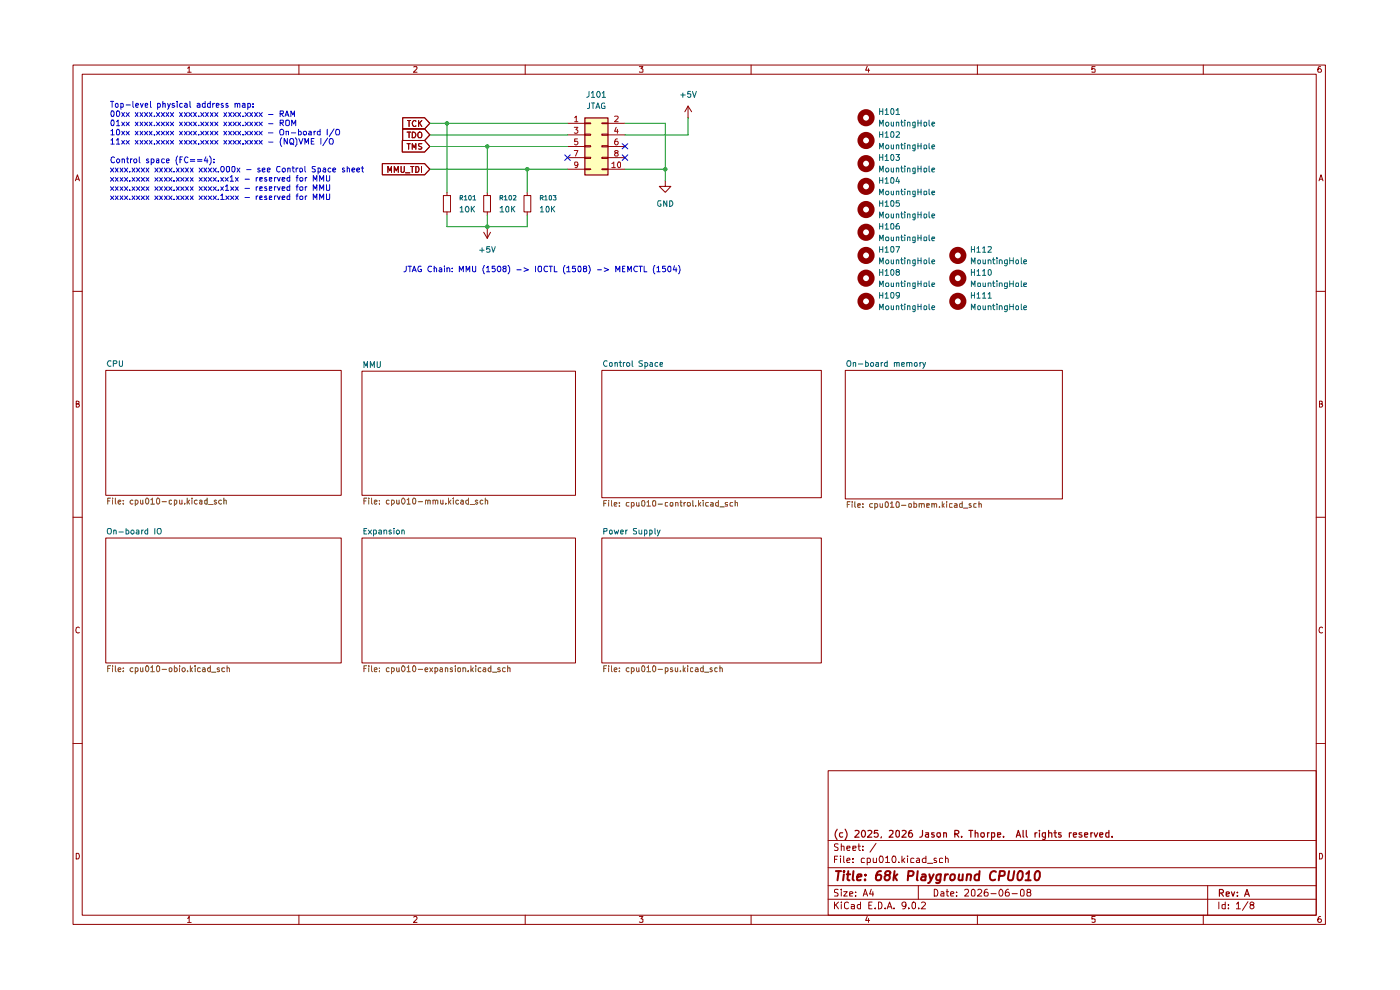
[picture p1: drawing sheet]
<svg xmlns="http://www.w3.org/2000/svg" width="297mm" height="210mm" viewBox="0 0 297 210" stroke-linecap="round" stroke-linejoin="round" font-family="sans-serif">
<g fill="none" stroke="#910000" stroke-width=".21">
<path d="M15.5 13.8h265.7v182.3h-265.7zM17.4 15.7h261.8v178.4h-261.8zM39.8 14.5l.3-.4v1.2M39.8 15.3h.8M63.4 13.8v1.9M87.8 14.2l.6-.1 .1 .4-.8 .8h.8M111.4 13.8v1.9M135.6 14.1h.8l-.4 .5 .4 .1v.5h-.8M159.3 13.8v1.9M184 14.1l-.4 .8h.9M184.2 14.6v.7M207.3 13.8v1.9"/>
<path d="M232.3 14.1h-.7v.6l.2-.1 .5 .1-.1 .6-.6-.1M255.3 13.8v1.9M280.2 14.1l-.5 .1a.94 .94 0 0 0 0 1.1h.5l.1-.1v-.4l-.2-.2h-.3l-.2 .2M16 38.4l.4-1.3 .4 1.3M16.2 38h.6M279.8 38.4l.4-1.3 .5 1.3M279.9 38h.6M15.5 61.8h1.9M279.2 61.8h2M16.2 85.7l.6-.1v-.4l-.6-.1v1.3h.4l.2-.5-.3-.2M279.9 85.7l.6-.1v-.4l-.6-.1v1.3l.6-.1 .1-.4-.3-.2M15.5 109.7h1.9"/>
<path d="M279.2 109.7h2M16.8 133.2l-.2-.2a.65 .65 0 0 0-.5 .6 .65 .65 0 0 0 .5 .7l.2-.1M280.6 133.2l-.3-.2a.65 .65 0 0 0-.5 .6 .65 .65 0 0 0 .5 .7l.3-.1M15.5 157.7h1.9M279.2 157.7h2M175.7 163.5h103.5v30.6h-103.5zM175.7 178.3h103.5M177.8 179.1l-.5-.1-.3 .2v.3l.8 .5-.3 .4-.5-.1M178.5 179.6l.5-.1 .1 .9M178.5 179v1.4M179.7 179.9l.6-.1v-.3h-.6v.2v.6h.6M180.9 179.9l.7-.1-.1-.3h-.6v.8h.6"/>
<path d="M182 179.5h.5M182.2 179v1.2l.3 .2M183 179.5v.2M185.8 178.9l-1.2 1.9M16.2 181a.66 .66 0 0 1 .6 .4 .66 .66 0 0 1-.2 .8h-.4zM39.8 194.8l.3-.4v1.3M39.8 195.7h.8M63.4 194.1v2M87.8 194.6l.4-.2 .3 .4-.8 .9h.8M111.4 194.1v2M135.6 194.4h.8l-.4 .5 .4 .1v.6h-.8M159.3 194.1v2"/>
<path d="M175.7 190.8h103.5M175.7 187.9h103.5M175.7 184.1h103.5M177 191.3v1.5M177 182.3h.5M177.3 191.9l.6 .9M177.7 181.6h-.7v1.4M177.8 188.7h-.7v.6a.53 .53 0 0 1 .6 .2 .53 .53 0 0 1 0 .6h-.7M177.9 191.3l-.9 .9M178.3 181.6v.1M178.3 182v1M178.5 191.3v.2"/>
<path d="M178.5 188.6v.2M178.5 189.1v1M178.5 191.9v.9M179 189.1h.7l-.7 1h.7M179 181.6v1.2l.2 .2M179.7 182.5l.6-.1-.1-.4-.5 .1v.7v.2h.6M180 191.5l-.4-.2-.4 .4v.9l.4 .2 .4-.2M180.3 189.7l.6-.2-.1-.3h-.5v.9h.5M180.6 191.9h.4l.3 .1v.8M180.9 182.9v.1M180.9 182.1v.2M181.3 192.2l-.7 .1v.4h.7"/>
<path d="M181.5 190v.1M181.5 189.2v.1M182.5 191.9h-.4l-.2 .2v.4l.2 .3 .4-.1M182.5 191.3v1.5M183 180.3v.1M183.1 190.1l.5-1.5 .5 1.5M183.2 189.7h.7M183.4 182.1l-.4-.1-.3 .3 .1 .7h.6M184 194.4l-.4 .8h.9M184 182.1l.4-.1 .3 .3-.1 .7h-.6M184 182v1.5M184.2 194.8v.9"/>
<path d="M184.3 192h.5M184.8 188.6l-.3 1.1h.8M185 191.3h-.7v1.5h.7M185.2 189.1v1M185.2 182l.1 1 .6-.1M185.7 192.6v.2M185.9 182v1M186.3 191.3l.7 .2v1.1l-.3 .2h-.4zM186.7 181.6a.73 .73 0 0 1 .7 .5 .73 .73 0 0 1-.3 .9h-.4l-.2-.5zM187.8 192.6v.2M187.9 181.9l.4-.3v1.4M187.9 183h.8"/>
<path d="M188.2 192.8l.5-1.5 .5 1.5M188.4 192.4h.7M189.4 181.7l.5-.1 .2 .5-.2 .9h-.4l-.2-.3-.1-.6zM189.7 192.6v.2M190.7 182.9v.1M191.3 181.6v1.4M191.5 182.5l.4 .5M191.9 182l-.6 .6M192.2 191.9l-.1 .3-.4 .1-.4-.4v-.3a.46 .46 0 0 1 .5-.3 .46 .46 0 0 1 .4 .3l-.2 1-.5 .2M192.5 181.6v.1M192.5 182v1M192.8 192.6v.2"/>
<path d="M193.5 191.5l.4-.2 .3 .3v.9l-.3 .3a.82 .82 0 0 1-.4-1.3zM193.9 182.1l-.4-.1-.3 .2v.7l.7 .1M194.5 182.1l.4-.1 .2 .3v.7h-.6l-.1-.4 .7-.2M194.8 187.9v2.9M194.9 192.6v.2M195.5 191.5l.2-.2h.3l.3 .5-.9 1h.9M196.4 181.6v1.4h-.6l-.1-.7a.52 .52 0 0 1 .7-.2M196.8 183.1h1.1M198.2 188.6a.8 .8 0 0 1 .8 .6 .8 .8 0 0 1-.3 .9h-.5zM198.6 182.1l-.3-.1-.2 .3 .2 .2 .4 .2-.1 .3h-.5M199.6 189.2l.4-.1 .2 .2v.8h-.6v-.4l.6-.2M200 182.1l-.4-.1-.3 .2v.7l.7 .1"/>
<path d="M200.6 182.2l.1-.2 .4 .1 .1 .9M200.6 181.6v1.4M200.7 189.1h.5M200.9 188.6v1.3l.1 .2h.2M201.7 189.7l.7-.2-.2-.4h-.4l-.1 .2v.6l.1 .2h.5M202.9 190v.1M202.9 189.2v.1M204.6 188.8l.6-.2 .3 .4-.1 .3-.8 .8h.9M206.2 188.8l.3-.2 .3 .4v.8l-.1 .3h-.5l-.1-.3zM207.3 194.1v2M207.4 188.8l.2-.2h.3l.4 .5-.1 .2-.9 .8h1M209.5 188.6l-.5 .2-.2 1 .2 .3 .5-.1v-.7l-.5-.1-.2 .3"/>
<path d="M210.2 189.6h1.1M212.3 188.6a.87 .87 0 0 1 .2 1.5h-.3l-.3-.5 .1-.6zM213.9 188.6h-.2a1.04 1.04 0 0 0-.3 1.5h.5l.2-.6-.2-.3-.5 .1-.1 .2M214.7 189.6h1.1M216.6 188.8l.3-.2 .4 .4v.8l-.2 .3h-.4l-.2-.3zM218.1 189.3l-.3-.3 .1-.3h.6l.2 .3-.1 .1-.7 .2-.1 .3 .1 .5h.6l.2-.5-.3-.3M232.3 194.4h-.7v.6h.7v.6h-.7M255.3 194.1v2M256.2 187.9v6.2M258.6 191.3v1.5M259.9 191.9h-.7v.7l.3 .2 .4-.1M259.9 191.3v1.5"/>
<path d="M260.6 192.6v.2M260.6 191.9v.1M262.3 191.8l.4-.5v1.5M262.3 192.8h.8M264.7 191.3l-1.1 1.8M265.4 191.9l-.2-.2 .2-.4 .6 .3-.1 .3h-.5l-.1 .2-.1 .4 .2 .3a.45 .45 0 0 0 .5-.2 .45 .45 0 0 0 0-.5l-.2-.2M279.9 181a.66 .66 0 0 1 .7 .4 .66 .66 0 0 1-.3 .8h-.4zM280.2 194.4a.72 .72 0 0 0-.6 .5 .72 .72 0 0 0 .2 .8l.4-.1a.42 .42 0 0 0 0-.6 .42 .42 0 0 0-.5 0l-.1 .2"/>
</g>
<g fill="none" stroke="#910000" stroke-width=".25">
<path d="M177.6 175.9a1.75 1.75 0 0 0 0 2.2M178.8 176.7h-.5l-.2 .2v.4l.2 .3 .5-.1M179.3 175.9a1.64 1.64 0 0 1 0 2.2M181.4 176.2h.8v.4l-.9 1h.9M182.9 176.2l.2-.1a.73 .73 0 0 1 .6 .8 .73 .73 0 0 1-.6 .7l-.4-.6zM184.1 176.2l.6-.1 .3 .5-1 1h1M186.2 176.1h-.7v.7l.6-.1 .2 .3v.3l-.2 .3-.6-.2M187 177.5l-.1 .3M188.7 176.2h.7v.5l-.8 .9h.8M190.1 176.2l.4-.1 .3 .3v.9l-.3 .3a.87 .87 0 0 1-.4-1.4zM191.4 176.2h.7l.1 .4-.9 1h.9M193.4 176.1a.57 .57 0 0 0-.7 .6v.6l.3 .3h.3l.3-.3v-.3l-.3-.3h-.3l-.3 .3"/>
<path d="M195.7 176.1v1.1l-.2 .3-.4 .1M196.4 176.7h.6v.9M197 177h-.4l-.3 .2 .3 .4 .4-.1M198.2 176.7h-.5v.3l.5 .3-.2 .3-.3-.1M198.8 176.7h.6v.8a.45 .45 0 0 1-.6-.2zM200.2 176.7h.5l.1 .9M200.2 176.7v.9M202.6 176.9l.6-.1 .2-.1-.1-.5-.7-.1v1.5M202.9 176.9l.5 .7M204 177.4v.2M205.5 176.1h.9M205.9 176.1v1.5"/>
<path d="M206.9 176.7h.5l.1 .9M206.9 176.1v1.5M208.1 176.7h.6v.8a.45 .45 0 0 1-.6-.2zM209.5 176.7v.9M209.8 176.7h-.2l-.1 .2M210.4 177.5h.5v-.8h-.5v1.4M211.6 177.1l.7-.1-.1-.3h-.6v.8h.6M212.9 177.4v.2M215.6 177.6l.4-1.5 .5 1.5M215.7 177.2h.7M217 176.1v1.4l.2 .1M217.7 176.1v1.2l.3 .3"/>
<path d="M219.6 176.7v.9M220 176.7h-.3l-.1 .2M220.5 176.1v.1M220.5 176.7v.9M221.8 177.5l-.4 .1-.3-.3 .2-.6h.5v1.1l-.3 .3-.3-.1M222.5 176.7h.6v.9M222.5 176.1v1.5M223.6 176.7h.6M223.8 176.1v1.2l.4 .3M225.1 176.7h-.5v.3l.6 .3-.3 .3-.3-.1M226.9 176.7v.9M227.3 176.7h-.3l-.1 .2"/>
<path d="M227.7 177.1l.7-.1-.1-.3h-.5l-.1 .1 .1 .7h.5M229.5 176.7h-.5l-.1 .1 .6 .4v.3h-.6M230.1 177.1l.7-.1-.1-.3h-.5l-.1 .1 .1 .7h.5M231.4 176.7v.9M231.8 176.7h-.3l-.1 .2M232.1 176.7l.3 .9 .5-.9M233.3 177.1l.7-.1-.1-.3h-.5l-.1 .1 .1 .7h.5M235.2 176.7h-.5l-.1 .2 .1 .6h.5M235.2 176.1v1.5M235.9 177.4v.2M258.7 189.4h.8v-.5l-.2-.2h-.6v1.4M259 189.4l.5 .7"/>
<path d="M260.1 189.7l.7-.2-.1-.2h-.6v.7h.6M261.2 189.2l.4 .9 .3-.9M262.5 190v.1M262.5 189.3v.1M264 190.1l.5-1.4 .5 1.4M264.2 189.7h.7"/>
</g>
<g fill="none" stroke="#910000" stroke-width=".42">
<path d="M177.3 184.8h1.1M177.9 184.8l-.2 1.9M179 185.5l-.1 1.2M179.1 184.8l-.2 .1 .1 .1 .1-.2-.1 .2M179.6 185.5h.8M180 184.8l-.2 1.7 .4 .2M181.1 184.8l-.2 1.7 .2 .2M181.8 186.1l.9-.2v-.4h-.5l-.3 .2-.1 .9h.8M183.5 186.6v.1M183.6 185.5v.2M186.9 184.8a1.2 1.2 0 0 0-.9 1.8l.5 .1 .3-.1 .1-.9a.63 .63 0 0 0-1 .2M188.1 185.6l-.4-.4 .3-.3 .6-.1 .2 .2 .1 .1-.2 .4-.8 .2a.61 .61 0 0 0-.1 .9 .61 .61 0 0 0 .9-.1 .61 .61 0 0 0-.2-.9"/>
<path d="M189.8 184.8l-.3 1.9M189.8 186l.5 .7M190.4 185.5l-.8 .6M192.7 185.8l.9-.1 .2-.6v-.1l-.3-.2h-.8l-.1 1.9M194.7 184.8l-.2 1.7 .2 .2M195.6 185.5h.7v1.2M196.4 185.9l-.9 .2-.1 .4 .2 .2 .7-.1M197.1 185.5l.4 1.2M198.1 185.5l-.9 1.7-.3 .1M199.6 185.5l-.2 1.5a.53 .53 0 0 1-.8 .2M199.6 185.5a.65 .65 0 0 0-.9 .3v.8a.64 .64 0 0 0 .8 0M200.5 185.5l-.1 1.2"/>
<path d="M201.1 185.5h-.4l-.2 .3M201.7 185.6l.3-.1 .6 .1v.7l-.5 .4a.46 .46 0 0 1-.6-.4zM203.5 185.5l-.2 1a.49 .49 0 0 0 .9 .1M204.3 185.5l-.1 1.2M205.2 185.6l.2-.1h.5v1.2M205.2 185.5l-.2 1.2M207.7 185.5a.65 .65 0 0 0-.9 .3v.8a.64 .64 0 0 0 .8 0M207.8 184.8l-.2 1.9M211.3 185l-.1-.1a.85 .85 0 0 0-1.2 .7v.6a.66 .66 0 0 0 1.1 .4M212 185.8l1-.1 .1-.2v-.5l-.2-.2h-.8l-.2 1.9M214.1 184.8l-.3 1.5 .4 .4 .6-.1 .4-1.8M216.1 185l.3-.2 .5 .2a1.72 1.72 0 0 1-.2 1.6l-.3 .1-.4-.1a1.4 1.4 0 0 1 .1-1.6z"/>
<path d="M217.5 186.7h1.1M217.7 185.4l.6-.6-.2 1.9M219.7 185l.4-.2 .4 .2a1.65 1.65 0 0 1-.2 1.6h-.6a1.4 1.4 0 0 1 0-1.6z"/>
</g>
<g fill="#fff">
<path d="M22.4 114.1h50v26.5h-50z"/>
<path d="M22.4 78.6h50v26.5h-50z"/>
<path d="M76.8 114.1h45.3v26.5h-45.3z"/>
<path d="M76.8 78.7h45.3v26.4h-45.3z"/>
<path d="M127.7 78.6h46.5v27h-46.5z"/>
<path d="M127.7 114.1h46.5v26.5h-46.5z"/>
<path d="M179.3 78.6h46.1v27.2h-46.1z"/>
</g>
<path d="M124 25h4.9v12.1h-4.9z" fill="#ffb"/>
<g fill="none" stroke="#910000" stroke-width=".21">
<path d="M81.1 34.7h9l1.1 1.2-1.1 1.2h-9zM82.3 36.6v-1.3l.4 .9 .4-.9v1.3M83.6 36.6v-1.3l.5 .9 .4-.9v1.3M85.1 35.3v1.1l.2 .2 .4-.1 .1-.2v-1M85.3 29.8h4.8l1.1 1.3-1.1 1.2h-4.8zM85.4 25h4.7l1.1 1.2-1.1 1.1h-4.7zM85.4 27.3h4.7l1.1 1.3-1.1 1.2h-4.7zM86 36.7h.9M86.4 30.5h.6M86.4 28h.7M86.4 25.6h.7M86.7 30.5v1.2"/>
<path d="M86.8 25.6v1.2M86.8 28v1.2M87.1 35.3h.7M87.5 31.7v-1.2l.4 .8 .3-.8v1.2M87.5 28a.66 .66 0 0 1 .7 .4 .66 .66 0 0 1-.2 .8h-.5zM87.5 35.3v1.3M88.2 35.3a.64 .64 0 0 1 .7 .6 .64 .64 0 0 1-.7 .7zM88.2 25.7l-.1-.1a.64 .64 0 0 0-.6 .6 .64 .64 0 0 0 .6 .6l.1-.1M88.7 28.2l.3-.2 .3 .1a.87 .87 0 0 1 0 1.1h-.5l-.2-.3zM88.8 25.6v1.2M89 26.1l.5 .7M89.4 35.3v1.3"/>
<path d="M89.5 30.5l-.7 .1v.3l.7 .4-.3 .4-.4-.1M89.5 25.6l-.7 .6M120.4 26.2h3.6M120.4 28.6h3.6M120.4 31.1h3.6M120.4 33.4h3.6M120.4 35.9h3.6M124 26.1h1.3v.1h-1.3zM124 28.4h1.3v.3h-1.3zM124 30.9h1.3v.3h-1.3zM124 33.4h1.3v.2h-1.3zM124 35.8h1.3v.2h-1.3z"/>
<path d="M127.7 26.1h1.2v.1h-1.2zM127.7 28.4h1.2v.3h-1.2zM127.7 30.9h1.2v.3h-1.2zM127.7 33.4h1.2v.2h-1.2zM127.7 35.8h1.2v.2h-1.2zM128.9 26.2h3.7M128.9 28.6h3.7M128.9 31.1h3.7M128.9 33.4h3.7M128.9 35.9h3.7M141.1 38.4v1.1h1.2l-1.2 1.3-1.2-1.3h1.2M141.1 38.4h.1"/>
<path d="M146 25h.1M146 22.5l-.7 1.2M146 22.5l.7 1.2M146 22.5v2.5M94.1 41.5h1.5v3.5h-1.5zM94.8 40.8v.7M94.8 45v.6M102.6 41.5h1.5v3.5h-1.5zM102.6 49.3l.8 1.2M103.4 48.1h.1M103.4 40.8v.7M103.4 45v.6"/>
<path d="M103.4 48.1v2.4M104.1 49.3l-.7 1.2M111.2 41.5h1.4v3.5h-1.4zM111.8 40.8v.7M111.8 45v.6M22.4 78.6h50v26.5h-50zM76.8 78.7h45.3v26.4h-45.3zM127.7 78.6h46.5v27h-46.5zM179.3 78.6h46.1v27.2h-46.1zM22.4 114.1h50v26.5h-50zM76.8 114.1h45.3v26.5h-45.3zM127.7 114.1h46.5v26.5h-46.5z"/>
</g>
<path d="M124.1 25h4.9v12.1h-4.9z" fill="none" stroke="#910000" stroke-width=".25"/>
<g fill="none" stroke="#b90000" stroke-width=".21">
<path d="M121.8 27h.8l-.4 .5 .3 .1v.6h-.7M121.8 31.9h.8l-.5 1.2M121.9 25l.4-.4v1.2M121.9 25.8h.7M122.5 29.5h-.6v.6l.5-.1 .2 .1v.4l-.3 .2-.4-.1M122.6 34.9l-.3 .2h-.2l-.2-.1v-.5l.5-.1 .2 .2-.2 .9-.4 .1M129.8 34.7l.4-.3v1.2M129.8 35.6h.8M130.4 24.7l.6-.1 .1 .2v.3l-.7 .7h.7M130.6 32.4l-.2-.2 .1-.2h.6v.2l-.1 .2h-.4l-.2 .3 .2 .4h.4l.1-.2v-.2l-.2-.3M130.7 27l-.3 .9h.7M131 29.5l-.4 .1-.2 .9 .2 .2h.3l.2-.2v-.4l-.1-.1h-.4l-.2 .1"/>
<path d="M131 27.4v.9M131.1 34.4h.4l.2 .2-.1 .9-.5 .1a1.05 1.05 0 0 1 0-1.2z"/>
</g>
<g fill="none" stroke="#910000" stroke-width="1.2">
<circle cx="183.7" cy="34.7" r="1.23"/>
<circle cx="183.7" cy="39.5" r="1.23"/>
<circle cx="183.7" cy="29.8" r="1.23"/>
<circle cx="183.7" cy="25" r="1.23"/>
<circle cx="183.7" cy="59" r="1.23"/>
<circle cx="183.7" cy="44.4" r="1.23"/>
<circle cx="183.7" cy="54.2" r="1.23"/>
<circle cx="183.7" cy="49.3" r="1.23"/>
<circle cx="203.2" cy="59" r="1.23"/>
<circle cx="203.2" cy="54.2" r="1.23"/>
<circle cx="183.7" cy="63.9" r="1.23"/>
<circle cx="203.2" cy="63.9" r="1.23"/>
</g>
<path d="M91.2 31.1h29.2M91.2 26.2h29.2M91.2 28.6h29.2M91.2 35.9h29.2M94.8 26.2v14.6M103.4 31.1v9.7M111.8 35.9v4.9M132.6 26.2h8.5v12.2M132.6 35.9h8.5M146 25v3.6h-13.4M94.8 45.6v2.5h17v-2.5M103.4 45.6v2.5" fill="none" stroke="#090" stroke-width=".21"/>
<g fill="none" stroke="#0000ca" stroke-width=".21">
<path d="M23.4 21.5h.7M23.4 35.6l.7 .9M23.4 37.7l.7 .7M23.4 39.6l.7 .8M23.5 27.8l.4-.4v1.2M23.5 29.7l.4-.3v1.2M23.5 28.6h.7M23.5 30.6h.7M23.6 23.6l.4-.1a.86 .86 0 0 1 0 1.2l-.4-.1zM23.6 25.6l.4-.1a.86 .86 0 0 1 0 1.2l-.4-.1zM23.8 21.5v1.3M24.1 35.6l-.7 .9"/>
<path d="M24.1 37.7l-.7 .7M24.1 39.6l-.7 .8M24.3 33.4l-.3-.1a.65 .65 0 0 0-.5 .6 .65 .65 0 0 0 .5 .6l.3-.1M24.5 35.6l.6 .9M24.5 37.7l.6 .7M24.5 39.6l.6 .8M24.6 22l.3-.1 .2 .2v.5l-.2 .2-.4-.3zM24.7 23.7l.2-.2 .3 .1a.66 .66 0 0 1-.2 1.1l-.3-.2zM24.7 25.8l.4-.3v1.2M24.7 29.7l.4-.3v1.2M24.7 33.9l.4-.2 .3 .2v.4l-.4 .2-.3-.2zM24.7 26.7h.7"/>
<path d="M24.7 30.6h.7M24.8 27.5l.3-.1a.84 .84 0 0 1 .1 1.2h-.3l-.2-.2zM25.1 35.6l-.6 .9M25.1 37.7l-.6 .7M25.1 39.6l-.6 .8M25.5 35.6l.6 .9M25.5 37.7l.6 .7M25.5 39.6l.6 .8M25.7 22l.3-.1 .2 .2v.5l-.2 .2-.3-.1M25.7 21.9v1.3M25.8 23.9l.6 .8M25.8 25.9l.6 .8"/>
<path d="M25.8 27.9l.6 .7M25.8 29.8l.6 .8M25.9 33.9l.2-.2 .3 .2v.6M25.9 33.7v.8M26.1 35.6l-.6 .9M26.1 37.7l-.6 .7M26.1 39.6l-.6 .8M26.4 23.9l-.6 .8M26.4 25.9l-.6 .8M26.4 27.9l-.6 .7M26.4 29.8l-.6 .8M26.4 35.6l.7 .9"/>
<path d="M26.4 37.7l.7 .7M26.4 39.6l.7 .8M26.8 22.3h.9M26.8 23.9l.6 .8M26.8 25.9l.6 .8M26.8 27.9l.6 .7M26.8 29.8l.6 .8M26.8 33.7h.5M27 33.3v1.1l.3 .1M27.1 35.6l-.7 .9M27.1 37.7l-.7 .7M27.1 39.6l-.7 .8"/>
<path d="M27.4 23.9l-.6 .8M27.4 25.9l-.6 .8M27.4 27.9l-.6 .7M27.4 29.8l-.6 .8M27.5 36.4v.1M27.5 38.4h.1M27.7 33.7v.8M28 33.7l-.3 .2M28 35.6l.6 .9M28 37.7l.6 .7M28 39.6l.6 .8M28.2 21.5v1.1l.2 .2"/>
<path d="M28.4 33.9l.2-.2 .4 .1v.7h-.4l-.2-.2zM28.6 35.6l-.6 .9M28.6 37.7l-.6 .7M28.6 39.6l-.6 .8M28.7 23.9l.6 .8M28.7 25.9l.6 .8M28.7 27.9l.6 .7M28.7 29.8l.6 .8M28.8 22.3h.6l-.2-.4-.4 .2v.5l.2 .2 .3-.1M29 35.6l.6 .9M29 37.7l.6 .7M29 39.6l.6 .8"/>
<path d="M29.3 23.9l-.6 .8M29.3 25.9l-.6 .8M29.3 27.9l-.6 .7M29.3 29.8l-.6 .8M29.5 33.3v1.1l.2 .1M29.6 35.6l-.6 .9M29.6 37.7l-.6 .7M29.6 39.6l-.6 .8M29.7 23.9l.6 .8M29.7 25.9l.6 .8M29.7 27.9l.6 .7M29.7 29.8l.6 .8"/>
<path d="M29.8 21.9l.3 .9 .3-.9M30 35.6l.6 .9M30 37.7l.6 .7M30 39.6l.6 .8M30.3 23.9l-.6 .8M30.3 25.9l-.6 .8M30.3 27.9l-.6 .7M30.3 29.8l-.6 .8M30.6 23.9l.7 .8M30.6 25.9l.7 .8M30.6 27.9l.7 .7M30.6 29.8l.7 .8"/>
<path d="M30.6 35.6l-.6 .9M30.6 37.7l-.6 .7M30.6 39.6l-.6 .8M30.8 22.3h.5v-.3h-.5v.7h.5M31 35.6l.6 .9M31 37.7l.6 .7M31 39.6l.6 .8M31.3 23.9l-.7 .8M31.3 25.9l-.7 .8M31.3 27.9l-.7 .7M31.3 29.8l-.7 .8M31.5 33.8l-.3-.1-.1 .2 .5 .5-.2 .1h-.3"/>
<path d="M31.6 35.6l-.6 .9M31.6 37.7l-.6 .7M31.6 39.6l-.6 .8M31.7 23.9l.6 .8M31.7 25.9l.6 .8M31.7 27.9l.6 .7M31.7 29.8l.6 .8M31.9 21.5v1.2l.2 .1M32.1 33.8l.3-.1 .3 .2-.1 .6h-.5M32.1 33.7v1.3M32.3 23.9l-.6 .8M32.3 25.9l-.6 .8"/>
<path d="M32.3 27.9l-.6 .7M32.3 29.8l-.6 .8M32.8 24.6v.1M32.8 26.6v.1M32.8 28.5v.1M32.8 30.5v.1M32.8 35.6l.7 .9M32.8 37.7l.7 .7M32.8 39.6l.7 .8M33.2 33.8h.5v.7M33.2 23.9l.7 .8M33.2 25.9l.7 .8"/>
<path d="M33.2 27.9l.7 .7M33.2 29.8l.7 .8M33.4 22l.4-.1 .2 .3-.1 .5h-.5M33.4 21.9v1.3M33.5 35.6l-.7 .9M33.5 37.7l-.7 .7M33.5 39.6l-.7 .8M33.7 34l-.5 .1v.4h.5M33.9 23.9l-.7 .8M33.9 25.9l-.7 .8M33.9 27.9l-.7 .7M33.9 29.8l-.7 .8"/>
<path d="M33.9 35.6l.6 .9M33.9 37.7l.6 .7M33.9 39.6l.6 .8M34.2 23.9l.7 .8M34.2 25.9l.7 .8M34.2 27.9l.7 .7M34.2 29.8l.7 .8M34.5 35.6l-.6 .9M34.5 37.7l-.6 .7M34.5 39.6l-.6 .8M34.5 22.1l.2-.2 .3 .1v.8M34.5 21.5v1.3"/>
<path d="M34.9 33.8l-.4-.1-.2 .2v.5l.2 .1h.4M34.9 23.9l-.7 .8M34.9 25.9l-.7 .8M34.9 27.9l-.7 .7M34.9 37.7l.6 .7M34.9 29.8l-.7 .8M34.9 35.6l.6 .9M34.9 39.6l.6 .8M35.2 23.9l.6 .8M35.2 25.9l.6 .8M35.2 27.9l.6 .7M35.2 29.8l.6 .8"/>
<path d="M35.3 34.1l.6-.1-.2-.3-.4 .2v.5l.2 .1h.3M35.5 35.6l-.6 .9M35.5 37.7l-.6 .7M35.5 39.6l-.6 .8M35.6 21.9l.2 .9M35.8 23.9l-.6 .8M35.8 25.9l-.6 .8M35.8 27.9l-.6 .7M35.8 29.8l-.6 .8M35.8 35.6l.7 .9M35.8 37.7l.7 .7M35.8 39.6l.7 .8"/>
<path d="M36.1 21.9l-.5 1.3M36.1 23.9l.7 .8M36.1 25.9l.7 .8M36.1 27.9l.7 .7M36.1 29.8l.7 .8M36.5 35.6l-.7 .9M36.5 37.7l-.7 .7M36.5 39.6l-.7 .8M36.8 23.9l-.7 .8M36.8 25.9l-.7 .8M36.8 27.9l-.7 .7M36.8 29.8l-.7 .8"/>
<path d="M36.9 36.4v.1M36.9 38.4h.1M37 22l-.3-.1-.2 .3 .6 .4-.3 .2-.3-.1M37.4 39.6l.6 .8M37.4 35.6l.6 .9M37.4 37.7l.6 .7M37.6 21.5v.2M37.6 21.9v.9M37.7 33.1l-.1 .1a1.48 1.48 0 0 0 .1 1.8M38 35.6l-.6 .9M38 37.7l-.6 .7M38 39.6l-.6 .8"/>
<path d="M38.1 23.9l.6 .8M38.1 25.9l.6 .8M38.1 27.9l.6 .7M38.1 29.8l.6 .8M38.2 33.9h.3M38.4 35.6l.6 .9M38.4 37.7l.6 .7M38.4 39.6l.6 .8M38.7 22l-.3-.1-.3 .3 .1 .5h.5M38.7 33.3h-.5v1.2M38.7 23.9l-.6 .8M38.7 25.9l-.6 .8"/>
<path d="M38.7 27.9l-.6 .7M38.7 29.8l-.6 .8M39 35.6l-.6 .9M39 37.7l-.6 .7M39 39.6l-.6 .8M39.1 23.9l.6 .8M39.1 25.9l.6 .8M39.1 27.9l.6 .7M39.1 29.8l.6 .8M39.2 22l.3-.1 .2 .2v.7M39.4 39.6l.6 .8M39.4 35.6l.6 .9"/>
<path d="M39.4 37.7l.6 .7M39.7 22.3h-.4l-.2 .1 .2 .4 .4-.1M39.7 23.9l-.6 .8M39.7 25.9l-.6 .8M39.7 27.9l-.6 .7M39.7 29.8l-.6 .8M39.9 33.4l-.3-.1a.6 .6 0 0 0-.5 .6 .6 .6 0 0 0 .7 .6l.1-.1M40 37.7l-.6 .7M40 39.6l-.6 .8M40 35.6l-.6 .9M40 23.9l.7 .8M40 25.9l.7 .8"/>
<path d="M40 27.9l.7 .7M40 29.8l.7 .8M40.3 21.5v1.1l.2 .2M40.4 39.6l.6 .8M40.4 33.9h.9M40.4 34.2h.9M40.4 35.6l.6 .9M40.4 37.7l.6 .7M40.7 23.9l-.7 .8M40.7 25.9l-.7 .8M40.7 27.9l-.7 .7M40.7 29.8l-.7 .8"/>
<path d="M41 35.6l-.6 .9M41 37.7l-.6 .7M41 39.6l-.6 .8M41.1 23.9l.6 .8M41.1 25.9l.6 .8M41.1 27.9l.6 .7M41.1 29.8l.6 .8M41.7 23.9l-.6 .8M41.7 25.9l-.6 .8M41.7 27.9l-.6 .7M41.7 29.8l-.6 .8M41.8 22l.4-.1 .2 .2v.7"/>
<path d="M41.9 33.9h.9M41.9 34.2h.9M42.2 24.6v.1M42.2 26.6v.1M42.2 28.5v.1M42.2 30.5v.1M42.2 35.6l.7 .9M42.2 37.7l.7 .7M42.2 39.6l.7 .8M42.4 22.3h-.6v.4h.6M42.6 23.9l.7 .8M42.6 25.9l.7 .8"/>
<path d="M42.6 27.9l.7 .7M42.6 29.8l.7 .8M42.9 35.6l-.7 .9M42.9 37.7l-.7 .7M42.9 39.6l-.7 .8M43.3 23.9l-.7 .8M43.3 25.9l-.7 .8M43.3 27.9l-.7 .7M43.3 29.8l-.7 .8M43.3 35.6l.6 .9M43.3 37.7l.6 .7M43.3 39.6l.6 .8"/>
<path d="M43.5 22l-.4-.1-.2 .2v.5l.2 .2 .4-.1M43.5 21.5v1.3M43.6 23.9l.6 .8M43.6 25.9l.6 .8M43.6 27.9l.6 .7M43.6 29.8l.6 .8M43.7 33.3l-.4 .8h.8M43.9 35.6l-.6 .9M43.9 37.7l-.6 .7M43.9 39.6l-.6 .8M43.9 33.7v.8M44.2 23.9l-.6 .8"/>
<path d="M44.2 25.9l-.6 .8M44.2 27.9l-.6 .7M44.2 29.8l-.6 .8M44.2 35.6l.7 .9M44.2 37.7l.7 .7M44.2 39.6l.7 .8M44.4 33.1l.1 .1a1.34 1.34 0 0 1-.1 1.8M44.6 22l-.4-.1-.2 .2v.5l.2 .2 .4-.1M44.6 21.5v1.3M44.6 23.9l.6 .8M44.6 25.9l.6 .8M44.6 27.9l.6 .7"/>
<path d="M44.6 29.8l.6 .8M44.9 35.6l-.7 .9M44.9 37.7l-.7 .7M44.9 39.6l-.7 .8M45.1 21.9v.9M45.2 23.9l-.6 .8M45.2 25.9l-.6 .8M45.2 27.9l-.6 .7M45.2 29.8l-.6 .8M45.2 35.6l.7 .9M45.2 37.7l.7 .7M45.2 39.6l.7 .8"/>
<path d="M45.4 34.4v.1M45.4 33.8v.1M45.5 21.9l-.4 .3M45.5 23.9l.7 .8M45.5 25.9l.7 .8M45.5 27.9l.7 .7M45.5 29.8l.7 .8M45.9 22.3h.6l-.1-.3h-.5v.7h.5M45.9 35.6l-.7 .9M45.9 37.7l-.7 .7M45.9 39.6l-.7 .8M46.2 23.9l-.7 .8"/>
<path d="M46.2 25.9l-.7 .8M46.2 27.9l-.7 .7M46.2 29.8l-.7 .8M46.3 36.4v.1M46.3 38.4h.1M46.8 39.6l.6 .8M46.8 37.7l.6 .7M47 35.3a.61 .61 0 0 1 .6 .5 .61 .61 0 0 1-.4 .7l-.4-.5zM47.3 22l-.2-.1-.2 .3 .5 .4-.2 .2-.3-.1M47.4 37.7l-.6 .7M47.4 39.6l-.6 .8M47.5 23.9l.6 .8"/>
<path d="M47.5 25.9l.6 .8M47.5 27.9l.6 .7M47.5 29.8l.6 .8M47.7 37.7l.7 .7M47.8 39.5l.4-.3v1.2M48.1 35.4l.4-.1 .2 .2v.7l-.3 .3-.3-.1zM48.1 23.9l-.6 .8M48.1 25.9l-.6 .8M48.1 27.9l-.6 .7M48.1 29.8l-.6 .8M48.3 22h-.4v.3h.4l.1 .3-.1 .2-.4-.1M48.4 37.7l-.7 .7"/>
<path d="M48.5 23.9l.6 .8M48.5 25.9l.6 .8M48.5 27.9l.6 .7M48.5 29.8l.6 .8M48.8 37.6l.4-.3v1.1M48.8 38.4h.7M48.9 39.6l.7 .8M49.1 23.9l-.6 .8M49.1 25.9l-.6 .8M49.1 27.9l-.6 .7M49.1 29.8l-.6 .8M49.4 35.3h.3a.91 .91 0 0 1-.1 1.2l-.4-.3v-.7z"/>
<path d="M49.4 23.9l.7 .8M49.4 25.9l.7 .8M49.4 27.9l.7 .7M49.4 29.8l.7 .8M49.6 39.6l-.7 .8M49.9 22.1l.1-.2 .4 .2v.7M49.9 21.9v.9M50 37.7l.5 .7M50 39.6l.5 .8M50.1 23.9l-.7 .8M50.1 25.9l-.7 .8M50.1 27.9l-.7 .7"/>
<path d="M50.1 29.8l-.7 .8M50.3 35.6l.6 .9M50.4 22.1l.1-.2 .4 .1v.8M50.5 23.9l.6 .8M50.5 25.9l.6 .8M50.5 27.9l.6 .7M50.5 29.8l.6 .8M50.5 37.7l-.5 .7M50.5 39.6l-.5 .8M50.9 35.6l-.6 .9M51.1 23.9l-.6 .8M51.1 25.9l-.6 .8"/>
<path d="M51.1 27.9l-.6 .7M51.1 29.8l-.6 .8M51.5 22h.5v.8M51.6 24.6v.1M51.6 26.6v.1M51.6 28.5v.1M51.6 30.5v.1M52 22.3h-.4l-.2 .1 .2 .4 .4-.1M52 23.9l.7 .8M52 25.9l.7 .8M52 27.9l.7 .7M52 29.8l.7 .8"/>
<path d="M52 38h.9M52 40h.9M52.3 36h1M52.6 22l.3-.1 .3 .3-.1 .5h-.5M52.6 21.9v1.3M52.7 23.9l-.7 .8M52.7 25.9l-.7 .8M52.7 27.9l-.7 .7M52.7 29.8l-.7 .8M53 23.9l.6 .8M53 25.9l.6 .8M53 27.9l.6 .7"/>
<path d="M53 29.8l.6 .8M53.6 23.9l-.6 .8M53.6 25.9l-.6 .8M53.6 27.9l-.6 .7M53.6 29.8l-.6 .8M53.7 22.6v.2M53.7 22v.1M54 23.9l.6 .8M54 25.9l.6 .8M54 27.9l.6 .7M54 29.8l.6 .8M54.4 37.7v.7"/>
<path d="M54.4 39.6v.8M54.6 23.9l-.6 .8M54.6 25.9l-.6 .8M54.6 27.9l-.6 .7M54.6 29.8l-.6 .8M54.7 37.7l-.3 .1M54.7 39.6l-.3 .2M54.9 23.9l.7 .8M54.9 25.9l.7 .8M54.9 27.9l.7 .7M54.9 29.8l.7 .8M55.1 35.7h-.4v.3l.3 .1 .2 .2-.2 .2-.3-.1"/>
<path d="M55.1 38l.5-.1v-.2h-.5v.7h.5M55.1 40l.5-.1v-.3h-.5v.8h.5M55.6 36.1l.6-.1v-.3l-.3-.1-.3 .2 .1 .6h.5M55.6 23.9l-.7 .8M55.6 25.9l-.7 .8M55.6 27.9l-.7 .7M55.6 29.8l-.7 .8M56.6 37.7h-.4l-.1 .1 .5 .5-.1 .1h-.4M56.6 39.6h-.4l-.1 .2 .5 .2v.4h-.5M56.7 36.1l.6-.1-.2-.4-.4 .1v.7h.5M57 24.3h.9M57 26.2h.9"/>
<path d="M57 28.2h.9M57 30.1h.9M57.1 38l.6-.1v-.2h-.6v.7h.6M57.1 40l.6-.1v-.3h-.6v.8h.6M58.2 37.7v.7M58.2 39.6v.8M58.6 37.7h-.3l-.1 .1M58.6 39.6h-.3l-.1 .2M58.8 37.7l.4 .7 .2-.7M58.8 39.6l.4 .8 .2-.8M59.4 24.1l.7-.1v-.4l-.7-.1v1.2M59.4 26.1h.6l.1-.5-.7-.1v1.2"/>
<path d="M59.4 27.6l.3-.2 .3 .1a.87 .87 0 0 1 0 1.1h-.5l-.2-.3zM59.4 35.4l-.5-.1a.61 .61 0 0 0-.2 .8 .61 .61 0 0 0 .7 .3M59.7 24.1l.4 .6M59.7 26.1l.4 .6M59.8 29.2a1.44 1.44 0 0 0 0 1.9M59.9 35.9l.2-.3 .3 .1v.7h-.5zM59.9 38l.5-.1v-.2h-.5v.7h.5M59.9 40l.5-.1v-.3h-.5v.8h.5M60.4 24.7l.5-1.2 .4 1.2M60.6 25.7l.2-.2h.4l.2 .2v.8l-.3 .2-.5-.2zM60.6 24.4h.6M60.7 27.9h.5v.7"/>
<path d="M60.7 27.9v.7M61 29.4v1.2l-.7-1.2v1.2M61 35.8l.2-.2 .3 .1v.8M61 35.6v.9M61.5 37.7h-.5l-.1 .1 .1 .6h.5M61.5 39.2v1.2h-.5v-.8h.5M61.5 37.3v1.1M61.7 24.7v-1.2l.4 .9 .4-.9v1.2M61.7 30.3l.6 .4M61.8 28.2h.9M61.9 26.7v-1.2l.4 .8 .4-.8v1.2M62 35.6h.5"/>
<path d="M62.1 35.3v1l.4 .2M62.7 29.2l.3 .5v.9l-.3 .5M62.8 35.6v.9M62.8 37.7h.4M62.8 39.6h.4M63.2 35.6l-.4 .3M63.2 37.3h-.2v1.1M63.2 39.2l-.2 .1v1.1M63.3 27.4v1.2h.5l.1-.2v-.4l-.1-.1h-.5M63.4 29.4l.4 1.2 .5-1.2M63.6 35.8l.2-.2 .3 .1v.7h-.5zM63.6 37.8l.2-.1h.3l.2 .1-.1 .6h-.5z"/>
<path d="M63.6 39.8l.2-.2h.3l.2 .2v.4l-.2 .2h-.3l-.2-.2zM64.3 28l.2-.1h.4l.1 .1v.4l-.1 .2h-.4l-.2-.2zM64.7 30.6v-1.2l.3 .8 .4-.8v1.2M64.7 35.3v1l.2 .2M64.8 37.7v.7M64.8 39.6v.8M65.1 37.7h-.2l-.1 .1M65.1 39.6h-.2l-.1 .2M65.5 27.9h.5v.1v.6h-.5l-.1-.2 .2-.2 .4-.1M66 30h.5M66.5 38.4v-1.1l.4 .8 .3-.8v1.1M66.6 29.4h-.6v1.2h.6"/>
<path d="M66.6 27.9v.7M66.9 35.3h-.5l-.2 .2 .2 .3 .5 .2v.4h-.7M67 27.9h-.3l-.1 .1M67.5 35.7l.3-.1 .2 .2v.6h-.5M67.5 35.6v1.3M67.8 38.4v-1.1l.4 .8 .5-.8v1.1M67.9 27.4v1.2h-.4l-.2-.2v-.4l.2-.1h.4M68.1 29.4v1.2M68.6 35.7l.3-.1 .2 .2v.7M69.1 36h-.4l-.2 .2 .2 .3 .4-.1M69.3 37.3v1.1a.36 .36 0 0 0 .6-.2v-.9M69.3 39.2v1.2h.5l.1-.2v-1"/>
<path d="M69.4 27.4v1.2M69.5 29.3l-1 1.6M69.9 29.5l.3-.1 .3 .1a.87 .87 0 0 1 0 1.1h-.5l-.2-.4zM70.2 35.7h-.5l-.1 .5a.36 .36 0 0 0 .6 .2M70.6 36.1l.6-.1-.2-.4-.4 .2v.5l.2 .2 .3-.1M70.9 27.3l-1.1 1.7M71.5 27.4a.46 .46 0 0 1 .5 .5l-.1 .7h-.5a.86 .86 0 0 1 .1-1.2zM73.1 35.7h-.5v.3l.4 .1 .1 .2-.1 .2-.4-.1M73.7 35.8l.1-.2 .4 .2v.7M73.7 35.3v1.2M74.7 36.1l.6-.1-.2-.4-.4 .2v.5l.1 .2 .4-.1M75.7 36.1l.6-.1v-.3l-.4-.1-.2 .2 .1 .6h.5"/>
<path d="M76.6 35.6h.5M76.9 35.3v1.1l.2 .1M23.4 41.6l.7 .7M24.1 41.6l-.7 .7M24.5 41.6l.6 .7M25.1 41.6l-.6 .7M25.5 41.6l.6 .7M26.1 41.6l-.6 .7M26.4 41.6l.7 .7M27.1 41.6l-.7 .7M27.5 40.3v.1M27.5 42.2v.1"/>
<path d="M28 41.6l.6 .7M28.6 41.6l-.6 .7M29 41.6l.6 .7M29.6 41.6l-.6 .7M30 41.6l.6 .7M30.6 41.6l-.6 .7M31 41.6l.6 .7M31.6 41.6l-.6 .7M32.8 41.6l.7 .7M33.5 41.6l-.7 .7M33.9 41.6l.6 .7M34.5 41.6l-.6 .7"/>
<path d="M34.9 41.6l.6 .7M35.5 41.6l-.6 .7M35.8 41.6l.7 .7M36.5 41.6l-.7 .7M36.9 40.3v.1M36.9 42.2v.1M37.4 41.6l.6 .7M38 41.6l-.6 .7M38.4 41.6l.6 .7M39 41.6l-.6 .7M39.4 41.6l.6 .7M40 41.6l-.6 .7"/>
<path d="M40.4 41.6l.6 .7M41 41.6l-.6 .7M42.2 41.6l.7 .7M42.9 41.6l-.7 .7M43.3 41.6l.6 .7M43.9 41.6l-.6 .7M44.2 41.6l.7 .7M44.9 41.6l-.7 .7M45.2 41.6l.7 .7M45.9 41.6l-.7 .7M46.3 40.3v.1M46.3 42.2v.1"/>
<path d="M46.8 41.5l.4-.4v1.2M46.8 42.3h.8M47.8 40.4h.7M47.9 41.6l.7 .7M48.6 41.6l-.7 .7M48.9 41.6l.7 .7M49.6 41.6l-.7 .7M50 41.6l.5 .7M50.5 41.6l-.5 .7M52 41.9h.9M54.4 41.6v.7M54.7 41.6l-.3 .2"/>
<path d="M55.1 42l.5-.2v-.1h-.5v.6h.5M56.6 41.7l-.3-.1-.2 .1 .2 .3h.3v.3h-.5M57.1 42l.6-.2v-.1h-.6v.6h.6M58.2 41.6v.7M58.6 41.6l-.4 .1v.1M58.8 41.6l.4 .7 .2-.7M59.9 42l.5-.2-.1-.2-.4 .1v.6h.5M61.5 41.1v1.2h-.5v-.6h.5M62.8 41.6h.4M63.2 41.1l-.2 .1v1.1M63.7 41.7h.5l.1 .5-.2 .1h-.3l-.2-.1zM64.8 41.6v.7"/>
<path d="M65.1 41.6l-.3 .2M66.5 40.4v-1.2l.4 .8 .3-.8v1.2M66.5 42.3v-1.2l.4 .9 .3-.9v1.2M67.8 40.4v-1.2l.4 .8 .5-.8v1.2M67.8 42.3v-1.2l.4 .9 .5-.9v1.2M69.3 41.1v1.2h.5l.1-.1v-1.1M86.2 56.5v.8l-.2 .3-.3 .1M86.5 56.5h.8M86.9 56.5v1.2M87.5 57.7l.4-1.2 .4 1.2M87.6 57.3h.6M89.3 56.5h-.4a.61 .61 0 0 0-.3 .8 .61 .61 0 0 0 .8 .3v-.5h-.2"/>
<path d="M91.5 56.6l-.5-.1a.61 .61 0 0 0-.2 .7 .61 .61 0 0 0 .7 .4M92.1 57l.2-.2 .3 .2v.7M92.1 56.5v1.2M93.2 56.9l.4-.1 .1 .2v.7M93.7 57.1l-.5 .1-.1 .2 .2 .3 .4-.1M94.3 56.5v.1M94.3 56.8v.9M94.8 57l.2-.2 .4 .2v.7M94.8 56.8v.9M95.9 57.6v.1M95.9 56.9v.1M97.4 57.7v-1.2l.5 .8 .4-.8v1.2"/>
<path d="M98.9 57.7v-1.2l.3 .8 .4-.8v1.2M100.2 56.5v.9l.3 .3 .4-.1v-1.1M102.8 56.3a1.32 1.32 0 0 0 0 1.8M103.2 56.8l.3-.3v1.2M103.2 57.7h.7M105 56.5h-.6v.5l.4-.1 .3 .2-.1 .5h-.6M105.6 56.6l.1-.1 .4 .1a.66 .66 0 0 1-.3 1.1l-.1-.1a.67 .67 0 0 1-.1-1zM106.9 57l-.2-.4 .1-.1h.5l.1 .3-.2 .2h-.4l-.1 .2 .2 .5 .5-.1v-.5l-.2-.1M107.8 56.3l.3 .5v.8l-.3 .5M109.6 57.2h1M111.2 56.8l.9 .4-.9 .4M113.6 56.5v1.2"/>
<path d="M114.3 56.5h.4l.2 .1v.9l-.5 .2a.86 .86 0 0 1-.1-1.2zM116.2 56.6l-.5-.1a.61 .61 0 0 0-.3 .8 .61 .61 0 0 0 .8 .3M116.5 56.5h.7M116.8 56.5v1.2M117.6 56.5v1.2h.6M119.9 56.3l-.4 .5v.8l.4 .5M120.2 56.8l.4-.3v1.2M120.2 57.7h.8M122.1 56.5h-.6l-.1 .5h.7v.6h-.7M122.7 56.6l.4-.1a.86 .86 0 0 1-.1 1.2l-.3-.1zM123.9 57l-.1-.4 .5-.1 .2 .2-.3 .3-.4 .1v.5l.1 .1 .5-.1 .1-.2-.3-.4M124.9 56.3a1.32 1.32 0 0 1 0 1.8"/>
<path d="M126.7 57.2h.9M128.2 56.8l.9 .4-.9 .4M130.6 57.7v-1.2l.5 .8 .4-.8v1.2M132.1 57h.3M132.6 56.5h-.5v1.2h.5M133.2 57.7v-1.2l.3 .8 .4-.8v1.2M135.2 56.6l-.5-.1a.61 .61 0 0 0-.2 .7 .61 .61 0 0 0 .7 .4M135.5 56.5h.8M135.9 56.5v1.2M136.6 56.5v1.2h.6M138.9 56.3a1.32 1.32 0 0 0 0 1.8M139.4 56.8l.3-.3v1.2"/>
<path d="M139.4 57.7h.6M141.1 56.5h-.6v.5l.5-.1 .2 .2-.1 .5h-.6M141.8 56.5h.4l.1 .1v.8l-.3 .3a.84 .84 0 0 1-.2-1.2zM143.1 56.4l-.3 .8h.8M143.4 56.8v.9M143.9 56.3a1.32 1.32 0 0 1 0 1.8"/>
<circle cx="61.9" cy="30" r=".58"/>
</g>
<g fill="none" stroke="#006665" stroke-width=".21">
<path d="M23.5 76.6l-.5-.1a.66 .66 0 0 0-.2 .7 .66 .66 0 0 0 .6 .5l.1-.1M24 77.1l.7-.1 .1-.3-.2-.2h-.6v1.2M25.3 76.5v1a.35 .35 0 0 0 .4 .2 .35 .35 0 0 0 .3-.2v-1M77.2 78v-1.3l.4 .9 .4-.9v1.3M78.6 78v-1.3l.4 .9 .4-.9v1.3M80 76.7v1.1l.2 .2h.2l.3-.3v-1M128.8 76.6l-.5-.1a.66 .66 0 0 0-.3 .7 .66 .66 0 0 0 .6 .5l.2-.1M129.4 77l.3-.1 .2 .1v.6h-.5zM130.5 77l.1-.1 .4 .1v.7M130.5 76.9v.8M131.3 76.9h.5M131.6 76.5v1.1l.2 .1"/>
<path d="M132.2 76.9v.8M132.6 76.9l-.4 .2M133 77l.3-.1 .3 .2-.1 .5h-.5zM134.1 76.5v1.1l.2 .1M136.3 76.5h-.6l-.2 .2 .2 .3 .5 .2v.4h-.7M136.8 77l.4-.1 .2 .2-.1 .5h-.5M136.8 76.9v1.2M137.9 77l.4-.1 .1 .1v.7M138.4 77.2h-.4l-.2 .2 .2 .3 .4-.1M139.5 77l-.3-.1-.3 .2 .1 .5h.5M140 77.3l.5-.1v-.2h-.5v.6h.5M181 77l.2-.1 .3 .1v.7"/>
<path d="M181 76.9v.8M182.1 77.2h.9M183.6 77l.4-.1 .2 .2-.1 .5h-.5M183.6 76.5v1.2M184.7 77.1l.2-.2 .3 .1v.6h-.5zM185.8 77h.5v.7M186.3 77.2h-.4l-.1 .2 .1 .3 .4-.1M186.9 76.9v.8M187.3 76.9l-.4 .2M188.2 77l-.3-.1-.3 .2 .1 .5h.5M188.2 76.5v1.2M189.7 77l.2-.1 .3 .1v.7"/>
<path d="M189.7 76.9v.8M190.2 77l.2-.1 .4 .1v.7M191.3 77.3l.6-.1v-.2l-.4-.1-.2 .1v.6h.6M192.4 77l.2-.1 .4 .1v.7M192.4 76.9v.8M193 77l.1-.1 .4 .1v.7M194.1 77l.3-.1 .2 .1v.6h-.5zM195.2 76.9v.8M195.5 76.9l-.3 .2M195.7 76.9l.4 .8M196.3 76.9l-.2 .8-.4 .4M24.1 112.6l.2-.2 .3 .1v.8"/>
<path d="M24.1 112.4v.9M25.2 112.9h1M26.8 112.5l.3-.1 .2 .3v.5h-.5M26.8 112.1v1.2M27.8 112.7l.4-.3 .2 .3v.5h-.5zM29 112.5h.5v.8M29.5 112.8l-.5 .1-.1 .1 .1 .3 .5-.1M30.1 112.4v.9M30.4 112.4l-.3 .3M31.3 112.5l-.3-.1-.3 .3 .1 .5h.5M31.3 112.1v1.2M32.8 112.1v1.2"/>
<path d="M33.5 112.1h.5a.77 .77 0 0 1-.1 1.2l-.4-.1a.87 .87 0 0 1 0-1.1zM77.2 112.6h.4M77.8 112.1h-.6v1.2h.6M78.1 112.4l.7 .9M78.8 112.4l-.7 .9M79.2 112.5l.5-.1 .1 .2v.6h-.6M79.2 112.4v1.3M80.3 112.5l.5-.1 .1 .2v.7M80.9 112.8l-.6 .1v.3h.6M81.4 112.6l.2-.2 .4 .2v.7M81.4 112.4v.9M83 112.5h-.5v.4h.4l.2 .2-.2 .2-.4-.1"/>
<path d="M83.6 112.1v.1M83.6 112.4v.9M84.1 112.7l.4-.3 .2 .3v.5h-.5zM85.3 112.6l.1-.2 .4 .2v.7M85.3 112.4v.9M128.1 112.7l.7-.1v-.4l-.7-.1v1.2M129.4 112.5l.3-.1 .2 .2v.6h-.5zM130.3 112.4l.3 .9 .2-.6 .2 .6 .2-.9M131.7 112.9l.5-.1-.1-.4-.4 .2v.5l.1 .2 .4-.1M132.8 112.4v.9M133.1 112.4l-.3 .3M135 112.1h-.6v.2v.3l.6 .3v.3h-.6"/>
<path d="M135.5 112.4v.7l.3 .2 .3-.1M136.1 112.4v.9M136.7 112.5l.4-.1 .1 .2v.6h-.5M136.7 112.4v1.3M137.8 112.5l.4-.1 .1 .2v.6h-.5M137.8 112.4v1.3M138.9 112.1v1.1l.2 .1M139.4 112.4l.3 .9M140 112.4l-.6 1.3"/>
<circle cx="180.1" cy="77.1" r=".57"/>
<circle cx="23.2" cy="112.7" r=".57"/>
</g>
<g fill="none" stroke="#765500" stroke-width=".21">
<path d="M22.9 106.3h.4M23.4 105.7h-.5v1.2M23.9 105.7v.1M23.9 106.1v.8M24.5 105.7v1.1l.1 .1M25.1 106.5l.6-.2-.2-.2-.4 .2v.5l.1 .1 .4-.1M26.2 106.8v.1M26.2 106.2v.1M28.2 106.2l-.3-.1-.3 .2v.4l.3 .2 .3-.1M28.7 106.2a.36 .36 0 0 1 .6 .1l-.1 .5h-.5M28.7 106.1v1.2M29.8 106.1v.7l.2 .1 .3-.1"/>
<path d="M30.3 106.1v.8M31.2 105.7a.68 .68 0 0 1 .4 .6 .68 .68 0 0 1-.4 .6l-.3-.2v-.8zM32 106h.2l.1-.3v1.2M32 106.9h.8M33.4 105.7l.5 .2v.8l-.3 .2a.75 .75 0 0 1-.2-1.2zM34.4 106.4h.9M36.4 106.2h-.5v.6l.2 .1 .3-.1M37 106.2h.5v.6l-.2 .1-.3-.1M37 106.1v1.2M38.1 106.1v.7l.3 .1 .2-.1M38.6 106.1v.8M39.2 106.8v.1"/>
<path d="M39.7 105.7v1.2M39.9 106.4l.3 .5M40.2 106.1l-.5 .5M40.7 105.7v.1M40.7 106.1v.8M41.8 106.2l-.3-.1-.3 .2v.4l.3 .2 .3-.1M42.3 106.2h.5v.7M42.8 106.3l-.5 .2v.3h.5M43.9 106.2h-.5v.6l.2 .1 .3-.1M43.9 105.7v1.2M44.3 107h.9M45.9 106.2h-.4v.2l.3 .1 .2 .3-.2 .1-.3-.1"/>
<path d="M47 106.2l-.4-.1-.2 .2v.4l.2 .2 .4-.1M47.5 106.2h.5v.7M47.5 105.7v1.2M77.2 106.3h.4M77.8 105.7h-.6v1.2M78.2 105.7v.1M78.2 106.1v.8M78.8 105.7v1.1l.2 .1M79.4 106.5l.6-.2-.2-.2-.4 .1v.6h.5M80.5 106.8v.1M80.5 106.2v.1M82.5 106.2a.36 .36 0 0 0-.5 .1v.5h.5"/>
<path d="M83.1 106.2l.3-.1 .2 .2v.4l-.2 .2-.3-.1M83.1 106.1v1.2M84.2 106.1v.7l.1 .1 .4-.1M84.7 106.1v.8M85.3 105.7h.2a.68 .68 0 0 1 .4 .6 .68 .68 0 0 1-.4 .6 .81 .81 0 0 1-.2-1.2zM86.4 106l.3-.3v1.2M86.4 106.9h.6M87.5 105.9l.3-.2a.68 .68 0 0 1 .4 .6 .68 .68 0 0 1-.4 .6l-.3-.2zM88.7 106.4h1M90.3 106.2l.3-.1 .2 .2v.6M90.3 106.1v.8M90.8 106.3l.1-.2 .4 .1v.7"/>
<path d="M91.9 106.2h.5v.7M91.9 106.1v.8M92.4 106.3l.1-.2 .4 .1v.7M93.5 106.1v.7l.1 .1 .4-.1M94 106.1v.8M94.6 106.8v.1M95.2 105.7v1.2M95.2 106.4l.5 .5M95.7 106.1l-.5 .5M96.2 105.7v.1M96.2 106.1v.8M97.3 106.2a.36 .36 0 0 0-.6 .1l.1 .5h.5"/>
<path d="M97.8 106.2l.3-.1 .2 .2v.6M98.3 106.3l-.6 .3 .2 .3 .4-.1M99.4 106.2l-.3-.1-.3 .2v.4l.3 .2 .3-.1M99.4 105.7v1.2M99.7 107h1M101.3 106.2l-.3-.1-.2 .2 .2 .2 .3 .1v.2h-.5M102.4 106.2a.36 .36 0 0 0-.5 .1v.5h.5M103 106.2l.3-.1 .2 .2v.6M103 105.7v1.2M128.1 106.8h.4M128.7 106.2h-.6v1.2M129.1 106.2v.1"/>
<path d="M129.1 106.6v.8M129.7 106.2v1l.2 .2M130.3 107l.6-.2-.1-.2h-.4l-.1 .2 .1 .6h.4M131.4 107.3v.1M131.4 106.6v.2M133.4 106.6h-.4l-.2 .2v.4l.2 .2h.4M133.9 107.4h.5v-.8h-.5v1.2M135 106.6l.1 .8 .4-.1M135.5 106.6v.8M136.2 106.3l.3-.1a.77 .77 0 0 1 .1 1.2h-.3l-.2-.2zM137.2 106.5l.4-.3v1.2M137.2 107.4h.8"/>
<path d="M138.5 106.3l.4-.1 .2 .2v.8l-.2 .2-.4-.1zM139.6 106.9h.9M141.6 106.6l-.5 .1v.6l.5 .1M142.2 106.6l.5 .1v.7h-.5zM143.3 106.7l.5-.1v.8M143.3 106.6v.8M144.3 106.6h.4M144.4 106.2v1.2h.3M145.1 106.6v.8M145.5 106.6h-.3l-.1 .2M145.9 106.6l.5 .1 .1 .5-.2 .2h-.4zM147 106.2v1.2h.1"/>
<path d="M147.6 107.3v.1M148.2 106.2v1.2M148.3 106.9l.4 .5M148.7 106.6l-.5 .4M149.2 106.2v.1M149.2 106.6v.8M150.3 106.6h-.5l-.1 .2 .1 .6h.5M150.8 106.6h.4l.1 .2v.6h-.5l-.1-.3 .6-.3M152.4 106.2v1.2h-.4l-.2-.2 .1-.5 .5-.1M152.7 107.5h1M154.3 106.6h-.4l-.1 .2 .2 .2h.3v.4h-.5M155.4 106.6h-.5v.2v.6h.5"/>
<path d="M156 106.7l.4-.1 .1 .8M156 106.2v1.2M179.7 107h.5M180.3 106.4h-.6v1.2M180.8 106.4v.1M180.8 106.8v.8M181.4 106.4v1l.1 .2M181.9 107.2l.6-.1v-.3h-.5l-.1 .2 .1 .6h.5M183 107.5v.1M183 106.8v.2M185.1 106.8h-.4l-.2 .2v.4l.2 .2h.4M185.6 107.6h.5v-.8h-.5v1.2"/>
<path d="M186.7 106.8l.1 .8 .4-.1M187.2 106.8v.8M187.9 106.5l.2-.1a.77 .77 0 0 1 .2 1.2h-.3l-.2-.2zM188.9 106.8l.3-.4v1.2M188.9 107.6h.8M190.2 106.5l.3-.1 .3 .3v.7l-.2 .2-.4-.1zM191.3 107.2h.9M192.8 106.9l.5-.1v.8l-.5-.1zM193.9 106.4v1.2h.5v-.8h-.5M195 106.9l.5-.1v.8M195 106.8v.8M195.5 107l.1-.2h.4l.1 .8"/>
<path d="M196.6 107.2l.6-.1-.1-.3h-.5v.8h.5M197.7 106.9l.4-.1 .1 .8M197.7 106.8v.8M198.2 107l.1-.2h.3l.1 .8M199.3 107.5v.1M199.9 106.4v1.2M200 107.2l.3 .4M200.3 106.8l-.4 .5M200.8 106.4v.1M200.8 106.8v.8M202 106.8l-.6 .1v.6l.6 .1M202.5 106.8h.4l.1 .2v.6h-.5v-.4l.5-.1"/>
<path d="M204.1 106.4v1.2h-.5v-.8h.5M204.4 107.8h.9M206 106.8h-.3l-.1 .2 .4 .3v.3h-.4M207.1 106.8l-.5 .1v.6l.5 .1M207.7 106.9l.4-.1 .1 .8M207.7 106.4v1.2M22.9 141.8h.4M23.4 141.2h-.5v1.3M23.9 141.2v.2M23.9 141.6v.9M24.5 141.2v1.1l.1 .2M25.1 142.1l.6-.1-.2-.4-.4 .2v.5l.1 .2 .4-.1"/>
<path d="M26.2 142.3v.2M26.2 141.7v.1M28.2 141.7l-.3-.1-.3 .3v.3l.3 .3 .3-.1M28.7 141.7a.36 .36 0 0 1 .6 .2l-.1 .5h-.5M28.7 141.6v1.3M29.8 141.6v.7l.2 .2 .3-.2M30.3 141.6v.9M31.2 141.2a.68 .68 0 0 1 .4 .7 .68 .68 0 0 1-.4 .6l-.3-.3v-.7zM32 141.6h.2l.1-.4v1.3M32 142.5h.8M33.4 141.2l.5 .3v.7l-.3 .3a.75 .75 0 0 1-.2-1.3zM34.4 142h.9"/>
<path d="M35.9 141.7h.5v.7l-.3 .1-.2-.2zM37 141.7a.36 .36 0 0 1 .6 .2l-.1 .5h-.5M37 141.2v1.3M38.1 141.2v.2M38.1 141.6v.9M38.7 141.7h.5v.7l-.3 .1-.3-.3zM39.8 142.3v.2M40.4 141.2v1.3M40.5 142l.3 .5M40.8 141.6l-.4 .6M41.4 141.2v.2M41.4 141.6v.9"/>
<path d="M42.5 141.7h-.6v.6l.3 .2 .3-.1M43 141.7l.3-.1 .2 .2v.7M43.5 142h-.4l-.2 .2 .2 .3 .4-.1M44.6 141.7l-.3-.1-.3 .3v.3l.3 .3 .3-.1M44.6 141.2v1.3M44.9 142.6h.9M46.6 141.7l-.4-.1-.1 .2 .1 .3 .4 .1v.2h-.5M47.7 141.7h-.6v.6l.2 .2 .4-.1M48.2 141.7l.3-.1 .2 .2v.7M48.2 141.2v1.3M77.2 141.8h.4M77.8 141.2h-.6v1.3"/>
<path d="M78.2 141.2v.2M78.2 141.6v.9M78.8 141.2v1.1l.2 .2M79.4 142.1l.6-.1-.2-.4-.4 .1v.7h.5M80.5 142.3v.2M80.5 141.7v.1M82.5 141.7a.36 .36 0 0 0-.5 .2v.5h.5M83.1 141.7l.3-.1 .2 .3v.3l-.2 .3-.3-.1M83.1 141.6v1.3M84.2 141.6v.7l.1 .2 .4-.2M84.7 141.6v.9M85.3 141.3l.2-.1a.68 .68 0 0 1 .4 .7 .68 .68 0 0 1-.4 .6 .81 .81 0 0 1-.2-1.2z"/>
<path d="M86.4 141.6l.3-.4v1.3M86.4 142.5h.6M87.5 141.5l.3-.3a.68 .68 0 0 1 .4 .7 .68 .68 0 0 1-.4 .6l-.3-.3zM88.7 142h1M90.2 142.1l.6-.1-.2-.4-.4 .2v.5l.1 .2 .4-.1M91.2 141.6l.6 .9M91.8 141.6l-.6 .9M92.3 141.7l.3-.1 .3 .3v.3l-.3 .3-.3-.1M92.3 141.6v1.3M93.4 141.7l.3-.1 .2 .2v.7M93.9 142h-.4l-.2 .2 .2 .3 .4-.1M94.5 141.7l.3-.1 .2 .2v.7"/>
<path d="M94.5 141.6v.9M96 141.7l-.3-.1-.2 .2 .2 .3 .3 .1v.2h-.5M96.6 141.2v.2M96.6 141.6v.9M97.1 141.7h.6v.6l-.2 .2-.4-.2zM98.2 141.7l.4-.1 .2 .2v.7M98.2 141.6v.9M99.3 142.3v.2M99.9 141.2v1.3M100.1 142l.3 .5M100.4 141.6l-.5 .6M100.9 141.2v.2"/>
<path d="M100.9 141.6v.9M102 141.7l-.3-.1-.3 .3 .1 .5h.5M102.5 141.7h.5v.8M103 142l-.6 .2 .3 .3 .3-.1M104.1 141.7l-.3-.1-.3 .3v.3l.3 .3 .3-.1M104.1 141.2v1.3M104.5 142.6h.9M106.1 141.7l-.4-.1-.1 .3 .4 .2 .2 .2-.2 .2-.4-.1M107.2 141.7l-.4-.1-.2 .3 .1 .5h.5M107.7 141.7h.5v.8M107.7 141.2v1.3M128.1 141.8h.4"/>
<path d="M128.7 141.2h-.6v1.3M129.1 141.2v.2M129.1 141.6v.9M129.7 141.2v1.1l.2 .2M130.3 142.1l.6-.1-.2-.4-.4 .2v.5l.2 .2 .3-.1M131.4 142.3v.2M131.4 141.7v.1M133.4 141.7l-.3-.1-.3 .3v.3l.3 .3 .3-.1M133.9 141.7a.36 .36 0 0 1 .6 .2l-.1 .5h-.5M133.9 141.6v1.3M135 141.6v.7l.2 .2 .3-.2M135.5 141.6v.9"/>
<path d="M136.4 141.2a.68 .68 0 0 1 .4 .7 .68 .68 0 0 1-.4 .6l-.3-.3v-.7zM137.2 141.6h.2l.2-.4v1.3M137.2 142.5h.8M138.7 141.2l.4 .3v.7l-.2 .3a.75 .75 0 0 1-.2-1.3zM139.6 142h.9M141.1 141.7a.36 .36 0 0 1 .6 .2l-.1 .5h-.5M141.1 141.6v1.3M142.7 141.7h-.5v.3l.4 .1 .1 .2-.1 .2-.4-.1M143.3 141.6v.7l.1 .2 .4-.2M143.8 141.6v.9M144.4 142.3v.2M144.9 141.2v1.3"/>
<path d="M145 142l.4 .5M145.4 141.6l-.5 .6M145.9 141.2v.2M145.9 141.6v.9M147 141.7h-.5v.6l.1 .2 .4-.1M147.6 141.7l.3-.1 .2 .2v.7M148.1 142h-.4l-.2 .2 .2 .3 .4-.1M149.2 141.7a.36 .36 0 0 0-.6 .2l.1 .5h.5M149.2 141.2v1.3M149.4 142.6h1M151 141.7l-.2-.1-.2 .3 .5 .4-.1 .2-.4-.1M152.1 141.7h-.5v.6l.2 .2 .3-.1"/>
<path d="M152.7 141.7l.4-.1 .1 .2v.7M152.7 141.2v1.3"/>
</g>
<path d="M119.8 32.8l1.2 1.2M121 32.8l-1.2 1.2M132 30.5l1.2 1.1M132 32.8l1.2 1.2M133.2 30.5l-1.2 1.1M133.2 32.8l-1.2 1.2" fill="none" stroke="#00008a" stroke-width=".21"/>
<g fill="#090">
<circle cx="111.8" cy="35.9" r=".47"/>
<circle cx="94.8" cy="26.2" r=".47"/>
<circle cx="103.4" cy="31.1" r=".47"/>
<circle cx="103.4" cy="48.1" r=".47"/>
<circle cx="141.1" cy="35.9" r=".47"/>
</g>
<g fill="none" stroke="#006665" stroke-width=".21">
<path d="M125 19.4l-.1 1.1-.4 .2M125.5 19.7l.3-.3v1.3M126.7 19.5a.61 .61 0 0 1 .7 .4 .61 .61 0 0 1-.4 .8 .71 .71 0 0 1-.3-1.2zM127.8 19.7l.3-.3v1.3M144.9 19.7v1M146.5 19.4h-.5l-.1 .6 .6-.1v.7l-.5 .1-.1-.2M146.9 19.4l.4 1.3 .4-1.3M125 21.8v1.1l-.4 .1M125.5 21.8h.7M125.5 20.7h.7M125.8 21.8v1.2M126.4 23l.4-1.2 .5 1.2"/>
<path d="M126.5 22.7h.6M127.8 20.7h.6M128.3 21.9a.46 .46 0 0 0-.7 .2v.7l.2 .2 .6-.1v-.4h-.3M144.4 20.1h1M186.6 31.6v-1.2l.3 .8 .5-.8v1.2M186.6 36.5v-1.3l.3 .9 .5-.9v1.3M186.6 26.8v-1.3l.3 .8 .5-.8v1.3M186.6 23v1.3M186.6 27.9v1.2M186.6 32.8v1.2M186.6 37.7v1.2M186.6 28.5h.7"/>
<path d="M186.6 33.4h.7M186.6 38.3h.7M186.6 23.6h.7M187.3 23v1.3M187.3 27.9v1.2M187.3 32.8v1.2M187.3 37.7v1.2M187.8 28.3l.3-.4v1.2M187.8 33.2l.3-.4v1.2M187.8 38l.3-.3v1.2M187.8 23.4l.3-.4v1.3M187.8 29.1h.7"/>
<path d="M187.8 34h.7M187.8 38.9h.7M187.8 24.3h.7M188 35.7h.5v.7l-.4 .1-.2-.3zM188 26h.5v.7l-.4 .1-.2-.3zM188.1 30.7l.4 .3v.3l-.2 .3-.4-.3v-.3zM189 33l.2-.2a.68 .68 0 0 1 .5 .6 .68 .68 0 0 1-.5 .6l-.2-.2zM189.1 30.7v.7l.1 .2 .4-.1M189.1 35.6v.7l.1 .2 .4-.2M189.1 25.9v.8l.3 .1 .2-.2M189.1 28l.3-.1a.86 .86 0 0 1 .1 1.2h-.4l-.1-.1zM189.1 37.8l.3-.1a.86 .86 0 0 1 .1 1.2h-.4l-.1-.2z"/>
<path d="M189.2 23a.68 .68 0 0 1 .5 .7 .68 .68 0 0 1-.5 .6l-.2-.3v-.7zM189.6 25.9v.9M189.6 30.7v.9M189.6 35.6v.9M190.1 28l.5-.1 .2 .3-.7 .9h.7M190.1 32.8h.7l-.4 .5 .4 .1v.4l-.2 .2h-.4l-.1-.1M190.1 23.4l.4-.4v1.3M190.1 24.3h.7M190.2 30.9l.1-.2 .4 .1v.8M190.2 35.7h.5v.8M190.2 26h.5v.8M190.2 25.9v.9"/>
<path d="M190.2 30.7v.9M190.2 35.6v.9M190.4 37.6l-.3 .9h.7M190.7 38.1v.8M191.1 30.7h.5M191.1 35.6h.5M191.1 25.9h.5M191.3 30.4v1l.3 .2M191.3 35.2v1.1l.3 .2M191.3 25.5v1l.3 .3M191.9 30.4v.1M191.9 35.2v.2"/>
<path d="M191.9 25.5v.2M191.9 25.9v.9M191.9 30.7v.9M191.9 35.6v.9M192.5 30.9l.2-.2 .3 .1v.8M192.5 35.7h.5v.8M192.5 26h.5v.8M192.5 25.9v.9M192.5 30.7v.9M192.5 35.6v.9M194.1 30.7v1.1l-.1 .2-.4-.1M194.1 30.8l-.3-.1-.2 .2v.6h.5"/>
<path d="M194.1 35.6v1.1l-.5 .1M194.1 35.7h-.5v.6l.2 .2 .3-.1M194.1 25.9v1.1l-.5 .1M194.1 26h-.5v.6l.2 .2 .3-.1M194.7 25.5v1.3M194.7 30.4v1.2M194.7 35.2v1.3M194.7 31h.7M194.7 35.8h.7M194.7 26.1h.7M195.4 25.5v1.3M195.4 30.4v1.2"/>
<path d="M195.4 35.2v1.3M196 30.9l.2-.2 .3 .1 .1 .7h-.6zM196 35.7h.6l-.1 .7-.3 .1-.2-.2zM196 26h.6l-.1 .7-.3 .1-.2-.2zM197.1 30.4v1l.2 .2M197.1 35.2v1.1l.2 .2M197.1 25.5v1l.2 .3M197.7 31.2l.6-.1-.2-.4-.3 .1-.1 .6 .2 .2 .3-.1M197.7 36.1l.6-.2-.2-.3-.4 .2v.5l.2 .2 .3-.1M197.7 26.3l.6-.1-.2-.3-.4 .2v.4l.2 .3 .3-.1M97.6 44.1l.4-.3v1.2M97.6 42l.5-.1-.1-.4h-.4v.9"/>
<path d="M97.6 45h.7M97.8 42l.3 .4M98.5 41.7l.3-.2v.9M98.5 42.4h.6M98.9 43.9l.2-.1a.84 .84 0 0 1 .2 1.2h-.3a.78 .78 0 0 1-.1-1.1zM99.6 41.5a.47 .47 0 0 1 .4 .4 .47 .47 0 0 1-.4 .5l-.2-.3zM100 43.8v1.2M100.2 44.3l.5 .7M100.3 41.7l.4-.2v.9M100.3 42.4h.6M100.7 43.8l-.7 .6M101.8 53.1h.9"/>
<path d="M102.3 52.6v.9M103.9 52.3h-.6l-.1 .6 .2-.2h.3l.3 .3-.1 .4h-.7M104.3 52.3l.3 1.2 .5-1.2M106.1 44.1l.4-.3v1.2M106.1 42h.4l.2-.2-.1-.3h-.5v.9M106.1 45h.7M106.3 42l.4 .4M107 41.7l.3-.2v.9M107 42.4h.6M107.4 43.9l.3-.1 .2 .2v.8l-.1 .2-.4-.1a.78 .78 0 0 1 0-1zM108 41.6l.1-.1a.47 .47 0 0 1 .5 .4 .47 .47 0 0 1-.5 .5l-.2-.3zM108.5 43.8v1.2"/>
<path d="M108.7 44.3l.5 .7M108.9 41.6l.5-.1 .1 .2-.6 .7h.6M109.2 43.8l-.7 .6M114.6 44.1l.4-.3v1.2M114.6 42l.5-.1 .1-.2-.1-.2h-.5v.9M114.6 45h.7M114.9 42l.3 .4M115.6 41.7l.2-.2v.9M115.6 42.4h.5M115.9 43.9l.3-.1a.86 .86 0 0 1 .1 1.2l-.4-.1zM116.6 41.5h.3l.1 .2-.1 .7h-.3l-.1-.2zM117 43.8v1.2"/>
<path d="M117.2 44.3l.5 .7M117.3 41.5h.6l-.2 .3 .2 .1v.4h-.6M117.7 43.8l-.7 .6M140.2 42.6h-.5l-.2 .2v.7a.45 .45 0 0 0 .7 .2v-.4h-.2M141.5 42.6v1.2l-.7-1.2v1.2M142.1 42.6h.4a.66 .66 0 0 1 .2 .7 .66 .66 0 0 1-.6 .5zM186.6 51.1v-1.2l.3 .8 .5-.8v1.2M186.6 46.2v-1.2l.3 .9 .5-.9v1.2M186.6 41.3v-1.2l.3 .9 .5-.9v1.2M186.6 56v-1.3l.3 .9 .5-.9v1.3M186.6 42.6v1.2M186.6 47.4v1.2"/>
<path d="M186.6 52.3v1.2M186.6 57.1v1.3M186.6 48h.7M186.6 43.1h.7M186.6 52.9h.7M186.6 57.7h.7M187.3 42.6v1.2M187.3 47.4v1.2M187.3 52.3v1.2M187.3 57.1v1.3M187.8 47.7l.3-.3v1.2M187.8 42.9l.3-.3v1.2"/>
<path d="M187.8 52.7l.3-.4v1.2M187.8 57.5l.3-.4v1.3M187.8 48.6h.7M187.8 43.8h.7M187.8 53.5h.7M187.8 58.4h.7M187.9 50.5l.1-.2h.5v.8h-.5l-.1-.2zM187.9 40.7l.1-.1h.5v.6h-.5zM188 45.5h.5v.6l-.4 .1-.2-.2zM188.1 55.1l.4 .3v.3l-.2 .3-.4-.3v-.3zM189 42.8l.1-.2h.4a.91 .91 0 0 1-.1 1.2l-.4-.3zM189 52.5l.1-.2h.4a.86 .86 0 0 1-.1 1.2l-.4-.2z"/>
<path d="M189.1 50.3v.8l.5-.1M189.1 45.4v.7l.1 .1 .4-.1M189.1 40.6v.5l.1 .2 .4-.1M189.1 55.1v.7l.1 .2 .4-.2M189.1 47.5l.3-.1a.91 .91 0 0 1 .1 1.2h-.4l-.1-.2zM189.2 57.1a.68 .68 0 0 1 .5 .7 .68 .68 0 0 1-.5 .6l-.2-.2v-.8zM189.6 40.6v.7M189.6 45.4v.8M189.6 50.3v.8M189.6 55.1v.9M190.1 52.3h.7l-.5 1.2M190.2 50.4l.5-.1v.8"/>
<path d="M190.2 45.5h.5v.7M190.2 40.6h.5v.7M190.2 55.3l.1-.2 .4 .1v.8M190.2 40.6v.7M190.2 45.4v.8M190.2 50.3v.8M190.2 55.1v.9M190.3 57.7l-.2-.3 .2-.3h.3l.2 .4-.7 .4v.3l.2 .2h.3l.2-.2v-.3l-.2-.2M190.7 47.4a.55 .55 0 0 0-.6 .5v.5l.1 .2h.5l.1-.2v-.3l-.1-.2h-.5l-.1 .2M190.8 42.6h-.6l-.1 .5a.45 .45 0 0 1 .6 0 .45 .45 0 0 1 .1 .6h-.7M191.1 50.3h.5M191.1 45.4h.5"/>
<path d="M191.1 40.6h.5M191.1 55.1h.5M191.3 49.9v1v.2h.3M191.3 45v1.1l.3 .1M191.3 40.1v1l.3 .2M191.3 54.7v1.1l.3 .2M191.3 59.6v1v.2h.3M191.9 49.9v.1M191.9 45v.1M191.9 40.1v.1M191.9 54.7v.2M191.9 59.6v.1"/>
<path d="M191.9 40.6v.7M191.9 45.4v.8M191.9 50.3v.8M191.9 55.1v.9M192.5 50.4l.5-.1v.8M192.5 45.5h.5v.7M192.5 40.6h.5v.7M192.5 55.3l.2-.2 .3 .1v.8M192.5 40.6v.7M192.5 45.4v.8M192.5 50.3v.8M192.5 55.1v.9"/>
<path d="M194.1 51.1l-.5-.1 .1-.7h.4v1.1h-.5M194.1 45.4v1.1l-.1 .1h-.4M194.1 45.5h-.5v.6l.2 .1 .3-.1M194.1 41.2h-.5l.1-.6h.4v1.1h-.5M194.1 55.1v1.1l-.1 .2-.4-.1M194.1 55.2l-.3-.1-.2 .2v.5l.2 .2 .3-.1M194.7 40.1v1.2M194.7 45v1.2M194.7 49.9v1.2M194.7 54.7v1.3M194.7 59.6v1.2M194.7 50.5h.7"/>
<path d="M194.7 45.5h.7M194.7 40.7h.7M194.7 55.3h.7M195.4 40.1v1.2M195.4 45v1.2M195.4 49.9v1.2M195.4 54.7v1.3M195.4 59.6v1.2M196 50.4h.6l-.1 .7-.5-.1zM196 45.5h.6l-.1 .6-.3 .1-.2-.1zM196 40.6h.5l.1 .6h-.6zM196 55.3l.2-.2 .4 .2-.1 .6-.3 .1-.2-.2z"/>
<path d="M197.1 49.9v1l.2 .2M197.1 45v1.1l.2 .1M197.1 40.1v1l.2 .2M197.1 54.7v1.1l.2 .2M197.1 59.6v1l.2 .2M197.7 50.6l.6-.1-.1-.2h-.4l-.1 .2 .1 .6h.4M197.7 45.8l.6-.1-.2-.3-.4 .1v.6l.2 .1 .3-.1M197.7 40.9l.6-.1-.1-.2h-.4l-.1 .1v.4l.2 .2 .3-.1M197.7 55.5h.6l-.2-.4-.4 .2v.5l.2 .2 .3-.1M206.1 56v-1.3l.4 .9 .3-.9v1.3M206.1 52.9h.7M206.1 52.3v1.2"/>
<path d="M206.1 57.1v1.3M206.1 57.7h.7M206.8 52.3v1.2M206.8 57.1v1.3M207.3 52.7l.3-.4v1.2M207.3 57.5h.1l.2-.4v1.3M207.3 53.5h.6M207.3 58.4h.6M207.4 55.3l.2-.2 .3 .1v.7l-.3 .1-.2-.2zM208.4 52.7l.4-.4v1.2M208.4 57.5l.4-.4v1.3M208.4 53.5h.7"/>
<path d="M208.4 58.4h.7M208.5 55.1v.7l.2 .2 .3-.2M209 55.1v.9M209.6 55.3l.2-.2 .4 .2v.7M209.6 52.4l.6-.1 .1 .4-.8 .8h.8M209.6 55.1v.9M209.9 57.1a.68 .68 0 0 1 .4 .7 .68 .68 0 0 1-.4 .6l-.3-.2v-.8zM210.6 55.1h.5M210.7 54.7v1.1l.4 .2M210.7 59.6v1l.1 .2h.3M211.5 54.7v.2M211.5 59.6v.1"/>
<path d="M211.5 55.1v.9M212 55.3l.2-.2 .4 .2v.7M212 55.1v.9M213.7 55.1v1l-.3 .3-.3-.1M213.7 55.2l-.3-.1-.3 .2v.5l.3 .2 .3-.1M214.2 55.3h.8M214.2 54.7v1.3M214.2 59.6v1.2M215 54.7v1.3M215 59.6v1.2M215.6 55.2l.3-.1 .2 .2v.5l-.2 .2-.4-.3zM216.7 54.7v1.2l.1 .1"/>
<path d="M216.7 59.6v1.2h.1M217.2 55.5h.6v-.3l-.5-.1-.1 .2v.5l.1 .2 .5-.1M186.6 65.7v-1.2l.3 .9 .5-.9v1.2M186.6 60.8v-1.2l.3 .8 .5-.8v1.2M186.6 62.1v1.1M186.6 62.7h.7M187.3 62.1v1.1M187.8 62.4l.3-.3v1.1M187.8 63.2h.7M187.9 65.1l.2-.2h.4v.7h-.5zM188 60.1l.5-.1v.8h-.5l-.1-.2zM189 62.2l.1-.1h.4a.86 .86 0 0 1-.1 1.1l-.4-.2z"/>
<path d="M189.1 64.9v.6l.1 .2 .4-.1M189.1 60v.8l.5-.1M189.6 60v.8M189.6 64.9v.8M190.2 65l.1-.1h.4v.8M190.2 60.1l.5-.1v.8M190.2 60v.8M190.2 64.9v.8M190.8 62.6l-.2 .2h-.3l-.2-.2v-.4l.1-.1h.5a.94 .94 0 0 1 0 1.1h-.5M191.1 60h.5M191.1 64.9h.5M191.3 64.5v1l.3 .2"/>
<path d="M191.9 64.5v.1M191.9 60v.8M191.9 64.9v.8M192.5 65l.2-.1h.3v.8M192.5 60.1l.5-.1v.8M192.5 60v.8M192.5 64.9v.8M194.1 64.9v1.1l-.1 .1-.4-.1M194.1 64.9h-.3l-.2 .1v.6h.5M194.1 60.8l-.5-.1 .1-.7h.4v1.1h-.5M194.7 64.5v1.2M194.7 60.2h.7"/>
<path d="M194.7 65h.7M195.4 64.5v1.2M196 65l.2-.1h.3l.1 .7h-.6zM196 60.1h.6l-.1 .7-.5-.1zM197.1 64.5v1l.2 .2M197.7 65.3l.6-.1-.2-.3-.4 .1v.5l.2 .2 .3-.1M197.7 60.4l.6-.1-.1-.3h-.4l-.1 .2 .1 .6h.4M206.1 60.8v-1.2l.4 .8 .3-.8v1.2M206.1 65.7v-1.2l.4 .9 .3-.9v1.2M206.1 62.1v1.1M206.1 62.7h.7M206.8 62.1v1.1"/>
<path d="M207.3 62.4l.3-.3v1.1M207.3 63.2h.6M207.4 60.1l.5-.1v.8l-.5-.1zM207.4 65l.2-.1h.3v.7h-.5zM208.4 62.4l.4-.3v1.1M208.4 63.2h.7M208.5 60l.1 .8 .4-.1M208.5 64.9v.6l.2 .2 .3-.1M209 60v.8M209 64.9v.8M209.6 60.1l.5-.1 .1 .8M209.6 65l.2-.1 .4 .1v.7"/>
<path d="M209.6 62.4l.4-.3v1.1M209.6 60v.8M209.6 64.9v.8M209.6 63.2h.7M210.6 60h.5M210.6 64.9h.5M210.7 64.5v1l.4 .2M211.5 64.5v.1M211.5 60v.8M211.5 64.9v.8M212 60.1l.5-.1 .1 .8M212 65l.2-.1 .4 .1v.7"/>
<path d="M212 60v.8M212 64.9v.8M213.7 60.8l-.6-.1 .1-.7h.5v1l-.3 .2-.3-.1M213.7 64.9v1l-.3 .2-.3-.1M213.7 64.9h-.3l-.3 .1v.6h.6M214.2 64.5v1.2M214.2 60.2h.8M214.2 65h.8M215 64.5v1.2M215.6 60l.5 .1-.1 .7h-.4zM215.6 64.9h.3l.2 .1v.6h-.5zM216.7 64.5v1.1l.1 .1"/>
<path d="M217.2 60.4l.6-.1v-.3h-.5l-.1 .2 .1 .6h.5M217.2 65.3l.6-.1v-.3h-.5l-.1 .1v.5l.1 .2 .5-.1"/>
</g>
</svg>
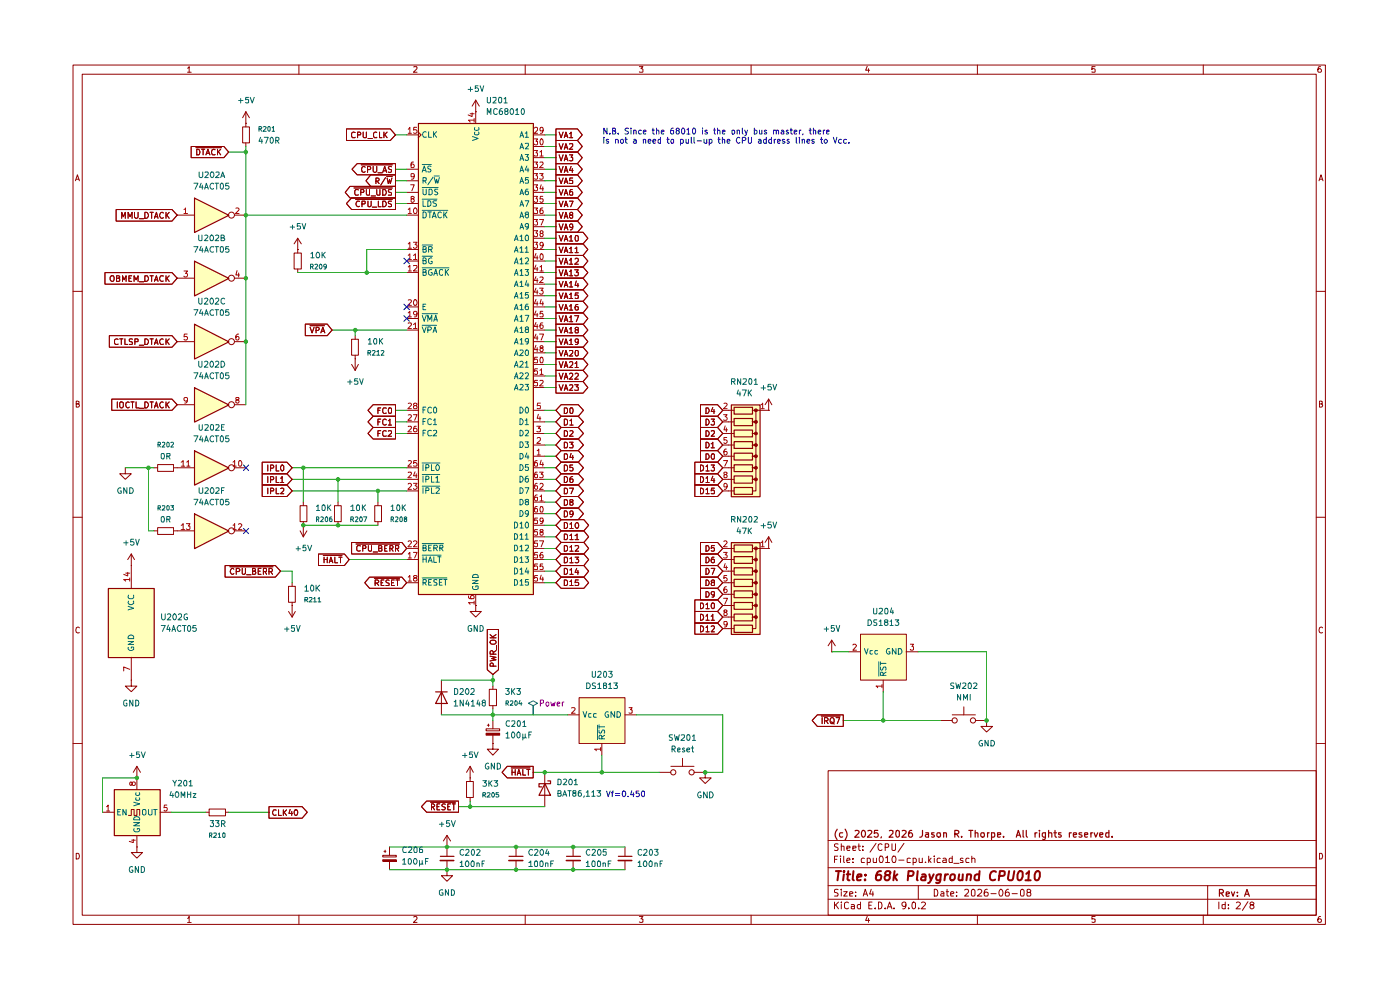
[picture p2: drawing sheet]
<svg xmlns="http://www.w3.org/2000/svg" width="297mm" height="210mm" viewBox="0 0 297 210" stroke-linecap="round" stroke-linejoin="round" font-family="sans-serif">
<g fill="none" stroke="#910000" stroke-width=".21">
<path d="M15.5 13.8h265.7v182.3h-265.7zM17.4 15.7h261.8v178.4h-261.8zM39.8 14.5l.3-.4v1.2M39.8 15.3h.8M63.4 13.8v1.9M87.8 14.2l.6-.1 .1 .4-.8 .8h.8M111.4 13.8v1.9M135.6 14.1h.8l-.4 .5 .4 .1v.5h-.8M159.3 13.8v1.9M184 14.1l-.4 .8h.9M184.2 14.6v.7M207.3 13.8v1.9"/>
<path d="M232.3 14.1h-.7v.6l.2-.1 .5 .1-.1 .6-.6-.1M255.3 13.8v1.9M280.2 14.1l-.5 .1a.94 .94 0 0 0 0 1.1h.5l.1-.1v-.4l-.2-.2h-.3l-.2 .2M16 38.4l.4-1.3 .4 1.3M16.2 38h.6M279.8 38.4l.4-1.3 .5 1.3M279.9 38h.6M15.5 61.8h1.9M279.2 61.8h2M16.2 85.7l.6-.1v-.4l-.6-.1v1.3h.4l.2-.5-.3-.2M279.9 85.7l.6-.1v-.4l-.6-.1v1.3l.6-.1 .1-.4-.3-.2M15.5 109.7h1.9"/>
<path d="M279.2 109.7h2M16.8 133.2l-.2-.2a.65 .65 0 0 0-.5 .6 .65 .65 0 0 0 .5 .7l.2-.1M280.6 133.2l-.3-.2a.65 .65 0 0 0-.5 .6 .65 .65 0 0 0 .5 .7l.3-.1M15.5 157.7h1.9M279.2 157.7h2M175.7 163.5h103.5v30.6h-103.5zM175.7 178.3h103.5M177.8 179.1l-.5-.1-.3 .2v.3l.8 .5-.3 .4-.5-.1M178.5 179.6l.5-.1 .1 .9M178.5 179v1.4M179.7 179.9l.6-.1v-.3h-.6v.2v.6h.6M180.9 179.9l.7-.1-.1-.3h-.6v.8h.6"/>
<path d="M182 179.5h.5M182.2 179v1.2l.3 .2M183 179.5v.2M185.8 178.9l-1.2 1.9M187.1 179.2l-.4-.2a.7 .7 0 0 0-.5 .8 .7 .7 0 0 0 .8 .5h.1M187.8 179.7h.7v-.6l-.7-.1v1.4M189.2 179v1.3l.3 .1h.2l.3-.2v-1.2M191.8 178.9l-1.3 1.9M16.2 181a.66 .66 0 0 1 .6 .4 .66 .66 0 0 1-.2 .8h-.4zM39.8 194.8l.3-.4v1.3M39.8 195.7h.8M63.4 194.1v2"/>
<path d="M87.8 194.6l.4-.2 .3 .4-.8 .9h.8M111.4 194.1v2M135.6 194.4h.8l-.4 .5 .4 .1v.6h-.8M159.3 194.1v2M175.7 190.8h103.5M175.7 187.9h103.5M175.7 184.1h103.5M177 191.3v1.5M177 182.3h.5M177.3 191.9l.6 .9M177.7 181.6h-.7v1.4M177.8 188.7h-.7v.6a.53 .53 0 0 1 .6 .2 .53 .53 0 0 1 0 .6h-.7"/>
<path d="M177.9 191.3l-.9 .9M178.3 181.6v.1M178.3 182v1M178.5 191.3v.2M178.5 188.6v.2M178.5 189.1v1M178.5 191.9v.9M179 189.1h.7l-.7 1h.7M179 181.6v1.2l.2 .2M179.7 182.5l.6-.1-.1-.4-.5 .1v.7v.2h.6M180 191.5l-.4-.2-.4 .4v.9l.4 .2 .4-.2M180.3 189.7l.6-.2-.1-.3h-.5v.9h.5"/>
<path d="M180.6 191.9h.4l.3 .1v.8M180.9 182.9v.1M180.9 182.1v.2M181.3 192.2l-.7 .1v.4h.7M181.5 190v.1M181.5 189.2v.1M182.5 191.9h-.4l-.2 .2v.4l.2 .3 .4-.1M182.5 191.3v1.5M183 180.3v.1M183.1 190.1l.5-1.5 .5 1.5M183.2 189.7h.7M183.4 182.1l-.4-.1-.3 .3 .1 .7h.6"/>
<path d="M184 194.4l-.4 .8h.9M184 182.1l.4-.1 .3 .3-.1 .7h-.6M184 182v1.5M184.2 194.8v.9M184.3 192h.5M184.8 188.6l-.3 1.1h.8M185 191.3h-.7v1.5h.7M185.2 189.1v1M185.2 182l.1 1 .6-.1M185.7 192.6v.2M185.9 182v1M186.3 191.3l.7 .2v1.1l-.3 .2h-.4z"/>
<path d="M186.7 181.6a.73 .73 0 0 1 .7 .5 .73 .73 0 0 1-.3 .9h-.4l-.2-.5zM187.8 192.6v.2M187.9 181.9l.4-.3v1.4M187.9 183h.8M188.2 192.8l.5-1.5 .5 1.5M188.4 192.4h.7M189.4 181.7l.5-.1 .2 .5-.2 .9h-.4l-.2-.3-.1-.6zM189.7 192.6v.2M190.7 182.5h1.1M192.2 191.9l-.1 .3-.4 .1-.4-.4v-.3a.46 .46 0 0 1 .5-.3 .46 .46 0 0 1 .4 .3l-.2 1-.5 .2M192.8 192.6v.2M193.1 182.1l-.4-.1-.3 .2v.7l.7 .1"/>
<path d="M193.5 191.5l.4-.2 .3 .3v.9l-.3 .3a.82 .82 0 0 1-.4-1.3zM193.7 182.1l.4-.1 .3 .3-.2 .7h-.5M193.7 182v1.5M194.8 187.9v2.9M194.9 192.6v.2M195 182l.1 1 .6-.1M195.5 191.5l.2-.2h.3l.3 .5-.9 1h.9M195.7 182v1M196.3 182.9v.1M197 181.6v1.4M197.1 182.5l.4 .5M197.5 182l-.5 .6"/>
<path d="M198.2 188.6a.8 .8 0 0 1 .8 .6 .8 .8 0 0 1-.3 .9h-.5zM198.2 181.6v.1M198.2 182v1M199.5 182.1l-.5-.1-.2 .3 .1 .7h.6M199.6 189.2l.4-.1 .2 .2v.8h-.6v-.4l.6-.2M200.1 182.1l.4-.1 .2 .3v.7h-.6v-.5l.6-.1M200.7 189.1h.5M200.9 188.6v1.3l.1 .2h.2M201.7 189.7l.7-.2-.2-.4h-.4l-.1 .2v.6l.1 .2h.5M202 181.6v1.4h-.6v-.9h.6M202.4 183.1h1.1M202.9 190v.1"/>
<path d="M202.9 189.2v.1M204.3 182.1a.36 .36 0 0 0-.6 .2l.6 .3v.4h-.6M204.6 188.8l.6-.2 .3 .4-.1 .3-.8 .8h.9M205.6 182.1l-.5-.1-.2 .3 .1 .7h.6M206.2 188.8l.3-.2 .3 .4v.8l-.1 .3h-.5l-.1-.3zM206.2 182.2v-.1a.36 .36 0 0 1 .6 .2v.7M206.2 181.6v1.4M207.3 194.1v2M207.4 188.8l.2-.2h.3l.4 .5-.1 .2-.9 .8h1M209.5 188.6l-.5 .2-.2 1 .2 .3 .5-.1v-.7l-.5-.1-.2 .3M210.2 189.6h1.1M212.3 188.6a.87 .87 0 0 1 .2 1.5h-.3l-.3-.5 .1-.6z"/>
<path d="M213.9 188.6h-.2a1.04 1.04 0 0 0-.3 1.5h.5l.2-.6-.2-.3-.5 .1-.1 .2M214.7 189.6h1.1M216.6 188.8l.3-.2 .4 .4v.8l-.2 .3h-.4l-.2-.3zM218.1 189.3l-.3-.3 .1-.3h.6l.2 .3-.1 .1-.7 .2-.1 .3 .1 .5h.6l.2-.5-.3-.3M232.3 194.4h-.7v.6h.7v.6h-.7M255.3 194.1v2M256.2 187.9v6.2M258.6 191.3v1.5M259.9 191.9h-.7v.7l.3 .2 .4-.1M259.9 191.3v1.5M260.6 192.6v.2M260.6 191.9v.1"/>
<path d="M262.3 191.5l.2-.2h.3l.3 .5-.9 1h.9M264.7 191.3l-1.1 1.8M265.4 191.9l-.2-.2 .2-.4 .6 .3-.1 .3h-.5l-.1 .2-.1 .4 .2 .3a.45 .45 0 0 0 .5-.2 .45 .45 0 0 0 0-.5l-.2-.2M279.9 181a.66 .66 0 0 1 .7 .4 .66 .66 0 0 1-.3 .8h-.4zM280.2 194.4a.72 .72 0 0 0-.6 .5 .72 .72 0 0 0 .2 .8l.4-.1a.42 .42 0 0 0 0-.6 .42 .42 0 0 0-.5 0l-.1 .2"/>
</g>
<g fill="none" stroke="#910000" stroke-width=".25">
<path d="M177.6 175.9a1.75 1.75 0 0 0 0 2.2M178.8 176.7h-.5l-.2 .2v.4l.2 .3 .5-.1M179.3 175.9a1.64 1.64 0 0 1 0 2.2M181.4 176.2h.8v.4l-.9 1h.9M182.9 176.2l.2-.1a.73 .73 0 0 1 .6 .8 .73 .73 0 0 1-.6 .7l-.4-.6zM184.1 176.2l.6-.1 .3 .5-1 1h1M186.2 176.1h-.7v.7l.6-.1 .2 .3v.3l-.2 .3-.6-.2M187 177.5l-.1 .3M188.7 176.2h.7v.5l-.8 .9h.8M190.1 176.2l.4-.1 .3 .3v.9l-.3 .3a.87 .87 0 0 1-.4-1.4zM191.4 176.2h.7l.1 .4-.9 1h.9M193.4 176.1a.57 .57 0 0 0-.7 .6v.6l.3 .3h.3l.3-.3v-.3l-.3-.3h-.3l-.3 .3"/>
<path d="M195.7 176.1v1.1l-.2 .3-.4 .1M196.4 176.7h.6v.9M197 177h-.4l-.3 .2 .3 .4 .4-.1M198.2 176.7h-.5v.3l.5 .3-.2 .3-.3-.1M198.8 176.7h.6v.8a.45 .45 0 0 1-.6-.2zM200.2 176.7h.5l.1 .9M200.2 176.7v.9M202.6 176.9l.6-.1 .2-.1-.1-.5-.7-.1v1.5M202.9 176.9l.5 .7M204 177.4v.2M205.5 176.1h.9M205.9 176.1v1.5"/>
<path d="M206.9 176.7h.5l.1 .9M206.9 176.1v1.5M208.1 176.7h.6v.8a.45 .45 0 0 1-.6-.2zM209.5 176.7v.9M209.8 176.7h-.2l-.1 .2M210.4 177.5h.5v-.8h-.5v1.4M211.6 177.1l.7-.1-.1-.3h-.6v.8h.6M212.9 177.4v.2M215.6 177.6l.4-1.5 .5 1.5M215.7 177.2h.7M217 176.1v1.4l.2 .1M217.7 176.1v1.2l.3 .3"/>
<path d="M219.6 176.7v.9M220 176.7h-.3l-.1 .2M220.5 176.1v.1M220.5 176.7v.9M221.8 177.5l-.4 .1-.3-.3 .2-.6h.5v1.1l-.3 .3-.3-.1M222.5 176.7h.6v.9M222.5 176.1v1.5M223.6 176.7h.6M223.8 176.1v1.2l.4 .3M225.1 176.7h-.5v.3l.6 .3-.3 .3-.3-.1M226.9 176.7v.9M227.3 176.7h-.3l-.1 .2"/>
<path d="M227.7 177.1l.7-.1-.1-.3h-.5l-.1 .1 .1 .7h.5M229.5 176.7h-.5l-.1 .1 .6 .4v.3h-.6M230.1 177.1l.7-.1-.1-.3h-.5l-.1 .1 .1 .7h.5M231.4 176.7v.9M231.8 176.7h-.3l-.1 .2M232.1 176.7l.3 .9 .5-.9M233.3 177.1l.7-.1-.1-.3h-.5l-.1 .1 .1 .7h.5M235.2 176.7h-.5l-.1 .2 .1 .6h.5M235.2 176.1v1.5M235.9 177.4v.2M258.7 189.4h.8v-.5l-.2-.2h-.6v1.4M259 189.4l.5 .7"/>
<path d="M260.1 189.7l.7-.2-.1-.2h-.6v.7h.6M261.2 189.2l.4 .9 .3-.9M262.5 190v.1M262.5 189.3v.1M264 190.1l.5-1.4 .5 1.4M264.2 189.7h.7"/>
</g>
<g fill="none" stroke="#910000" stroke-width=".42">
<path d="M177.3 184.8h1.1M177.9 184.8l-.2 1.9M179 185.5l-.1 1.2M179.1 184.8l-.2 .1 .1 .1 .1-.2-.1 .2M179.6 185.5h.8M180 184.8l-.2 1.7 .4 .2M181.1 184.8l-.2 1.7 .2 .2M181.8 186.1l.9-.2v-.4h-.5l-.3 .2-.1 .9h.8M183.5 186.6v.1M183.6 185.5v.2M186.9 184.8a1.2 1.2 0 0 0-.9 1.8l.5 .1 .3-.1 .1-.9a.63 .63 0 0 0-1 .2M188.1 185.6l-.4-.4 .3-.3 .6-.1 .2 .2 .1 .1-.2 .4-.8 .2a.61 .61 0 0 0-.1 .9 .61 .61 0 0 0 .9-.1 .61 .61 0 0 0-.2-.9"/>
<path d="M189.8 184.8l-.3 1.9M189.8 186l.5 .7M190.4 185.5l-.8 .6M192.7 185.8l.9-.1 .2-.6v-.1l-.3-.2h-.8l-.1 1.9M194.7 184.8l-.2 1.7 .2 .2M195.6 185.5h.7v1.2M196.4 185.9l-.9 .2-.1 .4 .2 .2 .7-.1M197.1 185.5l.4 1.2M198.1 185.5l-.9 1.7-.3 .1M199.6 185.5l-.2 1.5a.53 .53 0 0 1-.8 .2M199.6 185.5a.65 .65 0 0 0-.9 .3v.8a.64 .64 0 0 0 .8 0M200.5 185.5l-.1 1.2"/>
<path d="M201.1 185.5h-.4l-.2 .3M201.7 185.6l.3-.1 .6 .1v.7l-.5 .4a.46 .46 0 0 1-.6-.4zM203.5 185.5l-.2 1a.49 .49 0 0 0 .9 .1M204.3 185.5l-.1 1.2M205.2 185.6l.2-.1h.5v1.2M205.2 185.5l-.2 1.2M207.7 185.5a.65 .65 0 0 0-.9 .3v.8a.64 .64 0 0 0 .8 0M207.8 184.8l-.2 1.9M211.3 185l-.1-.1a.85 .85 0 0 0-1.2 .7v.6a.66 .66 0 0 0 1.1 .4M212 185.8l1-.1 .1-.2v-.5l-.2-.2h-.8l-.2 1.9M214.1 184.8l-.3 1.5 .4 .4 .6-.1 .4-1.8M216.1 185l.3-.2 .5 .2a1.72 1.72 0 0 1-.2 1.6l-.3 .1-.4-.1a1.4 1.4 0 0 1 .1-1.6z"/>
<path d="M217.5 186.7h1.1M217.7 185.4l.6-.6-.2 1.9M219.7 185l.4-.2 .4 .2a1.65 1.65 0 0 1-.2 1.6h-.6a1.4 1.4 0 0 1 0-1.6z"/>
</g>
<g fill="#ffb">
<path d="M41.2 95.6l7.3 3.6-7.3 3.7z"/>
<path d="M41.2 109l7.3 3.6-7.3 3.7z"/>
<path d="M22.9 124.8h9.8v14.6h-9.8z"/>
<path d="M24.2 167.5h9.7v9.7h-9.7z"/>
<path d="M122.8 148h9.8v9.7h-9.8z"/>
<path d="M182.5 134.5h9.8v9.8h-9.8z"/>
<path d="M88.7 26.2h24.4v99.9h-24.4z"/>
<path d="M41.2 55.4l7.3 3.6-7.3 3.7z"/>
<path d="M41.2 42l7.3 3.6-7.3 3.7z"/>
<path d="M41.2 68.7l7.3 3.8-7.3 3.6z"/>
<path d="M41.2 82.2l7.3 3.6-7.3 3.7z"/>
<path d="M155.1 85.8h6.1v19.5h-6.1z"/>
<path d="M155.1 115.1h6.1v19.4h-6.1z"/>
</g>
<g fill="none" stroke="#910000" stroke-width=".21">
<path d="M40.6 31.1h6.9l1 1.2-1 1.1h-6.9zM41.6 31.3h5.4M41.7 31.7a.66 .66 0 0 1 .7 .4 .66 .66 0 0 1-.2 .7h-.5zM42.8 31.7h.6M43.1 31.7v1.1M43.7 32.8l.4-1.1 .4 1.1M43.9 32.5h.5M45.6 31.7h-.2a.67 .67 0 0 0-.5 .5 .67 .67 0 0 0 .2 .6h.5M46.1 31.7v1.1M46.3 32.2l.5 .6M46.8 31.7l-.7 .6M51.5 26.9h1.4v3.4h-1.4z"/>
<path d="M52.2 26.2h.1M52.2 23.7l-.7 1.3M52.2 23.7l.7 1.3M52.2 23.7v3.2M52.2 30.3v.8M73.5 27.3h9.3l1.1 1.3-1.1 1.2h-9.3zM74.2 39.5h9.7v2.5h-9.7l-1-1.2zM75.1 39.9h8.1M75.4 28.1h-.1a.45 .45 0 0 0-.7 .2v.7l.2 .2 .6-.1M75.8 34.7h8.1v2.4h-8.1l-1.1-1.2zM75.9 28.6h.6v-.5l-.6-.1v1.2M76.6 35h6.6"/>
<path d="M77 28v1l.2 .2 .5-.1v-1.1M77.5 35.5l-.3-.2a.65 .65 0 0 0-.5 .6 .65 .65 0 0 0 .5 .7l.3-.2M78 36l.6-.1v-.5l-.6-.1v1.3M78.1 29.4h.9M78.7 37.1h5.2v2.4h-5.2l-1.1-1.1zM79.2 35.3v1l.2 .3h.3l.2-.3v-1M79.8 38.4h.4l.2-.2-.1-.4h-.5v1.1M79.9 28.1a.45 .45 0 0 0-.7 .2v.7l.2 .2 .5-.1M80 38.4l.4 .5M80.2 36.7h.9M80.5 28v1.2h.5M81.2 36.6l.4-1.3 .4 1.3"/>
<path d="M81.4 36.2h.6M81.4 28v1.2M81.6 28.5l.5 .7M81.8 37.7l-1 1.6M82 37.4h1.2M82.1 37.8l.3 1.1 .2-.8 .2 .8 .3-1.1M82.1 28l-.7 .7M83.1 35.4l-.5-.1-.2 .3 .1 .2 .6 .3v.3l-.3 .2-.4-.1M86.3 28.6h2.4M86.3 35.9h2.4M86.3 38.4h2.4M88.7 28l.6 .6-.6 .6"/>
<path d="M100.9 23.7h.1M100.9 21.2v5M100.9 21.2l-.7 1.3M100.9 21.2l.8 1.3M113.1 28.6h2.5M113.1 35.9h2.5M113.1 38.4h2.5M113.1 31.1h2.5M113.1 33.4h2.5M117.9 37.1h4.6l1 1.3-1 1.1h-4.6zM117.9 39.5h4.6l1 1.3-1 1.2h-4.6zM117.9 34.7h4.6l1 1.2-1 1.2h-4.6z"/>
<path d="M117.9 27.3h4.6l1 1.3-1 1.2h-4.6zM117.9 29.8h4.6l1 1.3-1 1.2h-4.6zM117.9 32.3h4.6l1 1.1-1 1.3h-4.6zM118.6 37.8l.4 1.1 .5-1.1M118.6 35.3l.4 1.3 .5-1.3M118.6 28l.4 1.2 .5-1.2M118.6 30.5l.4 1.2 .5-1.2M118.6 32.8l.4 1.3 .5-1.3M119.7 38.9l.4-1.1 .4 1.1M119.7 36.6l.4-1.3 .4 1.3M119.7 29.2l.4-1.2 .4 1.2M119.7 31.7l.4-1.2 .4 1.2"/>
<path d="M119.7 34.1l.4-1.3 .4 1.3M119.8 31.3h.6M119.8 36.2h.6M119.8 38.6h.6M119.8 28.9h.6M119.8 33.8h.6M120.8 28.4l.4-.4v1.2M120.8 30.6h.7v.4l-.7 .7h.7M120.8 32.8h.7l-.3 .6h.3v.6h-.7M120.8 29.2h.7M121.2 35.3l-.4 .8h.8M121.4 35.7v.9"/>
<path d="M121.5 37.8h-.6l-.1 .6 .6-.1 .1 .6h-.7M22.3 57.8h14.2l1.1 1.2-1.1 1.3h-14.2zM24.6 44.4h11.9l1.1 1.2-1.1 1.3h-11.9zM24.7 59h.5l.2-.3-.2-.2h-.5v1.2h.5l.2-.1v-.4l-.3-.2M25.8 46.3v-1.3l.4 1 .4-1v1.3M26 59.7v-1.2l.3 .8 .5-.8v1.2M27.2 46.3v-1.3l.4 1 .4-1v1.3M27.3 59h.5M27.9 58.5h-.6v1.2h.6M28.4 59.7v-1.2l.5 .8 .4-.8v1.2M28.5 45v1.1l.3 .2h.2l.3-.2v-1.1M29.5 46.4h1"/>
<path d="M29.5 59.8h1M30.7 45a.65 .65 0 0 1 .8 .7 .65 .65 0 0 1-.8 .6zM30.7 58.5h.5a.66 .66 0 0 1 .3 .8 .66 .66 0 0 1-.8 .4zM31.8 45h.7M31.8 58.5h.7M32.2 45v1.3M32.2 58.5v1.2M32.8 46.3l.4-1.3 .3 1.3M32.8 59.7l.4-1.2 .3 1.2M32.8 46h.6M32.8 59.3h.6M34.6 45.2l-.1-.2a.6 .6 0 0 0-.6 .7 .6 .6 0 0 0 .7 .5v-.1"/>
<path d="M34.6 58.6l-.5-.1a.61 .61 0 0 0-.2 .8 .61 .61 0 0 0 .7 .3M35.2 45v1.3M35.2 58.5v1.2M35.4 45.6l.5 .7M35.4 59l.5 .7M35.9 45l-.7 .8M35.9 58.5l-.7 .7M37.6 45.6h3.6M37.6 59h3.6M49.8 45.6h2.4M49.8 59h2.4M62.4 53.7h1.5v3.4h-1.5z"/>
<path d="M63.2 52.9h.1M63.2 50.5l-.8 1.2M63.2 50.5l.7 1.2M63.2 50.5v3.2M63.2 57.1v.7M74.6 42h9.3v2.4h-9.3l-1.1-1.2zM75.4 42.3h7.8M76 40.3l-.6-.1-.1 .3v.6l.1 .3 .6-.1M76.3 42.8l-.5-.1a.61 .61 0 0 0-.3 .8 .61 .61 0 0 0 .8 .3M76.5 40.8h.6v-.6h-.6v1.2M76.8 43.3l.7-.1v-.4l-.7-.1v1.2M77.7 40.2v.9l.2 .3 .5-.1v-1.1"/>
<path d="M78.1 42.7v1.1l.1 .1h.3l.2-.3v-.9M78.7 41.6h1M79 43.9h.9M79.9 40.2v.9l.2 .3 .5-.1v-1.1M80.3 42.7v1.2h.6M81.2 42.7h.5a.66 .66 0 0 1 .2 .8 .66 .66 0 0 1-.7 .4zM81.2 40.2h.5l.2 .3 .1 .4-.3 .5h-.5zM83.1 42.7h-.6l-.1 .1 .1 .4 .6 .1v.5h-.7M83.1 40.2h-.6a.47 .47 0 0 0 0 .5 .47 .47 0 0 0 .5 .2v.5h-.6M86.3 40.8h2.4M86.3 43.2h2.4M86.3 45.6h2.4"/>
<path d="M86.3 52.9h2.4M86.3 55.4h2.4M86.3 57.8h2.4M113.1 40.8h2.5M113.1 43.2h2.5M113.1 45.6h2.5M113.1 52.9h2.5M113.1 55.4h2.5M113.1 57.8h2.5M113.1 48.1h2.5M113.1 50.5h2.5M117.9 42h4.6l1 1.2-1 1.2h-4.6z"/>
<path d="M117.9 59h5.8l1 1.3-1 1.2h-5.8zM117.9 56.6h5.8l1 1.2-1 1.2h-5.8zM117.9 54.2h5.8l1 1.2-1 1.2h-5.8zM117.9 46.9h4.6l1 1.2-1 1.2h-4.6zM117.9 49.3h5.8l1 1.2-1 1.2h-5.8zM117.9 44.4h4.6l1 1.2-1 1.3h-4.6zM117.9 51.7h5.8l1 1.2-1 1.3h-5.8zM118.6 40.2l.4 1.2 .5-1.2M118.6 42.7l.4 1.2 .5-1.2M118.6 59.7l.4 1.2 .5-1.2M118.6 57.2l.4 1.3 .5-1.3M118.6 54.8l.4 1.2 .5-1.2"/>
<path d="M118.6 47.5l.4 1.3 .5-1.3M118.6 50l.4 1.1 .5-1.1M118.6 45l.4 1.3 .5-1.3M118.6 52.4l.4 1.2 .5-1.2M119.7 41.4l.4-1.2 .4 1.2M119.7 43.9l.4-1.2 .4 1.2M119.7 58.5l.4-1.3 .4 1.3M119.7 56l.4-1.2 .4 1.2M119.7 48.8l.4-1.3 .4 1.3M119.7 51.1l.4-1.1 .4 1.1M119.7 46.3l.4-1.3 .4 1.3M119.7 53.6l.4-1.2 .4 1.2"/>
<path d="M119.8 46h.6M119.8 41.1h.6M119.8 43.5h.6M119.8 58.2h.6M119.8 55.7h.6M119.8 48.3h.6M119.8 50.8h.6M119.8 53.3h.6M120.8 42.7h.8l-.5 1.2M120.8 57.6h.2l.2-.4v1.3M120.8 55.2l.4-.4v1.2M120.8 50.3l.4-.3v1.1"/>
<path d="M120.8 52.7l.4-.3v1.2M120.8 58.5h.7M120.8 56h.7M120.8 51.1h.7M120.8 53.6h.7M121.1 45.6l-.3-.3 .3-.3h.2l.2 .5-.7 .3v.3l.3 .2 .4-.2v-.4l-.2-.1M121.4 40.2l-.4 .1-.2 .8 .2 .3 .5-.1v-.5l-.2-.2h-.2l-.3 .3M121.5 48v.2l-.4 .1-.3-.3v-.3l.3-.2 .4 .2v.7l-.2 .3-.3 .1M121.9 57.2h.8l-.4 .5 .4 .1v.5l-.3 .2h-.3l-.2-.2M122 54.9l.2-.1 .4 .1 .1 .5-.8 .6h.8M122 52.7l.3-.3v1.2M122 53.6h.7"/>
<path d="M122.1 50h.3l.3 .2v.8l-.2 .1h-.4zM122.3 59.6l-.3 .9h.8M23.2 71.2h13.3l1.1 1.3-1.1 1.2h-13.3zM25.1 72h-.1a.46 .46 0 0 0-.7 .1v.7l.2 .3 .6-.1M25.4 71.9h.7M25.7 71.9v1.2M26.5 71.9v1.2h.6M28.1 72h-.7v.3l.7 .4-.1 .4h-.6M28.6 72.5h.6l.1-.5-.7-.1v1.2M29.5 73.2h1M30.7 71.9a.66 .66 0 0 1 .8 .4 .66 .66 0 0 1-.3 .8h-.5zM31.8 71.9h.7"/>
<path d="M32.2 71.9v1.2M32.8 73.1l.4-1.2 .3 1.2M32.8 72.7h.6M34.6 72a.61 .61 0 0 0-.7 .3 .61 .61 0 0 0 .2 .8l.5-.1M35.2 71.9v1.2M35.4 72.4l.5 .7M35.9 71.9l-.7 .7M37.6 72.5h3.6M49.8 72.5h2.4M64.8 68.7h4.6l1 1.3-1 1.2h-4.6zM65.8 69.4l.4 1.2 .4-1.2M65.8 69.1h3"/>
<path d="M67.1 70.1h.4l.2-.3-.1-.3-.5-.1v1.2M68.1 70.6l.4-1.2 .4 1.2M68.2 70.3h.5M74.6 72h1.4v3.4h-1.4zM74.6 77.3l.8 1.3M75.4 76.1h.1M75.4 71.2v.8M75.4 75.4v3.2M76 77.3l-.6 1.3M86.3 65.1h2.4M86.3 67.6h2.4M86.3 70h2.4"/>
<path d="M113.1 65.1h2.5M113.1 67.6h2.5M113.1 70h2.5M113.1 60.3h2.5M113.1 62.7h2.5M113.1 72.5h2.5M113.1 74.8h2.5M113.1 77.3h2.5M113.1 79.8h2.5M117.9 73.7h5.8l1 1.1-1 1.3h-5.8zM117.9 66.4h5.8l1 1.2-1 1.2h-5.8zM117.9 68.7h5.8l1 1.3-1 1.2h-5.8z"/>
<path d="M117.9 71.2h5.8l1 1.3-1 1.2h-5.8zM117.9 63.9h5.8l1 1.2-1 1.3h-5.8zM117.9 61.5h5.8l1 1.2-1 1.2h-5.8zM117.9 76.1h5.8l1 1.2-1 1.3h-5.8zM117.9 78.6h5.8l1 1.2-1 1.1h-5.8zM118.6 74.3l.4 1.2 .5-1.2M118.6 67l.4 1.2 .5-1.2M118.6 69.4l.4 1.2 .5-1.2M118.6 71.9l.4 1.2 .5-1.2M118.6 64.6l.4 1.2 .5-1.2M118.6 62.1l.4 1.2 .5-1.2M118.6 76.7l.4 1.3 .5-1.3"/>
<path d="M118.6 79.2l.4 1.2 .5-1.2M119.7 75.5l.4-1.2 .4 1.2M119.7 68.2l.4-1.2 .4 1.2M119.7 70.6l.4-1.2 .4 1.2M119.7 73.1l.4-1.2 .4 1.2M119.7 65.8l.4-1.2 .4 1.2M119.7 60.9l.4-1.2 .4 1.2M119.7 63.3l.4-1.2 .4 1.2M119.7 78l.4-1.3 .4 1.3M119.8 72.7h.6M119.8 70.3h.6M119.8 75.2h.6"/>
<path d="M119.8 67.9h.6M119.8 65.4h.6M119.8 60.5h.6M119.8 63h.6M119.8 77.6h.6M120.8 74.4h.7v.4l-.7 .7h.7M120.8 67.3h.2l.2-.3v1.2M120.8 69.8h.2l.2-.4v1.2M120.8 72.2l.4-.3v1.2M120.8 64.9l.4-.3v1.2M120.8 60l.4-.3v1.2M120.8 62.5l.4-.4v1.2"/>
<path d="M120.8 76.9l.2-.2h.3l.2 .2v.4l-.7 .7h.7M120.8 79.3l.2-.1h.3l.2 .1v.4l-.7 .7h.7M120.8 68.2h.7M120.8 70.6h.7M120.8 73.1h.7M120.8 65.8h.7M120.8 60.9h.7M120.8 63.3h.7M121.9 67h.9l-.5 1.2M122 77.1l.3-.4v1.3M122 79.3l.4-.1 .3 .1v.4l-.8 .7h.8M122 78h.7"/>
<path d="M122.1 74.4l.4-.1 .2 .2v.8a.35 .35 0 0 1-.4 .2 .35 .35 0 0 1-.3-.4zM122.3 69.9h-.2l-.1-.2a.42 .42 0 0 1 .7-.2l-.1 .4-.5 .1v.6l.6-.1v-.4l-.3-.2M122.6 64.6l-.4 .1-.2 .8a.42 .42 0 0 0 .7 .2l-.1-.6a.36 .36 0 0 0-.6 .2M122.6 60.1v.8M122.7 72.4l-.4 .2h-.2l-.1-.5a.42 .42 0 0 1 .7-.1v.8l-.3 .3h-.3M122.7 62.1h-.6l-.1 .6 .2-.1 .4 .1 .1 .5h-.7M23.7 84.7h12.8l1.1 1.1-1.1 1.2h-12.8zM24.9 85.3v1.2M25.4 85.4l.3-.1 .5 .1v.9l-.3 .2h-.2l-.3-.2zM26.6 99.2v1.3h1.3l-1.3 1.2-1.2-1.2h1.2M26.6 99.2h.1M27.4 85.3h-.2a.6 .6 0 0 0-.5 .6 .6 .6 0 0 0 .6 .5h.1"/>
<path d="M27.8 85.3h.6M28.1 85.3v1.2M28.9 85.3v1.2h.6M29.5 86.6h1M30.7 85.3a.65 .65 0 0 1 .8 .6 .65 .65 0 0 1-.8 .6zM31.8 85.3h.7M32.2 85.3v1.2M32.7 99.2h.7M32.8 86.5l.4-1.2 .3 1.2M32.8 86.1h.6M33.4 98.5h3.4v1.5h-3.4zM34.6 85.3h-.1a.64 .64 0 0 0-.6 .6 .64 .64 0 0 0 .6 .6l.1-.1"/>
<path d="M35.2 85.3v1.2M35.4 85.8l.5 .7M35.9 85.3l-.7 .6M36.8 99.2h4.4M37.6 85.8h3.6M49.8 99.2h2.4M49.8 85.8h2.4M55.6 98h5.3l1.1 1.2-1.1 1.3h-5.3zM56.8 98.6v1.3M57.4 99.3l.6-.1v-.5l-.6-.1v1.3M58.6 98.6v1.3h.6M59.7 98.7l.2-.1 .3 .3v.7l-.3 .3a.71 .71 0 0 1-.2-1.2z"/>
<path d="M79.2 88.3h4.7v2.4h-4.7l-1.1-1.2zM79.2 90.7h4.7v2.4h-4.7l-1.1-1.2zM79.2 85.8h4.7v2.5h-4.7l-1.1-1.3zM80.2 89.5h.4M80.2 91.9h.4M80.2 87h.4M80.8 88.9h-.6v1.3M80.8 91.4h-.6v1.1M80.8 86.5h-.6v1.2M82 89.1l-.5-.2-.3 .3v.6l.2 .3 .3 .1 .3-.2M82 91.4h-.1a.45 .45 0 0 0-.7 .2v.7l.2 .2h.6M82 86.6l-.6-.1-.2 .3 .1 .7 .2 .2 .5-.1"/>
<path d="M82.4 89.2l.3-.3v1.3M82.4 91.4h.7v.5l-.8 .6h.8M82.4 90.2h.7M82.5 86.6l.4-.1 .2 .2v.8l-.3 .2-.3-.1zM86.3 99.2h2.4M86.3 89.5h2.4M86.3 91.9h2.4M86.3 87h2.4M113.1 99.2h2.5M113.1 89.5h2.5M113.1 91.9h2.5M113.1 87h2.5"/>
<path d="M113.1 82.2h2.5M113.1 94.4h2.5M113.1 96.8h2.5M117.9 80.9h5.8l1 1.3-1 1.2h-5.8zM118.6 81.6l.4 1.2 .5-1.2M119 98h3.7l1.1 1.2-1.1 1.3h-3.7l-1.1-1.3zM119 95.6h3.7l1.1 1.2-1.1 1.2h-3.7l-1.1-1.2zM119 93.1h3.7l1.1 1.3-1.1 1.2h-3.7l-1.1-1.2zM119 90.7h3.7l1.1 1.2-1.1 1.2h-3.7l-1.1-1.2zM119 88.3h3.7l1.1 1.2-1.1 1.2h-3.7l-1.1-1.2zM119 85.8h3.7l1.1 1.2-1.1 1.3h-3.7l-1.1-1.3zM119.7 98.6h.4l.3 .4v.6l-.3 .3h-.4z"/>
<path d="M119.7 96.3h.5l.2 .2v.7l-.3 .2h-.4zM119.7 93.8h.4l.3 .3v.6l-.2 .3h-.5zM119.7 91.4h.4l.3 .2v.7l-.2 .2h-.5zM119.7 88.9l.5 .1 .2 .2v.6l-.3 .4h-.4zM119.7 86.5h.5l.2 .3v.6l-.3 .3h-.4zM119.7 82.8l.4-1.2 .4 1.2M119.7 80.4l.4-1.2 .4 1.2M119.8 82.5h.6M119.8 80h.6M120.8 93.8h.8l-.4 .4 .4 .3-.1 .5-.7-.1M120.8 81.7h.7v.4l-.7 .7h.7M120.9 91.4h.4l.3 .3-.8 .8h.8"/>
<path d="M120.9 89.2l.3-.3v1.3M120.9 86.7l.2-.2h.3a.91 .91 0 0 1-.1 1.2l-.4-.2zM120.9 90.2h.7M121.2 96.2l-.3 .8h.8M121.5 98.6h-.6v.6h.6v.6l-.4 .1-.2-.2M121.5 96.6v.8M121.9 81.6h.8l-.4 .4 .4 .2v.5h-.8M147.4 98h4.8l1.1 1.2-1.1 1.3h-4.8zM148.6 98.6a.64 .64 0 0 1 .7 .7 .64 .64 0 0 1-.7 .6zM148.6 95.6h3.6l1.1 1.2-1.1 1.2h-3.6zM148.6 93.1h3.6l1.1 1.3-1.1 1.2h-3.6zM148.6 90.7h3.6l1.1 1.2-1.1 1.2h-3.6z"/>
<path d="M148.6 85.8h3.6l1.1 1.2-1.1 1.3h-3.6zM148.6 88.3h3.6l1.1 1.2-1.1 1.2h-3.6zM149.8 99l.3-.4v1.3M149.8 96.3h.4a.66 .66 0 0 1 .2 .7 .66 .66 0 0 1-.6 .4zM149.8 93.8a.66 .66 0 0 1 .6 .4 .66 .66 0 0 1-.2 .8h-.4zM149.8 91.4a.66 .66 0 0 1 .6 .4 .66 .66 0 0 1-.2 .7h-.4zM149.8 86.5h.4a.66 .66 0 0 1 .2 .8 .66 .66 0 0 1-.6 .4zM149.8 88.9a.64 .64 0 0 1 .7 .6 .64 .64 0 0 1-.7 .7zM149.8 99.9h.6M150.9 98.6h.7l-.4 .5 .4 .1v.5l-.2 .2h-.4l-.1-.2M150.9 94.1l.3-.3v1.2M150.9 91.4h.7v.5l-.7 .6h.7"/>
<path d="M150.9 88.9h.7l-.4 .5 .4 .1v.5l-.2 .2h-.4l-.1-.2M150.9 95h.7M151 96.3h.4l.2 .1v.8l-.4 .2a.84 .84 0 0 1-.2-1.1zM151.2 86.4l-.3 .9h.7M151.5 86.9v.8M163.1 87h.1M163.1 84.7l-.8 1.1M163.1 84.7l.6 1.1M163.1 84.7v2.3M27.9 120h.1M27.9 117.5l-.8 1.2M27.9 117.5l.6 1.2"/>
<path d="M27.9 117.5v7.3M32.7 112.6h.7M33.4 111.9h3.4v1.5h-3.4zM36.8 112.6h4.4M47.7 120h10.7l1.1 1.2-1.1 1.2h-10.7zM49.8 112.6h2.4M55.6 100.5h5.3l1.1 1.2-1.1 1.2h-5.3zM55.6 102.9h5.3l1.1 1.2-1.1 1.2h-5.3zM56.8 101.1v1.3M56.8 103.5v1.2M57.4 101.8l.6-.1v-.5l-.6-.1v1.3M57.4 104.1h.6v-.5l-.6-.1v1.2"/>
<path d="M58.6 101.1v1.3h.6M58.6 103.5v1.2h.6M59.5 101.4h.2l.2-.3v1.3M59.5 103.6h.7v.5l-.7 .6h.7M59.5 102.4h.7M63.7 107.3h1.4v3.4h-1.4zM63.7 112.6l.6 1.3M64.3 111.4h.1M64.3 106.5v.8M64.3 110.7v3.2M65.1 112.6l-.8 1.3M67.6 117.5h5.5l1 1.2-1 1.3h-5.5z"/>
<path d="M68.6 117.9h4M68.7 118.2v1.2M68.7 118.7h.7M69.4 118.2v1.2M69.8 119.4l.4-1.2 .4 1.2M69.9 119h.6M70.9 107.3h1.5v3.4h-1.5zM71 118.2v1.2h.6M71.7 106.5v.8M71.7 110.7v.7M71.9 118.2h.7M72.2 118.2v1.2"/>
<path d="M74.6 115.1h10.7l1 1.2-1 1.2h-10.7zM75.5 115.4h9.2M76.5 115.8l-.6-.1-.2 .3v.7a.55 .55 0 0 0 .8 .1M77 116.3h.6v-.6h-.6v1.2M78.1 115.7v1l.3 .2 .4-.1v-1.1M79.2 117.1h.9M79.5 107.3h1.4v3.4h-1.4zM80.2 106.5v.8M80.2 110.7v.7M80.3 116.3h.5l.2-.2-.1-.4h-.6v1.2l.7-.1v-.4l-.2-.1M81.6 116.3h.4M82.1 115.7h-.5v1.2h.5"/>
<path d="M82.7 116.3h.5l.2-.1-.2-.5h-.5v1.2M83 116.3l.4 .6M83.9 116.3h.6l.1-.5-.7-.1v1.2M84.2 116.3l.4 .6M86.3 118.7h2.4M86.3 101.7h2.4M86.3 104.1h2.4M86.3 116.3h2.4M113.1 118.7h2.5M113.1 101.7h2.5M113.1 104.1h2.5M113.1 116.3h2.5"/>
<path d="M113.1 106.5h2.5M113.1 109h2.5M113.1 111.4h2.5M113.1 113.9h2.5M119 100.5h3.7l1.1 1.2-1.1 1.2h-3.7l-1.1-1.2zM119 102.9h3.7l1.1 1.2-1.1 1.2h-3.7l-1.1-1.2zM119 105.3h3.7l1.1 1.2-1.1 1.3h-3.7l-1.1-1.3zM119 107.8h3.7l1.1 1.2-1.1 1.2h-3.7l-1.1-1.2zM119 110.2h4.9l1 1.2-1 1.2h-4.9l-1.1-1.2zM119 115.1h4.9l1 1.2-1 1.2h-4.9l-1.1-1.2zM119 112.6h4.9l1 1.3-1 1.2h-4.9l-1.1-1.2zM119 120h4.9l1 1.2-1 1.2h-4.9l-1.1-1.2z"/>
<path d="M119 117.5h4.9l1 1.2-1 1.3h-4.9l-1.1-1.3zM119.7 101.1h.4l.3 .3v.6l-.3 .4h-.4zM119.7 103.5h.4l.3 .3v.7l-.2 .2h-.5zM119.7 106h.5l.2 .3v.6l-.3 .3h-.4zM119.7 108.4h.4l.3 .3v.6l-.3 .3h-.4zM119.7 110.8h.4l.3 .4v.6l-.3 .3h-.4zM119.7 115.7h.5l.2 .3v.7l-.3 .2h-.4zM119.7 113.3h.4l.3 .2v.7l-.2 .3h-.5zM119.7 118.2h.5l.2 .2v.7l-.3 .3h-.4zM120.8 103.5h.9l-.5 1.2M120.9 111.2l.3-.4v1.3M120.9 116.1l.3-.4v1.2"/>
<path d="M120.9 113.6l.3-.3v1.2M120.9 118.5l.3-.3v1.2M120.9 112.1h.7M120.9 116.9h.7M120.9 114.5h.7M120.9 119.4h.7M121.2 106.5l-.3-.2v-.2l.6-.1a.44 .44 0 0 1-.1 .5 .44 .44 0 0 1-.4 .1v.5a.35 .35 0 0 0 .5-.1 .35 .35 0 0 0-.2-.5M121.5 101.1h-.3l-.3 .3v.8l.3 .2 .3-.1v-.7h-.5l-.1 .2M121.6 109l-.1 .1-.6-.1 .1-.5 .3-.1 .2 .1a.85 .85 0 0 1-.3 1.1h-.2M122 115.8l.6-.1 .2 .3-.8 .9h.8M122 113.6l.4-.3v1.2M122 118.2h.8l-.5 .4 .4 .1v.6h-.7"/>
<path d="M122 114.5h.8M122.1 111.1l.2-.3a.68 .68 0 0 1 .5 .7 .68 .68 0 0 1-.5 .6 .77 .77 0 0 1-.2-1zM147.4 100.5h4.8l1.1 1.2-1.1 1.2h-4.8zM147.4 102.9h4.8l1.1 1.2-1.1 1.2h-4.8zM148.6 120h3.6l1.1 1.2-1.1 1.2h-3.6zM148.6 101.1a.64 .64 0 0 1 .7 .6 .64 .64 0 0 1-.7 .7zM148.6 103.5a.66 .66 0 0 1 .6 .5 .66 .66 0 0 1-.2 .7h-.4zM149.8 101.4l.3-.3v1.3M149.8 103.9l.3-.4v1.2M149.8 102.4h.6M149.8 104.7h.6M151.2 101l-.3 .9h.7"/>
<path d="M151.5 101.5v.9M151.6 103.5h-.6l-.1 .6 .1-.1h.4l.2 .1v.5h-.7M27.9 139.4v4.9M48.8 120.2h9.1M49.6 120.7l-.2-.1a.6 .6 0 0 0-.5 .6 .6 .6 0 0 0 .6 .5h.1M50.1 121.2h.7l.1-.4-.3-.2h-.5v1.2M51.4 120.6v1.1l.2 .1h.2l.3-.2v-1M52.3 121.9h1M53.6 121.2h.5l.1-.5-.6-.1v1.2h.4l.3-.4-.4-.2M54.8 121.2h.4M55.4 120.6h-.6v1.2h.6M55.9 121.2h.7v-.5l-.2-.1h-.5v1.2"/>
<path d="M56.2 121.2l.4 .6M57.1 121.2h.6l.1-.4-.2-.2h-.5v1.2M57.4 121.2l.4 .6M61.2 124.4h1.5v3.4h-1.5zM61.2 129.7l.8 1.2M62 128.4h.1M62 123.6v.8M62 127.8v3.1M62.7 129.7l-.7 1.2M78.4 122.4h6.9l1 1.2-1 1.2h-6.9l-1-1.2zM79.4 122.7h5.3M79.6 123.7h.5l.2-.3v-.3l-.7-.1v1.2"/>
<path d="M79.9 123.7l.4 .5M80.9 123.6h.3M81.4 123h-.5v1.2h.5M82.5 123.1l-.4-.1-.2 .3 .1 .2 .5 .3v.3l-.6 .1M83.1 123.6h.4M83.6 123h-.5v1.2h.5M84 123h.7M84.3 123v1.2M86.3 123.6h2.4M100.9 128.4v1.3h1.2l-1.2 1.2-1.2-1.2h1.2M100.9 128.4h.1M100.9 126.1v2.3"/>
<path d="M103.4 133.5h2.3v8.6l-1.1 1-1.2-1zM104 139.2l1.2 .2-.9 .3 .9 .3-1.2 .2M104 135.3h1.2M104 134.6l.7 .7M104.1 136l.7-.2 .4 .2v.3l-.1 .3h-.7l-.3-.1zM104.6 138.8v-.5l-.4-.3-.2 .3v.5h1.2M105.2 138l-.6 .4M105.2 134.6l-.7 .5M105.3 136.9v.9M113.1 121.2h2.5M113.1 123.6h2.5M119 122.4h4.9l1 1.2-1 1.2h-4.9l-1.1-1.2z"/>
<path d="M119.7 120.6h.5l.2 .3v.6l-.3 .3h-.4zM119.7 123h.4l.3 .4v.5l-.2 .3h-.5zM120.9 120.9l.3-.3v1.2M120.9 123.4l.3-.4v1.2M120.9 121.8h.7M120.9 124.2h.7M122.3 120.6l-.3 .8h.8M122.6 121v.8M122.7 123h-.6l-.1 .6 .6-.1 .2 .2v.3l-.2 .2-.6-.1M147.4 132.2h4.8l1.1 1.1-1.1 1.2h-4.8zM147.4 127.3h4.8l1.1 1.1-1.1 1.3h-4.8zM147.4 129.7h4.8l1.1 1.2-1.1 1.3h-4.8z"/>
<path d="M148.6 132.8a.64 .64 0 0 1 .7 .6 .64 .64 0 0 1-.7 .6zM148.6 124.8h3.6l1.1 1.3-1.1 1.2h-3.6zM148.6 122.4h3.6l1.1 1.2-1.1 1.2h-3.6zM148.6 127.9h.4a.66 .66 0 0 1 .2 .8 .66 .66 0 0 1-.6 .4zM148.6 130.3a.64 .64 0 0 1 .7 .6 .64 .64 0 0 1-.7 .7zM149.8 133.1l.3-.3v1.2M149.8 120.6a.64 .64 0 0 1 .7 .6 .64 .64 0 0 1-.7 .6zM149.8 125.5a.66 .66 0 0 1 .6 .4 .66 .66 0 0 1-.2 .8h-.4zM149.8 123a.66 .66 0 0 1 .6 .5 .66 .66 0 0 1-.2 .7h-.4zM149.8 128.3l.3-.4v1.2M149.8 130.7l.3-.4v1.3M149.8 134h.6"/>
<path d="M149.8 129.1h.6M149.8 131.6h.6M150.9 132.9l.1-.1h.4l.2 .1v.4l-.7 .7h.7M150.9 120.6h.7l-.5 1.2M150.9 130.7l.3-.4v1.3M150.9 131.6h.7M151 127.9h.4l.2 .2v.8l-.4 .2a.84 .84 0 0 1-.2-1.2zM151.1 123.5l-.2-.1 .1-.3h.6v.3l-.5 .1-.2 .3 .1 .4 .6-.1v-.4l-.2-.2M151.6 126l-.2 .2h-.3l-.2-.2 .1-.4h.6v.8l-.2 .3h-.4M176.4 138.3h.1M176.4 135.8l-.7 1.2M176.4 135.8l.8 1.2"/>
<path d="M176.4 135.8v2.5M180.1 138.3h2.4M182.5 134.5h9.8v9.8h-9.8zM192.3 138.3h2.4M27.9 144.3v1.2h1.1l-1.1 1.2-1.3-1.2h1.3M27.9 144.3h.1M93.6 144.3v7.3M103.1 154.6h2.9v.4h-2.9zM103.1 155.5h2.9v.5h-2.9zM103.4 153.8h.4M103.6 153.6v.5M103.8 146.2h1.5v3.5h-1.5z"/>
<path d="M104.6 157.7v1.2h1.1l-1.1 1.3-1.2-1.3h1.2M104.6 157.7h.1M104.6 145.5v.7M104.6 149.7v.7M104.6 152.8v1.8M104.6 156v1.7M104.6 141.3v-.6h-.5l-.1 .6h1.2M120.4 151.6h2.4M122.8 148h9.8v9.7h-9.8zM127.7 157.7v2.5M132.6 151.6h2.4M173.4 151.6h5.5v2.5h-5.5l-1.1-1.3z"/>
<path d="M174.2 151.9h4M174.4 152.2v1.3M174.9 152.9l.7-.1 .1-.3-.3-.3h-.5v1.3M175.3 152.9l.4 .6M176.2 152.4l.2-.2 .5 .2 .1 .7-.4 .4-.4-.2zM176.4 153.2l.6 .4M177.4 152.2h.7l-.5 1.3M187.4 144.3v2.4M199.6 152.8h2.4M202 151.6h4.9M204.5 149.9v1.7M206.9 152.8h2.4"/>
<path d="M209.3 152.8v1.3h1.3l-1.3 1.2-1.2-1.2h1.2M209.3 152.8h.1M21.8 172.3h2.4M27.3 173h.6v-1.3h.5v1.3h.6v-1.3h.6v1.3M29 165h.1M29 179.7v1.1h1.2l-1.2 1.2-1.1-1.2h1.1M29 179.7h.1M29 162.6l-.7 1.2M29 162.6l.8 1.2M29 162.6v4.9M29 177.2v2.5M33.9 172.3h2.4"/>
<path d="M43.7 172.3h.7M44.4 171.6h3.4v1.5h-3.4zM47.8 172.3h.7M57.1 171.1h7l1.1 1.2-1.1 1.3h-7zM58.6 171.9l-.5-.1a.61 .61 0 0 0-.3 .8 .61 .61 0 0 0 .8 .3M59.1 171.8v1.2h.6M60.1 171.8v1.2M60.3 172.3l.5 .7M60.8 171.8l-.7 .7M61.5 171.7l-.2 .8h.8M61.9 172.1v.9M62.6 171.8a.61 .61 0 0 1 .6 .5 .61 .61 0 0 1-.4 .7 .75 .75 0 0 1-.2-1.2z"/>
<path d="M82.6 179.7v1.7M90.5 169.9h6.8v2.4h-6.8l-1.1-1.2zM91.4 170.2h5.2M91.5 171.2h.4l.3-.3-.3-.4h-.4v1.3M91.8 171.2l.4 .6M92.7 171.1h.4M93.3 170.5h-.6v1.3h.6M94.5 170.6l-.5-.1-.3 .3 .1 .2 .7 .4-.3 .4-.5-.1M94.8 179.7h.1M94.8 177.2v4.4M94.8 177.2l-.7 1.2M94.8 177.2l.8 1.2"/>
<path d="M95 171.1h.3M95.6 170.5h-.6v1.3h.6M95.9 170.5h.7M96.3 170.5v1.3M99 165.8h1.4v3.4h-1.4zM99.7 165h.1M99.7 162.6l-.7 1.2M99.7 162.6l.7 1.2M99.7 162.6v3.2M99.7 169.2v.7M107.6 162.6h5.5v2.4h-5.5l-1.1-1.2zM108.5 162.9h3.9"/>
<path d="M108.6 163.2v1.2M108.6 163.8h.7M109.3 163.2v1.2M109.5 179.7v1.9M109.7 164.4l.4-1.2 .4 1.2M109.8 164.1h.6M110.9 163.2v1.2h.6M111.8 163.2h.6M112.1 163.2v1.2M115.6 163.8v7.3M121.6 179.7v1.9M132.6 179.7v1.9"/>
<path d="M139.9 163.8h2.4M142.3 162.6h4.9M144.8 160.9v1.7M147.2 163.8h2.4M149.6 163.8v1.2h1.3l-1.3 1.2-1.2-1.2h1.2M149.6 163.8h.1M81.2 181.4h2.9v.4h-2.9zM81.2 182.4h2.9v.3h-2.9zM81.4 180.6h.5M81.7 180.3v.5M82.6 182.7v1.8M94.8 184.5v1.3h1.2l-1.2 1.1-1.2-1.1h1.2"/>
<path d="M94.8 184.5h.1M94.8 182.5v2M109.5 182.5v2M121.6 182.5v2M132.6 182.5v2"/>
<circle cx="23.8" cy="59.1" r=".57"/>
<circle cx="49.1" cy="59" r=".64"/>
<circle cx="49.1" cy="45.6" r=".64"/>
<circle cx="49.1" cy="72.5" r=".64"/>
<circle cx="49.1" cy="99.2" r=".64"/>
<circle cx="49.1" cy="85.8" r=".64"/>
<circle cx="49.1" cy="112.6" r=".64"/>
<circle cx="202.5" cy="152.8" r=".55"/>
<circle cx="206.4" cy="152.8" r=".55"/>
<circle cx="142.8" cy="163.8" r=".55"/>
<circle cx="146.7" cy="163.8" r=".55"/>
</g>
<g fill="none" stroke="#910000" stroke-width=".25">
<path d="M88.8 26.2h24.4v99.9h-24.4zM41.3 55.4l7.3 3.7-7.3 3.7zM41.3 42l7.3 3.7-7.3 3.6zM41.3 68.8l7.3 3.7-7.3 3.7zM41.3 95.6l7.3 3.7-7.3 3.6zM41.3 82.3l7.3 3.6-7.3 3.6zM155.1 85.9h6.1v19.5h-6.1zM155.7 86.4h3.9v1.4h-3.9zM41.3 109l7.3 3.6-7.3 3.8zM23 124.8h9.7v14.7h-9.7zM92.4 146.8h2.5M93.7 146.8l1.2 2.4h-2.5z"/>
<path d="M24.3 167.5h9.7v9.7h-9.7zM115.6 166.2l1.2 2.5h-2.5zM116.2 165.6h.6v.6h-2.5v.7h.6M93.4 181.6h2.9M108 181.6h3M120.2 181.6h2.9M131.2 181.6h2.9"/>
</g>
<g fill="none" stroke="#b90000" stroke-width=".21">
<path d="M86.6 27.4l.3-.4v1.3M86.6 28.3h.7M87.1 39.2h.8l-.5 1.3M87.7 34.4h-.3l-.2 .2v.9h.6l.1-.5-.3-.2h-.2l-.2 .2M87.9 37.3l-.2 .2-.5-.1v-.5l.5-.1a.94 .94 0 0 1 0 1.1l-.4 .1M88.4 27h-.6l-.1 .6h.7v.6h-.7M99.7 24.1h.9M100.2 24v.7l-.9-.3M100.6 25.5h-1.2l.3 .4M100.6 25.1v.8M113.4 27.2l.1-.2h.4l.1 .2v.4l-.6 .7h.6M113.4 29.5h.6l-.3 .5 .3 .1v.5l-.1 .1h-.4l-.1-.1"/>
<path d="M113.4 31.9h.6l-.3 .5 .3 .1v.5h-.6M113.4 34.4h.6l-.3 .4 .3 .2v.5h-.6M113.4 36.8h.6l-.3 .5h.3v.6h-.6M113.4 39.2h.6l-.3 .5 .3 .1v.5l-.1 .2h-.4l-.1-.2M114.5 36.8h.7l-.4 .5 .4 .2-.1 .4h-.6M114.6 32.3l.3-.4v1.2M114.6 34.5l.5-.1 .1 .3-.7 .9h.7M114.6 33.1h.6M114.8 29.5a.68 .68 0 0 1 .4 .6 .68 .68 0 0 1-.4 .6l-.2-.5v-.6zM114.8 39.2l-.2 .8h.7M115.1 39.6v.9M115.2 27.6l-.1 .2h-.5v-.7l.4-.1 .2 .3-.1 .9-.5 .1"/>
<path d="M39 57.5h.8l-.4 .5 .4 .2v.3l-.3 .3h-.3l-.2-.2M39 44.4l.4-.3v1.2M39 45.3h.8M50 44.2l.5-.1 .2 .3-.7 .9h.7M50.3 57.4l-.3 .9h.8M50.6 57.9v.9M86.6 44.4l.3-.3v1.2M86.6 51.7l.3-.3v1.3M86.6 54.2l.3-.4v1.2M86.6 56.6l.3-.3v1.2M86.6 45.3h.7M86.6 52.7h.7"/>
<path d="M86.6 55h.7M86.6 57.5h.7M87.4 42.2l-.2-.1v-.4h.6l.1 .3-.7 .3v.5l.2 .1h.2l.3-.2v-.3l-.3-.2M87.7 51.4h.8l-.4 .5 .4 .2v.3l-.3 .3h-.3l-.2-.2M87.7 54.2l.4-.4v1.2M87.7 56.4l.6-.1 .2 .3-.8 .9h.8M87.7 55h.8M87.9 44.2l.2-.1a.84 .84 0 0 1 .2 1.2l-.4-.1a.78 .78 0 0 1 0-1zM113.4 41.7h.6l-.3 .5h.3v.6l-.1 .1h-.4l-.1-.1M113.4 44.1h.6l-.3 .4 .3 .2v.5h-.6M113.4 46.6h.6l-.3 .4 .3 .2v.5h-.6M113.4 48.9h.6l-.3 .5 .3 .1v.5l-.1 .2h-.4l-.1-.2"/>
<path d="M113.4 51.4h.6l-.3 .5 .3 .1v.5l-.1 .2h-.4l-.1-.2M113.7 53.8l-.3 .9h.7M113.7 56.2l-.3 .9h.7M113.7 58.7l-.3 .8h.7M114 54.3v.7M114 56.7v.8M114 59.1v.8M114.5 46.6h.8l-.5 1.1M114.6 56.6l.3-.3v1.2M114.6 58.8h.5l.1 .3-.7 .8h.7M114.6 57.5h.6M114.6 53.9l.4-.1a.86 .86 0 0 1 .1 1.2l-.5-.1z"/>
<path d="M114.8 49.5l-.2-.1a.31 .31 0 0 1 .1-.4 .31 .31 0 0 1 .4 .1v.3l-.5 .1v.2v.3l.2 .2 .4-.2-.1-.5h-.1M115.1 41.7h-.5v.5h.5v.6l-.4 .1-.1-.1M115.1 44.1l-.4 .1-.1 .4v.7h.5v-.7l-.3-.1-.2 .3M115.2 51.9a.35 .35 0 0 1-.3 .3 .35 .35 0 0 1-.3-.3v-.4l.4-.1a.72 .72 0 0 1 .2 .7 .72 .72 0 0 1-.6 .6M39.7 70.9h-.6l-.1 .6h.7l.1 .4-.3 .2h-.3l-.2-.1M50.6 70.9h-.2l-.4 .3v.8l.5 .1 .2-.2v-.3a.35 .35 0 0 0-.3-.2 .35 .35 0 0 0-.4 .2M86.6 63.7l.4-.1 .3 .3-.8 .9h.8M86.6 66.4l.3-.4v1.2M86.6 68.6l.6-.1 .1 .3-.8 .9h.8M86.6 67.2h.7M87.7 68.8l.4-.3v1.2M87.7 69.7h.8"/>
<path d="M87.9 63.7a.61 .61 0 0 1 .6 .3 .61 .61 0 0 1-.2 .8h-.4l-.1-.2-.1-.5zM88.5 66.5l-.3 .3h-.2l-.3-.3 .1-.4 .4-.1 .3 .3-.2 .8-.4 .1M113.7 61.1l-.3 .9h.7M113.7 63.5l-.3 .9h.7M113.7 66l-.3 .8h.7M113.7 68.4l-.3 .9h.7M113.7 70.9l-.3 .8h.7M113.7 73.2l-.3 1h.7M114 61.5v.9M114 64v.8M114 66.5v.7M114 68.8v.9"/>
<path d="M114 71.3v.8M114 73.7v.9M114 75.8h-.5l-.1 .6 .1-.2h.4l.1 .2v.5h-.6M114 78.2h-.5l-.1 .6 .1-.1h.4l.1 .1v.5h-.6M114.5 61.1h.7l-.4 .5h.3v.7l-.5 .1-.1-.2M114.5 70.9h.8l-.5 1.2M114.6 78.6l.3-.4v1.2M114.6 79.4h.6M114.6 75.9l.4-.1a.86 .86 0 0 1 .1 1.2l-.5-.1zM114.8 63.5l-.2 .9h.7M114.8 73.8h-.2a.31 .31 0 0 1 .1-.4 .31 .31 0 0 1 .4 .1v.3h-.3l-.2 .3v.2l.2 .3 .4-.3v-.2l-.2-.3M115.1 66h-.5v.6l.1-.1h.4v.7l-.5-.1"/>
<path d="M115.1 68.5l-.4 .1-.1 .8a.35 .35 0 0 0 .3 .3 .35 .35 0 0 0 .3-.3v-.2a.35 .35 0 0 0-.3-.3 .35 .35 0 0 0-.3 .3M115.1 64v.8M38.4 98l.5-.3v1.2M38.4 98.9h.8M39.6 98l.4-.3v1.2M39.6 98.9h.7M39.8 84.8l-.3 .3h-.2l-.3-.3v-.3l.2-.2h.4l.2 .2v.5a.55 .55 0 0 1-.6 .5M49.4 98l.4-.3v1.2M49.4 98.9h.7M50.3 84.8l-.3-.1v-.3l.6-.1a.44 .44 0 0 1 0 .5 .44 .44 0 0 1-.5 .1v.5a.35 .35 0 0 0 .6 0 .35 .35 0 0 0-.2-.6M50.7 97.8l.3-.1a.84 .84 0 0 1 .1 1.2h-.3l-.2-.2zM86.6 85.6l.4-.1 .3 .3-.8 .9h.8"/>
<path d="M86.6 88.1l.4-.1 .3 .3-.8 .9h.8M86.6 90.5l.6-.1 .1 .4-.8 .8h.8M86.6 97.8l.4-.1 .3 .3-.8 .9h.8M87.7 88h.8l-.5 1.2M88 86l-.3-.2 .1-.2h.6l.1 .2-.2 .2h-.3l-.3 .3 .2 .4h.4l.2-.2v-.2l-.3-.3M88.3 90.4h-.3l-.2 .3v.8a.42 .42 0 0 0 .5 0 .42 .42 0 0 0 .1-.6l-.4-.1-.3 .3M88.4 97.7h-.6l-.1 .6 .2-.2h.3l.3 .3v.3l-.2 .2-.6-.1M113.9 90.4h.7l-.4 .4 .4 .1v.6h-.7M114 93l.1-.2h.4l.1 .2v.4l-.7 .7h.7M114 95.6l.3-.4v1.3M114 97.7l-.5 .1a.94 .94 0 0 0 0 1.1l.5-.1v-.5l-.4-.2-.2 .3M114 96.5h.6"/>
<path d="M114 80.7h-.5l-.1 .5h.6v.6h-.6M114.2 87.9l-.2 .8h.7M114.6 80.8l.5-.1 .1 .3-.7 .9h.7M114.6 88.4v.8M114.6 85.5h-.6v.6l.6-.1v.6h-.6M114.8 97.6l-.2 .9h.7M115.1 98.1v.8M38.4 111.4l.5-.3v1.2M38.4 112.3h.8M39.5 111.1h.8l-.3 .5 .3 .1v.5l-.2 .1h-.4l-.2-.1M49.4 111.4l.4-.3v1.2M49.4 112.3h.7"/>
<path d="M50.6 111.2l.5-.1 .2 .3-.8 .9h.8M86.6 100.2h.6l.1 .3-.8 .8h.8M86.6 102.7l.4-.2 .3 .5-.8 .8h.8M86.6 114.9l.4-.2 .3 .4-.8 .9h.8M86.6 117.5l.3-.3v1.2M86.6 118.4h.7M87.7 102.5h.8l-.4 .5 .3 .1 .1 .4-.3 .3h-.3l-.2-.2M87.7 114.9l.2-.2h.3l.3 .3-.8 1h.8M87.7 117.2h.8l-.5 1.2M88.1 100.1l-.4 .8h.8M88.3 100.5v.8M114 100.2h-.5l-.1 .9 .2 .2h.4v-.5l-.1-.2h-.3l-.2 .2"/>
<path d="M114 102.5a.72 .72 0 0 0-.6 .6 .72 .72 0 0 0 .2 .7l.4-.2v-.5l-.4-.1-.2 .3M114 105l-.5 .2-.1 .8 .2 .3 .4-.2v-.6h-.5l-.1 .2M114 107.4l-.5 .1a.94 .94 0 0 0 0 1.1l.5-.1v-.5l-.4-.1-.2 .2M114 109.9h-.5l-.1 .6 .1-.2h.4l.1 .2v.5h-.6M114 112.3h-.5l-.1 .6h.6v.6h-.6M114 114.7h-.5l-.1 .6 .6-.1v.6l-.1 .2h-.4l-.1-.2M114 117.2h-.5l-.1 .6 .6-.1v.6h-.6M114 119.6h-.5l-.1 .6 .1-.1h.4l.1 .1v.5h-.6M114.5 100.2h.7l-.4 .4 .3 .1v.6h-.6M114.5 114.7h.8l-.5 1.3M114.6 102.7l.4-.2 .2 .5-.7 .8h.7M114.6 105.3l.3-.3v1.3"/>
<path d="M114.6 106.3h.6M114.6 107.5l.4-.1a.86 .86 0 0 1 .1 1.2l-.5-.1zM114.8 112.9l-.2-.3v-.3h.5v.5l-.5 .1v.4a.35 .35 0 0 0 .3 .2 .35 .35 0 0 0 .3-.2l-.1-.4h-.1M115.1 117.2l-.4 .1-.1 .4v.7h.5v-.7h-.5v.2M115.1 119.6h-.5v.6l.1-.1h.4v.7l-.5-.1M115.2 110.4l-.1 .2a.43 .43 0 0 1-.5-.2 .43 .43 0 0 1 0-.5h.5l.1 .2-.1 .9-.5 .1M26.7 121.6h.8M27.1 121.4v.8l-.9-.4M27.5 122.9h-1.3l.5 .4M27.5 122.6v.7M86.6 122.4l.3-.3v1.2M86.6 123.3h.7"/>
<path d="M88 122.6l-.3-.3 .2-.2h.4l.2 .2-.8 .5 .3 .5h.2l.3-.3-.3-.4M99.4 126.4v.4l.2 .2h.9v-.6h-.6l-.1 .4 .3 .2M100.6 127.8h-1.2l.3 .4M100.6 127.5v.7M114 122.1h-.5l-.1 .6 .1-.2h.4l.1 .2v.5h-.6M114.8 122l-.2 .8h.7M115.1 122.4v.9M180.9 136.8l.2-.2h.3l.3 .3-.8 1h.8M193.1 136.6h.7l-.3 .6h.3v.5l-.2 .2h-.3l-.2-.2M27.5 142l-1.3-.5v.8M121.2 150.2l.6-.1 .2 .2-.1 .3-.7 .7h.8M127.4 158.9h-1.2l.3 .4"/>
<path d="M127.4 158.6v.7M133.4 150.1h.7l-.3 .4 .3 .1v.6h-.7M187.1 145.5h-1.3l.4 .4M187.1 145.2v.7M22.6 171.1l.3-.3v1.2M22.6 172h.7M27.9 178.2h.8M28 166.1l.3-.2h.3v.6a.51 .51 0 0 1-.7-.6h-.3l-.1 .5 .3 .2 .2-.2M28.3 178.1v.6l-.9-.2M35.4 170.8h-.5l-.1 .6 .6-.1v.7h-.4l-.2-.1"/>
</g>
<g fill="none" stroke="#006665" stroke-width=".21">
<path d="M89.6 36.5l.4-1.3 .4 1.3M89.6 34.9h1.9M89.6 39.8h3.4M89.7 36.1h.6M89.7 38.4h.6l.1-.2v-.4l-.7-.1v1.2M90.1 38.4l.3 .5M90.4 28a.61 .61 0 0 0-.7 .3 .61 .61 0 0 0 .2 .8l.5-.1M90.9 27.9v1.2h.6M91.4 35.3l-.5-.1-.1 .2v.3l.6 .2v.2l-.2 .4-.4-.1M91.9 37.6l-1.1 1.6M91.9 27.9v1.2M92.1 37.7l.4 1.2 .1-.9 .3 .9 .3-1.2"/>
<path d="M92.1 28.4l.5 .7M92.1 37.3h1.1M92.6 27.9l-.7 .7M100.2 29l1.2 .4-1.2 .4M100.8 28l-.1 .4 .1 .2h.5l.3-.2-.1-.4M100.8 27.1l-.1 .4 .4 .2 .5-.2-.1-.4M110.3 29.1l.4-1.2 .4 1.2M110.3 31.6l.4-1.2 .4 1.2M110.3 34l.4-1.2 .4 1.2M110.3 36.5l.4-1.3 .4 1.3M110.3 38.9l.4-1.2 .4 1.2M110.4 36.1h.6"/>
<path d="M110.4 28.8h.6M110.4 31.2h.6M110.4 33.7h.6M110.4 38.5h.6M111.4 28.3l.4-.4v1.2M111.4 30.5h.7v.4l-.7 .7h.7M111.4 32.8h.7l-.3 .5 .3 .1v.5l-.2 .1h-.3l-.2-.1M111.4 29.1h.7M111.8 35.2l-.4 .9h.8M112 35.6v.9M112.1 37.7h-.6l-.1 .6 .2-.2h.3l.2 .2v.5h-.7M89.6 42.2h3.1"/>
<path d="M89.6 44.6h5.4M89.6 52h2.2M89.6 54.4h2.2M89.6 56.8h5.6M89.7 40.1v1l.3 .2 .4-.1v-1.1M89.7 42.6v1.2h.6M89.7 45h.4l.3 .3v.6l-.3 .3h-.4zM89.7 52.9h.5l.2-.2-.1-.4h-.6v1.2l.7-.1v-.4l-.2-.1M89.7 55.3h.6l.1-.4-.2-.2h-.5v1.3h.6l.1-.2v-.3l-.2-.2M89.7 57.7h.6l.1-.3-.2-.3h-.5v1.3h.6l.1-.2v-.4l-.2-.1M90.8 42.6h.4a.66 .66 0 0 1 .2 .7 .66 .66 0 0 1-.6 .5zM90.8 45h.7"/>
<path d="M90.9 52.9h.6l.2-.4-.2-.2h-.6v1.2M91 40.1h.5l.2 .3v.7l-.3 .2h-.4zM91.2 45v1.2M91.3 52.9l.4 .6M91.6 54.8l-.2-.1-.5 .3 .1 .8 .4 .2 .2-.1 .1-.4h-.3M91.6 57.2l-.2-.1-.5 .4v.6l.5 .3 .3-.2v-.4h-.3M91.7 46.2l.4-1.2 .4 1.2M91.9 45.9h.6M92 58.4l.5-1.3 .3 1.3M92.1 58h.6M92.6 42.6h-.6l-.1 .2 .1 .3 .5 .2v.4h-.6M92.9 40.1h-.6a.47 .47 0 0 0 0 .5 .47 .47 0 0 0 .5 .2v.4h-.6"/>
<path d="M93.6 45.1l-.2-.1a.65 .65 0 0 0-.5 .6 .65 .65 0 0 0 .5 .6l.2-.1M93.9 57.3l-.3-.2-.4 .4 .1 .7 .3 .2 .3-.2M94.1 45v1.2M94.3 45.5l.5 .7M94.5 57.1v1.3M94.7 57.7l.5 .7M94.8 45l-.7 .7M95.2 57.1l-.7 .7M109.1 51.1l.5-1.2 .3 1.2M109.1 53.5l.5-1.2 .3 1.2M109.1 56l.5-1.3 .3 1.3M109.1 58.4l.5-1.3 .3 1.3"/>
<path d="M109.2 58h.6M109.2 50.7h.6M109.2 53.2h.6M109.2 55.6h.6M110.3 41.3l.4-1.2 .4 1.2M110.3 43.8l.4-1.2 .4 1.2M110.3 46.2l.4-1.2 .4 1.2M110.3 48.6l.4-1.2 .4 1.2M110.3 50.2l.4-.3v1.2M110.3 52.7l.4-.4v1.2M110.3 55.1l.4-.4v1.3M110.3 57.5l.4-.4v1.3"/>
<path d="M110.3 59.9l.4-.3v1.2M110.3 51.1h.7M110.3 53.5h.7M110.3 56h.7M110.3 58.4h.7M110.4 45.9h.6M110.4 41h.6M110.4 43.4h.6M110.4 48.3h.6M111.4 42.6h.8l-.5 1.2M111.4 52.7l.4-.4v1.2M111.4 54.9l.2-.2h.3l.2 .2v.4l-.7 .7h.7"/>
<path d="M111.4 57.1h.7l-.3 .6h.3v.5l-.2 .2h-.3l-.2-.2M111.4 53.5h.7M111.6 50l.2-.1 .3 .2v.8l-.2 .2-.3-.1a.78 .78 0 0 1 0-1zM111.7 45.5l-.3-.3 .3-.2h.2l.2 .4-.4 .1-.3 .2v.3l.3 .2 .4-.1v-.5l-.2-.1M111.8 59.5l-.4 .9h.8M112 40.1l-.4 .1-.2 .9 .3 .2 .4-.1v-.5l-.2-.1h-.2l-.3 .2M112.1 47.9v.2a.42 .42 0 0 1-.6-.1 .42 .42 0 0 1 0-.5h.6v.8l-.2 .3h-.3M89.6 66.9l.4 1.3 .4-1.3M89.6 69.3l.4 1.2 .4-1.2M89.6 66.5h3.2M89.6 69h3M89.7 65h.5"/>
<path d="M90.3 64.5h-.6v1.2h.6M90.8 68.2v-1.3l.4 .9 .4-.9v1.3M90.8 70h.5l.2-.2-.1-.4-.6-.1v1.2M91.9 70.5l.4-1.2 .3 1.2M91.9 70.2h.6M92 68.2l.5-1.3 .3 1.3M92.1 67.8h.6M109.1 60.8l.5-1.2 .3 1.2M109.1 63.2l.5-1.1 .3 1.1M109.1 65.7l.5-1.2 .3 1.2M109.1 68.2l.5-1.3 .3 1.3M109.1 70.5l.5-1.2 .3 1.2"/>
<path d="M109.1 73l.5-1.2 .3 1.2M109.1 75.4l.5-1.2 .3 1.2M109.1 77.9l.5-1.3 .3 1.3M109.2 67.8h.6M109.2 70.2h.6M109.2 60.4h.6M109.2 62.9h.6M109.2 65.4h.6M109.2 72.6h.6M109.2 75.1h.6M109.2 77.6h.6M109.2 79.9h.6"/>
<path d="M110.3 62.4l.4-.3v1.1M110.3 64.9l.4-.4v1.2M110.3 67.2l.4-.3v1.3M110.3 69.7l.4-.4v1.2M110.3 72.1l.4-.3v1.2M110.3 74.3l.5-.1 .2 .4-.8 .8h.8M110.3 76.8l.4-.2 .3 .4-.8 .9h.8M110.3 79.2l.4-.1 .3 .3-.8 .9h.8M110.3 60.8h.7M110.3 63.2h.7M110.3 65.7h.7M110.3 68.2h.7"/>
<path d="M110.3 70.5h.7M110.3 73h.7M111.4 66.9h.8l-.5 1.3M111.4 77h.2l.2-.4v1.3M111.4 79.2l.2-.1h.3l.2 .1v.4l-.7 .7h.7M111.4 77.9h.7M111.6 74.2h.3l.2 .2v.8l-.3 .2a.84 .84 0 0 1-.2-1.2zM111.7 69.8l-.3-.2 .1-.2h.6v.4h-.4l-.3 .3 .2 .4h.4l.1-.5-.2-.2M112 64.5l-.4 .1-.2 .8 .3 .3 .4-.1v-.6l-.4-.1-.3 .3M112 60v.8M112.1 62.1h-.6l-.1 .6 .2-.2h.3l.2 .2v.5h-.7M112.1 72.3l-.2 .3h-.2l-.3-.3 .1-.4h.6v.8l-.2 .3h-.3"/>
<path d="M89.6 98.2h3.7M89.7 86.9h.5M89.7 89.4h.5M89.7 91.9h.5M89.7 98.5v1.3M90.3 86.4h-.6v1.2M90.3 88.8h-.6v1.3M90.3 91.3h-.6v1.2M90.3 99.2l.6-.1v-.5l-.6-.1v1.3M91.5 86.5l-.3-.1-.4 .3v.8l.4 .1 .3-.1M91.5 89l-.3-.2-.4 .4v.7l.4 .2 .3-.2M91.5 91.4h-.1a.46 .46 0 0 0-.6 .1v.7l.1 .3 .6-.1"/>
<path d="M91.5 98.5v1.3h.6M91.9 89.2l.4-.4v1.3M91.9 91.4h.7v.4l-.7 .7h.7M91.9 90.1h.7M92.1 86.4h.3l.2 .2v.8l-.2 .2a.71 .71 0 0 1-.3-1.2zM92.6 98.6l.2-.1a.68 .68 0 0 1 .4 .7 .68 .68 0 0 1-.4 .6 .81 .81 0 0 1-.2-1.2zM109.1 80.3l.5-1.2 .3 1.2M109.1 82.7l.5-1.2 .3 1.2M109.2 82.4h.6M110.3 81.6l.4-.1 .3 .4-.8 .8h.8M110.3 86.4a.64 .64 0 0 1 .7 .6 .64 .64 0 0 1-.7 .6zM110.3 88.8a.64 .64 0 0 1 .7 .6 .64 .64 0 0 1-.7 .7z"/>
<path d="M110.3 91.3a.66 .66 0 0 1 .7 .4 .66 .66 0 0 1-.3 .8h-.4zM110.3 93.7a.66 .66 0 0 1 .7 .5 .66 .66 0 0 1-.3 .7h-.4zM110.3 96.2h.4a.66 .66 0 0 1 .3 .7 .66 .66 0 0 1-.7 .5zM110.3 98.5a.64 .64 0 0 1 .7 .7 .64 .64 0 0 1-.7 .6zM111.4 81.5h.7l-.3 .5 .3 .1v.5h-.7M111.4 89.2h.2l.2-.4v1.3M111.4 91.4h.7v.4l-.7 .7h.7M111.4 93.7h.7l-.3 .4 .3 .2v.5h-.7M111.4 90.1h.7M111.6 86.4h.2l.3 .2v.8l-.3 .2a.71 .71 0 0 1-.2-1.2zM111.8 96.1l-.4 .8h.8M112 96.5v.9"/>
<path d="M112.1 98.5h-.6l-.1 .6h.7v.5l-.2 .2h-.3l-.2-.2M89.6 100.7h3.7M89.6 103.1h3.7M89.6 115.3h4.5M89.6 117.8h4M89.7 116.2h.5l.2-.2-.1-.3h-.6v1.1h.7v-.5l-.2-.1M89.7 101v1.3M89.7 103.5v1.1M89.7 118.1v1.2M89.7 118.6h.7M90.3 101.7l.6-.1v-.5l-.6-.1v1.3M90.3 104.1h.6v-.6h-.6v1.1"/>
<path d="M90.4 118.1v1.2M90.8 119.3l.5-1.2 .4 1.2M90.9 116.2h.5M90.9 119h.6M91.5 101v1.3h.6M91.5 103.5v1.1h.6M91.5 115.7h-.6v1.1h.6M92 116.2h.6l.2-.1-.1-.4h-.7v1.1M92 118.1v1.2h.6M92.4 116.2l.4 .6M92.5 101.3h.1l.2-.3v1.3M92.5 103.5h.5l.2 .2-.7 .9h.7"/>
<path d="M92.5 102.3h.7M92.9 118.1h.7M93.2 118.1v1.2M93.3 116.2h.6v-.5h-.6v1.1M93.6 116.2l.4 .6M109.1 110.7a.64 .64 0 0 1 .7 .7 .64 .64 0 0 1-.7 .6zM109.1 113.2a.66 .66 0 0 1 .7 .4 .66 .66 0 0 1-.2 .8h-.5zM109.1 115.7h.5a.66 .66 0 0 1 .2 .7 .66 .66 0 0 1-.7 .4zM109.1 118.1h.5a.66 .66 0 0 1 .2 .8 .66 .66 0 0 1-.7 .4zM110.3 101a.64 .64 0 0 1 .7 .6 .64 .64 0 0 1-.7 .7zM110.3 103.5a.66 .66 0 0 1 .7 .4 .66 .66 0 0 1-.3 .7h-.4zM110.3 105.9h.4a.66 .66 0 0 1 .3 .8 .66 .66 0 0 1-.7 .4z"/>
<path d="M110.3 108.3a.64 .64 0 0 1 .7 .6 .64 .64 0 0 1-.7 .7zM110.3 111.1l.4-.4v1.3M110.3 113.5l.4-.3v1.2M110.3 116l.4-.3v1.1M110.3 118.4l.4-.3v1.2M110.3 112h.7M110.3 114.4h.7M110.3 116.8h.7M110.3 119.3h.7M111.4 103.5h.8l-.5 1.1M111.4 113.5l.4-.3v1.2M111.4 115.7h.7v.5l-.7 .6h.7"/>
<path d="M111.4 118.1h.7l-.3 .4 .3 .1v.6h-.7M111.4 114.4h.7M111.6 110.8l.2-.1 .3 .3v.8l-.3 .2a.71 .71 0 0 1-.2-1.2zM111.7 106.4l-.3-.3 .2-.2h.4l.1 .4-.7 .4 .3 .4 .4-.1v-.5l-.2-.1M112 101l-.4 .1a.92 .92 0 0 0 .1 1.2l.4-.2v-.5l-.5-.1-.2 .2M112.1 108.9l-.1 .1h-.4l-.2-.1v-.4l.3-.2 .4 .2v.7l-.2 .3-.3 .1M27.2 128.6l1.2 .4-1.2 .4M27.2 136.1h1.2l-1.2 .6h1.2M27.3 127.5a.61 .61 0 0 0 .3 .8 .61 .61 0 0 0 .8-.3l-.1-.5M27.3 126.2v.1a.45 .45 0 0 0 .1 .7h.7l.3-.2-.1-.6M27.3 137.3a.59 .59 0 0 0 .3 .7 .59 .59 0 0 0 .8-.3l-.1-.5h-.4v.3M27.3 135a.72 .72 0 0 1 1.1 0v.5h-1.2z"/>
<path d="M89.6 122.6h5.2M89.7 123.6h.6l.1-.2v-.4l-.7-.1v1.2M90.1 123.6l.3 .5M90.9 123.5h.5M91.5 122.9h-.6v1.2h.6M92.7 123h-.7v.4l.6 .2 .1 .2-.1 .3h-.6M93.2 123.5h.4M93.8 122.9h-.6v1.2h.6M94.1 122.9h.7M94.5 122.9v1.2M100.2 123.1h1.2l-1.2 .7h1.2M100.3 124.4l-.1 .3 .4 .3h.6l.2-.1-.1-.6h-.4v.2"/>
<path d="M100.4 121.9h.9l.1 .2v.4h-1.2zM109.1 120.5a.64 .64 0 0 1 .7 .6 .64 .64 0 0 1-.7 .6zM109.1 122.9a.66 .66 0 0 1 .7 .5 .66 .66 0 0 1-.2 .7h-.5zM110.3 120.8l.4-.3v1.2M110.3 123.3l.4-.4v1.2M110.3 121.7h.7M110.3 124.1h.7M111.8 120.5l-.4 .8h.8M112 120.9v.8M112.1 122.9h-.6l-.1 .6 .6-.1 .1 .6h-.7M183.4 137.6l.4 1.2 .3-1.2M185.1 138l-.5 .1v.6h.5"/>
<path d="M186.2 138h-.5l-.1 .5a.36 .36 0 0 0 .6 .2M188.7 137.6h-.4a.61 .61 0 0 0-.3 .8 .61 .61 0 0 0 .8 .3v-.4h-.3M190.1 137.6v1.2l-.8-1.2v1.2M190.6 137.6h.5a.66 .66 0 0 1 .2 .8 .66 .66 0 0 1-.7 .4zM123.7 151l.4 1.1 .4-1.1M125.4 151.4l-.5 .1v.6h.5M126.5 151.4h-.5l-.1 .2 .1 .5h.5M126.7 153.8v3.1M127.1 154.9v.5l.2 .1 .3-.1 .2-.5h.4v.6M127.1 153.8v.7M127.1 154.2h1.2M127.7 156.7l-.1-.7h-.3l-.2 .1v.6h1.2"/>
<path d="M128.3 156l-.6 .4M129 151a.59 .59 0 0 0-.7 .4 .59 .59 0 0 0 .3 .7h.5v-.5h-.2M130.4 151v1.1l-.8-1.1v1.1M130.9 151a.66 .66 0 0 1 .7 .3 .66 .66 0 0 1-.2 .8h-.5zM186.4 140.4v3M186.8 141.5v.5l.1 .2 .4-.2 .1-.5h.5v.7M186.8 140.4v.7M186.8 140.7h1.2M187.4 143.3l-.1-.6-.4-.1-.1 .1v.6h1.2M188 142.6l-.6 .4M25 172.2h.4M25.6 171.7h-.6v1.2h.6"/>
<path d="M26.8 171.7v1.2l-.7-1.2v1.2M28.4 170.2l1.2 .3-1.2 .4M28.4 174.5h1.2l-1.2 .7h1.2M28.4 175.8v.3l.3 .3h.6l.2-.1v-.5h-.4v.1M28.5 173.3h1l.1 .6h-1.2zM28.9 169.2v.6h.6l.1-.2-.1-.4M28.9 168.1a.36 .36 0 0 0 .1 .6h.5v-.6M30.2 171.9l.2-.2h.4a.86 .86 0 0 1-.1 1.2l-.5-.2zM31.5 171.7v.9l.2 .3 .5-.1 .1-.2v-.9M32.6 171.7h.8M32.9 171.7v1.2"/>
</g>
<path d="M81.2 182.5h2.9M93.4 182.5h2.9M107.9 182.5h3M120.1 182.5h3M131.1 182.5h2.9" fill="none" stroke="#910000" stroke-width=".34"/>
<path d="M103.1 155.7h2.9" fill="none" stroke="#910000" stroke-width=".42"/>
<path d="M112.1 149.2l1-.5 .9 .5-.9 .5v1.9v-1.9z" fill="none" stroke="#474747" stroke-width=".21"/>
<path d="M160.2 86.9h.4v.4h-.4z" fill="#910000"/>
<path d="M154.5 87h1.2M159.6 87h.8v2.5h-.8M160.2 86.8h.4v.5h-.4z" fill="none" stroke="#910000" stroke-width=".21"/>
<path d="M155.7 88.8h3.9v1.5h-3.9z" fill="none" stroke="#910000" stroke-width=".25"/>
<path d="M160.2 89.3h.4v.5h-.4z" fill="#910000"/>
<path d="M154.5 89.5h1.2M159.6 89.5h.8v2.4h-.8M160.2 89.3h.4v.4h-.4z" fill="none" stroke="#910000" stroke-width=".21"/>
<path d="M155.7 91.2h3.9v1.5h-3.9z" fill="none" stroke="#910000" stroke-width=".25"/>
<path d="M160.2 91.8h.4v.4h-.4z" fill="#910000"/>
<path d="M154.5 91.9h1.2M159.6 91.9h.8v2.5h-.8M160.2 91.7h.4v.5h-.4z" fill="none" stroke="#910000" stroke-width=".21"/>
<path d="M155.7 93.7h3.9v1.4h-3.9z" fill="none" stroke="#910000" stroke-width=".25"/>
<path d="M160.2 94.2h.4v.5h-.4z" fill="#910000"/>
<path d="M154.5 94.4h1.2M159.6 94.4h.8v2.4h-.8M160.2 94.2h.4v.4h-.4z" fill="none" stroke="#910000" stroke-width=".21"/>
<path d="M155.7 96.1h3.9v1.5h-3.9z" fill="none" stroke="#910000" stroke-width=".25"/>
<path d="M160.2 96.6h.4v.4h-.4z" fill="#910000"/>
<path d="M154.5 96.8h1.2M159.6 96.8h.8v2.4h-.8M160.2 96.5h.4v.5h-.4z" fill="none" stroke="#910000" stroke-width=".21"/>
<path d="M155.7 98.6h3.9v1.4h-3.9z" fill="none" stroke="#910000" stroke-width=".25"/>
<path d="M160.2 99h.4v.5h-.4z" fill="#910000"/>
<path d="M154.5 99.2h1.2M159.6 99.2h.8v2.5h-.8M160.2 99h.4v.4h-.4z" fill="none" stroke="#910000" stroke-width=".21"/>
<path d="M155.7 101h3.9v1.5h-3.9z" fill="none" stroke="#910000" stroke-width=".25"/>
<path d="M160.2 101.5h.4v.4h-.4z" fill="#910000"/>
<g fill="none" stroke="#910000" stroke-width=".21">
<path d="M153.3 87h1.2M153.3 89.5h1.2M153.3 91.9h1.2M153.3 94.4h1.2M153.3 96.8h1.2M153.3 99.2h1.2M160.6 87h2.5M148.6 115.1h3.6l1.1 1.2-1.1 1.2h-3.6zM148.6 117.5h3.6l1.1 1.2-1.1 1.3h-3.6zM149.8 115.7h.4a.66 .66 0 0 1 .2 .8 .66 .66 0 0 1-.6 .4zM149.8 118.2h.4a.66 .66 0 0 1 .2 .7 .66 .66 0 0 1-.6 .5zM151.5 118.2l-.5 .1-.1 .8 .2 .3 .5-.1v-.6l-.5-.1-.2 .3"/>
<path d="M151.6 115.7h-.6l-.1 .6 .1-.1h.4l.2 .1v.5h-.7M153.3 101.7h2.4M153.3 104.1h2.4M159.6 101.7h.8v2.4h-.8M160.2 101.5h.4v.4h-.4z"/>
</g>
<path d="M155.1 115.1h6.1v19.5h-6.1zM155.7 103.4h3.9v1.5h-3.9zM155.7 115.6h3.9v1.4h-3.9z" fill="none" stroke="#910000" stroke-width=".25"/>
<path d="M153.5 88h.8l-.5 .4 .5 .2-.1 .5h-.7M153.5 97.7h.8l-.5 1.2M153.6 85.6l.4-.1 .3 .3-.8 .9h.8M153.8 90.3l-.2 .9h.7M154.1 95.2l-.3 .1-.2 .3v.7l.4 .2 .3-.2v-.4l-.2-.1h-.4l-.1 .1M154.1 90.8v.8M154.2 92.8h-.6v.6h.6l.1 .4-.3 .3-.4-.2M161.5 85.8l.3-.3v1.2M161.5 86.7h.6M153.8 100.7l-.2-.5h.5l.2 .2-.3 .3-.4 .1v.5h.2h.4l.1-.2-.3-.4M154.3 103.1l-.2 .2h-.4l-.1-.6 .4-.2 .3 .3-.2 .8-.4 .2" fill="none" stroke="#b90000" stroke-width=".21"/>
<path d="M160.2 116.1h.4v.5h-.4z" fill="#910000"/>
<path d="M154.5 116.3h1.2M159.6 116.3h.8v2.4h-.8M160.2 116.1h.4v.5h-.4z" fill="none" stroke="#910000" stroke-width=".21"/>
<path d="M155.7 118.1h3.9v1.4h-3.9z" fill="none" stroke="#910000" stroke-width=".25"/>
<path d="M160.2 118.5h.4v.5h-.4z" fill="#910000"/>
<path d="M154.5 118.7h1.2M159.6 118.7h.8v2.5h-.8M160.2 118.5h.4v.4h-.4z" fill="none" stroke="#910000" stroke-width=".21"/>
<path d="M155.7 120.4h3.9v1.6h-3.9z" fill="none" stroke="#910000" stroke-width=".25"/>
<path d="M160.2 121h.4v.4h-.4z" fill="#910000"/>
<path d="M154.5 121.2h1.2M159.6 121.2h.8v2.4h-.8M160.2 120.9h.4v.5h-.4z" fill="none" stroke="#910000" stroke-width=".21"/>
<path d="M155.7 122.9h3.9v1.5h-3.9z" fill="none" stroke="#910000" stroke-width=".25"/>
<path d="M160.2 123.4h.4v.5h-.4z" fill="#910000"/>
<path d="M154.5 123.6h1.2M159.6 123.6h.8v2.5h-.8M160.2 123.4h.4v.4h-.4z" fill="none" stroke="#910000" stroke-width=".21"/>
<path d="M155.7 125.3h3.9v1.5h-3.9z" fill="none" stroke="#910000" stroke-width=".25"/>
<path d="M160.2 125.9h.4v.4h-.4z" fill="#910000"/>
<path d="M154.5 126.1h1.2M159.6 126.1h.8v2.3h-.8M160.2 125.8h.4v.5h-.4z" fill="none" stroke="#910000" stroke-width=".21"/>
<path d="M155.7 127.8h3.9v1.4h-3.9z" fill="none" stroke="#910000" stroke-width=".25"/>
<path d="M160.2 128.3h.4v.4h-.4z" fill="#910000"/>
<path d="M154.5 128.4h1.2M159.6 128.4h.8v2.5h-.8M160.2 128.2h.4v.5h-.4z" fill="none" stroke="#910000" stroke-width=".21"/>
<path d="M155.7 130.3h3.9v1.4h-3.9z" fill="none" stroke="#910000" stroke-width=".25"/>
<path d="M160.2 130.7h.4v.5h-.4z" fill="#910000"/>
<g fill="none" stroke="#910000" stroke-width=".21">
<path d="M40.6 31.1h6.9l1 1.2-1 1.1h-6.9zM41.6 31.3h5.4M41.7 31.7a.66 .66 0 0 1 .7 .4 .66 .66 0 0 1-.2 .7h-.5zM42.8 31.7h.6M43.1 31.7v1.1M43.7 32.8l.4-1.1 .4 1.1M43.9 32.5h.5M45.6 31.7h-.2a.67 .67 0 0 0-.5 .5 .67 .67 0 0 0 .2 .6h.5M46.1 31.7v1.1M46.3 32.2l.5 .6M46.8 31.7l-.7 .6M73.5 27.3h9.3l1.1 1.3-1.1 1.2h-9.3z"/>
<path d="M74.2 39.5h9.7v2.5h-9.7l-1-1.2zM75.1 39.9h8.1M75.4 28.1h-.1a.45 .45 0 0 0-.7 .2v.7l.2 .2 .6-.1M75.8 34.7h8.1v2.4h-8.1l-1.1-1.2zM75.9 28.6h.6v-.5l-.6-.1v1.2M76.6 35h6.6M77 28v1l.2 .2 .5-.1v-1.1M77.5 35.5l-.3-.2a.65 .65 0 0 0-.5 .6 .65 .65 0 0 0 .5 .7l.3-.2M78 36l.6-.1v-.5l-.6-.1v1.3M78.1 29.4h.9M78.7 37.1h5.2v2.4h-5.2l-1.1-1.1zM79.2 35.3v1l.2 .3h.3l.2-.3v-1"/>
<path d="M79.8 38.4h.4l.2-.2-.1-.4h-.5v1.1M79.9 28.1a.45 .45 0 0 0-.7 .2v.7l.2 .2 .5-.1M80 38.4l.4 .5M80.2 36.7h.9M80.5 28v1.2h.5M81.2 36.6l.4-1.3 .4 1.3M81.4 36.2h.6M81.4 28v1.2M81.6 28.5l.5 .7M81.8 37.7l-1 1.6M82 37.4h1.2M82.1 37.8l.3 1.1 .2-.8 .2 .8 .3-1.1"/>
<path d="M82.1 28l-.7 .7M83.1 35.4l-.5-.1-.2 .3 .1 .2 .6 .3v.3l-.3 .2-.4-.1M117.9 37.1h4.6l1 1.3-1 1.1h-4.6zM117.9 39.5h4.6l1 1.3-1 1.2h-4.6zM117.9 34.7h4.6l1 1.2-1 1.2h-4.6zM117.9 27.3h4.6l1 1.3-1 1.2h-4.6zM117.9 29.8h4.6l1 1.3-1 1.2h-4.6zM117.9 32.3h4.6l1 1.1-1 1.3h-4.6zM118.6 37.8l.4 1.1 .5-1.1M118.6 35.3l.4 1.3 .5-1.3M118.6 28l.4 1.2 .5-1.2M118.6 30.5l.4 1.2 .5-1.2"/>
<path d="M118.6 32.8l.4 1.3 .5-1.3M119.7 38.9l.4-1.1 .4 1.1M119.7 36.6l.4-1.3 .4 1.3M119.7 29.2l.4-1.2 .4 1.2M119.7 31.7l.4-1.2 .4 1.2M119.7 34.1l.4-1.3 .4 1.3M119.8 31.3h.6M119.8 36.2h.6M119.8 38.6h.6M119.8 28.9h.6M119.8 33.8h.6M120.8 28.4l.4-.4v1.2"/>
<path d="M120.8 30.6h.7v.4l-.7 .7h.7M120.8 32.8h.7l-.3 .6h.3v.6h-.7M120.8 29.2h.7M121.2 35.3l-.4 .8h.8M121.4 35.7v.9M121.5 37.8h-.6l-.1 .6 .6-.1 .1 .6h-.7M22.3 57.8h14.2l1.1 1.2-1.1 1.3h-14.2zM24.6 44.4h11.9l1.1 1.2-1.1 1.3h-11.9zM24.7 59h.5l.2-.3-.2-.2h-.5v1.2h.5l.2-.1v-.4l-.3-.2M25.8 46.3v-1.3l.4 1 .4-1v1.3M26 59.7v-1.2l.3 .8 .5-.8v1.2M27.2 46.3v-1.3l.4 1 .4-1v1.3"/>
<path d="M27.3 59h.5M27.9 58.5h-.6v1.2h.6M28.4 59.7v-1.2l.5 .8 .4-.8v1.2M28.5 45v1.1l.3 .2h.2l.3-.2v-1.1M29.5 46.4h1M29.5 59.8h1M30.7 45a.65 .65 0 0 1 .8 .7 .65 .65 0 0 1-.8 .6zM30.7 58.5h.5a.66 .66 0 0 1 .3 .8 .66 .66 0 0 1-.8 .4zM31.8 45h.7M31.8 58.5h.7M32.2 45v1.3M32.2 58.5v1.2"/>
<path d="M32.8 46.3l.4-1.3 .3 1.3M32.8 59.7l.4-1.2 .3 1.2M32.8 46h.6M32.8 59.3h.6M34.6 45.2l-.1-.2a.6 .6 0 0 0-.6 .7 .6 .6 0 0 0 .7 .5v-.1M34.6 58.6l-.5-.1a.61 .61 0 0 0-.2 .8 .61 .61 0 0 0 .7 .3M35.2 45v1.3M35.2 58.5v1.2M35.4 45.6l.5 .7M35.4 59l.5 .7M35.9 45l-.7 .8M35.9 58.5l-.7 .7"/>
<path d="M74.6 42h9.3v2.4h-9.3l-1.1-1.2zM75.4 42.3h7.8M76 40.3l-.6-.1-.1 .3v.6l.1 .3 .6-.1M76.3 42.8l-.5-.1a.61 .61 0 0 0-.3 .8 .61 .61 0 0 0 .8 .3M76.5 40.8h.6v-.6h-.6v1.2M76.8 43.3l.7-.1v-.4l-.7-.1v1.2M77.7 40.2v.9l.2 .3 .5-.1v-1.1M78.1 42.7v1.1l.1 .1h.3l.2-.3v-.9M78.7 41.6h1M79 43.9h.9M79.9 40.2v.9l.2 .3 .5-.1v-1.1M80.3 42.7v1.2h.6"/>
<path d="M81.2 42.7h.5a.66 .66 0 0 1 .2 .8 .66 .66 0 0 1-.7 .4zM81.2 40.2h.5l.2 .3 .1 .4-.3 .5h-.5zM83.1 42.7h-.6l-.1 .1 .1 .4 .6 .1v.5h-.7M83.1 40.2h-.6a.47 .47 0 0 0 0 .5 .47 .47 0 0 0 .5 .2v.5h-.6M117.9 42h4.6l1 1.2-1 1.2h-4.6zM117.9 59h5.8l1 1.3-1 1.2h-5.8zM117.9 56.6h5.8l1 1.2-1 1.2h-5.8zM117.9 54.2h5.8l1 1.2-1 1.2h-5.8zM117.9 46.9h4.6l1 1.2-1 1.2h-4.6zM117.9 49.3h5.8l1 1.2-1 1.2h-5.8zM117.9 44.4h4.6l1 1.2-1 1.3h-4.6zM117.9 51.7h5.8l1 1.2-1 1.3h-5.8z"/>
<path d="M118.6 40.2l.4 1.2 .5-1.2M118.6 42.7l.4 1.2 .5-1.2M118.6 59.7l.4 1.2 .5-1.2M118.6 57.2l.4 1.3 .5-1.3M118.6 54.8l.4 1.2 .5-1.2M118.6 47.5l.4 1.3 .5-1.3M118.6 50l.4 1.1 .5-1.1M118.6 45l.4 1.3 .5-1.3M118.6 52.4l.4 1.2 .5-1.2M119.7 41.4l.4-1.2 .4 1.2M119.7 43.9l.4-1.2 .4 1.2M119.7 58.5l.4-1.3 .4 1.3"/>
<path d="M119.7 56l.4-1.2 .4 1.2M119.7 48.8l.4-1.3 .4 1.3M119.7 51.1l.4-1.1 .4 1.1M119.7 46.3l.4-1.3 .4 1.3M119.7 53.6l.4-1.2 .4 1.2M119.8 46h.6M119.8 41.1h.6M119.8 43.5h.6M119.8 58.2h.6M119.8 55.7h.6M119.8 48.3h.6M119.8 50.8h.6"/>
<path d="M119.8 53.3h.6M120.8 42.7h.8l-.5 1.2M120.8 57.6h.2l.2-.4v1.3M120.8 55.2l.4-.4v1.2M120.8 50.3l.4-.3v1.1M120.8 52.7l.4-.3v1.2M120.8 58.5h.7M120.8 56h.7M120.8 51.1h.7M120.8 53.6h.7M121.1 45.6l-.3-.3 .3-.3h.2l.2 .5-.7 .3v.3l.3 .2 .4-.2v-.4l-.2-.1M121.4 40.2l-.4 .1-.2 .8 .2 .3 .5-.1v-.5l-.2-.2h-.2l-.3 .3"/>
<path d="M121.5 48v.2l-.4 .1-.3-.3v-.3l.3-.2 .4 .2v.7l-.2 .3-.3 .1M121.9 57.2h.8l-.4 .5 .4 .1v.5l-.3 .2h-.3l-.2-.2M122 54.9l.2-.1 .4 .1 .1 .5-.8 .6h.8M122 52.7l.3-.3v1.2M122 53.6h.7M122.1 50h.3l.3 .2v.8l-.2 .1h-.4zM122.3 59.6l-.3 .9h.8M23.2 71.2h13.3l1.1 1.3-1.1 1.2h-13.3zM25.1 72h-.1a.46 .46 0 0 0-.7 .1v.7l.2 .3 .6-.1M25.4 71.9h.7M25.7 71.9v1.2M26.5 71.9v1.2h.6"/>
<path d="M28.1 72h-.7v.3l.7 .4-.1 .4h-.6M28.6 72.5h.6l.1-.5-.7-.1v1.2M29.5 73.2h1M30.7 71.9a.66 .66 0 0 1 .8 .4 .66 .66 0 0 1-.3 .8h-.5zM31.8 71.9h.7M32.2 71.9v1.2M32.8 73.1l.4-1.2 .3 1.2M32.8 72.7h.6M34.6 72a.61 .61 0 0 0-.7 .3 .61 .61 0 0 0 .2 .8l.5-.1M35.2 71.9v1.2M35.4 72.4l.5 .7M35.9 71.9l-.7 .7"/>
<path d="M64.8 68.7h4.6l1 1.3-1 1.2h-4.6zM65.8 69.4l.4 1.2 .4-1.2M65.8 69.1h3M67.1 70.1h.4l.2-.3-.1-.3-.5-.1v1.2M68.1 70.6l.4-1.2 .4 1.2M68.2 70.3h.5M117.9 73.7h5.8l1 1.1-1 1.3h-5.8zM117.9 66.4h5.8l1 1.2-1 1.2h-5.8zM117.9 68.7h5.8l1 1.3-1 1.2h-5.8zM117.9 71.2h5.8l1 1.3-1 1.2h-5.8zM117.9 63.9h5.8l1 1.2-1 1.3h-5.8zM117.9 61.5h5.8l1 1.2-1 1.2h-5.8z"/>
<path d="M117.9 76.1h5.8l1 1.2-1 1.3h-5.8zM117.9 78.6h5.8l1 1.2-1 1.1h-5.8zM118.6 74.3l.4 1.2 .5-1.2M118.6 67l.4 1.2 .5-1.2M118.6 69.4l.4 1.2 .5-1.2M118.6 71.9l.4 1.2 .5-1.2M118.6 64.6l.4 1.2 .5-1.2M118.6 62.1l.4 1.2 .5-1.2M118.6 76.7l.4 1.3 .5-1.3M118.6 79.2l.4 1.2 .5-1.2M119.7 75.5l.4-1.2 .4 1.2M119.7 68.2l.4-1.2 .4 1.2"/>
<path d="M119.7 70.6l.4-1.2 .4 1.2M119.7 73.1l.4-1.2 .4 1.2M119.7 65.8l.4-1.2 .4 1.2M119.7 60.9l.4-1.2 .4 1.2M119.7 63.3l.4-1.2 .4 1.2M119.7 78l.4-1.3 .4 1.3M119.8 72.7h.6M119.8 70.3h.6M119.8 75.2h.6M119.8 67.9h.6M119.8 65.4h.6M119.8 60.5h.6"/>
<path d="M119.8 63h.6M119.8 77.6h.6M120.8 74.4h.7v.4l-.7 .7h.7M120.8 67.3h.2l.2-.3v1.2M120.8 69.8h.2l.2-.4v1.2M120.8 72.2l.4-.3v1.2M120.8 64.9l.4-.3v1.2M120.8 60l.4-.3v1.2M120.8 62.5l.4-.4v1.2M120.8 76.9l.2-.2h.3l.2 .2v.4l-.7 .7h.7M120.8 79.3l.2-.1h.3l.2 .1v.4l-.7 .7h.7M120.8 68.2h.7"/>
<path d="M120.8 70.6h.7M120.8 73.1h.7M120.8 65.8h.7M120.8 60.9h.7M120.8 63.3h.7M121.9 67h.9l-.5 1.2M122 77.1l.3-.4v1.3M122 79.3l.4-.1 .3 .1v.4l-.8 .7h.8M122 78h.7M122.1 74.4l.4-.1 .2 .2v.8a.35 .35 0 0 1-.4 .2 .35 .35 0 0 1-.3-.4zM122.3 69.9h-.2l-.1-.2a.42 .42 0 0 1 .7-.2l-.1 .4-.5 .1v.6l.6-.1v-.4l-.3-.2M122.6 64.6l-.4 .1-.2 .8a.42 .42 0 0 0 .7 .2l-.1-.6a.36 .36 0 0 0-.6 .2"/>
<path d="M122.6 60.1v.8M122.7 72.4l-.4 .2h-.2l-.1-.5a.42 .42 0 0 1 .7-.1v.8l-.3 .3h-.3M122.7 62.1h-.6l-.1 .6 .2-.1 .4 .1 .1 .5h-.7M23.7 84.7h12.8l1.1 1.1-1.1 1.2h-12.8zM24.9 85.3v1.2M25.4 85.4l.3-.1 .5 .1v.9l-.3 .2h-.2l-.3-.2zM27.4 85.3h-.2a.6 .6 0 0 0-.5 .6 .6 .6 0 0 0 .6 .5h.1M27.8 85.3h.6M28.1 85.3v1.2M28.9 85.3v1.2h.6M29.5 86.6h1M30.7 85.3a.65 .65 0 0 1 .8 .6 .65 .65 0 0 1-.8 .6z"/>
<path d="M31.8 85.3h.7M32.2 85.3v1.2M32.8 86.5l.4-1.2 .3 1.2M32.8 86.1h.6M34.6 85.3h-.1a.64 .64 0 0 0-.6 .6 .64 .64 0 0 0 .6 .6l.1-.1M35.2 85.3v1.2M35.4 85.8l.5 .7M35.9 85.3l-.7 .6M55.6 98h5.3l1.1 1.2-1.1 1.3h-5.3zM56.8 98.6v1.3M57.4 99.3l.6-.1v-.5l-.6-.1v1.3M58.6 98.6v1.3h.6"/>
<path d="M59.7 98.7l.2-.1 .3 .3v.7l-.3 .3a.71 .71 0 0 1-.2-1.2zM79.2 88.3h4.7v2.4h-4.7l-1.1-1.2zM79.2 90.7h4.7v2.4h-4.7l-1.1-1.2zM79.2 85.8h4.7v2.5h-4.7l-1.1-1.3zM80.2 89.5h.4M80.2 91.9h.4M80.2 87h.4M80.8 88.9h-.6v1.3M80.8 91.4h-.6v1.1M80.8 86.5h-.6v1.2M82 89.1l-.5-.2-.3 .3v.6l.2 .3 .3 .1 .3-.2M82 91.4h-.1a.45 .45 0 0 0-.7 .2v.7l.2 .2h.6"/>
<path d="M82 86.6l-.6-.1-.2 .3 .1 .7 .2 .2 .5-.1M82.4 89.2l.3-.3v1.3M82.4 91.4h.7v.5l-.8 .6h.8M82.4 90.2h.7M82.5 86.6l.4-.1 .2 .2v.8l-.3 .2-.3-.1zM117.9 80.9h5.8l1 1.3-1 1.2h-5.8zM118.6 81.6l.4 1.2 .5-1.2M119 98h3.7l1.1 1.2-1.1 1.3h-3.7l-1.1-1.3zM119 95.6h3.7l1.1 1.2-1.1 1.2h-3.7l-1.1-1.2zM119 93.1h3.7l1.1 1.3-1.1 1.2h-3.7l-1.1-1.2zM119 90.7h3.7l1.1 1.2-1.1 1.2h-3.7l-1.1-1.2zM119 88.3h3.7l1.1 1.2-1.1 1.2h-3.7l-1.1-1.2z"/>
<path d="M119 85.8h3.7l1.1 1.2-1.1 1.3h-3.7l-1.1-1.3zM119.7 98.6h.4l.3 .4v.6l-.3 .3h-.4zM119.7 96.3h.5l.2 .2v.7l-.3 .2h-.4zM119.7 93.8h.4l.3 .3v.6l-.2 .3h-.5zM119.7 91.4h.4l.3 .2v.7l-.2 .2h-.5zM119.7 88.9l.5 .1 .2 .2v.6l-.3 .4h-.4zM119.7 86.5h.5l.2 .3v.6l-.3 .3h-.4zM119.7 82.8l.4-1.2 .4 1.2M119.7 80.4l.4-1.2 .4 1.2M119.8 82.5h.6M119.8 80h.6M120.8 93.8h.8l-.4 .4 .4 .3-.1 .5-.7-.1"/>
<path d="M120.8 81.7h.7v.4l-.7 .7h.7M120.9 91.4h.4l.3 .3-.8 .8h.8M120.9 89.2l.3-.3v1.3M120.9 86.7l.2-.2h.3a.91 .91 0 0 1-.1 1.2l-.4-.2zM120.9 90.2h.7M121.2 96.2l-.3 .8h.8M121.5 98.6h-.6v.6h.6v.6l-.4 .1-.2-.2M121.5 96.6v.8M121.9 81.6h.8l-.4 .4 .4 .2v.5h-.8M147.4 98h4.8l1.1 1.2-1.1 1.3h-4.8zM148.6 98.6a.64 .64 0 0 1 .7 .7 .64 .64 0 0 1-.7 .6zM148.6 95.6h3.6l1.1 1.2-1.1 1.2h-3.6z"/>
<path d="M148.6 93.1h3.6l1.1 1.3-1.1 1.2h-3.6zM148.6 90.7h3.6l1.1 1.2-1.1 1.2h-3.6zM148.6 85.8h3.6l1.1 1.2-1.1 1.3h-3.6zM148.6 88.3h3.6l1.1 1.2-1.1 1.2h-3.6zM149.8 99l.3-.4v1.3M149.8 96.3h.4a.66 .66 0 0 1 .2 .7 .66 .66 0 0 1-.6 .4zM149.8 93.8a.66 .66 0 0 1 .6 .4 .66 .66 0 0 1-.2 .8h-.4zM149.8 91.4a.66 .66 0 0 1 .6 .4 .66 .66 0 0 1-.2 .7h-.4zM149.8 86.5h.4a.66 .66 0 0 1 .2 .8 .66 .66 0 0 1-.6 .4zM149.8 88.9a.64 .64 0 0 1 .7 .6 .64 .64 0 0 1-.7 .7zM149.8 99.9h.6M150.9 98.6h.7l-.4 .5 .4 .1v.5l-.2 .2h-.4l-.1-.2"/>
<path d="M150.9 94.1l.3-.3v1.2M150.9 91.4h.7v.5l-.7 .6h.7M150.9 88.9h.7l-.4 .5 .4 .1v.5l-.2 .2h-.4l-.1-.2M150.9 95h.7M151 96.3h.4l.2 .1v.8l-.4 .2a.84 .84 0 0 1-.2-1.1zM151.2 86.4l-.3 .9h.7M151.5 86.9v.8M47.7 120h10.7l1.1 1.2-1.1 1.2h-10.7zM55.6 100.5h5.3l1.1 1.2-1.1 1.2h-5.3zM55.6 102.9h5.3l1.1 1.2-1.1 1.2h-5.3zM56.8 101.1v1.3M56.8 103.5v1.2"/>
<path d="M57.4 101.8l.6-.1v-.5l-.6-.1v1.3M57.4 104.1h.6v-.5l-.6-.1v1.2M58.6 101.1v1.3h.6M58.6 103.5v1.2h.6M59.5 101.4h.2l.2-.3v1.3M59.5 103.6h.7v.5l-.7 .6h.7M59.5 102.4h.7M67.6 117.5h5.5l1 1.2-1 1.3h-5.5zM68.6 117.9h4M68.7 118.7h.7M68.7 118.2v1.2M69.4 118.2v1.2"/>
<path d="M69.8 119.4l.4-1.2 .4 1.2M69.9 119h.6M71 118.2v1.2h.6M71.9 118.2h.7M72.2 118.2v1.2M74.6 115.1h10.7l1 1.2-1 1.2h-10.7zM75.5 115.4h9.2M76.5 115.8l-.6-.1-.2 .3v.7a.55 .55 0 0 0 .8 .1M77 116.3h.6v-.6h-.6v1.2M78.1 115.7v1l.3 .2 .4-.1v-1.1M79.2 117.1h.9M80.3 116.3h.5l.2-.2-.1-.4h-.6v1.2l.7-.1v-.4l-.2-.1"/>
<path d="M81.6 116.3h.4M82.1 115.7h-.5v1.2h.5M82.7 116.3h.5l.2-.1-.2-.5h-.5v1.2M83 116.3l.4 .6M83.9 116.3h.6l.1-.5-.7-.1v1.2M84.2 116.3l.4 .6M119 100.5h3.7l1.1 1.2-1.1 1.2h-3.7l-1.1-1.2zM119 102.9h3.7l1.1 1.2-1.1 1.2h-3.7l-1.1-1.2zM119 105.3h3.7l1.1 1.2-1.1 1.3h-3.7l-1.1-1.3zM119 107.8h3.7l1.1 1.2-1.1 1.2h-3.7l-1.1-1.2zM119 110.2h4.9l1 1.2-1 1.2h-4.9l-1.1-1.2zM119 115.1h4.9l1 1.2-1 1.2h-4.9l-1.1-1.2z"/>
<path d="M119 112.6h4.9l1 1.3-1 1.2h-4.9l-1.1-1.2zM119 120h4.9l1 1.2-1 1.2h-4.9l-1.1-1.2zM119 117.5h4.9l1 1.2-1 1.3h-4.9l-1.1-1.3zM119.7 101.1h.4l.3 .3v.6l-.3 .4h-.4zM119.7 103.5h.4l.3 .3v.7l-.2 .2h-.5zM119.7 106h.5l.2 .3v.6l-.3 .3h-.4zM119.7 108.4h.4l.3 .3v.6l-.3 .3h-.4zM119.7 110.8h.4l.3 .4v.6l-.3 .3h-.4zM119.7 115.7h.5l.2 .3v.7l-.3 .2h-.4zM119.7 113.3h.4l.3 .2v.7l-.2 .3h-.5zM119.7 118.2h.5l.2 .2v.7l-.3 .3h-.4zM120.8 103.5h.9l-.5 1.2"/>
<path d="M120.9 111.2l.3-.4v1.3M120.9 116.1l.3-.4v1.2M120.9 113.6l.3-.3v1.2M120.9 118.5l.3-.3v1.2M120.9 112.1h.7M120.9 116.9h.7M120.9 114.5h.7M120.9 119.4h.7M121.2 106.5l-.3-.2v-.2l.6-.1a.44 .44 0 0 1-.1 .5 .44 .44 0 0 1-.4 .1v.5a.35 .35 0 0 0 .5-.1 .35 .35 0 0 0-.2-.5M121.5 101.1h-.3l-.3 .3v.8l.3 .2 .3-.1v-.7h-.5l-.1 .2M121.6 109l-.1 .1-.6-.1 .1-.5 .3-.1 .2 .1a.85 .85 0 0 1-.3 1.1h-.2M122 115.8l.6-.1 .2 .3-.8 .9h.8"/>
<path d="M122 113.6l.4-.3v1.2M122 118.2h.8l-.5 .4 .4 .1v.6h-.7M122 114.5h.8M122.1 111.1l.2-.3a.68 .68 0 0 1 .5 .7 .68 .68 0 0 1-.5 .6 .77 .77 0 0 1-.2-1zM147.4 100.5h4.8l1.1 1.2-1.1 1.2h-4.8zM147.4 102.9h4.8l1.1 1.2-1.1 1.2h-4.8zM148.6 120h3.6l1.1 1.2-1.1 1.2h-3.6zM148.6 101.1a.64 .64 0 0 1 .7 .6 .64 .64 0 0 1-.7 .7zM148.6 103.5a.66 .66 0 0 1 .6 .5 .66 .66 0 0 1-.2 .7h-.4zM148.6 115.1h3.6l1.1 1.2-1.1 1.2h-3.6zM148.6 117.5h3.6l1.1 1.2-1.1 1.3h-3.6zM149.8 101.4l.3-.3v1.3"/>
<path d="M149.8 103.9l.3-.4v1.2M149.8 115.7h.4a.66 .66 0 0 1 .2 .8 .66 .66 0 0 1-.6 .4zM149.8 118.2h.4a.66 .66 0 0 1 .2 .7 .66 .66 0 0 1-.6 .5zM149.8 102.4h.6M149.8 104.7h.6M151.2 101l-.3 .9h.7M151.5 118.2l-.5 .1-.1 .8 .2 .3 .5-.1v-.6l-.5-.1-.2 .3M151.5 101.5v.9M151.6 103.5h-.6l-.1 .6 .1-.1h.4l.2 .1v.5h-.7M151.6 115.7h-.6l-.1 .6 .1-.1h.4l.2 .1v.5h-.7M153.3 116.3h1.2M153.3 118.7h1.2"/>
<path d="M160.6 116.3h2.5M163.1 116.3h.1M163.1 113.9l-.8 1.2M163.1 113.9l.6 1.2M163.1 113.9v2.4M48.8 120.2h9.1M49.6 120.7l-.2-.1a.6 .6 0 0 0-.5 .6 .6 .6 0 0 0 .6 .5h.1M50.1 121.2h.7l.1-.4-.3-.2h-.5v1.2M51.4 120.6v1.1l.2 .1h.2l.3-.2v-1M52.3 121.9h1M53.6 121.2h.5l.1-.5-.6-.1v1.2h.4l.3-.4-.4-.2M54.8 121.2h.4"/>
<path d="M55.4 120.6h-.6v1.2h.6M55.9 121.2h.7v-.5l-.2-.1h-.5v1.2M56.2 121.2l.4 .6M57.1 121.2h.6l.1-.4-.2-.2h-.5v1.2M57.4 121.2l.4 .6M78.4 122.4h6.9l1 1.2-1 1.2h-6.9l-1-1.2zM79.4 122.7h5.3M79.6 123.7h.5l.2-.3v-.3l-.7-.1v1.2M79.9 123.7l.4 .5M80.9 123.6h.3M81.4 123h-.5v1.2h.5M82.5 123.1l-.4-.1-.2 .3 .1 .2 .5 .3v.3l-.6 .1"/>
<path d="M83.1 123.6h.4M83.6 123h-.5v1.2h.5M84 123h.7M84.3 123v1.2M103.4 133.5h2.3v8.6l-1.1 1-1.2-1zM104 139.2l1.2 .2-.9 .3 .9 .3-1.2 .2M104 135.3h1.2M104 134.6l.7 .7M104.1 136l.7-.2 .4 .2v.3l-.1 .3h-.7l-.3-.1zM104.6 138.8v-.5l-.4-.3-.2 .3v.5h1.2M105.2 138l-.6 .4M105.2 134.6l-.7 .5"/>
<path d="M105.3 136.9v.9M119 122.4h4.9l1 1.2-1 1.2h-4.9l-1.1-1.2zM119.7 120.6h.5l.2 .3v.6l-.3 .3h-.4zM119.7 123h.4l.3 .4v.5l-.2 .3h-.5zM120.9 120.9l.3-.3v1.2M120.9 123.4l.3-.4v1.2M120.9 121.8h.7M120.9 124.2h.7M122.3 120.6l-.3 .8h.8M122.6 121v.8M122.7 123h-.6l-.1 .6 .6-.1 .2 .2v.3l-.2 .2-.6-.1M147.4 132.2h4.8l1.1 1.1-1.1 1.2h-4.8z"/>
<path d="M147.4 127.3h4.8l1.1 1.1-1.1 1.3h-4.8zM147.4 129.7h4.8l1.1 1.2-1.1 1.3h-4.8zM148.6 132.8a.64 .64 0 0 1 .7 .6 .64 .64 0 0 1-.7 .6zM148.6 124.8h3.6l1.1 1.3-1.1 1.2h-3.6zM148.6 122.4h3.6l1.1 1.2-1.1 1.2h-3.6zM148.6 127.9h.4a.66 .66 0 0 1 .2 .8 .66 .66 0 0 1-.6 .4zM148.6 130.3a.64 .64 0 0 1 .7 .6 .64 .64 0 0 1-.7 .7zM149.8 133.1l.3-.3v1.2M149.8 120.6a.64 .64 0 0 1 .7 .6 .64 .64 0 0 1-.7 .6zM149.8 125.5a.66 .66 0 0 1 .6 .4 .66 .66 0 0 1-.2 .8h-.4zM149.8 123a.66 .66 0 0 1 .6 .5 .66 .66 0 0 1-.2 .7h-.4zM149.8 128.3l.3-.4v1.2"/>
<path d="M149.8 130.7l.3-.4v1.3M149.8 134h.6M149.8 129.1h.6M149.8 131.6h.6M150.9 132.9l.1-.1h.4l.2 .1v.4l-.7 .7h.7M150.9 120.6h.7l-.5 1.2M150.9 130.7l.3-.4v1.3M150.9 131.6h.7M151 127.9h.4l.2 .2v.8l-.4 .2a.84 .84 0 0 1-.2-1.2zM151.1 123.5l-.2-.1 .1-.3h.6v.3l-.5 .1-.2 .3 .1 .4 .6-.1v-.4l-.2-.2M151.6 126l-.2 .2h-.3l-.2-.2 .1-.4h.6v.8l-.2 .3h-.4M153.3 130.9h2.4"/>
<path d="M153.3 133.3h2.4M153.3 121.2h1.2M153.3 123.6h1.2M153.3 126.1h1.2M153.3 128.4h1.2M159.6 130.9h.8v2.4h-.8M160.2 130.7h.4v.4h-.4zM104.6 141.3v-.6h-.5l-.1 .6h1.2M173.4 151.6h5.5v2.5h-5.5l-1.1-1.3zM174.2 151.9h4M174.4 152.2v1.3M174.9 152.9l.7-.1 .1-.3-.3-.3h-.5v1.3"/>
<path d="M175.3 152.9l.4 .6M176.2 152.4l.2-.2 .5 .2 .1 .7-.4 .4-.4-.2zM176.4 153.2l.6 .4M177.4 152.2h.7l-.5 1.3M57.1 171.1h7l1.1 1.2-1.1 1.3h-7zM58.6 171.9l-.5-.1a.61 .61 0 0 0-.3 .8 .61 .61 0 0 0 .8 .3M59.1 171.8v1.2h.6M60.1 171.8v1.2M60.3 172.3l.5 .7M60.8 171.8l-.7 .7M61.5 171.7l-.2 .8h.8M61.9 172.1v.9"/>
<path d="M62.6 171.8a.61 .61 0 0 1 .6 .5 .61 .61 0 0 1-.4 .7 .75 .75 0 0 1-.2-1.2zM90.5 169.9h6.8v2.4h-6.8l-1.1-1.2zM91.4 170.2h5.2M91.5 171.2h.4l.3-.3-.3-.4h-.4v1.3M91.8 171.2l.4 .6M92.7 171.1h.4M93.3 170.5h-.6v1.3h.6M94.5 170.6l-.5-.1-.3 .3 .1 .2 .7 .4-.3 .4-.5-.1M95 171.1h.3M95.6 170.5h-.6v1.3h.6M95.9 170.5h.7M96.3 170.5v1.3"/>
<path d="M107.6 162.6h5.5v2.4h-5.5l-1.1-1.2zM108.5 162.9h3.9M108.6 163.2v1.2M108.6 163.8h.7M109.3 163.2v1.2M109.7 164.4l.4-1.2 .4 1.2M109.8 164.1h.6M110.9 163.2v1.2h.6M111.8 163.2h.6M112.1 163.2v1.2"/>
<circle cx="23.8" cy="59.1" r=".57"/>
</g>
<path d="M155.7 132.6h3.9v1.6h-3.9z" fill="none" stroke="#910000" stroke-width=".25"/>
<path d="M153.5 117.2h.8l-.5 .5 .5 .2v.3l-.2 .2-.6-.1M153.6 114.9l.4-.2 .3 .4-.8 .9h.8M153.8 119.5l-.2 .9h.7M161.5 115.1h.1l.2-.4v1.3M161.5 116h.6M153.5 126.9h.8l-.5 1.3M153.8 129.9l-.2-.1v-.3h.6v.3l-.6 .2 .1 .6h.4l.2-.2v-.3l-.3-.2M154.1 124.5h-.3l-.2 .3v.8l.4 .1 .3-.2v-.3l-.3-.2h-.4v.2M154.1 120.1v.7M154.2 122.1h-.6v.6l.4-.2 .3 .3-.1 .4h-.6M154.3 132.3l-.3 .3-.4-.2v-.5l.5-.1a.94 .94 0 0 1 0 1.1l-.4 .1" fill="none" stroke="#b90000" stroke-width=".21"/>
<g fill="none" stroke="#090" stroke-width=".21">
<path d="M48.5 32.3h3.7M52.2 31.1v54.7M83.9 38.4h2.4M83.9 35.9h2.4M83.9 28.6h2.4M115.6 38.4h2.3M115.6 35.9h2.3M115.6 28.6h2.3M115.6 33.4h2.3M115.6 31.1h2.3M52.2 45.6h34.1M63.2 57.8h23.1"/>
<path d="M83.9 43.2h2.4M83.9 40.8h2.4M86.3 52.9h-8.5v4.9M115.6 45.6h2.3M115.6 57.8h2.3M115.6 43.2h2.3M115.6 40.8h2.3M115.6 52.9h2.3M115.6 48.1h2.3M115.6 50.5h2.3M115.6 55.4h2.3M70.4 70h15.9"/>
<path d="M75.4 70v1.2M115.6 74.8h2.3M115.6 77.3h2.3M115.6 72.5h2.3M115.6 70h2.3M115.6 79.8h2.3M115.6 65.1h2.3M115.6 67.6h2.3M115.6 60.3h2.3M115.6 62.7h2.3M26.6 99.2h6.1M31.5 99.2v13.4h1.2"/>
<path d="M62 99.2h24.3M64.3 99.2v7.3M83.9 89.5h2.4M83.9 91.9h2.4M83.9 87h2.4M115.6 99.2h2.3M115.6 96.8h2.3M115.6 89.5h2.3M115.6 94.4h2.3M115.6 91.9h2.3M115.6 87h2.3M115.6 82.2h2.3"/>
<path d="M62 104.1h24.3M62 101.7h24.3M64.3 111.4h15.9M71.7 101.7v4.8M74.1 118.7h12.2M80.2 104.1v2.4M115.6 104.1h2.3M115.6 101.7h2.3M115.6 109h2.3M115.6 106.5h2.3M115.6 111.4h2.3M115.6 113.9h2.3"/>
<path d="M115.6 116.3h2.3M115.6 118.7h2.3M59.5 121.2h2.5v2.4M115.6 121.2h2.3M115.6 123.6h2.3M176.4 138.3h3.7M194.7 138.3h14.6v14.5M93.6 151.6h26.8M93.6 144.3h11M104.6 143.1v2.4M104.6 150.4v2.4M135 151.6h18.3v12.2h-3.7"/>
<path d="M178.9 152.8h20.7M187.4 146.7v6.1M29 165h-7.2v7.3M36.3 172.3h7.4M48.5 172.3h8.6M82.6 179.7h50M97.3 171.1h18.3M99.7 169.9v1.2M113.1 163.8h26.8M127.7 160.2v3.6M82.6 184.5h50"/>
</g>
<g fill="none" stroke="#0000ca" stroke-width=".21">
<path d="M128.1 29.1v.2M128.1 29.5v.9M128.8 27.2v1.2l-.7-1.2v1.2M129.1 29.6l-.3-.1-.2 .2 .2 .3 .3 .1v.2h-.5M129.4 28.3v.1M130 27.8l.6-.1v-.4l-.2-.1h-.4v1.2h.6v-.4l-.2-.2M130.6 29.7l.2-.2 .3 .2v.7M130.6 29.5v.9M131.1 28.3v.1M131.7 29.7l.2-.2 .3 .2v.5l-.1 .2-.4-.2zM132.6 29.5h.5M132.8 29.1v1.1l.3 .2"/>
<path d="M133.3 27.3l-.5-.1-.2 .2 .1 .3 .5 .2 .1 .2-.2 .3h-.5M133.9 27.2v.1M133.9 27.6v.8M134.4 27.7l.4-.1 .2 .2v.6M134.4 29.6l.4-.1 .2 .2v.7M134.4 27.6v.8M135 29.9h-.5l-.1 .2 .1 .3 .5-.1M136.1 27.7a.36 .36 0 0 0-.6 .2v.5h.6M136.5 28l.6-.1-.2-.3-.4 .2v.5l.1 .1h.4M136.5 29.7l.1-.2 .4 .2v.7M136.5 29.5v.9M137.5 30l.6-.1-.2-.4-.4 .2v.5l.2 .2 .3-.1"/>
<path d="M138.3 27.6h.6M138.5 27.2v1.1l.4 .1M138.5 30l.6-.1-.2-.4-.4 .2v.5l.2 .2 .3-.1M139.3 27.7l.3-.1 .2 .2v.6M139.3 27.2v1.2M140.1 29.6l-.3-.1-.2 .2v.5l.2 .2 .3-.1M140.1 29.1v1.3M140.3 28l.6-.1-.2-.3-.4 .2v.5l.2 .1h.3M141.5 29.5h.5M141.6 29.1v1.1l.4 .2M142.4 29.6l.3-.1 .2 .2v.5l-.2 .2-.4-.3zM142.8 27.2l-.4 .1-.2 .9 .3 .2 .4-.1-.1-.6h-.4l-.2 .2"/>
<path d="M143.7 27.7h-.2a.31 .31 0 0 1 .1-.4 .31 .31 0 0 1 .4 0v.4h-.3l-.3 .2 .1 .5h.2l.4-.2v-.3l-.3-.2M144.4 29.6l.4-.1 .1 .2v.5l-.1 .2-.4-.1M144.4 29.5v1.3M144.9 27.2a.68 .68 0 0 1 .4 .6 .68 .68 0 0 1-.4 .6l-.3-.2v-.8zM145.5 29.5v.8l.4 .1 .1-.2M145.7 27.5h.2l.1-.3v1.2M145.7 28.4h.7M146 29.5v.9M146.6 29.1v1.2l.2 .1M147.1 27.2a.68 .68 0 0 1 .5 .6 .68 .68 0 0 1-.5 .6l-.2-.5 .1-.6zM147.2 29.1v1.1l.2 .2M147.9 29.9h.9"/>
<path d="M149 27.2v.1M149 27.6v.8M149.3 29.5v.7l.2 .2 .4-.2M149.9 29.5v.9M150 27.7l-.2-.1-.3 .3 .4 .1 .2 .3-.2 .1h-.4M150.4 29.6l.5-.1 .1 .2v.5l-.1 .2-.5-.1M150.4 29.5v1.3M151.4 27.6h.4M151.6 27.2v1.2h.2M152.2 27.7l.4-.1 .1 .2v.6M152.2 27.2v1.2M152.3 29.5h.5"/>
<path d="M152.5 29.1v1.1l.3 .2M153.2 28l.6-.1-.1-.3-.5 .2v.5l.2 .1h.4M153.2 29.7l.2-.2 .4 .2v.7M153.2 29.1v1.3M154.3 30l.6-.1-.2-.4-.4 .2v.5l.1 .2 .4-.1M155.3 27.7h.5v.7h-.4l-.1-.1zM156.4 27.7h.5v.7M156.4 27.6v.8M157 29.3l-.3-.2a.6 .6 0 0 0-.5 .7 .6 .6 0 0 0 .7 .5l.1-.1M157.5 27.2v1.1l.1 .1M157.5 29.8l.7-.1v-.3l-.2-.3h-.5v1.3M158 27.6l.3 .8"/>
<path d="M158.6 27.6l-.4 1.1-.2 .1M158.7 29.1v1.1l.2 .2 .4-.1 .1-.2v-1M160 27.7l.4-.1 .2 .3v.3l-.2 .2h-.4M160 27.2v1.2M160.9 29.6l.4-.1 .2 .2v.7M161.1 27.6v.8h.4l.1-.1M161.5 29.9h-.5l-.1 .2 .1 .3 .5-.1M161.6 27.6v.8M162.6 29.6l-.4-.1-.2 .3v.5h.6M162.6 29.1v1.3M162.6 27.7l-.3-.1-.2 .2 .2 .2 .3 .1v.3h-.5M163.7 29.6l-.4-.1-.2 .3v.5h.6"/>
<path d="M163.7 29.1v1.3M164.1 27.7l.4-.1 .2 .2v.6M164.1 27.6v.8M164.3 29.5v.9M164.6 29.5l-.3 .3M164.7 27.8l.1-.2 .4 .2v.6M164.9 30l.6-.1-.1-.4-.5 .2v.5l.2 .2 .3-.1M165.8 27.7l.3-.1 .2 .2v.6M166.3 27.9a.46 .46 0 0 0-.6 .4l.2 .1h.4M166.5 29.6l-.4-.1-.2 .3 .6 .4-.2 .2-.4-.1M167.2 27.7l-.2-.1-.2 .3 .5 .4-.2 .1h-.3M167.4 29.6l-.3-.1-.1 .3 .5 .4-.2 .2-.3-.1"/>
<path d="M167.6 27.6h.5M167.8 27.2v1.1l.3 .1M168.5 28l.6-.1-.2-.3-.4 .1v.7h.5M168.9 29.1v1.1l.2 .2M169.6 29.1v.2M169.6 27.6v.8M169.6 29.5v.9M169.9 27.6l-.3 .3M170.2 29.7l.1-.2 .4 .2v.7M170.2 29.5v.9M170.3 28.4v.2M171.2 30l.6-.1-.2-.4-.4 .2v.5l.2 .2 .3-.1"/>
<path d="M171.6 27.6h.5M171.9 27.2v1.2h.2M172.5 27.7l.4-.1 .2 .2v.6M172.5 27.2v1.2M172.7 29.6l-.3-.1-.2 .2 .2 .3 .3 .1v.2h-.5M173.6 28l.6-.1-.2-.3-.4 .2v.5l.1 .1h.4M174.1 29.5h.4M174.2 29.1v1.2l.3 .1M174.7 27.6v.8M174.8 29.8l.5-.3 .2 .3v.3l-.4 .3-.3-.3zM175 27.6l-.3 .3M175.3 28l.6-.1-.1-.3-.5 .2v.5l.2 .1h.3"/>
<path d="M176.8 29.1l.4 1.3 .3-1.3M178.5 29.6l-.4-.1-.2 .3v.3l.2 .3 .4-.1M179.6 29.6l-.4-.1-.2 .2 .1 .6h.5M180.1 30.2v.2M128.7 167.8l.3 1.2 .5-1.2M129.7 168.1h.4M130.1 167.8l-.2 .2v1M130.6 168.3h.9M130.6 168.7h.9M132.2 167.8a.61 .61 0 0 1 .6 .5 .61 .61 0 0 1-.5 .7l-.3-.5zM133.3 168.9v.1M134 167.7l-.2 .9h.7"/>
<path d="M134.4 168.1v.9M135.5 167.8h-.5v.5l.4-.1 .2 .3-.1 .4h-.5M136.2 167.8h.4l.1 .2v.7l-.1 .2a.6 .6 0 0 1-.6-.4 .6 .6 0 0 1 .2-.7z"/>
</g>
<path d="M85.7 54.8l1.2 1.2M86.9 54.8l-1.2 1.2M85.7 67l1.2 1.2M85.7 64.5l1.2 1.2M86.9 67l-1.2 1.2M86.9 64.5l-1.2 1.2M51.6 98.6l1.1 1.2M52.7 98.6l-1.1 1.2M51.6 112.1l1.1 1.1M52.7 112.1l-1.1 1.1" fill="none" stroke="#00008a" stroke-width=".21"/>
<g fill="#090">
<circle cx="64.3" cy="99.2" r=".47"/>
<circle cx="31.5" cy="99.2" r=".47"/>
<circle cx="29" cy="165" r=".47"/>
<circle cx="94.8" cy="184.5" r=".47"/>
<circle cx="94.8" cy="179.7" r=".47"/>
<circle cx="121.6" cy="184.5" r=".47"/>
<circle cx="109.5" cy="184.5" r=".47"/>
<circle cx="121.6" cy="179.7" r=".47"/>
<circle cx="104.6" cy="144.3" r=".47"/>
<circle cx="99.7" cy="171.1" r=".47"/>
<circle cx="109.5" cy="179.7" r=".47"/>
<circle cx="115.6" cy="163.8" r=".47"/>
<circle cx="104.6" cy="151.6" r=".47"/>
<circle cx="149.6" cy="163.8" r=".47"/>
<circle cx="127.7" cy="163.8" r=".47"/>
<circle cx="209.3" cy="152.8" r=".47"/>
<circle cx="187.4" cy="152.8" r=".47"/>
<circle cx="80.2" cy="104.1" r=".47"/>
<circle cx="71.7" cy="101.7" r=".47"/>
<circle cx="64.3" cy="111.4" r=".47"/>
<circle cx="71.7" cy="111.4" r=".47"/>
<circle cx="52.2" cy="45.6" r=".47"/>
<circle cx="52.2" cy="59" r=".47"/>
<circle cx="52.2" cy="32.3" r=".47"/>
<circle cx="52.2" cy="72.5" r=".47"/>
<circle cx="77.8" cy="57.8" r=".47"/>
<circle cx="75.3" cy="70" r=".47"/>
</g>
<path d="M114.6 149.2h.5l.2-.2v-.3l-.2-.2h-.5v1.3M115.9 149h.5v.6l-.2 .2-.4-.3zM116.8 148.9l.3 .9 .2-.6 .2 .6 .3-.9M118.2 149.3l.6-.1-.2-.3-.4 .2v.5l.2 .2 .3-.1M119.3 148.9v.9M119.6 148.9l-.3 .3" fill="none" stroke="#910089" stroke-width=".21"/>
<g fill="none" stroke="#006665" stroke-width=".21">
<path d="M99.3 19h.9M99.8 18.5v.9M101.4 18.2h-.6v.6l.5-.2 .2 .3-.2 .5-.5-.1M101.9 18.2l.4 1.2 .3-1.2M41.1 38.9h.9l-.6 1.2M42.2 36.5v.9l.3 .3 .4-.1 .1-.2v-.9M42.7 38.9l-.4 .8h.8M42.9 39.3v.8M43.5 36.6l.6-.1 .1 .3-.8 .9h.8M43.5 39.8h.6M44.8 36.5l.4 .1a.66 .66 0 0 1-.2 1.1 .84 .84 0 0 1-.2-1.2zM45.3 39l-.2-.1a.6 .6 0 0 0-.6 .6 .6 .6 0 0 0 .8 .5"/>
<path d="M45.6 38.9h.8M45.8 36.6l.6-.1 .1 .5-.8 .7h.8M46 38.9v1.2M46.8 37.7l.4-1.2 .5 1.2M47 38.9a.68 .68 0 0 1 .4 .6 .68 .68 0 0 1-.4 .6l-.3-.2v-.8zM47 37.3h.6M48.5 38.9h-.6l-.1 .6h.7l.1 .4-.3 .2h-.3l-.2-.1M50.6 21.3h1M51.1 20.9v.9M52.7 20.7h-.5l-.1 .5h.6v.6h-.6M53.1 20.7l.4 1.1 .4-1.1M54.9 27.3h.5l.1-.3-.6-.2v1.1"/>
<path d="M55.2 27.3l.3 .6M55.3 29.1l-.4 .9h.8M55.5 29.5v.9M55.9 26.9l.3-.1 .3 .3-.7 .8h.7M56 29.1h.9l-.5 1.3M56.8 27l.3-.2 .2 .2v.6l-.2 .3-.3-.3zM57.6 29.1a.68 .68 0 0 1 .4 .7 .68 .68 0 0 1-.4 .6l-.3-.3v-.7zM57.7 27.1l.3-.3v1.1M57.7 27.9h.5M58.5 29.8l.6-.1 .1-.4-.7-.2v1.3M58.8 29.8l.4 .6M103.4 24.3v-1.3l.4 1 .3-1v1.3"/>
<path d="M103.4 20.7v.9a.35 .35 0 0 0 .3 .3 .35 .35 0 0 0 .4-.3v-.9M104.6 20.7h.6v.5l-.6 .6h.6M105.5 23.2l-.4-.2-.4 .4v.6l.2 .2 .3 .1 .3-.2M105.8 20.7h.5l.1 .1v.8l-.2 .2h-.4zM106.5 23a.72 .72 0 0 0-.6 .6 .72 .72 0 0 0 .3 .7l.4-.2v-.5l-.4-.1-.3 .3M106.9 21l.4-.3v1.1M106.9 21.8h.7M107.3 23.6l-.2-.4 .2-.2 .4 .1v.4l-.6 .2v.4l.2 .2 .4-.1 .1-.2-.1-.4h-.2M108.4 23.1a.61 .61 0 0 1 .6 .5 .61 .61 0 0 1-.4 .7 .71 .71 0 0 1-.2-1.2zM109.4 23.4h.2l.1-.4v1.3M109.4 24.3h.7M110.8 23a.68 .68 0 0 1 .5 .7 .68 .68 0 0 1-.5 .6l-.2-.5 .1-.6z"/>
<path d="M41.1 52.3h.9l-.6 1.2M42.2 49.9v1l.1 .2 .5-.1v-1.1M42.7 52.2l-.4 .9h.8M42.9 52.7v.8M43.4 53.5l.4-1.2 .4 1.2M43.4 40.1l.4-1.2 .4 1.2M43.4 50l.5-.1 .2 .3-.8 .9h.8M43.5 53.2h.6M44.7 50l.3-.1a.84 .84 0 0 1 .1 1.2l-.4-.1a.78 .78 0 0 1 0-1zM45.3 52.4l-.5-.1a.61 .61 0 0 0-.2 .8 .61 .61 0 0 0 .7 .3M45.6 52.3h.8M45.7 50h.7v.4l-.8 .7h.8"/>
<path d="M46 52.3v1.2M46.7 52.5l.2-.2h.3a.86 .86 0 0 1 0 1.2l-.5-.2zM46.9 50.5l.6-.1v-.4l-.6-.1v1.2h.6l.2-.5-.4-.1M48.5 52.3h-.6l-.1 .6 .2-.2h.3l.3 .3-.1 .4h-.7M61.5 48.2h1M62.1 47.7v.9M63.7 47.4h-.6v.6l.5-.1 .2 .2v.3l-.2 .2-.5-.1M64.1 47.4l.4 1.2 .4-1.2M65.9 56.6h.5l.1-.3-.2-.3h-.4v1.1M66 53.8l.3-.3v1.2M66 54.7h.6M66.1 56.6l.4 .5"/>
<path d="M66.8 56.1l.4-.1 .2 .3-.6 .8h.6M67.2 53.6a.61 .61 0 0 1 .7 .4 .61 .61 0 0 1-.3 .7h-.4l-.1-.2v-.5zM67.8 56.1a.38 .38 0 0 1 .5 .1 .38 .38 0 0 1 0 .4l-.2 .5a.58 .58 0 0 1-.3-1zM68.3 53.5v1.2M68.5 54l.5 .7M69 53.5l-.7 .7M69.3 56.5l-.1 .1h-.5v-.1a.34 .34 0 0 1 .4-.5l.1 .1a.73 .73 0 0 1-.2 1h-.3M41.1 65.7h.9l-.6 1.2M41.1 79.1h.9l-.6 1.2M42.2 63.2v1.1l.2 .2 .4-.2v-1.1M42.2 76.6v1l.2 .3 .4-.2v-1.1M42.7 65.6l-.4 .9h.8"/>
<path d="M42.7 79l-.4 .9h.8M42.9 66.1v.8M42.9 79.5v.8M43.4 66.9l.4-1.2 .4 1.2M43.4 63.4l.5-.2 .2 .4-.8 .9h.8M43.4 76.8l.5-.2 .2 .4-.8 .9h.8M43.5 66.5h.6M43.5 79.9h.6M44.7 63.3a.61 .61 0 0 1 .7 .5 .61 .61 0 0 1-.4 .7 .71 .71 0 0 1-.3-1.2zM44.7 76.7a.61 .61 0 0 1 .7 .5 .61 .61 0 0 1-.4 .7 .71 .71 0 0 1-.3-1.2zM45.3 65.8a.61 .61 0 0 0-.8 .3 .61 .61 0 0 0 .3 .8l.5-.1M45.3 79.2l-.2-.1a.64 .64 0 0 0-.6 .6 .64 .64 0 0 0 .6 .6l.2-.1"/>
<path d="M45.6 65.7h.8M45.6 79.1h.8M45.7 63.4l.2-.2h.3l.2 .2v.4l-.8 .7h.8M45.7 76.8l.2-.2h.3l.2 .2v.4l-.8 .7h.8M46 65.7v1.2M46 79.1v1.2M46.8 65.8l.4-.1a.86 .86 0 0 1 0 1.2h-.3l-.2-.2zM46.9 76.6a.65 .65 0 0 1 .8 .7 .65 .65 0 0 1-.8 .6zM47 79.1a.68 .68 0 0 1 .4 .6 .68 .68 0 0 1-.4 .6l-.3-.2v-.8zM47.7 63.4l-.4-.2-.4 .4v.6l.4 .3 .4-.2M48.5 65.7h-.6l-.1 .6 .2-.2h.3l.3 .3v.3l-.2 .2-.6-.1M48.5 79.1h-.6l-.1 .6 .6-.1 .2 .2v.3l-.3 .2h-.3l-.2-.1"/>
<path d="M78.1 74.8h.5l.1-.3-.2-.2h-.4v1.1M78.1 72.1l.4-.3v1.2M78.1 73h.7M78.3 74.8l.4 .6M79 74.4l.4-.1 .2 .2-.6 .9h.6M79.4 71.9l.3-.1 .2 .2-.1 .9-.4 .1a.94 .94 0 0 1 0-1.1zM79.9 74.6l.4-.3v1.1M79.9 75.4h.6M80.5 71.8v1.2M80.7 72.3l.5 .7M80.9 74.4l.4-.1 .1 .2-.5 .9h.5M81.2 71.8l-.7 .7"/>
<path d="M33.5 94.3h.4l.1-.4-.5-.1v1M33.7 94.3l.3 .5M34.2 96.3l.2-.1h.3a.91 .91 0 0 1-.1 1.2l-.4-.3zM34.5 93.9h.5v.3l-.6 .6h.6M35.4 96.8l.7-.1v-.4l-.7-.1v1.2M35.6 93.8l.3 .3v.6l-.3 .1-.2-.1v-.6zM35.7 96.8l.4 .6M36.2 93.9l.5-.1 .1 .3-.6 .7h.6M41.1 92.5h.9l-.6 1.2M42.2 90.1v.9a.35 .35 0 0 0 .4 .3 .35 .35 0 0 0 .3-.3v-.9M42.7 92.5l-.4 .8h.8M42.9 92.9v.8"/>
<path d="M43.4 93.7l.4-1.2 .4 1.2M43.4 80.3l.4-1.2 .4 1.2M43.4 90.2l.6-.1 .2 .2-.1 .3-.7 .7h.8M43.5 93.4h.6M44.7 90.2l.4-.1 .2 .2v.7a.35 .35 0 0 1-.4 .3 .35 .35 0 0 1-.3-.5zM45.3 92.6l-.2-.1a.6 .6 0 0 0-.6 .6 .6 .6 0 0 0 .8 .5M45.6 92.5h.8M45.8 90.2l.6-.1 .1 .3-.8 .9h.8M46 92.5v1.2M47 92.5a.68 .68 0 0 1 .4 .6 .68 .68 0 0 1-.4 .6l-.3-.2v-.8zM47 90.6h.4M47.6 90.1h-.6v1.2h.6"/>
<path d="M48.5 92.5h-.6l-.1 .5h.7l.1 .5-.3 .2h-.3l-.2-.1M73.7 81h1M74.2 80.6v.9M75.9 80.3h-.6l-.1 .6h.7v.5h-.7M76.3 80.3l.4 1.2 .3-1.2M155.2 80.9h.7l.1-.4-.2-.2h-.6v1.2M155.5 80.9l.5 .6M156.6 82.7l-.2 .9h.7M157 83.1v.9M157.1 80.3v1.2l-.6-1.2v1.2M157.5 82.7h.8l-.5 1.3M157.6 80.4l.6-.1 .1 .6-.7 .6h.7"/>
<path d="M158.7 82.7v1.3M158.9 80.4l.4-.1a.91 .91 0 0 1 0 1.2l-.4-.1zM158.9 83.2l.5 .8M159.4 82.7l-.7 .8M160 80.7l.4-.4v1.2M160 81.5h.7M161.5 82.3h.9M162 81.8v.9M163.6 81.5h-.6l-.1 .6 .2-.1h.3l.3 .2v.3l-.2 .2-.6-.1M164 81.5l.3 1.2 .5-1.2M25.7 103.5a.59 .59 0 0 0-.8 .4 .59 .59 0 0 0 .3 .7h.5v-.5h-.2M26.2 115.1h1"/>
<path d="M26.8 114.7v1M26.9 103.5v1.1l-.7-1.1v1.1M27.5 103.5a.66 .66 0 0 1 .7 .4 .66 .66 0 0 1-.2 .7h-.5zM28.4 114.4h-.6l-.1 .6h.7v.4l-.2 .3h-.3l-.2-.2M28.8 114.4l.3 1.3 .4-1.3M33.5 107.8l.5-.1v-.3l-.5-.1v.9M33.7 107.8l.3 .4M34.3 109.6h.3a.86 .86 0 0 1 .1 1.1h-.3l-.2-.2zM34.5 107.4l.4-.1 .1 .4-.6 .5h.6M35.4 110.1h.6l.1-.5h-.7v1.1M35.5 107.3l.4 .1v.6l-.2 .2h-.2l-.1-.2zM35.7 110.1l.4 .6"/>
<path d="M36.2 107.3h.6l-.3 .3 .3 .2-.1 .4-.5-.1M41.1 105.9h.9l-.6 1.2M42.2 103.5v1l.2 .1h.4l.2-.1v-1M42.7 105.8l-.4 .9h.8M42.9 106.3v.8M43.4 107.1l.4-1.2 .4 1.2M43.5 103.5h.4l.3 .3-.8 .8h.8M43.5 106.8h.6M44.8 103.5h.2a.84 .84 0 0 1 .2 1.1h-.4a.78 .78 0 0 1 0-1.1zM45.3 106l-.5-.1a.61 .61 0 0 0-.2 .8 .61 .61 0 0 0 .7 .3M45.6 105.9h.8M45.8 103.5h.7v.5l-.8 .6h.8"/>
<path d="M46 105.9v1.2M46.7 106.1l.2-.2h.3a.86 .86 0 0 1 0 1.2l-.5-.3zM47 104.1h.4M47.6 103.5h-.6v1.1M48.5 105.9h-.6l-.1 .6 .2-.2h.3l.3 .3-.1 .4h-.7M62.8 116.4h1M63.2 115.9v.9M64.9 115.7h-.6v.5l.1-.1 .5 .1v.6h-.6M65.3 115.7l.4 1.1 .4-1.1M67.1 107.4l.4-.3v1.2M67.1 110.1h.5v-.4l-.5-.1v1.1M67.1 108.3h.7"/>
<path d="M67.4 110.1l.2 .6M68.1 109.7h.5v.4l-.6 .6h.6M68.4 107.2l.3-.1a.91 .91 0 0 1 .1 1.2h-.3l-.2-.2zM69.1 109.7l.2-.1 .2 .3v.6l-.2 .2-.3-.2zM69.5 107.1v1.2M69.7 107.6l.5 .7M70.2 107.1l-.7 .7M70.4 109.6l-.5 .3v.7h.5v-.5h-.4l-.1 .1M74.4 107.4l.4-.3v1.2M74.4 110.1h.5v-.4l-.5-.1v1.1M74.4 108.3h.8M74.7 110.1l.3 .6"/>
<path d="M75.4 109.7l.4-.1 .1 .3-.5 .8h.5M75.7 107.2l.3-.1 .3 .3v.7l-.2 .2-.4-.1zM76.4 109.7l.1-.1a.55 .55 0 0 1 .4 .5 .55 .55 0 0 1-.4 .6l-.2-.4zM76.9 107.1v1.2M77 107.6l.6 .7M77.1 109.6h.7l-.4 1.1M77.6 107.1l-.7 .7M83 107.4l.3-.3v1.2M83 110.1h.4l.1-.4-.5-.1v1.1M83 108.3h.6M83.2 110.1l.3 .6M83.9 109.7h.5v.4l-.6 .6h.6"/>
<path d="M84.2 107.2l.4-.1a.91 .91 0 0 1 .1 1.2l-.5-.1zM84.9 109.7l.3-.1 .1 .3v.6l-.1 .2-.4-.2zM85.3 107.1v1.2M85.5 107.6l.5 .7M85.9 110.1l-.1-.1v-.3h.5l-.1 .4h-.4v.5l.1 .1 .4-.1v-.5h-.2M86 107.1l-.7 .7M155.2 110.1h.6l.2-.1-.1-.4h-.7v1.1M155.5 110.1l.5 .6M156.6 111.9l-.2 .9h.7M157 112.3v.9M157.1 109.6v1.1l-.6-1.1v1.1M157.5 112h.8l-.5 1.2"/>
<path d="M157.6 109.6h.7v.5l-.7 .6h.7M158.7 112v1.2M158.9 109.6h.4a.86 .86 0 0 1 0 1.1h-.4zM158.9 112.5l.5 .7M159.4 112l-.7 .7M160 109.6h.4l.3 .3-.8 .8h.8M161.5 111.5h.9M162 111.1v.9M163.6 110.7h-.6l-.1 .6 .6-.1 .2 .2v.4l-.3 .2h-.3l-.2-.2M164 110.7l.3 1.3 .5-1.3M34.2 132.7h.8l-.5 1.2M34.3 130.2v1l.2 .3h.3l.2-.3v-1"/>
<path d="M35.6 130.4l.4-.2 .2 .4-.7 .9h.7M35.7 132.6l-.3 .9h.7M36 133.1v.8M36.5 133.9l.3-1.2 .5 1.2M36.6 133.5h.6M36.8 130.3a.61 .61 0 0 1 .7 .5 .61 .61 0 0 1-.4 .7 .71 .71 0 0 1-.3-1.2zM37.8 130.4l.2-.2h.4l.1 .2v.4l-.7 .7h.7M38.4 132.8l-.2-.1a.64 .64 0 0 0-.6 .6 .64 .64 0 0 0 .6 .6l.2-.1M38.7 132.7h.8M39.1 132.7v1.2M39.7 130.3l-.1-.1a.64 .64 0 0 0-.6 .6 .64 .64 0 0 0 .5 .7l.3-.2v-.3h-.3M40 132.7a.68 .68 0 0 1 .5 .6 .68 .68 0 0 1-.5 .6l-.2-.2v-.8z"/>
<path d="M41.6 132.7h-.6l-.1 .6 .6-.1 .2 .1v.4l-.3 .2h-.3l-.2-.1M60.4 133.4h.9M60.9 133v.9M62.5 132.7h-.6l-.1 .6 .6-.1 .1 .6-.2 .1h-.3l-.2-.1M62.9 132.7l.3 1.2 .5-1.2M64.7 124.5l.3-.4v1.3M64.7 127.3l.5-.1v-.5h-.5v1M64.7 125.4h.7M64.9 127.3l.4 .4M65.6 126.8l.5-.1 .1 .3-.7 .7h.7M66.1 124.1l.4 .3v.7l-.2 .3a.75 .75 0 0 1-.2-1.3zM66.5 127l.3-.3v1"/>
<path d="M66.5 127.7h.6M67.1 124.1v1.3M67.2 124.7l.6 .7M67.5 127l.2-.3v1M67.5 127.7h.6M67.8 124.1l-.7 .8M100 132.8h-.5l-.2 .2v.6l.2 .3h.3l.3-.1v-.5h-.3M101.3 132.7v1.2l-.7-1.2v1.2M101.9 132.7a.64 .64 0 0 1 .6 .6 .64 .64 0 0 1-.6 .6zM174.8 133.4h1M175.3 133v.9M177 132.7h-.6v.6l.5-.1 .1 .1v.4l-.2 .2-.4-.1"/>
<path d="M177.4 132.7l.4 1.2 .3-1.2M184.1 131.5h.6a.66 .66 0 0 1 .2 .8 .66 .66 0 0 1-.8 .4zM185.3 129l.1 1.2h.5l.1-1.2M186 131.5h-.6l-.1 .2 .1 .3 .6 .2v.4h-.7M186.5 131.8l.4-.3v1.2M186.5 129.1h.7v.4l-.8 .7h.8M186.5 132.7h.7M187.8 129.1l.3-.1a.86 .86 0 0 1 .1 1.2h-.3l-.2-.2zM187.9 132l-.3-.3 .2-.2h.4l.2 .2-.1 .2a.51 .51 0 0 0-.6 .7h.6l.1-.4-.3-.2M188.8 131.8l.3-.3v1.2M188.8 132.7h.7M189.1 128.9l-.2 1h.7"/>
<path d="M189.4 129.5v.7M189.9 131.5h.8l-.5 .4 .4 .1v.6h-.7M26.9 148.6l-.3-.1-.4 .3v.6l.4 .4 .3-.1v-.5h-.1M27.9 159.8v.9M28.2 148.5v1.3l-.7-1.3v1.3M28.8 148.5a.64 .64 0 0 1 .7 .6 .64 .64 0 0 1-.7 .7zM29.5 159.5h-.5v.6l.4-.2 .2 .3-.1 .4h-.5M30 159.5l.4 1.2 .4-1.2M96.3 148.8h.2l.2-.3v1.3M96.3 149.8h.8M96.4 146a.52 .52 0 0 1 .7 .4v.6a.52 .52 0 0 1-.7 .3zM97.6 146.2l.4-.2 .3 .5-.8 .8h.8"/>
<path d="M98.3 148.5v1.3l-.7-1.3v1.3M98.6 159.8v.9M99.1 146a.68 .68 0 0 1 .4 .7 .68 .68 0 0 1-.4 .6 .75 .75 0 0 1 0-1.3zM99.1 148.5l-.3 .8h.8M99.4 148.9v.9M99.9 146.2l.2-.2h.3l.2 .2v.4l-.8 .7h.8M100 148.8l.3-.3v1.3M100 149.8h.7M100.2 159.5h-.6v.6l.1-.2h.4l.1 .2v.5h-.6M100.6 159.5l.4 1.2 .4-1.2M101.4 148.5l-.2 .8h.7M101.7 148.9v.9"/>
<path d="M102.5 149l-.2-.2 .2-.3h.3l.2 .4-.5 .1-.2 .3v.2l.2 .3 .5-.2v-.4l-.2-.2M107.3 146h.7l-.4 .6 .4 .2-.1 .4-.5 .1-.1-.2M107.4 155.6l.3-.3v1.2M107.4 149.2l.5-.1v-.3l-.5-.1v.9M107.4 156.5h.6M107.5 149.2l.4 .4M108.1 153l-.5-.1a.61 .61 0 0 0-.3 .8 .61 .61 0 0 0 .8 .3M108.3 148.8l.4-.1 .1 .4-.6 .5h.6M108.5 153h.7v.4l-.7 .7h.7M108.5 146v1.3M108.7 146.6l.5 .7M108.8 155.3a.68 .68 0 0 1 .4 .6 .68 .68 0 0 1-.4 .6l-.3-.2v-.8z"/>
<path d="M109.2 146l-.7 .8M109.3 148.7l.4 .1v.6l-.1 .2h-.3l-.1-.2zM109.6 146h.8l-.4 .6 .4 .2-.1 .4-.5 .1-.2-.2M109.8 155.4l.3-.1 .2 .2v.8l-.2 .2a.71 .71 0 0 1-.3-1.1zM109.8 153l.4-.1a.91 .91 0 0 1-.1 1.2l-.3-.1zM110.3 148.6l-.2 .7h.6M110.6 149v.6M110.9 153.2l.3-.3v1.2M110.9 155.7v1.3M110.9 154.1h.7M111.4 156.4l.3 .1M111.4 155.7v.8h-.3l-.2-.1"/>
<path d="M112.2 155.9h.4M112.8 155.3h-.6v1.2M124.5 144.9a.66 .66 0 0 1 .7 .4 .66 .66 0 0 1-.2 .7h-.5zM125.6 142.4v1.1l.3 .2 .4-.3v-1M126.3 144.9h-.4l-.3 .2 .1 .3 .6 .2v.4h-.7M126.8 145.2l.4-.3v1.1M126.8 142.6l.2-.2h.3l.2 .2v.3l-.8 .8h.8M126.8 146h.7M128.2 145.4l-.2-.1v-.4h.6v.4l-.6 .2 .1 .5h.4l.2-.1v-.3l-.3-.2M128.3 142.4a.68 .68 0 0 1 .4 .6 .68 .68 0 0 1-.4 .7l-.3-.5 .1-.6zM129.1 145.2l.4-.3v1.1M129.1 142.4h.8l-.4 .5 .4 .2v.3l-.3 .3h-.3l-.2-.2"/>
<path d="M129.1 146h.7M130.2 144.9h.8l-.4 .5h.3l.1 .1-.1 .5h-.7M142.6 158.9l.6-.1v-.5l-.6-.1v1.3M142.7 155.9h-.6v.5l.5 .1 .1 .3-.3 .3-.4-.1M142.8 158.9l.5 .6M143.1 155.9l.2 1.2 .3-.9 .2 .9 .3-1.2M143.8 159.1l.5-.1v-.3h-.5v.7h.5M144.5 156l.6-.1 .1 .5-.8 .7h.8M145.2 158.7h-.3l-.1 .2 .5 .4-.2 .2-.3-.1M145.7 159.1l.6-.1v-.3h-.3l-.3 .1v.5l.3 .2 .3-.1M145.7 156l.2-.1h.3a.91 .91 0 0 1-.1 1.2l-.4-.3zM146.6 158.7h.5"/>
<path d="M146.9 158.2v1.2l.2 .1M146.9 156.2l.3-.3v1.2M146.9 157.1h.7M202.4 144.9h-.6v.5l.5 .1 .1 .4-.1 .1h-.6M202.8 144.9l.2 1.1 .3-.8 .2 .8 .3-1.1M203.8 147.3v1.2l-.7-1.2v1.2M204.2 144.9h.7v.5l-.8 .6h.8M204.4 148.5v-1.2l.4 .9 .4-.9v1.2M205.5 144.9h.3a.91 .91 0 0 1 .1 1.1h-.3l-.2-.1zM205.8 147.3v1.2M206.5 144.9h.5l.3 .2-.8 .9h.8M208.4 157.1a.59 .59 0 0 0-.7 .4 .59 .59 0 0 0 .2 .7h.5v-.5h-.2"/>
<path d="M209.6 157.1v1.1l-.6-1.1v1.1M210.2 157.1a.66 .66 0 0 1 .7 .3 .66 .66 0 0 1-.2 .8h-.5zM27.5 160.3h.9M36.3 167.9l-.2 .8h.7M36.7 165.5l.4 .6 .3-.6M36.7 168.3v.9M37.1 166.1v.6M37.3 168l.5 .1a.66 .66 0 0 1-.3 1.1 .84 .84 0 0 1-.2-1.2zM37.8 165.6l.5-.1 .2 .4-.7 .8h.7M38.4 169.2v-1.2l.5 .8 .3-.8v1.2M39.1 165.6l.3-.1 .2 .3-.1 .8-.4 .1a.94 .94 0 0 1 0-1.1zM39.8 168v1.2"/>
<path d="M39.8 168.5h.7M40.1 165.9l.4-.4v1.2M40.1 166.7h.7M40.5 168v1.2M41 168.3h.6l-.6 .9h.6M44.4 177.2l.6-.1-.1-.4h-.5v.9M44.6 174.1h.7l-.3 .5 .3 .1v.5l-.2 .1h-.3l-.2-.1M44.7 177.2l.3 .4M45.4 176.8l.4-.1 .1 .4-.6 .5h.6M45.7 174.1h.8l-.4 .5h.3v.7h-.5l-.2-.1M46.3 177l.3-.3v.9M46.3 177.6h.5"/>
<path d="M47 174.7h.5l.2-.4-.2-.2h-.5v1.2M47.3 176.7h.4v.2v.7h-.4l-.1-.1zM47.3 174.7l.4 .6M86.2 179.7h-.3a.67 .67 0 0 0-.5 .5 .67 .67 0 0 0 .3 .6h.5M86.6 179.7h.5l.3 .2-.8 .9h.8M87.9 179.7h.3l.3 .2v.8l-.2 .1h-.4zM89.6 179.7h-.4l-.2 .3v.8h.6v-.6h-.5l-.1 .1M93.2 174.8h.9M93.7 174.4v.9M95.3 174.1h-.6v.6l.5-.1 .2 .5-.2 .2-.5-.1M95.8 174.1l.4 1.2 .4-1.2M98.1 160.3h1"/>
<path d="M102.4 165.6h.8l-.4 .4 .3 .1v.6h-.7M102.4 168.7l.6-.1v-.5h-.6v1M102.7 168.7l.3 .4M103.4 168.2l.4-.1 .2 .3-.7 .7h.7M103.6 162a.61 .61 0 0 0-.7 .2 .61 .61 0 0 0 .1 .8l.4 .1h.2l.1-.5h-.2M103.7 165.6v1.2M103.9 166.1l.5 .7M104.4 165.6l-.7 .7M104.5 168.1a.47 .47 0 0 1 .4 .5 .47 .47 0 0 1-.4 .5l-.2-.4zM104.8 165.6h.8l-.4 .4 .3 .1v.6h-.7M104.9 161.9v1.2l-.7-1.2v1.2M105.5 161.9a.52 .52 0 0 1 .7 .3v.6a.52 .52 0 0 1-.7 .3z"/>
<path d="M105.7 168.1h-.5v.5h.5l.1 .3-.1 .2-.5-.1M118.4 168.3h.4l.2-.2v-.3l-.6-.1v1.2h.5l.1-.1v-.4l-.2-.1M118.4 165.3l.6 .2v.7l-.1 .3h-.5zM119.4 168.9l.4-1.2 .4 1.2M119.5 165.4l.5-.1 .2 .3-.7 .9h.7M119.5 168.6h.6M120.5 167.7h.7M120.8 165.4a.61 .61 0 0 1 .7 .3 .61 .61 0 0 1-.3 .8h-.4l-.1-.2-.1-.5zM120.8 167.7v1.2M121.7 168.2l-.2-.2 .1-.3 .6 .1v.3l-.3 .1a.35 .35 0 0 0-.4 .5 .35 .35 0 0 0 .6 .1l.1-.5-.3-.1M121.8 165.6l.4-.3v1.2M121.8 166.5h.7"/>
<path d="M123.3 167.7h-.5l-.1 .3v.8h.6v-.6l-.5-.1-.1 .3M123.9 168.8l-.1 .3M124.4 168.1l.3-.4v1.2M124.4 168.9h.6M125.6 168.1l.3-.4v1.2M125.6 168.9h.6M126.7 167.7h.7l-.4 .4 .3 .1v.6h-.6M148.7 168.1l-.1-.1a.6 .6 0 0 0-.6 .6 .6 .6 0 0 0 .7 .6l.1-.5h-.3M150 168v1.2l-.7-1.2v1.2M150.5 168a.65 .65 0 0 1 .8 .6 .65 .65 0 0 1-.8 .6zM28.1 183.9l-.1-.1a.64 .64 0 0 0-.6 .6 .64 .64 0 0 0 .5 .7l.3-.2v-.3h-.3M29.4 183.8v1.3l-.7-1.3v1.3"/>
<path d="M30 183.8a.52 .52 0 0 1 .6 .3v.6a.52 .52 0 0 1-.6 .4zM85.4 182.5l.4-.4v1.2M85.4 183.3h.7M86.7 182.2l.2-.1a.77 .77 0 0 1 .2 1.2h-.3l-.2-.3zM87.9 182.2h.3a.67 .67 0 0 1 0 1.1h-.3a.94 .94 0 0 1 0-1.1zM89 182.5v1.2M89.6 183.1v.2h.1M89.6 182.5l-.1 .8h-.5v-.2M90.3 182.7h.4M90.8 182.1h-.5v1.2M93.9 188.8l-.3-.1-.4 .3v.7l.3 .2 .5-.1v-.4h-.3M95.2 188.7v1.2l-.7-1.2v1.2"/>
<path d="M95.8 188.7a.66 .66 0 0 1 .6 .5 .66 .66 0 0 1-.2 .7h-.4zM97.6 183l.4-.4v1.2M97.6 183.8h.7M98.4 180.3l-.4-.1-.4 .3 .1 .8 .3 .1 .4-.1M98.8 180.3l.2-.1h.3l.2 .1v.4l-.8 .7h.8M98.9 182.7h.1a.6 .6 0 0 1 .6 .4 .6 .6 0 0 1-.3 .7h-.3a.78 .78 0 0 1-.1-1.1zM100.1 182.7l.2-.1 .3 .3v.7l-.2 .2h-.3l-.2-.4zM100.2 180.2a.68 .68 0 0 1 .5 .6 .68 .68 0 0 1-.5 .6l-.2-.5 .1-.6zM101.2 183.1l.3-.1 .2 .2v.6M101.2 180.3l.4-.1 .3 .3-.8 .9h.8M101.2 183v.8M102.3 183.2h.3"/>
<path d="M102.8 182.6h-.5v1.2M112.2 183l.4-.4v1.2M112.2 183.8h.7M112.9 180.3l-.1-.1a.64 .64 0 0 0-.6 .6 .64 .64 0 0 0 .6 .6l.1-.1M113.5 182.7l.3-.1 .2 .3v.7l-.1 .2-.4-.1zM113.5 180.3l.4-.1 .2 .3-.7 .9h.7M114.6 182.7l.4-.1a.91 .91 0 0 1 .1 1.2h-.4l-.1-.2zM114.9 180.2a.68 .68 0 0 1 .4 .6 .68 .68 0 0 1-.4 .6 .75 .75 0 0 1 0-1.2zM115.7 183.1h.5v.7M115.7 183v.8M116.1 180.2l-.4 .8h.8M116.3 180.6v.8"/>
<path d="M116.8 183.2h.5M117.4 182.6h-.6v1.2M124.4 183h.1l.2-.4v1.2M124.4 183.8h.6M125.1 180.3l-.2-.1a.65 .65 0 0 0-.5 .6 .65 .65 0 0 0 .5 .6l.2-.1M125.6 182.7l.4-.1 .2 .3v.7l-.1 .2-.5-.1zM125.6 180.3l.5-.1 .2 .3-.7 .9h.7M126.8 182.7h.5l.1 .7-.1 .4h-.4l-.2-.2zM126.9 180.3a.61 .61 0 0 1 .7 .4 .61 .61 0 0 1-.4 .7 .71 .71 0 0 1-.3-1.1zM127.9 183.1h.5v.7M127.9 183v.8M128.6 180.2h-.6l-.1 .6 .6-.1 .1 .6-.2 .1h-.3l-.2-.1"/>
<path d="M129 183.2h.5M129.6 182.6h-.6v1.2M135.4 183l.3-.4v1.2M135.4 183.8h.7M136.1 180.3l-.3-.1-.4 .3 .1 .8 .3 .1 .3-.1M136.6 180.3l.1-.1h.4l.1 .1v.4l-.7 .7h.7M136.6 182.7h.1a.6 .6 0 0 1 .6 .4 .6 .6 0 0 1-.2 .7h-.4a.78 .78 0 0 1-.1-1.1zM137.8 182.7l.3-.1 .2 .3v.7l-.1 .2h-.4l-.1-.4zM138 180.2a.68 .68 0 0 1 .4 .6 .68 .68 0 0 1-.4 .6l-.3-.5 .1-.6zM138.9 180.2h.7l-.4 .5 .3 .1 .1 .4-.2 .2h-.4l-.1-.1M138.9 183.1l.4-.1 .1 .2v.6M138.9 183v.8"/>
<path d="M140 183.2h.4M140.5 182.6h-.5v1.2"/>
</g>
</svg>
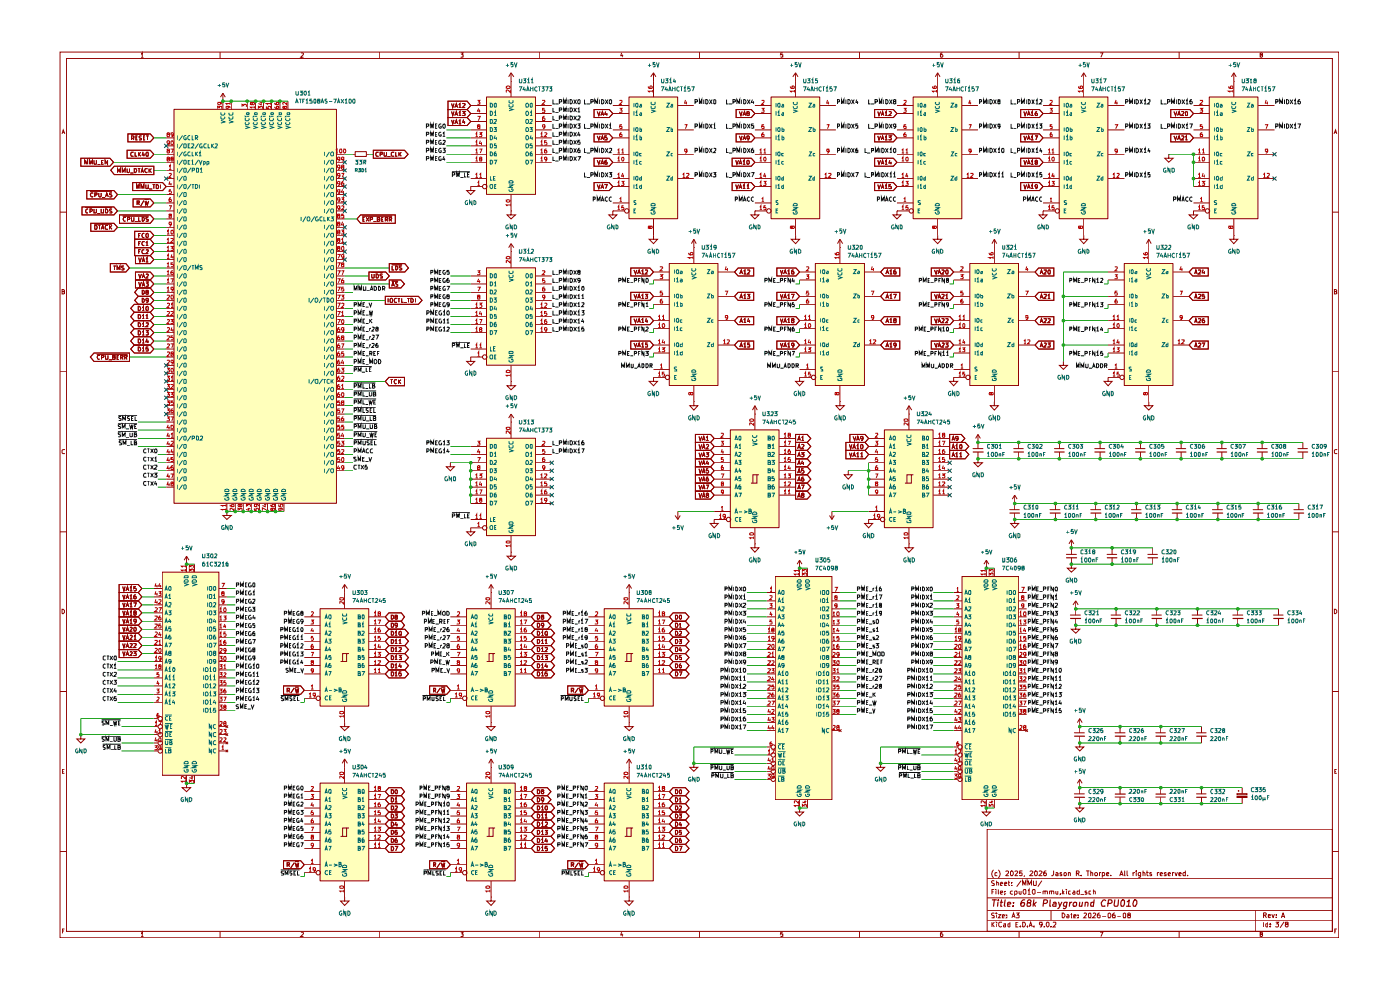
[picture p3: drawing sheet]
<svg xmlns="http://www.w3.org/2000/svg" width="297mm" height="210mm" viewBox="0 0 297 210" stroke-linecap="round" stroke-linejoin="round" font-family="sans-serif">
<g fill="none" stroke="#910000" stroke-width=".21">
<path d="M12.7 11h271.3v187.9h-271.3zM14.1 12.4h268.6v185.2h-268.6zM29.9 11.5l.3-.3v.9M29.9 12.1h.5M46.7 11v1.4M63.9 11.3l.3-.1 .2 .3-.6 .6h.6M80.6 11v1.4M97.7 11.2h.6l-.3 .4h.3v.5h-.6M114.5 11v1.4M131.9 11.2l-.2 .6h.5M132.1 11.6v.5M148.4 11v1.4"/>
<path d="M166.1 11.2h-.5v.4h.5v.5h-.5M182.3 11v1.4M199.9 11.2l-.3 .1-.1 .8h.4l.1-.1-.1-.4-.4 .1M216.2 11v1.4M233.4 11.2h.6l-.5 .9M250.1 11v1.4M267.5 11.6h-.2v-.3l.4-.1 .1 .3-.5 .2v.4h.2l.3-.1-.1-.4M13.2 28.4l.2-.8 .4 .8M13.2 28.1h.5M283 28.4l.3-.8 .3 .8M283.1 28.1h.4M12.7 45h1.4"/>
<path d="M282.7 45h1.3M12.7 78.9h1.4M13.2 61.8h.4l.1-.2-.2-.2h-.3v1l.5-.1v-.4l-.2-.1M282.7 78.9h1.3M283.1 61.8h.4l.1-.2-.2-.2h-.3v1l.5-.1v-.4l-.2-.1M13.7 95.5l-.4-.1-.1 .1v.6l.1 .1 .4-.1M283.6 95.5l-.4-.1-.1 .1v.6l.1 .1 .4-.1M12.7 112.8h1.4M282.7 112.8h1.3M13.2 129.2h.2l.3 .3v.4l-.3 .3h-.2zM283.1 129.2h.2l.3 .3v.4l-.3 .3h-.2zM12.7 146.7h1.4"/>
<path d="M282.7 146.7h1.3M13.2 163.6h.3M13.7 163.2h-.5v.8h.5M209.4 175.9h73.3v21.7h-73.3zM283.2 163.6h.2M283.6 163.2h-.4v.8h.4M12.7 180.6h1.4M13.2 197.5h.4M13.7 197.1h-.5v.9M29.9 198l.3-.3v1M29.9 198.7h.5M46.7 197.6v1.3"/>
<path d="M63.9 197.8l.3-.1 .2 .3-.6 .7h.6M80.6 197.6v1.3M97.7 197.7h.6l-.3 .4 .3 .1v.4h-.6M114.5 197.6v1.3M131.9 197.7l-.2 .6h.5M132.1 198.1v.6M148.4 197.6v1.3M166.1 197.7h-.5v.5h.5v.4h-.5M182.3 197.6v1.3M199.9 197.7l-.3 .1-.1 .8 .4 .1 .1-.2-.1-.4-.4 .1M209.4 195.2h73.3M209.4 193.2h73.3"/>
<path d="M209.4 190.5h73.3M209.4 186.4h73.3M210.4 195.6v1M210.4 189.2h.4M210.5 196l.4 .6M210.7 184.6l-.1 .1a1.11 1.11 0 0 0 .1 1.5M210.9 188.7h-.5v1M210.9 193.8l-.4-.1-.1 .1v.2l.4 .2 .1 .2v.3h-.5M210.9 186.9l-.4-.1-.1 .2v.2l.5 .4v.2h-.5M210.9 195.6l-.5 .5M211.3 188.7v.1M211.3 189v.7"/>
<path d="M211.4 193.7v.1M211.4 187.2h.4v.6M211.4 186.8v1M211.4 194v.7M211.5 195.6v.1M211.5 196v.6M211.5 185.2h-.4v.5l.4 .1M211.8 194h.5l-.5 .7h.5M211.8 188.7l.1 1M211.8 184.6l.1 .1a1.11 1.11 0 0 1-.1 1.5M212.2 189.4l.5-.1-.1-.3h-.3l-.1 .2v.3l.2 .2 .2-.1M212.2 187.5l.5-.1-.1-.2-.4 .1v.4l.4 .1"/>
<path d="M212.5 195.7l-.5-.1-.1 .2v.6l.3 .2 .3-.1M212.6 194.3h.5l-.1-.3-.4 .1v.6h.5M212.9 196h.4v.6M213.1 189.6v.1M213.1 189v.2M213.1 187.5l.5-.1-.1-.2h-.4v.6h.5M213.3 196.1l-.4 .2 .1 .3h.3M213.4 184.8h.5v.4l-.5 .6h.5M213.6 194.6v.1M213.6 194.1v.1M213.9 187.2h.3M214 186.8v.9l.2 .1"/>
<path d="M214.2 196h-.4v.5l.2 .1h.2M214.2 195.6v1M214.4 184.9l.2-.2a.52 .52 0 0 1 .4 .6 .52 .52 0 0 1-.5 .5zM214.6 187.7v.1M214.6 187.2v.1M214.7 194.7l.3-1 .3 1M214.8 194.4h.5M214.8 189h-.3l-.2 .2 .1 .4h.4M215.3 189.6l.3 .1 .2-.2-.1-.5h-.4v1M215.3 184.8l.4-.1 .2 .2-.6 .9h.6M215.5 196h.4M215.6 193.7h.6l-.3 .4 .3 .1v.4h-.6"/>
<path d="M216 195.6h-.5v1h.5M216.2 189v.5l.2 .2 .2-.1M216.2 197.6v1.3M216.4 196.5v.1M216.6 189v.7M216.6 186.8l-.9 1.3M216.8 184.7h-.5v.5h.5l-.1 .6-.4-.1M217 195.6h.3a.55 .55 0 0 1 .2 .8l-.3 .2h-.2zM217 187.8v-1l.3 .8 .3-.8v1M217.2 188.7h.3l.1 .1v.7l-.2 .2a.63 .63 0 0 1-.2-1zM217.3 185.8v.1M218 196.5v.1"/>
<path d="M218.1 188.9l.2-.2v1M218.1 187.8v-1l.3 .8 .4-.8v1M218.1 189.7h.5M218.3 196.6l.3-1 .4 1M218.4 196.3h.5M218.5 184.8l.4-.1 .2 .4-.7 .7h.7M219.2 188.7h.3l.1 .1v.7l-.3 .2a.63 .63 0 0 1-.1-1zM219.2 186.8l.1 1 .5-.1v-.9M219.3 196.5v.1M219.5 184.8l.3-.1 .2 .2v.7l-.1 .2-.4-.1zM220 189.3h.8M220.5 184.8l.3-.1 .3 .4-.7 .7h.7"/>
<path d="M221 186.8l-.8 1.3M221.1 196l-.2 .2-.4-.2 .1-.4h.4a.64 .64 0 0 1-.4 1M221.3 189.1l.4-.1v.7M221.3 189v.7M221.5 196.5v.1M221.7 189.2l.1-.2h.3l.1 .7M221.9 184.7l-.3 .1a.74 .74 0 0 0-.1 1h.4l.1-.5-.1-.1h-.4l-.1 .1M222 195.7l.4-.1 .1 .2v.6l-.2 .2-.3-.4zM222.6 189.1l.5-.1v.7M222.6 189v.7M223 196.5v.1M223 193.2v2"/>
<path d="M223.1 189.2v-.2h.4l.1 .7M223.4 195.7h.6v.3l-.6 .6h.6M223.5 184.7v.8l-.2 .3h-.2M224 189v.5l.2 .2 .2-.1M224 185.2l.3-.1 .1 .1v.6h-.4v-.4l.4-.1M224.4 189v.7M224.9 189.6v.1M225.2 185.2h-.3v.2l.4 .2-.1 .2h-.3M225.3 193.7h.3l.3 .4-.2 .6h-.4zM225.4 188.7v1M225.5 189.3l.3 .4M225.7 185.2l.4-.1 .1 .1-.1 .6-.4-.1z"/>
<path d="M225.8 189l-.4 .4M226.3 188.7v.1M226.3 189v.7M226.4 194.1l.2-.1 .2 .2v.5h-.4v-.4h.4M226.6 185.2h.5v.6M226.6 185.1v.7M227.1 189l-.4 .1v.5h.4M227.1 194h.4M227.3 193.7v1h.2M227.6 189h.4v.7M227.8 194.3h.5l-.2-.3-.3 .1v.6h.4M228 189.3h-.3l-.2 .1 .2 .3 .3-.1"/>
<path d="M228.3 185.2h.6v-.3l-.1-.2h-.5v1.1M228.6 185.2l.3 .6M228.7 194.6v.1M228.7 194.1v.1M229 189h-.4l-.1 .2v.3l.1 .2 .4-.1M229 188.7v1M229.2 189.8h.8M229.4 185.7v.1M229.9 193.8l.4-.1 .2 .1-.6 .9h.6M230.5 184.7h.6M230.6 189h-.4v.2l.4 .2v.2h-.4M230.8 184.7v1.1"/>
<path d="M231.1 193.7l.3 .1-.1 .9h-.3l-.1-.2v-.7zM231.4 185.2h.4v.6M231.4 184.7v1.1M231.4 189l-.4 .1v.5h.4M231.9 193.8l.4-.1 .1 .3-.6 .7h.6M231.9 189.1l.4-.1 .1 .7M231.9 188.7v1M232.3 185.2l.3-.1 .2 .1-.1 .6h-.4zM233.3 185.1v.7M233.3 193.7l-.3 .1-.2 .7 .2 .2 .4-.1-.1-.5h-.3l-.2 .2M233.4 197.7h.6l-.5 1M233.5 185.1l-.2 .1"/>
<path d="M233.8 194.3h.9M233.8 185.2l.4-.1 .2 .1-.1 .6h-.5M233.8 185.1v1M234.8 185.4l.4-.1-.1-.2-.3 .1v.6h.4M235.1 193.8l.2-.1a.52 .52 0 0 1 .4 .6 .52 .52 0 0 1-.5 .4zM235.6 185.7v.1M236.5 193.7l-.3 .1a.74 .74 0 0 0-.1 .9h.4l.1-.4-.1-.2h-.4l-.1 .2M237 194.3h.8M237.6 185.8l.3-1.1 .3 1.1M237.7 185.5h.5M238.5 193.7l.3 .1-.1 .9h-.3l-.1-.2v-.7zM238.6 184.7l.1 1.1"/>
<path d="M239.1 184.7v.9l.2 .2M239.4 194.1l-.2-.3 .4-.1 .2 .2-.1 .2-.4 .1v.5h.4l.1-.4-.2-.2M240.4 185.1v.7M240.7 185.1l-.3 .1M241 184.7v.1M241 185.1v.7M242 185.1v.8l-.1 .2h-.3M242 185.2l-.4-.1-.1 .1 .1 .6h.4M242.5 185.2l.2-.1 .2 .1v.6M242.5 184.7v1.1M243.2 185.1h.4M243.3 184.7v.9l.3 .2"/>
<path d="M244.3 185.2h-.4v.2l.4 .2v.2h-.4M245.5 185.1v.7M245.9 185.1l-.4 .1M246.1 185.4l.5-.1-.1-.2-.4 .1v.4l.1 .2h.3M247.4 185.2l-.3-.1-.1 .1 .4 .3v.3h-.4M247.8 185.4l.5-.1-.1-.2-.4 .1v.4l.1 .2h.3M248.7 185.1v.7M249 185.1l-.3 .1M249.3 185.1l.2 .7 .3-.7M250.1 185.4l.5-.1-.2-.2-.3 .1v.6h.4M250.1 197.6v1.3M251.5 184.7v1.1h-.5l-.1-.6 .2-.1 .4 .1"/>
<path d="M252 185.7v.1M266.4 193.2v4.4M267.5 198.2l-.2-.1v-.3l.4-.1 .1 .3-.5 .2v.4l.2 .1 .3-.2-.1-.3M268 195.6v1M268.1 194.1h.5v-.3l-.1-.2h-.4v1M268.3 194.1l.3 .5M268.9 196h-.4v.5l.2 .1h.2M268.9 195.6v1M269.1 194.3l.4-.1-.1-.2-.3 .1v.5h.4M269.4 196.5v.1M269.4 196h.1M269.8 194l.3 .6 .2-.6"/>
<path d="M270.6 195.6h.6l-.3 .4h.3v.5l-.1 .1h-.4l-.1-.1M270.8 194.6h.1M270.8 194.1h.1M271.9 194.6l.3-1 .3 1M271.9 194.4h.6M272.4 195.5l-.8 1.3M272.9 196l-.2-.2 .1-.2h.4l.1 .4h-.5l-.1 .2 .2 .4 .4-.1v-.4l-.2-.1M282.7 180.6h1.3M283.2 197.5h.2M283.6 197.1h-.4v.9"/>
</g>
<g fill="none" stroke="#910000" stroke-width=".25">
<path d="M210.5 190.9h.9M210.9 190.9l-.1 1.3M211.7 191.4l-.1 .8M211.8 190.9v.1M212.2 191.4h.5M212.5 190.9l-.2 1.3h.3M213.2 190.9l-.1 1.2 .1 .1M213.7 191.8l.7-.1-.2-.3-.5 .2v.6h.5M214.9 192.1v.1M215 191.5v.1M217.4 190.9a.89 .89 0 0 0-.7 1.3h.5l.2-.5-.1-.2h-.5l-.2 .2M218.1 191.5l-.1-.1v-.3l.2-.2 .4 .1v.4l-.5 .1-.2 .2 .1 .5 .6-.1v-.4l-.2-.2"/>
<path d="M219.3 190.9l-.1 1.3M219.3 191.7l.4 .5M219.8 191.4l-.6 .5M221.4 191.6h.6l.2-.2v-.4l-.2-.1h-.6l-.1 1.3M222.8 190.9l-.1 1.3h.2M223.5 191.5l.4-.1 .2 .2-.1 .6h-.6v-.4l.6-.1M224.6 191.4l.2 .8M225.3 191.4l-.6 1.2-.3 .1M226.4 191.4l-.2 1.1-.3 .2h-.3M226.4 191.5h-.6l-.2 .5 .1 .2h.5M226.9 191.4v.8M227.4 191.4l-.5 .2"/>
<path d="M227.8 191.5h.6v.5l-.2 .2-.5-.1zM229.1 191.4l-.1 .8 .5-.1M229.7 191.4l-.2 .8M230.2 191.5l.5-.1 .1 .2v.6M230.2 191.4v.8M232.1 190.9l-.2 1.3h-.5v-.7h.6M234.6 191a.6 .6 0 0 0-.8 0 .6 .6 0 0 0-.2 .7l.2 .5 .6-.1M235.1 191.6h.7l.1-.2-.1-.4-.6-.1-.2 1.3M236.5 190.9l-.2 1.1 .2 .2 .6-.1 .2-1.2M237.9 191.1l.3-.2 .3 .1v.7l-.2 .5h-.4zM239 192.2h.8M239.1 191.3l.5-.4-.2 1.3"/>
<path d="M240.7 190.9l.5 .2v.6l-.3 .5h-.4l-.2-.5 .2-.6z"/>
</g>
<g fill="#ffb">
<path d="M103.2 93h10.5v20.7h-10.5z"/>
<path d="M99 129.2h10.3v20.6h-10.3z"/>
<path d="M128.2 129.2h10.4v20.6h-10.4z"/>
<path d="M155 91.2h10.3v20.8h-10.3z"/>
<path d="M99 166.2h10.3v20.7h-10.3z"/>
<path d="M128.2 166.2h10.4v20.7h-10.4z"/>
<path d="M256.6 20.6h10.3v25.8h-10.3z"/>
<path d="M238.5 55.9h10.4v25.9h-10.4z"/>
<path d="M205.8 55.9h10.3v25.9h-10.3z"/>
<path d="M193.8 20.6h10.3v25.8h-10.3z"/>
<path d="M224.7 20.6h10.4v25.8h-10.4z"/>
<path d="M37 23.2h34.4v83.6h-34.4z"/>
<path d="M34.4 121.4h12v43.1h-12z"/>
<path d="M67.9 166.2h10.4v20.7h-10.4z"/>
<path d="M67.9 129.2h10.4v20.6h-10.4z"/>
<path d="M142 55.9h10.4v25.9h-10.4z"/>
<path d="M173 55.9h10.4v25.9h-10.4z"/>
<path d="M103.2 20.6h10.5v20.7h-10.5z"/>
<path d="M133.5 20.6h10.3v25.8h-10.3z"/>
<path d="M103.2 56.9h10.5v20.6h-10.5z"/>
<path d="M163.6 20.6h10.3v25.8h-10.3z"/>
<path d="M187.7 91.2h10.3v20.8h-10.3z"/>
<path d="M204.1 122.3h12v47.3h-12z"/>
<path d="M164.5 122.3h12v47.3h-12z"/>
</g>
<g fill="none" stroke="#910000" stroke-width=".21">
<path d="M47.3 19.8l-.5 .8M47.3 19.8l.5 .8M47.3 19.8v3.4M108.4 17.2h.1M108.4 15.4v5.2M108.4 15.4l-.5 .9M108.4 15.4l.6 .9M138.6 17.2h.1M138.6 15.4v5.2M138.6 15.4l-.6 .9M138.6 15.4l.5 .9M168.8 17.2h.1"/>
<path d="M168.8 15.4l-.6 .9M168.8 15.4l.5 .9M168.8 15.4v5.2M198.9 17.2h.1M198.9 15.4l-.5 .9M198.9 15.4l.5 .9M198.9 15.4v5.2M229.9 17.2h.1M229.9 15.4l-.5 .9M229.9 15.4l.5 .9M229.9 15.4v5.2M261.7 17.2h.1"/>
<path d="M261.7 15.4l-.5 .9M261.7 15.4l.6 .9M261.7 15.4v5.2M17.1 33.6h6.2l.8 .8-.8 .9h-6.2zM18 34.8v-.8l.3 .7 .3-.7v.8M19 34.8v-.8l.3 .7 .3-.7v.8M19.9 34l.1 .8h.4v-.8M20.7 34.9h.6M21.5 34.4h.3M22 34h-.5v.8h.5M22.8 34v.8l-.5-.8v.8M24.3 35.3h8.3v1.7h-8.3l-.8-.9z"/>
<path d="M24.9 36.6v-.8l.4 .6 .2-.6v.8M25.9 36.6v-.8l.3 .6 .3-.6v.8M27 31.9h4.9l.7 .8-.7 .9h-4.9zM27 35.8v.7l.1 .1 .4-.2v-.6M27.1 28.4h4.8l.7 .8-.7 .9h-4.8zM27.6 36.7h.7M27.8 28.6h3.7M27.9 29.3l.5-.1v-.3l-.5-.1v.9M28.1 38.7h6.4l.8 .9-.8 .8h-6.4zM28.1 29.3l.3 .4M28.2 32.4l-.3-.1-.2 .3 .2 .5h.3M28.5 35.8h.3a.48 .48 0 0 1 .2 .5 .48 .48 0 0 1-.5 .3z"/>
<path d="M28.7 32.3v.8h.4M28.8 29.2h.3M29.2 28.8h-.4v.9h.4M29.2 35.8h.6M29.3 32.3v.8M29.4 32.6l.4 .5M29.5 35.8v.8M29.8 32.3l-.5 .5M29.9 36.6l.3-.8 .2 .8M30 28.9l-.3-.1-.2 .2 .1 .2 .4 .2v.2l-.5 .1M30 36.4h.3M30.3 32.2l-.1 .7h.5"/>
<path d="M30.4 29.2h.3M30.5 32.6v.5M30.8 28.8h-.4v.9h.4M30.9 39.2l.1 .8 .5-.1v-.7M31 32.4l.4-.1v.8a.39 .39 0 0 1-.5-.2 .39 .39 0 0 1 .1-.5zM31 28.8h.5M31.3 35.9l-.4-.1a.44 .44 0 0 0-.1 .5 .44 .44 0 0 0 .5 .2M31.3 28.8v.9M31.6 35.8v.8M31.7 36.1l.4 .5M32.1 35.8l-.5 .4M32.4 39.2h.5"/>
<path d="M32.6 39.2v.8M33.1 39.2a.49 .49 0 0 1 .5 .3 .49 .49 0 0 1-.1 .5h-.4zM34 39.2v.8M35.3 29.2h1.7M35.3 32.7h1.7M35.3 34.4h1.7M35.3 37.9h1.7M35.3 39.6h1.7M35.3 30.9h1.7M35.3 36.1h1.7M36.9 23.2h34.5v83.6h-34.5zM47.3 21.5h.1"/>
<path d="M49.1 21.5v1.7M52.4 21.5v1.7M54.2 21.5v1.7M55.9 21.5v1.7M57.6 21.5v1.7M59.4 21.5v1.7M61.1 21.5v1.7M71.4 32.7h1.7M71.4 34.4h1.7M71.4 37.9h1.7M71.4 39.6h1.7M71.4 36.1h1.7"/>
<path d="M74.9 32.7h.5M75.4 32.2h2.3v1h-2.3zM77.8 32.7h.5M79.2 31.9h6.6l.8 .8-.8 .9h-6.6zM80.2 32.4l-.3-.1-.2 .3 .2 .5h.3M80.6 32.7h.5v-.4h-.5v.8M81.5 32.3l.1 .8h.3l.1-.1v-.7M82.2 33.2h.6M83.5 32.4l-.3-.1-.2 .2v.5l.2 .1h.3M83.9 32.3v.8h.4M84.6 32.3v.8M84.7 32.6l.4 .5"/>
<path d="M85.1 32.3l-.5 .5M95 23.2h4.1l.8 .9-.8 .8h-4.1zM95 21.5h4.1l.8 .9-.8 .8h-4.1zM95 24.9h4.1l.8 .9-.8 .8h-4.1zM95.8 23.7l.3 .8 .2-.8M95.8 22l.3 .8 .2-.8M95.8 25.4l.3 .9 .2-.9M96.5 24.5l.3-.8 .3 .8M96.5 22.8l.3-.8 .3 .8M96.5 26.3l.3-.9 .3 .9M96.6 24.3h.4M96.6 22.6h.4"/>
<path d="M96.6 26h.4M97.3 23.9l.3-.2v.8M97.3 22.2l.3-.2v.8M97.3 25.6l.3-.2v.9M97.3 24.5h.5M97.3 22.8h.5M97.3 26.3h.5M98.1 23.7h.6l-.4 .3 .4 .2-.1 .3-.5-.1M98.2 22.1l.4-.1 .1 .2-.6 .6h.6M98.3 25.4l-.1 .5h.5M98.6 25.7v.6M99.9 39.6v.8h.8l-.8 .9-.9-.9h.9"/>
<path d="M99.9 39.6h.1M99.9 22.4h3.3M99.9 24.1h3.3M99.9 27.6h3.3M99.9 29.2h3.3M99.9 32.7h3.3M99.9 34.4h3.3M99.9 37.9h3.3M99.9 39.6h2.5M99.9 30.9h3.3M99.9 25.8h3.3M103.2 20.6h10.4v20.6h-10.4z"/>
<path d="M113.7 22.4h3.3M113.7 24.1h3.3M113.7 27.6h3.3M113.7 29.2h3.3M113.7 32.7h3.3M113.7 34.4h3.3M113.7 30.9h3.3M113.7 25.8h3.3M126 33.6h3.2l.8 .8-.8 .9h-3.2zM126 38.7h3.2l.8 .9-.8 .8h-3.2zM126 28.4h3.2l.8 .8-.8 .9h-3.2zM126 23.2h3.2l.8 .9-.8 .8h-3.2z"/>
<path d="M126.7 34l.3 .8 .3-.8M126.7 39.2l.3 .8 .3-.8M126.7 28.8l.3 .9 .3-.9M126.7 23.7l.3 .8 .3-.8M127.5 34.8l.3-.8 .3 .8M127.5 29.7l.3-.9 .3 .9M127.5 24.5l.3-.8 .3 .8M127.5 29.4h.5M127.5 24.3h.5M127.5 34.7h.5M127.5 39.8h.5M128.2 39.2h.6l-.3 .8"/>
<path d="M128.5 23.7l-.2 .6h.5M128.7 34l-.4 .2v.6h.4l.1-.3-.2-.2-.3 .2M128.7 28.8h-.4v.4h.3l.2 .1-.1 .4-.4-.1M128.7 24v.5M130 22.4h3.5M130 24.1h3.5M130 27.6h3.5M130 29.2h3.5M130 32.7h3.5M130 34.4h3.5M130 37.9h3.5M130 39.6h3.5"/>
<path d="M133.4 20.6h10.4v25.8h-10.4zM143.8 22.4h3.4M143.8 27.6h3.4M143.8 32.7h3.4M143.8 37.9h3.4M155.3 33.6h4.1l.7 .8-.7 .9h-4.1zM155.3 38.7h4.1l.7 .9-.7 .8h-4.1zM156.1 34l.2 .8 .4-.8M156.1 39.2l.2 .8 .4-.8M156.2 28.4h3.2l.7 .8-.7 .9h-3.2zM156.2 23.2h3.2l.7 .9-.7 .8h-3.2zM156.8 34.8l.3-.8 .2 .8"/>
<path d="M156.8 28.8l.4 .9 .2-.9M156.8 23.7l.4 .8 .2-.8M156.8 34.7h.5M156.8 39.8h.5M157.6 34.2l.3-.2v.8M157.6 39.4l.3-.2v.8M157.6 29.7l.3-.9 .3 .9M157.6 24.5l.3-.8 .3 .8M157.6 34.8h.5M157.7 29.4h.4M157.7 24.3h.4M158.5 39.4l.2-.2v.8"/>
<path d="M158.6 34a.43 .43 0 0 1 .4 .5 .43 .43 0 0 1-.5 .3v-.6zM158.6 24.1l-.1-.1v-.3h.3l.2 .2-.2 .2h-.3v.3l.4 .1 .1-.3-.2-.1M159 29.2l-.2 .2-.3-.1v-.4l.3-.1 .2 .2-.2 .7h-.3M160.1 22.4h3.5M160.1 24.1h3.5M160.1 27.6h3.5M160.1 29.2h3.5M160.1 32.7h3.5M160.1 34.4h3.5M160.1 37.9h3.5M160.1 39.6h3.5M163.6 20.6h10.3v25.8h-10.3z"/>
<path d="M173.9 22.4h3.4M173.9 27.6h3.4M173.9 32.7h3.4M173.9 37.9h3.4M185.5 23.2h4l.8 .9-.8 .8h-4zM185.5 33.6h4l.8 .8-.8 .9h-4zM185.5 28.4h4l.8 .8-.8 .9h-4zM185.5 38.7h4l.8 .9-.8 .8h-4zM186.2 23.7l.3 .8 .3-.8M186.2 34l.3 .8 .3-.8M186.2 28.8l.3 .9 .3-.9M186.2 39.2l.3 .8 .3-.8"/>
<path d="M187 24.5l.2-.8 .3 .8M187 34.8l.2-.8 .3 .8M187 29.7l.2-.9 .3 .9M187 29.4h.4M187 24.3h.4M187 34.7h.4M187 39.8h.4M187.7 23.9l.3-.2v.8M187.7 34.2l.3-.2v.8M187.7 29.1l.3-.3v.9M187.7 39.4l.3-.2v.8M187.7 29.7h.6"/>
<path d="M187.7 24.5h.6M187.7 34.8h.6M188.5 28.8h.6l-.3 .4 .3 .1-.1 .4-.5-.1M188.6 23.7h.3l.2 .2-.6 .6h.6M188.8 34l-.2 .6h.5M189 39.2h-.4v.4l.3-.1 .2 .4h-.5M189 34.3v.5M190.3 22.4h3.5M190.3 24.1h3.5M190.3 27.6h3.5M190.3 29.2h3.5M190.3 32.7h3.5"/>
<path d="M190.3 34.4h3.5M190.3 37.9h3.5M190.3 39.6h3.5M193.7 20.6h10.3v25.8h-10.3zM204.1 22.4h3.4M204.1 27.6h3.4M204.1 32.7h3.4M204.1 37.9h3.4M216.5 33.6h4l.8 .8-.8 .9h-4zM216.5 38.7h4l.8 .9-.8 .8h-4zM216.5 23.2h4l.8 .9-.8 .8h-4zM216.5 28.4h4l.8 .8-.8 .9h-4z"/>
<path d="M217.2 34l.3 .8 .3-.8M217.2 39.2l.3 .8 .3-.8M217.2 23.7l.3 .8 .3-.8M217.2 28.8l.3 .9 .3-.9M218 34.8l.2-.8 .4 .8M218 24.5l.2-.8 .4 .8M218 29.7l.2-.9 .4 .9M218.1 29.4h.4M218.1 24.3h.4M218.1 34.7h.4M218.1 39.8h.4M218.7 34.2l.3-.2v.8"/>
<path d="M218.7 39.4l.3-.2v.8M218.7 23.9l.3-.2v.8M218.7 29.1l.3-.3v.9M218.7 29.7h.5M218.7 24.5h.5M218.7 34.8h.5M219.6 28.8h.5l-.4 .9M219.7 34.4l-.1-.2 .3-.2 .2 .2-.4 .2-.1 .3 .1 .1h.3l.1-.2-.2-.2M220 23.7h-.3l-.1 .4 .1 .4h.3l.1-.3-.2-.2-.3 .2M220.1 39.6l-.2 .1-.3-.1 .1-.4 .4 .1v.4l-.2 .3h-.2M221.3 22.4h3.4M221.3 24.1h3.4"/>
<path d="M221.3 27.6h3.4M221.3 29.2h3.4M221.3 32.7h3.4M221.3 34.4h3.4M221.3 37.9h3.4M221.3 39.6h3.4M224.7 20.6h10.3v25.8h-10.3zM235.1 22.4h3.4M235.1 27.6h3.4M235.1 32.7h3.4M235.1 37.9h3.4M247.9 32.7v.9h1l-1 .8-.8-.8h.8"/>
<path d="M247.9 32.7h.1M248.4 28.4h4l.8 .8-.8 .9h-4zM248.4 23.2h4l.8 .9-.8 .8h-4zM249 28.8l.4 .9 .2-.9M249 23.7l.4 .8 .2-.8M249.8 29.7l.3-.9 .3 .9M249.8 24.5l.3-.8 .3 .8M249.9 29.4h.4M249.9 24.3h.4M250.7 28.9l.3-.1 .2 .3-.6 .6h.6M250.7 23.7h.3l.2 .2-.6 .6h.6M251.5 29.1l.2-.3v.9"/>
<path d="M251.5 23.7h.3l.1 .1-.1 .7-.3-.1zM251.5 29.7h.4M253.2 22.4h3.4M253.2 24.1h3.4M253.2 27.6h3.4M253.2 29.2h3.4M253.2 32.7h3.4M253.2 34.4h3.4M253.2 37.9h3.4M253.2 39.6h3.4M256.5 20.6h10.4v25.8h-10.4zM266.9 22.4h3.5"/>
<path d="M266.9 27.6h3.5M266.9 32.7h3.5M266.9 37.9h3.5M17.4 43.9h6.8l.7 .8-.7 .9h-6.8zM18.1 44.1h5.6M18.4 40.4h5.8l.7 .9-.7 .9h-5.8zM18.7 44.4a.43 .43 0 0 0-.5 .3 .43 .43 0 0 0 .1 .5h.4M19.1 44.8h.3l.2-.1-.2-.4h-.3v.9M19.1 40.7h4.6M19.3 47.4h4.9l.7 .8-.7 .9h-4.9zM19.8 41l-.5-.1a.44 .44 0 0 0-.1 .6 .44 .44 0 0 0 .6 .2M19.9 44.3v.9l.5-.1v-.8"/>
<path d="M20 47.5h3.7M20.1 47.8l.4 .1 .1 .4-.2 .3h-.3zM20.1 41.4h.3l.2-.2-.1-.3h-.4v.9M20.6 45.3h.7M20.9 47.8h.4M21 40.9v.7l.1 .2 .4-.2v-.7M21.1 47.8v.8M21.5 44.3v.9h.5v-.9M21.5 48.6l.3-.8 .3 .8M21.5 48.4h.5M21.6 41.9h.7M22.4 44.3a.49 .49 0 0 1 .4 .3 .49 .49 0 0 1-.1 .6h-.3z"/>
<path d="M22.4 41.8l.2-.9 .4 .9M22.5 41.5h.4M22.8 47.9l-.3-.1-.2 .3 .2 .5h.3M23.2 47.8v.8M23.3 48.1l.4 .5M23.4 55.9h3.3l.8 1-.8 .8h-3.3zM23.7 44.4h-.5v.3l.5 .3v.2h-.5M23.7 40.9l-.5 .1v.3l.5 .1v.1l-.1 .3-.4-.1M23.7 47.8l-.5 .5M24.1 56.4h.5M24.3 56.4v.9M24.8 57.3v-.9l.4 .6 .2-.6v.9"/>
<path d="M25.4 45.6h6.5l.7 .8-.7 1h-6.5zM26 45.8h5.5M26.3 56.4h-.4l-.1 .2 .1 .3h.4v.3h-.5M26.6 46.2l-.3-.1a.43 .43 0 0 0-.2 .5 .43 .43 0 0 0 .5 .3M27 46.5h.5v-.4h-.5v.8M27.9 46.1v.8h.2l.3-.1v-.7M28.2 42.2h3.7l.7 .8-.7 .9h-3.7zM28.6 49.1h3.3l.7 .8-.7 .9h-3.3zM28.6 50.8h3.3l.7 .9-.7 .8h-3.3zM28.6 52.5h3.3l.7 .9-.7 .8h-3.3zM28.6 47h.6M28.7 54.2h3.2l.7 .9-.7 .8h-3.2z"/>
<path d="M28.7 57.7h3.2l.7 .8-.7 .9h-3.2zM28.7 59.4h3.2l.7 .8-.7 .9h-3.2zM29 40v-.8l.2 .6 .3-.6v.8M29.1 43h.4v-.4h-.4v.9M29.2 43l.4 .5M29.4 46.1v.8h.4M29.4 54.6l.3 1 .3-1M29.4 58.1l.3 .9 .3-.9M29.4 59.8l.3 .9 .3-.9M29.4 49.9h.3M29.4 51.7h.3M29.4 53.4h.3"/>
<path d="M29.8 49.5h-.4v.9M29.8 51.3h-.4v.8M29.8 53h-.4v.8M29.9 40v-.8l.4 .6 .2-.6v.8M30.2 46.1l.4 .2v.4l-.3 .2h-.1zM30.2 55.6l.2-1 .3 1M30.2 59l.2-.9 .3 .9M30.3 55.3h.3M30.3 58.7h.3M30.5 42.5l-.7 1.2M30.6 49.6a.4 .4 0 0 0-.5 .4 .4 .4 0 0 0 .5 .3M30.6 51.3h-.3a.42 .42 0 0 0-.2 .5 .42 .42 0 0 0 .5 .2"/>
<path d="M30.6 53a.42 .42 0 0 0-.5 .3 .42 .42 0 0 0 .2 .5l.3-.1M30.7 42.4h.8M30.8 42.6l.1 .9 .2-.6 .2 .6 .2-.9M30.9 51.5l.3-.2v.8M30.9 54.9l.3-.3v1M30.9 58.2h.6v.3l-.6 .5h.6M30.9 53h.6v.3l-.6 .5h.6M30.9 59.8h.6l-.3 .4h.3v.5h-.6M30.9 52.1h.6M30.9 55.6h.6M31 49.6l.3-.1 .2 .2v.5l-.2 .2a.53 .53 0 0 1-.3-.8zM31.5 46.1h-.5l-.1 .2 .2 .2 .4 .1v.3h-.6"/>
<path d="M31.6 40.1h.7M35.3 43h1.7M35.3 44.7h1.7M35.3 49.9h1.7M35.3 51.7h1.7M35.3 41.3h1.7M35.3 46.4h1.7M35.3 48.2h1.7M35.3 53.4h1.7M35.3 55.1h1.7M35.3 56.9h1.7M35.3 58.5h1.7"/>
<path d="M71.4 43h1.7M71.4 44.7h1.7M71.4 49.9h1.7M71.4 51.7h1.7M71.4 41.3h1.7M71.4 46.4h1.7M71.4 48.2h1.7M71.4 53.4h1.7M71.4 55.1h1.7M71.4 56.9h1.7M71.4 58.5h1.7M76.5 45.6h7.4v1.8h-7.4l-.8-1z"/>
<path d="M76.8 45.8h6.4M77 46.5h.3M77.3 46.1h-.3v.8h.3M77.7 46.1l.6 .8M78.3 57.7h3.5l.8 .8-.8 .9h-3.5zM78.3 46.1l-.6 .8M78.5 46.5h.4l.1-.3-.5-.1v.8M78.8 57.9h2.4M78.9 58.1v.9l.5-.1v-.8M79.2 47h.7M79.8 58.1a.47 .47 0 0 1 .5 .3 .47 .47 0 0 1-.2 .6h-.3zM80 46.5h.4l.2-.1-.1-.3h-.5v.8h.6v-.4h-.2"/>
<path d="M81 46.5h.2M81.1 58.2h-.5v.3l.5 .2v.3h-.5M81.3 46.1h-.3v.8h.3M81.7 46.5h.5v-.4h-.5v.8M81.9 46.5l.4 .4M82.6 46.5h.4v-.4h-.4v.8M82.6 59.4h2.4l.8 .8-.8 .9h-2.4zM82.6 55.9h3.3l.8 1-.8 .8h-3.3zM82.8 46.5l.3 .4M83.1 59.6h1.4M83.1 56.2h2.2M83.2 56.4v.9h.4"/>
<path d="M83.9 56.4l.5 .2v.4l-.3 .3h-.2zM84.4 59.9h-.5v.3l.5 .2v.3h-.5M85.2 56.4h-.4l-.1 .2 .2 .3h.3v.3h-.5M99.9 58.5h3.3M103.2 56.8h10.4v20.7h-10.4zM108.4 53.4h.1M108.4 44.7v.9h.9l-.9 .8-.8-.8h.8M108.4 44.7h.1M108.4 41.3v3.4M108.4 51.7v5.2M108.4 51.7l-.5 .8M108.4 51.7l.6 .8"/>
<path d="M113.7 58.5h3.3M127.5 40l.3-.8 .3 .8M130 44.7v.9h.8l-.8 .8-.8-.8h.8M130 44.7h.1M130 43h3.5M130 44.7h2.5M133.8 56.9h4.1l.7 .8-.7 .8h-4.1zM134.5 57.3l.3 .8 .3-.8M135.3 58.1l.3-.8 .2 .8M135.3 57.9h.5M136.1 57.5l.3-.2v.8M136.1 58.1h.5"/>
<path d="M136.9 57.4l.4-.1 .1 .3-.5 .5h.5M138.6 49.9v.9h.9l-.9 .9-.9-.9h.9M138.6 49.9h.1M138.6 57.7h3.4M138.6 59.4h3.4M138.6 46.4v3.5M142 55.9h10.3v25.9h-10.3zM147.2 52.5h.1M147.2 50.8v5.1M147.2 50.8l-.5 .9M147.2 50.8l.5 .9M152.4 57.7h3.4"/>
<path d="M156.6 56.9h3.3v1.6h-3.3l-.8-.8zM156.8 40l.3-.8 .2 .8M156.9 58.1l.4-.8 .2 .8M157 57.9h.4M157.6 40h.5M157.8 57.5l.2-.2v.8M157.8 58.1h.5M158.5 40h.5M158.6 57.4l.4-.1v.3l-.5 .5h.5M160.1 44.7v.9h.9l-.9 .8-.8-.8h.8M160.1 44.7h.1M160.1 43h3.5"/>
<path d="M160.1 44.7h2.6M164.8 56.9h4.1l.7 .8-.7 .8h-4.1zM165.6 57.3l.2 .8 .3-.8M166.2 58.1l.4-.8 .2 .8M166.3 57.9h.4M167.1 57.5l.2-.2v.8M167.1 58.1h.5M168.4 57.3l-.5 .1v.6l.5 .1v-.5h-.4l-.1 .2M168.8 49.9v.9h.8l-.8 .9-1-.9h1M168.8 49.9h.1M168.8 46.4v3.5M169.6 57.7h3.4"/>
<path d="M169.6 59.4h3.4M173 55.9h10.4v25.9h-10.4zM178.2 52.5h.1M178.2 50.8l-.5 .9M178.2 50.8l.6 .9M178.2 50.8v5.1M183.4 57.7h3.4M187 40l.2-.8 .3 .8M187.6 56.9h3.3v1.6h-3.3l-.8-.8zM187.7 40h.6M187.9 58.1l.4-.8 .2 .8M188 57.9h.4"/>
<path d="M188.8 57.5l.2-.2v.8M188.8 58.1h.5M190 57.3l-.4 .1v.6l.4 .1v-.5h-.3l-.1 .2M190.3 44.7v.9h.8l-.8 .8-.9-.8h.9M190.3 44.7h.1M190.3 43h3.5M190.3 44.7h2.5M197.6 56.9h3.9l.8 .8-.8 .8h-3.9zM198.2 57.3l.4 .8 .2-.8M198.9 49.9v.9h.9l-.9 .9-.9-.9h.9M198.9 49.9h.1M198.9 46.4v3.5"/>
<path d="M199 58.1l.3-.8 .3 .8M199.1 57.9h.4M199.9 57.4l.3-.1 .1 .3-.5 .5h.5M200.7 57.4l.3-.1 .1 .1-.1 .6a.39 .39 0 0 1-.4-.2 .39 .39 0 0 1 .1-.4zM202.3 57.7h3.5M202.3 59.4h3.5M205.7 55.9h10.4v25.9h-10.4zM210.9 52.5h.1M210.9 50.8v5.1M210.9 50.8l-.5 .9M210.9 50.8l.6 .9M216.1 57.7h3.5"/>
<path d="M218 40l.2-.8 .4 .8M218.7 40h.5M220.3 56.9h3.3v1.6h-3.3l-.7-.8zM220.7 58.1l.2-.8 .4 .8M220.8 57.9h.4M221.3 44.7v.9h.8l-.8 .8-.9-.8h.9M221.3 44.7h.1M221.3 43h3.4M221.3 44.7h2.6M221.5 57.4l.5-.1v.3l-.6 .5h.6M222.4 57.4l.3-.1v.7a.39 .39 0 0 1-.4-.2 .39 .39 0 0 1 .1-.4zM229.9 49.9v.9h.9l-.9 .9-.8-.9h.8"/>
<path d="M229.9 49.9h.1M229.9 46.4v3.5M235.1 57.7h3.4M235.1 59.4h3.4M238.5 55.9h10.3v25.9h-10.3zM243.7 52.5h.1M243.7 50.8l-.5 .9M243.7 50.8l.5 .9M243.7 50.8v5.1M248.9 57.7h3.4M253 56.9h3.3v1.6h-3.3l-.7-.8zM253.2 44.7v.9h.8l-.8 .8-.9-.8h.9"/>
<path d="M253.2 44.7h.1M253.2 43h3.4M253.2 44.7h2.5M253.4 58.1l.3-.8 .3 .8M253.5 57.9h.4M254.2 57.4h.5v.2l-.5 .5h.5M255.2 57.2l-.1 .7h.5M255.5 57.5v.6M261.7 49.9v.9h.9l-.9 .9-.8-.9h.8M261.7 49.9h.1M261.7 46.4v3.5M19.9 74.9h7.6v1.8h-7.6l-.7-1z"/>
<path d="M20.5 75.1h6.5M21.1 75.5l-.3-.1a.43 .43 0 0 0-.2 .5 .43 .43 0 0 0 .5 .3M21.5 75.8h.4l.2-.3-.6-.1v.8M22.4 75.4v.8h.2l.3-.1v-.7M23.1 76.3h.6M23.9 75.7h.4l.1-.2-.5-.1v.8h.5v-.4l-.1-.1M24.8 75.7h.3M25.2 75.4h-.4v.8h.4M25.6 75.8h.3l.2-.3-.5-.1v.8M25.8 75.8l.3 .4M26.5 75.8h.3l.2-.3-.5-.1v.8M26.6 75.8l.4 .4"/>
<path d="M28.5 64.6h3.4l.7 .8-.7 .8h-3.4l-.8-.8zM28.5 68h3.4l.7 .9-.7 .8h-3.4l-.8-.8zM28.5 66.2h3.4l.7 1-.7 .8h-3.4l-.8-.8zM28.5 69.7h3.4l.7 .9-.7 .8h-3.4l-.8-.8zM28.5 71.4h3.4l.7 .9-.7 .9h-3.4l-.8-.9zM28.5 73.2h3.4l.7 .8-.7 .9h-3.4l-.8-.9zM29.3 61.1h2.6l.7 .9-.7 .9h-2.6l-.7-.9zM29.3 62.9h2.6l.7 .8-.7 .9h-2.6l-.7-.9zM29.3 65a.47 .47 0 0 1 .5 .4 .47 .47 0 0 1-.5 .5zM29.3 68.4a.49 .49 0 0 1 .5 .4 .49 .49 0 0 1-.1 .5h-.4zM29.3 66.8h.4a.47 .47 0 0 1 .1 .5 .47 .47 0 0 1-.5 .3zM29.3 70.1a.47 .47 0 0 1 .5 .5 .47 .47 0 0 1-.5 .5z"/>
<path d="M29.3 71.9l.5 .1v.4l-.1 .4h-.4zM29.3 73.6a.49 .49 0 0 1 .5 .3 .49 .49 0 0 1-.1 .6h-.4zM30.2 60.7l.2-.9 .3 .9M30.2 61.6l.4 .2v.5l-.3 .1h-.1zM30.2 63.3l.4 .2v.5l-.2 .1h-.2zM30.2 65.2l.2-.2v.9M30.2 68.7l.2-.3v.9M30.2 67l.2-.2v.8M30.2 70.4l.2-.3v1M30.2 72.2l.2-.3v.9M30.2 73.9l.2-.3v.9M30.2 65.9h.4"/>
<path d="M30.2 69.3h.4M30.2 67.6h.4M30.2 71.1h.4M30.2 72.8h.4M30.2 74.5h.4M30.3 60.5h.3M30.9 68.5h.6v.4l-.6 .4h.6M30.9 67l.3-.2v.8M30.9 70.1h.6l-.3 .4 .3 .1v.4h-.6M30.9 67.6h.6M31 65.1l.3-.1 .2 .1v.6l-.2 .2a.53 .53 0 0 1-.3-.8zM31.1 61.9l-.2-.1 .1-.2h.4l.1 .2-.6 .3 .2 .3h.4v-.4l-.2-.1"/>
<path d="M31.2 71.8l-.3 .7h.6M31.4 72.2v.6M31.5 63.6l-.1 .2h-.4l-.1-.3 .2-.2 .4 .1v.6l-.5 .1M31.5 73.6h-.5l-.1 .4h.6v.4h-.6M35.3 60.2h1.7M35.3 62h1.7M35.3 63.7h1.7M35.3 65.4h1.7M35.3 67.2h1.7M35.3 68.9h1.7M35.3 70.6h1.7M35.3 72.3h1.7"/>
<path d="M35.3 74h1.7M35.3 75.7h1.7M35.3 77.5h1.7M35.3 79.2h1.7M71.4 60.2h1.7M71.4 62h1.7M71.4 63.7h1.7M71.4 65.4h1.7M71.4 67.2h1.7M71.4 68.9h1.7M71.4 70.6h1.7M71.4 72.3h1.7"/>
<path d="M71.4 74h1.7M71.4 75.7h1.7M71.4 77.5h1.7M71.4 79.2h1.7M81.7 62.9h7.1l.7 .8-.7 .9h-7.1zM82.3 63.3v.8M82.9 63.3l.4 .2-.1 .6-.4-.1v-.5zM83.1 60.7l.3-.9 .3 .9M83.2 60.5h.4M84.1 63.4a.43 .43 0 0 0-.5 .2 .43 .43 0 0 0 .2 .5l.3-.1M84.4 63.3h.5M84.6 63.3v.8"/>
<path d="M85.2 63.3v.8h.4M85.6 64.2h.7M86.4 63.3h.5M86.7 63.3v.8M87.2 63.3h.2l.3 .2v.5l-.2 .1h-.3zM88.1 63.3v.8M99.9 75.7v1h.8l-.8 .8-.9-.8h.9M99.9 75.7h.1M99.9 60.2h3.3M99.9 62h3.3M99.9 63.7h3.3M99.9 65.4h3.3"/>
<path d="M99.9 67.2h3.3M99.9 68.9h3.3M99.9 70.6h3.3M99.9 74h3.3M99.9 75.7h2.5M108.4 77.5v3.4M113.7 60.2h3.3M113.7 62h3.3M113.7 63.7h3.3M113.7 65.4h3.3M113.7 67.2h3.3M113.7 68.9h3.3"/>
<path d="M113.7 70.6h3.3M133.8 62h4.1l.7 .9-.7 .8h-4.1zM133.8 72.3h4.1l.7 .9-.7 .8h-4.1zM133.8 67.2h4.1l.7 .8-.7 .9h-4.1zM134.5 62.4l.3 .9 .3-.9M134.5 72.8l.3 .8 .3-.8M134.5 67.6l.3 .8 .3-.8M135.3 63.3l.3-.9 .2 .9M135.3 73.6l.3-.8 .2 .8M135.3 68.4l.3-.8 .2 .8M135.3 68.2h.5M135.3 63h.5"/>
<path d="M135.3 73.4h.5M136.1 62.7l.3-.3v.9M136.1 73l.3-.2v.8M136.1 67.9l.3-.3v.8M136.1 73.6h.5M136.1 68.4h.5M136.1 63.3h.5M136.9 62.4h.5l-.3 .4 .3 .1v.3h-.5M137.1 67.5l-.2 .7h.6M137.3 67.9v.5M137.4 72.8h-.5v.4h.5l-.1 .4-.4-.1M138.6 62.9h3.4"/>
<path d="M138.6 64.6h3.4M138.6 68h3.4M138.6 69.7h3.4M138.6 73.2h3.4M138.6 74.9h3.4M138.6 78.4h3.4M152.4 62.9h3.4M152.4 68h3.4M152.4 73.2h3.4M156.6 72.3h3.3v1.7h-3.3l-.8-.8zM156.6 67.2h3.3v1.7h-3.3l-.8-.9zM156.6 62h3.3v1.7h-3.3l-.8-.8z"/>
<path d="M156.9 73.6l.4-.8 .2 .8M156.9 68.4l.4-.8 .2 .8M156.9 63.3l.4-.9 .2 .9M157 68.2h.4M157 63h.4M157 73.4h.4M157.8 73l.2-.2v.8M157.8 67.9l.2-.3v.8M157.8 62.7l.2-.3v.9M157.8 73.6h.5M157.8 68.4h.5M157.8 63.3h.5"/>
<path d="M158.5 62.4h.5l-.2 .4 .2 .1v.3h-.5M158.8 67.5l-.2 .7h.5M159 67.9v.5M159 72.8h-.4v.4h.4v.4l-.4-.1M164.8 67.2h4.1l.7 .8-.7 .9h-4.1zM164.8 62h4.1l.7 .9-.7 .8h-4.1zM164.8 72.3h4.1l.7 .9-.7 .8h-4.1zM165.6 67.6l.2 .8 .3-.8M165.6 62.4l.2 .9 .3-.9M165.6 72.8l.2 .8 .3-.8M166.2 68.4l.4-.8 .2 .8M166.2 63.3l.4-.9 .2 .9"/>
<path d="M166.2 73.6l.4-.8 .2 .8M166.3 68.2h.4M166.3 63h.4M166.3 73.4h.4M167.1 67.9l.2-.3v.8M167.1 62.7l.2-.3v.9M167.1 73l.2-.2v.8M167.1 73.6h.5M167.1 68.4h.5M167.1 63.3h.5M167.8 62.4h.6l-.3 .9M168.1 67.9l-.2-.2 .5-.1v.3l-.5 .1 .1 .4h.4v-.3l-.1-.2"/>
<path d="M168.4 73.1v.2h-.4l-.1-.4 .4-.1 .1 .1-.1 .7h-.3M169.6 62.9h3.4M169.6 64.6h3.4M169.6 68h3.4M169.6 69.7h3.4M169.6 73.2h3.4M169.6 74.9h3.4M169.6 78.4h3.4M183.4 62.9h3.4M183.4 68h3.4M183.4 73.2h3.4M187.6 72.3h3.3v1.7h-3.3l-.8-.8z"/>
<path d="M187.6 67.2h3.3v1.7h-3.3l-.8-.9zM187.6 62h3.3v1.7h-3.3l-.8-.8zM187.9 73.6l.4-.8 .2 .8M187.9 68.4l.4-.8 .2 .8M187.9 63.3l.4-.9 .2 .9M188 68.2h.4M188 63h.4M188 73.4h.4M188.8 73l.2-.2v.8M188.8 67.9l.2-.3v.8M188.8 62.7l.2-.3v.9M188.8 73.6h.5"/>
<path d="M188.8 68.4h.5M188.8 63.3h.5M189.5 62.4h.6l-.3 .9M189.8 67.9l-.2-.2 .4-.1v.3l-.4 .1 .1 .4h.3l.1-.1-.2-.4M190.1 73.1l-.1 .2h-.3l-.1-.4 .3-.1 .2 .1-.2 .7h-.2M197.6 67.2h3.9l.8 .8-.8 .9h-3.9zM197.6 72.3h3.9l.8 .9-.8 .8h-3.9zM197.6 62h3.9l.8 .9-.8 .8h-3.9zM198.2 67.6l.4 .8 .2-.8M198.2 72.8l.4 .8 .2-.8M198.2 62.4l.4 .9 .2-.9M199 68.4l.3-.8 .3 .8"/>
<path d="M199 73.6l.3-.8 .3 .8M199 63.3l.3-.9 .3 .9M199.1 68.2h.4M199.1 63h.4M199.1 73.4h.4M199.9 67.7l.3-.1 .1 .3-.5 .5h.5M199.9 72.9l.3-.1 .1 .3-.5 .5h.5M199.9 62.5l.3-.1 .1 .4-.5 .5h.5M200.6 67.7h.5v.2l-.5 .5h.5M200.6 72.8h.5l-.2 .3 .2 .1v.3h-.5M200.6 62.7l.3-.3v.9M200.6 63.3h.5"/>
<path d="M202.3 62.9h3.5M202.3 64.6h3.5M202.3 68h3.5M202.3 69.7h3.5M202.3 73.2h3.5M202.3 74.9h3.5M202.3 78.4h3.5M216.1 62.9h3.5M216.1 68h3.5M216.1 73.2h3.5M220.3 72.3h3.3v1.7h-3.3l-.7-.8zM220.3 67.2h3.3v1.7h-3.3l-.7-.9z"/>
<path d="M220.3 62h3.3v1.7h-3.3l-.7-.8zM220.7 73.6l.2-.8 .4 .8M220.7 68.4l.2-.8 .4 .8M220.7 63.3l.2-.9 .4 .9M220.8 68.2h.4M220.8 63h.4M220.8 73.4h.4M221.5 72.9l.4-.1 .1 .3-.6 .5h.6M221.5 67.7l.5-.1v.3l-.6 .5h.6M221.5 62.5l.5-.1v.4l-.6 .5h.6M222.3 72.8h.5l-.3 .3 .3 .1v.3h-.5M222.3 67.7h.5v.2l-.5 .5h.5"/>
<path d="M222.3 62.7l.2-.3v.9M222.3 63.3h.5M225.6 76.7v.8h.8l-.8 .9-.9-.9h.9M225.6 76.7h.1M235.1 62.9h3.4M235.1 64.6h3.4M235.1 68h3.4M235.1 69.7h3.4M235.1 73.2h3.4M235.1 74.9h3.4M235.1 78.4h3.4M248.9 62.9h3.4"/>
<path d="M248.9 68h3.4M248.9 73.2h3.4M253 67.2h3.3v1.7h-3.3l-.7-.9zM253 62h3.3v1.7h-3.3l-.7-.8zM253 72.3h3.3v1.7h-3.3l-.7-.8zM253.4 68.4l.3-.8 .3 .8M253.4 63.3l.3-.9 .3 .9M253.4 73.6l.3-.8 .3 .8M253.5 68.2h.4M253.5 63h.4M253.5 73.4h.4M254.2 67.7h.5v.2l-.5 .5h.5"/>
<path d="M254.2 62.5h.5v.3l-.5 .5h.5M254.2 72.9h.5v.2l-.5 .5h.5M255 72.8h.6l-.4 .8M255.5 67.6l-.4 .2v.6h.4v-.5h-.4v.2M255.5 62.4h-.4v.5l.4-.1 .1 .1-.1 .4-.4-.1M35.3 94.7h1.7M35.3 96.4h1.7M35.3 98.2h1.7M35.3 99.9h1.7M35.3 93h1.7M35.3 80.9h1.7M35.3 82.7h1.7"/>
<path d="M35.3 84.4h1.7M35.3 86.1h1.7M35.3 87.8h1.7M35.3 89.5h1.7M35.3 91.2h1.7M71.4 94.7h1.7M71.4 96.4h1.7M71.4 98.2h1.7M71.4 99.9h1.7M71.4 93h1.7M71.4 80.9h1.7M71.4 82.7h1.7"/>
<path d="M71.4 84.4h1.7M71.4 86.1h1.7M71.4 87.8h1.7M71.4 89.5h1.7M71.4 91.2h1.7M82.5 80h3.3v1.8h-3.3l-.8-.9zM82.8 80.6h.6M83.1 80.6v.8M84.1 80.6h-.3a.43 .43 0 0 0-.2 .5 .43 .43 0 0 0 .5 .2M84.5 80.6v.8M84.6 80.9l.4 .5M85 80.6l-.5 .4"/>
<path d="M95.5 98.2v.8h.9l-.9 .9-.8-.9h.8M95.5 98.2h.1M99.9 94.7h3.3M99.9 96.4h3.3M99.9 98.2h3.3M99.9 99.9h3.3M103.2 93h10.4v20.6h-10.4zM108.4 80.9v.9h.9l-.9 .9-.8-.9h.8M108.4 80.9h.1M108.4 89.5h.1M108.4 87.8v5.2M108.4 87.8l-.5 .9"/>
<path d="M108.4 87.8l.6 .9M113.7 94.7h3.3M113.7 96.4h3.3M113.7 98.2h3.3M113.7 99.9h3.3M138.6 80v.9h.9l-.9 .9-.9-.9h.9M138.6 80h.1M138.6 80h2.6M147.2 85.2v.9h.8l-.8 .9-.9-.9h.9M147.2 85.2h.1M147.2 81.8v3.4M147.5 99h3.2l.8 .9-.8 .8h-3.2z"/>
<path d="M147.5 97.3h3.2l.8 .9-.8 .8h-3.2zM147.5 92.2h3.2l.8 .8-.8 .8h-3.2zM147.5 95.5h3.2l.8 .9-.8 .9h-3.2zM147.5 93.8h3.2l.8 .9-.8 .8h-3.2zM148.3 99.4l.2 1 .4-1M148.3 97.7l.2 .9 .4-.9M148.3 92.6l.2 .8 .4-.8M148.3 96.1l.2 .8 .4-.8M148.3 94.3l.2 .9 .4-.9M149 98.6l.3-.9 .3 .9M149 93.4l.3-.8 .3 .8M149 96.9l.3-.8 .3 .8"/>
<path d="M149 95.2l.3-.9 .3 .9M149.1 98.3h.4M149.1 93.2h.4M149.1 96.6h.4M149.1 95h.4M149.8 92.8l.3-.2v.8M149.8 96.1h.5l-.2 .3 .2 .1v.2l-.1 .2-.4-.1M149.8 94.4l.4-.1 .1 .1-.5 .8h.5M149.8 93.4h.5M150.1 97.7l-.3 .6h.5M150.2 99.4h-.3l-.1 .5 .4-.1 .1 .4-.1 .2-.4-.1M150.2 98v.6"/>
<path d="M151.5 94.7h3.5M151.5 96.4h3.5M151.5 98.2h3.5M151.5 99.9h3.5M151.5 93h3.5M154.9 91.2h10.4v20.7h-10.4zM160.1 87.8h.1M160.1 86.1v5.1M160.1 86.1l-.5 .9M160.1 86.1l.6 .9M165.3 94.7h3.5M165.3 96.4h3.5"/>
<path d="M165.3 98.2h3.5M165.3 99.9h3.5M165.3 93h3.5M168.8 97.3h2.4l.8 .9-.8 .8h-2.4zM168.8 99h2.4l.8 .9-.8 .8h-2.4zM168.8 93.8h2.4l.8 .9-.8 .8h-2.4zM168.8 92.2h2.4l.8 .8-.8 .8h-2.4zM168.8 95.5h2.4l.8 .9-.8 .9h-2.4zM169.2 98.6l.3-.9 .3 .9M169.2 95.2l.3-.9 .3 .9M169.2 93.4l.3-.8 .3 .8M169.2 96.9l.3-.8 .3 .8"/>
<path d="M169.3 98.3h.4M169.3 93.2h.4M169.3 96.6h.4M169.3 95h.4M169.6 80v.9h.9l-.9 .9-.8-.9h.8M169.6 80h.1M169.6 80h2.6M170 96.1h.6l-.4 .3h.3l.1 .3-.2 .2-.4-.1M170 94.4l.4-.1 .2 .2-.6 .7h.6M170 92.8l.3-.2v.8M170 93.4h.6M170.2 97.7l-.2 .6h.6"/>
<path d="M170.5 99.4h-.5v.5l.4-.1 .2 .4-.2 .2-.4-.1M170.5 98v.6M178.2 85.2v.9h.9l-.9 .9-.9-.9h.9M178.2 85.2h.1M178.2 81.8v3.4M179.4 95.5h4.1l.8 .9-.8 .9h-4.1zM179.4 93.8h4.1l.8 .9-.8 .8h-4.1zM180 99.9v.8h.8l-.8 .9-.9-.9h.9M180 99.9h.1M180.2 96.1l.3 .8 .2-.8M180.2 94.3l.3 .9 .2-.9M180.3 92.2h3.2l.8 .8-.8 .8h-3.2z"/>
<path d="M180.9 96.9l.3-.8 .3 .8M180.9 95.2l.3-.9 .3 .9M181 92.6l.3 .8 .3-.8M181 96.6h.4M181 95h.4M181.7 96.3l.3-.2v.8M181.7 93.4l.3-.8 .3 .8M181.7 94.5l.3-.2v.9M181.7 95.2h.5M181.7 96.9h.5M181.8 93.2h.4M182.6 96.3l.2-.2v.8"/>
<path d="M182.6 96.9h.5M182.7 94.3a.48 .48 0 0 1 .4 .4 .48 .48 0 0 1-.4 .5l-.1-.2v-.6zM183.1 92.9l-.1 .2h-.3l-.1-.4 .4-.1 .1 .1-.2 .7h-.2M184.3 94.7h3.4M184.3 96.4h3.4M184.3 98.2h3.4M184.3 99.9h3.4M184.3 93h3.4M187.6 91.2h10.3v20.7h-10.3zM192.8 87.8h.1M192.8 86.1l-.5 .9M192.8 86.1l.6 .9"/>
<path d="M192.8 86.1v5.1M198 94.7h3.5M198 96.4h3.5M198 98.2h3.5M198 99.9h3.5M198 93h3.5M201.5 93.8h3.3l.7 .9-.7 .8h-3.3zM201.5 92.2h2.4l.8 .8-.8 .8h-2.4zM201.5 95.5h3.3l.7 .9-.7 .9h-3.3zM202 95.2l.2-.9 .4 .9M202 93.4l.2-.8 .4 .8M202 96.9l.2-.8 .4 .8"/>
<path d="M202.1 93.2h.4M202.1 96.6h.4M202.1 95h.4M202.3 80v.9h.9l-.9 .9-.8-.9h.8M202.3 80h.1M202.3 80h2.6M202.7 94.5l.3-.2v.9M202.7 96.3l.3-.2v.8M202.7 95.2h.5M202.7 96.9h.5M203.2 92.9v.2h-.4v-.5l.4 .1v.6l-.4 .1M203.6 96.3l.2-.2v.8"/>
<path d="M203.6 96.9h.5M203.7 94.4l.1-.1a.59 .59 0 0 1 .1 .9 .53 .53 0 0 1-.2-.8zM206.4 95.2h2.1M207.5 93.8h.1M207.5 97.3v.9h.9l-.9 .8-.9-.8h.9M207.5 97.3h.1M207.5 92.2l-.5 .8M207.5 92.2l.5 .8M207.5 92.2v3M207.5 95.9v1.4M210.9 85.2v.9h.9l-.9 .9-.8-.9h.8M210.9 85.2h.1"/>
<path d="M210.9 81.8v3.4M215.1 95.2h2M216.1 93.8v1.4M216.1 95.9v1.4M223.7 95.2h2M224.7 93.8v1.4M224.7 95.9v1.4M232.2 95.2h2.2M233.4 93.8v1.4M233.4 95.9v1.4M235.1 80v.9h.8l-.8 .9-.9-.9h.9M235.1 80h.1"/>
<path d="M235.1 80h2.5M240.9 95.2h2M241.9 93.8v1.4M241.9 95.9v1.4M243.7 85.2v.9h.9l-.9 .9-.9-.9h.9M243.7 85.2h.1M243.7 81.8v3.4M249.5 95.2h2M250.6 93.8v1.4M250.6 95.9v1.4M258.1 95.2h2.1M259.2 93.8v1.4"/>
<path d="M259.2 95.9v1.4M266.7 95.2h2.1M267.8 93.8v1.4M267.8 95.9v1.4M275.3 95.2h2.1M276.4 93.8v1.4M276.4 95.9v1.4M35.3 101.6h1.7M35.3 103.3h1.7M39.6 119.7h.1M39.6 118l-.5 .8M39.6 118l.5 .8"/>
<path d="M39.6 118v3.4M41.3 119.7v1.7M48.1 108.5v.8h1l-1 .9-.8-.9h.8M48.1 108.5h.1M48.1 106.8v1.7M49.9 106.8v1.7M51.6 106.8v1.7M53.3 106.8v1.7M55.1 106.8v1.7M56.8 106.8v1.7M58.5 106.8v1.7M60.2 106.8v1.7"/>
<path d="M99.9 112v.8h.8l-.8 .9-.9-.9h.9M99.9 112h.1M99.9 101.6h3.3M99.9 103.3h3.3M99.9 105h3.3M99.9 106.8h3.3M99.9 110.2h3.3M99.9 112h2.5M108.4 117.1v.9h.9l-.9 .8-.8-.8h.8M108.4 117.1h.1M108.4 113.7v3.4M113.7 101.6h3.3"/>
<path d="M113.7 103.3h3.3M113.7 105h3.3M113.7 106.8h3.3M143.2 109.3l.6 .9M143.8 108.5h.1M143.8 108.5v1.7M144.3 109.3l-.5 .9M147.5 100.7h3.2l.8 .9-.8 .9h-3.2zM147.5 102.5h3.2l.8 .8-.8 .9h-3.2zM147.5 104.2h3.2l.8 .8-.8 .9h-3.2zM148.3 101.2l.2 .9 .4-.9M148.3 102.9l.2 .9 .4-.9"/>
<path d="M148.3 104.6l.2 .9 .4-.9M149 102.1l.3-.9 .3 .9M149 103.8l.3-.9 .3 .9M149 105.5l.3-.9 .3 .9M149 100.4l.3-1 .3 1M149.1 101.8h.4M149.1 103.5h.4M149.1 105.3h.4M149.1 100.1h.4M149.8 102.9h.5l-.3 .9M150 105l-.2-.2 .4-.2 .1 .3-.5 .3 .2 .3 .3-.1-.1-.4M150.2 101.2h-.2l-.2 .7 .2 .2 .3-.2-.1-.3h-.3l-.1 .1"/>
<path d="M151.5 110.2v.8h.9l-.9 1-.8-1h.8M151.5 110.2h.1M151.5 101.6h3.5M151.5 103.3h3.5M151.5 105h3.5M151.5 110.2h2.6M151.5 108.5h3.5M160.1 115.4v.8h.9l-.9 .9-.8-.9h.8M160.1 115.4h.1M160.1 112v3.4M160.6 100.7h-.9v1.8M161 100.7h-.4v1.8h-1.3"/>
<path d="M165.3 101.6h3.5M165.3 103.3h3.5M165.3 105h3.5M168.8 100.7h2.4l.8 .9-.8 .9h-2.4zM168.8 104.2h2.4l.8 .8-.8 .9h-2.4zM168.8 102.5h2.4l.8 .8-.8 .9h-2.4zM169.2 100.4l.3-1 .3 1M169.2 102.1l.3-.9 .3 .9M169.2 105.5l.3-.9 .3 .9M169.2 103.8l.3-.9 .3 .9M169.3 101.8h.4M169.3 103.5h.4"/>
<path d="M169.3 105.3h.4M169.3 100.1h.4M169.6 118.8v3.5M169.6 118.8l-.5 .9M169.6 118.8l.5 .9M170 102.9h.6l-.4 .9M170.2 105l-.2-.1v-.2l.4-.1 .2 .3-.6 .2v.3l.2 .1 .4-.1-.2-.4M170.5 101.2l-.5 .2v.6l.4 .1 .2-.2-.1-.3h-.4l-.1 .1M176 109.3l.5 .9M176.5 108.5h.1M176.5 108.5v1.7M177 109.3l-.5 .9"/>
<path d="M184.3 110.2v.8h.8l-.8 1-.9-1h.9M184.3 110.2h.1M184.3 101.6h3.4M184.3 103.3h3.4M184.3 105h3.4M184.3 110.2h2.5M184.3 108.5h3.4M192.8 115.4v.8h1l-1 .9-.8-.9h.8M192.8 115.4h.1M192.8 112v3.4M193.3 100.7h-.9v1.8M193.8 100.7h-.5v1.8h-1.3"/>
<path d="M198 101.6h3.5M198 103.3h3.5M198 105h3.5M209.3 118.8l-.6 .9M209.3 118.8l.5 .9M209.3 118.8v3.5M214.2 108.1h2M215.3 110.2v.8h.8l-.8 1-.9-1h.9M215.3 110.2h.1M215.3 106.8h.1M215.3 105v3.2M215.3 108.8v1.4"/>
<path d="M215.3 105l-.5 .9M215.3 105l.5 .9M222.8 108.1h2.1M223.9 106.8v1.4M223.9 108.8v1.4M226.2 117.6h2.1M227.3 116.2h.1M227.3 119.7v.8h.9l-.9 .9-.9-.9h.9M227.3 119.7h.1M227.3 114.5l-.5 .9M227.3 114.5l.5 .9M227.3 114.5v3.1"/>
<path d="M227.3 118.3v1.4M231.4 108.1h2.1M232.4 106.8v1.4M232.4 108.8v1.4M234.9 117.6h2M235.9 116.2v1.4M235.9 118.3v1.4M240 108.1h2.1M241.1 106.8v1.4M241.1 108.8v1.4M243.5 117.6h2M244.6 116.2v1.4"/>
<path d="M244.6 118.3v1.4M248.7 108.1h2M249.7 106.8v1.4M249.7 108.8v1.4M257.2 108.1h2.1M258.4 106.8v1.4M258.4 108.8v1.4M265.9 108.1h2M266.9 106.8v1.4M266.9 108.8v1.4M274.5 108.1h2M275.5 106.8v1.4"/>
<path d="M275.5 108.8v1.4M25.3 137.8h4l.8 .8-.8 .9h-4zM25.3 136h4l.8 .9-.8 .9h-4zM25.3 130.8h4l.8 1-.8 .8h-4zM25.3 124h4l.8 .8-.8 .9h-4zM25.3 132.6h4l.8 .9-.8 .8h-4zM25.3 125.7h4l.8 .9-.8 .9h-4zM25.3 134.3h4l.8 .9-.8 .8h-4zM25.3 127.5h4l.8 .8-.8 .9h-4zM25.3 129.2h4l.8 .8-.8 .8h-4zM26 138.2l.3 .9 .2-.9M26 136.5l.3 .9 .2-.9"/>
<path d="M26 131.4l.3 .8 .2-.8M26 124.4l.3 .9 .2-.9M26 133.1l.3 .8 .2-.8M26 126.2l.3 .8 .2-.8M26 134.7l.3 1 .2-1M26 127.9l.3 .8 .2-.8M26 129.6l.3 .9 .2-.9M26.7 139.1l.3-.9 .3 .9M26.7 137.4l.3-.9 .3 .9M26.7 132.2l.3-.8 .3 .8M26.7 125.3l.3-.9 .3 .9M26.7 133.9l.3-.8 .3 .8"/>
<path d="M26.7 127l.3-.8 .3 .8M26.7 135.7l.3-1 .3 1M26.7 128.7l.3-.8 .3 .8M26.7 130.5l.3-.9 .3 .9M26.8 138.8h.4M26.8 137.1h.4M26.8 131.9h.4M26.8 125.1h.4M26.8 133.6h.4M26.8 126.8h.4M26.8 135.4h.4M26.8 128.5h.4"/>
<path d="M26.8 130.3h.4M27.6 138.3l.3-.1 .2 .2-.5 .7h.5M27.6 136.6l.4-.1 .1 .2-.5 .7h.5M27.6 131.6l.2-.2v.8M27.6 124.7l.2-.3v.9M27.6 133.1h.3l.2 .1-.5 .7h.5M27.6 126.4l.2-.2v.8M27.6 134.8l.3-.1 .2 .2-.5 .8h.5M27.6 128.1l.2-.2v.8M27.6 129.8l.2-.2v.9M27.6 132.2h.5M27.6 125.3h.5"/>
<path d="M27.6 127h.5M27.6 128.7h.5M27.6 130.5h.5M28.3 138.2h.6l-.3 .4 .3 .1-.1 .4-.5-.1M28.3 127.9h.6l-.3 .8M28.4 136.6l.4-.1 .1 .3-.6 .6h.6M28.4 135l.3-.3v1M28.4 135.7h.5M28.6 133.1a.43 .43 0 0 1 .3 .4 .43 .43 0 0 1-.4 .4l-.1-.7zM28.6 130l-.2-.1v-.2l.3-.1 .2 .2-.5 .3v.3l.2 .1 .3-.2-.2-.3M28.8 124.4h-.4v.4h.3l.2 .4-.2 .1h-.3M28.8 126.2l-.4 .2v.6h.3l.2-.1-.1-.4h-.3l-.1 .2"/>
<path d="M28.9 131.7l-.1 .2h-.3l-.1-.5h.4l.1 .1-.1 .5-.3 .2M32.6 124.8h1.8M32.6 126.6h1.8M32.6 128.3h1.8M32.6 130h1.8M32.6 131.8h1.8M32.6 133.5h1.8M32.6 135.2h1.8M32.6 136.9h1.8M32.6 138.6h1.8M34.4 121.4h12v43.1h-12zM46.4 124.8h1.7"/>
<path d="M46.4 126.6h1.7M46.4 128.3h1.7M46.4 130h1.7M46.4 131.8h1.7M46.4 133.5h1.7M46.4 135.2h1.7M46.4 136.9h1.7M46.4 138.6h1.7M64.6 130.8h3.3M64.6 132.6h3.3M64.6 134.3h3.3M64.6 136h3.3"/>
<path d="M64.6 137.8h3.3M64.6 139.5h3.3M67.9 129.1h10.3v20.7h-10.3zM73.1 125.7h.1M73.1 124v5.2M73.1 124l-.5 .8M73.1 124l.6 .8M73.5 138.6h-.8v1.7M74 138.6h-.5v1.7h-1.2M78.3 130.8h3.4M78.3 132.6h3.4M78.3 134.3h3.4"/>
<path d="M78.3 136h3.4M78.3 137.8h3.4M78.3 139.5h3.4M82.5 138.6h3.4l.8 .9-.8 .8h-3.4l-.8-.8zM82.5 131.8h2.6l.7 .8-.7 .9h-2.6l-.8-.9zM82.5 135.2h3.4l.8 .8-.8 .9h-3.4l-.8-.9zM82.5 133.5h3.4l.8 .8-.8 .9h-3.4l-.8-.9zM82.5 136.9h3.4l.8 .9-.8 .8h-3.4l-.8-.8zM82.5 130h2.6l.7 .8-.7 1h-2.6l-.8-1zM83 139.1a.49 .49 0 0 1 .5 .3 .49 .49 0 0 1-.1 .5h-.4zM83 132.2l.4 .1 .1 .4-.1 .4h-.4zM83 135.7h.4a.48 .48 0 0 1 .1 .5 .48 .48 0 0 1-.5 .3z"/>
<path d="M83 133.9a.49 .49 0 0 1 .5 .3 .49 .49 0 0 1-.1 .5h-.4zM83 137.4l.4 .1 .1 .4-.1 .3h-.4zM83 130.5h.4a.48 .48 0 0 1 .1 .6 .48 .48 0 0 1-.5 .3zM83.8 139.3l.2-.2v.8M83.8 135.9l.2-.2v.8M83.8 134.2l.2-.3v.8M83.8 137.6l.2-.2v.8M83.8 139.9h.5M83.8 136.5h.5M83.8 134.7h.5M83.8 138.2h.5M83.9 130.8l-.1-.1 .1-.2 .4 .1v.2h-.4l-.1 .2 .1 .4 .4-.1v-.4l-.2-.1"/>
<path d="M84.3 132.5l-.1 .2h-.3v-.5l.4 .1v.6l-.4 .2M84.6 139.1h.5l-.2 .3 .2 .1v.4h-.5M84.6 135.9l.3-.2v.8M84.6 137.5h.5v.2l-.5 .5h.5M84.6 136.5h.5M84.7 134l.3-.1 .1 .2-.1 .6h-.2l-.2-.2zM95.5 130.8h3.5M95.5 132.6h3.5M95.5 134.3h3.5M95.5 136h3.5M95.5 137.8h3.5M95.5 139.5h3.5"/>
<path d="M99 129.1h10.3v20.7h-10.3zM104.2 125.7h.1M104.2 124l-.5 .8M104.2 124l.5 .8M104.2 124v5.2M104.6 138.6h-.8v1.7M105 138.6h-.4v1.7h-1.4M109.3 130.8h3.4M109.3 132.6h3.4M109.3 134.3h3.4M109.3 136h3.4M109.3 137.8h3.4"/>
<path d="M109.3 139.5h3.4M113.5 131.8h2.6l.8 .8-.8 .9h-2.6l-.8-.9zM113.5 136.9h3.4l.7 .9-.7 .8h-3.4l-.8-.8zM113.5 135.2h3.4l.7 .8-.7 .9h-3.4l-.8-.9zM113.5 133.5h3.4l.7 .8-.7 .9h-3.4l-.8-.9zM113.5 130h2.6l.8 .8-.8 1h-2.6l-.8-1zM113.5 138.6h3.4l.7 .9-.7 .8h-3.4l-.8-.8zM114 132.2l.4 .1 .1 .4-.2 .4h-.3zM114 137.4l.4 .1 .1 .4-.2 .3h-.3zM114 135.7h.3a.48 .48 0 0 1 .2 .5 .48 .48 0 0 1-.5 .3zM114 133.9a.49 .49 0 0 1 .5 .3 .49 .49 0 0 1-.2 .5h-.3zM114 130.5h.3a.48 .48 0 0 1 .2 .6 .48 .48 0 0 1-.5 .3z"/>
<path d="M114 139.1a.49 .49 0 0 1 .5 .3 .49 .49 0 0 1-.2 .5h-.3zM114.8 137.6l.3-.2v.8M114.8 135.9l.3-.2v.8M114.8 134.2l.3-.3v.8M114.8 139.3l.3-.2v.8M114.8 139.9h.6M114.8 136.5h.6M114.8 134.7h.6M114.8 138.2h.6M115 130.8l-.2-.2 .5-.1 .1 .2-.2 .1-.4 .1v.4l.2 .1 .4-.2-.2-.4M115.4 132.5l-.1 .2h-.4l-.1-.4 .5-.1 .1 .2-.2 .7h-.3M115.6 137.5h.5v.2l-.5 .5h.5"/>
<path d="M115.6 135.9l.3-.2v.8M115.6 139.1h.5l-.2 .3 .2 .1v.4h-.5M115.6 136.5h.5M115.7 134l.2-.1 .2 .2-.1 .6h-.2l-.2-.2zM124.8 130.8h3.4M124.8 132.6h3.4M124.8 134.3h3.4M124.8 136h3.4M124.8 137.8h3.4M124.8 139.5h3.4M128.2 129.1h10.4v20.7h-10.4zM133.5 125.7h.1"/>
<path d="M133.5 124l-.6 .8M133.5 124l.5 .8M133.5 124v5.2M133.9 138.6h-.9v1.7M134.3 138.6h-.4v1.7h-1.4M138.6 130.8h3.4M138.6 132.6h3.4M138.6 134.3h3.4M138.6 136h3.4M138.6 137.8h3.4M138.6 139.5h3.4M142.8 133.5h2.6l.8 .8-.8 .9h-2.6l-.8-.9z"/>
<path d="M142.8 135.2h2.6l.8 .8-.8 .9h-2.6l-.8-.9zM142.8 138.6h2.6l.8 .9-.8 .8h-2.6l-.8-.8zM142.8 130h2.6l.8 .8-.8 1h-2.6l-.8-1zM142.8 131.8h2.6l.8 .8-.8 .9h-2.6l-.8-.9zM142.8 136.9h2.6l.8 .9-.8 .8h-2.6l-.8-.8zM143.3 133.9a.49 .49 0 0 1 .4 .3 .49 .49 0 0 1-.1 .5h-.3zM143.3 135.7h.3a.48 .48 0 0 1 .2 .5 .48 .48 0 0 1-.5 .3zM143.3 139.1a.49 .49 0 0 1 .4 .3 .49 .49 0 0 1-.1 .5h-.3zM143.3 130.5h.3a.48 .48 0 0 1 .2 .6 .48 .48 0 0 1-.5 .3zM143.3 132.2l.4 .1 .1 .4-.2 .4h-.3zM143.3 137.4l.4 .1 .1 .4-.2 .3h-.3zM144.1 135.7h.5l-.3 .3h.3v.4h-.5"/>
<path d="M144.1 134h.5v.3l-.5 .4h.5M144.1 132.5l.2-.3v.9M144.1 133.1h.5M144.2 130.5h.3l.1 .2v.5l-.2 .2-.3-.2zM144.3 137.3l-.2 .7h.5M144.5 137.6v.6M144.6 139.1h-.5v.4h.5v.4h-.5M162.7 130.8h1.8M162.7 132.6h1.8M162.7 134.3h1.8M162.7 136h1.8M162.7 137.8h1.8"/>
<path d="M162.7 139.5h1.8M162.7 125.7h1.8M162.7 127.5h1.8M162.7 129.2h1.8M164.5 122.3h12v47.3h-12zM169.6 120.5h.1M171.3 120.5v1.8M176.5 130.8h1.7M176.5 132.6h1.7M176.5 134.3h1.7M176.5 136h1.7M176.5 137.8h1.7"/>
<path d="M176.5 139.5h1.7M176.5 125.7h1.7M176.5 127.5h1.7M176.5 129.2h1.7M202.3 130.8h1.8M202.3 132.6h1.8M202.3 134.3h1.8M202.3 136h1.8M202.3 137.8h1.8M202.3 139.5h1.8M202.3 125.7h1.8M202.3 127.5h1.8"/>
<path d="M202.3 129.2h1.8M204.1 122.3h12v47.3h-12zM209.3 120.5h.1M210.9 120.5v1.8M216.1 130.8h1.7M216.1 132.6h1.7M216.1 134.3h1.7M216.1 136h1.7M216.1 137.8h1.7M216.1 139.5h1.7M216.1 125.7h1.7M216.1 127.5h1.7"/>
<path d="M216.1 129.2h1.7M227.1 130.5h2.1M228.2 129.2h.1M228.2 132.6v.9h.9l-.9 .8-.9-.8h.9M228.2 132.6h.1M228.2 127.5l-.6 .8M228.2 127.5l.5 .8M228.2 127.5v3M228.2 131.2v1.4M235.7 130.5h2M236.8 129.2v1.3M236.8 131.2v1.4"/>
<path d="M244.3 130.5h2.1M245.4 129.2v1.3M245.4 131.2v1.4M252.9 130.5h2.1M254 129.2v1.3M254 131.2v1.4M261.5 130.5h2.1M262.6 129.2v1.3M262.6 131.2v1.4M270.2 130.5h2M271.2 129.2v1.3M271.2 131.2v1.4"/>
<path d="M17.1 155.8v1h.9l-.9 .8-.8-.8h.8M17.1 155.8h.1M32.6 140.3h1.8M32.6 142.1h1.8M32.6 143.8h1.8M32.6 145.5h1.8M32.6 147.3h1.8M32.6 149h1.8M32.6 152.4h.9M32.6 154.1h.9M32.6 155.8h.9M32.6 157.6h.9"/>
<path d="M32.6 159.3h.9M46.4 140.3h1.7M46.4 142.1h1.7M46.4 143.8h1.7M46.4 145.5h1.7M46.4 147.3h1.7M46.4 149h1.7M46.4 154.1h1.7M46.4 155.8h1.7M46.4 157.6h1.7M46.4 159.3h1.7M46.4 150.7h1.7"/>
<path d="M47.9 153.9l.5 .5M47.9 155.6l.5 .5M47.9 157.3l.5 .6M47.9 159l.5 .6M48.4 153.9l-.5 .5M48.4 155.6l-.5 .5M48.4 157.3l-.5 .6M48.4 159l-.5 .6M60.2 145.5h3.6l.8 .9-.8 .9h-3.6zM60.9 146.4h.4l.1-.3-.5-.1v.9M61.2 146.4l.2 .5M62.4 145.9l-.7 1.1"/>
<path d="M62.6 146l.3 .9 .1-.6 .2 .6 .2-.9M62.6 145.8h.8M64.6 141.2h3.3M64.6 143h3.3M64.6 146.4h3.3M64.6 148.1h2.5M73.1 153.3v.8h.9l-.9 .9-.8-.9h.8M73.1 153.3h.1M73.1 149.8v3.5M78.3 141.2h3.4M78.3 143h3.4M82.5 140.3h3.4l.8 .9-.8 .9h-3.4l-.8-.9z"/>
<path d="M82.5 142.1h3.4l.8 .9-.8 .8h-3.4l-.8-.8zM83 140.8h.4a.48 .48 0 0 1 .1 .6 .48 .48 0 0 1-.5 .3zM83 142.5l.4 .1 .1 .4-.1 .4h-.4zM83.8 141.1l.2-.3v.9M83.8 142.8l.2-.3v.9M83.8 141.7h.5M83.8 143.4h.5M84.9 140.8l-.3 .5h.5M85 141.1v.6M85.1 142.5h-.4l-.1 .5 .4-.1 .1 .4h-.5M91.1 145.5h3.7l.7 .9-.7 .9h-3.7zM92 146.4h.3l.1-.3-.4-.1v.9"/>
<path d="M92.2 146.4l.2 .5M93.4 145.9l-.7 1.1M93.6 146l.2 .9 .2-.6 .2 .6 .2-.9M93.6 145.8h.8M95.5 141.2h3.5M95.5 143h3.5M95.5 146.4h3.5M95.5 148.1h2.6M104.2 153.3v.8h.8l-.8 .9-1-.9h1M104.2 153.3h.1M104.2 149.8v3.5M109.3 141.2h3.4"/>
<path d="M109.3 143h3.4M113.5 140.3h3.4l.7 .9-.7 .9h-3.4l-.8-.9zM113.5 142.1h3.4l.7 .9-.7 .8h-3.4l-.8-.8zM114 140.8h.3a.48 .48 0 0 1 .2 .6 .48 .48 0 0 1-.5 .3zM114 142.5l.4 .1 .1 .4-.2 .4h-.3zM114.8 141.1l.3-.3v.9M114.8 142.8l.3-.3v.9M114.8 141.7h.6M114.8 143.4h.6M115.9 140.8l-.3 .5h.6M116 141.1v.6M116.1 142.5h-.4l-.1 .5 .4-.1 .1 .4h-.5"/>
<path d="M120.4 145.5h3.7l.7 .9-.7 .9h-3.7zM121.2 146.4h.4l.1-.3-.5-.1v.9M121.5 146.4l.2 .5M122.7 145.9l-.7 1.1M122.9 146l.2 .9 .2-.6 .2 .6 .2-.9M122.9 145.8h.8M124.8 141.2h3.4M124.8 143h3.4M124.8 146.4h3.4M124.8 148.1h2.6M133.5 153.3v.8h.8l-.8 .9-1-.9h1M133.5 153.3h.1"/>
<path d="M133.5 149.8v3.5M138.6 141.2h3.4M138.6 143h3.4M142.8 140.3h2.6l.8 .9-.8 .9h-2.6l-.8-.9zM142.8 142.1h2.6l.8 .9-.8 .8h-2.6l-.8-.8zM143.3 140.8h.3a.48 .48 0 0 1 .2 .6 .48 .48 0 0 1-.5 .3zM143.3 142.5l.4 .1 .1 .4-.2 .4h-.3zM144.1 142.5h.5l-.3 .9M144.5 140.8l-.4 .2v.6h.5l-.1-.4-.4 .1M162.7 141.2h1.8M162.7 143h1.8M162.7 146.4h1.8"/>
<path d="M162.7 148.1h1.8M162.7 144.6h1.8M162.7 149.8h1.8M162.7 151.6h1.8M162.7 153.3h1.8M162.7 155h1.8M162.7 158.5h.9M176.5 141.2h1.7M176.5 143h1.7M176.5 146.4h1.7M176.5 148.1h1.7M176.5 144.6h1.7"/>
<path d="M176.5 149.8h1.7M176.5 151.6h1.7M176.5 155h1.7M177.9 154.7l.6 .5M178.5 154.7l-.6 .5M202.3 141.2h1.8M202.3 143h1.8M202.3 146.4h1.8M202.3 148.1h1.8M202.3 144.6h1.8M202.3 149.8h1.8M202.3 151.6h1.8"/>
<path d="M202.3 153.3h1.8M202.3 155h1.8M202.3 158.5h.9M216.1 141.2h1.7M216.1 143h1.7M216.1 146.4h1.7M216.1 148.1h1.7M216.1 144.6h1.7M216.1 149.8h1.7M216.1 151.6h1.7M216.1 155h1.7M217.5 154.7l.6 .5"/>
<path d="M218.1 154.7l-.6 .5M227.9 155.4h2.1M229.1 157.6v.9h.8l-.8 .8-.9-.8h.9M229.1 157.6h.1M229.1 154.1h.1M229.1 152.4v3.1M229.1 156.2v1.4M229.1 152.4l-.5 .9M229.1 152.4l.5 .9M236.6 155.4h2.1M237.6 154.1v1.4M237.6 156.2v1.4"/>
<path d="M245.2 155.4h2M246.2 154.1v1.4M246.2 156.2v1.4M253.8 155.4h2.1M254.9 154.1v1.4M254.9 156.2v1.4M39.6 166.2v.9h.8l-.8 .8-1-.8h1M39.6 166.2h.1M39.6 164.5v1.7M41.3 164.5v1.7M64.6 167.9h3.3M64.6 169.6h3.3"/>
<path d="M64.6 171.4h3.3M64.6 173.1h3.3M64.6 174.8h3.3M64.6 176.6h3.3M64.6 178.3h3.3M64.6 180h3.3M67.9 166.1h10.3v20.8h-10.3zM73.1 162.8h.1M73.1 161l-.5 .9M73.1 161l.6 .9M73.1 161v5.2M73.5 175.6h-.8v1.8"/>
<path d="M74 175.6h-.5v1.8h-1.2M78.3 167.9h3.4M78.3 169.6h3.4M78.3 171.4h3.4M78.3 173.1h3.4M78.3 174.8h3.4M78.3 176.6h3.4M78.3 178.3h3.4M78.3 180h3.4M82.5 179.1h2.6l.7 .9-.7 .8h-2.6l-.8-.8zM82.5 177.4h2.6l.7 .9-.7 .8h-2.6l-.8-.8zM82.5 172.3h2.6l.7 .8-.7 .8h-2.6l-.8-.8z"/>
<path d="M82.5 173.9h2.6l.7 .9-.7 .8h-2.6l-.8-.8zM82.5 170.5h2.6l.7 .9-.7 .9h-2.6l-.8-.9zM82.5 168.8h2.6l.7 .8-.7 .9h-2.6l-.8-.9zM82.5 175.6h2.6l.7 1-.7 .8h-2.6l-.8-.8zM82.5 167.1h2.6l.7 .8-.7 .9h-2.6l-.8-.9zM83 179.5a.47 .47 0 0 1 .5 .5 .47 .47 0 0 1-.5 .5zM83 177.8a.49 .49 0 0 1 .5 .3 .49 .49 0 0 1-.1 .6h-.4zM83 172.7a.47 .47 0 0 1 .5 .3 .47 .47 0 0 1-.1 .5h-.4zM83 174.4a.47 .47 0 0 1 .5 .4 .47 .47 0 0 1-.5 .5zM83 171h.4a.47 .47 0 0 1 .1 .5 .47 .47 0 0 1-.5 .3zM83 169.2a.47 .47 0 0 1 .5 .5 .47 .47 0 0 1-.5 .4zM83 176.1h.4a.47 .47 0 0 1 .1 .6 .47 .47 0 0 1-.5 .3z"/>
<path d="M83 167.5a.47 .47 0 0 1 .5 .3 .47 .47 0 0 1-.1 .6h-.4zM83.8 179.5h.6l-.5 1M83.8 172.7h.5l-.3 .3 .3 .1v.3h-.5M83.8 171.1h.5v.2l-.5 .5h.5M83.8 169.5l.2-.3v.9M83.8 170.1h.5M83.9 167.6l.2-.1 .2 .2-.1 .6a.39 .39 0 0 1-.4-.2 .39 .39 0 0 1 .1-.5zM84 174.4l-.2 .6h.6M84.2 177.8l-.4 .4v.3l.1 .2 .4-.1-.1-.4h-.3l-.1 .1M84.2 174.7v.6M84.3 176.1h-.4l-.1 .5 .4-.1 .1 .4h-.5M95.5 167.9h3.5"/>
<path d="M95.5 169.6h3.5M95.5 171.4h3.5M95.5 173.1h3.5M95.5 174.8h3.5M95.5 176.6h3.5M95.5 178.3h3.5M95.5 180h3.5M99 166.1h10.3v20.8h-10.3zM104.2 162.8h.1M104.2 161v5.2M104.2 161l-.5 .9M104.2 161l.5 .9"/>
<path d="M104.6 175.6h-.8v1.8M105 175.6h-.4v1.8h-1.4M109.3 167.9h3.4M109.3 169.6h3.4M109.3 171.4h3.4M109.3 173.1h3.4M109.3 174.8h3.4M109.3 176.6h3.4M109.3 178.3h3.4M109.3 180h3.4M113.5 179.1h3.4l.7 .9-.7 .8h-3.4l-.8-.8zM113.5 168.8h2.6l.8 .8-.8 .9h-2.6l-.8-.9z"/>
<path d="M113.5 167.1h2.6l.8 .8-.8 .9h-2.6l-.8-.9zM113.5 172.3h3.4l.7 .8-.7 .8h-3.4l-.8-.8zM113.5 173.9h3.4l.7 .9-.7 .8h-3.4l-.8-.8zM113.5 175.6h3.4l.7 1-.7 .8h-3.4l-.8-.8zM113.5 177.4h3.4l.7 .9-.7 .8h-3.4l-.8-.8zM113.5 170.5h3.4l.7 .9-.7 .9h-3.4l-.8-.9zM114 179.5a.47 .47 0 0 1 .5 .5 .47 .47 0 0 1-.5 .5zM114 169.2a.47 .47 0 0 1 .5 .5 .47 .47 0 0 1-.5 .4zM114 167.5a.47 .47 0 0 1 .5 .3 .47 .47 0 0 1-.2 .6h-.3zM114 172.7a.47 .47 0 0 1 .5 .3 .47 .47 0 0 1-.2 .5h-.3zM114 174.4a.47 .47 0 0 1 .5 .4 .47 .47 0 0 1-.5 .5zM114 176.1h.3a.47 .47 0 0 1 .2 .6 .47 .47 0 0 1-.5 .3z"/>
<path d="M114 177.8a.49 .49 0 0 1 .5 .3 .49 .49 0 0 1-.2 .6h-.3zM114 171h.3a.47 .47 0 0 1 .2 .5 .47 .47 0 0 1-.5 .3zM114.8 179.8l.3-.3v1M114.8 172.9l.3-.2v.8M114.8 174.6l.3-.2v.9M114.8 176.4l.3-.3v.9M114.8 178.1l.3-.3v.9M114.8 171.2l.3-.2v.8M114.8 173.5h.6M114.8 175.3h.6M114.8 177h.6M114.8 178.7h.6"/>
<path d="M114.8 171.8h.6M115 167.8l-.2-.2 .4-.1 .2 .2-.1 .1-.5 .1 .1 .5h.4l.1-.4-.2-.2M115.4 169.6l-.2 .2-.4-.1v-.4l.4-.1 .2 .2-.2 .6-.3 .1M115.6 172.9l.3-.2v.8M115.6 174.5h.5v.3l-.5 .5h.5M115.6 176.1h.5l-.2 .4 .2 .1v.3h-.5M115.6 173.5h.5M115.7 171.1l.3-.1 .1 .2v.5l-.2 .1a.48 .48 0 0 1-.2-.7zM115.9 177.8l-.3 .6h.6M116 178.1v.6M116.1 179.5h-.4l-.1 .5h.5v.4h-.5M124.8 167.9h3.4"/>
<path d="M124.8 169.6h3.4M124.8 171.4h3.4M124.8 173.1h3.4M124.8 174.8h3.4M124.8 176.6h3.4M124.8 178.3h3.4M124.8 180h3.4M128.2 166.1h10.4v20.8h-10.4zM133.5 162.8h.1M133.5 161v5.2M133.5 161l-.6 .9M133.5 161l.5 .9"/>
<path d="M133.9 175.6h-.9v1.8M134.3 175.6h-.4v1.8h-1.4M138.6 167.9h3.4M138.6 169.6h3.4M138.6 171.4h3.4M138.6 173.1h3.4M138.6 174.8h3.4M138.6 176.6h3.4M138.6 178.3h3.4M138.6 180h3.4M142.8 167.1h2.6l.8 .8-.8 .9h-2.6l-.8-.9zM142.8 170.5h2.6l.8 .9-.8 .9h-2.6l-.8-.9z"/>
<path d="M142.8 175.6h2.6l.8 1-.8 .8h-2.6l-.8-.8zM142.8 173.9h2.6l.8 .9-.8 .8h-2.6l-.8-.8zM142.8 179.1h2.6l.8 .9-.8 .8h-2.6l-.8-.8zM142.8 177.4h2.6l.8 .9-.8 .8h-2.6l-.8-.8zM142.8 168.8h2.6l.8 .8-.8 .9h-2.6l-.8-.9zM142.8 172.3h2.6l.8 .8-.8 .8h-2.6l-.8-.8zM143.3 167.5a.47 .47 0 0 1 .5 .3 .47 .47 0 0 1-.2 .6h-.3zM143.3 171h.3a.47 .47 0 0 1 .2 .5 .47 .47 0 0 1-.5 .3zM143.3 176.1h.3a.47 .47 0 0 1 .2 .6 .47 .47 0 0 1-.5 .3zM143.3 174.4a.47 .47 0 0 1 .5 .4 .47 .47 0 0 1-.5 .5zM143.3 179.5a.47 .47 0 0 1 .5 .5 .47 .47 0 0 1-.5 .5zM143.3 177.8a.49 .49 0 0 1 .4 .3 .49 .49 0 0 1-.1 .6h-.3z"/>
<path d="M143.3 169.2a.47 .47 0 0 1 .5 .5 .47 .47 0 0 1-.5 .4zM143.3 172.7a.47 .47 0 0 1 .5 .3 .47 .47 0 0 1-.2 .5h-.3zM144.1 179.5h.5l-.3 1M144.1 172.7h.5l-.3 .3 .3 .1v.3h-.5M144.1 171.1l.4-.1 .1 .3-.5 .5h.5M144.1 169.5l.2-.3v.9M144.1 170.1h.5M144.3 167.5l.3 .2-.1 .7h-.3l-.1-.2v-.5zM144.3 174.4l-.2 .6h.5M144.5 177.8l-.4 .3v.5h.5l-.1-.4h-.3l-.1 .1M144.5 174.7v.6M144.6 176.1h-.5v.5h.5v.3h-.5"/>
<path d="M147.2 161.9v.9h.8l-.8 .8-.9-.8h.9M147.2 161.9h.1M162.7 160.1h.9M162.7 161.9h.9M162.7 163.6h.9M162.7 165.3h.9M169.6 171.4v.9h.9l-.9 .8-.8-.8h.8M169.6 171.4h.1M169.6 169.6v1.8M171.3 169.6v1.8M186.8 161.9v.9h.9l-.9 .8-.8-.8h.8M186.8 161.9h.1"/>
<path d="M202.3 160.1h.9M202.3 161.9h.9M202.3 163.6h.9M202.3 165.3h.9M209.3 171.4v.9h.8l-.8 .8-.9-.8h.9M209.3 171.4h.1M209.3 169.6v1.8M210.9 169.6v1.8M227.9 168.4h2.1M229.1 170.5v.9h.8l-.8 .9-.9-.9h.9M229.1 170.5h.1M229.1 167.1h.1"/>
<path d="M229.1 165.3v3.1M229.1 169.1v1.4M229.1 165.3l-.5 .9M229.1 165.3l.5 .9M236.6 169.1h2.1M237.6 167.1v1.3M237.6 169.1v1.4M245.2 169.1h2M246.2 167.1v1.3M246.2 169.1v1.4M253.8 168.4h2.1M254.9 167.1v1.3"/>
<path d="M254.9 169.1v1.4M262.4 168.4h2.1v.2h-2.1zM262.4 168.9h2.1v.3h-2.1zM262.6 167.8h.3M262.8 167.6v.3M263.5 167.1v1.3M263.5 169.2v1.3M60.2 182.6h3.6l.8 .8-.8 .9h-3.6zM60.9 183.4h.4l.1-.3-.5-.1v.9M61.2 183.4l.2 .5M62.4 183l-.7 1.1M62.6 183l.3 .9 .1-.6 .2 .6 .2-.9"/>
<path d="M62.6 182.7h.8M64.6 183.4h3.3M64.6 185.1h2.5M73.1 190.3v.8h.9l-.9 1-.8-1h.8M73.1 190.3h.1M73.1 186.9v3.4M91.1 182.6h3.7l.7 .8-.7 .9h-3.7zM92 183.4h.3l.1-.3-.4-.1v.9M92.2 183.4l.2 .5M93.4 183l-.7 1.1M93.6 183l.2 .9 .2-.6 .2 .6 .2-.9M93.6 182.7h.8"/>
<path d="M95.5 183.4h3.5M95.5 185.1h2.6M104.2 190.3v.8h.8l-.8 1-1-1h1M104.2 190.3h.1M104.2 186.9v3.4M114.8 180.5h.6M120.4 182.6h3.7l.7 .8-.7 .9h-3.7zM121.2 183.4h.4l.1-.3-.5-.1v.9M121.5 183.4l.2 .5M122.7 183l-.7 1.1M122.9 183l.2 .9 .2-.6 .2 .6 .2-.9M122.9 182.7h.8"/>
<path d="M124.8 183.4h3.4M124.8 185.1h2.6M133.5 190.3v.8h.8l-.8 1-1-1h1M133.5 190.3h.1M133.5 186.9v3.4"/>
<circle cx="102.8" cy="39.6" r=".47"/>
<circle cx="133" cy="44.7" r=".47"/>
<circle cx="163.1" cy="44.7" r=".47"/>
<circle cx="193.3" cy="44.7" r=".47"/>
<circle cx="224.3" cy="44.7" r=".47"/>
<circle cx="256.2" cy="44.7" r=".47"/>
<circle cx="102.8" cy="75.7" r=".47"/>
<circle cx="141.6" cy="80" r=".47"/>
<circle cx="172.6" cy="80" r=".47"/>
<circle cx="205.4" cy="80" r=".47"/>
<circle cx="238" cy="80" r=".47"/>
<circle cx="102.8" cy="112" r=".47"/>
<circle cx="154.6" cy="110.2" r=".47"/>
<circle cx="187.2" cy="110.2" r=".47"/>
<circle cx="34" cy="154.1" r=".47"/>
<circle cx="34" cy="155.8" r=".47"/>
<circle cx="34" cy="152.4" r=".47"/>
<circle cx="34" cy="157.6" r=".47"/>
<circle cx="34" cy="159.3" r=".47"/>
<circle cx="67.5" cy="148.1" r=".47"/>
<circle cx="98.6" cy="148.1" r=".47"/>
<circle cx="127.8" cy="148.1" r=".47"/>
<circle cx="164" cy="158.5" r=".47"/>
<circle cx="203.7" cy="158.5" r=".47"/>
<circle cx="164" cy="163.6" r=".47"/>
<circle cx="164" cy="161.9" r=".47"/>
<circle cx="164" cy="165.3" r=".47"/>
<circle cx="164" cy="160.1" r=".47"/>
<circle cx="203.7" cy="161.9" r=".47"/>
<circle cx="203.7" cy="163.6" r=".47"/>
<circle cx="203.7" cy="165.3" r=".47"/>
<circle cx="203.7" cy="160.1" r=".47"/>
<circle cx="67.5" cy="185.1" r=".47"/>
<circle cx="98.6" cy="185.1" r=".47"/>
<circle cx="127.8" cy="185.1" r=".47"/>
</g>
<g fill="none" stroke="#910000" stroke-width=".25">
<path d="M206.5 95.9h2.1M215.1 95.9h2M223.7 95.9h2.1M232.3 95.9h2.1M240.9 95.9h2M249.6 95.9h2M258.2 95.9h2M266.7 95.9h2.2M275.4 95.9h2M214.2 108.8h2.1M222.8 108.8h2.1M226.3 118.3h2.1"/>
<path d="M231.4 108.8h2.1M234.9 118.3h2M240.1 108.8h2M243.5 118.3h2.1M248.7 108.8h2M257.3 108.8h2.1M265.9 108.8h2M274.5 108.8h2.1M227.1 131.2h2.1M235.8 131.2h2M244.4 131.2h2M252.9 131.2h2.2"/>
<path d="M261.6 131.2h2.1M270.2 131.2h2M228 156.2h2.1M236.6 156.2h2.1M245.2 156.2h2.1M253.9 156.2h2M228 169.1h2.1M236.6 168.4h2.1M245.2 168.4h2.1M253.9 169.1h2M262.4 169.1h2.1"/>
</g>
<g fill="none" stroke="#0f0f0f" stroke-width=".21">
<path d="M90.5 33.7h.4l.1-.4-.5-.1v.9M90.5 30.2h.4l.1-.4h-.5v.8M90.5 32l.5-.1v-.4h-.5v.9M90.5 26.8l.5-.1v-.3l-.5-.1v.9M90.5 28.5h.4l.1-.4h-.5v.8M91.4 34.1v-.9l.2 .6 .3-.6v.9M91.4 30.6v-.8l.2 .5 .3-.5v.8M91.4 32.4v-.9l.2 .6 .3-.6v.9M91.4 27.2v-.9l.2 .7 .3-.7v.9M91.4 28.9v-.8l.2 .6 .3-.6v.8M92.3 33.7h.4M92.3 30.2h.4"/>
<path d="M92.3 31.9h.4M92.3 26.7h.4M92.3 28.5h.4M92.7 33.2h-.4v.9h.4M92.7 29.8h-.4v.8h.4M92.7 31.5h-.4v.9h.4M92.7 26.3h-.4v.9h.4M92.7 28.1h-.4v.8h.4M93.6 33.2h-.3l-.2 .2v.5l.2 .2 .3-.1v-.3h-.2M93.6 29.8h-.3l-.2 .1v.5l.2 .2h.3v-.3h-.2M93.6 31.5h-.3l-.2 .2v.4l.2 .3 .3-.1v-.3h-.2M93.6 26.4l-.3-.1-.2 .2v.5l.2 .2 .3-.1v-.3h-.2"/>
<path d="M93.6 28.1h-.3l-.2 .1v.5l.2 .2 .3-.1v-.2h-.2M93.9 29.8h.5v.3l-.5 .5h.5M93.9 31.5h.5l-.2 .3 .2 .1v.4h-.5M93.9 28.3l.3-.2v.8M93.9 28.9h.5M94 26.4l.3-.1 .1 .2v.5l-.1 .2a.53 .53 0 0 1-.3-.8zM94.2 33.1l-.3 .7h.5M94.4 33.5v.6M95.9 36.4h3.8M96 37.1l.5-.1v-.3l-.5-.1v.9M96.9 37.5v-.9l.3 .7 .2-.7v.9M97.7 37.6h.6"/>
<path d="M98.5 36.6v.9h.4M99.2 37h.3M99.6 36.6h-.4v.9h.4M117.3 33.2v.9h.4M117.3 31.5v.9h.4M117.3 29.8v.8h.4M117.3 21.1v1h.4M117.3 24.6v.8h.4M117.3 28.1v.8h.4M117.3 26.3v.9h.4M117.3 22.9v.8h.4M117.8 22.1h.7"/>
<path d="M117.8 27.3h.7M117.8 32.5h.7M117.8 34.2h.7M117.8 30.7h.7M117.8 25.5h.7M117.8 29h.7M117.8 23.8h.7M118.7 33.7h.4l.1-.4-.5-.1v.9M118.7 32l.5-.1v-.4h-.5v.9M118.7 30.2h.4l.1-.4h-.5v.8M118.7 21.6l.5-.1v-.3l-.5-.1v1M118.7 25h.4l.1-.3-.5-.1v.8"/>
<path d="M118.7 28.5h.4l.1-.4h-.5v.8M118.7 26.8l.5-.1v-.3l-.5-.1v.9M118.7 23.3h.4l.1-.3-.5-.1v.8M119.6 34.1v-.9l.2 .6 .3-.6v.9M119.6 32.4v-.9l.2 .6 .3-.6v.9M119.6 30.6v-.8l.2 .5 .3-.5v.8M119.6 22.1v-1l.2 .7 .3-.7v1M119.6 25.4v-.8l.2 .6 .3-.6v.8M119.6 28.9v-.8l.2 .6 .3-.6v.8M119.6 27.2v-.9l.2 .7 .3-.7v.9M119.6 23.7v-.8l.2 .6 .3-.6v.8M120.5 21.1v1"/>
<path d="M120.5 22.9v.8M120.5 24.6v.8M120.5 26.3v.9M120.5 28.1v.8M120.5 29.8v.8M120.5 31.5v.9M120.5 33.2v.9M120.9 33.2h.4a.47 .47 0 0 1 .1 .6 .47 .47 0 0 1-.5 .3zM120.9 31.5a.47 .47 0 0 1 .6 .4 .47 .47 0 0 1-.6 .5zM120.9 29.8a.47 .47 0 0 1 .5 .3 .47 .47 0 0 1-.1 .5h-.4zM120.9 21.1a.47 .47 0 0 1 .6 .5 .47 .47 0 0 1-.6 .5zM120.9 24.6a.47 .47 0 0 1 .5 .3 .47 .47 0 0 1-.1 .5h-.4z"/>
<path d="M120.9 28.1h.4a.47 .47 0 0 1 .1 .5 .47 .47 0 0 1-.5 .3zM120.9 26.3a.47 .47 0 0 1 .6 .5 .47 .47 0 0 1-.6 .4zM120.9 22.9h.4a.47 .47 0 0 1 .1 .6 .47 .47 0 0 1-.5 .2zM121.7 33.2l.6 .9M121.7 31.5l.6 .9M121.7 29.8l.6 .8M121.7 21.1l.6 1M121.7 24.6l.6 .8M121.7 28.1l.6 .8M121.7 26.3l.6 .9M121.7 22.9l.6 .8M122.3 33.2l-.6 .9"/>
<path d="M122.3 31.5l-.6 .9M122.3 29.8l-.6 .8M122.3 21.1l-.6 1M122.3 24.6l-.6 .8M122.3 28.1l-.6 .8M122.3 26.3l-.6 .9M122.3 22.9l-.6 .8M122.6 33.2h.5l-.4 .9M122.6 24.7h.5v.2l-.5 .5h.5M122.6 26.3h.5l-.3 .3 .3 .1v.4h-.5M122.6 23.2l.2-.3v.8M122.6 23.7h.5"/>
<path d="M122.6 21.2l.3-.1 .2 .2v.6l-.2 .2a.53 .53 0 0 1-.3-.9zM122.8 28l-.2 .7h.5M123 31.5h-.3l-.1 .7 .1 .2 .4-.1v-.4l-.4-.1-.1 .2M123 28.3v.6M123.1 29.8h-.5v.4l.4-.1 .1 .4h-.5M124 36.6v.9h.4M124 31.5v.9h.4M124 21.1v1h.4M124 26.3v.9h.4M124.5 22.1h.7M124.5 27.3h.7M124.5 32.5h.7"/>
<path d="M124.5 37.6h.7M125.3 37.1l.6-.1v-.3l-.6-.1v.9M125.3 32l.6-.1v-.4h-.6v.9M125.3 21.6l.6-.1v-.3l-.6-.1v1M125.3 26.8l.6-.1v-.3l-.6-.1v.9M126.2 37.5v-.9l.3 .7 .3-.7v.9M126.2 32.4v-.9l.3 .6 .3-.6v.9M126.2 22.1v-1l.3 .7 .3-.7v1M126.2 27.2v-.9l.3 .7 .3-.7v.9M127.2 21.1v1M127.2 26.3v.9M127.2 31.5v.9"/>
<path d="M127.2 36.6v.9M127.6 36.6a.47 .47 0 0 1 .5 .5 .47 .47 0 0 1-.5 .4zM127.6 31.5a.47 .47 0 0 1 .5 .4 .47 .47 0 0 1-.5 .5zM127.6 21.1a.47 .47 0 0 1 .5 .5 .47 .47 0 0 1-.5 .5zM127.6 26.3a.47 .47 0 0 1 .5 .5 .47 .47 0 0 1-.5 .4zM128.4 36.6l.6 .9M128.4 31.5l.6 .9M128.4 21.1l.6 1M128.4 26.3l.6 .9M129 36.6l-.6 .9M129 31.5l-.6 .9M129 21.1l-.6 1"/>
<path d="M129 26.3l-.6 .9M129.2 36.6h.5l-.2 .4h.2v.5h-.5M129.2 31.5h.5v.4l-.5 .5h.5M129.2 26.5l.3-.2v.9M129.2 27.2h.5M129.3 21.2l.3-.1 .1 .2v.6l-.1 .2a.53 .53 0 0 1-.3-.9zM147.4 32l.6-.1v-.4h-.6v.9M147.4 37.1l.6-.1v-.3l-.6-.1v.9M147.4 26.8l.6-.1v-.3l-.6-.1v.9M147.4 21.6l.6-.1v-.3l-.6-.1v1M148.4 32.4v-.9l.2 .6 .3-.6v.9M148.4 37.5v-.9l.2 .7 .3-.7v.9"/>
<path d="M148.4 27.2v-.9l.2 .7 .3-.7v.9M148.4 22.1v-1l.2 .7 .3-.7v1M149.3 21.1v1M149.3 26.3v.9M149.3 31.5v.9M149.3 36.6v.9M149.7 31.5a.47 .47 0 0 1 .5 .4 .47 .47 0 0 1-.5 .5zM149.7 36.6a.47 .47 0 0 1 .5 .5 .47 .47 0 0 1-.5 .4zM149.7 26.3a.47 .47 0 0 1 .5 .5 .47 .47 0 0 1-.5 .4zM149.7 21.1a.47 .47 0 0 1 .5 .5 .47 .47 0 0 1-.5 .5zM150.5 31.5l.6 .9M150.5 36.6l.6 .9"/>
<path d="M150.5 26.3l.6 .9M150.5 21.1l.6 1M151.1 31.5l-.6 .9M151.1 36.6l-.6 .9M151.1 26.3l-.6 .9M151.1 21.1l-.6 1M151.3 36.6h.5l-.2 .4h.2v.5h-.5M151.4 31.5h.4v.4l-.5 .5h.5M151.4 26.5l.2-.2v.9M151.4 21.2l.3-.1 .1 .2v.6l-.1 .2-.3-.1zM151.4 27.2h.4M154.1 31.5v.9h.5"/>
<path d="M154.1 36.6v.9h.5M154.1 21.1v1h.5M154.1 26.3v.9h.5M154.6 22.1h.7M154.6 27.3h.7M154.6 32.5h.7M154.6 37.6h.7M155.5 32l.5-.1v-.4h-.5v.9M155.5 37.1l.5-.1v-.3l-.5-.1v.9M155.5 21.6l.5-.1v-.3l-.5-.1v1M155.5 26.8l.5-.1v-.3l-.5-.1v.9M156.3 32.4v-.9l.4 .6 .2-.6v.9"/>
<path d="M156.3 37.5v-.9l.4 .7 .2-.7v.9M156.3 22.1v-1l.4 .7 .2-.7v1M156.3 27.2v-.9l.4 .7 .2-.7v.9M157.3 21.1v1M157.3 26.3v.9M157.3 31.5v.9M157.3 36.6v.9M157.8 31.5a.47 .47 0 0 1 .5 .4 .47 .47 0 0 1-.5 .5zM157.8 36.6a.47 .47 0 0 1 .5 .5 .47 .47 0 0 1-.5 .4zM157.8 21.1a.47 .47 0 0 1 .5 .5 .47 .47 0 0 1-.5 .5zM157.8 26.3a.47 .47 0 0 1 .5 .5 .47 .47 0 0 1-.5 .4zM158.5 31.5l.6 .9"/>
<path d="M158.5 36.6l.6 .9M158.5 21.1l.6 1M158.5 26.3l.6 .9M159.1 31.5l-.6 .9M159.1 36.6l-.6 .9M159.1 21.1l-.6 1M159.1 26.3l-.6 .9M159.4 36.6h.6l-.4 .9M159.6 21.1l-.2 .6h.6M159.8 31.5h-.2l-.2 .7 .2 .2 .3-.1v-.4l-.3-.1-.2 .2M159.8 21.5v.6M159.9 26.3h-.4l-.1 .4h.5v.4h-.5"/>
<path d="M177.7 32l.4-.1v-.4h-.4v.9M177.7 26.8l.4-.1v-.3l-.4-.1v.9M177.7 37.1l.4-.1v-.3l-.4-.1v.9M177.7 21.6l.4-.1v-.3l-.4-.1v1M178.5 32.4v-.9l.3 .6 .2-.6v.9M178.5 27.2v-.9l.3 .7 .2-.7v.9M178.5 37.5v-.9l.3 .7 .2-.7v.9M178.5 22.1v-1l.3 .7 .2-.7v1M179.4 21.1v1M179.4 26.3v.9M179.4 31.5v.9M179.4 36.6v.9"/>
<path d="M179.9 31.5h.2l.3 .2v.4l-.3 .3h-.2zM179.9 26.3h.2l.3 .2v.5l-.3 .2h-.2zM179.9 36.6h.2l.3 .3v.4l-.3 .2h-.2zM179.9 21.1h.2l.3 .3v.4l-.3 .3h-.2zM180.6 31.5l.6 .9M180.6 26.3l.6 .9M180.6 36.6l.6 .9M180.6 21.1l.6 1M181.2 31.5l-.6 .9M181.2 26.3l-.6 .9M181.2 36.6l-.6 .9M181.2 21.1l-.6 1"/>
<path d="M181.5 36.6h.6l-.5 .9M181.7 21.1l-.1 .6h.5M181.9 31.5l-.3 .2v.6h.4v-.4l-.4-.1v.2M181.9 21.5v.6M182 26.3h-.4v.4h.4v.4h-.4M183.5 36.6v.9h.4M183.5 31.5v.9h.4M183.9 32.5h.7M183.9 37.6h.7M184.3 21.1v1h.4M184.3 26.3v.9h.4M184.8 22.1h.7"/>
<path d="M184.8 27.3h.7M184.9 37.1l.4-.1-.1-.4h-.3v.9M184.9 32l.4-.1-.1-.4h-.3v.9M185.6 21.6l.5-.1v-.3l-.5-.1v1M185.6 26.8l.5-.1v-.3l-.5-.1v.9M185.7 37.5v-.9l.3 .7 .3-.7v.9M185.7 32.4v-.9l.3 .6 .3-.6v.9M186.6 22.1v-1l.2 .7 .3-.7v1M186.6 27.2v-.9l.2 .7 .3-.7v.9M186.6 31.5v.9M186.6 36.6v.9M187.1 36.6h.2l.3 .3v.4l-.3 .2h-.2z"/>
<path d="M187.1 31.5h.2l.3 .2v.4l-.3 .3h-.2zM187.5 21.1v1M187.5 26.3v.9M187.8 36.6l.6 .9M187.8 31.5l.6 .9M187.9 21.1a.47 .47 0 0 1 .5 .5 .47 .47 0 0 1-.5 .5zM187.9 26.3a.47 .47 0 0 1 .5 .5 .47 .47 0 0 1-.5 .4zM188.4 36.6l-.6 .9M188.4 31.5l-.6 .9M188.7 21.1l.6 1M188.7 26.3l.6 .9M188.8 36.9l.2-.3v.9"/>
<path d="M188.8 31.7l.2-.2v.9M188.8 37.5h.4M188.8 32.4h.4M189.3 21.1l-.6 1M189.3 26.3l-.6 .9M189.5 36.9l.3-.3v.9M189.5 37.5h.5M189.6 31.5h.3l.1 .1v.6l-.1 .2a.53 .53 0 0 1-.3-.9zM189.7 21.5l-.2-.1 .2-.3 .3 .1v.3h-.4l-.1 .2 .2 .4 .3-.1v-.4l-.1-.1M190 26.7l-.3 .2-.2-.4 .2-.2 .3 .1-.1 .7-.3 .1M207.8 37.1l.4-.1v-.3l-.4-.1v.9M207.8 26.8l.4-.1v-.3l-.4-.1v.9"/>
<path d="M207.8 21.6l.4-.1v-.3l-.4-.1v1M207.8 32l.4-.1v-.4h-.4v.9M208.7 37.5v-.9l.2 .7 .4-.7v.9M208.7 27.2v-.9l.2 .7 .4-.7v.9M208.7 22.1v-1l.2 .7 .4-.7v1M208.7 32.4v-.9l.2 .6 .4-.6v.9M209.6 21.1v1M209.6 26.3v.9M209.6 31.5v.9M209.6 36.6v.9M210 36.6h.3l.2 .3v.4l-.2 .2h-.3zM210 26.3h.3l.2 .2v.5l-.2 .2h-.3z"/>
<path d="M210 21.1h.3l.2 .3v.4l-.2 .3h-.3zM210 31.5h.3l.2 .2v.4l-.2 .3h-.3zM210.8 36.6l.6 .9M210.8 26.3l.6 .9M210.8 21.1l.6 1M210.8 31.5l.6 .9M211.4 36.6l-.6 .9M211.4 26.3l-.6 .9M211.4 21.1l-.6 1M211.4 31.5l-.6 .9M211.7 36.9l.3-.3v.9M211.7 31.7l.3-.2v.9"/>
<path d="M211.7 37.5h.4M211.7 32.4h.4M211.9 21.5h-.2v-.3l.3-.1 .1 .1v.3l-.4 .1v.4l.2 .1 .2-.1v-.4l-.1-.1M212.1 26.7l-.1 .2-.3-.1v-.4h.4v.6l-.3 .2M212.5 36.9l.2-.3v.9M212.5 37.5h.5M212.6 31.5h.2l.2 .1v.6l-.2 .2a.53 .53 0 0 1-.2-.9zM214.5 31.5v.9h.4M214.5 36.6v.9h.4M214.5 26.3v.9h.4M214.5 21.1v1h.4M215 22.1h.6"/>
<path d="M215 27.3h.6M215 32.5h.6M215 37.6h.6M215.9 32h.3l.2-.2-.2-.3h-.3v.9M215.9 37.1h.3l.2-.1-.2-.4h-.3v.9M215.9 26.8h.3l.2-.2-.2-.3h-.3v.9M215.9 21.6h.3l.2-.1-.2-.4h-.3v1M216.7 32.4v-.9l.3 .6 .3-.6v.9M216.7 37.5v-.9l.3 .7 .3-.7v.9M216.7 27.2v-.9l.3 .7 .3-.7v.9M216.7 22.1v-1l.3 .7 .3-.7v1M217.7 21.1v1"/>
<path d="M217.7 26.3v.9M217.7 31.5v.9M217.7 36.6v.9M218.1 31.5l.5 .2v.4l-.3 .3h-.2zM218.1 36.6l.5 .3v.4l-.3 .2h-.2zM218.1 26.3l.5 .2v.5l-.3 .2h-.2zM218.1 21.1l.5 .3v.4l-.3 .3h-.2zM218.9 31.5l.5 .9M218.9 36.6l.5 .9M218.9 26.3l.5 .9M218.9 21.1l.5 1M219.4 31.5l-.5 .9"/>
<path d="M219.4 36.6l-.5 .9M219.4 26.3l-.5 .9M219.4 21.1l-.5 1M219.7 31.7l.3-.2v.9M219.7 36.9l.3-.3v.9M219.7 26.5l.3-.2v.9M219.7 21.4l.3-.3v1M219.7 27.2h.6M219.7 22.1h.6M219.7 37.5h.6M219.7 32.4h.6M220.5 26.3h.5l-.2 .3 .2 .1v.4h-.5"/>
<path d="M220.6 21.2h.4v.3l-.5 .6h.5M220.8 31.5l-.2 .5h.5M220.9 31.8v.6M221 36.6h-.4v.4h.4v.5h-.4M238.8 37.1h.3l.2-.1-.2-.4h-.3v.9M238.8 26.8h.3l.2-.2-.2-.3h-.3v.9M238.8 21.6h.3l.2-.1-.2-.4h-.3v1M238.8 32h.3l.2-.2-.2-.3h-.3v.9M239.6 37.5v-.9l.3 .7 .3-.7v.9M239.6 27.2v-.9l.3 .7 .3-.7v.9M239.6 22.1v-1l.3 .7 .3-.7v1M239.6 32.4v-.9l.3 .6 .3-.6v.9"/>
<path d="M240.7 21.1v1M240.7 26.3v.9M240.7 31.5v.9M240.7 36.6v.9M241 36.6h.3l.2 .3v.4l-.2 .2h-.3zM241 26.3h.3l.2 .2v.5l-.2 .2h-.3zM241 21.1h.3l.2 .3v.4l-.2 .3h-.3zM241 31.5h.3l.2 .2v.4l-.2 .3h-.3zM241.8 36.6l.6 .9M241.8 26.3l.6 .9M241.8 21.1l.6 1M241.8 31.5l.6 .9"/>
<path d="M242.4 36.6l-.6 .9M242.4 26.3l-.6 .9M242.4 21.1l-.6 1M242.4 31.5l-.6 .9M242.7 36.9l.2-.3v.9M242.7 26.5l.2-.2v.9M242.7 21.4l.2-.3v1M242.7 31.7l.2-.2v.9M242.7 27.2h.5M242.7 22.1h.5M242.7 37.5h.5M242.7 32.4h.5"/>
<path d="M243.5 26.3h.5l-.3 .3 .3 .1v.4h-.5M243.5 21.2h.5v.3l-.5 .6h.5M243.7 31.5l-.2 .5h.5M243.9 31.8v.6M244 36.6h-.5v.4h.5v.5h-.5M246.3 26.3v.9h.5M246.3 21.1v1h.5M246.8 22.1h.7M246.8 27.3h.7M247.7 26.8l.5-.1v-.3l-.5-.1v.9M247.7 21.6l.5-.1v-.3l-.5-.1v1M248.5 27.2v-.9l.4 .7 .2-.7v.9"/>
<path d="M248.5 22.1v-1l.4 .7 .2-.7v1M249.6 21.1v1M249.6 26.3v.9M250 26.3a.47 .47 0 0 1 .5 .5 .47 .47 0 0 1-.5 .4zM250 21.1a.47 .47 0 0 1 .5 .5 .47 .47 0 0 1-.5 .5zM250.7 26.3l.6 .9M250.7 21.1l.6 1M251.3 26.3l-.6 .9M251.3 21.1l-.6 1M251.6 26.5l.2-.2v.9M251.6 21.4l.2-.3v1M251.6 27.2h.5"/>
<path d="M251.6 22.1h.5M252.3 26.3h.6l-.3 .9M252.9 21.1l-.5 .3v.6l.4 .1 .1-.2-.1-.4-.4 .1M270.6 26.8l.5-.1v-.3l-.5-.1v.9M270.6 21.6l.5-.1v-.3l-.5-.1v1M271.5 27.2v-.9l.3 .7 .3-.7v.9M271.5 22.1v-1l.3 .7 .3-.7v1M272.5 21.1v1M272.5 26.3v.9M272.9 26.3a.47 .47 0 0 1 .5 .5 .47 .47 0 0 1-.5 .4zM272.9 21.1a.47 .47 0 0 1 .5 .5 .47 .47 0 0 1-.5 .5zM273.7 26.3l.6 .9"/>
<path d="M273.7 21.1l.6 1M274.3 26.3l-.6 .9M274.3 21.1l-.6 1M274.5 26.5l.3-.2v.9M274.5 21.4l.3-.3v1M274.5 27.2h.5M274.5 22.1h.5M275.3 26.3h.6l-.4 .9M275.8 21.1l-.3 .1-.1 .8 .3 .1 .2-.2-.2-.4-.3 .1M91.4 57.8l.4-.1v-.3h-.4v.8M91.4 59.5h.4v-.4h-.4v.8M92.2 58.2v-.8l.3 .6 .3-.6v.8"/>
<path d="M92.2 59.9v-.8l.3 .5 .3-.5v.8M93.2 59.5h.3M93.2 57.7h.3M93.6 57.4h-.4v.8h.4M93.6 59.1h-.4v.8h.4M94.4 57.4h-.3a.43 .43 0 0 0-.1 .5 .43 .43 0 0 0 .4 .2v-.3M94.4 59.1h-.3l-.2 .3 .2 .5h.3v-.3M95.2 59.1h-.2l-.2 .6 .1 .2 .4-.1-.1-.4h-.3l-.1 .2M95.3 57.4h-.4l-.1 .3h.5v.4h-.5M117.3 59.1v.8h.4M117.3 57.4v.8h.4M117.8 60h.7"/>
<path d="M117.8 58.3h.7M118.7 59.5h.4l.1-.4h-.5v.8M118.7 57.8l.5-.1v-.3h-.5v.8M119.6 59.9v-.8l.2 .5 .3-.5v.8M119.6 58.2v-.8l.2 .6 .3-.6v.8M120.5 57.4v.8M120.5 59.1v.8M120.9 59.1h.5l.1 .5-.2 .3h-.4zM120.9 57.4h.4a.48 .48 0 0 1 .1 .5 .48 .48 0 0 1-.5 .3zM121.7 59.1l.6 .8M121.7 57.4l.6 .8M122.3 59.1l-.6 .8"/>
<path d="M122.3 57.4l-.6 .8M122.7 57.7l-.1-.2v-.1h.5v.2l-.5 .1v.2l.1 .3 .4-.1v-.3l-.2-.1M123.1 59.4l-.1 .2h-.4v-.5h.5v.6l-.5 .2M125.9 42.3l.4-.1v-.3l-.4-.1v.9M126.7 42.7v-.9l.3 .7 .3-.7v.9M127.5 42.7l.3-.9 .3 .9M127.6 42.5h.5M128.9 41.9l-.3-.1-.2 .2v.5l.2 .2 .3-.1M129.7 41.9l-.2-.1-.3 .2v.5l.3 .2 .2-.1M131.3 59.5h.4v-.4h-.4v.8M132.1 59.9v-.8l.4 .5 .2-.5v.8M133.1 59.5h.3"/>
<path d="M133.6 59.1h-.5v.8h.5M133.7 60h.6M134.6 59.5h.4v-.4h-.4v.8M135.4 59.5h.3M135.8 59.1h-.4v.8M136.6 59.1v.8l-.4-.8v.8M137.1 59.1a.42 .42 0 0 1 .4 .4 .42 .42 0 0 1-.4 .4zM156 42.3l.4-.1v-.3l-.4-.1v.9M156.8 42.7v-.9l.3 .7 .3-.7v.9M157.7 42.7l.2-.9 .4 .9M157.8 42.5h.4M159 41.9l-.2-.1-.3 .2v.5l.3 .2 .2-.1"/>
<path d="M159.9 41.9l-.3-.1-.2 .2v.5l.2 .2 .3-.1M162.3 59.5h.4l.1-.4h-.5v.8M163.1 59.9v-.8l.3 .5 .3-.5v.8M164.1 59.5h.3M164.5 59.1h-.4v.8h.4M164.7 60h.7M165.6 59.5h.4v-.4h-.4v.8M166.4 59.5h.3M166.8 59.1h-.4v.8M167.7 59.1v.8l-.5-.8v.8M168.2 59l-.2 .6h.5M168.4 59.3v.6"/>
<path d="M186.1 42.3l.5-.1-.1-.4h-.4v.9M187 42.7v-.9l.2 .7 .4-.7v.9M187.8 42.7l.3-.9 .3 .9M187.9 42.5h.4M189.2 41.9l-.3-.1-.2 .2v.5l.2 .2 .3-.1M190 41.9l-.2-.1-.3 .2v.5l.3 .2 .2-.1M195 59.5h.4v-.4h-.4v.8M195.9 59.9v-.8l.2 .5 .4-.5v.8M196.9 59.5h.2M197.2 59.1h-.3v.8h.3M197.4 60h.7M198.3 59.5l.5-.1-.1-.3h-.4v.8"/>
<path d="M199.2 59.5h.2M199.6 59.1h-.4v.8M200.4 59.1v.8l-.5-.8v.8M201 59.4l-.2-.3h.3l.1 .2-.4 .2 .1 .4 .3-.1v-.3l-.2-.1M217.1 42.3h.4l.1-.2-.1-.3h-.4v.9M218 42.7v-.9l.2 .7 .4-.7v.9M218.8 42.7l.4-.9 .2 .9M218.9 42.5h.4M220.2 41.9l-.3-.1-.2 .2v.5l.2 .2 .3-.1M221 41.9l-.2-.1a.43 .43 0 0 0-.3 .5 .43 .43 0 0 0 .5 .3M226.9 59.5l.5-.1-.1-.3h-.4v.8M227.8 59.9v-.8l.2 .5 .4-.5v.8"/>
<path d="M228.7 59.5h.4M229.1 59.1h-.4v.8h.4M229.3 60h.7M230.2 59.5h.4l.1-.4h-.5v.8M231.1 59.5h.2M231.4 59.1h-.3v.8M232.3 59.1v.8l-.5-.8v.8M232.6 59.3l.3-.2v.8M232.6 59.9h.5M233.5 59.1h.4l.1 .1-.5 .7h.5M249 42.3l.5-.1v-.3l-.5-.1v.9M249.8 42.7v-.9l.3 .7 .3-.7v.9"/>
<path d="M250.7 42.7l.3-.9 .2 .9M250.8 42.5h.4M252.1 41.9a.42 .42 0 0 0-.6 .3 .42 .42 0 0 0 .6 .4M252.9 41.9a.42 .42 0 0 0-.6 .3 .42 .42 0 0 0 .6 .4M75.1 77.8h3.8M75.1 64.6h.5v-.4h-.5v.9M75.1 69.8h.5v-.2l-.1-.2h-.4v.8M75.1 61.6v-.9l.3 .7 .3-.7v.9M75.1 73.3h.5v-.4h-.5v.8M75.1 76.7h.4l.1-.3-.1-.2h-.4v1M75.1 75h.5v-.3l-.1-.2h-.4v.9M75.1 68.1h.5v-.4h-.5v.8"/>
<path d="M75.1 66.4h.4l.1-.3-.1-.2h-.4v.9M75.1 71.6h.4l.1-.4-.1-.1h-.4v.9M75.1 78.4h.5v-.4h-.5v.9M76 65.1v-.9l.3 .6 .3-.6v.9M76 70.2v-.8l.3 .6 .3-.6v.8M76 73.7v-.8l.3 .5 .3-.5v.8M76 77.2v-1l.3 .7 .3-.7v1M76 75.4v-.9l.3 .6 .3-.6v.9M76 68.5v-.8l.3 .6 .3-.6v.8M76 66.8v-.9l.3 .7 .3-.7v.9M76 72v-.9l.3 .7 .3-.7v.9M76 78.9v-.9l.3 .6 .3-.6v.9"/>
<path d="M76.2 61.6v-.9l.2 .7 .3-.7v.9M76.7 78.9h.7M77 69.8h.3M77 75h.3M77 64.6h.3M77 66.3h.3M77 68.1h.3M77 73.3h.3M77 76.7h.3M77 71.5h.3M77.1 60.7l.1 .9 .4-.1v-.8M77.4 64.2h-.4v.9h.4"/>
<path d="M77.4 69.4h-.4v.8h.4M77.4 72.9h-.4v.8h.4M77.4 76.2h-.4v1h.4M77.4 74.5h-.4v.9h.4M77.4 67.7h-.4v.8h.4M77.4 65.9h-.4v.9h.4M77.4 71.1h-.4v.9h.4M77.6 70.3h.6M77.6 75.5h.6M77.6 65.1h.6M77.6 66.8h.6M77.6 73.8h.6"/>
<path d="M77.6 77.3h.6M77.6 68.6h.6M77.6 72.1h.6M77.7 78v.9h.3M77.8 61.7h.6M78.3 64.2l.3 .9 .3-.9M78.4 65.9l.1 .9 .2-.6 .2 .6 .1-.9M78.4 78.4h.2M78.4 77.2v-1l.3 .7 .3-.7v1M78.4 75h.5v-.3l-.1-.2h-.4v.9M78.4 67.7v.8M78.4 69.6v.6"/>
<path d="M78.4 71.4v.6M78.4 73.1v.6M78.5 61.6l.4-.9 .2 .9M78.5 68l.4 .5M78.6 61.4h.4M78.6 75l.3 .4M78.7 69.6l-.3 .2M78.7 73.1l-.3 .2M78.7 71.4l-.3 .2M78.8 78h-.4v.9h.4M78.9 69.5h.5v.2l-.5 .5h.5M78.9 72.9h.4l.1 .3-.5 .5h.5"/>
<path d="M78.9 71.2h.5v.3l-.5 .5h.5M78.9 67.7l-.5 .4M79.3 75h.2M79.4 60.7h.2l.3 .3v.4l-.2 .2h-.3zM79.4 76.4l.1-.2a.47 .47 0 0 1 .5 .5 .47 .47 0 0 1-.5 .5l-.1-.2zM79.7 74.5h-.4v.9h.4M79.7 71.1h.6l-.4 .9M79.9 69.7l-.2-.1 .2-.2 .3 .1-.1 .2-.4 .2 .1 .3 .4-.1v-.3l-.2-.1M80 75h.4M80.1 72.9h-.2l-.2 .6 .2 .2 .3-.1-.1-.4h-.3l-.1 .2M80.3 60.7l.4 .3v.4l-.1 .2h-.3zM80.3 76.2a.47 .47 0 0 1 .5 .5 .47 .47 0 0 1-.5 .5z"/>
<path d="M80.5 74.5h-.5v.9M81.1 61.3h.4l.2-.4-.2-.2h-.4v.9M81.3 61.3l.4 .3M90.5 66.4h.4l.2-.3-.2-.2h-.4v.9M90.5 68.1h.5v-.4h-.5v.8M90.5 69.8h.5l.1-.2-.2-.2h-.4v.8M91.4 66.8v-.9l.3 .7 .3-.7v.9M91.4 68.5v-.8l.3 .6 .3-.6v.8M91.4 70.2v-.8l.3 .6 .3-.6v.8M91.4 61.3l.4-.1-.1-.5h-.3v.9M91.4 62.9h.4v-.4h-.4v.9M91.4 64.6h.4v-.4h-.4v.9"/>
<path d="M92.2 61.6v-.9l.3 .7 .3-.7v.9M92.2 63.4v-.9l.3 .6 .3-.6v.9M92.2 65.1v-.9l.3 .6 .3-.6v.9M92.4 69.8h.3M92.4 66.3h.3M92.4 68.1h.3M92.8 65.9h-.4v.9h.4M92.8 67.7h-.4v.8h.4M92.8 69.4h-.4v.8h.4M93.2 64.6h.3M93.2 61.2h.3M93.2 62.9h.3"/>
<path d="M93.6 66a.41 .41 0 0 0-.5 .4 .41 .41 0 0 0 .6 .4v-.4h-.2M93.6 67.7h-.3a.44 .44 0 0 0-.1 .5 .44 .44 0 0 0 .5 .2v-.3h-.2M93.6 69.5l-.1-.1a.47 .47 0 0 0-.4 .3 .47 .47 0 0 0 .2 .5l.4-.1v-.2h-.2M93.6 60.7h-.4v.9h.4M93.6 62.5h-.4v.9h.4M93.6 64.2h-.4v.9h.4M94 66.2l.3-.3v.9M94 67.9l.3-.2v.8M94 69.6l.3-.2v.8M94 70.2h.4M94 66.8h.4M94 68.5h.4"/>
<path d="M94.4 60.8a.43 .43 0 0 0-.4 .3 .43 .43 0 0 0 .1 .5h.3v-.3M94.4 62.5h-.3a.43 .43 0 0 0-.1 .5 .43 .43 0 0 0 .4 .3v-.4M94.4 64.2h-.3l-.2 .4 .2 .5h.3v-.4M94.8 67.9l.2-.2v.8M94.8 69.5h.5v.2l-.5 .5h.5M94.8 60.7h.6l-.4 .9M94.8 68.5h.5M94.9 66l.2-.1 .2 .2v.6l-.2 .1a.53 .53 0 0 1-.2-.8zM95 62.9l-.2-.2 .1-.2h.3l.1 .3-.4 .1-.1 .1 .2 .4 .3-.1v-.4h-.2M95.3 64.6l-.1 .1h-.3v-.5l.4 .1v.6l-.4 .2M95.9 72.6h3.8M96 73.3h.4l.1-.4h-.5v.8"/>
<path d="M96.9 73.7v-.8l.3 .5 .2-.5v.8M97.7 73.8h.6M98.5 72.9v.8h.4M99.2 73.3h.3M99.6 72.9h-.4v.8h.4M117.3 60.7v.9h.4M117.3 64.2v.9h.4M117.3 67.7v.8h.4M117.3 69.4v.8h.4M117.3 65.9v.9h.4M117.3 62.5v.9h.4M117.8 70.3h.7"/>
<path d="M117.8 65.1h.7M117.8 66.8h.7M117.8 61.7h.7M117.8 68.6h.7M117.8 63.5h.7M118.7 61.3l.5-.1v-.4l-.5-.1v.9M118.7 64.6h.4l.1-.3-.5-.1v.9M118.7 68.1h.4l.1-.3-.5-.1v.8M118.7 69.8h.4l.1-.3-.5-.1v.8M118.7 66.4l.5-.1v-.3l-.5-.1v.9M118.7 62.9h.5v-.3l-.5-.1v.9M119.6 61.6v-.9l.2 .7 .3-.7v.9"/>
<path d="M119.6 65.1v-.9l.2 .6 .3-.6v.9M119.6 68.5v-.8l.2 .6 .3-.6v.8M119.6 70.2v-.8l.2 .6 .3-.6v.8M119.6 66.8v-.9l.2 .7 .3-.7v.9M119.6 63.4v-.9l.2 .6 .3-.6v.9M120.5 60.7v.9M120.5 62.5v.9M120.5 64.2v.9M120.5 65.9v.9M120.5 67.7v.8M120.5 69.4v.8M120.9 60.7a.49 .49 0 0 1 .5 .4 .49 .49 0 0 1-.1 .5h-.4z"/>
<path d="M120.9 64.2l.5 .1 .1 .4-.2 .4h-.4zM120.9 67.7h.4a.48 .48 0 0 1 .1 .5 .48 .48 0 0 1-.5 .3zM120.9 69.4a.47 .47 0 0 1 .5 .3 .47 .47 0 0 1-.1 .5h-.4zM120.9 65.9a.47 .47 0 0 1 .6 .5 .47 .47 0 0 1-.6 .4zM120.9 62.5h.4a.48 .48 0 0 1 .1 .6 .48 .48 0 0 1-.5 .3zM121.7 60.7l.6 .9M121.7 64.2l.6 .9M121.7 67.7l.6 .8M121.7 69.4l.6 .8M121.7 65.9l.6 .9M121.7 62.5l.6 .9M122.3 60.7l-.6 .9"/>
<path d="M122.3 64.2l-.6 .9M122.3 67.7l-.6 .8M122.3 69.4l-.6 .8M122.3 65.9l-.6 .9M122.3 62.5l-.6 .9M122.6 61l.2-.3v.9M122.6 64.5l.2-.3v.9M122.6 67.9l.2-.2v.8M122.6 69.6l.2-.2v.8M122.6 66.2l.2-.3v.9M122.6 62.8l.2-.3v.9M122.6 70.2h.5"/>
<path d="M122.6 65.1h.5M122.6 66.8h.5M122.6 68.5h.5M122.6 61.6h.5M122.6 63.4h.5M123.4 64.3l.4-.1 .1 .2-.5 .7h.5M123.4 65.9h.5l-.2 .3 .2 .2v.3l-.2 .1h-.3M123.4 62.8l.3-.3v.9M123.4 63.4h.5M123.5 60.8l.2-.1a.47 .47 0 0 1 .2 .5 .47 .47 0 0 1-.3 .4l-.2-.3zM123.7 67.6l-.3 .6h.5M123.8 69.4h-.3l-.1 .4 .4-.1v.5l-.4-.1"/>
<path d="M123.8 67.9v.6M131.3 75h.4l.1-.3-.2-.2h-.3v.9M131.3 69.8h.4l.1-.2-.2-.2h-.3v.8M131.3 64.6h.4v-.4h-.4v.9M131.9 78v-.8l.3 .6 .3-.6v.8M132.1 75.4v-.9l.4 .6 .2-.6v.9M132.1 70.2v-.8l.4 .6 .2-.6v.8M132.1 65.1v-.9l.4 .6 .2-.6v.9M132.9 78v-.8l.2 .6 .4-.6v.8M133.1 69.8h.3M133.1 75h.3M133.1 64.6h.3"/>
<path d="M133.6 74.5h-.5v.9h.5M133.6 69.4h-.5v.8h.5M133.6 64.2h-.5v.9h.5M133.7 70.3h.6M133.7 75.5h.6M133.7 65.1h.6M133.9 77.2l.1 .8 .3-.1v-.7M134.6 75h.4l.1-.3-.2-.2h-.3v.9M134.6 69.8h.4l.1-.2-.2-.2h-.3v.8M134.6 64.6h.4v-.4h-.4v.9M134.6 78.1h.6M135.3 78l.3-.8 .2 .8"/>
<path d="M135.3 77.8h.5M135.4 69.8h.3M135.4 75h.3M135.4 64.6h.3M135.8 74.5h-.4v.9M135.8 69.4h-.4v.8M135.8 64.2h-.4v.9M136.2 77.2h.3l.1 .1v.5l-.2 .2h-.2zM136.6 74.5v.9l-.4-.9v.9M136.6 69.4v.8l-.4-.8v.8M136.6 64.2v.9l-.4-.9v.9M136.9 74.5h.6l-.3 .4h.3v.2v.3l-.6-.1"/>
<path d="M137 77.2h.4a.48 .48 0 0 1 .1 .5 .48 .48 0 0 1-.5 .3zM137 69.5l.4-.1 .1 .2-.6 .6h.6M137 64.5l.3-.3v.9M137 65.1h.5M137.9 77.6h.3l.2-.2-.1-.2h-.4v.8M138 77.6l.4 .4M162.3 75h.4l.1-.4-.5-.1v.9M162.3 64.6h.4l.1-.3-.5-.1v.9M162.3 69.8h.4l.1-.3-.5-.1v.8M162.9 78v-.8l.3 .6 .2-.6v.8M163.1 75.4v-.9l.3 .6 .3-.6v.9M163.1 65.1v-.9l.3 .6 .3-.6v.9"/>
<path d="M163.1 70.2v-.8l.3 .6 .3-.6v.8M163.9 78v-.8l.2 .6 .4-.6v.8M164.1 69.8h.3M164.1 75h.3M164.1 64.6h.3M164.5 74.5h-.4v.9h.4M164.5 64.2h-.4v.9h.4M164.5 69.4h-.4v.8h.4M164.7 70.3h.7M164.7 75.5h.7M164.7 65.1h.7M164.9 77.2v.7l.2 .1 .3-.2v-.6"/>
<path d="M165.6 75h.4l.1-.3-.2-.2h-.3v.9M165.6 64.6h.4v-.4h-.4v.9M165.6 69.8h.4l.1-.2-.2-.2h-.3v.8M165.6 78.1h.6M166.3 78l.3-.8 .2 .8M166.4 77.8h.3M166.4 69.8h.3M166.4 75h.3M166.4 64.6h.3M166.8 74.5h-.4v.9M166.8 64.2h-.4v.9M166.8 69.4h-.4v.8"/>
<path d="M167.2 77.2h.3a.48 .48 0 0 1 .1 .5 .48 .48 0 0 1-.4 .3zM167.7 74.5v.9l-.5-.9v.9M167.7 64.2v.9l-.5-.9v.9M167.7 69.4v.8l-.5-.8v.8M168 74.5h.5l-.3 .9M168 77.2h.4a.48 .48 0 0 1 .1 .5 .48 .48 0 0 1-.5 .3zM168.4 64.2h-.3l-.1 .4h.4v.5l-.4-.1M168.4 69.4l-.3 .1-.1 .2 .1 .5h.3v-.5h-.3l-.1 .2M168.9 77.6l.5-.1v-.2l-.5-.1v.8M169.1 77.6l.3 .4M194.2 69.8h.4l.1-.2-.2-.2h-.3v.8M194.2 75h.4l.1-.3-.2-.2h-.3v.9"/>
<path d="M195 64.6h.4v-.4h-.4v.9M195 70.2v-.8l.4 .6 .2-.6v.8M195 75.4v-.9l.4 .6 .2-.6v.9M195.6 78v-.8l.3 .6 .3-.6v.8M195.9 65.1v-.9l.2 .6 .4-.6v.9M196 69.8h.3M196 75h.3M196.5 69.4h-.5v.8h.5M196.5 74.5h-.5v.9h.5M196.6 78v-.8l.3 .6 .2-.6v.8M196.6 70.3h.6M196.6 75.5h.6"/>
<path d="M196.9 64.6h.2M197.2 64.2h-.3v.9h.3M197.4 65.1h.7M197.5 69.8h.4l.1-.2-.2-.2h-.3v.8M197.5 75h.4l.1-.3-.2-.2h-.3v.9M197.6 77.2v.6l.1 .2 .4-.1v-.7M198.3 64.6h.4l.1-.3-.5-.1v.9M198.3 78.1h.6M198.3 69.8h.3M198.3 75h.3M198.8 69.4h-.5v.8M198.8 74.5h-.5v.9"/>
<path d="M199 78l.3-.8 .3 .8M199.1 77.8h.4M199.2 64.6h.2M199.6 64.2h-.4v.9M199.6 69.4v.8l-.5-.8v.8M199.6 74.5v.9l-.5-.9v.9M199.9 77.2h.3l.2 .1v.5l-.3 .2h-.2zM199.9 69.6l.3-.2v.8M199.9 74.8l.3-.3v.9M199.9 70.2h.5M199.9 75.4h.5M200.4 64.2v.9l-.5-.9v.9"/>
<path d="M200.8 77.2l.4 .1v.5l-.2 .2h-.2zM200.8 74.8l.2-.3v.9M200.8 75.4h.4M201 69.4l.2 .2-.1 .6h-.2l-.1-.1v-.5zM201.2 64.6l-.1 .1h-.2l-.1-.4h.4v.6l-.3 .2M201.6 77.6h.4l.1-.2v-.2h-.5v.8M201.8 77.6l.3 .4M226.9 69.8l.5-.1-.1-.3h-.4v.8M226.9 75l.5-.1-.1-.4h-.4v.9M226.9 64.6h.5l-.1-.4h-.4v.9M227.8 70.2v-.8l.2 .6 .4-.6v.8M227.8 75.4v-.9l.2 .6 .4-.6v.9"/>
<path d="M227.8 65.1v-.9l.2 .6 .4-.6v.9M228.4 78v-.8l.2 .6 .3-.6v.8M228.7 69.8h.4M228.7 75h.4M228.7 64.6h.4M229.1 69.4h-.4v.8h.4M229.1 74.5h-.4v.9h.4M229.1 64.2h-.4v.9h.4M229.3 78v-.8l.4 .6 .2-.6v.8M229.3 70.3h.7M229.3 75.5h.7M229.3 65.1h.7"/>
<path d="M230.2 69.8h.4l.1-.3-.5-.1v.8M230.2 75h.4l.1-.4-.5-.1v.9M230.2 64.6h.4l.1-.3-.5-.1v.9M230.3 77.2v.7l.2 .1 .3-.2v-.6M231 78.1h.7M231.1 69.8h.2M231.1 75h.2M231.1 64.6h.2M231.4 69.4h-.3v.8M231.4 74.5h-.3v.9M231.4 64.2h-.3v.9M231.8 78l.2-.8 .4 .8"/>
<path d="M231.9 77.8h.4M232.3 69.4v.8l-.5-.8v.8M232.3 74.5v.9l-.5-.9v.9M232.3 64.2v.9l-.5-.9v.9M232.6 77.2h.4a.48 .48 0 0 1 .1 .5 .48 .48 0 0 1-.5 .3zM232.6 69.6l.3-.2v.8M232.6 74.8l.3-.3v.9M232.6 64.5l.3-.3v.9M232.6 70.2h.5M232.6 75.4h.5M232.6 65.1h.5M233.5 77.2h.3a.48 .48 0 0 1 .1 .5 .48 .48 0 0 1-.4 .3z"/>
<path d="M233.5 64.2h.5l-.3 .4 .3 .1-.1 .4-.4-.1M233.7 69.4l-.2 .6h.5M233.9 74.5h-.4v.5l.4-.1v.5l-.4-.1M233.9 69.6v.6M234.3 77.6l.5-.1v-.2l-.5-.1v.8M234.6 77.6l.2 .4M25 91.6h4.1M25 89.8h4.1M25.1 88.1h4M25.2 93.3h3.9M25.6 90.1h-.5v.3l.5 .2-.1 .3h-.4M25.6 91.8h-.5v.3l.5 .3-.2 .3-.3-.1"/>
<path d="M25.7 88.3h-.4l-.1 .2 .2 .3 .3 .1v.2l-.5 .1M25.8 93.5h-.4l-.1 .2 .1 .2 .4 .1v.3l-.5 .1M25.9 90.9v-.9l.3 .6 .3-.6v.9M25.9 92.7v-.9l.3 .6 .3-.6v.9M26 89.2v-.9l.4 .6 .2-.6v.9M26.1 94.4v-.9l.4 .6 .2-.6v.9M26.7 92.7h.7M26.7 91h.7M27 94.4h.6M27.5 90l.2 .9 .2-.6 .2 .6 .1-.9M27.5 88.3l-.5 .1v.3l.5 .2v.2l-.5 .1M27.6 91.8v.7l.1 .2 .4-.1v-.8"/>
<path d="M27.8 93.5v.9h.4M27.9 88.8h.2M28.3 88.3h-.4v.9h.4M28.5 92.2h.3l.1-.4h-.4v.9h.3l.2-.4-.3-.1M28.5 93.9l.4-.1-.1-.3h-.3v.9h.4l.1-.3-.3-.2M28.6 90.5h.2M28.7 88.3v.9h.4M29 90h-.4v.9h.4M31 95.3a.44 .44 0 0 0-.6 .2 .44 .44 0 0 0 .2 .6l.4-.1M31 97.1l-.4-.1a.44 .44 0 0 0-.1 .5 .44 .44 0 0 0 .5 .2M31 98.8l-.4-.1-.2 .3 .2 .5 .4-.1M31.3 95.2h.4"/>
<path d="M31.3 98.7h.4M31.3 97h.4M31.5 95.2v.9M31.5 97v.8M31.5 98.7v.8M32 95.2l.6 .9M32 97l.6 .8M32 98.7l.6 .8M32.6 95.2l-.6 .9M32.6 97l-.6 .8M32.6 98.7l-.6 .8M32.8 97.2l.3-.2v.8"/>
<path d="M32.8 98.8l.4-.1 .1 .2-.6 .6h.6M32.8 97.8h.5M33 95.2a.43 .43 0 0 1 .3 .5 .43 .43 0 0 1-.4 .4l-.1-.7zM75.1 88.1h4.7M75.1 93.3h4.8M75.1 82.9h4.7M75.1 91.6h4.9M75.1 81.2h4.5M75.1 89.8h4.9M75.1 84.6h4.7M75.1 86.4h4.6M75.1 88.8h.5v-.5h-.5v.9"/>
<path d="M75.1 95.7h.4l.1-.3-.1-.2h-.4v.9M75.1 93.9h.5v-.4h-.5v.9M75.1 83.6h.5v-.4h-.5v.8M75.1 92.2h.4l.1-.3-.5-.1v.9M75.1 81.9h.4l.1-.3-.1-.2h-.4v.9M75.1 90.5h.5v-.3l-.1-.2h-.4v.9M75.1 85.3h.5v-.3l-.1-.1h-.4v.8M75.1 87.1h.4l.1-.4-.1-.1h-.4v.9M75.6 97l-.5 .1v.2l.5 .2v.2h-.5M75.6 98.8l-.4-.1-.1 .3 .1 .5 .4-.1M75.9 98.7h.5M76 89.2v-.9l.3 .6 .3-.6v.9"/>
<path d="M76 96.1v-.9l.3 .6 .3-.6v.9M76 94.4v-.9l.3 .6 .3-.6v.9M76 84v-.8l.3 .6 .3-.6v.8M76 92.7v-.9l.3 .6 .3-.6v.9M76 82.3v-.9l.3 .7 .3-.7v.9M76 90.9v-.9l.3 .6 .3-.6v.9M76 97.8v-.8l.2 .6 .3-.6v.8M76 85.7v-.8l.3 .6 .3-.6v.8M76 87.5v-.9l.3 .6 .3-.6v.9M76.2 98.7v.8M76.6 98.7l.6 .8M76.8 96.1l.4-.9 .2 .9"/>
<path d="M76.9 95.8h.4M76.9 97.3h.4M77 88.3l.1 .9h.3l.1-.2v-.7M77 93.5l.1 .9h.3l.1-.9M77 83.2v.8h.4M77 91.8v.8l.2 .1 .3-.2v-.7M77 81.4v.9h.4M77 90l.1 .9h.3l.1-.9M77 84.9v.8h.4M77 86.6v.9h.4M77.2 98.7l-.6 .8M77.3 97h-.4v.8h.4"/>
<path d="M77.5 84.1h.6M77.5 82.4h.6M77.5 97.9h.7M77.5 85.8h.6M77.7 89.3h.7M77.7 92.7h.7M77.7 91h.7M77.8 98.7h-.3l-.1 .4 .4-.1v.5l-.4-.1M78.1 86.7h-.4v.3l.4 .2v.2h-.4M78.2 95.3l-.3-.1-.2 .3v.4l.1 .2 .4-.1M78.3 97l.2 .8 .4-.8M78.3 84.9l.1 .8 .2-.6 .2 .6 .2-.8"/>
<path d="M78.4 93.5l-.6 .1v.2l.6 .3-.1 .3h-.5M78.4 83.2v.7l.1 .1 .4-.1v-.7M78.4 81.4v.9h.4M78.4 91.8l.3 .9 .2-.7 .1 .7 .2-.9M78.5 88.3v.9h.4M78.5 90l.1 .9 .4-.1v-.8M78.5 87h.3M78.7 93.9h.3M78.9 86.6h-.4v.9h.4M79 95.3a.43 .43 0 0 0-.4 .2 .43 .43 0 0 0 .1 .6l.3-.1M79 81.8h.4l.1-.3-.5-.1v.9h.4l.1-.3-.2-.2M79.1 93.5h-.4v.9h.4"/>
<path d="M79.2 88.8h.3l.2-.2-.1-.3h-.4v.9l.5-.1v-.2l-.2-.1M79.2 83.6h.3l.2-.2-.1-.2h-.4v.8l.5-.1v-.2l-.2-.1M79.3 86.6v.9h.4M79.3 85.3h.3M79.5 93.5v.9h.4M79.5 90.5h.3l.1-.4-.4-.1v.9h.4l.1-.3-.3-.1M79.5 92.2h.3M79.7 84.9h-.4v.8h.4M80 91.8h-.5v.9h.5M90.5 95.7h.4l.2-.3-.2-.2h-.4v.9M90.5 93.9h.5v-.4h-.5v.9M91.4 96.1v-.9l.3 .6 .3-.6v.9"/>
<path d="M91.4 94.4v-.9l.3 .6 .3-.6v.9M92.4 95.6h.3M92.4 93.9h.3M92.8 95.2h-.4v.9h.4M92.8 93.5h-.4v.9h.4M93.6 95.3a.43 .43 0 0 0-.5 .2 .43 .43 0 0 0 .2 .6l.4-.1v-.3h-.2M93.6 93.5h-.3l-.2 .3 .2 .6 .4-.1v-.3h-.2M94 95.5l.3-.3v.9M94 93.8l.3-.3v.9M94 96.1h.4M94 94.4h.4M94.8 93.5h.5l-.3 .3 .3 .1v.4h-.5"/>
<path d="M95 95.2l-.2 .6h.6M95.2 95.5v.6M117.3 95.2v.9h.4M117.3 93.5v.9h.4M117.8 94.4h.7M117.8 96.1h.7M118.7 95.7l.5-.1v-.3l-.5-.1v.9M118.7 93.9h.4l.1-.3-.5-.1v.9M119.6 96.1v-.9l.2 .6 .3-.6v.9M119.6 94.4v-.9l.2 .6 .3-.6v.9M120.5 93.5v.9M120.5 95.2v.9"/>
<path d="M120.9 95.2a.49 .49 0 0 1 .5 .3 .49 .49 0 0 1-.1 .6h-.4zM120.9 93.5l.5 .1 .1 .4-.2 .4h-.4zM121.7 95.2l.6 .9M121.7 93.5l.6 .9M122.3 95.2l-.6 .9M122.3 93.5l-.6 .9M122.6 95.5l.2-.3v.9M122.6 93.8l.2-.3v.9M122.6 96.1h.5M122.6 94.4h.5M123.4 95.2h.5l-.3 .9M123.8 93.5h-.2l-.2 .3 .1 .6h.3v-.6h-.3l-.1 .2"/>
<path d="M31 102.2l-.4-.1a.44 .44 0 0 0-.1 .6 .44 .44 0 0 0 .5 .2M31 100.5a.44 .44 0 0 0-.6 .1 .44 .44 0 0 0 .2 .6l.4-.1M31.3 102.1h.4M31.3 100.4h.4M31.5 100.4v.8M31.5 102.1v.9M32 102.1l.6 .9M32 100.4l.6 .8M32.6 102.1l-.6 .9M32.6 100.4l-.6 .8M32.7 100.4h.6l-.3 .3 .3 .2-.1 .3-.5-.1M33 102.1l-.2 .6h.5"/>
<path d="M33.2 102.4v.6M95.9 108.8h3.8M96 109.4h.4l.1-.3-.5-.1v.9M96.9 109.9v-.9l.3 .6 .2-.6v.9M97.7 109.9h.6M98.5 109v.9h.4M99.2 109.4h.3M99.6 109h-.4v.9h.4M22.4 139.2l-.3-.1-.2 .2v.5l.2 .2 .3-.1M22.6 139.1h.6M22.9 139.1v.9M23.3 139.1l.6 .9"/>
<path d="M23.9 139.1l-.6 .9M24.3 139.2l.3-.1v.8a.39 .39 0 0 1-.4-.2 .39 .39 0 0 1 .1-.5zM50.2 124.1h.4v-.4h-.4v.8M50.2 125.9h.3l.2-.2-.2-.4h-.3v.9M50.2 131h.3l.2-.3-.2-.2h-.3v.9M50.2 134.4h.4v-.4h-.4v.8M50.2 132.7h.3l.2-.2-.1-.2h-.4v.8M50.2 137.9h.4v-.4h-.4v.8M50.2 127.5h.3l.2-.1-.1-.3h-.4v.9M50.2 129.2h.4v-.4h-.4v.9M50.2 136.2h.3l.2-.4-.2-.1h-.3v.8M50.2 139.6h.4v-.5h-.4v.9"/>
<path d="M51 124.5v-.8l.3 .5 .3-.5v.8M51 126.2v-.9l.3 .7 .3-.7v.9M51 131.4v-.9l.3 .7 .3-.7v.9M51 134.8v-.8l.3 .6 .3-.6v.8M51 133.1v-.8l.3 .6 .3-.6v.8M51 138.3v-.8l.3 .5 .3-.5v.8M51 128v-.9l.3 .6 .3-.6v.9M51 129.7v-.9l.3 .6 .3-.6v.9M51 136.5v-.8l.3 .7 .3-.7v.8M51 140v-.9l.3 .6 .3-.6v.9M52 124.1h.3M52 125.8h.3"/>
<path d="M52 130.9h.3M52 134.4h.3M52 132.6h.3M52 137.9h.3M52 127.5h.3M52 129.2h.3M52 136.1h.3M52 139.6h.3M52.4 123.7h-.4v.8h.4M52.4 125.3h-.4v.9h.4M52.4 130.5h-.4v.9h.4M52.4 134h-.4v.8h.4"/>
<path d="M52.4 132.3h-.4v.8h.4M52.4 137.5h-.4v.8h.4M52.4 127.1h-.4v.9h.4M52.4 128.8h-.4v.9h.4M52.4 135.7h-.4v.8h.4M52.4 139.1h-.4v.9h.4M53.2 123.7h-.3l-.2 .3 .2 .5 .4-.1v-.2h-.2M53.2 125.4a.43 .43 0 0 0-.5 .3 .43 .43 0 0 0 .2 .5l.4-.1v-.2h-.2M53.2 130.6a.43 .43 0 0 0-.5 .2 .43 .43 0 0 0 .2 .6l.4-.1v-.3h-.2M53.2 134h-.3l-.2 .3 .2 .5 .4-.1v-.2h-.2M53.2 132.3h-.3a.44 .44 0 0 0-.1 .5 .44 .44 0 0 0 .5 .3v-.4h-.2M53.2 137.5h-.3a.44 .44 0 0 0-.1 .5 .44 .44 0 0 0 .5 .2v-.3h-.2"/>
<path d="M53.2 127.1h-.3a.44 .44 0 0 0-.1 .6 .44 .44 0 0 0 .5 .2v-.4h-.2M53.2 128.8h-.3l-.2 .4 .2 .5 .4-.1v-.3h-.2M53.2 135.8a.43 .43 0 0 0-.5 .2 .43 .43 0 0 0 .2 .5h.4v-.3h-.2M53.2 139.1h-.3l-.2 .4 .2 .5 .4-.1v-.2h-.2M53.5 128.8h.6l-.3 .4h.3v.5l-.6-.1M53.5 135.7h.6l-.3 .8M53.6 125.6l.3-.3v.9M53.6 127.2l.5-.1v.4l-.6 .5h.6M53.6 126.2h.5M53.7 123.7h.4l-.1 .8h-.3l-.1-.2zM53.8 130.5l-.2 .6h.5M53.8 137.8l-.2-.3h.5v.3l-.5 .1v.3l.2 .1 .3-.1-.1-.4"/>
<path d="M54.1 134l-.5 .2v.5l.5 .1v-.5h-.4l-.1 .2M54.1 132.3h-.5v.3h.5l-.1 .5h-.4M54.1 139.5v.2h-.4l-.1-.5 .5-.1v.7l-.1 .2h-.3M54.1 130.8v.6M59.6 137h.3l.2-.3-.2-.2h-.3v1M59.6 135.3h.4l.1-.3-.2-.2h-.3v.9M59.6 133.6h.4v-.5h-.4v.9M59.6 138.7h.4v-.4h-.4v.8M60.3 131.9l.5-.1v-.4h-.5v.9M60.3 130.1h.4l.1-.4h-.5v.8M60.4 137.5v-1l.3 .7 .3-.7v1M60.4 135.7v-.9l.3 .6 .3-.6v.9"/>
<path d="M60.4 134v-.9l.3 .6 .3-.6v.9M60.4 139.1v-.8l.3 .6 .3-.6v.8M61.3 132.3v-.9l.2 .6 .3-.6v.9M61.3 130.5v-.8l.2 .6 .3-.6v.8M61.4 138.7h.3M61.4 136.9h.3M61.4 135.3h.3M61.4 133.6h.3M61.8 136.5h-.4v1h.4M61.8 134.8h-.4v.9h.4M61.8 133.1h-.4v.9h.4M61.8 140h-.4v.8h.4"/>
<path d="M61.8 138.3h-.4v.8h.4M62.2 131.8h.3M62.2 130.1h.3M62.6 136.6a.41 .41 0 0 0-.5 .4 .41 .41 0 0 0 .6 .4v-.4h-.2M62.6 134.9a.43 .43 0 0 0-.5 .3 .43 .43 0 0 0 .2 .5l.4-.1v-.3h-.2M62.6 131.4h-.4v.9h.4M62.6 133.1h-.3a.44 .44 0 0 0-.2 .6 .44 .44 0 0 0 .6 .2v-.3h-.2M62.6 129.7h-.4v.8h.4M62.6 138.3h-.3l-.2 .3 .2 .5h.4v-.3h-.2M62.9 136.8l.3-.3v1M62.9 135.1l.3-.3v.9M62.9 133.4l.3-.3v.9"/>
<path d="M62.9 138.6l.3-.3v.8M62.9 134h.6M62.9 135.7h.6M62.9 139.1h.6M62.9 137.5h.6M63.5 131.4h-.3l-.3 .2v.4l.3 .3 .3-.1v-.3h-.2M63.5 129.7h-.3l-.3 .2v.4l.2 .2h.4v-.3h-.2M63.8 136.6l.3-.1 .2 .2-.5 .8h.5M63.8 135.1l.2-.3v.9M63.8 138.3h.5l-.3 .3 .3 .2-.1 .3h-.4M63.8 135.7h.5M63.9 133.2l.1-.1a.45 .45 0 0 1 .3 .4 .45 .45 0 0 1-.3 .5l-.2-.4z"/>
<path d="M64 130l-.2-.1 .2-.2 .3 .1-.5 .4 .1 .3h.3l.1-.3-.2-.2M64 140l-.2 .6h.5M64.3 131.8l-.3 .1-.2-.4 .2-.1 .3 .1-.2 .7-.2 .1M89.6 130.1h.4l.1-.4h-.5v.8M90 131.9l.5-.1-.1-.4h-.4v.9M90.2 135.3h.4l.1-.3-.2-.2h-.3v.9M90.2 137h.3l.2-.3-.2-.2h-.3v1M90.2 133.6h.4v-.5h-.4v.9M90.5 130.5v-.8l.3 .6 .3-.6v.8M90.9 132.3v-.9l.2 .6 .4-.6v.9M91.1 135.7v-.9l.3 .6 .2-.6v.9M91.1 137.5v-1l.3 .7 .2-.7v1"/>
<path d="M91.1 134v-.9l.3 .6 .2-.6v.9M91.5 130.1h.3M91.6 138.7l.4-.1-.1-.3h-.3v.8M91.8 131.8h.4M91.9 129.7h-.4v.8h.4M92.1 136.9h.2M92.1 135.3h.2M92.1 133.6h.2M92.1 130.6h.6M92.2 131.4h-.4v.9h.4M92.4 139.1v-.8l.3 .6 .3-.6v.8M92.4 132.4h.7"/>
<path d="M92.5 134.8h-.4v.9h.4M92.5 136.5h-.4v1h.4M92.5 133.1h-.4v.9h.4M92.7 137.5h.6M92.7 135.8h.6M92.7 134.1h.6M92.9 130.5v-.8l.3 .6 .3-.6v.8M93.3 131.9l.5-.1v-.4h-.5v.9M93.3 138.7h.4M93.5 133.4v.6M93.5 135.2v.5M93.5 136.9v.6"/>
<path d="M93.5 131.9l.3 .4M93.7 140h-.4v.8h.4M93.8 135.2l-.3 .1M93.8 138.3h-.5v.8h.5M93.8 136.9l-.3 .1M93.8 133.4l-.3 .2M93.9 139.2h.7M94 134.9l.4-.1v.5l-.5 .4h.5M94 136.6l.4-.1v.4l-.5 .6h.5M94 133.2l.4-.1v.4l-.5 .5h.5M94.1 129.7l.3 .1v.6h-.5a.52 .52 0 0 1 .2-.7zM94.2 131.8h.2"/>
<path d="M94.5 131.4h-.3v.9h.3M94.6 140l.2 .8 .2-.6 .1 .6 .3-.8M94.8 134.8h.6l-.4 .9M94.8 129.7h.2l.3 .2v.4l-.2 .2h-.3zM94.8 138.3v.8M95 136.9l-.2-.2 .2-.2 .3 .1v.3h-.4l-.1 .2 .2 .4 .3-.1v-.4l-.2-.1M95 131.8h.2M95 138.6l.3 .5M95.2 133.1h-.2l-.2 .7 .2 .2 .3-.1-.1-.4h-.3l-.1 .1M95.3 138.3l-.5 .5M95.4 131.4h-.4v.9M119.5 131.9h.3l.2-.2-.2-.3h-.3v.9"/>
<path d="M119.5 133.6h.4v-.5h-.4v.9M119.5 130.1h.4l.1-.3-.2-.1h-.3v.8M119.5 135.3h.4l.1-.3-.2-.2h-.3v.9M120.2 137h.3l.2-.3-.2-.2h-.3v1M120.2 138.7h.4v-.4h-.4v.8M120.4 132.3v-.9l.3 .6 .2-.6v.9M120.4 134v-.9l.3 .6 .2-.6v.9M120.4 130.5v-.8l.3 .6 .2-.6v.8M120.4 135.7v-.9l.3 .6 .2-.6v.9M121 137.5v-1l.3 .7 .3-.7v1M121 139.1v-.8l.3 .6 .3-.6v.8M121.4 135.3h.2"/>
<path d="M121.4 131.8h.2M121.4 133.6h.2M121.4 130.1h.2M121.8 131.4h-.4v.9h.4M121.8 133.1h-.4v.9h.4M121.8 129.7h-.4v.8h.4M121.8 134.8h-.4v.9h.4M122 135.8h.6M122 132.4h.6M122 134.1h.6M122 130.6h.6M122 138.7h.3"/>
<path d="M122 136.9h.3M122.4 136.5h-.4v1h.4M122.4 138.3h-.4v.8h.4M122.4 140h-.4v.8h.4M122.6 139.2h.6M122.6 137.5h.6M122.8 130v.5M122.8 131.7v.6M122.8 133.4v.6M122.8 135.2v.5M123.1 131.7l-.3 .2M123.1 133.4l-.3 .2"/>
<path d="M123.1 130l-.3 .1M123.1 135.2l-.3 .1M123.3 131.6l.2-.2v.9M123.3 133.4l.2-.3v.9M123.3 129.9l.2-.2v.8M123.3 135.1l.2-.3v.9M123.3 132.3h.4M123.3 134h.4M123.3 130.5h.4M123.3 135.7h.4M123.7 136.9h-.3v.2l.3 .1v.3l-.3-.1M123.7 138.6h-.3l.1 .3h.2v.2h-.3"/>
<path d="M124.1 131.4h.6l-.5 .9M124.1 138.6l.2-.3v.8M124.1 139.1h.5M124.2 136.6l.2-.1 .2 .2v.6l-.2 .2a.53 .53 0 0 1-.2-.9zM124.2 133.5l-.1-.2 .1-.2 .4 .1-.1 .3-.4 .1 .1 .4 .4-.1v-.3l-.2-.1M124.5 129.7l-.4 .3v.3l.1 .2 .4-.1-.1-.4h-.3l-.1 .2M124.6 135.3h-.5l.1-.5 .4 .1v.6l-.4 .2M153.8 137h.3l.2-.3-.2-.2h-.3v1M153.8 135.3h.4l.1-.3-.2-.2h-.3v.9M153.8 138.7h.4v-.4h-.4v.8M153.8 130.1h.4l.1-.3-.2-.1h-.3v.8M153.8 131.9h.3l.2-.2-.2-.3h-.3v.9"/>
<path d="M153.8 128.4h.4v-.4h-.4v.8M153.8 133.6h.4v-.5h-.4v.9M153.8 126.7h.3l.2-.2-.2-.3h-.3v.9M153.8 124.9h.4l.1-.2-.2-.2h-.3v.8M154.6 137.5v-1l.4 .7 .2-.7v1M154.6 135.7v-.9l.4 .6 .2-.6v.9M154.6 139.1v-.8l.4 .6 .2-.6v.8M154.6 130.5v-.8l.4 .6 .2-.6v.8M154.6 132.3v-.9l.4 .6 .2-.6v.9M154.6 128.8v-.8l.4 .6 .2-.6v.8M154.6 134v-.9l.4 .6 .2-.6v.9M154.6 127.1v-.9l.4 .7 .2-.7v.9"/>
<path d="M154.6 125.3v-.8l.4 .6 .2-.6v.8M155.7 124.5v.8M155.7 126.2v.9M155.7 128v.8M155.7 129.7v.8M155.7 131.4v.9M155.7 133.1v.9M155.7 134.8v.9M155.7 136.5v1M155.7 138.3v.8M155.7 140v.8M156.1 140l.4 .2v.5l-.2 .1h-.2z"/>
<path d="M156.1 136.5l.4 .3v.4l-.3 .3h-.1zM156.1 134.8l.4 .3v.4l-.2 .2h-.2zM156.1 138.3l.4 .2v.5l-.2 .1h-.2zM156.1 129.7l.4 .2v.4l-.2 .2h-.2zM156.1 131.4l.4 .2v.4l-.3 .3h-.1zM156.1 128l.4 .1v.5l-.3 .2h-.1zM156.1 133.1l.4 .2v.5l-.3 .2h-.1zM156.1 126.2l.4 .2v.5l-.3 .2h-.1zM156.1 124.5l.4 .3v.4l-.2 .1h-.2zM156.8 140l.6 .8M156.8 136.5l.6 1M156.8 134.8l.6 .9"/>
<path d="M156.8 138.3l.6 .8M156.8 129.7l.6 .8M156.8 131.4l.6 .9M156.8 128l.6 .8M156.8 133.1l.6 .9M156.8 126.2l.6 .9M156.8 124.5l.6 .8M157.4 140l-.6 .8M157.4 136.5l-.6 1M157.4 134.8l-.6 .9M157.4 138.3l-.6 .8M157.4 129.7l-.6 .8"/>
<path d="M157.4 131.4l-.6 .9M157.4 128l-.6 .8M157.4 133.1l-.6 .9M157.4 126.2l-.6 .9M157.4 124.5l-.6 .8M157.6 136.5h.6l-.3 1M157.6 129.7h.6l-.3 .3h.2l.1 .2-.1 .3-.5-.1M157.7 128.1l.4-.1 .1 .2-.6 .6h.6M157.7 126.4l.2-.2v.9M157.7 127.1h.5M157.9 138.6l-.2-.2 .4-.1v.3l-.4 .1 .1 .4h.3l.1-.1-.2-.4M157.9 131.4l-.2 .5h.5"/>
<path d="M157.9 124.5a.43 .43 0 0 1 .3 .5 .43 .43 0 0 1-.4 .3l-.1-.6zM158.1 134.8l-.4 .3v.5l.4 .1 .1-.4-.2-.1-.3 .1M158.1 133.1h-.4v.5l.4-.1 .1 .3-.2 .2-.3-.1M158.1 131.7v.6M181.9 137l.5-.1v-.3l-.5-.1v1M181.9 138.7h.4l.1-.3-.5-.1v.8M181.9 135.3h.5v-.4l-.5-.1v.9M181.9 128.4h.4l.1-.3-.5-.1v.8M181.9 130.1h.4l.1-.4h-.5v.8M181.9 126.7l.5-.1v-.3l-.5-.1v.9M181.9 133.6h.4l.1-.4-.5-.1v.9M181.9 131.9l.5-.1v-.4h-.5v.9"/>
<path d="M181.9 124.9h.4l.1-.3-.5-.1v.8M182.8 137.5v-1l.3 .7 .2-.7v1M182.8 139.1v-.8l.3 .6 .2-.6v.8M182.8 135.7v-.9l.3 .6 .2-.6v.9M182.8 128.8v-.8l.3 .6 .2-.6v.8M182.8 130.5v-.8l.3 .6 .2-.6v.8M182.8 127.1v-.9l.3 .7 .2-.7v.9M182.8 134v-.9l.3 .6 .2-.6v.9M182.8 132.3v-.9l.3 .6 .2-.6v.9M182.8 125.3v-.8l.3 .6 .2-.6v.8M183.8 138.7h.3M183.8 136.9h.3"/>
<path d="M183.8 135.3h.3M183.8 131.8h.3M183.8 133.6h.3M183.8 130.1h.3M183.8 124.9h.3M183.8 128.4h.3M183.8 126.6h.3M184.2 136.5h-.4v1h.4M184.2 138.3h-.4v.8h.4M184.2 140h-.4v.8h.4M184.2 134.8h-.4v.9h.4M184.2 128h-.4v.8h.4"/>
<path d="M184.2 129.7h-.4v.8h.4M184.2 126.2h-.4v.9h.4M184.2 133.1h-.4v.9h.4M184.2 131.4h-.4v.9h.4M184.2 124.5h-.4v.8h.4M184.4 139.2h.6M184.4 137.5h.6M184.4 135.8h.6M184.4 132.4h.6M184.4 134.1h.6M184.4 130.6h.6M184.4 125.4h.6"/>
<path d="M184.4 128.9h.6M184.4 127.2h.6M185.2 139.1v-.8l.3 .6 .3-.6v.8M185.2 124.8v.5M185.2 126.5v.6M185.2 128.2v.6M185.2 130v.5M185.5 128.2l-.3 .2M185.5 130l-.3 .1M185.5 126.5l-.3 .2M185.5 124.8l-.3 .1M185.5 136.9h-.3v.2l.3 .1v.3l-.3-.1"/>
<path d="M185.5 135.2h-.3l.1 .2h.2v.3h-.3M185.5 133.5h-.3l.1 .2h.2v.3l-.3-.1M185.5 131.7h-.3v.2h.3v.3h-.3M185.7 128.2l.3-.2v.8M185.7 129.9l.3-.2v.8M185.7 126.4l.3-.2v.9M185.7 124.8l.3-.3v.8M185.7 130.5h.5M185.7 127.1h.5M185.7 128.8h.5M185.7 125.3h.5M185.8 136.5h.6l-.3 .4 .3 .1v.3l-.2 .2-.4-.1"/>
<path d="M185.9 134.9l.3-.1 .2 .3-.6 .6h.6M185.9 133.4l.2-.3v.9M185.9 134h.5M186.1 131.4a.48 .48 0 0 1 .3 .4 .48 .48 0 0 1-.3 .5l-.2-.2v-.6zM186.2 138.4h.5l-.1 .7h-.4zM186.5 140h-.4v.8h.4M186.5 126.2h.6l-.4 .9M186.7 128.3l-.1-.2 .3-.1 .1 .2-.4 .2v.3l.1 .1 .3-.1-.1-.4M186.9 124.5l-.3 .3v.5h.4l-.1-.5h-.3v.2M187 130l-.1 .2h-.3v-.5h.4v.6l-.1 .2h-.3M187.1 138.3h.3l.2 .2v.5l-.2 .1h-.3zM187.2 140h-.3v.8"/>
<path d="M193.4 131.9h.4l.1-.2-.1-.3h-.4v.9M193.4 128.4h.4v-.4h-.4v.8M193.4 135.3h.4l.1-.3-.1-.2h-.4v.9M193.4 137h.4l.1-.3-.1-.2h-.4v1M193.4 124.9h.4l.1-.2-.1-.2h-.4v.8M193.4 130.1h.4l.1-.3-.1-.1h-.4v.8M193.4 126.7h.4l.1-.3-.1-.2h-.4v.9M193.4 133.6h.4v-.5h-.4v.9M193.4 138.7h.4v-.4h-.4v.8M194.3 132.3v-.9l.2 .6 .4-.6v.9M194.3 128.8v-.8l.2 .6 .4-.6v.8M194.3 135.7v-.9l.2 .6 .4-.6v.9"/>
<path d="M194.3 137.5v-1l.2 .7 .4-.7v1M194.3 125.3v-.8l.2 .6 .4-.6v.8M194.3 130.5v-.8l.2 .6 .4-.6v.8M194.3 127.1v-.9l.2 .7 .4-.7v.9M194.3 134v-.9l.2 .6 .4-.6v.9M194.3 139.1v-.8l.2 .6 .4-.6v.8M195.3 124.5v.8M195.3 126.2v.9M195.3 128v.8M195.3 129.7v.8M195.3 131.4v.9M195.3 133.1v.9"/>
<path d="M195.3 134.8v.9M195.3 136.5v1M195.3 138.3v.8M195.3 140v.8M195.7 131.4l.4 .2v.4l-.2 .3h-.2zM195.7 128l.4 .1v.5l-.2 .2h-.2zM195.7 134.8l.4 .3v.4l-.1 .2h-.3zM195.7 136.5l.4 .3v.4l-.2 .3h-.2zM195.7 124.5l.4 .3v.4l-.1 .1h-.3zM195.7 129.7l.4 .2v.4l-.1 .2h-.3zM195.7 126.2l.4 .2v.5l-.2 .2h-.2zM195.7 133.1l.4 .2v.5l-.2 .2h-.2z"/>
<path d="M195.7 140l.4 .2v.5l-.1 .1h-.3zM195.7 138.3l.4 .2v.5l-.1 .1h-.3zM196.5 140l.6 .8M196.5 129.7l.6 .8M196.5 131.4l.6 .9M196.5 128l.6 .8M196.5 134.8l.6 .9M196.5 136.5l.6 1M196.5 124.5l.6 .8M196.5 126.2l.6 .9M196.5 133.1l.6 .9M196.5 138.3l.6 .8"/>
<path d="M197.1 131.4l-.6 .9M197.1 128l-.6 .8M197.1 134.8l-.6 .9M197.1 136.5l-.6 1M197.1 124.5l-.6 .8M197.1 129.7l-.6 .8M197.1 126.2l-.6 .9M197.1 133.1l-.6 .9M197.1 140l-.6 .8M197.1 138.3l-.6 .8M197.2 136.5h.6l-.3 1M197.2 129.7h.6l-.3 .3h.2v.5l-.5-.1"/>
<path d="M197.3 128.1l.4-.1 .1 .2-.6 .6h.6M197.3 126.4l.3-.2v.9M197.3 127.1h.5M197.5 131.4l-.2 .5h.5M197.5 124.5a.43 .43 0 0 1 .3 .5 .43 .43 0 0 1-.4 .3l-.1-.6zM197.5 138.6l-.2-.2 .4-.1v.3l-.4 .1v.4h.4l.1-.3-.1-.2M197.7 134.8l-.4 .3v.5l.4 .1 .1-.4-.1-.1-.4 .1M197.7 133.1h-.4v.5l.4-.1 .1 .3-.1 .2-.4-.1M197.7 131.7v.6M218.1 138.7h.5v-.4h-.5v.8M218.1 137l.5-.1-.1-.4h-.4v1M218.1 135.3h.5v-.4l-.5-.1v.9"/>
<path d="M218.1 124.9h.5v-.3l-.5-.1v.8M218.1 130.1h.5v-.4h-.5v.8M218.1 128.4h.5v-.4h-.5v.8M218.1 133.6h.5v-.5h-.5v.9M218.1 126.7l.5-.1-.1-.4h-.4v.9M218.1 131.9l.5-.1-.1-.4h-.4v.9M219 139.1v-.8l.2 .6 .4-.6v.8M219 137.5v-1l.2 .7 .4-.7v1M219 135.7v-.9l.2 .6 .4-.6v.9M219 125.3v-.8l.2 .6 .4-.6v.8M219 130.5v-.8l.2 .6 .4-.6v.8M219 128.8v-.8l.2 .6 .4-.6v.8"/>
<path d="M219 134v-.9l.2 .6 .4-.6v.9M219 127.1v-.9l.2 .7 .4-.7v.9M219 132.3v-.9l.2 .6 .4-.6v.9M219.9 138.7h.4M219.9 136.9h.4M219.9 135.3h.4M219.9 131.8h.4M219.9 133.6h.4M219.9 130.1h.4M219.9 124.9h.4M219.9 128.4h.4M219.9 126.6h.4"/>
<path d="M220.3 138.3h-.4v.8h.4M220.3 140h-.4v.8h.4M220.3 136.5h-.4v1h.4M220.3 134.8h-.4v.9h.4M220.3 124.5h-.4v.8h.4M220.3 129.7h-.4v.8h.4M220.3 128h-.4v.8h.4M220.3 133.1h-.4v.9h.4M220.3 126.2h-.4v.9h.4M220.3 131.4h-.4v.9h.4M220.5 139.2h.7M220.5 137.5h.7"/>
<path d="M220.5 135.8h.7M220.5 132.4h.7M220.5 134.1h.7M220.5 130.6h.7M220.5 125.4h.7M220.5 128.9h.7M220.5 127.2h.7M221.4 138.7h.4l.1-.3-.5-.1v.8M221.4 137l.5-.1v-.3l-.5-.1v1M221.4 135.3h.5v-.4l-.5-.1v.9M221.4 124.9h.4l.1-.3-.5-.1v.8M221.4 130.1h.4l.1-.4h-.5v.8"/>
<path d="M221.4 128.4h.4l.1-.3-.5-.1v.8M221.4 133.6h.4l.1-.4-.5-.1v.9M221.4 126.7l.5-.1v-.3l-.5-.1v.9M221.4 131.9l.5-.1v-.4h-.5v.9M222.3 138.7h.2M222.3 136.9h.2M222.3 135.3h.2M222.3 131.8h.2M222.3 133.6h.2M222.3 130.1h.2M222.3 124.9h.2M222.3 128.4h.2"/>
<path d="M222.3 126.6h.2M222.6 138.3h-.3v.8M222.6 140h-.3v.8M222.6 136.5h-.3v1M222.6 134.8h-.3v.9M222.6 124.5h-.3v.8M222.6 129.7h-.3v.8M222.6 128h-.3v.8M222.6 133.1h-.3v.9M222.6 126.2h-.3v.9M222.6 131.4h-.3v.9M223.5 138.3v.8l-.5-.8v.8"/>
<path d="M223.5 140v.8l-.5-.8v.8M223.5 136.5v1l-.5-1v1M223.5 134.8v.9l-.5-.9v.9M223.5 124.5v.8l-.5-.8v.8M223.5 129.7v.8l-.5-.8v.8M223.5 128v.8l-.5-.8v.8M223.5 133.1v.9l-.5-.9v.9M223.5 126.2v.9l-.5-.9v.9M223.5 131.4v.9l-.5-.9v.9M223.8 136.5h.6l-.4 1M223.8 129.7h.5l-.2 .3 .2 .1v.3h-.5M223.8 128.1h.5v.2l-.5 .5h.5"/>
<path d="M223.8 126.4l.3-.2v.9M223.8 127.1h.5M223.9 124.6l.3-.1 .1 .2-.1 .6a.39 .39 0 0 1-.4-.2 .39 .39 0 0 1 .1-.5zM224 138.6l-.2-.1 .1-.2h.3l.1 .3-.5 .2 .1 .3h.4v-.4l-.1-.1M224.1 131.4l-.3 .5h.6M224.2 134.8l-.2 .1-.2 .6 .1 .2 .4-.1v-.3l-.3-.1-.2 .1M224.2 131.7v.6M224.3 133.1h-.4l-.1 .5 .4-.1 .1 .4h-.5M21.5 156.2h4.1M21.5 152.7h4.1M21.8 157.9h3.8M22.1 156.4l-.3-.1-.2 .2 .5 .6-.1 .2-.4-.1"/>
<path d="M22.1 152.9h-.4l-.1 .2 .5 .5-.1 .2-.4-.1M22.3 158.1l-.4 .1v.3l.4 .1v.3l-.4 .1M22.4 146.1l-.3-.1-.2 .3v.4l.2 .2h.3M22.4 147.9l-.3-.1-.2 .2v.4l.2 .2 .3-.1M22.4 142.7l-.3-.1-.2 .2v.4l.2 .3 .3-.1M22.4 140.9l-.3-.1-.2 .3v.4l.2 .3 .3-.1M22.4 144.4l-.3-.1-.2 .2v.5l.2 .2 .3-.1M22.5 157.3v-1l.3 .7 .3-.7v1M22.5 153.8v-.9l.3 .6 .3-.6v.9M22.6 142.6h.6M22.6 144.3h.6M22.6 146h.6"/>
<path d="M22.6 147.8h.6M22.6 140.8h.6M22.7 159v-.9l.3 .6 .3-.6v.9M22.9 140.8v1M22.9 142.6v.9M22.9 144.3v.9M22.9 146v.9M22.9 147.8v.8M23.3 157.3h.6M23.3 153.9h.6M23.3 146l.6 .9M23.3 147.8l.6 .8"/>
<path d="M23.3 142.6l.6 .9M23.3 140.8l.6 1M23.3 144.3l.6 .9M23.5 159h.7M23.9 146l-.6 .9M23.9 147.8l-.6 .8M23.9 142.6l-.6 .9M23.9 140.8l-.6 1M23.9 144.3l-.6 .9M24.1 152.9l.2 .9 .1-.6 .2 .6 .2-.9M24.2 156.3v.9l.1 .1 .4-.2v-.8M24.2 142.7h.5v.3l-.5 .5h.5"/>
<path d="M24.2 141.1l.2-.3v1M24.2 144.3h.5l-.3 .3 .3 .1v.4h-.5M24.2 141.8h.5M24.3 158.1v.9h.5M24.4 146l-.2 .6h.5M24.6 146.3v.6M24.7 147.8h-.4l-.1 .4 .4-.1 .1 .4h-.5M25 156.8h.4l.1-.3-.1-.2h-.4v1l.5-.1v-.4h-.1M25 158.5h.4l.1-.1-.1-.3h-.4v.9l.5-.1v-.3l-.1-.1M25.1 153.4h.3M25.5 152.9h-.4v.9h.4M50.2 148.2h.4v-.4h-.4v.8"/>
<path d="M50.2 146.5h.3l.2-.3-.2-.2h-.3v.9M50.2 144.7h.4l.1-.2-.2-.2h-.3v.9M50.2 141.3h.3l.2-.1-.2-.4h-.3v1M50.2 143h.4v-.4h-.4v.9M50.6 149.6l-.4-.1-.1 .1 .1 .3 .4 .1v.2l-.5 .1M51 148.6v-.8l.3 .6 .3-.6v.8M51 150.3v-.8l.3 .6 .2-.6v.8M51 146.9v-.9l.3 .7 .3-.7v.9M51 145.2v-.9l.3 .6 .3-.6v.9M51 141.8v-1l.3 .7 .3-.7v1M51 143.5v-.9l.3 .6 .3-.6v.9M51.9 149.9h.4"/>
<path d="M52 148.2h.3M52 146.4h.3M52 144.7h.3M52 141.3h.3M52 143h.3M52.4 149.5h-.5v.8h.5M52.4 147.8h-.4v.8h.4M52.4 146h-.4v.9h.4M52.4 144.3h-.4v.9h.4M52.4 140.8h-.4v1h.4M52.4 142.6h-.4v.9h.4M52.5 150.4h.7"/>
<path d="M53.2 147.8h-.3a.44 .44 0 0 0-.1 .5 .44 .44 0 0 0 .5 .2v-.2h-.2M53.2 146.1a.41 .41 0 0 0-.5 .4 .41 .41 0 0 0 .6 .4v-.4h-.2M53.2 144.4a.42 .42 0 0 0-.5 .2 .42 .42 0 0 0 .2 .6l.4-.1v-.3h-.2M53.2 140.9a.41 .41 0 0 0-.5 .5 .41 .41 0 0 0 .6 .3v-.4h-.2M53.2 142.6h-.3a.44 .44 0 0 0-.1 .6 .44 .44 0 0 0 .5 .2v-.3h-.2M53.3 149.5l.2 .8 .4-.8M53.6 148l.3-.2v.8M53.6 146.3l.3-.3v.9M53.6 144.6l.3-.3v.9M53.6 141.1l.3-.3v1M53.6 142.9l.3-.3v.9M53.6 141.8h.5"/>
<path d="M53.6 148.6h.5M53.6 146.9h.5M53.6 145.2h.5M53.6 143.5h.5M54.4 146h.5l-.3 .3 .3 .1v.5h-.5M54.4 144.4h.5v.2l-.5 .6h.5M54.4 142.9l.2-.3v.9M54.4 143.5h.5M54.5 140.9l.2-.1 .2 .2v.6l-.2 .2a.53 .53 0 0 1-.2-.9zM54.6 147.7l-.2 .7h.6M54.8 148v.6M59.6 140.5h.3l.2-.3-.2-.2h-.3v.8"/>
<path d="M59.6 147.5h3.9M60.2 147.8h-.5l-.1 .2 .2 .2 .4 .1v.2h-.6M60.4 140.8v-.8l.3 .6 .3-.6v.8M60.5 148.6v-.8l.3 .6 .3-.6v.8M61.2 141.8l-.5 .1v.1l.5 .4-.2 .2-.3-.1M61.4 140.4h.3M61.5 142.6v-.8l.3 .6 .3-.6v.8M61.9 147.8h-.4v.3l.4 .2v.2h-.4M62.4 148.2h.2M62.5 142.1h.3M62.6 140.1a.43 .43 0 0 0-.5 .2 .43 .43 0 0 0 .2 .5h.4v-.3h-.2M62.8 147.8h-.4v.8h.4"/>
<path d="M62.9 141.8h-.4v.8h.4M62.9 140.2l.3-.2v.8M62.9 140.8h.6M63 142.7h.7M63.1 147.8v.8h.4M63.8 141.8l.3 .8 .3-.8M64.2 140.3v.5M89.6 147.5h4.9M89.8 148.2h.4v-.4h-.4v.8M90.6 148.6v-.8l.3 .6 .3-.6v.8M91.4 140.5h.3l.2-.3-.2-.2h-.3v.8M91.6 147.8v.7l.2 .1 .3-.1v-.7"/>
<path d="M91.6 142.2h.4l.2-.3-.6-.1v.8M92.2 140.8v-.8l.4 .6 .2-.6v.8M92.5 142.6v-.8l.3 .6 .3-.6v.8M93 147.8l-.5 .1v.2l.5 .3-.2 .2-.3-.1M93.3 140.4h.2M93.3 148.2h.3M93.5 142.1h.3M93.8 147.8h-.5v.8h.5M93.8 140.9h.6M93.9 141.8h-.4v.8h.4M94.1 147.8v.8h.4M94.1 142.7h.6"/>
<path d="M94.8 141.8l.3 .8 .3-.8M118.9 147.5h4.9M119.1 148.2l.4-.1-.1-.3h-.3v.8M119.9 148.6v-.8l.3 .6 .3-.6v.8M120.2 140.5h.3l.2-.3-.2-.2h-.3v.8M120.2 142.2h.3l.2-.3-.5-.1v.8M120.9 147.8v.7l.1 .1 .4-.1v-.7M121 140.8v-.8l.3 .6 .3-.6v.8M121 142.6v-.8l.3 .6 .3-.6v.8M122 142.1h.3M122 140.4h.3M122.2 147.8l-.4 .1v.2l.4 .2v.2h-.4"/>
<path d="M122.4 141.8h-.4v.8h.4M122.6 142.7h.6M122.6 140.9h.6M122.6 148.2h.3M123.1 147.8h-.5v.8h.5M123.4 147.8v.8h.4M123.7 140.3h-.3l.1 .3h.2v.2h-.3M123.7 142h-.3v.3l.3 .1v.2l-.3-.1M124.1 140.1h.5v.3l-.5 .4h.5M124.1 141.8h.5l-.3 .2 .3 .1v.4h-.5M150.7 158.7h5M150.8 159.4h.4l.1-.4h-.5v.8"/>
<path d="M151.7 159.8v-.8l.2 .6 .4-.6v.8M152.6 159l.1 .8 .4-.1v-.7M152.9 150.8l.6-.1v-.3l-.6-.1v.9M152.9 147.4l.6-.1v-.3l-.6-.1v.9M152.9 152.5l.6-.1v-.2l-.6-.1v.8M152.9 154.2h.5l.1-.3-.6-.1v.8M152.9 149.1h.5l.1-.4-.6-.1v.9M152.9 142.2l.6-.1v-.2l-.6-.1v.8M152.9 143.9h.5l.1-.4h-.6v.8M152.9 145.7l.6-.1v-.4h-.6v.8M153.4 159.9h.6M153.8 151.2v-.9l.3 .7 .3-.7v.9"/>
<path d="M153.8 147.8v-.9l.3 .6 .3-.6v.9M153.8 152.9v-.8l.3 .6 .3-.6v.8M153.8 154.6v-.8l.3 .6 .3-.6v.8M153.8 149.5v-.9l.3 .6 .3-.6v.9M153.8 140.5h.3l.2-.3-.2-.2h-.3v.8M153.8 142.6v-.8l.3 .6 .3-.6v.8M153.8 144.3v-.8l.3 .6 .3-.6v.8M153.8 146v-.8l.3 .6 .3-.6v.8M154.1 159l.2 .8 .2-.6 .1 .6 .3-.8M154.6 140.8v-.8l.4 .6 .2-.6v.8M154.8 141.8v.8M154.8 143.5v.8"/>
<path d="M154.8 145.2v.8M154.8 146.9v.9M154.8 148.6v.9M154.8 150.3v.9M154.8 152.1v.8M154.8 153.8v.8M155.1 159.4h.4M155.2 150.3a.49 .49 0 0 1 .5 .3 .49 .49 0 0 1-.1 .6h-.4zM155.2 146.9h.4a.48 .48 0 0 1 .1 .6 .48 .48 0 0 1-.5 .3zM155.2 152.1h.4a.48 .48 0 0 1 .1 .5 .48 .48 0 0 1-.5 .3zM155.2 153.8l.5 .1v.4l-.1 .3h-.4zM155.2 148.6l.5 .1v.4l-.1 .4h-.4z"/>
<path d="M155.2 141.8h.4a.48 .48 0 0 1 .1 .5 .48 .48 0 0 1-.5 .3zM155.2 143.5h.5v.5l-.1 .3h-.4zM155.2 145.2a.49 .49 0 0 1 .5 .3 .49 .49 0 0 1-.1 .5h-.4zM155.6 159h-.5v.8h.5M156 150.3l.6 .9M156 146.9l.6 .9M156 152.1l.6 .8M156 153.8l.6 .8M156 148.6l.6 .9M156 141.8l.6 .8M156 143.5l.6 .8M156 145.2l.6 .8"/>
<path d="M156.6 150.3l-.6 .9M156.6 146.9l-.6 .9M156.6 152.1l-.6 .8M156.6 153.8l-.6 .8M156.6 148.6l-.6 .9M156.6 141.8l-.6 .8M156.6 143.5l-.6 .8M156.6 145.2l-.6 .8M156.8 150.6l.3-.3v.9M156.8 147.1l.3-.2v.9M156.8 152.4l.3-.3v.8M156.8 154l.3-.2v.8"/>
<path d="M156.8 148.9l.3-.3v.9M156.8 141.9l.3-.1v.8M156.8 143.7l.3-.2v.8M156.8 145.4l.3-.2v.8M156.8 142.6h.5M156.8 144.3h.5M156.8 146h.5M156.8 151.2h.5M156.8 147.8h.5M156.8 149.5h.5M156.8 152.9h.5M156.8 154.6h.5"/>
<path d="M157.6 146.9h.6l-.3 .3 .3 .2v.2l-.2 .2-.4-.1M157.6 153.8h.6l-.3 .8M157.7 141.9l.2-.1a.43 .43 0 0 1 .3 .4 .43 .43 0 0 1-.3 .4l-.2-.2zM157.7 143.7l.2-.2v.8M157.7 145.2h.3l.2 .2-.6 .6h.6M157.7 144.3h.5M157.9 148.5l-.2 .7h.5M158.1 150.3h-.4v.4h.3l.2 .1-.1 .4-.4-.1M158.1 152.1l-.4 .2v.6h.3l.2-.4-.2-.1-.3 .1M158.1 148.9v.6M158.2 140.4l-.5 .1v-.4l.3-.1 .2 .2-.2 .6h-.2M181.9 150.8l.5-.1v-.3l-.5-.1v.9"/>
<path d="M181.9 143.9h.4l.1-.4h-.5v.8M181.9 145.7l.5-.1v-.4h-.5v.8M181.9 149.1h.4l.1-.4-.5-.1v.9M181.9 142.2l.5-.1v-.2l-.5-.1v.8M181.9 140.5l.5-.1v-.3l-.5-.1v.8M181.9 147.4l.5-.1v-.3l-.5-.1v.9M182.8 151.2v-.9l.3 .7 .2-.7v.9M182.8 144.3v-.8l.3 .6 .2-.6v.8M182.8 146v-.8l.3 .6 .2-.6v.8M182.8 149.5v-.9l.3 .6 .2-.6v.9M182.8 142.6v-.8l.3 .6 .2-.6v.8M182.8 140.8v-.8l.3 .6 .2-.6v.8"/>
<path d="M182.8 147.8v-.9l.3 .6 .2-.6v.9M183.8 142.1h.3M183.8 143.9h.3M183.8 140.4h.3M183.8 145.6h.3M183.8 150.7h.3M183.8 147.3h.3M183.8 149.1h.3M184.2 150.3h-.4v.9h.4M184.2 143.5h-.4v.8h.4M184.2 145.2h-.4v.8h.4M184.2 148.6h-.4v.9h.4"/>
<path d="M184.2 141.8h-.4v.8h.4M184.2 146.9h-.4v.9h.4M184.4 142.7h.6M184.4 144.4h.6M184.4 140.9h.6M184.4 146.1h.6M184.4 151.3h.6M184.4 147.9h.6M184.4 149.6h.6M185.1 150.3l.3 .9 .2-.9M185.1 148.6l.3 .9 .1-.6 .1 .6 .3-.9M185.2 140.5h.3l.2-.3-.2-.2h-.3v.8"/>
<path d="M185.2 142v.6M185.2 143.7v.6M185.2 145.5v.5M185.2 146.9v.9M185.4 147.3l.3 .5M185.5 143.7l-.3 .2M185.5 145.5l-.3 .2M185.5 142l-.3 .2M185.5 140.5l.2 .3M185.7 143.5h.4l.1 .2-.6 .6h.6M185.7 145.2h.4l.1 .2-.6 .6h.6M185.7 141.9l.4-.1 .1 .1-.6 .7h.6"/>
<path d="M185.7 146.9l-.5 .5M186.1 140.4h.3M186.5 143.5h.6l-.4 .8M186.7 145.6l-.1-.1v-.3h.3l.1 .3-.4 .2v.3l.4-.1-.1-.3M186.9 141.8l-.3 .1v.6l.3 .1 .1-.5-.3-.1-.1 .2M186.9 140.4h.3M190.5 158.7h4.8M190.6 159.4h.4v-.4h-.4v.8M191.5 159.8v-.8l.3 .6 .3-.6v.8M192.5 159v.8h.4M192.6 142.2l.5-.1v-.2l-.5-.1v.8M192.6 143.9h.4l.1-.4h-.5v.8"/>
<path d="M192.6 150.8l.5-.1v-.3l-.5-.1v.9M192.6 152.5l.5-.1v-.2l-.5-.1v.8M192.6 145.7l.5-.1v-.4h-.5v.8M192.6 147.4l.5-.1v-.3l-.5-.1v.9M192.6 149.1h.4l.1-.4-.5-.1v.9M192.6 154.2h.4l.1-.3-.5-.1v.8M193 159.9h.6M193.4 142.6v-.8l.4 .6 .2-.6v.8M193.4 144.3v-.8l.4 .6 .2-.6v.8M193.4 151.2v-.9l.4 .7 .2-.7v.9M193.4 152.9v-.8l.4 .6 .2-.6v.8M193.4 146v-.8l.4 .6 .2-.6v.8"/>
<path d="M193.4 147.8v-.9l.4 .6 .2-.6v.9M193.4 149.5v-.9l.4 .6 .2-.6v.9M193.4 140.5h.4l.1-.3-.1-.2h-.4v.8M193.4 154.6v-.8l.4 .6 .2-.6v.8M193.8 159l.1 .8 .2-.6 .2 .6 .1-.8M194.3 140.8v-.8l.2 .6 .4-.6v.8M194.4 141.8v.8M194.4 143.5v.8M194.4 145.2v.8M194.4 146.9v.9M194.4 148.6v.9M194.4 150.3v.9"/>
<path d="M194.4 152.1v.8M194.4 153.8v.8M194.8 159.4h.3M194.9 141.8h.3a.48 .48 0 0 1 .1 .5 .48 .48 0 0 1-.4 .3zM194.9 143.5h.4l.1 .5-.2 .3h-.3zM194.9 150.3a.49 .49 0 0 1 .4 .3 .49 .49 0 0 1-.1 .6h-.3zM194.9 152.1h.3a.48 .48 0 0 1 .1 .5 .48 .48 0 0 1-.4 .3zM194.9 145.2a.49 .49 0 0 1 .4 .3 .49 .49 0 0 1-.1 .5h-.3zM194.9 146.9h.3a.48 .48 0 0 1 .1 .6 .48 .48 0 0 1-.4 .3zM194.9 148.6l.4 .1 .1 .4-.2 .4h-.3zM194.9 153.8l.4 .1 .1 .4-.2 .3h-.3zM195.2 159h-.4v.8h.4"/>
<path d="M195.6 141.8l.6 .8M195.6 143.5l.6 .8M195.6 150.3l.6 .9M195.6 152.1l.6 .8M195.6 145.2l.6 .8M195.6 146.9l.6 .9M195.6 148.6l.6 .9M195.6 153.8l.6 .8M196.2 141.8l-.6 .8M196.2 143.5l-.6 .8M196.2 150.3l-.6 .9M196.2 152.1l-.6 .8"/>
<path d="M196.2 145.2l-.6 .8M196.2 146.9l-.6 .9M196.2 148.6l-.6 .9M196.2 153.8l-.6 .8M196.5 141.9l.2-.1v.8M196.5 143.7l.2-.2v.8M196.5 150.6l.2-.3v.9M196.5 152.4l.2-.3v.8M196.5 145.4l.2-.2v.8M196.5 147.1l.2-.2v.9M196.5 148.9l.2-.3v.9M196.5 154l.2-.2v.8"/>
<path d="M196.5 142.6h.5M196.5 144.3h.5M196.5 146h.5M196.5 151.2h.5M196.5 147.8h.5M196.5 149.5h.5M196.5 152.9h.5M196.5 154.6h.5M197.2 146.9h.6l-.3 .3 .3 .2v.2l-.1 .2-.5-.1M197.2 153.8h.6l-.3 .8M197.3 141.9l.2-.1a.43 .43 0 0 1 .3 .4 .43 .43 0 0 1-.3 .4l-.2-.2zM197.3 143.7l.3-.2v.8"/>
<path d="M197.3 145.2h.4l.1 .2-.6 .6h.6M197.3 144.3h.5M197.5 148.5l-.2 .7h.5M197.7 150.3h-.4v.4h.4l.1 .1-.1 .4-.4-.1M197.7 152.1l-.4 .2v.6h.4l.1-.4-.1-.1-.4 .1M197.7 148.9v.6M197.8 140.4l-.5 .1v-.4l.4-.1 .1 .2-.1 .6h-.3M218.1 142.2h.4l.1-.4h-.5v.8M218.1 143.9h.5v-.4h-.5v.8M218.1 140.5l.5-.1-.1-.4h-.4v.8M218.1 145.7l.5-.1-.1-.4h-.4v.8M218.1 150.8l.5-.1-.1-.4h-.4v.9"/>
<path d="M218.1 147.4l.5-.1v-.4h-.5v.9M218.1 149.1h.5v-.5h-.5v.9M219 142.6v-.8l.2 .6 .4-.6v.8M219 144.3v-.8l.2 .6 .4-.6v.8M219 140.8v-.8l.2 .6 .4-.6v.8M219 146v-.8l.2 .6 .4-.6v.8M219 151.2v-.9l.2 .7 .4-.7v.9M219 147.8v-.9l.2 .6 .4-.6v.9M219 149.5v-.9l.2 .6 .4-.6v.9M219.9 142.1h.4M219.9 143.9h.4M219.9 140.4h.4"/>
<path d="M219.9 145.6h.4M219.9 150.7h.4M219.9 147.3h.4M219.9 149.1h.4M220.3 141.8h-.4v.8h.4M220.3 143.5h-.4v.8h.4M220.3 145.2h-.4v.8h.4M220.3 150.3h-.4v.9h.4M220.3 146.9h-.4v.9h.4M220.3 148.6h-.4v.9h.4M220.5 142.7h.7M220.5 144.4h.7"/>
<path d="M220.5 140.9h.7M220.5 146.1h.7M220.5 151.3h.7M220.5 147.9h.7M220.5 149.6h.7M221.4 142.2l.5-.1v-.2l-.5-.1v.8M221.4 143.9h.4l.1-.4h-.5v.8M221.4 140.5l.5-.1v-.3l-.5-.1v.8M221.4 145.7l.5-.1v-.4h-.5v.8M221.4 150.8l.5-.1v-.3l-.5-.1v.9M221.4 147.4l.5-.1v-.3l-.5-.1v.9M221.4 149.1h.4l.1-.4-.5-.1v.9"/>
<path d="M222.3 142.1h.2M222.3 143.9h.2M222.3 140.4h.2M222.3 145.6h.2M222.3 150.7h.2M222.3 147.3h.2M222.3 149.1h.2M222.6 141.8h-.3v.8M222.6 143.5h-.3v.8M222.6 145.2h-.3v.8M222.6 150.3h-.3v.9M222.6 146.9h-.3v.9"/>
<path d="M222.6 148.6h-.3v.9M223.5 141.8v.8l-.5-.8v.8M223.5 143.5v.8l-.5-.8v.8M223.5 145.2v.8l-.5-.8v.8M223.5 150.3v.9l-.5-.9v.9M223.5 146.9v.9l-.5-.9v.9M223.5 148.6v.9l-.5-.9v.9M223.8 141.9l.3-.1v.8M223.8 143.7l.3-.2v.8M223.8 145.4l.3-.2v.8M223.8 150.6l.3-.3v.9M223.8 147.1l.3-.2v.9"/>
<path d="M223.8 148.9l.3-.3v.9M223.8 142.6h.5M223.8 144.3h.5M223.8 146h.5M223.8 151.2h.5M223.8 147.8h.5M223.8 149.5h.5M224.3 140.4h-.5l.2-.4 .3 .1v.6l-.4 .1M224.7 143.7l.2-.2v.8M224.7 145.2h.3l.2 .1-.5 .7h.5M224.7 146.9h.5l-.3 .3 .3 .2v.2l-.2 .2-.3-.1M224.7 144.3h.5"/>
<path d="M224.8 141.8a.46 .46 0 0 1 .4 .3 .46 .46 0 0 1-.2 .5 .48 .48 0 0 1-.3-.4 .48 .48 0 0 1 .1-.4zM224.9 148.5l-.2 .7h.5M225.1 150.3h-.4v.4h.3l.2 .1-.1 .4-.4-.1M225.1 148.9v.6M60.3 174h.4l.1-.3-.5-.1v.9M60.3 177.5l.5-.1v-.2l-.5-.1v.8M60.3 175.8l.5-.1v-.3l-.5-.1v.8M60.3 170.6h.5v-.4l-.5-.1v.9M60.3 172.3h.5v-.3l-.5-.1v.9M60.3 167.2l.5-.1v-.3l-.5-.1v.9M60.3 168.9h.4l.1-.4-.5-.1v.9M60.3 179.2h.4l.1-.3-.5-.1v.8"/>
<path d="M61.3 174.5v-.9l.2 .6 .3-.6v.9M61.3 177.9v-.8l.2 .6 .3-.6v.8M61.3 176.1v-.8l.2 .7 .3-.7v.8M61.3 171v-.9l.2 .7 .3-.7v.9M61.3 172.8v-.9l.2 .6 .3-.6v.9M61.3 167.6v-.9l.2 .6 .3-.6v.9M61.3 169.3v-.9l.2 .6 .3-.6v.9M61.3 179.6v-.8l.2 .6 .3-.6v.8M62.2 179.2h.3M62.2 174h.3M62.2 172.3h.3M62.2 170.6h.3"/>
<path d="M62.2 177.4h.3M62.2 175.7h.3M62.2 167.1h.3M62.2 168.9h.3M62.6 173.6h-.4v.9h.4M62.6 177.1h-.4v.8h.4M62.6 175.3h-.4v.8h.4M62.6 170.1h-.4v.9h.4M62.6 171.9h-.4v.9h.4M62.6 166.7h-.4v.9h.4M62.6 168.4h-.4v.9h.4M62.6 178.8h-.4v.8h.4"/>
<path d="M63.5 173.6h-.4l-.2 .2v.5l.2 .2h.4v-.4h-.2M63.5 177.1h-.4l-.2 .1v.5l.3 .2 .3-.1v-.3h-.2M63.5 175.4l-.3-.1-.3 .3v.4l.2 .1h.4v-.3h-.2M63.5 170.2l-.3-.1-.3 .3v.4l.2 .2h.4v-.4h-.2M63.5 171.9h-.4l-.2 .2v.4l.3 .3 .3-.1v-.4h-.2M63.5 166.7h-.4l-.2 .2v.4l.3 .3 .3-.1v-.3h-.2M63.5 168.4h-.4l-.2 .2v.5l.2 .2h.4v-.4h-.2M63.5 178.8h-.4l-.2 .1v.5l.2 .2h.4v-.3h-.2M63.8 170.2l.3-.1 .2 .2-.5 .7h.5M63.8 171.9h.5l-.3 .3 .3 .1v.3l-.2 .2-.3-.1M63.8 168.7l.2-.3v.9M63.8 178.8h.5l-.3 .8"/>
<path d="M63.8 169.3h.5M63.9 166.8l.1-.1a.47 .47 0 0 1 .3 .5 .47 .47 0 0 1-.3 .4l-.2-.3zM64 173.5l-.2 .7h.5M64.2 177.1h-.2l-.2 .3v.4l.3 .1 .2-.4-.2-.2-.3 .2M64.2 175.3h-.3l-.1 .4 .3-.1 .2 .5h-.5M64.2 173.9v.6M88.3 179.2h.4v-.4h-.4v.8M88.3 174h.4v-.4h-.4v.9M88.3 172.3h.3l.2-.1-.1-.3h-.4v.9M88.3 170.6h.3l.2-.3-.2-.2h-.3v.9M88.3 177.5h.3l.2-.2-.1-.2h-.4v.8M88.3 175.8h.3l.2-.2-.2-.3h-.3v.8"/>
<path d="M89.1 179.6v-.8l.3 .6 .3-.6v.8M89.1 174.5v-.9l.3 .6 .3-.6v.9M89.1 172.8v-.9l.3 .6 .3-.6v.9M89.1 171v-.9l.3 .7 .3-.7v.9M89.1 177.9v-.8l.3 .6 .3-.6v.8M89.1 176.1v-.8l.3 .7 .3-.7v.8M89.1 167.2l.4-.1-.1-.4h-.3v.9M89.1 168.9l.4-.1-.1-.4h-.3v.9M90 167.6v-.9l.2 .6 .3-.6v.9M90 169.3v-.9l.2 .6 .3-.6v.9M90.1 179.2h.3M90.1 174h.3"/>
<path d="M90.1 172.3h.3M90.1 170.6h.3M90.1 177.4h.3M90.1 175.7h.3M90.5 178.8h-.4v.8h.4M90.5 173.6h-.4v.9h.4M90.5 171.9h-.4v.9h.4M90.5 170.1h-.4v.9h.4M90.5 177.1h-.4v.8h.4M90.5 175.3h-.4v.8h.4M90.6 179.7h.7M90.6 174.5h.7"/>
<path d="M90.6 172.8h.7M90.6 171.1h.7M90.6 178h.7M90.6 176.2h.7M90.9 167.1h.3M90.9 168.9h.3M91.3 166.7h-.4v.9h.4M91.3 168.4h-.4v.9h.4M91.5 167.7h.7M91.5 169.4h.7M91.6 179.2l.4-.1-.1-.3h-.3v.8M91.6 174h.3l.1-.3-.4-.1v.9"/>
<path d="M91.6 172.3h.4l-.1-.4h-.3v.9M91.6 170.6h.4v-.4l-.4-.1v.9M91.6 177.5l.4-.1v-.2l-.4-.1v.8M91.6 175.8l.4-.1v-.3l-.4-.1v.8M92.3 167.2l.5-.1v-.3l-.5-.1v.9M92.3 168.9h.4l.1-.4-.5-.1v.9M92.4 179.2h.3M92.4 174h.3M92.4 172.3h.3M92.4 170.6h.3M92.4 177.4h.3M92.4 175.7h.3"/>
<path d="M92.8 178.8h-.4v.8M92.8 173.6h-.4v.9M92.8 171.9h-.4v.9M92.8 170.1h-.4v.9M92.8 177.1h-.4v.8M92.8 175.3h-.4v.8M93.2 167.1h.3M93.2 168.9h.3M93.6 178.8v.8l-.5-.8v.8M93.6 173.6v.9l-.5-.9v.9M93.6 171.9v.9l-.5-.9v.9M93.6 170.1v.9l-.5-.9v.9"/>
<path d="M93.6 177.1v.8l-.5-.8v.8M93.6 175.3v.8l-.5-.8v.8M93.6 166.7h-.4v.9M93.6 168.4h-.4v.9M94 179l.3-.2v.8M94 173.9l.3-.3v.9M94 172.1l.3-.2v.9M94 170.4l.3-.3v.9M94 177.3l.3-.2v.8M94 175.6l.3-.3v.8M94 179.6h.4M94 174.5h.4"/>
<path d="M94 172.8h.4M94 171h.4M94 177.9h.4M94 176.1h.4M94.4 166.7v.9l-.5-.9v.9M94.4 168.4v.9l-.5-.9v.9M94.8 173.7h.5v.2l-.5 .6h.5M94.8 172.1l.2-.2v.9M94.8 175.3h.5l-.3 .3 .3 .1v.4h-.5M94.8 172.8h.5M94.9 170.2l.2-.1 .2 .2-.1 .7h-.2l-.2-.3zM95 167.1l-.2-.3 .4-.1 .1 .3-.4 .1-.1 .2 .2 .3 .3-.1v-.3l-.2-.1"/>
<path d="M95 177l-.2 .6h.6M95.2 177.3v.6M95.3 178.8h-.4l-.1 .4 .4-.1 .1 .4h-.5M95.3 168.8l-.1 .1h-.3v-.5l.4 .1v.6l-.4 .2M118.3 177.5l.5-.1v-.2l-.5-.1v.8M118.3 179.2h.4l.1-.3-.5-.1v.8M118.3 174h.4l.1-.3-.5-.1v.9M118.3 172.3h.5v-.3l-.5-.1v.9M118.3 170.6h.5v-.4l-.5-.1v.9M118.3 175.8l.5-.1v-.3l-.5-.1v.8M118.3 168.9h.4l.1-.4-.5-.1v.9M118.3 167.2l.5-.1v-.3l-.5-.1v.9"/>
<path d="M119.2 177.9v-.8l.3 .6 .3-.6v.8M119.2 179.6v-.8l.3 .6 .3-.6v.8M119.2 174.5v-.9l.3 .6 .3-.6v.9M119.2 172.8v-.9l.3 .6 .3-.6v.9M119.2 171v-.9l.3 .7 .3-.7v.9M119.2 176.1v-.8l.3 .7 .3-.7v.8M119.2 169.3v-.9l.3 .6 .3-.6v.9M119.2 167.6v-.9l.3 .6 .3-.6v.9M120.2 179.2h.3M120.2 174h.3M120.2 172.3h.3M120.2 170.6h.3"/>
<path d="M120.2 177.4h.3M120.2 175.7h.3M120.2 167.1h.3M120.2 168.9h.3M120.6 177.1h-.4v.8h.4M120.6 178.8h-.4v.8h.4M120.6 173.6h-.4v.9h.4M120.6 171.9h-.4v.9h.4M120.6 170.1h-.4v.9h.4M120.6 175.3h-.4v.8h.4M120.6 168.4h-.4v.9h.4M120.6 166.7h-.4v.9h.4"/>
<path d="M120.8 179.7h.7M120.8 174.5h.7M120.8 172.8h.7M120.8 171.1h.7M120.8 178h.7M120.8 176.2h.7M120.8 167.7h.7M120.8 169.4h.7M121.6 177.5h.4l.1-.2-.1-.2h-.4v.8M121.6 179.2h.4v-.4h-.4v.8M121.6 174h.4v-.4h-.4v.9M121.6 172.3h.4l.1-.1-.1-.3h-.4v.9"/>
<path d="M121.6 170.6h.4l.1-.3-.1-.2h-.4v.9M121.6 175.8h.4l.1-.2-.1-.3h-.4v.8M121.6 168.9h.4v-.5h-.4v.9M121.6 167.2h.4l.1-.4-.5-.1v.9M122.5 179.2h.3M122.5 174h.3M122.5 172.3h.3M122.5 170.6h.3M122.5 177.4h.3M122.5 175.7h.3M122.5 167.1h.3M122.5 168.9h.3"/>
<path d="M122.9 177.1h-.4v.8M122.9 178.8h-.4v.8M122.9 173.6h-.4v.9M122.9 171.9h-.4v.9M122.9 170.1h-.4v.9M122.9 175.3h-.4v.8M122.9 168.4h-.4v.9M122.9 166.7h-.4v.9M123.7 177.1v.8l-.5-.8v.8M123.7 178.8v.8l-.5-.8v.8M123.7 173.6v.9l-.5-.9v.9M123.7 171.9v.9l-.5-.9v.9"/>
<path d="M123.7 170.1v.9l-.5-.9v.9M123.7 175.3v.8l-.5-.8v.8M123.7 168.4v.9l-.5-.9v.9M123.7 166.7v.9l-.5-.9v.9M124.1 178.8h.6l-.5 .8M124.1 171.9h.5l-.3 .3 .3 .1v.4h-.5M124.1 170.2h.5v.4l-.5 .4h.5M124.1 168.7l.2-.3v.9M124.1 169.3h.5M124.2 166.8h.4v.6l-.2 .2-.2-.1-.1-.2zM124.3 173.5l-.2 .7h.6M124.5 177.1h-.3l-.1 .7 .1 .1 .4-.1v-.4l-.4-.1-.1 .2"/>
<path d="M124.5 173.9v.6M124.6 175.3h-.4l-.1 .4h.5v.4h-.5M150.7 162.2h5M150.8 162.9h.4l.1-.4-.5-.1v.9M150.9 163.9h4.8M151 164.5h.4l.1-.2-.2-.2h-.3v.9M151.7 163.3v-.9l.2 .6 .4-.6v.9M151.8 165v-.9l.4 .6 .2-.6v.9M152.6 162.4v.7l.2 .2 .3-.1v-.8M152.9 164.1v.9h.4l.1-.9M153.4 163.4h.6M153.5 165.1h.7"/>
<path d="M154.2 162.4v.8l.2 .1 .3-.2v-.7M154.4 164.1v.9h.4M155.1 164.5h.3l.2-.1-.2-.3h-.3v.9h.4l.1-.4-.2-.1M155.1 162.9h.3l.2-.2-.1-.3h-.4v.9l.5-.1v-.3h-.2M190.5 162.2h4.8M190.6 162.9h.4v-.5h-.4v.9M190.7 163.9h4.6M190.8 164.5h.4l.1-.3-.5-.1v.9M191.5 163.3v-.9l.3 .6 .3-.6v.9M191.7 165v-.9l.3 .6 .2-.6v.9M192.5 162.4v.9h.4M192.7 164.1v.9h.4"/>
<path d="M193 163.4h.6M193.2 165.1h.6M193.8 162.4v.8l.2 .1 .3-.2v-.7M194 164.1v.9h.4M194.7 164.5h.3l.2-.1-.2-.3h-.3v.9h.4l.1-.4-.2-.1M194.7 162.9h.3l.2-.2-.1-.3h-.4v.9l.5-.1v-.3h-.2M59.6 184.5h3.9M60.2 184.9l-.4-.1-.2 .2 .1 .2 .5 .1v.2l-.6 .1M60.5 185.6v-.8l.3 .6 .3-.6v.8M61.9 184.9h-.4v.3l.4 .1-.1 .3h-.3M62.4 185.2h.2M62.8 184.8h-.4v.8h.4"/>
<path d="M63.1 184.8v.8h.4M89.9 184.5h4.6M90 185.2h.5v-.3l-.5-.1v.8M90.8 185.6v-.8l.3 .6 .3-.6v.8M91.8 184.8v.8h.4M93 184.9h-.5l.1 .3 .4 .2-.1 .2h-.4M93.3 185.2h.3M93.8 184.8h-.5v.8h.5M94.1 184.8v.8h.4M119.2 184.5h4.6M119.2 185.2h.5l.1-.2-.2-.2h-.4v.8M120.1 185.6v-.8l.3 .6 .3-.6v.8"/>
<path d="M121.1 184.8v.8h.4M122.2 184.9h-.4l.1 .3 .3 .1-.1 .3h-.3M122.6 185.2h.3M123.1 184.8h-.5v.8h.5M123.4 184.8v.8h.4"/>
</g>
<g fill="none" stroke="#b90000" stroke-width=".21">
<path d="M107.4 18.4a.48 .48 0 0 1 .5-.2 .48 .48 0 0 1 .3 .4l-.1 .2h-.5l-.2-.1zM108.2 19.1v.5l-.5-.5-.3 .1 .1 .4M137.5 18.3l.2 .5h.6l.1-.4-.4-.2v.6M138.4 19.3h-.9l.3 .3M138.4 19.1v.5M167.7 18.3l.1 .5h.6l.1-.4-.4-.2v.6M168.5 19.3h-.8l.2 .3M168.5 19.1v.5M197.8 18.3l.2 .5h.6l.1-.4-.2-.2-.3 .1v.4l.1 .1M198.7 19.3h-.9l.3 .3M198.7 19.1v.5M228.8 18.3l.2 .5h.6l.1-.5h-.6v.4l.2 .1"/>
<path d="M229.7 19.3h-.9l.3 .3M229.7 19.1v.5M260.6 18.3l.3 .5h.6l.1-.4-.2-.2-.4 .2 .2 .4M261.6 19.3h-1l.3 .3M261.6 19.1v.5M35.6 28.5l-.2-.1 .2-.3 .3 .1v.3l-.5 .2 .1 .3 .4-.1v-.3l-.1-.1M35.6 32l-.2-.2 .1-.2 .4 .1v.3l-.5 .1 .2 .4 .3-.1v-.4h-.1M35.6 33.7l-.2-.1 .2-.3 .3 .1v.3l-.5 .1 .1 .4 .4-.1v-.4h-.1M35.9 35.3l.2-.3v.9M35.9 36.9l.4-.1 .1 .2-.5 .6h.5M35.9 35.9h.5M35.9 30.3l-.3 .1-.2-.4 .2-.2 .3 .1v.8l-.4 .1"/>
<path d="M36 38.5l-.1 .6h.5M36.2 31.6h.6l-.4 .9M36.3 30l.1-.2a.48 .48 0 0 1 .4 .5 .48 .48 0 0 1-.4 .5l-.1-.2zM36.3 38.8v.5M36.4 33.7h-.1v-.3l.3-.1 .2 .3-.2 .1h-.3l.1 .5h.3l.1-.4-.2-.1M36.8 28.5l-.1 .2h-.3l-.1-.5 .3-.1 .2 .2-.2 .7h-.2M46.2 23.1v-.5l.3 .2 .1-.2h.4v.5M46.6 21.7l.2 .2-.2 .3-.4-.1 .1-.4h.6l.1 .1v.3M48.3 22.6l.2 .1-.1 .3h-.4v-.4h.6l.2 .3M48.8 22h-.8l.2 .2M48.8 21.7v.5M51.3 22.6v-.5l.4 .3 .1-.3h.4v.5"/>
<path d="M53.5 21.9v-.2h.4l.1 .2-.2 .3h-.2l-.1-.4-.3-.1-.1 .4 .2 .1 .2-.1M54 22.7h-.9l.3 .3M54 22.6v.4M54.8 23.1v-.5l.4 .2v-.2h.4v.5M55.1 21.8h.6M55.4 21.6v.6l-.6-.2M56.5 22.6v.4h.4v-.4h.5v.4M57.4 22h-.9l.3 .2M57.4 21.7v.5M58.3 22.6l.2 .4h.6v-.4h-.5v.3l.2 .1M58.3 21.8v.3l.7 .1 .1-.1v-.4l-.5 .1v.3l.2 .1M60.3 22.7l.1-.1h.3l.1 .3-.4 .1-.1-.4h-.2v.4l.2-.2"/>
<path d="M60.8 21.7v.5l-.5-.5h-.2l-.1 .2 .1 .3M71.2 31.9l.3-.3v.9M71.2 32.5h.5M72.1 31.7l.3-.1 .1 .2v.5l-.2 .2a.48 .48 0 0 1-.2-.8zM72.1 33.7h-.5l.2-.4 .3 .1v.6l-.4 .2M72.1 35.4l-.3 .2-.2-.4 .2-.2 .3 .1-.1 .8h-.3M72.1 37.1l-.1 .2h-.3v-.5l.4 .1v.6l-.4 .1M72.1 38.9h-.5l.2-.4 .3 .1v.6l-.4 .1M72.4 36.8h.5l-.3 .8M72.6 35.4l-.2-.2 .2-.2 .3 .1v.2l-.4 .1-.1 .2 .2 .3h.3v-.4l-.1-.1M72.9 38.5l-.3 .1-.2 .6 .1 .1 .4-.1v-.3l-.3-.1-.2 .2M72.9 31.6a.39 .39 0 0 1 .5 .4 .39 .39 0 0 1-.5 .4z"/>
<path d="M72.9 33.7h-.5l.2-.4 .3 .1v.6l-.4 .2M100.9 28.4l.2-.3v.9M100.9 30.1l.2-.3v1M100.9 31.9l.2-.3v.9M100.9 33.6l.2-.3v.9M100.9 37l.2-.2v.8M100.9 32.5h.5M100.9 34.2h.5M100.9 37.6h.5M100.9 29h.5M100.9 30.8h.5M101.3 21.3h.5l-.2 .3 .2 .1v.4h-.5"/>
<path d="M101.3 24.7h.6l-.4 .9M101.3 38.7l.3-.2v.8M101.3 39.3h.5M101.5 26.8l-.2-.2 .1-.1h.3l.1 .2-.5 .3 .2 .3 .3-.1v-.3l-.2-.1M101.6 23l-.3 .6h.6M101.7 28.1h.5l-.3 .4h.2v.5l-.4-.1M101.7 31.6h.5l-.3 .9M101.7 37l.3-.2v.8M101.7 23.2v.6M101.7 37.6h.5M101.9 29.8l-.2 .6h.5M101.9 33.7l-.2-.2 .4-.2 .1 .3-.5 .2 .1 .4h.3l.1-.4-.1-.1"/>
<path d="M102.1 30.2v.6M114.7 28.4l.2-.3v.9M114.7 30.1l.2-.3v1M114.7 31.9l.2-.3v.9M114.7 33.6l.2-.3v.9M114.7 32.5h.5M114.7 34.2h.5M114.7 29h.5M114.7 30.8h.5M115.1 21.4l.4-.1 .1 .2-.6 .6h.6M115.5 23h-.4v.4l.4-.1v.5l-.4-.1M115.5 24.7l-.4 .2v.6l.3 .1 .2-.2-.2-.4-.3 .2"/>
<path d="M115.5 28.2l.4-.1 .1 .3-.6 .6h.6M115.6 26.8l-.1 .2h-.3l-.1-.5h.4l.1 .1-.1 .5-.3 .2M115.9 29.8h-.4v.5l.4-.1 .1 .4-.1 .2-.4-.1M115.9 31.6l-.4 .2v.6l.4 .1 .1-.2-.1-.3h-.3l-.1 .1M116 33.7l-.4 .1-.1-.4 .4-.1 .1 .2-.1 .7h-.3M131 31.9l.3-.3v.9M131 33.6l.3-.3v.9M131 37l.3-.2v.8M131 38.7l.3-.2v.8M131 32.5h.5M131 34.2h.5M131 37.6h.5"/>
<path d="M131 39.3h.5M131.4 21.4h.5v.2l-.5 .5h.5M131.4 23h.5l-.2 .3 .2 .1v.3h-.5M131.9 28.1l-.5 .4v.3l.1 .2 .4-.1v-.4h-.4l-.1 .2M131.9 31.9l.2-.3v.9M131.9 38.5h.5l-.3 .3 .3 .2-.1 .3-.4-.1M131.9 32.5h.5M131.9 26.5h-.4l-.1 .4 .5-.1v.4h-.5M131.9 33.4h.1a.34 .34 0 0 1 .4 .4 .34 .34 0 0 1-.5 .3zM132.1 36.7l-.2 .7h.5M132.3 37v.6M144.8 37l.3-.2v.8"/>
<path d="M144.8 37.6h.5M145.2 26.5h.6l-.4 .8M145.4 21.2l-.2 .7h.6M145.7 36.9l.4-.1 .1 .2-.6 .6h.6M145.7 21.5v.6M145.8 32l-.1 .1h-.4l-.1-.4 .5-.1 .1 .2-.1 .5-.4 .2M161.2 31.9l.2-.3v.9M161.2 33.6l.2-.3v.9M161.2 37l.2-.2v.8M161.2 38.7l.2-.2v.8M161.2 32.5h.5M161.2 34.2h.5"/>
<path d="M161.2 37.6h.5M161.2 39.3h.5M161.6 21.4h.5v.2l-.5 .5h.5M161.6 23h.5l-.3 .3 .3 .1v.3h-.5M162 28.1l-.4 .4v.3l.1 .2 .4-.1-.1-.4h-.3l-.1 .2M162 31.9l.3-.3v.9M162 38.5h.5l-.2 .3 .2 .2-.1 .3-.4-.1M162 32.5h.5M162.1 26.5h-.4l-.1 .4 .4-.1 .1 .4h-.5M162.1 33.4h.3v.8l-.3-.1zM162.3 36.7l-.3 .7h.5M162.4 37v.6"/>
<path d="M175 37l.2-.2v.8M175 37.6h.5M175.4 26.5h.5l-.3 .8M175.6 21.2l-.2 .7h.5M175.8 36.9l.4-.1 .1 .2-.6 .6h.6M175.8 21.5v.6M175.9 32l-.1 .1h-.3v-.5h.3l.1 .2-.1 .5-.3 .2M191.3 31.9l.3-.3v.9M191.3 33.6l.3-.3v.9M191.3 37l.3-.2v.8M191.3 38.7l.3-.2v.8M191.3 32.5h.5"/>
<path d="M191.3 34.2h.5M191.3 37.6h.5M191.3 39.3h.5M191.7 21.4h.5v.2l-.5 .5h.5M191.7 23h.5l-.2 .3 .2 .1v.3h-.5M192.1 28.1l-.4 .4v.3l.1 .2 .4-.1-.1-.4h-.3l-.1 .2M192.1 31.9l.3-.3v.9M192.1 38.5h.6l-.3 .3 .3 .1v.3h-.6M192.1 32.5h.6M192.2 26.5h-.4l-.1 .4 .4-.1 .1 .4h-.5M192.2 33.4l.3-.1 .2 .2-.1 .6a.39 .39 0 0 1-.5-.2 .39 .39 0 0 1 .1-.5zM192.4 36.7l-.3 .7h.6"/>
<path d="M192.6 37v.6M205.1 37l.3-.2v.8M205.1 37.6h.5M205.5 26.5h.5l-.3 .8M205.8 21.2l-.3 .7h.5M205.9 36.9l.5-.1 .1 .2-.6 .6h.6M205.9 21.5v.6M206 32l-.1 .1h-.3v-.5h.3l.1 .2-.1 .5-.3 .2M222.4 31.9l.2-.3v.9M222.4 33.6l.2-.3v.9M222.4 37l.2-.2v.8M222.4 38.7l.2-.2v.8"/>
<path d="M222.4 32.5h.5M222.4 34.2h.5M222.4 37.6h.5M222.4 39.3h.5M222.7 23h.5l-.2 .3 .2 .1v.3h-.5M222.8 21.4l.3-.1 .1 .3-.5 .5h.5M223.1 28.1l-.3 .3v.5h.4l-.1-.4h-.2l-.1 .2M223.1 31.9l.3-.3v.9M223.1 38.5h.5l-.2 .3 .2 .1v.3h-.5M223.1 32.5h.5M223.2 26.5h-.4v.4l.3-.1 .1 .4h-.4M223.2 33.4l.3-.1 .1 .2v.6a.39 .39 0 0 1-.5-.2 .39 .39 0 0 1 .1-.5z"/>
<path d="M223.4 36.7l-.3 .7h.6M223.6 37v.6M236.1 37l.2-.2v.8M236.1 37.6h.5M236.5 26.5h.6l-.4 .8M236.8 21.2l-.3 .7h.6M236.9 36.9l.5-.1v.2l-.5 .6h.5M236.9 21.5v.6M237 32l-.1 .1h-.3v-.5l.4 .1v.6l-.4 .2M254.2 31.9l.3-.3v.9M254.2 33.6l.3-.3v.9M254.2 37l.3-.2v.8"/>
<path d="M254.2 38.7l.3-.2v.8M254.2 32.5h.5M254.2 34.2h.5M254.2 37.6h.5M254.2 39.3h.5M254.5 23h.6l-.3 .3h.3v.5l-.6-.1M254.6 21.4l.5-.1v.2l-.6 .6h.6M255 38.5h.6l-.4 .3 .4 .2-.1 .3-.5-.1M255.1 26.5h-.5v.4l.5-.1v.3l-.1 .2-.4-.1M255.1 28.1l-.5 .3v.5l.5 .1v-.5h-.4l-.1 .2M255.1 31.9l.2-.3v.9M255.1 32.5h.5"/>
<path d="M255.2 33.3a.43 .43 0 0 1 .4 .5 .43 .43 0 0 1-.5 .4v-.7zM255.2 36.7l-.1 .7h.5M255.5 37v.6M268 37l.3-.2v.8M268 37.6h.5M268.3 26.5h.6l-.3 .8M268.6 21.2l-.2 .7h.5M268.9 36.9l.3-.1 .1 .3-.5 .5h.5M268.9 21.5v.6M268.9 32v.1h-.4l-.1-.4 .5-.1v.2v.5l-.4 .2M35.4 49.1l.3-.3v.9M35.4 50.8l.3-.2v.8"/>
<path d="M35.4 52.5l.3-.2v.8M35.4 54.2l.3-.2v.8M35.4 56l.3-.3v.9M35.4 57.7l.3-.3v.9M35.4 59.4l.3-.3v.9M35.4 49.7h.5M35.4 51.4h.5M35.4 53.1h.5M35.4 54.8h.5M35.4 56.6h.5M35.4 58.3h.5M35.4 60h.5"/>
<path d="M35.9 43.6h.5l-.4 .9M36 45.8l-.1-.3 .4-.1 .1 .2-.5 .3 .1 .4 .4-.2-.2-.3M36.2 52.3h.6l-.4 .3h.3l.1 .2-.1 .3-.5-.1M36.2 59.1h.6l-.4 .9M36.3 40.3h-.4v.3l.3-.1 .2 .4-.2 .2-.3-.1M36.3 41.9h-.3l-.1 .4v.5h.4v-.5h-.4v.2M36.3 50.7l.4-.1 .1 .2-.6 .6h.6M36.4 47.5l-.1 .1h-.4v-.5h.4l.1 .2-.2 .7h-.3M36.4 48.8a.43 .43 0 0 1 .4 .5 .43 .43 0 0 1-.4 .4l-.1-.7zM36.4 54l-.1 .6h.5M36.7 55.7h-.4v.4h.4l.1 .3-.2 .2-.3-.1M36.7 57.4l-.4 .2v.6l.4 .1v-.5h-.3l-.1 .2"/>
<path d="M36.7 54.3v.5M71.6 54h.6l-.4 .8M71.6 55.7h.6l-.4 .9M71.6 57.4h.6l-.4 .9M71.6 59.1h.6l-.4 .9M71.8 45.8l-.2-.2 .1-.2 .4 .1v.2l-.4 .1-.1 .1 .2 .4 .3-.1v-.4h-.2M71.8 47.5l-.2-.2 .1-.2 .4 .1-.1 .3-.4 .1 .1 .4 .4-.1v-.4h-.2M71.8 49.2l-.2-.1 .2-.3 .3 .1v.2l-.4 .1v.5l.4-.1v-.3l-.2-.1M71.8 50.9l-.2-.1 .1-.2 .4 .1v.1l-.4 .1-.1 .2 .2 .3 .3-.1v-.3l-.2-.1M71.8 52.6l-.2-.2 .1-.1h.3l.1 .2-.5 .3 .1 .3 .4-.1v-.3l-.2-.1M72.1 40.6l-.3 .2-.2-.5h.5l-.1 .7-.3 .1M72.1 42.3l-.1 .2h-.3v-.6l.4 .1v.6l-.4 .2"/>
<path d="M72.1 44.1l-.2 .1-.3-.1 .2-.5 .3 .1v.6l-.4 .2M72.4 41.9h.5l-.2 .4 .2 .1v.3h-.5M72.4 43.7h.5v.4l-.5 .4h.5M72.4 48.8h.5l-.2 .3 .2 .1v.4h-.5M72.4 50.8l.3-.2v.8M72.4 57.4h.5l-.3 .9M72.4 51.4h.5M72.6 52.3h.3v.1v.6a.39 .39 0 0 1-.5-.2 .39 .39 0 0 1 .1-.4zM72.6 56.1l-.2-.2 .1-.2h.4v.3l-.4 .1-.1 .2 .2 .3 .3-.1v-.3l-.1-.1M72.7 40.2l-.3 .6h.5M72.7 47l-.3 .7h.5M72.9 59.1l-.3 .1-.2 .7 .5 .1v-.4l-.3-.1-.2 .1"/>
<path d="M72.9 40.5v.6M72.9 47.4v.6M72.9 45.4h-.4l-.1 .4h.5v.4h-.5M72.9 54.4l-.1 .2-.4-.2 .2-.4 .3 .1v.5l-.4 .2M101.3 57.4h.5l-.2 .4 .2 .1v.3h-.5M101.6 59.1l-.3 .6h.6M101.7 59.5v.5M107.4 42.5l.5-.1 .3 .1a.43 .43 0 0 1-.4 .4 .43 .43 0 0 1-.4-.4zM107.4 54.6a.48 .48 0 0 1 .5-.2 .48 .48 0 0 1 .3 .3l-.1 .2h-.5l-.2-.1zM108.2 43.5h-.8l.2 .2M108.2 55.2v.5l-.6-.5-.2 .1 .1 .4M108.2 43.2v.5"/>
<path d="M115.1 57.5l.4-.1 .1 .3-.6 .6h.6M115.5 59.1h-.4v.5l.3-.1 .2 .4-.5 .1M131 43.9l.3-.3v.9M131 44.5h.5M131.4 42.2l.3-.3v.9M131.4 42.8h.5M132.3 43.6h-.4v.5l.3-.1 .2 .2-.1 .3-.4-.1M137.9 48.1l.1-.1h.3l.1 .1v.2l-.4 .2-.1-.1v-.4h-.3l-.1 .4 .2 .1 .2-.2M140 58.3h.6l-.4 .3 .4 .2-.1 .3h-.5M140.1 56.7l.4-.1 .1 .3-.6 .5h.6M146.1 53.6l.2 .5h.6l.1-.4-.1-.2-.5 .2 .2 .4M147 54.6h-.9l.2 .3"/>
<path d="M147 54.4v.5M154 56.5l-.1 .7h.5M154.3 56.9v.5M161.2 43.9l.2-.3v.9M161.2 44.5h.5M161.6 42.2l.2-.3v.9M161.6 42.8h.5M162.4 43.6h-.3l-.1 .5 .3-.1 .2 .2-.1 .3-.4-.1M168 48.1l.1-.1h.3l.1 .1v.2l-.3 .2-.3-.5h-.2v.4l.1 .1 .2-.2M171.1 56.7h.5v.2l-.5 .5h.5M171.1 58.3h.5l-.3 .3 .3 .1v.4h-.5M177.2 53.6l.1 .5h.6l.1-.4-.4-.2-.2 .2 .2 .4"/>
<path d="M178 54.6h-.8l.1 .3M178 54.4v.5M185 56.5l-.1 .7h.5M185.3 56.9v.5M191.3 43.9l.3-.3v.9M191.3 44.5h.5M191.7 42.2l.3-.3v.9M191.7 42.8h.5M192.7 43.6h-.5l-.1 .5h.6v.3h-.6M198.2 48.1v-.1h.4l.1 .1v.2l-.4 .2-.2-.5h-.3v.4l.2 .1 .2-.2M203.7 58.3h.6l-.3 .3 .3 .2v.3h-.6M203.8 56.7l.5-.1v.3l-.6 .5h.6"/>
<path d="M209.8 53.6l.3 .5h.5l.1-.5-.3-.1-.2 .2 .2 .4M210.7 54.6h-.9l.3 .3M210.7 54.4v.5M217.8 56.5l-.2 .7h.5M218 56.9v.5M222.4 43.9l.2-.3v.9M222.4 44.5h.5M222.8 42.2l.2-.3v.9M222.8 42.8h.4M223.6 43.6h-.4l-.1 .5h.5v.3h-.5M229.1 48.1l.1-.1h.5v.4l-.2 .1-.4-.2v-.3h-.3v.4l.2 .1 .1-.2M236.5 56.7h.5v.2l-.5 .5h.5"/>
<path d="M236.5 58.3h.5l-.2 .3 .2 .1v.4h-.5M242.6 53.6l.2 .5h.6l.1-.4-.2-.2-.4 .1v.4l.2 .1M243.5 54.6h-.9l.3 .3M243.5 54.4v.5M250.6 56.5l-.3 .7h.5M250.7 56.9v.5M254.2 43.9l.3-.3v.9M254.2 44.5h.5M254.6 42.2l.3-.3v.9M254.6 42.8h.5M255.5 43.6h-.4v.5l.3-.1 .2 .2-.1 .3-.4-.1M261.1 48.1l.1-.1h.3l.1 .1-.2 .4h-.2l-.1-.1-.1-.4h-.3l-.1 .3 .2 .2 .3-.2"/>
<path d="M35.4 61.2l.3-.3v.9M35.4 62.7h.5v.2l-.5 .6h.5M35.4 64.4h.5v.3l-.5 .5h.5M35.4 66.2h.5v.2l-.5 .5h.5M35.4 67.9h.5v.2l-.5 .5h.5M35.4 69.6h.5v.3l-.5 .5h.5M35.4 71.3h.5v.3l-.5 .5h.5M35.4 73h.5v.3l-.5 .5h.5M35.4 74.7h.5v.4l-.5 .5h.5M35.4 76.5h.5v.2l-.5 .6h.5M35.4 78.1h.5l-.2 .3 .2 .1v.4h-.5M35.4 79.8h.5l-.2 .3 .2 .1v.4h-.5"/>
<path d="M35.4 61.8h.5M36.2 67.8h.6l-.4 .3h.3v.5l-.5-.1M36.2 72.9h.6l-.4 .9M36.3 64.6l.2-.3v.9M36.3 66.2l.4-.1 .1 .2-.6 .6h.6M36.3 65.2h.5M36.4 62.6a.42 .42 0 0 1 .4 .4 .42 .42 0 0 1-.4 .5zM36.4 69.5l-.1 .6h.5M36.4 75.1l-.1-.1v-.3l.3-.1 .2 .3-.5 .2v.4l.1 .1 .4-.2-.2-.3M36.4 78.1a.43 .43 0 0 1 .4 .5 .43 .43 0 0 1-.4 .3l-.1-.6zM36.7 71.2h-.4v.5l.4-.1 .1 .3-.2 .2-.3-.1M36.7 69.8v.6"/>
<path d="M36.8 61.3l-.2 .1-.3-.1v-.3l.4-.1 .1 .2-.2 .6-.2 .1M36.8 76.7l-.1 .2h-.3l-.1-.4 .4-.1 .1 .2-.1 .5-.3 .2M71.6 60.9h.6l-.4 .9M71.6 62.6h.6l-.4 .9M71.6 64.3h.6l-.4 .9M71.6 66.1h.6l-.4 .8M71.6 67.8h.6l-.4 .8M72 69.5l-.2 .1-.2 .6 .2 .2 .3-.1v-.4l-.3-.1-.2 .2M72 71.2h-.2l-.2 .7 .2 .2 .3-.1-.1-.4h-.3l-.1 .2M72 72.9l-.4 .4v.3l.1 .2 .4-.1-.1-.4h-.3l-.1 .1M72 74.6l-.2 .1-.2 .7 .2 .2 .3-.1v-.4l-.3-.1-.2 .1M72 76.4h-.2l-.2 .7 .2 .2 .3-.1-.1-.5h-.3l-.1 .2"/>
<path d="M72 78.1l-.4 .3v.4l.1 .1h.4l-.1-.5h-.3l-.1 .2M72 79.8l-.2 .1-.2 .7 .2 .1 .3-.1v-.4l-.3-.1-.2 .2M72.4 62.6h.5l-.2 .3 .2 .1v.4h-.5M72.4 64.4h.5v.3l-.5 .5h.5M72.4 66.3l.3-.2v.8M72.4 72.9h.5l-.3 .9M72.4 78.1h.5l-.2 .3 .2 .1v.4h-.5M72.4 79.9h.5v.3l-.5 .5h.5M72.4 66.9h.5M72.5 67.9l.3-.1 .1 .1v.6a.39 .39 0 0 1-.5-.2 .39 .39 0 0 1 .1-.4zM72.6 71.6l-.2-.2 .1-.2h.4v.3l-.5 .3 .2 .3 .3-.1v-.3l-.1-.1M72.7 76.3l-.3 .7h.5"/>
<path d="M72.9 76.7v.6M72.9 60.9h-.4l-.1 .4h.5v.4h-.5M72.9 69.9l-.3 .2-.2-.5 .2-.1 .3 .1v.5l-.4 .3M72.9 74.6h-.4l-.1 .5h.5v.4h-.5M100.9 64.6l.2-.3v.9M100.9 66.3l.2-.2v.8M100.9 68l.2-.2v.8M100.9 69.7l.2-.2v.9M100.9 73.2l.2-.3v.9M100.9 65.2h.5M100.9 66.9h.5M100.9 68.6h.5"/>
<path d="M100.9 70.4h.5M100.9 73.8h.5M101.3 60.9h.6l-.4 .9M101.3 74.9l.3-.3v1M101.3 75.6h.5M101.5 62.9l-.2-.1 .1-.2h.3l.1 .3-.5 .2 .1 .4 .4-.1v-.4l-.2-.1M101.7 64.3h.5l-.3 .3 .3 .2v.3l-.1 .1-.4-.1M101.7 67.8h.5l-.3 .8M101.7 73.2l.3-.3v.9M101.7 73.8h.5M101.9 66l-.2 .6h.5M101.9 69.9l-.2-.3 .4-.1 .1 .2-.5 .4 .2 .3 .3-.2-.1-.3"/>
<path d="M102.1 66.3v.6M107.4 78.7a.48 .48 0 0 1 .5-.2 .48 .48 0 0 1 .3 .4l-.1 .1h-.5l-.2-.1zM108.2 79.6h-.8l.2 .3M108.2 79.4v.5M114.7 64.6l.2-.3v.9M114.7 66.3l.2-.2v.8M114.7 68l.2-.2v.8M114.7 69.7l.2-.2v.9M114.7 65.2h.5M114.7 66.9h.5M114.7 68.6h.5M114.7 70.4h.5"/>
<path d="M115.5 60.9l-.4 .2v.6l.3 .1 .2-.5h-.5M115.5 64.4l.4-.1 .1 .3-.6 .6h.6M115.6 62.9l-.1 .2h-.3l-.1-.4 .4-.1 .1 .2-.2 .7h-.2M115.9 66.1h-.4v.4l.4-.1 .1 .4-.1 .1-.4-.1M115.9 67.8l-.4 .1v.6l.4 .1v-.5h-.3l-.1 .2M116 69.9l-.1 .2-.4-.1v-.4l.4-.1 .1 .1-.1 .7-.3 .1M139.7 67.2l.2-.3v.9M139.7 68.9l.2-.3v.9M139.7 72.3l.2-.2v.8M139.7 74l.2-.2v.8M139.7 79.2l.2-.3v.9M139.7 67.8h.5"/>
<path d="M139.7 69.5h.5M139.7 72.9h.5M139.7 74.6h.5M139.7 79.8h.5M140.1 77.5l.2-.2v.8M140.1 78.1h.5M140.4 73.8h.6l-.3 .3 .3 .2-.1 .3-.5-.1M140.5 61.8h-.4v.4l.4-.1 .1 .2-.1 .3-.4-.1M140.5 63.5l-.4 .2v.5l.4 .1 .1-.3-.2-.2-.3 .2M140.5 67.2l.3-.3v.9M140.5 67.8h.5M140.7 68.6a.43 .43 0 0 1 .3 .5 .43 .43 0 0 1-.4 .4l-.1-.7z"/>
<path d="M140.7 72l-.2 .7h.5M140.9 78.9h-.4v.5l.3-.1 .2 .4-.5 .1M140.9 72.3v.6M153.5 72.3l.2-.2v.8M153.5 72.9h.5M153.8 61.8h.6l-.4 .8M154.3 72.2l.3-.1 .1 .3-.5 .5h.5M154.4 67.3l-.1 .1h-.3l-.1-.4 .4-.1 .1 .2-.2 .7h-.2M170.6 67.2l.3-.3v.9M170.6 68.9l.3-.3v.9M170.6 72.3l.3-.2v.8M170.6 74l.3-.2v.8"/>
<path d="M170.6 79.2l.3-.3v.9M170.6 67.8h.6M170.6 69.5h.6M170.6 72.9h.6M170.6 74.6h.6M170.6 79.8h.6M171.1 77.5l.2-.2v.8M171.1 78.1h.5M171.5 63.5h-.3l-.1 .6 .1 .2 .4-.1v-.3l-.2-.1-.3 .2M171.5 67.2l.2-.3v.9M171.5 73.8h.5l-.3 .3 .3 .2-.1 .3-.4-.1M171.5 67.8h.5"/>
<path d="M171.6 61.8h-.4l-.1 .4 .4-.1 .1 .4h-.5M171.7 68.6a.43 .43 0 0 1 .3 .5 .43 .43 0 0 1-.4 .4l-.1-.5zM171.7 72l-.2 .7h.5M171.9 78.9h-.3l-.1 .5 .3-.1 .2 .4-.5 .1M171.9 72.3v.6M184.4 72.3l.3-.2v.8M184.4 72.9h.6M184.8 61.8h.6l-.4 .8M185.3 72.2l.4-.1 .1 .2-.6 .6h.6M185.4 67.3l-.1 .1h-.3l-.1-.4 .4-.1 .1 .2-.2 .7h-.2M203.4 67.2l.3-.3v.9M203.4 68.9l.3-.3v.9"/>
<path d="M203.4 72.3l.3-.2v.8M203.4 74l.3-.2v.8M203.4 79.2l.3-.3v.9M203.4 67.8h.5M203.4 69.5h.5M203.4 72.9h.5M203.4 74.6h.5M203.4 79.8h.5M203.8 77.5l.3-.2v.8M203.8 78.1h.5M204.2 73.8h.5l-.3 .3 .3 .1v.3h-.5M204.3 61.8h-.5v.4l.5-.1v.5l-.5-.1"/>
<path d="M204.3 63.5l-.5 .2v.5l.5 .1v-.3l-.1-.2-.4 .2M204.3 67.2l.2-.3v.9M204.3 67.8h.4M204.4 68.6l.3 .2-.1 .7h-.3v-.2v-.5zM204.4 72l-.1 .7h.5M204.6 72.3v.6M204.7 78.9h-.4v.5h.4v.4h-.4M217.2 72.3l.3-.2v.8M217.2 72.9h.4M217.5 61.8h.6l-.4 .8M218 72.2h.5v.2l-.5 .5h.5M218.1 67.3l-.1 .1h-.4v-.5l.5 .1v.6l-.5 .2"/>
<path d="M236.1 67.2l.2-.3v.9M236.1 68.9l.2-.3v.9M236.1 72.3l.2-.2v.8M236.1 74l.2-.2v.8M236.1 79.2l.2-.3v.9M236.1 67.8h.5M236.1 69.5h.5M236.1 72.9h.5M236.1 74.6h.5M236.1 79.8h.5M236.5 77.5l.3-.2v.8M236.5 78.1h.5"/>
<path d="M236.9 63.5h-.2l-.2 .6 .1 .2 .4-.1v-.3l-.1-.1-.4 .2M236.9 67.2l.3-.3v.9M236.9 73.8h.5l-.2 .3 .2 .2v.3l-.5-.1M236.9 67.8h.5M237 61.8h-.4l-.1 .4 .4-.1 .1 .4h-.5M237 68.7h.4v.8h-.3l-.2-.3zM237.2 72l-.3 .7h.5M237.4 78.9h-.4l-.1 .5 .4-.1 .1 .4-.5 .1M237.4 72.3v.6M249.9 72.3l.2-.2v.8M249.9 72.9h.5M250.3 61.8h.5l-.3 .8"/>
<path d="M250.7 72.2l.5-.1v.2l-.5 .6h.5M250.8 67.3l-.1 .1h-.3v-.5h.3l.1 .2-.1 .7h-.3M35.4 81.6h.5l-.2 .3 .2 .1v.3h-.5M35.4 83.3h.5l-.2 .3 .2 .1v.3h-.5M35.4 85h.5l-.2 .3 .2 .1v.4h-.5M35.4 86.7h.5l-.2 .4 .2 .1v.3h-.5M35.4 88.4h.5l-.2 .4 .2 .1v.3h-.5M35.7 90.1l-.3 .6h.6M35.7 91.8l-.3 .7h.6M35.7 93.6l-.3 .6h.6M35.7 95.3l-.3 .6h.6M35.7 97l-.3 .7h.6"/>
<path d="M35.7 98.8l-.3 .6h.6M35.9 90.5v.6M35.9 92.2v.5M35.9 93.9v.5M35.9 95.6v.6M35.9 97.3v.6M35.9 99.1v.5M36.2 83.3h.6l-.4 .3 .4 .2-.1 .3-.5-.1M36.2 88.4h.6l-.4 .9M36.3 80l.2-.2v.9M36.3 81.7l.4-.1 .1 .2-.6 .6h.6M36.3 90.3l.1-.1a.43 .43 0 0 1 .4 .4 .43 .43 0 0 1-.4 .5l-.1-.2z"/>
<path d="M36.3 92.2l.2-.3v.8M36.3 93.7l.3-.1 .2 .2-.6 .6h.6M36.3 92.7h.5M36.3 80.7h.5M36.4 95.3l-.1 .6h.5M36.7 85h-.4v.4l.3-.1 .2 .4-.2 .2-.3-.1M36.7 86.7l-.4 .2v.6l.4 .1v-.5h-.3l-.1 .1M36.7 97.1h-.4v.4l.4-.1 .1 .2-.1 .3-.4-.1M36.7 98.8h-.3l-.1 .7h.5l-.2-.4-.3 .2M36.7 95.6v.6M71.8 98.8l-.2 .6h.6M72 81.6h-.2l-.2 .7 .1 .1 .4-.1-.1-.4h-.3l-.1 .2"/>
<path d="M72 83.3l-.2 .1-.2 .5 .1 .2 .4-.1v-.3l-.2-.1-.3 .2M72 99.1v.5M72.1 85h-.4l-.1 .4h.5v.4h-.5M72.1 86.7h-.4l-.1 .5 .4-.1 .1 .4h-.5M72.1 88.4h-.4l-.1 .5h.5v.3h-.5M72.1 90.2h-.4l-.1 .3h.5v.5h-.5M72.1 91.9h-.4l-.1 .4 .4-.1 .1 .5h-.5M72.1 93.6h-.4l-.1 .4h.5v.4h-.5M72.1 95.4h-.4l-.1 .3h.5v.4h-.5M72.1 97.1h-.4l-.1 .4 .4-.1 .1 .4h-.5M72.4 81.8l.3-.2v.8M72.4 86.7h.5l-.3 .9"/>
<path d="M72.4 93.6h.5l-.2 .3 .2 .1v.4h-.5M72.4 95.5h.5v.2l-.5 .5h.5M72.4 82.4h.5M72.5 83.4l.3-.1 .1 .1v.6a.39 .39 0 0 1-.5-.2 .39 .39 0 0 1 .1-.4zM72.5 97.2l.4-.1v.1v.6a.39 .39 0 0 1-.5-.2 .39 .39 0 0 1 .1-.4zM72.6 85.4l-.2-.3 .5-.1v.3l-.4 .1-.1 .2 .2 .3 .3-.1v-.3l-.1-.1M72.7 91.8l-.3 .7h.5M72.9 88.4l-.3 .1-.2 .6 .1 .2 .4-.1v-.3l-.3-.1-.2 .1M72.9 92.2v.5M72.9 90.2h-.4l-.1 .3h.5v.5h-.5M72.9 99.2l-.1 .2-.4-.2 .2-.4h.3v.6l-.4 .2M101.3 93.6h.5l-.2 .3 .2 .1v.4h-.5"/>
<path d="M101.3 97.1h.6l-.4 .8M101.5 99.2l-.2-.3 .2-.1h.3v.3l-.4 .1v.4l.4-.1v-.2l-.2-.1M101.6 95.3l-.3 .6h.6M101.7 95.6v.6M107.4 90.7l.7-.1 .1 .2a.43 .43 0 0 1-.4 .3 .43 .43 0 0 1-.4-.4zM108.2 91.4v.6l-.6-.6-.2 .1 .1 .4M115.1 93.7l.3-.1 .2 .2-.6 .6h.6M115.5 95.4h-.4v.3l.3-.1 .2 .5-.2 .1-.3-.1M115.5 97.1l-.4 .1v.6l.4 .1v-.5h-.3l-.1 .2M115.6 99.2l-.2 .2-.3-.1v-.5h.3l.2 .1-.2 .7h-.2M146.5 83.4l.1-.1h.3l.1 .1v.2l-.3 .2-.2-.1-.1-.4h-.2l-.1 .3 .2 .2 .2-.2M152.9 93.6h.6l-.3 .3 .3 .1v.4h-.6"/>
<path d="M153 92l.4-.1 .1 .3-.6 .5h.6M153.2 95.3l-.2 .6h.5M153.4 98.8l-.4 .2v.5h.5v-.3l-.3-.1-.2 .2M153.4 95.6v.6M153.5 97.1h-.5v.4h.5l-.1 .4-.4-.1M159.1 88.9a.39 .39 0 0 1 .5-.1 .39 .39 0 0 1 .2 .5l-.6 .1-.2-.1zM159.9 89.7v.5l-.6-.5-.3 .1 .1 .4M166.3 92.2l.3-.3v.8M166.3 93.8l.3-.2v.8M166.3 95.5l.3-.1v.8M166.3 97.3l.3-.2v.8M166.3 99l.3-.2v.8"/>
<path d="M166.3 92.7h.5M166.3 94.4h.5M166.3 96.2h.5M166.3 97.9h.5M166.3 99.6h.5M167.2 93.6h.5l-.4 .8M167.3 92.2l-.1-.1 .1-.2h.3l.1 .3-.5 .2 .1 .3h.3l.1-.4-.2-.1M167.4 98.8l-.2 .6h.5M167.6 95.4h-.3l-.1 .7 .1 .1 .4-.1v-.4l-.4-.1-.1 .2M167.6 99.1v.5M167.7 97.1h-.4l-.1 .4 .4-.1 .1 .4h-.5M177.5 83.4l.1-.1h.3l.1 .1v.2l-.3 .2-.2-.1-.1-.4h-.2v.4l.1 .1 .2-.2"/>
<path d="M185.7 92l.4-.1 .1 .2-.5 .6h.5M185.7 93.6h.5l-.2 .3 .2 .2-.1 .3h-.4M186 95.3l-.3 .6h.5M186.1 97.1h-.3l-.1 .4 .4-.1v.5l-.4-.1M186.1 98.8h-.2l-.2 .7h.5l-.1-.4-.4 .2M186.1 95.6v.6M191.8 88.9a.53 .53 0 0 1 .9 .3l-.2 .2h-.6zM192.7 89.7v.5l-.7-.5-.2 .1v.4M199.1 92.2l.2-.3v.8M199.1 93.8l.2-.2v.8M199.1 95.5l.2-.1v.8M199.1 97.3l.2-.2v.8"/>
<path d="M199.1 99l.2-.2v.8M199.1 92.7h.5M199.1 94.4h.5M199.1 96.2h.5M199.1 97.9h.5M199.1 99.6h.5M199.9 93.6h.5l-.3 .8M200.1 92.2l-.2-.2 .5-.1v.3l-.5 .1 .1 .4h.4v-.1l-.1-.4M200.1 98.8l-.2 .6h.5M200.4 95.4l-.5 .1v.6l.4 .1 .1-.4-.1-.2-.4 .2M200.4 97.1h-.5v.4l.5-.1v.2v.3l-.5-.1M200.4 99.1v.5"/>
<path d="M210.3 83.4v-.1l.4 .1v.3l-.3 .1-.2-.5h-.3l-.1 .3 .2 .2 .3-.2M242.9 83.4l.1-.1h.4l.1 .1v.2l-.4 .2-.2-.4-.2-.1-.1 .4 .2 .1 .1-.2M35.7 100.5l-.3 .5h.6M35.7 102.1l-.3 .7h.6M35.9 100.8v.6M35.9 102.5v.6M36.2 100.5h.6l-.4 .9M36.4 102.6l-.1-.3 .4-.1v.4l-.4 .1 .1 .4h.3l.1-.4-.2-.1M39.3 119.9v.5M48 108.1h-1l.3 .1M48 107.2h-1l.3 .3M48 107v.5"/>
<path d="M48 107.8v.4M48.8 107.1v.2l.7 .2 .2-.1-.1-.4-.5 .1v.3l.2 .1M49.7 107.8v.5l-.6-.5-.3 .1 .1 .3M50.5 108.3v-.5l.3 .3 .1-.3h.4v.5M50.9 107.1l.1-.1 .3 .1v.3l-.3 .1-.2-.5h-.2l-.1 .3 .2 .2 .2-.2M52.3 107.5v-.5l.2 .2 .1-.2h.4v.5M52.5 107.9h.6M52.8 107.7v.5l-.6-.1M54 107.8v.4h.4v-.4l.4 .1-.1 .3M54.3 107l.2 .1v.3h-.5l.1-.4h.5l.2 .4M56 107.1h.5M56.3 106.9v.6l-.6-.3"/>
<path d="M56.5 108.2l-.8-.5v.6M57.4 107.1v.2l.7 .2 .2-.2-.1-.3h-.4l-.1 .3 .2 .2M57.8 108l.1-.2h.3l.1 .2-.1 .2h-.4l-.1-.4-.3 .1v.3h.4M59.1 107v.4l.5 .1-.1-.4 .4-.1v.5M59.5 107.8l.1 .1v.3h-.5l.1-.4h.6l.2 .4M100.9 100.8l.2-.3v.9M100.9 102.5l.2-.3v.9M100.9 104.2l.2-.3v.9M100.9 106l.2-.3v.8M100.9 109.3l.2-.2v.9M100.9 101.4h.5M100.9 103.1h.5"/>
<path d="M100.9 104.8h.5M100.9 106.5h.5M100.9 110h.5M101.3 111.1l.3-.2v.8M101.3 111.7h.5M101.7 100.5h.5l-.3 .3 .3 .2v.2l-.1 .2-.4-.1M101.7 103.9h.5l-.3 .9M101.7 109.3l.3-.2v.9M101.7 110h.5M101.9 102.1l-.2 .7h.5M101.9 106l-.2-.1 .1-.2h.3v.3h-.3l-.1 .2 .2 .3 .3-.1-.1-.4M102.1 102.5v.6"/>
<path d="M107.4 114.8h.7l.1 .2-.1 .2h-.5l-.2-.1zM108.2 115.8h-.8l.2 .2M108.2 115.5v.5M114.7 100.8l.2-.3v.9M114.7 102.5l.2-.3v.9M114.7 104.2l.2-.3v.9M114.7 106l.2-.3v.8M114.7 101.4h.5M114.7 103.1h.5M114.7 104.8h.5M114.7 106.5h.5M115.5 100.6l.4-.1 .1 .3-.6 .6h.6"/>
<path d="M115.9 102.2h-.4v.5l.4-.1 .1 .1-.1 .4-.4-.1M115.9 103.9l-.3 .1-.1 .8 .5-.1-.1-.4-.4 .1M116 106l-.1 .2-.4-.1v-.3l.4-.1 .1 .2-.1 .6h-.3M152.6 109.3l.3-.2v.9M152.6 110h.5M152.9 100.5h.6l-.3 .9M153 107.7l.2-.3v.8M153 108.2h.5M153.2 102.6l-.2-.3 .4-.1 .1 .3-.5 .2 .1 .4 .4-.1v-.3l-.2-.1M153.5 104.3l-.2 .2-.3-.1v-.4h.5v.6l-.1 .2h-.3M153.9 109.5l-.4 .2-.1-.4 .1-.2 .4 .1-.1 .7-.3 .1M159.1 113.1a.39 .39 0 0 1 .5-.1 .39 .39 0 0 1 .2 .4l-.6 .1-.2-.1z"/>
<path d="M159.9 114.1h-.9l.3 .2M159.9 113.8v.5M166.3 100.8l.3-.3v.9M166.3 102.5l.3-.3v.9M166.3 104.2l.3-.3v.9M166.3 101.4h.5M166.3 103.1h.5M166.3 104.8h.5M167.2 100.5h.5l-.3 .3 .3 .1v.4h-.5M167.2 102.3h.5v.3l-.5 .5h.5M167.2 104.2l.2-.3v.9M167.2 104.8h.5"/>
<path d="M185.3 109.3l.2-.2v.9M185.3 110h.5M185.7 100.5h.5l-.3 .9M185.7 107.7l.3-.3v.8M185.7 108.2h.5M185.9 102.6l-.2-.2 .1-.2h.3v.4l-.4 .1 .1 .4h.3l.1-.4-.1-.1M186.2 104.3l-.1 .2-.4-.2 .2-.4 .3 .2v.3l-.1 .4h-.3M186.6 109.5l-.1 .2-.4-.1v-.4l.4-.1 .1 .2-.1 .6-.3 .1M191.8 113.1a.53 .53 0 0 1 .9 .2l-.2 .2h-.6zM192.7 114.1h-.9l.2 .2M192.7 113.8v.5M199.1 100.8l.2-.3v.9"/>
<path d="M199.1 102.5l.2-.3v.9M199.1 104.2l.2-.3v.9M199.1 101.4h.5M199.1 103.1h.5M199.1 104.8h.5M199.9 100.5h.5l-.3 .3 .3 .2v.2l-.1 .2-.4-.1M199.9 102.3l.5-.1v.3l-.5 .6h.5M199.9 104.2l.3-.3v.9M199.9 104.8h.5M32.9 129l.3-.1 .2 .3-.6 .5h.6M32.9 130.8l.4-.1 .1 .2-.6 .6h.6M32.9 132.5l.4-.1 .1 .2-.6 .6h.6"/>
<path d="M32.9 134.2l.3-.1 .2 .2-.6 .7h.6M32.9 135.9l.4-.1 .1 .3-.6 .6h.6M32.9 137.6l.3-.1 .2 .3-.6 .6h.6M32.9 139.5l.2-.3v1M33.1 123.7l-.2 .6h.5M33.1 125.4l-.2 .6h.5M33.1 127.1l-.2 .7h.5M33.3 124.1v.5M33.3 125.8v.6M33.3 127.5v.6M33.7 125.5h.5l-.3 .4h.3v.4h-.5M33.7 127.3h.5v.2l-.5 .6h.5"/>
<path d="M33.7 128.9h.5l-.4 .8M33.7 136.1l.2-.3v.9M33.7 136.7h.5M33.7 137.6l.3-.1 .2 .2-.1 .6a.39 .39 0 0 1-.5-.2 .39 .39 0 0 1 .1-.5zM33.9 123.7l-.2 .6h.5M33.9 134.1l-.2 .6h.5M34.1 130.7h-.3l-.1 .7 .1 .1 .4-.1-.1-.4-.4 .1M34.1 124.1v.5M34.1 134.4v.6M34.2 132.4h-.5v.4l.4-.1 .1 .4h-.5M34.2 139.7l-.4 .1-.1-.4 .1-.2 .4 .1-.1 .8-.4 .1M39.3 120.9h-.8l.2 .3"/>
<path d="M39.3 120.1h-.8l.2 .3M39.3 120.7v.5M40.2 121.3v-.6l.3 .3v-.2l.2-.1 .3 .1-.1 .5M40.2 120.4v-.5l.3 .3 .1-.3h.3v.5M46.6 129.2l.3-.3v.8M46.6 130.9l.3-.2v.8M46.6 132.6l.3-.2v.8M46.6 134.3l.3-.2v.9M46.6 136.1l.3-.3v.9M46.6 137.6h.5v.3l-.5 .5h.5M46.6 139.2h.5l-.2 .4 .2 .1v.4h-.5M46.6 136.7h.5"/>
<path d="M46.6 129.7h.5M46.6 131.5h.5M46.6 133.2h.5M46.6 135h.5M47 123.7h.6l-.4 .9M47.2 125.9l-.2-.2 .1-.2 .4 .1v.3h-.4l-.1 .1 .2 .4 .3-.1v-.4h-.1M47.5 130.7h.5l-.3 .3 .3 .1v.3l-.2 .1-.3-.1M47.5 127.5v.2h-.4v-.5l.4 .1v.6l-.4 .2M47.5 129h.4v.7h-.4zM47.5 139.3l.2-.1a.54 .54 0 0 1 0 1l-.2-.4zM47.7 132.4l-.2 .6h.5M47.9 134.1h-.4v.4l.3-.1 .2 .4-.2 .2-.3-.1"/>
<path d="M47.9 135.8h-.3l-.1 .7 .1 .2 .4-.2-.1-.3h-.4v.2M47.9 132.6v.6M48 137.9l-.1 .1h-.4v-.3l.1-.2 .4 .2-.1 .6-.4 .1M66 129.8l.3-.1 .2 .2-.5 .8h.5M66 131.5h.5l-.3 .4 .3 .1-.1 .4-.4-.1M66 138.4h.5l-.3 .8M66.2 133.2l-.2 .6h.5M66.4 135h-.3l-.1 .3h.3l.2 .4-.2 .1h-.3M66.4 136.7h-.2l-.2 .3 .1 .5h.3v-.5h-.3l-.1 .2M66.4 133.6v.5M72.1 126.9l.7-.1 .1 .2a.45 .45 0 0 1-.4 .3 .45 .45 0 0 1-.4-.3zM72.9 127.6v.5l-.5-.5h-.3v.5"/>
<path d="M79.4 130l.2-.3v1M79.4 131.8l.2-.3v.9M79.4 133.5l.2-.3v.9M79.4 135.2l.2-.2v.8M79.4 136.9l.2-.2v.8M79.4 138.6l.2-.2v.8M79.4 130.7h.5M79.4 132.4h.5M79.4 134.1h.5M79.4 135.8h.5M79.4 137.5h.5M79.4 139.2h.5"/>
<path d="M80.1 131.5h.6l-.3 .9M80.1 138.4h.6l-.3 .3 .3 .2-.1 .3-.5-.1M80.4 130.2l-.2-.1v-.3l.4-.1 .1 .3-.5 .3v.3l.2 .1 .3-.2-.1-.3M80.4 136.6l-.2 .7h.5M80.6 133.2l-.4 .3v.5l.4 .1 .1-.4-.1-.1-.4 .1M80.6 135h-.4v.3h.4l.1 .4-.1 .1h-.4M80.6 136.9v.6M97 129.8h.5v.4l-.5 .5h.5M97 131.5h.5l-.3 .4h.3v.4h-.5M97 138.4h.6l-.4 .8M97.2 133.2l-.2 .6h.6M97.4 136.7h-.2l-.2 .7 .1 .1h.4l-.1-.5h-.3l-.1 .2"/>
<path d="M97.4 133.6v.5M97.5 135h-.4l-.1 .3h.5v.5h-.5M103.1 126.9l.7-.1 .1 .2a.43 .43 0 0 1-.4 .3 .43 .43 0 0 1-.4-.4zM103.9 127.6v.5l-.5-.5-.3 .1 .1 .4M110.4 130l.2-.3v1M110.4 131.8l.2-.3v.9M110.4 133.5l.2-.3v.9M110.4 135.2l.2-.2v.8M110.4 136.9l.2-.2v.8M110.4 138.6l.2-.2v.8M110.4 130.7h.5M110.4 132.4h.5"/>
<path d="M110.4 134.1h.5M110.4 135.8h.5M110.4 137.5h.5M110.4 139.2h.5M111.1 131.5h.6l-.3 .9M111.1 138.4h.6l-.3 .3 .3 .2-.1 .3-.5-.1M111.4 130.2l-.2-.1v-.3l.3-.1 .2 .3-.5 .3v.3l.2 .1 .3-.2-.2-.3M111.4 136.6l-.2 .7h.5M111.6 133.2l-.4 .3v.5l.4 .1 .1-.4-.2-.1-.3 .1M111.6 135h-.4v.3h.3l.2 .4-.2 .1h-.3M111.6 136.9v.6M126.3 129.8h.5v.4l-.5 .5h.5"/>
<path d="M126.3 131.5h.5l-.3 .4h.3v.4h-.5M126.3 138.4h.6l-.5 .8M126.5 133.2l-.2 .6h.6M126.7 136.7h-.3l-.1 .7 .1 .1h.4l-.1-.5h-.3l-.1 .2M126.7 133.6v.5M126.8 135h-.4l-.1 .3h.5v.5h-.5M132.4 126.9l.7-.1 .1 .2a.43 .43 0 0 1-.4 .3 .43 .43 0 0 1-.4-.4zM133.2 127.6v.5l-.5-.5-.3 .1 .1 .4M139.7 130l.2-.3v1M139.7 131.8l.2-.3v.9M139.7 133.5l.2-.3v.9M139.7 135.2l.2-.2v.8"/>
<path d="M139.7 136.9l.2-.2v.8M139.7 138.6l.2-.2v.8M139.7 130.7h.5M139.7 132.4h.5M139.7 134.1h.5M139.7 135.8h.5M139.7 137.5h.5M139.7 139.2h.5M140.4 131.5h.6l-.3 .9M140.4 138.4h.6l-.3 .3 .3 .2-.1 .3-.5-.1M140.7 130.2l-.2-.1v-.3l.3-.1 .2 .3-.5 .3v.3l.2 .1 .3-.2-.2-.3M140.7 136.6l-.2 .7h.5"/>
<path d="M140.9 133.2l-.4 .3v.5l.4 .1 .1-.4-.2-.1-.3 .1M140.9 135h-.4v.3h.3l.2 .4-.2 .1h-.3M140.9 136.9v.6M162.9 133.5l.3-.3v.9M162.9 135.2l.3-.2v.8M162.9 136.8l.5-.1v.2l-.5 .6h.5M162.9 138.5l.4-.1 .1 .2-.5 .6h.5M162.9 134.1h.5M162.9 135.8h.5M163.3 128.1h.5l-.3 .3 .3 .1v.3h-.5M163.4 124.8l.2-.2v.9M163.4 126.4h.3l.1 .3-.5 .5h.5"/>
<path d="M163.4 125.5h.4M163.5 129.7l-.1 .6h.5M163.7 138.6l.3-.2v.8M163.7 139.2h.5M163.7 130.1v.6M163.8 131.5h-.4v.4h.4l-.1 .5-.3-.1M163.9 133.6l-.2-.2 .2-.2 .3 .1v.3l-.5 .1 .1 .4h.3l.1-.4-.2-.1M163.9 136.7h.2l.1 .2-.1 .6a.39 .39 0 0 1-.4-.3 .39 .39 0 0 1 .1-.4zM164.2 135.3l-.3 .2-.2-.4 .5-.1-.1 .8h-.3M169.4 121.8h-.9l.3 .2M169.4 121h-.9l.3 .3M169.4 120.8v.5"/>
<path d="M169.4 121.5v.5M170.2 122.1v-.6l.4 .4 .1-.4 .4 .1-.1 .5M170.2 121.3v-.5l.4 .2v-.2h.4v.5M176.7 130l.2-.3v1M176.7 131.8l.2-.3v.9M176.7 133.5l.2-.3v.9M176.7 135.2l.2-.2v.8M176.7 136.9l.2-.2v.8M176.7 138.5h.5v.3l-.5 .4h.5M176.7 130.7h.5M176.7 132.4h.5M176.7 134.1h.5"/>
<path d="M176.7 135.8h.5M176.7 137.5h.5M177.1 124.6h.6l-.5 .9M177.2 126.7l-.1-.2 .1-.1h.4l-.1 .3-.4 .2 .1 .3 .4-.1v-.3l-.2-.1M177.5 131.5h.5l-.2 .4h.2v.4h-.5M177.6 128.5h-.5l.1-.4h.4v.6l-.4 .2M177.6 129.8l.2-.1 .2 .2v.6l-.2 .2a.53 .53 0 0 1-.2-.9zM177.8 133.2l-.3 .6h.6M177.9 136.7h-.2l-.2 .7 .1 .1h.4l-.1-.5h-.3l-.1 .2M177.9 133.6v.5M178 135h-.4l-.1 .3h.5v.5h-.5M178 138.8l-.2 .2-.3-.2 .2-.4 .3 .1v.6l-.4 .1"/>
<path d="M202.6 133.5l.2-.3v.9M202.6 135.2l.2-.2v.8M202.6 136.8l.4-.1 .1 .2-.6 .6h.6M202.6 138.5l.3-.1 .2 .2-.6 .6h.6M202.6 134.1h.5M202.6 135.8h.5M202.9 128.1h.5l-.2 .3 .2 .1v.3h-.5M203 124.8l.2-.2v.9M203 126.4h.3l.1 .3-.5 .5h.5M203 125.5h.4M203.2 129.7l-.2 .6h.5M203.3 138.6l.3-.2v.8"/>
<path d="M203.3 139.2h.5M203.3 130.1v.6M203.4 131.5h-.4v.4h.4l-.1 .5-.3-.1M203.4 136.8l.3-.1 .1 .2-.1 .6a.39 .39 0 0 1-.4-.3 .39 .39 0 0 1 .1-.4zM203.5 133.6l-.2-.2 .2-.2 .3 .1v.3l-.5 .1 .1 .4 .4-.1v-.3l-.1-.1M203.8 135.3l-.3 .2-.2-.4 .5-.1v.6l-.4 .2M209 121.8h-.9l.3 .2M209 121h-.9l.3 .3M209 120.8v.5M209 121.5v.5M209.8 122.1v-.6l.4 .4 .2-.4 .3 .1-.1 .5M209.8 121.3v-.5l.4 .2 .1-.2h.3v.5"/>
<path d="M216.4 130l.1-.3v1M216.4 131.8l.1-.3v.9M216.4 133.5l.1-.3v.9M216.4 135.2l.1-.2v.8M216.4 136.9l.1-.2v.8M216.4 138.5h.4v.3l-.5 .4h.5M216.4 130.7h.4M216.4 132.4h.4M216.4 134.1h.4M216.4 135.8h.4M216.4 137.5h.4M216.7 124.6h.6l-.4 .9"/>
<path d="M216.9 126.7l-.2-.2 .1-.1h.3l.1 .2-.5 .3 .2 .3 .3-.1v-.3l-.2-.1M217.1 131.5h.5l-.2 .4h.2v.4h-.5M217.2 128.5h-.5l.2-.4h.3v.6l-.4 .2M217.2 129.8l.3-.1 .1 .2v.6l-.1 .2a.53 .53 0 0 1-.3-.9zM217.4 133.2l-.3 .6h.5M217.5 136.7h-.2l-.2 .7 .1 .1h.4l-.1-.5h-.3l-.1 .2M217.5 133.6v.5M217.6 135h-.4l-.1 .3h.5v.5h-.5M217.6 138.8l-.1 .2-.4-.2 .2-.4 .3 .1v.6l-.4 .1M32.8 158.2h.6l-.3 .3 .3 .2-.1 .3h-.5M32.9 141.3l.2-.3v.9M32.9 153.3l.2-.3v.9"/>
<path d="M32.9 140.2h.5M32.9 141.9h.5M32.9 153.9h.5M33.1 154.7l-.2 .6h.5M33.1 156.4l-.2 .7h.5M33.2 146.2h.5l-.2 .3 .2 .1v.3h-.5M33.3 148h.4v.2l-.5 .5h.5M33.3 155.1v.6M33.3 156.8v.5M33.5 144.4l-.2 .6h.5M33.7 151.3h-.3l-.1 .2v.6h.4v-.4h-.3l-.1 .1M33.7 153h.5l-.4 .9"/>
<path d="M33.7 155l.2-.3v1M33.7 144.7v.6M33.7 155.7h.5M33.7 142.7h-.4v.4h.4v.4h-.4M33.7 156.6l.4-.1 .1 .2-.1 .6a.39 .39 0 0 1-.5-.2 .39 .39 0 0 1 .1-.5zM33.8 141.3l-.1-.1v-.2h.4l.1 .3-.5 .2 .1 .4 .4-.1v-.4l-.2-.1M34.2 158.6h-.5l.1-.4 .4 .1v.6l-.5 .1M46.6 141h.5l-.2 .3 .2 .1v.4h-.5M46.6 142.7h.5l-.2 .3 .2 .1v.4h-.5M46.6 144.4h.5l-.2 .3 .2 .1v.4h-.5M46.6 146.2h.5l-.2 .3 .2 .1v.3h-.5M46.6 147.9h.5l-.2 .3 .2 .1v.3h-.5"/>
<path d="M46.6 149.6h.5l-.2 .3 .2 .1v.4h-.5M46.6 153.1h.5v.4l-.5 .4h.5M46.6 154.8h.5v.3l-.5 .6h.5M46.6 156.6h.5v.2l-.5 .5h.5M47 158.5l.3-.3v.8M47 159h.5M47.5 141.3l.2-.3v.9M47.5 142.8l.3-.1 .2 .2-.5 .6h.5M47.5 147.9h.5l-.4 .8M47.5 154.7h.5l-.3 .4 .3 .1v.3l-.2 .2-.3-.1M47.5 156.6l.4-.1 .1 .2-.5 .6h.5M47.5 141.9h.5"/>
<path d="M47.6 150l-.1-.3 .3-.1 .2 .2-.5 .4 .1 .3 .4-.2-.2-.3M47.6 153.5l-.1-.3 .3-.2 .2 .3-.5 .2v.4h.4l.1-.4h-.2M47.9 144.4h-.4v.4l.3-.1 .2 .5-.2 .1-.3-.1M47.9 146.2h-.3l-.1 .7 .1 .1 .4-.1-.1-.4h-.4v.2M65.6 147.3l.2-.3v.9M65.6 147.9h.5M66 145.6l.2-.3v.9M66 146.2h.5M66.2 140.5l-.2-.3h.4l.1 .1-.5 .4 .2 .3 .3-.2-.2-.3M66.5 142.2l-.1 .2h-.3v-.5h.3l.1 .1-.2 .7h-.2M66.9 147.4l-.1 .1h-.3l-.1-.4 .4-.1 .1 .2-.1 .7h-.3M72.1 151l.7-.1 .1 .2a.45 .45 0 0 1-.4 .3 .45 .45 0 0 1-.4-.2z"/>
<path d="M72.9 151.9h-.8l.2 .3M72.9 151.7v.5M79.4 140.3l.2-.1v.8M79.4 142.1l.2-.2v.8M79.4 141h.5M79.4 142.7h.5M80.2 140.2h.4l.1 .1-.6 .7h.6M80.2 142.1l.3-.2v.8M80.2 142.7h.5M96.6 147.3l.2-.3v.9M96.6 147.9h.5M97 145.6l.2-.3v.9"/>
<path d="M97 146.2h.5M97.2 140.5l-.2-.3h.4l.1 .2-.4 .1-.1 .2 .2 .3 .3-.1v-.3l-.2-.1M97.5 142.2l-.1 .2h-.3v-.5h.4v.6l-.4 .2M97.9 147.4l-.1 .1h-.3v-.5l.4 .1v.6l-.4 .2M103.1 151l.7-.1 .1 .2a.43 .43 0 0 1-.4 .3 .43 .43 0 0 1-.4-.4zM103.9 151.9h-.8l.2 .3M103.9 151.7v.5M110.4 140.3l.2-.1v.8M110.4 142.1l.2-.2v.8M110.4 141h.5M110.4 142.7h.5M111.2 140.2h.4l.1 .1-.6 .7h.6"/>
<path d="M111.2 142.1l.3-.2v.8M111.2 142.7h.5M125.9 147.3l.2-.3v.9M125.9 147.9h.5M126.3 145.6l.2-.3v.9M126.3 146.2h.5M126.4 140.5l-.1-.3h.4l.1 .2-.4 .1-.1 .2 .1 .3 .4-.1v-.3l-.2-.1M126.8 142.2l-.1 .2h-.3v-.5h.4v.6l-.4 .2M127.2 147.4l-.1 .1h-.3v-.5h.3l.1 .2-.2 .7h-.2M132.4 151l.7-.1 .1 .2a.43 .43 0 0 1-.4 .3 .43 .43 0 0 1-.4-.4zM133.2 151.9h-.8l.2 .3M133.2 151.7v.5"/>
<path d="M139.7 140.3l.2-.1v.8M139.7 142.1l.2-.2v.8M139.7 141h.5M139.7 142.7h.5M140.5 140.2h.4l.1 .1-.6 .7h.6M140.5 142.1l.3-.2v.8M140.5 142.7h.5M162.9 140.2h.5v.1l-.5 .7h.5M162.9 141.9h.5v.2l-.5 .6h.5M162.9 143.6l.4-.1 .1 .3-.5 .6h.5M162.9 145.4l.5-.1v.3l-.5 .6h.5M162.9 147.1l.5-.1v.3l-.5 .6h.5"/>
<path d="M162.9 148.8l.4-.1 .1 .3-.5 .6h.5M162.9 159.3l.3-.3v1M162.9 160h.5M163.1 150.4l-.2 .6h.5M163.1 152.1l-.2 .7h.5M163.1 153.9l-.2 .6h.5M163.4 150.7v.6M163.4 152.4v.6M163.4 154.2v.5M163.7 140.2h.5v.3l-.5 .5h.5M163.7 141.9h.5l-.2 .3 .2 .1v.3h-.5M163.7 148.7h.6l-.4 .9"/>
<path d="M163.7 150.6h.5v.2l-.5 .5h.5M163.7 152.2h.5l-.2 .3 .2 .1v.3h-.5M163.7 157.3l-.3 .2v.6h.4l-.1-.4h-.3v.2M163.7 159h.6l-.4 1M164 143.5l-.3 .6h.6M164 153.9l-.3 .6h.6M164.1 147h-.2l-.2 .7 .1 .2 .4-.1-.1-.4h-.3l-.1 .1M164.1 143.9v.5M164.1 154.2v.5M164.2 145.3h-.4l-.1 .4h.5v.4h-.5M176.7 140.2h.5l-.3 .2 .3 .1v.4h-.5M176.7 141.9h.5l-.3 .3 .3 .1v.3h-.5"/>
<path d="M176.7 143.5h.5l-.3 .4 .3 .1v.3h-.5M176.7 145.3h.5l-.3 .3 .3 .1v.4h-.5M176.7 147h.5l-.3 .4h.3v.4h-.5M176.7 148.7h.5l-.3 .4h.3v.4h-.5M176.7 150.5h.5l-.3 .3h.3v.5h-.5M176.7 154h.5v.3l-.5 .4h.5M177.5 142.1l.3-.2v.8M177.5 143.6h.5v.4l-.5 .4h.5M177.5 148.7h.6l-.4 .9M177.5 142.7h.5M177.7 140.2h.3v.6l-.2 .2a.48 .48 0 0 1-.3-.4 .48 .48 0 0 1 .2-.4zM177.7 150.8l-.2-.1 .1-.2h.3l.1 .2-.4 .1-.1 .2 .2 .3h.3v-.4l-.2-.1"/>
<path d="M177.7 154.3l-.2-.2 .2-.2 .3 .1v.2l-.4 .1-.1 .2 .1 .2h.4v-.3l-.2-.1M177.9 147h-.2l-.2 .7 .1 .2 .4-.1-.1-.4h-.3l-.1 .1M178 145.3h-.4l-.1 .4h.5v.4h-.5M202.6 140.2h.4l.1 .1-.6 .7h.6M202.6 141.9h.4l.1 .2-.6 .6h.6M202.6 143.6l.3-.1 .2 .3-.6 .6h.6M202.6 145.4l.4-.1 .1 .3-.6 .6h.6M202.6 147.1l.4-.1 .1 .3-.6 .6h.6M202.6 148.8l.3-.1 .2 .3-.6 .6h.6M202.6 159.3l.2-.3v1M202.6 160h.5M202.7 150.4l-.1 .6h.5"/>
<path d="M202.7 152.1l-.1 .7h.5M202.7 153.9l-.1 .6h.5M203 150.7v.6M203 152.4v.6M203 154.2v.5M203.3 140.2h.5v.3l-.5 .5h.5M203.3 141.9h.5l-.2 .3 .2 .1v.3h-.5M203.3 148.7h.6l-.4 .9M203.3 150.6h.5v.2l-.5 .5h.5M203.3 152.2h.5l-.2 .3 .2 .1v.3h-.5M203.3 157.3l-.3 .2v.6h.4l-.1-.4h-.2l-.1 .2M203.3 159h.6l-.4 1"/>
<path d="M203.6 143.5l-.3 .6h.6M203.6 153.9l-.3 .6h.6M203.7 147h-.2l-.2 .7 .1 .2 .4-.1-.1-.4h-.3l-.1 .1M203.7 143.9v.5M203.7 154.2v.5M203.8 145.3h-.4l-.1 .4h.5v.4h-.5M216.3 140.2h.5l-.3 .2 .3 .1v.4h-.5M216.3 141.9h.5l-.3 .3 .3 .1v.3h-.5M216.3 143.5h.5l-.3 .4 .3 .1v.3h-.5M216.3 145.3h.5l-.3 .3 .3 .1v.4h-.5M216.3 147h.5l-.3 .4h.3v.4h-.5M216.3 148.7h.5l-.3 .4h.3v.4h-.5"/>
<path d="M216.3 150.5h.5l-.3 .3h.3v.5h-.5M216.4 154h.4v.3l-.5 .4h.5M217.1 142.1l.3-.2v.8M217.1 143.6h.5v.4l-.5 .4h.5M217.1 148.7h.5l-.3 .9M217.1 142.7h.5M217.2 140.2h.4v.6l-.1 .2-.3-.1zM217.3 150.8l-.2-.1 .1-.2h.3l.1 .2-.4 .1-.1 .2 .2 .3h.3v-.4l-.1-.1M217.3 154.3l-.2-.2 .2-.2 .3 .1v.2l-.4 .1-.1 .2 .1 .2h.4v-.3l-.1-.1M217.5 147h-.2l-.2 .7 .1 .2 .4-.1-.1-.4h-.3l-.1 .1M217.6 145.3h-.4l-.1 .4h.5v.4h-.5M39.3 165.7h-.8l.2 .3"/>
<path d="M39.3 164.7v.5l-.5-.5-.3 .1 .1 .3M39.3 165.5v.5M40.2 166.1v-.6l.3 .3v-.2l.2-.1 .3 .1-.1 .5M40.5 164.8h.5M40.8 164.6v.5l-.6-.1M66 166.9l.4-.1 .1 .2-.5 .7h.5M66 168.5h.5l-.3 .4 .3 .1-.1 .4-.4-.1M66 175.5h.5l-.3 .8M66.2 177.5l-.2-.2 .1-.1h.3v.3l-.4 .2 .1 .3h.3l.1-.3-.2-.2M66.2 170.2l-.2 .6h.5M66.4 172h-.3l-.1 .4 .4-.1v.5h-.4M66.4 173.7l-.2 .1-.2 .7h.5l-.2-.5-.3 .2"/>
<path d="M66.4 170.6v.6M66.5 179.3l-.3 .1-.2-.4 .2-.1 .3 .1-.2 .7-.2 .1M72.1 163.9a.53 .53 0 0 1 .8 .2l-.1 .2h-.6zM72.9 164.6v.5l-.6-.5-.2 .1v.4M79.4 167.1l.2-.3v.9M79.4 168.8l.2-.3v.9M79.4 170.6l.2-.3v.9M79.4 172.3l.2-.3v.8M79.4 173.9l.2-.2v.8M79.4 175.7l.2-.2v.8M79.4 177.4l.2-.2v.8M79.4 179.1l.2-.2v.9"/>
<path d="M79.4 167.7h.5M79.4 169.4h.5M79.4 171.2h.5M79.4 172.8h.5M79.4 174.5h.5M79.4 176.3h.5M79.4 178h.5M79.4 179.8h.5M80.1 168.5h.6l-.3 .9M80.1 175.5h.6l-.3 .3 .3 .1v.2l-.1 .2-.5-.1M80.2 177.2h.4l.1 .2-.6 .6h.6M80.2 179.1l.3-.2v.9"/>
<path d="M80.2 179.8h.5M80.4 167.2l-.2-.3 .4-.1v.4l-.4 .1 .1 .4h.3l.1-.4-.1-.1M80.4 173.7l-.2 .6h.5M80.6 170.3l-.4 .2v.6l.4 .1 .1-.5-.1-.1-.4 .1M80.6 172h-.4v.4l.4-.1v.5h-.4M80.6 174v.5M97 166.9h.5v.3l-.5 .5h.5M97 168.5h.5l-.3 .4h.3v.4h-.5M97 175.5h.6l-.4 .8M97.2 177.5l-.2-.2 .1-.1h.3l.1 .2-.5 .3 .1 .3 .4-.1v-.3l-.2-.1M97.2 170.2l-.2 .6h.6M97.4 173.7l-.2 .1-.2 .7h.5v-.4l-.3-.1-.2 .2"/>
<path d="M97.4 170.6v.6M97.5 172h-.4l-.1 .4 .4-.1 .1 .5h-.5M97.5 179.3l-.3 .1-.2-.4 .2-.1h.3v.6l-.4 .3M103.1 164a.48 .48 0 0 1 .5-.2 .48 .48 0 0 1 .3 .3l-.1 .2h-.6l-.1-.1zM103.9 164.6v.5l-.6-.5-.2 .1 .1 .4M110.4 167.1l.2-.3v.9M110.4 168.8l.2-.3v.9M110.4 170.6l.2-.3v.9M110.4 172.3l.2-.3v.8M110.4 173.9l.2-.2v.8M110.4 175.7l.2-.2v.8M110.4 177.4l.2-.2v.8"/>
<path d="M110.4 179.1l.2-.2v.9M110.4 167.7h.5M110.4 169.4h.5M110.4 171.2h.5M110.4 172.8h.5M110.4 174.5h.5M110.4 176.3h.5M110.4 178h.5M110.4 179.8h.5M111.1 168.5h.6l-.3 .9M111.1 175.5h.6l-.3 .3 .3 .1v.2l-.2 .2-.4-.1M111.2 177.2h.4l.1 .2-.6 .6h.6"/>
<path d="M111.2 179.1l.3-.2v.9M111.2 179.8h.5M111.4 167.2l-.2-.3 .4-.1v.4l-.4 .1 .1 .4h.3l.1-.4-.2-.1M111.4 173.7l-.2 .6h.5M111.6 170.3l-.4 .2v.6l.3 .1 .2-.5-.2-.1-.3 .1M111.6 172h-.4v.4l.4-.1v.5h-.4M111.6 174v.5M126.3 166.9h.5v.3l-.5 .5h.5M126.3 168.5h.5l-.3 .4h.3v.4h-.5M126.3 175.5h.6l-.5 .8M126.4 177.5l-.1-.2 .1-.1h.3l.1 .2-.5 .3 .1 .3h.3l.1-.4-.2-.1M126.5 170.2l-.2 .6h.6"/>
<path d="M126.7 173.7l-.3 .1-.1 .7h.5v-.4l-.4-.1-.1 .2M126.7 170.6v.6M126.8 172h-.4l-.1 .4 .4-.1 .1 .5h-.5M126.8 179.3l-.4 .1-.1-.4 .1-.1h.4v.6l-.4 .3M132.4 164a.48 .48 0 0 1 .4-.2 .48 .48 0 0 1 .4 .3l-.1 .2h-.6l-.1-.1zM133.2 164.6v.5l-.6-.5-.2 .1 .1 .4M139.7 167.1l.2-.3v.9M139.7 168.8l.2-.3v.9M139.7 170.6l.2-.3v.9M139.7 172.3l.2-.3v.8M139.7 173.9l.2-.2v.8M139.7 175.7l.2-.2v.8"/>
<path d="M139.7 177.4l.2-.2v.8M139.7 179.1l.2-.2v.9M139.7 167.7h.5M139.7 169.4h.5M139.7 171.2h.5M139.7 172.8h.5M139.7 174.5h.5M139.7 176.3h.5M139.7 178h.5M139.7 179.8h.5M140.4 168.5h.6l-.3 .9M140.4 175.5h.6l-.3 .3h.2l.1 .3-.2 .2-.4-.1"/>
<path d="M140.5 177.2h.4l.1 .2-.6 .6h.6M140.5 179.1l.3-.2v.9M140.5 179.8h.5M140.7 167.2l-.2-.3 .4-.1v.4l-.4 .1v.3l.4 .1 .1-.4-.2-.1M140.7 173.7l-.2 .6h.5M140.9 170.3l-.4 .2v.6l.3 .1 .2-.5-.2-.1-.3 .1M140.9 172h-.4v.4l.4-.1v.5h-.4M140.9 174v.5M162.9 164.2h.5l-.3 .3 .3 .2v.3l-.1 .1h-.4M163.1 160.7l-.2 .6h.5M163.1 162.5l-.2 .6h.5M163.4 161.1v.6"/>
<path d="M163.4 162.8v.6M163.7 161.1l.3-.3v.9M163.7 161.7h.5M163.8 162.6l.2-.1 .2 .2-.1 .6a.39 .39 0 0 1-.4-.2 .39 .39 0 0 1 .1-.5zM164.2 164.6l-.3 .2-.2-.4 .2-.2 .3 .1-.1 .8h-.3M169.4 170.9h-.9l.3 .3M169.4 169.9v.5l-.5-.5-.4 .1 .1 .3M169.4 170.6v.6M170.2 171.2v-.6l.4 .4 .1-.4 .4 .1-.1 .5M170.6 170h.5M170.8 169.8v.5l-.6-.2M202.5 164.2h.6l-.4 .3 .4 .2v.3l-.2 .1h-.4"/>
<path d="M202.7 160.7l-.1 .6h.5M202.7 162.5l-.1 .6h.5M203 161.1v.6M203 162.8v.6M203.3 161.1l.3-.3v.9M203.3 161.7h.5M203.4 162.6l.3-.1 .1 .2-.1 .6a.39 .39 0 0 1-.4-.2 .39 .39 0 0 1 .1-.5zM203.8 164.6l-.3 .2-.2-.4 .2-.2 .3 .1v.6l-.4 .2M209 170.9h-.9l.3 .3M209 169.9v.5l-.5-.5-.4 .1 .1 .3M209 170.6v.6M209.8 171.2v-.6l.4 .4 .2-.4 .3 .1-.1 .5"/>
<path d="M210.2 170h.5M210.4 169.8v.5l-.6-.2M65.6 184.3l.2-.3v1M65.6 185h.5M66 182.6l.2-.3v.9M66 183.2h.5M66.9 184.4l-.1 .2-.4-.1v-.4l.4-.1 .1 .2-.1 .7-.3 .1M72.1 188a.53 .53 0 0 1 .8 .3l-.1 .1h-.6zM72.9 189h-.8l.2 .3M72.9 188.8v.5M96.6 184.3l.2-.3v1M96.6 185h.5"/>
<path d="M97 182.6l.2-.3v.9M97 183.2h.5M97.9 184.4l-.3 .2-.2-.4 .2-.2 .3 .1-.1 .8-.3 .1M103.1 188.1a.48 .48 0 0 1 .5-.2 .48 .48 0 0 1 .3 .4l-.1 .1h-.6l-.1-.1zM103.9 189h-.8l.2 .3M103.9 188.8v.5M125.9 184.3l.2-.3v1M125.9 185h.5M126.3 182.6l.2-.3v.9M126.3 183.2h.5M127.2 184.4l-.3 .2-.2-.4 .2-.2 .3 .2-.2 .7-.2 .1M132.4 188.1a.48 .48 0 0 1 .4-.2 .48 .48 0 0 1 .4 .4l-.1 .1h-.6l-.1-.1z"/>
<path d="M133.2 189h-.8l.2 .3M133.2 188.8v.5"/>
</g>
<g fill="none" stroke="#006665" stroke-width=".21">
<path d="M37.7 28.7v1M37.7 30.5v.9M37.7 32.2v.9M37.7 34v.8M37.7 35.7v.8M37.7 37.4v.8M37.7 39.2v.8M38.7 28.7l-.7 1.1M38.7 30.4l-.7 1.1M38.7 32.2l-.7 1.1M38.7 33.9l-.7 1.1M38.7 35.6l-.7 1.1"/>
<path d="M38.7 37.4l-.7 1.1M38.7 39.1l-.7 1.1M39 30.6h.5l-.1 .8-.4-.1zM39 34.1h.5v.6l-.2 .1-.3-.1zM39 35.8h.5l-.1 .7-.4-.1zM39 39.2h.5v.6l-.2 .2-.3-.2zM39.2 37.4l.3 .1-.1 .7-.4-.1v-.6zM39.4 28.8l-.2-.1-.2 .3v.4l.2 .3 .3-.1v-.4h-.2M39.4 32.3l-.2-.1-.2 .3v.4l.2 .2 .3-.1v-.3h-.2M39.9 30.9h.3M39.9 34.3h.3M40.3 28.8l-.2-.1-.3 .3v.4l.3 .3 .2-.1"/>
<path d="M40.3 30.5h-.4v.9h.4M40.3 32.3l-.2-.1-.3 .3v.4l.2 .2 .3-.1M40.3 34h-.4v.8h.4M40.5 35.6l-.8 1.1M40.5 39.1l-.8 1.1M40.7 30.6l.3-.1 .1 .4-.5 .5h.5M40.7 34.2l.1-.2v.8M40.7 34.8h.4M40.7 39.2h.5M40.8 28.7v1h.3M40.8 32.2v.9h.3M40.8 36.1h.4l.1-.3-.5-.1v.8"/>
<path d="M40.9 39.2v.8M41.4 29.2h.4l.1-.3-.1-.2h-.4v1M41.4 39.2h.4l.1 .1v.4l-.2 .3h-.3zM41.4 32.2v.9M41.5 32.6l.4 .5M41.6 29.2l.3 .5M41.7 35.7l.4 .1-.1 .7h-.3zM41.9 32.2l-.5 .5M42.1 30.4l-.7 1.1M42.1 33.9l-.7 1.1M42.2 32.5l.3-.3v.9M42.2 33.1h.5"/>
<path d="M42.3 34l.2 .8 .4-.8M42.3 39.2v.8M42.5 35.9l.2-.2v.8M42.5 36.5h.5M42.9 30.5h-.4l-.1 .2v.5l.1 .2h.4v-.4h-.2M43.1 34.8h.3l.2-.1-.1-.5h-.4v.9M43.7 30.6l-.3-.1-.2 .4 .2 .5 .3-.1M43.9 34.8h.4l-.1-.6h-.3v.9M44.2 30.5v.9h.4M44.8 30.5v.9M44.9 30.9l.4 .5M45.3 30.5l-.5 .5"/>
<path d="M45.7 30.6l.3-.1 .1 .4-.5 .5h.5M46.9 25.5l.8 .4-.8 .2M46.9 24.8v.3l.1 .2h.5l.2-.3-.1-.2M46.9 23.9v.4l.1 .1h.5l.2-.2-.1-.3M48.6 25.5l.8 .4-.8 .2M48.6 24.8v.2l.1 .3h.5l.2-.2-.1-.3M48.6 23.9v.3l.1 .2h.5l.2-.1-.1-.4M52 26.7l.9 .3-.9 .3M52 24.8h.1M52.1 25.9l-.1 .4 .2 .2h.4l.3-.3-.1-.3M52.1 25.1l-.1 .3 .2 .2h.4l.3-.2-.1-.3M52.3 24.8h.6"/>
<path d="M52.4 23.9h.4v.4h-.4zM53.7 26.7l.9 .3-.9 .3M53.7 24.8h.1M53.8 25.9l-.1 .3 .3 .3h.4l.2-.2-.1-.4M53.8 25.1l-.1 .3 .3 .2h.4l.2-.2-.1-.3M54 24.8h.6M54.1 23.9h.4l.1 .4h-.5zM55.4 26.7l.9 .3-.9 .3M55.4 24.8h.1M55.5 25.9l-.1 .3 .3 .3h.4l.2-.3v-.3M55.5 25.1l-.1 .3 .3 .2h.4l.2-.2v-.3M55.7 24l.6-.1v.3v.1h-.5z"/>
<path d="M55.7 24.8h.6M57.2 26.7l.8 .3-.8 .3M57.2 24.8h.1M57.3 25.9l-.1 .4 .2 .2h.5l.1-.3v-.3M57.3 25.1l-.1 .3 .2 .2h.5l.1-.2v-.3M57.4 24.8h.6M57.5 23.9h.5v.4h-.5zM58.9 26.7l.8 .3-.8 .3M58.9 24.8h.1M59 25.9l-.1 .3 .2 .3h.5l.1-.2-.1-.4M59 25.1l-.1 .3 .2 .2h.5l.1-.2-.1-.3M59.2 23.9h.4l.1 .4h-.5z"/>
<path d="M59.2 24.8h.5M60.6 26.7l.9 .3-.9 .3M60.6 24.8h.1M60.7 25.9l-.1 .3 .2 .3h.5l.2-.3-.1-.3M60.7 25.1l-.1 .3 .2 .2h.5l.2-.2-.1-.3M60.9 24l.5-.1 .1 .3-.1 .1h-.4zM60.9 24.8h.6M68.9 32.2v.9M68.9 34v.8M68.9 35.7v.8M68.9 37.4v.8M68.9 39.2v.8"/>
<path d="M69.9 32.2l-.7 1.1M69.9 33.9l-.7 1.1M69.9 35.6l-.7 1.1M69.9 37.4l-.7 1.1M69.9 39.1l-.7 1.1M70.2 34.1h.5v.6l-.1 .1a.47 .47 0 0 1-.4-.2 .47 .47 0 0 1 0-.5zM70.2 35.8h.5v.7l-.5-.1zM70.2 39.2h.5v.6l-.1 .2a.47 .47 0 0 1-.4-.3 .47 .47 0 0 1 0-.5zM70.4 32.2l.3 .2v.6h-.5a.52 .52 0 0 1 .2-.8zM70.4 37.4l.3 .1v.6h-.5a.52 .52 0 0 1 .2-.7zM104 21.9a.49 .49 0 0 1 .5 .3 .49 .49 0 0 1-.2 .5h-.3zM104 23.6a.47 .47 0 0 1 .5 .4 .47 .47 0 0 1-.5 .5z"/>
<path d="M104 25.4h.3a.47 .47 0 0 1 .2 .5 .47 .47 0 0 1-.5 .3zM104 27a.49 .49 0 0 1 .5 .4 .49 .49 0 0 1-.2 .5h-.3zM104 28.7a.47 .47 0 0 1 .5 .5 .47 .47 0 0 1-.5 .5zM104 30.5l.4 .1 .1 .4-.2 .4h-.3zM104 32.2a.49 .49 0 0 1 .5 .3 .49 .49 0 0 1-.2 .6h-.3zM104 34h.3a.48 .48 0 0 1 .2 .5 .48 .48 0 0 1-.5 .3zM104 37.4v.8h.4M104 39.2h.5v.6l-.2 .2a.47 .47 0 0 1-.4-.3 .47 .47 0 0 1 .1-.5zM104.7 37.8h.3M104.8 27h.5l-.3 .4h.3v.5l-.5-.1M104.8 34h.6l-.4 .8M104.9 22.1l.1-.2 .3 .1-.1 .7h-.3z"/>
<path d="M104.9 23.8l.2-.2v.9M104.9 25.4h.4v.3l-.5 .5h.5M104.9 24.5h.4M104.9 39.5h.3M105 28.7l-.1 .6h.5M105.1 37.4h-.4v.8h.4M105.3 30.5h-.4v.4h.4v.5l-.4-.1M105.3 32.2l-.4 .3v.5l.4 .1-.1-.5-.3 .1M105.3 39.2h-.4v.8h.4M105.3 29.1v.6M108 23l.8 .2-.8 .3M108 39.2h.8l-.8 .5h.8"/>
<path d="M108 38.5l.3-.2 .5 .1v.4h-.8zM108.1 22.1l-.1 .5 .3 .1 .5-.1v-.5M108.1 21.3l-.1 .4 .3 .2 .5-.2v-.4M111.6 25.4h.4l.1 .2v.3l-.2 .3-.4-.3zM111.6 30.5h.4l.1 .3-.1 .6h-.4zM111.6 34l.5 .1a.47 .47 0 0 1-.4 .7l-.2-.3zM111.7 21.9l.4 .2-.1 .6h-.4l-.1-.2zM111.7 23.6a.47 .47 0 0 1 .5 .4 .47 .47 0 0 1-.5 .5l-.2-.3zM111.7 27a.47 .47 0 0 1 .4 .4 .47 .47 0 0 1-.1 .5h-.4l-.1-.3zM111.7 28.7a.47 .47 0 0 1 .5 .5 .47 .47 0 0 1-.5 .5l-.2-.4zM111.7 32.2a.47 .47 0 0 1 .4 .3 .47 .47 0 0 1-.1 .6h-.4l-.1-.3zM112.4 27h.5l-.3 .4h.3v.5l-.5-.1"/>
<path d="M112.4 34h.6l-.4 .8M112.5 22.1l.1-.2 .3 .1-.1 .7h-.2zM112.5 23.8l.2-.2v.9M112.5 25.4h.4v.3l-.5 .5h.5M112.5 24.5h.4M112.6 28.7l-.1 .6h.5M112.9 30.5h-.4v.4h.4v.5l-.4-.1M112.9 32.2l-.4 .3v.5l.4 .1-.1-.5-.3 .1M112.9 29.1v.6M134.5 21.9v.8M134.5 23.6v.9M134.5 27v.9"/>
<path d="M134.5 28.7v1M134.5 32.2v.9M134.5 34v.8M134.5 37.4v.8M134.5 39.2v.8M134.8 23.8l.3-.2v.9M134.8 29l.3-.3v1M134.8 34.2l.3-.2v.8M134.8 39.3l.3-.1v.8M134.8 24.5h.5M134.8 29.7h.5M134.8 34.8h.5"/>
<path d="M134.9 22l.3-.1 .1 .2v.5a.39 .39 0 0 1-.5-.2 .39 .39 0 0 1 .1-.4zM134.9 27.1l.3-.1 .1 .2v.6a.39 .39 0 0 1-.5-.2 .39 .39 0 0 1 .1-.5zM134.9 32.3l.3-.1 .1 .2v.6a.39 .39 0 0 1-.5-.2 .39 .39 0 0 1 .1-.5zM134.9 37.5l.3-.1 .1 .1v.7h-.3l-.2-.2zM135.8 22.2l.2-.1 .1 .2v.4h-.3l-.1-.1 .1-.2h.3M135.8 23.9l.3 .1v.5M135.8 27v.9h.2l.1-.5h-.3M135.8 29.1l.3 .1v.4h-.3M135.8 28.7v1M136.1 24.1l-.4 .2 .1 .2 .3-.1M136.1 32.6h-.4l.1 .5h.3M136.1 34.2h-.3l-.1 .2 .1 .4h.3"/>
<path d="M136.1 37.4v.8h-.3v-.5h.3M136.1 39.4h-.3l-.1 .2 .1 .4 .3-.1M136.1 39.2v.8M138.1 23.3l.9 .3-.9 .3M138.2 22.6l-.1 .3 .4 .2 .5-.2-.1-.3M138.2 21.6l-.1 .5 .4 .1 .5-.1-.1-.5M141.4 21.9h.6l-.6 .8h.6M141.4 27h.6l-.6 .9h.6M141.4 32.2h.6l-.6 .9h.6M141.4 37.4h.6l-.6 .8h.6M142.4 22.2h.3v.5h-.3l-.1-.1 .1-.2h.3M142.4 27v.9h.3v-.5h-.3"/>
<path d="M142.7 32.6h-.3v.4l.3 .1M142.7 37.4v.8h-.3v-.5h.3M164.6 21.9v.8M164.6 23.6v.9M164.6 27v.9M164.6 28.7v1M164.6 32.2v.9M164.6 34v.8M164.6 37.4v.8M164.6 39.2v.8M165 23.8l.2-.2v.9M165 29l.2-.3v1"/>
<path d="M165 34.2l.2-.2v.8M165 39.3l.2-.1v.8M165 24.5h.5M165 29.7h.5M165 34.8h.5M165.1 22l.2-.1 .2 .2-.1 .5a.39 .39 0 0 1-.4-.2 .39 .39 0 0 1 .1-.4zM165.1 27.1l.2-.1 .2 .2-.1 .6a.39 .39 0 0 1-.4-.2 .39 .39 0 0 1 .1-.5zM165.1 32.3l.2-.1 .2 .2-.1 .6a.39 .39 0 0 1-.4-.2 .39 .39 0 0 1 .1-.5zM165.1 37.5l.2-.1 .2 .1-.1 .7h-.3l-.1-.2zM165.9 22.2h.3v.5h-.3l-.1-.1 .2-.2h.2M165.9 23.9h.3v.6M165.9 27v.9h.3l.1-.4-.4-.1"/>
<path d="M165.9 29.1h.3l.1 .1-.1 .5-.3-.1M165.9 28.7v1M166.2 24.1l-.4 .2 .2 .2 .2-.1M166.2 32.6h-.4l.1 .5h.3M166.2 34.2h-.3l-.1 .2 .2 .4h.2M166.2 37.4v.8h-.3v-.5h.3M166.2 39.4h-.3l-.1 .2 .2 .4 .2-.1M166.2 39.2v.8M168.3 23.3l.8 .3-.8 .3M168.4 22.6a.42 .42 0 0 0 .2 .5 .42 .42 0 0 0 .5-.2l-.1-.3M168.4 21.6a.44 .44 0 0 0 .1 .6 .44 .44 0 0 0 .6-.1l-.1-.5M171.6 21.9h.6l-.6 .8h.6"/>
<path d="M171.6 27h.6l-.6 .9h.6M171.6 37.4h.6l-.6 .8h.6M171.7 32.2h.5l-.5 .9h.5M172.5 22.2h.3v.5h-.3l-.1-.1 .2-.2h.2M172.5 27v.9h.3l.1-.4-.4-.1M172.8 37.4v.8h-.3v-.5h.3M172.9 32.6h-.4l.1 .5h.3M194.8 21.9v.8M194.8 23.6v.9M194.8 27v.9M194.8 28.7v1M194.8 32.2v.9"/>
<path d="M194.8 34v.8M194.8 37.4v.8M194.8 39.2v.8M195.2 23.8l.2-.2v.9M195.2 29l.2-.3v1M195.2 34.2l.2-.2v.8M195.2 39.3l.2-.1v.8M195.2 24.5h.4M195.2 29.7h.4M195.2 34.8h.4M195.4 21.9l.2 .2-.1 .6h-.2l-.1-.1v-.5zM195.4 27l.2 .2-.1 .7h-.2l-.1-.2v-.5z"/>
<path d="M195.4 32.2l.2 .2-.1 .7h-.2l-.1-.2v-.5zM195.4 37.4l.2 .1-.1 .7h-.2l-.1-.1v-.6zM196 22.2h.4v.5h-.4v-.1l.4-.2M196 23.9h.4v.6M196 27v.9h.4l.1-.4-.5-.1M196 29.1h.4l.1 .1-.2 .5-.3-.1M196 28.7v1M196.4 24.1l-.4 .2 .1 .2 .3-.1M196.4 32.6h-.4v.5h.4M196.4 34.2h-.4v.2l.1 .4h.3M196.4 37.4v.8h-.4v-.5h.4M196.4 39.4h-.4v.2l.1 .4 .3-.1"/>
<path d="M196.4 39.2v.8M198.4 23.3l.9 .3-.9 .3M198.5 22.6a.43 .43 0 0 0 .2 .4 .43 .43 0 0 0 .6-.1l-.1-.3M198.5 21.6a.44 .44 0 0 0 .2 .6 .44 .44 0 0 0 .6-.1l-.1-.5M201.7 21.9h.6l-.6 .8h.6M201.7 27h.6l-.6 .9h.6M201.7 37.4h.6l-.6 .8h.6M201.8 32.2h.5l-.5 .9h.5M202.6 22.2h.4v.5h-.4v-.1l.1-.2h.3M202.6 27v.9h.4l.1-.4-.5-.1M203 37.4v.8h-.4v-.5h.4M203.1 32.6h-.5l.1 .5h.4"/>
<path d="M225.8 21.9v.8M225.8 23.6v.9M225.8 27v.9M225.8 28.7v1M225.8 32.2v.9M225.8 34v.8M225.8 37.4v.8M225.8 39.2v.8M226.2 23.8l.2-.2v.9M226.2 29l.2-.3v1M226.2 34.2l.2-.2v.8M226.2 39.3l.2-.1v.8"/>
<path d="M226.2 24.5h.5M226.2 29.7h.5M226.2 34.8h.5M226.4 21.9a.43 .43 0 0 1 .3 .4 .43 .43 0 0 1-.4 .4l-.1-.6zM226.4 27a.43 .43 0 0 1 .3 .5 .43 .43 0 0 1-.4 .4l-.1-.7zM226.4 32.2a.43 .43 0 0 1 .3 .5 .43 .43 0 0 1-.4 .4l-.1-.7zM226.4 37.4a.43 .43 0 0 1 .3 .4 .43 .43 0 0 1-.4 .4l-.1-.7zM227 22.2h.4v.5h-.4l-.1-.1 .2-.2h.3M227 23.9h.4v.6M227 27v.9h.4l.1-.4-.5-.1M227 29.1h.4l.1 .1-.2 .5-.3-.1M227 28.7v1"/>
<path d="M227.4 24.1l-.5 .2 .2 .2 .3-.1M227.4 32.6h-.5l.1 .5h.4M227.4 34.2h-.4l-.1 .2 .2 .4h.3M227.4 37.4v.8h-.4v-.5h.4M227.4 39.4h-.4l-.1 .2 .2 .4 .3-.1M227.4 39.2v.8M229.4 23.3l.8 .3-.8 .3M229.5 22.6a.43 .43 0 0 0 .2 .4 .43 .43 0 0 0 .5-.1v-.3M229.5 21.6a.44 .44 0 0 0 .2 .6 .44 .44 0 0 0 .5-.1v-.5M232.7 21.9h.6l-.6 .8h.6M232.7 27h.6l-.6 .9h.6M232.7 37.4h.6l-.6 .8h.6"/>
<path d="M232.8 32.2h.6l-.6 .9h.6M233.6 22.2h.4v.5h-.4l-.1-.1 .2-.2h.3M233.6 27v.9h.4l.1-.4-.5-.1M234 37.4v.8h-.4v-.5h.4M234.1 32.6h-.5l.1 .5h.4M257.7 21.9v.8M257.7 23.6v.9M257.7 27v.9M257.7 28.7v1M257.7 32.2v.9M257.7 34v.8M257.7 37.4v.8"/>
<path d="M257.7 39.2v.8M258 23.8l.3-.2v.9M258 29l.3-.3v1M258 34.2l.3-.2v.8M258 39.3l.3-.1v.8M258 24.5h.5M258 29.7h.5M258 34.8h.5M258.1 22h.3v.7l-.3-.1zM258.1 27.1h.3v.8l-.3-.1zM258.1 32.3h.3v.8l-.3-.1zM258.1 37.5h.3v.7h-.2l-.2-.2z"/>
<path d="M258.9 22.2l.2-.1 .2 .2v.4h-.4v-.3h.4M258.9 23.9l.4 .1v.5M258.9 27v.9h.3l.1-.5h-.4M258.9 29.1l.4 .1v.4h-.4M258.9 28.7v1M259.3 24.1l-.4 .1v.3l.4-.1M259.3 32.6h-.4v.5h.4M259.3 34.2l-.4 .1v.5h.4M259.3 37.4v.8h-.4v-.4l.4-.1M259.3 39.4l-.4 .1v.4h.4M259.3 39.2v.8M261.3 23.3l.9 .3-.9 .3"/>
<path d="M261.4 22.6l-.1 .3a.43 .43 0 0 0 .5 .1 .43 .43 0 0 0 .3-.4M261.4 21.6l-.1 .5a.44 .44 0 0 0 .6 .1 .44 .44 0 0 0 .2-.6M264.6 21.9h.5l-.5 .8h.5M264.6 27h.5l-.5 .9h.5M264.6 32.2h.6l-.6 .9h.6M264.6 37.4h.5l-.5 .8h.5M265.5 22.2l.2-.1 .2 .2v.4h-.4l.1-.3h.3M265.5 27v.9h.3l.1-.5h-.4M265.9 32.6h-.4l.1 .5h.3M265.9 37.4v.8h-.3l-.1-.4 .4-.1M37.7 40.8v.9M37.7 42.5v.9"/>
<path d="M37.7 44.3v.9M37.7 46v.9M37.7 47.7v.9M37.7 49.5v.8M37.7 51.2v.8M37.7 52.9v.8M37.7 54.6v.9M37.7 56.3v.9M37.7 58v1M37.7 59.8v.9M38.7 40.8l-.7 1.1M38.7 42.5l-.7 1.1"/>
<path d="M38.7 44.2l-.7 1.1M38.7 45.9l-.7 1.2M38.7 47.7l-.7 1.1M38.7 49.4l-.7 1.1M38.7 51.1l-.7 1.2M38.7 52.9l-.7 1.1M38.7 54.6l-.7 1.1M38.7 56.3l-.7 1.1M38.7 58l-.7 1.1M38.7 59.7l-.7 1.1M39 44.4h.5v.6l-.2 .2-.3-.2zM39 46.1h.5l-.1 .8-.4-.1z"/>
<path d="M39 49.6h.5v.6l-.2 .1-.3-.1zM39 51.3h.5l-.1 .7-.4-.1zM39 54.7h.5v.6l-.2 .2-.3-.2zM39 56.4h.5l-.1 .8-.4-.1zM39 59.9h.5v.6l-.2 .2-.3-.2zM39.1 40.8l.4 .1-.1 .8-.4-.1zM39.2 42.5l.3 .2-.1 .7-.4-.1v-.6zM39.2 47.7l.3 .2-.1 .7-.4-.1v-.6zM39.2 52.9l.3 .1-.1 .7-.4-.1v-.6zM39.2 58l.3 .2v.6l-.2 .2-.3-.2v-.6zM40.5 56.3l-.8 1.1M40.7 56.3h.5"/>
<path d="M40.9 56.3v.9M41.4 57.2v-.9l.4 .6 .2-.6v.9M42.9 56.3h-.4l-.1 .2 .1 .3 .4 .1v.2l-.5 .1M63.9 46v.9M64.9 45.9l-.7 1.2M65.2 46.1l.4-.1 .1 .3-.1 .6h-.3l-.2-.3zM66.8 45.9l-.8 1.2M67.4 46h-.3l-.2 .4 .2 .5 .4-.1v-.3h-.2M68.4 46.1l-.4-.1-.1 .2v.5l.1 .2 .4-.1M68.7 46v.9h.4M68.9 40.8v.9M68.9 42.5v.9"/>
<path d="M68.9 44.3v.9M68.9 47.7v.9M68.9 49.5v.8M68.9 51.2v.8M68.9 52.9v.8M68.9 54.6v.9M68.9 56.3v.9M68.9 58v1M68.9 59.8v.9M69.5 46v.9M69.6 46.4l.3 .5M69.9 40.8l-.7 1.1"/>
<path d="M69.9 42.5l-.7 1.1M69.9 44.2l-.7 1.1M69.9 46l-.4 .5M69.9 47.7l-.7 1.1M69.9 49.4l-.7 1.1M69.9 51.1l-.7 1.2M69.9 52.9l-.7 1.1M69.9 54.6l-.7 1.1M69.9 56.3l-.7 1.1M69.9 58l-.7 1.1M69.9 59.7l-.7 1.1M70.2 40.9h.5v.8l-.5-.1z"/>
<path d="M70.2 44.4h.5v.6l-.1 .2a.47 .47 0 0 1-.4-.3 .47 .47 0 0 1 0-.5zM70.2 46h.5l-.2 .4h.2v.4h-.5M70.2 49.6h.5v.6l-.1 .1a.47 .47 0 0 1-.4-.2 .47 .47 0 0 1 0-.5zM70.2 51.3h.5v.7l-.5-.1zM70.2 54.7h.5v.6l-.1 .2a.47 .47 0 0 1-.4-.3 .47 .47 0 0 1 0-.5zM70.2 56.4h.5v.8l-.5-.1zM70.2 59.9h.5v.6l-.1 .2a.47 .47 0 0 1-.4-.3 .47 .47 0 0 1 0-.5zM70.4 42.5l.3 .2v.6h-.5a.52 .52 0 0 1 .2-.8zM70.4 47.7l.3 .2v.6h-.5a.52 .52 0 0 1 .2-.8zM70.4 52.9l.3 .1v.6h-.5a.52 .52 0 0 1 .2-.7zM70.4 58l.3 .2v.6l-.1 .2a.49 .49 0 0 1-.5-.4 .49 .49 0 0 1 .3-.6zM104 58a.47 .47 0 0 1 .5 .5 .47 .47 0 0 1-.5 .5z"/>
<path d="M104 59.8h.3a.47 .47 0 0 1 .2 .6 .47 .47 0 0 1-.5 .3zM105 58l.3 .1v.8l-.2 .1-.2-.2v-.6zM108 40.2l.2 .4h.5l.1-.2v-.3h-.3v.2M108 59.1l.8 .3-.8 .3M108.1 58.4l-.1 .3 .2 .2h.5l.1-.2v-.3M108.1 57.5l-.1 .4 .3 .1 .5-.1v-.4M111.6 59.8l.5 .1a.47 .47 0 0 1-.4 .8l-.2-.4zM111.7 58a.47 .47 0 0 1 .5 .5 .47 .47 0 0 1-.5 .5l-.2-.4zM112.6 58l.3 .1v.8l-.2 .1-.2-.2v-.6zM134.5 44.7h.2M134.8 40h.5M134.9 42.6h-.4v.3l.4 .2-.1 .3h-.3"/>
<path d="M134.9 44.3h-.4v.9h.4M138.1 45l.2 .4h.5l.2-.1-.1-.4h-.3v.2M138.1 44.1h.9l-.9 .5h.9M138.1 43.3l.4-.2 .4 .1 .1 .4h-.9zM143.1 57.2v.8M143.1 59v.8M143.5 59.1l.2-.1v.8M143.5 59.8h.5M143.5 57.3l.3-.1 .2 .2-.1 .6a.39 .39 0 0 1-.4-.3 .39 .39 0 0 1 0-.4zM144.3 57.5l.4 .1v.4h-.4l.1-.3h.3M144.3 59.2l.4 .1v.5M144.7 59.4l-.4 .1 .1 .3 .3-.1"/>
<path d="M146.8 58.6l.8 .3-.8 .3M146.9 57.9l-.1 .3a.42 .42 0 0 0 .5 .2 .42 .42 0 0 0 .2-.5M146.9 56.9l-.1 .5a.44 .44 0 0 0 .5 .1 .44 .44 0 0 0 .2-.6M150.1 57.2h.5l-.5 .8h.5M150.9 57.5l.4 .1v.4h-.4l.1-.3h.3M164.6 44.7h.4M165 40h.5M165.1 42.6h-.5v.3l.5 .2-.1 .3h-.4M165.1 44.3h-.5v.9h.5M168.3 44.1h.8l-.8 .5h.8M168.4 45l-.1 .2 .1 .2h.5l.2-.1-.1-.4h-.2v.2M168.4 43.3l.2-.2 .4 .1 .1 .4h-.8z"/>
<path d="M174.1 57.2v.8M174.1 59v.8M174.5 59.1l.2-.1v.8M174.5 59.8h.5M174.5 57.3l.3-.1 .2 .2-.1 .6a.39 .39 0 0 1-.5-.3 .39 .39 0 0 1 .1-.4zM175.4 57.5l.3 .1v.4h-.3l-.1-.1 .4-.2M175.4 59.2l.3 .1v.5M175.7 59.4l-.4 .2 .2 .2 .2-.1M177.8 58.6l.8 .3-.8 .3M177.8 57.9v.3l.3 .2 .5-.2-.1-.3M177.8 56.9v.5l.3 .1 .5-.1-.1-.5M181.1 57.2h.5l-.5 .8h.5"/>
<path d="M182 57.5l.3 .1v.4h-.3l-.1-.1 .2-.2h.2M194.8 44.7h.3M195.2 44.3h-.4v.9h.4M195.2 40h.4M195.3 42.6h-.5v.3l.5 .3-.1 .2h-.4M198.4 44.1h.9l-.9 .5h.9M198.5 45l-.1 .2 .3 .2h.4l.2-.1-.1-.4h-.3v.2M198.5 43.3l.3-.2 .4 .1 .1 .4h-.9zM206.9 57.2v.8M206.9 59v.8M207.2 59.1l.3-.1v.8M207.2 59.8h.5"/>
<path d="M207.4 57.2a.43 .43 0 0 1 .3 .5 .43 .43 0 0 1-.4 .3l-.1-.6zM208.1 57.5h.3v.5h-.3v-.3h.3M208.1 59.2h.3v.6M208.4 59.4l-.3 .1v.3l.3-.1M210.5 58.6l.9 .3-.9 .3M210.5 57.9v.3a.43 .43 0 0 0 .5 .1 .43 .43 0 0 0 .3-.4M210.5 56.9v.5a.44 .44 0 0 0 .6 .1 .44 .44 0 0 0 .2-.6M213.7 57.2h.6l-.6 .8h.6M214.7 57.5l.4 .1v.4h-.4l.1-.3h.3M225.8 44.7h.3M226.2 44.3h-.4v.9h.4M226.2 40h.5"/>
<path d="M226.3 42.6h-.5v.3l.5 .3-.1 .2h-.4M229.4 44.1h.8l-.8 .5h.8M229.5 45l-.1 .2 .3 .2h.4l.1-.1v-.4h-.3v.2M229.6 43.2h.6v.4h-.8zM239.6 57.2v.8M239.6 59v.8M240 57.3l.2-.1 .2 .2-.1 .6h-.3zM240 59.1l.2-.1v.8M240 59.8h.4M240.8 57.5h.4v.5h-.4l-.1-.1 .5-.2M240.8 59.2h.4v.6M241.2 59.4l-.5 .2 .2 .2 .3-.1"/>
<path d="M243.2 58.6l.8 .3-.8 .3M243.3 57.9l-.1 .1a.48 .48 0 0 0 .4 .4 .48 .48 0 0 0 .4-.2v-.3M243.3 56.9a.44 .44 0 0 0 .2 .6 .44 .44 0 0 0 .5-.1v-.5M246.5 57.2h.6l-.6 .8h.6M247.4 57.5h.4v.5h-.4v-.1l.4-.2M257.7 44.7h.2M258 40h.5M258.1 42.6l-.3-.1-.2 .2 .1 .3 .4 .1v.2l-.5 .1M258.1 44.3h-.4v.9h.4M261.3 45l.2 .4h.4l.3-.2-.1-.3h-.3v.2M261.3 44.1h.9l-.9 .5h.9M261.3 43.3a.47 .47 0 0 1 .6-.2 .47 .47 0 0 1 .3 .5h-.9z"/>
<path d="M37.7 61.5v.9M37.7 63.2v.9M37.7 65v.8M37.7 66.7v.8M37.7 68.4v.9M37.7 70.1v.9M37.7 71.8v.9M37.7 73.5v1M37.7 75.3v.9M37.7 77v.8M37.7 78.7v.9M38.7 61.5l-.7 1.1"/>
<path d="M38.7 63.2l-.7 1.1M38.7 64.9l-.7 1.1M38.7 66.7l-.7 1.1M38.7 68.4l-.7 1.1M38.7 70.1l-.7 1.1M38.7 71.8l-.7 1.1M38.7 73.5l-.7 1.1M38.7 75.2l-.7 1.1M38.7 77l-.7 1.1M38.7 78.7l-.7 1.1M39 61.6h.5l-.1 .8-.4-.1zM39 65.1h.5v.6l-.2 .1-.3-.1z"/>
<path d="M39 70.2h.5v.6l-.2 .2-.3-.2zM39 75.4h.5v.7h-.5zM39.2 63.2l.3 .2v.6l-.2 .1-.3-.1v-.6zM39.2 66.7l.3 .1-.1 .7-.4-.1v-.6zM39.2 68.4l.3 .1v.6l-.2 .2-.3-.2v-.6zM39.2 71.8l.3 .2-.1 .7-.4-.1v-.6zM39.2 73.5l.3 .2v.6l-.2 .2-.3-.2v-.6zM39.2 77l.3 .2-.1 .6h-.4v-.6zM39.2 78.7l.3 .2v.6l-.2 .1-.3-.1v-.6zM65.6 63.2v.9M66.6 63.2l-.8 1.1M67 63.2a.47 .47 0 0 1 .5 .5 .47 .47 0 0 1-.5 .4l-.2-.1v-.6z"/>
<path d="M68.4 63.2l-.7 1.1M68.5 63.2h.5M68.8 63.2v.9M68.9 61.5v.9M68.9 65v.8M68.9 66.7v.8M68.9 68.4v.9M68.9 70.1v.9M68.9 71.8v.9M68.9 73.5v1M68.9 75.3v.9M68.9 77v.8"/>
<path d="M68.9 78.7v.9M69.4 63.2l.4 .3v.4l-.2 .2h-.2zM69.9 61.5l-.7 1.1M69.9 64.9l-.7 1.1M69.9 66.7l-.7 1.1M69.9 68.4l-.7 1.1M69.9 70.1l-.7 1.1M69.9 71.8l-.7 1.1M69.9 73.5l-.7 1.1M69.9 75.2l-.7 1.1M69.9 77l-.7 1.1M69.9 78.7l-.7 1.1"/>
<path d="M70.2 61.6h.5v.8l-.5-.1zM70.2 65.1h.5v.6l-.1 .1-.5-.2zM70.2 70.2h.5v.6l-.1 .2-.5-.3zM70.2 75.4h.5v.7h-.5zM70.4 63.2l.3 .2v.6l-.1 .1a.49 .49 0 0 1-.5-.4 .49 .49 0 0 1 .3-.5zM70.4 66.7l.3 .1v.7h-.4l-.2-.2v-.4zM70.4 68.4l.3 .1v.6l-.1 .2a.49 .49 0 0 1-.5-.4 .49 .49 0 0 1 .3-.5zM70.4 71.8l.3 .2v.6h-.5a.52 .52 0 0 1 .2-.8zM70.4 73.5l.3 .2v.6l-.1 .2a.49 .49 0 0 1-.5-.4 .49 .49 0 0 1 .3-.6zM70.4 77l.3 .2v.6h-.5a.52 .52 0 0 1 .2-.8zM70.4 78.7l.3 .2v.6l-.1 .1a.49 .49 0 0 1-.5-.4 .49 .49 0 0 1 .3-.5zM104 61.5a.47 .47 0 0 1 .5 .3 .47 .47 0 0 1-.2 .6h-.3z"/>
<path d="M104 63.2a.47 .47 0 0 1 .5 .5 .47 .47 0 0 1-.5 .4zM104 65h.3a.47 .47 0 0 1 .2 .5 .47 .47 0 0 1-.5 .3zM104 66.7a.49 .49 0 0 1 .5 .3 .49 .49 0 0 1-.2 .5h-.3zM104 68.4a.47 .47 0 0 1 .5 .4 .47 .47 0 0 1-.5 .5zM104 70.1h.3a.47 .47 0 0 1 .2 .6 .47 .47 0 0 1-.5 .3zM104 73.5v1h.4M104 75.4h.5v.7h-.5zM104.7 74h.3M104.8 63.2h.5l-.3 .3 .3 .1v.4h-.5M104.8 70.1h.6l-.4 .9M104.9 60.1l.2-.3v.9M104.9 61.6l.3-.1 .1 .3-.5 .6h.5"/>
<path d="M104.9 60.7h.4M104.9 75.7h.3M105 64.9l-.1 .7h.5M105.1 73.5h-.4v1h.4M105.3 66.7h-.4v.4l.4-.1v.5l-.4-.1M105.3 68.4l-.4 .2v.6l.3 .1 .1-.5-.3-.1-.1 .2M105.3 75.3h-.4v.9h.4M105.3 65.2v.6M108 76.3v.4l.3 .1 .5-.1v-.5h-.3v.2M108 75.4h.8l-.8 .5h.8M108 74.6l.8-.1v.5h-.8zM111.6 65h.4l.1 .2v.4l-.2 .2-.4-.2z"/>
<path d="M111.6 70.1h.4l.1 .3v.3l-.2 .3-.4-.3zM111.7 61.5l.4 .3-.1 .6h-.4l-.1-.3zM111.7 63.2a.47 .47 0 0 1 .5 .5 .47 .47 0 0 1-.5 .4l-.2-.3zM111.7 66.7l.4 .2-.1 .6h-.4l-.1-.2zM111.7 68.4a.47 .47 0 0 1 .5 .4 .47 .47 0 0 1-.5 .5l-.2-.3zM112.4 63.2h.5l-.3 .3 .3 .1v.4h-.5M112.4 70.1h.6l-.4 .9M112.5 60.1l.2-.3v.9M112.5 61.6l.3-.1 .1 .3-.5 .6h.5M112.5 60.7h.4M112.6 64.9l-.1 .7h.5M112.9 66.7h-.4v.4l.4-.1v.5l-.4-.1"/>
<path d="M112.9 68.4l-.4 .2v.6l.3 .1 .1-.5-.3-.1-.1 .2M112.9 65.2v.6M143.1 62.4v.8M143.1 64.1v.9M143.1 67.5v.9M143.1 69.3v.8M143.1 72.7v.8M143.1 74.5v.8M143.5 64.3l.2-.2v.9M143.5 69.6l.2-.3v.8M143.5 74.7l.2-.2v.8M143.5 65h.5"/>
<path d="M143.5 70.1h.5M143.5 75.3h.5M143.5 62.4h.3l.2 .1-.1 .7h-.3l-.1-.3zM143.5 67.6l.3-.1 .2 .2-.1 .7h-.3l-.1-.3zM143.5 72.8l.3-.1 .2 .2-.1 .6h-.3l-.1-.2zM143.5 77.9l-.3-.1-.2 .2 .1 .3 .4 .1v.3h-.5M143.5 79.6h-.4v.9h.4M144.3 62.4v.8h.3l.1-.4-.4-.1M144.3 64.4l.4 .1v.4h-.4M144.3 64.1v.9M144.7 67.9h-.4v.4l.4 .1M144.7 69.6h-.4v.5h.4"/>
<path d="M144.7 72.7v.8h-.3l-.1-.4 .4-.1M144.7 74.8h-.4v.4h.4M144.7 74.5v.8M146.8 79.4h.8l-.8 .5h.8M146.8 78.6a.47 .47 0 0 1 .5-.1 .47 .47 0 0 1 .3 .4h-.8zM150.1 62.4h.5l-.5 .8h.5M150.1 67.5h.6l-.6 .9h.6M150.1 72.7h.5l-.5 .8h.5M150.9 62.4v.8h.4v-.4l-.4-.1M151.3 67.9h-.3l-.1 .1 .1 .4h.3M151.3 72.7v.8h-.3l-.1-.4 .4-.1M174.1 62.4v.8"/>
<path d="M174.1 64.1v.9M174.1 67.5v.9M174.1 69.3v.8M174.1 72.7v.8M174.1 74.5v.8M174.5 64.3l.2-.2v.9M174.5 69.6l.2-.3v.8M174.5 74.7l.2-.2v.8M174.5 65h.5M174.5 70.1h.5M174.5 75.3h.5M174.5 62.4h.3l.2 .1-.1 .7h-.3l-.1-.3z"/>
<path d="M174.5 67.6l.3-.1 .2 .2-.1 .7h-.3l-.1-.3zM174.5 72.8l.3-.1 .2 .2-.1 .6h-.3l-.1-.2zM174.5 77.9h-.4v.3l.4 .2v.3h-.4M174.5 79.6h-.4v.9h.4M175.4 62.4v.8h.2l.1-.4-.3-.1M175.4 64.4l.3 .1v.4h-.3M175.4 64.1v.9M175.7 67.9h-.3l-.1 .1 .1 .4h.3M175.7 69.6h-.3l-.1 .1 .2 .4h.2M175.7 72.7v.8h-.3v-.5h.3M175.7 74.8l-.2-.1-.2 .2 .2 .4 .2-.1M175.7 74.5v.8"/>
<path d="M177.8 79.4h.8l-.8 .5h.8M177.8 78.6l.3-.2 .4 .1 .1 .4h-.8zM181.1 62.4h.5l-.5 .8h.5M181.1 67.5h.5l-.5 .9h.5M181.1 72.7h.5l-.5 .8h.5M182 62.4v.8h.2l.1-.4-.3-.1M182.3 67.9h-.3v.4l.3 .1M182.3 72.7v.8h-.3v-.5h.3M206.9 62.4v.8M206.9 64.1v.9M206.9 67.5v.9M206.9 69.3v.8"/>
<path d="M206.9 72.7v.8M206.9 74.5v.8M207.2 64.3l.3-.2v.9M207.2 69.6l.3-.3v.8M207.2 74.7l.3-.2v.8M207.2 79.6h-.3v.9h.3M207.2 65h.5M207.2 70.1h.5M207.2 75.3h.5M207.3 77.9l-.3-.1-.2 .2 .1 .3 .4 .2-.1 .2h-.4M207.4 62.4a.43 .43 0 0 1 .3 .4 .43 .43 0 0 1-.4 .4l-.1-.7zM207.4 67.5a.43 .43 0 0 1 .3 .5 .43 .43 0 0 1-.4 .4l-.1-.7z"/>
<path d="M207.4 72.7a.43 .43 0 0 1 .3 .4 .43 .43 0 0 1-.4 .4l-.1-.6zM208.1 62.4v.8h.3v-.5h-.3M208.1 64.4h.3l.1 .2-.2 .4-.2-.1M208.1 64.1v.9M208.4 67.9h-.3v.4l.3 .1M208.4 69.6h-.3v.5h.3M208.4 72.7v.8h-.3v-.4l.3-.1M208.4 74.8h-.3v.4h.3M208.4 74.5v.8M210.5 79.4h.9l-.9 .5h.9M210.5 78.6a.48 .48 0 0 1 .6-.1 .48 .48 0 0 1 .3 .4h-.9zM213.7 62.4h.6l-.6 .8h.6"/>
<path d="M213.7 72.7h.6l-.6 .8h.6M213.8 67.5h.6l-.6 .9h.6M214.7 62.4v.8h.3l.1-.4-.4-.1M215.1 67.9h-.3l-.1 .1 .1 .4h.3M215.1 72.7v.8h-.3l-.1-.4 .4-.1M239.6 62.4v.8M239.6 64.1v.9M239.6 67.5v.9M239.6 69.3v.8M239.6 72.7v.8M239.6 74.5v.8M240 62.4h.2l.2 .1-.1 .7-.3-.1z"/>
<path d="M240 64.3l.2-.2v.9M240 67.6l.2-.1 .2 .2-.1 .7-.3-.1zM240 69.6l.2-.3v.8M240 72.8l.2-.1 .2 .2-.1 .6-.3-.1zM240 74.7l.2-.2v.8M240 77.9h-.4v.3l.4 .2v.3h-.4M240 79.6h-.4v.9h.4M240 65h.4M240 70.1h.4M240 75.3h.4M240.8 62.4v.8h.4v-.5h-.4M240.8 64.4h.4l.1 .2-.2 .4-.3-.1"/>
<path d="M240.8 64.1v.9M241.2 67.9h-.4l-.1 .1 .1 .4h.4M241.2 69.6h-.4l-.1 .1 .2 .4h.3M241.2 72.7v.8h-.4v-.5h.4M241.2 74.8l-.3-.1-.2 .2 .2 .4 .3-.1M241.2 74.5v.8M243.2 79.4h.8l-.8 .5h.8M243.3 78.6l.2-.2 .5 .1v.4h-.8zM246.5 62.4h.6l-.6 .8h.6M246.5 72.7h.6l-.6 .8h.6M246.6 67.5h.5l-.5 .9h.5M247.4 62.4v.8h.4v-.5h-.4"/>
<path d="M247.8 72.7v.8h-.4v-.5h.4M247.9 67.9h-.5l.1 .5h.4M37.7 80.5v.8M37.7 82.2v.8M37.7 83.9v.9M37.7 85.6v.9M37.7 87.3v.9M37.7 89.1v.9M37.7 90.8v.8M37.7 92.5v.8M37.7 94.3v.8M37.7 96v.8"/>
<path d="M37.7 97.7v.8M37.7 99.4v.9M38.7 80.4l-.7 1.1M38.7 82.2l-.7 1.1M38.7 83.9l-.7 1.1M38.7 85.6l-.7 1.1M38.7 87.3l-.7 1.1M38.7 89l-.7 1.1M38.7 90.7l-.7 1.2M38.7 92.5l-.7 1.1M38.7 94.2l-.7 1.1M38.7 95.9l-.7 1.2"/>
<path d="M38.7 97.7l-.7 1.1M38.7 99.4l-.7 1.1M39 80.6h.5l-.1 .7-.4-.1zM39 84h.5v.6l-.2 .2-.3-.2zM39 85.7h.5l-.1 .8-.4-.1zM39 89.2h.5v.6l-.2 .2-.3-.2zM39 90.9h.5l-.1 .7h-.4zM39 94.4h.5v.6l-.2 .1-.3-.1zM39 99.5h.5v.6l-.2 .2-.3-.2zM39.1 96l.4 .1-.1 .7-.4-.1zM39.2 82.2l.3 .1-.1 .7-.4-.1v-.6zM39.2 87.3l.3 .2-.1 .7-.4-.1v-.6z"/>
<path d="M39.2 92.5l.3 .2-.1 .6h-.4v-.6zM39.2 97.7l.3 .1-.1 .7-.4-.1v-.6zM40.5 92.5l-.8 1.1M40.8 93l.5-.1v-.3l-.5-.1v.8M41.7 92.5l.4 .2-.1 .6h-.3zM42.5 92.6h.5v.3l-.5 .4h.5M65.6 80.5v.8M66.7 80.4l-.8 1.1M66.9 80.6h.5l-.1 .7-.4-.1zM68.4 80.4l-.7 1.1M68.6 80.5h.5M68.9 80.5v.8"/>
<path d="M68.9 82.2v.8M68.9 83.9v.9M68.9 85.6v.9M68.9 87.3v.9M68.9 89.1v.9M68.9 90.8v.8M68.9 92.5v.8M68.9 94.3v.8M68.9 96v.8M68.9 97.7v.8M68.9 99.4v.9M69.9 80.6l-.3-.1-.2 .1v.5l.2 .2 .3-.1"/>
<path d="M69.9 82.2l-.7 1.1M69.9 83.9l-.7 1.1M69.9 85.6l-.7 1.1M69.9 87.3l-.7 1.1M69.9 89l-.7 1.1M69.9 90.7l-.7 1.2M69.9 92.5l-.7 1.1M69.9 94.2l-.7 1.1M69.9 95.9l-.7 1.2M69.9 97.7l-.7 1.1M69.9 99.4l-.7 1.1M70.2 84h.5v.6l-.1 .2a.47 .47 0 0 1-.4-.3 .47 .47 0 0 1 0-.5z"/>
<path d="M70.2 85.7h.5v.8l-.5-.1zM70.2 89.2h.5v.6l-.1 .2a.47 .47 0 0 1-.4-.3 .47 .47 0 0 1 0-.5zM70.2 90.9h.5v.7h-.5zM70.2 94.4h.5v.6l-.1 .1a.47 .47 0 0 1-.4-.3 .47 .47 0 0 1 0-.4zM70.2 99.5h.5v.6l-.1 .2a.47 .47 0 0 1-.4-.3 .47 .47 0 0 1 0-.5zM70.2 80.5v.8M70.3 96l.4 .1v.7h-.4l-.2-.2zM70.4 82.2l.3 .1v.6h-.5a.52 .52 0 0 1 .2-.7zM70.4 87.3l.3 .2v.6h-.5a.52 .52 0 0 1 .2-.8zM70.4 92.5l.3 .2v.6h-.5a.52 .52 0 0 1 .2-.8zM70.4 97.7l.3 .1v.6h-.5a.52 .52 0 0 1 .2-.7zM70.4 80.8l.3 .5"/>
<path d="M70.7 80.5l-.5 .5M104 94.3h.3a.48 .48 0 0 1 .2 .5 .48 .48 0 0 1-.5 .3zM104 96l.4 .1 .1 .4-.2 .3h-.3zM104 97.7a.49 .49 0 0 1 .5 .3 .49 .49 0 0 1-.2 .5h-.3zM104 99.4h.3a.48 .48 0 0 1 .2 .6 .48 .48 0 0 1-.5 .3zM104.8 99.4h.5l-.3 .4h.3v.4h-.5M104.9 96.2l.2-.2v.8M104.9 97.7h.3l.1 .4-.5 .4h.5M104.9 96.8h.4M104.9 94.3l.4 .1v.6l-.2 .1-.2-.1zM108 95.3l.8 .3-.8 .3M108.1 94.5l-.1 .4 .2 .1h.5l.1-.1v-.4"/>
<path d="M108.1 93.7l-.1 .3 .2 .2h.5l.1-.2v-.3M111.6 94.3l.5 .1a.47 .47 0 0 1-.4 .7l-.2-.3zM111.6 96h.4l.1 .2-.1 .6h-.4zM111.6 99.4l.5 .1a.47 .47 0 0 1-.4 .8l-.2-.4zM111.7 97.7a.47 .47 0 0 1 .4 .3 .47 .47 0 0 1-.1 .5h-.4l-.1-.2zM112.4 99.4h.5l-.3 .4h.3v.4h-.5M112.5 96.2l.2-.2v.8M112.5 97.7h.3l.1 .4-.5 .4h.5M112.5 96.8h.4M112.6 94.3l.3 .1v.6l-.2 .1-.2-.1zM143.1 80h.3M146.8 80.3v.3l.1 .1 .6-.1v-.4h-.2v.2"/>
<path d="M155.9 93.3l.3-.8 .3 .8M155.9 95.1l.3-.8 .3 .8M155.9 96.8l.3-.8 .3 .8M155.9 98.5l.3-.8 .3 .8M156 93.2h.4M156 94.9h.4M156 96.6h.4M156 98.3h.4M156.7 97.7h.5l-.3 .3 .3 .1v.4h-.5M156.8 94.5l.2-.2v.8M156.8 96.1l.3-.1 .1 .3-.5 .5h.5M156.8 95.1h.4"/>
<path d="M156.9 92.5l.3 .2-.1 .6h-.3v-.1v-.5zM156.9 99.4l-.1 .5h.5M157.1 99.7v.6M159.6 93.9l1 .3-1 .3M159.7 93.2l-.1 .2 .3 .3h.4l.3-.3-.1-.2M159.7 92.3a.4 .4 0 0 0 .4 .5 .4 .4 0 0 0 .4-.5M162.9 92.9h.5v-.2l-.1-.2h-.4v.8h.5v-.3l-.1-.1M162.9 94.6h.5v-.3h-.5v.8l.5-.1v-.3l-.1-.1M162.9 96.4h.4l.1-.2v-.2h-.5v.8l.5-.1v-.2l-.1-.1M162.9 98.1h.5v-.3l-.1-.1h-.4v.8h.5v-.3l-.1-.1M162.9 99.8h.5v-.4h-.5v.9l.5-.1v-.3l-.1-.1M163.7 97.7h.6l-.3 .3 .3 .2v.2l-.6 .1"/>
<path d="M163.8 94.5l.2-.2v.8M163.8 96.1l.4-.1 .1 .2-.6 .6h.6M163.8 95.1h.5M164 92.5a.43 .43 0 0 1 .3 .5 .43 .43 0 0 1-.4 .3l-.1-.6zM164 99.4l-.2 .5h.5M164.2 99.7v.6M174.1 80h.3M177.8 80.3v.3l.1 .1 .7-.1-.1-.4h-.2v.2M188.7 93.3l.2-.8 .3 .8M188.7 95.1l.2-.8 .3 .8M188.7 96.8l.2-.8 .3 .8M188.7 98.5l.2-.8 .3 .8"/>
<path d="M188.7 93.2h.4M188.7 94.9h.4M188.7 96.6h.4M188.7 98.3h.4M189.4 94.5l.3-.2v.8M189.4 96.1h.5v.2l-.5 .5h.5M189.4 97.7h.5l-.2 .3 .2 .1v.4h-.5M189.4 95.1h.5M189.5 92.6l.3-.1 .1 .2v.6h-.3l-.2-.2zM189.7 99.4l-.3 .5h.6M189.9 99.7v.6M192.4 93.9l.8 .3-.8 .3"/>
<path d="M192.5 93.2l-.1 .3 .2 .2h.5l.1-.2v-.3M192.5 92.3l-.1 .4 .3 .1 .5-.1v-.4M195.7 92.9h.3l.1-.3-.4-.1v.8h.4l.1-.2-.2-.2M195.7 94.6h.3l.1-.2-.4-.1v.8h.3l.2-.3-.2-.2M195.7 96.4l.4-.1-.1-.3h-.3v.8h.4l.1-.2-.2-.2M195.7 98.1h.3l.1-.4h-.4v.8h.4l.1-.2-.2-.2M195.7 99.8h.4v-.3l-.4-.1v.9h.3l.2-.4-.2-.1M196.5 97.7h.5l-.3 .3 .3 .1v.4h-.5M196.6 94.5l.1-.2v.8M196.6 96.1l.3-.1 .1 .3-.5 .5h.5M196.6 95.1h.4M196.7 92.5l.3 .2-.1 .6h-.3v-.1v-.5z"/>
<path d="M196.7 99.4l-.1 .5h.5M196.9 99.7v.6M206.9 80h.2M210.5 80.3v.3l.2 .1h.4l.3-.2-.1-.3h-.4v.2M239.6 80h.3M243.3 80.3l-.1 .2 .3 .2 .5-.1v-.4h-.3v.2M37.7 101.1v.9M37.7 102.8v1M38.7 101.1l-.7 1.1M38.7 102.8l-.7 1.1M39 101.2h.5l-.1 .8-.4-.1zM39.2 102.8l.3 .2v.6l-.2 .2-.3-.2v-.6z"/>
<path d="M47.7 105.6v.4l.3 .1 .6-.1-.1-.5h-.3v.2M47.7 104.7h.9l-.9 .5h.9M47.7 103.9l.3-.1h.5l.1 .5h-.9zM49.4 104.7h.8l-.8 .5h.8M49.5 105.6a.43 .43 0 0 0 .2 .5 .43 .43 0 0 0 .5-.1v-.5h-.3v.2M49.5 103.9l.3-.1h.4v.5h-.8zM51.2 105.6v.4a.44 .44 0 0 0 .5 .1 .44 .44 0 0 0 .2-.6h-.3v.2M51.2 104.7h.8l-.8 .5h.8M51.2 103.9a.48 .48 0 0 1 .5-.1 .48 .48 0 0 1 .3 .5h-.8zM52.9 105.6v.4l.3 .1 .5-.1-.1-.5h-.2v.2M52.9 104.7h.8l-.8 .5h.8M52.9 103.9l.3-.1h.4l.1 .5h-.8z"/>
<path d="M54.6 104.7h.8l-.8 .5h.8M54.6 105.6a.43 .43 0 0 0 .3 .5 .43 .43 0 0 0 .5-.1l-.1-.5h-.2v.2M54.6 103.9l.4-.1h.3l.1 .5h-.8zM56.3 105.6v.4a.44 .44 0 0 0 .6 .1 .44 .44 0 0 0 .2-.6h-.3v.2M56.3 104.7h.9l-.9 .5h.9M56.3 103.9a.48 .48 0 0 1 .6-.1 .48 .48 0 0 1 .3 .5h-.9zM58 105.6v.4l.4 .1 .5-.1-.1-.5h-.3v.2M58 104.7h.9l-.9 .5h.9M58 103.9l.4-.1h.4l.1 .5h-.9zM59.7 104.7h.9l-.9 .5h.9M59.8 105.6a.43 .43 0 0 0 .3 .5 .43 .43 0 0 0 .5-.1l-.1-.5h-.3v.2M59.8 103.9l.4-.1h.3l.1 .5h-.9z"/>
<path d="M104 101.1l.4 .1 .1 .4-.2 .4h-.3zM104 102.8a.47 .47 0 0 1 .5 .5 .47 .47 0 0 1-.5 .5zM104 104.6h.3a.48 .48 0 0 1 .2 .5 .48 .48 0 0 1-.5 .3zM104 106.3a.47 .47 0 0 1 .5 .3 .47 .47 0 0 1-.2 .5h-.3zM104 109.8v.8h.4M104.2 111.5l.3 .1-.1 .7h-.3l-.2-.2v-.4zM104.7 110.2h.3M104.8 106.3h.6l-.4 .8M104.9 111.9h.3M105 101.1l-.1 .6h.5M105.1 109.8h-.4v.8h.4M105.3 102.8h-.4v.4h.4l-.1 .6-.3-.1"/>
<path d="M105.3 104.6l-.4 .2v.6h.3l.1-.5-.4 .1M105.3 111.5h-.4v.8h.4M105.3 101.4v.6M108 112.5v.3l.3 .2 .5-.2v-.3h-.3v.1M108 111.5h.8l-.8 .6h.8M108 110.9l.2-.2h.5l.1 .2v.3h-.8zM111.6 101.1h.4l.1 .3-.1 .6h-.4zM111.6 104.6l.5 .1a.47 .47 0 0 1-.4 .7l-.2-.3zM111.7 102.8a.47 .47 0 0 1 .5 .5 .47 .47 0 0 1-.5 .5l-.2-.4zM111.7 106.3l.4 .2-.1 .6h-.4l-.1-.2zM112.4 106.3h.6l-.4 .8M112.6 101.1l-.1 .6h.5"/>
<path d="M112.9 102.8h-.4v.4h.4l-.1 .6-.3-.1M112.9 104.6l-.4 .2v.6h.3l.1-.5-.4 .1M112.9 101.4v.6M155.9 100.3l.3-.9 .3 .9M155.9 102l.3-.9 .3 .9M155.9 103.8l.3-1 .3 1M155.9 105.4l.3-.8 .3 .8M155.9 108.9l.3-.9 .3 .9M156 100h.4M156 101.7h.4M156 103.5h.4M156 105.2h.4"/>
<path d="M156 108.7h.4M156.5 109.9l-.3-.1-.2 .1v.5l.2 .2 .3-.1M156.7 104.6h.6l-.4 .8M156.8 108.6h.6M156.9 110.2h.3M157.1 102.8l-.3 .3v.6l.3 .1 .1-.6h-.3l-.1 .1M157.2 101.1h-.4v.5h.4l-.1 .4-.3-.1M157.3 109.8h-.4v.8h.4M157.9 108.3l.6 .3-.6 .2M158.9 108.4h.4l.1-.2-.2-.2h-.3v.9l.5-.1v-.3l-.2-.1M159.6 109.5h1l-1 .5h1M159.7 110.4l-.1 .2 .2 .3h.6l.2-.3-.1-.2h-.4v.1"/>
<path d="M159.7 108.8a.48 .48 0 0 1 .6-.2 .48 .48 0 0 1 .3 .5h-1zM162.9 101.6h.4l.1-.2v-.3h-.5v.9l.5-.1v-.3h-.1M162.9 103.2h.5v-.2l-.1-.2h-.4v1l.5-.1v-.4l-.1-.1M162.9 105h.4l.1-.1v-.3h-.5v.8h.5v-.4h-.1M163.7 104.6h.6l-.3 .8M164.2 101.1h-.4v.5l.4-.1 .1 .1-.1 .4-.4-.1M164.2 102.8l-.3 .1-.1 .8 .3 .1 .2-.2-.2-.4-.3 .1M188.7 100.3l.2-.9 .3 .9M188.7 102l.2-.9 .3 .9M188.7 103.8l.2-1 .3 1M188.7 105.4l.2-.8 .3 .8M188.7 108.9l.2-.9 .3 .9"/>
<path d="M188.7 100h.4M188.7 101.7h.4M188.7 103.5h.4M188.7 105.2h.4M188.7 108.7h.4M189.3 109.9l-.5-.1a.44 .44 0 0 0-.1 .5 .44 .44 0 0 0 .6 .2M189.4 104.6h.6l-.4 .8M189.5 108.6h.6M189.6 110.2h.3M189.9 102.8l-.3 .1-.2 .7 .2 .2 .3-.1v-.5h-.3l-.2 .1M189.9 101.1h-.4l-.1 .5 .5-.1v.4h-.5M190 109.8h-.4v.8h.4"/>
<path d="M190.5 108.3l.7 .3-.7 .2M191.6 108.4h.4l.1-.3-.5-.1v.9h.4l.1-.3-.2-.2M192.4 110.4l.1 .5h.7v-.5h-.3v.1M192.4 109.5h.8l-.8 .5h.8M192.4 108.8l.3-.2 .5 .1v.4h-.8zM195.7 101.6l.4-.1-.1-.4h-.3v.9h.4l.1-.3-.2-.1M195.7 103.2h.3l.1-.3-.4-.1v1h.3l.2-.4-.2-.2M195.7 105l.4-.1-.1-.3h-.3v.8h.3l.2-.1-.1-.3h-.1M196.5 104.6h.6l-.5 .8M196.9 102.8l-.3 .3v.6h.4v-.5h-.4v.1M197 101.1h-.4v.5l.3-.1 .1 .4h-.4M35 125.3l.3-.9 .2 .9"/>
<path d="M35 127l.3-.9 .2 .9M35 128.7l.3-.9 .2 .9M35 130.4l.3-.8 .2 .8M35 132.1l.3-.8 .2 .8M35 133.9l.3-.9 .2 .9M35 135.6l.3-.9 .2 .9M35 137.3l.3-.9 .2 .9M35 139.1l.3-1 .2 1M35.1 125h.4M35.1 126.7h.4M35.1 128.5h.4M35.1 130.2h.4"/>
<path d="M35.1 131.9h.4M35.1 133.6h.4M35.1 135.3h.4M35.1 137h.4M35.1 138.8h.4M35.8 126.4l.2-.3v.9M35.8 127.9h.5v.3l-.5 .5h.5M35.8 129.6h.5l-.3 .3 .3 .1v.3h-.5M35.8 136.4h.6l-.5 .9M35.8 127h.5M35.9 124.5l.3-.1 .1 .2v.5l-.2 .2a.48 .48 0 0 1-.2-.8zM35.9 138.6l-.1-.3 .1-.2 .4 .1v.3l-.4 .1-.1 .1 .1 .4 .4-.1v-.4h-.2"/>
<path d="M36 131.3l-.2 .6h.6M36.2 134.7h-.3l-.1 .7 .1 .2 .4-.1-.1-.4h-.3l-.1 .2M36.2 131.5v.6M36.3 133h-.4l-.1 .4h.5v.4h-.5M39.1 123.7l.8 .3-.8 .3M39.1 123.2l.2-.2h.4l.2 .1v.4h-.8zM39.2 122.2l.6-.1 .1 .5h-.8zM40.8 123.7l.9 .3-.9 .3M40.8 123.2l.2-.2h.4l.3 .2v.3h-.9zM40.8 122.2l.7-.1 .2 .5h-.9zM44 124.4v.9M44 126.1v.9"/>
<path d="M44 127.8v.9M44 129.6v.8M44 131.3v.8M44 133v.9M44 134.7v.9M44 136.4v.9M44 138.1v1M44 139.9v.9M44.4 124.5h.5v.6l-.2 .2-.3-.2zM44.4 126.2h.5l-.1 .8-.4-.1zM44.4 129.7h.5v.6l-.2 .1-.3-.1zM44.4 131.4h.5l-.1 .7-.4-.1z"/>
<path d="M44.4 134.8h.5v.6l-.2 .2-.3-.2zM44.5 139.9l.4 .1v.6l-.2 .2-.3-.2zM44.6 127.8l.3 .2v.6l-.2 .1-.3-.1v-.6zM44.6 133l.3 .1v.6l-.2 .2-.3-.2v-.6zM44.6 136.4l.3 .2-.1 .7-.4-.1v-.6zM44.6 138.1l.3 .2v.6l-.2 .2-.3-.2v-.6zM45.3 126.4l.2-.3v.9M45.3 127.9h.5v.3l-.5 .5h.5M45.3 129.6h.5l-.3 .3 .3 .1v.3h-.5M45.3 136.4h.5l-.4 .9M45.3 127h.5M45.3 124.5l.4-.1 .1 .2v.5l-.2 .2a.48 .48 0 0 1-.3-.8z"/>
<path d="M45.4 138.6l-.1-.3 .1-.2 .4 .1v.3l-.5 .1v.1l.1 .4 .4-.1v-.4h-.2M45.5 131.3l-.2 .6h.5M45.7 134.7h-.3l-.1 .7 .1 .2 .4-.1-.1-.4h-.4v.2M45.7 131.5v.6M45.8 133h-.5v.4h.5v.4h-.5M69 131.3l.2-.9 .3 .9M69 133l.2-.9 .3 .9M69 134.7l.2-.8 .3 .8M69 136.4l.2-.8 .3 .8M69 138.1l.2-.8 .3 .8M69 139.9l.2-.8 .3 .8M69 131h.4"/>
<path d="M69 132.7h.4M69 134.5h.4M69 136.2h.4M69 138h.4M69 139.7h.4M69.7 132.4l.3-.3v.9M69.7 134h.5v.2l-.5 .5h.5M69.7 135.6h.5l-.2 .3 .2 .1v.4h-.5M69.7 133h.5M69.9 130.4h.2l.1 .2-.1 .6a.39 .39 0 0 1-.4-.2 .39 .39 0 0 1 .1-.5zM70 137.3l-.3 .6h.5M70.1 137.6v.5"/>
<path d="M70.2 139.1h-.4l-.1 .3h.5v.4h-.5M72.7 131.9l.8 .2-.8 .3M72.8 131l-.1 .4 .3 .2 .5-.2-.1-.4M72.8 130.2l-.1 .4 .2 .1 .6-.1-.1-.4M76 130.8h.4l-.1-.4h-.3v.9h.4l.1-.3-.3-.2M76 132.5h.3l.1-.3-.4-.1v.9h.4l.1-.3-.3-.2M76 134.2h.3l.1-.2-.4-.1v.8h.3l.2-.3-.3-.2M76 136l.4-.1-.1-.3h-.3v.8h.4l.1-.2-.3-.2M76 137.7h.3l.1-.3-.4-.1v.8h.4l.1-.2-.3-.2M76 139.4h.3l.1-.3h-.4v.8h.3l.2-.3-.3-.2M76.7 135.6h.6l-.3 .3 .3 .1v.4h-.6M76.8 132.4l.2-.3v.9"/>
<path d="M76.8 134l.4-.1 .1 .3-.6 .5h.6M76.8 133h.5M76.9 130.4h.3l.1 .2-.1 .7h-.3l-.1-.2zM77 137.3l-.2 .6h.5M77.2 137.6v.5M77.3 139.1h-.5v.3h.5v.4h-.5M99.9 131.3l.3-.9 .3 .9M99.9 133l.3-.9 .3 .9M99.9 134.7l.3-.8 .3 .8M99.9 136.4l.3-.8 .3 .8M99.9 138.1l.3-.8 .3 .8M99.9 139.9l.3-.8 .3 .8"/>
<path d="M100 131h.5M100 132.7h.5M100 134.5h.5M100 136.2h.5M100 138h.5M100 139.7h.5M100.7 132.4l.3-.3v.9M100.7 134h.5v.2l-.5 .5h.5M100.7 135.6h.5l-.2 .3 .2 .1v.4h-.5M100.7 133h.5M100.9 130.4h.2l.1 .2-.1 .6a.39 .39 0 0 1-.4-.2 .39 .39 0 0 1 .1-.5zM101 137.3l-.3 .6h.6"/>
<path d="M101.1 137.6v.5M101.2 139.1h-.4l-.1 .3h.5v.4h-.5M103.7 131.9l.8 .2-.8 .3M103.8 131a.44 .44 0 0 0 .1 .6 .44 .44 0 0 0 .6-.2l-.1-.4M103.8 130.2l-.1 .2 .2 .3 .6-.1-.1-.4M107 130.8h.4l-.1-.4h-.3v.9h.4l.1-.3-.3-.2M107 132.5h.3l.1-.3-.4-.1v.9h.4l.1-.3-.3-.2M107 134.2h.3l.1-.2-.4-.1v.8h.3l.2-.3-.3-.2M107 136l.4-.1-.1-.3h-.3v.8h.4l.1-.2-.3-.2M107 137.7h.3l.1-.3-.4-.1v.8h.4l.1-.2-.3-.2M107 139.4h.3l.1-.3h-.4v.8h.3l.2-.3-.3-.2M107.7 135.6h.6l-.3 .3h.2l.1 .2-.1 .3h-.5"/>
<path d="M107.8 132.4l.3-.3v.9M107.8 134l.4-.1 .1 .2-.6 .6h.6M107.8 133h.5M107.9 130.4a.42 .42 0 0 1 .4 .4 .42 .42 0 0 1-.4 .5zM108 137.3l-.2 .6h.5M108.2 139.1h-.4v.3l.4-.1 .1 .4-.1 .2-.4-.1M108.2 137.6v.5M129.2 131.3l.3-.9 .2 .9M129.2 133l.3-.9 .2 .9M129.2 134.7l.3-.8 .2 .8M129.2 136.4l.3-.8 .2 .8M129.2 138.1l.3-.8 .2 .8"/>
<path d="M129.2 139.9l.3-.8 .2 .8M129.3 131h.4M129.3 132.7h.4M129.3 134.5h.4M129.3 136.2h.4M129.3 138h.4M129.3 139.7h.4M130 132.4l.3-.3v.9M130 134h.5v.2l-.5 .5h.5M130 135.6h.5l-.2 .3 .2 .1v.4h-.5M130 133h.5M130.2 130.4h.2l.1 .2-.1 .6a.39 .39 0 0 1-.4-.2 .39 .39 0 0 1 .1-.5z"/>
<path d="M130.3 137.3l-.3 .6h.6M130.4 137.6v.5M130.5 139.1h-.4l-.1 .3h.5v.4h-.5M133 131.9l.8 .2-.8 .3M133.1 131l-.1 .4 .3 .2 .5-.2-.1-.4M133.1 130.2l-.1 .4 .1 .1 .7-.1-.1-.4M136.3 130.8h.4l-.1-.4h-.3v.9h.4l.1-.3-.3-.2M136.3 132.5h.3l.1-.3-.4-.1v.9h.4l.1-.3-.3-.2M136.3 134.2h.3l.1-.2-.4-.1v.8h.3l.2-.3-.3-.2M136.3 136l.4-.1-.1-.3h-.3v.8h.4l.1-.2-.3-.2M136.3 137.7h.3l.1-.3-.4-.1v.8h.4l.1-.2-.3-.2M136.3 139.4h.3l.1-.3h-.4v.8h.3l.2-.3-.3-.2"/>
<path d="M137 135.6h.5l-.2 .3 .2 .1v.4h-.5M137.1 132.4l.3-.3v.9M137.1 134l.4-.1v.3l-.5 .5h.5M137.1 133h.4M137.2 130.4h.3v.2v.7h-.3l-.1-.2zM137.3 137.3l-.2 .6h.5M137.5 137.6v.5M137.5 139.1h-.4v.3h.4v.4h-.4M165.1 126.1l.2-.8 .3 .8M165.1 127.8l.2-.8 .3 .8M165.1 129.6l.2-.9 .3 .9M165.1 131.3l.2-.9 .3 .9"/>
<path d="M165.1 133l.2-.9 .3 .9M165.1 134.7l.2-.8 .3 .8M165.1 136.4l.2-.8 .3 .8M165.1 138.1l.2-.8 .3 .8M165.1 139.9l.2-.8 .3 .8M165.1 131h.5M165.1 132.7h.5M165.1 134.5h.5M165.1 136.2h.5M165.1 138h.5M165.1 139.7h.5M165.1 125.9h.5"/>
<path d="M165.1 127.5h.5M165.1 129.3h.5M165.8 127.2l.3-.2v.8M165.8 128.7h.5v.4l-.5 .5h.5M165.8 130.4h.5l-.2 .4h.2v.4h-.5M165.8 137.3h.6l-.4 .8M165.8 127.8h.5M165.9 125.3h.3l.1 .1-.1 .6a.39 .39 0 0 1-.4-.2 .39 .39 0 0 1 .1-.5zM166 139.4l-.2-.2 .1-.1h.3l.1 .2-.4 .1-.1 .2 .2 .3 .3-.1v-.3l-.1-.1M166.1 132.1l-.3 .6h.6M166.2 135.6h-.2l-.2 .7 .1 .1h.4l-.1-.5h-.3l-.1 .2M166.2 132.5v.5"/>
<path d="M166.3 133.9h-.4l-.1 .3h.5v.5h-.5M169.1 124.6l.9 .2-.9 .4M169.1 124.1l.3-.3h.4l.2 .2v.3h-.9zM169.1 123.2l.3-.2h.4l.2 .1v.4h-.9zM170.9 124.6l.8 .2-.8 .4M170.9 124l.2-.2h.4l.2 .3v.2h-.8zM170.9 123.1l.2-.1h.4l.2 .2v.3h-.8zM174 125.3v.8M174 127v.8M174 128.7v.9M174 130.4v.9M174 132.1v.9"/>
<path d="M174 133.9v.8M174 135.6v.8M174 137.3v.8M174 139.1v.8M174.5 125.3h.5l-.1 .8-.4-.1zM174.5 128.8h.5v.6l-.2 .2-.3-.2zM174.5 134h.5v.6l-.2 .1-.3-.1zM174.5 135.7h.5l-.1 .7h-.4zM174.5 139.1h.5v.6l-.2 .2-.3-.2zM174.5 130.4l.5 .1-.1 .8-.4-.1zM174.6 127l.4 .1-.1 .7-.4-.1v-.6zM174.6 132.1l.4 .2-.1 .7-.4-.1v-.6z"/>
<path d="M174.6 137.3l.4 .2-.1 .6-.4-.1v-.5zM175.3 127.2l.3-.2v.8M175.3 128.7h.5v.4l-.5 .5h.5M175.3 130.4h.5l-.2 .4h.2v.4h-.5M175.3 137.3h.6l-.4 .8M175.3 127.8h.5M175.4 125.3h.3l.1 .1-.1 .6a.39 .39 0 0 1-.4-.2 .39 .39 0 0 1 .1-.5zM175.5 139.4l-.2-.2 .1-.1h.4v.2l-.4 .1-.1 .2 .2 .3 .3-.1v-.3l-.2-.1M175.6 132.1l-.3 .6h.6M175.7 135.6h-.2l-.2 .7 .1 .1h.4l-.1-.5h-.3l-.1 .2M175.7 132.5v.5M175.8 133.9h-.4l-.1 .3h.5v.5h-.5"/>
<path d="M204.7 126.1l.2-.8 .4 .8M204.7 127.8l.2-.8 .4 .8M204.7 129.6l.2-.9 .4 .9M204.7 131.3l.2-.9 .4 .9M204.7 133l.2-.9 .4 .9M204.7 134.7l.2-.8 .4 .8M204.7 136.4l.2-.8 .4 .8M204.7 138.1l.2-.8 .4 .8M204.7 139.9l.2-.8 .4 .8M204.8 131h.4M204.8 132.7h.4M204.8 134.5h.4"/>
<path d="M204.8 136.2h.4M204.8 138h.4M204.8 139.7h.4M204.8 125.9h.4M204.8 127.5h.4M204.8 129.3h.4M205.4 127.2l.3-.2v.8M205.4 128.7h.5v.4l-.5 .5h.5M205.4 130.4h.5l-.2 .4h.2v.4h-.5M205.4 137.3h.6l-.4 .8M205.4 127.8h.5M205.5 125.3h.4v.7a.39 .39 0 0 1-.5-.2 .39 .39 0 0 1 .1-.5z"/>
<path d="M205.6 139.4l-.2-.2 .1-.1h.4v.2l-.4 .1-.1 .2 .2 .3 .3-.1v-.3l-.1-.1M205.7 132.1l-.3 .6h.6M205.9 135.6h-.3l-.2 .7 .1 .1h.4v-.5h-.4l-.1 .2M205.9 132.5v.5M205.9 133.9h-.4l-.1 .3h.5v.5h-.5M208.7 124.6l.9 .2-.9 .4M208.7 124.1l.3-.3h.4l.2 .2v.3h-.9zM208.7 123.2l.3-.2h.4l.2 .1v.4h-.9zM210.5 124.6l.9 .2-.9 .4M210.5 124l.2-.2h.4l.3 .3v.2h-.9zM210.5 123.1l.2-.1h.4l.3 .2v.3h-.9zM213.7 125.3v.8"/>
<path d="M213.7 127v.8M213.7 128.7v.9M213.7 130.4v.9M213.7 132.1v.9M213.7 133.9v.8M213.7 135.6v.8M213.7 137.3v.8M213.7 139.1v.8M214.1 125.3h.5l-.1 .8-.4-.1zM214.1 128.8h.5v.6l-.2 .2-.3-.2zM214.1 132.3l.1-.2 .4 .2-.1 .7-.4-.1zM214.1 134h.5v.6l-.2 .1-.3-.1z"/>
<path d="M214.1 135.7h.5l-.1 .7h-.4zM214.2 130.4l.4 .1-.1 .8-.4-.1zM214.2 139.1h.4v.6l-.2 .2-.3-.2zM214.2 127l.4 .1-.1 .7-.4-.1v-.6zM214.2 137.3l.4 .2-.1 .6-.4-.1v-.5zM214.9 127.2l.3-.2v.8M214.9 128.7h.5v.4l-.5 .5h.5M214.9 130.4h.5l-.2 .4h.2v.4h-.5M214.9 137.3h.6l-.4 .8M214.9 127.8h.5M215 125.3h.3v.7a.39 .39 0 0 1-.4-.2 .39 .39 0 0 1 .1-.5zM215.1 139.4l-.2-.2 .1-.1h.3l.1 .2-.4 .1-.1 .2 .2 .3 .3-.1v-.3l-.1-.1"/>
<path d="M215.2 132.1l-.3 .6h.6M215.3 135.6h-.2l-.2 .7 .1 .1h.4l-.1-.5h-.3l-.1 .2M215.3 132.5v.5M215.4 133.9h-.4l-.1 .3h.5v.5h-.5M35 140.8l.3-.9 .2 .9M35 142.4l.3-.8 .2 .8M35 144.2l.3-.9 .2 .9M35 145.9l.3-.8 .2 .8M35 147.6l.3-.8 .2 .8M35 149.4l.3-.9 .2 .9M35 153.7l.3 .9 .1-.7 .1 .7 .3-.9M35 151.7h1.4"/>
<path d="M35 153.5h1.6M35 155.1h1.5M35 156.8h1.6M35 158.6h1.4M35.1 157.1l.1 .8h.3l.1-.8M35.1 158.9v.8h.4M35.1 140.5h.4M35.1 142.2h.4M35.1 144h.4M35.1 145.7h.4M35.1 147.4h.4M35.1 149.1h.4"/>
<path d="M35.2 155.4l.4 .1-.1 .7h-.4zM35.6 152l-.3-.1-.2 .3v.4l.2 .2 .3-.1M35.8 141.9l.2-.3v.8M35.8 143.5l.2-.2v.9M35.8 145.3l.2-.2v.8M35.8 147l.2-.2v.8M35.8 148.7l.2-.2v.9M35.8 159.2h.4v-.3h-.4v.8l.5-.1v-.3l-.2-.1M35.8 142.4h.5M35.8 144.2h.5M35.8 145.9h.5M35.8 147.6h.5"/>
<path d="M35.8 149.4h.5M35.9 152.4h.4M36 157.5h.4v-.3l-.4-.1v.8h.4l.1-.2-.2-.2M36 155.8h.3M36.1 154h.3M36.3 140.2l-.1 .2h-.3v-.5l.4 .1v.6l-.4 .2M36.4 151.9h-.5v.9h.5M36.4 155.4h-.4v.8h.4M36.5 153.7h-.4v.9h.4M36.6 143.5l.3-.2v.9M36.6 145.2l.4-.1 .1 .1-.5 .7h.5M36.6 146.8h.5l-.3 .3 .3 .2-.1 .3-.4-.1"/>
<path d="M36.6 144.2h.5M36.8 141.6a.43 .43 0 0 1 .3 .4 .43 .43 0 0 1-.3 .4 .6 .6 0 0 1 0-.8zM36.8 148.5l-.2 .6h.5M37 148.8v.6M43.2 141.6v.8M43.2 143.3v.9M43.2 145.1v.8M43.2 146.8v.8M43.2 148.5v.9M43.2 150.2v.9M43.6 145.2h.5v.6h-.5zM43.6 150.3h.5l.1 .5-.2 .3-.4-.1z"/>
<path d="M43.7 141.6a.47 .47 0 0 1 .4 .3 .47 .47 0 0 1-.1 .5h-.4v-.6zM43.7 143.3a.47 .47 0 0 1 .5 .5 .47 .47 0 0 1-.5 .4l-.1-.1v-.6zM43.7 146.8a.47 .47 0 0 1 .4 .3 .47 .47 0 0 1-.1 .5l-.4-.1v-.6zM43.7 148.5a.47 .47 0 0 1 .5 .4 .47 .47 0 0 1-.5 .5l-.1-.2v-.6zM44.5 141.9l.2-.3v.8M44.5 143.5l.2-.2v.9M44.5 145.3l.2-.2v.8M44.5 147l.2-.2v.8M44.5 148.7l.2-.2v.9M44.5 150.5l.2-.3v.9M44.5 142.4h.4M44.5 144.2h.4"/>
<path d="M44.5 145.9h.4M44.5 147.6h.4M44.5 149.4h.4M44.5 151.1h.4M44.8 153.7v.9l-.4-.9v.9M44.8 155.4v.8l-.4-.8v.8M44.8 157.1v.8l-.4-.8v.8M44.8 158.9v.8l-.4-.8v.8M45.3 143.5l.2-.2v.9M45.3 145.2h.5v.2l-.5 .5h.5M45.3 146.8h.5l-.3 .3 .3 .1v.3h-.5M45.3 144.2h.5"/>
<path d="M45.3 141.7l.3-.1 .2 .2-.1 .6a.39 .39 0 0 1-.5-.2 .39 .39 0 0 1 .1-.5zM45.5 148.5l-.2 .6h.5M45.7 148.8v.6M45.8 140.2l-.1 .2h-.4v-.5l.5 .1v.6l-.5 .2M45.8 150.2h-.5v.5l.4-.1 .1 .4h-.5M45.8 153.7h-.4l-.1 .2v.4l.2 .3 .3-.1M45.8 155.5l-.4-.1-.1 .2v.5l.1 .1h.4M45.8 157.2l-.3-.1-.2 .2v.5l.1 .1h.4M45.8 159l-.4-.1-.1 .1v.5l.2 .2 .3-.1M69 141.6l.2-.8 .3 .8M69 143.3l.2-.9 .3 .9M69 146.8l.2-.9 .3 .9"/>
<path d="M69 141.3h.4M69 143.1h.4M69 146.5h.4M69.6 147.7a.44 .44 0 0 0-.6 .2 .44 .44 0 0 0 .1 .6h.5M69.7 142.4h.5l-.3 .9M69.8 146.4h.6M69.9 148h.3M70.1 140.8h-.2l-.2 .6 .1 .2 .4-.1-.1-.4h-.3l-.1 .2M70.3 147.6h-.4v.9h.4M70.8 146.2l.7 .2-.7 .3M71.9 146.3h.4v-.4h-.4v.9h.4l.1-.3-.2-.2M72.7 148.3v.3l.2 .2h.5l.1-.2v-.3h-.3v.2"/>
<path d="M72.7 147.4h.8l-.8 .5h.8M72.7 146.7l.2-.2h.5l.1 .2v.3h-.8zM76 141.2l.4-.1-.1-.3h-.3v.8h.4l.1-.3-.3-.1M76 142.9h.3l.1-.4-.4-.1v.9h.4l.1-.3-.3-.1M76.7 142.4h.6l-.4 .9M77.2 140.8h-.3l-.1 .1v.6h.5l-.1-.4h-.3l-.1 .2M99.9 141.6l.3-.8 .3 .8M99.9 143.3l.3-.9 .3 .9M99.9 146.8l.3-.9 .3 .9M100 141.3h.5M100 143.1h.5M100 146.5h.5"/>
<path d="M100.5 147.7l-.2-.1-.3 .3v.4l.2 .2h.3M100.7 142.4h.6l-.4 .9M100.8 146.4h.7M100.9 148h.3M101.1 140.8h-.2l-.2 .6 .1 .2 .4-.1-.1-.4h-.3l-.1 .2M101.3 147.6h-.4v.9h.4M101.8 146.2l.7 .2-.7 .3M102.9 146.3h.4l-.1-.4h-.3v.9h.4l.1-.3-.2-.2M103.7 147.4h.8l-.8 .5h.8M103.7 146.8l.2-.3h.4l.2 .2v.3h-.8zM103.8 148.3l-.1 .2 .2 .3h.4l.2-.2v-.3h-.3v.2M107 141.2l.4-.1-.1-.3h-.3v.8h.4l.1-.3-.3-.1"/>
<path d="M107 142.9h.3l.1-.4-.4-.1v.9h.4l.1-.3-.3-.1M107.7 142.4h.6l-.3 .9M108.2 140.8l-.4 .1v.6l.4 .1v-.5h-.3l-.1 .2M129.2 141.6l.3-.8 .2 .8M129.2 143.3l.3-.9 .2 .9M129.2 146.8l.3-.9 .2 .9M129.3 141.3h.4M129.3 143.1h.4M129.3 146.5h.4M129.8 147.7l-.2-.1-.3 .3v.4l.2 .2h.3M130 142.4h.6l-.4 .9M130.1 146.4h.7"/>
<path d="M130.2 148h.3M130.4 140.8h-.2l-.2 .6 .1 .2 .4-.1-.1-.4h-.3l-.1 .2M130.6 147.6h-.4v.9h.4M131.1 146.2l.7 .2-.7 .3M132.2 146.3h.4l-.1-.4h-.3v.9h.4l.1-.3-.2-.2M133 148.3v.3l.1 .2h.5l.2-.2v-.3h-.3v.2M133 147.4h.8l-.8 .5h.8M133 146.7l.1-.2h.5l.2 .2v.3h-.8zM136.3 141.2l.4-.1-.1-.3h-.3v.8h.4l.1-.3-.3-.1M136.3 142.9h.3l.1-.4-.4-.1v.9h.4l.1-.3-.3-.1M137 142.4h.6l-.3 .9M137.5 140.8l-.4 .1v.6h.4v-.4h-.3l-.1 .2"/>
<path d="M165.1 141.6l.2-.8 .3 .8M165.1 143.3l.2-.9 .3 .9M165.1 145.1l.2-.9 .3 .9M165.1 146.8l.2-.9 .3 .9M165.1 148.5l.2-.9 .3 .9M165.1 150.2l.2-.8 .3 .8M165.1 151.9l.2-.8 .3 .8M165.1 153.7l.2-.9 .3 .9M165.1 155.4l.2-.8 .3 .8M165.1 159.7l.2 .9 .2-.6 .1 .6 .2-.9M165.1 157.8h1.4M165.1 159.5h1.6"/>
<path d="M165.1 141.3h.5M165.1 143.1h.5M165.1 146.5h.5M165.1 151.7h.5M165.1 153.5h.5M165.1 155.1h.5M165.1 144.8h.5M165.1 148.3h.5M165.1 150h.5M165.6 158l-.2-.1-.3 .3v.4l.3 .3 .2-.1M165.8 142.7l.3-.3v.9M165.8 144.5l.3-.3v.9"/>
<path d="M165.8 146.2l.3-.3v.9M165.8 147.9l.3-.3v.9M165.8 149.6l.3-.2v.8M165.8 151.3l.3-.2v.8M165.8 153l.3-.2v.9M165.8 154.8l.3-.2v.8M165.8 143.3h.5M165.8 145.1h.5M165.8 146.8h.5M165.8 148.5h.5M165.8 150.2h.5M165.8 151.9h.5"/>
<path d="M165.8 153.7h.5M165.8 155.4h.5M166 158.4h.3M166.3 141.1l-.1 .2h-.3v-.5h.4v.6l-.4 .2M166.4 157.9h-.4v1h.4M166.6 159.7h-.4v.9h.4M166.7 144.5l.2-.3v.9M166.7 146l.4-.1 .1 .2-.5 .7h.5M166.7 147.6h.5l-.3 .4 .3 .1v.3l-.5 .1M166.7 154.6h.5l-.4 .8M166.7 145.1h.5M166.7 142.5h.4v.8h-.3l-.1-.3z"/>
<path d="M166.9 149.3l-.2 .6h.5M167.1 151.1h-.4v.4l.4-.1v.5l-.4-.1M167.1 152.8l-.3 .1-.1 .6 .1 .2 .4-.2-.2-.4-.3 .2M167.1 149.6v.6M173.3 142.4v.9M173.3 144.2v.9M173.3 145.9v.9M173.3 147.6v.9M173.3 149.4v.8M173.3 151.1v.8M173.6 144.3h.5a.47 .47 0 0 1-.3 .8l-.2-.2zM173.6 149.5h.5a.47 .47 0 0 1-.3 .7l-.2-.1z"/>
<path d="M173.6 151.2h.5l.1 .5-.2 .2-.4-.1zM173.7 145.9h.3l.2 .3-.2 .6-.4-.1zM173.8 142.4a.47 .47 0 0 1 .4 .4 .47 .47 0 0 1-.2 .5l-.4-.1v-.6zM173.8 147.6a.47 .47 0 0 1 .4 .3 .47 .47 0 0 1-.2 .6l-.4-.1v-.6zM174 140.8v.8M174.5 140.8h.5l-.1 .8-.4-.1zM174.5 142.7l.3-.3v.9M174.5 144.5l.3-.3v.9M174.5 146.2l.3-.3v.9M174.5 147.9l.3-.3v.9M174.5 149.6l.3-.2v.8M174.5 151.3l.3-.2v.8"/>
<path d="M174.5 143.3h.5M174.5 145.1h.5M174.5 146.8h.5M174.5 148.5h.5M174.5 150.2h.5M174.5 151.9h.5M174.9 154.6v.8l-.4-.8v.8M175.3 144.5l.3-.3v.9M175.3 146h.5v.3l-.5 .5h.5M175.3 147.6h.5l-.2 .4h.2v.5h-.5M175.3 145.1h.5M175.4 142.5l.2-.1 .2 .2-.1 .7h-.2l-.2-.3z"/>
<path d="M175.6 149.3l-.3 .6h.6M175.7 149.6v.6M175.8 141.1l-.1 .2h-.3v-.5h.4v.6l-.4 .2M175.8 151.1h-.4l-.1 .4 .4-.1 .1 .4h-.5M175.8 154.6h-.3l-.2 .1v.4l.3 .3 .2-.1M204.7 141.6l.2-.8 .4 .8M204.7 143.3l.2-.9 .4 .9M204.7 145.1l.2-.9 .4 .9M204.7 146.8l.2-.9 .4 .9M204.7 148.5l.2-.9 .4 .9M204.7 150.2l.2-.8 .4 .8M204.7 151.9l.2-.8 .4 .8"/>
<path d="M204.7 153.7l.2-.9 .4 .9M204.7 155.4l.2-.8 .4 .8M204.7 159.7l.2 .9 .2-.6 .2 .6 .1-.9M204.7 157.8h1.4M204.7 159.5h1.6M204.8 141.3h.4M204.8 143.1h.4M204.8 146.5h.4M204.8 151.7h.4M204.8 153.5h.4M204.8 155.1h.4M204.8 144.8h.4"/>
<path d="M204.8 148.3h.4M204.8 150h.4M205.3 158l-.3-.1-.2 .3v.4l.2 .3 .3-.1M205.4 142.7l.3-.3v.9M205.4 144.5l.3-.3v.9M205.4 146.2l.3-.3v.9M205.4 147.9l.3-.3v.9M205.4 149.6l.3-.2v.8M205.4 151.3l.3-.2v.8M205.4 153l.3-.2v.9M205.4 154.8l.3-.2v.8M205.4 143.3h.5"/>
<path d="M205.4 145.1h.5M205.4 146.8h.5M205.4 148.5h.5M205.4 150.2h.5M205.4 151.9h.5M205.4 153.7h.5M205.4 155.4h.5M205.6 158.4h.3M205.9 141.1v.2h-.4v-.5h.4v.6l-.4 .2M206 157.9h-.4v1h.4M206.2 159.7h-.4v.9h.4M206.3 144.5l.2-.3v.9"/>
<path d="M206.3 146l.4-.1 .1 .2-.5 .7h.5M206.3 147.6h.5l-.3 .4 .3 .1v.3l-.5 .1M206.3 154.6h.5l-.3 .8M206.3 145.1h.5M206.4 142.5l.1-.1a.45 .45 0 0 1 .3 .5 .45 .45 0 0 1-.3 .4l-.2-.3zM206.5 149.3l-.2 .6h.5M206.7 151.1h-.3l-.1 .4 .4-.1v.5l-.4-.1M206.7 152.8l-.2 .1-.2 .6 .2 .2 .3-.2-.2-.4-.3 .2M206.7 149.6v.6M212.9 142.4v.9M212.9 144.2v.9M212.9 145.9v.9"/>
<path d="M212.9 147.6v.9M212.9 149.4v.8M212.9 151.1v.8M213.2 144.3h.5a.47 .47 0 0 1-.3 .8l-.2-.2zM213.2 146h.5l.1 .5-.1 .3-.5-.1zM213.2 149.5h.5a.47 .47 0 0 1-.3 .7l-.2-.1zM213.2 151.2h.5l.1 .5-.1 .2-.5-.1zM213.4 142.4a.47 .47 0 0 1 .4 .4 .47 .47 0 0 1-.1 .5l-.5-.1v-.6zM213.4 147.6a.47 .47 0 0 1 .4 .3 .47 .47 0 0 1-.1 .6l-.5-.1v-.6zM213.7 140.8v.8M214.1 140.8h.5l-.1 .8-.4-.1zM214.2 142.7l.1-.3v.9"/>
<path d="M214.2 144.5l.1-.3v.9M214.2 146.2l.1-.3v.9M214.2 147.9l.1-.3v.9M214.2 149.6l.1-.2v.8M214.2 151.3l.1-.2v.8M214.2 143.3h.4M214.2 145.1h.4M214.2 146.8h.4M214.2 148.5h.4M214.2 150.2h.4M214.2 151.9h.4M214.5 154.6v.8l-.4-.8v.8"/>
<path d="M214.9 144.5l.3-.3v.9M214.9 146h.5v.3l-.5 .5h.5M214.9 147.6h.5l-.2 .4h.2v.5h-.5M214.9 145.1h.5M215 142.5l.3-.1 .1 .2-.1 .7h-.2l-.2-.3zM215.2 149.3l-.3 .6h.6M215.3 149.6v.6M215.4 141.1l-.1 .2h-.3v-.5h.4v.6l-.4 .2M215.4 151.1h-.4l-.1 .4 .4-.1 .1 .4h-.5M215.4 154.6h-.3l-.2 .1v.4l.3 .3 .2-.1M39.1 162.4h.8l-.8 .5h.8M39.2 163.3l-.1 .2 .2 .3h.4l.2-.2v-.3h-.3v.1"/>
<path d="M39.3 161.5h.4l.2 .2v.3h-.8v-.2zM40.8 162.4h.9l-.9 .5h.9M40.8 163.3v.2l.2 .3h.4l.3-.3-.1-.2h-.3v.1M41 161.5h.4l.3 .3v.2h-.9v-.2zM69 168.3l.2-.9 .3 .9M69 170l.2-.8 .3 .8M69 171.7l.2-.8 .3 .8M69 173.5l.2-.9 .3 .9M69 175.2l.2-.8 .3 .8M69 176.9l.2-.8 .3 .8M69 178.7l.2-.9 .3 .9M69 168.1h.4"/>
<path d="M69 169.8h.4M69 171.5h.4M69 173.3h.4M69 175h.4M69 176.7h.4M69 178.4h.4M69.7 169.5l.3-.3v.8M69.7 171h.5v.2l-.5 .5h.5M69.7 172.6h.5l-.2 .3 .2 .1v.4h-.5M69.7 179.5h.5l-.3 .9M69.7 170h.5M69.8 167.5l.3-.1 .1 .2-.1 .7h-.2l-.2-.3z"/>
<path d="M70 174.3l-.3 .6h.5M70.1 177.8h-.2l-.2 .7 .2 .2 .3-.1v-.4l-.3-.1-.2 .2M70.1 174.6v.6M70.2 176.1h-.4l-.1 .4 .4-.1 .1 .4h-.5M72.7 168.9l.8 .2-.8 .4M72.8 168.1l-.1 .3 .2 .2h.5l.1-.2-.1-.3M72.8 167.3l-.1 .3 .3 .2 .5-.2-.1-.3M76 167.8h.3l.1-.3-.4-.1v.9h.4l.1-.3-.3-.2M76 169.5h.4v-.2l-.4-.1v.8h.3l.2-.3-.3-.2M76 171.3l.4-.1-.1-.3h-.3v.8h.4l.1-.2-.3-.2M76 173h.3l.1-.3-.4-.1v.9h.3l.2-.3-.3-.2M76 174.8l.4-.1-.1-.3h-.3v.8h.3l.2-.2-.1-.2h-.2"/>
<path d="M76 176.5l.4-.1v-.3h-.4v.8h.4l.1-.2-.3-.2M76 178.2h.3l.1-.4h-.4v.9h.3l.2-.4-.3-.1M76 180l.4-.1-.1-.4h-.3v.9h.3l.2-.2v-.2h-.3M76.7 172.6h.6l-.3 .3 .3 .1v.4h-.6M76.7 179.5h.6l-.4 .9M76.8 169.5l.2-.3v.8M76.8 171l.4-.1 .1 .3-.6 .5h.6M76.8 170h.5M77 167.4l.3 .2-.1 .7-.4-.1v-.6zM77 174.3l-.2 .6h.5M77.2 177.8l-.4 .2v.6h.5v-.4l-.4-.1-.1 .2M77.2 174.6v.6"/>
<path d="M77.3 176.1h-.5v.4h.5l-.1 .4-.4-.1M99.9 168.3l.3-.9 .3 .9M99.9 170l.3-.8 .3 .8M99.9 171.7l.3-.8 .3 .8M99.9 173.5l.3-.9 .3 .9M99.9 175.2l.3-.8 .3 .8M99.9 176.9l.3-.8 .3 .8M99.9 178.7l.3-.9 .3 .9M100 168.1h.5M100 169.8h.5M100 171.5h.5M100 173.3h.5"/>
<path d="M100 175h.5M100 176.7h.5M100 178.4h.5M100.7 169.5l.3-.3v.8M100.7 171h.5v.2l-.5 .5h.5M100.7 172.6h.5l-.2 .3 .2 .1v.4h-.5M100.7 179.5h.6l-.4 .9M100.7 170h.5M100.8 167.5l.2-.1 .2 .2-.1 .7h-.2l-.2-.3zM101 174.3l-.3 .6h.6M101.1 177.8h-.2l-.2 .7 .2 .2 .3-.1v-.4l-.3-.1-.2 .2M101.1 174.6v.6"/>
<path d="M101.2 176.1h-.4l-.1 .4 .4-.1 .1 .4h-.5M103.7 168.9l.8 .2-.8 .4M103.8 168.1l-.1 .3 .2 .2h.4l.2-.2-.1-.3M103.8 167.3a.43 .43 0 0 0 .2 .4 .43 .43 0 0 0 .5-.1l-.1-.3M107 167.8h.3l.1-.3-.4-.1v.9h.4l.1-.3-.3-.2M107 169.5h.4v-.2l-.4-.1v.8h.3l.2-.3-.3-.2M107 171.3l.4-.1-.1-.3h-.3v.8h.4l.1-.2-.3-.2M107 173h.3l.1-.3-.4-.1v.9h.3l.2-.3-.3-.2M107 174.8l.4-.1-.1-.3h-.3v.8h.3l.2-.2-.1-.2h-.2M107 176.5l.4-.1v-.3h-.4v.8h.4l.1-.2-.3-.2M107 178.2h.3l.1-.4h-.4v.9h.3l.2-.4-.3-.1M107 180l.4-.1-.1-.4h-.3v.9h.3l.2-.2v-.2h-.3"/>
<path d="M107.7 172.6h.6l-.3 .3 .3 .2v.3l-.1 .1-.5-.1M107.7 179.5h.6l-.3 .9M107.8 169.5l.3-.3v.8M107.8 171l.4-.1 .1 .3-.6 .5h.6M107.8 170h.5M108 167.4a.43 .43 0 0 1 .3 .5 .43 .43 0 0 1-.4 .4l-.1-.7zM108 174.3l-.2 .6h.5M108.2 176.1h-.4v.4l.4-.1v.5l-.4-.1M108.2 177.8h-.3l-.1 .8 .4 .1 .1-.2-.1-.4-.4 .2M108.2 174.6v.6M129.2 168.3l.3-.9 .2 .9M129.2 170l.3-.8 .2 .8"/>
<path d="M129.2 171.7l.3-.8 .2 .8M129.2 173.5l.3-.9 .2 .9M129.2 175.2l.3-.8 .2 .8M129.2 176.9l.3-.8 .2 .8M129.2 178.7l.3-.9 .2 .9M129.3 168.1h.4M129.3 169.8h.4M129.3 171.5h.4M129.3 173.3h.4M129.3 175h.4M129.3 176.7h.4M129.3 178.4h.4"/>
<path d="M130 169.5l.3-.3v.8M130 171h.5v.2l-.5 .5h.5M130 172.6h.5l-.2 .3 .2 .1v.4h-.5M130 179.5h.6l-.4 .9M130 170h.5M130.1 167.5l.2-.1 .2 .2-.1 .7h-.2l-.2-.3zM130.3 174.3l-.3 .6h.6M130.4 177.8h-.2l-.2 .7 .2 .2 .3-.1v-.4l-.3-.1-.2 .2M130.4 174.6v.6M130.5 176.1h-.4l-.1 .4 .4-.1 .1 .4h-.5M133 168.9l.8 .2-.8 .4M133.1 168.1l-.1 .3 .1 .2h.5l.2-.2-.1-.3"/>
<path d="M133.1 167.3l-.1 .3 .3 .2 .5-.2-.1-.3M136.3 167.8h.3l.1-.3-.4-.1v.9h.4l.1-.3-.3-.2M136.3 169.5h.4v-.2l-.4-.1v.8h.3l.2-.3-.3-.2M136.3 171.3l.4-.1-.1-.3h-.3v.8h.4l.1-.2-.3-.2M136.3 173h.3l.1-.3-.4-.1v.9h.3l.2-.3-.3-.2M136.3 174.8l.4-.1-.1-.3h-.3v.8h.3l.2-.2v-.1l-.3-.1M136.3 176.5l.4-.1v-.3h-.4v.8h.4l.1-.2-.3-.2M136.3 178.2h.3l.1-.4h-.4v.9h.3l.2-.4-.3-.1M136.3 180l.4-.1-.1-.4h-.3v.9h.3l.2-.2v-.2h-.3M137 172.6h.5l-.2 .3 .2 .1v.4h-.5M137 179.5h.6l-.3 .9M137.1 169.5l.3-.3v.8"/>
<path d="M137.1 171l.4-.1v.3l-.5 .5h.5M137.1 170h.4M137.3 167.4l.2 .2v.7l-.4-.1v-.6zM137.3 174.3l-.2 .6h.5M137.5 177.8l-.4 .2v.6l.4 .1v-.5l-.2-.1-.2 .2M137.5 174.6v.6M137.5 176.1h-.4v.4h.4v.4l-.4-.1M165.1 161.2h1.5M165.1 162.9h1.6M165.1 164.6h1.3M165.1 163.1v.8l.2 .1h.3v-.9M165.1 164.9v.8h.5"/>
<path d="M165.3 161.4l.4 .3-.1 .6-.5-.1v-.6zM165.8 165.3h.4l.1-.2-.1-.2h-.4v.8l.5-.1v-.2l-.1-.1M166.1 163.5h.3l.1-.3-.4-.1v.9h.3l.2-.3-.3-.2M166.1 161.8h.2M166.2 160.1h.2M166.5 161.4h-.4v.9h.4M169.1 167.6h.9l-.9 .4h.9M169.1 166.9l.3-.2h.4l.2 .1v.4h-.9zM169.2 168.4l-.1 .3 .3 .2h.4l.2-.1v-.4h-.4v.2M170.9 168.4v.4l.2 .1h.4l.2-.2v-.3h-.4v.2M170.9 167.6h.8l-.8 .4h.8M170.9 166.8l.2-.1h.4l.2 .2v.3h-.8z"/>
<path d="M204.7 161.2h1.5M204.7 162.9h1.6M204.7 164.6h1.3M204.8 163.1v.8l.1 .1h.4v-.9M204.8 164.9v.8h.4M204.9 161.4l.4 .2-.1 .7-.4-.1v-.6zM205.4 165.3h.4l.1-.2v-.2h-.5v.8l.5-.1v-.2l-.1-.1M205.7 163.5h.3l.1-.3-.4-.1v.9h.3l.2-.3-.3-.2M205.7 161.8h.2M205.8 160.1h.2M206.1 161.4h-.4v.9h.4M208.7 167.6h.9l-.9 .4h.9"/>
<path d="M208.7 166.9l.3-.2h.4l.2 .1v.4h-.9zM208.8 168.4l-.1 .3 .3 .2h.4l.2-.1v-.4h-.3v.2M210.5 168.4v.4l.2 .1h.4l.3-.2-.1-.3h-.4v.2M210.5 167.6h.9l-.9 .4h.9M210.5 166.8l.2-.1h.4l.3 .2v.3h-.9zM69 180.4l.2-.9 .3 .9M69 183.9l.2-1 .3 1M69 180.1h.4M69 183.6h.4M69.6 184.8l-.5-.1a.44 .44 0 0 0-.1 .6 .44 .44 0 0 0 .6 .2M69.8 183.5h.6M69.9 185.1h.3"/>
<path d="M70.3 184.7h-.4v.8h.4M70.8 183.3l.7 .2-.7 .3M71.9 183.3h.4v-.3l-.4-.1v1h.4l.1-.4-.2-.2M72.7 185.4v.3l.3 .2 .5-.2-.1-.4h-.2v.2M72.7 184.4h.8l-.8 .6h.8M72.7 183.7l.3-.2 .4 .1 .1 .4h-.8zM99.9 180.4l.3-.9 .3 .9M99.9 183.9l.3-1 .3 1M100 180.1h.5M100 183.6h.5M100.5 184.8l-.3-.1-.2 .2v.4l.3 .2h.2M100.8 183.5h.7"/>
<path d="M100.9 185.1h.3M101.3 184.7h-.4v.8h.4M101.8 183.3l.7 .2-.7 .3M102.9 183.3h.3l.1-.3-.4-.1v1h.3l.2-.4-.2-.2M103.7 184.4h.8l-.8 .6h.8M103.8 185.4a.43 .43 0 0 0 .2 .4 .43 .43 0 0 0 .5-.1l-.1-.4h-.2v.2M103.8 183.7l.2-.2 .4 .1 .1 .4h-.8zM129.2 180.4l.3-.9 .2 .9M129.2 183.9l.3-1 .2 1M129.3 180.1h.4M129.3 183.6h.4M129.8 184.8l-.3-.1-.2 .2v.4l.3 .2h.2"/>
<path d="M130.1 183.5h.7M130.2 185.1h.3M130.6 184.7h-.4v.8h.4M131.1 183.3l.7 .2-.7 .3M132.2 183.3h.3l.1-.3-.4-.1v1h.3l.2-.4-.2-.2M133 185.4v.3l.3 .2 .5-.2-.1-.4h-.2v.2M133 184.4h.8l-.8 .6h.8M133 183.7l.3-.2 .4 .1 .1 .4h-.8z"/>
</g>
<g fill="none" stroke="#090" stroke-width=".21">
<path d="M24.1 34.4h11.2M32.6 32.7h2.7M32.6 29.2h2.7M32.6 36.1h2.7M47.3 21.5h13.8M73.1 32.7h1.8M78.3 32.7h.9M94.7 32.7h5.2M94.7 29.2h5.2M94.7 34.4h5.2M94.7 27.6h5.2M94.7 30.9h5.2"/>
<path d="M247.9 32.7h5.3v6.9M24.9 44.7h10.4M24.9 41.3h10.4M24.9 48.2h10.4M27.5 56.9h7.8M32.6 46.4h2.7M32.6 43h2.7M32.6 49.9h2.7M32.6 51.7h2.7M32.6 58.5h2.7M32.6 55.1h2.7M32.6 53.4h2.7"/>
<path d="M73.1 46.4h2.6M73.1 58.5h5.2M73.1 56.9h9.5M95.5 58.5h4.4M138.6 59.4v.8h-.9M169.6 59.4v.8h-.8M202.3 59.4v.8h-.8M235.1 57.7h-9.5v19M235.1 59.4v.8h-.9M27.5 75.7h7.8M32.6 65.4h2.7M32.6 70.6h2.7"/>
<path d="M32.6 60.2h2.7M32.6 63.7h2.7M32.6 62h2.7M32.6 67.2h2.7M32.6 68.9h2.7M32.6 74h2.7M32.6 72.3h2.7M73.1 65.4h1.8M73.1 70.6h1.8M73.1 75.7h1.8M73.1 60.2h9.5M73.1 63.7h8.6"/>
<path d="M73.1 62h1.8M73.1 67.2h1.8M73.1 68.9h1.8M73.1 74h1.8M73.1 72.3h1.8M73.1 79.2h1.8M73.1 77.5h1.8M95.5 65.4h4.4M95.5 70.6h4.4M95.5 60.2h4.4M95.5 63.7h4.4M95.5 62h4.4"/>
<path d="M95.5 67.2h4.4M95.5 68.9h4.4M138.6 64.6v.8h-.9M138.6 69.7v.9h-.9M138.6 74.9v.8h-.9M169.6 64.6v.8h-.8M169.6 69.7v.9h-.8M169.6 74.9v.8h-.8M202.3 64.6v.8h-.8M202.3 69.7v.9h-.8M202.3 74.9v.8h-.8M225.6 68h9.5"/>
<path d="M225.6 73.2h9.5M225.6 62.9h9.5M235.1 64.6v.8h-.9M235.1 69.7v.9h-.9M235.1 74.9v.8h-.9M29.2 93h6.1M29.2 94.7h6.1M29.2 91.2h6.1M29.2 89.5h6.1M33.5 99.9h1.8M33.5 96.4h1.8M33.5 98.2h1.8"/>
<path d="M73.1 80.9h8.6M73.1 99.9h1.8M73.1 93h1.8M73.1 94.7h1.8M73.1 96.4h1.8M73.1 91.2h1.8M73.1 98.2h1.8M73.1 89.5h1.8M73.1 86.1h1.8M73.1 87.8h1.8M73.1 82.7h1.8M73.1 84.4h1.8"/>
<path d="M95.5 98.2h4.4v8.6M95.5 94.7h4.4M95.5 96.4h4.4M180 99.9h4.3M184.3 98.2v6.8M207.5 97.3h68.9M207.5 93.8h68.9M33.5 101.6h1.8M33.5 103.3h1.8M39.6 119.7h1.7M48.1 108.5h12.1M143.8 108.5h7.7"/>
<path d="M176.5 108.5h7.8M215.3 106.8h60.2M215.3 110.2h60.2M227.3 116.2h17.3M227.3 119.7h17.3M30.1 138.6h2.5M30.1 135.2h2.5M30.1 130h2.5M30.1 128.3h2.5M30.1 133.5h2.5M30.1 126.6h2.5M30.1 124.8h2.5"/>
<path d="M30.1 136.9h2.5M30.1 131.8h2.5M48.1 138.6h1.8M48.1 135.2h1.8M48.1 130h1.8M48.1 128.3h1.8M48.1 133.5h1.8M48.1 126.6h1.8M48.1 124.8h1.8M48.1 136.9h1.8M48.1 131.8h1.8M158.5 132.6h4.2"/>
<path d="M158.5 129.2h4.2M158.5 134.3h4.2M158.5 136h4.2M158.5 130.8h4.2M158.5 125.7h4.2M158.5 127.5h4.2M158.5 137.8h4.2M158.5 139.5h4.2M169.6 120.5h1.7M178.2 132.6h3.4M178.2 129.2h3.4M178.2 134.3h3.4"/>
<path d="M178.2 136h3.4M178.2 130.8h3.4M178.2 125.7h3.4M178.2 127.5h3.4M178.2 137.8h3.4M178.2 139.5h3.4M198 132.6h4.3M198 129.2h4.3M198 134.3h4.3M198 136h4.3M198 130.8h4.3M198 125.7h4.3"/>
<path d="M198 127.5h4.3M198 137.8h4.3M198 139.5h4.3M209.3 120.5h1.6M228.2 132.6h43M228.2 129.2h43M24.9 149h7.7M24.9 147.3h7.7M24.9 145.5h7.7M24.9 143.8h7.7M24.9 140.3h7.7M24.9 142.1h7.7"/>
<path d="M25.8 154.1h6.8M25.8 157.6h6.8M25.8 159.3h6.8M32.6 152.4h-15.5v3.4h15.5M48.1 149h1.8M48.1 147.3h1.8M48.1 145.5h1.8M48.1 143.8h1.8M48.1 140.3h1.8M48.1 142.1h1.8M48.1 150.7h1.8M64.6 148.1v.9h-.9"/>
<path d="M95.5 148.1v.9h-.8M124.8 148.1v.9h-.8M158.5 151.6h4.2M158.5 148.1h4.2M158.5 146.4h4.2M158.5 143h4.2M158.5 149.8h4.2M158.5 144.6h4.2M158.5 155h4.2M158.5 153.3h4.2M158.5 141.2h4.2M162.7 158.5h-15.5v3.4h15.5"/>
<path d="M178.2 151.6h3.4M178.2 148.1h3.4M178.2 146.4h3.4M178.2 143h3.4M178.2 149.8h3.4M178.2 144.6h3.4M178.2 141.2h3.4M198 151.6h4.3M198 148.1h4.3M198 146.4h4.3M198 143h4.3M198 149.8h4.3"/>
<path d="M198 144.6h4.3M198 155h4.3M198 153.3h4.3M198 141.2h4.3M202.3 158.5h-15.5v3.4h15.5M229.1 154.1h25.8M229.1 157.6h25.8M39.6 166.2h1.7M155.8 160.1h6.9M155.8 165.3h6.9M155.8 163.6h6.9M169.6 171.4h1.7"/>
<path d="M195.4 160.1h6.9M195.4 165.3h6.9M195.4 163.6h6.9M209.3 171.4h1.6M229.1 170.5h34.4M229.1 167.1h34.4M64.6 185.1v.9h-.9M95.5 185.1v.9h-.8M124.8 185.1v.9h-.8"/>
</g>
<g fill="none" stroke="#00008a" stroke-width=".21">
<path d="M34.8 30.5l.9 .9M34.8 37.5l.9 .8M35.7 30.5l-.9 .9M35.7 37.5l-.9 .8M72.8 35.8l.7 .7M72.8 34l.7 .8M72.8 39.2l.7 .8M72.8 37.5l.7 .8M73.5 35.8l-.7 .7M73.5 34l-.7 .8M73.5 39.2l-.7 .8M73.5 37.5l-.7 .8"/>
<path d="M270 32.3l.8 .8M270 37.5l.8 .8M270.8 32.3l-.8 .8M270.8 37.5l-.8 .8M72.8 42.6l.7 .9M72.8 49.5l.7 .8M72.8 51.3l.7 .7M72.8 47.8l.7 .8M72.8 44.3l.7 .9M72.8 40.9l.7 .8M72.8 54.6l.7 .9M72.8 53l.7 .8"/>
<path d="M73.5 42.6l-.7 .9M73.5 49.5l-.7 .8M73.5 51.3l-.7 .7M73.5 47.8l-.7 .8M73.5 44.3l-.7 .9M73.5 40.9l-.7 .8M73.5 54.6l-.7 .9M73.5 53l-.7 .8M34.8 78.8l.9 .8M34.8 77.1l.9 .8M35.7 78.8l-.9 .8M35.7 77.1l-.9 .8"/>
<path d="M34.8 80.5l.9 .8M34.8 83.9l.9 .9M34.8 82.3l.9 .8M34.8 87.4l.9 .9M34.8 85.7l.9 .8M35.7 80.5l-.9 .8M35.7 83.9l-.9 .9M35.7 82.3l-.9 .8M35.7 87.4l-.9 .9M35.7 85.7l-.9 .8M116.6 99.4l.9 .9M116.6 97.7l.9 .9"/>
<path d="M117.5 99.4l-.9 .9M117.5 97.7l-.9 .9M201 97.7l.9 .9M201 99.4l.9 .9M201.9 97.7l-.9 .9M201.9 99.4l-.9 .9M116.6 104.6l.9 .8M116.6 101.2l.9 .8M116.6 106.4l.9 .7M116.6 102.9l.9 .9M117.5 104.6l-.9 .8M117.5 101.2l-.9 .8"/>
<path d="M117.5 106.4l-.9 .7M117.5 102.9l-.9 .9M201 102.9l.9 .9M201 104.6l.9 .8M201 101.2l.9 .8M201.9 102.9l-.9 .9M201.9 104.6l-.9 .8M201.9 101.2l-.9 .8"/>
</g>
<g fill="#090">
<circle cx="250.6" cy="97.3" r=".38"/>
<circle cx="249.7" cy="110.2" r=".38"/>
<circle cx="241.9" cy="97.3" r=".38"/>
<circle cx="232.4" cy="106.8" r=".38"/>
<circle cx="233.4" cy="97.3" r=".38"/>
<circle cx="249.7" cy="106.8" r=".38"/>
<circle cx="259.2" cy="97.3" r=".38"/>
<circle cx="229.1" cy="167.1" r=".38"/>
<circle cx="229.1" cy="170.5" r=".38"/>
<circle cx="229.1" cy="157.6" r=".38"/>
<circle cx="229.1" cy="154.1" r=".38"/>
<circle cx="227.3" cy="116.2" r=".38"/>
<circle cx="227.3" cy="119.7" r=".38"/>
<circle cx="235.9" cy="116.2" r=".38"/>
<circle cx="235.9" cy="119.7" r=".38"/>
<circle cx="232.4" cy="110.2" r=".38"/>
<circle cx="224.7" cy="97.3" r=".38"/>
<circle cx="223.9" cy="110.2" r=".38"/>
<circle cx="223.9" cy="106.8" r=".38"/>
<circle cx="236.8" cy="129.2" r=".38"/>
<circle cx="236.8" cy="132.6" r=".38"/>
<circle cx="245.4" cy="129.2" r=".38"/>
<circle cx="245.4" cy="132.6" r=".38"/>
<circle cx="228.2" cy="132.6" r=".38"/>
<circle cx="228.2" cy="129.2" r=".38"/>
<circle cx="262.6" cy="129.2" r=".38"/>
<circle cx="262.6" cy="132.6" r=".38"/>
<circle cx="254" cy="129.2" r=".38"/>
<circle cx="254" cy="132.6" r=".38"/>
<circle cx="246.2" cy="170.5" r=".38"/>
<circle cx="246.2" cy="167.1" r=".38"/>
<circle cx="237.6" cy="170.5" r=".38"/>
<circle cx="237.6" cy="167.1" r=".38"/>
<circle cx="246.2" cy="154.1" r=".38"/>
<circle cx="246.2" cy="157.6" r=".38"/>
<circle cx="237.6" cy="157.6" r=".38"/>
<circle cx="237.6" cy="154.1" r=".38"/>
<circle cx="254.9" cy="167.1" r=".38"/>
<circle cx="254.9" cy="170.5" r=".38"/>
<circle cx="169.6" cy="171.4" r=".38"/>
<circle cx="147.2" cy="161.9" r=".38"/>
<circle cx="99.9" cy="103.3" r=".38"/>
<circle cx="99.9" cy="105" r=".38"/>
<circle cx="253.2" cy="37.9" r=".38"/>
<circle cx="253.2" cy="34.4" r=".38"/>
<circle cx="253.2" cy="32.7" r=".38"/>
<circle cx="225.6" cy="73.2" r=".38"/>
<circle cx="216.1" cy="93.8" r=".38"/>
<circle cx="224.7" cy="93.8" r=".38"/>
<circle cx="225.6" cy="68" r=".38"/>
<circle cx="233.4" cy="93.8" r=".38"/>
<circle cx="207.5" cy="93.8" r=".38"/>
<circle cx="225.6" cy="62.9" r=".38"/>
<circle cx="258.4" cy="106.8" r=".38"/>
<circle cx="241.1" cy="106.8" r=".38"/>
<circle cx="241.1" cy="110.2" r=".38"/>
<circle cx="258.4" cy="110.2" r=".38"/>
<circle cx="241.9" cy="93.8" r=".38"/>
<circle cx="250.6" cy="93.8" r=".38"/>
<circle cx="259.2" cy="93.8" r=".38"/>
<circle cx="266.9" cy="106.8" r=".38"/>
<circle cx="266.9" cy="110.2" r=".38"/>
<circle cx="267.8" cy="93.8" r=".38"/>
<circle cx="267.8" cy="97.3" r=".38"/>
<circle cx="52.4" cy="21.5" r=".38"/>
<circle cx="55.9" cy="21.5" r=".38"/>
<circle cx="54.2" cy="21.5" r=".38"/>
<circle cx="47.3" cy="21.5" r=".38"/>
<circle cx="49.1" cy="21.5" r=".38"/>
<circle cx="57.6" cy="21.5" r=".38"/>
<circle cx="59.4" cy="21.5" r=".38"/>
<circle cx="17.1" cy="155.8" r=".38"/>
<circle cx="39.6" cy="119.7" r=".38"/>
<circle cx="49.9" cy="108.5" r=".38"/>
<circle cx="56.8" cy="108.5" r=".38"/>
<circle cx="51.6" cy="108.5" r=".38"/>
<circle cx="55.1" cy="108.5" r=".38"/>
<circle cx="53.3" cy="108.5" r=".38"/>
<circle cx="48.1" cy="108.5" r=".38"/>
<circle cx="58.5" cy="108.5" r=".38"/>
<circle cx="39.6" cy="166.2" r=".38"/>
<circle cx="99.9" cy="98.2" r=".38"/>
<circle cx="99.9" cy="99.9" r=".38"/>
<circle cx="99.9" cy="101.6" r=".38"/>
<circle cx="184.3" cy="101.6" r=".38"/>
<circle cx="184.3" cy="99.9" r=".38"/>
<circle cx="209.2" cy="120.5" r=".38"/>
<circle cx="215.3" cy="110.2" r=".38"/>
<circle cx="215.3" cy="106.8" r=".38"/>
<circle cx="207.5" cy="97.3" r=".38"/>
<circle cx="216.1" cy="97.3" r=".38"/>
<circle cx="186.8" cy="161.9" r=".38"/>
<circle cx="209.2" cy="171.4" r=".38"/>
<circle cx="169.6" cy="120.5" r=".38"/>
<circle cx="184.3" cy="103.3" r=".38"/>
</g>
<g fill="none" stroke="#006665" stroke-width=".21">
<path d="M46.2 18.2h.7M46.5 17.8v.6M47.7 17.6h-.4l-.1 .4h.5v.3h-.5M48 17.6l.2 .8 .4-.8M62.8 19.3v.7l.1 .2 .4-.1v-.8M63.6 19.3h.5l-.2 .3 .2 .1v.4h-.5M64.6 19.4l.3-.1 .1 .2v.5l-.2 .2a.48 .48 0 0 1-.2-.8zM65.3 19.5l.3-.2v.9M107.3 13.8h.7M107.7 13.5v.7M108.8 13.2h-.4v.5h.4v.4h-.4M109.1 13.2l.3 1 .3-1"/>
<path d="M110.1 18.4h.6l-.4 .9M110.2 16.7l.1 .9h.3l.1-.2v-.7M111 16.7h.5l-.2 .4 .2 .1v.4l-.5-.1M111.2 18.4l-.2 .6h.5M111.4 18.8v.5M111.7 19.3l.3-.9 .3 .9M111.8 19.1h.4M111.9 17l.2-.3v.9M111.9 17.6h.5M112.6 18.4v.9M112.6 18.8h.5M112.7 17l.2-.3v.9"/>
<path d="M112.7 17.6h.5M113.1 18.4v.9M114 18.5a.42 .42 0 0 0-.6 .4 .42 .42 0 0 0 .6 .4M114.2 18.4h.5M114.4 18.4v.9M114.9 18.4h.5l-.2 .4 .2 .1v.3l-.1 .1h-.4M115.7 18.4h.6l-.4 .9M116.5 18.4h.5l-.2 .4h.2v.5h-.5M137.5 13.8h.6M137.8 13.5v.7M139 13.2h-.4v.5h.4v.4h-.4M139.2 13.2l.4 1 .2-1"/>
<path d="M140.2 18.4h.6l-.4 .9M140.3 16.7l.1 .9h.4v-.9M141.2 16.7h.5l-.3 .4h.3v.4h-.5M141.3 18.4l-.2 .6h.6M141.5 18.8v.5M141.9 19.3l.2-.9 .3 .9M141.9 19.1h.5M142 17l.3-.3v.9M142 17.6h.5M142.7 18.8h.5M142.7 18.4v.9M143 16.7l-.1 .6h.5"/>
<path d="M143.2 17v.6M143.2 18.4v.9M144.1 18.5a.42 .42 0 0 0-.6 .4 .42 .42 0 0 0 .6 .4M144.3 18.4h.5M144.6 18.4v.9M145.1 18.7l.2-.3v.9M145.1 19.3h.5M146.3 18.4h-.4v.4h.4l.1 .4-.1 .1h-.4M146.7 18.4h.6l-.4 .9M167.7 13.8h.6M167.9 13.5v.7M169.1 13.2h-.4v.5h.4v.4h-.4"/>
<path d="M169.4 13.2l.3 1 .3-1M170.4 18.4h.6l-.4 .9M170.5 16.7l.1 .9h.3l.1-.9M171.3 16.7h.5l-.2 .4h.2v.4h-.5M171.5 18.4l-.3 .6h.6M171.7 18.8v.5M172 19.3l.3-.9 .3 .9M172.1 19.1h.4M172.2 17l.2-.3v.9M172.2 17.6h.5M172.8 18.8h.6M172.8 18.4v.9"/>
<path d="M173.4 18.4v.9M173.4 16.7h-.4v.4h.4v.5l-.4-.1M174.3 18.5a.42 .42 0 0 0-.6 .4 .42 .42 0 0 0 .6 .4M174.5 18.4h.5M174.7 18.4v.9M175.2 18.7l.3-.3v.9M175.2 19.3h.5M176.5 18.4h-.4v.4h.3l.2 .4-.2 .1h-.3M176.8 18.4h.6l-.3 .9M197.8 13.8h.6M198.1 13.5v.7M199.3 13.2h-.5v.5h.5l-.1 .5-.4-.1"/>
<path d="M199.5 13.2l.4 1 .2-1M200.5 18.4h.6l-.3 .9M200.6 16.7l.1 .9h.3l.1-.2v-.7M201.5 16.7h.5l-.3 .4h.3v.4h-.5M201.6 18.4l-.2 .6h.6M201.8 18.8v.5M202.1 19.3l.3-.9 .3 .9M202.2 19.1h.4M202.3 17l.3-.3v.9M202.3 17.6h.5M203 18.8h.5M203 18.4v.9"/>
<path d="M203.5 18.4v.9M203.6 16.7l-.4 .2v.6l.4 .1v-.5h-.4v.1M204.4 18.5a.42 .42 0 0 0-.6 .4 .42 .42 0 0 0 .6 .4M204.7 18.4h.4M204.8 18.4v.9M205.4 18.7l.2-.3v.9M205.4 19.3h.5M206.6 18.4h-.4v.4h.3l.2 .4-.2 .1h-.3M207 18.4h.6l-.4 .9M228.8 13.8h.7M229.1 13.5v.7M230.2 13.2h-.4v.5l.4-.1 .1 .4-.1 .2-.4-.1"/>
<path d="M230.6 13.2l.2 1 .3-1M231.5 18.4h.6l-.3 .9M231.6 16.7l.1 .9 .4-.1v-.8M232.4 16.7h.6l-.3 .4h.3v.4h-.6M232.6 18.4l-.2 .6h.6M232.8 18.8v.5M233.1 19.3l.4-.9 .2 .9M233.2 19.1h.4M233.3 17l.2-.3v.9M233.3 17.6h.5M234 18.8h.5M234 18.4v.9"/>
<path d="M234.1 16.7h.6l-.4 .9M234.5 18.4v.9M235.4 18.5l-.2-.1-.3 .3v.4l.3 .2h.2M235.7 18.4h.5M235.9 18.4v.9M236.4 18.7l.2-.3v.9M236.4 19.3h.5M237.7 18.4h-.4l-.1 .4h.5v.5h-.5M238 18.4h.5l-.3 .9M260.6 13.8h.7M261 13.5v.7M262.2 13.2h-.5v.5h.5v.4h-.5"/>
<path d="M262.4 13.2l.3 1 .3-1M263.4 18.4h.6l-.4 .9M263.5 16.7l.1 .9h.3l.1-.9M264.3 16.7h.6l-.4 .4h.3l.1 .1-.1 .4-.5-.1M264.5 18.4l-.2 .6h.5M264.7 18.8v.5M265 19.3l.3-.9 .3 .9M265.1 19.1h.4M265.2 17l.2-.3v.9M265.2 17.6h.4M265.9 18.4v.9M265.9 18.8h.5"/>
<path d="M266.1 17.1l-.1-.2 .1-.2 .4 .1-.1 .3-.4 .1 .1 .4 .4-.1v-.4h-.2M266.4 18.4v.9M267.2 18.5l-.2-.1-.3 .3v.4l.3 .2h.2M267.5 18.4h.5M267.8 18.4v.9M268.3 18.7l.2-.3v.9M268.3 19.3h.5M269.5 18.4h-.4v.4h.4v.5h-.4M269.9 18.4h.6l-.5 .9M62.7 21.9l.2-.9 .4 .9M62.8 21.6h.4M63.5 21h.5"/>
<path d="M63.7 21v.9M64.2 21.5h.3M64.6 21h-.4v.9M64.9 21.3l.2-.3v.9M64.9 21.9h.5M65.3 20.2h.5M66.2 21h-.5v.5l.5-.1v.1v.4l-.5-.1M66.7 21h.2l.1 .2-.1 .7h-.2l-.1-.2zM67.5 21.4l-.2-.2 .1-.2 .5 .1-.1 .3-.5 .1 .1 .4 .5-.1v-.3l-.2-.1M68.1 21.9l.3-.9 .3 .9M68.2 21.6h.4M69.4 21l-.4 .1v.3l.4 .1-.1 .4h-.3"/>
<path d="M69.8 21.5h.7M70.7 21h.6l-.3 .9M71.6 21.9l.2-.9 .3 .9M71.7 21.6h.3M72.3 21l.6 .9M72.9 21l-.6 .9M73.2 21.3l.2-.3v.9M73.2 21.9h.5M74.1 21a.42 .42 0 0 1 .5 .5 .42 .42 0 0 1-.5 .4zM74.9 21.1l.3-.1 .1 .2-.1 .6a.39 .39 0 0 1-.4-.2 .39 .39 0 0 1 .1-.5zM75.4 34h.5l-.3 .2 .3 .1v.5h-.5M75.4 36.1h.3l.1-.2-.4-.1v.6"/>
<path d="M75.6 36.1l.2 .3M76.1 35.8h.4l-.3 .2h.2l.1 .4h-.4M76.2 34h.5l-.2 .2 .2 .1v.5h-.5M76.8 35.8a.31 .31 0 0 1 .4 .3 .31 .31 0 0 1-.5 .3zM77.2 34.4l.4-.1v-.3h-.4v.8M77.3 34.4l.3 .4M77.4 35.9l.2-.1v.6M77.4 36.4h.4M247.4 35.7h-.4l-.2 .2v.5l.2 .1h.4v-.3h-.2M248.2 35.7v.8l-.4-.8v.8M248.6 35.7h.4l.1 .2v.5l-.1 .1h-.4zM99.2 42.6a.43 .43 0 0 0-.5 .3 .43 .43 0 0 0 .1 .5h.4l-.1-.4"/>
<path d="M100.1 42.5v.9l-.5-.9v.9M100.5 42.5l.5 .3v.4l-.2 .2h-.3zM107.3 50h.7M107.7 49.7v.6M107.8 47.8l-.2-.1-.3 .3v.4l.2 .2h.3v-.4h-.1M108.7 47.7v.9l-.5-.9v.9M108.8 49.5h-.4v.3h.4v.4h-.4M109.1 49.5l.3 .8 .3-.8M109.1 47.7h.2l.3 .3v.4l-.2 .2h-.3zM110.1 54.6h.6l-.4 .9M110.2 52.9v.8l.5-.1v-.7M111 52.9h.5l-.2 .3 .2 .2v.2l-.5 .1"/>
<path d="M111.2 54.6l-.2 .6h.5M111.4 54.9v.6M111.7 55.5l.3-.9 .3 .9M111.8 55.2h.4M111.9 53.1l.2-.2v.8M111.9 53.7h.5M112.6 54.6v.9M112.6 55.1h.5M112.7 53h.5v.3l-.6 .4h.6M113.1 54.6v.9M114 54.7l-.4-.1a.44 .44 0 0 0-.1 .6 .44 .44 0 0 0 .5 .2M114.2 54.6h.5"/>
<path d="M114.4 54.6v.9M114.9 54.6h.5l-.2 .4 .2 .1v.2l-.1 .2-.4-.1M115.7 54.6h.6l-.4 .9M116.5 54.6h.5l-.2 .4 .2 .1v.3h-.5M129.3 47.8a.43 .43 0 0 0-.4 .2 .43 .43 0 0 0 .1 .6l.4-.1v-.3h-.2M130.3 47.7v.9l-.6-.9v.9M130.7 47.7l.4 .3v.4l-.2 .2h-.2zM138 53l-.3-.1-.2 .2v.4l.1 .2h.4v-.3h-.2M138.8 52.9v.8l-.4-.8v.8M139.2 52.9h.3l.2 .2v.4l-.1 .2h-.4zM146.1 49.1h.7M146.4 48.8v.7"/>
<path d="M147.6 48.6h-.4l-.1 .4h.5v.4h-.5M147.9 48.6l.2 .9 .4-.9M148.9 53.7h.6l-.4 .9M149 52l.1 .9h.3l.1-.2v-.7M149.7 52h.6l-.3 .4 .3 .1-.1 .4-.5-.1M149.9 53.7l-.2 .6h.5M150.2 54.1v.5M150.5 54.6l.2-.9 .3 .9M150.6 54.4h.3M150.7 52.3l.2-.3v.9M150.7 52.9h.4M151.3 54.1h.5"/>
<path d="M151.3 53.7v.9M151.8 53.7v.9M151.9 52.4h-.5l.2-.4 .3 .1v.6l-.4 .2M152.7 53.8l-.2-.1a.43 .43 0 0 0-.3 .5 .43 .43 0 0 0 .5 .4M152.9 53.7h.6M153.2 53.7v.9M153.7 54l.3-.3v.9M153.7 54.6h.5M155 53.7h-.4v.4h.4l-.1 .5h-.3M155.3 53.7h.6l-.4 .9M159.5 47.8a.43 .43 0 0 0-.5 .2 .43 .43 0 0 0 .1 .6l.5-.1v-.3h-.2M160.4 47.7v.9l-.5-.9v.9"/>
<path d="M160.8 47.7l.4 .3v.4l-.1 .2h-.3zM168.1 53l-.1-.1a.48 .48 0 0 0-.4 .3 .48 .48 0 0 0 .2 .5h.3v-.3h-.2M168.9 52.9v.8l-.4-.8v.8M169.4 52.9h.2l.3 .2v.4l-.2 .2h-.3zM177.1 49.1h.7M177.4 48.8v.7M178.6 48.6h-.4v.4h.4v.4h-.4M178.9 48.6l.3 .9 .2-.9M179.9 53.7h.6l-.5 .9M180 52v.9h.4l.1-.2v-.7M180.8 52h.5l-.2 .4 .2 .1-.1 .4-.4-.1M181 53.7l-.3 .6h.5"/>
<path d="M181.1 54.1v.5M181.5 54.6l.2-.9 .4 .9M181.6 54.4h.4M181.6 52.1l.4-.1 .2 .3-.6 .6h.6M182.3 54.1h.5M182.3 53.7v.9M182.5 52.1l.2-.1 .2 .2-.1 .7-.3-.1zM182.8 53.7v.9M183.8 53.8a.42 .42 0 0 0-.6 .4 .42 .42 0 0 0 .6 .4M183.9 53.7h.5M184.2 53.7v.9M184.7 54l.3-.3v.9"/>
<path d="M184.7 54.6h.5M186 53.7h-.5v.4h.4l.2 .4-.2 .1h-.4M186.3 53.7h.6l-.4 .9M189.6 47.8a.43 .43 0 0 0-.5 .2 .43 .43 0 0 0 .2 .6l.4-.1v-.3h-.2M190.5 47.7v.9l-.5-.9v.9M191 47.7l.4 .3-.1 .6h-.3zM198.2 53v-.1a.48 .48 0 0 0-.4 .3 .48 .48 0 0 0 .1 .5h.3v-.3h-.1M199.2 52.9v.8l-.5-.8v.8M199.5 52.9h.3l.2 .2v.4l-.1 .2h-.4zM209.8 49.1h.7M210.2 48.8v.7M211.3 48.6h-.4v.4l.3-.1 .2 .4-.2 .2-.3-.1"/>
<path d="M211.6 48.6l.3 .9 .3-.9M212.6 53.7h.5l-.3 .9M212.7 52l.1 .9 .3-.1v-.8M213.5 52h.6l-.4 .4 .4 .1-.1 .4-.5-.1M213.7 53.7l-.2 .6h.5M213.9 54.1v.5M214.2 54.6l.3-.9 .3 .9M214.2 54.4h.5M214.3 52.1h.5v.3l-.5 .5h.5M215.1 54.1h.4M215.1 53.7v.9M215.2 52.3l.2-.3v.9"/>
<path d="M215.2 52.9h.5M215.5 53.7v.9M216.4 53.8l-.2-.1-.3 .3v.4l.3 .2h.2M216.7 53.7h.5M217 53.7v.9M217.5 54l.2-.3v.9M217.5 54.6h.5M218.7 53.7h-.4l-.1 .4h.5v.5h-.5M219.1 53.7h.5l-.4 .9M220.6 47.8l-.2-.1-.2 .3 .1 .6 .4-.1v-.3h-.2M221.5 47.7v.9l-.5-.9v.9M222 47.7a.49 .49 0 0 1 .4 .3 .49 .49 0 0 1-.1 .6h-.3z"/>
<path d="M229.2 53a.43 .43 0 0 0-.4 .2 .43 .43 0 0 0 .1 .5h.4v-.3h-.2M230.2 52.9v.8l-.5-.8v.8M230.6 52.9l.4 .2v.4l-.2 .2h-.2zM242.6 49.1h.6M242.9 48.8v.7M244 48.6h-.4v.4h.4v.5l-.4-.1M244.3 48.6l.3 .9 .3-.9M245.3 53.7h.6l-.3 .9M245.4 52l.1 .9h.3l.1-.2v-.7M246.2 52h.6l-.3 .4h.3v.4h-.6M246.4 53.7l-.2 .6h.6M246.6 54.1v.5"/>
<path d="M246.9 54.6l.3-.9 .3 .9M247 54.4h.4M247.1 52.1l.3-.1 .2 .3-.6 .6h.6M247.8 53.7v.9M247.8 54.1h.5M247.9 52.1l.4-.1 .1 .4-.5 .5h.5M248.3 53.7v.9M249.2 53.8a.42 .42 0 0 0-.6 .4 .42 .42 0 0 0 .6 .4M249.5 53.7h.4M249.6 53.7v.9M250.1 54l.3-.3v.9M250.1 54.6h.6"/>
<path d="M251.4 53.7h-.4v.4h.3l.2 .4-.2 .1h-.3M251.8 53.7h.5l-.3 .9M252.5 47.8l-.2-.1-.3 .3v.4l.2 .2h.3v-.4h-.2M253.4 47.7v.9l-.5-.9v.9M253.8 47.7h.2l.3 .3v.4l-.2 .2h-.3zM261.1 53l-.2-.1-.3 .2v.4l.2 .2h.4v-.3h-.2M262 52.9v.8l-.5-.8v.8M262.4 52.9a.49 .49 0 0 1 .5 .3 .49 .49 0 0 1-.1 .5h-.4zM99.2 78.8a.4 .4 0 0 0-.5 .4 .4 .4 0 0 0 .5 .3l-.1-.3M100.1 78.7v.9l-.5-.9v.9M100.5 78.7l.5 .2v.5l-.3 .2h-.2zM224.9 79.6h-.3a.44 .44 0 0 0-.1 .6 .44 .44 0 0 0 .5 .2v-.4h-.2"/>
<path d="M225.8 79.6v.9l-.5-.9v.9M226.3 79.6h.3a.48 .48 0 0 1 .1 .6 .48 .48 0 0 1-.4 .3zM107.3 86.1h.7M107.7 85.8v.7M107.8 83.9h-.3l-.2 .2v.4l.3 .3 .2-.1v-.3h-.1M108.7 83.9v.9l-.5-.9v.9M108.8 85.6h-.4v.5h.4v.4l-.4-.1M109.1 83.9h.3l.2 .2v.4l-.3 .3h-.2zM109.1 85.6l.3 .9 .3-.9M110.1 90.8h.6l-.4 .8M110.2 89.1v.8l.2 .1 .3-.2v-.7M111 89.1h.5l-.2 .3 .2 .1v.3l-.1 .2-.4-.1"/>
<path d="M111.2 90.7l-.2 .7h.5M111.4 91.1v.5M111.7 91.6l.3-.8 .3 .8M111.8 91.4h.4M111.9 89.3l.2-.2v.9M111.9 90h.5M112.6 90.8v.8M112.6 91.2h.5M112.6 89.1h.6l-.3 .3h.3v.5h-.6M113.1 90.8v.8M114 90.9l-.4-.1-.2 .3 .2 .5h.4M114.2 90.8h.5"/>
<path d="M114.4 90.8v.8M114.9 90.8h.5l-.2 .3 .2 .2v.3h-.5M115.7 90.8h.6l-.4 .8M116.5 90.8h.5l-.2 .3 .2 .1v.4h-.5M138 83.1l-.3-.1-.2 .3v.4l.2 .2h.3v-.4h-.2M138.8 83v.9l-.4-.9v.9M139.2 83h.3l.2 .3v.4l-.2 .2h-.3zM146.6 88.3l-.3-.1-.2 .2v.5l.2 .2 .3-.1v-.3h-.2M147.4 88.2v.9l-.5-.9v.9M147.9 88.2a.47 .47 0 0 1 .5 .4 .47 .47 0 0 1-.5 .5zM159 84.5h.7M159.4 84.1v.7"/>
<path d="M160.5 83.9h-.4v.4l.3-.1 .2 .4-.2 .2-.3-.1M160.8 83.9l.3 .9 .2-.9M161.8 89.1h.5l-.3 .9M161.8 87.3l.1 .9 .4-.1v-.8M162.7 87.3h.5l-.3 .4 .3 .1v.3h-.5M162.9 89l-.2 .6h.5M163 89.4v.6M163.4 90l.3-.9 .3 .9M163.4 89.7h.5M163.5 87.4h.5v.4l-.5 .4h.5M164.2 89.1v.9M164.2 89.4h.5"/>
<path d="M164.3 87.3h.6l-.4 .4 .4 .1-.1 .4-.5-.1M164.7 89.1v.9M165.6 89.2l-.3-.1-.2 .2v.4l.3 .3 .2-.1M165.9 89.1h.5M166.2 89.1v.9M166.7 89.2l.3-.1 .1 .3-.5 .6h.5M167.7 89l-.3 .6h.6M167.8 89.4v.6M168.7 89.1h-.4v.3h.3l.2 .4-.2 .2-.3-.1M168.9 83.1a.4 .4 0 0 0-.5 .4 .4 .4 0 0 0 .5 .4v-.4M169.9 83v.9l-.5-.9v.9M170.3 83l.4 .3v.4l-.2 .2h-.2z"/>
<path d="M177.6 88.3l-.3-.1-.2 .2v.5l.2 .2 .3-.1v-.3h-.2M178.4 88.2v.9l-.4-.9v.9M178.9 88.2h.2l.3 .2v.5l-.3 .2h-.2zM191.7 84.5h.7M192.1 84.1v.7M193.2 83.9h-.4l-.1 .4h.5v.4h-.5M193.5 83.9l.3 .9 .3-.9M194.5 89.1h.6l-.4 .9M194.6 87.3l.1 .9h.3l.1-.9M195.4 87.3h.6l-.4 .4 .4 .1-.1 .4-.5-.1M195.6 89l-.2 .6h.5M195.8 89.4v.6"/>
<path d="M196.1 90l.3-.9 .3 .9M196.2 89.7h.4M196.3 87.4l.3-.1 .2 .3-.6 .6h.6M197 89.4h.5M197 89.1v.9M197.3 87.3l-.2 .6h.6M197.5 87.7v.5M197.5 89.1v.9M198.3 89.2l-.3-.1a.43 .43 0 0 0-.1 .5 .43 .43 0 0 0 .4 .3M198.6 89.1h.5M198.8 89.1v.9M199.3 89.2l.5-.1 .1 .2-.6 .7h.6"/>
<path d="M200.4 89l-.2 .6h.5M200.6 89.4v.6M201.5 89.1h-.5v.3h.5v.5h-.5M201.7 83.1l-.2-.1-.3 .3v.4l.3 .2h.2v-.4h-.2M202.6 83v.9l-.5-.9v.9M203 83a.47 .47 0 0 1 .5 .5 .47 .47 0 0 1-.5 .4zM206.4 90.5h.6M206.7 90.1v.7M207.9 90h-.4l-.1 .4 .4-.1 .1 .4h-.5M208.1 90l.4 .8 .2-.8M209.5 96.2l.2-.2v.8M209.5 96.8h.4"/>
<path d="M210 94.4l-.4-.1-.1 .1 .1 .6h.4M210.3 88.3a.41 .41 0 0 0-.5 .4 .41 .41 0 0 0 .6 .3v-.3h-.2M210.3 94.3h.6l-.4 .3h.3l.1 .4-.2 .1-.4-.1M210.4 96.1l.3-.1 .1 .1-.1 .6a.39 .39 0 0 1-.4-.2 .39 .39 0 0 1 .1-.4zM211.2 88.2v.9l-.5-.9v.9M211.2 96a.42 .42 0 0 1 .4 .4 .42 .42 0 0 1-.4 .4zM211.2 94.4l.3-.1 .1 .1v.6l-.1 .1a.48 .48 0 0 1-.3-.7zM211.6 88.2a.47 .47 0 0 1 .5 .4 .47 .47 0 0 1-.5 .5zM212 96.3h.3v.5M212 94.5l.2-.2v.8M212 96.2v.6M212 95.1h.5"/>
<path d="M212.7 96.4h.4M213.1 96h-.4v.8M218.1 96.2l.2-.2v.8M218.1 96.8h.5M218.6 94.4l-.4-.1a.44 .44 0 0 0-.1 .5 .44 .44 0 0 0 .5 .2M218.9 94.3h.5l-.2 .3 .2 .1v.3h-.5M219 96a.42 .42 0 0 1 .4 .4 .42 .42 0 0 1-.4 .4zM219.8 96h.3l.1 .1-.1 .7h-.3l-.1-.2zM219.8 94.4l.1-.1a.45 .45 0 0 1 .4 .4 .45 .45 0 0 1-.3 .4l-.3-.3zM220.6 96.3h.3v.5M220.6 94.4l.4-.1 .1 .2-.6 .6h.6M220.6 96.2v.6"/>
<path d="M221.4 96.4h.2M221.8 96h-.4v.8M226.7 96.2l.2-.2v.8M226.7 96.8h.5M227.2 94.4l-.3-.1-.2 .1v.5l.2 .2 .3-.1M227.5 94.3h.5l-.2 .3 .2 .1v.3l-.1 .1-.4-.1M227.6 96l.4 .1-.1 .7h-.3l-.1-.2zM228.4 96.1l.3-.1v.7a.39 .39 0 0 1-.4-.2 .39 .39 0 0 1 .1-.4zM228.5 94.3a.43 .43 0 0 1 .4 .4 .43 .43 0 0 1-.3 .4l-.2-.1zM229.1 94.3h.6l-.3 .3 .3 .1v.3h-.6M229.2 96.3l.2-.1 .2 .2v.4M229.2 96.2v.6"/>
<path d="M230 96.4h.2M230.4 96h-.4v.8M234.4 83.1a.41 .41 0 0 0-.5 .4 .41 .41 0 0 0 .6 .4v-.4h-.2M235.3 83v.9l-.5-.9v.9M235.3 96.2l.3-.2v.8M235.3 96.8h.5M235.8 83l.4 .3v.4l-.3 .2h-.1zM235.8 94.4l-.3-.1-.2 .1v.5l.3 .2 .2-.1M236.1 94.3h.6l-.4 .3 .4 .1v.3l-.2 .1-.4-.1M236.3 96h.2l.1 .1-.1 .6a.39 .39 0 0 1-.4-.2 .39 .39 0 0 1 .1-.4zM237 96.1l.1-.1a.43 .43 0 0 1 .4 .4 .43 .43 0 0 1-.4 .4l-.2-.3zM237.1 94.3h.3v.1v.6l-.1 .1-.3-.1z"/>
<path d="M237.8 96.3l.2-.1 .2 .2v.4M237.8 96.2v.6M238 94.2l-.2 .6h.6M238.2 94.5v.6M238.5 96.4h.4M239 96h-.5v.8M243 88.3l-.1-.1a.43 .43 0 0 0-.4 .4 .43 .43 0 0 0 .5 .4v-.3h-.1M243.9 96.2l.2-.2v.8M243.9 96.8h.5M244 88.2v.9l-.5-.9v.9M244.3 88.2h.3l.2 .2v.5l-.2 .2h-.3zM244.5 94.4l-.5-.1a.44 .44 0 0 0-.1 .5 .44 .44 0 0 0 .6 .2"/>
<path d="M244.7 94.3h.5l-.2 .3 .2 .1v.3h-.5M244.8 96.1l.1-.1a.43 .43 0 0 1 .3 .4 .43 .43 0 0 1-.3 .4l-.2-.3zM245.7 96a.42 .42 0 0 1 .4 .4 .42 .42 0 0 1-.4 .4zM245.7 94.4l.3-.1 .1 .1v.6l-.2 .1a.48 .48 0 0 1-.2-.7zM246.4 96.3h.4v.5M246.4 96.2v.6M246.8 94.3h-.4v.4l.4-.1 .1 .4-.1 .1-.4-.1M247.2 96.4h.3M247.6 96h-.4v.8M252.5 96.2l.3-.2v.8M252.5 96.8h.5M253 94.4l-.3-.1a.43 .43 0 0 0-.1 .5 .43 .43 0 0 0 .4 .2"/>
<path d="M253.4 94.3h.5l-.3 .3 .3 .1v.3h-.5M253.4 96a.42 .42 0 0 1 .5 .4 .42 .42 0 0 1-.5 .4zM254.3 96h.2l.1 .1-.1 .7h-.2l-.1-.2zM254.3 94.3a.39 .39 0 0 1 .4 .4 .39 .39 0 0 1-.4 .3zM255.1 96.3h.3v.5M255.1 96.2v.6M255.5 94.3l-.4 .1v.6l.3 .1 .2-.4h-.5M255.8 96.4h.3M256.2 96h-.4v.8M261.2 96.2l.2-.2v.8M261.2 96.8h.5M261.7 94.4l-.4-.1-.1 .1v.5l.2 .2 .3-.1"/>
<path d="M262 94.3h.5l-.3 .3h.2l.1 .4-.2 .1-.3-.1M262.1 96h.2l.1 .1-.1 .7h-.2l-.1-.2zM262.8 96.1l.4-.1 .1 .1-.1 .6a.39 .39 0 0 1-.5-.2 .39 .39 0 0 1 .1-.4zM262.9 94.3a.43 .43 0 0 1 .5 .4 .43 .43 0 0 1-.4 .4l-.2-.1zM263.6 96.3l.3-.1 .1 .2v.4M263.6 94.3h.6l-.4 .8M263.6 96.2v.6M264.5 96.4h.2M264.8 96h-.3v.8M269.8 96.2l.2-.2v.8M269.8 96.8h.4M270.3 94.4l-.3-.1-.2 .1v.5l.2 .2 .3-.1"/>
<path d="M270.5 94.3h.6l-.3 .3h.3v.4l-.1 .1-.5-.1M270.6 96.1l.4-.1v.7a.39 .39 0 0 1-.5-.2 .39 .39 0 0 1 .1-.4zM271.5 96a.42 .42 0 0 1 .4 .4 .42 .42 0 0 1-.4 .4zM271.6 94.3h.2l.1 .1v.6l-.2 .1a.48 .48 0 0 1-.3-.4 .48 .48 0 0 1 .2-.4zM272.2 96.3l.3-.1 .2 .2v.4M272.2 96.2v.6M272.4 94.6l-.2-.2 .1-.1 .5 .1-.1 .2-.5 .2 .2 .3 .4-.1v-.3l-.2-.1M273 96.4h.3M273.4 96h-.4v.8M278.3 96.2l.3-.2v.8M278.3 96.8h.5M278.9 94.4l-.4-.1a.44 .44 0 0 0-.1 .5 .44 .44 0 0 0 .5 .2"/>
<path d="M279.2 94.3h.5l-.3 .3 .3 .1v.3h-.5M279.3 96a.42 .42 0 0 1 .4 .4 .42 .42 0 0 1-.4 .4zM280.1 96a.42 .42 0 0 1 .4 .4 .42 .42 0 0 1-.4 .4zM280.1 94.4l.4-.1v.1v.6l-.1 .1a.48 .48 0 0 1-.3-.7zM280.9 96.3h.3v.5M280.9 96.2v.6M281.4 94.6l-.4 .2-.1-.1v-.3l.4-.1 .1 .1-.2 .6-.2 .1M281.6 96.4h.3M282.1 96h-.5v.8M38.5 116.3h.6M38.7 115.9v.7M39.9 115.8h-.4v.4l.4-.1v.5l-.4-.1"/>
<path d="M40.2 115.8l.3 .8 .3-.8M43 117.5v.8l.5-.1v-.7M43.4 119.2l-.4 .2v.6l.3 .1 .2-.4-.2-.2-.3 .2M43.8 119.5l.3-.3v.9M43.8 117.5h.5l-.2 .3 .2 .1v.4l-.5-.1M44.7 117.6l.3-.1 .2 .1-.1 .7h-.3l-.1-.2zM45.2 119.3l-.5-.1a.44 .44 0 0 0-.1 .6 .44 .44 0 0 0 .6 .2M45.4 119.2h.5l-.2 .3 .2 .1v.4h-.5M45.5 117.6l.3-.1 .2 .1-.5 .7h.5M46.3 119.3h.5v.3l-.5 .5h.5M47.1 119.5l.3-.3v.9M47.5 111.5h-.2l-.3 .1v.5l.2 .2h.3v-.3h-.1"/>
<path d="M48.3 119.2l-.3 .2v.6l.3 .1 .1-.5-.3-.1-.1 .2M48.4 111.5v.8l-.5-.8v.8M48.8 111.5a.47 .47 0 0 1 .5 .3 .47 .47 0 0 1-.2 .5h-.3zM94.9 101.1h-.4l-.1 .4 .1 .5 .5-.1v-.3h-.2M95.8 101.1v.9l-.5-.9v.9M96.2 101.1h.4v.2v.7h-.4zM99.2 114.9h-.4a.42 .42 0 0 0-.1 .6 .42 .42 0 0 0 .5 .2l-.1-.3M100.1 114.9v.9l-.5-.9v.9M100.5 114.9l.5 .2v.5l-.3 .2h-.2zM142.6 112h.7M143 111.6v.7M144.1 111.5h-.4v.4l.4-.1v.4h-.4"/>
<path d="M144.4 111.5l.3 .8 .3-.8M150.8 113.2h-.1l-.3 .2v.4l.3 .3 .2-.1v-.3h-.2M151.8 113.2v.9l-.5-.9v.9M152.2 113.2a.47 .47 0 0 1 .5 .4 .47 .47 0 0 1-.5 .5zM159.5 118.4a.41 .41 0 0 0-.5 .4 .41 .41 0 0 0 .6 .4v-.4h-.2M160.4 118.3v.9l-.5-.9v.9M160.8 118.3l.4 .3v.4l-.2 .2h-.2zM168.5 117.1h.6M168.9 116.9v.6M170 116.6h-.5v.4h.5v.5l-.5-.1M170.3 116.6l.3 .9 .2-.9M173.1 118.3v.9h.2h.2v-.9"/>
<path d="M173.9 118.3h.6l-.4 .4 .4 .1v.3l-.2 .1h-.4M174.8 118.4l.2-.1 .2 .2v.6l-.2 .1a.53 .53 0 0 1-.2-.8zM175.4 112h.7M175.7 111.6v.7M176 118.3h-.4v.4h.3l.2 .4-.2 .1h-.3M176.8 111.5h-.3l-.1 .4 .4-.1v.5l-.4-.1M177.2 111.5l.2 .8 .4-.8M179.3 102.9a.41 .41 0 0 0-.5 .5 .41 .41 0 0 0 .6 .3v-.4h-.2M180.2 102.8v1l-.5-1v1M180.6 102.8l.5 .3v.4l-.3 .3h-.2zM183.6 113.2a.4 .4 0 0 0-.5 .4 .4 .4 0 0 0 .5 .4v-.3h-.2M184.5 113.2v.9l-.5-.9v.9"/>
<path d="M184.9 113.2h.2l.3 .2v.4l-.3 .3h-.2zM192.2 118.4l-.2-.1-.3 .3v.4l.3 .2h.2v-.4h-.1M193.1 118.3v.9l-.4-.9v.9M193.5 118.3h.3l.2 .3v.4l-.2 .2h-.3zM206.9 100.3h-.4l-.1 .2v.5l.1 .1h.4v-.3h-.2M207.7 100.3v.8l-.5-.8v.8M208.1 100.3l.5 .1 .1 .4-.2 .3h-.4zM208.1 117.1h.6M208.5 116.9v.6M209.6 116.6h-.4v.4h.4l.1 .1-.1 .4-.4-.1M209.8 116.6l.4 .9 .2-.9M212.7 118.3l.1 .9h.3v-.9"/>
<path d="M213.5 118.3h.6l-.4 .4 .4 .1v.3l-.2 .1h-.4M214.2 103.4h.6M214.4 118.4l.3-.1 .1 .2v.6l-.1 .1a.53 .53 0 0 1-.3-.8zM214.5 103.1v.7M214.6 113.2a.41 .41 0 0 0-.5 .5 .41 .41 0 0 0 .6 .3v-.3h-.2M215.5 113.2v.9l-.5-.9v.9M215.6 102.8h-.4v.4h.3l.2 .4-.2 .2-.3-.1M215.6 118.3l-.3 .1-.1 .7 .1 .1 .4-.1-.2-.4-.3 .1M215.9 113.2l.5 .1v.6l-.3 .2h-.2zM215.9 102.8l.3 1 .2-1M217.2 109.2l.3-.3v.9M217.2 109.8h.5"/>
<path d="M217.7 107.2l-.2-.1a.5 .5 0 0 0-.1 .9l.3-.1M218.1 107.1h.5l-.3 .4 .3 .1v.3h-.5M218.1 108.9a.42 .42 0 0 1 .4 .3 .42 .42 0 0 1-.1 .5l-.2 .1-.1-.2zM218.9 109l.3-.1 .1 .2v.5l-.1 .2a.48 .48 0 0 1-.3-.8zM218.9 107.4l.3-.3v.9M218.9 108h.5M219.7 109.3l.4-.1v.6M219.7 109.2v.6M219.9 107.1l.3 .2-.1 .7h-.3l-.1-.2v-.5zM220.5 109.3h.3M220.9 108.9h-.4v.9M225.8 109.2l.3-.3v.9"/>
<path d="M225.8 109.8h.6M226.2 112.9h.7M226.4 107.2l-.3-.1-.3 .3v.4l.2 .2 .4-.1M226.5 112.6v.6M226.7 109l.3-.1 .1 .2v.5l-.2 .2-.2-.1zM226.7 107.1h.5l-.3 .4 .3 .2-.1 .3-.4-.1M227.5 109l.4-.1 .1 .2v.5l-.2 .2a.48 .48 0 0 1-.3-.8zM227.5 107.4l.3-.3v.9M227.5 108h.5M227.7 112.3h-.4l-.1 .4h.5v.4h-.5M228 112.3l.2 .9 .4-.9M228.3 109.3h.4v.5"/>
<path d="M228.3 107.4l.3-.3v.9M228.3 109.2v.6M228.3 108h.5M229.1 109.3h.3M229.3 118.6l.2-.3v.9M229.3 119.2h.4M229.5 108.9h-.4v.9M229.8 116.7l-.2-.1-.3 .2v.6h.5M230.1 116.6h.5l-.3 .4h.3v.5l-.5-.1M230.2 118.4l.2-.1 .2 .2v.6l-.2 .1a.53 .53 0 0 1-.2-.8zM230.9 116.9l.3-.3v.9M230.9 117.5h.5"/>
<path d="M231.1 118.3a.48 .48 0 0 1 .4 .5 .48 .48 0 0 1-.4 .4l-.2-.1v-.6zM231.8 118.7h.3v.5M231.8 118.7v.5M231.9 117l-.1-.2 .3-.2 .2 .3-.4 .1-.1 .3 .1 .2h.3l.1-.4-.2-.1M232.5 118.7h.4M233 118.3h-.5v.9M234.5 109.2l.2-.3v.9M234.5 109.8h.4M235 107.2l-.3-.1-.2 .3 .1 .6 .4-.1M235.2 107.1h.6l-.3 .4 .3 .2v.3l-.6-.1M235.3 109l.4-.1 .1 .2v.5l-.2 .2a.48 .48 0 0 1-.3-.8zM236.1 107.4l.2-.3v.9"/>
<path d="M236.1 108h.5M236.2 108.9a.42 .42 0 0 1 .4 .3 .42 .42 0 0 1-.2 .5l-.1 .1-.2-.2zM236.9 109.3l.4-.1v.6M236.9 107.2l.4-.1 .1 .2-.5 .7h.5M236.9 109.2v.6M237.7 109.3h.3M237.9 118.6l.2-.3v.9M237.9 119.2h.5M238.1 108.9h-.4v.9M238.5 116.7a.44 .44 0 0 0-.6 .2 .44 .44 0 0 0 .1 .6l.5-.1M238.7 116.6h.5l-.2 .4h.2v.4h-.5M238.9 118.3a.48 .48 0 0 1 .3 .5 .48 .48 0 0 1-.3 .4l-.2-.1v-.6z"/>
<path d="M239.6 116.9l.2-.3v.9M239.6 117.5h.5M239.7 118.3l.3 .2v.6l-.2 .1-.2-.1v-.6zM240.4 118.7h.3v.5M240.4 118.7v.5M240.9 117l-.4 .1-.1-.4 .3-.1 .2 .2-.2 .7h-.2M241.2 118.7h.2M241.6 118.3h-.4v.9M243 109.2l.3-.3v.9M243 109.8h.5M243.6 107.2a.44 .44 0 0 0-.6 .2 .44 .44 0 0 0 .2 .6l.4-.1M243.9 107.1h.5l-.3 .4 .3 .1v.3h-.5"/>
<path d="M244 108.9a.42 .42 0 0 1 .4 .3 .42 .42 0 0 1-.2 .5l-.2 .1-.1-.2zM244.7 107.4l.3-.3v.9M244.7 108h.5M244.8 108.9h.3v.2v.5l-.1 .2-.3-.2zM245.5 107.1h.6l-.4 .4 .4 .2-.1 .3-.5-.1M245.6 109.3l.3-.1v.6M245.6 109.2v.6M246.3 109.3h.3M246.5 118.6l.3-.3v.9M246.5 119.2h.5M246.8 108.9h-.5v.9M247 116.7l-.2-.1-.3 .3v.4l.2 .2 .3-.1"/>
<path d="M247.4 116.6h.5l-.3 .4 .3 .1-.1 .4-.4-.1M247.5 118.3l.3 .2v.6l-.2 .1-.2-.1v-.6zM248.2 118.4l.3-.1 .1 .2v.6l-.1 .1a.53 .53 0 0 1-.3-.8zM248.2 116.7l.3-.1 .2 .3-.6 .6h.6M249 118.7h.4v.5M249 116.7l.3-.1 .2 .2-.1 .7-.4-.1zM249 118.7v.5M249.8 118.7h.3M250.2 118.3h-.4v.9M251.7 109.2l.2-.3v.9M251.7 109.8h.5M252.2 107.2l-.3-.1-.2 .3v.4l.1 .2 .4-.1"/>
<path d="M252.5 107.1h.5l-.2 .4 .2 .2-.1 .3-.4-.1M252.6 108.9l.3 .1v.7l-.1 .1-.3-.2zM253.4 107.4l.2-.3v.9M253.4 108h.5M253.4 108.9h.3l.1 .2v.5l-.2 .2a.48 .48 0 0 1-.3-.4 .48 .48 0 0 1 .1-.5zM254.2 109.3h.3v.5M254.2 109.2v.6M254.4 107.1l-.2 .6h.5M254.5 107.5v.5M255 109.3h.2M255.4 108.9h-.4v.9M260.3 109.2l.3-.3v.9"/>
<path d="M260.3 109.8h.5M260.8 107.2l-.2-.1-.3 .3v.4l.2 .2 .3-.1M261.1 107.1h.6l-.4 .4 .4 .2-.1 .3-.5-.1M261.2 109l.3-.1 .1 .2v.5l-.2 .2a.48 .48 0 0 1-.2-.8zM262 109l.1-.1a.43 .43 0 0 1 .3 .3 .43 .43 0 0 1-.1 .5h-.3zM262 107.4l.2-.3v.9M262 108h.4M262.8 109.3h.4v.5M262.8 109.2v.6M263.3 107.1h-.5v.5h.5v.3h-.5M263.5 109.3h.4M263.9 108.9h-.4v.9"/>
<path d="M268.9 109.2l.2-.3v.9M268.9 109.8h.5M269.4 107.2a.44 .44 0 0 0-.5 .2 .44 .44 0 0 0 .1 .6l.4-.1M269.7 107.1h.5l-.2 .4 .2 .1v.3h-.5M269.8 109l.1-.1a.46 .46 0 0 1 .3 .4 .46 .46 0 0 1-.2 .5 .48 .48 0 0 1-.2-.8zM270.5 107.4l.3-.3v.9M270.5 108h.6M270.6 108.9a.42 .42 0 0 1 .4 .3 .42 .42 0 0 1-.1 .5l-.2 .1-.2-.2zM271.4 109.3l.3-.1v.6M271.4 109.2v.6M271.8 107.1l-.4 .3v.5l.4 .1 .1-.3-.2-.2-.3 .2M272.2 109.3h.3"/>
<path d="M272.6 108.9h-.4v.9M277.5 109.2l.2-.3v.9M277.5 109.8h.5M278 107.2a.43 .43 0 0 0-.5 .3 .43 .43 0 0 0 .2 .5l.3-.1M278.3 107.1h.5l-.2 .4 .2 .1v.3h-.5M278.4 108.9a.42 .42 0 0 1 .4 .3 .42 .42 0 0 1-.1 .5l-.2 .1-.2-.2zM279.2 107.4l.2-.3v.9M279.2 108h.5M279.3 108.9h.2l.1 .2v.5l-.2 .2-.2-.2zM279.9 107.1h.6l-.3 .9M280 109.3l.4-.1v.6M280 109.2v.6"/>
<path d="M280.8 109.3h.2M281.2 108.9h-.4v.9M43.8 120.1h.5M47.1 120.1h.5M72 122.3h.7M72.3 122v.6M73.5 121.8h-.4l-.1 .4 .4-.1 .1 .5h-.5M73.8 121.8l.3 .8 .3-.8M74.8 127h.6l-.4 .8M74.9 125.3l.1 .8h.3l.1-.2v-.6M75.7 125.3h.5l-.3 .3h.3v.5l-.5-.1M75.9 127l-.3 .5h.6"/>
<path d="M76.1 127.3v.5M76.4 127.8l.3-.8 .3 .8M76.5 127.5h.4M76.7 125.3a.42 .42 0 0 1 .4 .4 .42 .42 0 0 1-.4 .4zM77.3 127.4h.5M77.3 127v.8M77.3 125.3h.5l-.2 .3 .2 .1v.3h-.5M77.8 127v.8M78.6 127a.43 .43 0 0 0-.5 .3 .43 .43 0 0 0 .2 .5l.3-.1M78.9 127h.5M79.1 127v.8M79.6 127h.4l.1 .1-.5 .7h.5"/>
<path d="M80.6 127l-.1 .5h.5M80.9 127.3v.5M81.7 127h-.4l-.1 .4h.5v.3h-.5M103.1 122.3h.6M103.3 122v.6M104.5 121.8h-.4v.4l.4-.1v.5h-.4M104.8 121.8l.3 .8 .3-.8M105.8 127h.6l-.4 .8M105.9 125.3l.1 .8h.3l.1-.8M106.7 125.3h.5l-.2 .3 .2 .1v.3h-.5M106.9 127l-.3 .5h.6M107.1 127.3v.5"/>
<path d="M107.4 127.8l.3-.8 .3 .8M107.5 127.5h.4M107.7 125.3a.42 .42 0 0 1 .4 .4 .42 .42 0 0 1-.4 .4zM107.8 120.1h-.3l-.2 .2 .1 .6h.4v-.3h-.1M108.2 127v.8M108.2 127.4h.6M108.3 125.3h.6l-.3 .8M108.7 120.1v.8l-.5-.8v.8M108.8 127v.8M109.1 120.1h.3l.2 .2v.5l-.3 .1h-.2zM109.7 127a.44 .44 0 0 0-.6 .2 .44 .44 0 0 0 .2 .6l.4-.1M109.9 127h.5"/>
<path d="M110.1 127v.8M110.6 127h.5v.4l-.5 .4h.5M111.6 127l-.1 .5h.5M111.9 127.3v.5M112.7 127h-.4v.4h.4v.4l-.4-.1M132.3 122.3h.7M132.6 122v.6M133.8 121.8h-.4v.4l.3-.1 .1 .5h-.4M134.1 121.8l.3 .8 .3-.8M135.1 127h.6l-.4 .8M135.2 125.3l.1 .8h.3l.1-.2v-.6M136 125.3h.5l-.2 .3 .2 .2-.1 .3-.4-.1"/>
<path d="M136.2 127l-.3 .5h.5M136.4 127.3v.5M136.7 127.8l.2-.8 .4 .8M136.8 127.5h.4M136.9 125.3a.42 .42 0 0 1 .5 .4 .42 .42 0 0 1-.5 .4zM137.5 127.4h.5M137.5 127v.8M137.8 125.6l-.1-.3h.3l.1 .2-.4 .2v.3l.3 .1 .1-.4-.1-.1M138 127v.8M139 127a.44 .44 0 0 0-.6 .2 .44 .44 0 0 0 .2 .6l.4-.1M139.1 127h.6M139.4 127v.8"/>
<path d="M139.9 127h.5v.4l-.5 .4h.5M140.9 127l-.1 .5h.5M141.2 127.3v.5M142 127h-.4v.4h.4v.3h-.4M173 120.1h.5l-.3 .8M174.4 120.2l-.4-.1-.1 .2v.5l.2 .1h.3M174.9 120l-.2 .7h.5M175.1 120.4v.5M175.6 120.1h.3l.1 .2v.5l-.2 .1-.2-.1zM176.8 120.4l-.1 .2h-.3v-.5l.4 .1v.6l-.4 .1M177.3 120.4l-.1-.1v-.2h.4v.3l-.4 .2 .1 .3 .4-.1-.2-.4M212.6 120.1h.5l-.3 .8"/>
<path d="M214 120.2l-.3-.1-.2 .2v.5l.2 .1h.3M214.5 120l-.2 .7h.5M214.8 120.4v.5M215.3 120.1h.2l.1 .2v.5l-.2 .1-.2-.1zM216.4 120.4v.2h-.4v-.5l.4 .1v.6l-.4 .1M217 120.4l-.2-.2 .4-.1v.3l-.4 .1v.4h.2l.3-.1-.2-.4M226.7 122.7l-.3-.1-.2 .3v.4l.2 .2h.3v-.4h-.2M227 125.8h.7M227.4 125.4v.7M227.5 122.6v.9l-.5-.9v.9M227.5 135.6h-.3l-.2 .2v.5l.2 .1h.3v-.3h-.1M228 122.6a.48 .48 0 0 1 .4 .3 .48 .48 0 0 1-.1 .6h-.3z"/>
<path d="M228.4 135.6v.8l-.4-.8v.8M228.6 125.3h-.5v.4h.5l-.1 .4-.4-.1M228.8 125.3l.3 .8 .3-.8M228.8 135.6h.3l.2 .2v.5l-.2 .1h-.3zM230.2 131.5l.2-.2v.8M230.2 132.1h.4M230.7 129.7l-.4-.1-.1 .1v.5l.2 .2 .3-.1M230.9 129.6h.6l-.3 .3h.2l.1 .4-.2 .1-.4-.1M231 131.4l.3-.1 .1 .1-.1 .6a.39 .39 0 0 1-.4-.2 .39 .39 0 0 1 .1-.4zM231.9 129.7l.3-.1 .1 .3-.5 .5h.5M231.9 131.3a.43 .43 0 0 1 .4 .4 .43 .43 0 0 1-.4 .4 .6 .6 0 0 1 0-.8zM232.6 131.6l.3-.1 .1 .2v.4"/>
<path d="M232.6 129.8l.3-.2v.8M232.6 131.5v.6M232.6 130.4h.5M233.4 131.7h.3M233.8 131.3h-.4v.8M238.7 131.5l.3-.2v.8M238.7 132.1h.5M239.3 129.7l-.4-.1a.44 .44 0 0 0-.1 .5 .44 .44 0 0 0 .5 .2M239.6 129.6h.5l-.3 .3 .3 .1v.3h-.5M239.6 131.4h.1a.34 .34 0 0 1 .4 .3 .34 .34 0 0 1-.5 .3zM240.4 129.7h.5v.2l-.5 .5h.5M240.6 131.3a.43 .43 0 0 1 .3 .4 .43 .43 0 0 1-.4 .4l-.1-.7z"/>
<path d="M241.3 131.6h.3v.5M241.3 129.7l.4-.1 .1 .2-.6 .6h.6M241.3 131.5v.6M242 131.7h.4M242.4 131.3h-.4v.8M247.4 131.5l.2-.2v.8M247.4 132.1h.5M247.9 129.7l-.4-.1a.42 .42 0 0 0-.1 .5 .42 .42 0 0 0 .5 .2M248.2 129.6h.5l-.2 .3 .2 .1v.3h-.5M248.4 131.3a.43 .43 0 0 1 .3 .4 .43 .43 0 0 1-.4 .4l-.1-.7zM249 131.4l.3-.1 .2 .1-.1 .7-.4-.1zM249 129.7l.5-.1 .1 .1-.6 .7h.6"/>
<path d="M249.8 129.6h.5l-.2 .3h.2v.4h-.5M249.9 131.6h.3v.5M249.9 131.5v.6M250.7 131.7h.2M251.1 131.3h-.4v.8M256 131.5l.2-.2v.8M256 132.1h.5M256.5 129.7l-.3-.1-.2 .1v.5l.2 .2 .3-.1M256.8 131.4l.2-.1 .3 .1-.1 .7h-.3zM256.8 129.6h.5l-.3 .3h.3v.4l-.1 .1-.4-.1M257.7 131.4l.2-.1 .2 .1-.1 .6a.39 .39 0 0 1-.4-.2 .39 .39 0 0 1 .1-.4zM257.7 129.7l.4-.1 .1 .2-.6 .6h.6"/>
<path d="M258.4 131.6l.3-.1 .2 .2v.4M258.4 131.5v.6M258.7 129.5l-.3 .7h.6M258.9 129.8v.6M259.3 131.7h.2M259.6 131.3h-.3v.8M264.6 131.5l.2-.2v.8M264.6 132.1h.4M265.1 129.7l-.3-.1-.2 .1v.5l.3 .2 .2-.1M265.4 129.6h.6l-.4 .3h.3l.1 .4-.2 .1-.4-.1M265.5 131.4l.2-.1 .2 .1-.1 .6a.39 .39 0 0 1-.4-.2 .39 .39 0 0 1 .1-.4zM266.2 131.4l.2-.1a.43 .43 0 0 1 .3 .4 .43 .43 0 0 1-.4 .4z"/>
<path d="M266.2 129.6h.5l-.2 .3 .2 .1v.3h-.5M267.1 131.6h.3v.5M267.1 129.6h.5l-.3 .3h.2l.1 .4-.2 .1-.3-.1M267.1 131.5v.6M267.8 131.7h.4M268.3 131.3h-.5v.8M273.2 131.5l.2-.2v.8M273.2 132.1h.5M273.8 129.7l-.5-.1a.44 .44 0 0 0-.1 .5 .44 .44 0 0 0 .6 .2M274 129.6h.5l-.2 .3 .2 .1v.3h-.5M274.2 131.3a.43 .43 0 0 1 .3 .4 .43 .43 0 0 1-.4 .4l-.1-.7zM274.9 129.6h.5l-.3 .3 .3 .1v.3h-.5"/>
<path d="M275 131.3a.43 .43 0 0 1 .4 .4 .43 .43 0 0 1-.4 .4l-.1-.7zM275.7 131.6h.4v.5M275.7 131.5v.6M275.9 129.5l-.2 .7h.5M276.1 129.8v.6M276.5 131.7h.2M276.9 131.3h-.4v.8M16.5 158.9l-.5 .1v.5l.3 .2 .2-.1v-.3h-.1M17.4 158.9v.8l-.5-.8v.8M17.8 158.9h.4a.48 .48 0 0 1 .1 .5 .48 .48 0 0 1-.5 .3zM72 159.4h.7M72.3 159v.7"/>
<path d="M72.5 156.3l-.2-.1-.3 .2v.5l.2 .2h.3v-.3h-.2M73.4 156.2v.9l-.5-.9v.9M73.5 158.9h-.4l-.1 .3h.5v.4h-.5M73.8 156.2a.47 .47 0 0 1 .5 .3 .47 .47 0 0 1-.2 .6h-.3zM73.8 158.9l.3 .8 .3-.8M103.1 159.4h.6M103.3 159v.7M103.5 156.3a.42 .42 0 0 0-.5 .3 .42 .42 0 0 0 .2 .5h.3v-.3h-.2M104.4 156.2v.9l-.5-.9v.9M104.5 158.9h-.4v.3h.4v.4h-.4M104.8 156.2l.5 .2v.5l-.2 .2h-.3zM104.8 158.9l.3 .8 .3-.8"/>
<path d="M132.3 159.4h.7M132.6 159v.7M132.8 156.3l-.3-.1-.2 .2v.5l.2 .2h.3v-.3h-.2M133.6 156.2v.9l-.4-.9v.9M133.8 158.9h-.4v.3h.4v.4h-.4M134.1 156.2l.5 .2v.5l-.2 .2h-.3zM134.1 158.9l.3 .8 .3-.8M228 150.7h.6M228.2 150.4v.7M229.4 150.2h-.4v.5l.4-.1 .1 .1-.1 .4-.4-.1M229.7 150.2l.3 .9 .2-.9M231 156.3l.3-.1 .2 .3-.6 .6h.6"/>
<path d="M231.5 154.6h-.3l-.2 .1v.5l.3 .2 .2-.1M231.9 156.3h.4v.3l-.5 .5h.5M231.9 154.6h.5l-.4 .3h.3l.1 .3-.2 .2-.3-.1M232.7 156.3l.3-.1 .1 .2-.1 .6a.39 .39 0 0 1-.4-.2 .39 .39 0 0 1 .1-.5zM232.7 154.6h.4l.1 .2-.6 .6h.6M233.5 156.6l.2-.1 .2 .2v.4M233.5 156.5v.6M234 154.6h-.5v.4l.4-.1 .1 .4h-.5M234.3 156.7h.3M234.7 156.2h-.4v.9M239.6 156.3h.5v.3l-.5 .5h.5M240.2 154.6h-.4l-.2 .1v.5l.3 .2 .3-.1"/>
<path d="M240.4 156.3h.5v.3l-.5 .5h.5M240.4 154.6h.6l-.3 .3h.2l.1 .3-.2 .2-.4-.1M241.3 154.6h.5v.3l-.5 .5h.5M241.4 156.2a.43 .43 0 0 1 .4 .5 .43 .43 0 0 1-.5 .4v-.7zM242.1 156.6h.3v.5M242.1 156.5v.6M242.5 154.6h-.2l-.2 .6 .2 .2 .3-.2-.1-.3h-.3l-.1 .2M242.9 156.7h.3M243.3 156.2h-.4v.9M248.2 156.3h.5v.3l-.5 .5h.5M248.8 154.6h-.4a.44 .44 0 0 0-.2 .5 .44 .44 0 0 0 .6 .2M249 156.3l.4-.1 .2 .2-.6 .7h.6"/>
<path d="M249 154.6h.6l-.3 .3 .3 .1v.3h-.6M249.9 154.6h.4l.1 .1-.5 .7h.5M250.1 156.2l.2 .1-.1 .8h-.2l-.1-.2v-.5zM250.7 154.6h.5l-.3 .8M250.7 156.6h.4v.5M250.7 156.5v.6M251.5 156.7h.3M251.9 156.2h-.4v.9M256.8 156.3l.4-.1 .1 .2-.5 .7h.5M257.3 154.6h-.3a.42 .42 0 0 0-.2 .5 .42 .42 0 0 0 .5 .2M257.7 156.3l.3-.1 .2 .3-.6 .6h.6M257.7 154.6h.5l-.3 .3 .3 .1v.3h-.5"/>
<path d="M258.5 156.3l.3-.1 .1 .2v.6a.39 .39 0 0 1-.5-.2 .39 .39 0 0 1 .1-.5zM258.5 154.6h.4l.1 .2-.6 .6h.6M259.4 156.6l.1-.1 .2 .2v.4M259.4 156.5v.6M259.5 154.9l-.1-.3h.3l.1 .2-.4 .2v.3l.1 .1 .3-.1v-.3l-.2-.1M260.1 156.7h.3M260.6 156.2h-.5v.9M38.9 169.2h-.3a.43 .43 0 0 0-.2 .5 .43 .43 0 0 0 .5 .3v-.4h-.2M39.8 169.2v.8l-.5-.8v.8M40.2 169.2h.3l.2 .2v.4l-.3 .2h-.2zM74.8 164h.6l-.4 .9M74.9 162.3l.1 .8h.3l.1-.8"/>
<path d="M75.7 162.3h.5l-.3 .3 .3 .2v.3l-.5-.1M75.9 164l-.3 .5h.6M76.1 164.3v.6M76.4 164.9l.3-.9 .3 .9M76.5 164.6h.4M76.7 162.3a.43 .43 0 0 1 .4 .4 .43 .43 0 0 1-.4 .4l-.1-.7zM77.3 164.4h.5M77.3 164v.9M77.6 162.3l-.3 .6h.6M77.8 162.6v.5M77.8 164v.9M78.6 164.1l-.3-.1a.43 .43 0 0 0-.2 .6 .43 .43 0 0 0 .5 .2"/>
<path d="M78.9 164h.5M79.1 164v.9M79.6 164.1l.4-.1 .1 .2-.5 .7h.5M80.6 164l-.1 .5h.5M80.9 164.3v.6M81.7 164h-.4l-.1 .4h.5v.4h-.5M105.8 164h.6l-.4 .9M105.9 162.3l.1 .8h.3l.1-.8M106.7 162.3h.5l-.2 .3 .2 .1v.3h-.5M106.9 164l-.3 .5h.6M107.1 164.3v.6M107.4 164.9l.3-.9 .3 .9"/>
<path d="M107.5 164.6h.4M107.7 162.3a.43 .43 0 0 1 .4 .4 .43 .43 0 0 1-.4 .4l-.1-.7zM108.2 164v.9M108.2 164.4h.6M108.8 164v.9M108.8 162.7v.2l-.4-.1v-.5h.4v.6v.2h-.3M109.7 164.1l-.4-.1a.44 .44 0 0 0-.1 .6 .44 .44 0 0 0 .5 .2M109.9 164h.5M110.1 164v.9M110.6 164.1h.5v.3l-.5 .5h.5M111.6 164l-.1 .5h.5M111.9 164.3v.6"/>
<path d="M112.7 164h-.4v.4h.4l-.1 .5-.3-.1M135.1 164h.6l-.4 .9M135.2 162.3l.1 .8h.3l.1-.8M136 162.3h.5l-.2 .3 .2 .2-.1 .3-.4-.1M136.2 164l-.3 .5h.5M136.4 164.3v.6M136.7 164.9l.2-.9 .4 .9M136.8 164.6h.4M136.9 162.5l.2-.2v.8M136.9 163.1h.5M137.5 164v.9M137.5 164.4h.5"/>
<path d="M137.9 162.3l.2 .1-.1 .7h-.2l-.1-.2v-.5zM138 164v.9M139 164.1l-.4-.1a.44 .44 0 0 0-.2 .6 .44 .44 0 0 0 .6 .2M139.1 164h.6M139.4 164v.9M139.9 164.1h.5v.3l-.5 .5h.5M140.9 164l-.1 .5h.5M141.2 164.3v.6M142 164h-.4v.4h.4v.4h-.4M146.6 164.9h-.3l-.2 .2v.5l.2 .1 .3-.1v-.2h-.2M147.4 164.9v.8l-.5-.8v.8M147.9 164.9h.3a.47 .47 0 0 1 .2 .5 .47 .47 0 0 1-.5 .3z"/>
<path d="M168.9 174.4h-.3a.43 .43 0 0 0-.1 .5 .43 .43 0 0 0 .4 .2v-.3M169.9 174.4v.8l-.5-.8v.8M170.3 174.4l.4 .1v.5l-.2 .2h-.2zM186.1 164.9l-.4 .2v.5l.3 .1 .2-.1v-.2h-.1M187.1 164.9v.8l-.5-.8v.8M187.5 164.9h.3a.47 .47 0 0 1 .2 .5 .47 .47 0 0 1-.5 .3zM208.6 174.4h-.4a.43 .43 0 0 0-.1 .5 .43 .43 0 0 0 .5 .2l-.1-.3M209.5 174.4v.8l-.5-.8v.8M209.8 174.4h.4l.2 .1v.5l-.3 .2h-.3zM228 163.7h.6M228.2 163.4v.6M228.4 173.5h-.4a.43 .43 0 0 0-.1 .5 .43 .43 0 0 0 .5 .3v-.4h-.2"/>
<path d="M228.4 160.6l-.4 .1-.1 .4 .1 .3h.4v-.3h-.2M229.3 173.5v.9l-.5-.9v.9M229.3 160.6v.8l-.5-.8v.8M229.4 163.1h-.4v.4l.3-.1 .2 .5-.2 .1h-.3M229.7 173.5h.3l.2 .2v.4l-.3 .3h-.2zM229.7 163.1l.3 .9 .2-.9M229.7 160.6h.3l.2 .1v.5l-.2 .2h-.3zM231 169.3l.4-.1 .1 .3-.6 .5h.6M231.5 167.5l-.2-.1-.3 .3v.4l.3 .3 .2-.1M231.9 169.3l.3-.1 .1 .3-.5 .5h.5M231.9 167.4h.5l-.4 .4 .4 .1v.3l-.2 .2-.3-.1M232.7 169.3l.3-.1 .1 .2v.5l-.1 .1a.48 .48 0 0 1-.3-.7z"/>
<path d="M232.7 167.5l.3-.1 .2 .3-.6 .7h.6M233.5 169.5h.2l.2 .1v.4M233.5 169.5v.5M234 167.8l-.4 .2-.1-.4 .1-.2 .4 .1v.6l-.5 .3M234.3 169.6h.3M234.7 169.2h-.4v.8M239.6 167.5h.5v.3l-.5 .5h.5M240.2 169.3l-.4-.1-.2 .2v.4l.3 .2h.3M240.4 167.5h.5v.3l-.5 .5h.5M240.4 169.2h.6l-.3 .3 .3 .1v.3l-.2 .1h-.4M241.3 169.2h.5l-.3 .3h.3v.5h-.5M241.4 167.4a.43 .43 0 0 1 .4 .5 .43 .43 0 0 1-.5 .4v-.7z"/>
<path d="M242.1 167.8h.3v.5M242.1 167.8v.5M242.2 169.3l.1-.1a.46 .46 0 0 1 .3 .4 .46 .46 0 0 1-.2 .4 .48 .48 0 0 1-.2-.7zM242.9 167.8h.3M243.3 167.4h-.4v.9M248.2 167.5h.5v.3l-.5 .5h.5M248.8 169.3l-.4-.1a.44 .44 0 0 0-.1 .6 .44 .44 0 0 0 .5 .2M249 167.5l.4-.1 .2 .2-.6 .7h.6M249 169.2h.6l-.3 .3h.3v.5h-.6M249.9 169.2h.5l-.3 .3 .3 .1v.3l-.2 .1h-.3M250.1 167.4l.2 .1-.1 .8h-.2l-.1-.2v-.5zM250.7 167.8h.4v.5"/>
<path d="M250.7 169.4l.3-.2v.8M250.7 167.8v.5M250.7 170h.5M251.5 167.8h.3M251.9 167.4h-.4v.9M256.8 169.3l.5-.1v.2l-.5 .6h.5M257.3 167.5l-.1-.1a.43 .43 0 0 0-.4 .5 .43 .43 0 0 0 .5 .4M257.7 169.3l.4-.1 .1 .3-.6 .5h.6M257.7 167.4h.5l-.3 .4h.3v.5h-.5M258.4 167.4h.6l-.3 .4 .3 .1v.3l-.1 .2-.5-.1M258.5 169.3l.4-.1v.2v.5l-.1 .1a.48 .48 0 0 1-.3-.7zM259.4 169.5h.1l.2 .1v.4"/>
<path d="M259.4 167.5h.4v.3l-.5 .6h.5M259.4 169.5v.5M260.1 169.6h.3M260.6 169.2h-.5v.8M265.5 169l.2-.2v.8M265.5 169.6h.5M266 167.2l-.4-.1-.1 .2v.5l.1 .1 .4-.1M266.2 167.1h.6l-.3 .3h.2v.5l-.5-.1M266.3 168.9l.3-.1 .1 .1v.7h-.3l-.2-.2zM267.1 167.1h.5l-.3 .3 .3 .1v.3h-.5M267.2 168.9l.1-.1a.45 .45 0 0 1 .3 .4 .45 .45 0 0 1-.4 .4l-.1-.2zM267.9 169.1v.9"/>
<path d="M268.3 169.5l.2 .1M268.3 169.1v.5l-.4-.1M268.4 167.1h-.4l-.1 .4 .4-.1 .1 .4h-.5M268.9 169.2h.2M269.3 168.8h-.4v.8M72.5 193.3l-.2-.1-.3 .3v.4l.3 .3 .2-.1v-.3h-.2M73.4 193.2v1l-.5-1v1M73.8 193.2a.47 .47 0 0 1 .5 .5 .47 .47 0 0 1-.5 .5zM103.5 193.3l-.1-.1a.43 .43 0 0 0-.4 .5 .43 .43 0 0 0 .5 .4v-.3h-.2M104.4 193.2v1l-.5-1v1M104.8 193.2h.2l.3 .3v.4l-.3 .3h-.2zM132.8 193.3l-.3-.1-.2 .3v.4l.2 .3 .3-.1v-.3h-.2"/>
<path d="M133.6 193.2v1l-.4-1v1M134.1 193.2h.2l.3 .3v.4l-.3 .3h-.2z"/>
</g>
</svg>
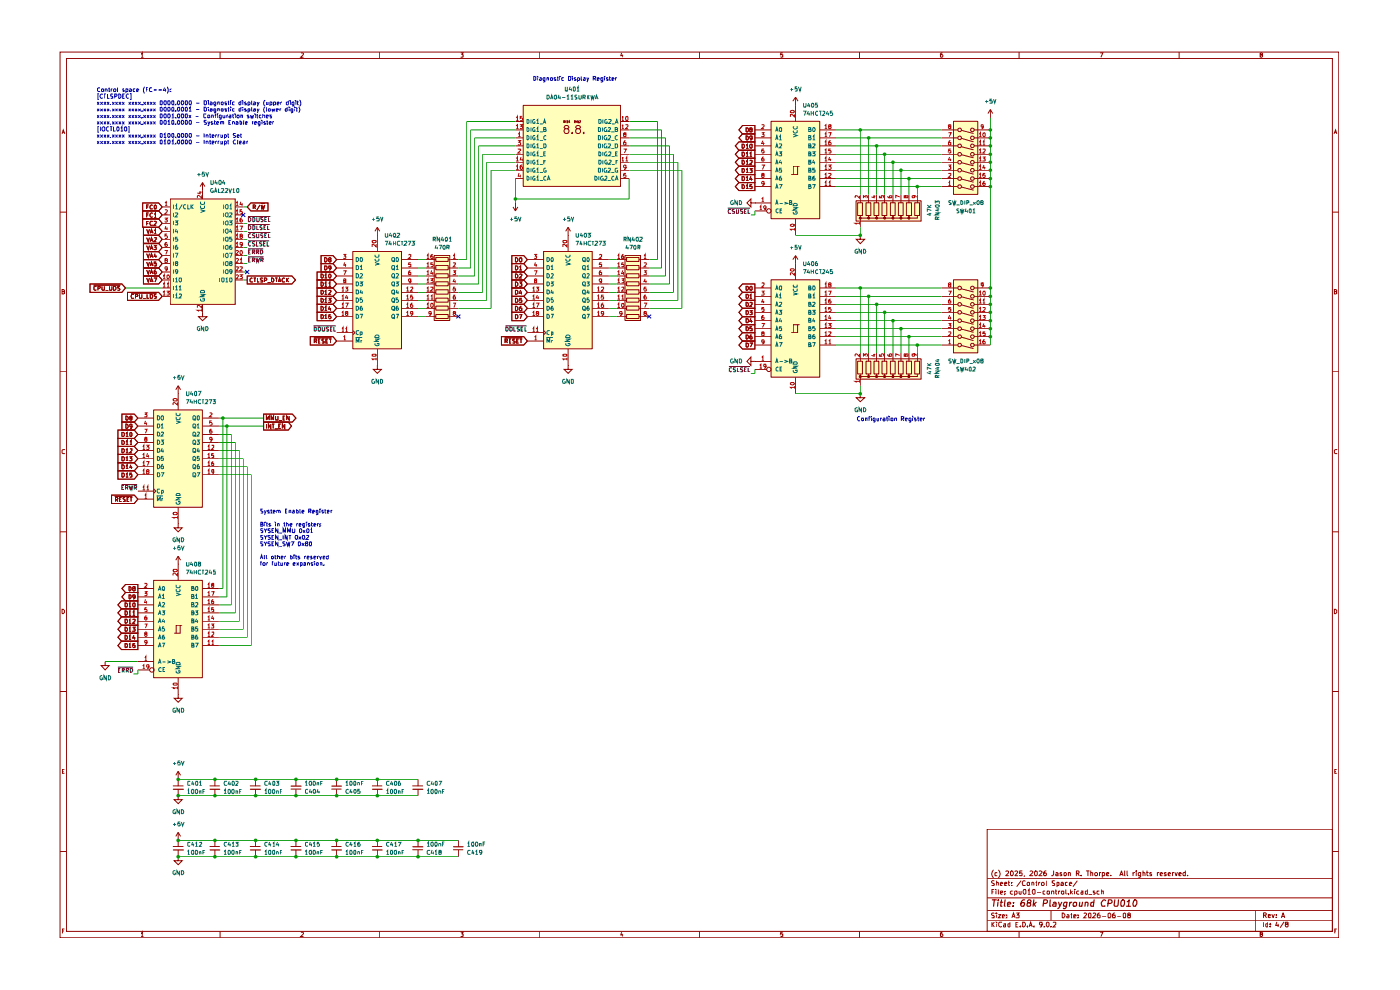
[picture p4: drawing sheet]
<svg xmlns="http://www.w3.org/2000/svg" width="297mm" height="210mm" viewBox="0 0 297 210" stroke-linecap="round" stroke-linejoin="round" font-family="sans-serif">
<g fill="none" stroke="#910000" stroke-width=".21">
<path d="M12.7 11h271.3v187.9h-271.3zM14.1 12.4h268.6v185.2h-268.6zM29.9 11.5l.3-.3v.9M29.9 12.1h.5M46.7 11v1.4M63.9 11.3l.3-.1 .2 .3-.6 .6h.6M80.6 11v1.4M97.7 11.2h.6l-.3 .4h.3v.5h-.6M114.5 11v1.4M131.9 11.2l-.2 .6h.5M132.1 11.6v.5M148.4 11v1.4"/>
<path d="M166.1 11.2h-.5v.4h.5v.5h-.5M182.3 11v1.4M199.9 11.2l-.3 .1-.1 .8h.4l.1-.1-.1-.4-.4 .1M216.2 11v1.4M233.4 11.2h.6l-.5 .9M250.1 11v1.4M267.5 11.6h-.2v-.3l.4-.1 .1 .3-.5 .2v.4h.2l.3-.1-.1-.4M13.2 28.4l.2-.8 .4 .8M13.2 28.1h.5M283 28.4l.3-.8 .3 .8M283.1 28.1h.4M12.7 45h1.4"/>
<path d="M282.7 45h1.3M12.7 78.9h1.4M13.2 61.8h.4l.1-.2-.2-.2h-.3v1l.5-.1v-.4l-.2-.1M282.7 78.9h1.3M283.1 61.8h.4l.1-.2-.2-.2h-.3v1l.5-.1v-.4l-.2-.1M13.7 95.5l-.4-.1-.1 .1v.6l.1 .1 .4-.1M283.6 95.5l-.4-.1-.1 .1v.6l.1 .1 .4-.1M12.7 112.8h1.4M282.7 112.8h1.3M13.2 129.2h.2l.3 .3v.4l-.3 .3h-.2zM283.1 129.2h.2l.3 .3v.4l-.3 .3h-.2zM12.7 146.7h1.4"/>
<path d="M282.7 146.7h1.3M13.2 163.6h.3M13.7 163.2h-.5v.8h.5M209.4 175.9h73.3v21.7h-73.3zM283.2 163.6h.2M283.6 163.2h-.4v.8h.4M12.7 180.6h1.4M13.2 197.5h.4M13.7 197.1h-.5v.9M29.9 198l.3-.3v1M29.9 198.7h.5M46.7 197.6v1.3"/>
<path d="M63.9 197.8l.3-.1 .2 .3-.6 .7h.6M80.6 197.6v1.3M97.7 197.7h.6l-.3 .4 .3 .1v.4h-.6M114.5 197.6v1.3M131.9 197.7l-.2 .6h.5M132.1 198.1v.6M148.4 197.6v1.3M166.1 197.7h-.5v.5h.5v.4h-.5M182.3 197.6v1.3M199.9 197.7l-.3 .1-.1 .8 .4 .1 .1-.2-.1-.4-.4 .1M209.4 195.2h73.3M209.4 193.2h73.3"/>
<path d="M209.4 190.5h73.3M209.4 186.4h73.3M210.4 195.6v1M210.4 189.2h.4M210.5 196l.4 .6M210.7 184.6l-.1 .1a1.11 1.11 0 0 0 .1 1.5M210.9 188.7h-.5v1M210.9 193.8l-.4-.1-.1 .1v.2l.4 .2 .1 .2v.3h-.5M210.9 186.9l-.4-.1-.1 .2v.2l.5 .4v.2h-.5M210.9 195.6l-.5 .5M211.3 188.7v.1M211.3 189v.7"/>
<path d="M211.4 193.7v.1M211.4 187.2h.4v.6M211.4 186.8v1M211.4 194v.7M211.5 195.6v.1M211.5 196v.6M211.5 185.2h-.4v.5l.4 .1M211.8 194h.5l-.5 .7h.5M211.8 188.7l.1 1M211.8 184.6l.1 .1a1.11 1.11 0 0 1-.1 1.5M212.2 189.4l.5-.1-.1-.3h-.3l-.1 .2v.3l.2 .2 .2-.1M212.2 187.5l.5-.1-.1-.2-.4 .1v.4l.4 .1"/>
<path d="M212.5 195.7l-.5-.1-.1 .2v.6l.3 .2 .3-.1M212.6 194.3h.5l-.1-.3-.4 .1v.6h.5M212.9 196h.4v.6M213.1 189.6v.1M213.1 189v.2M213.1 187.5l.5-.1-.1-.2h-.4v.6h.5M213.3 196.1l-.4 .2 .1 .3h.3M213.4 184.8h.5v.4l-.5 .6h.5M213.6 194.6v.1M213.6 194.1v.1M213.9 187.2h.3M214 186.8v.9l.2 .1"/>
<path d="M214.2 196h-.4v.5l.2 .1h.2M214.2 195.6v1M214.4 184.9l.2-.2a.52 .52 0 0 1 .4 .6 .52 .52 0 0 1-.5 .5zM214.6 187.7v.1M214.6 187.2v.1M214.7 194.7l.3-1 .3 1M214.8 194.4h.5M214.8 189h-.3l-.2 .2 .1 .4h.4M215.3 189.6l.3 .1 .2-.2-.1-.5h-.4v1M215.3 184.8l.4-.1 .2 .2-.6 .9h.6M215.5 196h.4M215.6 193.7h.6l-.3 .4 .3 .1v.4h-.6"/>
<path d="M216 195.6h-.5v1h.5M216.2 189v.5l.2 .2 .2-.1M216.2 197.6v1.3M216.4 196.5v.1M216.6 189v.7M216.6 186.8l-.9 1.3M216.8 184.7h-.5v.5h.5l-.1 .6-.4-.1M217 195.6h.3a.55 .55 0 0 1 .2 .8l-.3 .2h-.2zM217.2 188.7h.3l.1 .1v.7l-.2 .2a.63 .63 0 0 1-.2-1zM217.3 185.8v.1M217.5 186.9a.45 .45 0 0 0-.5 .1 .45 .45 0 0 0 0 .6v.2l.5-.1M218 196.5v.1"/>
<path d="M218 187.2h.4l-.1 .6h-.3zM218.1 188.9l.2-.2v1M218.1 189.7h.5M218.3 196.6l.3-1 .4 1M218.4 196.3h.5M218.5 184.8l.4-.1 .2 .4-.7 .7h.7M218.9 187.2h.3l.1 .1v.5M218.9 187.2v.6M219.2 188.7h.3l.1 .1v.7l-.3 .2a.63 .63 0 0 1-.1-1zM219.3 196.5v.1M219.5 184.8l.3-.1 .2 .2v.7l-.1 .2-.4-.1zM219.7 187.2h.3"/>
<path d="M219.8 186.8v1h.2M220 189.3h.8M220.3 187.2v.6M220.5 184.8l.3-.1 .3 .4-.7 .7h.7M220.7 187.2l-.4 .2M221 187.2h.4l.1 .5-.1 .1h-.4zM221.1 196l-.2 .2-.4-.2 .1-.4h.4a.64 .64 0 0 1-.4 1M221.5 196.5v.1M221.7 189l-.4 .1v.5h.4M221.9 184.7l-.3 .1a.74 .74 0 0 0-.1 1h.4l.1-.5-.1-.1h-.4l-.1 .1M222 186.8v1M222 195.7l.4-.1 .1 .2v.6l-.2 .2-.3-.4z"/>
<path d="M222.2 189l.4 .1v.5l-.3 .1-.2-.2zM223 196.5v.1M223 193.2v2M223.1 189.1l.4-.1 .1 .7M223.1 189v.7M223.4 195.7h.6v.3l-.6 .6h.6M223.5 184.7v.8l-.2 .3h-.2M223.7 186.9h-.5v.3l.5 .3-.1 .3h-.4M223.9 189h.3M224 188.7v.8l.2 .2M224 185.2l.3-.1 .1 .1v.6h-.4v-.4l.4-.1M224.2 187.2h.5v.5l-.5 .1"/>
<path d="M224.2 187.2v1M224.6 189v.7M224.9 189h-.2l-.1 .2M225.1 187.2h.3l.2 .1v.5h-.5v-.3l.5-.1M225.2 185.2h-.3v.2l.4 .2-.1 .2h-.3M225.3 189l.4 .1v.5l-.4 .1-.1-.2zM225.3 193.7h.3l.3 .4-.2 .6h-.4zM225.7 185.2l.4-.1 .1 .1-.1 .6-.4-.1zM226.1 188.7v.8l.2 .2M226.4 194.1l.2-.1 .2 .2v.5h-.4v-.4h.4M226.4 187.2h-.4v.5l.4 .1M226.6 185.2h.5v.6"/>
<path d="M226.6 185.1v.7M226.7 189.6v.1M226.9 187.5l.5-.1-.2-.2-.3 .1v.4l.4 .1M227.1 194h.4M227.1 188.7v1M227.3 193.7v1h.2M227.3 189.3l.2 .4M227.5 189l-.4 .4M227.8 194.3h.5l-.2-.3-.3 .1v.6h.4M228 188.7v.1M228 189v.7M228.3 185.2h.6v-.3l-.1-.2h-.5v1.1"/>
<path d="M228.6 186.8l-1 1.3M228.6 185.2l.3 .6M228.7 194.6v.1M228.7 194.1v.1M228.9 189h-.3l-.2 .2 .1 .4h.4M229.3 189h.4v.7M229.4 185.7v.1M229.7 189.3l-.4 .1 .1 .3 .3-.1M229.9 193.8l.4-.1 .2 .1-.6 .9h.6M230.5 184.7h.6M230.7 189l-.5 .1v.5h.5M230.7 188.7v1"/>
<path d="M230.8 184.7v1.1M230.9 189.8h.8M231.1 193.7l.3 .1-.1 .9h-.3l-.1-.2v-.7zM231.4 185.2h.4v.6M231.4 184.7v1.1M231.9 193.8l.4-.1 .1 .3-.6 .7h.6M232.3 189h-.4v.3l.5 .2-.2 .2-.3-.1M232.3 185.2l.3-.1 .2 .1-.1 .6h-.4zM233.2 189h-.4l-.1 .2 .1 .4h.4M233.3 185.1v.7M233.3 193.7l-.3 .1-.2 .7 .2 .2 .4-.1-.1-.5h-.3l-.2 .2M233.4 197.7h.6l-.5 1"/>
<path d="M233.5 185.1l-.2 .1M233.6 189.1l.5-.1v.7M233.6 188.7v1M233.8 194.3h.9M233.8 185.2l.4-.1 .2 .1-.1 .6h-.5M233.8 185.1v1M234.8 185.4l.4-.1-.1-.2-.3 .1v.6h.4M235.1 193.8l.2-.1a.52 .52 0 0 1 .4 .6 .52 .52 0 0 1-.5 .4zM235.6 185.7v.1M236.5 193.7l-.3 .1a.74 .74 0 0 0-.1 .9h.4l.1-.4-.1-.2h-.4l-.1 .2M237 194.3h.8M237.6 185.8l.3-1.1 .3 1.1"/>
<path d="M237.7 185.5h.5M238.5 193.7l.3 .1-.1 .9h-.3l-.1-.2v-.7zM238.6 184.7l.1 1.1M239.1 184.7v.9l.2 .2M239.4 194.1l-.2-.3 .4-.1 .2 .2-.1 .2-.4 .1v.5h.4l.1-.4-.2-.2M240.4 185.1v.7M240.7 185.1l-.3 .1M241 184.7v.1M241 185.1v.7M242 185.1v.8l-.1 .2h-.3M242 185.2l-.4-.1-.1 .1 .1 .6h.4M242.5 185.2l.2-.1 .2 .1v.6"/>
<path d="M242.5 184.7v1.1M243.2 185.1h.4M243.3 184.7v.9l.3 .2M244.3 185.2h-.4v.2l.4 .2v.2h-.4M245.5 185.1v.7M245.9 185.1l-.4 .1M246.1 185.4l.5-.1-.1-.2-.4 .1v.4l.1 .2h.3M247.4 185.2l-.3-.1-.1 .1 .4 .3v.3h-.4M247.8 185.4l.5-.1-.1-.2-.4 .1v.4l.1 .2h.3M248.7 185.1v.7M249 185.1l-.3 .1M249.3 185.1l.2 .7 .3-.7"/>
<path d="M250.1 185.4l.5-.1-.2-.2-.3 .1v.6h.4M250.1 197.6v1.3M251.5 184.7v1.1h-.5l-.1-.6 .2-.1 .4 .1M252 185.7v.1M266.4 193.2v4.4M267.5 198.2l-.2-.1v-.3l.4-.1 .1 .3-.5 .2v.4l.2 .1 .3-.2-.1-.3M268 195.6v1M268.1 194.1h.5v-.3l-.1-.2h-.4v1M268.3 194.1l.3 .5M268.9 196h-.4v.5l.2 .1h.2M268.9 195.6v1M269.1 194.3l.4-.1-.1-.2-.3 .1v.5h.4"/>
<path d="M269.4 196.5v.1M269.4 196h.1M269.8 194l.3 .6 .2-.6M270.8 194.6h.1M270.8 194.1h.1M270.9 195.5l-.3 .8h.7M271.1 196v.6M271.9 194.6l.3-1 .3 1M271.9 194.4h.6M272.4 195.5l-.8 1.3M272.9 196l-.2-.2 .1-.2h.4l.1 .4h-.5l-.1 .2 .2 .4 .4-.1v-.4l-.2-.1M282.7 180.6h1.3"/>
<path d="M283.2 197.5h.2M283.6 197.1h-.4v.9"/>
</g>
<g fill="none" stroke="#910000" stroke-width=".25">
<path d="M210.5 190.9h.9M210.9 190.9l-.1 1.3M211.7 191.4l-.1 .8M211.8 190.9v.1M212.2 191.4h.5M212.5 190.9l-.2 1.3h.3M213.2 190.9l-.1 1.2 .1 .1M213.7 191.8l.7-.1-.2-.3-.5 .2v.6h.5M214.9 192.1v.1M215 191.5v.1M217.4 190.9a.89 .89 0 0 0-.7 1.3h.5l.2-.5-.1-.2h-.5l-.2 .2M218.1 191.5l-.1-.1v-.3l.2-.2 .4 .1v.4l-.5 .1-.2 .2 .1 .5 .6-.1v-.4l-.2-.2"/>
<path d="M219.3 190.9l-.1 1.3M219.3 191.7l.4 .5M219.8 191.4l-.6 .5M221.4 191.6h.6l.2-.2v-.4l-.2-.1h-.6l-.1 1.3M222.8 190.9l-.1 1.3h.2M223.5 191.5l.4-.1 .2 .2-.1 .6h-.6v-.4l.6-.1M224.6 191.4l.2 .8M225.3 191.4l-.6 1.2-.3 .1M226.4 191.4l-.2 1.1-.3 .2h-.3M226.4 191.5h-.6l-.2 .5 .1 .2h.5M226.9 191.4v.8M227.4 191.4l-.5 .2"/>
<path d="M227.8 191.5h.6v.5l-.2 .2-.5-.1zM229.1 191.4l-.1 .8 .5-.1M229.7 191.4l-.2 .8M230.2 191.5l.5-.1 .1 .2v.6M230.2 191.4v.8M232.1 190.9l-.2 1.3h-.5v-.7h.6M234.6 191a.6 .6 0 0 0-.8 0 .6 .6 0 0 0-.2 .7l.2 .5 .6-.1M235.1 191.6h.7l.1-.2-.1-.4-.6-.1-.2 1.3M236.5 190.9l-.2 1.1 .2 .2 .6-.1 .2-1.2M237.9 191.1l.3-.2 .3 .1v.7l-.2 .5h-.4zM239 192.2h.8M239.1 191.3l.5-.4-.2 1.3"/>
<path d="M240.7 190.9l.5 .2v.6l-.3 .5h-.4l-.2-.5 .2-.6z"/>
</g>
<g fill="#ffb">
<path d="M32.6 87h10.4v20.7h-10.4z"/>
<path d="M92.2 54.2h3.3v13.8h-3.3z"/>
<path d="M74.9 53.4h10.3v20.6h-10.3z"/>
<path d="M36.1 42.2h13.8v22.4h-13.8z"/>
<path d="M32.6 123.1h10.4v20.7h-10.4z"/>
<path d="M181.6 76.2h13.8v4.3h-13.8z"/>
<path d="M202.3 59.4h5.2v15.5h-5.2z"/>
<path d="M163.6 25.8h10.3v20.6h-10.3z"/>
<path d="M111 22.4h20.7v17.2h-20.7z"/>
<path d="M132.6 54.2h3.3v13.8h-3.3z"/>
<path d="M115.4 53.4h10.3v20.6h-10.3z"/>
<path d="M163.6 59.4h10.3v20.6h-10.3z"/>
<path d="M202.3 25.8h5.2v15.5h-5.2z"/>
<path d="M181.6 42.6h13.8v4.3h-13.8z"/>
</g>
<g fill="none" stroke="#910000" stroke-width=".21">
<path d="M43 38.7l-.5 .9M43 38.7l.5 .9M43 38.7v3.5M30.3 43h3.4l.7 .9-.7 .8h-3.4zM30.3 44.7h3.4l.7 .9-.7 .8h-3.4zM30.3 46.4h3.4l.7 1-.7 .8h-3.4zM30.4 51.6h3.3l.7 .9-.7 .9h-3.3zM30.4 49.9h3.3l.7 .9-.7 .9h-3.3zM30.4 48.2h3.3l.7 .9-.7 .8h-3.3zM30.4 55.1h3.3l.7 .8-.7 1h-3.3zM30.4 53.4h3.3l.7 .8-.7 .9h-3.3zM30.4 58.5h3.3l.7 .9-.7 .8h-3.3z"/>
<path d="M30.4 56.9h3.3l.7 .8-.7 .8h-3.3zM31.1 52.1l.4 .9 .2-.9M31.1 50.4l.4 .9 .2-.9M31.1 48.6l.4 .9 .2-.9M31.1 55.6l.4 .8 .2-.8M31.1 53.8l.4 .8 .2-.8M31.1 59l.4 .8 .2-.8M31.1 57.3l.4 .8 .2-.8M31.1 43.9h.4M31.1 45.6h.4M31.1 47.4h.4M31.5 43.5h-.4v.8"/>
<path d="M31.5 45.2h-.4v.9M31.5 46.9h-.4v.9M31.9 53l.2-.9 .4 .9M31.9 51.3l.2-.9 .4 .9M31.9 49.5l.2-.9 .4 .9M31.9 56.4l.2-.8 .4 .8M31.9 54.6l.2-.8 .4 .8M31.9 59.8l.2-.8 .4 .8M31.9 58.1l.2-.8 .4 .8M32 59.6h.4M32 52.7h.4M32 51h.4"/>
<path d="M32 49.2h.4M32 56.2h.4M32 54.4h.4M32 57.9h.4M32.4 43.6a.44 .44 0 0 0-.6 .1 .44 .44 0 0 0 .2 .6l.4-.1M32.4 45.3a.42 .42 0 0 0-.6 .3 .42 .42 0 0 0 .6 .4M32.4 47l-.4-.1-.2 .4 .2 .5 .4-.1M32.6 52.1h.5l-.2 .3 .2 .1v.4h-.5M32.6 59h.6l-.3 .8M32.7 45.4l.3-.2v.9M32.7 47l.4-.1v.4l-.5 .5h.5M32.7 50.4h.4v.4l-.5 .5h.5"/>
<path d="M32.7 48.9l.3-.3v.9M32.7 46.1h.4M32.7 49.5h.4M32.9 43.5l.2 .1v.7h-.3l-.1-.1v-.6zM32.9 53.8l-.2 .6h.5M33.1 57.3l-.4 .1v.6h.4v-.4h-.3l-.1 .2M33.1 54.1v.5M33.1 55.6h-.4v.3h.4v.4h-.4M34.4 43.9h1.7M34.4 45.6h1.7M34.4 47.4h1.7M34.4 49.1h1.7"/>
<path d="M34.4 50.8h1.7M34.4 52.5h1.7M34.4 54.2h1.7M34.4 55.9h1.7M34.4 57.7h1.7M34.4 59.4h1.7M36.1 42.2h13.8v22.4h-13.8zM43 40.4h.1M49.9 43.9h1.7M49.9 45.6h1.7M49.9 47.4h1.7M49.9 49.1h1.7"/>
<path d="M49.9 50.8h1.7M49.9 52.5h1.7M49.9 54.2h1.7M49.9 55.9h1.7M49.9 57.7h1.7M49.9 59.4h1.7M52.4 58.5h9.5l.8 .9-.8 .8h-9.5zM53.2 43h3.7v1.7h-3.7l-.8-.8zM53.5 59.1l-.2-.1-.3 .2v.4l.2 .2 .3-.1M53.7 43.9h.4l.1-.3-.1-.1h-.4v.8M53.8 59h.5M53.9 43.9l.3 .4"/>
<path d="M54.1 59v.8M54.6 59v.8h.4M55.2 43.5l-.7 1.1M55.3 43.2h.9M55.4 43.5l.2 .8 .1-.6 .2 .6 .3-.8M55.7 59.1h-.5v.2l.5 .3v.2h-.5M56.1 59.5h.3l.2-.4-.2-.1h-.3v.8M56.8 59.9h.6M57.6 59a.49 .49 0 0 1 .5 .3 .49 .49 0 0 1-.1 .5h-.4zM58.4 59h.5M58.6 59v.8M59.1 59.8l.2-.8 .3 .8"/>
<path d="M59.1 59.6h.4M60.4 59.1a.44 .44 0 0 0-.6 .1 .44 .44 0 0 0 .2 .6l.4-.1M60.7 59v.8M60.8 59.4l.5 .4M61.3 59l-.6 .5M67.3 59.4h3.4l.7 .8-.7 .9h-3.4zM67.3 57.7h3.4l.7 .8-.7 .9h-3.4zM68.1 54.2h2.6l.7 .9-.7 .8h-2.6zM68.1 55.9h2.6l.7 1-.7 .8h-2.6zM68.1 59.8a.47 .47 0 0 1 .5 .5 .47 .47 0 0 1-.5 .4zM68.1 58.1a.49 .49 0 0 1 .5 .3 .49 .49 0 0 1-.2 .6h-.3zM68.9 54.6h.2l.3 .3v.4l-.3 .3h-.2z"/>
<path d="M68.9 56.4h.3l.2 .2v.4l-.3 .3h-.2zM68.9 58.4l.2-.3v.9M68.9 59h.5M69.9 55.1l-.2-.3 .4-.2 .1 .3-.5 .3 .2 .4 .3-.2-.1-.3M69.9 58.1a.43 .43 0 0 1 .3 .4 .43 .43 0 0 1-.3 .5 .6 .6 0 0 1 0-.9zM70.2 56.8l-.1 .1h-.3v-.5h.3l.1 .2v.3l-.4 .4M71.4 55.1h3.5M71.4 56.9h3.5M71.4 58.5h3.5M74.8 53.3h10.4v20.7h-10.4zM80 49.9h.1M80 48.2v5.2"/>
<path d="M80 48.2l-.5 .9M80 48.2l.6 .9M85.2 55.1h3.5M85.2 56.9h3.5M85.2 58.5h3.5M90.4 55.1h2.1M90.4 56.9h2.1M90.4 58.5h2.1M92.1 54.2h3.3v13.8h-3.3zM92.5 54.6h2.6v.9h-2.6zM92.5 56.3h2.6v.9h-2.6zM92.5 58.1h2.6v.8h-2.6z"/>
<path d="M92.5 59.8h2.6v.8h-2.6zM95.1 55.1h2.1M95.1 56.9h2.1M95.1 58.5h2.1M19.1 60.2h6.8l.7 .9-.7 .9h-6.8zM19.9 60.5h5.6M20.4 60.8h-.5v.6l.3 .2 .2-.1M20.8 61.2h.3l.2-.2-.1-.3h-.4v.9M21.6 60.7v.7l.2 .2 .3-.1v-.8M22.4 61.7h.6M23.2 60.7v.8l.2 .1 .3-.2v-.7M24.1 60.7h.3l.2 .2v.4l-.3 .3h-.2z"/>
<path d="M25.4 60.7h-.4l-.1 .2 .5 .3v.2l-.1 .2-.4-.1M27 62h6.7l.7 .9-.7 .8h-6.7zM27.8 62.2h5.4M28.4 62.5l-.4-.1-.2 .4 .2 .5 .4-.1M28.7 62.9h.5v-.5h-.5v.9M29.6 62.4l.1 .9 .4-.1v-.8M30.3 63.4h.6M31.2 62.4v.9h.4M31.9 62.4l.4 .1 .1 .4-.2 .4h-.3zM33.1 62.4l-.4 .1v.3l.4 .1v.4h-.4M34.4 61.1h1.7M34.4 62.9h1.7"/>
<path d="M43 66.2v1h.9l-.9 .8-.9-.8h.9M43 66.2h.1M43 64.6v1.6M65.8 71.4h4.9l.7 .9-.7 .9h-4.9zM66.6 71.7h3.7M66.7 72.3h.4l.1-.3-.5-.1v.9M66.9 72.3l.3 .5M67.3 62.9h3.4l.7 .8-.7 .9h-3.4zM67.3 66.2h3.4l.7 1-.7 .8h-3.4zM67.3 64.6h3.4l.7 .8-.7 .8h-3.4zM67.3 61.1h3.4l.7 .9-.7 .9h-3.4zM67.5 72.3h.4"/>
<path d="M67.9 71.9h-.4v.9h.4M68.1 63.3a.49 .49 0 0 1 .5 .3 .49 .49 0 0 1-.2 .5h-.3zM68.1 66.8h.3a.47 .47 0 0 1 .2 .5 .47 .47 0 0 1-.5 .3zM68.1 65a.47 .47 0 0 1 .5 .4 .47 .47 0 0 1-.5 .5zM68.1 61.6h.3a.47 .47 0 0 1 .2 .5 .47 .47 0 0 1-.5 .3zM68.8 71.9h-.4l-.1 .3 .5 .4-.1 .2h-.4M68.9 63.5l.2-.2v.8M68.9 67l.2-.2v.8M68.9 65.2l.2-.2v.9M68.9 61.8l.2-.2v.8M68.9 60.1l.2-.3v.9M68.9 64.1h.5"/>
<path d="M68.9 67.6h.5M68.9 65.9h.5M68.9 62.4h.5M68.9 60.7h.5M69.1 72.3h.4M69.6 71.9h-.5v.9h.5M69.7 63.3h.5l-.3 .3h.2v.5l-.4-.1M69.7 61.7l.4-.1 .1 .2-.5 .6h.5M69.7 60.1l.3-.3v.9M69.7 60.7h.5M69.8 71.9h.5M69.9 65l-.2 .6h.5"/>
<path d="M70.1 71.9v.9M70.1 66.8h-.3l-.1 .4 .4-.1 .1 .3-.1 .2-.4-.1M70.1 65.3v.6M71.4 60.2h3.5M71.4 62h3.5M71.4 63.7h3.5M71.4 65.4h3.5M71.4 67.2h3.5M71.4 70.6h3.5M71.4 72.3h3.5M74.9 70.1l.4 .5-.4 .4M80 77.5v.9h.9l-.9 .8-.8-.8h.8"/>
<path d="M80 77.5h.1M80 74v3.5M85.2 60.2h3.5M85.2 62h3.5M85.2 63.7h3.5M85.2 65.4h3.5M85.2 67.2h3.5M90.4 60.2h2.1M90.4 62h2.1M90.4 63.7h2.1M90.4 65.4h2.1M90.4 67.2h2.1"/>
<path d="M92.5 61.5h2.6v.9h-2.6zM92.5 63.2h2.6v.9h-2.6zM92.5 64.9h2.6v.9h-2.6zM92.5 66.7h2.6v.9h-2.6zM95.1 60.2h2.1M95.1 62h2.1M95.1 63.7h2.1M95.1 65.4h2.1M95.1 67.2h2.1M181.6 76.1h13.8v4.3h-13.8zM181.9 76.6h1.1v2.7h-1.1zM25 99.9h3.5l.7 .8-.7 .9h-3.5z"/>
<path d="M25 98.2h3.5l.7 .8-.7 .9h-3.5zM25 96.4h3.5l.7 .9-.7 .9h-3.5zM25 91.2h3.5l.7 1-.7 .8h-3.5zM25 93h3.5l.7 .8-.7 .9h-3.5zM25 94.7h3.5l.7 .8-.7 .9h-3.5zM25.9 98.6h.2l.3 .2v.5l-.2 .1h-.3zM25.9 96.9h.3l.2 .2v.5l-.2 .1h-.3zM25.9 91.7h.3l.2 .2v.5l-.2 .2h-.3zM25.9 93.4h.2l.3 .3v.4l-.2 .2h-.3zM25.9 95.2h.3l.2 .2v.4l-.3 .3h-.2zM25.9 89.5h2.6l.7 .9-.7 .8h-2.6zM25.9 87.8h2.6l.7 .9-.7 .8h-2.6z"/>
<path d="M26.7 98.8l.3-.2v.8M26.7 97.2l.3-.3v.8M26.7 92l.3-.3v.9M26.7 93.7l.3-.3v.9M26.7 95.4l.3-.2v.9M26.7 90a.47 .47 0 0 1 .5 .4 .47 .47 0 0 1-.5 .5zM26.7 88.3a.49 .49 0 0 1 .5 .3 .49 .49 0 0 1-.2 .5h-.3zM26.7 99.4h.5M26.7 97.7h.5M26.7 92.6h.5M26.7 94.3h.5M26.7 96.1h.5"/>
<path d="M27.5 96.9h.5l-.3 .3 .3 .1v.4h-.5M27.6 93.7l.2-.3v.9M27.6 95.2h.4v.3l-.5 .6h.5M27.6 94.3h.4M27.6 91.7h.3l.1 .2-.1 .7h-.3v-.2zM27.7 98.6l-.1 .6h.5M27.7 88.6h-.1v-.3h.4v.3l-.4 .1v.4l.4-.1v-.3l-.2-.1M27.9 98.9v.5M28 90.4l-.2 .1h-.2v-.5h.4v.6l-.4 .3M29.2 88.7h3.4M29.2 90.4h3.4M29.2 92.2h3.4"/>
<path d="M29.2 93.8h3.4M29.2 95.5h3.4M29.2 97.3h3.4M29.2 99h3.4M32.6 86.9h10.3v20.7h-10.3zM37.8 83.5h.1M37.8 81.8v5.2M37.8 81.8l-.5 .9M37.8 81.8l.5 .9M43 88.7h3.4M43 90.4h3.4M43 92.2h3.4"/>
<path d="M43 93.8h3.4M43 95.5h3.4M43 97.3h3.4M43 99h3.4M55.9 87.8h6.1l.8 .9-.8 .8h-6.1zM55.9 89.5h5.3l.6 .9-.6 .8h-5.3zM56.5 89.1v-.8l.3 .6 .3-.6v.8M56.5 90v.9M57.4 90v.9l-.5-.9v.9M57.5 89.1v-.8l.3 .6 .2-.6v.8M57.7 90h.5M58 90v.9"/>
<path d="M58.3 91h.7M58.5 88.3v.8l.5-.1v-.7M59.1 89.2h.7M59.1 90.4h.3M59.6 90h-.5v.9h.5M60.1 88.7h.2M60.4 88.3h-.3v.8h.3M60.4 90v.9l-.5-.9v.9M61.3 88.3v.8l-.5-.8v.8M182.5 83.5v.9h.9l-.9 .8-.9-.8h.9M182.5 83.5h.1M23.7 105h4.8l.7 .9-.7 .9h-4.8z"/>
<path d="M24.3 105.3h3.8M24.5 106h.3l.2-.2-.1-.3h-.4v.9M24.7 106l.3 .4M25.4 105.9h.2M25.8 105.5h-.4v.9h.4M25.9 100.4h.3l.2 .1v.5l-.3 .2h-.2zM26.5 105.5l-.4 .1 .1 .3 .3 .1v.3h-.4M26.7 100.5l.3-.1v.8M26.7 101.2h.5M27 105.9h.2M27.4 105.5h-.4v.9h.4M27.6 105.5h.5"/>
<path d="M27.8 105.5v.9M28 100.4h-.4v.3h.4v.4h-.4M29.2 105.9h3.4M29.2 100.7h3.4M29.2 104.2h3.4M32.6 103.8l.5 .4-.5 .4M37.8 119.7h.1M37.8 111v1h.8l-.8 .8-.8-.8h.8M37.8 111h.1M37.8 118l-.5 .8M37.8 118l.5 .8M37.8 107.7v3.3"/>
<path d="M37.8 118v5.1M43 100.7h3.4M25.8 134.3h3.4v1.7h-3.4l-.8-.8zM25.8 129.2h3.4v1.6h-3.4l-.8-.8zM25.8 127.5h3.4v1.7h-3.4l-.8-.9zM25.8 130.8h3.4v1.8h-3.4l-.8-.8zM25.8 132.6h3.4v1.7h-3.4l-.8-.8zM25.8 136h3.4v1.8h-3.4l-.8-.9zM26.5 134.7a.47 .47 0 0 1 .5 .5 .47 .47 0 0 1-.5 .5zM26.5 129.6a.47 .47 0 0 1 .5 .4 .47 .47 0 0 1-.5 .5zM26.5 127.9a.47 .47 0 0 1 .5 .3 .47 .47 0 0 1-.1 .5h-.4zM26.5 131.4h.4a.47 .47 0 0 1 .1 .5 .47 .47 0 0 1-.5 .3z"/>
<path d="M26.5 133.1a.49 .49 0 0 1 .5 .3 .49 .49 0 0 1-.1 .5h-.4zM26.5 136.5h.4a.47 .47 0 0 1 .1 .6 .47 .47 0 0 1-.5 .3zM26.6 125.7h2.6v1.8h-2.6l-.7-.9zM26.6 124h2.6v1.7h-2.6l-.7-.9zM27.4 135l.2-.3v1M27.4 129.8l.2-.2v.9M27.4 128.1l.2-.2v.8M27.4 126.2l.4 .2v.4l-.2 .2h-.2zM27.4 124.4l.4 .3v.4l-.2 .2h-.2zM27.4 131.6l.2-.2v.8M27.4 133.3l.2-.2v.8M27.4 136.8l.2-.3v.9"/>
<path d="M27.4 135.7h.4M27.4 130.5h.4M27.4 128.7h.4M27.4 132.2h.4M27.4 133.9h.4M27.4 137.4h.4M28.1 129.8l.3-.2v.9M28.1 131.4h.6v.3l-.6 .5h.6M28.1 133.1h.6l-.3 .3 .3 .1v.3h-.6M28.1 130.5h.6M28.2 128l.3-.1 .2 .2-.1 .5a.39 .39 0 0 1-.5-.2 .39 .39 0 0 1 .1-.4zM28.3 124.8l-.2-.2 .2-.2 .4 .1v.3h-.5l-.1 .2 .2 .3h.4v-.4l-.2-.1"/>
<path d="M28.4 134.7l-.3 .6h.6M28.6 135.1v.6M28.7 126.5l-.1 .2h-.4v-.5l.5 .1-.1 .7h-.4M28.7 136.5h-.5l-.1 .4h.5l.1 .4h-.6M29.2 124.8h3.4M29.2 126.6h3.4M29.2 128.3h3.4M29.2 130h3.4M29.2 131.8h3.4M29.2 133.5h3.4M29.2 135.2h3.4M29.2 136.9h3.4"/>
<path d="M32.6 123.1h10.3v20.7h-10.3zM38.2 132.6h-.8v1.7M38.6 132.6h-.4v1.7h-1.2M43 124.8h3.4M43 126.6h3.4M43 128.3h3.4M43 130h3.4M43 131.8h3.4M43 133.5h3.4M43 135.2h3.4M43 136.9h3.4M22.3 140.3v.9h.9l-.9 .9-.8-.9h.8"/>
<path d="M22.3 140.3h.1M29.2 140.3h3.4M29.2 142.1h2.6M37.8 147.3v.8h.8l-.8 .9-.8-.9h.8M37.8 147.3h.1M37.8 143.8v3.5M36.7 179.6h2.2M36.7 166.7h2.2M37.8 178.3h.1M37.8 168.8v.8h.8l-.8 .9-.8-.9h.8M37.8 168.8h.1M37.8 165.3h.1"/>
<path d="M37.8 163.6v3.1M37.8 167.4v1.4M37.8 176.6v3M37.8 176.6l-.5 .8M37.8 176.6l.5 .8M37.8 163.6l-.5 .9M37.8 163.6l.5 .9M44.5 179.6h2.1M44.5 166.7h2.1M45.6 165.3v1.4M45.6 167.4v1.4M45.6 178.3v1.3"/>
<path d="M53.1 179.6h2.1M53.1 166.7h2.1M54.2 165.3v1.4M54.2 167.4v1.4M54.2 178.3v1.3M61.7 179.6h2.1M61.7 167.4h2.1M62.8 165.3v1.4M62.8 167.4v1.4M62.8 178.3v1.3M70.4 179.6h2M70.4 167.4h2"/>
<path d="M71.4 165.3v1.4M71.4 167.4v1.4M71.4 178.3v1.3M79 179.6h2M79 166.7h2M80 165.3v1.4M80 167.4v1.4M80 178.3v1.3M87.5 166.7h2.2M88.7 165.3v1.4M88.7 167.4v1.4M88.7 178.3v1.3"/>
<path d="M97.2 178.3v1.3M37.8 181.7v.9h.8l-.8 .8-.8-.8h.8M37.8 181.7h.1M37.8 180.3v1.4M45.6 180.3v1.4M54.2 180.3v1.4M62.8 180.3v1.4M71.4 180.3v1.4M80 180.3v1.4M87.5 180.3h2.2M88.7 180.3v1.4M96.2 180.3h2"/>
<path d="M97.2 180.3v1.4"/>
<circle cx="32.2" cy="142.1" r=".47"/>
</g>
<g fill="none" stroke="#0f0f0f" stroke-width=".21">
<path d="M52.6 51.1h4.5M52.6 49.3h4.8M52.6 47.6h4.6M52.6 45.9h4.8M52.6 54.5h3.3M52.6 52.8h3.2M52.7 47.9h.3l.2 .1v.5l-.2 .2h-.3zM52.7 46.1h.3l.2 .3v.4l-.2 .2h-.3zM52.7 55.2h.3M52.7 53.5h.3M53.1 54.7h-.4v.9h.4M53.1 53h-.4v.9h.4"/>
<path d="M53.2 51.3h-.2l-.3 .2v.4l.3 .3 .2-.1M53.2 49.7l-.2-.1-.3 .1v.5l.2 .2 .3-.1M53.5 55.2h.5l.1-.3-.2-.2h-.4v.9M53.5 53.5h.5v-.5h-.5v.9M53.6 47.9l.5 .1v.6l-.3 .1h-.2zM53.6 46.1l.5 .2v.6l-.3 .1h-.2zM53.7 55.2l.4 .4M53.7 53.5l.4 .4M54.1 51.3h-.4l-.2 .1 .1 .3 .5 .2v.2h-.6M54.1 49.7l-.4-.1-.2 .1 .2 .3 .4 .1-.1 .3h-.5M54.3 54.7l.2 .9 .1-.6 .2 .6 .3-.9M54.4 51.3v.9h.4"/>
<path d="M54.4 49.6l.1 .8 .4-.1v-.7M54.4 53.5h.4v-.5h-.4v.9M54.5 47.9v.8h.4M54.5 46.1v.8l.1 .1 .4-.1v-.8M54.6 53.5l.3 .4M55.2 53h.4a.47 .47 0 0 1 .1 .6 .47 .47 0 0 1-.5 .3zM55.3 55.2h.4l.1-.4-.5-.1v.9M55.6 51.3h-.4l-.1 .1 .1 .3 .4 .2-.2 .3-.3-.1M55.6 47.9l-.4 .1v.2l.4 .2v.2h-.4M55.6 55.2l.2 .4M55.7 49.7h-.4v.2l.4 .2v.3h-.4M55.8 46.2h-.5v.2l.5 .4-.1 .2-.4-.1"/>
<path d="M55.9 51.7h.4M56 48.3h.3M56.2 50h.2M56.2 46.5h.3M56.3 51.3h-.4v.9h.4M56.4 47.9h-.4v.8h.4M56.6 49.6h-.4v.8h.4M56.6 46.1h-.4v.9h.4M56.7 51.3v.9h.4M56.8 47.9v.8h.4M56.9 49.6v.8h.5M56.9 46.1v.9h.5"/>
<path d="M66.5 69.1h4.7M66.7 69.4l.4 .2v.5l-.2 .1h-.2zM67.5 69.4a.47 .47 0 0 1 .5 .3 .47 .47 0 0 1-.1 .5h-.4zM68.4 69.4v.8h.4l.1-.8M69.7 69.5l-.3-.1-.2 .2 .5 .4-.1 .2h-.4M70.1 69.8h.3M70.5 69.4h-.4v.8h.4M70.8 69.4v.8h.4M25.8 102.7h3.3M25.9 103.4h.2M26.3 103h-.4v.8h.4M26.6 103.4h.4l.1-.3-.5-.1v.8"/>
<path d="M26.9 103.4l.2 .4M27.4 103l.2 .8 .2-.6 .2 .6 .1-.8M28.5 103.4h.4v-.4h-.4v.8M28.7 103.4l.3 .4M25 141.5h3.2M25.1 142.1h.3M25.5 141.8h-.4v.8h.4M25.9 142.2l.5-.1-.1-.3h-.4v.8M26.1 142.2l.3 .4M26.8 142.2h.3l.2-.3-.5-.1v.8M27 142.2l.3 .4M27.6 141.8h.4a.48 .48 0 0 1 .1 .5 .48 .48 0 0 1-.5 .3z"/>
</g>
<g fill="none" stroke="#b90000" stroke-width=".21">
<path d="M34.6 58.5l.2-.2v.8M34.6 59.1h.5M34.9 46.3h.6l-.3 .3h.2l.1 .3-.2 .2-.4-.1M34.9 53.1h.6l-.3 .9M35 43l.3-.2v.8M35 44.6l.3-.1 .2 .2-.6 .7h.6M35 43.6h.5M35.2 48l-.2 .6h.5M35.2 55.2h-.2v-.3l.3-.1 .2 .3-.5 .2v.4h.2l.3-.1-.2-.4M35.4 49.7h-.4v.4l.3-.1 .2 .4-.2 .2-.3-.1M35.4 51.4l-.4 .2v.6l.3 .1 .2-.2-.1-.3h-.3l-.1 .1M35.4 48.2v.6"/>
<path d="M35.5 56.9l-.1 .2h-.3l-.1-.4 .4-.1 .1 .2-.1 .5-.3 .1M35.6 58.3a.43 .43 0 0 1 .3 .5 .43 .43 0 0 1-.4 .3l-.1-.6zM42.2 40.8h.6M42.5 40.6v.5l-.6-.2M42.8 41.4v.6l-.7-.6-.2 .2v.3M50.1 43l.2-.2v.8M50.1 44.7l.2-.2v.9M50.1 46.5l.2-.2v.8M50.1 48.2l.2-.2v.8M50.1 49.9l.2-.2v.9M50.1 51.7l.2-.3v.9M50.1 53.2l.3-.1 .2 .2-.5 .7h.5"/>
<path d="M50.1 54.9l.3-.1 .2 .2-.5 .7h.5M50.1 56.7l.4-.1 .1 .2-.5 .6h.5M50.1 58.4l.3-.1 .2 .2-.5 .6h.5M50.1 43.6h.5M50.1 45.4h.5M50.1 47.1h.5M50.1 48.8h.5M50.1 50.6h.5M50.1 52.3h.5M50.8 48h.6l-.3 .8M50.8 58.3h.6l-.3 .3 .3 .2-.1 .3h-.5M50.9 53.3l.2-.2a.43 .43 0 0 1 .3 .5 .43 .43 0 0 1-.4 .4z"/>
<path d="M50.9 55.1l.3-.3v.9M50.9 56.7l.4-.1 .1 .3-.6 .5h.6M50.9 55.7h.5M51.1 42.8l-.2 .6h.5M51.1 50.1l-.2-.1v-.3h.4l.1 .2-.5 .3v.3l.2 .1 .3-.2-.1-.3M51.3 44.5h-.4v.4l.4-.1 .1 .5-.1 .1-.4-.1M51.3 46.3l-.4 .1v.6l.4 .1 .1-.2-.1-.3h-.3l-.1 .2M51.3 43v.6M51.4 51.8l-.1 .1h-.3l-.1-.4 .4-.1 .1 .2-.1 .5-.3 .2M72.9 54h.5l-.3 .3 .3 .1v.3h-.5M72.9 57.4h.5l-.4 .9M73 59.6v-.5l.4 .1v.3l-.5 .1v.4h.5v-.4h-.2"/>
<path d="M73.1 55.7l-.2 .6h.5M73.3 56v.6M78.9 51.1h.8a.39 .39 0 0 1-.2 .4 .39 .39 0 0 1-.5-.1zM79.8 51.8v.6l-.6-.6-.3 .1 .1 .4M86.7 54.1h.5v.3l-.5 .4h.5M87.1 57.4h-.3l-.1 .7v.2l.5-.1-.1-.4h-.4v.2M87.2 55.7h-.5v.4h.5v.4h-.5M87.2 59.6l-.2 .1-.3-.1 .1-.5 .4 .1v.6l-.1 .2h-.4M90.5 54.2l.3-.2v.8M90.5 56l.3-.3v.9M90.5 57.7l.3-.3v.9M90.5 59.4l.3-.3v.9"/>
<path d="M90.5 54.8h.6M90.5 56.6h.6M90.5 58.3h.6M90.5 60h.6M91.3 59.1h.6l-.3 .4 .3 .1v.3l-.6 .1M91.6 57.4l-.2 .6h.5M91.8 54l-.3 .1-.1 .6h.5l-.2-.4-.3 .2M91.8 55.7h-.4v.4h.4l.1 .3-.2 .2-.3-.1M91.8 57.7v.6M96.1 54.2l.3-.2v.8M96.1 55.8l.5-.1v.2l-.5 .7h.5M96.1 57.4h.5l-.2 .4 .2 .2v.3l-.5-.1"/>
<path d="M96.1 54.8h.5M96.4 59.1l-.3 .6h.5M96.6 59.5v.5M34.6 60.2l.2-.2v.9M34.6 62l.2-.2v.8M34.6 60.9h.5M34.6 62.6h.5M35.3 61.8h.6l-.3 .3h.3v.5l-.6-.1M35.4 60.2l.3-.2v.9M35.4 60.9h.5M42.8 65.8h-.9l.2 .3M42.8 64.8v.5l-.5-.5-.4 .1v.3"/>
<path d="M42.8 65.6v.5M72.5 61.2l.3-.3v.9M72.5 62.9l.3-.3v.9M72.5 64.6l.3-.3v.9M72.5 66.3l.3-.2v.8M72.5 69.7l.3-.2v.9M72.5 61.8h.4M72.5 63.5h.4M72.5 65.2h.4M72.5 66.9h.4M72.5 70.4h.4M72.9 71.5l.2-.3v.9"/>
<path d="M72.9 72.1h.5M73.3 60.9h.5l-.3 .4h.3v.4h-.5M73.3 64.3h.6l-.5 .9M73.3 69.7l.2-.2v.9M73.3 70.4h.5M73.4 66.4l-.1-.2 .1-.1h.3l.1 .2-.5 .3 .1 .3 .4-.1v-.3l-.2-.1M73.5 62.6l-.2 .6h.6M73.7 62.9v.6M78.9 75.2l.7-.1 .2 .1v.3l-.7 .1-.2-.1zM79.8 76.2h-.9l.3 .2M79.8 75.9v.5M86.2 61.2l.3-.3v.9"/>
<path d="M86.2 62.9l.3-.3v.9M86.2 64.6l.3-.3v.9M86.2 66.3l.3-.2v.8M86.2 61.8h.5M86.2 63.5h.5M86.2 65.2h.5M86.2 66.9h.5M87.1 61l.4-.1 .1 .2-.5 .7h.5M87.5 62.6h-.3l-.1 .4 .4-.1v.6l-.4-.1M87.5 64.3l-.3 .1-.1 .7 .1 .1 .4-.1-.2-.5-.3 .2M87.6 66.4l-.1 .2h-.3v-.5h.3l.1 .1v.4l-.4 .3M90.5 61.2l.3-.3v.9"/>
<path d="M90.5 62.9l.3-.3v.9M90.5 64.6l.3-.3v.9M90.5 61.8h.6M90.5 63.5h.6M90.5 65.2h.6M91.4 61l.4-.1 .1 .3-.6 .6h.6M91.4 62.9l.2-.3v.9M91.4 63.5h.5M91.5 66.4l-.1 .2h-.3v-.5h.3l.1 .1v.4l-.4 .3M91.6 64.3a.48 .48 0 0 1 .3 .5 .48 .48 0 0 1-.3 .4l-.2-.1v-.6zM96.1 64.3h.5l-.3 .9M96.3 66.4l-.2-.2 .1-.1h.4v.3l-.5 .2 .2 .3 .3-.1-.1-.4"/>
<path d="M96.6 60.9h-.4l-.1 .4h.5v.3l-.1 .2-.4-.1M96.6 62.6h-.3l-.2 .3 .1 .6h.4v-.6h-.4l-.1 .2M30.3 94.7l.2-.3v1M30.3 96.5l.2-.3v.9M30.3 98.2l.2-.3v.9M30.3 99.9l.2-.3v.9M30.3 95.4h.5M30.3 97.1h.5M30.3 98.8h.5M30.7 87.6h.5l-.3 .3h.2l.1 .2-.1 .3-.4-.1M30.7 91.1h.5l-.3 .8M30.9 89.3l-.2 .6h.5"/>
<path d="M30.9 93.1l-.2-.2 .2-.2 .3 .2-.5 .4 .1 .3h.3l.1-.3-.2-.2M31 94.4h.6l-.3 .4 .3 .2v.2l-.1 .2-.5-.1M31 97.9h.6l-.3 .9M31.1 89.6v.6M31.3 96.1l-.2 .7h.5M31.5 96.5v.6M36.8 84.6a.53 .53 0 0 1 .8 .3l-.1 .1h-.6l-.2-.1zM37.6 85.4v.5l-.6-.5-.3 .2 .1 .3M44.1 94.7l.2-.3v1M44.1 96.5l.2-.3v.9M44.1 98.2l.2-.3v.9M44.1 99.9l.2-.3v.9"/>
<path d="M44.1 95.4h.5M44.1 97.1h.5M44.1 98.8h.5M44.5 87.7l.3-.1 .2 .2-.6 .6h.6M44.9 89.3h-.4v.4l.3-.1 .2 .4-.2 .2-.3-.1M44.9 91.1l-.4 .1v.6l.3 .1 .2-.2-.1-.3h-.3l-.1 .2M44.9 94.5l.4-.1v.5l-.5 .5h.5M45 93.1l-.1 .2h-.3l-.1-.5 .3-.1 .2 .2-.2 .7h-.2M45.3 97.9l-.4 .3v.5h.4v-.4h-.3l-.1 .1M45.3 96.2h-.4v.4h.4v.5l-.4-.1M30.3 103.3l.2-.2v.8M30.3 100.5h.5"/>
<path d="M30.3 103.9h.5M30.7 105l.2-.2v.9M30.7 105.7h.5M31.1 103.3l.3-.2v.8M31.1 103.9h.5M31.3 100l-.2-.1v-.2l.4-.1 .1 .3-.5 .2v.4h.2l.3-.1-.1-.4M36.8 108.8a.53 .53 0 0 1 .8 .2l-.1 .2h-.6l-.2-.2zM37.6 109.8h-.9l.3 .2M37.6 109.5v.5M44.1 100.5h.5M45.3 100v.2l-.4-.1v-.4h.4v.6l-.3 .2M30.7 123.8l.3-.1 .2 .2-.5 .7h.5"/>
<path d="M30.7 125.5h.5l-.3 .4h.3v.3l-.2 .2-.3-.1M30.7 132.4h.5l-.3 .8M30.7 139.5l.2-.3v1M30.9 127.1l-.2 .7h.5M30.9 134.5l-.2-.3 .3-.1 .2 .2-.5 .4 .2 .3 .3-.2-.2-.3M31.1 128.9h-.3l-.1 .4 .3-.1 .2 .5h-.5M31.1 130.7h-.2l-.2 .3v.4l.3 .1 .2-.4h-.5M31.1 127.5v.6M31.2 136.2l-.1 .2h-.3v-.6h.3l.1 .2v.4l-.4 .3M36.7 120.9l.2-.1h.6l.1 .1a.48 .48 0 0 1-.4 .4 .48 .48 0 0 1-.5-.4zM37.6 121.5v.6l-.6-.6-.3 .2 .1 .3M44.1 124l.2-.3v.9"/>
<path d="M44.1 125.8l.2-.3v.9M44.1 127.5l.2-.3v.9M44.1 129.2l.2-.3v.8M44.1 130.9l.2-.2v.8M44.1 132.6l.2-.2v.8M44.1 134.3l.2-.2v.9M44.1 136.1l.2-.3v.9M44.1 124.6h.5M44.1 126.4h.5M44.1 128.1h.5M44.1 129.7h.5M44.1 131.5h.5"/>
<path d="M44.1 133.2h.5M44.1 135h.5M44.1 136.7h.5M44.8 125.5h.6l-.3 .9M44.8 132.4h.5l-.2 .3 .2 .1v.3h-.5M44.9 134.2l.4-.1v.4l-.5 .5h.5M44.9 136.1l.3-.3v.9M44.9 136.7h.4M45.1 124.2l-.2-.1v-.3l.4-.1v.4l-.4 .1 .1 .4 .3-.1v-.3M45.1 130.6l-.2 .6h.5M45.3 127.2l-.4 .2v.6h.4v-.5h-.3l-.1 .2M45.3 130.9v.6"/>
<path d="M45.3 128.9h-.4v.4h.4v.4h-.4M30.3 141.3l.2-.3v.9M30.3 141.9h.5M30.7 140.2h.5M31.6 141.3l-.1 .2h-.3l-.1-.4 .4-.1 .1 .2v.3l-.4 .4M36.7 145.1l.2-.2h.6l.1 .3-.1 .1h-.6zM37.6 145.9h-.9l.3 .3M37.6 145.7v.5"/>
</g>
<g fill="none" stroke="#006665" stroke-width=".21">
<path d="M36.8 43.4v.9M36.8 45.2v.8M36.8 46.9v.8M36.8 48.6v.9M36.8 50.3v.9M36.8 52v.9M36.8 53.7v.9M36.8 55.5v.8M36.8 57.2v.8M36.8 59v.8M37.1 46.9h.6l-.3 .3h.2l.1 .2-.1 .3-.5-.1M37.1 53.7h.6l-.3 .9"/>
<path d="M37.2 43.6l.3-.2v.9M37.2 45.3l.4-.1 .1 .2-.6 .6h.6M37.2 59.1l.3-.1v.8M37.2 44.3h.5M37.2 59.8h.5M37.4 48.6l-.2 .5h.5M37.4 55.8l-.2-.2 .4-.1v.3l-.4 .1 .1 .4h.3l.1-.1-.2-.4M37.6 50.3h-.4v.5l.4-.1 .1 .3-.2 .2-.3-.1M37.6 52l-.4 .3v.5l.4 .1 .1-.4-.2-.1-.3 .1M37.6 48.9v.6M37.7 57.6l-.5 .1v-.4l.3-.1 .2 .2-.2 .6h-.2M38.1 59l.4 .1v.5l-.2 .2a.53 .53 0 0 1-.2-.8z"/>
<path d="M38.6 43.4l-.6 1.1M39.4 43.5a.4 .4 0 0 0-.5 .4 .4 .4 0 0 0 .5 .3M39.8 43.4v.9h.5M40.5 43.4v.9M40.6 43.8l.4 .5M41 43.4l-.5 .5M42.5 44.5l.9 .2-.9 .4M42.6 43.7l-.1 .4 .2 .1h.5l.2-.1-.1-.4M42.6 42.9l-.1 .3 .4 .2 .5-.2-.1-.3M46.6 59v.8M47 59.1h.5v.5l-.1 .2-.4-.2zM47.5 43.4v.9"/>
<path d="M47.5 45.2v.8M47.5 46.9v.8M47.5 48.6v.9M47.5 50.3v.9M47.5 52v.9M47.5 53.7v.9M47.5 55.5v.8M47.5 57.2v.8M47.9 45.3h.5v.5l-.2 .2-.4-.2zM47.9 48.7l.1-.1 .4 .1v.6l-.2 .2a.47 .47 0 0 1-.4-.3 .47 .47 0 0 1 .1-.5zM47.9 50.4h.5v.7h-.5zM47.9 52.2l.1-.2 .4 .2-.1 .7-.4-.1z"/>
<path d="M47.9 55.6h.5l-.1 .7h-.4zM47.9 59.1l.2-.1v.8M47.9 59.8h.5M48 43.4l.4 .2v.6l-.2 .1a.49 .49 0 0 1-.4-.4 .49 .49 0 0 1 .2-.5zM48 46.9l.4 .1-.1 .7h-.3l-.2-.2v-.4zM48 53.7l.4 .2v.6l-.2 .1a.49 .49 0 0 1-.4-.4 .49 .49 0 0 1 .2-.5zM48 57.2l.4 .2v.6h-.5a.52 .52 0 0 1 .1-.8zM48.6 46.9h.6l-.3 .3h.2l.1 .2-.1 .3-.5-.1M48.6 53.7h.6l-.3 .9M48.7 43.6l.3-.2v.9M48.7 45.3l.4-.1 .1 .2-.6 .6h.6M48.7 59.1l.4-.1a.53 .53 0 0 1-.2 .8l-.2-.2z"/>
<path d="M48.7 44.3h.5M48.9 48.6l-.2 .5h.5M48.9 55.8l-.2-.2 .4-.1v.3l-.4 .1 .1 .4h.3l.1-.1-.1-.4M49.1 50.3h-.4v.5l.4-.1 .1 .3-.1 .2-.4-.1M49.1 52l-.4 .3v.5l.4 .1 .1-.4-.1-.1-.4 .1M49.1 48.9v.6M49.2 57.6l-.5 .1v-.4l.4-.1 .1 .2-.1 .6h-.3M75.6 54.6h.3l.2 .2v.4l-.3 .3h-.2zM75.6 56.3h.3l.2 .2v.5l-.2 .2h-.3zM75.6 58h.2l.3 .3v.4l-.3 .3h-.2zM75.6 59.8h.3l.2 .2v.4l-.3 .3h-.2zM76.3 59.8h.6l-.3 .4h.2l.1 .3-.2 .2-.4-.1"/>
<path d="M76.4 56.6l.3-.3v.9M76.4 58.1l.3-.1 .2 .3-.6 .7h.6M76.4 57.2h.5M76.5 54.6a.43 .43 0 0 1 .4 .4 .43 .43 0 0 1-.3 .5l-.2-.2zM79.5 55.7l.9 .3-.9 .3M79.6 54.9l-.1 .3 .3 .2h.4l.2-.2-.1-.3M79.6 54.1l-.1 .2 .3 .3h.4l.2-.2-.1-.3M83.2 54.7h.5v.6l-.2 .2a.47 .47 0 0 1-.4-.3 .47 .47 0 0 1 .1-.5zM83.2 56.4h.5l-.1 .8-.4-.1zM83.2 58.2l.2-.2 .3 .2v.6l-.2 .2a.47 .47 0 0 1-.4-.3 .47 .47 0 0 1 .1-.5zM83.2 59.9h.5v.6l-.2 .2a.47 .47 0 0 1-.4-.3 .47 .47 0 0 1 .1-.5zM83.3 55.2l.5 .4"/>
<path d="M83.3 57l.5 .3M83.3 58.7l.5 .3M84 56.6l.3-.3v.9M84 58.1l.4-.1 .1 .2-.5 .8h.5M84 59.8h.5l-.3 .4h.3v.3l-.1 .2-.4-.1M84 57.2h.5M84.1 54.6a.43 .43 0 0 1 .4 .4 .43 .43 0 0 1-.3 .5l-.2-.2zM36.8 60.7v.8M36.8 62.4v.8M37.2 60.9l.3-.2v.8M37.2 62.6l.3-.2v.8M37.2 61.5h.5"/>
<path d="M37.2 63.2h.5M38 60.9l.2-.2v.8M38 62.4h.5v.4l-.5 .4h.5M38 61.5h.5M42.5 63.4v.3l.2 .2h.5l.2-.2v-.3h-.4v.1M42.5 62.5h.9l-.9 .4h.9M42.5 61.8l.2-.2h.5l.2 .2v.3h-.9zM75.5 71.6h1.3M75.6 61.5l.5 .2v.5l-.2 .2h-.3zM75.6 63.2h.2l.3 .3v.4l-.3 .2h-.2zM75.6 65h.3l.2 .1v.5l-.3 .2h-.2zM75.6 66.7h.2l.3 .2v.4l-.2 .2h-.3z"/>
<path d="M75.6 72.7v-.9l.3 .6 .3-.6v.9M76.1 70.2l-.4-.1-.1 .2v.5l.2 .2 .3-.1M76.3 66.7h.6l-.3 .8M76.4 70.5h.4v.4h-.4M76.4 70.4v.8M76.6 61.5l-.2 .6h.5M76.6 72.2v.5M76.8 63.2h-.4v.4l.3-.1 .2 .5-.2 .1-.3-.1M76.8 65l-.4 .1v.6l.3 .1 .2-.1-.1-.4h-.3l-.1 .2M76.8 72.2l-.2 .1M76.8 61.8v.6M79.5 71.9h.9l-.9 .5h.9"/>
<path d="M79.5 71.3l.3-.2h.4l.2 .1v.4h-.9zM79.6 72.9h-.1a.48 .48 0 0 0 .4 .4 .48 .48 0 0 0 .5-.1v-.3h-.4v.1M83.1 66.9l.4-.2 .2 .1v.6l-.4 .1zM83.2 61.6h.5l-.1 .8-.4-.1zM83.2 63.4l.2-.2 .3 .2v.6l-.2 .1a.47 .47 0 0 1-.4-.2 .47 .47 0 0 1 .1-.5zM83.2 65.1h.5v.6l-.2 .1-.4-.2zM83.3 60.4l.5 .3M83.3 62.2l.5 .2M83.3 63.9l.5 .3M83.3 65.6l.5 .3M83.3 67.3l.5 .3M84 66.7h.5l-.3 .8"/>
<path d="M84.2 61.5l-.2 .6h.5M84.5 63.2h-.5v.4l.4-.1 .1 .5-.1 .1-.4-.1M84.5 65l-.5 .1v.6l.4 .1 .1-.1v-.4h-.4l-.1 .2M84.5 61.8v.6M33.4 88.2a.47 .47 0 0 1 .5 .4 .47 .47 0 0 1-.5 .5zM33.4 90h.3a.47 .47 0 0 1 .2 .5 .47 .47 0 0 1-.5 .3zM33.4 91.6a.49 .49 0 0 1 .4 .4 .49 .49 0 0 1-.1 .5h-.3zM33.4 93.3a.47 .47 0 0 1 .5 .5 .47 .47 0 0 1-.5 .5zM33.4 95.1h.3a.47 .47 0 0 1 .2 .6 .47 .47 0 0 1-.5 .3zM33.4 96.8a.49 .49 0 0 1 .4 .3 .49 .49 0 0 1-.1 .6h-.3zM33.4 98.5a.47 .47 0 0 1 .5 .5 .47 .47 0 0 1-.5 .4zM34.2 90.2l.2-.2v.8"/>
<path d="M34.2 91.7h.5v.3l-.5 .5h.5M34.2 93.3h.5l-.3 .4 .3 .1v.4h-.5M34.2 90.8h.5M34.2 88.3l.3-.1 .2 .1v.6l-.2 .2a.53 .53 0 0 1-.3-.8zM34.4 95l-.2 .7h.6M34.6 98.5l-.3 .1-.1 .7 .1 .1h.4v-.5l-.4-.1-.1 .2M34.6 95.4v.6M34.7 96.8h-.5v.4h.4l.1 .4h-.5M37.4 89.3l.8 .2-.8 .4M37.5 88.5l-.1 .4 .1 .1h.6l.1-.2-.1-.3M37.5 87.7l-.1 .3a.42 .42 0 0 0 .5 .2 .42 .42 0 0 0 .2-.5M40.9 88.3l.2-.1a.47 .47 0 0 1 .4 .4 .47 .47 0 0 1-.4 .5l-.2-.2z"/>
<path d="M40.9 90h.5l.1 .2v.3l-.2 .3-.4-.2zM40.9 91.8l.4-.2 .2 .3-.1 .6-.5-.1zM40.9 93.5l.2-.2a.47 .47 0 0 1 .4 .5 .47 .47 0 0 1-.4 .5l-.2-.2zM40.9 95.2h.5v.7h-.5zM40.9 97l.2-.2a.42 .42 0 0 1 .4 .4 .42 .42 0 0 1-.4 .5l-.2-.1zM41.1 88.9l.4 .3M41.1 90.5l.4 .4M41.1 92.3l.4 .3M41.1 94l.4 .4M41.1 95.8l.4 .3M41.1 97.5l.4 .2M41.1 99.2l.4 .3"/>
<path d="M41.1 98.5a.47 .47 0 0 1 .4 .5 .47 .47 0 0 1-.4 .4l-.2-.1v-.6zM41.8 93.3h.5l-.3 .4 .3 .1v.4h-.5M41.9 88.3l.2-.1 .2 .1v.6l-.2 .2-.2-.1zM41.9 90.2l.1-.2v.8M41.9 91.7h.4v.3l-.5 .5h.5M41.9 90.8h.4M42 95l-.1 .7h.5M42.2 98.5l-.3 .3v.6h.4v-.5l-.4-.1v.2M42.2 95.4v.6M42.3 96.8h-.4v.4h.4l-.1 .5-.3-.1M33.2 105.2h1.4M33.4 100.3l.4 .1 .1 .4-.2 .3h-.3z"/>
<path d="M33.4 106.3v-.9l.3 .6 .3-.6v.9M33.9 103.8h-.4a.44 .44 0 0 0-.1 .5 .44 .44 0 0 0 .5 .2M34.2 100.3h.6l-.5 .8M34.2 104.5l.3 .1 .2-.2-.1-.4h-.4v.9M34.3 105.7v.6M34.6 105.7l-.3 .2M37.4 106.5v.3a.44 .44 0 0 0 .6 .2 .44 .44 0 0 0 .1-.6h-.2v.1M37.4 105.5h.8l-.8 .5h.8M37.4 104.9l.1-.2h.6l.1 .4h-.8zM40.9 100.4h.5l.1 .5-.1 .2-.5-.1zM41.1 101l.4 .2M41.8 100.3h.6l-.5 .8"/>
<path d="M33.6 125.3l.3-.9 .3 .9M33.6 127l.3-.9 .3 .9M33.6 128.7l.3-.9 .3 .9M33.6 130.4l.3-.8 .3 .8M33.6 132.1l.3-.8 .3 .8M33.6 133.9l.3-.9 .3 .9M33.6 135.6l.3-.9 .3 .9M33.6 137.3l.3-.9 .3 .9M33.7 125h.4M33.7 126.7h.4M33.7 128.5h.4M33.7 130.2h.4"/>
<path d="M33.7 131.9h.4M33.7 133.6h.4M33.7 135.3h.4M33.7 137h.4M34.4 126.4l.3-.3v.9M34.4 127.9l.4-.1 .1 .2-.5 .7h.5M34.4 129.6h.5l-.2 .3h.1l.1 .4-.1 .1-.4-.1M34.4 136.4h.5l-.3 .9M34.4 127h.5M34.5 124.5l.1-.1a.45 .45 0 0 1 .3 .4 .45 .45 0 0 1-.2 .5l-.3-.4zM34.7 131.3l-.3 .6h.5M34.8 133h-.3l-.1 .4 .4-.1 .1 .4-.1 .2-.4-.1"/>
<path d="M34.8 134.7h-.2l-.2 .7 .2 .2 .3-.2-.1-.3h-.3l-.1 .2M34.8 131.5v.6M37.4 125.8l.8 .3-.8 .3M37.5 125l-.1 .3 .1 .2h.6l.1-.2-.1-.3M37.5 124.2l-.1 .3 .1 .2h.6l.1-.3-.1-.2M40.7 124.8h.4v-.3l-.4-.1v.9h.3l.2-.4-.3-.1M40.7 126.5l.4-.1-.1-.3h-.3v.9h.4l.1-.3-.3-.2M40.7 128.2h.3l.1-.3-.4-.1v.9h.3l.2-.3-.3-.2M40.7 130l.4-.1-.1-.3h-.3v.8h.3l.2-.1v-.2l-.3-.1M40.7 131.7l.4-.1v-.2l-.4-.1v.8h.4l.1-.2-.3-.2M40.7 133.4h.3l.1-.3-.4-.1v.9h.3l.2-.3-.3-.2M40.7 135.2l.4-.1-.1-.4h-.3v.9h.3l.2-.2-.1-.2h-.2"/>
<path d="M40.7 136.9l.4-.1v-.3l-.4-.1v.9h.4l.1-.3-.3-.1M41.4 126.4l.3-.3v.9M41.4 127.9h.5v.3l-.5 .5h.5M41.4 129.6h.5l-.2 .3 .2 .1v.3h-.5M41.4 136.4h.6l-.4 .9M41.4 127h.5M41.5 124.5l.4-.1v.2v.5l-.1 .2a.48 .48 0 0 1-.3-.8zM41.7 131.3l-.3 .6h.6M41.9 134.7h-.3l-.2 .7 .2 .2 .3-.1v-.4h-.4l-.1 .2M41.9 131.5v.6M41.9 133h-.4l-.1 .4h.5v.4h-.5M33.6 140.8l.3-.9 .3 .9"/>
<path d="M33.7 140.5h.4M34.2 141.7a.44 .44 0 0 0-.5 .2 .44 .44 0 0 0 .1 .5h.4M34.5 140.4h.6M34.6 142h.2M35 141.6h-.4v.8h.4M35.5 140.2l.7 .2-.7 .3M36.6 140.3l.4-.1v-.3h-.4v.9h.4l.1-.2-.1-.3h-.1M37.4 142.3v.3a.42 .42 0 0 0 .5 .2 .42 .42 0 0 0 .2-.5h-.2v.1M37.4 141.3h.8l-.8 .6h.8M37.4 140.7l.1-.2h.6l.1 .5h-.8z"/>
</g>
<g fill="none" stroke="#910000" stroke-width=".25">
<path d="M36.8 167.4h2.1M44.6 167.4h2M53.1 167.4h2.1M61.8 166.7h2.1M70.4 166.7h2M79 167.4h2.1M87.6 167.4h2.1M87.6 179.6h2.1M96.2 179.6h2.1M36.8 180.3h2.1M44.6 180.3h2M53.1 180.3h2.1"/>
<path d="M61.8 180.3h2.1M70.4 180.3h2M79 180.3h2.1"/>
</g>
<path d="M182.4 79.6l.3 .2-.1 .2-.4-.2z" fill="#910000"/>
<path d="M182.4 79.7l.3 .2-.1 .2-.3-.2zM182.5 79.4v.5h1.8v-.5M182.5 75.7v1M183.7 76.6h1v2.7h-1z" fill="none" stroke="#910000" stroke-width=".21"/>
<path d="M184.1 79.6l.3 .2-.1 .2-.3-.2z" fill="#910000"/>
<path d="M184.2 79.7l.3 .2-.1 .2-.3-.2zM184.3 79.4v.5h1.7v-.5M184.3 75.7v1M185.4 76.6h1v2.7h-1z" fill="none" stroke="#910000" stroke-width=".21"/>
<path d="M185.8 79.6l.3 .2-.1 .2-.3-.2z" fill="#910000"/>
<path d="M185.9 79.7l.3 .2-.1 .2-.3-.2zM186 79.4v.5h1.7v-.5M186 75.7v1M187.1 76.6h1v2.7h-1z" fill="none" stroke="#910000" stroke-width=".21"/>
<path d="M187.5 79.6l.3 .2-.1 .2-.3-.2z" fill="#910000"/>
<path d="M187.6 79.7l.3 .2-.1 .2-.4-.2zM187.7 79.4v.5h1.7v-.5M187.7 75.7v1M188.9 76.6h1v2.7h-1z" fill="none" stroke="#910000" stroke-width=".21"/>
<path d="M189.3 79.6l.3 .2-.1 .2-.3-.2z" fill="#910000"/>
<path d="M189.3 79.7l.4 .2-.2 .2-.3-.2zM189.4 79.4v.5h1.7v-.5M189.4 75.7v1M190.6 76.6h1v2.7h-1z" fill="none" stroke="#910000" stroke-width=".21"/>
<path d="M191 79.6l.3 .2-.1 .2-.3-.2z" fill="#910000"/>
<path d="M191 79.7l.3 .2-.1 .2-.3-.2zM191.1 79.4v.5h1.7v-.5M191.1 75.7v1M192.3 76.6h1.1v2.7h-1.1z" fill="none" stroke="#910000" stroke-width=".21"/>
<path d="M192.7 79.6l.3 .2-.1 .2-.3-.2z" fill="#910000"/>
<g fill="none" stroke="#910000" stroke-width=".21">
<path d="M109.3 27.6h1.7M109.3 29.2h1.7M109.3 30.9h1.7M109.3 32.7h1.7M109.3 34.4h1.7M109.3 36.1h1.7M109.3 37.9h1.7M109.3 25.8h1.7M111 22.3h20.7v17.2h-20.7zM119.6 25.6h.2v.4h-.2zM120 27.3l-.3-.3 .1-.3 .6-.1 .2 .2 .1 .2-.2 .2-.5 .1-.3 .3v.4l.3 .3h.4l.3-.3v-.4l-.3-.3M120 25.6v.4"/>
<path d="M120.5 25.6h-.2l.1 .4 .1-.1-.1-.1M120.7 25.7l.1-.1v.4M120.7 26h.2M121.4 28.1v.2M121.9 25.6l.2 .2-.1 .2zM122.3 25.6v.4M122.5 27.3l-.4-.3 .2-.3 .5-.1 .3 .2v.2l-.1 .2-.5 .1-.4 .3v.4l.4 .3h.3l.3-.3v-.4l-.3-.3M122.7 25.6l-.2 .1 .1 .3v-.2M122.9 25.6h.2l-.2 .4h.2M123.8 28.1v.2M131.7 27.6h1.8M131.7 29.2h1.8"/>
<path d="M131.7 30.9h1.8M131.7 32.7h1.8M131.7 34.4h1.8M131.7 36.1h1.8M131.7 37.9h1.8M131.7 25.8h1.8M156.8 33.6h3.3v1.7h-3.3l-.8-.9zM156.8 35.3h3.3v1.7h-3.3l-.8-.9zM156.8 31.9h3.3v1.7h-3.3l-.8-.9zM156.8 30.1h3.3v1.8h-3.3l-.8-1zM156.8 37h3.3v1.7h-3.3l-.8-.8zM156.8 38.7h3.3v1.7h-3.3l-.8-.8z"/>
<path d="M157.4 34a.48 .48 0 0 1 .5 .3 .48 .48 0 0 1-.1 .5h-.4zM157.4 35.8h.4a.48 .48 0 0 1 .1 .5 .48 .48 0 0 1-.5 .3zM157.4 32.3l.5 .1v.4l-.1 .3h-.4zM157.4 30.6h.4a.48 .48 0 0 1 .1 .6 .48 .48 0 0 1-.5 .3zM157.4 37.5h.5v.5l-.1 .3h-.4zM157.4 39.2a.48 .48 0 0 1 .5 .3 .48 .48 0 0 1-.1 .5h-.4zM157.5 28.4h2.6v1.7h-2.6l-.7-.9zM157.5 26.6h2.6v1.8h-2.6l-.7-.8zM158.3 34.2l.2-.2v.8M158.3 35.9l.2-.1v.8M158.3 28.8a.49 .49 0 0 1 .4 .3 .49 .49 0 0 1-.1 .6h-.3zM158.3 27.1l.4 .1 .1 .4-.2 .4h-.3z"/>
<path d="M158.3 32.6l.2-.3v.8M158.3 30.8l.2-.2v.9M158.3 37.7l.2-.2v.8M158.3 39.4l.2-.2v.8M158.3 34.8h.5M158.3 36.6h.5M158.3 33.1h.5M158.3 31.5h.5M158.3 38.3h.5M159 34.1h.6v.3l-.6 .4h.6M159 35.8h.6l-.3 .2 .3 .1v.4h-.6M159 32.6l.3-.3v.8"/>
<path d="M159 33.1h.6M159.1 30.7h.5v.6l-.2 .2-.3-.1zM159.2 27.5l-.2-.2 .1-.2h.4l.1 .3-.6 .2 .1 .4 .5-.1v-.3l-.2-.1M159.3 37.4l-.3 .7h.6M159.5 37.7v.6M159.6 29.2l-.2 .2-.4-.2 .2-.4 .4 .1v.6l-.5 .2M159.6 39.2h-.5l-.1 .4h.6v.3h-.6M160.1 27.6h3.5M160.1 29.2h3.5M160.1 30.9h3.5M160.1 32.7h3.5M160.1 34.4h3.5"/>
<path d="M160.1 36.1h3.5M160.1 37.9h3.5M160.1 39.6h3.5M163.6 25.7h10.3v20.7h-10.3zM168.8 22.4h.1M168.8 20.6v5.2M168.8 20.6l.5 .9M168.8 20.6l-.6 .9M169.2 35.3h-.9v1.7M169.6 35.3h-.4v1.7h-1.4M173.9 27.6h3.4M173.9 29.2h3.4"/>
<path d="M173.9 30.9h3.4M173.9 32.7h3.4M173.9 34.4h3.4M173.9 36.1h3.4M173.9 37.9h3.4M173.9 39.6h3.4M199.8 27.6h3.4M199.8 29.2h3.4M199.8 30.9h3.4M199.8 32.7h3.4M199.8 34.4h3.4M199.8 36.1h3.4"/>
<path d="M199.8 37.9h3.4M199.8 39.6h3.4M202.3 25.7h5.1v15.5h-5.1zM203.9 39.7l2.6 .6M203.9 38l2.6 .6M203.9 36.2l2.6 .8M203.9 34.5l2.6 .7M203.9 32.8l2.6 .7M203.9 31.1l2.6 .7M203.9 29.3l2.6 .8M203.9 27.6l2.6 .7M206.6 27.6h3.5"/>
<path d="M206.6 29.2h3.5M206.6 30.9h3.5M206.6 32.7h3.5M206.6 34.4h3.5M206.6 36.1h3.5M206.6 37.9h3.5M206.6 39.6h3.5M210.1 24.9h.1M210.1 23.2l-.5 .9M210.1 23.2l.5 .9M210.1 23.2v1.7M108.6 55.9h2.5l.8 1-.8 .8h-2.5z"/>
<path d="M108.6 54.2h2.5l.8 .9-.8 .8h-2.5zM108.6 57.7h2.5l.8 .8-.8 .9h-2.5zM108.6 59.4h2.5l.8 .8-.8 .9h-2.5zM108.8 43.9l.5 .8M109.3 43h.1M109.3 56.4h.4l.2 .2v.4l-.3 .3h-.3zM109.3 54.6h.3l.3 .3v.4l-.3 .3h-.3zM109.3 58.1h.3l.3 .3v.4l-.2 .2h-.4zM109.3 59.8h.3l.3 .3v.4l-.3 .2h-.3zM109.3 43v1.7M109.9 43.9l-.6 .8M110.2 56.7l.2-.3v.9"/>
<path d="M110.2 58.2h.5v.3l-.5 .5h.5M110.2 59.8h.5l-.3 .4h.3v.5h-.5M110.2 57.3h.5M110.3 54.7l.2-.1 .2 .2v.6l-.2 .2a.53 .53 0 0 1-.2-.9zM111.9 55.1h3.5M111.9 56.9h3.5M111.9 58.5h3.5M115.3 53.3h10.3v20.7h-10.3zM120.5 49.9h.1M120.5 48.2l.5 .9M120.5 48.2l-.5 .9M120.5 48.2v5.2"/>
<path d="M125.7 55.1h3.5M125.7 56.9h3.5M125.7 58.5h3.5M130.8 55.1h2.2M130.8 56.9h2.2M130.8 58.5h2.2M132.6 54.2h3.3v13.8h-3.3zM132.9 54.6h2.6v.9h-2.6zM132.9 56.3h2.6v.9h-2.6zM132.9 58.1h2.6v.8h-2.6zM132.9 59.8h2.6v.8h-2.6zM135.6 55.1h2.1"/>
<path d="M135.6 56.9h2.1M135.6 58.5h2.1M158.3 40h.5M159.3 43v-.8l-.8 .8 .8 .9v-.9h.8M160.1 43h.1M160.1 43h3.5M160.1 44.7h2.6M163.6 59.3h10.3v20.7h-10.3zM168.8 55.9h.1M168.8 46.4v3.5M168.8 54.2v5.2M168.8 54.2l.5 .9"/>
<path d="M168.8 54.2l-.6 .9M181.6 42.6h13.8v4.3h-13.8zM181.9 43h1.1v2.7h-1.1zM182.5 49.9v.9h.9l-.9 .9-.9-.9h.9M182.5 49.9h.1M202.3 59.3h5.1v15.5h-5.1zM106.4 71.4h4.7l.8 .9-.8 .9h-4.7zM107.1 71.7h3.7M107.1 72.3h.5l.1-.3-.6-.1v.9M107.4 72.3l.3 .5M108.1 72.3h.2M108.4 71.9h-.3v.9h.3"/>
<path d="M108.6 66.2h2.5l.8 1-.8 .8h-2.5zM108.6 62.9h2.5l.8 .8-.8 .9h-2.5zM108.6 64.6h2.5l.8 .8-.8 .8h-2.5zM108.6 61.1h2.5l.8 .9-.8 .9h-2.5zM109.3 71.9h-.5v.2l.1 .2 .4 .1v.3l-.5 .1M109.3 66.8h.4l.2 .1v.5l-.3 .2h-.3zM109.3 63.3h.3l.3 .2v.5l-.2 .1h-.4zM109.3 65h.3l.3 .2v.5l-.3 .2h-.3zM109.3 61.6h.4l.2 .2v.5l-.3 .1h-.3zM109.6 72.3h.3M110 71.9h-.4v.9h.4M110.2 66.8h.5l-.3 .8"/>
<path d="M110.3 71.9h.5M110.4 61.5l-.2 .7h.5M110.5 71.9v.9M110.6 65l-.2 .1-.2 .6 .2 .2 .3-.1v-.4l-.3-.1-.2 .2M110.6 61.8v.6M110.7 63.3h-.4l-.1 .4 .4-.1 .1 .4h-.5M111.9 60.2h3.5M111.9 62h3.5M111.9 63.7h3.5M111.9 65.4h3.5M111.9 67.2h3.5M111.9 72.3h3.5"/>
<path d="M111.9 70.6h3.5M115.4 70.1l.4 .5-.4 .4M120.5 77.5v.9h.9l-.9 .8-.8-.8h.8M120.5 77.5h.1M120.5 74v3.5M125.7 60.2h3.5M125.7 62h3.5M125.7 63.7h3.5M125.7 65.4h3.5M125.7 67.2h3.5M130.8 60.2h2.2M130.8 62h2.2"/>
<path d="M130.8 63.7h2.2M130.8 65.4h2.2M130.8 67.2h2.2M132.9 61.5h2.6v.9h-2.6zM132.9 63.2h2.6v.9h-2.6zM132.9 64.9h2.6v.9h-2.6zM132.9 66.7h2.6v.9h-2.6zM135.6 60.2h2.1M135.6 62h2.1M135.6 63.7h2.1M135.6 65.4h2.1M135.6 67.2h2.1"/>
<path d="M157.5 65.4h2.6v1.8h-2.6l-.7-1zM157.5 68.9h2.6v1.7h-2.6l-.7-.9zM157.5 67.2h2.6v1.7h-2.6l-.7-.9zM157.5 60.2h2.6v1.8h-2.6l-.7-.9zM157.5 63.7h2.6v1.7h-2.6l-.7-.8zM157.5 62h2.6v1.7h-2.6l-.7-.8zM157.5 72.3h2.6v1.7h-2.6l-.7-.8zM157.5 70.6h2.6v1.7h-2.6l-.7-.9zM158.3 65.9h.3a.48 .48 0 0 1 .2 .6 .48 .48 0 0 1-.5 .3zM158.3 69.3a.49 .49 0 0 1 .4 .3 .49 .49 0 0 1-.1 .5h-.3zM158.3 67.6l.4 .1 .1 .4-.2 .3h-.3zM158.3 60.7h.3a.48 .48 0 0 1 .2 .6 .48 .48 0 0 1-.5 .3z"/>
<path d="M158.3 64.1a.49 .49 0 0 1 .4 .3 .49 .49 0 0 1-.1 .6h-.3zM158.3 62.4l.4 .1 .1 .4-.2 .4h-.3zM158.3 72.8a.47 .47 0 0 1 .5 .3 .47 .47 0 0 1-.2 .5h-.3zM158.3 71.1h.3a.48 .48 0 0 1 .2 .5 .48 .48 0 0 1-.5 .3zM159 65.9h.6l-.3 .3h.3v.5h-.6M159 64.2h.6v.4l-.6 .4h.6M159 62.7l.3-.3v.9M159 72.8h.6l-.4 .8M159 63.3h.6M159.1 60.8l.4-.1 .1 .2v.5l-.2 .2a.48 .48 0 0 1-.3-.8zM159.3 67.5l-.3 .7h.6M159.3 76.7v-1l-.8 1 .8 .8v-.8h.8"/>
<path d="M159.5 71.1h-.3l-.2 .7 .2 .1 .4-.1-.1-.4-.5 .1M159.5 67.9v.5M159.6 69.3h-.5l-.1 .4h.6v.4h-.6M160.1 76.7h.1M160.1 73.2h3.5M160.1 71.4h3.5M160.1 69.7h3.5M160.1 68h3.5M160.1 66.2h3.5M160.1 64.6h3.5M160.1 62.9h3.5M160.1 61.1h3.5"/>
<path d="M160.1 76.7h3.5M160.1 78.4h2.6M169.2 68.9h-.9v1.7M169.6 68.9h-.4v1.7h-1.4M173.9 73.2h3.4M173.9 71.4h3.4M173.9 69.7h3.4M173.9 68h3.4M173.9 66.2h3.4M173.9 64.6h3.4M173.9 62.9h3.4M173.9 61.1h3.4"/>
<path d="M182.5 74.9v.8M184.3 74.9v.8M186 74.9v.8M187.7 74.9v.8M189.4 74.9v.8M191.1 74.9v.8M192.7 79.7l.3 .2-.1 .2-.3-.2zM192.8 79.4v.5h1.8v-.5M192.8 74.9v1.8M194.1 76.6h1v2.7h-1zM194.6 74.9v1.8M199.8 73.2h3.4"/>
<path d="M199.8 71.4h3.4M199.8 69.7h3.4M199.8 68h3.4M199.8 66.2h3.4M199.8 64.6h3.4M199.8 62.9h3.4M199.8 61.1h3.4M203.9 73.3l2.6 .7M203.9 71.5l2.6 .8M203.9 69.8l2.6 .7M203.9 68.1l2.6 .7M203.9 66.3l2.6 .8"/>
<path d="M203.9 64.6l2.6 .8M203.9 62.9l2.6 .7M203.9 61.3l2.6 .6M206.6 73.2h3.5M206.6 71.4h3.5M206.6 69.7h3.5M206.6 68h3.5M206.6 66.2h3.5M206.6 64.6h3.5M206.6 62.9h3.5M206.6 61.1h3.5M168.8 80v3.5"/>
<path d="M182.5 80v1.8"/>
<circle cx="203.6" cy="39.6" r=".38"/>
<circle cx="203.6" cy="30.9" r=".38"/>
<circle cx="203.6" cy="37.9" r=".38"/>
<circle cx="203.6" cy="32.7" r=".38"/>
<circle cx="203.6" cy="34.4" r=".38"/>
<circle cx="203.6" cy="29.2" r=".38"/>
<circle cx="203.6" cy="27.6" r=".38"/>
<circle cx="203.6" cy="36.1" r=".38"/>
<circle cx="206.3" cy="39.6" r=".38"/>
<circle cx="206.3" cy="30.9" r=".38"/>
<circle cx="206.3" cy="37.9" r=".38"/>
<circle cx="206.3" cy="34.4" r=".38"/>
<circle cx="206.3" cy="29.2" r=".38"/>
<circle cx="206.3" cy="27.6" r=".38"/>
<circle cx="206.3" cy="32.7" r=".38"/>
<circle cx="206.3" cy="36.1" r=".38"/>
<circle cx="163.1" cy="44.7" r=".47"/>
<circle cx="163.1" cy="78.4" r=".47"/>
<circle cx="203.6" cy="69.7" r=".38"/>
<circle cx="203.6" cy="64.6" r=".38"/>
<circle cx="203.6" cy="61.1" r=".38"/>
<circle cx="203.6" cy="66.2" r=".38"/>
<circle cx="203.6" cy="73.2" r=".38"/>
<circle cx="203.6" cy="71.4" r=".38"/>
<circle cx="203.6" cy="68" r=".38"/>
<circle cx="203.6" cy="62.9" r=".38"/>
<circle cx="206.3" cy="73.2" r=".38"/>
<circle cx="206.3" cy="66.2" r=".38"/>
<circle cx="206.3" cy="64.6" r=".38"/>
<circle cx="206.3" cy="62.9" r=".38"/>
<circle cx="206.3" cy="61.1" r=".38"/>
<circle cx="206.3" cy="71.4" r=".38"/>
<circle cx="206.3" cy="68" r=".38"/>
<circle cx="206.3" cy="69.7" r=".38"/>
</g>
<g fill="none" stroke="#b90000" stroke-width=".21">
<path d="M109.5 24.9l.3-.2v.9M109.5 26.7l.3-.2v.8M109.5 33.6l.3-.3v.9M109.5 35.3l.3-.3v.9M109.5 27.3h.5M109.5 34.2h.5M109.5 35.9h.5M109.5 25.6h.5M109.9 29.8h.5l-.3 .4 .3 .1v.3l-.1 .2-.4-.1M109.9 28.4l.3-.3v.9M109.9 31.7l.5-.1v.3l-.5 .6h.5M109.9 29h.5"/>
<path d="M110.1 36.7l-.2 .7h.5M110.3 26.5h.6l-.4 .3h.3l.1 .3-.2 .2-.4-.1M110.4 37v.6M110.5 33.3l-.1 .6h.5M110.8 24.7h-.4v.4l.3-.1 .2 .4-.2 .2-.3-.1M110.8 35l-.4 .1v.8h.3l.2-.1-.2-.5-.3 .2M110.8 33.7v.5M131.9 24.9l.2-.2v.9M131.9 26.7l.2-.2v.8M131.9 33.6l.2-.3v.9M131.9 27.3h.5M131.9 34.2h.5"/>
<path d="M131.9 25.6h.5M132.3 31.6h.6l-.4 .9M132.5 28.5l-.2-.1 .2-.3 .3 .1-.1 .3-.4 .2 .1 .3 .4-.1v-.3l-.2-.1M132.7 26.5h.5v.3l-.5 .5h.5M132.7 29.8l-.2 .1-.2 .7 .2 .2 .3-.1v-.4l-.3-.1-.2 .1M132.7 33.6l.3-.3v.9M132.7 34.2h.5M132.8 24.8l.3-.1 .1 .1v.6l-.1 .2a.53 .53 0 0 1-.3-.8zM132.8 35.4l-.3 .2-.2-.4 .2-.2 .3 .1v.6l-.4 .2M132.8 36.8h-.4l-.1 .4 .4-.1 .1 .4h-.5M161.6 26.5h.5v.3l-.5 .5h.5M161.6 28.1h.5l-.3 .4 .3 .1v.3h-.5"/>
<path d="M161.6 35h.6l-.4 .9M161.8 37.1l-.2-.1 .1-.2h.3l.1 .2-.5 .3 .1 .3 .4-.1v-.3l-.2-.1M161.8 29.8l-.2 .6h.6M162 33.3l-.2 .1-.2 .6 .1 .2 .4-.1v-.4h-.2l-.3 .1M162 30.2v.6M162.1 31.6h-.4l-.1 .4h.4l.1 .4h-.5M162.1 38.9h-.5l.2-.4 .3 .1v.6l-.4 .1M167.7 23.6a.48 .48 0 0 1 .5-.2 .48 .48 0 0 1 .3 .3l-.1 .2h-.6l-.1-.1zM168.5 24.3v.5l-.5-.5h-.2v.5M175 26.7l.2-.2v.8M175 28.4l.2-.3v.9M175 30.1l.2-.3v1"/>
<path d="M175 31.9l.2-.3v.9M175 33.6l.2-.3v.9M175 35.3l.2-.3v.9M175 37l.2-.2v.8M175 38.7l.2-.2v.8M175 27.3h.5M175 29h.5M175 30.8h.5M175 32.5h.5M175 34.2h.5M175 35.9h.5M175 37.6h.5"/>
<path d="M175 39.3h.5M175.7 28.1h.6l-.3 .9M175.7 35h.6l-.3 .3 .3 .2v.3l-.2 .1h-.4M175.8 36.9l.4-.1 .1 .2-.6 .6h.6M175.8 38.7l.3-.2v.8M175.8 39.3h.5M176 26.8l-.2-.3h.4v.3l-.4 .1v.3l.2 .1 .3-.2-.2-.3M176 33.3l-.2 .6h.5M176.2 29.8l-.3 .1-.1 .8 .3 .1 .2-.2-.2-.4-.3 .1M176.2 31.6h-.4v.4h.4l.1 .3-.2 .2-.3-.1M176.2 33.7v.5M201.2 38.7l.3-.2v.8"/>
<path d="M201.2 36.9h.5v.2l-.5 .5h.5M201.2 35h.5l-.2 .3 .2 .1v.5h-.5M201.2 28.1h.6l-.4 .9M201.2 39.3h.5M201.4 26.8l-.2-.2 .1-.1h.4l-.1 .3-.4 .2 .2 .3 .3-.1v-.3l-.2-.1M201.5 33.3l-.3 .6h.6M201.6 29.8l-.2 .1-.2 .7 .2 .2 .3-.1v-.4l-.3-.1-.2 .1M201.6 33.7v.5M201.7 31.6h-.4l-.1 .4h.4l.1 .4h-.5M207.7 38.7l.3-.2v.8M207.7 37l.3-.2v.8M207.7 35.3l.3-.3v.9"/>
<path d="M207.7 33.6l.3-.3v.9M207.7 31.9l.3-.3v.9M207.7 30.1l.3-.3v1M207.7 28.4l.3-.3v.9M207.7 29h.5M207.7 30.8h.5M207.7 32.5h.5M207.7 34.2h.5M207.7 35.9h.5M207.7 37.6h.5M207.7 39.3h.5M208.5 33.3h.5l-.3 .4h.3v.4h-.5"/>
<path d="M208.5 31.7h.5v.3l-.5 .5h.5M208.5 30.1l.2-.3v1M208.5 30.8h.5M208.6 28.2l.2-.1 .2 .2-.1 .6a.39 .39 0 0 1-.4-.2 .39 .39 0 0 1 .1-.5zM208.6 26.8l-.1 .2h-.3l-.1-.5h.5v.6l-.4 .2M208.7 35l-.2 .6h.6M208.9 38.5l-.2 .1-.2 .6 .1 .1 .4-.1v-.3l-.3-.1-.2 .2M208.9 35.3v.6M209 36.8h-.4l-.1 .4 .4-.1 .1 .4h-.5M113.3 54h.5l-.2 .3 .2 .1v.3h-.5M113.3 57.4h.6l-.3 .9M113.6 55.7l-.2 .6h.5"/>
<path d="M113.6 59.6l-.2-.1v-.3l.3-.1 .1 .1v.3l-.4 .1v.4h.4v-.4h-.1M113.7 56v.6M119.4 51.1h.8a.39 .39 0 0 1-.2 .4 .39 .39 0 0 1-.5-.1zM120.3 51.8v.6l-.6-.6-.3 .1 .1 .4M127.1 54.1h.5v.3l-.5 .4h.5M127.5 57.4h-.2l-.2 .7 .1 .2 .4-.1-.1-.4h-.3l-.1 .2M127.6 55.7h-.4l-.1 .4h.5v.4h-.5M127.6 59.6l-.1 .1-.4-.1 .2-.5 .3 .1v.6l-.1 .2h-.3M131 54.2l.3-.2v.8M131 56l.3-.3v.9M131 57.7l.3-.3v.9M131 59.4l.3-.3v.9"/>
<path d="M131 54.8h.5M131 56.6h.5M131 58.3h.5M131 60h.5M131.9 59.1h.5l-.3 .4 .3 .1v.3l-.5 .1M132.1 57.4l-.2 .6h.5M132.3 54l-.3 .1-.1 .6h.5l-.2-.4-.3 .2M132.3 55.7h-.4v.4h.4l.1 .3-.2 .2-.3-.1M132.3 57.7v.6M136.6 54.2l.3-.2v.8M136.6 55.8h.5v.3l-.5 .5h.5M136.6 57.4h.5l-.2 .4 .2 .1v.3h-.5"/>
<path d="M136.6 54.8h.5M136.9 59.1l-.3 .6h.6M137 59.5v.5M161.2 43.9l.2-.3v.9M161.2 44.5h.5M161.6 42.2l.2-.3v.9M161.6 42.8h.5M162.5 44.1l-.2 .1-.3-.1 .2-.5 .3 .2v.4l-.2 .3h-.2M167.7 47.7a.52 .52 0 0 1 .8 .1 .45 .45 0 0 1-.4 .3 .45 .45 0 0 1-.4-.4zM167.7 57.1l.7-.1 .1 .2a.43 .43 0 0 1-.4 .3 .43 .43 0 0 1-.4-.4zM168.5 48.6h-.8l.2 .3M168.5 57.9v.5l-.5-.5-.3 .1 .1 .3"/>
<path d="M168.5 48.4v.5M113 61.2l.2-.3v.9M113 62.9l.2-.3v.9M113 64.6l.2-.3v.9M113 66.3l.2-.2v.8M113 69.7l.2-.2v.9M113 61.8h.5M113 63.5h.5M113 65.2h.5M113 66.9h.5M113 70.4h.5M113.4 71.5l.3-.3v.9"/>
<path d="M113.4 72.1h.4M113.7 60.9h.6l-.3 .4h.3v.4h-.6M113.7 64.3h.6l-.4 .9M113.7 69.7l.3-.2v.9M113.7 70.4h.6M113.9 66.4l-.2-.2 .1-.1h.4l.1 .2-.6 .3 .2 .3 .4-.1v-.3l-.2-.1M114 62.6l-.3 .6h.6M114.2 62.9v.6M119.4 75.2l.7-.1 .2 .1v.3l-.7 .1-.2-.1zM120.3 76.2h-.9l.3 .2M120.3 75.9v.5M126.8 61.2l.2-.3v.9"/>
<path d="M126.8 62.9l.2-.3v.9M126.8 64.6l.2-.3v.9M126.8 66.3l.2-.2v.8M126.8 61.8h.4M126.8 63.5h.4M126.8 65.2h.4M126.8 66.9h.4M127.5 61h.6v.3l-.6 .5h.6M128 64.3l-.3 .1-.2 .7 .2 .1 .4-.1v-.4l-.4-.1-.2 .2M128.1 62.6h-.5l-.1 .4 .5-.1 .1 .5h-.6M128.1 66.4l-.1 .2h-.4v-.5l.5 .1-.1 .6-.4 .1M131 61.2l.3-.3v.9"/>
<path d="M131 62.9l.3-.3v.9M131 64.6l.3-.3v.9M131 61.8h.5M131 63.5h.5M131 65.2h.5M131.9 61l.4-.1 .1 .2-.5 .7h.5M131.9 62.9l.2-.3v.9M131.9 63.5h.5M131.9 64.4l.2-.1a.54 .54 0 0 1 0 .9l-.2-.3zM131.9 66.4v.2h-.4v-.5l.4 .1v.6l-.4 .1M136.6 64.3h.6l-.4 .9M136.8 66.4l-.2-.2 .1-.1 .4 .1-.1 .2-.4 .2 .2 .3 .3-.1v-.3l-.2-.1"/>
<path d="M137 62.6h-.2l-.2 .7 .1 .2 .4-.1-.1-.5h-.3l-.1 .2M137.1 60.9h-.4l-.1 .4h.4l.1 .4h-.5M161.2 77.5l.2-.2v.8M161.2 78.1h.5M161.6 60.1h.5v.3l-.5 .5h.5M161.6 61.8h.5l-.3 .3 .3 .1v.3h-.5M161.6 68.6h.6l-.4 .9M161.6 75.8l.2-.2v.8M161.6 76.4h.5M161.8 70.7l-.2-.1 .1-.2h.3l.1 .3h-.4l-.1 .2 .2 .3h.3v-.4l-.2-.1M161.8 63.5l-.2 .5h.6M162 66.9h-.2l-.2 .7 .1 .2 .4-.1-.1-.4h-.3l-.1 .1"/>
<path d="M162 63.8v.5M162.1 65.2h-.4l-.1 .4h.5v.4h-.5M162.1 72.4l-.1 .2h-.3v-.5l.4 .1v.6l-.4 .1M162.5 77.6l-.1 .2h-.3v-.5h.3l.1 .1-.1 .6-.3 .1M175 60.2l.2-.2v.9M175 62l.2-.2v.8M175 63.7l.2-.2v.8M175 65.4l.2-.2v.9M175 67.2l.2-.3v.9M175 68.9l.2-.3v.9M175 70.6l.2-.2v.8M175 72.3l.2-.2v.8"/>
<path d="M175 72.9h.5M175 71.2h.5M175 69.5h.5M175 67.8h.5M175 66.1h.5M175 64.3h.5M175 62.6h.5M175 60.9h.5M175.7 61.8h.6l-.3 .8M175.7 68.6h.6l-.3 .4 .3 .1-.1 .4-.5-.1M175.8 70.5l.4-.1 .1 .2-.6 .6h.6M175.8 72.3l.3-.2v.8"/>
<path d="M175.8 72.9h.5M176 60.4l-.2-.1v-.2l.3-.1 .2 .2-.5 .3v.3l.2 .1 .3-.2-.2-.3M176 66.8l-.2 .7h.5M176.2 63.5l-.4 .2v.5l.4 .1 .1-.3-.2-.2-.3 .2M176.2 65.2h-.4v.4l.3-.1 .2 .4-.2 .2-.3-.1M176.2 67.2v.6M182.3 75.1v.5l-.7-.5-.2 .1 .1 .4M183.2 75.6v-.5l.3 .3v-.3h.4l.1 .1-.1 .4M185.2 75.1h.5M185.5 75.1v.5l-.6-.2M186.6 75.1v.5h.4l-.1-.4 .4-.1 .2 .1-.1 .4M188.3 75.1l.2 .5h.6l.1-.5h-.5v.4l.1 .1"/>
<path d="M190.9 75.4l-.9-.3v.5M192.1 75.2l.2-.1 .4 .1-.1 .4h-.4l-.2-.5h-.2v.5h.3v-.2M193.8 75.1h.2v.4l-.4 .1-.1-.5h.2l.6 .1v.3M201.2 72.3l.3-.2v.8M201.2 70.5h.5v.2l-.5 .5h.5M201.2 68.6h.5l-.2 .4h.2v.4h-.5M201.2 61.8h.6l-.4 .8M201.2 72.9h.5M201.4 60.4l-.2-.2 .2-.2 .3 .1v.2l-.4 .1-.1 .2 .2 .3 .3-.1v-.3l-.2-.1M201.5 66.8l-.3 .7h.6M201.6 63.5h-.2l-.2 .6 .1 .2 .4-.1v-.3l-.2-.1-.3 .2M201.6 67.2v.6"/>
<path d="M201.7 65.2h-.4l-.1 .4h.5v.4h-.5M207.7 72.3l.3-.2v.8M207.7 70.6l.3-.2v.8M207.7 68.9l.3-.3v.9M207.7 67.2l.3-.3v.9M207.7 65.4l.3-.2v.9M207.7 63.7l.3-.2v.8M207.7 62l.3-.2v.8M207.7 72.9h.5M207.7 71.2h.5M207.7 69.5h.5M207.7 67.8h.5"/>
<path d="M207.7 66.1h.5M207.7 64.3h.5M207.7 62.6h.5M208.5 66.9h.5l-.3 .4h.3v.4h-.5M208.5 65.3h.5v.3l-.5 .5h.5M208.5 63.7l.2-.2v.8M208.5 64.3h.5M208.6 61.8h.3l.1 .1-.1 .6a.39 .39 0 0 1-.4-.2 .39 .39 0 0 1 .1-.5zM208.6 60.4l-.1 .2-.4-.1v-.4h.5v.6l-.4 .2M208.7 68.6l-.2 .6h.6M208.9 72.1h-.2l-.2 .7 .1 .1h.4l-.1-.5h-.3l-.1 .2M208.9 69v.5"/>
<path d="M209 70.4h-.4l-.1 .3h.5v.5h-.5M167.7 81.2l.7-.1 .1 .2a.43 .43 0 0 1-.4 .4 .43 .43 0 0 1-.4-.5zM168.5 82.2h-.8l.2 .2M168.5 81.9v.5M182.3 80.9h-.9l.2 .2M182.3 80.6v.5"/>
</g>
<g fill="none" stroke="#006665" stroke-width=".21">
<path d="M111.8 25.4l.4 .1v.5l-.2 .2h-.2zM111.8 27l.4 .3v.4l-.1 .2h-.3zM111.8 28.7l.4 .3v.4l-.2 .3h-.2zM111.8 30.5l.4 .2v.5l-.1 .2h-.3zM111.8 32.2l.4 .3v.4l-.1 .2h-.3zM111.8 34l.4 .2v.4l-.2 .2h-.2zM111.8 35.7l.4 .2v.5l-.1 .1h-.3zM111.8 37.4l.4 .2v.5l-.1 .1h-.3zM112.6 25.4v.8M112.6 27v.9M112.6 28.7v1M112.6 30.5v.9"/>
<path d="M112.6 32.2v.9M112.6 34v.8M112.6 35.7v.8M112.6 37.4v.8M113.5 25.4h-.3a.42 .42 0 0 0-.2 .5 .42 .42 0 0 0 .5 .2v-.2h-.2M113.5 27.1l-.1-.1a.47 .47 0 0 0-.4 .4 .47 .47 0 0 0 .2 .5h.3v-.3h-.2M113.5 28.8l-.1-.1a.43 .43 0 0 0-.4 .5 .43 .43 0 0 0 .5 .4v-.4h-.2M113.5 30.5l-.4 .1-.1 .4 .2 .4h.3v-.4h-.2M113.5 32.3l-.1-.1a.48 .48 0 0 0-.4 .4 .48 .48 0 0 0 .2 .5h.3v-.4h-.2M113.5 34h-.3a.43 .43 0 0 0-.2 .5 .43 .43 0 0 0 .5 .3v-.4h-.2M113.5 35.7l-.4 .1-.1 .4 .2 .3h.3v-.3h-.2M113.5 37.5l-.1-.1a.48 .48 0 0 0-.4 .3 .48 .48 0 0 0 .2 .5h.3v-.3h-.2"/>
<path d="M113.8 25.6l.3-.2v.8M113.8 27.3l.3-.3v.9M113.8 29l.3-.3v1M113.8 30.8l.3-.3v.9M113.8 32.5l.3-.3v.9M113.8 34.2l.3-.2v.8M113.8 35.9l.3-.2v.8M113.8 37.6l.3-.2v.8M113.8 29.7h.5M113.8 26.2h.5M113.8 27.9h.5M113.8 31.4h.5"/>
<path d="M113.8 33.1h.5M113.8 34.8h.5M113.8 36.5h.5M113.8 38.2h.5M114.5 26.3h.7M114.5 28h.7M114.5 29.8h.7M114.5 31.5h.7M114.5 33.1h.7M114.5 34.9h.7M114.5 36.6h.7M114.5 38.3h.7"/>
<path d="M115.3 26.2l.2-.8 .3 .8M115.4 27.5l.4-.1-.1-.4h-.3v.9h.4l.1-.3-.2-.1M115.4 30.5l.4 .1 .1 .4-.2 .4h-.3zM115.4 25.9h.4M115.4 32.6h.3M115.4 34.3h.3M115.8 32.2h-.4v.9h.4M115.8 34h-.4v.8M115.8 35.7l-.4 .2v.5l.1 .1 .4-.1v-.2h-.2M115.9 28.8l-.3-.1-.2 .3v.4l.2 .3 .3-.1M115.9 37.5l-.3-.1-.2 .2v.5l.1 .1 .4-.1M116.1 38.2l.3-.8 .3 .8"/>
<path d="M116.2 38h.4M126.2 37.4a.49 .49 0 0 1 .4 .3 .49 .49 0 0 1-.1 .5h-.3zM127 27l.4 .2-.1 .7h-.3zM127 28.7l.4 .2v.6l-.3 .2h-.1zM127 30.5l.4 .1-.1 .8h-.3zM127 35.7l.4 .1-.1 .7h-.3zM127 25.4h.4a.47 .47 0 0 1 .1 .5 .47 .47 0 0 1-.5 .3zM127 32.2l.5 .3-.1 .6h-.4zM127 34h.4a.48 .48 0 0 1 .1 .5 .48 .48 0 0 1-.5 .3zM127 37.4v.8M127.8 27v.9M127.8 28.7v1"/>
<path d="M127.8 30.5v.9M127.8 35.7v.8M127.9 37.5a.43 .43 0 0 0-.5 .2 .43 .43 0 0 0 .1 .5l.5-.1v-.2h-.2M127.9 25.4v.8M127.9 32.2v.9M127.9 34v.8M128.3 37.5l.3-.1 .1 .4-.5 .4h.5M128.6 27.1a.43 .43 0 0 0-.4 .3 .43 .43 0 0 0 .1 .5l.4-.1v-.2h-.1M128.6 28.8a.41 .41 0 0 0-.5 .5 .41 .41 0 0 0 .6 .3v-.4h-.1M128.6 30.5h-.3l-.2 .4 .2 .5 .4-.1v-.3h-.1M128.6 35.7h-.3l-.2 .3 .2 .5 .4-.1v-.2h-.1M128.7 25.4l-.4 .1v.5l.3 .2 .2-.1v-.2h-.2"/>
<path d="M128.7 32.3a.43 .43 0 0 0-.4 .2 .43 .43 0 0 0 .1 .6h.3l-.1-.4M128.7 34l-.4 .2v.4l.3 .2h.2v-.4h-.2M128.9 38.3h.7M129 27.1h.5v.3l-.5 .5h.5M129 28.8h.5v.4l-.5 .5h.5M129 30.6h.5v.3l-.5 .5h.5M129 35.8h.5v.2l-.5 .5h.5M129.1 32.3h.5v.3l-.5 .5h.5M129.2 25.4h.4l.1 .2-.6 .6h.6M129.2 34h.4l.1 .2-.6 .6h.6M129.7 28h.6M129.7 29.8h.6"/>
<path d="M129.7 31.5h.6M129.7 36.6h.6M129.7 33.1h.7M129.8 26.3h.6M129.8 34.9h.6M130.3 37.5a.43 .43 0 0 0-.5 .2 .43 .43 0 0 0 .1 .5l.4-.1M130.5 26.2l.3-.8 .3 .8M130.5 27.5h.3l.2-.2-.2-.3h-.3v.9h.4l.1-.3-.2-.1M130.5 30.5h.3l.2 .2v.5l-.2 .2h-.3zM130.5 38.2l.3-.8 .3 .8M130.6 38h.4M130.6 25.9h.4"/>
<path d="M130.6 32.6h.3M130.7 34.3h.2M131 28.8l-.2-.1-.3 .3v.4l.3 .3 .2-.1M131 32.2h-.4v.9h.4M131 35.7h-.3l-.2 .2v.5l.2 .1h.3v-.3h-.2M131.1 34h-.4v.8M164.5 27.9l.3-.9 .3 .9M164.5 29.7l.3-1 .3 1M164.5 31.4l.3-.9 .3 .9M164.5 33.1l.3-.9 .3 .9M164.5 34.8l.3-.8 .3 .8M164.5 36.5l.3-.8 .3 .8"/>
<path d="M164.5 38.2l.3-.8 .3 .8M164.6 27.6h.4M164.6 29.4h.4M164.6 31.1h.4M164.6 32.8h.4M164.6 34.6h.4M164.6 36.3h.4M164.6 38h.4M164.6 39.7h.4M165.3 29l.3-.3v1M165.3 30.6h.5v.3l-.5 .5h.5M165.3 32.2h.5l-.2 .4h.2v.4h-.5"/>
<path d="M165.3 39.2h.6l-.4 .8M165.3 29.7h.5M165.4 27.1l.2-.1 .2 .2-.1 .6a.39 .39 0 0 1-.4-.2 .39 .39 0 0 1 .1-.5zM165.6 33.9l-.3 .6h.6M165.7 37.4l-.2 .1-.2 .6 .1 .1 .4-.1v-.3l-.2-.1-.3 .2M165.7 34.2v.6M165.8 35.7h-.4l-.1 .4 .4-.1 .1 .4h-.5M168.3 28.5l.8 .2-.8 .4M168.4 27.7a.42 .42 0 0 0 .2 .5 .42 .42 0 0 0 .5-.1l-.1-.4M168.4 26.8a.44 .44 0 0 0 .1 .6 .44 .44 0 0 0 .6-.2l-.1-.4M171.6 27.5l.4-.1v-.3l-.4-.1v.9h.4l.1-.3-.3-.1M171.6 29.2h.3l.1-.4-.4-.1v1h.3l.2-.4-.3-.1"/>
<path d="M171.6 30.9h.4l-.1-.4h-.3v.9h.4l.1-.3-.3-.2M171.6 32.6h.3l.1-.3-.4-.1v.9h.4l.1-.3-.3-.2M171.6 34.3h.3l.1-.3h-.4v.8h.3l.2-.3-.3-.2M171.6 36.1l.4-.1-.1-.3h-.3v.8h.4l.1-.2-.3-.2M171.6 37.8h.3l.1-.3-.4-.1v.8h.4l.1-.2-.3-.2M171.6 39.5h.3l.1-.3h-.4v.8h.3l.2-.3-.3-.2M172.3 32.2h.6l-.3 .4 .3 .1-.1 .4-.5-.1M172.3 39.2h.6l-.3 .8M172.4 29l.3-.3v1M172.4 30.6l.4-.1 .1 .3-.6 .6h.6M172.4 29.7h.5M172.6 27a.43 .43 0 0 1 .3 .5 .43 .43 0 0 1-.4 .4l-.1-.7z"/>
<path d="M172.6 33.9l-.2 .6h.5M172.8 35.7h-.4v.4l.4-.1v.5l-.4-.1M172.8 37.4l-.4 .2v.5l.4 .1 .1-.3-.1-.2-.4 .2M172.8 34.2v.6M116 54.6h.4l.1 .2v.4l-.2 .3h-.3zM116 56.3h.4l.1 .2v.5l-.1 .2h-.4zM116 58h.3l.2 .3v.4l-.2 .3h-.3zM116 59.8h.4l.1 .2v.4l-.2 .3h-.3zM116.9 56.6l.2-.3v.9M116.9 58.1l.3-.1 .2 .2-.5 .8h.5M116.9 59.8h.5l-.4 .4h.3l.1 .3-.2 .2-.3-.1M116.9 57.2h.5"/>
<path d="M117 54.6a.39 .39 0 0 1 .4 .5 .39 .39 0 0 1-.4 .3l-.1-.4zM120 55.7l.9 .3-.9 .3M120.1 54.9l-.1 .3 .3 .2h.4l.2-.2v-.3M120.1 54.1l-.1 .2 .3 .3h.4l.2-.3v-.2M123.7 54.7h.5v.6l-.2 .2a.47 .47 0 0 1-.4-.3 .47 .47 0 0 1 .1-.5zM123.7 56.4h.5l-.1 .8-.4-.1zM123.7 59.9h.5v.6l-.2 .2a.47 .47 0 0 1-.4-.3 .47 .47 0 0 1 .1-.5zM123.7 55.2l.5 .4M123.7 57l.5 .3M123.7 58.7l.5 .3M123.8 58l.4 .2v.6l-.2 .2a.49 .49 0 0 1-.4-.4 .49 .49 0 0 1 .2-.6zM124.5 56.6l.3-.3v.9"/>
<path d="M124.5 58.1l.3-.1 .2 .2-.5 .8h.5M124.5 59.8h.5l-.2 .4h.1l.1 .3-.2 .2-.3-.1M124.5 57.2h.5M124.6 54.7l.1-.1a.38 .38 0 0 1 .3 .5 .38 .38 0 0 1-.4 .3zM164.5 40l.3-.8 .3 .8M164.5 43.4l.3-.9 .3 .9M164.6 43.2h.4M165.1 44.4l-.3-.1-.2 .2v.4l.3 .3 .2-.1M165.4 43.1h.7M165.5 44.7h.3M165.9 44.3h-.4v.9h.4M166.4 42.9l.7 .2-.7 .2"/>
<path d="M167.5 43h.3l.1-.4-.4-.1v.9h.4l.1-.3-.2-.1M168.3 44.1h.8l-.8 .5h.8M168.4 45l-.1 .2 .1 .2h.5l.2-.1-.1-.4h-.2v.2M168.4 43.3l.2-.2 .4 .1 .1 .4h-.8zM115.9 71.6h1.4M116 61.5l.5 .2v.5l-.1 .2h-.4zM116 63.2h.3l.2 .3v.4l-.2 .2h-.3zM116 65h.4l.1 .1v.5l-.2 .2h-.3zM116 66.7h.3l.2 .2v.4l-.1 .2h-.4zM116 72.7v-.9l.4 .6 .2-.6v.9M116.5 70.2l-.3-.1-.2 .2v.5l.3 .2 .2-.1M116.9 66.7h.5l-.4 .8"/>
<path d="M117 70.5h.3v.4h-.3M117 70.4v.8M117 61.5l-.1 .6h.5M117 72.2v.5M117.3 63.2h-.3l-.1 .4 .3-.1 .2 .5-.2 .1-.3-.1M117.3 65h-.3l-.1 .7 .1 .1 .4-.1-.1-.4h-.3l-.1 .2M117.3 72.2l-.3 .1M117.3 61.8v.6M120 71.9h.9l-.9 .5h.9M120 71.3l.3-.2h.4l.2 .2v.3h-.9zM120.1 72.9h-.1a.43 .43 0 0 0 .5 .5 .43 .43 0 0 0 .4-.5h-.4v.1M123.6 66.9l.4-.2 .2 .1v.6l-.5 .1z"/>
<path d="M123.7 61.6h.5l-.1 .8-.4-.1zM123.7 63.4l.1-.2 .4 .2v.6l-.2 .1a.47 .47 0 0 1-.4-.2 .47 .47 0 0 1 .1-.5zM123.7 65.1h.5v.6l-.2 .1-.4-.2zM123.7 60.4l.5 .3M123.7 62.2l.5 .2M123.7 63.9l.5 .3M123.7 65.6l.5 .3M123.7 67.3l.5 .3M124.5 66.7h.5l-.3 .8M124.8 61.5l-.3 .6h.5M124.9 63.2h-.3l-.1 .4 .3-.1 .2 .5-.2 .1-.3-.1M124.9 65h-.2l-.2 .7 .2 .1 .3-.1-.1-.4h-.3l-.1 .2"/>
<path d="M124.9 61.8v.6M164.5 61.5l.3-.8 .3 .8M164.5 63.2l.3-.8 .3 .8M164.5 65l.3-.9 .3 .9M164.5 66.7l.3-.9 .3 .9M164.5 68.4l.3-.9 .3 .9M164.5 70.1l.3-.8 .3 .8M164.5 71.8l.3-.8 .3 .8M164.5 73.5l.3-.8 .3 .8M164.5 77l.3-.8 .3 .8M164.6 71.6h.4M164.6 61.3h.4"/>
<path d="M164.6 62.9h.4M164.6 64.7h.4M164.6 66.4h.4M164.6 68.2h.4M164.6 69.9h.4M164.6 73.4h.4M164.6 76.7h.4M165.1 77.9l-.2-.1-.3 .3v.4l.2 .2h.3M165.3 62.6l.3-.2v.8M165.3 64.2h.5v.3l-.5 .5h.5M165.3 65.8h.5l-.2 .4h.2v.4h-.5M165.3 72.7h.6l-.4 .8"/>
<path d="M165.3 63.2h.5M165.4 76.7h.7M165.5 60.7h.2l.1 .1-.1 .6a.39 .39 0 0 1-.4-.2 .39 .39 0 0 1 .1-.5zM165.5 78.3h.3M165.6 67.5l-.3 .6h.6M165.7 71h-.2l-.2 .7 .1 .1h.4l-.1-.5h-.3l-.1 .2M165.7 67.9v.5M165.8 69.3h-.4l-.1 .3h.5v.5h-.5M165.9 77.8h-.4v.9h.4M166.4 76.4l.7 .3-.7 .2M167.5 76.6l.4-.1-.1-.3h-.3v.8h.4l.1-.3-.2-.1M168.3 62.1l.8 .3-.8 .2"/>
<path d="M168.3 77.7h.8l-.8 .4h.8M168.4 61.3a.44 .44 0 0 0 .1 .5 .44 .44 0 0 0 .6-.1l-.1-.4M168.4 60.4l-.1 .3 .1 .2 .7-.1-.1-.4M168.4 78.5l-.1 .3 .1 .2h.5l.2-.1v-.4h-.3v.2M168.4 76.7h.5l.2 .2v.4h-.8zM171.6 61.1l.4-.1-.1-.3h-.3v.8h.4l.1-.2-.3-.2M171.6 62.8h.3l.1-.4h-.4v.8h.4l.1-.3-.3-.1M171.6 64.5h.3l.1-.3-.4-.1v.9h.3l.2-.4-.3-.1M171.6 66.2h.4l-.1-.4h-.3v.9h.4l.1-.3-.3-.2M171.6 67.9h.3l.1-.3-.4-.1v.9h.4l.1-.3-.3-.2M171.6 69.6h.3l.1-.2-.4-.1v.8h.3l.2-.3-.3-.2M171.6 71.4l.4-.1-.1-.3h-.3v.8h.4l.1-.2-.3-.2"/>
<path d="M171.6 73.1h.3l.1-.3-.4-.1v.8h.4l.1-.2-.3-.2M172.3 65.8h.6l-.3 .4h.2v.5l-.5-.1M172.3 72.7h.6l-.3 .8M172.4 62.6l.3-.2v.8M172.4 64.2l.4-.1 .1 .2-.6 .7h.6M172.4 63.2h.5M172.5 60.7a.42 .42 0 0 1 .4 .4 .42 .42 0 0 1-.4 .4zM172.6 67.5l-.2 .6h.5M172.8 69.3h-.4v.3h.4l.1 .4-.1 .1h-.4M172.8 71l-.4 .2v.6h.4v-.5h-.3l-.1 .2M172.8 67.9v.5"/>
</g>
<g fill="none" stroke="#0f0f0f" stroke-width=".21">
<path d="M154.4 44.2h4.7M155 44.5l-.4-.1-.1 .3 .1 .6 .4-.1M155.8 44.4h-.4l-.1 .2 .2 .2 .3 .1v.3l-.5 .1M156.2 44.4v.9l.5-.1v-.8M157.6 44.4l-.5 .1v.2l.5 .3-.1 .3h-.4M157.9 44.8h.3M158.4 44.4h-.5v.9h.5M158.7 44.4v.9h.4M107.2 69.1h4.5M107.3 69.4a.47 .47 0 0 1 .5 .3 .47 .47 0 0 1-.1 .5h-.4zM108.2 69.4l.5 .2v.5l-.2 .1h-.3zM109 69.4v.8h.4"/>
<path d="M110.2 69.5l-.3-.1-.2 .2 .2 .2 .3 .1v.2l-.5 .1M110.5 69.8h.4M111 69.4h-.5v.8h.5M111.4 69.4v.8h.3M154.6 77.8h4.5M155.2 78.1l-.3-.1-.2 .2v.5l.3 .2 .2-.1M156.1 78l-.5 .1v.3l.5 .2-.2 .3-.3-.1M156.4 78v.9h.4M157.6 78l-.5 .1v.3l.5 .2-.2 .3-.3-.1M157.9 78.4h.3M158.4 78h-.5v.9h.5M158.7 78v.9h.4"/>
</g>
<path d="M182.4 46l.3 .2-.1 .2-.4-.2z" fill="#910000"/>
<path d="M182.4 46.1l.3 .2-.1 .2-.3-.2zM182.5 45.8v.5h1.8v-.5M182.5 42.2v.8M183.7 43h1v2.7h-1z" fill="none" stroke="#910000" stroke-width=".21"/>
<path d="M184.1 46l.3 .2-.1 .2-.3-.2z" fill="#910000"/>
<path d="M184.2 46.1l.3 .2-.1 .2-.3-.2zM184.3 45.8v.5h1.7v-.5M184.3 42.2v.8M185.4 43h1v2.7h-1z" fill="none" stroke="#910000" stroke-width=".21"/>
<path d="M185.8 46l.3 .2-.1 .2-.3-.2z" fill="#910000"/>
<path d="M185.9 46.1l.3 .2-.1 .2-.3-.2zM186 45.8v.5h1.7v-.5M186 42.2v.8M187.1 43h1v2.7h-1z" fill="none" stroke="#910000" stroke-width=".21"/>
<path d="M187.5 46l.3 .2-.1 .2-.3-.2z" fill="#910000"/>
<path d="M187.6 46.1l.3 .2-.1 .2-.4-.2zM187.7 45.8v.5h1.7v-.5M187.7 42.2v.8M188.9 43h1v2.7h-1z" fill="none" stroke="#910000" stroke-width=".21"/>
<path d="M189.3 46l.3 .2-.1 .2-.3-.2z" fill="#910000"/>
<path d="M189.3 46.1l.4 .2-.2 .2-.3-.2zM189.4 45.8v.5h1.7v-.5M189.4 42.2v.8M190.6 43h1v2.7h-1z" fill="none" stroke="#910000" stroke-width=".21"/>
<path d="M191 46l.3 .2-.1 .2-.3-.2z" fill="#910000"/>
<path d="M191 46.1l.3 .2-.1 .2-.3-.2zM191.1 45.8v.5h1.7v-.5M191.1 42.2v.8M192.3 43h1.1v2.7h-1.1z" fill="none" stroke="#910000" stroke-width=".21"/>
<path d="M192.7 46l.3 .2-.1 .2-.3-.2z" fill="#910000"/>
<g fill="none" stroke="#910000" stroke-width=".21">
<path d="M156.8 33.6h3.3v1.7h-3.3l-.8-.9zM156.8 35.3h3.3v1.7h-3.3l-.8-.9zM156.8 31.9h3.3v1.7h-3.3l-.8-.9zM156.8 30.1h3.3v1.8h-3.3l-.8-1zM156.8 37h3.3v1.7h-3.3l-.8-.8zM156.8 38.7h3.3v1.7h-3.3l-.8-.8zM157.4 34a.48 .48 0 0 1 .5 .3 .48 .48 0 0 1-.1 .5h-.4zM157.4 35.8h.4a.48 .48 0 0 1 .1 .5 .48 .48 0 0 1-.5 .3zM157.4 32.3l.5 .1v.4l-.1 .3h-.4zM157.4 30.6h.4a.48 .48 0 0 1 .1 .6 .48 .48 0 0 1-.5 .3zM157.4 37.5h.5v.5l-.1 .3h-.4zM157.4 39.2a.48 .48 0 0 1 .5 .3 .48 .48 0 0 1-.1 .5h-.4z"/>
<path d="M157.5 28.4h2.6v1.7h-2.6l-.7-.9zM157.5 26.6h2.6v1.8h-2.6l-.7-.8zM158.3 34.2l.2-.2v.8M158.3 35.9l.2-.1v.8M158.3 28.8a.49 .49 0 0 1 .4 .3 .49 .49 0 0 1-.1 .6h-.3zM158.3 27.1l.4 .1 .1 .4-.2 .4h-.3zM158.3 32.6l.2-.3v.8M158.3 30.8l.2-.2v.9M158.3 37.7l.2-.2v.8M158.3 39.4l.2-.2v.8M158.3 34.8h.5M158.3 36.6h.5"/>
<path d="M158.3 33.1h.5M158.3 31.5h.5M158.3 38.3h.5M159 34.1h.6v.3l-.6 .4h.6M159 35.8h.6l-.3 .2 .3 .1v.4h-.6M159 32.6l.3-.3v.8M159 33.1h.6M159.1 30.7h.5v.6l-.2 .2-.3-.1zM159.2 27.5l-.2-.2 .1-.2h.4l.1 .3-.6 .2 .1 .4 .5-.1v-.3l-.2-.1M159.3 37.4l-.3 .7h.6M159.5 37.7v.6M159.6 29.2l-.2 .2-.4-.2 .2-.4 .4 .1v.6l-.5 .2"/>
<path d="M159.6 39.2h-.5l-.1 .4h.6v.3h-.6M30.3 43h3.4l.7 .9-.7 .8h-3.4zM30.3 44.7h3.4l.7 .9-.7 .8h-3.4zM30.3 46.4h3.4l.7 1-.7 .8h-3.4zM30.4 51.6h3.3l.7 .9-.7 .9h-3.3zM30.4 49.9h3.3l.7 .9-.7 .9h-3.3zM30.4 48.2h3.3l.7 .9-.7 .8h-3.3zM30.4 55.1h3.3l.7 .8-.7 1h-3.3zM30.4 53.4h3.3l.7 .8-.7 .9h-3.3zM30.4 58.5h3.3l.7 .9-.7 .8h-3.3zM30.4 56.9h3.3l.7 .8-.7 .8h-3.3zM31.1 52.1l.4 .9 .2-.9"/>
<path d="M31.1 50.4l.4 .9 .2-.9M31.1 48.6l.4 .9 .2-.9M31.1 55.6l.4 .8 .2-.8M31.1 53.8l.4 .8 .2-.8M31.1 59l.4 .8 .2-.8M31.1 57.3l.4 .8 .2-.8M31.1 43.9h.4M31.1 45.6h.4M31.1 47.4h.4M31.5 43.5h-.4v.8M31.5 45.2h-.4v.9M31.5 46.9h-.4v.9"/>
<path d="M31.9 53l.2-.9 .4 .9M31.9 51.3l.2-.9 .4 .9M31.9 49.5l.2-.9 .4 .9M31.9 56.4l.2-.8 .4 .8M31.9 54.6l.2-.8 .4 .8M31.9 59.8l.2-.8 .4 .8M31.9 58.1l.2-.8 .4 .8M32 59.6h.4M32 52.7h.4M32 51h.4M32 49.2h.4M32 56.2h.4"/>
<path d="M32 54.4h.4M32 57.9h.4M32.4 43.6a.44 .44 0 0 0-.6 .1 .44 .44 0 0 0 .2 .6l.4-.1M32.4 45.3a.42 .42 0 0 0-.6 .3 .42 .42 0 0 0 .6 .4M32.4 47l-.4-.1-.2 .4 .2 .5 .4-.1M32.6 52.1h.5l-.2 .3 .2 .1v.4h-.5M32.6 59h.6l-.3 .8M32.7 45.4l.3-.2v.9M32.7 47l.4-.1v.4l-.5 .5h.5M32.7 50.4h.4v.4l-.5 .5h.5M32.7 48.9l.3-.3v.9M32.7 46.1h.4"/>
<path d="M32.7 49.5h.4M32.9 43.5l.2 .1v.7h-.3l-.1-.1v-.6zM32.9 53.8l-.2 .6h.5M33.1 57.3l-.4 .1v.6h.4v-.4h-.3l-.1 .2M33.1 54.1v.5M33.1 55.6h-.4v.3h.4v.4h-.4M52.4 58.5h9.5l.8 .9-.8 .8h-9.5zM53.2 43h3.7v1.7h-3.7l-.8-.8zM53.5 59.1l-.2-.1-.3 .2v.4l.2 .2 .3-.1M53.7 43.9h.4l.1-.3-.1-.1h-.4v.8M53.8 59h.5M53.9 43.9l.3 .4"/>
<path d="M54.1 59v.8M54.6 59v.8h.4M55.2 43.5l-.7 1.1M55.3 43.2h.9M55.4 43.5l.2 .8 .1-.6 .2 .6 .3-.8M55.7 59.1h-.5v.2l.5 .3v.2h-.5M56.1 59.5h.3l.2-.4-.2-.1h-.3v.8M56.8 59.9h.6M57.6 59a.49 .49 0 0 1 .5 .3 .49 .49 0 0 1-.1 .5h-.4zM58.4 59h.5M58.6 59v.8M59.1 59.8l.2-.8 .3 .8"/>
<path d="M59.1 59.6h.4M60.4 59.1a.44 .44 0 0 0-.6 .1 .44 .44 0 0 0 .2 .6l.4-.1M60.7 59v.8M60.8 59.4l.5 .4M61.3 59l-.6 .5M67.3 59.4h3.4l.7 .8-.7 .9h-3.4zM67.3 57.7h3.4l.7 .8-.7 .9h-3.4zM68.1 54.2h2.6l.7 .9-.7 .8h-2.6zM68.1 55.9h2.6l.7 1-.7 .8h-2.6zM68.1 59.8a.47 .47 0 0 1 .5 .5 .47 .47 0 0 1-.5 .4zM68.1 58.1a.49 .49 0 0 1 .5 .3 .49 .49 0 0 1-.2 .6h-.3zM68.9 54.6h.2l.3 .3v.4l-.3 .3h-.2z"/>
<path d="M68.9 56.4h.3l.2 .2v.4l-.3 .3h-.2zM68.9 58.4l.2-.3v.9M68.9 59h.5M69.9 55.1l-.2-.3 .4-.2 .1 .3-.5 .3 .2 .4 .3-.2-.1-.3M69.9 58.1a.43 .43 0 0 1 .3 .4 .43 .43 0 0 1-.3 .5 .6 .6 0 0 1 0-.9zM70.2 56.8l-.1 .1h-.3v-.5h.3l.1 .2v.3l-.4 .4M108.6 55.9h2.5l.8 1-.8 .8h-2.5zM108.6 54.2h2.5l.8 .9-.8 .8h-2.5zM108.6 57.7h2.5l.8 .8-.8 .9h-2.5zM108.6 59.4h2.5l.8 .8-.8 .9h-2.5zM109.3 56.4h.4l.2 .2v.4l-.3 .3h-.3zM109.3 54.6h.3l.3 .3v.4l-.3 .3h-.3z"/>
<path d="M109.3 58.1h.3l.3 .3v.4l-.2 .2h-.4zM109.3 59.8h.3l.3 .3v.4l-.3 .2h-.3zM110.2 56.7l.2-.3v.9M110.2 58.2h.5v.3l-.5 .5h.5M110.2 59.8h.5l-.3 .4h.3v.5h-.5M110.2 57.3h.5M110.3 54.7l.2-.1 .2 .2v.6l-.2 .2a.53 .53 0 0 1-.2-.9zM158.3 40h.5M182.5 41.3v.9M182.5 46.4v1.8M184.3 41.3v.9M186 41.3v.9"/>
<path d="M187.7 41.3v.9M189.4 41.3v.9M191.1 41.3v.9M192.7 46.1l.3 .2-.1 .2-.3-.2zM192.8 45.8v.5h1.8v-.5M192.8 41.3v1.7M194.1 43h1v2.7h-1zM194.6 41.3v1.7M19.1 60.2h6.8l.7 .9-.7 .9h-6.8zM19.9 60.5h5.6M20.4 60.8h-.5v.6l.3 .2 .2-.1M20.8 61.2h.3l.2-.2-.1-.3h-.4v.9"/>
<path d="M21.6 60.7v.7l.2 .2 .3-.1v-.8M22.4 61.7h.6M23.2 60.7v.8l.2 .1 .3-.2v-.7M24.1 60.7h.3l.2 .2v.4l-.3 .3h-.2zM25.4 60.7h-.4l-.1 .2 .5 .3v.2l-.1 .2-.4-.1M27 62h6.7l.7 .9-.7 .8h-6.7zM27.8 62.2h5.4M28.4 62.5l-.4-.1-.2 .4 .2 .5 .4-.1M28.7 62.9h.5v-.5h-.5v.9M29.6 62.4l.1 .9 .4-.1v-.8M30.3 63.4h.6M31.2 62.4v.9h.4"/>
<path d="M31.9 62.4l.4 .1 .1 .4-.2 .4h-.3zM33.1 62.4l-.4 .1v.3l.4 .1v.4h-.4M65.8 71.4h4.9l.7 .9-.7 .9h-4.9zM66.6 71.7h3.7M66.7 72.3h.4l.1-.3-.5-.1v.9M66.9 72.3l.3 .5M67.3 62.9h3.4l.7 .8-.7 .9h-3.4zM67.3 66.2h3.4l.7 1-.7 .8h-3.4zM67.3 64.6h3.4l.7 .8-.7 .8h-3.4zM67.3 61.1h3.4l.7 .9-.7 .9h-3.4zM67.5 72.3h.4M67.9 71.9h-.4v.9h.4"/>
<path d="M68.1 63.3a.49 .49 0 0 1 .5 .3 .49 .49 0 0 1-.2 .5h-.3zM68.1 66.8h.3a.47 .47 0 0 1 .2 .5 .47 .47 0 0 1-.5 .3zM68.1 65a.47 .47 0 0 1 .5 .4 .47 .47 0 0 1-.5 .5zM68.1 61.6h.3a.47 .47 0 0 1 .2 .5 .47 .47 0 0 1-.5 .3zM68.8 71.9h-.4l-.1 .3 .5 .4-.1 .2h-.4M68.9 63.5l.2-.2v.8M68.9 67l.2-.2v.8M68.9 65.2l.2-.2v.9M68.9 61.8l.2-.2v.8M68.9 60.1l.2-.3v.9M68.9 64.1h.5M68.9 67.6h.5"/>
<path d="M68.9 65.9h.5M68.9 62.4h.5M68.9 60.7h.5M69.1 72.3h.4M69.6 71.9h-.5v.9h.5M69.7 63.3h.5l-.3 .3h.2v.5l-.4-.1M69.7 61.7l.4-.1 .1 .2-.5 .6h.5M69.7 60.1l.3-.3v.9M69.7 60.7h.5M69.8 71.9h.5M69.9 65l-.2 .6h.5M70.1 71.9v.9"/>
<path d="M70.1 66.8h-.3l-.1 .4 .4-.1 .1 .3-.1 .2-.4-.1M70.1 65.3v.6M106.4 71.4h4.7l.8 .9-.8 .9h-4.7zM107.1 71.7h3.7M107.1 72.3h.5l.1-.3-.6-.1v.9M107.4 72.3l.3 .5M108.1 72.3h.2M108.4 71.9h-.3v.9h.3M108.6 66.2h2.5l.8 1-.8 .8h-2.5zM108.6 62.9h2.5l.8 .8-.8 .9h-2.5zM108.6 64.6h2.5l.8 .8-.8 .8h-2.5zM108.6 61.1h2.5l.8 .9-.8 .9h-2.5z"/>
<path d="M109.3 71.9h-.5v.2l.1 .2 .4 .1v.3l-.5 .1M109.3 66.8h.4l.2 .1v.5l-.3 .2h-.3zM109.3 63.3h.3l.3 .2v.5l-.2 .1h-.4zM109.3 65h.3l.3 .2v.5l-.3 .2h-.3zM109.3 61.6h.4l.2 .2v.5l-.3 .1h-.3zM109.6 72.3h.3M110 71.9h-.4v.9h.4M110.2 66.8h.5l-.3 .8M110.3 71.9h.5M110.4 61.5l-.2 .7h.5M110.5 71.9v.9M110.6 65l-.2 .1-.2 .6 .2 .2 .3-.1v-.4l-.3-.1-.2 .2"/>
<path d="M110.6 61.8v.6M110.7 63.3h-.4l-.1 .4 .4-.1 .1 .4h-.5M157.5 65.4h2.6v1.8h-2.6l-.7-1zM157.5 68.9h2.6v1.7h-2.6l-.7-.9zM157.5 67.2h2.6v1.7h-2.6l-.7-.9zM157.5 60.2h2.6v1.8h-2.6l-.7-.9zM157.5 63.7h2.6v1.7h-2.6l-.7-.8zM157.5 62h2.6v1.7h-2.6l-.7-.8zM157.5 72.3h2.6v1.7h-2.6l-.7-.8zM157.5 70.6h2.6v1.7h-2.6l-.7-.9zM158.3 65.9h.3a.48 .48 0 0 1 .2 .6 .48 .48 0 0 1-.5 .3zM158.3 69.3a.49 .49 0 0 1 .4 .3 .49 .49 0 0 1-.1 .5h-.3z"/>
<path d="M158.3 67.6l.4 .1 .1 .4-.2 .3h-.3zM158.3 60.7h.3a.48 .48 0 0 1 .2 .6 .48 .48 0 0 1-.5 .3zM158.3 64.1a.49 .49 0 0 1 .4 .3 .49 .49 0 0 1-.1 .6h-.3zM158.3 62.4l.4 .1 .1 .4-.2 .4h-.3zM158.3 72.8a.47 .47 0 0 1 .5 .3 .47 .47 0 0 1-.2 .5h-.3zM158.3 71.1h.3a.48 .48 0 0 1 .2 .5 .48 .48 0 0 1-.5 .3zM159 65.9h.6l-.3 .3h.3v.5h-.6M159 64.2h.6v.4l-.6 .4h.6M159 62.7l.3-.3v.9M159 72.8h.6l-.4 .8M159 63.3h.6M159.1 60.8l.4-.1 .1 .2v.5l-.2 .2a.48 .48 0 0 1-.3-.8z"/>
<path d="M159.3 67.5l-.3 .7h.6M159.5 71.1h-.3l-.2 .7 .2 .1 .4-.1-.1-.4-.5 .1M159.5 67.9v.5M159.6 69.3h-.5l-.1 .4h.6v.4h-.6M25 99.9h3.5l.7 .8-.7 .9h-3.5zM25 98.2h3.5l.7 .8-.7 .9h-3.5zM25 96.4h3.5l.7 .9-.7 .9h-3.5zM25 91.2h3.5l.7 1-.7 .8h-3.5zM25 93h3.5l.7 .8-.7 .9h-3.5zM25 94.7h3.5l.7 .8-.7 .9h-3.5zM25.9 98.6h.2l.3 .2v.5l-.2 .1h-.3zM25.9 96.9h.3l.2 .2v.5l-.2 .1h-.3z"/>
<path d="M25.9 91.7h.3l.2 .2v.5l-.2 .2h-.3zM25.9 93.4h.2l.3 .3v.4l-.2 .2h-.3zM25.9 95.2h.3l.2 .2v.4l-.3 .3h-.2zM25.9 89.5h2.6l.7 .9-.7 .8h-2.6zM25.9 87.8h2.6l.7 .9-.7 .8h-2.6zM26.7 98.8l.3-.2v.8M26.7 97.2l.3-.3v.8M26.7 92l.3-.3v.9M26.7 93.7l.3-.3v.9M26.7 95.4l.3-.2v.9M26.7 90a.47 .47 0 0 1 .5 .4 .47 .47 0 0 1-.5 .5zM26.7 88.3a.49 .49 0 0 1 .5 .3 .49 .49 0 0 1-.2 .5h-.3z"/>
<path d="M26.7 99.4h.5M26.7 97.7h.5M26.7 92.6h.5M26.7 94.3h.5M26.7 96.1h.5M27.5 96.9h.5l-.3 .3 .3 .1v.4h-.5M27.6 93.7l.2-.3v.9M27.6 95.2h.4v.3l-.5 .6h.5M27.6 94.3h.4M27.6 91.7h.3l.1 .2-.1 .7h-.3v-.2zM27.7 98.6l-.1 .6h.5M27.7 88.6h-.1v-.3h.4v.3l-.4 .1v.4l.4-.1v-.3l-.2-.1"/>
<path d="M27.9 98.9v.5M28 90.4l-.2 .1h-.2v-.5h.4v.6l-.4 .3M55.9 87.8h6.1l.8 .9-.8 .8h-6.1zM55.9 89.5h5.3l.6 .9-.6 .8h-5.3zM56.5 89.1v-.8l.3 .6 .3-.6v.8M56.5 90v.9M57.4 90v.9l-.5-.9v.9M57.5 89.1v-.8l.3 .6 .2-.6v.8M57.7 90h.5M58 90v.9M58.3 91h.7M58.5 88.3v.8l.5-.1v-.7"/>
<path d="M59.1 89.2h.7M59.1 90.4h.3M59.6 90h-.5v.9h.5M60.1 88.7h.2M60.4 88.3h-.3v.8h.3M60.4 90v.9l-.5-.9v.9M61.3 88.3v.8l-.5-.8v.8M23.7 105h4.8l.7 .9-.7 .9h-4.8zM24.3 105.3h3.8M24.5 106h.3l.2-.2-.1-.3h-.4v.9M24.7 106l.3 .4M25.4 105.9h.2"/>
<path d="M25.8 105.5h-.4v.9h.4M25.9 100.4h.3l.2 .1v.5l-.3 .2h-.2zM26.5 105.5l-.4 .1 .1 .3 .3 .1v.3h-.4M26.7 100.5l.3-.1v.8M26.7 101.2h.5M27 105.9h.2M27.4 105.5h-.4v.9h.4M27.6 105.5h.5M27.8 105.5v.9M28 100.4h-.4v.3h.4v.4h-.4M25.8 134.3h3.4v1.7h-3.4l-.8-.8zM25.8 129.2h3.4v1.6h-3.4l-.8-.8z"/>
<path d="M25.8 127.5h3.4v1.7h-3.4l-.8-.9zM25.8 130.8h3.4v1.8h-3.4l-.8-.8zM25.8 132.6h3.4v1.7h-3.4l-.8-.8zM25.8 136h3.4v1.8h-3.4l-.8-.9zM26.5 134.7a.47 .47 0 0 1 .5 .5 .47 .47 0 0 1-.5 .5zM26.5 129.6a.47 .47 0 0 1 .5 .4 .47 .47 0 0 1-.5 .5zM26.5 127.9a.47 .47 0 0 1 .5 .3 .47 .47 0 0 1-.1 .5h-.4zM26.5 131.4h.4a.47 .47 0 0 1 .1 .5 .47 .47 0 0 1-.5 .3zM26.5 133.1a.49 .49 0 0 1 .5 .3 .49 .49 0 0 1-.1 .5h-.4zM26.5 136.5h.4a.47 .47 0 0 1 .1 .6 .47 .47 0 0 1-.5 .3zM26.6 125.7h2.6v1.8h-2.6l-.7-.9zM26.6 124h2.6v1.7h-2.6l-.7-.9z"/>
<path d="M27.4 135l.2-.3v1M27.4 129.8l.2-.2v.9M27.4 128.1l.2-.2v.8M27.4 126.2l.4 .2v.4l-.2 .2h-.2zM27.4 124.4l.4 .3v.4l-.2 .2h-.2zM27.4 131.6l.2-.2v.8M27.4 133.3l.2-.2v.8M27.4 136.8l.2-.3v.9M27.4 135.7h.4M27.4 130.5h.4M27.4 128.7h.4M27.4 132.2h.4"/>
<path d="M27.4 133.9h.4M27.4 137.4h.4M28.1 129.8l.3-.2v.9M28.1 131.4h.6v.3l-.6 .5h.6M28.1 133.1h.6l-.3 .3 .3 .1v.3h-.6M28.1 130.5h.6M28.2 128l.3-.1 .2 .2-.1 .5a.39 .39 0 0 1-.5-.2 .39 .39 0 0 1 .1-.4zM28.3 124.8l-.2-.2 .2-.2 .4 .1v.3h-.5l-.1 .2 .2 .3h.4v-.4l-.2-.1M28.4 134.7l-.3 .6h.6M28.6 135.1v.6M28.7 126.5l-.1 .2h-.4v-.5l.5 .1-.1 .7h-.4M28.7 136.5h-.5l-.1 .4h.5l.1 .4h-.6"/>
</g>
<path d="M182.3 47.4h-.9l.2 .2M182.3 41.5v.5l-.5-.5h-.3v.4M182.3 47.1v.5M183.2 42v-.5l.3 .3 .1-.3h.3v.5M185.2 41.6h.5M185.5 41.4v.5l-.6-.1M186.6 41.5v.4h.4v-.4h.4v.4M188.3 41.6l.2 .3h.6v-.4l-.4 .1v.3h.1M190.9 41.8l-.9-.4v.6M192.1 41.7l.1-.2h.4l.1 .2-.1 .2h-.4l-.1-.4h-.3v.4h.3v-.1M193.8 41.5l.2 .1v.3h-.4v-.4h.6l.1 .4" fill="none" stroke="#b90000" stroke-width=".21"/>
<g fill="none" stroke="#090" stroke-width=".21">
<path d="M109.3 36.1h-5.1v29.3h-7M109.3 34.4h-6.1v29.3h-6M109.3 29.2h-8.6v29.3h-3.5M109.3 32.7h-6.9v29.3h-5.2M109.3 25.8h-10.3v29.3h-1.8M109.3 27.6h-9.4v29.3h-2.7M109.3 30.9h-7.7v29.3h-4.4M109.3 37.9v5.1M133.5 36.1h11.1v29.3h-6.9M133.5 34.4h10.3v29.3h-6.1M133.5 29.2h7.7v29.3h-3.5M133.5 25.8h6v29.3h-1.8"/>
<path d="M133.5 27.6h6.8v29.3h-2.6M133.5 30.9h8.5v29.3h-4.3M133.5 32.7h9.4v29.3h-5.2M133.5 37.9v4.3h-24.2M177.3 29.2h22.5M177.3 36.1h22.5M177.3 37.9h22.5M177.3 39.6h22.5M177.3 27.6h22.5M177.3 32.7h22.5M177.3 30.9h22.5M177.3 34.4h22.5"/>
<path d="M182.5 27.6v13.7M184.3 29.2v12.1M186 30.9v10.4M187.7 32.7v8.6M189.4 34.4v6.9M191.1 36.1v5.2M192.8 37.9v3.4M194.6 39.6v1.7M210.1 24.9v48.3M51.6 43.9h.8M51.6 52.5h.8M51.6 50.8h.8"/>
<path d="M51.6 49.1h.8M51.6 47.4h.8M51.6 54.2h.8M51.6 59.4h.8M51.6 57.7h.8M51.6 55.9h.8M88.7 58.5h1.7M88.7 55.1h1.7M88.7 56.9h1.7M129.2 58.5h1.6M129.2 55.1h1.6M129.2 56.9h1.6"/>
<path d="M160.1 44.7v.9h-.8M182.5 48.2v1.7h-13.7M26.6 61.1h7.8M88.7 67.2h1.7M88.7 65.4h1.7M88.7 63.7h1.7M88.7 60.2h1.7M88.7 62h1.7M129.2 67.2h1.6M129.2 65.4h1.6M129.2 63.7h1.6M129.2 60.2h1.6"/>
<path d="M129.2 62h1.6M160.1 78.4v.8h-.8M177.3 61.1h22.5M177.3 66.2h22.5M177.3 69.7h22.5M177.3 62.9h22.5M177.3 68h22.5M177.3 73.2h22.5M177.3 64.6h22.5M177.3 71.4h22.5M182.5 61.1v13.8M184.3 62.9v12"/>
<path d="M186 64.6v10.3M187.7 66.2v8.7M189.4 68v6.9M191.1 69.7v5.2M192.8 71.4v3.5M194.6 73.2v1.7M46.4 97.3h5.2v36.2h-5.2M46.4 95.5h4.4v36.3h-4.4M46.4 99h6v36.2h-6M46.4 93.8h3.5v36.2h-3.5M46.4 92.2h2.7v36.1h-2.7M46.4 90.4h9.5"/>
<path d="M46.4 88.7h9.5M47.3 88.7v36.1h-.9M48.1 90.4v36.2h-1.7M182.5 81.8v1.7h-13.7M46.4 100.7h6.9v36.2h-6.9M22.3 140.3h6.9M29.2 142.1v.9h-.9M37.8 178.3h59.4M37.8 168.8h50.9M37.8 165.3h50.9M37.8 181.7h59.4"/>
</g>
<g fill="none" stroke="#0000ca" stroke-width=".21">
<path d="M21 19.9h-.2v1.2h.2M21.2 18.7l-.2-.1-.3 .2v.5l.2 .1 .3-.1M21.5 18.9h.5l-.1 .5-.4-.1zM22.1 19.9h.4M22.2 19.9v1M22.3 18.9l.3-.1 .1 .2v.4M22.3 18.8v.6M22.8 19.9v1h.4M23 18.8h.3M23.2 18.6v.8h.1M23.6 18.8v.6M23.8 18.8l-.2 .2"/>
<path d="M24.1 19l.2-.2 .3 .2-.1 .4h-.3zM24.9 18.6l.1 .8M25.2 19.9a.47 .47 0 0 1 .5 .5 .47 .47 0 0 1-.5 .5zM26.3 18.9l-.2-.1-.1 .3 .4 .2-.4 .1M26.5 19.9h-.5v1h.5M26.7 18.9h.4v.4l-.4 .1M26.7 18.8v1M27.5 18.9l.2-.1 .2 .2v.4h-.4l.1-.3h.3M27.6 19.9h.2v1.2h-.2M28.7 18.9l-.3-.1-.2 .2 .1 .4h.4M29 19.2l.4-.1-.2-.3-.2 .1v.5h.3M30.7 18.5l-.3 .3v.6l.3 .4"/>
<path d="M31 19h.3M31.4 18.6h-.4v.8M32.2 18.7l-.2-.1-.3 .2v.5l.2 .1 .3-.1M32.6 19h.6M32.6 19.3h.6M33.7 19h.6M33.7 19.3h.6M34.9 18.6l-.2 .6h.6M35.1 18.8v.6M35.4 18.5l.3 .3v.6l-.3 .4M36.1 19.3v.1M36.1 18.9v.1"/>
<path d="M113.2 16.2l.5 .2v.5l-.2 .2h-.3zM114.1 16.2v.1M114.1 16.5v.6M114.5 16.5h.3v.6h-.3l-.1-.2 .2-.2h.2M115.6 16.5v.8h-.3M115.6 16.5h-.2l-.2 .1 .1 .5h.3M116 16.5h.4v.6M116 16.5v.6M116.8 16.5h.4l-.1 .6-.3-.1zM117.9 16.5h-.3v.3h.3v.3h-.3M118.1 16.5h.4M118.3 16.2v.9h.2"/>
<path d="M118.7 16.2v.1M118.7 16.5v.6M119.6 16.5h-.4v.5l.4 .1M120.6 16.2l.4 .1 .1 .4-.2 .4h-.3zM121.5 16.2v.1M121.5 16.5v.6M122.1 16.5h-.1l-.2 .1 .4 .4-.4 .1M122.6 16.5h.2l.2 .1-.1 .5h-.3M122.6 16.5v.9M123.3 16.2v.8l.2 .1M123.8 16.5h.3l.1 .1v.5h-.4l-.1-.2 .2-.2h.3M124.5 16.5l.2 .6"/>
<path d="M124.9 16.5l-.4 .9M125.9 16.6h.4l.1-.3-.5-.1v.9M126.1 16.6l.3 .5M126.7 16.8l.4-.1-.1-.2h-.3v.6h.3M127.9 16.5v.7l-.2 .2-.2-.1M127.9 16.5h-.4v.5l.4 .1M128.2 16.2v.1M128.2 16.5v.6M129 16.5h-.4l.1 .3h.3v.3h-.4M129.2 16.5h.4M129.3 16.2v.8l.3 .1M129.8 16.8l.5-.1-.2-.2h-.3v.6h.4"/>
<path d="M130.6 16.5v.6M130.8 16.5l-.2 .1M20.6 21.6l.4 .6M20.6 23.1l.4 .5M20.6 24.4l.4 .6M20.6 25.8l.4 .6M20.6 28.6l.4 .6M20.6 29.9l.4 .6M21 26.8h-.2v1.3h.2M21 21.6l-.4 .6M21 23.1l-.4 .5M21 24.4l-.4 .6"/>
<path d="M21 25.8l-.4 .6M21 28.6l-.4 .6M21 29.9l-.4 .6M21.3 21.6l.5 .6M21.3 23.1l.5 .5M21.3 24.4l.5 .6M21.3 25.8l.5 .6M21.3 26.9v.9M21.3 28.6l.5 .6M21.3 29.9l.5 .6M21.8 20a.42 .42 0 0 0-.6 .4 .42 .42 0 0 0 .6 .4M21.8 21.6l-.5 .6"/>
<path d="M21.8 23.1l-.5 .5M21.8 24.4l-.5 .6M21.8 25.8l-.5 .6M21.8 28.6l-.5 .6M21.8 29.9l-.5 .6M21.9 26.9l.3 .1v.6l-.1 .2a.49 .49 0 0 1-.5-.4 .49 .49 0 0 1 .3-.5zM22.1 21.6l.4 .6M22.1 23.1l.4 .5M22.1 24.4l.4 .6M22.1 25.8l.4 .6M22.1 28.6l.4 .6M22.1 29.9l.4 .6"/>
<path d="M22.5 21.6l-.4 .6M22.5 29.9l-.4 .6M22.5 23.1l-.4 .5M22.5 24.4l-.4 .6M22.5 25.8l-.4 .6M22.5 28.6l-.4 .6M22.7 21.6l.5 .6M22.7 23.1l.5 .5M22.7 24.4l.5 .6M22.7 25.8l.5 .6M22.7 28.6l.5 .6M22.7 29.9l.5 .6"/>
<path d="M23.1 27l-.3-.1-.2 .2v.5l.2 .2 .3-.1M23.2 21.6l-.5 .6M23.2 29.9l-.5 .6M23.2 23.1l-.5 .5M23.2 24.4l-.5 .6M23.2 25.8l-.5 .6M23.2 28.6l-.5 .6M23.3 26.9h.5M23.5 22.1v.1M23.5 23.5v.1M23.5 24.9v.1M23.5 26.3v.1"/>
<path d="M23.5 29.1v.1M23.5 30.4v.1M23.6 26.9v.9M23.8 21.6l.5 .6M23.8 23.1l.5 .5M23.8 24.4l.5 .6M23.8 25.8l.5 .6M23.8 28.6l.5 .6M23.8 29.9l.5 .6M23.9 20h-.4v.4l.4 .1v.3h-.4M24.1 26.9v.9h.4M24.3 21.6l-.5 .6"/>
<path d="M24.3 23.1l-.5 .5M24.3 24.4l-.5 .6M24.3 25.8l-.5 .6M24.3 28.6l-.5 .6M24.3 29.9l-.5 .6M24.3 20.4h.4l.1-.3-.1-.2h-.4v1M24.5 21.6l.4 .6M24.5 23.1l.4 .5M24.5 29.9l.4 .6M24.5 24.4l.4 .6M24.5 25.8l.4 .6M24.5 28.6l.4 .6"/>
<path d="M24.9 26.9a.48 .48 0 0 1 .4 .4 .48 .48 0 0 1-.4 .5l-.1-.3zM24.9 21.6l-.4 .6M24.9 23.1l-.4 .5M24.9 24.4l-.4 .6M24.9 25.8l-.4 .6M24.9 28.6l-.4 .6M24.9 29.9l-.4 .6M25.2 21.6l.5 .6M25.2 23.1l.5 .5M25.2 24.4l.5 .6M25.2 25.8l.5 .6M25.2 28.6l.5 .6"/>
<path d="M25.2 29.9l.5 .6M25.6 27.1l.3-.2v.9M25.6 27.8h.5M25.7 21.6l-.5 .6M25.7 23.1l-.5 .5M25.7 24.4l-.5 .6M25.7 25.8l-.5 .6M25.7 28.6l-.5 .6M25.7 29.9l-.5 .6M25.9 21.6l.5 .6M25.9 23.1l.5 .5M25.9 24.4l.5 .6"/>
<path d="M25.9 25.8l.5 .6M25.9 28.6l.5 .6M25.9 29.9l.5 .6M26 20.4h.3M26.4 21.6l-.5 .6M26.4 29.9l-.5 .6M26.4 23.1l-.5 .5M26.4 24.4l-.5 .6M26.4 25.8l-.5 .6M26.4 28.6l-.5 .6M26.5 27l.2-.1 .2 .1v.6l-.2 .2a.53 .53 0 0 1-.2-.8zM27.2 26.8h.2v1.3h-.2"/>
<path d="M27.3 20l-.3-.1-.2 .3v.4l.2 .3 .3-.1M27.3 21.6l.4 .6M27.3 23.1l.4 .5M27.3 24.4l.4 .6M27.3 25.8l.4 .6M27.3 28.6l.4 .6M27.3 29.9l.4 .6M27.7 21.6l-.4 .6M27.7 23.1l-.4 .5M27.7 24.4l-.4 .6M27.7 25.8l-.4 .6M27.7 28.6l-.4 .6"/>
<path d="M27.7 29.9l-.4 .6M28 29.9l.4 .6M28 21.6l.4 .6M28 23.1l.4 .5M28 24.4l.4 .6M28 28.6l.4 .6M28 25.8l.4 .6M28.4 21.6l-.4 .6M28.4 23.1l-.4 .5M28.4 24.4l-.4 .6M28.4 25.8l-.4 .6M28.4 28.6l-.4 .6"/>
<path d="M28.4 29.9l-.4 .6M28.7 29.9l.4 .6M28.7 21.6l.4 .6M28.7 23.1l.4 .5M28.7 24.4l.4 .6M28.7 25.8l.4 .6M28.7 28.6l.4 .6M29.1 21.6l-.4 .6M29.1 23.1l-.4 .5M29.1 24.4l-.4 .6M29.1 29.9l-.4 .6M29.1 25.8l-.4 .6"/>
<path d="M29.1 28.6l-.4 .6M29.3 21.6l.5 .6M29.3 23.1l.5 .5M29.3 24.4l.5 .6M29.3 25.8l.5 .6M29.3 28.6l.5 .6M29.3 29.9l.5 .6M29.8 21.6l-.5 .6M29.8 23.1l-.5 .5M29.8 24.4l-.5 .6M29.8 25.8l-.5 .6M29.8 28.6l-.5 .6"/>
<path d="M29.8 29.9l-.5 .6M30.1 22.1v.1M30.1 23.5v.1M30.1 24.9v.1M30.1 26.3v.1M30.1 29.1v.1M30.1 30.4v.1M30.4 21.6l.5 .6M30.4 23.1l.5 .5M30.4 24.4l.5 .6M30.4 25.8l.5 .6M30.4 28.6l.5 .6"/>
<path d="M30.4 29.9l.5 .6M30.9 21.6l-.5 .6M30.9 23.1l-.5 .5M30.9 24.4l-.5 .6M30.9 25.8l-.5 .6M30.9 28.6l-.5 .6M30.9 29.9l-.5 .6M31.2 21.6l.4 .6M31.2 23.1l.4 .5M31.2 29.9l.4 .6M31.2 24.4l.4 .6M31.2 25.8l.4 .6"/>
<path d="M31.2 28.6l.4 .6M31.6 21.6l-.4 .6M31.6 23.1l-.4 .5M31.6 24.4l-.4 .6M31.6 25.8l-.4 .6M31.6 28.6l-.4 .6M31.6 29.9l-.4 .6M31.9 29.9l.4 .6M31.9 21.6l.4 .6M31.9 23.1l.4 .5M31.9 24.4l.4 .6M31.9 25.8l.4 .6"/>
<path d="M31.9 28.6l.4 .6M32.3 21.6l-.4 .6M32.3 23.1l-.4 .5M32.3 24.4l-.4 .6M32.3 25.8l-.4 .6M32.3 28.6l-.4 .6M32.3 29.9l-.4 .6M32.6 21.6l.4 .6M32.6 23.1l.4 .5M32.6 29.9l.4 .6M32.6 24.4l.4 .6M32.6 25.8l.4 .6"/>
<path d="M32.6 28.6l.4 .6M33 21.6l-.4 .6M33 23.1l-.4 .5M33 24.4l-.4 .6M33 25.8l-.4 .6M33 28.6l-.4 .6M33 29.9l-.4 .6M34 21.5l.3-.1 .1 .1-.1 .7-.3-.1zM34 22.8l.2-.1 .2 .2-.1 .7-.3-.1zM34 24.3l.3-.1 .1 .1v.5l-.2 .2-.2-.1zM34 25.6l.3-.1 .1 .2-.1 .7-.3-.1zM34 28.4l.3-.1 .1 .2v.5l-.2 .2-.2-.1z"/>
<path d="M34 29.8l.2-.1 .2 .1-.1 .7-.3-.1zM34.8 28.6l.2-.3v.9M34.8 29.9l.2-.2v.8M34.8 29.2h.5M34.8 30.5h.5M34.8 21.5l.4-.1v.7a.39 .39 0 0 1-.5-.2 .39 .39 0 0 1 .1-.4zM34.8 22.8l.3-.1 .2 .2-.1 .6a.39 .39 0 0 1-.5-.2 .39 .39 0 0 1 .1-.5zM34.8 24.3l.4-.1 .1 .1v.5l-.2 .2a.48 .48 0 0 1-.3-.7zM34.8 25.6l.4-.1v.8a.39 .39 0 0 1-.5-.2 .39 .39 0 0 1 .1-.5zM35.6 22.9l.2-.2a.43 .43 0 0 1 .3 .5 .43 .43 0 0 1-.4 .4zM35.6 25.8l.3-.3v.9M35.6 29.8l.2-.1a.43 .43 0 0 1 .3 .4 .43 .43 0 0 1-.4 .4z"/>
<path d="M35.6 26.4h.5M35.7 21.4a.42 .42 0 0 1 .4 .4 .42 .42 0 0 1-.4 .4zM35.7 24.2a.42 .42 0 0 1 .4 .3 .42 .42 0 0 1-.2 .4l-.1 .1-.2-.2zM35.7 28.3a.43 .43 0 0 1 .4 .4 .43 .43 0 0 1-.3 .5l-.2-.2zM36.4 24.3l.3-.1v.8M36.4 29.9l.3-.2v.8M36.4 25h.5M36.4 30.5h.5M36.5 21.4h.3l.1 .1-.1 .7h-.3l-.1-.1zM36.5 25.5h.3l.1 .2-.1 .7h-.3l-.1-.2zM36.5 28.3h.3l.1 .2v.5l-.2 .2-.3-.2zM36.6 22.7l.3 .2-.1 .7h-.3l-.1-.2v-.5z"/>
<path d="M37.3 22.1v.1M37.3 23.5v.1M37.3 24.9v.1M37.3 26.3v.1M37.3 29.1v.1M37.3 30.4v.1M37.7 21.5l.1-.1a.43 .43 0 0 1 .3 .4 .43 .43 0 0 1-.3 .4l-.2-.3zM37.7 22.8l.2-.1a.45 .45 0 0 1 .2 .5 .45 .45 0 0 1-.3 .4l-.2-.4zM37.7 24.3l.1-.1a.46 .46 0 0 1 .4 .3 .46 .46 0 0 1-.2 .5 .48 .48 0 0 1-.3-.7zM37.7 25.6l.1-.1a.43 .43 0 0 1 .3 .4 .43 .43 0 0 1-.3 .5l-.2-.4zM37.7 28.4l.1-.1a.45 .45 0 0 1 .3 .4 .45 .45 0 0 1-.2 .5l-.3-.4zM37.7 29.8l.2-.1a.45 .45 0 0 1 .2 .4 .45 .45 0 0 1-.3 .4l-.2-.3z"/>
<path d="M38.6 21.4a.42 .42 0 0 1 .4 .4 .42 .42 0 0 1-.4 .4zM38.6 24.2a.42 .42 0 0 1 .4 .3 .42 .42 0 0 1-.2 .4l-.2 .1-.1-.2zM38.6 25.5a.42 .42 0 0 1 .4 .4 .42 .42 0 0 1-.4 .5zM38.6 28.3a.43 .43 0 0 1 .4 .4 .43 .43 0 0 1-.4 .5l-.1-.2zM38.6 22.7a.43 .43 0 0 1 .4 .5 .43 .43 0 0 1-.4 .4l-.1-.7zM38.6 29.7a.43 .43 0 0 1 .4 .4 .43 .43 0 0 1-.4 .4l-.1-.7zM39.3 21.5l.4-.1v.1v.7l-.4-.1zM39.3 22.8l.3-.1 .1 .2v.7l-.4-.1zM39.3 24.3l.4-.1v.1v.5l-.1 .2-.3-.1zM39.3 25.6l.4-.1v.2v.7l-.4-.1zM39.3 28.4l.4-.1v.2v.5l-.1 .2-.3-.1zM39.3 29.8l.3-.1 .1 .1v.7l-.4-.1z"/>
<path d="M40.1 23l.2-.3v.9M40.1 23.6h.5M40.1 24.4l.4 .6M40.2 21.5l.3-.1v.7a.39 .39 0 0 1-.4-.2 .39 .39 0 0 1 .1-.4zM40.2 25.6l.3-.1v.8a.39 .39 0 0 1-.4-.2 .39 .39 0 0 1 .1-.5zM40.2 28.4l.3-.1 .1 .2v.5l-.2 .2a.48 .48 0 0 1-.2-.8zM40.2 29.8l.2-.1 .2 .1-.1 .6a.39 .39 0 0 1-.4-.2 .39 .39 0 0 1 .1-.4zM40.5 24.4l-.4 .6M41.5 24.7h.6M41.6 21.9h.7M41.6 23.2h.7M41.6 26h.7"/>
<path d="M41.6 28.8h.7M41.6 30.2h.7M43.3 21.4h.3l.2 .1v.6l-.2 .1h-.3zM43.3 22.7h.3l.2 .3v.4l-.2 .2h-.3zM43.3 28.3v.9M43.3 29.7v.8M43.7 24.3h-.5v.5l.3 .2 .2-.1M43.7 28.7l.3-.1 .2 .1v.5M43.7 30l.3-.1 .2 .2v.4M43.7 28.6v.6M43.7 29.9v.6M43.8 25.5l-.5 .1v.3l.5 .2-.1 .3h-.4"/>
<path d="M44.1 24.5l.3-.1 .1 .5h-.4zM44.1 25.8l.2 .6M44.2 21.4v.1M44.2 22.7v.1M44.2 21.6v.6M44.2 23.1v.5M44.4 28.6h.3M44.4 29.9h.3M44.5 25.8l-.3 .8-.1 .1M44.6 21.7l.2-.1 .2 .2v.4h-.4l.1-.3h.3M44.6 23.1l.4 .1v.4h-.4l.1-.4h.3M44.6 28.3v.8l.1 .1"/>
<path d="M44.6 29.7v.8h.1M44.8 24.5h.5v.5M44.8 24.4v.6M45 28.8h.4l-.1-.2-.3 .1v.4h.3M45 30.3l.4-.1-.1-.3-.3 .1v.5h.3M45.1 25.9l-.2-.1-.2 .1 .5 .4-.5 .1M45.4 25.8h.4M45.5 25.5v.8l.3 .1M45.5 24.4h.3M45.8 21.6v.8l-.4 .1M45.8 21.7l-.3-.1-.2 .2 .1 .4h.4M45.8 23.6h-.4v-.5h.4v.7h-.4"/>
<path d="M45.8 28.6v.6M45.8 29.9v.6M45.8 24.2h-.1v.8M45.9 26.1l.5-.1-.1-.2-.4 .1v.4l.5 .1M46 28.6l-.2 .1M46 29.9l-.2 .2M46.1 24.2v.1M46.1 24.4v.6M46.2 21.7h.3v.5M46.2 23.2l.3-.1v.5M46.2 21.6v.6M46.2 23.1v.5"/>
<path d="M46.3 28.6v.6M46.3 29.9v.6M46.5 28.6l-.2 .1M46.5 29.9l-.2 .2M46.8 25.9h.3v.5M46.8 25.8v.6M46.9 28.6v.5h.3M46.9 29.9v.6l.3-.1M46.9 21.7l.3-.1 .2 .2-.1 .4-.4-.1zM46.9 23.2l.4-.1v.5l-.4-.1zM46.9 24.9h-.4l.1-.5h.3v.7v.2h-.4M47.1 25.9l.1-.1 .3 .1v.5"/>
<path d="M47.2 28.6v.6M47.2 29.9v.6M47.3 24.4v.4l.2 .2 .2-.1M47.6 28.7l.3-.1 .1 .1-.1 .5-.3-.1M47.6 30l.3-.1 .1 .2v.4h-.4M47.6 28.6v.8M47.6 29.9v1M47.7 24.4v.6M48 21.7h-.3l.1 .3h.2v.2h-.3M48 23.1h-.3l.1 .2h.2v.3h-.3M48.1 24.4v.6M48.3 21.6h.3"/>
<path d="M48.3 23.1h.3M48.3 28.6h.3M48.3 29.9h.3M48.4 24.4l-.3 .2M48.4 28.3v.7l.2 .2M48.4 29.7v.7l.2 .1M48.5 21.4v.8h.1M48.5 22.7v.9h.1M48.6 25.9h.2M48.6 24.4h.4v.6M48.9 21.4v.1M48.9 22.7v.1"/>
<path d="M48.9 21.6v.6M48.9 23.1v.5M49 24.6l-.4 .2 .1 .2 .3-.1M49 25.5h-.4v.9h.4M49.3 25.9l.3-.1 .1 .1v.5M49.3 24.4h.4M49.3 25.8v.6M49.4 24.2v.6l.3 .2M49.7 21.7h-.4v.4l.4 .1M49.7 23.1l-.4 .1 .1 .4h.3M49.9 24.2v.1M49.9 24.4v.6"/>
<path d="M50 28.3h-.4l-.1 .2 .5 .5-.2 .2-.3-.1M50 29.8a.43 .43 0 0 0-.5 .2 .43 .43 0 0 0 .2 .5l.3-.1M50.1 25.9l.2-.1 .2 .1v.5h-.4l.1-.4h.3M50.3 24.4h.4l.1 .2-.2 .4-.4-.2zM50.3 28.8h.5l-.2-.2-.3 .1v.4h.4M50.4 29.7l.1 .8M50.8 30.3l.4-.1-.1-.3-.3 .1v.5h.4M50.9 25.5v.9h.3l.1-.5h-.4M51 28.6h.3M51.1 21.4v.8h-.3l-.1-.4 .1-.2 .3 .1M51.1 22.7v.9h-.3v-.5h.3M51.1 24.5l.3-.1v.6"/>
<path d="M51.1 28.3v.8l.2 .1M51.1 24.4v.6M51.5 21.4v.1M51.5 22.7v.1M51.5 21.6v.6M51.5 23.1v.5M51.6 30h.3v.5h-.3l-.1-.2 .2-.1h.2M51.7 25.5l.1 .9M52.1 26.1l.3-.1v-.2l-.3 .1v.5h.3M52.2 21.7l-.2-.1-.1 .2 .4 .3-.4 .1M52.2 23.1h-.3v.1l.4 .3-.4 .1M52.4 29.9v.6"/>
<path d="M52.6 21.7l.3-.1 .1 .2v.4h-.4M52.6 23.6h.4v-.5h-.4v.8M52.6 29.9l-.2 .2M52.6 21.6v.9M52.8 24.4h-.3l-.1 .2 .5 .2-.2 .2-.3-.1M53.1 24.4l.2 .6 .2-.4 .1 .4 .2-.6M53.4 21.4v.7l.1 .1M53.4 22.7v.8l.1 .1M53.5 25.8v.6M53.7 25.8l-.2 .1M53.8 21.7l.3-.1 .1 .2v.4h-.4l.1-.3h.3M53.8 23.1l.4 .1v.4h-.4l.1-.4h.3"/>
<path d="M54 26.1l.4-.1-.1-.2-.3 .1v.4l.4 .1M54.1 24.2v.1M54.1 24.4v.6M54.4 24.4h.3M54.6 24.2v.7l.1 .1M54.6 21.6l.1 .6M54.6 23.1l.1 .5M55 21.6l-.4 .9M55 23.1l-.4 .8M55.2 25.8v.7l-.2 .2-.2-.1M55.2 25.9l-.3-.1-.2 .1 .1 .5h.4M55.4 24.4h-.3l-.1 .2 .2 .4 .2-.1"/>
<path d="M55.6 25.5v.1M55.6 25.8v.6M55.7 24.5h.5v.5M55.7 24.2v.8M56.2 21.2a1.02 1.02 0 0 0 0 1.4M56.2 22.6a.92 .92 0 0 0 0 1.3M56.3 25.9l-.2-.1-.2 .1 .4 .4-.4 .1M56.5 21.6v.6l.4-.1M56.5 22.7l.1 .9M56.5 24.7l.4-.1v-.2h-.4v.5h.4M56.5 25.8h.4M56.7 25.5v.9h.2"/>
<path d="M56.9 21.6v.6M56.9 23.2h.5l-.1 .4-.4-.1zM57.1 26.1l.4-.1-.1-.2-.3 .1v.4l.4 .1M57.3 21.7h.4v.4l-.4 .1M57.3 21.6v.9M57.6 24.4h-.3v.3h.2l.1 .2h-.3M57.7 23.1l.1 .5 .2-.4 .1 .4 .2-.5M57.9 25.8v.6M58 21.7h.5v.4l-.5 .1M58 21.6v.9M58.1 25.8l-.2 .1M58.6 23.3l.5-.1-.1-.1h-.4v.5h.4"/>
<path d="M58.8 22l.4-.1-.1-.3-.3 .2v.3l.3 .1M59.4 23.1v.5M59.6 21.6v.6M59.6 23.1l-.2 .1M59.8 21.6l-.2 .2M60.9 22.7v.9h-.3v-.5h.3M61.2 21.4v.8h-.4l-.1-.5h.5M61.3 22.7v.1M61.3 23.1v.5M61.6 21.4v.1M61.6 21.6v.6M62.1 23.6h-.3v-.5h.3v.7h-.3"/>
<path d="M62.4 21.6v.7l-.1 .2h-.4M62.4 21.7h-.5v.4l.5 .1M62.5 22.7v.1M62.5 23.1v.5M62.8 21.4v.1M62.8 21.6v.6M62.9 23.1h.2M62.9 22.7v.9h.2M63 21.6h.4M63.1 21.4v.7l.3 .1M63.4 22.6a.92 .92 0 0 1 0 1.3M63.5 21.2l.3 .4v.6l-.3 .4"/>
<path d="M182.4 88.4l-.2-.1-.3 .3v.4l.3 .3 .2-.1M182.8 88.7l.4 .1v.4l-.2 .1-.3-.2zM183.6 88.8l.3-.1v.6M183.6 88.7v.6M184.3 88.7h.2M184.5 88.3l-.1 .1v.9M184.9 88.3v.1M184.9 88.7v.6M185.6 89.2l-.2 .1-.2-.2 .1-.4h.3v.7l-.3 .1M186.1 88.7v.5h.3M186.4 88.7v.6M186.8 88.7v.6"/>
<path d="M187.1 88.7l-.3 .2M187.3 88.7l.4 .1v.5M187.7 88.9h-.4l.1 .4 .3-.1M188 88.7h.3M188.2 88.3v.9l.1 .1M188.6 88.3v.1M188.6 88.7v.6M189 88.8l.4-.1v.5h-.4zM189.8 88.8h.4v.5M189.8 88.7v.6M191.2 88.9l.5-.1v-.4l-.5-.1v1M191.5 88.9l.2 .4"/>
<path d="M192.1 88.9h.4l-.1-.2-.3 .1v.3l.1 .2 .2-.1M193.2 89.2h-.4l.1-.5h.3v.7v.1h-.4M193.6 88.3v.1M193.6 88.7v.6M194.3 88.7h-.3v.2l.3 .1v.3l-.3-.1M194.6 88.7h.3M194.8 88.3v.9l.1 .1M195.2 88.9h.4l-.1-.2h-.3v.5h.3M196 88.7v.6M196.2 88.7l-.2 .2M55.2 118.6l.3-.9 .2 .9M55.2 119.3h.3"/>
<path d="M55.3 111.2l.4-.1v-.2l-.4-.1v.8h.4l.1-.2-.2-.2M55.3 118.3h.4M55.5 119.1l-.2 .1v.7M55.7 108h-.4v.3l.4 .2v.3h-.4M55.7 112.2h-.4v.3l.4 .1v.4h-.4M55.7 113.6h-.4v.3l.4 .2v.2h-.4M55.7 114.9h-.4v.4l.4 .1v.4h-.4M55.7 119.5l.2-.2 .4 .2-.1 .4h-.4zM56 112.1l.3 .5 .3-.5M56 113.6l.3 .4 .3-.4M56 114.9l.3 .5 .3-.5M56.1 117.7l.1 .9"/>
<path d="M56.1 108.2l.2 .6M56.2 110.8v.1M56.2 111v.6M56.3 112.6v.4M56.3 114v.4M56.3 115.4v.4M56.5 108.2l-.4 1M56.5 117.7v.7l.2 .2M56.5 111h.3M56.6 110.8v.7l.2 .1M56.6 119.3v.6M56.9 119.3l-.3 .2"/>
<path d="M57.1 108.3h-.3l.1 .3h.2v.2h-.3M57.4 111.1l-.2-.1-.2 .2 .4 .3-.1 .1-.3-.1M57.4 112.2h-.5v.3l.5 .2-.1 .3h-.4M57.4 113.6h-.5v.2l.5 .4-.2 .2-.3-.1M57.4 114.9l-.5 .1v.3l.5 .2-.1 .3h-.4M57.4 108.2h.3M57.5 108v.8h.2M57.6 118.1l.3-.1 .1 .1-.1 .5-.3-.1zM57.7 112.6h.3M57.7 113.9h.3M57.7 115.4h.3M57.7 119.3h.3"/>
<path d="M58 108.6l.4-.1-.2-.3-.2 .1v.5h.3M58 119.1l-.2 .1v.7M58.1 112.1h-.4v.9h.4M58.1 113.6h-.4v.8h.4M58.1 114.9h-.4v.9h.4M58.3 119.3v.6l.3-.1M58.3 118h.3M58.4 117.7v.7l.2 .2M58.5 110.8v.1M58.5 111v.6M58.6 119.3v.6M58.7 108.3l.3-.1 .1 .2v.4"/>
<path d="M58.7 108.2v.6M58.9 111.1h.3v.5M58.9 118.1h.4v.5M58.9 111v.6M58.9 117.7v.9M59 112.1v.9l-.5-.9v.9M59 113.6v.8l-.5-.8v.8M59 114.9v.9l-.5-.9v.9M59 119.3h.3M59.1 119.1v.7l.2 .1M59.1 108.4l.1-.2 .3 .2v.4M59.2 113.1h.6"/>
<path d="M59.2 114.5h.6M59.2 115.9h.6M59.6 119.3v.6l.3-.1M59.6 118.2l.5-.1h-.5v.4h.4M59.9 119.3v.6M60.1 113v-.9l.2 .6 .3-.6v.9M60.1 113.6v.8M60.2 111h.3M60.3 110.8v.7l.2 .1M60.3 119.3v.6M60.4 118v.6M60.5 114.9h-.4l-.1 .2 .2 .3h.3v.3l-.5 .1"/>
<path d="M60.6 119.3l-.3 .2M60.6 108.4h.2M60.7 118l-.3 .1M60.7 111.1l.3-.1 .2 .2v.4M60.7 114.9l.3 .9 .2-.6 .1 .6 .2-.9M60.7 110.8v.8M60.8 119.7l.5-.1-.2-.3-.3 .1v.5h.4M60.9 108h-.3v.8h.3M60.9 113.6v.8l-.4-.8v.8M61 113v-.9l.3 .6 .3-.6v.9M61.3 113.6h.5M61.3 108.3h.4v.5"/>
<path d="M61.3 108.2v.6M61.5 111.4l.4-.1-.1-.3-.3 .2v.3l.2 .1 .2-.1M61.5 113.6v.8M61.6 118.1l.2-.1 .2 .1-.2 .5-.2-.1M61.6 117.7v.9M61.8 114.9h.6l-.5 .9M62 112.1l.1 .9h.3l.1-.2v-.7M62.1 108.3h.3v.5h-.3l-.1-.1 .4-.2M62.2 119.7l.4-.1-.1-.3-.3 .2v.3l.4 .1M62.4 117.7v.1M62.4 118v.6M62.7 113.6l.4 .1v.6l-.2 .1a.53 .53 0 0 1-.2-.8z"/>
<path d="M62.7 118h.3M62.8 117.7v.7l.2 .2M62.9 108v.8h.3l.1-.4-.2-.2-.2 .1M62.9 111v.6M62.9 119.3l.5 .6M63.2 111l-.3 .2M63.4 114.9a.42 .42 0 0 1 .4 .5 .42 .42 0 0 1-.4 .4zM63.4 113.8l.5 .6M63.4 119.3l-.5 .6M63.5 111.4l.4-.1-.2-.3-.2 .1v.4h.3M63.5 118.1l-.1-.1-.2 .1 .4 .3-.1 .2-.3-.1M63.6 108v.8h.2"/>
<path d="M63.7 112.1a.43 .43 0 0 1 .4 .5 .43 .43 0 0 1-.5 .4l-.1-.7zM63.7 119.4l.3-.1 .1 .2-.1 .4h-.3M63.7 119.3v1M63.9 113.8l-.5 .6M64 108.6l.5-.1-.1-.3-.4 .2v.4h.5M64 115.2l.6 .6M64.2 113.6a.46 .46 0 0 1 .5 .3 .46 .46 0 0 1-.2 .5 .53 .53 0 0 1-.3-.8zM64.3 112.5l.4 .5M64.5 119.4h.3v.5h-.3v-.2l.3-.1M64.6 111v.9h-.4M64.6 111.1h-.4v.4h.4M64.6 115.2l-.6 .6"/>
<path d="M64.6 118v.6M64.7 112.5l-.4 .5M64.9 118l-.3 .1M65 110.8v.1M65 113.6h.4l.1 .1-.6 .7h.6M65 115.3l-.2-.3 .4-.1v.4l-.4 .1 .1 .4h.3l.1-.4-.2-.1M65 111v.6M65.1 112.3l.1-.2a.43 .43 0 0 1 .4 .5 .43 .43 0 0 1-.5 .4zM65.1 118.2l.5-.1h-.5v.4h.4M65.2 119.4l.3-.1 .2 .2v.4M65.2 119.3v.6M65.5 108.4h.4v-.4h-.4v.8"/>
<path d="M65.7 111.1h-.3l.1 .3h.2v.2l-.3-.1M65.7 114.9h.3l.1 .2-.1 .7h-.3v-.2zM65.7 108.4l.3 .4M65.9 112.4l.2-.3v.9M65.9 113h.4M66 111h.3M66.1 110.8v.7l.2 .1M66.2 118.1l-.2-.1-.1 .2 .3 .2-.1 .2-.2-.1M66.3 108.6l.5-.1-.2-.3-.3 .1v.5h.4M66.3 119.4h-.3l.1 .3h.2v.2h-.3M66.6 111.4l.4-.1-.2-.3-.2 .1v.4h.3M66.6 118.2l.4-.1h-.4v.4h.3"/>
<path d="M66.8 119.1v.1M66.8 119.3v.6M67.1 119.5l.2-.2 .2 .1v.4l-.3 .1zM67.3 111v.6M67.3 118v.6M67.4 108.2v.9h-.3M67.4 108.3h-.3v.5h.3M67.6 111l-.3 .2M67.6 118l-.3 .1M67.8 118l.2 .6 .2-.6M67.9 108v.1M67.9 111.5v.1"/>
<path d="M67.9 111.1v.1M67.9 108.2v.6M67.9 119.4h.4v.5M67.9 119.3v.6M68.5 108.3l-.1-.1-.1 .3 .3 .3h-.3M68.5 118.2l.4-.1-.1-.1-.3 .1v.4h.4M68.7 119.8v.1M68.9 108.2h.3M69 108v.8h.2M69.5 108.6l.3-.1-.1-.3-.2 .1v.5h.3M69.6 118.1l-.2-.1-.2 .1 .2 .5 .2-.1M69.6 117.7v.9"/>
<path d="M70.2 108.2v.6M70.5 108.2l-.3 .2"/>
</g>
<path d="M51.2 45.2l.8 .8M52 45.2l-.8 .8M52 57.3l.9 .8M52.9 57.3l-.9 .8M96.8 66.8l.9 .7M97.7 66.8l-.9 .7M137.3 66.8l.8 .7M138.1 66.8l-.8 .7" fill="none" stroke="#00008a" stroke-width=".21"/>
<g fill="#090">
<circle cx="54.2" cy="168.8" r=".38"/>
<circle cx="45.6" cy="168.8" r=".38"/>
<circle cx="71.4" cy="181.7" r=".38"/>
<circle cx="71.4" cy="178.3" r=".38"/>
<circle cx="45.6" cy="165.3" r=".38"/>
<circle cx="54.2" cy="165.3" r=".38"/>
<circle cx="45.6" cy="178.3" r=".38"/>
<circle cx="37.8" cy="178.3" r=".38"/>
<circle cx="37.8" cy="181.7" r=".38"/>
<circle cx="62.8" cy="168.8" r=".38"/>
<circle cx="37.8" cy="168.8" r=".38"/>
<circle cx="37.8" cy="165.3" r=".38"/>
<circle cx="62.8" cy="181.7" r=".38"/>
<circle cx="62.8" cy="178.3" r=".38"/>
<circle cx="54.2" cy="178.3" r=".38"/>
<circle cx="54.2" cy="181.7" r=".38"/>
<circle cx="45.6" cy="181.7" r=".38"/>
<circle cx="80" cy="178.3" r=".38"/>
<circle cx="80" cy="181.7" r=".38"/>
<circle cx="71.4" cy="168.8" r=".38"/>
<circle cx="71.4" cy="165.3" r=".38"/>
<circle cx="62.8" cy="165.3" r=".38"/>
<circle cx="88.7" cy="178.3" r=".38"/>
<circle cx="88.7" cy="181.7" r=".38"/>
<circle cx="80" cy="165.3" r=".38"/>
<circle cx="80" cy="168.8" r=".38"/>
<circle cx="47.3" cy="88.7" r=".38"/>
<circle cx="48.1" cy="90.4" r=".38"/>
<circle cx="194.6" cy="73.2" r=".38"/>
<circle cx="182.5" cy="83.5" r=".38"/>
<circle cx="210.1" cy="68" r=".38"/>
<circle cx="210.1" cy="66.2" r=".38"/>
<circle cx="210.1" cy="64.6" r=".38"/>
<circle cx="210.1" cy="69.7" r=".38"/>
<circle cx="210.1" cy="71.4" r=".38"/>
<circle cx="192.8" cy="71.4" r=".38"/>
<circle cx="182.5" cy="61.1" r=".38"/>
<circle cx="189.4" cy="34.4" r=".38"/>
<circle cx="182.5" cy="49.9" r=".38"/>
<circle cx="187.7" cy="32.7" r=".38"/>
<circle cx="186" cy="30.9" r=".38"/>
<circle cx="184.3" cy="29.2" r=".38"/>
<circle cx="186" cy="64.6" r=".38"/>
<circle cx="191.1" cy="69.7" r=".38"/>
<circle cx="189.4" cy="68" r=".38"/>
<circle cx="184.3" cy="62.9" r=".38"/>
<circle cx="187.7" cy="66.2" r=".38"/>
<circle cx="182.5" cy="27.6" r=".38"/>
<circle cx="210.1" cy="30.9" r=".38"/>
<circle cx="210.1" cy="29.2" r=".38"/>
<circle cx="210.1" cy="27.6" r=".38"/>
<circle cx="210.1" cy="36.1" r=".38"/>
<circle cx="194.6" cy="39.6" r=".38"/>
<circle cx="210.1" cy="34.4" r=".38"/>
<circle cx="210.1" cy="32.7" r=".38"/>
<circle cx="191.1" cy="36.1" r=".38"/>
<circle cx="192.8" cy="37.9" r=".38"/>
<circle cx="109.3" cy="42.2" r=".38"/>
<circle cx="210.1" cy="37.9" r=".38"/>
<circle cx="210.1" cy="39.6" r=".38"/>
<circle cx="210.1" cy="61.1" r=".38"/>
<circle cx="210.1" cy="62.9" r=".38"/>
</g>
<g fill="none" stroke="#006665" stroke-width=".21">
<path d="M119.9 18.4v.9h.2h.3v-.9M120.9 18.4l-.1 .6h.5M121.2 18.8v.5M121.6 18.5l.3-.1 .1 .2v.6l-.1 .1h-.3zM122.4 18.7l.2-.3v.9M122.4 19.3h.5M167.7 19h.6M167.9 18.7v.6M169.1 18.4h-.4v.4h.4v.5h-.4M169.4 18.4l.3 .9 .3-.9M41.9 37h.6M42.2 36.7v.7"/>
<path d="M43.4 36.5h-.4l-.1 .5 .4-.1 .1 .4h-.5M43.6 36.5l.4 .9 .2-.9M44.7 38.2v.9l.2 .1 .4-.2v-.8M45.8 38.2l-.2 .6h.5M46 38.6v.6M46.6 38.2a.48 .48 0 0 1 .4 .5 .48 .48 0 0 1-.4 .5l-.2-.2v-.6zM47.5 38.2l-.3 .6h.6M47.6 38.6v.6M116 20.2h.4a.47 .47 0 0 1 .1 .5 .47 .47 0 0 1-.5 .3zM116.8 21l.2-.8 .3 .8M116.9 20.8h.3M117.6 20.3l.4-.1 .1 .2v.5l-.2 .1a.48 .48 0 0 1-.3-.7z"/>
<path d="M118.6 20.1l-.2 .7h.5M118.8 20.4v.6M119.2 20.7h.7M120.3 20.4l.2-.2v.8M120.3 21h.5M121.1 20.4l.3-.2v.8M121.1 21h.5M122.4 20.2l-.4 .1v.2l.4 .2v.3h-.4M122.8 20.2v.8h.2l.3-.1v-.7M123.7 20.6h.4l.1-.3-.5-.1v.8M123.9 20.6l.3 .4M124.6 20.2v.8"/>
<path d="M124.7 20.5l.3 .5M125 20.2l-.4 .5M125.3 20.2l.2 .8 .2-.6 .2 .6 .2-.8M126.3 21l.2-.8 .4 .8M126.4 20.8h.4M170.4 23.6h.6l-.4 .9M170.5 21.9l.1 .8h.3l.1-.8M171.5 23.6l-.3 .6h.6M171.6 21.9l-.3 .6h.6M171.7 23.9v.6M171.7 22.1v.6M172.1 23.6v.9"/>
<path d="M172.1 24h.5M172.3 21.9a.43 .43 0 0 1 .4 .4 .43 .43 0 0 1-.4 .4l-.1-.6zM172.6 23.6v.9M173.4 21.9h-.4v.4h.4v.4l-.4-.1M173.5 23.7l-.2-.1-.3 .2v.5l.3 .2 .2-.1M173.8 23.6h.5M174 23.6v.9M174.5 23.7h.5v.3l-.5 .5h.5M175.6 23.6l-.3 .6h.6M175.7 23.9v.6M176.6 23.6h-.5v.4l.4-.1 .2 .4-.2 .2-.4-.1M209 21.5h.7"/>
<path d="M209.3 21.2v.7M210.4 21h-.4v.5l.4-.1v.5l-.4-.1M210.8 21l.2 .9 .3-.9M45.2 40h-.4a.44 .44 0 0 0-.1 .6 .44 .44 0 0 0 .6 .2v-.3h-.2M45.5 40.8l.3-.8 .2 .8M45.6 40.6h.3M46.4 40v.8h.4M46.9 40.1h.6v.2l-.6 .5h.6M47.8 40.1h.5v.2l-.5 .5h.5M48.6 40l.2 .8 .3-.8M49.4 40.3l.2-.3v.8M49.4 40.8h.4"/>
<path d="M50.2 40.1l.4-.1 .1 .2v.5l-.2 .1a.48 .48 0 0 1-.3-.7zM78.9 46.5h.6M79.3 46.2v.7M80.4 46h-.4v.4h.4l.1 .1-.1 .4-.4-.1M80.7 46l.3 .9 .2-.9M81.7 51.2h.6l-.4 .8M81.7 49.5v.7l.2 .1 .4-.1v-.7M82.8 51.1l-.3 .7h.6M82.8 49.4l-.2 .6h.6M82.9 51.4v.6M83 49.7v.6M83.4 51.2v.8"/>
<path d="M83.4 51.6h.5M83.5 49.6l.1-.1a.45 .45 0 0 1 .4 .4 .45 .45 0 0 1-.3 .4l-.3-.3zM83.9 51.2v.8M84.3 49.6l.4-.1 .1 .2-.6 .6h.6M84.8 51.3l-.3-.1-.2 .1v.6l.2 .1 .3-.1M85 51.2h.6M85.3 51.2v.8M85.8 51.3l.4-.1 .1 .2-.6 .6h.6M86.6 51.2h.6l-.5 .8M87.4 51.2h.5l-.2 .3 .2 .2-.1 .3-.4-.1M91.9 50.8h.4v-.5h-.4v.9M92.1 50.8l.3 .4"/>
<path d="M92.5 52l-.2 .6h.5M92.7 52.4v.5M93.1 52h.6l-.4 .9M93.3 50.3v.9l-.6-.9v.9M93.8 50.2l-.2 .7h.6M94 52.1l.3-.1 .1 .2v.6a.39 .39 0 0 1-.5-.2 .39 .39 0 0 1 .1-.5zM94 50.6v.6M94.6 50.3a.39 .39 0 0 1 .4 .5 .39 .39 0 0 1-.5 .3l-.1-.4zM94.8 52.4h.5v-.3l-.5-.1v.9M95 52.4l.3 .5M95.3 50.6l.2-.3v.9M95.3 51.2h.5"/>
<path d="M108.2 46.5h.6M108.5 46.2v.7M109.7 46h-.4v.4h.4l.1 .1-.1 .4-.4-.1M109.9 46l.4 .9 .2-.9M119.4 46.5h.7M119.8 46.2v.7M120.9 46h-.5v.4h.5v.1v.4l-.5-.1M121.2 46l.3 .9 .2-.9M122.1 51.2h.6l-.3 .8M122.2 49.5v.7l.2 .1 .3-.1v-.7M123.2 51.1l-.1 .7h.5M123.3 49.4l-.2 .6h.6"/>
<path d="M123.4 51.4v.6M123.5 49.7v.6M123.9 51.6h.5M123.9 51.2v.8M124 49.6l.3-.1 .1 .2v.5l-.2 .1a.48 .48 0 0 1-.2-.7zM124.4 51.2v.8M124.7 49.5h.6l-.4 .3h.3l.1 .4-.2 .1-.4-.1M125.3 51.3l-.4-.1-.1 .1v.6l.1 .1 .4-.1M125.5 51.2h.5M125.8 51.2v.8M126.3 51.3l.4-.1 .1 .2-.6 .6h.6M127 51.2h.6l-.4 .8"/>
<path d="M127.9 51.2h.5l-.3 .3 .3 .1v.3h-.5M132.4 50.8h.4v-.5h-.4v.9M132.6 50.8l.3 .4M133 52l-.2 .6h.5M133.2 52.4v.5M133.6 52h.6l-.4 .9M133.7 50.3v.9l-.5-.9v.9M134.3 50.2l-.2 .7h.6M134.5 52.1l.2-.1 .2 .2-.1 .6a.39 .39 0 0 1-.4-.2 .39 .39 0 0 1 .1-.5zM134.5 50.6v.6M135.1 50.3h.2l.1 .2v.5l-.1 .2a.48 .48 0 0 1-.4-.4 .48 .48 0 0 1 .2-.5zM135.3 52.4h.5v-.3l-.5-.1v.9"/>
<path d="M135.5 52.4l.3 .5M135.8 50.4l.4-.1 .1 .3-.6 .6h.6M155.5 42.6a.43 .43 0 0 0-.5 .3 .43 .43 0 0 0 .1 .5l.5-.1v-.3h-.2M156.4 42.5v.9l-.5-.9v.9M156.8 42.5a.49 .49 0 0 1 .5 .4 .49 .49 0 0 1-.1 .5h-.4zM167.7 52.5h.6M167.9 52.3v.6M169.1 52h-.4v.4h.4v.4h-.4M169.4 52l.3 .9 .3-.9M170.4 57.2h.6l-.4 .8M170.5 55.5l.1 .8h.3l.1-.8M171.5 57.2l-.3 .6h.6"/>
<path d="M171.6 55.4l-.3 .7h.6M171.7 57.5v.5M171.7 55.7v.6M172.1 57.2v.8M172.1 57.6h.5M172.3 55.5a.42 .42 0 0 1 .4 .4 .42 .42 0 0 1-.4 .4zM172.6 57.2v.8M173.4 55.5l-.4 .2v.6h.4v-.5h-.3l-.1 .2M173.5 57.3l-.2-.1-.3 .2v.5l.2 .1h.3M173.8 57.2h.5M174 57.2v.8M174.5 57.3h.5v.3l-.5 .4h.5"/>
<path d="M175.6 57.2l-.3 .6h.6M175.7 57.5v.5M176.6 57.2h-.5v.4l.4-.1 .2 .2-.1 .3h-.5M181.9 53l-.3-.1-.2 .2v.4l.2 .2h.3v-.3h-.2M182.7 52.9v.8l-.5-.8v.8M183.2 52.9a.48 .48 0 0 1 .4 .3 .48 .48 0 0 1-.1 .5h-.3zM196.7 44h.9M196.7 43.5l.5 .5M197 45.3h.6M197.3 45.2v.5l-.7-.3M197.6 44.7l-.9-.4v.6M197.6 43.5l-.5 .4"/>
<path d="M198.4 45.2h.9l-.9 .4h.9M198.4 43.6l.2-.1 .6 .1a.36 .36 0 0 1-.2 .4 .36 .36 0 0 1-.5-.2zM198.4 43.1v-.5l.4 .3 .1-.3 .4 .1-.1 .4M198.7 44.3h.6M198.8 46.5v-.4l-.3-.1-.1 .5h.9M199 44.2v.5l-.6-.1M199.3 46l-.5 .3M201.8 42.6h-.5v.3l.5 .3-.1 .2h-.4M202.1 42.5l.2 .9 .2-.6 .1 .6 .2-.9M202.9 43.5h.7M203.4 44.3l-.4 .1 .1 .3 .3 .1v.3h-.4M203.7 44.3l.2 .9 .2-.7 .2 .7 .2-.9"/>
<path d="M203.8 42.5l.5 .3v.4l-.2 .2h-.3zM204.7 42.5v.9M204.9 44.2l-.1 .6h.5M205.1 43h.4v-.4l-.4-.1v.9M205.2 44.6v.6M205.7 44.3h.2l.1 .2v.5l-.1 .2-.3-.2zM205.7 43.5h.7M206.4 44.5l.2-.2v.9M206.4 45.2h.5M206.5 42.9l.5 .5M207 42.9l-.5 .5M207.3 42.6l.3-.1 .1 .2-.1 .7h-.2l-.2-.3z"/>
<path d="M208.2 43l-.1-.1v-.3l.3-.1 .2 .3-.5 .2v.4h.4l.1-.3-.2-.1M37 79.8v.7M38.2 79.6h-.4l-.1 .4h.4l.1 .4h-.5M38.5 79.6l.2 .9 .4-.9M42.4 69.3h-.4l-.1 .2v.4l.2 .2h.3v-.4h-.2M43.2 69.3v.8l-.5-.8v.8M43.6 69.3h.4a.48 .48 0 0 1 .1 .5 .48 .48 0 0 1-.5 .3zM155.5 76.2h-.4l-.1 .3 .1 .5 .5-.1v-.2h-.2M156.4 76.2v.8l-.5-.8v.8M156.8 76.2h.5v.5l-.1 .3h-.4zM196.7 77.6h.9M196.7 77.1l.5 .5"/>
<path d="M197 78.9h.6M197.3 78.7v.6l-.7-.3M197.6 78.3l-.9-.4v.5M197.6 77.1l-.5 .3M198.4 78.7h.9l-.9 .5h.9M198.5 77.1h.7l.1 .3-.7 .1-.2-.2zM198.7 77.9h.6M198.7 76.3h.6M199 77.8v.6l-.6-.2M199 76.2v.5l-.6-.2M199.3 79.6l-.5 .3M201.8 76.2h-.5v.3l.5 .2-.1 .3h-.4"/>
<path d="M202.1 76.2l.2 .8 .2-.6 .1 .6 .2-.8M202.9 77.1h.7M203.4 77.9h-.4v.3l.4 .2v.3h-.4M203.7 77.8l.2 .9 .2-.6 .2 .6 .2-.9M203.8 76.2l.5 .1v.5l-.2 .2h-.3zM204.7 76.2v.8M204.9 77.8l-.1 .6h.5M205.1 76.6h.3l.1-.4h-.4v.8M205.2 78.2v.5M205.7 77.1h.7M205.8 77.8l.2 .2-.1 .7-.3-.1v-.6zM206.4 77.9h.5v.4l-.5 .4h.5"/>
<path d="M206.5 76.4l.5 .6M207 76.4l-.5 .6M207.3 76.2h.3l.1 .1-.1 .6a.39 .39 0 0 1-.4-.2 .39 .39 0 0 1 .1-.5zM208.2 76.5l-.1-.3h.4v.3l-.4 .1v.4h.4l.1-.2-.2-.3M36.7 80.1h.7M39.5 84.8h.6l-.4 .8M39.6 83v.9h.1l.4-.1v-.8M40.5 84.7l-.2 .6h.5M40.6 83l-.2 .6h.5M40.8 85v.6M40.8 83.4v.5M41.2 84.8v.8"/>
<path d="M41.2 85.2h.5M41.4 83l.3 .1v.8h-.2l-.2-.1v-.6zM41.7 84.8v.8M42 83h.6l-.4 .9M42.6 84.9l-.4-.1a.44 .44 0 0 0-.1 .5 .44 .44 0 0 0 .5 .3M42.9 84.8h.4M43 84.8v.8M43.6 84.9h.5v.2l-.5 .5h.5M44.3 84.8h.6l-.3 .8M45.2 84.8h.5l-.3 .3h.3v.5h-.5M79.4 80.5h-.4l-.1 .3 .1 .5 .5-.1v-.2h-.2M80.3 80.5v.8l-.5-.8v.8"/>
<path d="M80.7 80.5l.4 .1v.5l-.1 .2h-.3zM119.8 80.5h-.3l-.2 .3 .2 .5 .4-.1v-.2h-.1M120.8 80.5v.8l-.5-.8v.8M121.2 80.5l.4 .1-.1 .7h-.3zM181.9 86.6l-.3-.1-.2 .2v.5l.2 .1h.3v-.3h-.2M182.7 86.5v.8l-.5-.8v.8M183.2 86.5a.47 .47 0 0 1 .5 .3 .47 .47 0 0 1-.2 .5h-.3zM198.8 80v-.3l-.3-.1-.1 .4h.9M36.7 116.3h.7M37 115.9v.7M37.2 114.1h-.3l-.2 .2v.4l.3 .2 .2-.1v-.3h-.2M38.1 114.1v.8l-.6-.8v.8"/>
<path d="M38.2 115.8h-.4l-.1 .4 .4-.1 .1 .4h-.5M38.5 115.8l.2 .8 .4-.8M38.5 114.1h.3a.48 .48 0 0 1 .2 .5 .48 .48 0 0 1-.5 .3zM39.6 119.2v.8l.1 .1 .4-.2v-.7M40.6 119.2l-.2 .6h.5M40.8 119.5v.6M41.4 119.2l.3 .1v.7l-.2 .1-.2-.2zM42.2 119.6l-.2-.2 .1-.2h.4v.3l-.4 .1-.1 .2 .2 .3 .3-.1v-.3l-.1-.1M39.5 120.9h.6l-.4 .9M40.5 120.9l-.2 .6h.5M40.8 121.2v.6M41.2 120.9v.9"/>
<path d="M41.2 121.4h.5M41.7 120.9v.9M42.6 121l-.4-.1-.2 .4 .2 .5 .4-.1M42.9 120.9h.4M43 120.9v.9M43.6 121h.5v.3l-.5 .5h.5M44.6 120.9l-.2 .6h.5M44.8 121.2v.6M45.7 120.9h-.4v.5l.4-.1v.5l-.4-.1M21.6 143.4l-.1-.1-.3 .2v.5l.3 .2 .2-.1v-.3h-.2M22.6 143.3v.9l-.5-.9v.9M23 143.3a.47 .47 0 0 1 .5 .5 .47 .47 0 0 1-.5 .4z"/>
<path d="M37.2 150.2h-.3l-.2 .2v.5l.2 .2h.3v-.4h-.2M38.1 150.2v.9l-.6-.9v.9M38.5 150.2l.4 .1 .1 .4-.2 .4h-.3zM36.7 174.9h.7M36.7 161.9h.7M37 161.7v.6M37 174.5v.7M37.2 171.8l-.2-.1-.3 .3v.4l.2 .2h.3v-.3h-.2M38.1 171.7v.9l-.6-.9v.9M38.2 174.4h-.4l-.1 .4 .4-.1 .1 .4h-.5M38.2 161.4h-.4l-.1 .4h.4l.1 .4h-.5M38.5 174.4l.2 .8 .4-.8"/>
<path d="M38.5 171.7a.48 .48 0 0 1 .5 .3 .48 .48 0 0 1-.2 .6h-.3zM38.5 161.4l.2 .9 .4-.9M39.8 167.7l.2-.3v1M39.8 168.4h.5M40.3 178.8h-.5v.6l.3 .1 .2-.1M40.3 165.8h-.5v.7h.5M40.7 167.5l.2-.1 .2 .2v.6l-.2 .2a.53 .53 0 0 1-.2-.9zM40.8 178.6l-.1 .6h.5M40.8 165.7l-.1 .6h.5M41.1 166v.6M41.1 178.9v.6M41.4 178.9l.3-.2v.8"/>
<path d="M41.4 179.5h.5M41.5 165.8l.4-.1v.8a.39 .39 0 0 1-.5-.2 .39 .39 0 0 1 .1-.5zM41.6 167.4a.48 .48 0 0 1 .4 .5 .48 .48 0 0 1-.4 .5l-.2-.2v-.6zM42.3 167.8h.3v.6M42.3 178.8l.4-.1 .1 .2-.5 .6h.5M42.3 166l.2-.3v.9M42.3 167.8v.6M42.3 166.6h.5M43 167.8h.4M43.5 167.4h-.5v1M47.5 167.7l.3-.3v1M47.5 168.4h.5"/>
<path d="M48 165.8l-.3-.1-.2 .4 .2 .5 .3-.1M48 178.8l-.3-.1a.43 .43 0 0 0-.1 .5 .43 .43 0 0 0 .4 .2M48.4 167.6l.2-.2a.48 .48 0 0 1 .3 .5 .48 .48 0 0 1-.3 .5l-.2-.2zM48.6 165.7l-.2 .6h.6M48.6 178.6l-.2 .6h.6M48.8 166v.6M48.8 178.9v.6M49.2 167.5l.3-.1 .2 .2v.6l-.2 .2a.53 .53 0 0 1-.3-.9zM49.2 178.9l.3-.2v.8M49.2 179.5h.5M49.3 165.7a.42 .42 0 0 1 .4 .5 .42 .42 0 0 1-.4 .4zM50 178.7h.5l-.3 .2 .3 .1v.4h-.5"/>
<path d="M50.1 167.8h.3v.6M50.1 165.8l.3-.1 .1 .4-.5 .5h.5M50.1 167.8v.6M50.8 167.8h.3M51.3 167.4h-.5v1M56.2 167.7l.2-.3v1M56.2 168.4h.5M56.7 165.8l-.4-.1-.1 .2v.5l.1 .2 .4-.1M56.7 178.8l-.4-.1-.1 .2v.4l.2 .2 .3-.1M57 167.5l.3-.1 .1 .2v.6l-.1 .2a.53 .53 0 0 1-.3-.9zM57.2 165.7l-.2 .6h.5M57.2 178.6l-.2 .6h.5"/>
<path d="M57.4 166v.6M57.4 178.9v.6M57.9 167.5l.1-.1a.54 .54 0 0 1 0 1l-.2-.4zM57.9 178.9l.2-.2v.8M57.9 179.5h.4M58 165.7h.2l.1 .2-.1 .7h-.2l-.1-.2zM58.6 167.8h.5v.6M58.6 165.7h.5l-.2 .4 .2 .1v.3h-.5M58.6 167.8v.6M58.9 178.6l-.3 .6h.6M59.1 178.9v.6M59.5 167.8h.2"/>
<path d="M59.8 167.4h-.3v1M64.8 166l.2-.3v.9M64.8 166.6h.4M65.3 178.8h-.5v.6l.3 .1 .2-.1M65.3 167.5l-.2-.1-.3 .2v.6h.5M65.7 165.8l.3-.1v.8a.39 .39 0 0 1-.4-.2 .39 .39 0 0 1 .1-.5zM65.8 178.6l-.1 .6h.5M65.8 167.4l-.1 .6h.5M66.1 167.8v.5M66.1 178.9v.6M66.4 178.9l.3-.2v.8M66.4 179.5h.5"/>
<path d="M66.5 165.7a.42 .42 0 0 1 .4 .5 .42 .42 0 0 1-.4 .4zM66.5 167.5l.3-.1 .1 .2-.1 .7h-.2l-.2-.3zM67.3 166.1h.3v.5M67.3 166v.6M67.4 167.4l-.1 .6h.5M67.7 178.7h-.4v.3l.3-.1 .2 .5-.2 .1-.3-.1M67.7 167.8v.5M68 166.2h.4M68.4 165.7h-.4v.9M73.4 166l.2-.3v.9M73.4 166.6h.5M74 167.5a.44 .44 0 0 0-.6 .2 .44 .44 0 0 0 .1 .6l.5-.1"/>
<path d="M74 178.8l-.5-.1a.44 .44 0 0 0-.1 .5 .44 .44 0 0 0 .6 .2M74.3 165.7a.42 .42 0 0 1 .4 .5 .42 .42 0 0 1-.4 .4zM74.5 167.4l-.3 .6h.6M74.5 178.6l-.3 .6h.6M74.6 167.8v.5M74.6 178.9v.6M75.1 178.9l.2-.2v.8M75.1 179.5h.5M75.1 165.7h.3l.1 .2-.1 .7h-.3v-.2zM75.1 167.5l.2-.1a.45 .45 0 0 1 .3 .5 .45 .45 0 0 1-.4 .4l-.1-.3zM75.9 166.1h.3v.5M75.9 166v.6"/>
<path d="M76.3 167.4h-.4v.4h.3l.2 .1-.1 .4-.4-.1M76.3 178.7l-.4 .2v.5l.3 .1 .2-.4-.2-.2-.3 .2M76.7 166.2h.2M77.1 165.7h-.4v.9M82 167.7l.3-.3v1M82 168.4h.5M82.5 178.8l-.3-.1-.2 .2v.4l.3 .2 .2-.1M82.5 165.8l-.3-.1-.2 .2v.5l.2 .2 .3-.1M83 167.4l.3 .2v.6l-.2 .2-.3-.2v-.6zM83.1 178.6l-.3 .6h.6M83.1 165.7l-.3 .6h.6M83.3 166v.6"/>
<path d="M83.3 178.9v.6M83.7 167.5l.2-.1 .2 .2v.6l-.2 .2a.53 .53 0 0 1-.2-.9zM83.7 178.9l.2-.2v.8M83.7 179.5h.5M83.8 165.7a.42 .42 0 0 1 .4 .5 .42 .42 0 0 1-.4 .4zM84.5 178.7h.5l-.4 .8M84.5 167.8h.4v.6M84.5 167.8v.6M84.9 165.7h-.3l-.1 .2v.7l.5-.1-.1-.4h-.4v.1M85.3 167.8h.3M85.7 167.4h-.4v1M90.6 178.9l.3-.3v.9"/>
<path d="M90.6 167.7l.3-.3v1M90.6 168.4h.5M90.6 179.5h.5M91.1 165.8l-.3-.1-.2 .2v.5l.2 .2 .3-.1M91.5 178.7l.2-.1 .2 .2v.6l-.2 .1a.53 .53 0 0 1-.2-.8zM91.5 167.5l.2-.1 .2 .2v.6l-.2 .2a.53 .53 0 0 1-.2-.9zM91.6 165.7l-.1 .6h.5M91.9 166v.6M92.4 178.6a.48 .48 0 0 1 .4 .5 .48 .48 0 0 1-.4 .4 .69 .69 0 0 1 0-.9zM92.4 167.4a.48 .48 0 0 1 .4 .5 .48 .48 0 0 1-.4 .5 .69 .69 0 0 1 0-1zM92.4 165.7h.3v.2v.7h-.3l-.1-.2zM93.1 179h.4v.5"/>
<path d="M93.1 167.8h.4v.6M93.1 165.7h.6l-.4 .9M93.1 167.8v.6M93.1 178.9v.6M93.8 167.8h.4M93.8 179h.4M94.3 178.6h-.5v.9M94.3 167.4h-.5v1M99.2 178.9l.2-.3v.9M99.2 179.5h.5M100.1 178.7l.2-.1a.59 .59 0 0 1 .1 .9 .53 .53 0 0 1-.3-.8zM101 178.6a.48 .48 0 0 1 .4 .5 .48 .48 0 0 1-.4 .4l-.1-.1v-.6z"/>
<path d="M101.7 179l.4-.1v.6M101.7 178.9v.6M102.5 179h.3M102.9 178.6h-.4v.9M37.2 184.7h-.3l-.2 .2v.4l.3 .2h.2v-.3h-.2M38.1 184.7v.8l-.6-.8v.8M38.5 184.7h.3a.47 .47 0 0 1 .2 .5 .47 .47 0 0 1-.5 .3zM39.8 180.6l.2-.2v.8M39.8 181.2h.5M40.8 180.4h.2l.1 .1-.1 .6a.39 .39 0 0 1-.4-.2 .39 .39 0 0 1 .1-.4zM41.5 180.4a.42 .42 0 0 1 .5 .4 .42 .42 0 0 1-.5 .4zM42.3 180.7h.3v.5"/>
<path d="M42.3 180.6v.6M43 180.8h.4M43.5 180.4h-.5v.8M47.5 180.6l.3-.2v.8M47.5 181.2h.5M48.5 180.4a.42 .42 0 0 1 .4 .4 .42 .42 0 0 1-.4 .4zM49.3 180.4h.3l.1 .1-.1 .6a.39 .39 0 0 1-.5-.2 .39 .39 0 0 1 .1-.4zM50.1 180.7l.2-.1 .1 .6M50.1 180.6v.6M50.8 180.8h.3M51.3 180.4h-.5v.8M56.2 180.6l.2-.2v.8"/>
<path d="M56.2 181.2h.5M57 180.5l.4-.1v.7a.39 .39 0 0 1-.5-.2 .39 .39 0 0 1 .1-.4zM57.9 180.5l.3-.1v.8l-.3-.1zM58.6 180.7l.3-.1 .2 .2v.4M58.6 180.6v.6M59.5 180.8h.2M59.8 180.4h-.3v.8M64.8 180.6l.2-.2v.8M64.8 181.2h.4M65.7 180.5l.3-.1v.7a.39 .39 0 0 1-.4-.2 .39 .39 0 0 1 .1-.4zM66.5 180.4a.42 .42 0 0 1 .4 .4 .42 .42 0 0 1-.4 .4zM67.3 180.7h.3v.5"/>
<path d="M67.3 180.6v.6M68 180.8h.4M68.4 180.4h-.4v.8M73.4 180.6l.2-.2v.8M73.4 181.2h.5M74.3 180.4a.42 .42 0 0 1 .4 .4 .42 .42 0 0 1-.4 .4zM75.1 180.4h.3l.1 .1-.1 .7h-.3v-.1zM75.9 180.7h.3v.5M75.9 180.6v.6M76.7 180.8h.2M77.1 180.4h-.4v.8M82 180.6l.3-.2v.8"/>
<path d="M82 181.2h.5M82.9 180.4h.3l.1 .1-.1 .7h-.3l-.1-.1zM83.7 180.5l.3-.1v.7a.39 .39 0 0 1-.4-.2 .39 .39 0 0 1 .1-.4zM84.5 180.7l.2-.1 .2 .2v.4M84.5 180.6v.6M85.3 180.8h.3M85.7 180.4h-.4v.8M91.1 180.5l-.3-.1-.2 .1v.6l.2 .1 .3-.1M91.6 180.3l-.1 .7h.5M91.9 180.6v.6M92.3 180.6l.2-.2v.8M92.3 181.2h.4"/>
<path d="M93.3 180.7l-.2-.2 .1-.1h.3l.1 .2-.5 .3 .1 .3h.3l.1-.4-.2-.1M99.8 180.5l-.4-.1-.2 .3 .2 .5 .4-.1M100.3 180.3l-.2 .7h.5M100.5 180.6v.6M100.9 180.6l.2-.2v.8M100.9 181.2h.5M102.2 180.7l-.1 .2h-.3l-.1-.4 .4-.1 .1 .1-.1 .7h-.3"/>
</g>
</svg>
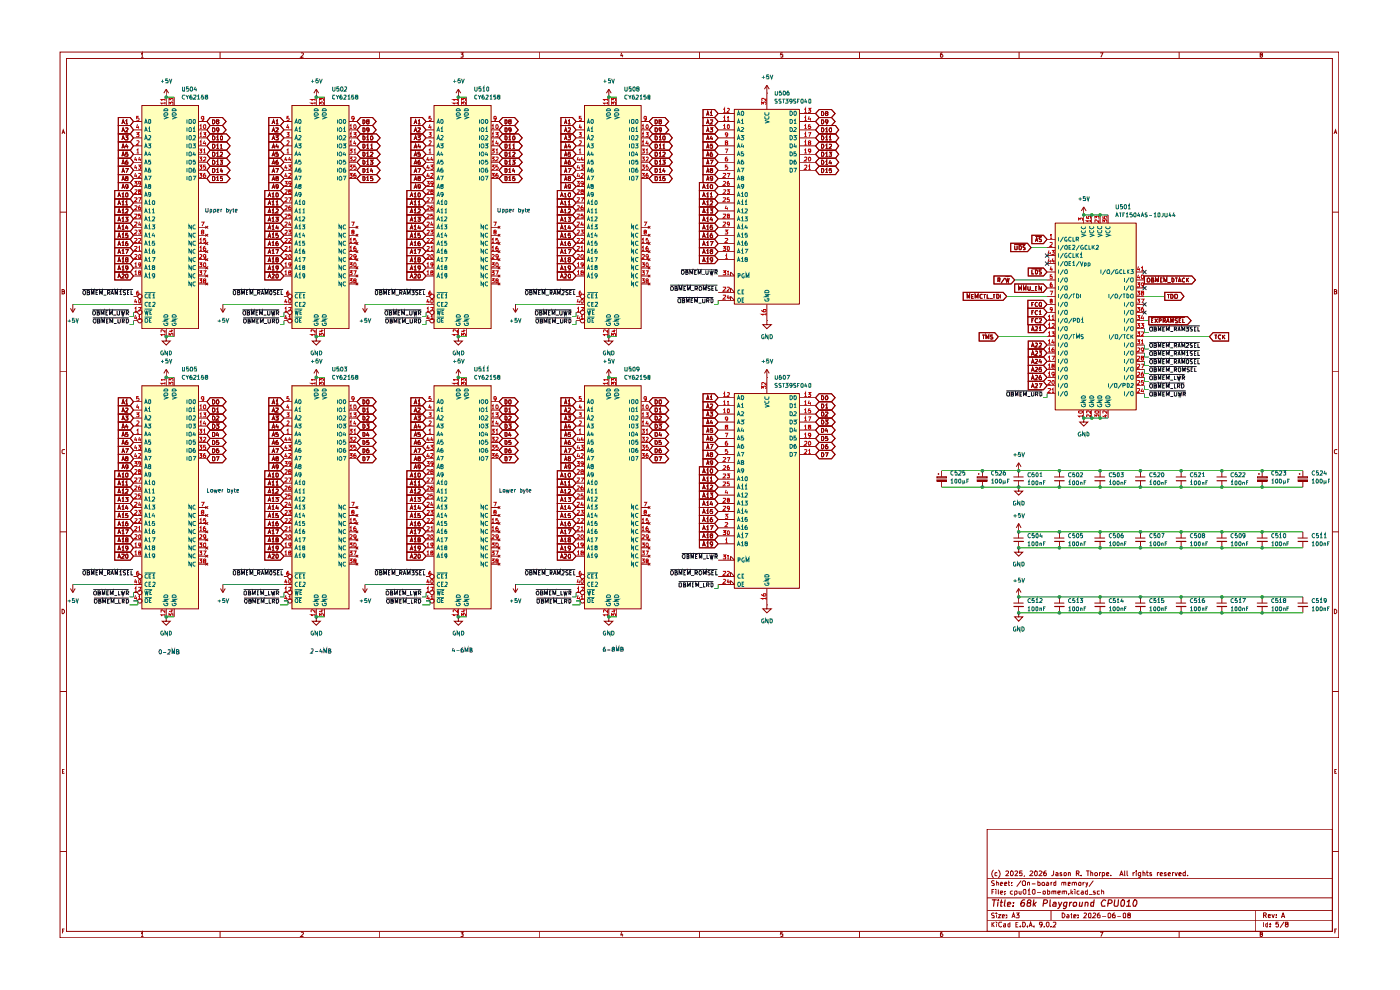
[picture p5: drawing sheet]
<svg xmlns="http://www.w3.org/2000/svg" width="297mm" height="210mm" viewBox="0 0 297 210" stroke-linecap="round" stroke-linejoin="round" font-family="sans-serif">
<g fill="none" stroke="#910000" stroke-width=".21">
<path d="M12.7 11h271.3v187.9h-271.3zM14.1 12.4h268.6v185.2h-268.6zM29.9 11.5l.3-.3v.9M29.9 12.1h.5M46.7 11v1.4M63.9 11.3l.3-.1 .2 .3-.6 .6h.6M80.6 11v1.4M97.7 11.2h.6l-.3 .4h.3v.5h-.6M114.5 11v1.4M131.9 11.2l-.2 .6h.5M132.1 11.6v.5M148.4 11v1.4"/>
<path d="M166.1 11.2h-.5v.4h.5v.5h-.5M182.3 11v1.4M199.9 11.2l-.3 .1-.1 .8h.4l.1-.1-.1-.4-.4 .1M216.2 11v1.4M233.4 11.2h.6l-.5 .9M250.1 11v1.4M267.5 11.6h-.2v-.3l.4-.1 .1 .3-.5 .2v.4h.2l.3-.1-.1-.4M13.2 28.4l.2-.8 .4 .8M13.2 28.1h.5M283 28.4l.3-.8 .3 .8M283.1 28.1h.4M12.7 45h1.4"/>
<path d="M282.7 45h1.3M12.7 78.9h1.4M13.2 61.8h.4l.1-.2-.2-.2h-.3v1l.5-.1v-.4l-.2-.1M282.7 78.9h1.3M283.1 61.8h.4l.1-.2-.2-.2h-.3v1l.5-.1v-.4l-.2-.1M13.7 95.5l-.4-.1-.1 .1v.6l.1 .1 .4-.1M283.6 95.5l-.4-.1-.1 .1v.6l.1 .1 .4-.1M12.7 112.8h1.4M282.7 112.8h1.3M13.2 129.2h.2l.3 .3v.4l-.3 .3h-.2zM283.1 129.2h.2l.3 .3v.4l-.3 .3h-.2zM12.7 146.7h1.4"/>
<path d="M282.7 146.7h1.3M13.2 163.6h.3M13.7 163.2h-.5v.8h.5M209.4 175.9h73.3v21.7h-73.3zM283.2 163.6h.2M283.6 163.2h-.4v.8h.4M12.7 180.6h1.4M13.2 197.5h.4M13.7 197.1h-.5v.9M29.9 198l.3-.3v1M29.9 198.7h.5M46.7 197.6v1.3"/>
<path d="M63.9 197.8l.3-.1 .2 .3-.6 .7h.6M80.6 197.6v1.3M97.7 197.7h.6l-.3 .4 .3 .1v.4h-.6M114.5 197.6v1.3M131.9 197.7l-.2 .6h.5M132.1 198.1v.6M148.4 197.6v1.3M166.1 197.7h-.5v.5h.5v.4h-.5M182.3 197.6v1.3M199.9 197.7l-.3 .1-.1 .8 .4 .1 .1-.2-.1-.4-.4 .1M209.4 195.2h73.3M209.4 193.2h73.3"/>
<path d="M209.4 190.5h73.3M209.4 186.4h73.3M210.4 195.6v1M210.4 189.2h.4M210.5 196l.4 .6M210.7 184.6l-.1 .1a1.11 1.11 0 0 0 .1 1.5M210.9 188.7h-.5v1M210.9 193.8l-.4-.1-.1 .1v.2l.4 .2 .1 .2v.3h-.5M210.9 186.9l-.4-.1-.1 .2v.2l.5 .4v.2h-.5M210.9 195.6l-.5 .5M211.3 188.7v.1M211.3 189v.7"/>
<path d="M211.4 193.7v.1M211.4 187.2h.4v.6M211.4 186.8v1M211.4 194v.7M211.5 195.6v.1M211.5 196v.6M211.5 185.2h-.4v.5l.4 .1M211.8 194h.5l-.5 .7h.5M211.8 188.7l.1 1M211.8 184.6l.1 .1a1.11 1.11 0 0 1-.1 1.5M212.2 189.4l.5-.1-.1-.3h-.3l-.1 .2v.3l.2 .2 .2-.1M212.2 187.5l.5-.1-.1-.2-.4 .1v.4l.4 .1"/>
<path d="M212.5 195.7l-.5-.1-.1 .2v.6l.3 .2 .3-.1M212.6 194.3h.5l-.1-.3-.4 .1v.6h.5M212.9 196h.4v.6M213.1 189.6v.1M213.1 189v.2M213.1 187.5l.5-.1-.1-.2h-.4v.6h.5M213.3 196.1l-.4 .2 .1 .3h.3M213.4 184.8h.5v.4l-.5 .6h.5M213.6 194.6v.1M213.6 194.1v.1M213.9 187.2h.3M214 186.8v.9l.2 .1"/>
<path d="M214.2 196h-.4v.5l.2 .1h.2M214.2 195.6v1M214.4 184.9l.2-.2a.52 .52 0 0 1 .4 .6 .52 .52 0 0 1-.5 .5zM214.6 187.7v.1M214.6 187.2v.1M214.7 194.7l.3-1 .3 1M214.8 194.4h.5M214.8 189h-.3l-.2 .2 .1 .4h.4M215.3 189.6l.3 .1 .2-.2-.1-.5h-.4v1M215.3 184.8l.4-.1 .2 .2-.6 .9h.6M215.5 196h.4M215.6 193.7h.6l-.3 .4 .3 .1v.4h-.6"/>
<path d="M216 195.6h-.5v1h.5M216.2 189v.5l.2 .2 .2-.1M216.2 197.6v1.3M216.4 196.5v.1M216.6 189v.7M216.6 186.8l-.9 1.3M216.8 184.7h-.5v.5h.5l-.1 .6-.4-.1M217 195.6h.3a.55 .55 0 0 1 .2 .8l-.3 .2h-.2zM217.1 186.8l.4 .2v.7h-.5a.67 .67 0 0 1 .1-.9zM217.2 188.7h.3l.1 .1v.7l-.2 .2a.63 .63 0 0 1-.2-1zM217.3 185.8v.1M218 196.5v.1"/>
<path d="M218 187.2h.4v.6M218 187.2v.6M218.1 188.9l.2-.2v1M218.1 189.7h.5M218.3 196.6l.3-1 .4 1M218.4 196.3h.5M218.5 184.8l.4-.1 .2 .4-.7 .7h.7M218.9 187.5h.8M219.2 188.7h.3l.1 .1v.7l-.3 .2a.63 .63 0 0 1-.1-1zM219.3 196.5v.1M219.5 184.8l.3-.1 .2 .2v.7l-.1 .2-.4-.1zM220 189.3h.8"/>
<path d="M220.2 186.8v1h.4v-.6h-.4M220.5 184.8l.3-.1 .3 .4-.7 .7h.7M221.1 196l-.2 .2-.4-.2 .1-.4h.4a.64 .64 0 0 1-.4 1M221.3 189.1l.4-.1 .1 .5-.2 .2-.3-.1zM221.5 196.5v.1M221.9 184.7l-.3 .1a.74 .74 0 0 0-.1 1h.4l.1-.5-.1-.1h-.4l-.1 .1M222 195.7l.4-.1 .1 .2v.6l-.2 .2-.3-.4zM222 187.2h.3l.2 .1v.5h-.5v-.3l.5-.1M222.2 189h.4l.1 .2v.3l-.2 .2-.3-.1M222.2 188.7v1M223 196.5v.1M223 187.2v.6"/>
<path d="M223 193.2v2M223.1 189.1l.5-.1v.7M223.1 189v.7M223.2 187.2h-.2v.2M223.4 195.7h.6v.3l-.6 .6h.6M223.5 184.7v.8l-.2 .3h-.2M223.6 189.2v-.2h.4v.7M224 186.8v1h-.4v-.6h.4M224 185.2l.3-.1 .1 .1v.6h-.4v-.4l.4-.1M224.4 189.4l.5-.1v-.3h-.4l-.1 .2v.3l.2 .2 .3-.1M225.2 185.2h-.3v.2l.4 .2-.1 .2h-.3M225.3 187.2h.4v.6"/>
<path d="M225.3 187.2v.6M225.3 193.7h.3l.3 .4-.2 .6h-.4zM225.3 189.1l.5-.1v.7M225.3 189v.7M225.7 187.3l.1-.1h.3v.6M225.7 185.2l.4-.1 .1 .1-.1 .6-.4-.1zM225.8 189.2v-.2h.4l.1 .7M226.4 194.1l.2-.1 .2 .2v.5h-.4v-.4h.4M226.6 187.5l.4-.1-.1-.2h-.3v.6h.4M226.6 185.2h.5v.6M226.6 185.1v.7M226.7 189.6v.1"/>
<path d="M227.1 194h.4M227.2 188.7v1M227.3 193.7v1h.2M227.3 189.3l.3 .4M227.5 187.2h.3l.2 .1v.5M227.5 187.2v.6M227.6 189l-.4 .4M227.8 194.3h.5l-.2-.3-.3 .1v.6h.4M228 187.3v-.1l.4 .1v.5M228 188.7v.1M228 189v.7M228.3 185.2h.6v-.3l-.1-.2h-.5v1.1"/>
<path d="M228.6 185.2l.3 .6M228.7 194.6v.1M228.7 194.1v.1M229 189h-.4l-.1 .2v.3l.1 .2 .4-.1M229 187.2h.3l-.1 .6h-.3l-.1-.1zM229.4 185.7v.1M229.4 189h.3l.1 .7M229.7 187.2v.6M229.8 189.3h-.3l-.2 .1 .2 .3 .3-.1M229.9 193.8l.4-.1 .2 .1-.6 .9h.6M230.1 187.2l-.4 .2M230.3 187.2l.3 .6"/>
<path d="M230.5 184.7h.6M230.8 189h-.5l-.1 .2v.3l.2 .2 .4-.1M230.8 187.2l-.5 1M230.8 188.7v1M230.8 184.7v1.1M231 189.8h.8M231.1 193.7l.3 .1-.1 .9h-.3l-.1-.2v-.7zM231.4 185.2h.4v.6M231.4 184.7v1.1M231.9 193.8l.4-.1 .1 .3-.6 .7h.6M231.9 186.8l-.9 1.3M232.3 185.2l.3-.1 .2 .1-.1 .6h-.4z"/>
<path d="M232.4 189h-.4l-.1 .2 .5 .2v.2h-.5M233.3 185.1v.7M233.3 193.7l-.3 .1-.2 .7 .2 .2 .4-.1-.1-.5h-.3l-.2 .2M233.3 189l-.5 .1v.5h.5M233.4 197.7h.6l-.5 1M233.5 185.1l-.2 .1M233.7 189.1l.4-.1v.7M233.7 188.7v1M233.8 194.3h.9M233.8 185.2l.4-.1 .2 .1-.1 .6h-.5M233.8 185.1v1M234.8 185.4l.4-.1-.1-.2-.3 .1v.6h.4"/>
<path d="M235.1 193.8l.2-.1a.52 .52 0 0 1 .4 .6 .52 .52 0 0 1-.5 .4zM235.6 185.7v.1M236.5 193.7l-.3 .1a.74 .74 0 0 0-.1 .9h.4l.1-.4-.1-.2h-.4l-.1 .2M237 194.3h.8M237.6 185.8l.3-1.1 .3 1.1M237.7 185.5h.5M238.5 193.7l.3 .1-.1 .9h-.3l-.1-.2v-.7zM238.6 184.7l.1 1.1M239.1 184.7v.9l.2 .2M239.4 194.1l-.2-.3 .4-.1 .2 .2-.1 .2-.4 .1v.5h.4l.1-.4-.2-.2M240.4 185.1v.7M240.7 185.1l-.3 .1"/>
<path d="M241 184.7v.1M241 185.1v.7M242 185.1v.8l-.1 .2h-.3M242 185.2l-.4-.1-.1 .1 .1 .6h.4M242.5 185.2l.2-.1 .2 .1v.6M242.5 184.7v1.1M243.2 185.1h.4M243.3 184.7v.9l.3 .2M244.3 185.2h-.4v.2l.4 .2v.2h-.4M245.5 185.1v.7M245.9 185.1l-.4 .1M246.1 185.4l.5-.1-.1-.2-.4 .1v.4l.1 .2h.3"/>
<path d="M247.4 185.2l-.3-.1-.1 .1 .4 .3v.3h-.4M247.8 185.4l.5-.1-.1-.2-.4 .1v.4l.1 .2h.3M248.7 185.1v.7M249 185.1l-.3 .1M249.3 185.1l.2 .7 .3-.7M250.1 185.4l.5-.1-.2-.2-.3 .1v.6h.4M250.1 197.6v1.3M251.5 184.7v1.1h-.5l-.1-.6 .2-.1 .4 .1M252 185.7v.1M266.4 193.2v4.4M267.5 198.2l-.2-.1v-.3l.4-.1 .1 .3-.5 .2v.4l.2 .1 .3-.2-.1-.3M268 195.6v1"/>
<path d="M268.1 194.1h.5v-.3l-.1-.2h-.4v1M268.3 194.1l.3 .5M268.9 196h-.4v.5l.2 .1h.2M268.9 195.6v1M269.1 194.3l.4-.1-.1-.2-.3 .1v.5h.4M269.4 196.5v.1M269.4 196h.1M269.8 194l.3 .6 .2-.6M270.8 194.6h.1M270.8 194.1h.1M271.2 195.6h-.5l-.1 .4h.6v.5l-.1 .1-.5-.1M271.9 194.6l.3-1 .3 1"/>
<path d="M271.9 194.4h.6M272.4 195.5l-.8 1.3M272.9 196l-.2-.2 .1-.2h.4l.1 .4h-.5l-.1 .2 .2 .4 .4-.1v-.4l-.2-.1M282.7 180.6h1.3M283.2 197.5h.2M283.6 197.1h-.4v.9"/>
<circle cx="221.3" cy="187.5" r=".34"/>
</g>
<g fill="none" stroke="#910000" stroke-width=".25">
<path d="M210.5 190.9h.9M210.9 190.9l-.1 1.3M211.7 191.4l-.1 .8M211.8 190.9v.1M212.2 191.4h.5M212.5 190.9l-.2 1.3h.3M213.2 190.9l-.1 1.2 .1 .1M213.7 191.8l.7-.1-.2-.3-.5 .2v.6h.5M214.9 192.1v.1M215 191.5v.1M217.4 190.9a.89 .89 0 0 0-.7 1.3h.5l.2-.5-.1-.2h-.5l-.2 .2M218.1 191.5l-.1-.1v-.3l.2-.2 .4 .1v.4l-.5 .1-.2 .2 .1 .5 .6-.1v-.4l-.2-.2"/>
<path d="M219.3 190.9l-.1 1.3M219.3 191.7l.4 .5M219.8 191.4l-.6 .5M221.4 191.6h.6l.2-.2v-.4l-.2-.1h-.6l-.1 1.3M222.8 190.9l-.1 1.3h.2M223.5 191.5l.4-.1 .2 .2-.1 .6h-.6v-.4l.6-.1M224.6 191.4l.2 .8M225.3 191.4l-.6 1.2-.3 .1M226.4 191.4l-.2 1.1-.3 .2h-.3M226.4 191.5h-.6l-.2 .5 .1 .2h.5M226.9 191.4v.8M227.4 191.4l-.5 .2"/>
<path d="M227.8 191.5h.6v.5l-.2 .2-.5-.1zM229.1 191.4l-.1 .8 .5-.1M229.7 191.4l-.2 .8M230.2 191.5l.5-.1 .1 .2v.6M230.2 191.4v.8M232.1 190.9l-.2 1.3h-.5v-.7h.6M234.6 191a.6 .6 0 0 0-.8 0 .6 .6 0 0 0-.2 .7l.2 .5 .6-.1M235.1 191.6h.7l.1-.2-.1-.4-.6-.1-.2 1.3M236.5 190.9l-.2 1.1 .2 .2 .6-.1 .2-1.2M237.9 191.1l.3-.2 .3 .1v.7l-.2 .5h-.4zM239 192.2h.8M239.1 191.3l.5-.4-.2 1.3"/>
<path d="M240.7 190.9l.5 .2v.6l-.3 .5h-.4l-.2-.5 .2-.6z"/>
</g>
<g fill="#ffb">
<path d="M223.9 47.4h17.2v39.6h-17.2z"/>
<path d="M92.1 81.8h12.1v47.4h-12.1z"/>
<path d="M155.8 23.2h13.8v41.4h-13.8z"/>
<path d="M124 22.4h12v47.3h-12z"/>
<path d="M92.1 22.4h12.1v47.3h-12.1z"/>
<path d="M155.8 83.5h13.8v41.3h-13.8z"/>
<path d="M124 81.8h12v47.4h-12z"/>
<path d="M30.1 81.8h12v47.4h-12z"/>
<path d="M61.9 81.8h12.1v47.4h-12.1z"/>
<path d="M61.9 22.4h12.1v47.3h-12.1z"/>
<path d="M30.1 22.4h12v47.3h-12z"/>
</g>
<g fill="none" stroke="#910000" stroke-width=".21">
<path d="M35.3 18.9v3.5M35.3 18.9l-.5 .9M35.3 18.9l.5 .9M67.1 18.9v3.5M67.1 18.9l-.5 .9M67.1 18.9l.5 .9M97.2 18.9v3.5M97.2 18.9l-.5 .9M97.2 18.9l.5 .9M129.2 18.9v3.5M129.2 18.9l-.6 .9M129.2 18.9l.5 .9"/>
<path d="M162.7 19.8h.1M162.7 18.1l-.5 .8M162.7 18.1l.5 .8M162.7 18.1v5.1M25.1 35.3h2.5l.7 .8-.7 .9h-2.5zM25.1 37h2.5l.7 .9-.7 .8h-2.5zM25.1 38.7h2.5l.7 .9-.7 .8h-2.5zM25.1 31.9h2.5l.7 .8-.7 .9h-2.5zM25.1 30.1h2.5l.7 .8-.7 1h-2.5zM25.1 33.6h2.5l.7 .8-.7 .9h-2.5zM25.1 24.9h2.5l.7 .9-.7 .8h-2.5zM25.1 26.6h2.5l.7 1-.7 .8h-2.5z"/>
<path d="M25.1 28.4h2.5l.7 .8-.7 .9h-2.5zM25.9 36.6l.2-.8 .4 .8M25.9 38.3l.2-.8 .4 .8M25.9 33.1l.2-.8 .4 .8M25.9 31.5l.2-.9 .4 .9M25.9 34.8l.2-.8 .4 .8M25.9 26.3l.2-.9 .4 .9M25.9 28l.2-.9 .4 .9M25.9 29.7l.2-.9 .4 .9M25.9 29.4h.5M25.9 27.7h.5M25.9 31.2h.5"/>
<path d="M25.9 32.9h.5M25.9 39.8h.5M25.9 34.7h.5M25.9 26h.5M25.9 38.1h.5M25.9 36.4h.5M26.6 35.8h.6l-.4 .8M26.6 25.6l.3-.2v.9M26.6 27.2h.5v.3l-.5 .5h.5M26.6 28.8h.5l-.2 .4h.2v.4h-.5M26.6 26.3h.5M26.8 37.8l-.2-.2 .1-.1h.3l.1 .2-.5 .3 .1 .3h.3l.1-.4-.1-.1"/>
<path d="M26.9 30.5l-.3 .6h.6M27 34l-.2 .1-.2 .6 .1 .1h.4v-.4l-.3-.1-.2 .2M27 30.9v.6M27.1 39.6l-.1 .1-.4-.1 .2-.4h.3v.6l-.4 .2M27.1 32.3h-.4l-.1 .4 .4-.1 .1 .5h-.5M28.3 25.8h1.8M28.3 27.6h1.8M28.3 29.2h1.8M28.3 30.9h1.8M28.3 32.7h1.8M28.3 34.4h1.8M28.3 36.1h1.8"/>
<path d="M28.3 37.9h1.8M28.3 39.6h1.8M30.1 22.4h12v47.3h-12zM35.3 20.6h.1M37 20.6v1.8M42.1 25.8h1.8M42.1 27.6h1.8M42.1 29.2h1.8M42.1 30.9h1.8M42.1 32.7h1.8M42.1 34.4h1.8M42.1 36.1h1.8"/>
<path d="M42.1 37.9h1.8M44.6 33.6h3.4l.8 .8-.8 .9h-3.4l-.7-.9zM44.6 37h3.4l.8 .9-.8 .8h-3.4l-.7-.8zM44.6 35.3h3.4l.8 .8-.8 .9h-3.4l-.7-.9zM44.6 24.9h2.6l.8 .9-.8 .8h-2.6l-.7-.8zM44.6 26.6h2.6l.8 1-.8 .8h-2.6l-.7-.8zM44.6 31.9h3.4l.8 .8-.8 .9h-3.4l-.7-.9zM44.6 28.4h3.4l.8 .8-.8 .9h-3.4l-.7-.9zM44.6 30.1h3.4l.8 .8-.8 1h-3.4l-.7-1zM45.1 34h.2l.3 .2v.5l-.2 .1h-.3zM45.1 37.5h.3l.2 .1v.5l-.2 .2h-.3zM45.1 35.8h.3l.2 .1v.5l-.3 .2h-.2z"/>
<path d="M45.1 25.4h.3l.2 .2v.4l-.3 .3h-.2zM45.1 27.1h.3l.2 .2v.5l-.2 .2h-.3zM45.1 32.3h.3l.2 .2v.5l-.2 .1h-.3zM45.1 28.8h.2l.3 .3v.4l-.2 .2h-.3zM45.1 30.6h.3l.2 .2v.4l-.3 .3h-.2zM45.9 34.2l.3-.2v.8M45.9 37.7l.3-.2v.8M45.9 35.9l.3-.1v.8M45.9 32.6l.3-.3v.8M45.9 29.1l.3-.3v.9M45.9 30.8l.3-.2v.9M45.9 29.7h.5"/>
<path d="M45.9 33.1h.5M45.9 38.3h.5M45.9 34.8h.5M45.9 36.6h.5M45.9 31.5h.5M46.1 25.8l-.2-.1v-.3h.5v.2l-.1 .2-.4 .1v.3l.2 .1 .3-.2-.1-.3M46.4 27.5v.1h-.4l-.1-.4 .5-.1v.2l-.1 .7h-.3M46.7 34h.5l-.3 .3 .3 .1v.4h-.5M46.8 32.4l.3-.1 .1 .3-.5 .5h.5M46.8 30.8l.1-.2v.9M46.8 31.5h.4M46.9 35.7l-.1 .6h.5"/>
<path d="M46.9 28.8l.3 .2-.1 .7h-.2l-.1-.2v-.5zM47.1 36v.6M47.2 37.5h-.4v.4h.4l-.1 .4-.3-.1M57 35.3h2.5l.7 .8-.7 .9h-2.5zM57 33.6h2.5l.7 .8-.7 .9h-2.5zM57 31.9h2.5l.7 .8-.7 .9h-2.5zM57 30.1h2.5l.7 .8-.7 1h-2.5zM57 37h2.5l.7 .9-.7 .8h-2.5zM57 38.7h2.5l.7 .9-.7 .8h-2.5zM57 24.9h2.5l.7 .9-.7 .8h-2.5zM57 26.6h2.5l.7 1-.7 .8h-2.5zM57 28.4h2.5l.7 .8-.7 .9h-2.5z"/>
<path d="M57.7 36.6l.3-.8 .3 .8M57.7 34.8l.3-.8 .3 .8M57.7 33.1l.3-.8 .3 .8M57.7 31.5l.3-.9 .3 .9M57.7 38.3l.3-.8 .3 .8M57.7 26.3l.3-.9 .3 .9M57.7 28l.3-.9 .3 .9M57.7 29.7l.3-.9 .3 .9M57.8 29.4h.4M57.8 27.7h.4M57.8 31.2h.4M57.8 32.9h.4"/>
<path d="M57.8 39.8h.4M57.8 34.7h.4M57.8 26h.4M57.8 38.1h.4M57.8 36.4h.4M58.5 35.8h.6l-.4 .8M58.5 28.8h.6l-.4 .4 .4 .1-.1 .4-.5-.1M58.5 25.6l.3-.2v.9M58.5 27.2l.5-.1 .1 .3-.6 .6h.6M58.5 26.3h.6M58.7 30.5l-.2 .6h.6M58.7 37.8l-.2-.3h.5v.3l-.5 .1 .1 .4h.4l.1-.3-.2-.2"/>
<path d="M59 34l-.5 .2v.6h.5l.1-.3-.2-.2-.4 .2M59 32.3h-.5v.4l.5-.1v.5h-.5M59 30.9v.6M59.1 39.6l-.2 .1h-.4v-.5h.4l.2 .1-.2 .7h-.3M60.2 25.8h1.7M60.2 27.6h1.7M60.2 29.2h1.7M60.2 30.9h1.7M60.2 32.7h1.7M60.2 34.4h1.7M60.2 36.1h1.7M60.2 37.9h1.7"/>
<path d="M60.2 39.6h1.7M61.9 22.4h12.1v47.3h-12.1zM67.1 20.6h.1M68.9 20.6v1.8M74 25.8h1.7M74 27.6h1.7M74 29.2h1.7M74 30.9h1.7M74 32.7h1.7M74 34.4h1.7M74 36.1h1.7M74 37.9h1.7"/>
<path d="M76.5 37h3.4l.7 .9-.7 .8h-3.4l-.8-.8zM76.5 33.6h3.4l.7 .8-.7 .9h-3.4l-.8-.9zM76.5 31.9h3.4l.7 .8-.7 .9h-3.4l-.8-.9zM76.5 30.1h3.4l.7 .8-.7 1h-3.4l-.8-1zM76.5 35.3h3.4l.7 .8-.7 .9h-3.4l-.8-.9zM76.5 26.6h2.5l.8 1-.8 .8h-2.5l-.8-.8zM76.5 28.4h3.4l.7 .8-.7 .9h-3.4l-.8-.9zM76.5 24.9h2.5l.8 .9-.8 .8h-2.5l-.8-.8zM77 37.5l.4 .1v.5l-.1 .2h-.3zM77 34l.4 .2v.5l-.1 .1h-.3zM77 32.3l.4 .2v.5l-.1 .1h-.3zM77 30.6l.4 .2v.4l-.2 .3h-.2z"/>
<path d="M77 35.8l.4 .1v.5l-.2 .2h-.2zM77 27.1l.4 .2v.5l-.1 .2h-.3zM77 28.8l.4 .3v.4l-.1 .2h-.3zM77 25.4l.4 .2v.4l-.2 .3h-.2zM77.8 37.7l.2-.2v.8M77.8 34.2l.2-.2v.8M77.8 32.6l.2-.3v.8M77.8 30.8l.2-.2v.9M77.8 35.9l.2-.1v.8M77.8 29.1l.2-.3v.9M77.8 29.7h.5M77.8 33.1h.5"/>
<path d="M77.8 38.3h.5M77.8 34.8h.5M77.8 36.6h.5M77.8 31.5h.5M77.9 25.8l-.1-.2v-.2h.5v.3l-.5 .1v.1l.1 .4 .4-.1v-.3l-.2-.1M78.3 27.5l-.1 .1h-.4v-.5l.5 .1v.6l-.5 .2M78.5 34h.6l-.3 .3 .3 .2-.1 .3h-.5M78.6 32.4l.4-.1 .1 .3-.6 .5h.6M78.6 30.8l.3-.2v.9M78.6 31.5h.5M78.8 35.7l-.2 .6h.5M78.8 28.8a.43 .43 0 0 1 .3 .5 .43 .43 0 0 1-.4 .4l-.1-.7z"/>
<path d="M79 37.5h-.4v.4l.4-.1 .1 .2-.1 .3-.4-.1M79 36v.6M87.2 24.9h2.4l.8 .9-.8 .8h-2.4zM87.2 28.4h2.4l.8 .8-.8 .9h-2.4zM87.2 26.6h2.4l.8 1-.8 .8h-2.4zM87.2 30.1h2.4l.8 .8-.8 1h-2.4zM87.2 37h2.4l.8 .9-.8 .8h-2.4zM87.2 33.6h2.4l.8 .8-.8 .9h-2.4zM87.2 38.7h2.4l.8 .9-.8 .8h-2.4zM87.2 35.3h2.4l.8 .8-.8 .9h-2.4zM87.2 31.9h2.4l.8 .8-.8 .9h-2.4zM87.8 26.3l.4-.9 .2 .9"/>
<path d="M87.8 29.7l.4-.9 .2 .9M87.8 28l.4-.9 .2 .9M87.8 31.5l.4-.9 .2 .9M87.8 38.3l.4-.8 .2 .8M87.8 34.8l.4-.8 .2 .8M87.8 36.6l.4-.8 .2 .8M87.8 33.1l.4-.8 .2 .8M87.9 29.4h.4M87.9 27.7h.4M87.9 31.2h.4M87.9 32.9h.4M87.9 39.8h.4"/>
<path d="M87.9 34.7h.4M87.9 26h.4M87.9 38.1h.4M87.9 36.4h.4M88.6 28.8h.6l-.3 .4 .3 .1-.1 .4-.5-.1M88.6 35.8h.6l-.3 .8M88.7 25.6l.2-.2v.9M88.7 27.2l.4-.1 .1 .3-.6 .6h.6M88.7 26.3h.5M88.9 30.5l-.2 .6h.5M88.9 37.8l-.2-.3h.4v.3l-.4 .1 .1 .4h.3l.1-.3-.2-.2M89.1 34l-.4 .2v.6h.4l.1-.3-.2-.2-.3 .2"/>
<path d="M89.1 32.3h-.4v.4l.4-.1 .1 .2-.1 .3h-.4M89.1 30.9v.6M89.2 39.6l-.2 .1h-.3v-.5h.3l.2 .1-.2 .7h-.2M90.4 25.8h1.7M90.4 27.6h1.7M90.4 29.2h1.7M90.4 30.9h1.7M90.4 32.7h1.7M90.4 34.4h1.7M90.4 36.1h1.7M90.4 37.9h1.7M90.4 39.6h1.7"/>
<path d="M92.1 22.4h12.1v47.3h-12.1zM97.2 20.6h.1M99 20.6v1.8M104.2 25.8h1.7M104.2 27.6h1.7M104.2 29.2h1.7M104.2 30.9h1.7M104.2 32.7h1.7M104.2 34.4h1.7M104.2 36.1h1.7M104.2 37.9h1.7M106.6 31.9h3.4l.8 .8-.8 .9h-3.4l-.7-.9z"/>
<path d="M106.6 26.6h2.6l.7 1-.7 .8h-2.6l-.7-.8zM106.6 30.1h3.4l.8 .8-.8 1h-3.4l-.7-1zM106.6 28.4h3.4l.8 .8-.8 .9h-3.4l-.7-.9zM106.6 24.9h2.6l.7 .9-.7 .8h-2.6l-.7-.8zM106.6 33.6h3.4l.8 .8-.8 .9h-3.4l-.7-.9zM106.6 35.3h3.4l.8 .8-.8 .9h-3.4l-.7-.9zM106.6 37h3.4l.8 .9-.8 .8h-3.4l-.7-.8zM107.1 32.3h.4l.1 .2-.1 .6h-.4zM107.1 27.1h.4l.1 .2-.1 .7h-.4zM107.1 30.6h.4l.1 .2v.4l-.3 .3h-.2zM107.1 28.8l.5 .3-.1 .6h-.4zM107.1 25.4h.4l.1 .2v.4l-.3 .3h-.2z"/>
<path d="M107.1 34l.5 .2-.1 .6h-.4zM107.1 35.8h.4l.1 .1v.5l-.3 .2h-.2zM107.1 37.5h.4l.1 .1-.1 .7h-.4zM107.9 32.6l.3-.3v.8M107.9 30.8l.3-.2v.9M107.9 29.1l.3-.3v.9M107.9 34.2l.3-.2v.8M107.9 35.9l.3-.1v.8M107.9 37.7l.3-.2v.8M107.9 29.7h.5M107.9 33.1h.5M107.9 38.3h.5"/>
<path d="M107.9 34.8h.5M107.9 36.6h.5M107.9 31.5h.5M108.1 25.8l-.2-.3 .5-.1v.3l-.4 .1-.1 .1 .2 .4 .3-.1v-.3l-.2-.1M108.4 27.5l-.1 .1h-.3v-.5l.4 .1v.6l-.4 .2M108.8 32.4l.4-.1 .1 .2-.5 .6h.5M108.8 30.8l.2-.2v.9M108.8 34h.5l-.4 .3 .4 .2-.1 .3h-.4M108.8 31.5h.5M108.9 28.8a.43 .43 0 0 1 .4 .5 .43 .43 0 0 1-.5 .4v-.5zM108.9 35.7l-.1 .6h.5M109.2 37.5h-.4v.4l.4-.1v.5l-.4-.1"/>
<path d="M109.2 36v.6M119 33.6h2.5l.7 .8-.7 .9h-2.5zM119 37h2.5l.7 .9-.7 .8h-2.5zM119 35.3h2.5l.7 .8-.7 .9h-2.5zM119 31.9h2.5l.7 .8-.7 .9h-2.5zM119 26.6h2.5l.7 1-.7 .8h-2.5zM119 30.1h2.5l.7 .8-.7 1h-2.5zM119 28.4h2.5l.7 .8-.7 .9h-2.5zM119 38.7h2.5l.7 .9-.7 .8h-2.5zM119 24.9h2.5l.7 .9-.7 .8h-2.5zM119.8 34.8l.2-.8 .3 .8M119.8 38.3l.2-.8 .3 .8"/>
<path d="M119.8 36.6l.2-.8 .3 .8M119.8 33.1l.2-.8 .3 .8M119.8 28l.2-.9 .3 .9M119.8 31.5l.2-.9 .3 .9M119.8 29.7l.2-.9 .3 .9M119.8 26.3l.2-.9 .3 .9M119.8 29.4h.4M119.8 27.7h.4M119.8 31.2h.4M119.8 32.9h.4M119.8 39.8h.4M119.8 34.7h.4"/>
<path d="M119.8 26h.4M119.8 38.1h.4M119.8 36.4h.4M120.5 35.8h.6l-.4 .8M120.5 27.2h.5v.3l-.5 .5h.5M120.5 28.8h.5l-.2 .4h.2v.4h-.5M120.5 25.6l.3-.2v.9M120.5 26.3h.5M120.7 37.8l-.2-.2 .1-.1h.3l.1 .2-.5 .3 .1 .3 .4-.1v-.3l-.1-.1M120.8 30.5l-.3 .6h.6M120.9 34l-.2 .1-.2 .6 .1 .1h.4v-.4l-.3-.1-.2 .2M120.9 30.9v.6"/>
<path d="M121 32.3h-.4l-.1 .4 .4-.1 .1 .5h-.5M121 39.6l-.1 .1-.4-.1 .2-.4h.3v.6l-.4 .2M122.2 25.8h1.8M122.2 27.6h1.8M122.2 29.2h1.8M122.2 30.9h1.8M122.2 32.7h1.8M122.2 34.4h1.8M122.2 36.1h1.8M122.2 37.9h1.8M122.2 39.6h1.8M124 22.4h12v47.3h-12z"/>
<path d="M129.2 20.6h.1M130.8 20.6v1.8M136 25.8h1.7M136 27.6h1.7M136 29.2h1.7M136 30.9h1.7M136 32.7h1.7M136 34.4h1.7M136 36.1h1.7M136 37.9h1.7M138.5 28.4h3.4l.7 .8-.7 .9h-3.4l-.8-.9zM138.5 31.9h3.4l.7 .8-.7 .9h-3.4l-.8-.9z"/>
<path d="M138.5 37h3.4l.7 .9-.7 .8h-3.4l-.8-.8zM138.5 33.6h3.4l.7 .8-.7 .9h-3.4l-.8-.9zM138.5 24.9h2.6l.8 .9-.8 .8h-2.6l-.8-.8zM138.5 35.3h3.4l.7 .8-.7 .9h-3.4l-.8-.9zM138.5 26.6h2.6l.8 1-.8 .8h-2.6l-.8-.8zM138.5 30.1h3.4l.7 .8-.7 1h-3.4l-.8-1zM139 28.8a.49 .49 0 0 1 .4 .3 .49 .49 0 0 1-.1 .6h-.3zM139 32.3l.4 .1 .1 .4-.2 .3h-.3zM139 37.5h.4l.1 .5-.2 .3h-.3zM139 34a.49 .49 0 0 1 .4 .3 .49 .49 0 0 1-.1 .5h-.3zM139 25.4h.3a.48 .48 0 0 1 .2 .6 .48 .48 0 0 1-.5 .3zM139 35.8h.3a.48 .48 0 0 1 .2 .5 .48 .48 0 0 1-.5 .3z"/>
<path d="M139 27.1l.4 .1 .1 .4-.2 .4h-.3zM139 30.6h.3a.48 .48 0 0 1 .2 .6 .48 .48 0 0 1-.5 .3zM139.8 29.1l.3-.3v.9M139.8 32.6l.3-.3v.8M139.8 37.7l.3-.2v.8M139.8 34.2l.3-.2v.8M139.8 35.9l.3-.1v.8M139.8 30.8l.3-.2v.9M139.8 29.7h.5M139.8 33.1h.5M139.8 38.3h.5M139.8 34.8h.5"/>
<path d="M139.8 36.6h.5M139.8 31.5h.5M140 25.8l-.2-.1v-.3h.4l.1 .2-.1 .2-.4 .1v.3l.2 .1 .3-.2-.1-.3M140.3 27.5l-.1 .1h-.3l-.1-.4 .4-.1 .1 .2-.1 .7h-.3M140.6 32.4h.5v.2l-.5 .5h.5M140.6 34h.5l-.3 .3 .3 .1v.4h-.5M140.6 30.8l.2-.2v.9M140.6 31.5h.5M140.7 28.9l.2-.1 .2 .2-.1 .7h-.2l-.2-.3zM140.8 35.7l-.2 .6h.6M141 36v.6M141.1 37.5h-.4l-.1 .4 .4-.1 .1 .4h-.5"/>
<path d="M148.4 38.7h3.2l.8 .9-.8 .8h-3.2zM149.1 28.4h2.5l.8 .8-.8 .9h-2.5zM149.1 26.6h2.5l.8 1-.8 .8h-2.5zM149.1 30.1h2.5l.8 .8-.8 1h-2.5zM149.1 31.9h2.5l.8 .8-.8 .9h-2.5zM149.1 33.6h2.5l.8 .8-.8 .9h-2.5zM149.1 24.9h2.5l.8 .9-.8 .8h-2.5zM149.1 23.2h2.5l.8 .9-.8 .8h-2.5zM149.1 37h2.5l.8 .9-.8 .8h-2.5zM149.1 35.3h2.5l.8 .8-.8 .9h-2.5zM149.1 39.8h.5M149.9 29.7l.3-.9 .2 .9"/>
<path d="M149.9 28l.3-.9 .2 .9M149.9 31.5l.3-.9 .2 .9M149.9 33.1l.3-.8 .2 .8M149.9 39.4l.3-.2v.8M149.9 34.8l.3-.8 .2 .8M149.9 26.3l.3-.9 .2 .9M149.9 24.5l.3-.8 .2 .8M149.9 38.3l.3-.8 .2 .8M149.9 36.6l.3-.8 .2 .8M150 29.4h.3M150 27.7h.3M150 31.2h.3"/>
<path d="M150 32.9h.3M150 34.7h.3M150 26h.3M150 24.3h.3M150 38.1h.3M150 36.4h.3M150.7 27.1h.5l-.3 .4 .3 .1v.3h-.5M150.7 34h.6l-.5 .8M150.7 25.4h.5v.4l-.5 .5h.5M150.7 23.9l.2-.2v.8M150.7 24.5h.5M150.7 39.2h.3l.2 .1-.1 .7h-.3l-.1-.3z"/>
<path d="M150.8 36.1l-.1-.2v-.1h.4l.1 .2-.5 .1v.2l.1 .3 .4-.1v-.3l-.2-.1M150.9 28.8l-.2 .6h.6M151.1 32.3h-.3l-.1 .7v.1h.5l-.1-.5h-.4v.2M151.1 29.2v.5M151.2 30.6h-.5v.3h.5v.5h-.5M151.2 37.8l-.1 .2h-.4v-.5h.5v.6l-.5 .2M152.4 24.1h3.4M152.4 25.8h3.4M152.4 27.6h3.4M152.4 29.2h3.4M152.4 30.9h3.4M152.4 32.7h3.4"/>
<path d="M152.4 34.4h3.4M152.4 36.1h3.4M152.4 37.9h3.4M152.4 39.6h3.4M155.8 23.2h13.8v41.3h-13.8zM169.6 24.1h3.4M169.6 25.8h3.4M169.6 27.6h3.4M169.6 29.2h3.4M169.6 30.9h3.4M169.6 32.7h3.4M169.6 34.4h3.4"/>
<path d="M169.6 36.1h3.4M173.8 31.9h3.4l.7 .8-.7 .9h-3.4l-.8-.9zM173.8 33.6h3.4l.7 .8-.7 .9h-3.4l-.8-.9zM173.8 28.4h3.4l.7 .8-.7 .9h-3.4l-.8-.9zM173.8 30.1h3.4l.7 .8-.7 1h-3.4l-.8-1zM173.8 35.3h3.4l.7 .8-.7 .9h-3.4l-.8-.9zM173.8 26.6h3.4l.7 1-.7 .8h-3.4l-.8-.8zM173.8 23.2h2.6l.8 .9-.8 .8h-2.6l-.8-.8zM173.8 24.9h2.6l.8 .9-.8 .8h-2.6l-.8-.8zM174.3 32.3l.4 .1 .1 .4-.2 .3h-.3zM174.3 34a.48 .48 0 0 1 .5 .3 .48 .48 0 0 1-.2 .5h-.3zM174.3 28.8a.48 .48 0 0 1 .5 .3 .48 .48 0 0 1-.2 .6h-.3z"/>
<path d="M174.3 30.6h.3a.48 .48 0 0 1 .2 .6 .48 .48 0 0 1-.5 .3zM174.3 35.8h.3a.48 .48 0 0 1 .2 .5 .48 .48 0 0 1-.5 .3zM174.3 27.1l.4 .1 .1 .4-.2 .4h-.3zM174.3 23.7a.48 .48 0 0 1 .5 .3 .48 .48 0 0 1-.2 .5h-.3zM174.3 25.4h.3a.48 .48 0 0 1 .2 .6 .48 .48 0 0 1-.5 .3zM175.1 32.6l.3-.3v.8M175.1 34.2l.3-.2v.8M175.1 29.1l.3-.3v.9M175.1 30.8l.3-.2v.9M175.1 35.9l.3-.1v.8M175.1 27.4l.3-.3v.9M175.1 29.7h.5"/>
<path d="M175.1 33.1h.5M175.1 34.8h.5M175.1 36.6h.5M175.1 31.5h.5M175.1 28h.5M175.3 24.1l-.2-.1v-.3h.4l.1 .2-.1 .2h-.4v.3l.5 .1v-.3l-.1-.1M175.6 25.8l-.1 .1h-.4v-.5l.5 .1-.1 .7-.3 .1M175.9 32.3h.5l-.3 .3 .3 .1v.4h-.5M175.9 29.1l.2-.3v.9M175.9 30.7h.5v.2l-.5 .6h.5M175.9 29.7h.5M176.1 27.1h.2l.1 .2-.1 .6a.39 .39 0 0 1-.4-.2 .39 .39 0 0 1 .1-.5z"/>
<path d="M176.1 34l-.2 .6h.6M176.3 34.3v.5M176.4 35.8h-.4l-.1 .3h.5v.4h-.5M24.3 55.9h3.3l.7 1-.7 .8h-3.3zM24.3 57.7h3.3l.7 .8-.7 .9h-3.3zM24.3 54.2h3.3l.7 .9-.7 .8h-3.3zM24.3 50.8h3.3l.7 .9-.7 .8h-3.3zM24.3 52.5h3.3l.7 .9-.7 .8h-3.3zM24.3 45.6h3.3l.7 .8-.7 1h-3.3zM24.3 43.9h3.3l.7 .8-.7 .9h-3.3zM24.3 47.4h3.3l.7 .8-.7 .9h-3.3zM24.3 49.1h3.3l.7 .8-.7 .9h-3.3z"/>
<path d="M24.3 40.4h3.3l.7 .9-.7 .9h-3.3zM24.3 42.2h3.3l.7 .8-.7 .9h-3.3zM25 57.3l.3-.9 .3 .9M25 59l.3-.9 .3 .9M25 55.6l.3-1 .3 1M25 52.1l.3-.8 .3 .8M25 53.8l.3-.8 .3 .8M25 46.9l.3-.8 .3 .8M25 45.2l.3-.9 .3 .9M25 48.6l.3-.8 .3 .8M25 50.4l.3-.9 .3 .9M25 41.8l.3-.9 .3 .9"/>
<path d="M25 43.5l.3-.9 .3 .9M25.1 58.7h.4M25.1 51.9h.4M25.1 50.2h.4M25.1 57h.4M25.1 48.4h.4M25.1 55.3h.4M25.1 53.5h.4M25.1 43.2h.4M25.1 46.7h.4M25.1 41.5h.4M25.1 45h.4"/>
<path d="M25.9 56.7l.2-.3v.9M25.9 58.2l.3-.1 .2 .3-.6 .6h.6M25.9 54.9l.2-.3v1M25.9 51.5l.2-.2v.8M25.9 53.2l.2-.2v.8M25.9 46.4l.2-.3v.8M25.9 44.6l.2-.3v.9M25.9 48l.2-.2v.8M25.9 49.7l.2-.2v.9M25.9 41.2l.2-.3v.9M25.9 42.9l.2-.3v.9M25.9 40l.2-.8 .4 .8"/>
<path d="M25.9 52.1h.5M25.9 48.6h.5M25.9 55.6h.5M25.9 50.4h.5M25.9 53.8h.5M25.9 43.5h.5M25.9 46.9h.5M25.9 41.8h.5M25.9 45.2h.5M25.9 57.3h.5M26.6 53h.6l-.4 .8M26.6 46.1h.5l-.2 .3 .2 .1v.4h-.5"/>
<path d="M26.6 44.4h.5v.3l-.5 .5h.5M26.6 42.9l.3-.3v.9M26.6 43.5h.5M26.7 58.2l.3-.1 .1 .2-.1 .6a.39 .39 0 0 1-.4-.2 .39 .39 0 0 1 .1-.5zM26.7 41l.3-.1 .1 .2v.5l-.1 .2a.48 .48 0 0 1-.3-.8zM26.8 55.1l-.2-.3 .2-.2 .3 .1v.3l-.4 .1-.1 .1 .2 .4 .3-.1v-.3l-.1-.1M26.9 47.8l-.3 .6h.6M27 51.3h-.2l-.2 .6 .2 .2 .3-.1-.1-.4h-.3l-.1 .2M27 48v.6M27.1 56.8l-.1 .1h-.3v-.5l.4 .1-.1 .7-.3 .1M27.1 49.5h-.4l-.1 .4h.5v.4h-.5M28.3 41.3h1.8"/>
<path d="M28.3 43h1.8M28.3 44.7h1.8M28.3 46.4h1.8M28.3 48.2h1.8M28.3 49.9h1.8M28.3 51.7h1.8M28.3 53.4h1.8M28.3 55.1h1.8M28.3 58.5h1.8M28.3 56.9h1.8M42.1 48.2h1.8M42.1 49.9h1.8"/>
<path d="M42.1 51.7h1.8M42.1 53.4h1.8M42.1 55.1h1.8M42.1 58.5h1.8M42.1 56.9h1.8M43.6 48l.6 .5M43.6 49.7l.6 .5M43.6 51.3l.6 .6M43.6 53.1l.6 .5M43.6 54.8l.6 .5M43.6 56.5l.6 .6M43.6 58.3l.6 .5"/>
<path d="M43.6 60l.6 .5M44.2 48l-.6 .5M44.2 49.7l-.6 .5M44.2 51.3l-.6 .6M44.2 53.1l-.6 .5M44.2 54.8l-.6 .5M44.2 56.5l-.6 .6M44.2 58.3l-.6 .5M44.2 60l-.6 .5M56.2 45.6h3.3l.7 .8-.7 1h-3.3zM56.2 47.4h3.3l.7 .8-.7 .9h-3.3zM56.2 52.5h3.3l.7 .9-.7 .8h-3.3z"/>
<path d="M56.2 49.1h3.3l.7 .8-.7 .9h-3.3zM56.2 50.8h3.3l.7 .9-.7 .8h-3.3zM56.2 43.9h3.3l.7 .8-.7 .9h-3.3zM56.2 55.9h3.3l.7 1-.7 .8h-3.3zM56.2 57.7h3.3l.7 .8-.7 .9h-3.3zM56.2 54.2h3.3l.7 .9-.7 .8h-3.3zM56.2 40.4h3.3l.7 .9-.7 .9h-3.3zM56.2 42.2h3.3l.7 .8-.7 .9h-3.3zM56.9 46.9l.3-.8 .2 .8M56.9 48.6l.3-.8 .2 .8M56.9 53.8l.3-.8 .2 .8M56.9 50.4l.3-.9 .2 .9"/>
<path d="M56.9 52.1l.3-.8 .2 .8M56.9 45.2l.3-.9 .2 .9M56.9 57.3l.3-.9 .2 .9M56.9 59l.3-.9 .2 .9M56.9 55.6l.3-1 .2 1M56.9 41.8l.3-.9 .2 .9M56.9 43.5l.3-.9 .2 .9M56.9 58.7h.5M56.9 51.9h.5M56.9 50.2h.5M56.9 57h.5M56.9 48.4h.5"/>
<path d="M56.9 55.3h.5M56.9 53.5h.5M56.9 43.2h.5M56.9 46.7h.5M56.9 41.5h.5M56.9 45h.5M57.7 46.4l.3-.3v.8M57.7 48l.3-.2v.8M57.7 53.2l.3-.2v.8M57.7 49.7l.3-.2v.9M57.7 51.5l.3-.2v.8M57.7 44.6l.3-.3v.9"/>
<path d="M57.7 56.7l.3-.3v.9M57.7 58.2l.3-.1 .2 .2-.5 .7h.5M57.7 54.9l.3-.3v1M57.7 40l.3-.8 .3 .8M57.7 41.2l.3-.3v.9M57.7 42.9l.3-.3v.9M57.7 52.1h.5M57.7 48.6h.5M57.7 55.6h.5M57.7 50.4h.5M57.7 53.8h.5M57.7 43.5h.5"/>
<path d="M57.7 46.9h.5M57.7 41.8h.5M57.7 45.2h.5M57.7 57.3h.5M58.5 46.1h.6l-.4 .3h.3l.1 .4-.2 .1h-.4M58.5 53h.6l-.4 .8M58.5 44.4l.4-.1 .2 .3-.6 .6h.6M58.5 42.9l.3-.3v.9M58.5 43.5h.6M58.6 40.9a.43 .43 0 0 1 .5 .4 .43 .43 0 0 1-.4 .5l-.2-.2zM58.7 47.8l-.2 .6h.6M58.7 58.1a.43 .43 0 0 1 .4 .5 .43 .43 0 0 1-.5 .4l-.1-.7z"/>
<path d="M58.7 55.1l-.2-.1v-.3l.4-.1 .2 .3-.6 .3v.3l.2 .1 .4-.2-.2-.3M59 49.5h-.5v.4l.4-.1 .2 .4-.2 .2-.4-.1M59 51.3l-.5 .1v.6l.4 .1 .2-.2-.1-.3h-.4l-.1 .2M59 48v.6M59.1 56.8l-.1 .1h-.4l-.1-.4 .5-.1 .1 .2v.3l-.5 .4M60.2 41.3h1.7M60.2 43h1.7M60.2 44.7h1.7M60.2 46.4h1.7M60.2 48.2h1.7M60.2 49.9h1.7M60.2 51.7h1.7"/>
<path d="M60.2 53.4h1.7M60.2 55.1h1.7M60.2 58.5h1.7M60.2 56.9h1.7M74 48.2h1.7M74 49.9h1.7M74 51.7h1.7M74 53.4h1.7M74 55.1h1.7M74 58.5h1.7M74 56.9h1.7M75.5 48l.5 .5"/>
<path d="M75.5 49.7l.5 .5M75.5 51.3l.5 .6M75.5 53.1l.5 .5M75.5 54.8l.5 .5M75.5 56.5l.5 .6M75.5 58.3l.5 .5M75.5 60l.5 .5M76 48l-.5 .5M76 49.7l-.5 .5M76 51.3l-.5 .6M76 53.1l-.5 .5M76 54.8l-.5 .5"/>
<path d="M76 56.5l-.5 .6M76 58.3l-.5 .5M76 60l-.5 .5M86.3 42.2h3.3l.8 .8-.8 .9h-3.3zM86.3 43.9h3.3l.8 .8-.8 .9h-3.3zM86.3 47.4h3.3l.8 .8-.8 .9h-3.3zM86.3 45.6h3.3l.8 .8-.8 1h-3.3zM86.3 40.4h3.3l.8 .9-.8 .9h-3.3zM86.3 49.1h3.3l.8 .8-.8 .9h-3.3zM86.3 50.8h3.3l.8 .9-.8 .8h-3.3zM86.3 52.5h3.3l.8 .9-.8 .8h-3.3zM86.3 54.2h3.3l.8 .9-.8 .8h-3.3z"/>
<path d="M86.3 55.9h3.3l.8 1-.8 .8h-3.3zM86.3 57.7h3.3l.8 .8-.8 .9h-3.3zM87 43.5l.3-.9 .3 .9M87 45.2l.3-.9 .3 .9M87 48.6l.3-.8 .3 .8M87 46.9l.3-.8 .3 .8M87 41.8l.3-.9 .3 .9M87 50.4l.3-.9 .3 .9M87 52.1l.3-.8 .3 .8M87 53.8l.3-.8 .3 .8M87 55.6l.3-1 .3 1M87 57.3l.3-.9 .3 .9"/>
<path d="M87 59l.3-.9 .3 .9M87.1 58.7h.4M87.1 51.9h.4M87.1 50.2h.4M87.1 57h.4M87.1 48.4h.4M87.1 55.3h.4M87.1 53.5h.4M87.1 43.2h.4M87.1 46.7h.4M87.1 41.5h.4M87.1 45h.4"/>
<path d="M87.8 42.9l.3-.3v.9M87.8 44.6l.3-.3v.9M87.8 48l.3-.2v.8M87.8 46.4l.3-.3v.8M87.8 41.2l.3-.3v.9M87.8 40l.4-.8 .2 .8M87.8 49.7l.3-.2v.9M87.8 51.5l.3-.2v.8M87.8 53.2l.3-.2v.8M87.8 54.9l.3-.3v1M87.8 56.7l.3-.3v.9M87.8 58.2h.5v.3l-.5 .5h.5"/>
<path d="M87.8 52.1h.5M87.8 48.6h.5M87.8 55.6h.5M87.8 50.4h.5M87.8 53.8h.5M87.8 43.5h.5M87.8 46.9h.5M87.8 41.8h.5M87.8 45.2h.5M87.8 57.3h.5M88.6 46.1h.6l-.3 .3 .3 .1v.3l-.2 .1h-.4M88.6 53h.6l-.3 .8"/>
<path d="M88.7 42.9l.2-.3v.9M88.7 44.4l.3-.1 .2 .3-.6 .6h.6M88.7 43.5h.5M88.8 40.9a.43 .43 0 0 1 .4 .4 .43 .43 0 0 1-.3 .5l-.2-.2zM88.9 47.8l-.2 .6h.5M88.9 55.1l-.2-.1v-.3l.3-.1 .2 .3-.5 .3v.3l.2 .1 .3-.2-.2-.3M88.9 58.1a.43 .43 0 0 1 .3 .5 .43 .43 0 0 1-.4 .4l-.1-.7zM89.1 49.5h-.4v.4l.3-.1 .2 .4-.2 .2-.3-.1M89.1 51.3l-.4 .1v.6l.3 .1 .2-.2-.1-.3h-.3l-.1 .2M89.1 48v.6M89.2 56.8l-.1 .1h-.3l-.1-.4 .4-.1 .1 .2v.3l-.4 .4M90.4 41.3h1.7"/>
<path d="M90.4 43h1.7M90.4 44.7h1.7M90.4 46.4h1.7M90.4 48.2h1.7M90.4 49.9h1.7M90.4 51.7h1.7M90.4 53.4h1.7M90.4 55.1h1.7M90.4 58.5h1.7M90.4 56.9h1.7M104.2 48.2h1.7M104.2 49.9h1.7"/>
<path d="M104.2 51.7h1.7M104.2 53.4h1.7M104.2 55.1h1.7M104.2 58.5h1.7M104.2 56.9h1.7M105.6 48l.5 .5M105.6 49.7l.5 .5M105.6 51.3l.5 .6M105.6 53.1l.5 .5M105.6 54.8l.5 .5M105.6 56.5l.5 .6M105.6 58.3l.5 .5"/>
<path d="M105.6 60l.5 .5M106.1 48l-.5 .5M106.1 49.7l-.5 .5M106.1 51.3l-.5 .6M106.1 53.1l-.5 .5M106.1 54.8l-.5 .5M106.1 56.5l-.5 .6M106.1 58.3l-.5 .5M106.1 60l-.5 .5M118.2 55.9h3.3l.7 1-.7 .8h-3.3zM118.2 57.7h3.3l.7 .8-.7 .9h-3.3zM118.2 40.4h3.3l.7 .9-.7 .9h-3.3z"/>
<path d="M118.2 42.2h3.3l.7 .8-.7 .9h-3.3zM118.2 49.1h3.3l.7 .8-.7 .9h-3.3zM118.2 47.4h3.3l.7 .8-.7 .9h-3.3zM118.2 45.6h3.3l.7 .8-.7 1h-3.3zM118.2 50.8h3.3l.7 .9-.7 .8h-3.3zM118.2 52.5h3.3l.7 .9-.7 .8h-3.3zM118.2 43.9h3.3l.7 .8-.7 .9h-3.3zM118.2 54.2h3.3l.7 .9-.7 .8h-3.3zM118.9 57.3l.3-.9 .3 .9M118.9 59l.3-.9 .3 .9M118.9 41.8l.3-.9 .3 .9M118.9 43.5l.3-.9 .3 .9"/>
<path d="M118.9 50.4l.3-.9 .3 .9M118.9 48.6l.3-.8 .3 .8M118.9 46.9l.3-.8 .3 .8M118.9 52.1l.3-.8 .3 .8M118.9 53.8l.3-.8 .3 .8M118.9 45.2l.3-.9 .3 .9M118.9 55.6l.3-1 .3 1M119 58.7h.4M119 51.9h.4M119 50.2h.4M119 57h.4M119 48.4h.4"/>
<path d="M119 55.3h.4M119 53.5h.4M119 43.2h.4M119 46.7h.4M119 41.5h.4M119 45h.4M119.8 56.7l.1-.3v.9M119.8 58.2h.4v.3l-.5 .5h.5M119.8 41.2l.1-.3v.9M119.8 42.9l.1-.3v.9M119.8 40l.2-.8 .3 .8M119.8 49.7l.1-.2v.9"/>
<path d="M119.8 48l.1-.2v.8M119.8 46.4l.1-.3v.8M119.8 51.5l.1-.2v.8M119.8 53.2l.1-.2v.8M119.8 44.6l.1-.3v.9M119.8 54.9l.1-.3v1M119.8 52.1h.4M119.8 48.6h.4M119.8 55.6h.4M119.8 50.4h.4M119.8 53.8h.4M119.8 43.5h.4"/>
<path d="M119.8 46.9h.4M119.8 41.8h.4M119.8 45.2h.4M119.8 57.3h.4M120.5 42.9l.3-.3v.9M120.5 46.1h.5l-.2 .3 .2 .1v.4h-.5M120.5 53h.6l-.4 .8M120.5 44.4h.5v.3l-.5 .5h.5M120.5 43.5h.5M120.6 58.2l.3-.1 .1 .2-.1 .6a.39 .39 0 0 1-.4-.2 .39 .39 0 0 1 .1-.5zM120.6 41l.3-.1 .1 .2v.5l-.1 .2a.48 .48 0 0 1-.3-.8zM120.7 55.1l-.2-.3 .2-.2 .3 .1v.3l-.4 .1-.1 .1 .2 .4 .3-.1v-.3l-.1-.1"/>
<path d="M120.8 47.8l-.3 .6h.6M120.9 51.3h-.2l-.2 .6 .2 .2 .3-.1-.1-.4h-.3l-.1 .2M120.9 48v.6M121 56.8l-.1 .1h-.3v-.5l.4 .1-.1 .7-.3 .1M121 49.5h-.4l-.1 .4h.5v.4h-.5M122.2 41.3h1.8M122.2 43h1.8M122.2 44.7h1.8M122.2 46.4h1.8M122.2 48.2h1.8M122.2 49.9h1.8M122.2 51.7h1.8"/>
<path d="M122.2 53.4h1.8M122.2 55.1h1.8M122.2 58.5h1.8M122.2 56.9h1.8M136 48.2h1.7M136 49.9h1.7M136 51.7h1.7M136 53.4h1.7M136 55.1h1.7M136 58.5h1.7M136 56.9h1.7M137.5 48l.5 .5"/>
<path d="M137.5 49.7l.5 .5M137.5 51.3l.5 .6M137.5 53.1l.5 .5M137.5 54.8l.5 .5M137.5 56.5l.5 .6M137.5 58.3l.5 .5M137.5 60l.5 .5M138 48l-.5 .5M138 49.7l-.5 .5M138 51.3l-.5 .6M138 53.1l-.5 .5M138 54.8l-.5 .5"/>
<path d="M138 56.5l-.5 .6M138 58.3l-.5 .5M138 60l-.5 .5M148.4 50.8h3.2l.8 .9-.8 .8h-3.2zM148.4 47.4h3.2l.8 .8-.8 .9h-3.2zM148.4 54.2h3.2l.8 .9-.8 .8h-3.2zM148.4 49.1h3.2l.8 .8-.8 .9h-3.2zM148.4 52.5h3.2l.8 .9-.8 .8h-3.2zM148.4 42.2h3.2l.8 .8-.8 .9h-3.2zM148.4 45.6h3.2l.8 .8-.8 1h-3.2zM148.4 40.4h3.2l.8 .9-.8 .9h-3.2zM148.4 43.9h3.2l.8 .8-.8 .9h-3.2z"/>
<path d="M149.1 52.1l.2-.8 .3 .8M149.1 48.6l.2-.8 .3 .8M149.1 55.6l.2-1 .3 1M149.1 50.4l.2-.9 .3 .9M149.1 53.8l.2-.8 .3 .8M149.1 43.5l.2-.9 .3 .9M149.1 46.9l.2-.8 .3 .8M149.1 41.8l.2-.9 .3 .9M149.1 40l.2-.8 .3 .8M149.1 45.2l.2-.9 .3 .9M149.1 51.9h.5M149.1 50.2h.5"/>
<path d="M149.1 48.4h.5M149.1 55.3h.5M149.1 53.5h.5M149.1 43.2h.5M149.1 46.7h.5M149.1 41.5h.5M149.1 45h.5M149.9 51.5l.3-.2v.8M149.9 48l.3-.2v.8M149.9 54.9l.3-.3v1M149.9 49.7l.3-.2v.9M149.9 53.2l.3-.2v.8"/>
<path d="M149.9 42.9l.3-.3v.9M149.9 46.4l.3-.3v.8M149.9 41.2l.3-.3v.9M149.9 44.6l.3-.3v.9M149.9 52.1h.4M149.9 48.6h.4M149.9 55.6h.4M149.9 50.4h.4M149.9 53.8h.4M149.9 43.5h.4M149.9 46.9h.4M149.9 41.8h.4"/>
<path d="M149.9 40h.4M149.9 45.2h.4M150.7 51.3h.6l-.5 .8M150.7 42.7h.5v.3l-.5 .5h.5M150.7 41.2l.2-.3v.9M150.7 44.3h.5l-.3 .4h.3v.5h-.5M150.7 41.8h.5M150.8 53.3l-.1-.2 .1-.1h.4l-.1 .3-.4 .2v.3h.4l.1-.4-.2-.1M150.9 46l-.2 .6h.6M151.1 49.5l-.3 .1-.1 .6 .1 .2 .4-.1v-.4l-.4-.1-.1 .2M151.1 46.4v.5M151.2 47.8h-.5v.4l.4-.1 .1 .5h-.5"/>
<path d="M151.2 55.1l-.4 .1-.1-.4 .1-.2 .4 .1-.1 .8-.4 .1M152.4 41.3h3.4M152.4 43h3.4M152.4 44.7h3.4M152.4 46.4h3.4M152.4 48.2h3.4M152.4 49.9h3.4M152.4 51.7h3.4M152.4 53.4h3.4M152.4 55.1h3.4M152.4 58.5h3.4l-.8-.8v.8M210.9 58.5h3.6l.8 .9-.8 .8h-3.6z"/>
<path d="M211.7 59.5l.4-.1-.1-.4h-.3v.8M211.9 59.5l.2 .3M213.1 59l-.7 1.1M213.3 59l.3 .8 .1-.6 .2 .6 .2-.8M213.3 58.7h.9M214.4 51.6h3.6l.7 .9-.7 .9h-3.6zM215.2 51.9h2.3M215.3 52.1v.9l.5-.1v-.8M216.2 52.1l.4 .1 .1 .4-.2 .4h-.3zM217.5 52.1l-.5 .1v.2l.5 .2-.1 .4h-.4M218.1 56.9h3.3l.7 .8-.7 .8h-3.3zM218.8 57h2.2"/>
<path d="M218.9 49.9h2.5l.7 .9-.7 .9h-2.5zM218.9 57.3v.8h.4M219.7 51.3l.2-.9 .3 .9M219.7 57.3l.4 .1v.6l-.2 .1h-.2zM219.7 50.2h1.3M219.7 51h.4M220.9 50.4l-.5 .1 .1 .3 .4 .1v.3h-.5M220.9 57.3h-.4l-.1 .1 .2 .3 .3 .1v.2l-.5 .1M222.1 50.8h1.8M222.1 52.5h1.8M222.1 54.2h1.8M222.1 55.9h1.8"/>
<path d="M222.1 57.7h1.8M222.1 59.4h1.8M223.9 47.3h17.1v39.6h-17.1zM229.9 45.6h.1M229.9 43.9l-.5 .8M229.9 43.9l.5 .8M229.9 43.9v3.5M231.6 45.6v1.8M233.4 45.6v1.8M235.1 45.6v1.8M241.1 57.7h1.7M241.1 59.4h1.7"/>
<path d="M242.8 58.5h10.1l.7 .9-.7 .8h-10.1zM243.5 59a.47 .47 0 0 1 .5 .3 .47 .47 0 0 1-.2 .5l-.4-.1v-.6zM244.3 59.4l.4-.1-.1-.3h-.3v.8h.4l.1-.2-.2-.2M245.1 59.8v-.8l.4 .6 .2-.6v.8M246.2 59.4h.2M246.6 59h-.4v.8h.4M246.9 59.8v-.8l.4 .6 .2-.6v.8M247.7 59.9h.7M248.6 59l.4 .2v.4l-.1 .2h-.3zM249.3 59h.5M249.6 59v.8M250 59.8l.2-.8 .4 .8"/>
<path d="M250.1 59.6h.4M251.3 59.1l-.2-.1-.3 .2v.4l.2 .2 .3-.1M251.7 59v.8M251.8 59.4l.4 .4M252.2 59l-.5 .5M14.9 65.4l.5 .8M15.4 64.6h.1M15.4 64.6v1.6M16 65.4l-.6 .8M28.3 62.9h.9M28.3 64.6h1.8M28.3 66.2h.9"/>
<path d="M28.3 68h.9M35.3 71.4v.9h.8l-.8 .9-.9-.9h.9M35.3 71.4h.1M35.3 78.4l-.5 .8M35.3 78.4l.5 .8M35.3 69.7v1.7M35.3 78.4v3.4M37 69.7v1.7M42.1 60.2h1.8M46.8 65.4l.5 .8M47.3 64.6h.1M47.3 64.6v1.6"/>
<path d="M47.8 65.4l-.5 .8M60.2 62.9h.9M60.2 64.6h1.7M60.2 66.2h.9M60.2 68h.9M67.1 71.4v.9h.8l-.8 .9-.9-.9h.9M67.1 71.4h.1M67.1 78.4l-.5 .8M67.1 78.4l.5 .8M67.1 69.7v1.7M67.1 78.4v3.4M68.9 69.7v1.7"/>
<path d="M74 60.2h1.7M76.9 65.4l.5 .8M77.4 64.6h.1M77.4 64.6v1.6M77.9 65.4l-.5 .8M90.4 62.9h.8M90.4 64.6h1.7M90.4 66.2h.8M90.4 68h.8M97.2 71.4v.9h.9l-.9 .9-.8-.9h.8M97.2 71.4h.1M97.2 69.7v1.7"/>
<path d="M97.2 78.4v3.4M97.2 78.4l-.5 .8M97.2 78.4l.5 .8M99 69.7v1.7M104.2 60.2h1.7M108.8 65.4l.5 .8M109.3 64.6h.1M109.3 64.6v1.6M109.9 65.4l-.6 .8M122.2 62.9h.9M122.2 64.6h1.8M122.2 66.2h.9"/>
<path d="M122.2 68h.9M129.2 71.4v.9h.8l-.8 .9-1-.9h1M129.2 71.4h.1M129.2 78.4l-.6 .8M129.2 78.4l.5 .8M129.2 69.7v1.7M129.2 78.4v3.4M130.8 69.7v1.7M136 60.2h1.7M152.4 62h3.4l-.8-.9v.9M152.4 63.7h3.4l-.8-.8v.8M162.7 68v.9h.9l-.9 .8-.9-.8h.9"/>
<path d="M162.7 68h.1M162.7 64.6v3.4M162.7 78.4v5.1M162.7 78.4l-.5 .8M162.7 78.4l.5 .8M204.3 62h8.5l.8 .9-.8 .8h-8.5zM205.2 63.3v-.9l.2 .6 .3-.6v.9M206.1 62.9h.4M206.5 62.4h-.4v.9h.4M206.9 63.3v-.9l.3 .6 .3-.6v.9M207.7 70.6h3.3l.8 .8-.8 .9h-3.3zM208.4 62.5l-.3-.1-.2 .2v.5l.2 .2 .3-.1"/>
<path d="M208.4 71.1h.5M208.7 62.4h.5M208.7 71.1v.8M208.9 62.4v.9M209.2 71.9v-.8l.2 .6 .4-.6v.8M209.4 62.4v.9h.4M209.9 63.4h.7M210.6 71.1h-.4l-.1 .1 .2 .3 .3 .1v.2h-.5M210.7 62.4h.4M210.9 62.4v.9M211.5 62.4l.4 .1 .1 .4-.2 .4h-.3zM212.3 62.4v.9"/>
<path d="M215.3 60.2h6.1l.7 .9-.7 .9h-6.1zM216.1 61.6v-.9l.3 .6 .3-.6v.9M217.1 61.6v-.9l.3 .6 .2-.6v.9M218.1 63.7h3.3l.7 .9-.7 .8h-3.3zM218.1 60.7v.7l.1 .2 .4-.1v-.8M218.1 65.4h3.3l.7 .8-.7 1h-3.3zM218.1 67.2h3.3l.7 .8-.7 .9h-3.3zM218.1 79.2h3.3l.7 .8-.7 .9h-3.3zM218.1 74h3.3l.7 .9-.7 .8h-3.3zM218.1 75.7h3.3l.7 1-.7 .8h-3.3zM218.1 77.5h3.3l.7 .9-.7 .8h-3.3zM218.1 68.9h3.3l.7 .8-.7 .9h-3.3z"/>
<path d="M218.1 72.3h3.3l.7 .9-.7 .8h-3.3zM218.7 61.7h.7M218.8 75.4l.3-.9 .3 .9M218.8 77.1l.3-.9 .3 .9M218.8 78.8l.3-.9 .3 .9M218.8 70.1l.3-.8 .3 .8M218.8 73.6l.3-.8 .3 .8M218.9 64.6h.3M218.9 66.2h.3M218.9 68h.3M218.9 75.1h.4M218.9 76.8h.4"/>
<path d="M218.9 78.5h.4M218.9 70h.4M218.9 73.4h.4M219.3 64.1h-.4v.9M219.3 65.9h-.4v.9M219.3 67.6h-.4v.8M219.7 79.7h.4v.3l-.5 .6h.5M219.7 74.5h.4v.4l-.5 .5h.5M219.7 76.3l.3-.1 .1 .4-.5 .5h.5M219.7 78h.4v.3l-.5 .5h.5M219.7 69.4h.4v.3l-.5 .4h.5M219.7 72.9h.4v.2l-.5 .5h.5"/>
<path d="M219.7 61.1h.2M220 60.7h-.3v.9h.3M220.1 64.2a.43 .43 0 0 0-.5 .3 .43 .43 0 0 0 .1 .5l.4-.1M220.1 66l-.4-.1a.43 .43 0 0 0-.1 .5 .43 .43 0 0 0 .5 .3M220.1 67.7l-.4-.1-.1 .3 .1 .5h.4M220.4 74.5h.5l-.2 .3 .2 .1v.4h-.5M220.4 69.6l.3-.3v.8M220.4 66.2l.3-.3v.9M220.4 72.9h.5v.2l-.5 .5h.5M220.4 67.7h.5v.2l-.5 .5h.5M220.4 70.1h.5M220.4 66.8h.5"/>
<path d="M220.5 64.2l.3-.1 .1 .2-.1 .7h-.2l-.2-.3zM220.7 76.2l-.3 .5h.6M220.8 79.6l-.2 .1-.2 .7 .2 .2 .3-.1v-.5h-.3l-.2 .1M220.8 76.5v.6M220.9 60.7v.9l-.5-.9v.9M220.9 77.9h-.4l-.1 .5 .4-.1 .1 .4h-.5M222.1 62.9h1.8M222.1 64.6h1.8M222.1 61.1h1.8M222.1 66.2h1.8M222.1 68h1.8M222.1 69.7h1.8"/>
<path d="M222.1 71.4h1.8M222.1 73.2h1.8M222.1 74.9h1.8M222.1 76.7h1.8M222.1 78.4h1.8M241.1 62.9h1.7M241.1 64.6h1.7M241.1 61.1h1.7M241.1 66.2h1.7M241.1 68h1.7M241.1 69.7h1.7M241.1 71.4h1.7"/>
<path d="M241.1 73.2h1.7M241.1 74.9h1.7M241.1 76.7h1.7M241.1 78.4h1.7M243.7 67.2h8.2l.8 .8-.8 .9h-8.2zM244.1 67.3h7.2M244.3 68h.3M244.6 67.6h-.3v.8h.3M245 67.6l.6 .8M245.6 67.6l-.6 .8M245.9 68h.3l.1-.3-.4-.1v.8M246.8 68h.4v-.4h-.4v.8"/>
<path d="M246.9 68l.4 .4M247.1 62h3.4l.7 .9-.7 .8h-3.4zM247.4 68.4l.4-.8 .2 .8M247.5 68.2h.4M247.6 62.4h.5M247.9 62.4v.9M248.4 68.4v-.8l.2 .6 .3-.6v.8M248.4 62.4l.4 .1 .1 .4-.2 .4h-.3zM249.2 62.5h.5l.1 .5-.2 .3-.4-.1zM249.8 67.6l-.5 .1v.2l.5 .3-.1 .2h-.4M250.1 68h.3M250.6 67.6h-.5v.8h.5"/>
<path d="M250.9 67.6v.8h.4M257.3 70.6h3.3v1.7h-3.3l-.7-.9zM257.7 71.1h.5M257.9 71.1v.8M258.9 71.2l-.3-.1a.43 .43 0 0 0-.1 .5 .43 .43 0 0 0 .4 .2M259.4 71.1v.8M259.5 71.4l.4 .5M259.9 71.1l-.5 .4M24.3 99.9h3.3l.7 .8-.7 .9h-3.3zM25.1 93h2.5l.7 .8-.7 .9h-2.5zM25.1 87.8h2.5l.7 .9-.7 .8h-2.5zM25.1 84.4h2.5l.7 .8-.7 .9h-2.5z"/>
<path d="M25.1 94.7h2.5l.7 .8-.7 .9h-2.5zM25.1 89.5h2.5l.7 .9-.7 .8h-2.5zM25.1 86.1h2.5l.7 .9-.7 .8h-2.5zM25.1 91.2h2.5l.7 1-.7 .8h-2.5zM25.1 98.2h2.5l.7 .8-.7 .9h-2.5zM25.1 96.4h2.5l.7 .9-.7 .9h-2.5zM25.9 94.3l.2-.9 .4 .9M25.9 89.1l.2-.8 .4 .8M25.9 85.7l.2-.9 .4 .9M25.9 96.1l.2-.9 .4 .9M25.9 90.9l.2-.9 .4 .9M25.9 87.4l.2-.8 .4 .8"/>
<path d="M25.9 92.6l.2-.9 .4 .9M25.9 99.4l.2-.8 .4 .8M25.9 97.7l.2-.8 .4 .8M25.9 99.2h.5M25.9 97.5h.5M25.9 95.8h.5M25.9 94h.5M25.9 88.9h.5M25.9 87.2h.5M25.9 90.6h.5M25.9 85.5h.5M25.9 92.3h.5"/>
<path d="M26.6 88.3h.5l-.2 .3 .2 .1v.3h-.5M26.6 85l.3-.2v.9M26.6 95.2h.6l-.4 .9M26.6 86.7h.5v.2l-.5 .5h.5M26.6 85.7h.5M26.8 97.2l-.2-.1 .1-.2 .4 .1-.1 .2-.4 .2 .1 .3h.3l.1-.4-.1-.1M26.9 90l-.3 .5h.6M27 93.4l-.2 .1-.2 .6 .1 .2 .4-.1v-.4h-.3l-.2 .1M27 90.3v.6M27.1 91.7h-.4l-.1 .5 .4-.1 .1 .4h-.5M27.1 99h-.5l.2-.4 .3 .1v.6l-.4 .1M28.3 85.2h1.8"/>
<path d="M28.3 87h1.8M28.3 88.7h1.8M28.3 90.4h1.8M28.3 92.2h1.8M28.3 93.8h1.8M28.3 95.5h1.8M28.3 97.3h1.8M28.3 99h1.8M30.1 81.8h12v47.4h-12zM35.3 80h.1M37 80v1.8M42.1 85.2h1.8"/>
<path d="M42.1 87h1.8M42.1 88.7h1.8M42.1 90.4h1.8M42.1 92.2h1.8M42.1 93.8h1.8M42.1 95.5h1.8M42.1 97.3h1.8M44.6 86.1h2.6l.8 .9-.8 .8h-2.6l-.7-.8zM44.6 87.8h2.6l.8 .9-.8 .8h-2.6l-.7-.8zM44.6 84.4h2.6l.8 .8-.8 .9h-2.6l-.7-.9zM44.6 89.5h2.6l.8 .9-.8 .8h-2.6l-.7-.8zM44.6 94.7h2.6l.8 .8-.8 .9h-2.6l-.7-.9z"/>
<path d="M44.6 96.4h2.6l.8 .9-.8 .9h-2.6l-.7-.9zM44.6 93h2.6l.8 .8-.8 .9h-2.6l-.7-.9zM44.6 91.2h2.6l.8 1-.8 .8h-2.6l-.7-.8zM45.1 86.6h.3l.2 .1v.5l-.3 .2h-.2zM45.1 88.3h.2l.3 .2v.4l-.2 .2h-.3zM45.1 84.8h.2l.3 .2v.5l-.3 .2h-.2zM45.1 90h.2l.3 .2v.4l-.3 .3h-.2zM45.1 95.2h.3l.2 .2v.4l-.3 .3h-.2zM45.1 96.9h.3l.2 .2v.5l-.2 .1h-.3zM45.1 93.4h.2l.3 .3v.4l-.2 .2h-.3zM45.1 91.7h.3l.2 .2v.5l-.2 .2h-.3zM45.8 90h.6l-.3 .3 .3 .2v.2l-.1 .2-.5-.1"/>
<path d="M45.8 96.9h.6l-.3 .8M45.9 86.8l.3-.2v.8M45.9 88.3h.4l.1 .2-.6 .6h.6M45.9 85l.2-.2a.48 .48 0 0 1 .4 .5 .48 .48 0 0 1-.4 .4l-.2-.1zM45.9 87.4h.5M46.1 91.6l-.2 .7h.5M46.4 95.2h-.4l-.1 .2v.6l.4 .1 .1-.5-.1-.1-.4 .1M46.4 93.4h-.5v.4h.4l.1 .1v.4l-.5-.1M46.4 92v.6M56.2 99.9h3.3l.7 .8-.7 .9h-3.3zM57 98.2h2.5l.7 .8-.7 .9h-2.5zM57 84.4h2.5l.7 .8-.7 .9h-2.5z"/>
<path d="M57 86.1h2.5l.7 .9-.7 .8h-2.5zM57 87.8h2.5l.7 .9-.7 .8h-2.5zM57 96.4h2.5l.7 .9-.7 .9h-2.5zM57 94.7h2.5l.7 .8-.7 .9h-2.5zM57 93h2.5l.7 .8-.7 .9h-2.5zM57 91.2h2.5l.7 1-.7 .8h-2.5zM57 89.5h2.5l.7 .9-.7 .8h-2.5zM57.7 99.4l.3-.8 .3 .8M57.7 85.7l.3-.9 .3 .9M57.7 87.4l.3-.8 .3 .8M57.7 89.1l.3-.8 .3 .8M57.7 97.7l.3-.8 .3 .8"/>
<path d="M57.7 96.1l.3-.9 .3 .9M57.7 94.3l.3-.9 .3 .9M57.7 92.6l.3-.9 .3 .9M57.7 90.9l.3-.9 .3 .9M57.8 99.2h.4M57.8 97.5h.4M57.8 95.8h.4M57.8 94h.4M57.8 88.9h.4M57.8 87.2h.4M57.8 90.6h.4M57.8 85.5h.4"/>
<path d="M57.8 92.3h.4M58.5 88.3h.6l-.4 .3h.3v.5l-.5-.1M58.5 95.2h.6l-.4 .9M58.5 85l.3-.2v.9M58.5 86.7l.5-.1 .1 .2-.6 .6h.6M58.5 85.7h.6M58.7 97.2l-.2-.2 .5-.1v.3l-.5 .1 .1 .4h.4l.1-.3-.2-.2M58.7 90l-.2 .5h.6M59 93.4l-.5 .3v.5l.5 .1 .1-.4-.2-.1-.4 .1M59 91.7h-.5v.5l.5-.1v.5l-.5-.1M59 90.3v.6M59.1 99l-.6 .1v-.4l.4-.1 .2 .2-.2 .6h-.3"/>
<path d="M60.2 85.2h1.7M60.2 87h1.7M60.2 88.7h1.7M60.2 90.4h1.7M60.2 92.2h1.7M60.2 93.8h1.7M60.2 95.5h1.7M60.2 97.3h1.7M60.2 99h1.7M61.9 81.8h12.1v47.4h-12.1zM67.1 80h.1M68.9 80v1.8"/>
<path d="M74 85.2h1.7M74 87h1.7M74 88.7h1.7M74 90.4h1.7M74 92.2h1.7M74 93.8h1.7M74 95.5h1.7M74 97.3h1.7M76.5 89.5h2.5l.8 .9-.8 .8h-2.5l-.8-.8zM76.5 86.1h2.5l.8 .9-.8 .8h-2.5l-.8-.8zM76.5 91.2h2.5l.8 1-.8 .8h-2.5l-.8-.8zM76.5 93h2.5l.8 .8-.8 .9h-2.5l-.8-.9z"/>
<path d="M76.5 84.4h2.5l.8 .8-.8 .9h-2.5l-.8-.9zM76.5 96.4h2.5l.8 .9-.8 .9h-2.5l-.8-.9zM76.5 94.7h2.5l.8 .8-.8 .9h-2.5l-.8-.9zM76.5 87.8h2.5l.8 .9-.8 .8h-2.5l-.8-.8zM77 90l.4 .2v.4l-.2 .3h-.2zM77 86.6l.4 .1v.5l-.2 .2h-.2zM77 91.7l.4 .2v.5l-.1 .2h-.3zM77 93.4l.4 .3v.4l-.1 .2h-.3zM77 84.8l.4 .2v.5l-.2 .2h-.2zM77 96.9l.4 .2v.5l-.1 .1h-.3zM77 95.2l.4 .2v.4l-.2 .3h-.2zM77 88.3l.4 .2v.4l-.1 .2h-.3z"/>
<path d="M77.8 90h.5l-.3 .3 .3 .1v.4h-.5M77.8 86.8l.2-.2v.8M77.8 96.9h.6l-.5 .8M77.8 88.3h.5v.3l-.5 .5h.5M77.8 87.4h.5M77.8 84.9l.3-.1 .2 .2v.6l-.2 .1a.53 .53 0 0 1-.3-.8zM78 91.6l-.2 .7h.6M78.2 95.2h-.3l-.1 .7 .1 .2 .4-.1v-.5h-.4l-.1 .1M78.2 92v.6M78.3 93.4h-.5v.4h.5v.4h-.5M86.3 99.9h3.3l.8 .8-.8 .9h-3.3zM87.2 98.2h2.4l.8 .8-.8 .9h-2.4z"/>
<path d="M87.2 93h2.4l.8 .8-.8 .9h-2.4zM87.2 89.5h2.4l.8 .9-.8 .8h-2.4zM87.2 96.4h2.4l.8 .9-.8 .9h-2.4zM87.2 86.1h2.4l.8 .9-.8 .8h-2.4zM87.2 94.7h2.4l.8 .8-.8 .9h-2.4zM87.2 84.4h2.4l.8 .8-.8 .9h-2.4zM87.2 87.8h2.4l.8 .9-.8 .8h-2.4zM87.2 91.2h2.4l.8 1-.8 .8h-2.4zM87.8 99.4l.4-.8 .2 .8M87.8 94.3l.4-.9 .2 .9M87.8 90.9l.4-.9 .2 .9M87.8 97.7l.4-.8 .2 .8"/>
<path d="M87.8 87.4l.4-.8 .2 .8M87.8 96.1l.4-.9 .2 .9M87.8 85.7l.4-.9 .2 .9M87.8 89.1l.4-.8 .2 .8M87.8 92.6l.4-.9 .2 .9M87.9 99.2h.4M87.9 97.5h.4M87.9 95.8h.4M87.9 94h.4M87.9 88.9h.4M87.9 87.2h.4M87.9 90.6h.4"/>
<path d="M87.9 85.5h.4M87.9 92.3h.4M88.6 95.2h.6l-.3 .9M88.6 88.3h.6l-.3 .3h.2v.5l-.5-.1M88.7 86.7l.4-.1 .1 .2-.6 .6h.6M88.7 85l.2-.2v.9M88.7 85.7h.5M88.9 90l-.2 .5h.5M88.9 97.2l-.2-.2 .4-.1v.3l-.4 .1 .1 .4h.3l.1-.1-.2-.4M89.1 93.4l-.4 .3v.5l.4 .1 .1-.4-.2-.1-.3 .1M89.1 91.7h-.4v.5l.4-.1v.5l-.4-.1M89.1 90.3v.6"/>
<path d="M89.2 99l-.5 .1v-.4l.3-.1 .2 .2-.2 .6h-.2M90.4 85.2h1.7M90.4 87h1.7M90.4 88.7h1.7M90.4 90.4h1.7M90.4 92.2h1.7M90.4 93.8h1.7M90.4 95.5h1.7M90.4 97.3h1.7M90.4 99h1.7M92.1 81.8h12.1v47.4h-12.1zM97.2 80h.1"/>
<path d="M99 80v1.8M104.2 85.2h1.7M104.2 87h1.7M104.2 88.7h1.7M104.2 90.4h1.7M104.2 92.2h1.7M104.2 93.8h1.7M104.2 95.5h1.7M104.2 97.3h1.7M106.6 96.4h2.6l.7 .9-.7 .9h-2.6l-.7-.9zM106.6 94.7h2.6l.7 .8-.7 .9h-2.6l-.7-.9zM106.6 93h2.6l.7 .8-.7 .9h-2.6l-.7-.9z"/>
<path d="M106.6 86.1h2.6l.7 .9-.7 .8h-2.6l-.7-.8zM106.6 91.2h2.6l.7 1-.7 .8h-2.6l-.7-.8zM106.6 84.4h2.6l.7 .8-.7 .9h-2.6l-.7-.9zM106.6 89.5h2.6l.7 .9-.7 .8h-2.6l-.7-.8zM106.6 87.8h2.6l.7 .9-.7 .8h-2.6l-.7-.8zM107.1 96.9h.4l.1 .2-.1 .6h-.4zM107.1 95.2h.4l.1 .2v.4l-.3 .3h-.2zM107.1 93.4l.5 .3-.1 .6h-.4zM107.1 86.6h.4l.1 .1v.5l-.3 .2h-.2zM107.1 91.7h.4l.1 .2-.1 .7h-.4zM107.1 84.8l.5 .2v.5l-.3 .2h-.2zM107.1 90l.5 .2v.4l-.3 .3h-.2z"/>
<path d="M107.1 88.3l.5 .2-.1 .6h-.4zM107.9 96.9h.6l-.4 .8M107.9 86.8l.3-.2v.8M107.9 90h.5l-.2 .3 .2 .1v.4h-.5M107.9 88.3h.5v.3l-.5 .5h.5M107.9 87.4h.5M108 84.9l.2-.1 .2 .2v.6l-.2 .1a.53 .53 0 0 1-.2-.8zM108.2 91.6l-.3 .7h.6M108.3 95.2h-.2l-.2 .7 .2 .2 .3-.1v-.5h-.3l-.2 .1M108.3 92v.6M108.4 93.4h-.4l-.1 .4h.5v.4h-.5M118.2 99.9h3.3l.7 .8-.7 .9h-3.3z"/>
<path d="M119 98.2h2.5l.7 .8-.7 .9h-2.5zM119 96.4h2.5l.7 .9-.7 .9h-2.5zM119 94.7h2.5l.7 .8-.7 .9h-2.5zM119 93h2.5l.7 .8-.7 .9h-2.5zM119 87.8h2.5l.7 .9-.7 .8h-2.5zM119 86.1h2.5l.7 .9-.7 .8h-2.5zM119 89.5h2.5l.7 .9-.7 .8h-2.5zM119 84.4h2.5l.7 .8-.7 .9h-2.5zM119 91.2h2.5l.7 1-.7 .8h-2.5zM119.8 99.4l.2-.8 .3 .8M119.8 97.7l.2-.8 .3 .8M119.8 96.1l.2-.9 .3 .9"/>
<path d="M119.8 94.3l.2-.9 .3 .9M119.8 89.1l.2-.8 .3 .8M119.8 87.4l.2-.8 .3 .8M119.8 90.9l.2-.9 .3 .9M119.8 85.7l.2-.9 .3 .9M119.8 92.6l.2-.9 .3 .9M119.8 99.2h.4M119.8 97.5h.4M119.8 95.8h.4M119.8 94h.4M119.8 88.9h.4M119.8 87.2h.4"/>
<path d="M119.8 90.6h.4M119.8 85.5h.4M119.8 92.3h.4M120.5 95.2h.6l-.4 .9M120.5 88.3h.5l-.2 .3 .2 .1v.3h-.5M120.5 86.7h.5v.2l-.5 .5h.5M120.5 85l.3-.2v.9M120.5 85.7h.5M120.7 97.2l-.2-.1 .1-.2h.3l.1 .3-.5 .2 .1 .3h.4v-.4l-.1-.1M120.8 90l-.3 .5h.6M120.9 93.4l-.2 .1-.2 .6 .1 .2 .4-.1v-.4h-.3l-.2 .1M120.9 90.3v.6"/>
<path d="M121 99h-.5l.2-.4 .3 .1v.6l-.4 .1M121 91.7h-.4l-.1 .5 .4-.1 .1 .4h-.5M122.2 85.2h1.8M122.2 87h1.8M122.2 88.7h1.8M122.2 90.4h1.8M122.2 92.2h1.8M122.2 93.8h1.8M122.2 95.5h1.8M122.2 97.3h1.8M122.2 99h1.8M124 81.8h12v47.4h-12z"/>
<path d="M129.2 80h.1M130.8 80v1.8M136 85.2h1.7M136 87h1.7M136 88.7h1.7M136 90.4h1.7M136 92.2h1.7M136 93.8h1.7M136 95.5h1.7M136 97.3h1.7M138.5 86.1h2.6l.8 .9-.8 .8h-2.6l-.8-.8zM138.5 84.4h2.6l.8 .8-.8 .9h-2.6l-.8-.9z"/>
<path d="M138.5 87.8h2.6l.8 .9-.8 .8h-2.6l-.8-.8zM138.5 91.2h2.6l.8 1-.8 .8h-2.6l-.8-.8zM138.5 89.5h2.6l.8 .9-.8 .8h-2.6l-.8-.8zM138.5 94.7h2.6l.8 .8-.8 .9h-2.6l-.8-.9zM138.5 93h2.6l.8 .8-.8 .9h-2.6l-.8-.9zM138.5 96.4h2.6l.8 .9-.8 .9h-2.6l-.8-.9zM139 86.6h.3a.47 .47 0 0 1 .2 .5 .47 .47 0 0 1-.5 .3zM139 84.8a.47 .47 0 0 1 .5 .5 .47 .47 0 0 1-.5 .4zM139 88.3a.49 .49 0 0 1 .4 .3 .49 .49 0 0 1-.1 .5h-.3zM139 91.7l.4 .1 .1 .4-.2 .4h-.3zM139 90a.47 .47 0 0 1 .5 .4 .47 .47 0 0 1-.5 .5zM139 95.2h.3a.48 .48 0 0 1 .2 .6 .48 .48 0 0 1-.5 .3z"/>
<path d="M139 93.4a.49 .49 0 0 1 .4 .3 .49 .49 0 0 1-.1 .6h-.3zM139 96.9l.4 .1 .1 .4-.2 .3h-.3zM139.7 90h.6l-.3 .3 .3 .2v.2l-.1 .2-.5-.1M139.7 96.9h.6l-.3 .8M139.8 86.8l.3-.2v.8M139.8 88.3h.4l.1 .2-.6 .6h.6M139.8 87.4h.5M140 84.8a.48 .48 0 0 1 .3 .5 .48 .48 0 0 1-.3 .4l-.2-.1v-.6zM140 91.6l-.2 .7h.5M140.2 95.2h-.3l-.1 .2v.6l.4 .1 .1-.5-.1-.1-.4 .1M140.2 93.4h-.4v.4h.4l.1 .1-.1 .4-.4-.1M140.2 92v.6"/>
<path d="M148.4 99h3.2l.8 .9-.8 .8h-3.2zM149.1 90.4h2.5l.8 .8-.8 1h-2.5zM149.1 88.7h2.5l.8 .8-.8 .9h-2.5zM149.1 92.2h2.5l.8 .8-.8 .8h-2.5zM149.1 95.5h2.5l.8 .9-.8 .9h-2.5zM149.1 97.3h2.5l.8 .9-.8 .8h-2.5zM149.1 93.8h2.5l.8 .9-.8 .8h-2.5zM149.1 85.2h2.5l.8 .9-.8 .9h-2.5zM149.1 87h2.5l.8 .8-.8 .9h-2.5zM149.1 83.5h2.5l.8 .9-.8 .8h-2.5zM149.9 91.7l.3-.8 .2 .8M149.9 90l.3-.9 .2 .9"/>
<path d="M149.9 93.4l.3-.8 .2 .8M149.9 96.9l.3-.8 .2 .8M149.9 98.6l.3-.9 .2 .9M149.9 95.2l.3-.9 .2 .9M149.9 99.7l.3-.3v1M149.9 86.6l.3-.9 .2 .9M149.9 88.3l.3-.9 .2 .9M149.9 84.8l.3-.9 .2 .9M150 91.5h.3M150 89.8h.3M150 93.2h.3M150 96.6h.3"/>
<path d="M150 98.3h.3M150 95h.3M150 86.3h.3M150 88h.3M150 84.6h.3M150.7 94.3h.6l-.5 .9M150.7 85.8h.5v.3l-.5 .5h.5M150.7 87.4h.5l-.3 .4h.3v.4h-.5M150.7 84.2l.2-.3v.9M150.7 84.8h.5M150.7 99.5l.3-.1 .2 .2v.6l-.2 .2a.53 .53 0 0 1-.3-.9zM150.8 96.4l-.1-.2v-.1h.4l.1 .2-.5 .3 .1 .3 .4-.1v-.3l-.2-.1"/>
<path d="M150.9 89.1l-.2 .6h.6M151.1 92.6h-.3l-.1 .7v.1l.5-.1-.1-.4h-.4v.2M151.1 89.4v.6M151.2 90.9h-.5v.3h.5v.4h-.5M151.2 98.1l-.1 .2h-.4v-.4l.1-.2 .4 .1v.6l-.5 .2M152.4 84.4h3.4M152.4 86.1h3.4M152.4 87.8h3.4M152.4 89.5h3.4M152.4 91.2h3.4M152.4 93h3.4M152.4 94.7h3.4"/>
<path d="M152.4 96.4h3.4M152.4 98.2h3.4M152.4 99.9h3.4M155.8 83.5h13.8v41.3h-13.8zM162.7 80h.1M169.6 84.4h3.4M169.6 86.1h3.4M169.6 87.8h3.4M169.6 89.5h3.4M169.6 91.2h3.4M169.6 93h3.4M169.6 94.7h3.4"/>
<path d="M169.6 96.4h3.4M173.8 93.8h2.6l.8 .9-.8 .8h-2.6l-.8-.8zM173.8 92.2h2.6l.8 .8-.8 .8h-2.6l-.8-.8zM173.8 88.7h2.6l.8 .8-.8 .9h-2.6l-.8-.9zM173.8 90.4h2.6l.8 .8-.8 1h-2.6l-.8-1zM173.8 95.5h2.6l.8 .9-.8 .9h-2.6l-.8-.9zM173.8 83.5h2.6l.8 .9-.8 .8h-2.6l-.8-.8zM173.8 87h2.6l.8 .8-.8 .9h-2.6l-.8-.9zM173.8 85.2h2.6l.8 .9-.8 .9h-2.6l-.8-.9zM174.3 94.3a.47 .47 0 0 1 .5 .4 .47 .47 0 0 1-.5 .5zM174.3 92.6l.4 .1 .1 .4-.2 .3h-.3zM174.3 89.1a.48 .48 0 0 1 .5 .3 .48 .48 0 0 1-.2 .6h-.3z"/>
<path d="M174.3 90.9h.3a.48 .48 0 0 1 .2 .5 .48 .48 0 0 1-.5 .3zM174.3 96.1h.3a.48 .48 0 0 1 .2 .5 .48 .48 0 0 1-.5 .3zM174.3 83.9a.48 .48 0 0 1 .5 .3 .48 .48 0 0 1-.2 .6h-.3zM174.3 87.4l.4 .1 .1 .4-.2 .4h-.3zM174.3 85.7h.3a.48 .48 0 0 1 .2 .6 .48 .48 0 0 1-.5 .3zM175 89.1h.6l-.3 .3 .3 .2v.3l-.6 .1M175 96.1h.6l-.3 .8M175.1 87.5l.5-.1v.3l-.6 .6h.6M175.1 86l.3-.3v.9M175.1 86.6h.5M175.3 90.8l-.2 .6h.5M175.3 83.9a.43 .43 0 0 1 .3 .5 .43 .43 0 0 1-.4 .4l-.1-.7z"/>
<path d="M175.6 94.3l-.5 .2v.6l.4 .1 .1-.2-.1-.4-.4 .2M175.6 92.6h-.5v.4l.5-.1v.5l-.5-.1M175.6 91.1v.6M199.8 99.9v1.2M208.4 99.9v1.2M216.1 99.9h.1M216.1 98.2l-.5 .8M216.1 98.2l.5 .8M216.1 98.2v3M218.1 80.9h3.3l.7 .9-.7 .9h-3.3zM218.8 80.6l.3-1 .3 1M218.8 82.3l.3-.9 .3 .9"/>
<path d="M218.9 80.3h.4M218.9 82h.4M219.7 81.5l.3-.1 .1 .3-.5 .6h.5M220.4 81.4h.6l-.4 .9M222.1 80h1.8M222.1 81.8h1.8M222.1 83.5h1.8M224.7 99.9v1.3M229.9 88.7v.8h.9l-.9 .9-.8-.9h.8M229.9 88.7h.1M229.9 87v1.7M231.6 87v1.7"/>
<path d="M233.4 87v1.7M233.4 99.9v1.3M235.1 87v1.7M241.1 80h1.7M241.1 81.8h1.7M241.1 83.5h1.7M241.9 99.9v1.3M250.6 99.9v1.3M259.2 99.9v1.3M267.8 99.9v1.2M276.4 99.9v1.2M24.3 115.4h3.3l.7 .8-.7 .9h-3.3z"/>
<path d="M24.3 112h3.3l.7 .8-.7 .9h-3.3zM24.3 117.1h3.3l.7 .9-.7 .8h-3.3zM24.3 113.7h3.3l.7 .8-.7 .9h-3.3zM24.3 106.8h3.3l.7 .9-.7 .8h-3.3zM24.3 108.5h3.3l.7 .8-.7 .9h-3.3zM24.3 110.2h3.3l.7 .8-.7 1h-3.3zM24.3 101.6h3.3l.7 .9-.7 .8h-3.3zM24.3 105h3.3l.7 .9-.7 .9h-3.3zM24.3 103.3h3.3l.7 .9-.7 .8h-3.3zM25 116.7l.3-.8 .3 .8M25 113.2l.3-.8 .3 .8M25 118.4l.3-.8 .3 .8"/>
<path d="M25 114.9l.3-.8 .3 .8M25 108.1l.3-.9 .3 .9M25 109.8l.3-.9 .3 .9M25 111.5l.3-.8 .3 .8M25 102.9l.3-.8 .3 .8M25 106.4l.3-.9 .3 .9M25 101.2l.3-.8 .3 .8M25 104.6l.3-.8 .3 .8M25.1 101h.4M25.1 102.7h.4M25.1 107.8h.4M25.1 106.1h.4"/>
<path d="M25.1 104.4h.4M25.1 113h.4M25.1 111.3h.4M25.1 116.5h.4M25.1 118.1h.4M25.1 114.8h.4M25.1 109.6h.4M25.9 116.1l.2-.2v.8M25.9 112.6l.2-.2v.8M25.9 117.6h.4l.1 .2-.6 .6h.6M25.9 114.3l.2-.2v.8M25.9 107.5l.2-.3v.9"/>
<path d="M25.9 109.2l.2-.3v.9M25.9 111l.2-.3v.8M25.9 102.3l.2-.2v.8M25.9 105.7l.2-.2v.9M25.9 100.5l.2-.1v.8M25.9 104l.2-.2v.8M25.9 101.2h.5M25.9 102.9h.5M25.9 108.1h.5M25.9 106.4h.5M25.9 104.6h.5M25.9 113.2h.5"/>
<path d="M25.9 111.5h.5M25.9 116.7h.5M25.9 114.9h.5M25.9 109.8h.5M26.6 112.4h.6l-.4 .8M26.6 102.3l.3-.2v.8M26.6 105.5h.5l-.2 .3 .2 .1v.4h-.5M26.6 103.8h.5v.4l-.5 .4h.5M26.6 102.9h.5M26.7 117.6h.3v.7a.39 .39 0 0 1-.4-.2 .39 .39 0 0 1 .1-.5zM26.7 100.5h.4v.5l-.1 .2-.3-.1-.1-.2zM26.8 114.5l-.2-.2 .2-.2 .3 .1v.2l-.4 .1-.1 .2 .1 .2h.4v-.3l-.1-.1"/>
<path d="M26.9 107.1l-.3 .7h.6M27 110.7h-.2l-.2 .7 .2 .1h.3v-.5h-.3l-.2 .1M27 107.5v.6M27.1 116.2l-.3 .2-.2-.2 .1-.3h.4l-.1 .7-.3 .1M27.1 108.9h-.4l-.1 .4h.5v.4h-.5M28.3 100.7h1.8M28.3 102.5h1.8M28.3 104.2h1.8M28.3 105.9h1.8M28.3 107.7h1.8M28.3 109.3h1.8M28.3 111h1.8"/>
<path d="M28.3 112.8h1.8M28.3 114.5h1.8M28.3 116.2h1.8M28.3 118h1.8M42.1 107.7h1.8M42.1 109.3h1.8M42.1 111h1.8M42.1 112.8h1.8M42.1 114.5h1.8M42.1 116.2h1.8M42.1 118h1.8M42.1 119.7h1.8"/>
<path d="M43.6 107.4l.6 .5M43.6 109.1l.6 .5M43.6 110.8l.6 .5M43.6 112.6l.6 .5M43.6 114.3l.6 .5M43.6 115.9l.6 .6M43.6 117.7l.6 .5M43.6 119.4l.6 .5M44.2 107.4l-.6 .5M44.2 109.1l-.6 .5M44.2 110.8l-.6 .5M44.2 112.6l-.6 .5"/>
<path d="M44.2 114.3l-.6 .5M44.2 115.9l-.6 .6M44.2 117.7l-.6 .5M44.2 119.4l-.6 .5M56.2 101.6h3.3l.7 .9-.7 .8h-3.3zM56.2 106.8h3.3l.7 .9-.7 .8h-3.3zM56.2 105h3.3l.7 .9-.7 .9h-3.3zM56.2 103.3h3.3l.7 .9-.7 .8h-3.3zM56.2 115.4h3.3l.7 .8-.7 .9h-3.3zM56.2 113.7h3.3l.7 .8-.7 .9h-3.3zM56.2 112h3.3l.7 .8-.7 .9h-3.3zM56.2 108.5h3.3l.7 .8-.7 .9h-3.3z"/>
<path d="M56.2 110.2h3.3l.7 .8-.7 1h-3.3zM56.2 117.1h3.3l.7 .9-.7 .8h-3.3zM56.9 101.2l.3-.8 .2 .8M56.9 102.9l.3-.8 .2 .8M56.9 108.1l.3-.9 .2 .9M56.9 106.4l.3-.9 .2 .9M56.9 104.6l.3-.8 .2 .8M56.9 116.7l.3-.8 .2 .8M56.9 114.9l.3-.8 .2 .8M56.9 113.2l.3-.8 .2 .8M56.9 109.8l.3-.9 .2 .9M56.9 111.5l.3-.8 .2 .8"/>
<path d="M56.9 118.4l.3-.8 .2 .8M56.9 101h.5M56.9 102.7h.5M56.9 107.8h.5M56.9 106.1h.5M56.9 104.4h.5M56.9 113h.5M56.9 111.3h.5M56.9 116.5h.5M56.9 118.1h.5M56.9 114.8h.5M56.9 109.6h.5"/>
<path d="M57.7 100.5l.3-.1v.8M57.7 102.3l.3-.2v.8M57.7 107.5l.3-.3v.9M57.7 105.7l.3-.2v.9M57.7 104l.3-.2v.8M57.7 116.1l.3-.2v.8M57.7 114.3l.3-.2v.8M57.7 112.6l.3-.2v.8M57.7 109.2l.3-.3v.9M57.7 111l.3-.3v.8M57.7 117.6h.4l.1 .1-.5 .7h.5M57.7 101.2h.5"/>
<path d="M57.7 102.9h.5M57.7 108.1h.5M57.7 106.4h.5M57.7 104.6h.5M57.7 113.2h.5M57.7 111.5h.5M57.7 116.7h.5M57.7 114.9h.5M57.7 109.8h.5M58.5 105.5h.6l-.4 .3 .4 .2v.2l-.2 .2-.4-.1M58.5 112.4h.6l-.4 .8M58.5 100.5l.2-.1a.43 .43 0 0 1 .4 .4 .43 .43 0 0 1-.4 .4l-.2-.2z"/>
<path d="M58.5 102.3l.3-.2v.8M58.5 103.8h.4l.2 .2-.6 .6h.6M58.5 102.9h.6M58.6 117.6a.42 .42 0 0 1 .5 .4 .42 .42 0 0 1-.5 .4zM58.7 107.1l-.2 .7h.6M58.7 114.5l-.2-.1v-.2l.4-.1 .2 .2-.6 .3v.3l.6-.1-.2-.3M59 108.9h-.5v.4h.4l.2 .4h-.6M59 110.7l-.5 .2v.6h.4l.2-.4-.2-.1-.4 .1M59 107.5v.6M59.1 116.2l-.4 .2-.2-.1v-.4h.5l.1 .1-.2 .6-.3 .1M60.2 100.7h1.7M60.2 102.5h1.7"/>
<path d="M60.2 104.2h1.7M60.2 105.9h1.7M60.2 107.7h1.7M60.2 109.3h1.7M60.2 111h1.7M60.2 112.8h1.7M60.2 114.5h1.7M60.2 116.2h1.7M60.2 118h1.7M74 107.7h1.7M74 109.3h1.7M74 111h1.7"/>
<path d="M74 112.8h1.7M74 114.5h1.7M74 116.2h1.7M74 118h1.7M74 119.7h1.7M75.5 107.4l.5 .5M75.5 109.1l.5 .5M75.5 110.8l.5 .5M75.5 112.6l.5 .5M75.5 114.3l.5 .5M75.5 115.9l.5 .6M75.5 117.7l.5 .5"/>
<path d="M75.5 119.4l.5 .5M76 107.4l-.5 .5M76 109.1l-.5 .5M76 110.8l-.5 .5M76 112.6l-.5 .5M76 114.3l-.5 .5M76 115.9l-.5 .6M76 117.7l-.5 .5M76 119.4l-.5 .5M86.3 112h3.3l.8 .8-.8 .9h-3.3zM86.3 113.7h3.3l.8 .8-.8 .9h-3.3zM86.3 115.4h3.3l.8 .8-.8 .9h-3.3z"/>
<path d="M86.3 117.1h3.3l.8 .9-.8 .8h-3.3zM86.3 110.2h3.3l.8 .8-.8 1h-3.3zM86.3 108.5h3.3l.8 .8-.8 .9h-3.3zM86.3 103.3h3.3l.8 .9-.8 .8h-3.3zM86.3 101.6h3.3l.8 .9-.8 .8h-3.3zM86.3 105h3.3l.8 .9-.8 .9h-3.3zM86.3 106.8h3.3l.8 .9-.8 .8h-3.3zM87 113.2l.3-.8 .3 .8M87 114.9l.3-.8 .3 .8M87 116.7l.3-.8 .3 .8M87 118.4l.3-.8 .3 .8M87 111.5l.3-.8 .3 .8"/>
<path d="M87 109.8l.3-.9 .3 .9M87 104.6l.3-.8 .3 .8M87 102.9l.3-.8 .3 .8M87 101.2l.3-.8 .3 .8M87 106.4l.3-.9 .3 .9M87 108.1l.3-.9 .3 .9M87.1 101h.4M87.1 102.7h.4M87.1 107.8h.4M87.1 106.1h.4M87.1 104.4h.4M87.1 113h.4"/>
<path d="M87.1 111.3h.4M87.1 116.5h.4M87.1 118.1h.4M87.1 114.8h.4M87.1 109.6h.4M87.8 112.6l.3-.2v.8M87.8 114.3l.3-.2v.8M87.8 116.1l.3-.2v.8M87.8 117.6h.5v.3l-.5 .5h.5M87.8 111l.3-.3v.8M87.8 109.2l.3-.3v.9M87.8 104l.3-.2v.8"/>
<path d="M87.8 102.3l.3-.2v.8M87.8 100.5l.3-.1v.8M87.8 105.7l.3-.2v.9M87.8 107.5l.3-.3v.9M87.8 101.2h.5M87.8 102.9h.5M87.8 108.1h.5M87.8 106.4h.5M87.8 104.6h.5M87.8 113.2h.5M87.8 111.5h.5M87.8 116.7h.5"/>
<path d="M87.8 114.9h.5M87.8 109.8h.5M88.6 112.4h.6l-.3 .8M88.6 105.5h.6l-.3 .3 .3 .2v.2l-.2 .2-.4-.1M88.7 103.8h.3l.2 .2-.6 .6h.6M88.7 102.3l.2-.2v.8M88.7 100.5l.2-.1a.43 .43 0 0 1 .3 .4 .43 .43 0 0 1-.3 .4l-.2-.2zM88.7 102.9h.5M88.8 117.6a.42 .42 0 0 1 .4 .4 .42 .42 0 0 1-.4 .4zM88.9 114.5l-.2-.1v-.2l.3-.1 .2 .2-.5 .3v.3l.5-.1-.2-.3M88.9 107.1l-.2 .7h.5M89.1 110.7l-.4 .2v.6h.3l.2-.4-.2-.1-.3 .1"/>
<path d="M89.1 108.9h-.4v.4h.3l.2 .4h-.5M89.1 107.5v.6M89.2 116.2l-.2 .2-.3-.1v-.4h.4l.1 .1-.2 .6-.2 .1M90.4 100.7h1.7M90.4 102.5h1.7M90.4 104.2h1.7M90.4 105.9h1.7M90.4 107.7h1.7M90.4 109.3h1.7M90.4 111h1.7M90.4 112.8h1.7M90.4 114.5h1.7"/>
<path d="M90.4 116.2h1.7M90.4 118h1.7M104.2 107.7h1.7M104.2 109.3h1.7M104.2 111h1.7M104.2 112.8h1.7M104.2 114.5h1.7M104.2 116.2h1.7M104.2 118h1.7M104.2 119.7h1.7M105.6 107.4l.5 .5M105.6 109.1l.5 .5"/>
<path d="M105.6 110.8l.5 .5M105.6 112.6l.5 .5M105.6 114.3l.5 .5M105.6 115.9l.5 .6M105.6 117.7l.5 .5M105.6 119.4l.5 .5M106.1 107.4l-.5 .5M106.1 109.1l-.5 .5M106.1 110.8l-.5 .5M106.1 112.6l-.5 .5M106.1 114.3l-.5 .5M106.1 115.9l-.5 .6"/>
<path d="M106.1 117.7l-.5 .5M106.1 119.4l-.5 .5M118.2 101.6h3.3l.7 .9-.7 .8h-3.3zM118.2 106.8h3.3l.7 .9-.7 .8h-3.3zM118.2 105h3.3l.7 .9-.7 .9h-3.3zM118.2 103.3h3.3l.7 .9-.7 .8h-3.3zM118.2 112h3.3l.7 .8-.7 .9h-3.3zM118.2 110.2h3.3l.7 .8-.7 1h-3.3zM118.2 115.4h3.3l.7 .8-.7 .9h-3.3zM118.2 117.1h3.3l.7 .9-.7 .8h-3.3zM118.2 113.7h3.3l.7 .8-.7 .9h-3.3zM118.2 108.5h3.3l.7 .8-.7 .9h-3.3z"/>
<path d="M118.9 101.2l.3-.8 .3 .8M118.9 102.9l.3-.8 .3 .8M118.9 108.1l.3-.9 .3 .9M118.9 106.4l.3-.9 .3 .9M118.9 104.6l.3-.8 .3 .8M118.9 113.2l.3-.8 .3 .8M118.9 111.5l.3-.8 .3 .8M118.9 116.7l.3-.8 .3 .8M118.9 118.4l.3-.8 .3 .8M118.9 114.9l.3-.8 .3 .8M118.9 109.8l.3-.9 .3 .9M119 101h.4"/>
<path d="M119 102.7h.4M119 107.8h.4M119 106.1h.4M119 104.4h.4M119 113h.4M119 111.3h.4M119 116.5h.4M119 118.1h.4M119 114.8h.4M119 109.6h.4M119.8 100.5l.1-.1v.8M119.8 102.3l.1-.2v.8"/>
<path d="M119.8 107.5l.1-.3v.9M119.8 105.7l.1-.2v.9M119.8 104l.1-.2v.8M119.8 112.6l.1-.2v.8M119.8 111l.1-.3v.8M119.8 116.1l.1-.2v.8M119.8 117.6h.3l.1 .3-.5 .5h.5M119.8 114.3l.1-.2v.8M119.8 109.2l.1-.3v.9M119.8 101.2h.4M119.8 102.9h.4M119.8 108.1h.4"/>
<path d="M119.8 106.4h.4M119.8 104.6h.4M119.8 113.2h.4M119.8 111.5h.4M119.8 116.7h.4M119.8 114.9h.4M119.8 109.8h.4M120.5 102.3l.3-.2v.8M120.5 105.5h.5l-.2 .3 .2 .1v.4h-.5M120.5 103.8h.5v.4l-.5 .4h.5M120.5 112.4h.6l-.4 .8M120.5 102.9h.5"/>
<path d="M120.6 100.5h.4v.5l-.1 .2-.3-.1zM120.6 117.6h.3v.7a.39 .39 0 0 1-.4-.2 .39 .39 0 0 1 .1-.5zM120.7 114.5l-.2-.2 .2-.2 .3 .1v.2l-.4 .1-.1 .2 .1 .2h.4v-.3l-.1-.1M120.8 107.1l-.3 .7h.6M120.9 110.7h-.2l-.2 .7 .2 .1h.3v-.5h-.3l-.2 .1M120.9 107.5v.6M121 116.2l-.3 .2-.2-.2 .1-.3h.4l-.1 .7-.3 .1M121 108.9h-.4l-.1 .4h.5v.4h-.5M122.2 100.7h1.8M122.2 102.5h1.8M122.2 104.2h1.8M122.2 105.9h1.8"/>
<path d="M122.2 107.7h1.8M122.2 109.3h1.8M122.2 111h1.8M122.2 112.8h1.8M122.2 114.5h1.8M122.2 116.2h1.8M122.2 118h1.8M136 107.7h1.7M136 109.3h1.7M136 111h1.7M136 112.8h1.7M136 114.5h1.7"/>
<path d="M136 116.2h1.7M136 118h1.7M136 119.7h1.7M137.5 107.4l.5 .5M137.5 109.1l.5 .5M137.5 110.8l.5 .5M137.5 112.6l.5 .5M137.5 114.3l.5 .5M137.5 115.9l.5 .6M137.5 117.7l.5 .5M137.5 119.4l.5 .5M138 107.4l-.5 .5"/>
<path d="M138 109.1l-.5 .5M138 110.8l-.5 .5M138 112.6l-.5 .5M138 114.3l-.5 .5M138 115.9l-.5 .6M138 117.7l-.5 .5M138 119.4l-.5 .5M148.4 114.5h3.2l.8 .9-.8 .8h-3.2zM148.4 109.3h3.2l.8 .9-.8 .8h-3.2zM148.4 111h3.2l.8 1-.8 .8h-3.2zM148.4 107.7h3.2l.8 .8-.8 .8h-3.2zM148.4 112.8h3.2l.8 .9-.8 .8h-3.2z"/>
<path d="M148.4 104.2h3.2l.8 .8-.8 .9h-3.2zM148.4 100.7h3.2l.8 .9-.8 .9h-3.2zM148.4 102.5h3.2l.8 .8-.8 .9h-3.2zM148.4 105.9h3.2l.8 .9-.8 .9h-3.2zM149.1 115.9l.2-1 .3 1M149.1 110.7l.2-.9 .3 .9M149.1 112.4l.2-.9 .3 .9M149.1 108.9l.2-.8 .3 .8M149.1 114.1l.2-.9 .3 .9M149.1 100.4l.2-1 .3 1M149.1 105.5l.2-.9 .3 .9M149.1 102.1l.2-.9 .3 .9"/>
<path d="M149.1 103.8l.2-.9 .3 .9M149.1 107.2l.2-.8 .3 .8M149.1 115.6h.5M149.1 110.4h.5M149.1 112.1h.5M149.1 108.7h.5M149.1 113.8h.5M149.1 100.1h.5M149.1 105.3h.5M149.1 101.8h.5M149.1 103.5h.5M149.1 107h.5"/>
<path d="M149.9 115.2l.3-.3v1M149.9 110l.3-.2v.9M149.9 111.8l.3-.3v.9M149.9 108.3l.3-.2v.8M149.9 113.5l.3-.3v.9M149.9 104.9l.3-.3v.9M149.9 101.5l.3-.3v.9M149.9 103.2l.3-.3v.9M149.9 106.6l.3-.2v.8M149.9 115.9h.4M149.9 110.7h.4M149.9 112.4h.4"/>
<path d="M149.9 108.9h.4M149.9 114.1h.4M149.9 100.4h.4M149.9 105.5h.4M149.9 102.1h.4M149.9 103.8h.4M149.9 107.2h.4M150.7 111.5h.6l-.5 .9M150.7 104.6h.5l-.3 .3 .3 .1v.4h-.5M150.7 101.5l.2-.3v.9M150.7 103h.5v.2l-.5 .6h.5M150.7 102.1h.5"/>
<path d="M150.8 113.6l-.1-.1 .1-.3 .4 .1v.3h-.4l-.1 .1v.4h.4l.1-.4-.2-.1M150.9 106.3l-.2 .7h.6M151.1 109.8l-.3 .1-.1 .6 .1 .2 .4-.1v-.4l-.4-.1-.1 .2M151.1 106.6v.6M151.2 115.4l-.4 .1-.1-.4 .1-.2 .4 .1-.1 .8-.4 .1M151.2 108.1h-.5v.4l.4-.1 .1 .4h-.5M152.4 118.8h3.4l-.8-.8v.8M152.4 101.6h3.4M152.4 103.3h3.4M152.4 105h3.4M152.4 106.8h3.4M152.4 108.5h3.4"/>
<path d="M152.4 110.2h3.4M152.4 112h3.4M152.4 113.7h3.4M152.4 115.4h3.4M198.8 101.1h2v.3h-2zM198.8 101.8h2v.3h-2zM198.9 100.5h.4M199.1 100.4v.3M199.8 102.1v1.2M207.3 101.1h2.1v.3h-2.1zM207.3 101.8h2.1v.3h-2.1zM207.5 100.5h.3"/>
<path d="M207.6 100.4v.3M208.4 102.1v1.2M215.1 114.1h2M215.1 101.2h2M216.1 103.3v.9h.9l-.9 .8-.8-.8h.8M216.1 103.3h.1M216.1 112.8h.1M216.1 116.2v.9h.9l-.9 .9-.8-.9h.8M216.1 116.2h.1M216.1 102v1.3M216.1 111v3.2M216.1 114.8v1.4"/>
<path d="M216.1 111l-.5 1M216.1 111l.5 1M223.7 114.1h2M223.7 101.2h2M224.7 102v1.3M224.7 112.8v1.4M224.7 114.8v1.4M232.2 114.1h2.2M232.2 101.2h2.2M233.4 102v1.3M233.4 112.8v1.4M233.4 114.8v1.4"/>
<path d="M240.9 114.1h2M240.9 101.2h2M241.9 102v1.3M241.9 112.8v1.4M241.9 114.8v1.4M249.5 114.1h2M249.5 101.2h2M250.6 102v1.3M250.6 112.8v1.4M250.6 114.8v1.4M258.1 114.1h2.1M258.1 101.2h2.1"/>
<path d="M259.2 102v1.3M259.2 112.8v1.4M259.2 114.8v1.4M266.7 114.1h2.1M266.7 101.1h2.2v.3h-2.2zM266.7 101.8h2.2v.3h-2.2zM266.9 100.5h.3M267.1 100.4v.3M267.8 102.1v1.2M267.8 112.8v1.4M267.8 114.8v1.4M275.3 114.1h2.1"/>
<path d="M275.4 101.1h2v.3h-2zM275.4 101.8h2v.3h-2zM275.5 100.5h.4M275.7 100.4v.3M276.4 102.1v1.2M276.4 112.8v1.4M276.4 114.8v1.4M14.9 124.8l.5 .9M15.4 124h.1M15.4 124v1.7M16 124.8l-.6 .9M28.3 122.3h.9"/>
<path d="M28.3 124h1.8M28.3 125.7h.9M28.3 127.5h.9M35.3 130.8v1h.8l-.8 .8-.9-.8h.9M35.3 130.8h.1M35.3 129.2v1.6M37 129.2v1.6M46.8 124.8l.5 .9M47.3 124h.1M47.3 124v1.7M47.8 124.8l-.5 .9M60.2 122.3h.9"/>
<path d="M60.2 124h1.7M60.2 125.7h.9M60.2 127.5h.9M67.1 130.8v1h.8l-.8 .8-.9-.8h.9M67.1 130.8h.1M67.1 129.2v1.6M68.9 129.2v1.6M76.9 124.8l.5 .9M77.4 124h.1M77.4 124v1.7M77.9 124.8l-.5 .9M90.4 122.3h.8"/>
<path d="M90.4 124h1.7M90.4 125.7h.8M90.4 127.5h.8M97.2 130.8v1h.9l-.9 .8-.8-.8h.8M97.2 130.8h.1M97.2 129.2v1.6M99 129.2v1.6M108.8 124.8l.5 .9M109.3 124h.1M109.3 124v1.7M109.9 124.8l-.6 .9M122.2 122.3h.9"/>
<path d="M122.2 124h1.8M122.2 125.7h.9M122.2 127.5h.9M129.2 130.8v1h.8l-.8 .8-1-.8h1M129.2 130.8h.1M129.2 129.2v1.6M130.8 129.2v1.6M152.4 122.3h3.4l-.8-.9v.9M152.4 124h3.4l-.8-.9v.9M162.7 128.3v.9h.9l-.9 .8-.9-.8h.9M162.7 128.3h.1M162.7 124.8v3.5"/>
<path d="M215.1 127.9h2M216.1 130v.8h.9l-.9 1-.8-1h.8M216.1 130h.1M216.1 126.6h.1M216.1 124.8v3.2M216.1 128.6v1.4M216.1 124.8l-.5 .9M216.1 124.8l.5 .9M223.7 127.9h2M224.7 126.6v1.4M224.7 128.6v1.4M232.2 127.9h2.2"/>
<path d="M233.4 126.6v1.4M233.4 128.6v1.4M240.9 127.9h2M241.9 126.6v1.4M241.9 128.6v1.4M249.5 127.9h2M250.6 126.6v1.4M250.6 128.6v1.4M258.1 127.9h2.1M259.2 126.6v1.4M259.2 128.6v1.4M266.7 127.9h2.1"/>
<path d="M267.8 126.6v1.4M267.8 128.6v1.4M275.3 127.9h2.1M276.4 126.6v1.4M276.4 128.6v1.4"/>
<circle cx="29.7" cy="68" r=".47"/>
<circle cx="29.7" cy="66.2" r=".47"/>
<circle cx="29.7" cy="62.9" r=".47"/>
<circle cx="61.5" cy="68" r=".47"/>
<circle cx="61.5" cy="62.9" r=".47"/>
<circle cx="61.5" cy="66.2" r=".47"/>
<circle cx="91.6" cy="62.9" r=".47"/>
<circle cx="91.6" cy="66.2" r=".47"/>
<circle cx="91.6" cy="68" r=".47"/>
<circle cx="123.6" cy="68" r=".47"/>
<circle cx="123.6" cy="66.2" r=".47"/>
<circle cx="123.6" cy="62.9" r=".47"/>
<circle cx="29.7" cy="125.7" r=".47"/>
<circle cx="29.7" cy="127.5" r=".47"/>
<circle cx="29.7" cy="122.3" r=".47"/>
<circle cx="61.5" cy="125.7" r=".47"/>
<circle cx="61.5" cy="127.5" r=".47"/>
<circle cx="61.5" cy="122.3" r=".47"/>
<circle cx="91.6" cy="125.7" r=".47"/>
<circle cx="91.6" cy="127.5" r=".47"/>
<circle cx="91.6" cy="122.3" r=".47"/>
<circle cx="123.6" cy="125.7" r=".47"/>
<circle cx="123.6" cy="122.3" r=".47"/>
<circle cx="123.6" cy="127.5" r=".47"/>
</g>
<g fill="none" stroke="#910000" stroke-width=".25">
<path d="M198.8 101.9h2M207.3 101.9h2.1M215.1 114.8h2M215.1 102h2M223.7 114.8h2.1M223.7 102h2.1M232.3 114.8h2.1M232.3 102h2.1M240.9 114.8h2M240.9 102h2M249.6 114.8h2M249.6 102h2"/>
<path d="M258.2 114.8h2M258.2 102h2M266.7 114.8h2.2M266.7 101.9h2.2M275.4 101.9h2M275.4 114.8h2M215.1 128.6h2M223.7 128.6h2.1M232.3 128.6h2.1M240.9 128.6h2M249.6 128.6h2M258.2 128.6h2"/>
<path d="M266.7 128.6h2.2M275.4 128.6h2"/>
</g>
<g fill="none" stroke="#b90000" stroke-width=".21">
<path d="M28.5 38.5h.6l-.4 .3 .4 .2-.1 .3-.5-.1M28.7 33.3l-.1 .6h.5M28.7 35l-.1 .6h.5M28.7 36.7l-.1 .7h.5M28.9 28.1h.6l-.3 .4h.2v.5l-.5-.1M29 29.9l.3-.1 .2 .3-.6 .7h.6M29 31.9l.2-.3v.9M29 32.5h.5M29 33.7v.5M29 35.3v.6M29 37v.6M29.2 26.4l-.2 .6h.5"/>
<path d="M29.3 35h.5l-.2 .3 .2 .1v.5h-.5M29.4 24.7h-.4v.4l.3-.1 .2 .4-.2 .2-.3-.1M29.4 36.9l.4-.1v.3l-.5 .5h.5M29.4 26.7v.6M29.6 33.3l-.2 .6h.5M29.8 33.7v.5M29.8 38.9l-.4 .1v-.4h.4v.6l-.3 .1M35 21.9h-.8l.2 .2M35 21.1h-.8l.2 .3M35 20.9v.5M35 21.6v.5M35.9 22.2v-.6l.3 .4 .2-.4 .3 .1-.1 .5"/>
<path d="M35.9 21.4v-.5l.3 .2 .1-.2h.3v.5M42.3 31.6h.5l-.3 .4h.3v.4h-.5M42.3 33.3h.5l-.3 .4h.3v.4h-.5M42.3 35h.5l-.3 .3 .3 .1v.5h-.5M42.3 36.8h.5l-.3 .3 .3 .1v.3h-.5M42.4 26.7l.2-.2v.8M42.4 28.4l.2-.3v.9M42.4 30.1l.2-.3v1M42.4 27.3h.4M42.4 29h.4M42.4 30.8h.4M43.1 28.1h.5l-.2 .4 .2 .1v.3h-.5"/>
<path d="M43.1 31.9l.3-.3v.9M43.1 33.4h.5v.3l-.5 .5h.5M43.1 32.5h.5M43.2 25.1l-.3 .2-.2-.5 .2-.1 .3 .1-.1 .7-.3 .1M43.2 26.5h.4v.1v.5l-.1 .2a.48 .48 0 0 1-.3-.8zM43.4 29.8l-.3 .6h.6M43.6 36.8h-.3l-.2 .7 .1 .1 .4-.1v-.4h-.4l-.1 .2M43.6 30.2v.6M43.6 35h-.4l-.1 .4h.5v.5h-.5M60.4 38.5h.5l-.2 .3 .2 .1v.3h-.5M60.7 33.3l-.3 .6h.6M60.7 35l-.3 .6h.6"/>
<path d="M60.7 36.7l-.3 .7h.6M60.8 28.1h.5l-.2 .4 .2 .2v.3l-.5-.1M60.8 29.9l.4-.1 .1 .2-.5 .8h.5M60.8 31.9l.3-.3v.9M60.8 32.5h.5M60.8 33.7v.5M60.8 35.3v.6M60.8 37v.6M61.1 26.4l-.3 .6h.5M61.2 35h.6l-.4 .3 .4 .2v.3l-.2 .1h-.4M61.3 24.7h-.4l-.1 .4 .4-.1 .1 .4-.1 .2-.4-.1M61.3 36.9l.4-.1 .1 .2-.6 .6h.6"/>
<path d="M61.3 26.7v.6M61.4 33.3l-.1 .6h.5M61.7 33.7v.5M61.8 38.9l-.5 .1v-.4l.3-.1 .2 .1-.2 .7h-.3M66.8 21.9h-.8l.2 .2M66.8 21.1h-.8l.2 .3M66.8 20.9v.5M66.8 21.6v.5M67.8 22.2v-.6l.3 .4v-.3l.3-.1 .2 .2-.1 .4M67.8 21.4v-.5l.3 .2v-.2h.4v.5M74.2 26.7l.3-.2v.8M74.2 28.4l.3-.3v.9"/>
<path d="M74.2 30.1l.3-.3v1M74.2 31.6h.5l-.3 .4h.2l.1 .3-.2 .2-.3-.1M74.2 33.3h.5l-.3 .4 .3 .1-.1 .4-.4-.1M74.2 35h.5l-.3 .3 .3 .2v.3l-.2 .1h-.3M74.2 36.8h.5l-.3 .3h.2v.5l-.4-.1M74.2 27.3h.5M74.2 29h.5M74.2 30.8h.5M75 28.1h.6l-.4 .4h.3v.5l-.5-.1M75.1 31.9l.2-.3v.9M75.1 33.4l.3-.1 .2 .3-.6 .6h.6M75.1 32.5h.5"/>
<path d="M75.1 25.1l-.1 .2-.4-.1v-.4l.4-.1 .1 .1-.1 .7-.3 .1M75.1 26.5a.43 .43 0 0 1 .5 .3 .43 .43 0 0 1-.4 .5l-.1-.2zM75.2 29.8l-.1 .6h.5M75.5 35h-.4v.4l.3-.1 .2 .5-.2 .1h-.3M75.5 36.8l-.4 .2v.5l.4 .1v-.5h-.4v.2M75.5 30.2v.6M90.5 38.5h.6l-.3 .3 .3 .1v.3h-.6M90.8 33.3l-.3 .6h.6M90.8 35l-.3 .6h.6M90.8 36.7l-.3 .7h.6M91 28.1h.5l-.3 .4 .3 .2-.1 .3-.4-.1M91 29.9l.3-.1 .2 .2-.5 .8h.5"/>
<path d="M91 31.9l.2-.3v.9M91 33.7v.5M91 35.3v.6M91 37v.6M91 32.5h.5M91.2 26.4l-.2 .6h.5M91.3 35h.6l-.3 .3 .3 .2v.3l-.2 .1h-.4M91.4 24.7h-.3l-.1 .4 .3-.1 .2 .4-.2 .2-.3-.1M91.4 36.9l.4-.1 .1 .2-.6 .6h.6M91.4 26.7v.6M91.6 33.3l-.2 .6h.5M91.8 33.7v.5"/>
<path d="M91.9 38.9l-.5 .1v-.4l.3-.1 .2 .1-.2 .7h-.2M97.1 21.9h-1l.3 .2M97.1 21.1h-1l.3 .3M97.1 20.9v.5M97.1 21.6v.5M97.9 22.2v-.6l.4 .4v-.4h.3l.2 .2-.1 .4M97.9 21.4v-.5l.4 .2v-.2h.4v.5M104.3 26.7l.3-.2v.8M104.3 28.4l.3-.3v.9M104.3 30.1l.3-.3v1M104.3 31.6h.6l-.4 .4h.3l.1 .3-.2 .2-.4-.1M104.3 33.3h.6l-.4 .4 .4 .1-.1 .4-.5-.1"/>
<path d="M104.3 35h.6l-.4 .3 .4 .2v.3l-.2 .1h-.4M104.3 36.8h.6l-.4 .3h.3v.5l-.5-.1M104.3 27.3h.6M104.3 29h.6M104.3 30.8h.6M105.1 28.1h.6l-.3 .4h.2v.5l-.5-.1M105.2 31.9l.2-.3v.9M105.2 33.4l.3-.1 .2 .3-.6 .6h.6M105.2 32.5h.5M105.3 25.1l-.2 .2-.3-.1v-.4l.3-.1 .2 .1-.2 .7-.2 .1M105.3 26.5a.43 .43 0 0 1 .4 .3 .43 .43 0 0 1-.3 .5l-.2-.2zM105.4 29.8l-.2 .6h.5"/>
<path d="M105.6 35h-.4v.4l.3-.1 .2 .5-.2 .1h-.3M105.6 36.8l-.4 .2v.5l.4 .1v-.5h-.3l-.1 .2M105.6 30.2v.6M122.4 38.5h.5l-.3 .3 .3 .1v.4l-.5-.1M122.6 33.3l-.1 .6h.5M122.6 35l-.1 .6h.5M122.6 36.7l-.1 .7h.5M122.8 28.1h.5l-.2 .4 .2 .1v.3h-.5M122.9 29.9h.4v.4l-.5 .5h.5M122.9 31.9l.2-.3v.9M122.9 32.5h.4M122.9 33.7v.5"/>
<path d="M122.9 35.3v.6M122.9 37v.6M123.1 26.4l-.2 .6h.5M123.2 35h.5l-.2 .3 .2 .1v.5h-.5M123.2 36.9h.5v.2l-.5 .5h.5M123.2 26.7v.6M123.3 24.7h-.4v.4h.4v.4h-.4M123.5 33.3l-.3 .6h.6M123.7 33.7v.5M123.7 38.9h-.5l.2-.4 .3 .1v.6l-.4 .1M128.9 21.9h-.8l.2 .2M128.9 21.1h-.8l.2 .3"/>
<path d="M128.9 20.9v.5M128.9 21.6v.5M129.7 22.2v-.6l.4 .4v-.3l.2-.1 .3 .1-.1 .5M129.7 21.4v-.5l.4 .2 .1-.2h.3v.5M136.2 26.7l.2-.2v.8M136.2 28.4l.2-.3v.9M136.2 30.1l.2-.3v1M136.2 31.6h.5l-.3 .4h.3v.4h-.5M136.2 33.3h.5l-.3 .4h.3v.4h-.5M136.2 35h.5l-.3 .3 .3 .1v.5h-.5M136.2 36.8h.5l-.3 .3 .3 .1v.3h-.5M136.2 27.3h.5"/>
<path d="M136.2 29h.5M136.2 30.8h.5M137 28.1h.5l-.2 .4 .2 .2v.3l-.5-.1M137 31.9l.3-.3v.9M137 33.4l.4-.1 .1 .2-.5 .7h.5M137 32.5h.5M137.1 25.1l-.3 .2-.2-.5 .2-.1 .3 .1v.6l-.4 .2M137.2 26.5a.45 .45 0 0 1 .3 .3 .45 .45 0 0 1-.2 .5 .52 .52 0 0 1-.1-.8zM137.3 29.8l-.3 .6h.5M137.5 35h-.4l-.1 .4 .4-.1 .1 .5-.1 .1h-.4M137.5 36.8h-.3l-.2 .3 .1 .5h.4v-.5h-.4l-.1 .2M137.5 30.2v.6"/>
<path d="M153.5 23.2l.2-.2v.8M153.5 24.9l.2-.2v.9M153.5 26.7l.2-.2v.8M153.5 36.9l.4-.1 .1 .2-.6 .6h.6M153.5 38.6l.3-.1 .2 .2-.6 .6h.6M153.5 23.8h.5M153.5 25.6h.5M153.5 27.3h.5M153.8 31.6h.6l-.4 .9M154 30.3l-.1-.1v-.3l.3-.1 .2 .3-.5 .2v.4l.1 .1 .4-.2-.2-.3M154.2 36.8h.6l-.3 .8M154.3 23.1h.4v.2l-.5 .5h.5"/>
<path d="M154.3 24.9l.2-.2v.9M154.3 33.3l-.4 .3v.5l.4 .1 .1-.4-.2-.1-.3 .1M154.3 35h-.4v.4l.3-.1 .2 .5-.2 .1h-.3M154.3 25.6h.4M154.4 26.5h.2l.1 .1v.5l-.1 .2-.3-.2zM154.4 28.5l-.1 .2h-.3l-.1-.5 .3-.1 .2 .2-.2 .7h-.2M154.6 38.5l-.3 .2v.5h.4v-.3l-.2-.1-.2 .2M161.6 22.2v-.6l.3 .4 .2-.4h.2l.2 .2-.1 .4M162.5 20.9v.5l-.5-.5h-.3v.5M170.6 23.2l.3-.2v.8M170.6 24.9l.3-.2v.9M170.6 26.7l.3-.2v.8"/>
<path d="M170.6 28.4l.3-.3v.9M170.6 30.1l.3-.3v1M170.6 31.9l.3-.3v.9M170.6 33.4h.6v.3l-.6 .5h.6M170.6 35.1h.6v.3l-.6 .5h.6M170.6 23.8h.6M170.6 25.6h.6M170.6 27.3h.6M170.6 29h.6M170.6 30.8h.6M170.6 32.5h.6M171.5 23h.5l-.3 .3h.2l.1 .2-.1 .3-.4-.1"/>
<path d="M171.5 28.1h.5l-.3 .9M171.5 35.3l.2-.3v.9M171.5 35.9h.5M171.7 24.7l-.2 .6h.5M171.7 30.3l-.2-.3 .3-.2 .2 .3-.5 .3 .2 .4 .3-.2-.2-.3M171.7 33.3a.43 .43 0 0 1 .3 .5 .43 .43 0 0 1-.4 .4l-.1-.5zM171.9 26.5h-.3l-.1 .4 .4-.1 .1 .3-.2 .2-.3-.1M171.9 25v.6M172 32l-.1 .1h-.3v-.5h.3l.1 .2-.1 .5-.3 .2M28.6 40.3h.4l.1 .1-.6 .7h.6M28.6 42l.4-.1 .1 .3-.6 .6h.6M28.6 43.7l.3-.1 .2 .3-.6 .6h.6"/>
<path d="M28.6 45.5l.4-.1 .1 .2-.6 .7h.6M28.6 47.2l.4-.1 .1 .3-.6 .6h.6M28.6 48.9l.3-.1 .2 .3-.6 .6h.6M28.6 50.7l.4-.1 .1 .2-.6 .6h.6M28.6 52.4l.4-.1 .1 .2-.6 .6h.6M28.6 54.1l.3-.1 .2 .2-.6 .6h.6M28.6 56l.2-.3v.9M28.6 57.7l.2-.3v.9M28.6 58.3h.5M28.6 56.6h.5M29.3 41.9h.6l-.4 .9M29.3 48.8h.5l-.2 .3 .2 .1v.4h-.5"/>
<path d="M29.4 50.7l.4-.1v.3l-.5 .5h.5M29.4 52.5l.2-.2v.8M29.4 53.1h.4M29.5 40.6l-.1-.3h.4v.2l-.4 .2 .1 .4 .3-.1v-.3l-.1-.1M29.5 57.8l-.1-.3 .4-.1v.3l-.4 .2v.3l.4 .1v-.4l-.1-.1M29.6 47l-.2 .7h.5M29.6 54l.2 .1v.7l-.4-.1v-.6zM29.8 43.6l-.4 .3v.5h.4v-.3l-.3-.1-.1 .2M29.8 47.4v.6M29.8 45.4h-.4v.4h.4v.4h-.4M29.8 56.1l-.3 .2-.1-.5h.4v.5l-.3 .3M42.3 55.7h.5l-.3 .4h.3v.4h-.5"/>
<path d="M42.3 57.4h.5l-.3 .4 .3 .1v.3h-.5M42.3 59.1h.5l-.3 .4 .3 .1v.4h-.5M42.4 50.8l.2-.2v.8M42.4 52.5l.2-.2v.8M42.4 54.1h.4v.3l-.5 .4h.5M42.4 53.1h.4M42.4 51.4h.4M42.7 47.1h.6l-.4 .9M42.9 49.2l-.2-.2 .2-.2 .3 .1v.2l-.4 .1v.5l.4-.1v-.3l-.2-.1M43.1 57.4h.6l-.4 .9M43.2 55.8l.4-.1v.2v.5l-.1 .2a.48 .48 0 0 1-.3-.8zM43.3 59.6l-.2-.3 .2-.2 .3 .1v.3l-.4 .1-.1 .1 .1 .3h.4v-.4h-.1"/>
<path d="M43.6 52.3h-.3l-.2 .7 .1 .1 .4-.1v-.4h-.4l-.1 .2M43.6 50.6h-.4l-.1 .3h.5v.4h-.5M43.6 54.4l-.1 .2-.4-.2 .2-.4 .3 .1v.5l-.4 .2M60.4 40.3h.5v.3l-.5 .5h.5M60.4 42h.5v.3l-.5 .5h.5M60.4 43.7h.5v.4l-.5 .4h.5M60.4 45.5h.5v.3l-.5 .5h.5M60.4 47.2h.5v.3l-.5 .5h.5M60.4 48.9h.5v.3l-.5 .5h.5M60.4 50.7h.5v.2l-.5 .5h.5M60.4 52.4h.5v.2l-.5 .5h.5M60.4 54.1h.5v.3l-.5 .4h.5"/>
<path d="M60.4 56l.3-.3v.9M60.4 57.7l.3-.3v.9M60.4 58.3h.5M60.4 56.6h.5M61.2 41.9h.6l-.4 .9M61.2 48.8h.6l-.4 .3 .4 .2-.1 .4-.5-.1M61.3 50.7l.4-.1 .1 .2-.6 .6h.6M61.3 52.5l.2-.2v.8M61.3 53.1h.5M61.4 40.6l-.1-.1v-.2h.4l.1 .1-.2 .2-.3 .1v.3l.1 .1 .4-.2-.2-.3M61.4 47l-.1 .7h.5M61.4 54a.43 .43 0 0 1 .4 .4 .43 .43 0 0 1-.5 .4v-.7z"/>
<path d="M61.4 57.8l-.1-.3 .4-.1v.4l-.4 .1v.4h.4l.1-.2-.2-.3M61.7 43.6l-.4 .3v.5l.4 .1 .1-.3-.2-.2-.3 .2M61.7 45.4h-.4v.4l.3-.1 .2 .4-.2 .2-.3-.1M61.7 47.4v.6M61.8 56.1l-.4 .2-.1-.1v-.4l.4-.1 .1 .2-.2 .6-.3 .1M74.2 50.8l.3-.2v.8M74.2 52.5l.3-.2v.8M74.2 54.1l.3-.1 .2 .1-.5 .7h.5M74.2 55.7h.5l-.3 .4 .3 .1v.2l-.2 .2-.3-.1M74.2 57.4h.5l-.3 .4h.2l.1 .2-.1 .3-.4-.1M74.2 59.1h.5l-.3 .4 .3 .1v.3l-.5 .1M74.2 53.1h.5"/>
<path d="M74.2 51.4h.5M74.5 47.1h.6l-.3 .9M74.8 49.2l-.2-.1v-.2l.4-.1 .1 .3-.5 .2 .1 .4h.4v-.3l-.1-.2M75 57.4h.6l-.4 .9M75.1 55.7a.43 .43 0 0 1 .5 .4 .43 .43 0 0 1-.4 .5l-.1-.2zM75.2 59.6l-.1-.1v-.3l.3-.1 .2 .3-.5 .2v.4l.5-.1-.2-.3M75.5 50.6h-.4v.3l.3-.1 .2 .5-.2 .1-.3-.1M75.5 52.3l-.4 .1v.6l.4 .1v-.5h-.4v.2M75.6 54.4l-.2 .2-.3-.1v-.4l.3-.1 .2 .1-.2 .7h-.3M90.5 40.3h.6v.3l-.6 .5h.6M90.5 42h.6v.3l-.6 .5h.6M90.5 43.7h.6v.4l-.6 .4h.6"/>
<path d="M90.5 45.5h.6v.3l-.6 .5h.6M90.5 47.2h.6v.3l-.6 .5h.6M90.5 48.9h.6v.3l-.6 .5h.6M90.5 50.7h.6v.2l-.6 .5h.6M90.5 52.4h.6v.2l-.6 .5h.6M90.5 54.1h.6v.3l-.6 .4h.6M90.5 56l.3-.3v.9M90.5 57.7l.3-.3v.9M90.5 58.3h.6M90.5 56.6h.6M91.3 41.9h.6l-.3 .9M91.3 48.8h.6l-.3 .3 .3 .2-.1 .4-.5-.1"/>
<path d="M91.4 50.7l.4-.1 .1 .2-.6 .6h.6M91.4 52.5l.2-.2v.8M91.4 53.1h.5M91.6 40.6l-.2-.1v-.2h.4l.1 .1-.5 .3v.3l.2 .1 .3-.2-.2-.3M91.6 47l-.2 .7h.5M91.6 54a.43 .43 0 0 1 .3 .4 .43 .43 0 0 1-.4 .4l-.1-.7zM91.6 57.8l-.2-.3 .4-.1v.4l-.4 .1 .1 .4h.3l.1-.2-.2-.3M91.8 43.6l-.4 .3v.5l.4 .1 .1-.3-.2-.2-.3 .2M91.8 45.4h-.4v.4l.3-.1 .2 .4-.2 .2-.3-.1M91.8 47.4v.6M91.9 56.1l-.3 .2-.2-.1v-.4l.4-.1 .1 .2-.2 .6-.2 .1M104.3 50.8l.3-.2v.8"/>
<path d="M104.3 52.5l.3-.2v.8M104.3 54.1l.4-.1 .2 .1-.6 .7h.6M104.3 55.7h.6l-.4 .4 .4 .1v.2l-.2 .2-.4-.1M104.3 57.4h.6l-.4 .4h.3l.1 .2-.1 .3-.5-.1M104.3 59.1h.6l-.4 .4 .4 .1v.3l-.6 .1M104.3 53.1h.6M104.3 51.4h.6M104.7 47.1h.6l-.4 .9M104.9 49.2l-.1-.1v-.2l.3-.1 .2 .3-.5 .2 .1 .4h.3l.1-.3-.2-.2M105.1 57.4h.6l-.3 .9M105.3 55.7a.43 .43 0 0 1 .4 .4 .43 .43 0 0 1-.3 .5l-.2-.2zM105.4 59.6l-.2-.1v-.3l.3-.1 .2 .3-.5 .2v.4l.5-.1-.2-.3"/>
<path d="M105.6 50.6h-.4v.3l.3-.1 .2 .5-.2 .1-.3-.1M105.6 52.3l-.4 .1v.6l.4 .1v-.5h-.3l-.1 .2M105.7 54.4l-.2 .2-.3-.1v-.4l.3-.1 .2 .1-.2 .7h-.2M122.5 40.3h.4v.3l-.5 .5h.5M122.5 42l.4-.1v.4l-.5 .5h.5M122.5 43.7l.3-.1 .1 .5-.5 .4h.5M122.5 45.5l.4-.1v.4l-.5 .5h.5M122.5 47.2l.4-.1v.4l-.5 .5h.5M122.5 48.9l.3-.1 .1 .4-.5 .5h.5M122.5 50.7l.4-.1v.3l-.5 .5h.5M122.5 52.4l.4-.1v.3l-.5 .5h.5M122.5 54.1l.3-.1 .1 .4-.5 .4h.5"/>
<path d="M122.5 56l.2-.3v.9M122.5 57.7l.2-.3v.9M122.5 58.3h.4M122.5 56.6h.4M123.2 41.9h.6l-.4 .9M123.2 48.8h.5l-.2 .3 .2 .1v.4h-.5M123.2 50.7h.5v.2l-.5 .5h.5M123.2 52.5l.3-.2v.8M123.2 53.1h.5M123.3 54.1l.3-.1 .1 .1v.7h-.3l-.2-.2zM123.4 40.6l-.2-.3h.5v.2l-.4 .1-.1 .2 .2 .3 .3-.1v-.3l-.1-.1M123.4 57.8l-.2-.2 .1-.2h.4v.3l-.5 .3 .1 .3 .4-.1v-.3l-.1-.1"/>
<path d="M123.5 47l-.3 .7h.6M123.7 43.6l-.3 .1-.2 .6 .1 .2 .4-.1v-.3l-.3-.1-.2 .2M123.7 47.4v.6M123.7 45.4h-.4l-.1 .4h.5v.4h-.5M123.7 56.1l-.3 .2-.2-.2 .1-.4 .4 .1v.7l-.4 .1M136.2 50.8l.2-.2v.8M136.2 52.5l.2-.2v.8M136.2 54.1h.5v.3l-.5 .4h.5M136.2 55.7h.5l-.3 .4h.3v.4h-.5M136.2 57.4h.5l-.3 .4 .3 .1v.3h-.5M136.2 59.1h.5l-.3 .4 .3 .1v.4h-.5M136.2 53.1h.5"/>
<path d="M136.2 51.4h.5M136.6 47.1h.6l-.4 .9M136.8 49.2l-.2-.2 .2-.2 .3 .1v.2l-.4 .1v.5l.4-.1v-.3l-.2-.1M137 57.4h.5l-.3 .9M137.1 55.8l.1-.1a.45 .45 0 0 1 .3 .4 .45 .45 0 0 1-.2 .5l-.3-.3zM137.2 59.6l-.2-.3 .4-.2 .1 .3-.4 .2-.1 .3 .5 .1v-.3l-.1-.1M137.5 50.6h-.4l-.1 .3 .4-.1 .1 .5-.1 .1-.4-.1M137.5 52.3h-.3l-.2 .3 .1 .5h.4v-.5h-.4l-.1 .2M137.5 54.4l-.1 .2-.4-.2 .2-.4 .3 .1v.4l-.1 .3h-.3M153.4 52.3h.6l-.4 .3h.3l.1 .2-.1 .3-.5-.1M153.4 57.4h.6l-.4 .4h.3l.1 .2-.1 .3-.5-.1M153.5 40.3h.4l.1 .1-.6 .7h.6"/>
<path d="M153.5 42l.4-.1 .1 .3-.6 .6h.6M153.5 45.5l.4-.1 .1 .2-.6 .7h.6M153.5 47.2l.4-.1 .1 .3-.6 .6h.6M153.8 48.8h.6l-.4 .3 .4 .2-.1 .4-.5-.1M153.9 50.7l.4-.1 .1 .2-.6 .6h.6M153.9 54.2l.2-.2v.8M153.9 54.8h.5M154 43.6l-.1 .6h.5M154.2 40.3h.5l-.2 .2 .2 .1v.4h-.5M154.3 57.7l.2-.3v.9M154.3 44v.5M154.3 58.3h.4"/>
<path d="M154.4 52.3h.2l.1 .1-.1 .7h-.2l-.1-.1zM154.5 45.8l-.2-.3 .3-.1 .1 .3-.4 .1v.4l.2 .1 .2-.1v-.4h-.1M154.7 41.9h-.4v.5l.3-.1 .1 .4h-.4M154.7 47.5l-.1 .1h-.2l-.1-.4h.4v.6l-.3 .2M222.5 53.1l-.1 .6h.5M222.5 54.8l-.1 .6h.5M222.8 49.9l.2-.2v.9M222.8 51.5l.3-.1 .1 .4-.5 .5h.5M222.8 50.6h.4M222.8 53.5v.5M222.8 55.2v.5M223 56.5l-.2 .7h.5"/>
<path d="M223.1 53.1h.5l-.2 .4h.2v.4h-.5M223.1 60l-.3 .2v.6h.4v-.4l-.2-.1-.2 .2M223.1 56.9v.5M223.2 58.3h-.4v.4h.4v.4h-.4M223.4 54.8l-.3 .6h.6M223.6 55.2v.5M228.8 46.8v-.5l.3 .2 .1-.2h.4v.5M230.5 45.8v.5l.4 .1v-.6h.4v.6M231.3 46.9h-.8l.3 .2M231.3 46.6v.5M232.3 46.4v-.6l.3 .3v-.3h.4v.6M233.1 46.6v.6l-.6-.6-.2 .1 .1 .4"/>
<path d="M234 47.2v-.6l.3 .3v-.2l.2-.1 .3 .1-.1 .5M234 45.8v.5l.4 .1-.1-.5 .4-.1v.6M241.3 60h.5l-.3 .3 .3 .1v.4h-.5M241.5 56.5l-.2 .7h.5M241.5 58.3l-.2 .6h.5M241.7 56.9v.5M241.7 58.6v.5M242.1 56.9l.3-.3v.8M242.1 57.4h.5M242.2 58.4l.2-.1 .2 .2-.1 .6a.39 .39 0 0 1-.4-.3 .39 .39 0 0 1 .1-.4zM28.6 65.4l.2-.2v.9M28.6 66.1h.5"/>
<path d="M28.7 63.5l-.1 .5h.5M28.7 66.8l-.1 .7h.5M29 63.8v.5M29 67.2v.6M29.3 65.2h.6l-.4 .9M29.4 61.8l-.4 .1v.6l.4 .1v-.5h-.3l-.1 .2M29.4 67.2l.2-.3v.9M29.4 67.8h.4M29.6 63.5l.2 .1v.7h-.3l-.1-.2v-.5zM35 71h-.8l.2 .2M35 70v.5l-.5-.5-.3 .1v.3M35 70.7v.5"/>
<path d="M35.9 71.3v-.6l.3 .4 .2-.4 .3 .1-.1 .5M36.2 70.1h.5M36.4 69.9v.5l-.5-.2M60.4 65.4l.3-.2v.9M60.4 66.1h.5M60.7 63.5l-.3 .5h.6M60.7 66.8l-.3 .7h.6M60.8 63.8v.5M60.8 67.2v.6M61.2 65.2h.6l-.4 .9M61.3 61.8h-.3l-.2 .3 .1 .5h.4v-.5h-.4l-.1 .2M61.3 63.6l.1-.1a.43 .43 0 0 1 .4 .4 .43 .43 0 0 1-.5 .4z"/>
<path d="M61.3 67.2l.2-.3v.9M61.3 67.8h.5M66.8 71h-.8l.2 .2M66.8 70v.5l-.4-.5-.4 .1 .1 .3M66.8 70.7v.5M67.8 71.3v-.6l.3 .4v-.3l.3-.1 .2 .2-.1 .4M68 70.1h.6M68.3 69.9v.5l-.6-.2M90.5 65.4l.3-.2v.9M90.5 66.1h.6M90.8 63.5l-.3 .5h.6M90.8 66.8l-.3 .7h.6"/>
<path d="M91 63.8v.5M91 67.2v.6M91.3 65.2h.6l-.3 .9M91.4 61.8h-.3l-.1 .3 .1 .5h.3v-.5h-.3l-.1 .2M91.4 67.2l.2-.3v.9M91.4 67.8h.5M91.6 63.5a.43 .43 0 0 1 .3 .4 .43 .43 0 0 1-.4 .4l-.1-.7zM97.1 71h-1l.3 .2M97.1 70v.5l-.5-.5-.5 .1 .1 .3M97.1 70.7v.5M97.9 71.3v-.6l.4 .4v-.4h.3l.2 .2-.1 .4M98.2 70.1h.6"/>
<path d="M98.4 69.9v.5l-.6-.2M122.5 65.4l.2-.2v.9M122.5 66.1h.4M122.6 63.5l-.1 .5h.5M122.6 66.8l-.1 .7h.5M122.9 63.8v.5M122.9 67.2v.6M123.2 61.8h-.2l-.1 .1v.7l.4-.1-.1-.4h-.3v.2M123.2 65.2h.6l-.4 .9M123.2 67.2l.3-.3v.9M123.2 67.8h.5M123.3 63.5h.3l.1 .1v.6a.39 .39 0 0 1-.5-.2 .39 .39 0 0 1 .1-.5z"/>
<path d="M128.9 71h-.8l.2 .2M128.9 70v.5l-.5-.5-.3 .1v.3M128.9 70.7v.5M129.7 71.3v-.6l.4 .4v-.3l.2-.1 .3 .1-.1 .5M130 70.1h.6M130.3 69.9v.5l-.6-.2M153.5 61l.4-.1 .1 .3-.6 .6h.6M153.5 62.7l.4-.1 .1 .3-.6 .6h.6M154.3 61l.3-.1 .1 .4-.5 .5h.5M154.5 62.6l-.2 .6h.5M154.6 62.9v.6M161.6 65.7l.1 .3 .6 .2 .2-.2-.1-.3h-.4l-.1 .3 .2 .2"/>
<path d="M162.5 66.7h-.9l.2 .2M162.5 66.4v.5M222.4 67.2l.2-.3v.9M222.4 68.9l.2-.3v.9M222.4 70.6l.2-.2v.8M222.4 72.3l.2-.2v.8M222.4 74l.2-.2v.8M222.4 75.8l.2-.2v.8M222.4 77.5l.2-.2v.8M222.4 79.2l.2-.3v.9M222.4 67.8h.5M222.4 69.5h.5"/>
<path d="M222.4 71.2h.5M222.4 72.9h.5M222.4 74.6h.5M222.4 76.4h.5M222.4 78.1h.5M222.4 79.8h.5M222.7 61.8h.6l-.3 .8M223 63.9l-.2-.1v-.3h.3h.1v.3l-.4 .2 .1 .3 .3-.1v-.2l-.1-.1M223.1 67.2l.3-.3v.9M223.1 68.7h.5v.3l-.5 .5h.5M223.1 70.4h.5l-.2 .3h.2v.5h-.5M223.1 75.6h.6l-.4 .8"/>
<path d="M223.1 67.8h.5M223.2 65.6l-.1 .1h-.3v-.4h.4v.5l-.3 .3M223.3 77.6l-.2-.2 .1-.1h.4v.3l-.5 .2 .1 .3 .4-.1v-.3l-.1-.1M223.4 72l-.3 .7h.6M223.6 73.8l-.3 .1-.2 .6 .1 .1 .4-.1v-.3l-.3-.1-.2 .2M223.6 72.3v.6M223.6 79.4l-.1 .1-.4-.1 .2-.5 .3 .1v.6v.2h-.4M241.3 61.8h.5l-.3 .3 .3 .1v.3h-.5M241.3 63.5h.5l-.3 .3 .3 .1v.3h-.5M241.3 65.2h.5l-.3 .3 .3 .1v.4h-.5M241.3 66.9h.5l-.3 .4h.3v.4h-.5M241.3 68.6h.5l-.3 .4h.3v.4h-.5"/>
<path d="M241.3 70.4h.5l-.3 .3h.3v.5h-.5M241.3 72.1h.5l-.3 .3 .3 .1v.4h-.5M241.3 73.9h.5v.3l-.5 .4h.5M241.3 75.6h.4l.1 .3-.5 .5h.5M241.3 77.3h.4l.1 .3-.5 .5h.5M241.3 79h.5v.4l-.5 .4h.5M242.1 63.5h.6l-.4 .8M242.1 68.6h.5l-.2 .4h.2v.4h-.5M242.1 70.5h.5v.2l-.5 .5h.5M242.1 72.3l.3-.2v.8M242.1 77.3h.6l-.4 .8M242.1 72.9h.5"/>
<path d="M242.3 62.1l-.2-.2 .1-.1h.3l.1 .2-.5 .3 .1 .3h.3l.1-.4-.2-.1M242.3 75.9l-.2-.2 .1-.1h.3l.1 .2-.4 .1-.1 .2 .2 .3 .3-.1v-.3l-.2-.1M242.4 66.8l-.3 .7h.6M242.5 65.2h-.2l-.2 .7 .2 .2 .3-.1v-.4l-.3-.1-.2 .2M242.5 78.9l-.2 .1-.2 .7 .5 .1v-.4l-.3-.1-.2 .2M242.5 67.2v.6M242.6 60.4l-.3 .2-.2-.4 .2-.2 .3 .1-.1 .7-.3 .1M242.6 74.2l-.2 .2-.3-.2 .2-.4 .3 .1v.6l-.4 .1M28.5 97.9h.6l-.4 .4h.3l.1 .1-.1 .4-.5-.1M28.6 99.7l.3-.1 .2 .3-.6 .6h.6M28.7 92.7l-.1 .6h.5M28.7 94.4l-.1 .6h.5"/>
<path d="M28.7 96.1l-.1 .7h.5M28.9 87.6h.6l-.3 .3h.2l.1 .2-.1 .3-.5-.1M29 89.4l.3-.1 .2 .2-.6 .7h.6M29 91.3l.2-.2v.8M29 91.9h.5M29 93v.6M29 94.8v.6M29 96.5v.6M29.2 85.8l-.2 .6h.5M29.3 94.4h.5l-.2 .4 .2 .1v.4h-.5M29.4 84.1h-.4v.4h.3l.2 .4-.2 .1h-.3M29.4 96.3l.4-.1v.4l-.5 .5h.5"/>
<path d="M29.4 86.1v.6M29.6 92.7l-.2 .6h.5M29.8 93v.6M29.8 98.3v.1h-.3l-.1-.4h.4v.6l-.3 .2M35 81.3h-.8l.2 .3M35 80.6h-.8l.2 .1M35 80.3v.4M35 81.1v.5M35.9 81.7v-.6l.3 .3 .2-.3h.3l-.1 .6M35.9 80.8v-.5l.3 .3 .1-.3h.3v.5M42.3 91.1h.5l-.3 .3 .3 .1v.3h-.5M42.3 92.7h.5l-.3 .4 .3 .1v.3h-.5"/>
<path d="M42.3 94.4h.5l-.3 .4 .3 .1v.4h-.5M42.3 96.2h.5l-.3 .4h.3v.4h-.5M42.4 86.1l.2-.2v.8M42.4 87.8l.2-.2v.8M42.4 89.5l.2-.2v.9M42.4 86.7h.4M42.4 88.4h.4M42.4 90.2h.4M43.1 87.6h.5l-.2 .3 .2 .1v.3h-.5M43.1 91.3l.3-.2v.8M43.1 92.8h.5v.3l-.5 .5h.5M43.1 91.9h.5"/>
<path d="M43.2 84.5l-.3 .2-.2-.4 .2-.2 .3 .1v.6l-.4 .2M43.2 86l.4-.1v.2v.5l-.1 .1a.48 .48 0 0 1-.3-.7zM43.4 89.3l-.3 .6h.6M43.6 96.2h-.3l-.2 .7 .2 .2 .3-.1v-.4h-.4l-.1 .1M43.6 89.6v.6M43.6 94.4h-.4l-.1 .5h.5v.4h-.5M60.4 97.9h.5l-.2 .4h.2v.4h-.5M60.4 99.7h.5v.3l-.5 .5h.5M60.7 92.7l-.3 .6h.6M60.7 94.4l-.3 .6h.6M60.7 96.1l-.3 .7h.6M60.8 87.6h.5l-.2 .3 .2 .2v.3l-.5-.1"/>
<path d="M60.8 89.4l.4-.1 .1 .1-.5 .8h.5M60.8 91.3l.3-.2v.8M60.8 91.9h.5M60.8 93v.6M60.8 94.8v.6M60.8 96.5v.6M61.1 85.8l-.3 .6h.5M61.2 94.4h.6l-.4 .4 .4 .2v.2l-.2 .2-.4-.1M61.3 84.1h-.4l-.1 .4h.4l.1 .4-.1 .1h-.4M61.3 96.3l.4-.1 .1 .3-.6 .6h.6M61.3 86.1v.6M61.4 92.7l-.1 .6h.5"/>
<path d="M61.7 93v.6M61.8 98.3l-.1 .1h-.4v-.4l.3-.1 .2 .2-.2 .7h-.3M66.8 81.3h-.8l.2 .3M66.8 80.6h-.8l.2 .1M66.8 80.3v.4M66.8 81.1v.5M67.8 81.7v-.6l.3 .3v-.3h.3l.2 .1-.1 .5M67.8 80.8v-.5l.3 .3v-.3h.4v.5M74.2 86.1l.3-.2v.8M74.2 87.8l.3-.2v.8M74.2 89.5l.3-.2v.9M74.2 91.1h.5l-.3 .3h.2l.1 .3-.2 .2-.3-.1"/>
<path d="M74.2 92.7h.5l-.3 .4h.2l.1 .2-.1 .3-.4-.1M74.2 94.4h.5l-.3 .4 .3 .2v.2l-.2 .2-.3-.1M74.2 96.2h.5l-.3 .4h.2l.1 .3-.2 .2-.3-.1M74.2 86.7h.5M74.2 88.4h.5M74.2 90.2h.5M75 87.6h.6l-.4 .3h.3l.1 .2-.1 .3-.5-.1M75.1 91.3l.2-.2v.8M75.1 92.8l.3-.1 .2 .3-.6 .6h.6M75.1 91.9h.5M75.1 84.5l-.1 .2-.4-.1v-.4l.4-.1 .1 .2-.1 .7h-.3M75.1 85.9a.43 .43 0 0 1 .5 .4 .43 .43 0 0 1-.4 .4l-.1-.1z"/>
<path d="M75.2 89.3l-.1 .6h.5M75.5 94.4h-.4v.5l.3-.1 .2 .4-.2 .2-.3-.1M75.5 96.2l-.4 .2v.6l.3 .1 .2-.2-.1-.3h-.4v.1M75.5 89.6v.6M90.5 97.9h.6l-.3 .4h.3v.4h-.6M90.5 99.7h.6v.3l-.6 .5h.6M90.8 92.7l-.3 .6h.6M90.8 94.4l-.3 .6h.6M90.8 96.1l-.3 .7h.6M91 87.6h.5l-.3 .3 .3 .2-.1 .3-.4-.1M91 89.4l.3-.1 .2 .1-.5 .8h.5M91 91.3l.2-.2v.8"/>
<path d="M91 91.9h.5M91 93v.6M91 94.8v.6M91 96.5v.6M91.2 85.8l-.2 .6h.5M91.3 94.4h.6l-.3 .4 .3 .2v.2l-.2 .2-.4-.1M91.4 84.1h-.3l-.1 .4h.3l.2 .4-.2 .1h-.3M91.4 96.3l.4-.1 .1 .3-.6 .6h.6M91.4 86.1v.6M91.6 92.7l-.2 .6h.5M91.8 93v.6M91.9 98.3l-.1 .1h-.3l-.1-.4 .3-.1 .2 .2-.2 .7h-.2"/>
<path d="M97.1 81.3h-1l.3 .3M97.1 80.6h-1l.3 .1M97.1 80.3v.4M97.1 81.1v.5M97.9 81.7v-.6l.4 .3v-.3h.3l.2 .1-.1 .5M97.9 80.8v-.5l.4 .3v-.3h.4v.5M104.3 86.1l.3-.2v.8M104.3 87.8l.3-.2v.8M104.3 89.5l.3-.2v.9M104.3 91.1h.6l-.4 .3h.3l.1 .3-.2 .2-.4-.1M104.3 92.7h.6l-.4 .4h.3l.1 .2-.1 .3-.5-.1M104.3 94.4h.6l-.4 .4 .4 .2v.2l-.2 .2-.4-.1"/>
<path d="M104.3 96.2h.6l-.4 .4h.3l.1 .3-.2 .2-.4-.1M104.3 86.7h.6M104.3 88.4h.6M104.3 90.2h.6M105.1 87.6h.6l-.3 .3h.2l.1 .2-.1 .3-.5-.1M105.2 91.3l.2-.2v.8M105.2 92.8l.3-.1 .2 .3-.6 .6h.6M105.2 91.9h.5M105.3 84.5l-.2 .2-.3-.1v-.4l.3-.1 .2 .2-.2 .7h-.2M105.3 85.9a.43 .43 0 0 1 .4 .4 .43 .43 0 0 1-.3 .4l-.2-.1zM105.4 89.3l-.2 .6h.5M105.6 94.4h-.4v.5l.3-.1 .2 .4-.2 .2-.3-.1"/>
<path d="M105.6 96.2l-.4 .2v.6l.3 .1 .2-.2-.1-.3h-.3l-.1 .1M105.6 89.6v.6M122.4 97.9h.5l-.3 .4h.3v.5l-.5-.1M122.5 99.7l.3-.1 .1 .4-.5 .5h.5M122.6 92.7l-.1 .6h.5M122.6 94.4l-.1 .6h.5M122.6 96.1l-.1 .7h.5M122.8 87.6h.5l-.2 .3 .2 .1v.3h-.5M122.9 89.4h.4v.3l-.5 .5h.5M122.9 91.3l.2-.2v.8M122.9 91.9h.4M122.9 93v.6"/>
<path d="M122.9 94.8v.6M122.9 96.5v.6M123.1 85.8l-.2 .6h.5M123.2 94.4h.5l-.2 .4 .2 .1v.4h-.5M123.2 96.3h.5v.3l-.5 .5h.5M123.2 86.1v.6M123.3 84.1h-.4v.4h.4v.5h-.4M123.5 92.7l-.3 .6h.6M123.7 93v.6M123.7 98.3v.1h-.4l-.1-.3 .2-.2 .3 .1v.6l-.4 .2M128.9 81.3h-.8l.2 .3M128.9 80.6h-.8l.2 .1"/>
<path d="M128.9 80.3v.4M128.9 81.1v.5M129.7 81.7v-.6l.4 .3v-.3h.2h.3l-.1 .6M129.7 80.8v-.5l.4 .3 .1-.3h.3v.5M136.2 86.1l.2-.2v.8M136.2 87.8l.2-.2v.8M136.2 89.5l.2-.2v.9M136.2 91.1h.5l-.3 .3 .3 .1v.3h-.5M136.2 92.7h.5l-.3 .4 .3 .1v.3h-.5M136.2 94.4h.5l-.3 .4 .3 .1v.4h-.5M136.2 96.2h.5l-.3 .4h.3v.4h-.5M136.2 86.7h.5"/>
<path d="M136.2 88.4h.5M136.2 90.2h.5M137 87.6h.5l-.2 .3 .2 .2v.3l-.5-.1M137 91.3l.3-.2v.8M137 92.8l.4-.1 .1 .2-.5 .7h.5M137 91.9h.5M137.1 84.5l-.3 .2-.2-.4 .2-.2 .3 .1v.6l-.4 .2M137.1 86l.1-.1a.45 .45 0 0 1 .3 .4 .45 .45 0 0 1-.2 .4l-.3-.3zM137.3 89.3l-.3 .6h.5M137.5 94.4h-.4l-.1 .5 .4-.1 .1 .4-.1 .2-.4-.1M137.5 96.2h-.3l-.2 .7 .2 .2 .3-.2v-.3h-.4l-.1 .1M137.5 89.6v.6"/>
<path d="M153.5 83.5l.2-.2v.8M153.5 85.2l.2-.2v.9M153.5 87l.2-.3v.9M153.5 97.2l.4-.1 .1 .2-.6 .6h.6M153.5 98.8h.3l.2 .2-.6 .6h.6M153.5 84.1h.5M153.5 85.9h.5M153.5 87.6h.5M153.8 91.9h.6l-.4 .8M154 90.5h-.1l.1-.3 .4 .1-.2 .2-.3 .1v.4l.1 .1 .4-.2-.2-.4M154.2 97.1h.6l-.3 .8M154.3 83.4h.4v.3l-.5 .4h.5"/>
<path d="M154.3 85.2l.2-.2v.9M154.3 93.6l-.4 .2v.6h.4l.1-.3-.2-.2-.3 .2M154.3 95.4h-.4v.3l.3-.1 .2 .5-.2 .1-.3-.1M154.3 85.9h.4M154.4 86.7h.2l.1 .2-.1 .7h-.2l-.1-.2zM154.4 88.9h-.5v-.4l.3-.1 .2 .2-.2 .7h-.2M154.6 98.8l-.3 .2v.5h.4v-.3l-.2-.1-.2 .2M161.6 82.5v-.6l.3 .4 .2-.4h.2l.2 .2-.1 .4M162.5 81.1v.6l-.5-.6h-.3v.6M170.6 83.5l.3-.2v.8M170.6 85.2l.3-.2v.9M170.6 87l.3-.3v.9"/>
<path d="M170.6 88.7l.3-.3v.9M170.6 90.4l.3-.2v.9M170.6 92.2l.3-.3v.8M170.6 93.7h.6v.3l-.6 .4h.6M170.6 95.5h.6v.2l-.6 .5h.6M170.6 84.1h.6M170.6 85.9h.6M170.6 87.6h.6M170.6 89.3h.6M170.6 91.1h.6M170.6 92.7h.6M171.5 83.3h.5l-.3 .3 .3 .2-.1 .3-.4-.1"/>
<path d="M171.5 88.4h.5l-.3 .9M171.5 95.5l.2-.1v.8M171.5 96.2h.5M171.7 85l-.2 .6h.5M171.7 90.5l-.2-.1 .1-.2 .4 .1-.5 .4 .2 .4 .3-.2-.2-.4M171.7 93.6a.43 .43 0 0 1 .3 .5 .43 .43 0 0 1-.4 .3l-.1-.5zM171.9 86.7h-.3l-.1 .5 .4-.1v.5l-.4-.1M171.9 85.3v.6M172 92.2l-.1 .2h-.3v-.5h.3l.1 .2-.2 .6h-.2M222.4 80.8l.4-.1 .1 .3-.6 .6h.6M222.4 82.5l.4-.1 .1 .3-.6 .6h.6M223.1 82.7l.3-.3v.9"/>
<path d="M223.1 83.3h.5M223.2 80.8l.4-.1v.2v.5l-.1 .2a.48 .48 0 0 1-.3-.8zM228.8 87.2h.8a.39 .39 0 0 1-.2 .5 .39 .39 0 0 1-.5-.1zM229.7 88.3h-.9l.3 .2M229.7 88v.5M231.3 88v.5l-.4-.5h-.3v.5M231.3 87.2v.5l-.4-.5h-.3v.5M232.3 88.5v-.5l.3 .3v-.3h.4v.5M232.3 87.2h.7l.1 .1a.43 .43 0 0 1-.4 .4 .43 .43 0 0 1-.4-.5zM234.2 88.1h.6M234.6 87.9v.6l-.7-.2M234.8 87.2v.5l-.5-.5h-.3l.1 .5"/>
<path d="M241.3 80.8l.4-.1 .1 .4-.5 .5h.5M241.3 82.5l.4-.1 .1 .4-.5 .5h.5M242.4 82.4l-.3 .6h.6M242.5 82.7v.6M242.6 80.7h-.4l-.1 .4h.5v.4h-.5M28.6 101.5l.4-.1 .1 .2-.6 .6h.6M28.6 103.2l.3-.1 .2 .2-.6 .6h.6M28.6 104.9l.3-.1 .2 .2-.6 .7h.6M28.6 106.6l.4-.1 .1 .3-.6 .6h.6M28.6 108.3l.3-.1 .2 .3-.6 .6h.6M28.6 110h.4l.1 .2-.6 .7h.6M28.6 111.8l.4-.1 .1 .3-.6 .6h.6"/>
<path d="M28.6 113.5l.3-.1 .2 .3-.6 .6h.6M28.6 115.4l.2-.2v.8M28.6 117.1l.2-.2v.8M28.6 116h.5M28.6 117.7h.5M29.3 101.4h.6l-.4 .8M29.3 108.2h.5l-.2 .4 .2 .1v.3h-.5M29.4 110h.4v.4l-.5 .5h.5M29.4 112l.2-.3v.9M29.4 112.6h.4M29.5 100l-.1-.3h.4v.2l-.4 .2 .1 .4h.3v-.4l-.1-.1M29.5 117.2v-.3l.3 .1v.2l-.4 .1v.3l.4 .1v-.4l-.1-.1"/>
<path d="M29.6 106.5l-.2 .6h.5M29.6 113.4l.2 .2v.7h-.3l-.1-.2v-.5zM29.8 103.1l-.4 .2v.5h.4v-.4h-.3l-.1 .2M29.8 106.8v.6M29.8 104.8h-.4v.4h.4v.4h-.4M29.8 115.5l-.3 .2-.1-.4h.4v.5l-.3 .2M42.3 115.2h.5l-.3 .2 .3 .1v.4h-.5M42.3 116.9h.5l-.3 .3 .3 .1v.3h-.5M42.3 118.6h.5l-.3 .3 .3 .1v.3h-.5M42.4 110.2l.2-.2v.9M42.4 112l.2-.3v.9M42.4 113.5h.4v.3l-.5 .5h.5"/>
<path d="M42.4 112.6h.4M42.4 110.9h.4M42.7 106.5h.6l-.4 .9M42.9 108.7l-.2-.3 .2-.2 .3 .1v.3l-.5 .2 .1 .3 .4-.1v-.3h-.2M43.1 116.9h.6l-.4 .8M43.2 115.3h.4v.6l-.1 .1-.3-.1zM43.3 119l-.2-.3 .2-.1 .3 .1v.2l-.4 .1v.4l.4-.1v-.2l-.1-.1M43.6 111.7h-.3l-.2 .7 .1 .2 .4-.1v-.4h-.4l-.1 .1M43.6 110h-.4l-.1 .4h.5v.4h-.5M43.6 113.8l-.1 .2-.4-.2 .2-.4 .3 .1v.6l-.4 .2M60.4 101.5h.5v.2l-.5 .5h.5M60.4 103.2h.5v.2l-.5 .5h.5"/>
<path d="M60.4 104.9h.5v.3l-.5 .5h.5M60.4 106.6h.5v.3l-.5 .5h.5M60.4 108.3h.5v.4l-.5 .4h.5M60.4 110h.5v.4l-.5 .5h.5M60.4 111.8h.5v.3l-.5 .5h.5M60.4 113.5h.5v.3l-.5 .5h.5M60.4 115.4l.3-.2v.8M60.4 117.1l.3-.2v.8M60.4 116h.5M60.4 117.7h.5M61.2 101.4h.6l-.4 .8M61.2 108.2h.6l-.4 .4 .4 .2-.1 .3-.5-.1"/>
<path d="M61.3 110h.4l.1 .2-.6 .7h.6M61.3 112l.2-.3v.9M61.3 112.6h.5M61.4 100l-.1-.1v-.2l.3-.1 .2 .3-.5 .2v.4h.1l.4-.1-.2-.4M61.4 106.5l-.1 .6h.5M61.4 113.4a.43 .43 0 0 1 .4 .5 .43 .43 0 0 1-.5 .4v-.7zM61.4 117.2l-.1-.2 .4-.1v.3l-.4 .1v.4h.4l.1-.3-.2-.2M61.7 103.1l-.4 .2v.5l.4 .1v-.5h-.4v.2M61.7 104.8h-.4v.4l.3-.1 .2 .4-.2 .2-.3-.1M61.7 106.8v.6M61.8 115.5l-.2 .2-.3-.1v-.3h.5l-.2 .6-.3 .1M74.2 110.2l.3-.2v.9"/>
<path d="M74.2 112l.3-.3v.9M74.2 113.5l.3-.1 .2 .2-.5 .7h.5M74.2 115.2h.5l-.3 .2 .3 .2v.3l-.2 .1-.3-.1M74.2 116.9h.5l-.3 .3h.2l.1 .2-.1 .3-.4-.1M74.2 118.6h.5l-.3 .3 .3 .2-.1 .3-.4-.1M74.2 112.6h.5M74.2 110.9h.5M74.5 106.5h.6l-.3 .9M74.8 108.7l-.2-.1v-.3l.4-.1 .1 .3-.1 .2h-.4l.1 .4h.4v-.3l-.1-.1M75 116.9h.6l-.4 .8M75.1 115.3l.1-.1a.43 .43 0 0 1 .4 .4 .43 .43 0 0 1-.4 .4l-.1-.1zM75.2 119l-.1-.1v-.2l.3-.1 .2 .2-.5 .3v.3h.4l.1-.2-.2-.2"/>
<path d="M75.5 110h-.4v.4l.3-.1 .2 .4-.2 .2-.3-.1M75.5 111.7l-.4 .2v.6l.4 .1v-.5h-.4v.1M75.6 113.8l-.2 .2-.3-.1v-.4l.3-.1 .2 .2-.2 .7h-.3M90.5 101.5h.6v.2l-.6 .5h.6M90.5 103.2h.6v.2l-.6 .5h.6M90.5 104.9h.6v.3l-.6 .5h.6M90.5 106.6h.6v.3l-.6 .5h.6M90.5 108.3h.6v.4l-.6 .4h.6M90.5 110h.6v.4l-.6 .5h.6M90.5 111.8h.6v.3l-.6 .5h.6M90.5 113.5h.6v.3l-.6 .5h.6M90.5 115.4l.3-.2v.8"/>
<path d="M90.5 117.1l.3-.2v.8M90.5 116h.6M90.5 117.7h.6M91.3 101.4h.6l-.3 .8M91.3 108.2h.6l-.3 .4 .3 .2-.1 .3-.5-.1M91.4 110h.4l.1 .2-.6 .7h.6M91.4 112l.2-.3v.9M91.4 112.6h.5M91.6 100l-.2-.1v-.2l.3-.1 .2 .3-.5 .2v.4h.2l.3-.1-.2-.4M91.6 106.5l-.2 .6h.5M91.6 113.4a.43 .43 0 0 1 .3 .5 .43 .43 0 0 1-.4 .4l-.1-.7zM91.6 117.2l-.2-.2 .4-.1v.3l-.4 .1 .1 .4h.3l.1-.3-.2-.2"/>
<path d="M91.8 103.1l-.4 .2v.5l.4 .1v-.5h-.3l-.1 .2M91.8 104.8h-.4v.4l.3-.1 .2 .4-.2 .2-.3-.1M91.8 106.8v.6M91.9 115.5l-.2 .2-.3-.1v-.3h.5l-.2 .6-.2 .1M104.3 110.2l.3-.2v.9M104.3 112l.3-.3v.9M104.3 113.5l.4-.1 .2 .2-.6 .7h.6M104.3 115.2h.6l-.4 .2 .4 .2v.3l-.2 .1-.4-.1M104.3 116.9h.6l-.4 .3h.3l.1 .2-.1 .3-.5-.1M104.3 118.6h.6l-.4 .3 .4 .2-.1 .3-.5-.1M104.3 112.6h.6M104.3 110.9h.6"/>
<path d="M104.7 106.5h.6l-.4 .9M104.9 108.7l-.1-.1v-.3l.3-.1 .2 .3-.2 .2h-.3l.1 .4h.3l.1-.3-.2-.1M105.1 116.9h.6l-.3 .8M105.2 115.3l.2-.1a.43 .43 0 0 1 .3 .4 .43 .43 0 0 1-.3 .4l-.2-.1zM105.4 119l-.2-.1v-.2l.3-.1 .2 .2-.5 .3 .1 .3h.3l.1-.2-.2-.2M105.6 110h-.4v.4l.3-.1 .2 .4-.2 .2-.3-.1M105.6 111.7l-.4 .2v.6l.4 .1v-.5h-.3l-.1 .1M105.7 113.8l-.2 .2-.3-.1v-.4l.3-.1 .2 .2-.2 .7h-.2M122.5 101.5l.4-.1v.3l-.5 .5h.5M122.5 103.2l.3-.1 .1 .3-.5 .5h.5M122.5 104.9l.3-.1 .1 .4-.5 .5h.5M122.5 106.6l.4-.1v.4l-.5 .5h.5"/>
<path d="M122.5 108.3l.3-.1 .1 .5-.5 .4h.5M122.5 110h.4v.4l-.5 .5h.5M122.5 111.8l.4-.1v.4l-.5 .5h.5M122.5 113.5l.3-.1 .1 .4-.5 .5h.5M122.5 115.4l.2-.2v.8M122.5 117.1l.2-.2v.8M122.5 116h.4M122.5 117.7h.4M123.2 101.4h.6l-.4 .8M123.2 108.2h.5l-.2 .4 .2 .1v.3h-.5M123.2 110h.5v.4l-.5 .5h.5M123.2 112l.3-.3v.9"/>
<path d="M123.2 112.6h.5M123.3 113.5l.3-.1 .1 .2v.7h-.3l-.2-.3zM123.4 100l-.2-.2 .2-.2 .3 .1v.2l-.4 .1-.1 .2 .2 .3h.3v-.4l-.1-.1M123.4 117.2l-.2-.2 .1-.1h.4v.2l-.5 .3 .1 .3 .4-.1v-.3l-.1-.1M123.5 106.5l-.3 .6h.6M123.7 103.1l-.5 .3v.4l.1 .1 .4-.1v-.4h-.4l-.1 .2M123.7 106.8v.6M123.7 104.8h-.4l-.1 .4h.5v.4h-.5M123.7 115.5l-.3 .2-.2-.4h.5v.6l-.4 .1M136.2 110.2l.2-.2v.9M136.2 112l.2-.3v.9M136.2 113.5h.5v.3l-.5 .5h.5"/>
<path d="M136.2 115.2h.5l-.3 .2 .3 .1v.4h-.5M136.2 116.9h.5l-.3 .3 .3 .1v.3h-.5M136.2 118.6h.5l-.3 .3 .3 .1v.3h-.5M136.2 112.6h.5M136.2 110.9h.5M136.6 106.5h.6l-.4 .9M136.8 108.7l-.2-.3 .2-.2 .3 .1v.3l-.5 .2 .1 .3 .4-.1v-.3h-.2M137 116.9h.5l-.3 .8M137.1 115.3l.2-.1a.47 .47 0 0 1 .2 .4 .47 .47 0 0 1-.2 .4l-.3-.3zM137.2 119l-.2-.3 .4-.1 .1 .2-.4 .2-.1 .2 .1 .2h.4v-.2l-.1-.2M137.5 110h-.4l-.1 .4 .4-.1 .1 .4-.1 .2-.4-.1M137.5 111.7h-.3l-.2 .4 .1 .5h.4v-.5h-.4l-.1 .1"/>
<path d="M137.5 113.8l-.1 .2-.4-.2 .2-.4 .3 .2v.3l-.1 .4h-.3M153.4 112.6h.6l-.4 .3h.3l.1 .2-.1 .3-.5-.1M153.4 117.7h.6l-.4 .4h.3l.1 .1-.1 .4-.5-.1M153.5 100.6l.4-.1 .1 .3-.6 .6h.6M153.5 102.3l.4-.1 .1 .3-.6 .6h.6M153.5 105.8l.4-.1 .1 .3-.6 .5h.6M153.5 107.5l.4-.1 .1 .3-.6 .5h.6M153.8 109.1h.6l-.4 .3 .4 .2v.3l-.2 .1-.4-.1M153.9 111l.4-.1 .1 .2-.6 .6h.6M153.9 114.5l.2-.2v.9M153.9 115.2h.5M154 103.9l-.1 .6h.5"/>
<path d="M154.2 100.5h.5l-.2 .3 .2 .1v.4h-.5M154.3 118l.2-.3v.9M154.3 104.3v.5M154.3 118.6h.4M154.5 106l-.2-.2 .3-.1 .1 .3-.4 .1v.4h.2h.2v-.4l-.1-.1M154.5 112.6l.2 .1-.1 .7h-.2l-.1-.2v-.5zM154.7 102.2h-.4v.5h.4l-.1 .4-.3-.1M154.7 107.7l-.1 .2h-.2l-.1-.4h.4v.6l-.3 .1M28.6 124.8l.2-.2v.9M28.6 125.5h.5M28.7 122.9l-.1 .6h.5M28.7 126.3l-.1 .7h.5"/>
<path d="M29 123.1v.6M29 126.6v.6M29.3 124.6h.6l-.4 .9M29.4 121.2l-.4 .2v.6h.3l.2-.1-.1-.4h-.3l-.1 .2M29.4 126.6l.2-.2v.8M29.4 127.2h.4M29.6 122.9l.2 .2v.6h-.3l-.1-.1v-.5zM35 130.4h-.8l.2 .3M35 129.3v.6l-.6-.6-.2 .1v.4M35 130.2v.5M35.9 130.7v-.5l.3 .3 .2-.3 .3 .1-.1 .4M36.2 129.4h.5"/>
<path d="M36.4 129.3v.5l-.5-.1M60.4 124.8l.3-.2v.9M60.4 125.5h.5M60.7 122.9l-.3 .6h.6M60.7 126.3l-.3 .7h.6M60.8 123.1v.6M60.8 126.6v.6M61.2 124.6h.6l-.4 .9M61.3 121.2h-.3l-.2 .7 .2 .1 .3-.1v-.4h-.4l-.1 .2M61.3 126.6l.2-.2v.8M61.3 127.2h.5M61.4 122.9a.43 .43 0 0 1 .4 .5 .43 .43 0 0 1-.5 .3v-.6z"/>
<path d="M66.8 130.4h-.8l.2 .3M66.8 129.3v.6l-.6-.6-.2 .2 .1 .3M66.8 130.2v.5M67.8 130.7v-.5l.3 .3 .1-.3h.2l.2 .1-.1 .4M68 129.4h.6M68.3 129.3v.5l-.6-.1M90.5 124.8l.3-.2v.9M90.5 125.5h.6M90.8 122.9l-.3 .6h.6M90.8 126.3l-.3 .7h.6M91 123.1v.6M91 126.6v.6"/>
<path d="M91.3 124.6h.6l-.3 .9M91.4 121.2h-.3l-.1 .7 .1 .1 .4-.1-.1-.4h-.3l-.1 .2M91.4 126.6l.2-.2v.8M91.4 127.2h.5M91.6 122.9a.43 .43 0 0 1 .3 .5 .43 .43 0 0 1-.4 .3l-.1-.6zM97.1 130.4h-1l.3 .3M97.1 129.3v.6l-.7-.6-.3 .2 .1 .3M97.1 130.2v.5M97.9 130.7v-.5l.4 .3v-.3h.3l.2 .1-.1 .4M98.2 129.4h.6M98.4 129.3v.5l-.6-.1M122.5 124.8l.2-.2v.9"/>
<path d="M122.5 125.5h.4M122.6 122.9l-.1 .6h.5M122.6 126.3l-.1 .7h.5M122.9 123.1v.6M122.9 126.6v.6M123.2 121.2h-.2l-.1 .2v.6h.4l-.1-.5h-.3v.2M123.2 124.6h.6l-.4 .9M123.2 126.6l.3-.2v.8M123.2 127.2h.5M123.3 123l.3-.1 .1 .2v.6a.39 .39 0 0 1-.5-.3 .39 .39 0 0 1 .1-.4zM128.9 130.4h-.8l.2 .3M128.9 129.3v.6l-.6-.6-.2 .1v.4"/>
<path d="M128.9 130.2v.5M129.7 130.7v-.5l.4 .3v-.2l.2-.1 .3 .1-.1 .4M130 129.4h.6M130.3 129.3v.5l-.6-.1M153.5 121.3l.4-.1 .1 .3-.6 .5h.6M153.5 123l.3-.1 .2 .2-.6 .6h.6M154.3 121.3l.3-.1 .1 .3-.5 .5h.5M154.5 122.9l-.2 .6h.5M154.6 123.1v.6M161.6 126l.1 .3 .6 .1 .2-.1-.1-.4h-.4l-.1 .4 .2 .1M162.5 127h-.9l.2 .2M162.5 126.7v.5"/>
</g>
<g fill="none" stroke="#006665" stroke-width=".21">
<path d="M30.7 26.2l.2-.8 .4 .8M30.7 27.9l.2-.9 .4 .9M30.7 29.7l.2-1 .4 1M30.7 31.4l.2-.9 .4 .9M30.7 33.1l.2-.9 .4 .9M30.7 34.8l.2-.8 .4 .8M30.7 36.5l.2-.8 .4 .8M30.7 38.2l.2-.8 .4 .8M30.8 25.9h.4M30.8 27.6h.4M30.8 29.4h.4M30.8 31.1h.4"/>
<path d="M30.8 32.8h.4M30.8 34.6h.4M30.8 36.3h.4M30.8 38h.4M30.8 39.7h.4M31.5 30.5h.5l-.3 .4h.3v.4h-.5M31.5 37.4h.5l-.4 .8M31.5 25.4h.4l.1 .1v.5l-.2 .2-.3-.1zM31.5 27.3l.2-.3v.9M31.5 28.8h.5v.4l-.5 .5h.5M31.5 27.9h.5M31.6 39.5l-.1-.3h.5v.2l-.5 .1 .1 .5 .4-.1v-.3l-.2-.1"/>
<path d="M31.7 32.2l-.2 .6h.5M31.9 35.7h-.3l-.1 .2v.6l.5-.1-.1-.4h-.4v.2M31.9 32.6v.5M32 34h-.5v.3h.5v.5h-.5M34.8 24.7l.8 .2-.8 .4M34.8 24.2l.2-.3h.4l.2 .2v.3h-.8zM34.8 23.3l.2-.2h.4l.2 .4h-.8zM36.5 24.7l.9 .2-.9 .4M36.5 24.1l.2-.2h.4l.3 .3v.2h-.9zM36.7 23.1h.4l.3 .4h-.9zM39.7 25.4v.8M39.7 27v.9"/>
<path d="M39.7 28.7v1M39.7 30.5v.9M39.7 32.2v.9M39.7 34v.8M39.7 35.7v.8M39.7 37.4v.8M40.1 25.4h.5v.7h-.5zM40.1 28.9l.2-.2 .3 .2v.6l-.2 .2-.3-.2zM40.1 32.4l.2-.2 .3 .2-.1 .7-.4-.1zM40.1 34.1h.5v.6l-.2 .1-.3-.1zM40.1 35.8h.5l-.1 .7-.4-.1zM40.2 30.5l.4 .1-.1 .8-.4-.1z"/>
<path d="M40.3 27l.3 .2-.1 .7-.4-.1v-.6zM40.3 37.4l.3 .1-.1 .7-.4-.1v-.6zM40.9 27.3l.3-.3v.9M40.9 28.8h.5v.4l-.5 .5h.5M40.9 30.5h.5l-.2 .4h.2v.4h-.5M40.9 37.4h.6l-.4 .8M40.9 27.9h.5M41 25.4h.4v.1v.5l-.1 .2a.48 .48 0 0 1-.3-.8zM41.2 32.2l-.3 .6h.6M41.4 35.7h-.3l-.2 .7 .1 .1 .4-.1v-.4h-.4l-.1 .2M41.4 32.6v.5M41.4 34h-.4l-.1 .3h.5v.5h-.5"/>
<path d="M62.5 26.2l.4-.8 .2 .8M62.5 27.9l.4-.9 .2 .9M62.5 29.7l.4-1 .2 1M62.5 31.4l.4-.9 .2 .9M62.5 33.1l.4-.9 .2 .9M62.5 34.8l.4-.8 .2 .8M62.5 36.5l.4-.8 .2 .8M62.5 38.2l.4-.8 .2 .8M62.6 25.9h.4M62.6 27.6h.4M62.6 29.4h.4M62.6 31.1h.4"/>
<path d="M62.6 32.8h.4M62.6 34.6h.4M62.6 36.3h.4M62.6 38h.4M62.6 39.7h.4M63.3 30.5h.6l-.4 .4h.3l.1 .1-.1 .4-.5-.1M63.3 37.4h.6l-.4 .8M63.4 27.3l.2-.3v.9M63.4 28.8l.3-.1 .2 .3-.6 .7h.6M63.4 27.9h.5M63.5 25.4a.43 .43 0 0 1 .4 .3 .43 .43 0 0 1-.4 .5l-.1-.2zM63.5 32.2l-.1 .6h.5"/>
<path d="M63.5 39.5l-.1-.1 .1-.2h.4l-.2 .3-.3 .1v.3l.1 .1 .4-.2-.2-.3M63.8 34h-.4v.3l.3-.1 .2 .5-.2 .1h-.3M63.8 35.7l-.4 .2v.5l.4 .1v-.5h-.3l-.1 .2M63.8 32.6v.5M66.7 24.7l.8 .2-.8 .4M66.7 24.1l.1-.2h.5l.2 .3v.2h-.8zM66.8 23.1h.5l.2 .4h-.8zM68.4 24.7l.8 .2-.8 .4M68.4 24l.6-.1 .2 .2v.3h-.8zM68.4 23.2l.6-.1 .2 .4h-.8zM71.6 25.4v.8M71.6 27v.9"/>
<path d="M71.6 28.7v1M71.6 30.5v.9M71.6 32.2v.9M71.6 34v.8M71.6 35.7v.8M71.6 37.4v.8M72 25.4h.3l.2 .2v.3l-.2 .3-.4-.3zM72 30.6l.3-.1 .2 .3-.2 .6h-.2l-.2-.3zM72 34.1h.4a.48 .48 0 0 1-.2 .7 .52 .52 0 0 1-.2-.7zM72 35.8l.3-.1 .2 .2-.2 .6h-.2l-.2-.2zM72.2 27h.1a.52 .52 0 0 1 0 .9l-.3-.1a.52 .52 0 0 1 .2-.8zM72.2 28.7h.1a.5 .5 0 0 1 .2 .5 .5 .5 0 0 1-.3 .5 .54 .54 0 0 1 0-1z"/>
<path d="M72.2 32.2h.1a.52 .52 0 0 1 0 .9l-.3-.1a.52 .52 0 0 1 .2-.8zM72.2 37.4h.1a.52 .52 0 0 1 0 .8l-.3-.1a.52 .52 0 0 1 .2-.7zM72.8 30.5h.6l-.4 .4h.3v.5l-.5-.1M72.8 37.4h.6l-.4 .8M72.9 27.3l.2-.3v.9M72.9 28.8l.3-.1 .2 .3-.6 .7h.6M72.9 27.9h.5M72.9 25.4a.43 .43 0 0 1 .5 .3 .43 .43 0 0 1-.4 .5l-.1-.2zM73 32.2l-.1 .6h.5M73.3 34h-.4v.3l.3-.1 .2 .5-.2 .1h-.3M73.3 35.7l-.4 .2v.5l.4 .1v-.5h-.4v.2M73.3 32.6v.5"/>
<path d="M92.7 26.2l.3-.8 .3 .8M92.7 27.9l.3-.9 .3 .9M92.7 29.7l.3-1 .3 1M92.7 31.4l.3-.9 .3 .9M92.7 33.1l.3-.9 .3 .9M92.7 34.8l.3-.8 .3 .8M92.7 36.5l.3-.8 .3 .8M92.7 38.2l.3-.8 .3 .8M92.7 25.9h.5M92.7 27.6h.5M92.7 29.4h.5M92.7 31.1h.5"/>
<path d="M92.7 32.8h.5M92.7 34.6h.5M92.7 36.3h.5M92.7 38h.5M92.7 39.7h.5M93.4 30.5h.6l-.3 .4h.2l.1 .1-.1 .4-.5-.1M93.4 37.4h.6l-.3 .8M93.5 27.3l.3-.3v.9M93.5 28.8l.3-.1 .2 .3-.6 .7h.6M93.5 27.9h.5M93.6 25.4a.43 .43 0 0 1 .4 .3 .43 .43 0 0 1-.3 .5l-.2-.2zM93.7 32.2l-.2 .6h.5"/>
<path d="M93.7 39.5l-.2-.3h.4l.1 .1-.5 .3v.3l.2 .1 .3-.2-.2-.3M93.9 34h-.4v.3l.3-.1 .2 .5-.2 .1h-.3M93.9 35.7l-.4 .2v.5l.4 .1v-.5h-.3l-.1 .2M93.9 32.6v.5M96.8 24.7l.9 .2-.9 .4M96.8 24.1l.2-.2h.4l.3 .3v.2h-.9zM96.8 23.2l.2-.1h.4l.3 .4h-.9zM98.5 24.7l.9 .2-.9 .4M98.7 23.9h.5l.2 .2v.3h-.9zM98.7 23.1h.5l.2 .4h-.9zM101.7 25.4v.8M101.7 27v.9"/>
<path d="M101.7 28.7v1M101.7 30.5v.9M101.7 32.2v.9M101.7 34v.8M101.7 35.7v.8M101.7 37.4v.8M102.1 25.4h.4l.2 .2v.3l-.3 .3-.3-.3zM102.1 30.6l.4-.1 .2 .3-.2 .6h-.3l-.1-.3zM102.1 34.1h.5a.48 .48 0 0 1-.3 .7 .52 .52 0 0 1-.2-.7zM102.1 35.8l.4-.1 .2 .2-.2 .6h-.3l-.1-.2zM102.3 27h.1a.52 .52 0 0 1 .1 .9l-.4-.1a.52 .52 0 0 1 .2-.8zM102.3 28.7h.1a.5 .5 0 0 1 .3 .5 .5 .5 0 0 1-.4 .5 .54 .54 0 0 1 0-1z"/>
<path d="M102.3 32.2h.1a.52 .52 0 0 1 .1 .9l-.4-.1a.52 .52 0 0 1 .2-.8zM102.3 37.4h.1a.52 .52 0 0 1 .1 .8l-.4-.1a.52 .52 0 0 1 .2-.7zM102.9 30.5h.6l-.3 .4h.2l.1 .1-.1 .4-.5-.1M102.9 37.4h.6l-.3 .8M103 27.3l.2-.3v.9M103 28.8l.3-.1 .2 .3-.6 .7h.6M103 27.9h.5M103.1 25.4a.43 .43 0 0 1 .4 .3 .43 .43 0 0 1-.3 .5l-.2-.2zM103.2 32.2l-.2 .6h.5M103.4 34h-.4v.3l.3-.1 .2 .5-.2 .1h-.3M103.4 35.7l-.4 .2v.5l.4 .1v-.5h-.3l-.1 .2M103.4 32.6v.5"/>
<path d="M124.6 26.2l.2-.8 .3 .8M124.6 27.9l.2-.9 .3 .9M124.6 29.7l.2-1 .3 1M124.6 31.4l.2-.9 .3 .9M124.6 33.1l.2-.9 .3 .9M124.6 34.8l.2-.8 .3 .8M124.6 36.5l.2-.8 .3 .8M124.6 38.2l.2-.8 .3 .8M124.7 25.9h.3M124.7 27.6h.3M124.7 29.4h.3M124.7 31.1h.3"/>
<path d="M124.7 32.8h.3M124.7 34.6h.3M124.7 36.3h.3M124.7 38h.3M124.7 39.7h.3M125.3 27.3l.3-.3v.9M125.3 28.8h.6v.4l-.6 .5h.6M125.3 30.5h.6l-.3 .4h.3v.4h-.6M125.3 37.4h.6l-.4 .8M125.3 27.9h.6M125.5 25.4h.3l.1 .1v.5l-.2 .2a.48 .48 0 0 1-.4-.4 .48 .48 0 0 1 .2-.4zM125.5 39.5l-.2-.3h.5l.1 .2-.5 .1-.1 .2 .2 .3 .4-.1v-.3l-.2-.1"/>
<path d="M125.6 32.2l-.3 .6h.6M125.8 35.7h-.3l-.2 .7 .1 .1 .5-.1-.1-.4h-.4l-.1 .2M125.8 32.6v.5M125.9 34h-.5l-.1 .3h.6v.5h-.6M128.6 24.7l.9 .2-.9 .4M128.6 24.2l.3-.3h.4l.2 .2v.3h-.9zM128.6 23.3l.3-.2h.4l.2 .4h-.9zM130.3 24.7l1 .2-1 .4M130.3 24.2l.3-.3h.4l.3 .3v.2h-1zM130.3 23.3l.3-.2h.4l.3 .4h-1zM133.6 25.4v.8M133.6 27v.9"/>
<path d="M133.6 28.7v1M133.6 30.5v.9M133.6 32.2v.9M133.6 34v.8M133.6 35.7v.8M133.6 37.4v.8M134 25.4h.5v.7h-.5zM134 30.6h.5l-.1 .8-.4-.1zM134 34.1h.5v.6l-.2 .1-.3-.1zM134 35.8h.5l-.1 .7-.4-.1zM134.2 27l.3 .2-.1 .7-.4-.1v-.6zM134.2 28.7l.3 .2v.6l-.2 .2-.3-.2v-.6z"/>
<path d="M134.2 32.2l.3 .2-.1 .7-.4-.1v-.6zM134.2 37.4l.3 .1-.1 .7-.4-.1v-.6zM134.8 27.3l.3-.3v.9M134.8 28.8h.5v.4l-.5 .5h.5M134.8 30.5h.5l-.2 .4h.2v.4h-.5M134.8 37.4h.5l-.3 .8M134.8 27.9h.5M134.9 25.4h.4v.1v.5l-.1 .2a.48 .48 0 0 1-.3-.8zM135.1 32.2l-.3 .6h.5M135.3 35.7h-.3l-.2 .7 .1 .1 .4-.1v-.4h-.4l-.1 .2M135.3 32.6v.5M135.3 34h-.4l-.1 .3h.5v.5h-.5"/>
<path d="M156.4 24.5l.3-.9 .3 .9M156.4 26.2l.3-.8 .3 .8M156.4 27.9l.3-.9 .3 .9M156.4 29.7l.3-1 .3 1M156.4 31.4l.3-.9 .3 .9M156.4 33.1l.3-.9 .3 .9M156.4 34.8l.3-.8 .3 .8M156.4 36.5l.3-.8 .3 .8M156.4 38.2l.3-.8 .3 .8M156.5 24.3h.4M156.5 25.9h.4M156.5 27.6h.4"/>
<path d="M156.5 29.4h.4M156.5 31.1h.4M156.5 32.8h.4M156.5 34.6h.4M156.5 36.3h.4M156.5 38h.4M156.5 39.7h.4M157.2 28.7h.6l-.4 .4 .4 .1v.3l-.2 .2-.4-.1M157.2 35.7h.6l-.4 .8M157.3 25.6l.2-.2v.8M157.3 27.1l.3-.1 .2 .3-.6 .6h.6M157.3 26.2h.5"/>
<path d="M157.4 23.6a.48 .48 0 0 1 .4 .4 .48 .48 0 0 1-.4 .5l-.1-.2v-.6zM157.4 30.4l-.1 .7h.5M157.4 37.8l-.1-.1v-.2l.3-.1 .2 .2-.5 .3v.3h.4l.1-.2-.2-.2M157.7 32.2h-.4v.4h.3l.2 .1-.1 .4-.4-.1M157.7 34h-.4v.2v.6h.3l.2-.4-.2-.2-.3 .2M157.7 30.8v.6M157.8 39.5l-.4 .2-.1-.1v-.4h.5l-.2 .7-.3 .1M162.3 25.5l.8 .4-.8 .2M162.3 24.8v.3l.1 .2h.5l.2-.2-.1-.3M162.3 23.9v.4l.1 .1h.5l.2-.1-.1-.4M167.6 23.6h.2l.3 .2v.5l-.3 .2h-.2zM167.6 25.4h.3l.2 .1v.5l-.3 .2h-.2z"/>
<path d="M167.6 27h.2l.3 .3v.4l-.2 .2h-.3zM167.6 28.7h.2l.3 .3v.4l-.3 .3h-.2zM167.6 30.5h.3l.2 .2v.5l-.2 .2h-.3zM167.6 32.2h.2l.3 .3v.4l-.2 .2h-.3zM167.6 34h.3l.2 .2v.4l-.3 .2h-.2zM167.6 35.7h.3l.2 .2v.5l-.2 .1h-.3zM168.4 28.7h.5l-.3 .4 .3 .1v.3l-.1 .2-.4-.1M168.4 35.7h.5l-.3 .8M168.4 25.6l.3-.2v.8M168.4 27.1l.4-.1 .1 .3-.5 .6h.5M168.4 26.2h.5M168.6 23.6a.48 .48 0 0 1 .4 .4 .48 .48 0 0 1-.4 .5l-.2-.2v-.6z"/>
<path d="M168.6 30.4l-.2 .7h.5M168.9 32.2h-.5v.4h.4l.1 .1v.4l-.5-.1M168.9 34h-.4l-.1 .2v.6h.4l.1-.4-.1-.2-.4 .2M168.9 30.8v.6M30.7 40l.2-.8 .4 .8M30.7 41.7l.2-.9 .4 .9M30.7 43.4l.2-.9 .4 .9M30.7 45.2l.2-.9 .4 .9M30.7 46.9l.2-.9 .4 .9M30.7 48.6l.2-.9 .4 .9M30.7 50.3l.2-.8 .4 .8M30.7 52l.2-.8 .4 .8"/>
<path d="M30.7 53.7l.2-.8 .4 .8M30.7 55.5l.2-.9 .4 .9M30.7 57.2l.2-.9 .4 .9M30.7 59l.2-1 .4 1M30.8 41.4h.4M30.8 43.2h.4M30.8 44.9h.4M30.8 46.6h.4M30.8 48.4h.4M30.8 50.1h.4M30.8 51.8h.4M30.8 53.5h.4"/>
<path d="M30.8 55.2h.4M30.8 56.9h.4M30.8 58.7h.4M31.5 42.8l.2-.3v.9M31.5 44.5l.2-.2v.9M31.5 46.3l.2-.3v.9M31.5 48l.2-.3v.9M31.5 49.7l.2-.2v.8M31.5 51.4l.2-.2v.8M31.5 53.1l.2-.2v.8M31.5 54.9l.2-.3v.9M31.5 56.6l.2-.3v.9"/>
<path d="M31.5 58.3l.2-.3v1M31.5 43.4h.5M31.5 45.2h.5M31.5 46.9h.5M31.5 48.6h.5M31.5 50.3h.5M31.5 52h.5M31.5 53.7h.5M31.5 55.5h.5M31.5 57.2h.5M31.5 59h.5M32 41.2l-.1 .2h-.4v-.6l.5 .1v.6l-.5 .2"/>
<path d="M32.3 44.5l.3-.2v.9M32.3 46.1h.5v.3l-.5 .5h.5M32.3 47.7h.5l-.2 .3 .2 .1v.4h-.5M32.3 54.6h.6l-.4 .9M32.3 45.2h.5M32.4 42.6l.2-.1 .2 .2-.1 .7h-.2l-.2-.3zM32.5 56.7l-.2-.2 .1-.2h.3l.1 .3-.5 .3 .1 .3 .4-.1v-.3l-.2-.1M32.6 49.4l-.3 .6h.6M32.7 52.9l-.2 .1-.2 .6 .5 .1v-.4l-.3-.1-.2 .2M32.7 49.7v.6M32.8 51.2h-.4l-.1 .4 .4-.1 .1 .4h-.5M32.8 58.5l-.3 .1-.2-.4 .2-.2 .3 .1-.1 .8-.3 .1"/>
<path d="M40.6 47.7v.9l-.5-.9v.9M40.6 49.5v.8l-.5-.8v.8M40.6 51.2v.8l-.5-.8v.8M40.6 52.9v.8l-.5-.8v.8M40.6 54.6v.9l-.5-.9v.9M40.6 56.3v.9l-.5-.9v.9M40.6 58v1l-.5-1v1M40.6 59.8v.9l-.5-.9v.9M41.4 47.8l-.2-.1-.3 .3v.4l.2 .2 .3-.1M41.4 49.6l-.3-.1-.2 .2v.4l.3 .2 .2-.1M41.4 51.3l-.3-.1-.2 .1v.6l.2 .1 .3-.1M41.4 53l-.2-.1-.3 .2v.4l.2 .2h.3"/>
<path d="M41.4 54.7l-.3-.1-.2 .2v.4l.3 .3 .2-.1M41.4 56.4l-.3-.1-.2 .2v.5l.2 .2 .3-.1M41.4 58.1l-.2-.1-.3 .3v.4l.3 .3 .2-.1M41.4 59.9l-.3-.1-.2 .2v.4l.3 .3 .2-.1M62.5 40l.4-.8 .2 .8M62.5 41.7l.4-.9 .2 .9M62.5 43.4l.4-.9 .2 .9M62.5 45.2l.4-.9 .2 .9M62.5 46.9l.4-.9 .2 .9M62.5 48.6l.4-.9 .2 .9M62.5 50.3l.4-.8 .2 .8M62.5 52l.4-.8 .2 .8"/>
<path d="M62.5 53.7l.4-.8 .2 .8M62.5 55.5l.4-.9 .2 .9M62.5 57.2l.4-.9 .2 .9M62.5 59l.4-1 .2 1M62.6 41.4h.4M62.6 43.2h.4M62.6 44.9h.4M62.6 46.6h.4M62.6 48.4h.4M62.6 50.1h.4M62.6 51.8h.4M62.6 53.5h.4"/>
<path d="M62.6 55.2h.4M62.6 56.9h.4M62.6 58.7h.4M63.4 42.8l.2-.3v.9M63.4 44.5l.2-.2v.9M63.4 46.3l.2-.3v.9M63.4 48l.2-.3v.9M63.4 49.7l.2-.2v.8M63.4 51.4l.2-.2v.8M63.4 53.1l.2-.2v.8M63.4 54.9l.2-.3v.9M63.4 56.6l.2-.3v.9"/>
<path d="M63.4 58.3l.2-.3v1M63.4 43.4h.5M63.4 45.2h.5M63.4 46.9h.5M63.4 48.6h.5M63.4 50.3h.5M63.4 52h.5M63.4 53.7h.5M63.4 55.5h.5M63.4 57.2h.5M63.4 59h.5M63.9 41.2l-.1 .2h-.3l-.1-.5 .4-.1 .1 .2-.2 .7h-.2"/>
<path d="M64.1 47.7h.5l-.2 .3 .2 .1v.4h-.5M64.1 54.6h.6l-.3 .9M64.2 44.5l.3-.2v.9M64.2 46.1l.4-.1v.4l-.5 .5h.5M64.2 45.2h.4M64.4 42.5l.2 .2v.7h-.3l-.1-.2v-.5zM64.4 49.4l-.2 .6h.5M64.4 56.7l-.2-.3 .4-.1v.3l-.4 .2 .1 .4 .3-.1v-.3l-.1-.1M64.6 52.9l-.4 .2v.6h.4v-.4l-.2-.1-.2 .2M64.6 49.7v.6M64.6 51.2h-.4v.4h.4v.4l-.4-.1M64.6 58.5l-.1 .1-.3-.1v-.4h.4v.6l-.3 .3"/>
<path d="M72.4 47.7v.9l-.5-.9v.9M72.4 49.5v.8l-.5-.8v.8M72.4 51.2v.8l-.5-.8v.8M72.4 52.9v.8l-.5-.8v.8M72.4 54.6v.9l-.5-.9v.9M72.4 56.3v.9l-.5-.9v.9M72.4 58v1l-.5-1v1M72.4 59.8v.9l-.5-.9v.9M73.4 47.8a.44 .44 0 0 0-.6 .2 .44 .44 0 0 0 .1 .6l.5-.1M73.4 49.6l-.5-.1a.44 .44 0 0 0-.1 .5 .44 .44 0 0 0 .6 .2M73.4 51.3l-.5-.1-.1 .3 .1 .5 .5-.1M73.4 53a.44 .44 0 0 0-.6 .1 .44 .44 0 0 0 .1 .6h.5"/>
<path d="M73.4 54.7l-.5-.1a.44 .44 0 0 0-.1 .6 .44 .44 0 0 0 .6 .2M73.4 56.4l-.5-.1-.1 .4 .1 .5 .5-.1M73.4 58.1a.42 .42 0 0 0-.6 .4 .42 .42 0 0 0 .6 .4M73.4 59.9l-.5-.1a.44 .44 0 0 0-.1 .6 .44 .44 0 0 0 .6 .2M92.7 40l.3-.8 .3 .8M92.7 41.7l.3-.9 .3 .9M92.7 43.4l.3-.9 .3 .9M92.7 45.2l.3-.9 .3 .9M92.7 46.9l.3-.9 .3 .9M92.7 48.6l.3-.9 .3 .9M92.7 50.3l.3-.8 .3 .8M92.7 52l.3-.8 .3 .8"/>
<path d="M92.7 53.7l.3-.8 .3 .8M92.7 55.5l.3-.9 .3 .9M92.7 57.2l.3-.9 .3 .9M92.7 59l.3-1 .3 1M92.7 41.4h.5M92.7 43.2h.5M92.7 44.9h.5M92.7 46.6h.5M92.7 48.4h.5M92.7 50.1h.5M92.7 51.8h.5M92.7 53.5h.5"/>
<path d="M92.7 55.2h.5M92.7 56.9h.5M92.7 58.7h.5M93.5 42.8l.3-.3v.9M93.5 44.5l.3-.2v.9M93.5 46.3l.3-.3v.9M93.5 48l.3-.3v.9M93.5 49.7l.3-.2v.8M93.5 51.4l.3-.2v.8M93.5 53.1l.3-.2v.8M93.5 54.9l.3-.3v.9M93.5 56.6l.3-.3v.9"/>
<path d="M93.5 58.3l.3-.3v1M93.5 43.4h.5M93.5 45.2h.5M93.5 46.9h.5M93.5 48.6h.5M93.5 50.3h.5M93.5 52h.5M93.5 53.7h.5M93.5 55.5h.5M93.5 57.2h.5M93.5 59h.5M94 41.2l-.1 .2h-.3l-.1-.5 .4-.1 .1 .2-.2 .7h-.2"/>
<path d="M94.3 47.7h.5l-.3 .3 .3 .1v.4h-.5M94.3 54.6h.6l-.4 .9M94.4 44.5l.2-.2v.9M94.4 46.1l.3-.1 .1 .4-.5 .5h.5M94.4 45.2h.4M94.5 42.5l.3 .2-.1 .7h-.3v-.2v-.5zM94.5 49.4l-.1 .6h.5M94.5 56.7l-.1-.3 .3-.1 .1 .3-.4 .2v.4l.4-.1-.1-.4M94.7 52.9l-.3 .2v.6h.4l-.1-.5-.3 .2M94.7 49.7v.6M94.8 51.2h-.4v.4l.3-.1 .1 .4h-.4M94.8 58.5l-.1 .1-.3-.1v-.4h.4v.6l-.4 .3"/>
<path d="M102.6 47.7v.9l-.5-.9v.9M102.6 49.5v.8l-.5-.8v.8M102.6 51.2v.8l-.5-.8v.8M102.6 52.9v.8l-.5-.8v.8M102.6 54.6v.9l-.5-.9v.9M102.6 56.3v.9l-.5-.9v.9M102.6 58v1l-.5-1v1M102.6 59.8v.9l-.5-.9v.9M103.5 47.8a.44 .44 0 0 0-.6 .2 .44 .44 0 0 0 .2 .6l.4-.1M103.5 49.6l-.4-.1a.44 .44 0 0 0-.1 .5 .44 .44 0 0 0 .5 .2M103.5 51.3l-.4-.1-.2 .3 .2 .5 .4-.1M103.5 53a.44 .44 0 0 0-.6 .1 .44 .44 0 0 0 .2 .6h.4"/>
<path d="M103.5 54.7l-.4-.1a.44 .44 0 0 0-.1 .6 .44 .44 0 0 0 .5 .2M103.5 56.4l-.4-.1-.2 .4 .2 .5 .4-.1M103.5 58.1a.42 .42 0 0 0-.6 .4 .42 .42 0 0 0 .6 .4M103.5 59.9l-.4-.1a.44 .44 0 0 0-.1 .6 .44 .44 0 0 0 .5 .2M124.6 40l.2-.8 .3 .8M124.6 41.7l.2-.9 .3 .9M124.6 43.4l.2-.9 .3 .9M124.6 45.2l.2-.9 .3 .9M124.6 46.9l.2-.9 .3 .9M124.6 48.6l.2-.9 .3 .9M124.6 50.3l.2-.8 .3 .8M124.6 52l.2-.8 .3 .8"/>
<path d="M124.6 53.7l.2-.8 .3 .8M124.6 55.5l.2-.9 .3 .9M124.6 57.2l.2-.9 .3 .9M124.6 59l.2-1 .3 1M124.7 41.4h.3M124.7 43.2h.3M124.7 44.9h.3M124.7 46.6h.3M124.7 48.4h.3M124.7 50.1h.3M124.7 51.8h.3M124.7 53.5h.3"/>
<path d="M124.7 55.2h.3M124.7 56.9h.3M124.7 58.7h.3M125.3 42.8l.3-.3v.9M125.3 44.5l.3-.2v.9M125.3 46.3l.3-.3v.9M125.3 48l.3-.3v.9M125.3 49.7l.3-.2v.8M125.3 51.4l.3-.2v.8M125.3 53.1l.3-.2v.8M125.3 54.9l.3-.3v.9M125.3 56.6l.3-.3v.9"/>
<path d="M125.3 58.3l.3-.3v1M125.3 43.4h.6M125.3 45.2h.6M125.3 46.9h.6M125.3 48.6h.6M125.3 50.3h.6M125.3 52h.6M125.3 53.7h.6M125.3 55.5h.6M125.3 57.2h.6M125.3 59h.6M125.9 41.2l-.1 .2h-.4v-.6l.5 .1v.6l-.5 .2"/>
<path d="M126.2 44.5l.2-.2v.9M126.2 46.1l.4-.1 .1 .2-.5 .7h.5M126.2 47.7h.5l-.3 .3 .3 .2v.3h-.5M126.2 54.6h.5l-.3 .9M126.2 45.2h.5M126.4 42.5a.43 .43 0 0 1 .3 .5 .43 .43 0 0 1-.4 .4l-.1-.5zM126.4 49.4l-.2 .6h.5M126.4 56.7l-.2-.2 .1-.2h.3v.4l-.4 .2 .1 .3h.3l.1-.2-.2-.3M126.6 51.2h-.3l-.1 .4 .4-.1v.5l-.4-.1M126.6 52.9l-.3 .1-.1 .6h.5l-.2-.4-.3 .2M126.6 49.7v.6M126.7 58.5l-.3 .1-.2-.4 .2-.2 .3 .2-.2 .7-.2 .1"/>
<path d="M134.4 47.7v.9l-.4-.9v.9M134.4 49.5v.8l-.4-.8v.8M134.4 51.2v.8l-.4-.8v.8M134.4 52.9v.8l-.4-.8v.8M134.4 54.6v.9l-.4-.9v.9M134.4 56.3v.9l-.4-.9v.9M134.4 58v1l-.4-1v1M134.4 59.8v.9l-.4-.9v.9M135.3 47.8l-.2-.1-.3 .3v.4l.2 .2 .3-.1M135.3 49.6l-.3-.1-.2 .2v.4l.3 .2 .2-.1M135.3 51.3l-.3-.1-.2 .1v.6l.2 .1 .3-.1M135.3 53l-.2-.1-.3 .2v.4l.2 .2h.3"/>
<path d="M135.3 54.7l-.3-.1-.2 .2v.4l.3 .3 .2-.1M135.3 56.4l-.3-.1-.2 .2v.5l.2 .2 .3-.1M135.3 58.1l-.2-.1-.3 .3v.4l.3 .3 .2-.1M135.3 59.9l-.3-.1-.2 .2v.4l.3 .3 .2-.1M156.4 40l.3-.8 .3 .8M156.4 41.7l.3-.9 .3 .9M156.4 43.4l.3-.9 .3 .9M156.4 45.2l.3-.9 .3 .9M156.4 46.9l.3-.9 .3 .9M156.4 48.6l.3-.9 .3 .9M156.4 50.3l.3-.8 .3 .8M156.4 52l.3-.8 .3 .8"/>
<path d="M156.4 53.7l.3-.8 .3 .8M156.4 55.5l.3-.9 .3 .9M156.5 41.4h.4M156.5 43.2h.4M156.5 44.9h.4M156.5 46.6h.4M156.5 48.4h.4M156.5 50.1h.4M156.5 51.8h.4M156.5 53.5h.4M156.5 55.2h.4M156.6 58.5h.4v-.4l-.4-.1v1"/>
<path d="M157.3 41.1l.2-.3v.9M157.3 42.8l.2-.3v.9M157.3 44.5l.2-.2v.9M157.3 46.3l.2-.3v.9M157.3 48l.2-.3v.9M157.3 49.7l.2-.2v.8M157.3 51.4l.2-.2v.8M157.3 53.1l.2-.2v.8M157.3 54.9l.2-.3v.9M157.3 41.7h.5M157.3 43.4h.5M157.3 45.2h.5"/>
<path d="M157.3 46.9h.5M157.3 48.6h.5M157.3 50.3h.5M157.3 52h.5M157.3 53.7h.5M157.3 55.5h.5M157.9 58.1a.4 .4 0 0 0-.6 .4 .4 .4 0 0 0 .6 .4l-.1-.4M158 42.8l.3-.3v.9M158 44.4h.5v.3l-.5 .5h.5M158 46h.5l-.2 .4h.2v.4h-.5M158 52.9h.6l-.4 .8M158 43.4h.5"/>
<path d="M158.1 40.9l.4-.1v.2v.6a.39 .39 0 0 1-.5-.2 .39 .39 0 0 1 .1-.5zM158.2 55l-.2-.2 .1-.2 .4 .1v.3l-.5 .2 .2 .3 .3-.1v-.3l-.1-.1M158.3 47.7l-.3 .6h.6M158.3 59v-1l.2 .7 .4-.7v1M158.5 51.2h-.3l-.2 .7 .1 .1 .4-.1v-.4h-.4l-.1 .2M158.5 48v.6M158.5 49.5h-.4l-.1 .3h.5v.4h-.5M224.6 50.3v.9M224.6 52v.9M224.6 53.7v.9M224.6 55.5v.8M224.6 57.2v.8"/>
<path d="M224.6 59v.8M225.6 50.2l-.7 1.1M225.6 52l-.7 1.1M225.6 53.7l-.7 1.1M225.6 55.4l-.7 1.1M225.6 57.2l-.7 1.1M225.6 58.9l-.7 1.1M225.9 55.6l.5-.1v.8h-.5zM225.9 59.1l.1-.1a.46 .46 0 0 1 .5 .3 .46 .46 0 0 1-.2 .5 .47 .47 0 0 1-.4-.3 .47 .47 0 0 1 0-.4zM226.1 52l.3 .1v.5v.3l-.5-.1a.52 .52 0 0 1 .2-.8zM226.1 57.2l.3 .1v.5v.2h-.5a.52 .52 0 0 1 .2-.8zM226.4 50.3h-.4a.42 .42 0 0 0-.2 .6 .42 .42 0 0 0 .6 .2l-.1-.3"/>
<path d="M226.4 53.8a.4 .4 0 0 0-.6 .4 .4 .4 0 0 0 .6 .4l-.1-.4M226.8 52.4h.3M226.8 55.9h.3M227.2 52h-.4v.9h.4M227.2 55.5h-.4v.8h.4M227.3 50.4l-.4-.1a.44 .44 0 0 0-.2 .6 .44 .44 0 0 0 .6 .2M227.3 53.8a.42 .42 0 0 0-.6 .4 .42 .42 0 0 0 .6 .4M227.5 52.1l.4-.1 .1 .2-.5 .7h.5M227.5 55.7l.3-.2v.8M227.5 56.3h.5M227.6 50.3v.9h.4M227.6 53.7v.9h.4"/>
<path d="M228.3 50.8h.4l.1-.4-.5-.1v.9M228.3 53.7v.9M228.5 54.1l.3 .5M228.6 50.8l.2 .4M228.8 53.7l-.5 .5M229 52l-.7 1.1M229 55.4l-.7 1.1M229.1 54l.3-.3v.9M229.1 55.5l.4 .8 .2-.8M229.1 54.6h.6M229.4 49.7l.8 .2-.8 .3M229.5 48.9l-.1 .2 .3 .3h.4l.1-.2v-.3"/>
<path d="M229.5 48l-.1 .2a.5 .5 0 0 0 .8 .2v-.4M229.7 52.1a.43 .43 0 0 0-.4 .3 .43 .43 0 0 0 .1 .5l.4-.1v-.3h-.1M230.1 55.8h.3v.5h-.3M230.1 55.7v.9M230.7 52.1l-.3-.1-.2 .3v.6l.5-.1M230.8 55.8l.3-.1 .2 .2-.1 .4h-.4M230.8 55.7v.9M231 52v.9h.4M231.2 49.7l.8 .2-.8 .3M231.3 48.9l-.1 .3 .1 .2h.5l.2-.3-.1-.2M231.3 48l-.1 .4a.43 .43 0 0 0 .5 .1 .43 .43 0 0 0 .2-.5M231.7 52v.9"/>
<path d="M231.9 52.4l.3 .5M232.2 52l-.5 .5M232.5 52.1l.4-.1 .1 .2-.5 .7h.5M232.9 49.7l.8 .2-.8 .3M233 48.9l-.1 .3 .1 .2h.5l.2-.2-.1-.3M233 48l-.1 .4 .3 .2 .5-.2-.1-.4M233.5 57.2v.8M234.6 49.7l.9 .2-.9 .3M234.6 57.2l-.7 1.1M234.7 48.9l-.1 .2 .2 .3h.4l.3-.3-.1-.2M234.7 48l-.1 .2a.43 .43 0 0 0 .5 .4 .43 .43 0 0 0 .3-.6M235.1 57.2l.2 .1 .1 .5-.1 .2h-.4a.52 .52 0 0 1 .2-.8z"/>
<path d="M236.4 57.2l-.7 1.1M237.1 57.3l-.2-.1-.2 .2 .1 .6h.4v-.3h-.2M238 57.3l-.2-.1-.3 .2v.5l.2 .1h.3M238.4 57.2v.8h.4M238.5 59v.8M239.1 57.2v.8M239.2 57.6l.4 .4M239.6 57.2l-.5 .5M239.6 58.9l-.7 1.1M239.9 57.2h.5l-.2 .3 .2 .1v.4h-.5M239.9 59.1h.5v.5l-.2 .2a.47 .47 0 0 1-.4-.3 .47 .47 0 0 1 .1-.4zM30.7 65.8l.2 .9 .2-.6 .2 .6 .2-.9"/>
<path d="M30.7 62.1h2.3M30.7 65.6h1.6M30.7 67.3h1.5M30.9 67.5a.47 .47 0 0 1 .5 .4 .47 .47 0 0 1-.2 .5l-.4-.1v-.6zM31.3 62.4h-.3l-.2 .2v.4l.1 .2 .4-.1M31.3 64.2l-.4-.1-.1 .2v.4l.2 .3 .3-.1M31.6 62.8h.4M31.6 64.5h.4M31.7 67.9h.3M31.8 66.2h.2M32 62.4h-.4v.8h.4M32 64.1h-.4v.9h.4"/>
<path d="M32.1 67.5h-.4v.9h.4M32.2 65.8h-.4v.9h.4M32.4 62.6l.2-.2v.8M32.4 64.2h.5v.3l-.5 .5h.5M32.4 63.2h.5M34.8 67.7h.8l-.8 .4h.8M34.8 67l.2-.2h.4l.2 .1v.4h-.8zM34.8 68.5v.3l.2 .2h.4l.2-.1v-.4h-.3v.2M36.5 68.5v.4l.2 .1h.4l.3-.2-.1-.3h-.3v.2M36.5 67.7h.9l-.9 .4h.9M36.5 66.9l.2-.1h.4l.3 .2v.3h-.9zM62.5 62.1h2.3"/>
<path d="M62.5 65.6h1.6M62.5 67.3h1.5M62.6 65.8l.2 .9 .1-.6 .2 .6 .2-.9M62.9 67.5l.2 .1 .1 .5-.1 .3-.4-.1a.52 .52 0 0 1 .2-.8zM63.1 62.4a.43 .43 0 0 0-.5 .3 .43 .43 0 0 0 .2 .5l.3-.1M63.1 64.2l-.3-.1a.43 .43 0 0 0-.2 .5 .43 .43 0 0 0 .5 .3M63.5 62.8h.3M63.5 64.5h.3M63.5 67.9h.4M63.6 66.2h.4M64 62.4h-.5v.8h.5M64 64.1h-.5v.9h.5"/>
<path d="M64 67.5h-.5v.9h.5M64 65.8h-.4v.9h.4M64.3 62.6l.2-.2v.8M64.3 64.2l.3-.1 .1 .4-.5 .5h.5M64.3 63.2h.4M66.7 68.5v.4l.1 .1h.5l.2-.2-.1-.3h-.3v.2M66.7 67.7h.8l-.8 .4h.8M66.7 66.9l.1-.1h.5l.2 .2v.3h-.8zM68.4 67.7h.8l-.8 .4h.8M68.4 68.5v.3l.1 .2h.5l.2-.1v-.4h-.3v.2M68.4 66.8h.6l.2 .1v.4h-.8zM92.7 62.1h2.3"/>
<path d="M92.7 65.6h1.6M92.7 67.3h1.5M92.7 65.8l.2 .9 .2-.6 .2 .6 .1-.9M93 67.5l.3 .2v.6h-.5a.52 .52 0 0 1 .2-.8zM93.3 62.4a.44 .44 0 0 0-.5 .2 .44 .44 0 0 0 .1 .6l.4-.1M93.3 64.2l-.4-.1a.44 .44 0 0 0-.1 .6 .44 .44 0 0 0 .5 .2M93.7 62.8h.2M93.7 64.5h.2M93.7 67.9h.3M93.8 66.2h.3M94.1 62.4h-.4v.8h.4M94.1 64.1h-.4v.9h.4"/>
<path d="M94.1 67.5h-.4v.9h.4M94.2 65.8h-.4v.9h.4M94.4 62.6l.3-.2v.8M94.4 64.2l.4-.1 .1 .4-.5 .5h.5M94.4 63.2h.5M96.8 68.5v.4l.2 .1h.4l.3-.2-.1-.3h-.3v.2M96.8 67.7h.9l-.9 .4h.9M96.8 66.9l.2-.1h.4l.3 .2v.3h-.9zM98.5 67.7h.9l-.9 .4h.9M98.6 68.5l-.1 .3 .2 .2h.5l.2-.1v-.4h-.4v.2M98.7 66.8h.5l.2 .1v.4h-.9zM124.6 65.8l.2 .9 .2-.6 .1 .6 .2-.9"/>
<path d="M124.6 62.1h2.3M124.6 65.6h1.6M124.6 67.3h1.5M124.8 67.5l.4 .2-.1 .7-.4-.1v-.6zM125.2 62.4h-.3l-.2 .2v.4l.1 .2 .4-.1M125.2 64.2l-.4-.1-.1 .2v.4l.2 .3 .3-.1M125.5 62.8h.4M125.5 64.5h.4M125.6 67.9h.3M125.7 66.2h.2M125.9 62.4h-.4v.8h.4M125.9 64.1h-.4v.9h.4"/>
<path d="M126 67.5h-.4v.9h.4M126.1 65.8h-.4v.9h.4M126.3 62.6l.2-.2v.8M126.3 64.2l.4-.1 .1 .2-.5 .7h.5M126.3 63.2h.5M128.6 67.7h.9l-.9 .4h.9M128.6 67l.3-.2h.4l.2 .1v.4h-.9zM128.7 68.5l-.1 .3 .3 .2h.4l.2-.1v-.4h-.3v.2M130.3 67.7h1l-1 .4h1M130.3 67l.3-.2h.4l.3 .2v.3h-1zM130.4 68.5l-.1 .3 .3 .2h.4l.3-.2-.1-.3h-.4v.2M156.6 63.3l.1-.1a.47 .47 0 0 1 .4 .5 .47 .47 0 0 1-.4 .4l-.2-.3z"/>
<path d="M157 61.6l-.2-.1a.48 .48 0 0 0-.3 .4 .48 .48 0 0 0 .2 .5l.3-.1M157.4 61.9h.3M157.4 63.6h.4M157.9 61.5h-.5v.9h.5M157.9 63.2h-.5v.9h.5M162.3 63.4v.3l.1 .2h.5l.2-.2v-.3h-.3v.1M162.3 62.5h.8l-.8 .4h.8M162.3 61.8l.1-.2h.5l.2 .2v.3h-.8zM224.6 60.7v.8M224.6 62.4v.8M224.6 64.1v.9M224.6 65.8v.9"/>
<path d="M224.6 67.5v.9M224.6 69.3v.8M224.6 71v.8M224.6 72.7v.8M224.6 74.5v.8M224.6 76.2v.8M224.6 77.8v.9M224.6 79.6v.9M225.6 60.6l-.7 1.1M225.6 62.4l-.7 1.1M225.6 64l-.7 1.1M225.6 65.7l-.7 1.2"/>
<path d="M225.6 67.5l-.7 1.1M225.6 69.2l-.7 1.1M225.6 70.9l-.7 1.2M225.6 72.7l-.7 1.1M225.6 74.4l-.7 1.1M225.6 76.1l-.7 1.2M225.6 77.8l-.7 1.1M225.6 79.5l-.7 1.1M225.9 60.7h.5v.8l-.5-.1zM225.9 64.2l.1-.1a.46 .46 0 0 1 .5 .4 .46 .46 0 0 1-.2 .5 .47 .47 0 0 1-.4-.3 .47 .47 0 0 1 0-.5zM225.9 65.9l.5-.1v.9l-.5-.1zM225.9 69.4l.1-.1a.46 .46 0 0 1 .5 .3 .46 .46 0 0 1-.2 .5 .47 .47 0 0 1-.4-.2 .47 .47 0 0 1 0-.5z"/>
<path d="M225.9 71.1l.5-.1v.8h-.5zM225.9 74.5h.1a.46 .46 0 0 1 .5 .3 .46 .46 0 0 1-.2 .5 .47 .47 0 0 1-.4-.3 .47 .47 0 0 1 0-.5zM225.9 76.2h.5v.8l-.5-.1zM225.9 79.7l.1-.1a.46 .46 0 0 1 .5 .4 .46 .46 0 0 1-.2 .5 .47 .47 0 0 1-.4-.3 .47 .47 0 0 1 0-.5zM226.1 62.4h.3v.5v.3l-.5-.1a.52 .52 0 0 1 .2-.7zM226.1 67.5l.3 .1v.5v.3l-.5-.1a.52 .52 0 0 1 .2-.8zM226.1 72.7l.3 .1v.5v.2l-.5-.1a.52 .52 0 0 1 .2-.7zM226.1 77.8l.3 .1v.5v.3l-.5-.1a.52 .52 0 0 1 .2-.8zM227.5 62.4l-.8 1.1M227.5 67.5l-.8 1.1M227.5 70.9l-.8 1.2M227.6 62.4h.4"/>
<path d="M227.6 71h.4M227.7 68h.3l.2-.1-.2-.4h-.3v.9M227.8 62.4v.8M227.8 71v.8M228.4 62.4a.49 .49 0 0 1 .4 .3 .49 .49 0 0 1-.1 .5h-.3zM228.4 71.8v-.8l.2 .6 .4-.6v.8M228.6 67.5a.48 .48 0 0 1 .4 .3 .48 .48 0 0 1-.1 .6h-.3zM229.2 62.4v.8M229.4 67.8l.3-.3v.9M229.4 68.4h.5M229.8 71l-.5 .1v.2l.5 .3-.1 .2h-.4M235.2 62.4v.8"/>
<path d="M235.3 71v.8M236.3 62.4l-.8 1.1M236.3 70.9l-.7 1.2M236.6 71.1h.5l-.1 .7h-.4zM236.7 62.4a.47 .47 0 0 1 .4 .3 .47 .47 0 0 1-.2 .5h-.3l-.1-.3zM238 62.4l-.6 1.1M238.1 70.9l-.7 1.2M238.2 62.4h.5M238.3 71h.5M238.5 62.4v.8M238.5 60.7v.8M238.5 64.1v.9"/>
<path d="M238.5 65.8v.9M238.5 67.5v.9M238.5 69.3v.8M238.5 71v.8M238.5 72.7v.8M238.5 74.5v.8M238.5 76.2v.8M238.5 77.8v.9M238.5 79.6v.9M239.1 62.4l.4 .2v.4l-.2 .2h-.2zM239.6 71.1l-.4-.1-.1 .2v.5l.1 .1h.4M239.6 60.6l-.7 1.1"/>
<path d="M239.6 64l-.7 1.1M239.6 65.7l-.7 1.2M239.6 67.5l-.7 1.1M239.6 69.2l-.7 1.1M239.6 72.7l-.7 1.1M239.6 74.4l-.7 1.1M239.6 76.1l-.7 1.2M239.6 77.8l-.7 1.1M239.6 79.5l-.7 1.1M239.9 60.7h.5l-.1 .8-.4-.1zM239.9 64.2h.5v.6l-.2 .2a.47 .47 0 0 1-.4-.3 .47 .47 0 0 1 .1-.5zM239.9 65.9h.5l-.1 .8-.4-.1z"/>
<path d="M239.9 69.4h.5v.6l-.2 .1a.47 .47 0 0 1-.4-.2 .47 .47 0 0 1 .1-.5zM239.9 74.5h.5v.6l-.2 .2a.47 .47 0 0 1-.4-.3 .47 .47 0 0 1 .1-.5zM239.9 76.2h.5l-.1 .8-.4-.1zM239.9 79.7h.5v.6l-.2 .2a.47 .47 0 0 1-.4-.3 .47 .47 0 0 1 .1-.5zM239.9 71v.8M240.1 62.4l.3 .1v.6h-.5a.52 .52 0 0 1 .2-.7zM240.1 67.5l.3 .2v.6h-.5a.52 .52 0 0 1 .2-.8zM240.1 72.7l.3 .2v.5h-.5a.52 .52 0 0 1 .2-.7zM240.1 77.8l.3 .2v.6h-.5a.52 .52 0 0 1 .2-.8zM240.1 71.3l.3 .5M240.4 71l-.5 .5M30.7 85.6l.2-.8 .4 .8"/>
<path d="M30.7 87.3l.2-.8 .4 .8M30.7 89.1l.2-.9 .4 .9M30.7 90.8l.2-.8 .4 .8M30.7 92.5l.2-.9 .4 .9M30.7 94.3l.2-1 .4 1M30.7 96l.2-.9 .4 .9M30.7 97.7l.2-.9 .4 .9M30.7 99.4l.2-.9 .4 .9M30.8 85.4h.4M30.8 87.1h.4M30.8 88.9h.4M30.8 90.5h.4"/>
<path d="M30.8 92.2h.4M30.8 94h.4M30.8 95.7h.4M30.8 97.4h.4M30.8 99.2h.4M31.5 90h.5l-.3 .3 .3 .1v.3h-.5M31.5 96.8h.5l-.4 .9M31.5 84.9l.4-.1 .1 .2v.5l-.2 .1h-.3zM31.5 86.7l.2-.2v.8M31.5 88.3h.5v.3l-.5 .5h.5M31.5 87.3h.5M31.6 98.9v-.4l.4 .1v.2l-.5 .1 .1 .5h.4v-.4l-.2-.1"/>
<path d="M31.7 91.6l-.2 .6h.5M31.9 95.1h-.3l-.1 .2v.6h.5l-.1-.4h-.4v.1M31.9 91.9v.6M32 93.3h-.5v.5h.5v.4h-.5M34.8 84.1l.8 .3-.8 .3M34.8 83.6l.2-.2h.4l.2 .1v.4h-.8zM34.8 82.8l.2-.3h.4l.2 .4h-.8zM36.5 84.1l.9 .3-.9 .3M36.5 83.5l.2-.1h.4l.3 .2v.3h-.9zM36.5 82.7l.2-.2h.4l.3 .4h-.9zM39.7 84.8v.8M39.7 86.5v.8"/>
<path d="M39.7 88.2v.9M39.7 90v.8M39.7 91.6v.9M39.7 93.3v1M39.7 95.1v.9M39.7 96.8v.9M40.1 84.9h.5v.6l-.2 .1-.3-.1zM40.1 86.7l.2-.2 .3 .2-.1 .6-.4-.1zM40.1 90h.5v.6l-.2 .2-.3-.2zM40.1 95.2h.5v.7h-.5zM40.1 97l.2-.2 .3 .2-.1 .7-.4-.1zM40.3 88.2l.3 .1v.6l-.2 .2-.3-.2v-.6z"/>
<path d="M40.3 91.6l.3 .2-.1 .7-.4-.1v-.6zM40.3 93.3l.3 .2v.6l-.2 .2-.3-.2v-.6zM40.9 86.7l.3-.2v.8M40.9 88.3h.5v.3l-.5 .5h.5M40.9 90h.5l-.2 .3 .2 .1v.3h-.5M40.9 96.8h.6l-.4 .9M40.9 87.3h.5M41 84.9l.4-.1v.2v.5l-.1 .1a.48 .48 0 0 1-.3-.7zM41.2 91.6l-.3 .6h.6M41.4 95.1h-.3l-.2 .7 .2 .2 .3-.1v-.4h-.4l-.1 .1M41.4 91.9v.6M41.4 93.3h-.4l-.1 .5h.5v.4h-.5"/>
<path d="M62.5 85.6l.4-.8 .2 .8M62.5 87.3l.4-.8 .2 .8M62.5 89.1l.4-.9 .2 .9M62.5 90.8l.4-.8 .2 .8M62.5 92.5l.4-.9 .2 .9M62.5 94.3l.4-1 .2 1M62.5 96l.4-.9 .2 .9M62.5 97.7l.4-.9 .2 .9M62.5 99.4l.4-.9 .2 .9M62.6 85.4h.4M62.6 87.1h.4M62.6 88.9h.4"/>
<path d="M62.6 90.5h.4M62.6 92.2h.4M62.6 94h.4M62.6 95.7h.4M62.6 97.4h.4M62.6 99.2h.4M63.3 90h.6l-.4 .3h.3l.1 .3-.2 .2-.4-.1M63.3 96.8h.6l-.4 .9M63.4 86.7l.2-.2v.8M63.4 88.3l.3-.1 .2 .2-.6 .7h.6M63.4 87.3h.5M63.5 84.8a.43 .43 0 0 1 .4 .4 .43 .43 0 0 1-.4 .4l-.1-.1z"/>
<path d="M63.5 91.6l-.1 .6h.5M63.5 98.9l-.1-.1v-.2l.3-.1 .2 .3-.5 .2v.4h.1l.4-.1-.2-.4M63.8 93.3h-.4v.5l.3-.1 .2 .4-.2 .2-.3-.1M63.8 95.1l-.4 .2v.6l.3 .1 .2-.2-.1-.3h-.3l-.1 .1M63.8 91.9v.6M66.7 84.1l.8 .3-.8 .3M66.7 83.5l.1-.1h.5l.2 .2v.3h-.8zM66.7 82.7l.1-.2h.5l.2 .4h-.8zM68.4 84.1l.8 .3-.8 .3M68.4 83.4h.6l.2 .1v.4h-.8zM68.4 82.6l.6-.1 .2 .4h-.8zM71.6 84.8v.8"/>
<path d="M71.6 86.5v.8M71.6 88.2v.9M71.6 90v.8M71.6 91.6v.9M71.6 93.3v1M71.6 95.1v.9M71.6 96.8v.9M72 84.9h.4a.48 .48 0 0 1-.2 .7 .52 .52 0 0 1-.2-.7zM72 90h.3l.2 .2v.3l-.2 .3-.4-.3zM72 95.2l.3-.1 .2 .3v.3l-.2 .3-.4-.3zM72.2 86.5l.3 .2-.2 .6h-.2l-.2-.2v-.4zM72.2 88.2h.1a.5 .5 0 0 1 .2 .5 .5 .5 0 0 1-.3 .4 .54 .54 0 0 1 0-.9z"/>
<path d="M72.2 91.6l.3 .3-.2 .6h-.2l-.2-.3v-.3zM72.2 93.3h.1a.5 .5 0 0 1 .2 .5 .5 .5 0 0 1-.3 .5 .54 .54 0 0 1 0-1zM72.2 96.8h.1a.52 .52 0 0 1 0 .9l-.3-.1a.52 .52 0 0 1 .2-.8zM72.8 90h.6l-.4 .3h.3l.1 .3-.2 .2-.4-.1M72.8 96.8h.6l-.4 .9M72.9 86.7l.2-.2v.8M72.9 88.3l.3-.1 .2 .2-.6 .7h.6M72.9 87.3h.5M72.9 84.8a.43 .43 0 0 1 .5 .4 .43 .43 0 0 1-.4 .4l-.1-.1zM73 91.6l-.1 .6h.5M73.3 93.3h-.4v.5l.3-.1 .2 .4-.2 .2-.3-.1M73.3 95.1l-.4 .2v.6l.3 .1 .2-.2-.1-.3h-.4v.1"/>
<path d="M73.3 91.9v.6M92.7 85.6l.3-.8 .3 .8M92.7 87.3l.3-.8 .3 .8M92.7 89.1l.3-.9 .3 .9M92.7 90.8l.3-.8 .3 .8M92.7 92.5l.3-.9 .3 .9M92.7 94.3l.3-1 .3 1M92.7 96l.3-.9 .3 .9M92.7 97.7l.3-.9 .3 .9M92.7 99.4l.3-.9 .3 .9M92.7 85.4h.5M92.7 87.1h.5"/>
<path d="M92.7 88.9h.5M92.7 90.5h.5M92.7 92.2h.5M92.7 94h.5M92.7 95.7h.5M92.7 97.4h.5M92.7 99.2h.5M93.4 90h.6l-.3 .3h.2l.1 .3-.2 .2-.4-.1M93.4 96.8h.6l-.3 .9M93.5 86.7l.3-.2v.8M93.5 88.3l.3-.1 .2 .2-.6 .7h.6M93.5 87.3h.5"/>
<path d="M93.6 84.8a.43 .43 0 0 1 .4 .4 .43 .43 0 0 1-.3 .4l-.2-.1zM93.7 91.6l-.2 .6h.5M93.7 98.9l-.2-.1v-.2l.3-.1 .2 .3-.5 .2v.4h.2l.3-.1-.2-.4M93.9 93.3h-.4v.5l.3-.1 .2 .4-.2 .2-.3-.1M93.9 95.1l-.4 .2v.6l.3 .1 .2-.2-.1-.3h-.3l-.1 .1M93.9 91.9v.6M96.8 84.1l.9 .3-.9 .3M96.8 83.5l.2-.1h.4l.3 .2v.3h-.9zM96.8 82.7l.2-.2h.4l.3 .4h-.9zM98.5 84.1l.9 .3-.9 .3M98.7 83.4h.5l.2 .1v.4h-.9zM98.7 82.5h.5l.2 .4h-.9z"/>
<path d="M101.7 84.8v.8M101.7 86.5v.8M101.7 88.2v.9M101.7 90v.8M101.7 91.6v.9M101.7 93.3v1M101.7 95.1v.9M101.7 96.8v.9M102.1 84.9h.5a.48 .48 0 0 1-.3 .7 .52 .52 0 0 1-.2-.7zM102.1 90h.4l.2 .2v.3l-.3 .3-.3-.3zM102.1 95.2l.4-.1 .2 .3v.3l-.3 .3-.3-.3zM102.3 86.5l.4 .2-.2 .6h-.3l-.1-.2v-.4z"/>
<path d="M102.3 88.2h.1a.5 .5 0 0 1 .3 .5 .5 .5 0 0 1-.4 .4 .54 .54 0 0 1 0-.9zM102.3 91.6l.4 .3-.2 .6h-.3l-.1-.3v-.3zM102.3 93.3h.1a.5 .5 0 0 1 .3 .5 .5 .5 0 0 1-.4 .5 .54 .54 0 0 1 0-1zM102.3 96.8h.1a.52 .52 0 0 1 .1 .9l-.4-.1a.52 .52 0 0 1 .2-.8zM102.9 90h.6l-.3 .3h.2l.1 .3-.2 .2-.4-.1M102.9 96.8h.6l-.3 .9M103 86.7l.2-.2v.8M103 88.3l.3-.1 .2 .2-.6 .7h.6M103 87.3h.5M103.1 84.8a.43 .43 0 0 1 .4 .4 .43 .43 0 0 1-.3 .4l-.2-.1zM103.2 91.6l-.2 .6h.5M103.4 93.3h-.4v.5l.3-.1 .2 .4-.2 .2-.3-.1"/>
<path d="M103.4 95.1l-.4 .2v.6l.3 .1 .2-.2-.1-.3h-.3l-.1 .1M103.4 91.9v.6M124.6 85.6l.2-.8 .3 .8M124.6 87.3l.2-.8 .3 .8M124.6 89.1l.2-.9 .3 .9M124.6 90.8l.2-.8 .3 .8M124.6 92.5l.2-.9 .3 .9M124.6 94.3l.2-1 .3 1M124.6 96l.2-.9 .3 .9M124.6 97.7l.2-.9 .3 .9M124.6 99.4l.2-.9 .3 .9M124.7 85.4h.3"/>
<path d="M124.7 87.1h.3M124.7 88.9h.3M124.7 90.5h.3M124.7 92.2h.3M124.7 94h.3M124.7 95.7h.3M124.7 97.4h.3M124.7 99.2h.3M125.3 86.7l.3-.2v.8M125.3 88.3h.6v.3l-.6 .5h.6M125.3 90h.6l-.3 .3 .3 .1v.3h-.6M125.3 96.8h.6l-.4 .9"/>
<path d="M125.3 87.3h.6M125.4 84.9l.4-.1 .1 .2v.5l-.2 .1a.48 .48 0 0 1-.3-.7zM125.5 98.9l-.2-.2 .2-.2 .4 .1v.2l-.5 .1-.1 .2 .2 .3h.4v-.4l-.2-.1M125.6 91.6l-.3 .6h.6M125.8 95.1h-.3l-.2 .7 .2 .2 .4-.1-.1-.4h-.4l-.1 .1M125.8 91.9v.6M125.9 93.3h-.5l-.1 .5h.6v.4h-.6M128.6 84.1l.9 .3-.9 .3M128.6 83.6l.3-.2h.4l.2 .1v.4h-.9zM128.6 82.8l.3-.3h.4l.2 .4h-.9zM130.3 84.1l1 .3-1 .3M130.3 83.6l.3-.2h.4l.3 .2v.3h-1z"/>
<path d="M130.3 82.8l.3-.3h.4l.3 .4h-1zM133.6 84.8v.8M133.6 86.5v.8M133.6 88.2v.9M133.6 90v.8M133.6 91.6v.9M133.6 93.3v1M133.6 95.1v.9M133.6 96.8v.9M134 84.9h.5v.6l-.2 .1-.3-.1zM134 90h.5v.6l-.2 .2-.3-.2zM134 95.2h.5v.7h-.5z"/>
<path d="M134.2 86.5l.3 .2-.1 .6-.4-.1v-.5zM134.2 88.2l.3 .1v.6l-.2 .2-.3-.2v-.6zM134.2 91.6l.3 .2-.1 .7-.4-.1v-.6zM134.2 93.3l.3 .2v.6l-.2 .2-.3-.2v-.6zM134.2 96.8l.3 .2-.1 .7-.4-.1v-.6zM134.8 86.7l.3-.2v.8M134.8 88.3h.5v.3l-.5 .5h.5M134.8 90h.5l-.2 .3 .2 .1v.3h-.5M134.8 96.8h.5l-.3 .9M134.8 87.3h.5M134.9 84.9l.4-.1v.2v.5l-.1 .1a.48 .48 0 0 1-.3-.7zM135.1 91.6l-.3 .6h.5"/>
<path d="M135.3 95.1h-.3l-.2 .7 .2 .2 .3-.1v-.4h-.4l-.1 .1M135.3 91.9v.6M135.3 93.3h-.4l-.1 .5h.5v.4h-.5M156.4 84.8l.3-.9 .3 .9M156.4 86.5l.3-.9 .3 .9M156.4 88.2l.3-.9 .3 .9M156.4 90l.3-.9 .3 .9M156.4 91.6l.3-.8 .3 .8M156.4 93.3l.3-.8 .3 .8M156.4 95.1l.3-.8 .3 .8M156.4 96.8l.3-.8 .3 .8M156.4 98.5l.3-.8 .3 .8"/>
<path d="M156.5 84.5h.4M156.5 86.2h.4M156.5 87.9h.4M156.5 89.7h.4M156.5 91.4h.4M156.5 93.2h.4M156.5 94.9h.4M156.5 96.6h.4M156.5 98.3h.4M157.2 89.1h.6l-.4 .3 .4 .1v.3l-.2 .2-.4-.1M157.2 96h.6l-.4 .8M157.3 84l.1-.1a.43 .43 0 0 1 .4 .5 .43 .43 0 0 1-.4 .4l-.1-.2z"/>
<path d="M157.3 85.9l.2-.3v.9M157.3 87.4l.3-.1 .2 .3-.6 .6h.6M157.3 86.5h.5M157.4 90.7l-.1 .7h.5M157.4 98.1l-.1-.1v-.3h.3l.2 .2-.5 .3v.3l.5-.1-.2-.3M157.7 92.5h-.4v.4l.3-.1 .2 .2-.1 .3h-.4M157.7 94.3l-.4 .1v.6l.3 .1 .2-.4-.2-.2-.3 .2M157.7 91.1v.5M157.8 99.8l-.4 .1h-.1v-.4l.4-.1 .1 .2-.2 .6-.3 .1M162.3 85.8l.8 .3-.8 .3M162.3 85v.4l.1 .2h.5l.2-.2-.1-.4M162.3 84.2v.3l.1 .2h.5l.2-.2-.1-.3"/>
<path d="M167.6 83.9h.3l.2 .2v.4l-.3 .3h-.2zM167.6 85.6h.3l.2 .2v.5l-.2 .2h-.3zM167.6 87.3h.2l.3 .3v.4l-.2 .2h-.3zM167.6 89.1h.3l.2 .2v.4l-.3 .3h-.2zM167.6 90.8h.3l.2 .2v.5l-.2 .1h-.3zM167.6 92.5h.2l.3 .2v.5l-.2 .1h-.3zM167.6 94.3h.3l.2 .1v.5l-.3 .2h-.2zM167.6 96h.3l.2 .1v.5l-.2 .2h-.3zM168.4 89.1h.5l-.3 .3 .3 .1v.3l-.1 .2-.4-.1M168.4 96h.5l-.3 .8M168.4 84l.2-.1a.43 .43 0 0 1 .4 .5 .43 .43 0 0 1-.4 .4l-.2-.2zM168.4 85.9l.3-.3v.9"/>
<path d="M168.4 87.4l.4-.1 .1 .3-.5 .6h.5M168.4 86.5h.5M168.6 90.7l-.2 .7h.5M168.9 92.5h-.5v.4l.4-.1 .1 .2v.3h-.5M168.9 94.3l-.5 .1v.6l.4 .1 .1-.4-.1-.2-.4 .2M168.9 91.1v.5M224.6 81.3v.9M224.6 83v.9M225.6 81.3l-.7 1.1M225.6 83l-.7 1.1M225.9 81.4h.5v.8l-.5-.1zM226.1 83a.48 .48 0 0 1 .4 .5 .48 .48 0 0 1-.4 .4 .54 .54 0 0 1 0-.9z"/>
<path d="M229.4 84.9h.8l-.8 .5h.8M229.5 85.8a.43 .43 0 0 0 .2 .5 .43 .43 0 0 0 .5-.2v-.4h-.3v.2M229.5 84.1l.3-.2 .4 .1v.5h-.8zM231.2 85.8v.3a.44 .44 0 0 0 .5 .2 .44 .44 0 0 0 .2-.6h-.3v.2M231.2 84.9h.8l-.8 .5h.8M231.2 84.1a.48 .48 0 0 1 .5-.1 .48 .48 0 0 1 .3 .5h-.8zM232.9 85.8v.3l.3 .2 .5-.2-.1-.4h-.2v.2M232.9 84.9h.8l-.8 .5h.8M232.9 84.1l.3-.2 .4 .1 .1 .5h-.8zM234.6 84.9h.9l-.9 .5h.9M234.7 85.8a.41 .41 0 0 0 .4 .5 .41 .41 0 0 0 .3-.6h-.3v.2M234.7 84.1a.48 .48 0 0 1 .5-.1 .48 .48 0 0 1 .3 .5h-.9z"/>
<path d="M235.2 81.3v.9M236.2 81.3l-.8 1.1M236.4 81.4h.5v.8l-.5-.1zM238 81.3l-.8 1.1M238.2 81.7h.4l.1-.3-.5-.1v.9M238.5 83v.9M239.1 81.3l.5 .2v.5l-.2 .2h-.3zM239.6 83l-.7 1.1M239.9 81.4h.5v.3l-.5 .5h.5M240.1 83l.3 .2v.6l-.2 .1a.49 .49 0 0 1-.4-.4 .49 .49 0 0 1 .3-.5zM30.7 101.1l.2-.8 .4 .8M30.7 102.8l.2-.8 .4 .8"/>
<path d="M30.7 104.6l.2-.8 .4 .8M30.7 106.3l.2-.9 .4 .9M30.7 108l.2-.9 .4 .9M30.7 109.8l.2-.9 .4 .9M30.7 111.5l.2-.9 .4 .9M30.7 113.2l.2-.9 .4 .9M30.7 114.9l.2-.8 .4 .8M30.7 116.6l.2-.8 .4 .8M30.7 118.3l.2-.8 .4 .8M30.8 100.9h.4M30.8 102.6h.4M30.8 104.3h.4"/>
<path d="M30.8 106h.4M30.8 107.7h.4M30.8 109.5h.4M30.8 111.2h.4M30.8 113h.4M30.8 114.7h.4M30.8 116.4h.4M30.8 118.1h.4M31.5 102.2l.2-.2v.8M31.5 103.9l.2-.1v.8M31.5 105.7l.2-.3v.9M31.5 107.4l.2-.3v.9"/>
<path d="M31.5 109.1l.2-.2v.9M31.5 110.9l.2-.3v.9M31.5 112.6l.2-.3v.9M31.5 114.3l.2-.2v.8M31.5 116l.2-.2v.8M31.5 117.7l.2-.2v.8M31.5 102.8h.5M31.5 104.6h.5M31.5 106.3h.5M31.5 108h.5M31.5 109.8h.5M31.5 111.5h.5"/>
<path d="M31.5 113.2h.5M31.5 114.9h.5M31.5 116.6h.5M31.5 118.3h.5M32 100.6l-.1 .2h-.4v-.5l.5 .1v.6l-.5 .1M32.3 103.9l.3-.1v.8M32.3 105.5h.5v.3l-.5 .5h.5M32.3 107.1h.5l-.2 .4 .2 .1v.3h-.5M32.3 114.1h.6l-.4 .8M32.3 104.6h.5M32.4 102.1l.2-.1 .2 .1-.1 .6a.39 .39 0 0 1-.4-.2 .39 .39 0 0 1 .1-.4zM32.5 116.1l-.2-.2 .1-.1h.3l.1 .2-.5 .3 .1 .3 .4-.1v-.3l-.2-.1"/>
<path d="M32.6 108.8l-.3 .6h.6M32.7 112.3l-.2 .1-.2 .6 .1 .2 .4-.1v-.4l-.2-.1-.3 .2M32.7 109.2v.6M32.8 110.6h-.4l-.1 .4h.4l.1 .4h-.5M32.8 117.9l-.2 .2-.3-.2 .2-.4 .3 .1v.5l-.4 .2M40.6 107.1v.9l-.5-.9v.9M40.6 108.9v.9l-.5-.9v.9M40.6 110.6v.9l-.5-.9v.9M40.6 112.3v.9l-.5-.9v.9M40.6 114.1v.8l-.5-.8v.8M40.6 115.8v.8l-.5-.8v.8M40.6 117.5v.8l-.5-.8v.8"/>
<path d="M40.6 119.2v.9l-.5-.9v.9M41.4 107.2l-.2-.1-.3 .3v.4l.2 .2 .3-.1M41.4 109l-.3-.1-.2 .2v.4l.3 .3 .2-.1M41.4 110.7l-.3-.1-.2 .2v.5l.2 .2 .3-.1M41.4 112.4l-.2-.1-.3 .3v.4l.2 .2 .3-.1M41.4 114.2l-.3-.1-.2 .2v.4l.3 .2 .2-.1M41.4 115.9l-.3-.1-.2 .1v.6l.2 .1 .3-.1M41.4 117.6l-.2-.1-.3 .2v.4l.2 .2 .3-.1M41.4 119.3l-.3-.1-.2 .2v.4l.3 .3 .2-.1M62.5 101.1l.4-.8 .2 .8M62.5 102.8l.4-.8 .2 .8M62.5 104.6l.4-.8 .2 .8"/>
<path d="M62.5 106.3l.4-.9 .2 .9M62.5 108l.4-.9 .2 .9M62.5 109.8l.4-.9 .2 .9M62.5 111.5l.4-.9 .2 .9M62.5 113.2l.4-.9 .2 .9M62.5 114.9l.4-.8 .2 .8M62.5 116.6l.4-.8 .2 .8M62.5 118.3l.4-.8 .2 .8M62.6 100.9h.4M62.6 102.6h.4M62.6 104.3h.4M62.6 106h.4"/>
<path d="M62.6 107.7h.4M62.6 109.5h.4M62.6 111.2h.4M62.6 113h.4M62.6 114.7h.4M62.6 116.4h.4M62.6 118.1h.4M63.4 102.2l.2-.2v.8M63.4 103.9l.2-.1v.8M63.4 105.7l.2-.3v.9M63.4 107.4l.2-.3v.9M63.4 109.1l.2-.2v.9"/>
<path d="M63.4 110.9l.2-.3v.9M63.4 112.6l.2-.3v.9M63.4 114.3l.2-.2v.8M63.4 116l.2-.2v.8M63.4 117.7l.2-.2v.8M63.4 102.8h.5M63.4 104.6h.5M63.4 106.3h.5M63.4 108h.5M63.4 109.8h.5M63.4 111.5h.5M63.4 113.2h.5"/>
<path d="M63.4 114.9h.5M63.4 116.6h.5M63.4 118.3h.5M63.9 100.6l-.1 .2h-.3l-.1-.4 .4-.1 .1 .2-.2 .6h-.2M64.1 107.1h.5l-.2 .4 .2 .1v.3h-.5M64.1 114.1h.6l-.3 .8M64.2 103.9l.3-.1v.8M64.2 105.5l.4-.1v.4l-.5 .5h.5M64.2 104.6h.4M64.4 102l.2 .1v.7h-.3l-.1-.1v-.6zM64.4 108.8l-.2 .6h.5M64.4 116.1l-.2-.2 .4-.1v.2l-.4 .2 .1 .4 .3-.1v-.3l-.1-.1"/>
<path d="M64.6 112.3l-.4 .3v.5h.4v-.4l-.2-.1-.2 .2M64.6 109.2v.6M64.6 110.6h-.4v.4h.4v.5l-.4-.1M64.6 117.9l-.1 .2-.3-.1v-.4h.4v.5l-.3 .2M72.4 107.1v.9l-.5-.9v.9M72.4 108.9v.9l-.5-.9v.9M72.4 110.6v.9l-.5-.9v.9M72.4 112.3v.9l-.5-.9v.9M72.4 114.1v.8l-.5-.8v.8M72.4 115.8v.8l-.5-.8v.8M72.4 117.5v.8l-.5-.8v.8M72.4 119.2v.9l-.5-.9v.9"/>
<path d="M73.4 107.2a.44 .44 0 0 0-.6 .2 .44 .44 0 0 0 .1 .6l.5-.1M73.4 109l-.5-.1a.44 .44 0 0 0-.1 .6 .44 .44 0 0 0 .6 .2M73.4 110.7l-.5-.1-.1 .4 .1 .5 .5-.1M73.4 112.4a.44 .44 0 0 0-.6 .2 .44 .44 0 0 0 .1 .6l.5-.1M73.4 114.2l-.5-.1a.44 .44 0 0 0-.1 .5 .44 .44 0 0 0 .6 .2M73.4 115.9l-.5-.1-.1 .3 .1 .5 .5-.1M73.4 117.6a.44 .44 0 0 0-.6 .1 .44 .44 0 0 0 .1 .6l.5-.1M73.4 119.3l-.5-.1a.44 .44 0 0 0-.1 .6 .44 .44 0 0 0 .6 .2M92.7 101.1l.3-.8 .3 .8M92.7 102.8l.3-.8 .3 .8M92.7 104.6l.3-.8 .3 .8M92.7 106.3l.3-.9 .3 .9"/>
<path d="M92.7 108l.3-.9 .3 .9M92.7 109.8l.3-.9 .3 .9M92.7 111.5l.3-.9 .3 .9M92.7 113.2l.3-.9 .3 .9M92.7 114.9l.3-.8 .3 .8M92.7 116.6l.3-.8 .3 .8M92.7 118.3l.3-.8 .3 .8M92.7 100.9h.5M92.7 102.6h.5M92.7 104.3h.5M92.7 106h.5M92.7 107.7h.5"/>
<path d="M92.7 109.5h.5M92.7 111.2h.5M92.7 113h.5M92.7 114.7h.5M92.7 116.4h.5M92.7 118.1h.5M93.5 102.2l.3-.2v.8M93.5 103.9l.3-.1v.8M93.5 105.7l.3-.3v.9M93.5 107.4l.3-.3v.9M93.5 109.1l.3-.2v.9M93.5 110.9l.3-.3v.9"/>
<path d="M93.5 112.6l.3-.3v.9M93.5 114.3l.3-.2v.8M93.5 116l.3-.2v.8M93.5 117.7l.3-.2v.8M93.5 102.8h.5M93.5 104.6h.5M93.5 106.3h.5M93.5 108h.5M93.5 109.8h.5M93.5 111.5h.5M93.5 113.2h.5M93.5 114.9h.5"/>
<path d="M93.5 116.6h.5M93.5 118.3h.5M94 100.6l-.1 .2h-.3l-.1-.4 .4-.1 .1 .2-.2 .6h-.2M94.3 107.1h.5l-.3 .4 .3 .1v.3h-.5M94.3 114.1h.6l-.4 .8M94.4 103.9l.2-.1v.8M94.4 105.5l.3-.1 .1 .4-.5 .5h.5M94.4 104.6h.4M94.5 102l.3 .1-.1 .7h-.3v-.1v-.6zM94.5 108.8l-.1 .6h.5M94.5 116.1l-.1-.2 .3-.1 .1 .2-.4 .2v.4l.4-.1-.1-.4M94.7 112.3l-.3 .3v.5h.4l-.1-.5-.3 .2"/>
<path d="M94.7 109.2v.6M94.8 110.6h-.4v.4h.4l-.1 .5-.3-.1M94.8 117.9l-.1 .2-.3-.1v-.4h.4v.5l-.1 .2h-.3M102.6 107.1v.9l-.5-.9v.9M102.6 108.9v.9l-.5-.9v.9M102.6 110.6v.9l-.5-.9v.9M102.6 112.3v.9l-.5-.9v.9M102.6 114.1v.8l-.5-.8v.8M102.6 115.8v.8l-.5-.8v.8M102.6 117.5v.8l-.5-.8v.8M102.6 119.2v.9l-.5-.9v.9M103.5 107.2a.44 .44 0 0 0-.6 .2 .44 .44 0 0 0 .2 .6l.4-.1"/>
<path d="M103.5 109l-.4-.1a.44 .44 0 0 0-.1 .6 .44 .44 0 0 0 .5 .2M103.5 110.7l-.4-.1-.2 .4 .2 .5 .4-.1M103.5 112.4a.44 .44 0 0 0-.6 .2 .44 .44 0 0 0 .2 .6l.4-.1M103.5 114.2l-.4-.1a.44 .44 0 0 0-.1 .5 .44 .44 0 0 0 .5 .2M103.5 115.9l-.4-.1-.2 .3 .2 .5 .4-.1M103.5 117.6a.44 .44 0 0 0-.6 .1 .44 .44 0 0 0 .2 .6l.4-.1M103.5 119.3l-.4-.1a.44 .44 0 0 0-.1 .6 .44 .44 0 0 0 .5 .2M124.6 101.1l.2-.8 .3 .8M124.6 102.8l.2-.8 .3 .8M124.6 104.6l.2-.8 .3 .8M124.6 106.3l.2-.9 .3 .9M124.6 108l.2-.9 .3 .9"/>
<path d="M124.6 109.8l.2-.9 .3 .9M124.6 111.5l.2-.9 .3 .9M124.6 113.2l.2-.9 .3 .9M124.6 114.9l.2-.8 .3 .8M124.6 116.6l.2-.8 .3 .8M124.6 118.3l.2-.8 .3 .8M124.7 100.9h.3M124.7 102.6h.3M124.7 104.3h.3M124.7 106h.3M124.7 107.7h.3M124.7 109.5h.3"/>
<path d="M124.7 111.2h.3M124.7 113h.3M124.7 114.7h.3M124.7 116.4h.3M124.7 118.1h.3M125.3 102.2l.3-.2v.8M125.3 103.9l.3-.1v.8M125.3 105.7l.3-.3v.9M125.3 107.4l.3-.3v.9M125.3 109.1l.3-.2v.9M125.3 110.9l.3-.3v.9M125.3 112.6l.3-.3v.9"/>
<path d="M125.3 114.3l.3-.2v.8M125.3 116l.3-.2v.8M125.3 117.7l.3-.2v.8M125.3 102.8h.6M125.3 104.6h.6M125.3 106.3h.6M125.3 108h.6M125.3 109.8h.6M125.3 111.5h.6M125.3 113.2h.6M125.3 114.9h.6M125.3 116.6h.6"/>
<path d="M125.3 118.3h.6M125.9 100.6l-.1 .2h-.4v-.5l.5 .1v.6l-.5 .1M126.2 103.9l.2-.1v.8M126.2 105.5l.4-.1 .1 .2-.5 .7h.5M126.2 107.1h.5l-.3 .4 .3 .2-.1 .3-.4-.1M126.2 114.1h.5l-.3 .8M126.2 104.6h.5M126.4 102a.43 .43 0 0 1 .3 .4 .43 .43 0 0 1-.4 .4l-.1-.5zM126.4 108.8l-.2 .6h.5M126.4 116.1l-.2-.2 .1-.1h.3v.3l-.4 .2 .1 .3h.3l.1-.1-.2-.4M126.6 110.6h-.3l-.1 .4h.4v.5l-.4-.1M126.6 112.3a.57 .57 0 0 0-.3 .9h.3l.1-.4-.2-.2-.3 .2"/>
<path d="M126.6 109.2v.6M126.7 117.9l-.2 .2-.3-.2 .2-.4 .3 .1v.4l-.2 .3h-.2M134.4 107.1v.9l-.4-.9v.9M134.4 108.9v.9l-.4-.9v.9M134.4 110.6v.9l-.4-.9v.9M134.4 112.3v.9l-.4-.9v.9M134.4 114.1v.8l-.4-.8v.8M134.4 115.8v.8l-.4-.8v.8M134.4 117.5v.8l-.4-.8v.8M134.4 119.2v.9l-.4-.9v.9M135.3 107.2l-.2-.1-.3 .3v.4l.2 .2 .3-.1M135.3 109l-.3-.1-.2 .2v.4l.3 .3 .2-.1"/>
<path d="M135.3 110.7l-.3-.1-.2 .2v.5l.2 .2 .3-.1M135.3 112.4l-.2-.1-.3 .3v.4l.2 .2 .3-.1M135.3 114.2l-.3-.1-.2 .2v.4l.3 .2 .2-.1M135.3 115.9l-.3-.1-.2 .1v.6l.2 .1 .3-.1M135.3 117.6l-.2-.1-.3 .2v.4l.2 .2 .3-.1M135.3 119.3l-.3-.1-.2 .2v.4l.3 .3 .2-.1M156.4 100.3l.3-.9 .3 .9M156.4 102l.3-.9 .3 .9M156.4 103.8l.3-1 .3 1M156.4 105.4l.3-.8 .3 .8M156.4 107.1l.3-.8 .3 .8M156.4 108.9l.3-.9 .3 .9"/>
<path d="M156.4 110.6l.3-.8 .3 .8M156.4 112.3l.3-.8 .3 .8M156.4 114.1l.3-.9 .3 .9M156.4 115.8l.3-.9 .3 .9M156.5 100h.4M156.5 101.7h.4M156.5 103.5h.4M156.5 105.2h.4M156.5 106.9h.4M156.5 108.7h.4M156.5 110.4h.4M156.5 112.1h.4"/>
<path d="M156.5 113.8h.4M156.5 115.5h.4M156.6 118.8l.4-.1v-.3l-.4-.1v.9M157.3 101.4l.2-.3v.9M157.3 103.1l.2-.3v1M157.3 104.9l.2-.3v.8M157.3 106.5l.2-.2v.8M157.3 108.2l.2-.2v.9M157.3 110l.2-.2v.8M157.3 111.7l.2-.2v.8M157.3 113.4l.2-.2v.9M157.3 115.2l.2-.3v.9"/>
<path d="M157.3 102h.5M157.3 103.8h.5M157.3 105.4h.5M157.3 107.1h.5M157.3 108.9h.5M157.3 110.6h.5M157.3 112.3h.5M157.3 114.1h.5M157.3 115.8h.5M157.9 118.4a.4 .4 0 0 0-.6 .4 .4 .4 0 0 0 .6 .4l-.1-.4M158 103.1l.3-.3v1M158 104.7h.5v.2l-.5 .5h.5"/>
<path d="M158 106.3h.5l-.2 .3 .2 .1v.4h-.5M158 113.2h.6l-.4 .9M158 103.8h.5M158.1 101.2l.4-.1v.2v.6a.39 .39 0 0 1-.5-.2 .39 .39 0 0 1 .1-.5zM158.2 115.3l-.2-.2 .1-.2 .4 .1v.3l-.5 .1 .2 .4 .3-.1v-.3l-.1-.1M158.3 108l-.3 .6h.6M158.3 119.2v-.9l.2 .7 .4-.7v.9M158.5 111.5l-.4 .1-.1 .5 .1 .2 .4-.1v-.4h-.4l-.1 .2M158.5 108.3v.6M158.5 109.8h-.4l-.1 .4 .5-.1v.4h-.5M30.7 125.3l.2 .8 .2-.6 .2 .6 .2-.8M30.7 121.5h2.3"/>
<path d="M30.7 125h1.6M30.7 126.7h1.5M30.9 127a.47 .47 0 0 1 .5 .3 .47 .47 0 0 1-.2 .5l-.4-.1v-.6zM31.3 121.9l-.3-.1-.2 .2v.5l.1 .1h.4M31.3 123.6l-.3-.1-.2 .2v.5l.2 .2 .3-.1M31.6 122.2h.4M31.6 123.9h.4M31.7 127.4h.3M31.8 125.7h.2M32 121.8h-.4v.8h.4M32 123.5h-.4v.9h.4M32.1 127h-.4v.8h.4"/>
<path d="M32.2 125.3h-.4v.8h.4M32.4 122l.2-.2v.8M32.4 123.6h.5v.3l-.5 .5h.5M32.4 122.6h.5M34.8 127.1h.8l-.8 .4h.8M34.8 126.4l.2-.2h.4l.2 .2v.3h-.8zM34.8 128v.2l.2 .3h.4l.2-.2v-.3h-.3v.1M36.5 128v.3l.2 .2h.4l.3-.3-.1-.2h-.3v.1M36.5 127.1h.9l-.9 .4h.9M36.5 126.4l.2-.2h.4l.3 .2v.3h-.9zM62.5 121.5h2.3M62.5 125h1.6"/>
<path d="M62.5 126.7h1.5M62.6 125.3l.2 .8 .1-.6 .2 .6 .2-.8M62.9 127h.2l.1 .5-.1 .3-.4-.1a.52 .52 0 0 1 .2-.7zM63.1 121.9a.43 .43 0 0 0-.5 .2 .43 .43 0 0 0 .2 .5h.3M63.1 123.6a.4 .4 0 0 0-.5 .3 .4 .4 0 0 0 .5 .4M63.5 122.2h.3M63.5 123.9h.3M63.5 127.4h.4M63.6 125.7h.4M64 121.8h-.5v.8h.5M64 123.5h-.5v.9h.5M64 127h-.5v.8h.5"/>
<path d="M64 125.3h-.4v.8h.4M64.3 122l.2-.2v.8M64.3 123.6h.4v.3l-.5 .5h.5M64.3 122.6h.4M66.7 128v.3l.1 .2h.5l.2-.3-.1-.2h-.3v.1M66.7 127.1h.8l-.8 .4h.8M66.7 126.4l.1-.2h.5l.2 .2v.3h-.8zM68.4 127.1h.8l-.8 .4h.8M68.4 128v.2l.1 .3h.5l.2-.2v-.3h-.3v.1M68.4 126.3l.6-.1 .2 .2v.3h-.8zM92.7 121.5h2.3M92.7 125h1.6"/>
<path d="M92.7 126.7h1.5M92.7 125.3l.2 .8 .2-.6 .2 .6 .1-.8M93 127l.3 .1v.6h-.5a.52 .52 0 0 1 .2-.7zM93.3 121.9a.44 .44 0 0 0-.5 .2 .44 .44 0 0 0 .1 .5h.4M93.3 123.6a.42 .42 0 0 0-.6 .3 .42 .42 0 0 0 .6 .4M93.7 122.2h.2M93.7 123.9h.2M93.7 127.4h.3M93.8 125.7h.3M94.1 121.8h-.4v.8h.4M94.1 123.5h-.4v.9h.4M94.1 127h-.4v.8h.4"/>
<path d="M94.2 125.3h-.4v.8h.4M94.4 122l.3-.2v.8M94.4 123.6h.5v.3l-.5 .5h.5M94.4 122.6h.5M96.8 128v.3l.2 .2h.4l.3-.3-.1-.2h-.3v.1M96.8 127.1h.9l-.9 .4h.9M96.8 126.4l.2-.2h.4l.3 .2v.3h-.9zM98.5 127.1h.9l-.9 .4h.9M98.6 128l-.1 .2 .2 .3h.5l.2-.2v-.3h-.4v.1M98.7 126.2h.5l.2 .2v.3h-.9zM124.6 125.3l.2 .8 .2-.6 .1 .6 .2-.8M124.6 121.5h2.3"/>
<path d="M124.6 125h1.6M124.6 126.7h1.5M124.8 127l.4 .1-.1 .7-.4-.1v-.6zM125.2 121.9l-.3-.1-.2 .2v.5l.1 .1h.4M125.2 123.6l-.3-.1-.2 .2v.5l.2 .2 .3-.1M125.5 122.2h.4M125.5 123.9h.4M125.6 127.4h.3M125.7 125.7h.2M125.9 121.8h-.4v.8h.4M125.9 123.5h-.4v.9h.4M126 127h-.4v.8h.4"/>
<path d="M126.1 125.3h-.4v.8h.4M126.3 122l.2-.2v.8M126.3 123.6l.3-.1 .2 .2-.5 .7h.5M126.3 122.6h.5M128.6 127.1h.9l-.9 .4h.9M128.6 126.4l.3-.2h.4l.2 .2v.3h-.9zM128.7 128l-.1 .2 .3 .3h.4l.2-.2v-.3h-.3v.1M130.3 127.1h1l-1 .4h1M130.3 126.4l.3-.2h.4l.3 .2v.3h-1zM130.4 128l-.1 .2 .3 .3h.4l.3-.3-.1-.2h-.4v.1M156.7 123.5a.47 .47 0 0 1 .4 .4 .47 .47 0 0 1-.4 .5l-.2-.3zM157 121.9l-.2-.1a.48 .48 0 0 0-.3 .4 .48 .48 0 0 0 .2 .4h.3"/>
<path d="M157.4 122.2h.3M157.4 123.9h.4M157.9 121.8h-.5v.8h.5M157.9 123.5h-.5v.9h.5M162.3 123.7v.3l.1 .2h.5l.2-.2v-.3h-.3v.1M162.3 122.8h.8l-.8 .4h.8M162.3 122l.3-.1 .4 .1 .1 .4h-.8z"/>
</g>
<g fill="none" stroke="#0f0f0f" stroke-width=".21">
<path d="M144.5 57.1h7.7M144.6 57.4h.5a.47 .47 0 0 1-.4 .8l-.1-.2zM145.5 57.7h.3l.1-.3h-.4v.8h.3l.2-.3-.2-.2M146.3 58.2v-.8l.4 .6 .2-.6v.8M147.4 57.7h.2M147.8 57.4h-.4v.8h.4M148.1 58.2v-.8l.3 .6 .3-.6v.8M148.9 58.3h.7M149.7 57.4v.6l.2 .2 .3-.1v-.7M150.6 57.4l.2 .8 .2-.6 .1 .6 .2-.8M151.7 57.8h.3l.2-.2-.1-.2h-.4v.8M151.8 57.8l.4 .4"/>
<path d="M17.5 61.4h10.7M17.6 61.8l.2-.2a.48 .48 0 0 1 .4 .5 .48 .48 0 0 1-.4 .4 .52 .52 0 0 1-.2-.7zM18.5 62h.4l.1-.2-.2-.2h-.3v.9l.5-.1v-.3l-.2-.1M19.4 62.5v-.9l.3 .7 .2-.7v.9M19.6 65.7h7.7M19.7 67.4h7.6M19.9 67.8h.5v.6l-.2 .1a.47 .47 0 0 1-.4-.2 .47 .47 0 0 1 .1-.5zM19.9 65.9a.47 .47 0 0 1 .4 .5 .47 .47 0 0 1-.4 .4l-.2-.1v-.6zM20.4 62h.3M20.6 66.3h.4v-.3l-.4-.1v.9h.4l.1-.3-.2-.2M20.7 68.1h.3l.2-.2-.1-.2h-.4v.8l.5-.1v-.3h-.2M20.8 61.6h-.4v.9h.4"/>
<path d="M21.1 62.5v-.9l.4 .7 .2-.7v.9M21.5 66.8v-.9l.3 .7 .3-.7v.9M21.6 68.5v-.8l.3 .6 .2-.6v.8M22 62.6h.6M22.5 66.3h.2M22.6 68.1h.3M22.8 62.1h.4l.1-.3-.1-.2h-.4v.9M22.9 65.9h-.4v.9h.4M23 67.7h-.4v.8h.4M23 62.1l.3 .4M23.2 66.8v-.9l.3 .7 .3-.7v.9M23.3 68.5v-.8l.4 .6 .2-.6v.8"/>
<path d="M23.5 62.5l.3-.9 .3 .9M23.6 62.3h.4M24 66.8h.7M24.2 68.6h.6M24.4 62.5v-.9l.3 .7 .2-.7v.9M24.8 65.9v.8l.2 .1h.4v-.9M25 67.7v.7l.2 .1 .3-.1v-.7M25.4 61.8l.2-.2v.9M25.4 62.5h.5M25.7 65.9l.2 .9 .1-.6 .2 .6 .3-.9M25.9 68.1h.4l.1-.3-.5-.1v.8M26.1 68.1l.3 .4"/>
<path d="M26.6 61.7l-.3-.1-.2 .2 .1 .2 .4 .2v.2h-.5M26.8 67.7h.3a.48 .48 0 0 1 .2 .5 .48 .48 0 0 1-.5 .3zM26.8 66.4h.3l.2-.2-.2-.3h-.3v.9M27 66.4l.3 .4M27 62h.3M27.4 61.6h-.4v.9h.4M27.8 61.6v.9h.4M49.4 61.4h10.7M49.7 61.6l.3 .2v.6l-.2 .1-.3-.1v-.6zM50.4 62h.4v-.3l-.4-.1v.9h.4l.1-.3-.2-.2M51.3 62.5v-.9l.2 .7 .4-.7v.9M51.4 65.7h7.8"/>
<path d="M51.6 66.1l.2-.2 .3 .2v.6l-.2 .1a.47 .47 0 0 1-.4-.2 .47 .47 0 0 1 .1-.5zM51.6 67.4h7.6M51.7 67.8h.5a.47 .47 0 0 1-.3 .7l-.2-.1zM52.3 62h.2M52.4 66.3h.5l.1-.2-.2-.2h-.4v.9h.6v-.4l-.2-.1M52.6 68.1l.4-.1v-.2l-.4-.1v.8h.4l.1-.3-.2-.1M52.6 61.6h-.3v.9h.3M53 62.5v-.9l.3 .7 .3-.7v.9M53.4 66.8v-.9l.2 .7 .3-.7v.9M53.5 68.5v-.8l.2 .6 .4-.6v.8M53.8 62.6h.7M54.3 66.3h.3"/>
<path d="M54.5 68.1h.2M54.6 62.1h.4l.2-.3-.2-.2h-.4v.9M54.7 65.9h-.4v.9h.4M54.9 67.7h-.4v.8h.4M54.9 62.1l.3 .4M55.1 66.8v-.9l.3 .7 .3-.7v.9M55.2 68.5v-.8l.3 .6 .3-.6v.8M55.4 62.5l.3-.9 .3 .9M55.5 62.3h.4M55.9 66.8h.6M56 68.6h.7M56.3 62.5v-.9l.2 .7 .4-.7v.9"/>
<path d="M56.8 65.9v.9h.1l.4-.1v-.8M56.9 67.7v.7l.1 .1 .4-.1v-.7M57.3 61.7l.1-.1a.59 .59 0 0 1 .1 .9 .53 .53 0 0 1-.2-.8zM57.5 65.9l.3 .9 .2-.6 .1 .6 .2-.9M57.8 68.1h.4v-.4h-.4v.8M58 68.1l.3 .4M58.5 61.7h-.5v.2l.5 .4-.1 .2-.4-.1M58.6 66.4h.4l.1-.2-.1-.3h-.4v.9M58.6 67.7h.4a.48 .48 0 0 1 .1 .5 .48 .48 0 0 1-.5 .3zM58.9 62h.2M58.9 66.4l.2 .4M59.3 61.6h-.4v.9h.4"/>
<path d="M59.6 61.6v.9h.5M79.5 61.4h10.7M79.8 61.6l.3 .2v.6l-.1 .1-.4-.1v-.6zM80.6 62h.3l.1-.3-.4-.1v.9h.3l.2-.3-.3-.2M81.4 62.5v-.9l.3 .7 .3-.7v.9M81.6 65.7h7.8M81.7 67.4h7.7M81.8 67.8h.5a.47 .47 0 0 1-.3 .7l-.2-.1zM81.9 65.9l.4 .2v.6l-.2 .1a.49 .49 0 0 1-.5-.4 .49 .49 0 0 1 .3-.5zM82.4 62h.3M82.6 66.3h.4l.1-.2-.2-.2h-.3v.9h.5v-.4l-.2-.1M82.8 61.6h-.4v.9h.4"/>
<path d="M82.8 68.1l.4-.1v-.2l-.4-.1v.8h.3l.2-.3-.3-.1M83.2 62.5v-.9l.2 .7 .4-.7v.9M83.5 66.8v-.9l.3 .7 .2-.7v.9M83.6 68.5v-.8l.3 .6 .3-.6v.8M83.9 62.6h.7M84.5 66.3h.3M84.6 68.1h.3M84.8 62.1h.3l.2-.2-.2-.3h-.3v.9M84.9 65.9h-.4v.9h.4M85 67.7h-.4v.8h.4M85 62.1l.3 .4M85.2 66.8v-.9l.4 .7 .2-.7v.9"/>
<path d="M85.4 68.5v-.8l.2 .6 .4-.6v.8M85.6 62.5l.2-.9 .3 .9M85.6 62.3h.5M86.1 66.8h.6M86.1 68.6h.7M86.4 62.5v-.9l.3 .7 .3-.7v.9M86.9 65.9v.9h.2l.3-.1v-.8M87 67.7v.7l.2 .1 .3-.1v-.7M87.3 61.6h.5l-.2 .3 .2 .1v.4h-.5M87.8 65.9l.1 .9 .2-.6 .2 .6 .1-.9M87.9 68.1h.4v-.4h-.4v.8M88.1 68.1l.3 .4"/>
<path d="M88.7 61.7h-.5v.2l.5 .4-.2 .2-.3-.1M88.8 67.7h.3a.48 .48 0 0 1 .1 .5 .48 .48 0 0 1-.4 .3zM88.8 66.4h.3l.2-.2-.2-.3h-.3v.9M89 62h.3M89 66.4l.3 .4M89.4 61.6h-.4v.9h.4M89.8 61.6v.9h.4M111.4 61.4h10.6M111.6 61.6a.47 .47 0 0 1 .5 .5 .47 .47 0 0 1-.5 .4l-.1-.3zM112.4 62h.4v-.3l-.4-.1v.9h.3l.2-.1-.2-.4M113.2 62.5v-.9l.4 .7 .2-.7v.9M113.5 65.7h7.7"/>
<path d="M113.6 67.4h7.6M113.7 65.9a.47 .47 0 0 1 .5 .5 .47 .47 0 0 1-.5 .4l-.1-.1v-.6zM113.7 67.8l.1-.1a.46 .46 0 0 1 .5 .3 .46 .46 0 0 1-.2 .5 .47 .47 0 0 1-.4-.2 .47 .47 0 0 1 0-.5zM114.3 62h.2M114.5 66.3h.3l.1-.3-.4-.1v.9h.3l.2-.3-.2-.2M114.6 68.1h.3l.2-.2-.1-.2h-.4v.8l.5-.1v-.3h-.2M114.7 61.6h-.4v.9h.4M115 62.5v-.9l.4 .7 .2-.7v.9M115.4 66.8v-.9l.2 .7 .3-.7v.9M115.4 68.5v-.8l.4 .6 .2-.6v.8M115.8 62.6h.7M116.4 66.3h.2"/>
<path d="M116.5 68.1h.3M116.7 62.1l.4-.1v-.3l-.4-.1v.9M116.8 65.9h-.4v.9h.4M116.9 67.7h-.4v.8h.4M116.9 62.1l.2 .4M117.1 66.8v-.9l.3 .7 .3-.7v.9M117.2 68.5v-.8l.4 .6 .2-.6v.8M117.4 62.5l.3-.9 .3 .9M117.5 62.3h.4M117.9 66.8h.7M118.1 68.6h.6M118.2 62.5v-.9l.4 .7 .2-.7v.9"/>
<path d="M118.7 65.9v.8l.2 .1h.3v-.9M118.9 67.7v.7l.2 .1 .3-.1v-.7M119.2 61.7h.5v.3l-.5 .5h.5M119.6 65.9l.2 .9 .1-.6 .2 .6 .3-.9M119.8 68.1h.4l.1-.3-.5-.1v.8M120 68.1l.3 .4M120.5 61.7l-.3-.1-.2 .2 .1 .2 .4 .2v.2h-.5M120.7 66.4l.4-.1v-.3l-.4-.1v.9M120.7 67.7l.4 .2v.4l-.2 .2h-.2zM120.9 62h.3M120.9 66.4l.2 .4M121.3 61.6h-.4v.9h.4"/>
<path d="M121.7 61.6v.9h.3M142.2 60.5h10M142.4 60.7a.47 .47 0 0 1 .5 .4 .47 .47 0 0 1-.2 .5l-.4-.1v-.6zM143.2 61.2h.3l.1-.4-.4-.1v.9h.4l.1-.3-.2-.1M143.7 63.1h7.6M144 63.4l.4 .1-.1 .7h-.3l-.2-.2zM144.1 61.6v-.9l.3 .7 .2-.7v.9M144.7 63.8h.4l.1-.2v-.2h-.5v.8h.5v-.3l-.1-.1M145.1 61.2h.2M145.5 60.7h-.4v.9h.4M145.7 64.2v-.8l.2 .6 .3-.6v.8M145.8 61.6v-.9l.3 .7 .3-.7v.9"/>
<path d="M146.6 63.8h.3M146.6 61.7h.7M147 63.4h-.4v.8h.4M147.4 64.2v-.8l.3 .6 .3-.6v.8M147.4 61.3l.6-.1v-.4l-.6-.1v.9M147.7 61.3l.3 .3M148.2 64.3h.6M148.5 60.7a.47 .47 0 0 1 .4 .4 .47 .47 0 0 1-.2 .5h-.3l-.1-.3zM149.1 63.4v.8h.4l.1-.8M149.2 61.6v-.9l.4 .7 .2-.7v.9M149.9 63.8h.4l.1-.3-.5-.1v.8M150.2 63.8l.2 .4"/>
<path d="M150.7 60.8l-.4-.1-.1 .2v.3l.5 .1v.2l-.5 .1M150.8 63.4l.5 .1v.5l-.2 .2h-.3zM151 61.2h.3M151.4 60.7h-.4v.9h.4M151.8 60.7v.9h.5M243.8 77.8h10.1M243.8 72.6h10.7M243.8 74.3h10.7M243.8 76.1h10.7M243.8 79.5h7.5M243.8 69.1h10.7M244 78.1h.5v.6l-.2 .2-.4-.3z"/>
<path d="M244 72.9h.5v.6l-.2 .2a.47 .47 0 0 1-.4-.3 .47 .47 0 0 1 .1-.5zM244 69.5h.5l-.1 .7-.4-.1zM244.1 74.5l.4 .2-.1 .7h-.4l-.1-.3v-.3zM244.1 76.2l.4 .2v.6l-.2 .2a.49 .49 0 0 1-.4-.4 .49 .49 0 0 1 .2-.6zM244.1 79.7l.4 .2-.1 .7h-.4l-.1-.3v-.3zM244.8 78.4h.3l.2-.1-.1-.3h-.4v.9l.5-.1v-.3l-.2-.1M244.8 73.3h.3l.2-.2-.1-.2h-.4v.8l.5-.1v-.2l-.2-.1M244.8 75h.3l.2-.2-.2-.3h-.3v.9h.4l.1-.3-.2-.1M244.8 76.7h.4l.1-.3-.2-.2h-.3v1l.5-.1v-.4h-.2M244.8 69.8h.3l.2-.2-.2-.2h-.3v.8h.4l.1-.3-.2-.1M245.7 78.9v-.9l.3 .6 .2-.6v.9M245.7 73.7v-.8l.3 .5 .2-.5v.8"/>
<path d="M245.7 75.4v-.9l.3 .6 .2-.6v.9M245.7 77.2v-1l.3 .7 .2-.7v1M245.7 70.2v-.8l.3 .6 .2-.6v.8M246.7 78.4h.3M246.7 73.3h.3M246.7 75h.3M246.7 76.7h.3M246.7 69.8h.3M247.1 78h-.4v.9h.4M247.1 72.9h-.4v.8h.4M247.1 74.5h-.4v.9h.4M247.1 76.2h-.4v1h.4"/>
<path d="M247.1 79.7h-.4v.9h.4M247.1 69.4h-.4v.8h.4M247.4 78.9v-.9l.4 .6 .2-.6v.9M247.4 73.7v-.8l.4 .5 .2-.5v.8M247.4 75.4v-.9l.4 .6 .2-.6v.9M247.4 77.2v-1l.4 .7 .2-.7v1M247.4 70.2v-.8l.4 .6 .2-.6v.8M248.3 78.9h.6M248.3 73.8h.6M248.3 75.5h.6M248.3 77.3h.6M248.3 70.3h.6"/>
<path d="M249.1 78.4h.5v-.4h-.5v.9M249.1 73.3h.5v-.4h-.5v.8M249.1 75h.5v-.3l-.1-.2h-.4v.9M249.1 76.7h.4l.1-.3-.1-.2h-.4v1M249.1 79.7v.9h.5M249.1 69.8h.5v-.2l-.1-.2h-.4v.8M249.3 78.4l.3 .5M249.3 73.3l.3 .4M249.3 75l.3 .4M249.3 76.7l.3 .5M249.3 69.8l.3 .4M249.7 79.7l.3 .9 .1-.6 .1 .6 .3-.9"/>
<path d="M249.9 73.7l.2-.8 .3 .8M249.9 75.4l.2-.9 .3 .9M249.9 77.2l.2-1 .3 1M249.9 70.2l.2-.8 .3 .8M250 73.4h.3M250 75.1h.3M250 76.9h.3M250 70h.3M250.1 78l.4 .1v.6l-.2 .2-.3-.2zM250.7 73.7v-.8l.3 .5 .3-.5v.8M250.7 75.4v-.9l.3 .6 .3-.6v.9M250.7 77.2v-1l.3 .7 .3-.7v1"/>
<path d="M250.7 70.2v-.8l.3 .6 .3-.6v.8M250.9 78.9v-.9l.3 .6 .2-.6v.9M251.6 69.4h.6l-.4 .3h.3v.5l-.5-.1M251.7 72.9h.4l.1 .2-.6 .6h.6M251.7 74.8l.2-.3v.9M251.7 75.4h.5M251.8 76.2a.48 .48 0 0 1 .4 .5 .48 .48 0 0 1-.4 .5l-.1-.2v-.6zM252.3 78l-.5 .1v.3l.5 .2-.1 .3-.4-.1M252.7 78.4h.2M252.9 72.9h-.4v.3l.4 .2v.2h-.4M252.9 74.6h-.4v.3l.4 .2v.3h-.4M252.9 76.3h-.4v.3l.4 .2v.3h-.4"/>
<path d="M252.9 69.5h-.4v.2l.4 .2v.3h-.4M253.1 78h-.4v.9h.4M253.4 73.3h.2M253.4 75h.2M253.4 76.7h.2M253.4 69.8h.2M253.4 78v.9h.5M253.8 72.9h-.4v.8h.4M253.8 74.5h-.4v.9h.4M253.8 76.2h-.4v1h.4M253.8 69.4h-.4v.8h.4M254.1 72.9v.8h.4"/>
<path d="M254.1 74.5v.9h.4M254.1 76.2v1h.4M254.1 69.4v.8h.4M213.5 82.9h7.6M213.7 83.3h.5v.6h-.5zM214.5 83.6h.3l.2-.2-.1-.2h-.4v.8l.5-.1v-.2l-.2-.1M215.4 84v-.8l.3 .6 .2-.6v.8M216.4 83.6h.3M216.8 83.2h-.4v.8h.4M217.1 84v-.8l.4 .6 .2-.6v.8M218 84.1h.6M218.8 83.2v.7l.2 .1 .3-.1v-.7"/>
<path d="M219.7 83.6h.4l.1-.3-.5-.1v.8M219.9 83.6l.3 .4M220.6 83.2l.4 .2v.5l-.2 .1h-.2zM243.8 82.9h7.8M243.8 81.2h7.4M244 83.2l.5 .1v.6l-.2 .1-.4-.2zM244.1 81.4l.4 .2v.6l-.2 .1a.49 .49 0 0 1-.4-.4 .49 .49 0 0 1 .2-.5zM244.8 83.6h.3l.2-.2-.1-.2h-.4v.8l.5-.1v-.2l-.2-.1M244.8 81.8h.4l.1-.2-.2-.2h-.3v.9h.5v-.4l-.2-.1M244.8 80.1h.3l.2-.1-.2-.3h-.3v.9h.4l.1-.4-.2-.1M245.7 84v-.8l.3 .6 .2-.6v.8M245.7 82.3v-.9l.3 .7 .2-.7v.9"/>
<path d="M245.7 80.6v-.9l.3 .6 .2-.6v.9M246.7 83.6h.3M246.7 81.8h.3M246.7 80.1h.3M247.1 83.2h-.4v.8h.4M247.1 81.4h-.4v.9h.4M247.4 84v-.8l.4 .6 .2-.6v.8M247.4 82.3v-.9l.4 .7 .2-.7v.9M247.4 80.6v-.9l.4 .6 .2-.6v.9M248.3 84.1h.6M248.3 82.4h.6M248.3 80.6h.6"/>
<path d="M249.1 83.2v.7l.2 .1 .3-.1v-.7M249.1 81.4v.9h.5M249.8 81.9h.3l.2-.3-.2-.2h-.3v.9M250 83.2l.1 .8 .2-.6 .2 .6 .2-.8M250.1 81.9l.2 .4M250.7 81.4h.2l.3 .3v.4l-.3 .2h-.2zM250.8 80.1h.4l.1-.2-.1-.2h-.4v.9M251 83.6h.4v-.4h-.4v.8M251 80.1l.3 .5M251.2 83.6l.3 .4M144.6 117.4h7.6M144.8 117.7h.5v.6l-.1 .2a.47 .47 0 0 1-.4-.3 .47 .47 0 0 1 0-.5z"/>
<path d="M145.8 118.1l.4-.2-.1-.3h-.3v.9l.4-.1v-.3h-.2M146.6 118.5v-.9l.3 .6 .2-.6v.9M147.5 118.1h.4M148 117.6h-.5v.9h.5M148.4 118.5v-.9l.2 .6 .3-.6v.9M149.1 118.6h.6M150 117.6v.9h.4M150.6 117.6l.2 .9 .2-.6 .1 .6 .2-.9M151.7 118.1h.4v-.5h-.4v.9M151.8 118.1l.4 .4M17.5 120.9h10.7M17.6 121.2l.2-.2a.48 .48 0 0 1 .4 .5 .48 .48 0 0 1-.4 .5 .52 .52 0 0 1-.2-.8z"/>
<path d="M18.5 121.5h.4l.1-.3-.2-.2h-.3v1l.5-.1v-.4h-.2M19.4 122v-1l.3 .7 .2-.7v1M19.8 125.1h7.5M19.9 126.9h7.4M20 127.2h.5a.47 .47 0 0 1-.3 .8l-.2-.2zM20.1 125.3l.3 .2v.6h-.5a.52 .52 0 0 1 .2-.8zM20.4 121.5h.3M20.8 125.8h.4l.1-.3-.2-.2h-.3v.9h.4l.1-.3-.2-.1M20.8 121h-.4v1h.4M21 127.5h.3l.1-.3-.4-.1v.9h.3l.2-.4-.3-.1M21.1 122v-1l.4 .7 .2-.7v1M21.7 126.2v-.9l.3 .7 .2-.7v.9"/>
<path d="M21.8 128v-.9l.3 .6 .3-.6v.9M22 122h.6M22.6 125.8h.4M22.8 121.5h.4l.1-.1-.1-.4h-.4v1M22.8 127.5h.3M23 121.5l.3 .5M23.1 125.3h-.5v.9h.5M23.2 127.1h-.4v.9h.4M23.4 126.2v-.9l.3 .7 .3-.7v.9M23.5 122l.3-1 .3 1M23.6 128v-.9l.2 .6 .4-.6v.9M23.6 121.7h.4"/>
<path d="M24.3 126.3h.5M24.3 128.1h.7M24.4 122v-1l.3 .7 .2-.7v1M25.1 125.3v.9h.4M25.2 127.1v.9h.4M25.4 121.3l.2-.3v1M25.4 122h.5M25.7 125.3l.2 .9 .1-.6 .2 .6 .3-.9M25.9 127.5h.5v-.3l-.5-.1v.9M26.1 127.5l.3 .5M26.6 121.1l-.3-.1-.2 .2 .1 .3 .4 .1v.3h-.5M26.8 125.9h.3l.2-.2-.2-.4h-.3v.9"/>
<path d="M26.8 127.1h.3a.48 .48 0 0 1 .2 .6 .48 .48 0 0 1-.5 .3zM27 125.9l.3 .3M27 121.5h.3M27.4 121h-.4v1h.4M27.8 121v1h.4M49.4 120.9h10.7M49.7 121l.3 .2v.6l-.2 .2-.3-.2v-.6zM50.4 121.5h.4v-.4l-.4-.1v1h.4l.1-.4-.2-.1M51.3 122v-1l.2 .7 .4-.7v1M51.7 125.1h7.5M51.8 126.9h7.4M51.9 127.2l.1-.1a.46 .46 0 0 1 .5 .3 .46 .46 0 0 1-.2 .6 .47 .47 0 0 1-.4-.3 .47 .47 0 0 1 0-.5z"/>
<path d="M51.9 125.3l.4 .2-.1 .7-.4-.1v-.6zM52.3 121.5h.2M52.6 121h-.3v1h.3M52.7 125.8h.3l.1-.4-.4-.1v.9h.4l.1-.3-.2-.1M52.8 127.5h.4v-.4h-.4v.9l.5-.1v-.4h-.2M53 122v-1l.3 .7 .3-.7v1M53.5 126.2v-.9l.3 .7 .3-.7v.9M53.6 128v-.9l.4 .6 .2-.6v.9M53.8 122h.7M54.6 125.8h.2M54.6 121.5h.4l.2-.1-.2-.4h-.4v1M54.6 127.5h.3"/>
<path d="M54.9 125.3h-.3v.9h.3M54.9 121.5l.3 .5M55.1 127.1h-.5v.9h.5M55.3 126.2v-.9l.3 .7 .3-.7v.9M55.4 128v-.9l.3 .6 .3-.6v.9M55.4 122l.3-1 .3 1M55.5 121.7h.4M56.1 126.3h.7M56.3 122v-1l.2 .7 .4-.7v1M56.3 128.1h.6M56.9 125.3v.9h.5M57.1 127.1v.9h.4"/>
<path d="M57.3 121.1l.1-.1a.59 .59 0 0 1 .1 1 .53 .53 0 0 1-.2-.9zM57.5 125.3l.3 .9 .2-.6 .1 .6 .2-.9M57.8 127.5h.3l.2-.1-.1-.3h-.4v.9M58 127.5l.3 .5M58.5 121.1h-.5v.3l.5 .3-.1 .3-.4-.1M58.6 127.1h.4a.48 .48 0 0 1 .1 .6 .48 .48 0 0 1-.5 .3zM58.6 125.9h.4l.1-.2-.1-.4h-.4v.9M58.9 121.5h.2M58.9 125.9l.2 .3M59.3 121h-.4v1h.4M59.6 121v1h.5M79.5 120.9h10.7"/>
<path d="M79.8 121l.3 .2v.6l-.1 .2-.4-.2v-.6zM80.6 121.5h.3l.1-.4-.4-.1v1h.3l.2-.4-.3-.1M81.4 122v-1l.3 .7 .3-.7v1M81.8 125.1h7.6M81.9 126.9h7.5M82.1 127.2h.5v.6l-.2 .2a.47 .47 0 0 1-.4-.3 .47 .47 0 0 1 .1-.5zM82.1 125.3a.47 .47 0 0 1 .4 .4 .47 .47 0 0 1-.2 .5l-.4-.1v-.6zM82.4 121.5h.3M82.8 121h-.4v1h.4M82.8 125.8h.4l.1-.4-.5-.1v.9h.5l.1-.3-.3-.1M82.9 127.5h.5v-.4h-.5v.9l.5-.1v-.4h-.1M83.2 122v-1l.2 .7 .4-.7v1"/>
<path d="M83.7 126.2v-.9l.2 .7 .4-.7v.9M83.9 128v-.9l.2 .6 .3-.6v.9M83.9 122h.7M84.7 125.8h.3M84.8 121.5h.3l.2-.1-.2-.4h-.3v1M84.8 127.5h.3M85 121.5l.3 .5M85.1 125.3h-.4v.9h.4M85.2 127.1h-.4v.9h.4M85.5 126.2v-.9l.2 .7 .4-.7v.9M85.6 128v-.9l.3 .6 .2-.6v.9M85.6 122l.2-1 .3 1"/>
<path d="M85.6 121.7h.5M86.2 126.3h.7M86.4 122v-1l.3 .7 .3-.7v1M86.4 128.1h.6M87.1 125.3v.9h.4M87.2 127.1v.9h.5M87.3 121h.5l-.2 .4 .2 .1v.4h-.5M87.8 125.3l.1 .9 .2-.6 .2 .6 .1-.9M87.9 127.5h.4l.1-.1-.1-.3h-.4v.9M88.1 127.5l.3 .5M88.7 121.1h-.5v.3l.5 .3-.2 .3-.3-.1M88.8 127.1h.3a.48 .48 0 0 1 .1 .6 .48 .48 0 0 1-.4 .3z"/>
<path d="M88.8 125.9h.3l.2-.2-.2-.4h-.3v.9M89 121.5h.3M89 125.9l.3 .3M89.4 121h-.4v1h.4M89.8 121v1h.4M111.4 120.9h10.6M111.6 121a.47 .47 0 0 1 .5 .5 .47 .47 0 0 1-.5 .5l-.1-.4zM112.4 121.5h.4v-.4l-.4-.1v1h.3l.2-.2-.2-.3M113.2 122v-1l.4 .7 .2-.7v1M113.7 125.1h7.5M113.8 126.9h7.4M113.9 127.2h.5v.6l-.1 .2-.4-.2z"/>
<path d="M114 125.3a.43 .43 0 0 1 .3 .5 .43 .43 0 0 1-.4 .4l-.1-.1a.52 .52 0 0 1 .2-.8zM114.3 121.5h.2M114.7 125.8h.4l.1-.3-.2-.2h-.3v.9h.4l.1-.3-.2-.1M114.7 121h-.4v1h.4M114.8 127.5h.4l.1-.3-.5-.1v.9h.4l.2-.4-.3-.1M115 122v-1l.4 .7 .2-.7v1M115.5 126.2v-.9l.4 .7 .2-.7v.9M115.7 128v-.9l.2 .6 .4-.6v.9M115.8 122h.7M116.5 125.8h.3M116.7 121.5h.4v-.4l-.4-.1v1M116.7 127.5h.3"/>
<path d="M116.9 121.5l.2 .5M117 125.3h-.5v.9h.5M117 127.1h-.3v.9h.3M117.3 126.2v-.9l.3 .7 .3-.7v.9M117.4 122l.3-1 .3 1M117.5 128v-.9l.2 .6 .4-.6v.9M117.5 121.7h.4M118.1 126.3h.6M118.2 122v-1l.4 .7 .2-.7v1M118.2 128.1h.7M119 125.3v.9h.4M119.1 127.1v.9h.4"/>
<path d="M119.2 121.1h.5v.4l-.5 .5h.5M119.6 125.3l.2 .9 .1-.6 .2 .6 .3-.9M119.8 127.5h.5v-.3l-.5-.1v.9M120 127.5l.3 .5M120.5 121.1l-.3-.1-.2 .2 .1 .3 .4 .1v.3h-.5M120.7 127.1l.4 .2v.4l-.2 .3h-.2zM120.7 125.9l.4-.1v-.4l-.4-.1v.9M120.9 125.9l.2 .3M120.9 121.5h.3M121.3 121h-.4v1h.4M121.7 121v1h.3M142.2 120.9h10"/>
<path d="M142.4 121a.47 .47 0 0 1 .5 .5 .47 .47 0 0 1-.5 .5l-.1-.2v-.6zM143.2 121.5h.3l.1-.4-.4-.1v1h.3l.2-.4-.2-.1M144 123.4h7.3M144.1 123.7h.5l-.1 .8-.4-.1zM144.1 122v-1l.3 .7 .2-.7v1M145 124.1l.4-.1-.1-.3h-.3v.8h.4l.1-.3-.3-.1M145.1 121.5h.2M145.5 121h-.4v1h.4M145.8 124.5v-.8l.3 .5 .3-.5v.8M145.8 122v-1l.3 .7 .3-.7v1M146.6 122h.7M146.9 124.1h.2"/>
<path d="M147.2 123.7h-.3v.8h.3M147.4 121.5h.6v-.4l-.6-.1v1M147.6 124.5v-.8l.3 .5 .3-.5v.8M147.7 121.5l.3 .5M148.4 124.6h.7M148.5 121a.47 .47 0 0 1 .4 .5 .47 .47 0 0 1-.4 .5l-.2-.4zM149.2 123.7v.8h.4M149.2 122v-1l.4 .7 .2-.7v1M149.9 124.1h.4l.1-.4h-.5v.8M150.2 124.1l.2 .4M150.7 121.1l-.4-.1-.1 .2v.3l.5 .1v.3h-.5M150.8 123.7l.5 .1v.5l-.2 .2h-.3z"/>
<path d="M151 121.5h.3M151.4 121h-.4v1h.4M151.8 121v1h.5"/>
</g>
<g fill="none" stroke="#090" stroke-width=".21">
<path d="M35.3 20.6h1.7M67.1 20.6h1.8M97.2 20.6h1.8M129.2 20.6h1.6M215.3 59.4h6.8M218.7 52.5h3.4M229.9 45.6h5.2M15.4 64.6h12.9M28.3 68v.9h-.8M28.3 66.2v1h-.8M35.3 71.4h1.7M47.3 64.6h12.9"/>
<path d="M60.2 68v.9h-.8M60.2 66.2v1h-.8M67.1 71.4h1.8M77.4 64.6h13M90.4 66.2v1h-.9M90.4 68v.9h-.9M97.2 71.4h1.8M109.3 64.6h12.9M122.2 66.2v1h-.8M122.2 68v.9h-.8M129.2 71.4h1.6M152.4 63.7v.9h-.9"/>
<path d="M211.8 71.4h10.3M213.6 62.9h8.5M242.8 69.7v.9h.9M242.8 73.2v.8h.9M242.8 74.9v.8h.9M242.8 76.7v.8h.9M242.8 78.4v.8h.9M242.8 68h.9M242.8 62.9h4.3M242.8 71.4h13.8M35.3 80h1.7M67.1 80h1.8"/>
<path d="M97.2 80h1.8M129.2 80h1.6M199.8 99.9h76.6M222.1 83.5v.9h-.8M229.9 88.7h5.2M242.8 81.8v.9h.9M242.8 80v.9h.9M242.8 83.5v.9h.9M199.8 103.3h76.6M216.1 112.8h60.3M216.1 116.2h60.3M15.4 124h12.9"/>
<path d="M28.3 125.7v.9h-.8M28.3 127.5h.9v.8h-1.7M35.3 130.8h1.7M47.3 124h12.9M60.2 125.7v.9h-.8M60.2 127.5h.9v.8h-1.7M67.1 130.8h1.8M77.4 124h13M90.4 125.7v.9h-.9M90.4 127.5h.8v.8h-1.7M97.2 130.8h1.8M109.3 124h12.9"/>
<path d="M122.2 125.7v.9h-.8M122.2 127.5h.9v.8h-1.7M129.2 130.8h1.6M152.4 124v.8h-.9M216.1 126.6h60.3M216.1 130h60.3"/>
</g>
<g fill="none" stroke="#0000ca" stroke-width=".21">
<path d="M43.6 44.2v.7l.2 .1 .4-.2v-.6M44.6 44.9h.3l-.1-.5h-.2v.9M45.3 44.9l.3 .1 .2-.2-.1-.4h-.4v.9M46.1 44.7l.3-.1v-.2h-.3v.5h.3M46.9 44.4v.6M47.1 44.4l-.2 .2M48 44.4h.4l.1 .2-.2 .4-.3-.1M48 44.2v.8M48.7 44.4l.2 .6M49.1 44.4l-.4 .9M49.3 44.4h.4M49.5 44.2v.7l.2 .1"/>
<path d="M49.9 44.7l.4-.1-.1-.2-.3 .1 .1 .5 .2-.1M105.6 44.2v.6l.2 .2 .3-.1v-.7M106.5 44.9l.3 .1 .2-.2-.1-.4h-.4v.9M107.3 44.9h.4v-.5h-.4v.9M108.1 44.7l.4-.1-.1-.2h-.3v.5h.3M108.8 44.4v.6M109.1 44.4l-.3 .2M110 44.4l.4 .1v.4h-.4M110 44.2v.8M110.7 44.4l.3 .6M111.1 44.4l-.1 .6-.3 .3M111.4 44.4h.3"/>
<path d="M111.5 44.2v.6l.2 .2M111.9 44.7l.4-.1v-.2l-.4 .1v.3l.2 .2 .2-.1M44 103.6v.8h.4M44.7 103.8h.4l.1 .2-.2 .4-.3-.1zM45.4 103.8l.2 .6 .2-.4 .1 .4 .2-.6M46.4 104.1l.4-.1-.1-.2-.3 .1v.4l.1 .1 .2-.1M47.1 103.8v.6M47.4 103.8l-.3 .2M48.3 103.8l.4 .1v.4h-.4M48.3 103.6v.8M49.1 103.8l.1 .6M49.4 103.8l-.3 .9"/>
<path d="M49.7 103.8h.3M49.7 103.6v.7l.3 .1M50.2 104.1l.4-.1v-.2h-.4v.5h.4M106 103.6v.8h.5M106.7 103.9l.4-.1v.5h-.4zM107.4 103.8l.2 .6 .1-.4 .2 .4 .2-.6M108.4 104.1l.4-.1v-.2h-.4v.5h.4M109.2 103.8v.6M109.4 103.8l-.2 .2M110.4 103.8h.3l.1 .2-.2 .4-.2-.1M110.4 103.6v.8M111 103.8l.2 .6"/>
<path d="M111.5 103.8l-.5 .9M111.6 103.8h.4M111.8 103.6v.7l.2 .1M112.2 104.1l.4-.1v-.2l-.4 .1v.4l.2 .1 .2-.1M33.8 137.9l.3-.1 .1 .2v.6l-.1 .1a.53 .53 0 0 1-.3-.8zM34.6 138.4h.7M35.6 137.9h.5v.3l-.5 .5h.5M36.5 138.7v-.9l.3 .7 .2-.7v.9M37.5 138.2h.4l.1-.2-.2-.2h-.3v.9l.5-.1v-.3l-.2-.1M66 137.7l.3-.1 .1 .4-.5 .6h.5M66.8 138.2h.7M68 137.6l-.1 .6h.5"/>
<path d="M68.3 138v.6M68.7 138.6v-1l.3 .7 .3-.7v1M69.7 138h.4v-.3l-.4-.1v1h.4l.1-.4-.2-.2M96.1 137.5l-.1 .5h.5M96.4 137.8v.5M96.8 138h.7M98.3 137.5h-.4l-.1 .8 .5-.1-.1-.4-.4 .2M98.7 138.3v-.8l.3 .6 .3-.6v.8M99.7 137.9h.3l.1-.4h-.4v.8h.4l.1-.3-.3-.1M128.4 137.3l-.3 .1-.1 .6h.5l-.2-.4-.3 .2M128.8 137.9h.7M130 137.7l-.2-.2 .2-.2 .3 .1v.2l-.4 .1v.4l.4-.1v-.2l-.1-.1"/>
<path d="M130.8 138.1v-.8l.2 .7 .3-.7v.8M131.7 137.7h.4l.1-.2-.2-.2h-.3v.8h.4l.1-.3-.2-.1"/>
</g>
<path d="M221.7 55.5l.8 .8M221.7 53.8l.8 .8M222.5 55.5l-.8 .8M222.5 53.8l-.8 .8M242.4 57.3l.8 .8M243.2 57.3l-.8 .8M242.4 60.7l.8 .8M242.4 65.9l.8 .8M242.4 64.1l.8 .9M243.2 60.7l-.8 .8M243.2 65.9l-.8 .8M243.2 64.1l-.8 .9" fill="none" stroke="#00008a" stroke-width=".21"/>
<g fill="#090">
<circle cx="259.2" cy="112.8" r=".38"/>
<circle cx="259.2" cy="103.3" r=".38"/>
<circle cx="250.6" cy="130" r=".38"/>
<circle cx="259.2" cy="130" r=".38"/>
<circle cx="241.9" cy="130" r=".38"/>
<circle cx="250.6" cy="126.6" r=".38"/>
<circle cx="241.9" cy="126.6" r=".38"/>
<circle cx="259.2" cy="126.6" r=".38"/>
<circle cx="267.8" cy="130" r=".38"/>
<circle cx="267.8" cy="126.6" r=".38"/>
<circle cx="267.8" cy="112.8" r=".38"/>
<circle cx="267.8" cy="116.2" r=".38"/>
<circle cx="259.2" cy="116.2" r=".38"/>
<circle cx="259.2" cy="99.9" r=".38"/>
<circle cx="267.8" cy="99.9" r=".38"/>
<circle cx="267.8" cy="103.3" r=".38"/>
<circle cx="233.4" cy="88.7" r=".38"/>
<circle cx="233.4" cy="103.3" r=".38"/>
<circle cx="233.4" cy="99.9" r=".38"/>
<circle cx="233.4" cy="112.8" r=".38"/>
<circle cx="241.9" cy="103.3" r=".38"/>
<circle cx="241.9" cy="99.9" r=".38"/>
<circle cx="241.9" cy="112.8" r=".38"/>
<circle cx="229.9" cy="88.7" r=".38"/>
<circle cx="231.6" cy="88.7" r=".38"/>
<circle cx="224.7" cy="112.8" r=".38"/>
<circle cx="216.1" cy="112.8" r=".38"/>
<circle cx="216.1" cy="103.3" r=".38"/>
<circle cx="208.4" cy="103.3" r=".38"/>
<circle cx="208.4" cy="99.9" r=".38"/>
<circle cx="224.7" cy="126.6" r=".38"/>
<circle cx="216.1" cy="126.6" r=".38"/>
<circle cx="216.1" cy="130" r=".38"/>
<circle cx="233.4" cy="116.2" r=".38"/>
<circle cx="233.4" cy="126.6" r=".38"/>
<circle cx="224.7" cy="130" r=".38"/>
<circle cx="233.4" cy="130" r=".38"/>
<circle cx="224.7" cy="103.3" r=".38"/>
<circle cx="216.1" cy="99.9" r=".38"/>
<circle cx="224.7" cy="116.2" r=".38"/>
<circle cx="216.1" cy="116.2" r=".38"/>
<circle cx="233.4" cy="45.6" r=".38"/>
<circle cx="231.6" cy="45.6" r=".38"/>
<circle cx="229.9" cy="45.6" r=".38"/>
<circle cx="241.9" cy="116.2" r=".38"/>
<circle cx="250.6" cy="116.2" r=".38"/>
<circle cx="250.6" cy="112.8" r=".38"/>
<circle cx="224.7" cy="99.9" r=".38"/>
<circle cx="250.6" cy="99.9" r=".38"/>
<circle cx="250.6" cy="103.3" r=".38"/>
<circle cx="129.2" cy="80" r=".38"/>
<circle cx="129.2" cy="71.4" r=".38"/>
<circle cx="97.2" cy="71.4" r=".38"/>
<circle cx="129.2" cy="20.6" r=".38"/>
<circle cx="129.2" cy="130.8" r=".38"/>
<circle cx="67.1" cy="71.4" r=".38"/>
<circle cx="67.1" cy="80" r=".38"/>
<circle cx="35.3" cy="80" r=".38"/>
<circle cx="35.3" cy="71.4" r=".38"/>
<circle cx="97.2" cy="130.8" r=".38"/>
<circle cx="35.3" cy="130.8" r=".38"/>
<circle cx="67.1" cy="130.8" r=".38"/>
<circle cx="97.2" cy="20.6" r=".38"/>
<circle cx="67.1" cy="20.6" r=".38"/>
<circle cx="35.3" cy="20.6" r=".38"/>
<circle cx="97.2" cy="80" r=".38"/>
</g>
<g fill="none" stroke="#006665" stroke-width=".21">
<path d="M34.2 17.2h.6M34.5 16.9v.7M35.6 16.7h-.4v.4h.4l.1 .1-.1 .4-.4-.1M35.9 16.7l.3 .9 .2-.9M38.7 18.4v.9h.2h.3v-.9M40 18.4h-.4v.4h.3l.2 .4-.2 .1h-.3M40.4 18.5l.3-.1 .1 .2v.6l-.1 .1a.53 .53 0 0 1-.3-.8zM41.4 18.4l-.2 .6h.5M41.6 18.8v.5M66 17.2h.7M66.3 16.9v.7M67.5 16.7h-.4l-.1 .4h.4l.1 .4h-.5"/>
<path d="M67.8 16.7l.2 .9 .4-.9M70.6 18.4v.8l.1 .1 .4-.1v-.8M71.9 18.4h-.4l-.1 .4h.5v.5h-.5M72.4 18.4a.48 .48 0 0 1 .4 .5 .48 .48 0 0 1-.4 .4l-.1-.1v-.6zM73.1 18.5h.4v.3l-.5 .5h.5M96.1 17.2h.7M96.5 16.9v.7M97.7 16.7h-.5v.4h.4l.1 .4h-.5M97.9 16.7l.3 .9 .3-.9M100.7 18.4v.8l.2 .1 .3-.1v-.8M102.1 18.4h-.5v.4h.5v.5h-.5M102.4 18.7l.3-.3v.9"/>
<path d="M102.4 19.3h.5M103.4 18.4l.3 .2v.6l-.2 .1-.3-.1v-.6zM128.1 17.2h.5M128.3 16.9v.7M129.5 16.7h-.4v.4h.4v.5l-.4-.1M129.7 16.7l.4 .9 .2-.9M132.5 18.4v.8l.2 .1h.4v-.9M133.9 18.4h-.4v.4h.4v.5h-.4M134.3 18.5l.3-.1 .1 .2v.6l-.1 .1a.53 .53 0 0 1-.3-.8zM135.3 18.8h-.2v-.3l.3-.1 .2 .3-.5 .2v.4h.2l.3-.1-.2-.4M161.6 16.4h.7M161.9 16v.7"/>
<path d="M163.1 15.9h-.4l-.1 .4 .4-.1 .1 .4h-.5M163.4 15.9l.3 .8 .3-.8M164.5 19.3v.8l.1 .1 .4-.2v-.7M165.7 19.3h-.3l-.1 .4 .3-.1 .2 .4-.2 .2-.3-.1M166.2 19.3a.42 .42 0 0 1 .4 .3 .42 .42 0 0 1-.1 .5l-.2 .1-.1-.2zM167.3 19.3h-.2l-.2 .7 .2 .2 .3-.1v-.4l-.3-.1-.2 .2M39.2 20.3l-.4-.1a.42 .42 0 0 0-.1 .5 .42 .42 0 0 0 .5 .3M39.4 20.2l.3 .4 .3-.4M39.7 20.6v.4M40.7 20.2l-.4 .1v.6l.1 .1 .4-.1-.1-.4h-.4v.2M41.1 20.3l.4-.1 .1 .2-.6 .6h.6M41.9 20.4l.2-.2v.8"/>
<path d="M41.9 21h.5M43.1 20.2h-.3l-.1 .4 .4-.1 .1 .4-.2 .1h-.3M43.7 20.5l-.1-.2 .4-.1v.3l-.4 .1v.4h.1l.4-.1-.2-.4M71.1 20.3l-.4-.1-.1 .2v.5l.2 .1h.3M71.3 20.2l.3 .4 .3-.4M71.6 20.6v.4M72.5 20.2h-.2l-.2 .7 .2 .1h.3l-.1-.5h-.3l-.1 .2M72.9 20.3l.5-.1v.2l-.5 .6h.5M73.8 20.4l.2-.2v.8M73.8 21h.5M75.1 20.2h-.5l-.1 .4 .5-.1 .1 .5h-.6M75.6 20.5l-.2-.1 .1-.2 .4 .1-.1 .2-.4 .2 .2 .3h.3v-.4l-.2-.1"/>
<path d="M101.2 20.3l-.3-.1-.2 .2v.5l.3 .1h.2M101.5 20.2l.2 .4 .4-.4M101.7 20.6v.4M102.7 20.2h-.3l-.2 .7 .2 .1h.3v-.5h-.4l-.1 .2M103.1 20.3l.4-.1 .1 .2-.5 .6h.5M103.9 20.4l.3-.2v.8M103.9 21h.5M105.2 20.2h-.4v.4l.3-.1 .1 .5h-.4M105.7 20.5l-.2-.1 .1-.2h.4v.2l-.5 .3 .2 .3h.3v-.4l-.1-.1M133.1 20.3l-.4-.1-.2 .2v.5l.3 .1h.3M133.3 20.2l.3 .4 .3-.4M133.6 20.6v.4"/>
<path d="M134.6 20.2l-.4 .2v.6h.3l.2-.1-.1-.4h-.4v.2M135 20.3l.3-.1 .1 .3-.5 .5h.5M135.8 20.4l.2-.2v.8M135.8 21h.5M137 20.2h-.4v.4l.4-.1 .1 .4-.2 .1h-.3M137.6 20.5l-.1-.2 .3-.1 .1 .2-.4 .2v.4h.1h.3l-.1-.5M164.9 21h-.4l-.1 .2 .1 .3h.4v.3l-.5 .1M165.7 21h-.4l-.1 .3 .5 .4-.1 .2h-.4M166 21h.5M166.2 21v.9M166.7 21h.5l-.3 .4 .3 .1v.3h-.5M168 21.4l-.1 .1h-.3v-.5l.4 .1v.6l-.4 .2"/>
<path d="M168.9 21l-.5 .1v.3l.5 .2-.1 .3h-.4M169.2 21.5h.3M169.6 21h-.4v.9M170 21.1l.3-.1v.8a.39 .39 0 0 1-.4-.2 .39 .39 0 0 1 .1-.5zM170.9 21l-.2 .6h.5M171.2 21.3v.6M171.7 21l.3 .1-.1 .8h-.2l-.1-.2zM228.8 42.2h.7M229.1 41.9v.6M230.2 41.7h-.4v.4l.4-.1 .1 .2-.1 .3h-.4M230.6 41.7l.2 .8 .3-.8M236.7 46l.2-.8 .4 .8"/>
<path d="M236.8 43.4v.8l.1 .1 .4-.1v-.8M236.8 45.8h.4M237.4 45.2h.5M237.7 45.2v.8M238.1 43.4h-.4v.4h.4v.4h-.4M238.2 45.6h.3M238.5 43.5l.3-.1 .2 .2v.6l-.2 .1a.53 .53 0 0 1-.3-.8zM238.6 45.2h-.4v.8M238.9 45.4l.2-.2v.8M238.9 46h.5M239.3 43.6l.3-.2v.9M239.3 44.3h.5"/>
<path d="M240.2 45.2h-.5v.4l.5-.1v.3l-.1 .2-.4-.1M240.6 45.3l.3-.1 .1 .1v.5l-.2 .2a.48 .48 0 0 1-.2-.7zM241.6 45.1l-.3 .7h.5M241.8 45.4v.6M242.1 46l.3-.8 .3 .8M242.2 45.8h.4M243.4 45.2l-.5 .1v.2l.5 .2v.2h-.5M243.8 45.7h.6M244.8 45.4l.3-.2v.8M244.8 46h.5M245.7 45.3l.3-.1 .1 .1v.5l-.2 .2-.2-.1zM246.8 45.2v.6l-.4 .2"/>
<path d="M247.1 45.2v.6l.2 .2 .3-.1v-.7M248.2 45.1l-.2 .7h.5M248.4 45.4v.6M249 45.1l-.2 .7h.6M249.2 45.4v.6M14.3 68.1h.7M14.7 67.8v.6M15.8 67.5h-.4v.4h.3l.2 .1-.1 .4-.4-.1M16.1 67.5l.3 .9 .2-.9M34.2 76.7h.6M34.5 76.3v.7M34.6 74.5h-.4a.44 .44 0 0 0-.1 .5 .44 .44 0 0 0 .6 .2v-.3h-.2"/>
<path d="M35.5 74.5v.8l-.5-.8v.8M35.6 76.2h-.4v.4l.4-.1 .1 .2-.1 .3-.4-.1M35.9 76.2l.3 .8 .2-.8M35.9 74.5l.5 .1v.5l-.3 .2h-.2zM38.7 77.8v.9h.5v-.9M39.2 79.7l-.4-.1a.43 .43 0 0 0-.1 .5 .43 .43 0 0 0 .5 .3M39.4 79.6l.3 .4 .3-.4M40 77.8h-.4v.5l.3-.1 .2 .4-.5 .1M40.4 77.9l.3-.1 .1 .2v.7h-.4zM40.7 79.6h-.3l-.1 .4v.3l.3 .2 .2-.5h-.5M41.1 79.7l.4-.1 .1 .3-.6 .6h.6M41.7 77.8h-.4l-.1 .5h.5v.4h-.5"/>
<path d="M41.9 79.9l.2-.3v.9M43.1 79.6h-.3l-.1 .4h.4l.1 .3-.2 .2-.3-.1M43.7 80l-.1-.3 .4-.1v.4h-.4v.4l.1 .1 .4-.2-.2-.3M46.2 68.1h.7M46.5 67.8v.6M47.7 67.5h-.4l-.1 .4h.5v.4h-.5M48 67.5l.2 .9 .4-.9M66 76.7h.7M66.3 76.3v.7M66.4 74.5l-.4 .1v.5l.2 .2 .3-.1v-.3h-.2M67.3 74.5v.8l-.5-.8v.8M67.5 76.2h-.4l-.1 .4 .4-.1 .1 .4h-.5"/>
<path d="M67.8 74.5h.3a.48 .48 0 0 1 .1 .5 .48 .48 0 0 1-.4 .3zM67.8 76.2l.2 .8 .4-.8M70.6 77.8l.1 .9 .4-.1v-.8M71.1 79.7l-.4-.1-.1 .2 .1 .6h.4M71.3 79.6l.3 .4 .3-.4M71.9 77.8h-.4l-.1 .5h.5v.4h-.5M72.4 77.8a.53 .53 0 0 1 .3 .9l-.4-.1v-.6zM72.5 79.6h-.2l-.2 .7 .2 .2 .3-.1-.1-.4h-.4M72.9 79.7l.5-.1v.2l-.5 .7h.5M73 77.8h.5l-.2 .4 .2 .1v.4h-.5M73.8 79.9l.2-.3v.9M75.1 79.6h-.5l-.1 .4h.5l.1 .4h-.6"/>
<path d="M75.6 80l-.2-.2 .1-.2 .4 .1-.1 .3-.4 .1 .2 .4 .3-.1v-.4h-.2M76.3 68.1h.7M76.7 67.8v.6M77.8 67.5h-.4l-.1 .4h.5v.4h-.5M78.1 67.5l.3 .9 .3-.9M96.1 76.7h.7M96.5 76.3v.7M96.6 74.5l-.5 .1v.5l.3 .2 .2-.1v-.3h-.1M97.5 74.5v.8l-.5-.8v.8M97.7 76.2h-.5v.4l.4-.1 .1 .4h-.5M97.9 76.2l.3 .8 .3-.8M97.9 74.5h.4a.48 .48 0 0 1 .1 .5 .48 .48 0 0 1-.5 .3z"/>
<path d="M100.7 77.8l.1 .9 .4-.1v-.8M101.2 79.7l-.3-.1-.2 .2v.4l.3 .3 .2-.1M101.5 79.6l.2 .4 .4-.4M102.1 77.8h-.5v.5h.5v.4h-.5M102.4 78.1l.3-.3v.9M102.4 78.7h.5M102.7 79.6h-.3l-.2 .7 .2 .2 .3-.1v-.4h-.5M103.1 79.7l.4-.1 .1 .2-.5 .7h.5M103.2 78.1l.3-.3v.9M103.2 78.7h.5M103.9 79.9l.3-.3v.9M105.2 79.6h-.4v.4h.3l.1 .4h-.4"/>
<path d="M105.7 80l-.2-.2 .1-.2h.4v.3l-.5 .2 .2 .4 .3-.1v-.4h-.1M108.2 68.1h.6M108.5 67.8v.6M109.7 67.5h-.4v.4h.3l.2 .1-.1 .4-.4-.1M109.9 67.5l.4 .9 .2-.9M128.1 76.7h.5M128.3 76.3v.7M128.5 74.5h-.4a.43 .43 0 0 0-.1 .5 .43 .43 0 0 0 .5 .2v-.3h-.2M129.4 74.5v.8l-.5-.8v.8M129.5 76.2h-.4v.4l.4-.1v.5l-.4-.1M129.7 74.5h.4l.2 .1v.5l-.3 .2h-.3zM129.7 76.2l.4 .8 .2-.8"/>
<path d="M132.5 77.8l.1 .9h.5v-.9M133.1 79.7l-.4-.1-.2 .2v.4l.3 .3 .3-.1M133.3 79.6l.3 .4 .3-.4M133.9 77.8h-.4v.5h.4v.4h-.4M134.3 77.9l.3-.1 .1 .2v.7h-.4zM134.6 79.6l-.4 .2v.6l.3 .1 .2-.5h-.5M135 79.7l.3-.1 .1 .4-.5 .5h.5M135.6 78.3l-.2 .1h-.3v-.5l.3-.1 .2 .2-.2 .7h-.2M135.8 79.9l.2-.3v.9M137 79.6h-.4v.4h.4l.1 .3-.2 .2-.3-.1M137.6 80l-.1-.3 .3-.1 .1 .3-.4 .1v.4l.1 .1 .3-.1-.1-.4M161.6 76.7h.7"/>
<path d="M161.9 76.3v.7M162.1 71h-.3l-.2 .2v.5l.2 .1h.3v-.3h-.2M162.9 71v.8l-.5-.8v.8M163.1 76.2h-.4l-.1 .4 .4-.1 .1 .4h-.5M163.4 71l.4 .1 .1 .4-.2 .3h-.3zM163.4 76.2l.3 .8 .3-.8M164.5 79.6v.8l.1 .1 .4-.2v-.7M165.7 79.6h-.3l-.1 .4h.4l.1 .3-.2 .2-.3-.1M166.2 79.6a.43 .43 0 0 1 .5 .4 .43 .43 0 0 1-.4 .5l-.1-.2zM166.9 79.6h.6l-.4 .9M39.7 80v.5M41.9 80.5h.5"/>
<path d="M71.6 80v.5M73.8 80.5h.5M101.7 80v.5M103.9 80.5h.5M133.6 80v.5M135.8 80.5h.5M164.9 81.4l-.4-.1-.1 .2 .1 .2 .4 .1-.1 .4h-.4M165.7 81.4l-.3-.1-.2 .2 .5 .4-.1 .3h-.4M166 81.3h.5M166.2 81.3v.9M166.7 81.3h.5l-.3 .4h.3v.4h-.5M168 81.7l-.1 .1h-.3l-.1-.3 .2-.2 .3 .1v.6l-.4 .2"/>
<path d="M168.9 81.4h-.5v.3l.5 .2-.1 .3h-.4M169.2 81.7h.3M169.6 81.3h-.4v.9M170 81.4l.2-.1 .2 .2-.1 .6a.39 .39 0 0 1-.4-.2 .39 .39 0 0 1 .1-.5zM170.9 81.3l-.2 .6h.5M171.2 81.6v.6M171.7 81.3l.3 .1-.1 .8h-.2l-.1-.2v-.5zM202.2 99.9h-.2l-.3 .2v.4l.3 .3 .2-.1M203 99.9h-.4v.4l.3-.1 .2 .4-.2 .2-.3-.1M203.4 99.9h.3l.2 .2-.6 .7h.6M204.7 99.9h-.4v.4h.4v.4h-.4M210.9 99.9h-.3l-.2 .2v.4l.2 .3 .3-.1"/>
<path d="M211.6 99.9h-.4v.4l.3-.1 .2 .4-.2 .2-.3-.1M212 99.9h.5v.4l-.5 .5h.5M213.2 99.9h-.2l-.2 .7 .2 .2 .3-.1v-.4l-.3-.1-.2 .2M215 96.5h.7M215.3 96.1v.7M216.4 96h-.3l-.1 .4 .4-.1v.5l-.4-.1M216.8 96l.2 .8 .4-.8M229.2 91.7a.43 .43 0 0 0-.4 .3 .43 .43 0 0 0 .1 .5l.4-.1v-.2h-.2M230.2 91.6v.9l-.5-.9v.9M230.6 91.6l.4 .3v.4l-.2 .2h-.2zM270.3 99.9h-.3l-.2 .2v.4l.2 .3 .3-.1M271.1 99.9h-.5v.4l.4-.1 .1 .4-.1 .2-.4-.1"/>
<path d="M271.4 99.9h.5v.4l-.5 .5h.5M272.2 99.9h.6l-.3 .3 .3 .1v.4h-.6M278.9 99.9a.42 .42 0 0 0-.6 .4 .42 .42 0 0 0 .6 .4M279.7 99.9h-.4v.4h.4v.4h-.4M280 99.9h.5v.4l-.5 .5h.5M281 99.9l-.1 .6h.5M201.7 101.9l.3-.3v.9M201.7 102.5h.5M202.6 101.6l.4 .1v.7l-.2 .1-.2-.2zM203.4 101.7l.3-.1 .1 .2v.5l-.1 .2a.48 .48 0 0 1-.3-.8zM204.3 101.9v.8M204.6 102.4l.2 .1"/>
<path d="M204.6 101.9v.5h-.3M205.1 102.1h.3M205.5 101.6h-.4v.9M210.4 101.9l.2-.3v.9M210.4 102.5h.5M211.2 101.7l.3-.1 .1 .2v.5l-.1 .2a.48 .48 0 0 1-.3-.8zM212 101.7l.1-.1a.38 .38 0 0 1 .4 .5 .38 .38 0 0 1-.5 .3zM212.8 101.9v.8M213.2 102.4l.2 .1M213.2 101.9v.5h-.4M213.7 102.1h.3M214.2 101.6h-.5v.9"/>
<path d="M215 109.4h.7M215.3 109.1v.7M215.4 106.4h-.4v.7h.4l.1-.3h-.2M215.4 119.2l-.4 .1v.6l.3 .2 .2-.1v-.3h-.2M216.4 106.3v.8l-.5-.8v.8M216.4 119.2v.9l-.5-.9v.9M216.4 108.9h-.3l-.1 .4 .4-.1 .1 .4-.1 .2-.4-.1M216.8 106.3a.47 .47 0 0 1 .5 .3 .47 .47 0 0 1-.2 .5h-.3zM216.8 108.9l.2 .9 .4-.9M216.8 119.2h.3a.48 .48 0 0 1 .2 .6 .48 .48 0 0 1-.5 .3zM218.1 102.2l.2-.2v.8M218.1 115.2l.2-.3v.9"/>
<path d="M218.1 115.8h.5M218.1 102.8h.5M218.6 100.4l-.4-.1-.1 .3 .1 .5 .4-.1M218.6 113.2a.42 .42 0 0 0-.5 .4 .42 .42 0 0 0 .5 .4M219 114.9a.43 .43 0 0 1 .4 .4 .43 .43 0 0 1-.3 .5l-.2-.2zM219.1 102a.43 .43 0 0 1 .3 .4 .43 .43 0 0 1-.4 .4l-.1-.7zM219.4 100.3h-.4l-.1 .4 .4-.1 .1 .4h-.5M219.4 113.2h-.4l-.1 .4h.5v.4h-.5M219.8 114.9h.3l.1 .2v.5l-.2 .2-.3-.2zM219.8 113.2h.2a.59 .59 0 0 1 .1 .9 .53 .53 0 0 1-.3-.9zM219.9 102l.3 .1-.1 .7h-.3l-.1-.1v-.6zM219.9 100.3a.43 .43 0 0 1 .4 .4 .43 .43 0 0 1-.4 .4l-.2-.3z"/>
<path d="M220.6 102.4l.3-.1v.5M220.6 115.3h.3v.5M220.6 100.5l.2-.2v.8M220.6 102.3v.5M220.6 115.2v.6M220.6 101.1h.5M220.8 113.2l-.2 .5h.5M221 113.5v.6M221.4 115.4h.2M221.4 102.4h.2M221.8 102h-.4v.8M221.8 114.9h-.4v.9"/>
<path d="M226.7 115.2l.2-.3v.9M226.7 102.2l.2-.2v.8M226.7 115.8h.5M226.7 102.8h.5M227.2 113.2h-.3l-.2 .2v.4l.2 .3 .3-.1M227.2 100.4l-.3-.1-.2 .2v.5l.2 .1 .3-.1M227.6 114.9l.4 .1v.7l-.2 .1-.3-.2zM227.7 102l.3 .1-.1 .7h-.3l-.1-.1v-.6zM228 113.2h-.4l-.1 .4 .4-.1 .1 .4-.1 .2-.4-.1M228 100.3h-.4l-.1 .4 .5-.1v.5l-.5-.1M228.4 115l.3-.1 .1 .2v.5l-.2 .2a.48 .48 0 0 1-.2-.8zM228.4 102.1l.2-.1 .2 .1-.1 .7h-.2l-.2-.2z"/>
<path d="M228.5 100.3a.42 .42 0 0 1 .4 .4 .42 .42 0 0 1-.4 .4zM228.6 113.2a.48 .48 0 0 1 .3 .4 .48 .48 0 0 1-.3 .5l-.2-.2v-.6zM229.2 115.3l.2-.1 .2 .2v.4M229.2 102.4h.4v.4M229.2 100.4l.4-.1 .1 .3-.6 .5h.6M229.2 102.3v.5M229.2 115.2v.6M229.7 113.2h-.5v.4h.5v.4h-.5M230 115.4h.2M230 102.4h.2M230.4 114.9h-.4v.9M230.4 102h-.4v.8"/>
<path d="M235.3 115.2l.3-.3v.9M235.3 102.2l.3-.2v.8M235.3 115.8h.5M235.3 102.8h.5M235.8 113.2h-.2l-.3 .2v.4l.3 .3 .2-.1M235.8 100.4l-.3-.1-.2 .2v.5l.2 .1 .3-.1M236.2 115l.3-.1 .1 .2v.5l-.2 .2a.48 .48 0 0 1-.2-.8zM236.2 102.1l.2-.1 .2 .1-.1 .7h-.2l-.2-.2zM236.6 113.2h-.4v.4l.3-.1 .2 .4-.2 .2-.3-.1M236.6 100.3h-.4v.4l.4-.1 .1 .2-.1 .3-.4-.1M237 115l.1-.1a.38 .38 0 0 1 .4 .5 .38 .38 0 0 1-.5 .3zM237 102.1l.2-.1a.45 .45 0 0 1 .2 .4 .45 .45 0 0 1-.3 .4l-.2-.2z"/>
<path d="M237.1 100.3h.3v.2v.6h-.3l-.1-.1zM237.2 113.2l.2 .1v.6l-.1 .2-.3-.2v-.6zM237.8 115.3l.2-.1 .2 .2v.4M237.8 102.4h.4v.4M237.8 100.3h.5l-.3 .3 .3 .1v.3h-.5M237.8 102.3v.5M237.8 115.2v.6M238.2 113.2h-.2l-.2 .7 .2 .2 .3-.1v-.4l-.3-.1-.2 .2M238.5 115.4h.4M238.5 102.4h.4M239 114.9h-.5v.9M239 102h-.5v.8"/>
<path d="M243.9 115.2l.2-.3v.9M243.9 102.2l.2-.2v.8M243.9 115.8h.5M243.9 102.8h.5M244.5 113.2a.42 .42 0 0 0-.6 .4 .42 .42 0 0 0 .6 .4M244.5 100.4l-.5-.1-.1 .3 .1 .5 .5-.1M244.8 115l.1-.1a.45 .45 0 0 1 .3 .4 .45 .45 0 0 1-.2 .5l-.3-.4zM244.8 102.1l.2-.1a.45 .45 0 0 1 .2 .4 .45 .45 0 0 1-.3 .4l-.2-.2zM245.2 113.2h-.4v.4h.4v.4h-.4M245.2 100.3h-.4v.4l.3-.1 .1 .4h-.4M245.6 100.4h.5v.2l-.5 .5h.5M245.7 114.9a.43 .43 0 0 1 .4 .4 .43 .43 0 0 1-.4 .5l-.1-.2z"/>
<path d="M245.7 113.2h.2l.2 .1v.6l-.2 .2a.53 .53 0 0 1-.2-.9zM245.7 102a.43 .43 0 0 1 .4 .4 .43 .43 0 0 1-.4 .4l-.1-.7zM246.4 115.3h.4v.5M246.4 102.4l.4-.1v.5M246.4 113.2h.5l-.3 .9M246.4 102.3v.5M246.4 115.2v.6M246.5 100.3a.42 .42 0 0 1 .4 .4 .42 .42 0 0 1-.4 .4zM247.2 115.4h.3M247.2 102.4h.3M247.6 114.9h-.4v.9M247.6 102h-.4v.8"/>
<path d="M252.5 115.2l.3-.3v.9M252.5 102.2l.3-.2v.8M252.5 115.8h.5M252.5 102.8h.5M253 113.2a.4 .4 0 0 0-.5 .4 .4 .4 0 0 0 .5 .4M253 100.4l-.3-.1-.2 .3 .2 .5 .3-.1M253.4 114.9a.43 .43 0 0 1 .5 .4 .43 .43 0 0 1-.4 .5l-.1-.2zM253.5 102a.43 .43 0 0 1 .4 .4 .43 .43 0 0 1-.5 .4v-.7zM253.9 113.2h-.5v.4h.5v.4h-.5M253.9 100.3h-.5v.4l.4-.1 .1 .4h-.5M254.2 100.4l.4-.1 .1 .2-.5 .6h.5M254.3 114.9h.2l.1 .2v.5l-.1 .2-.3-.2z"/>
<path d="M254.4 102l.2 .1-.1 .7h-.2l-.1-.1v-.6zM254.4 113.2a.48 .48 0 0 1 .3 .4 .48 .48 0 0 1-.3 .5l-.2-.4zM255.1 115.3h.3v.5M255.1 102.4l.3-.1v.5M255.1 100.5l.2-.2v.8M255.1 102.3v.5M255.1 115.2v.6M255.1 101.1h.5M255.2 113.6l-.1-.1v-.3h.3l.2 .2-.5 .3v.3l.1 .1 .4-.2-.2-.3M255.8 115.4h.3M255.8 102.4h.3M256.2 114.9h-.4v.9"/>
<path d="M256.2 102h-.4v.8M261.2 115.2l.2-.3v.9M261.2 102.2l.2-.2v.8M261.2 115.8h.5M261.2 102.8h.5M261.7 113.2h-.3l-.2 .2v.4l.2 .3 .3-.1M261.7 100.4l-.4-.1-.1 .2v.5l.1 .1 .4-.1M262.1 114.9h.2l.1 .2v.5l-.1 .2-.3-.2zM262.2 102l.2 .1-.1 .7h-.2l-.1-.1v-.6zM262.4 113.2h-.3l-.1 .4 .3-.1 .2 .4-.2 .2-.3-.1M262.4 100.3h-.3l-.1 .4 .4-.1v.5l-.4-.1M262.8 115l.4-.1 .1 .2v.5l-.2 .2a.48 .48 0 0 1-.3-.8z"/>
<path d="M262.8 102.1l.3-.1 .2 .1-.1 .7h-.3l-.1-.2zM262.8 113.3l.2-.1a.48 .48 0 0 1 .4 .4 .48 .48 0 0 1-.4 .5l-.2-.2zM262.8 100.4l.5-.1 .1 .2-.6 .6h.6M263.6 115.3l.3-.1 .1 .2v.4M263.6 102.4l.3-.1 .1 .5M263.6 100.4h.5v.2l-.5 .5h.5M263.6 102.3v.5M263.6 115.2v.6M264.1 113.6l-.3 .1-.2-.4 .2-.1h.3l-.1 .8-.3 .1M264.5 115.4h.2M264.5 102.4h.2M264.8 114.9h-.3v.9"/>
<path d="M264.8 102h-.3v.8M269.8 115.2l.2-.3v.9M269.8 101.9l.2-.3v.9M269.8 115.8h.4M269.8 102.5h.4M270.3 113.2h-.3l-.2 .2v.4l.2 .3 .3-.1M270.6 101.7l.4-.1 .1 .2v.5l-.2 .2a.48 .48 0 0 1-.3-.8zM270.7 114.9h.3l.1 .2v.5l-.2 .2a.48 .48 0 0 1-.4-.4 .48 .48 0 0 1 .2-.5zM271.1 113.2h-.5v.4l.4-.1 .1 .4-.1 .2-.4-.1M271.4 113.4l.2-.2v.9M271.4 114.1h.5M271.5 114.9a.43 .43 0 0 1 .4 .4 .43 .43 0 0 1-.3 .5l-.2-.2z"/>
<path d="M271.5 101.6a.43 .43 0 0 1 .4 .4 .43 .43 0 0 1-.3 .5l-.2-.2zM272.2 115.3l.3-.1 .2 .2v.4M272.2 101.9v.8M272.2 115.2v.6M272.3 113.2h.3l.2 .1v.6l-.2 .2a.53 .53 0 0 1-.3-.9zM272.7 102.4l.1 .1M272.7 101.9v.5h-.5M273 115.4h.3M273.2 102.1h.2M273.4 114.9h-.4v.9M273.6 101.6h-.4v.9M278.3 115.2l.3-.3v.9"/>
<path d="M278.3 101.9l.3-.3v.9M278.3 115.8h.5M278.3 102.5h.5M278.9 113.2a.42 .42 0 0 0-.6 .4 .42 .42 0 0 0 .6 .4M279.3 114.9a.39 .39 0 0 1 .4 .4 .39 .39 0 0 1-.4 .4zM279.3 101.6a.39 .39 0 0 1 .4 .4 .39 .39 0 0 1-.4 .4zM279.7 113.2h-.4v.4h.4v.4h-.4M280 113.4l.3-.2v.9M280 114.1h.5M280.1 114.9a.43 .43 0 0 1 .4 .4 .43 .43 0 0 1-.3 .5l-.2-.2zM280.1 101.6a.43 .43 0 0 1 .4 .4 .43 .43 0 0 1-.3 .5l-.2-.2zM280.9 115.3h.3v.5"/>
<path d="M280.9 113.4l.2-.2v.9M280.9 101.9v.8M280.9 115.2v.6M280.9 114.1h.5M281.3 101.9v.5h-.4M281.3 102.4l.1 .1M281.3 100.2v.6M281.6 115.4h.3M281.8 102.1h.3M282.1 114.9h-.5v.9M282.1 101.6h-.3v.9M14.3 127.5h.7"/>
<path d="M14.7 127.2v.6M15.8 127h-.4v.4l.3-.1 .2 .2-.1 .3-.4-.1M16.1 127l.3 .8 .2-.8M34.6 133.9h-.4a.44 .44 0 0 0-.1 .6 .44 .44 0 0 0 .6 .2v-.4h-.2M35.5 133.9v.8l-.5-.8v.8M35.9 133.9l.5 .2v.4l-.3 .2h-.2zM46.2 127.5h.7M46.5 127.2v.6M47.7 127h-.4l-.1 .4h.5v.3h-.5M48 127l.2 .8 .4-.8M66.4 133.9l-.4 .2v.4l.2 .2h.3v-.4h-.2M67.3 133.9v.8l-.5-.8v.8"/>
<path d="M67.8 133.9h.3a.48 .48 0 0 1 .1 .5 .48 .48 0 0 1-.4 .3zM76.3 127.5h.7M76.7 127.2v.6M77.8 127h-.4l-.1 .4h.5v.3h-.5M78.1 127l.3 .8 .3-.8M96.6 133.9l-.5 .2v.4l.3 .2h.2v-.4h-.1M97.5 133.9v.8l-.5-.8v.8M97.9 133.9h.4a.48 .48 0 0 1 .1 .5 .48 .48 0 0 1-.5 .3zM108.2 127.5h.6M108.5 127.2v.6M109.7 127h-.4v.4l.3-.1 .2 .2-.1 .3-.4-.1M109.9 127l.4 .8 .2-.8"/>
<path d="M128.5 133.9h-.4a.43 .43 0 0 0-.1 .5 .43 .43 0 0 0 .5 .3v-.4h-.2M129.4 133.9v.8l-.5-.8v.8M129.7 133.9h.4l.2 .2v.4l-.3 .2h-.3zM162.1 131.4l-.3-.1-.2 .1v.5l.2 .2h.3v-.3h-.2M162.9 131.3v.8l-.5-.8v.8M163.4 131.3a.47 .47 0 0 1 .5 .3 .47 .47 0 0 1-.2 .5h-.3zM215 123.2h.7M215.3 122.9v.6M215.4 133.1l-.1-.1-.3 .1v.6l.3 .2 .2-.1v-.3h-.2M216.4 133v.9l-.5-.9v.9M216.4 122.6h-.3l-.1 .5 .4-.1 .1 .4-.5 .1M216.8 133a.47 .47 0 0 1 .5 .4 .47 .47 0 0 1-.5 .5z"/>
<path d="M216.8 122.6l.2 .9 .4-.9M218.1 128.9l.2-.2v.9M218.1 129.6h.5M218.6 127a.44 .44 0 0 0-.5 .2 .44 .44 0 0 0 .1 .6l.4-.1M219 128.7a.42 .42 0 0 1 .4 .3 .42 .42 0 0 1-.2 .5l-.1 .1-.2-.2zM219.4 127h-.4l-.1 .4h.5v.3h-.5M219.7 127.2l.3-.2v.8M219.7 127.8h.6M219.8 128.7h.3l.1 .2v.5l-.2 .2-.3-.2zM220.6 129.1l.3-.1v.6M220.6 127h.3l.2 .2-.6 .6h.6M220.6 129v.6"/>
<path d="M221.4 129.1h.2M221.8 128.7h-.4v.9M226.7 128.9l.2-.2v.9M226.7 129.6h.5M227.2 127h-.3l-.2 .2v.4l.2 .2 .3-.1M227.6 128.7l.4 .1v.7l-.2 .1-.3-.2zM228 127h-.4l-.1 .4 .4-.1 .1 .2v.3l-.5-.1M228.4 128.8l.3-.1 .1 .2v.5l-.2 .2a.48 .48 0 0 1-.2-.8zM228.4 127.2l.2-.2v.8M228.4 127.8h.5M229.1 127h.6l-.3 .3 .3 .1v.3h-.6M229.2 129.1h.4v.5"/>
<path d="M229.2 129v.6M230 129.1h.2M230.4 128.7h-.4v.9M235.3 128.9l.3-.2v.9M235.3 129.6h.5M235.8 127h-.2l-.3 .2v.4l.2 .2 .3-.1M236.2 128.8l.3-.1 .1 .2v.5l-.2 .2a.48 .48 0 0 1-.2-.8zM236.6 127h-.4v.4l.3-.1 .2 .2-.1 .3-.4-.1M237 128.8l.1-.1a.43 .43 0 0 1 .3 .4 .43 .43 0 0 1-.1 .4h-.3zM237 127.2l.2-.2v.8M237 127.8h.4M237.8 129.1h.4v.5"/>
<path d="M237.8 129v.6M238 127l-.2 .5h.6M238.2 127.3v.5M238.5 129.1h.4M239 128.7h-.5v.9M243.9 128.9l.2-.2v.9M243.9 129.6h.5M244.5 127a.44 .44 0 0 0-.6 .2 .44 .44 0 0 0 .1 .6l.5-.1M244.8 128.8l.1-.1a.46 .46 0 0 1 .4 .4 .46 .46 0 0 1-.2 .5 .48 .48 0 0 1-.3-.8zM245.2 127h-.4v.4h.4v.3h-.4M245.6 127.2l.2-.2v.8M245.6 127.8h.5"/>
<path d="M245.7 128.7a.42 .42 0 0 1 .4 .3 .42 .42 0 0 1-.2 .5l-.2 .1-.1-.2zM246.4 129.1l.4-.1v.6M246.4 129v.6M246.8 127h-.4v.4l.4-.1 .1 .2-.1 .3-.4-.1M247.2 129.1h.3M247.6 128.7h-.4v.9M252.5 128.9l.3-.2v.9M252.5 129.6h.5M253 127a.43 .43 0 0 0-.4 .3 .43 .43 0 0 0 .1 .5l.3-.1M253.4 128.7a.42 .42 0 0 1 .4 .3 .42 .42 0 0 1-.1 .5l-.2 .1-.1-.2zM253.9 127h-.5v.4h.5v.3h-.5M254.2 127.2l.3-.2v.8"/>
<path d="M254.2 127.8h.5M254.3 128.7h.2l.1 .2v.5l-.1 .2-.3-.2zM255.1 129.1l.3-.1v.6M255.1 129v.6M255.5 127l-.4 .2v.5l.4 .1 .1-.3-.2-.2-.3 .2M255.8 129.1h.3M256.2 128.7h-.4v.9M261.2 128.9l.2-.2v.9M261.2 129.6h.5M261.7 127h-.3l-.2 .2v.4l.1 .2 .4-.1M262.1 128.7h.2l.1 .2v.5l-.1 .2-.3-.2zM262.4 127h-.3l-.1 .4 .3-.1 .2 .2-.1 .3-.4-.1"/>
<path d="M262.8 128.8l.4-.1 .1 .2v.5l-.2 .2a.48 .48 0 0 1-.3-.8zM262.8 127.2l.3-.2v.8M262.8 127.8h.6M263.6 129.1h.4v.5M263.6 127h.6l-.4 .8M263.6 129v.6M264.5 129.1h.2M264.8 128.7h-.3v.9M269.8 128.9l.2-.2v.9M269.8 129.6h.4M270.3 127h-.3l-.2 .2v.4l.2 .2 .3-.1M270.6 128.8l.4-.1 .1 .2v.5l-.2 .2a.48 .48 0 0 1-.3-.8z"/>
<path d="M271.1 127h-.5v.4l.4-.1 .1 .2v.3l-.5-.1M271.4 127.2l.2-.2v.8M271.4 127.8h.5M271.5 128.7a.42 .42 0 0 1 .4 .3 .42 .42 0 0 1-.2 .5l-.1 .1-.2-.2zM272.2 129.1h.5v.5M272.2 129v.6M272.4 127.4l-.2-.2 .2-.2h.4v.3l-.5 .1v.4l.5-.1v-.2l-.2-.1M273 129.1h.3M273.4 128.7h-.4v.9M278.3 128.9l.3-.2v.9M278.3 129.6h.5M278.9 127a.44 .44 0 0 0-.5 .2 .44 .44 0 0 0 .1 .6l.4-.1"/>
<path d="M279.3 128.7a.42 .42 0 0 1 .4 .3 .42 .42 0 0 1-.2 .5h-.2zM279.7 127h-.4v.4h.4l-.1 .4-.3-.1M280 127.2l.3-.2v.8M280 127.8h.5M280.1 128.7a.42 .42 0 0 1 .4 .3 .42 .42 0 0 1-.1 .5l-.2 .1-.2-.2zM280.9 129.1l.3-.1v.6M280.9 129v.6M281.4 127.4l-.2 .1h-.3v-.5h.3l.2 .1-.2 .7h-.2M281.6 129.1h.3M282.1 128.7h-.5v.9"/>
</g>
</svg>
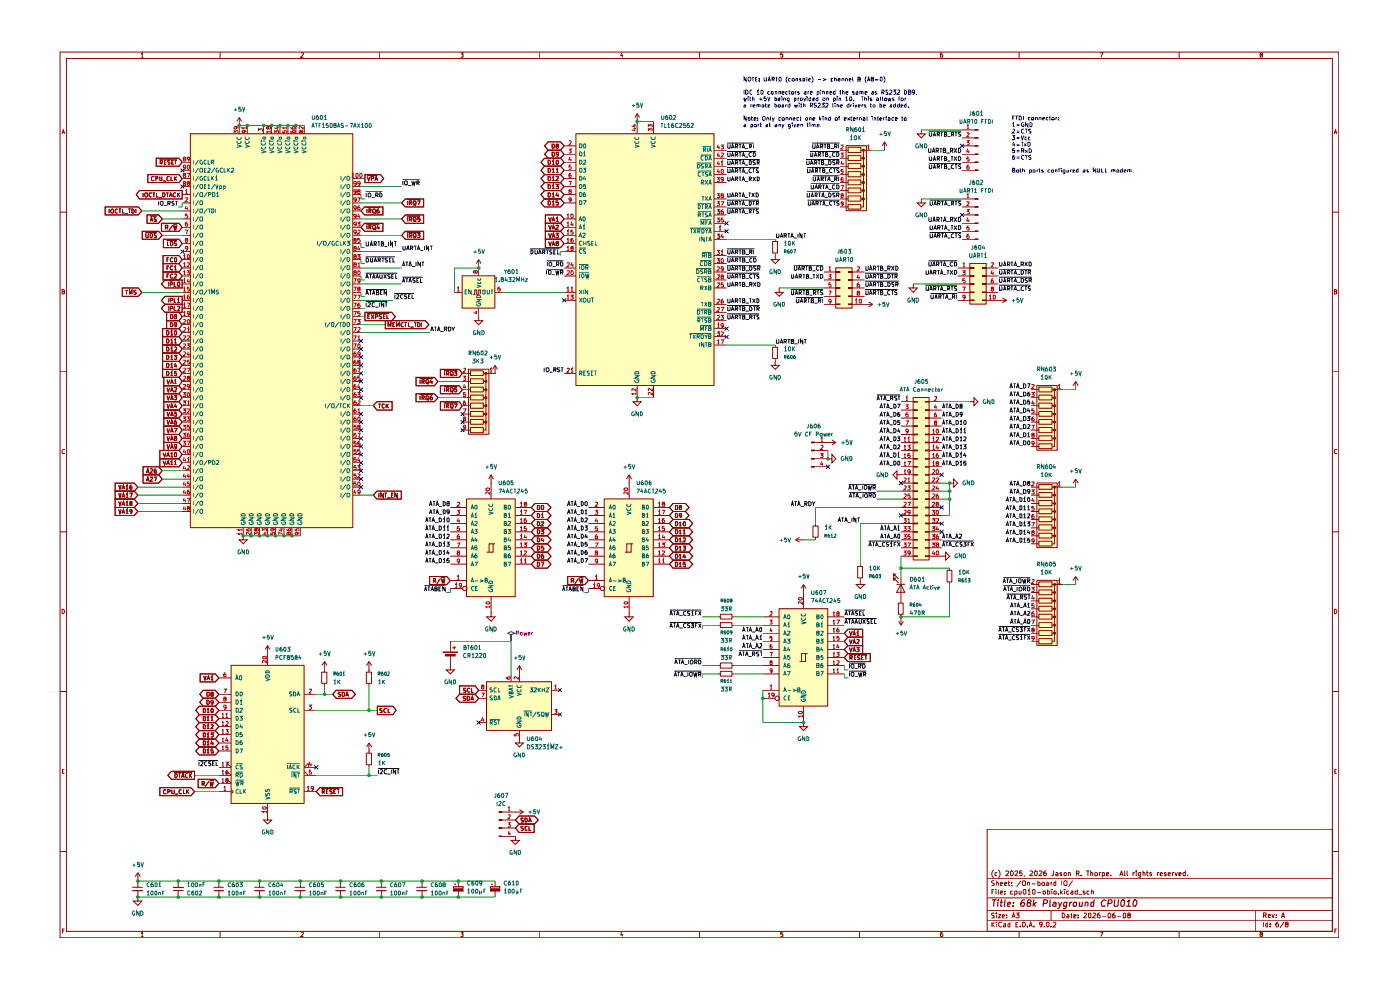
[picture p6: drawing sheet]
<svg xmlns="http://www.w3.org/2000/svg" width="297mm" height="210mm" viewBox="0 0 297 210" stroke-linecap="round" stroke-linejoin="round" font-family="sans-serif">
<g fill="none" stroke="#910000" stroke-width=".21">
<path d="M12.7 11h271.3v187.9h-271.3zM14.1 12.4h268.6v185.2h-268.6zM29.9 11.5l.3-.3v.9M29.9 12.1h.5M46.7 11v1.4M63.9 11.3l.3-.1 .2 .3-.6 .6h.6M80.6 11v1.4M97.7 11.2h.6l-.3 .4h.3v.5h-.6M114.5 11v1.4M131.9 11.2l-.2 .6h.5M132.1 11.6v.5M148.4 11v1.4"/>
<path d="M166.1 11.2h-.5v.4h.5v.5h-.5M182.3 11v1.4M199.9 11.2l-.3 .1-.1 .8h.4l.1-.1-.1-.4-.4 .1M216.2 11v1.4M233.4 11.2h.6l-.5 .9M250.1 11v1.4M267.5 11.6h-.2v-.3l.4-.1 .1 .3-.5 .2v.4h.2l.3-.1-.1-.4M13.2 28.4l.2-.8 .4 .8M13.2 28.1h.5M283 28.4l.3-.8 .3 .8M283.1 28.1h.4M12.7 45h1.4"/>
<path d="M282.7 45h1.3M12.7 78.9h1.4M13.2 61.8h.4l.1-.2-.2-.2h-.3v1l.5-.1v-.4l-.2-.1M282.7 78.9h1.3M283.1 61.8h.4l.1-.2-.2-.2h-.3v1l.5-.1v-.4l-.2-.1M13.7 95.5l-.4-.1-.1 .1v.6l.1 .1 .4-.1M283.6 95.5l-.4-.1-.1 .1v.6l.1 .1 .4-.1M12.7 112.8h1.4M282.7 112.8h1.3M13.2 129.2h.2l.3 .3v.4l-.3 .3h-.2zM283.1 129.2h.2l.3 .3v.4l-.3 .3h-.2zM12.7 146.7h1.4"/>
<path d="M282.7 146.7h1.3M13.2 163.6h.3M13.7 163.2h-.5v.8h.5M209.4 175.9h73.3v21.7h-73.3zM283.2 163.6h.2M283.6 163.2h-.4v.8h.4M12.7 180.6h1.4M13.2 197.5h.4M13.7 197.1h-.5v.9M29.9 198l.3-.3v1M29.9 198.7h.5M46.7 197.6v1.3"/>
<path d="M63.9 197.8l.3-.1 .2 .3-.6 .7h.6M80.6 197.6v1.3M97.7 197.7h.6l-.3 .4 .3 .1v.4h-.6M114.5 197.6v1.3M131.9 197.7l-.2 .6h.5M132.1 198.1v.6M148.4 197.6v1.3M166.1 197.7h-.5v.5h.5v.4h-.5M182.3 197.6v1.3M199.9 197.7l-.3 .1-.1 .8 .4 .1 .1-.2-.1-.4-.4 .1M209.4 195.2h73.3M209.4 193.2h73.3"/>
<path d="M209.4 190.5h73.3M209.4 186.4h73.3M210.4 195.6v1M210.4 189.2h.4M210.5 196l.4 .6M210.7 184.6l-.1 .1a1.11 1.11 0 0 0 .1 1.5M210.9 188.7h-.5v1M210.9 193.8l-.4-.1-.1 .1v.2l.4 .2 .1 .2v.3h-.5M210.9 186.9l-.4-.1-.1 .2v.2l.5 .4v.2h-.5M210.9 195.6l-.5 .5M211.3 188.7v.1M211.3 189v.7"/>
<path d="M211.4 193.7v.1M211.4 187.2h.4v.6M211.4 186.8v1M211.4 194v.7M211.5 195.6v.1M211.5 196v.6M211.5 185.2h-.4v.5l.4 .1M211.8 194h.5l-.5 .7h.5M211.8 188.7l.1 1M211.8 184.6l.1 .1a1.11 1.11 0 0 1-.1 1.5M212.2 189.4l.5-.1-.1-.3h-.3l-.1 .2v.3l.2 .2 .2-.1M212.2 187.5l.5-.1-.1-.2-.4 .1v.4l.4 .1"/>
<path d="M212.5 195.7l-.5-.1-.1 .2v.6l.3 .2 .3-.1M212.6 194.3h.5l-.1-.3-.4 .1v.6h.5M212.9 196h.4v.6M213.1 189.6v.1M213.1 189v.2M213.1 187.5l.5-.1-.1-.2h-.4v.6h.5M213.3 196.1l-.4 .2 .1 .3h.3M213.4 184.8h.5v.4l-.5 .6h.5M213.6 194.6v.1M213.6 194.1v.1M213.9 187.2h.3M214 186.8v.9l.2 .1"/>
<path d="M214.2 196h-.4v.5l.2 .1h.2M214.2 195.6v1M214.4 184.9l.2-.2a.52 .52 0 0 1 .4 .6 .52 .52 0 0 1-.5 .5zM214.6 187.7v.1M214.6 187.2v.1M214.7 194.7l.3-1 .3 1M214.8 194.4h.5M214.8 189h-.3l-.2 .2 .1 .4h.4M215.3 189.6l.3 .1 .2-.2-.1-.5h-.4v1M215.3 184.8l.4-.1 .2 .2-.6 .9h.6M215.5 196h.4M215.6 193.7h.6l-.3 .4 .3 .1v.4h-.6"/>
<path d="M216 195.6h-.5v1h.5M216.2 189v.5l.2 .2 .2-.1M216.2 197.6v1.3M216.4 196.5v.1M216.6 189v.7M216.6 186.8l-.9 1.3M216.8 184.7h-.5v.5h.5l-.1 .6-.4-.1M217 195.6h.3a.55 .55 0 0 1 .2 .8l-.3 .2h-.2zM217.1 186.8l.4 .2v.7h-.5a.67 .67 0 0 1 .1-.9zM217.2 188.7h.3l.1 .1v.7l-.2 .2a.63 .63 0 0 1-.2-1zM217.3 185.8v.1M218 196.5v.1"/>
<path d="M218 187.2h.4v.6M218 187.2v.6M218.1 188.9l.2-.2v1M218.1 189.7h.5M218.3 196.6l.3-1 .4 1M218.4 196.3h.5M218.5 184.8l.4-.1 .2 .4-.7 .7h.7M218.9 187.5h.8M219.2 188.7h.3l.1 .1v.7l-.3 .2a.63 .63 0 0 1-.1-1zM219.3 196.5v.1M219.5 184.8l.3-.1 .2 .2v.7l-.1 .2-.4-.1zM220 189.3h.8"/>
<path d="M220.2 186.8v1h.4v-.6h-.4M220.5 184.8l.3-.1 .3 .4-.7 .7h.7M221.1 196l-.2 .2-.4-.2 .1-.4h.4a.64 .64 0 0 1-.4 1M221.3 189.1l.4-.1 .1 .5-.2 .2-.3-.1zM221.5 196.5v.1M221.9 184.7l-.3 .1a.74 .74 0 0 0-.1 1h.4l.1-.5-.1-.1h-.4l-.1 .1M222 195.7l.4-.1 .1 .2v.6l-.2 .2-.3-.4zM222 187.2h.3l.2 .1v.5h-.5v-.3l.5-.1M222.2 189h.4l.1 .2v.3l-.2 .2-.3-.1M222.2 188.7v1M223 196.5v.1M223 187.2v.6"/>
<path d="M223 193.2v2M223.1 188.7v.1M223.1 189v.7M223.2 187.2h-.2v.2M223.4 195.7h.6v.3l-.6 .6h.6M223.5 184.7v.8l-.2 .3h-.2M223.6 189l.5 .1v.5l-.4 .1-.1-.2zM224 186.8v1h-.4v-.6h.4M224 185.2l.3-.1 .1 .1v.6h-.4v-.4l.4-.1M224.6 189.6v.1M225 188.7v1M225.1 189.3l.3 .4"/>
<path d="M225.2 185.2h-.3v.2l.4 .2-.1 .2h-.3M225.3 186.8v1M225.3 193.7h.3l.3 .4-.2 .6h-.4zM225.4 189l-.4 .4M225.7 185.2l.4-.1 .1 .1-.1 .6-.4-.1zM225.8 188.7v.1M225.8 189v.7M225.9 186.8l.5 .2v.7h-.6a.67 .67 0 0 1 .1-.9zM226.4 194.1l.2-.1 .2 .2v.5h-.4v-.4h.4M226.6 185.2h.5v.6M226.6 185.1v.7M226.8 189h-.4l-.1 .2v.3l.1 .2 .4-.1"/>
<path d="M227.1 194h.4M227.2 189h.4v.7M227.3 193.7v1h.2M227.5 186.8l-.8 1.3M227.6 189.3h-.3l-.2 .1 .2 .3 .3-.1M227.8 194.3h.5l-.2-.3-.3 .1v.6h.4M228.3 185.2h.6v-.3l-.1-.2h-.5v1.1M228.6 189h-.5l-.1 .2 .1 .4h.5M228.6 188.7v1M228.6 185.2l.3 .6M228.7 194.6v.1M228.7 194.1v.1"/>
<path d="M228.8 189.8h.8M229.4 185.7v.1M229.9 193.8l.4-.1 .2 .1-.6 .9h.6M230.2 189h-.4l-.1 .2 .5 .3-.1 .2-.4-.1M230.5 184.7h.6M230.8 184.7v1.1M231.1 193.7l.3 .1-.1 .9h-.3l-.1-.2v-.7zM231.1 189h-.4l-.1 .2v.3l.2 .2 .3-.1M231.4 185.2h.4v.6M231.4 184.7v1.1M231.5 189.1l.4-.1v.7M231.5 188.7v1"/>
<path d="M231.9 193.8l.4-.1 .1 .3-.6 .7h.6M232.3 185.2l.3-.1 .2 .1-.1 .6h-.4zM233.3 185.1v.7M233.3 193.7l-.3 .1-.2 .7 .2 .2 .4-.1-.1-.5h-.3l-.2 .2M233.4 197.7h.6l-.5 1M233.5 185.1l-.2 .1M233.8 194.3h.9M233.8 185.2l.4-.1 .2 .1-.1 .6h-.5M233.8 185.1v1M234.8 185.4l.4-.1-.1-.2-.3 .1v.6h.4M235.1 193.8l.2-.1a.52 .52 0 0 1 .4 .6 .52 .52 0 0 1-.5 .4zM235.6 185.7v.1"/>
<path d="M236.5 193.7l-.3 .1a.74 .74 0 0 0-.1 .9h.4l.1-.4-.1-.2h-.4l-.1 .2M237 194.3h.8M237.6 185.8l.3-1.1 .3 1.1M237.7 185.5h.5M238.5 193.7l.3 .1-.1 .9h-.3l-.1-.2v-.7zM238.6 184.7l.1 1.1M239.1 184.7v.9l.2 .2M239.4 194.1l-.2-.3 .4-.1 .2 .2-.1 .2-.4 .1v.5h.4l.1-.4-.2-.2M240.4 185.1v.7M240.7 185.1l-.3 .1M241 184.7v.1M241 185.1v.7"/>
<path d="M242 185.1v.8l-.1 .2h-.3M242 185.2l-.4-.1-.1 .1 .1 .6h.4M242.5 185.2l.2-.1 .2 .1v.6M242.5 184.7v1.1M243.2 185.1h.4M243.3 184.7v.9l.3 .2M244.3 185.2h-.4v.2l.4 .2v.2h-.4M245.5 185.1v.7M245.9 185.1l-.4 .1M246.1 185.4l.5-.1-.1-.2-.4 .1v.4l.1 .2h.3M247.4 185.2l-.3-.1-.1 .1 .4 .3v.3h-.4M247.8 185.4l.5-.1-.1-.2-.4 .1v.4l.1 .2h.3"/>
<path d="M248.7 185.1v.7M249 185.1l-.3 .1M249.3 185.1l.2 .7 .3-.7M250.1 185.4l.5-.1-.2-.2-.3 .1v.6h.4M250.1 197.6v1.3M251.5 184.7v1.1h-.5l-.1-.6 .2-.1 .4 .1M252 185.7v.1M266.4 193.2v4.4M267.5 198.2l-.2-.1v-.3l.4-.1 .1 .3-.5 .2v.4l.2 .1 .3-.2-.1-.3M268 195.6v1M268.1 194.1h.5v-.3l-.1-.2h-.4v1M268.3 194.1l.3 .5"/>
<path d="M268.9 196h-.4v.5l.2 .1h.2M268.9 195.6v1M269.1 194.3l.4-.1-.1-.2-.3 .1v.5h.4M269.4 196.5v.1M269.4 196h.1M269.8 194l.3 .6 .2-.6M270.8 194.6h.1M270.8 194.1h.1M271.1 195.6h-.2a.73 .73 0 0 0-.2 1h.4l.1-.1v-.5h-.3l-.3 .1M271.9 194.6l.3-1 .3 1M271.9 194.4h.6M272.4 195.5l-.8 1.3"/>
<path d="M272.9 196l-.2-.2 .1-.2h.4l.1 .4h-.5l-.1 .2 .2 .4 .4-.1v-.4l-.2-.1M282.7 180.6h1.3M283.2 197.5h.2M283.6 197.1h-.4v.9"/>
<circle cx="221.3" cy="187.5" r=".34"/>
</g>
<g fill="none" stroke="#910000" stroke-width=".25">
<path d="M210.5 190.9h.9M210.9 190.9l-.1 1.3M211.7 191.4l-.1 .8M211.8 190.9v.1M212.2 191.4h.5M212.5 190.9l-.2 1.3h.3M213.2 190.9l-.1 1.2 .1 .1M213.7 191.8l.7-.1-.2-.3-.5 .2v.6h.5M214.9 192.1v.1M215 191.5v.1M217.4 190.9a.89 .89 0 0 0-.7 1.3h.5l.2-.5-.1-.2h-.5l-.2 .2M218.1 191.5l-.1-.1v-.3l.2-.2 .4 .1v.4l-.5 .1-.2 .2 .1 .5 .6-.1v-.4l-.2-.2"/>
<path d="M219.3 190.9l-.1 1.3M219.3 191.7l.4 .5M219.8 191.4l-.6 .5M221.4 191.6h.6l.2-.2v-.4l-.2-.1h-.6l-.1 1.3M222.8 190.9l-.1 1.3h.2M223.5 191.5l.4-.1 .2 .2-.1 .6h-.6v-.4l.6-.1M224.6 191.4l.2 .8M225.3 191.4l-.6 1.2-.3 .1M226.4 191.4l-.2 1.1-.3 .2h-.3M226.4 191.5h-.6l-.2 .5 .1 .2h.5M226.9 191.4v.8M227.4 191.4l-.5 .2"/>
<path d="M227.8 191.5h.6v.5l-.2 .2-.5-.1zM229.1 191.4l-.1 .8 .5-.1M229.7 191.4l-.2 .8M230.2 191.5l.5-.1 .1 .2v.6M230.2 191.4v.8M232.1 190.9l-.2 1.3h-.5v-.7h.6M234.6 191a.6 .6 0 0 0-.8 0 .6 .6 0 0 0-.2 .7l.2 .5 .6-.1M235.1 191.6h.7l.1-.2-.1-.4-.6-.1-.2 1.3M236.5 190.9l-.2 1.1 .2 .2 .6-.1 .2-1.2M237.9 191.1l.3-.2 .3 .1v.7l-.2 .5h-.4zM239 192.2h.8M239.1 191.3l.5-.4-.2 1.3"/>
<path d="M240.7 190.9l.5 .2v.6l-.3 .5h-.4l-.2-.5 .2-.6z"/>
</g>
<g fill="#ffb">
<path d="M179.5 30.9h4.4v13.8h-4.4z"/>
<path d="M193.8 84.4h3.3v34.4h-3.3z"/>
<path d="M220 102.5h4.3v13.7h-4.3z"/>
<path d="M220 123.1h4.3v13.8h-4.3z"/>
<path d="M177.3 56.9h3.5v8.5h-3.5z"/>
<path d="M122.2 28.4h29.3v53.4h-29.3z"/>
<path d="M128.2 105.9h10.4v20.7h-10.4z"/>
<path d="M220 81.8h4.3v13.7h-4.3z"/>
<path d="M205.8 55.9h3.5v8.7h-3.5z"/>
<path d="M165.3 129.2h10.3v20.6h-10.3z"/>
<path d="M40.4 28.4h34.5v83.6h-34.5z"/>
<path d="M99.4 78.4h4.4v13.8h-4.4z"/>
<path d="M98.1 58.5h6.9v6.9h-6.9z"/>
<path d="M49.1 141.2h15.5v29.3h-15.5z"/>
<path d="M99 105.9h10.3v20.7h-10.3z"/>
<path d="M103.2 144.6h13.8v10.4h-13.8z"/>
</g>
<g fill="none" stroke="#0f0f0f" stroke-width=".21">
<path d="M171 33.8h7.1M171.2 34.1v.8h.4l.1-.8M171.2 35.5h6.9M171.3 35.8l.1 .8 .4-.1v-.7M171.8 32.1h6.3M171.9 34.9l.3-.8 .3 .8M172 32.4l.1 .8 .3-.1v-.7M172 34.7h.4M172 39h6.1M172.1 36.6l.3-.8 .3 .8M172.1 39.2l.1 .9h.3l.1-.9M172.2 36.4h.4"/>
<path d="M172.3 30.3h5.8M172.4 30.6l.1 .9h.3l.1-.9M172.4 37.3h5.7M172.5 37.5v.7l.2 .2 .3-.1v-.8M172.8 34.5h.4l.1-.3-.5-.1v.8M172.8 33.2l.2-.8 .4 .8M172.8 33h.5M172.9 39.8h.5M173 36.3l.4-.1v-.4h-.4v.8M173 34.5l.3 .4M173.2 31.5l.2-.9 .4 .9M173.2 36.3l.2 .3"/>
<path d="M173.3 31.3h.4M173.4 38.4l.2-.9 .3 .9M173.4 38.1h.4M173.5 34.1h.5M173.6 32.8h.3l.2-.2-.1-.2h-.4v.8M173.7 39.7h.4l.1-.4-.5-.1v.9M173.7 35.8h.5M173.8 34.1v.8M173.8 32.8l.3 .4M173.9 35.8v.8M173.9 39.7l.3 .4M174 31.1l.5-.1v-.3l-.5-.1v.9"/>
<path d="M174.2 38h.3l.2-.2-.1-.3h-.4v.9M174.3 34.5l.4-.1v-.3h-.4v.8h.4l.1-.2-.2-.2M174.3 31.1l.2 .4M174.4 38l.3 .4M174.4 32.4h.4M174.5 39.2h.5M174.5 36.2h.4l.1-.3-.2-.1h-.3v.8h.4l.1-.3-.2-.1M174.6 32.4v.8M174.7 39.2v.9M174.8 30.6h.5M174.9 37.5h.5M175 35h.6"/>
<path d="M175 30.6v.9M175.1 32.7h.4l.1-.2-.5-.1v.8h.4l.1-.3-.2-.2M175.1 36.7h.7M175.1 37.5v.9M175.2 39.8h.4M175.6 31h.4l-.1-.4h-.3v.9h.4l.1-.3-.2-.2M175.6 38.4l.3-.9 .2 .9M175.6 38.1h.5M175.8 34.1l.4 .1 .1 .4-.2 .3h-.3zM175.8 33.3h.6M176.2 31.5h.7M176.2 38.5h.7"/>
<path d="M176.5 35.9l-.3-.1-.2 .2v.4l.1 .2 .4-.1M176.7 35.8h.5M177 35.8v.8M177.1 31.1h.3l.2-.2-.2-.3h-.3v.9M177.1 38h.3l.2-.2-.1-.3h-.4v.9M177.2 34.1l-.5 .1v.2l.5 .3-.1 .2h-.4M177.2 39.3l-.5-.1-.1 .4 .1 .5 .5-.1M177.2 32.5l-.5-.1a.44 .44 0 0 0-.1 .5 .44 .44 0 0 0 .6 .2M177.3 31.1l.3 .4M177.3 38l.3 .4M177.5 34.5h.4v-.4h-.4v.8M177.5 39.2l.4 .1 .1 .4-.2 .4h-.3z"/>
<path d="M177.5 32.4h.3a.48 .48 0 0 1 .2 .5 .48 .48 0 0 1-.5 .3zM177.7 34.5l.3 .4M177.9 30.6v.9M177.9 37.5v.9M178 35.9h-.5v.2l.5 .3-.1 .2h-.4M197 31.5v.7l.1 .2 .4-.2v-.7M197.1 34.7h6.8M197.1 27.8h6.8M197.1 33.2v.7l.2 .2 .4-.1v-.8M197.1 34.9l.1 .9 .5-.1v-.8M197.1 28.1v.6l.2 .2 .4-.1v-.7M197.7 32.4l.4-.9 .2 .9"/>
<path d="M197.8 32.1h.4M198 34.1l.2-.9 .3 .9M198 35.8l.2-.9 .3 .9M198 28.9l.2-.8 .3 .8M198.1 33.8h.3M198.1 35.5h.3M198.1 28.7h.3M198.6 32l.5-.1v-.4h-.5v.9M198.8 33.7h.5v-.5h-.5v.9M198.8 35.3h.5v-.2l-.1-.2h-.4v.9M198.8 28.5h.5v-.4h-.5v.8M198.8 32l.3 .4"/>
<path d="M199 33.7l.3 .4M199 35.3l.3 .5M199 28.5l.3 .4M199.3 31.5h.6M199.6 33.2h.4M199.6 34.9h.4M199.6 31.5v.9M199.6 28.1h.4M199.8 28.1v.8M199.8 33.2v.9M199.8 34.9v.9M200.1 31.9h.4l.1-.3-.2-.1h-.3v.9l.5-.1v-.3l-.2-.1"/>
<path d="M200.4 33.7l.4-.1-.1-.4h-.3v.9h.3l.2-.2-.1-.2h-.2M200.4 35.3h.4v-.3l-.4-.1v.9h.4l.1-.3-.3-.2M200.4 28.5l.4-.1-.1-.3h-.3v.8h.3l.2-.2-.1-.2h-.2M200.8 32.5h.7M201 34.2h.6M201 35.9h.6M201 29h.6M201.6 32l.5-.1v-.4h-.5v.9M201.7 33.2h.5M201.9 28.5h.4v-.4h-.4v.8M201.9 32l.2 .4M202 33.2v.9"/>
<path d="M202.1 28.5l.2 .4M202.3 35a.43 .43 0 0 0-.5 .3 .43 .43 0 0 0 .2 .5l.3-.1M202.4 33.2l.6 .9M202.4 31.5l.6 .9M202.6 34.9h.5M202.6 28.1h.5M202.8 28.1v.8M202.8 34.9v.9M203 33.2l-.6 .9M203 31.5l-.6 .9M203.3 33.2h.4v.2a.42 .42 0 0 1 .1 .5 .42 .42 0 0 1-.5 .2zM203.3 31.5a.47 .47 0 0 1 .5 .4 .47 .47 0 0 1-.5 .5z"/>
<path d="M203.8 35l-.3-.1-.2 .2 .5 .4-.1 .3h-.4M203.8 28.1h-.4l-.1 .1 .5 .5-.1 .2-.4-.1M171.2 40.7h6.9M171.2 40.9l.1 .9h.4v-.9M171.3 42.5h6.8M171.5 42.7v.8l.2 .1 .3-.2v-.7M172.1 41.8l.2-.9 .3 .9M172.1 41.6h.4M172.3 43.6l.2-.9 .3 .9M172.3 43.3h.5M172.8 40.1l.4-.9 .2 .9M172.9 41.4h.5l-.1-.5h-.4v.9"/>
<path d="M173.1 43.1h.4v-.4h-.4v.9M173.1 41.4l.3 .4M173.4 43.1l.2 .5M173.6 40.9h.5M173.9 42.7h.5M173.9 40.9v.9M174.1 42.7v.9M174.3 41.8l.3-.9 .3 .9M174.4 41.6h.4M174.5 43.6l.3-.9 .2 .9M174.6 43.3h.4M175 41.9h.6"/>
<path d="M175.1 40.1l.3-.9 .3 .9M175.1 43.6h.7M175.8 40.9a.49 .49 0 0 1 .5 .3 .49 .49 0 0 1-.2 .6h-.3zM175.8 40.2h.6M176.5 42.8l-.4-.1-.1 .2v.4l.2 .3 .3-.1M176.7 42.7h.5M177 42.7v.9M177.2 41h-.5v.3l.5 .3-.1 .2h-.4M177.5 41.4h.3l.2-.3-.2-.2h-.3v.9M177.7 41.4l.3 .4M178 42.7l-.5 .1v.2l.4 .1 .1 .2-.2 .3-.3-.1M197.2 42.5h6.7"/>
<path d="M197.3 42.7v.8l.2 .1 .3-.2v-.7M198.1 43.6l.3-.9 .3 .9M198.2 43.3h.4M198.9 43.1h.4l.1-.3-.5-.1v.9M199.2 43.1l.2 .5M199.7 42.7h.5M199.9 42.7v.9M200.4 43.6l.2-.9 .4 .9M200.4 43.3h.5M201 43.6h.6M201.9 43.1h.4v-.4h-.4v.9M202.1 43.1l.2 .5"/>
<path d="M202.6 42.7h.5M202.8 42.7v.9M203.8 42.7h-.4l-.1 .2 .2 .2h.2l.1 .3-.1 .2-.4-.1"/>
</g>
<path d="M179.5 30.9h4.3v13.8h-4.3zM179.9 31.2h2.7v1.1h-2.7zM187.7 31.9h.1M187.7 30.1l-.5 .8M187.7 30.1l.5 .8M187.7 30.1v1.8M195.4 27.6v.8h.9l-.9 .8-.8-.8h.8M195.4 27.6h.1" fill="none" stroke="#910000" stroke-width=".21"/>
<path d="M183 31.6l.3 .2-.1 .2-.3-.2z" fill="#910000"/>
<path d="M179.1 31.9h.9M179.9 33h2.7v1h-2.7zM182.7 31.9h.5v1.7h-.5M183.1 31.7l.3 .2-.1 .2-.3-.2z" fill="none" stroke="#910000" stroke-width=".21"/>
<path d="M183 33.3l.3 .2-.1 .2-.3-.2z" fill="#910000"/>
<path d="M179.1 33.6h.9M179.9 34.7h2.7v1h-2.7zM182.7 33.6h.5v1.7h-.5M183.1 33.4l.3 .2-.1 .2-.3-.2z" fill="none" stroke="#910000" stroke-width=".21"/>
<path d="M183 35l.3 .2-.1 .2-.3-.2z" fill="#910000"/>
<path d="M179.1 35.3h.9M179.9 36.4h2.7v1.1h-2.7zM182.7 35.3h.5v1.7h-.5M183.1 35.1l.3 .2-.1 .1-.3-.1z" fill="none" stroke="#910000" stroke-width=".21"/>
<path d="M183 36.8l.3 .2-.1 .2-.3-.2z" fill="#910000"/>
<path d="M179.1 37h.9M179.9 38.2h2.7v1h-2.7zM182.7 37h.5v1.7h-.5M183.1 36.9l.3 .1-.1 .2-.3-.2z" fill="none" stroke="#910000" stroke-width=".21"/>
<path d="M183 38.5l.3 .2-.1 .2-.3-.2z" fill="#910000"/>
<path d="M179.1 38.7h.9M179.9 39.9h2.7v1h-2.7zM182.7 38.7h.5v1.7h-.5M183.1 38.5l.3 .2-.1 .2-.3-.2z" fill="none" stroke="#910000" stroke-width=".21"/>
<path d="M183 40.2l.3 .2-.1 .2-.3-.2z" fill="#910000"/>
<path d="M179.1 40.4h.9M179.9 41.6h2.7v1.1h-2.7zM182.7 40.4h.5v1.8h-.5M183.1 40.2l.3 .2-.1 .2-.3-.2z" fill="none" stroke="#910000" stroke-width=".21"/>
<path d="M183 42l.3 .2-.1 .1-.3-.1z" fill="#910000"/>
<g fill="none" stroke="#910000" stroke-width=".21">
<path d="M178.2 31.9h.9M178.2 33.6h.9M178.2 35.3h.9M178.2 37h.9M178.2 38.7h.9M183.4 31.9h1.7M178.2 42.2h1.8M178.2 43.9h1.8M178.2 40.4h.9M179.9 43.3h2.7v1.1h-2.7zM182.7 42.2h.5v1.7h-.5M183.1 42l.3 .2-.1 .2-.3-.2z"/>
<path d="M175.6 97.3h.9v-.9l.8 .9-.8 .9v-.9M175.6 97.3h.1"/>
</g>
<path d="M178.3 32.5h.6l-.3 .3h.3v.5l-.6-.1M178.3 39.3h.6l-.3 1M178.4 30.9l.5-.1v.3l-.6 .5h.6M178.6 34.2l-.2 .6h.5M178.9 35.9h-.5v.5l.5-.1v.4h-.5M178.9 37.6l-.5 .2v.6l.5 .1v-.5h-.4l-.1 .1M178.9 34.5v.5M184 31l.3-.2v.8M184 31.6h.5M178.6 41.4l-.2-.2 .5-.1v.3l-.5 .1v.4h.2h.3l-.1-.5M178.9 43.1v.2h-.4l-.1-.4h.5v.6l-.1 .1h-.3" fill="none" stroke="#b90000" stroke-width=".21"/>
<path d="M172.2 93.8h.6v.1h-.6z" fill="#910000"/>
<path d="M172.2 93.8h.6v.1h-.6z" fill="none" stroke="#910000" stroke-width=".21"/>
<path d="M172.2 95.5h.6v.1h-.6z" fill="#910000"/>
<path d="M172.2 95.5h.6v.1h-.6z" fill="none" stroke="#910000" stroke-width=".21"/>
<path d="M172.2 97.2h.6v.2h-.6z" fill="#910000"/>
<path d="M172.2 97.2h.6v.2h-.6z" fill="none" stroke="#910000" stroke-width=".21"/>
<path d="M172.2 98.9h.6v.2h-.6z" fill="#910000"/>
<g fill="none" stroke="#910000" stroke-width=".21">
<path d="M172.2 98.9h.6v.2h-.6zM172.8 93.8h4.5M172.8 95.5h2.8M172.8 97.3h2.8M172.8 99h2.8M175.6 93.8h.1M176.5 93.3l.8 .5M177.3 93.8l-.8 .6M191.1 93.8h2.7M191.1 95.5h2.7M191.1 97.3h2.7M191.1 99h2.7"/>
<path d="M191.1 85.2h2.7M191.1 87h2.7M191.1 88.7h2.7M191.1 90.4h2.7M191.1 92.2h2.7M193.7 84.3h3.4v34.5h-3.4zM193.8 85.1h.8v.2h-.8zM193.8 86.9h.8v.2h-.8zM193.8 88.6h.8v.2h-.8zM193.8 90.3h.8v.2h-.8zM193.8 92.1h.8v.1h-.8zM193.8 93.8h.8v.1h-.8z"/>
<path d="M193.8 95.5h.8v.1h-.8zM193.8 97.2h.8v.2h-.8zM193.8 98.9h.8v.2h-.8zM196.3 85.1h.8v.2h-.8zM196.3 86.9h.8v.2h-.8zM196.3 88.6h.8v.2h-.8zM196.3 90.3h.8v.2h-.8zM196.3 92.1h.8v.1h-.8zM196.3 93.8h.8v.1h-.8zM196.3 95.5h.8v.1h-.8zM196.3 97.2h.8v.2h-.8zM196.3 98.9h.8v.2h-.8z"/>
<path d="M197.1 93.8h2.7M197.1 95.5h2.7M197.1 97.3h2.7M197.1 99h2.7M197.1 85.2h2.7M197.1 87h2.7M197.1 88.7h2.7M197.1 90.4h2.7M197.1 92.2h2.7M172.5 111.6h1.1v2.4h-1.1zM173 111v.6M173 114v.5"/>
<path d="M190.3 100.7v-.8l-.9 .8 .9 .9v-.9h.8M191.1 100.7h.1M191.1 100.7h2.7M191.1 102.5h2.7M191.1 104.2h2.7M191.1 105.9h2.7M191.1 107.7h2.7M191.1 109.3h2.7M191.1 111h2.7M191.1 112.8h2.7M191.1 114.5h2.7M191.1 116.2h2.7"/>
<path d="M191.1 118h2.7M193.8 100.6h.8v.2h-.8zM193.8 102.4h.8v.2h-.8zM193.8 104.1h.8v.2h-.8zM193.8 105.8h.8v.2h-.8zM193.8 107.6h.8v.1h-.8zM193.8 109.3h.8v.1h-.8zM193.8 111h.8v.1h-.8zM193.8 112.7h.8v.2h-.8zM193.8 114.4h.8v.2h-.8zM193.8 116.1h.8v.2h-.8zM193.8 117.9h.8v.2h-.8z"/>
<path d="M196.3 100.6h.8v.2h-.8zM196.3 102.4h.8v.2h-.8zM196.3 104.1h.8v.2h-.8zM196.3 105.8h.8v.2h-.8zM196.3 107.6h.8v.1h-.8zM196.3 109.3h.8v.1h-.8zM196.3 111h.8v.1h-.8zM196.3 112.7h.8v.2h-.8zM196.3 114.4h.8v.2h-.8zM196.3 116.1h.8v.2h-.8zM196.3 117.9h.8v.2h-.8zM197.1 100.7h2.7"/>
<path d="M197.1 102.5h2.7M197.1 104.2h2.7M197.1 105.9h2.7M197.1 107.7h2.7M197.1 109.3h2.7M197.1 111h2.7M197.1 112.8h2.7M197.1 114.5h2.7M197.1 116.2h2.7M197.1 118h2.7M199.8 118h.8v-.9l.9 .9-.9 .8v-.8M199.8 118h.1"/>
<path d="M201.5 102.5h.8v-.9l.9 .9-.9 .8v-.8M201.5 102.5h.1M220 102.4h4.3v13.8h-4.3zM220.4 102.8h2.8v1h-2.8zM228.2 103.3h.1M228.2 101.6l-.6 .9M228.2 101.6l.5 .9M228.2 101.6v1.7M200.9 121h1v2.4h-1zM201.5 120.5v.5M201.5 123.5v.5"/>
</g>
<g fill="none" stroke="#b90000" stroke-width=".21">
<path d="M174 96.2h.6l-.3 .4h.2l.1 .3-.1 .2-.5-.1M174.1 93l.3-.3v.9M174.1 94.5l.4-.1 .1 .3-.6 .7h.6M174.1 93.6h.5M174.3 97.9l-.2 .6h.5M174.5 98.2v.6M191.8 93l.2-.3v.9M191.8 94.7l.2-.3v1M191.8 96.5l.2-.3v.9M191.8 98.2l.2-.3v.9M191.8 99.9l.2-.3v.9M191.8 93.6h.4"/>
<path d="M191.8 95.4h.4M191.8 97.1h.4M191.8 98.8h.4M192.1 84.4l.3-.3v.9M192.1 85.9h.6l-.3 .3 .3 .1v.4h-.6M192.1 89.3h.6l-.4 .9M192.1 85h.6M192.6 93l.2-.3v.9M192.6 94.4h.5l-.3 .4 .3 .1v.4h-.5M192.6 97.9h.6l-.5 .9M192.6 93.6h.5M192.7 87.6h-.5l-.1 .4 .5-.1 .1 .4h-.6"/>
<path d="M192.7 91.4l-.1 .2h-.4v-.5h.5l-.1 .7-.4 .1M193.1 96.2h-.4l-.1 .4h.4l.1 .4h-.5M197.8 91.3l.3-.2v.8M197.8 93l.3-.3v.9M197.8 94.7l.3-.3v1M197.8 96.5l.3-.3v.9M197.8 98.2l.3-.3v.9M197.8 99.7l.4-.1 .1 .3-.6 .6h.6M197.8 93.6h.5M197.8 95.4h.5M197.8 97.1h.5M197.8 98.8h.5"/>
<path d="M197.8 91.9h.5M198.2 84.2l.4-.1 .1 .4-.5 .5h.5M198.4 85.8l-.2 .6h.6M198.4 89.7l-.2-.1v-.2l.4-.1 .1 .3-.5 .2v.3l.2 .1 .3-.1-.1-.4M198.6 87.6l-.4 .2v.5h.5l-.1-.4h-.3l-.1 .2M198.6 92.8h.5v.3l-.5 .5h.5M198.6 86.1v.6M198.7 91.1h.3l.1 .1v.5l-.2 .2a.48 .48 0 0 1-.2-.8zM198.7 99.7l.2-.1 .2 .2v.6l-.2 .1a.53 .53 0 0 1-.2-.8zM198.8 98.3l-.2-.1 .2-.3 .3 .1-.1 .3-.4 .1 .1 .4h.3l.1-.5h-.2M198.8 94.4l-.2 .6h.6M199 96.2h-.2l-.2 .7 .2 .2 .3-.1-.1-.4h-.3l-.1 .1"/>
<path d="M199 94.8v.6M191.7 110h.5l-.2 .3 .2 .1v.4h-.5M191.7 111.7h.5l-.2 .4h.2v.4h-.5M191.7 113.4h.5l-.2 .3 .2 .1v.4h-.5M191.7 115.2h.5l-.2 .2 .2 .1v.4h-.5M191.7 116.9h.5l-.2 .3 .2 .1v.3h-.5M191.8 101.5l.3-.1 .1 .3-.5 .5h.5M191.8 103.2h.4v.2l-.5 .5h.5M191.8 104.9h.4v.3l-.5 .5h.5M191.8 106.6l.3-.1 .1 .4-.5 .5h.5M191.8 108.3h.4v.4l-.5 .4h.5M191.8 100.5h.4"/>
<path d="M192.6 101.6l.2-.2v.8M192.6 103.1h.5l-.3 .3 .3 .1v.3h-.5M192.6 106.5h.6l-.5 .9M192.6 110.2l.2-.2v.9M192.6 111.7h.5l-.3 .4h.3v.4h-.5M192.6 115.2h.6l-.5 .8M192.6 102.2h.5M192.6 110.9h.5M193.1 100l-.4 .2-.1-.4 .1-.2 .4 .1-.1 .8h-.3M193.1 104.8h-.4l-.1 .4h.5v.4h-.5M193.1 108.7h-.5l.1-.5 .4 .1v.6l-.4 .2M193.1 113.4h-.4l-.1 .4h.5v.4h-.5"/>
<path d="M193.1 117.2l-.1 .2h-.3v-.5l.4 .1v.6l-.4 .1M197.7 108.2h.6l-.3 .4 .3 .2-.1 .3-.5-.1M197.7 110h.6l-.3 .3 .3 .1v.3l-.1 .2-.5-.1M197.7 111.7h.6l-.3 .4h.2v.5l-.5-.1M197.7 113.4h.6l-.3 .3 .3 .2-.1 .4-.5-.1M197.7 115.2h.6l-.3 .2 .3 .2v.3l-.1 .1-.5-.1M197.8 101.5l.4-.1 .1 .2-.6 .6h.6M197.8 103.2l.4-.1 .1 .2-.6 .6h.6M197.8 104.9l.4-.1 .1 .2-.6 .7h.6M197.8 106.6l.4-.1 .1 .3-.6 .6h.6M198 116.8l-.2 .7h.5M198.2 117.1v.6"/>
<path d="M198.6 101.5h.5v.2l-.5 .5h.5M198.6 110h.5v.4l-.5 .5h.5M198.7 108.3l.2-.1 .2 .2-.1 .6a.39 .39 0 0 1-.4-.2 .39 .39 0 0 1 .1-.5zM198.7 117l.3-.1v.7a.39 .39 0 0 1-.4-.2 .39 .39 0 0 1 .1-.4zM198.8 106.9l-.2-.2 .1-.2h.3l.1 .3-.5 .3 .1 .3h.3l.1-.4-.2-.1M198.8 115.5l-.2-.2 .4-.1 .1 .2-.4 .1-.1 .2 .2 .3 .3-.1v-.3l-.2-.1M198.8 103.1l-.2 .6h.6M198.8 111.6l-.2 .7h.6M199 104.8l-.2 .1-.2 .6 .2 .2 .3-.1v-.4l-.3-.1-.2 .2M199 113.4l-.2 .1-.2 .6 .1 .2 .4-.1v-.4l-.3-.1-.2 .2M199 103.4v.5M199 112v.6"/>
</g>
<g fill="none" stroke="#0f0f0f" stroke-width=".21">
<path d="M186.6 90l.4-.8 .2 .8M186.6 93.5l.4-.8 .2 .8M186.6 98.7l.4-.9 .2 .9M186.6 91.8l.4-.9 .2 .9M186.6 97l.4-.9 .2 .9M186.7 89.8h.5M186.7 93.3h.5M186.7 98.4h.5M186.7 91.6h.5M186.7 96.7h.5M187.4 89.2h.5M187.4 92.7h.5"/>
<path d="M187.4 97.8h.5M187.4 90.9h.5M187.4 96.1h.5M187.7 89.2v.8M187.7 90.9v.9M187.7 92.7v.8M187.7 96.1v.9M187.7 97.8v.9M188.1 90l.2-.8 .4 .8M188.1 93.5l.2-.8 .4 .8M188.1 98.7l.2-.9 .4 .9M188.1 91.8l.2-.9 .4 .9"/>
<path d="M188.1 97l.2-.9 .4 .9M188.2 89.8h.4M188.2 93.3h.4M188.2 98.4h.4M188.2 91.6h.4M188.2 96.7h.4M188.8 90.1h.6M188.8 93.6h.6M188.8 98.8h.6M188.8 91.8h.6M188.8 97.1h.6M189.6 89.2l.4 .1 .1 .4-.2 .3h-.3z"/>
<path d="M189.6 92.7h.3a.48 .48 0 0 1 .2 .5 .48 .48 0 0 1-.5 .3zM189.6 97.8h.3a.47 .47 0 0 1 .2 .6 .47 .47 0 0 1-.5 .3zM189.6 90.9a.47 .47 0 0 1 .5 .5 .47 .47 0 0 1-.5 .4zM189.6 96.1a.47 .47 0 0 1 .5 .4 .47 .47 0 0 1-.5 .5zM190.4 92.7h.5l-.3 .3 .3 .1v.3h-.5M190.5 97.9l.3-.1 .1 .2v.5l-.2 .2-.2-.1zM190.5 96.3l.1-.2v.9M190.5 97h.4M190.6 90.9l-.1 .6h.5M190.8 91.2v.6M190.9 89.2h-.4v.4h.4l-.1 .4h-.3M199.9 98.7l.3-.9 .2 .9"/>
<path d="M200 98.4h.4M200.6 97.8h.5M200.9 97.8v.9M201.3 98.7l.2-.9 .4 .9M201.4 98.4h.4M202 98.8h.6M202.8 97.8h.4a.47 .47 0 0 1 .1 .6 .47 .47 0 0 1-.5 .3zM203.7 98.1l.2-.3v.9M203.7 98.7h.4M204.9 97.8h-.4l-.1 .5 .4-.1 .1 .4h-.5M167.8 107.3l.3-.9 .3 .9M167.9 107.1h.4"/>
<path d="M168.5 106.4h.5M168.8 106.4v.9M169.2 107.3l.3-.9 .3 .9M169.3 107.1h.4M169.9 107.4h.7M170.7 106.9h.4l.1-.4-.1-.1h-.4v.9M170.9 106.9l.3 .4M171.6 106.4h.2l.3 .2v.5l-.3 .2h-.2zM172.3 106.4l.3 .5 .3-.5M172.6 106.9v.4M177.8 110.7l.3-.8 .2 .8M177.8 110.4h.5"/>
<path d="M178.5 109.9h.5M178.8 109.9v.8M179.2 110.7l.2-.8 .4 .8M179.3 110.4h.4M179.9 110.8h.6M180 103.8l.3-.8 .3 .8M180 102.7h5.8M180.1 105.5l.4-.8 .2 .8M180.1 103.6h.4M180.1 104.4h5.7M180.2 105.3h.4M180.7 109.9v.8"/>
<path d="M180.8 103h.4M180.9 104.7h.5M181.1 103v.8M181.1 104.7v.8M181.4 103.8l.3-.8 .3 .8M181.5 103.6h.4M181.6 105.5l.2-.8 .4 .8M181.6 109.9v.8l-.5-.8v.8M181.6 105.3h.5M181.9 109.9h.5M182.1 103.9h.6M182.2 109.9v.8"/>
<path d="M182.2 105.6h.6M182.9 103v.8M183.1 104.7v.8M183.3 103.1l.5-.1 .1 .2v.4l-.2 .2-.4-.1zM183.7 104.7l.3 .2-.1 .6h-.3l-.2-.2v-.4zM184.2 103l.2 .8 .1-.6 .2 .6 .3-.8M184.4 105.1h.4l.1-.3-.5-.1v.8M184.6 105.1l.3 .4M185.2 103.4h.4l.1-.3-.5-.1v.8M185.2 104.7h.3l.2 .2v.5l-.2 .1h-.3zM185.5 103.4l.2 .4M186.8 112.5l.3-1 .3 1"/>
<path d="M186.9 112.2h.4M187.6 111.5h.4M187.8 111.5v1M188.2 112.5l.3-1 .3 1M188.3 112.2h.4M188.8 112.6h.7M189.6 112.5l.3-1 .3 1M189.7 112.2h.4M190.5 111.8l.1-.3v1M190.5 112.5h.4M199.9 115.9l.3-.9 .2 .9M199.9 114.2l.3-.9 .2 .9"/>
<path d="M199.9 114.8h6.6M200 115.6h.4M200 113.9h.4M200.6 115h.5M200.6 113.3h.5M200.9 113.3v.9M200.9 115v.9M201.3 115.9l.2-.9 .4 .9M201.3 114.2l.2-.9 .4 .9M201.4 115.6h.4M201.4 113.9h.4M202 115.9h.6"/>
<path d="M202 114.3h.6M202.7 114.2l.3-.9 .2 .9M202.7 113.9h.5M203.3 115.1a.44 .44 0 0 0-.6 .2 .44 .44 0 0 0 .2 .6l.4-.1M203.5 113.4h.5v.3l-.5 .5h.5M204.1 115.1h-.4v.3l.4 .1v.4h-.4M204.4 115h.5l-.2 .4h.2v.4h-.5M205.4 115.4h.2M205.7 115h-.3v.9M205.9 115l.6 .9M206.5 115l-.6 .9M213.4 111.5l.3-.8 .3 .8"/>
<path d="M213.4 109.9l.3-.9 .3 .9M213.4 113.3l.3-.8 .3 .8M213.4 115l.3-.8 .3 .8M213.5 114.8h.4M213.5 111.4h.4M213.5 109.6h.4M213.5 113.1h.4M214.2 112.5h.5M214.2 110.7h.5M214.2 109h.5M214.2 114.2h.5M214.4 109v.9"/>
<path d="M214.4 110.7v.8M214.4 112.5v.8M214.4 114.2v.8M214.8 111.5l.3-.8 .3 .8M214.8 109.9l.3-.9 .3 .9M214.8 113.3l.3-.8 .3 .8M214.8 115l.3-.8 .3 .8M214.9 114.8h.4M214.9 111.4h.4M214.9 109.6h.4M214.9 113.1h.4M215.5 111.6h.6"/>
<path d="M215.5 109.9h.6M215.5 113.4h.6M215.5 115.1h.6M216.4 110.7l.4 .2-.1 .6h-.3zM216.4 109l.4 .1-.1 .8h-.3zM216.4 112.5l.4 .1v.6l-.3 .1h-.1zM216.4 114.2l.4 .1-.1 .7h-.3zM217.1 111l.3-.3v.8M217.1 109.3l.3-.3v.9M217.1 112.7l.3-.2v.8M217.1 114.4l.3-.2v.8M217.1 111.5h.5"/>
<path d="M217.1 109.9h.5M217.1 115h.5M217.1 113.3h.5M218 110.7h.5l-.4 .3 .4 .2v.3h-.5M218 109.1l.4-.1 .1 .2-.5 .7h.5M218.1 112.4l-.1 .6h.5M218.4 114.2h-.3l-.1 .4 .4-.1v.5l-.4-.1M218.4 112.7v.6"/>
</g>
<path d="M223.6 103.1l.3 .2-.1 .2-.3-.2z" fill="#910000"/>
<path d="M219.6 103.3h.8M220.4 104.5h2.8v1h-2.8zM223.2 103.3h.5v1.7h-.5M223.6 103.1l.3 .2-.1 .2-.3-.2z" fill="none" stroke="#910000" stroke-width=".21"/>
<path d="M223.6 104.8l.3 .2-.1 .2-.3-.2z" fill="#910000"/>
<path d="M219.6 105h.8M220.4 106.2h2.8v1.1h-2.8zM223.2 105h.5v1.8h-.5M223.6 104.8l.3 .2-.1 .2-.3-.2z" fill="none" stroke="#910000" stroke-width=".21"/>
<path d="M223.6 106.6l.3 .2-.1 .1-.3-.1z" fill="#910000"/>
<path d="M219.6 106.8h.8M220.4 107.9h2.8v1.1h-2.8zM223.2 106.8h.5v1.7h-.5M223.6 106.6l.3 .2-.1 .2-.3-.2z" fill="none" stroke="#910000" stroke-width=".21"/>
<path d="M223.6 108.3l.3 .2-.1 .1-.3-.1z" fill="#910000"/>
<path d="M219.6 108.5h.8M220.4 109.6h2.8v1.1h-2.8zM223.2 108.5h.5v1.7h-.5M223.6 108.3l.3 .2-.1 .2-.3-.2z" fill="none" stroke="#910000" stroke-width=".21"/>
<path d="M223.6 110l.3 .1-.1 .2-.3-.2z" fill="#910000"/>
<path d="M219.6 110.2h.8M220.4 111.3h2.8v1.1h-2.8zM223.2 110.2h.5v1.8h-.5M223.6 110l.3 .2-.1 .2-.3-.2z" fill="none" stroke="#910000" stroke-width=".21"/>
<path d="M223.6 111.7l.3 .2-.1 .2-.3-.2z" fill="#910000"/>
<path d="M219.6 112h.8M220.4 113.1h2.8v1h-2.8zM223.2 112h.5v1.7h-.5M223.6 111.8l.3 .2-.1 .2-.3-.2z" fill="none" stroke="#910000" stroke-width=".21"/>
<path d="M223.6 113.4l.3 .2-.1 .2-.3-.2z" fill="#910000"/>
<g fill="none" stroke="#910000" stroke-width=".21">
<path d="M218.7 113.7h1.7M218.7 115.4h1.7M218.7 103.3h.9M218.7 105h.9M218.7 106.8h.9M218.7 108.5h.9M218.7 110.2h.9M218.7 112h.9M220.4 114.8h2.8v1h-2.8zM223.2 113.7h.5v1.7h-.5M223.6 113.5l.3 .2-.1 .1-.3-.1zM223.9 103.3h1.7"/>
<path d="M220 123.1h4.3v13.8h-4.3zM220.4 123.4h2.8v1.1h-2.8zM228.2 124h.1M228.2 122.3l-.6 .8M228.2 122.3l.5 .8M228.2 122.3v1.7"/>
</g>
<path d="M218.8 103.9h.6l-.3 .4 .3 .1v.3l-.6 .1M218.8 110.9h.6l-.3 .8M218.9 102.3l.4-.1 .1 .3-.6 .6h.6M219.1 105.6l-.2 .6h.5M219.1 112.9l-.2-.3h.3l.2 .1-.1 .2-.4 .1 .1 .4h.3l.1-.3-.2-.2M219.3 107.4h-.4v.4l.4-.1v.5h-.4M219.3 109.1l-.3 .1-.1 .7 .3 .1 .2-.1-.2-.5-.3 .2M219.3 106v.5M219.4 114.7l-.2 .1h-.3v-.5h.3l.2 .1-.2 .7-.2 .1M224.5 102.5l.2-.3v.9M224.5 103.1h.5" fill="none" stroke="#b90000" stroke-width=".21"/>
<g fill="none" stroke="#0f0f0f" stroke-width=".21">
<path d="M199.9 91.8l.3-.9 .2 .9M199.9 93.5l.3-.8 .2 .8M199.9 97l.3-.9 .2 .9M199.9 95.2l.3-.8 .2 .8M199.9 86.6l.3-.9 .2 .9M200 91.6h.4M200 93.3h.4M200 96.7h.4M200 95h.4M200 86.4h.4M200.6 90.9h.5M200.6 92.7h.5"/>
<path d="M200.6 96.1h.5M200.6 94.4h.5M200.6 85.7h.5M200.9 85.7v.9M200.9 90.9v.9M200.9 92.7v.8M200.9 94.4v.8M200.9 96.1v.9M201.3 91.8l.2-.9 .4 .9M201.3 93.5l.2-.8 .4 .8M201.3 97l.2-.9 .4 .9M201.3 95.2l.2-.8 .4 .8"/>
<path d="M201.3 86.6l.2-.9 .4 .9M201.4 91.6h.4M201.4 93.3h.4M201.4 96.7h.4M201.4 95h.4M201.4 86.4h.4M202 91.8h.6M202 93.6h.6M202 97.1h.6M202 95.3h.6M202 86.7h.6M202.8 90.9a.47 .47 0 0 1 .5 .5 .47 .47 0 0 1-.5 .4z"/>
<path d="M202.8 92.7h.4a.48 .48 0 0 1 .1 .5 .48 .48 0 0 1-.5 .3zM202.8 96.1a.47 .47 0 0 1 .5 .4 .47 .47 0 0 1-.5 .5zM202.8 94.4a.47 .47 0 0 1 .5 .3 .47 .47 0 0 1-.1 .5h-.4zM202.8 85.7a.49 .49 0 0 1 .5 .3 .49 .49 0 0 1-.1 .6h-.4zM203.7 91.1l.2-.2v.9M203.7 92.9l.2-.2v.8M203.7 96.3l.2-.2v.9M203.7 94.6l.2-.2v.8M203.7 91.8h.4M203.7 93.5h.4M203.7 97h.4M203.7 95.2h.4"/>
<path d="M203.8 86.1h-.1v-.3l.3-.1 .1 .4-.4 .1v.4h.4l-.1-.5M204.4 91.1l.3-.2v.9M204.4 92.7h.5v.3l-.5 .5h.5M204.4 94.4h.5l-.2 .3 .2 .1v.3h-.5M204.4 91.8h.5M204.7 96.1l-.3 .5h.6M204.8 96.4v.6M211.9 134l.2-.9 .4 .9M211.9 135.7l.2-.9 .4 .9M211.9 132.9h6.7M211.9 134.6h6.7M212 133.7h.4"/>
<path d="M212 135.4h.4M212.6 133.1h.5M212.6 134.8h.5M212.8 123.7l.3-.9 .2 .9M212.8 123.4h.4M212.8 122.6h5.8M212.9 125.3l.2-.8 .4 .8M212.9 133.1v.9M212.9 134.8v.9M212.9 124.2h5.7M213 125.1h.4M213.2 134l.4-.9 .2 .9"/>
<path d="M213.2 135.7l.4-.9 .2 .9M213.3 133.7h.4M213.3 135.4h.4M213.5 122.8h.5M213.6 127.1l.3-.9 .3 .9M213.6 126h5M213.7 124.5h.5M213.7 126.9h.4M213.7 122.8v.9M213.9 134.1h.7M213.9 135.8h.7M213.9 124.5v.8"/>
<path d="M214.2 123.7l.2-.9 .4 .9M214.2 125.3l.4-.8 .2 .8M214.2 123.4h.5M214.3 132.3l.4-.9 .2 .9M214.3 130.5l.4-.8 .2 .8M214.3 128.8l.4-.8 .2 .8M214.3 125.1h.5M214.3 126.2h.5M214.4 132h.4M214.4 130.3h.4M214.4 128.6h.4M214.6 126.2v.9"/>
<path d="M214.8 123.7h.7M214.9 125.4h.7M215 127.1l.3-.9 .2 .9M215.1 131.4h.5M215.1 129.7h.5M215.1 128h.5M215.1 126.9h.4M215.3 133.2l-.4-.1-.1 .2v.5l.2 .2 .3-.1M215.3 134.9l-.3-.1-.2 .3v.4l.1 .2 .4-.1M215.3 128v.8M215.3 129.7v.8M215.3 131.4v.9"/>
<path d="M215.6 127.2h.7M215.7 122.8v.9M215.8 132.3l.2-.9 .4 .9M215.8 130.5l.2-.8 .4 .8M215.8 128.8l.2-.8 .4 .8M215.8 124.5v.8M215.9 132h.4M215.9 130.3h.4M215.9 128.6h.4M216.1 133.1l-.5 .1v.3l.5 .2-.2 .3-.3-.1M216.1 134.9h-.5v.3l.5 .2-.1 .3h-.4M216.1 122.9h.5v.6l-.2 .2-.4-.3z"/>
<path d="M216.4 133.1h.5l-.3 .4 .3 .1v.3h-.5M216.4 124.5l.4 .3-.2 .5h-.4v-.6zM216.4 135.1l.3-.3v.9M216.4 132.4h.6M216.4 135.7h.5M216.4 130.6h.6M216.4 128.9h.6M216.5 126.7l.5-.1v-.3l-.5-.1v.9M216.7 126.7l.3 .4M216.9 122.8l.2 .9 .2-.6 .2 .6 .1-.9M217.1 132.3l.4-.9 .2 .9M217.1 130.5l.4-.8 .2 .8"/>
<path d="M217.1 128.8l.4-.8 .2 .8M217.1 124.9h.4l.1-.2-.1-.2h-.4v.8M217.2 132h.4M217.2 130.3h.4M217.2 128.6h.4M217.3 133.6h.2M217.3 135.3h.2M217.3 124.9l.3 .4M217.7 133.1h-.4v.9M217.7 134.8h-.4v.9M217.8 126.3l-.3-.1-.2 .2 .1 .2 .4 .2v.2h-.5M218 129.7h.3l.2 .1-.5 .7h.5"/>
<path d="M218 128.2l.2-.2v.8M218 124.5a.49 .49 0 0 1 .4 .3 .49 .49 0 0 1-.1 .5h-.3zM218 123.2h.4v-.4h-.4v.9M218 133.1l.5 .9M218 134.8l.5 .9M218 128.8h.5M218.1 126.2h.5M218.1 131.4a.48 .48 0 0 1 .4 .4 .48 .48 0 0 1-.4 .5 .69 .69 0 0 1 0-.9zM218.1 123.2l.4 .5M218.3 126.2v.9M218.5 133.1l-.5 .9M218.5 134.8l-.5 .9"/>
</g>
<path d="M223.6 123.8l.3 .1-.1 .2-.3-.2z" fill="#910000"/>
<path d="M219.6 124h.8M220.4 125.1h2.8v1.1h-2.8zM223.2 124h.5v1.7h-.5M223.6 123.8l.3 .2-.1 .2-.3-.2z" fill="none" stroke="#910000" stroke-width=".21"/>
<path d="M223.6 125.5l.3 .1-.1 .2-.3-.2z" fill="#910000"/>
<path d="M219.6 125.7h.8M220.4 126.9h2.8v1h-2.8zM223.2 125.7h.5v1.8h-.5M223.6 125.5l.3 .2-.1 .2-.3-.2z" fill="none" stroke="#910000" stroke-width=".21"/>
<path d="M223.6 127.2l.3 .2-.1 .2-.3-.2z" fill="#910000"/>
<path d="M219.6 127.5h.8M220.4 128.6h2.8v1h-2.8zM223.2 127.5h.5v1.7h-.5M223.6 127.3l.3 .2-.1 .2-.3-.2z" fill="none" stroke="#910000" stroke-width=".21"/>
<path d="M223.6 128.9l.3 .2-.1 .2-.3-.2z" fill="#910000"/>
<path d="M219.6 129.2h.8M220.4 130.3h2.8v1h-2.8zM223.2 129.2h.5v1.6h-.5M223.6 129l.3 .2-.1 .1-.3-.1z" fill="none" stroke="#910000" stroke-width=".21"/>
<path d="M223.6 130.6l.3 .2-.1 .2-.3-.2z" fill="#910000"/>
<path d="M219.6 130.8h.8M220.4 132.1h2.8v1h-2.8zM223.2 130.8h.5v1.8h-.5M223.6 130.7l.3 .1-.1 .2-.3-.2z" fill="none" stroke="#910000" stroke-width=".21"/>
<path d="M223.6 132.4l.3 .2-.1 .2-.3-.2z" fill="#910000"/>
<path d="M219.6 132.6h.8M220.4 133.8h2.8v1h-2.8zM223.2 132.6h.5v1.7h-.5M223.6 132.4l.3 .2-.1 .2-.3-.2z" fill="none" stroke="#910000" stroke-width=".21"/>
<path d="M223.6 134.1l.3 .2-.1 .2-.3-.2z" fill="#910000"/>
<g fill="none" stroke="#910000" stroke-width=".21">
<path d="M119.7 30.9h2.5M119.7 32.7h2.5M119.7 34.4h2.5M119.7 36.1h2.5M119.7 37.9h2.5M119.7 39.6h2.5M122.2 28.4h29.3v53.4h-29.3zM135.2 25.8h.1M135.2 24.1l-.5 .8M135.2 24.1l.5 .8M135.2 24.1v4.3M138.6 25.8v2.6"/>
<path d="M151.5 31.9h2.6M151.5 33.6h2.6M151.5 35.3h2.6M151.5 37h2.6M151.5 38.7h2.6M119.7 41.3h2.5M119.7 43h2.5M119.7 46.4h2.5M119.7 48.2h2.5M119.7 49.9h2.5M119.7 51.7h2.5M119.7 53.4h2.5"/>
<path d="M119.7 56.9h2.5M119.7 58.5h2.5M151.5 57.7h2.6M151.5 59.4h2.6M151.5 42.2h2.6M151.5 43.9h2.6M151.5 45.6h2.6M151.5 47.4h2.6M151.5 49.1h2.6M151.5 50.8h2.6M151.5 54.2h2.6M151.5 55.9h2.6"/>
<path d="M163.9 51.2h1v2.5h-1zM164.5 54.2v.9h.8l-.8 .8-.9-.8h.9M164.5 54.2h.1M164.5 50.8v.5M164.5 53.7v.5M174.8 57.7h2.5M174.8 59.4h2.5M177.3 56.8h3.5v8.6h-3.5zM177.3 57.6h.9v.2h-.9zM177.3 59.3h.9v.2h-.9zM180 57.6h.8v.2h-.8zM180 59.3h.8v.2h-.8z"/>
<path d="M180.8 57.7h2.6M180.8 59.4h2.6M119.7 62h2.5M119.7 63.7h2.5M119.7 79.2h2.5M151.5 61.1h2.6M151.5 64.6h2.6M151.5 66.2h2.6M151.5 68h2.6M151.5 69.7h2.6M151.5 71.4h2.6M151.5 73.2h2.6"/>
<path d="M163.9 73.7h1v2.3h-1zM164.5 76.7v.8h.8l-.8 .9-.9-.9h.9M164.5 76.7h.1M164.5 73.2v.5M164.5 76.1v.6M165.3 61.1v.9h.9l-.9 .9-.8-.9h.8M165.3 61.1h.1M174.8 61.1h2.5M174.8 62.9h2.5M174.8 64.6h2.5M177.3 61h.9v.2h-.9zM177.3 62.8h.9v.1h-.9z"/>
<path d="M177.3 64.5h.9v.1h-.9zM180 61h.8v.2h-.8zM180 62.8h.8v.1h-.8zM180 64.5h.8v.1h-.8zM180.8 61.1h2.6M180.8 62.9h2.6M180.8 64.6h4.3M183.4 64.6h.1M184.3 64l.8 .6M185.1 64.6l-.8 .5M135.2 84.4v.8h.8l-.8 .9-.9-.9h.9M135.2 84.4h.1"/>
<path d="M135.2 81.8v2.6M138.6 81.8v2.6M220 81.8h4.3v13.7h-4.3zM220.4 82.1h2.8v1h-2.8zM228.2 82.7h.1M228.2 80.9l-.6 .9M228.2 80.9l.5 .9M228.2 80.9v1.8M124.8 107.7h3.4M124.8 109.3h3.4M124.8 111h3.4M124.8 112.8h3.4"/>
<path d="M124.8 114.5h3.4M124.8 116.2h3.4M124.8 118h3.4M124.8 119.7h3.4M128.2 105.8h10.4v20.8h-10.4zM133.5 102.5h.1M133.5 100.7v5.2M133.5 100.7l-.6 .9M133.5 100.7l.5 .9M133.9 115.4h-.9v1.7M134.3 115.4h-.4v1.7h-1.4M138.6 107.7h3.4"/>
<path d="M138.6 109.3h3.4M138.6 111h3.4M138.6 112.8h3.4M138.6 114.5h3.4M138.6 116.2h3.4M138.6 118h3.4M138.6 119.7h3.4M142.8 110.2h3.4l.7 .8-.7 1h-3.4l-.8-1zM142.8 118.8h3.4l.7 .9-.7 .8h-3.4l-.8-.8zM142.8 106.8h2.6l.8 .9-.8 .8h-2.6l-.8-.8zM142.8 108.5h2.6l.8 .8-.8 .9h-2.6l-.8-.9zM142.8 117.1h3.4l.7 .9-.7 .8h-3.4l-.8-.8z"/>
<path d="M142.8 115.4h3.4l.7 .8-.7 .9h-3.4l-.8-.9zM142.8 112h3.4l.7 .8-.7 .9h-3.4l-.8-.9zM142.8 113.7h3.4l.7 .8-.7 .9h-3.4l-.8-.9zM143.3 110.7h.3a.48 .48 0 0 1 .2 .5 .48 .48 0 0 1-.5 .3zM143.3 119.2a.47 .47 0 0 1 .5 .5 .47 .47 0 0 1-.5 .5zM143.3 107.2l.4 .1 .1 .4-.2 .4h-.3zM143.3 108.9a.49 .49 0 0 1 .4 .3 .49 .49 0 0 1-.1 .6h-.3zM143.3 117.6h.4l.1 .5-.2 .3h-.3zM143.3 115.9h.3a.48 .48 0 0 1 .2 .5 .48 .48 0 0 1-.5 .3zM143.3 112.4l.4 .1 .1 .4-.2 .3h-.3zM143.3 114.1a.49 .49 0 0 1 .4 .3 .49 .49 0 0 1-.1 .5h-.3zM144.1 111l.2-.3v.8"/>
<path d="M144.1 119.5l.2-.3v1M144.1 117.8l.2-.2v.8M144.1 116.1l.2-.2v.8M144.1 112.6l.2-.2v.8M144.1 114.3l.2-.2v.8M144.1 111.5h.5M144.1 118.4h.5M144.1 116.7h.5M144.1 113.2h.5M144.1 114.9h.5M144.3 107.6l-.2-.3 .4-.1 .1 .3-.5 .2 .1 .4 .4-.1v-.3l-.2-.1M144.6 109.3l-.2 .2-.3-.1v-.4h.5v.6l-.4 .2"/>
<path d="M144.9 115.9h.5l-.2 .3h.2v.4h-.5M144.9 112.6l.3-.2v.8M144.9 114.2h.5v.3l-.5 .4h.5M144.9 113.2h.5M145 110.8l.3-.1 .1 .2v.5l-.2 .1a.48 .48 0 0 1-.2-.7zM145.2 117.6l-.3 .5h.6M145.3 117.8v.6M145.4 119.2h-.4l-.1 .5h.5v.4h-.5M120.4 122.3h3.7l.7 .8-.7 .9h-3.7zM121.2 123.1h.4l.1-.3-.5-.1v.9M121.5 123.1l.2 .5M122.7 122.7l-.7 1.1"/>
<path d="M122.9 122.7l.2 .9 .2-.6 .2 .6 .2-.9M122.9 122.5h.8M124.8 123.1h3.4M124.8 124.8h2.6M133.5 130v.8h.8l-.8 1-1-1h1M133.5 130h.1M133.5 126.6v3.4M144.1 120.2h.5M152.4 130.8h.5M152.4 132.6h.5M152.8 132.1h2.5v1h-2.5zM152.8 130.3h2.5v1h-2.5z"/>
<path d="M155.3 130.8h.5M155.3 132.6h.5M218.7 134.3h1.7M218.7 136h1.7M218.7 124h.9M218.7 125.7h.9M218.7 127.5h.9M218.7 129.2h.9M218.7 130.8h.9M218.7 132.6h.9M220.4 135.5h2.8v1.1h-2.8zM223.2 134.3h.5v1.7h-.5"/>
<path d="M223.6 134.1l.3 .2-.1 .2-.3-.2zM223.9 124h1.7M152.4 141.2h.5M152.4 143h.5M152.8 140.6h2.5v1.1h-2.5zM152.8 142.4h2.5v1h-2.5zM155.3 141.2h.5M155.3 143h.5"/>
<circle cx="127.8" cy="124.8" r=".47"/>
</g>
<g fill="none" stroke="#b90000" stroke-width=".21">
<path d="M120.7 29.9l.3-.1 .2 .2-.5 .8h.5M120.7 31.6h.5l-.3 .4h.2l.1 .3-.2 .2-.3-.1M120.7 38.5h.5l-.3 .8M120.9 33.3l-.2 .6h.5M121.1 35h-.3l-.1 .4 .3-.1 .2 .5-.2 .1h-.3M121.1 36.8h-.2l-.2 .3 .1 .5h.3v-.5h-.3l-.1 .2M121.1 33.7v.5M134.3 27.3h.6M134.3 26.5h.6M134.7 27.2v.5l-.7-.1M134.7 26.4v.6l-.7-.3M137.5 27.8v-.5l.4 .3v-.3h.4v.5"/>
<path d="M137.5 27v-.5l.4 .2v-.2h.4v.5M152.1 37.6h.5l-.2 .4 .2 .1v.3h-.5M152.4 30.7l-.2 .6h.5M152.4 32.4l-.2 .7h.5M152.4 34.2l-.2 .6h.5M152.4 35.9l-.2 .5h.5M152.5 31v.6M152.5 32.7v.6M152.5 34.5v.5M152.5 36.2v.6M152.9 30.8h.6l-.3 .2 .3 .1v.4h-.6M152.9 32.6h.6v.2l-.6 .5h.6"/>
<path d="M152.9 34.4l.3-.2v.8M152.9 35h.6M153 36l.4-.1 .1 .2v.5l-.2 .2a.48 .48 0 0 1-.3-.8zM153.5 38l-.1 .1h-.4v-.5l.5 .1v.6l-.5 .2M120.3 45.6l.2-.2v.9M120.3 47.4l.2-.3v.9M120.3 49.1l.2-.3v.9M120.3 50.8l.2-.2v.8M120.3 52.5l.2-.2v.8M120.3 55.8h.5v.3l-.5 .5h.5M120.3 57.5h.5v.3l-.5 .5h.5M120.3 46.3h.5"/>
<path d="M120.3 48h.5M120.3 49.7h.5M120.3 51.4h.5M120.3 53.1h.5M120.9 40.6l-.2-.3h.4l.1 .1-.5 .4 .2 .3 .3-.2-.2-.3M121.1 45.5l.2-.1a.43 .43 0 0 1 .3 .4 .43 .43 0 0 1-.3 .5l-.2-.2zM121.2 42.3l-.1 .2h-.3v-.6h.3l.1 .2-.2 .7h-.2M121.2 57.4a.42 .42 0 0 1 .4 .5 .42 .42 0 0 1-.4 .4zM121.3 47l-.2 .7h.5M121.3 52.6l-.2-.2 .4-.1v.3l-.4 .1 .1 .4h.3l.1-.3-.1-.2M121.3 55.7l-.2 .6h.5M121.5 48.8h-.4v.4l.4-.1 .1 .2-.1 .4-.4-.1"/>
<path d="M121.5 50.6l-.4 .2v.5l.4 .1 .1-.4-.1-.2-.4 .2M121.5 47.4v.6M121.5 56v.6M152.1 41.1h.5l-.2 .3 .2 .1v.4h-.5M152.1 42.8h.5l-.2 .3 .2 .1v.4h-.5M152.1 44.5h.5l-.2 .3 .2 .1v.4h-.5M152.1 46.3h.5l-.2 .3 .2 .1v.3h-.5M152.1 49.7h.5l-.2 .3 .2 .1v.4h-.5M152.1 53.1h.5l-.2 .4h.2v.4h-.5M152.1 54.8h.5l-.2 .4h.2v.5h-.5M152.2 56.7l.3-.1 .1 .3-.5 .5h.5M152.2 58.4l.3-.1 .1 .4-.5 .4h.5"/>
<path d="M152.5 48.2l.3-.2v.8M152.5 48.8h.5M152.9 42.8h.6l-.4 .8M152.9 53.4l.3-.3v.9M152.9 54h.6M153 54.9l.3-.1 .2 .2v.6l-.2 .1a.53 .53 0 0 1-.3-.8zM153.1 41.4l-.2-.1 .1-.2 .5 .1-.1 .2-.5 .2 .2 .3h.4v-.4l-.2-.1M153.1 58.7l-.2-.2 .2-.2 .4 .1v.2l-.6 .2 .1 .3h.5v-.4h-.2M153.2 49.7l-.3 .5h.6M153.4 44.5l-.3 .1-.2 .7 .2 .1 .4-.1v-.4l-.4-.1-.2 .2M153.4 50v.6M153.5 46.3h-.5l-.1 .4 .5-.1 .1 .4h-.6"/>
<path d="M153.5 56.9l-.1 .2h-.4v-.5l.5 .1v.6l-.5 .1M153.5 60h-.5l-.1 .4h.6v.4h-.6M175.8 56.9l.3-.3v.8M175.8 58.3h.5l-.2 .3 .2 .2-.1 .3h-.4M175.8 57.4h.5M176.2 60h-.3l-.1 .4 .3-.1 .2 .4-.2 .2-.3-.1M181.8 56.7h.5v.2l-.5 .5h.5M182.1 58.3l-.3 .6h.6M182.2 60l-.2 .1-.2 .6 .2 .2 .3-.1v-.4l-.3-.1-.2 .2M182.2 58.6v.5M120.3 61.2l.2-.3v.9M120.3 62.9l.2-.3v.9"/>
<path d="M120.3 78.2h.5v.2l-.5 .5h.5M120.3 61.8h.5M120.3 63.5h.5M121 62.6h.6l-.3 .3h.2v.6l-.5-.1M121.1 61.2l.3-.3v.9M121.1 78.4l.3-.3v.8M121.1 61.8h.5M121.1 78.9h.5M152.1 70.4h.5l-.2 .3h.2v.5h-.5M152.2 60.1l.3-.1 .1 .4-.5 .5h.5M152.2 63.5h.3l.1 .4-.5 .4h.5M152.2 65.3l.3-.1 .1 .4-.5 .5h.5"/>
<path d="M152.2 67l.3-.1 .1 .4-.5 .5h.5M152.2 68.9l.2-.3v.9M152.2 72.3l.2-.2v.8M152.2 69.5h.4M152.2 72.9h.4M152.9 65.2h.6l-.4 .9M152.9 66.9h.6l-.3 .4h.3v.4h-.6M152.9 70.5h.6v.2l-.6 .5h.6M152.9 72.1h.6l-.4 .8M153.4 63.5h-.3l-.2 .6 .1 .2 .5-.1v-.3l-.2-.1-.4 .2M153.5 69l-.2 .2-.4-.2 .2-.4 .4 .1v.6l-.5 .2M175.8 61.8h.5l-.3 .8"/>
<path d="M176.3 63.9h-.5l.2-.4 .3 .1v.4l-.2 .3h-.2M181.5 63.7l.1-.2v.8M181.5 64.3h.4M182 62.1l-.2-.2 .1-.1h.4l-.1 .3-.4 .2 .1 .3 .4-.1v-.3l-.1-.1M182.3 63.5h.3l.1 .1v.6a.39 .39 0 0 1-.5-.2 .39 .39 0 0 1 .1-.5zM134.9 83.5h-.8l.2 .3M134.9 82.4v.5l-.6-.5-.2 .1 .1 .4M134.9 83.3v.5M138.4 83.3v.5l-.5-.5-.4 .1 .1 .4M138.4 82.4v.5l-.6-.5-.3 .1 .1 .4M126.3 106.6h.5v.3l-.5 .5h.5M126.3 108.2h.5l-.3 .4 .3 .1v.3h-.5"/>
<path d="M126.3 115.2h.6l-.5 .8M126.4 117.2l-.1-.2 .1-.1 .4 .1-.1 .2-.4 .2 .1 .3h.3l.1-.4-.2-.1M126.5 109.9l-.2 .6h.6M126.7 113.4l-.3 .1-.1 .6 .1 .2 .4-.1v-.4l-.4-.1-.1 .2M126.7 110.3v.6M126.8 111.7h-.4l-.1 .4h.4l.1 .4h-.5M126.8 119l-.2 .2-.3-.2 .1-.4 .4 .1v.5l-.4 .2M132.4 103.7a.48 .48 0 0 1 .4-.2 .48 .48 0 0 1 .4 .3l-.1 .2h-.6l-.1-.1zM133.2 104.3v.6l-.5-.6-.3 .1 .1 .5M139.7 106.8l.2-.3v.9M139.7 108.5l.2-.3v.9M139.7 110.2l.2-.2v.9"/>
<path d="M139.7 112l.2-.3v.9M139.7 113.7l.2-.3v.9M139.7 115.4l.2-.2v.8M139.7 117.1l.2-.2v.8M139.7 118.8l.2-.2v.8M139.7 107.4h.5M139.7 109.1h.5M139.7 110.9h.5M139.7 112.6h.5M139.7 114.3h.5M139.7 116h.5M139.7 117.7h.5"/>
<path d="M139.7 119.4h.5M140.4 108.2h.6l-.3 .9M140.4 115.2h.6l-.3 .2 .3 .2v.3l-.2 .1-.4-.1M140.5 117l.4-.1 .1 .2-.6 .6h.6M140.5 118.8l.3-.2v.8M140.5 119.4h.5M140.7 106.9l-.2-.3 .4-.1v.4l-.4 .1v.3l.4 .1 .1-.3-.2-.2M140.7 113.4l-.2 .6h.5M140.9 110h-.3l-.1 .2v.6l.3 .1 .2-.5-.2-.1-.3 .1M140.9 111.7h-.4v.4h.4v.5l-.4-.1M140.9 113.7v.6M125.9 124l.2-.3v.9"/>
<path d="M125.9 124.6h.5M126.3 122.3l.2-.3v.9M126.3 122.9h.5M127.2 124.2l-.2 .1-.3-.1 .2-.5 .3 .2v.3l-.2 .4h-.2M132.4 127.8a.48 .48 0 0 1 .4-.2 .48 .48 0 0 1 .4 .4 .5 .5 0 0 1-.8-.2zM133.2 128.7h-.8l.2 .3M133.2 128.5v.5M218.8 124.6h.6l-.3 .3 .3 .2v.2l-.2 .2-.4-.1M218.8 131.5h.6l-.3 .9M218.9 123l.3-.1 .2 .2-.6 .6h.6M219.1 126.3l-.2 .7h.5M219.1 133.6h-.2v-.3l.3-.1 .2 .3-.5 .2 .1 .4h.3l.1-.4-.2-.1"/>
<path d="M219.3 128.1h-.4v.4l.3-.1 .2 .2-.1 .3-.4-.1M219.3 129.7l-.3 .1-.1 .8 .3 .1 .2-.2-.2-.4-.3 .2M219.3 126.6v.6M219.4 135.3l-.2 .2-.3-.1v-.4l.5 .1-.2 .7h-.2M224.5 123.1l.2-.2v.8M224.5 123.7h.5"/>
</g>
<g fill="none" stroke="#0f0f0f" stroke-width=".21">
<path d="M154.2 32.1h6.2M154.2 30.3h5.7M154.2 33.8h7M154.2 35.5h6.8M154.4 32.4v.7l.2 .1 .3-.1v-.7M154.4 30.6l.1 .9h.3l.1-.2v-.7M154.4 34.1l.1 .8h.3l.1-.1v-.7M154.4 37.5v.8l.2 .1 .3-.2v-.7M154.4 35.8l.1 .8 .4-.1v-.7M155.1 33.2l.3-.8 .3 .8M155.1 31.5l.3-.9 .3 .9M155.1 34.9l.3-.8 .3 .8"/>
<path d="M155.1 38.4l.3-.9 .3 .9M155.1 36.6l.3-.8 .3 .8M155.2 33h.5M155.2 31.3h.5M155.2 34.7h.5M155.2 38.1h.5M155.2 36.4h.5M156 32.8l.5-.1v-.2l-.5-.1v.8M156 31.1l.5-.1v-.3l-.5-.1v.9M156 34.5h.4l.1-.3-.5-.1v.8M156 38l.5-.1v-.3l-.5-.1v.9M156 36.3l.5-.1v-.3l-.5-.1v.8"/>
<path d="M156.2 32.8l.3 .4M156.2 31.1l.3 .4M156.2 34.5l.3 .4M156.2 38l.3 .4M156.2 36.3l.3 .3M156.8 32.4h.5M156.8 30.6h.5M156.8 34.1h.5M156.8 37.5h.5M156.8 35.8h.5M157 30.6v.9M157 32.4v.8"/>
<path d="M157 34.1v.8M157 35.8v.8M157 37.5v.9M157.4 33.2l.3-.8 .3 .8M157.4 31.5l.3-.9 .3 .9M157.4 34.9l.3-.8 .3 .8M157.4 38.4l.3-.9 .3 .9M157.4 36.6l.3-.8 .3 .8M157.5 33h.4M157.5 31.3h.4M157.5 34.7h.4M157.5 38.1h.4"/>
<path d="M157.5 36.4h.4M158 33.3h.7M158 31.5h.7M158 35h.7M158 38.5h.7M158 36.7h.7M159 31.1l.4-.1-.1-.4h-.3v.9M159 34.1h.3l.1 .1-.1 .7h-.3zM159 38l.4-.1-.1-.4h-.3v.9M159.1 31.1l.3 .4M159.1 38l.3 .4M159.4 32.5l-.4-.1a.43 .43 0 0 0-.1 .5 .43 .43 0 0 0 .5 .2"/>
<path d="M159.4 35.9a.43 .43 0 0 0-.5 .2 .43 .43 0 0 0 .1 .5l.4-.1M159.6 35.8h.5M159.7 37.5l.6 .9M159.8 32.4h.3a.48 .48 0 0 1 .2 .5 .48 .48 0 0 1-.5 .3zM159.8 30.6v.9M159.9 35.8v.8M160.2 34.1h-.4l-.1 .1 .2 .3 .3 .1v.2l-.5 .1M160.3 37.5l-.6 .9M160.7 34.5h.3l.1-.3-.4-.1v.8M160.7 37.5l.4 .2v.4l-.3 .3h-.1zM160.8 34.5l.3 .4M160.9 35.9l-.3-.1-.2 .1 .1 .3 .4 .2-.1 .2h-.4"/>
<path d="M154.2 54.5h6.3M154.2 58h6.9M154.2 56.3h7.1M154.2 52.8h5.9M154.2 42.5h6.8M154.2 44.2h6.8M154.4 54.7l.1 .9h.3l.1-.2v-.7M154.4 58.2v.8l.2 .1 .3-.2v-.7M154.4 56.4v.9l.2 .1 .3-.2v-.8M154.4 53v.8l.2 .1 .3-.2v-.7M154.4 59.9l.1 .8h.3l.1-.1v-.7M154.4 42.7v.8l.2 .1 .3-.2v-.7"/>
<path d="M154.4 40.9v.9l.5-.1v-.8M154.4 44.4l.1 .9h.3l.1-.2v-.7M155.1 55.6l.3-.9 .3 .9M155.1 59.1l.3-.9 .3 .9M155.1 57.4l.3-1 .3 1M155.1 53.9l.3-.9 .3 .9M155.1 43.6l.3-.9 .3 .9M155.1 41.8l.3-.9 .3 .9M155.1 45.3l.3-.9 .3 .9M155.2 55.3h.5M155.2 58.8h.5M155.2 57.1h.5"/>
<path d="M155.2 53.6h.5M155.2 43.3h.5M155.2 41.6h.5M155.2 45h.5M156 55.2h.4l.1-.4-.5-.1v.9M156 58.6h.4l.1-.3-.5-.1v.9M156 56.9h.5v-.4l-.5-.1v1M156 53.5h.4l.1-.4-.5-.1v.9M156 43.1h.4l.1-.3-.5-.1v.9M156 41.4h.5v-.4l-.5-.1v.9M156 44.8h.4l.1-.3-.5-.1v.9M156.2 55.2l.3 .4"/>
<path d="M156.2 58.6l.3 .5M156.2 56.9l.3 .5M156.2 53.5l.3 .4M156.2 43.1l.3 .5M156.2 41.4l.3 .4M156.2 44.8l.3 .5M156.8 54.7h.5M156.8 58.2h.5M156.8 56.4h.5M156.8 53h.5M156.8 59.9h.5M156.8 42.7h.5"/>
<path d="M156.8 40.9h.5M156.8 44.4h.5M157 40.9v.9M157 42.7v.9M157 44.4v.9M157 53v.9M157 54.7v.9M157 56.4v1M157 58.2v.9M157 59.9v.8M157.4 43.6l.3-.9 .3 .9M157.4 41.8l.3-.9 .3 .9"/>
<path d="M157.4 45.3l.3-.9 .3 .9M157.5 55.2h.4l.1-.2-.1-.3h-.4v.9h.4l.1-.4h-.1M157.5 58.6h.4l.1-.1-.1-.3h-.4v.9l.5-.1v-.3l-.1-.1M157.5 56.9h.4l.1-.3-.1-.2h-.4v1l.5-.1v-.4h-.1M157.5 53.5h.4l.1-.2-.1-.3h-.4v.9l.5-.1v-.3h-.1M157.5 43.3h.4M157.5 41.6h.4M157.5 45h.4M158 43.6h.7M158 41.9h.7M158 45.3h.7M158.2 55.7h.7"/>
<path d="M158.2 59.1h.7M158.2 57.4h.7M158.2 54h.7M158.8 40.9h.5M159 42.7h.3l.1 .2v.4l-.3 .3h-.1zM159 44.8l.4-.1-.1-.3h-.3v.9M159 56.4a.47 .47 0 0 1 .6 .5 .47 .47 0 0 1-.6 .5zM159 53.5h.5v-.5h-.5v.9M159 40.9v.9M159.1 44.8l.3 .5M159.3 53.5l.3 .4M159.5 40.9l.6 .9"/>
<path d="M159.6 54.8l-.3-.1-.3 .3v.4l.2 .2 .4-.1M159.6 58.3l-.4-.1-.2 .2v.5l.3 .2 .3-.1M159.6 42.7h.5M159.6 44.4h.5M159.8 58.2h.5M159.8 59.9l.6 .8M159.9 54.7h.2l.3 .3v.4l-.2 .2h-.3zM159.9 42.7v.9M159.9 44.4v.9M159.9 53v.9M160.1 58.2v.9M160.1 40.9l-.6 .9"/>
<path d="M160.4 56.5h-.5v.3l.5 .3-.2 .3-.3-.1M160.4 40.9a.48 .48 0 0 1 .5 .3 .48 .48 0 0 1-.2 .6h-.3zM160.4 59.9l-.6 .8M160.5 43.1h.3l.1-.3-.4-.1v.9M160.7 43.1l.2 .5M160.7 56.9h.4l.1-.1-.1-.4h-.4v1M160.7 59.9a.49 .49 0 0 1 .5 .3 .49 .49 0 0 1-.1 .5h-.4zM160.9 44.4h-.4l-.1 .2 .5 .4-.1 .3h-.4M160.9 56.9l.3 .5M161 58.2l-.4 .1 .1 .3 .3 .1v.3h-.4M164.7 49.6l.1 .8h.3l.1-.2v-.6M165.5 50.4l.3-.8 .3 .8"/>
<path d="M165.6 50.2h.4M166.3 50h.4l.1-.3-.5-.1v.8M166.6 50l.2 .4M167.1 49.6h.5M167.3 49.6v.8M167.8 50.4l.2-.8 .4 .8M167.8 50.2h.5M167.9 58.2v.8l.2 .1 .3-.1v-.8M168.4 56.3h6.2M168.4 50.5h.6M168.5 56.4v.9l.2 .1 .3-.2v-.8M168.7 59.1l.2-.9 .4 .9"/>
<path d="M168.8 58.8h.4M169.3 57.4l.2-1 .4 1M169.3 49.6v.8M169.4 57.1h.4M169.5 58.6h.5v-.4h-.5v.9M169.7 58.6l.3 .5M170.1 56.9h.5v-.4l-.5-.1v1M170.1 49.6v.8l-.4-.8v.8M170.3 58.2h.4M170.4 56.9l.2 .5M170.5 49.6h.5M170.6 58.2v.9"/>
<path d="M170.7 49.6v.8M170.9 56.4h.5M171.1 58.6l.4-.1-.1-.3h-.3v.9h.3l.2-.3-.3-.2M171.2 56.4v1M171.7 56.9h.4l-.1-.5h-.3v1h.3l.2-.2-.2-.3M171.7 59.1h.6M172.3 57.4h.7M172.4 58.2h.5M172.7 58.2v.9M173.2 58.2l.5 .9M173.7 56.5l-.3-.1-.2 .3v.4l.2 .3 .3-.1M173.7 58.2l-.5 .9"/>
<path d="M174 58.2h.4l.1 .2v.5l-.2 .2h-.3zM174 56.4h.3l.2 .3v.4l-.2 .3h-.3zM154.2 66.6h6.9M154.2 64.8h7M154.4 63.4l.1 .8h.3l.1-.2v-.6M154.4 66.8v.8l.2 .1 .3-.2v-.7M154.4 65.1l.1 .8h.3l.1-.2v-.6M155.1 64.2l.3-.8 .3 .8M155.1 60.7l.3-.8 .3 .8M155.1 67.7l.3-.9 .3 .9M155.1 65.9l.3-.8 .3 .8M155.2 64h.5"/>
<path d="M155.2 60.5h.5M155.2 67.4h.5M155.2 65.7h.5M156 63.8h.4l.1-.3-.5-.1v.8M156 60.3h.4l.1-.3-.5-.1v.8M156 67.3l.5-.1v-.4h-.5v.9M156 65.5h.5v-.4h-.5v.8M156.2 63.8l.3 .4M156.2 60.3l.3 .4M156.2 67.3l.3 .4M156.2 65.5l.3 .4M156.8 63.4h.5"/>
<path d="M156.8 66.8h.5M156.8 65.1h.5M157 63.4v.8M157 65.1v.8M157 66.8v.9M157.5 63.8h.4l.1-.2-.1-.2h-.4v.8h.4l.1-.3-.1-.1M157.5 60.3h.4l.1-.1-.1-.3h-.4v.8h.4l.1-.3-.1-.1M157.5 67.2h.4l.1-.3-.5-.1v.9l.5-.1v-.3l-.1-.1M157.5 65.5h.4l.1-.3-.1-.1h-.4v.8h.4l.1-.3-.1-.1M158.2 64.3h.7M158.2 60.8h.7M158.2 67.8h.7"/>
<path d="M158.2 66h.7M159 63.4h.4M159 60.3h.5l.1-.2-.2-.2h-.4v.8M159 67.3h.4l.2-.4-.6-.1v.9M159 65.1a.48 .48 0 0 1 .5 .3 .48 .48 0 0 1-.1 .5h-.4zM159.2 63.4v.8M159.3 60.3l.3 .4M159.3 67.3l.3 .4M159.6 63.4l.6 .8M159.8 66.8h.5M159.8 65.1h.5M160.1 65.1v.8"/>
<path d="M160.1 66.8v.9M160.2 63.4l-.6 .8M160.6 63.4l.4 .1v.5l-.2 .2h-.2zM160.6 65.5h.4l.1-.3-.2-.1h-.3v.8M160.7 65.5l.4 .4M161 66.8h-.4v.3l.4 .2v.3h-.4M164.7 72v.8l.2 .1 .3-.2v-.7M165.5 72.9l.3-.9 .3 .9M165.6 72.6h.4M166.3 72.4l.5-.1v-.2l-.5-.1v.9M166.6 72.4l.2 .5M167.1 72h.5"/>
<path d="M167.3 72v.9M167.8 61.4h6.8M167.8 72.3h.5l.1-.2-.6-.1v.9l.6-.1v-.4l-.2-.1M167.9 61.6v.8l.2 .1 .3-.1v-.8M168.5 72.9h.7M168.7 62.5l.2-.9 .4 .9M168.8 62.3h.4M168.9 63.1h5.7M168.9 63.4l.1 .8 .5-.1v-.7M169.4 72v.9M169.5 62.1h.4l.1-.2-.1-.3h-.4v.9M169.7 64.2l.3-.8 .3 .8"/>
<path d="M169.7 62.1l.3 .4M169.8 64h.4M170.3 72v.9l-.5-.9v.9M170.3 61.6h.4M170.6 61.6v.9M170.6 72h.5M170.6 63.8h.4l.1-.3-.5-.1v.8M170.8 63.8l.3 .4M170.8 72v.9M171.1 62h.3l.1-.3-.4-.1v.9h.3l.2-.3-.3-.2M171.3 63.4h.5M171.6 63.4v.8"/>
<path d="M171.7 62.6h.6M172.1 63.8h.3l.2-.2-.1-.2h-.4v.8h.4l.1-.3-.2-.1M172.6 62.1h.3l.2-.2-.2-.3h-.3v.9M172.8 64.3h.6M172.8 62.1l.3 .4M173.4 61.6h.4M173.5 61.6v.9M173.6 63.8h.4l.1-.3-.5-.1v.8M173.9 63.8l.2 .4M174.5 61.7l-.3-.1-.2 .2 .1 .2 .4 .2v.2h-.5M174.5 63.4v.8M183.5 61.4h6.9"/>
<path d="M183.7 61.6v.8l.2 .1 .3-.1v-.8M184.4 62.5l.3-.9 .3 .9M184.5 62.3h.5M185.3 62.1h.3l.2-.2-.2-.3h-.3v.9M185.5 62.1l.3 .4M186.1 61.6h.5M186.3 61.6v.9M186.8 62h.4v-.3l-.4-.1v.9h.4l.1-.3-.2-.2M187.5 62.6h.7M188.8 61.7a.42 .42 0 0 0-.5 .4 .42 .42 0 0 0 .5 .3M189.1 61.6h.5M189.4 61.6v.9"/>
<path d="M190.3 61.7l-.4-.1-.1 .2 .1 .2 .4 .2v.2h-.5M186.1 84.9l.2-.9 .3 .9M186.1 83.8h4.9M186.1 84.6h.5M186.6 95.2l.4-.8 .2 .8M186.6 86.6l.4-.9 .2 .9M186.6 88.3l.4-.8 .2 .8M186.7 95h.5M186.7 84h.5M186.7 86.4h.5M186.7 88.1h.5M187 84v.9"/>
<path d="M187.4 84.9l.3-.9 .3 .9M187.4 94.4h.5M187.4 85.7h.5M187.4 87.5h.5M187.5 84.6h.4M187.7 85.7v.9M187.7 87.5v.8M187.7 94.4v.8M188.1 95.2l.2-.8 .4 .8M188.1 86.6l.2-.9 .4 .9M188.1 88.3l.2-.8 .4 .8M188.1 85h.7"/>
<path d="M188.2 95h.4M188.2 86.4h.4M188.2 88.1h.4M188.8 95.3h.6M188.8 86.7h.6M188.8 88.4h.6M188.9 84.5h.5v-.5h-.5v.9M189.2 84.5l.2 .4M189.6 94.4a.47 .47 0 0 1 .5 .3 .47 .47 0 0 1-.2 .5h-.3zM189.6 85.7a.49 .49 0 0 1 .5 .3 .49 .49 0 0 1-.2 .6h-.3zM189.6 87.5h.3a.48 .48 0 0 1 .2 .5 .48 .48 0 0 1-.5 .3zM190.3 84l-.5 .1v.3l.5 .2-.1 .3h-.4"/>
<path d="M190.4 85.7h.6l-.5 .9M190.5 94.4h.4v.3l-.5 .5h.5M190.5 84h.5M190.7 84v.9M190.8 87.5h-.3v.2v.6h.4v-.5l-.4 .1M214.2 94.4l.3-.9 .3 .9M214.2 84l.3-.8 .3 .8M214.2 85.7l.3-.8 .3 .8M214.2 82.3l.3-.9 .3 .9M214.2 89.2l.3-.9 .3 .9M214.2 87.5l.3-.9 .3 .9M214.3 94.1h.5"/>
<path d="M214.3 83.8h.5M214.3 85.5h.5M214.3 82.1h.5M214.3 88.9h.5M214.3 87.2h.5M215 93.5h.5M215 83.2h.5M215 84.9h.5M215 81.4h.5M215 88.3h.5M215 86.6h.5M215.3 81.4v.9"/>
<path d="M215.3 83.2v.8M215.3 84.9v.8M215.3 86.6v.9M215.3 88.3v.9M215.3 93.5v.9M215.6 94.4l.3-.9 .3 .9M215.6 84l.3-.8 .3 .8M215.6 85.7l.3-.8 .3 .8M215.6 82.3l.3-.9 .3 .9M215.6 89.2l.3-.9 .3 .9M215.6 87.5l.3-.9 .3 .9M215.7 94.1h.4"/>
<path d="M215.7 83.8h.4M215.7 85.5h.4M215.7 82.1h.4M215.7 88.9h.4M215.7 87.2h.4M216.3 94.4h.7M216.3 84.1h.7M216.3 85.8h.7M216.3 82.4h.7M216.3 89.3h.7M216.3 87.6h.7M217.1 93.5h.4l.1 .2v.5l-.1 .2h-.4z"/>
<path d="M217.1 83.2h.4l.1 .2v.5l-.2 .1h-.3zM217.1 84.9h.3l.2 .2v.5l-.1 .1h-.4zM217.1 81.4h.3l.2 .3v.4l-.2 .2h-.3zM217.1 88.3h.4l.1 .2v.5l-.1 .2h-.4zM217.1 86.6h.3l.2 .2v.4l-.2 .3h-.3zM218 81.4h.5l-.4 .9M218 88.3h.5l-.4 .4h.3v.5l-.4-.1M218.1 93.5a.43 .43 0 0 1 .4 .4 .43 .43 0 0 1-.4 .5l-.1-.4zM218.1 86.6l-.1 .6h.5M218.4 83.2h-.3l-.1 .7 .1 .1 .4-.1-.1-.4h-.3l-.1 .2M218.4 84.9h-.3l-.1 .4 .4-.1v.5l-.4-.1M218.4 86.9v.6"/>
<path d="M120.4 117.6l.3-.8 .2 .8M120.4 115.9l.3-.9 .2 .9M120.4 119.3l.3-.8 .2 .8M120.4 114.2l.3-.9 .2 .9M120.4 110.7l.3-.8 .2 .8M120.4 109l.3-.8 .2 .8M120.4 112.5l.3-1 .2 1M120.4 107.3l.3-.9 .2 .9M120.4 117.4h.5M120.4 115.6h.5M120.4 119.1h.5M120.4 113.9h.5"/>
<path d="M120.4 110.4h.5M120.4 108.8h.5M120.4 112.2h.5M120.4 107.1h.5M121.1 108.2h.5M121.1 106.4h.5M121.1 116.8h.5M121.1 115h.5M121.1 118.5h.5M121.1 113.3h.5M121.1 109.9h.5M121.1 111.5h.5"/>
<path d="M121.4 106.4v.9M121.4 108.2v.8M121.4 109.9v.8M121.4 111.5v1M121.4 113.3v.9M121.4 115v.9M121.4 116.8v.8M121.4 118.5v.8M121.8 117.6l.2-.8 .3 .8M121.8 115.9l.2-.9 .3 .9M121.8 119.3l.2-.8 .3 .8M121.8 114.2l.2-.9 .3 .9"/>
<path d="M121.8 110.7l.2-.8 .3 .8M121.8 109l.2-.8 .3 .8M121.8 112.5l.2-1 .3 1M121.8 107.3l.2-.9 .3 .9M121.9 117.4h.3M121.9 115.6h.3M121.9 119.1h.3M121.9 113.9h.3M121.9 110.4h.3M121.9 108.8h.3M121.9 112.2h.3M121.9 107.1h.3"/>
<path d="M122.4 117.7h.7M122.4 115.9h.7M122.4 119.4h.7M122.4 114.3h.7M122.4 110.8h.7M122.4 109.1h.7M122.4 112.6h.7M122.4 107.4h.7M123.3 116.8l.4 .2v.4l-.2 .2h-.2zM123.3 115l.4 .3v.4l-.1 .2h-.3zM123.3 118.5l.4 .2v.5l-.1 .1h-.3zM123.3 113.3l.4 .2v.5l-.1 .2h-.3z"/>
<path d="M123.3 109.9l.4 .2v.4l-.1 .2h-.3zM123.3 108.2l.4 .1v.5l-.2 .2h-.2zM123.3 111.5l.4 .3v.4l-.2 .3h-.2zM123.3 106.4l.4 .2v.5l-.2 .2h-.2zM124.1 118.5h.6l-.5 .8M124.1 109.9h.5v.4l-.5 .4h.5M124.1 108.4l.2-.2v.8M124.1 111.5h.5l-.3 .4 .3 .1v.4h-.5M124.1 109h.5M124.2 106.5l.2-.1 .2 .1v.6l-.2 .2a.53 .53 0 0 1-.2-.8zM124.3 113.2l-.2 .7h.6M124.5 116.8h-.3l-.1 .7 .1 .1h.4v-.5l-.4-.1-.1 .2"/>
<path d="M124.5 113.6v.6M124.6 115h-.4l-.1 .4h.5v.4h-.5M213.4 108.2l.3-.9 .3 .9M213.4 106.4l.3-.9 .3 .9M213.5 107.9h.4M213.5 106.2h.4M214.2 107.3h.5M214.2 105.5h.5M214.2 104.7l.3-.9 .3 .9M214.2 103l.3-.9 .3 .9M214.3 104.4h.5M214.3 102.7h.5"/>
<path d="M214.4 105.5v.9M214.4 107.3v.9M214.8 108.2l.3-.9 .3 .9M214.8 106.4l.3-.9 .3 .9M214.9 107.9h.4M214.9 106.2h.4M215 103.8h.5M215 102.1h.5M215.3 102.1v.9M215.3 103.8v.9M215.5 108.2h.6M215.5 106.5h.6"/>
<path d="M215.6 104.7l.3-.9 .3 .9M215.6 103l.3-.9 .3 .9M215.7 104.4h.4M215.7 102.7h.4M216.3 104.8h.7M216.3 103.1h.7M216.4 107.3l.4 .1v.6l-.3 .2h-.1zM216.4 105.5l.4 .2-.1 .7h-.3zM217.1 107.6l.3-.3v.9M217.1 105.8l.3-.3v.9M217.1 103.8h.4l.1 .2v.5l-.1 .2h-.4zM217.1 102.1h.4l.1 .2v.4l-.2 .3h-.3z"/>
<path d="M217.1 108.2h.5M217.1 106.4h.5M218 107.6l.2-.3v.9M218 108.2h.5M218.1 105.5a.43 .43 0 0 1 .4 .5 .43 .43 0 0 1-.4 .4l-.1-.3zM218.1 102.5l-.1-.2 .1-.2h.3l.1 .2-.5 .4 .1 .3 .4-.2-.2-.3M218.5 104.2l-.1 .1h-.3v-.5h.3l.1 .2-.2 .7h-.2M119.3 125.3l.3-.8 .2 .8M119.3 124.2h4.5M119.4 125.1h.4M120 124.5h.5M120.3 124.5v.8"/>
<path d="M120.7 125.3l.2-.8 .4 .8M120.8 125.1h.4M121.5 124.9h.4l.1-.1-.1-.3h-.4v.8h.5v-.3l-.1-.1M122.4 124.9h.3M122.8 124.5h-.4v.8h.4M123.7 124.5v.8l-.5-.8v.8M142.1 133.1l.3-.8 .3 .8M142.1 130.5l.3-.8 .3 .8M142.1 132h6.7M142.1 129.4h6.7M142.2 132.9h.4M142.2 130.3h.4"/>
<path d="M142.9 132.3h.4M142.9 129.7h.4M143.1 139.7h5.7M143.1 129.7v.8M143.1 132.3v.8M143.5 133.1l.3-.8 .3 .8M143.5 130.5l.3-.8 .3 .8M143.5 132.9h.5M143.5 130.3h.5M143.9 140h.5M144.1 140v.8M144.1 133.2h.7"/>
<path d="M144.1 130.6h.7M145.5 132.4l-.3-.1-.2 .2v.4l.2 .2h.3M145.5 129.7h-.3l-.2 .2v.4l.2 .2 .3-.1M146 140v.8M146.3 132.3l-.5 .1v.2l.5 .1v.3l-.1 .1h-.4M146.3 129.7h-.5v.3l.5 .3v.2h-.5M146.6 140a.47 .47 0 0 1 .4 .3 .47 .47 0 0 1-.1 .5h-.5v-.6zM146.6 132.3h.5l-.2 .3h.2v.5h-.5M146.7 129.9l.2-.2v.8M146.7 130.5h.4M147.5 132.6h.3M147.5 130.1h.3"/>
<path d="M148 132.3h-.5v.8M148 129.7h-.5v.8M148.2 140a.49 .49 0 0 1 .5 .3 .49 .49 0 0 1-.2 .5h-.3zM148.2 132.3l.5 .8M148.2 129.7l.5 .8M148.7 132.3l-.5 .8M148.7 129.7l-.5 .8M156.8 139.1l.2-.8 .3 .8M156.8 138h4.9M156.8 138.9h.5M157.5 135.7l.3-.9 .3 .9M157.5 137.5l.3-1 .3 1"/>
<path d="M157.5 134l.3-.9 .3 .9M157.5 138.3h.4M157.6 135.4h.4M157.6 137.2h.4M157.6 133.7h.4M157.7 138.3v.8M158.1 139.1l.4-.8 .2 .8M158.2 138.9h.4M158.3 134.8h.5M158.3 136.5h.5M158.3 133.1h.5M158.5 133.1v.9"/>
<path d="M158.5 134.8v.9M158.5 136.5v1M158.8 139.2h.7M158.9 135.7l.3-.9 .3 .9M158.9 137.5l.3-1 .3 1M158.9 134l.3-.9 .3 .9M159 135.4h.4M159 137.2h.4M159 133.7h.4M159.6 135.8h.6M159.6 137.5h.6M159.6 134.1h.6"/>
<path d="M159.6 138.7h.5v-.3l-.5-.1v.8M159.9 138.7l.2 .4M160.3 135.7l.3-.9 .3 .9M160.3 137.5l.3-1 .3 1M160.3 134l.3-.9 .3 .9M160.4 135.4h.4M160.4 137.2h.4M160.4 133.7h.4M161 138.3l-.5 .1v.2l.5 .3-.1 .2h-.4M161.2 135.1l.2-.3v.9M161.2 136.6l.3-.1 .1 .4-.5 .6h.5M161.2 135.7h.4"/>
<path d="M161.2 133.1h.3l.1 .2v.5l-.2 .2-.2-.2zM161.2 138.3h.5M161.5 138.3v.8M143 143.5l.3-.9 .2 .9M143 142.4h5.8M143.1 140.8l.3-.8 .3 .8M143.1 143.2h.4M143.2 140.6h.4M143.7 142.6h.5M144 142.6v.9M144.4 143.5l.2-.9 .4 .9M144.5 140.8l.3-.8 .3 .8"/>
<path d="M144.5 143.2h.4M144.6 140.6h.4M145.1 143.5h.7M145.2 140.9h.6M145.9 142.6v.9M146.3 142.7h.6v.6l-.2 .2a.47 .47 0 0 1-.4-.3 .47 .47 0 0 1 0-.5zM147.1 142.6l.3 .9 .1-.6 .2 .6 .2-.9M147.4 140.5h.3l.2-.3-.2-.2h-.3v.8M147.5 140.5l.4 .3M148.2 143h.4v-.4h-.4v.9M148.4 143l.3 .5"/>
</g>
<g fill="none" stroke="#006665" stroke-width=".21">
<path d="M123 30.5l.4 .1 .1 .4-.2 .4h-.3zM123 32.2a.49 .49 0 0 1 .4 .3 .49 .49 0 0 1-.1 .6h-.3zM123 34h.3a.48 .48 0 0 1 .2 .5 .48 .48 0 0 1-.5 .3zM123 35.7l.4 .1 .1 .4-.2 .3h-.3zM123 37.4a.49 .49 0 0 1 .4 .3 .49 .49 0 0 1-.1 .5h-.3zM123 39.2h.3a.48 .48 0 0 1 .2 .5 .48 .48 0 0 1-.5 .3zM123.7 32.5l.3-.3v.9M123.7 34h.5v.3l-.5 .5h.5M123.7 35.7h.5l-.2 .3 .2 .1v.3h-.5M123.7 33.1h.5M123.9 30.5h.3v.2v.6a.39 .39 0 0 1-.5-.2 .39 .39 0 0 1 .1-.5zM124 37.4l-.3 .6h.6"/>
<path d="M124.2 37.7v.5M124.2 39.2h-.4l-.1 .3h.5v.4h-.5M134.7 30.7l.8 .3-.8 .3M134.7 29.9v.3l.2 .2h.4l.2-.1v-.4M134.7 29.1v.2l.2 .3h.4l.2-.2v-.3M138.1 30.7l.9 .3-.9 .3M138.2 29.9l-.1 .4 .2 .1h.5l.2-.1-.1-.4M138.2 29.1l-.1 .3 .2 .2h.5l.2-.2-.1-.3M147.8 34.6h3.1M148 34.8h.3a.47 .47 0 0 1 .1 .6 .47 .47 0 0 1-.4 .3zM148 36.3h2.9M148.6 36.6l-.2-.1-.3 .2v.5l.2 .2 .3-.1"/>
<path d="M148.6 32.9h2.3M148.8 38.7h.3l.2-.3-.2-.2h-.3v1M148.9 36.5h.5M149 38.7l.3 .5M149.1 31.1h1.8M149.1 36.5v.9M149.2 31.8h.4v-.4h-.4v.8M149.2 33.1h-.2l-.3 .2v.4l.3 .3 .2-.1M149.2 34.8h-.4l-.1 .2 .2 .3h.3v.3h-.5M149.4 31.8l.3 .4M149.6 38.2l.6 1M149.6 33.1l.5 .2v.4l-.3 .3h-.2z"/>
<path d="M149.6 35.3l.5-.1-.1-.4h-.4v.9M149.8 35.3l.3 .4M150.1 36.6h-.5v.3l.5 .1-.1 .4h-.4M150.1 31.4v.8M150.2 38.2l-.6 1M150.3 32.2l.4-.8 .2 .8M150.3 34l.4-.9 .2 .9M150.3 35.7l.4-.9 .2 .9M150.3 37.4l.4-.9 .2 .9M150.3 39.2l.4-1 .2 1M150.4 32h.4M150.4 33.7h.4"/>
<path d="M150.4 35.4h.4M150.4 37.1h.4M150.4 38.9h.4M122.8 46.9l.3-.9 .3 .9M122.8 48.6l.3-.9 .3 .9M122.8 50.3l.3-.8 .3 .8M122.8 52.6h1.5M122.8 56.1h2M122.8 57.9h2.1M122.9 46.6h.4M122.9 48.4h.4M122.9 50.1h.4"/>
<path d="M123 40.8l.4 .1 .1 .5-.2 .3h-.3zM123 42.5a.49 .49 0 0 1 .4 .4 .49 .49 0 0 1-.1 .5h-.3zM123 56.3v.9M123 58v1M123.4 56.4l.3-.1 .2 .3-.2 .6h-.2l-.2-.3zM123.5 51.3l-.4-.1-.2 .3 .2 .5 .4-.1M123.5 53a.44 .44 0 0 0-.6 .1 .44 .44 0 0 0 .2 .6h.4M123.6 58h.1a.5 .5 0 0 1 .2 .5 .5 .5 0 0 1-.3 .5 .54 .54 0 0 1 0-1zM123.7 48l.2-.3v.9M123.7 49.6l.4-.1 .1 .2-.5 .6h.5M123.7 48.6h.5M123.7 42.5h.6l-.4 .9"/>
<path d="M123.7 46a.42 .42 0 0 1 .5 .4 .42 .42 0 0 1-.5 .5zM123.8 51.2v.8M123.8 51.6h.5M124.2 40.8h-.3l-.2 .7 .1 .2 .4-.1v-.4h-.4l-.1 .2M124.2 58l.2 1 .2-.7 .2 .7 .1-1M124.2 53l-.3-.1-.2 .1 .1 .3 .4 .2v.2h-.5M124.2 56.8h.5l.1-.4-.6-.1v.9M124.3 51.2v.8M124.5 56.8l.3 .4M125.2 51.2h-.4l-.1 .2 .5 .5-.1 .1h-.4M125.5 51.6h.4M125.9 51.2h-.4v.8h.4"/>
<path d="M126.3 51.2v.8h.4M146.4 48.4h4.5M146.4 48.6h.5M146.7 48.6v.9M147.1 48.6l.6 .9M147.7 48.6l-.6 .9M147.7 56.9h3.2M147.8 57.2h.2l.3 .2v.5l-.2 .1h-.3zM147.9 58.7h3M148 43.2h2.9M148 49.1l.5-.1-.1-.4h-.4v.9M148 44.9h2.9"/>
<path d="M148.1 43.4l.4 .2v.5l-.2 .2h-.2zM148.1 45.6h.4v-.4h-.4v.8M148.2 49.1l.3 .4M148.4 45.6l.2 .4M148.5 59h-.4a.43 .43 0 0 0-.1 .5 .43 .43 0 0 0 .5 .2M148.5 50.3v.9M148.5 55.2h2.4M148.6 46.6h2.3M148.7 47.7v-.8l.4 .6 .2-.6v.8M148.7 59h.5M148.8 43.4h.5M148.9 48.6a.47 .47 0 0 1 .5 .4 .47 .47 0 0 1-.5 .5z"/>
<path d="M148.9 41.7h.5M148.9 45.2h.5M149 53.5h1.9M149 59v.8M149.1 54.2l.5-.1v-.3l-.5-.1v.9M149.1 43.4v.9M149.1 55.6l-.4-.1-.2 .3 .2 .5h.4M149.1 57.3h-.5v.2l.5 .3v.2h-.5M149.1 41.7v.8M149.1 45.2v.8M149.3 54.2l.3 .4M149.4 50.3v.9l-.5-.9v.9"/>
<path d="M149.5 55.5l.4 .1 .1 .4-.2 .3h-.3zM149.5 57.7h.3l.2-.2-.2-.3h-.3v.8M149.6 41.7l.6 .8M149.6 43.9l.5-.1v-.3l-.5-.1v.9M149.6 48.6l.3 .5 .3-.5M149.7 47.3h.3M149.7 50.3h.5M149.7 57.7l.3 .3M149.8 43.9l.3 .4M149.9 49.1v.4M149.9 50.3v.9M149.9 53.7v.9"/>
<path d="M150 59l-.5 .1 .5 .5-.2 .2-.3-.1M150.1 45.2l-.5 .1v.2l.5 .2v.2h-.5M150.2 46.9h-.5v.8M150.2 41.7l-.6 .8M150.3 42.5l.4-.8 .2 .8M150.3 44.3l.4-.9 .2 .9M150.3 46l.4-.8 .2 .8M150.3 47.7l.4-.8 .2 .8M150.3 49.5l.4-.9 .2 .9M150.3 51.2l.4-.9 .2 .9M150.3 54.1h.4l.1-.2-.1-.2h-.4v.9h.5v-.4l-.1-.1M150.3 55.9h.4l.1-.2-.1-.2h-.4v.8h.5v-.3l-.1-.1"/>
<path d="M150.3 57.6h.4l.1-.2-.1-.2h-.4v.8h.4l.1-.3-.1-.1M150.3 59.3h.4l.1-.2-.5-.1v.8l.5-.1v-.3l-.1-.1M150.4 42.3h.4M150.4 44.1h.4M150.4 45.8h.4M150.4 47.5h.4M150.4 49.2h.4M150.4 50.9h.4M122.9 61.5l.6 .9M122.9 63.2l.6 .9M123 79.2h.3l.2-.3-.2-.2h-.3v.9M123.1 79.2l.4 .4"/>
<path d="M123.5 61.5l-.6 .9M123.5 63.2l-.6 .9M123.7 61.5v.9M123.8 79.1h.3M123.9 63.2a.47 .47 0 0 1 .4 .5 .47 .47 0 0 1-.4 .4l-.2-.1v-.6zM124.2 78.7h-.4v.9h.4M124.7 61.5v.9l-.5-.9v.9M124.7 63.2v.8l.1 .1 .4-.1v-.8M125 78.8h-.4v.2l.4 .2-.1 .4-.3-.1M125.4 63.2h.5M125.4 79.1h.3M125.7 63.2v.9"/>
<path d="M125.9 78.7h-.5v.9h.5M126.1 78.7h.4M126.3 78.7v.9M134.7 79.7h.8l-.8 .5h.8M134.7 78.9l.4-.1 .3 .1 .1 .4h-.8zM138.1 79.7h.9l-.9 .5h.9M138.1 78.9l.4-.1 .4 .1 .1 .4h-.9zM146.3 71h.5M146.3 70.7h4.6M146.5 71v.8M147 71l.5 .8M147.5 71l-.5 .8"/>
<path d="M147.9 71.4h.4l.1-.3-.5-.1v.8M147.9 65.6h3M147.9 67.3h3M148 65.8h.3l.2 .2v.5l-.2 .2h-.3zM148 68l.5-.1-.1-.4h-.4v.9M148.1 71.4l.3 .4M148.2 68l.3 .4M148.4 72.7v.8M148.5 69h2.4M148.6 61.1h.5v-.4h-.5v.8M148.6 70.1v-.8l.3 .6 .3-.6v.8M148.7 71h.4l.1 .2v.5l-.1 .1h-.4z"/>
<path d="M148.7 64.1h.5M148.7 65.8h.5M148.7 67.5h.5M148.9 61.1l.2 .4M149 64.1v.9M149 65.8v.9M149 67.5v.9M149.3 72.7v.8l-.5-.8v.8M149.5 66.2h.4v-.4h-.4v.9M149.5 71l.3 .4 .3-.4M149.5 60.7l.5 .8M149.5 64.1l.5 .9"/>
<path d="M149.6 72.7h.5M149.6 69.6h.3M149.7 66.2l.3 .5M149.8 71.4v.4M149.8 72.7v.8M150 67.6l-.4-.1-.1 .2 .1 .2 .4 .3-.1 .2h-.4M150 69.3h-.4v.8M150 60.7l-.5 .8M150 64.1l-.5 .9M150.3 61.1h.4l.1-.2-.1-.2h-.4v.8h.4l.1-.3-.1-.1M150.3 64.5h.4v-.4h-.4v.9l.5-.1v-.3l-.1-.1M150.3 66.2h.4l.1-.1-.1-.3h-.4v.9l.5-.1v-.3l-.1-.1"/>
<path d="M150.3 67.9h.4l.1-.2-.1-.2h-.4v.9h.4l.1-.4-.1-.1M150.3 69.6h.4v-.3h-.4v.8h.5v-.4l-.1-.1M150.3 71.4h.4l.1-.2-.1-.2h-.4v.8h.4l.1-.3-.1-.1M150.3 73.1h.4l.1-.2-.1-.2h-.4v.8h.4l.1-.3-.1-.1M134.7 80.6a.43 .43 0 0 0 .3 .5 .43 .43 0 0 0 .5-.1v-.4h-.3v.1M138.1 80.6v.4l.4 .1 .5-.1-.1-.4h-.3v.1M129.2 108l.3-.9 .2 .9M129.2 109.8l.3-.9 .2 .9M129.2 111.5l.3-.9 .2 .9M129.2 113.2l.3-.9 .2 .9M129.2 114.9l.3-.8 .2 .8M129.2 116.6l.3-.8 .2 .8"/>
<path d="M129.2 118.3l.3-.8 .2 .8M129.3 107.7h.4M129.3 109.5h.4M129.3 111.2h.4M129.3 113h.4M129.3 114.7h.4M129.3 116.4h.4M129.3 118.1h.4M129.3 119.8h.4M130 109.1l.3-.2v.9M130 110.7h.5v.3l-.5 .5h.5M130 112.3h.5l-.2 .3 .2 .1v.4h-.5"/>
<path d="M130 119.2h.6l-.4 .9M130 109.8h.5M130.1 107.2l.2-.1 .2 .2-.1 .6a.39 .39 0 0 1-.4-.2 .39 .39 0 0 1 .1-.5zM130.3 114l-.3 .6h.6M130.4 117.5l-.2 .1-.2 .6h.5v-.3l-.3-.1-.2 .2M130.4 114.3v.6M130.5 115.8h-.4l-.1 .4 .4-.1 .1 .4h-.5M133 108.6l.8 .2-.8 .4M133.1 107.8l-.1 .4 .3 .1 .5-.1-.1-.4M133.1 106.9l-.1 .4 .3 .2 .5-.2-.1-.4M136.3 107.6h.3l.1-.4-.4-.1v.9h.4l.1-.3-.3-.1M136.3 109.3h.3l.1-.3-.4-.1v.9h.3l.2-.4-.3-.1"/>
<path d="M136.3 111h.4l-.1-.4h-.3v.9h.4l.1-.3-.3-.2M136.3 112.7h.3l.1-.3-.4-.1v.9h.4l.1-.3-.3-.2M136.3 114.4h.3l.1-.2-.4-.1v.8h.3l.2-.3-.3-.2M136.3 116.2l.4-.1-.1-.3h-.3v.8h.4l.1-.2-.3-.2M136.3 117.9h.3l.1-.3-.4-.1v.8h.4l.1-.2-.3-.2M136.3 119.6h.3l.1-.3-.4-.1v.9h.3l.2-.3-.3-.2M137 112.3h.5l-.2 .3 .2 .1v.4h-.5M137 119.2h.6l-.3 .9M137.1 109.1l.3-.2v.9M137.1 110.7l.4-.1v.4l-.5 .5h.5M137.1 109.8h.4M137.3 107.1l.2 .2v.7h-.3l-.1-.2v-.5z"/>
<path d="M137.3 114l-.2 .6h.5M137.5 117.5l-.4 .2v.5h.4v-.4l-.4 .2M137.5 114.3v.6M137.5 115.8h-.4v.4h.4v.4l-.4-.1M129.2 120.1l.3-.9 .2 .9M129.2 123.5l.3-.9 .2 .9M129.3 123.3h.4M129.8 124.5l-.3-.1-.2 .2v.4l.3 .3 .2-.1M130.1 123.2h.7M130.2 124.8h.3M130.6 124.4h-.4v.9h.4M131.1 123l.7 .2-.7 .3"/>
<path d="M132.2 123.1h.3l.1-.4-.4-.1v.9h.4l.1-.3-.2-.1M133 125.1l.1 .4h.5l.2-.2-.1-.3h-.2v.2M133 124.2h.8l-.8 .5h.8M133 123.4l.3-.2 .4 .1 .1 .4h-.8z"/>
</g>
<path d="M223.6 82.4l.3 .2-.1 .2-.3-.2z" fill="#910000"/>
<path d="M219.6 82.7h.8M220.4 83.8h2.8v1h-2.8zM223.2 82.7h.5v1.7h-.5M223.6 82.5l.3 .2-.1 .2-.3-.2z" fill="none" stroke="#910000" stroke-width=".21"/>
<path d="M223.6 84.1l.3 .2-.1 .2-.3-.2z" fill="#910000"/>
<path d="M219.6 84.4h.8M220.4 85.5h2.8v1.1h-2.8zM223.2 84.4h.5v1.7h-.5M223.6 84.2l.3 .2-.1 .2-.3-.2z" fill="none" stroke="#910000" stroke-width=".21"/>
<path d="M223.6 85.8l.3 .2-.1 .2-.3-.2z" fill="#910000"/>
<path d="M219.6 86.1h.8M220.4 87.3h2.8v1h-2.8zM223.2 86.1h.5v1.7h-.5M223.6 85.9l.3 .2-.1 .1-.3-.1z" fill="none" stroke="#910000" stroke-width=".21"/>
<path d="M223.6 87.6l.3 .2-.1 .2-.3-.2z" fill="#910000"/>
<path d="M219.6 87.8h.8M220.4 89h2.8v1h-2.8zM223.2 87.8h.5v1.7h-.5M223.6 87.7l.3 .1-.1 .2-.3-.2z" fill="none" stroke="#910000" stroke-width=".21"/>
<path d="M223.6 89.3l.3 .2-.1 .2-.3-.2z" fill="#910000"/>
<path d="M219.6 89.5h.8M220.4 90.7h2.8v1.1h-2.8zM223.2 89.5h.5v1.7h-.5M223.6 89.3l.3 .2-.1 .2-.3-.2z" fill="none" stroke="#910000" stroke-width=".21"/>
<path d="M223.6 91l.3 .2-.1 .2-.3-.2z" fill="#910000"/>
<path d="M219.6 91.2h.8M220.4 92.5h2.8v1h-2.8zM223.2 91.2h.5v1.8h-.5M223.6 91l.3 .2-.1 .2-.3-.2z" fill="none" stroke="#910000" stroke-width=".21"/>
<path d="M223.6 92.8l.3 .2-.1 .1-.3-.1z" fill="#910000"/>
<g fill="none" stroke="#910000" stroke-width=".21">
<path d="M195.4 42.2v.8h.9l-.9 .9-.8-.9h.8M195.4 42.2h.1M218.7 93h1.7M218.7 94.7h1.7M218.7 82.7h.9M218.7 84.4h.9M218.7 86.1h.9M218.7 87.8h.9M218.7 89.5h.9M218.7 91.2h.9M220.4 94.1h2.8v1.1h-2.8zM223.2 93h.5v1.7h-.5"/>
<path d="M223.6 92.8l.3 .2-.1 .2-.3-.2zM223.9 82.7h1.7"/>
</g>
<path d="M218.8 83.3h.6l-.3 .3 .3 .2-.1 .3-.5-.1M218.8 90.2h.6l-.3 .9M218.9 81.7l.4-.1 .1 .2-.6 .6h.6M219.1 85l-.2 .6h.5M219.1 92.2l-.2-.2 .4-.1v.3l-.4 .1 .1 .4h.3l.1-.3-.2-.2M219.3 86.7h-.4v.5l.4-.1v.5l-.4-.1M219.3 88.4l-.4 .3v.5l.4 .1 .1-.4-.2-.1-.3 .1M219.3 85.3v.6M219.4 94l-.2 .2-.3-.1v-.4l.3-.1 .2 .2-.2 .6h-.2M224.5 81.8l.2-.2v.8M224.5 82.4h.5" fill="none" stroke="#b90000" stroke-width=".21"/>
<g fill="none" stroke="#0f0f0f" stroke-width=".21">
<path d="M197.1 46.1v.8l.1 .1 .4-.1v-.8M197.2 49.3h6.7M197.3 49.6l.1 .8h.3l.1-.8M197.3 47.9v.7l.2 .1 .3-.1v-.7M197.9 47l.3-.9 .2 .9M198 46.8h.4M198.1 50.4l.3-.8 .3 .8M198.1 48.7l.3-.8 .3 .8M198.2 50.2h.4M198.2 48.5h.4M198.8 46.6h.3l.2-.3-.2-.2h-.3v.9M198.9 50h.4l.1-.3-.5-.1v.8"/>
<path d="M198.9 48.3h.4l.1-.3-.5-.1v.8M198.9 46.6l.4 .4M199.2 50l.2 .4M199.2 48.3l.2 .4M199.5 46.1h.4M199.7 49.6h.5M199.7 47.9h.5M199.7 46.1v.9M199.9 47.9v.8M199.9 49.6v.8M200.1 47l.3-.9 .3 .9M200.2 46.8h.4"/>
<path d="M200.4 50.4l.2-.8 .4 .8M200.4 48.7l.2-.8 .4 .8M200.4 50.2h.5M200.4 48.5h.5M200.8 47h.7M201 50.5h.6M201 48.8h.6M201.6 46.6l.5-.1v-.3l-.5-.1v.9M201.7 47.9h.5M201.9 46.6l.2 .4M202 47.9v.8M202.3 49.7a.42 .42 0 0 0-.5 .2 .42 .42 0 0 0 .2 .5l.3-.1"/>
<path d="M202.4 47.9l.6 .8M202.4 46.1l.6 .9M202.6 49.6h.5M202.8 49.6v.8M203 47.9l-.6 .8M203 46.1l-.6 .9M203.3 47.9h.4a.47 .47 0 0 1 .1 .5 .47 .47 0 0 1-.5 .3zM203.3 46.1a.47 .47 0 0 1 .5 .5 .47 .47 0 0 1-.5 .4zM203.8 49.7l-.3-.1-.2 .1 .5 .5-.1 .2h-.4"/>
</g>
<path d="M206.9 27.5h.6v.1h-.6z" fill="#910000"/>
<path d="M206.9 27.5h.6v.1h-.6z" fill="none" stroke="#910000" stroke-width=".21"/>
<path d="M206.9 29.2h.6v.1h-.6z" fill="#910000"/>
<path d="M206.9 29.2h.6v.1h-.6z" fill="none" stroke="#910000" stroke-width=".21"/>
<path d="M206.9 30.9h.6v.1h-.6z" fill="#910000"/>
<path d="M206.9 30.9h.6v.1h-.6z" fill="none" stroke="#910000" stroke-width=".21"/>
<path d="M206.9 32.6h.6v.2h-.6z" fill="#910000"/>
<path d="M206.9 32.6h.6v.2h-.6z" fill="none" stroke="#910000" stroke-width=".21"/>
<path d="M206.9 34.3h.6v.2h-.6z" fill="#910000"/>
<path d="M206.9 34.3h.6v.2h-.6z" fill="none" stroke="#910000" stroke-width=".21"/>
<path d="M206.9 36h.6v.2h-.6z" fill="#910000"/>
<path d="M204.1 27.6h2.8M204.1 29.2h2.8M204.1 30.9h2.8M204.1 32.7h2.8M204.1 34.4h2.8M204.1 36.1h2.8M206.9 36h.6v.2h-.6z" fill="none" stroke="#910000" stroke-width=".21"/>
<path d="M205.1 26.7l.3-.2v.8M205.1 28.2l.3-.1 .2 .2-.5 .7h.5M205.1 29.8h.5l-.3 .4 .3 .1v.3l-.2 .2-.3-.1M205.1 27.3h.5M205.3 31.5l-.2 .7h.5M205.5 33.3h-.3l-.1 .4h.3l.2 .1-.1 .4-.4-.1M205.5 35l-.3 .1-.1 .7 .2 .1 .3-.1-.2-.5-.3 .2M205.5 31.9v.6" fill="none" stroke="#b90000" stroke-width=".21"/>
<path d="M206.9 42.1h.6v.2h-.6z" fill="#910000"/>
<path d="M206.9 42.1h.6v.2h-.6z" fill="none" stroke="#910000" stroke-width=".21"/>
<path d="M206.9 43.8h.6v.2h-.6z" fill="#910000"/>
<path d="M206.9 43.8h.6v.2h-.6z" fill="none" stroke="#910000" stroke-width=".21"/>
<path d="M206.9 45.5h.6v.2h-.6z" fill="#910000"/>
<path d="M206.9 45.5h.6v.2h-.6z" fill="none" stroke="#910000" stroke-width=".21"/>
<path d="M206.9 47.3h.6v.2h-.6z" fill="#910000"/>
<path d="M206.9 47.3h.6v.2h-.6z" fill="none" stroke="#910000" stroke-width=".21"/>
<path d="M206.9 49h.6v.1h-.6z" fill="#910000"/>
<path d="M206.9 49h.6v.1h-.6z" fill="none" stroke="#910000" stroke-width=".21"/>
<path d="M206.9 50.7h.6v.1h-.6z" fill="#910000"/>
<g fill="none" stroke="#910000" stroke-width=".21">
<path d="M38.6 34.4h1.8M38.6 36.1h1.8M38.6 37.9h1.8M38.6 39.6h1.8M40.4 28.4h34.4v83.5h-34.4zM50.8 26.6v1.8M52.4 26.6v1.8M55.9 26.6v1.8M57.6 26.6v1.8M59.4 26.6v1.8M61.1 26.6v1.8M62.8 26.6v1.8"/>
<path d="M64.6 26.6v1.8M74.9 37.9h1.7M74.9 39.6h1.7M38.6 56.9h1.8M38.6 58.5h1.8M38.6 41.3h1.8M38.6 43h1.8M38.6 44.7h1.8M38.6 46.4h1.8M38.6 48.2h1.8M38.6 49.9h1.8M38.6 51.7h1.8"/>
<path d="M38.6 53.4h1.8M38.6 55.1h1.8M74.9 56.9h1.7M74.9 58.5h1.7M74.9 41.3h1.7M74.9 43h1.7M74.9 44.7h1.7M74.9 46.4h1.7M74.9 48.2h1.7M74.9 49.9h1.7M74.9 51.7h1.7M74.9 53.4h1.7"/>
<path d="M74.9 55.1h1.7M203.2 56.9h2.6M203.2 58.5h2.6M204.1 42.2h2.8M204.1 43.9h2.8M204.1 45.6h2.8M204.1 47.4h2.8M204.1 49.1h2.8M204.1 50.8h2.8M205.7 55.9h3.5v8.6h-3.5zM205.8 56.8h.8v.1h-.8zM205.8 58.5h.8v.1h-.8z"/>
<path d="M206.9 50.7h.6v.1h-.6zM208.4 56.8h.9v.1h-.9zM208.4 58.5h.9v.1h-.9zM209.3 56.9h2.5M209.3 58.5h2.5M38.6 60.2h1.8M38.6 62h1.8M38.6 63.7h1.8M38.6 65.4h1.8M38.6 67.2h1.8M38.6 68.9h1.8M38.6 70.6h1.8"/>
<path d="M38.6 72.3h1.8M38.6 74h1.8M38.6 75.7h1.8M38.6 77.5h1.8M38.6 79.2h1.8M74.9 60.2h1.7M74.9 62h1.7M74.9 63.7h1.7M74.9 65.4h1.7M74.9 67.2h1.7M74.9 68.9h1.7M74.9 70.6h1.7"/>
<path d="M74.9 72.3h1.7M74.9 74h1.7M74.9 75.7h1.7M74.9 77.5h1.7M74.9 79.2h1.7M93.4 78.4h4l.7 .8-.7 .8h-4zM94.2 78.5h2.8M94.3 78.8v.8M94.7 79.3h.3l.2-.4-.2-.1h-.3v.8M94.9 79.3l.3 .3M95.5 78.9l.2-.1a.42 .42 0 0 1 .4 .4 .42 .42 0 0 1-.4 .4l-.2-.1zM95.7 79.5l.4 .2"/>
<path d="M96.4 78.8h.5l-.3 .3 .3 .1v.3h-.5M99.4 78.3h4.3v13.8h-4.3zM99.8 78.7h2.7v1h-2.7zM193.8 60.2v.9h.8l-.8 .9-1-.9h1M193.8 60.2h.1M203.2 60.2h2.6M203.2 62h2.6M203.2 63.7h2.6M205.8 60.2h.8v.1h-.8zM205.8 61.9h.8v.2h-.8zM205.8 63.6h.8v.2h-.8zM208.4 60.2h.9v.1h-.9z"/>
<path d="M208.4 61.9h.9v.2h-.9zM208.4 63.6h.9v.2h-.9zM209.3 60.2h2.5M209.3 62h2.5M209.3 63.7h4.3M211.8 63.7h.1M212.6 63.2l1 .5M213.6 63.7l-1 .5M38.6 80.9h1.8M38.6 82.7h1.8M38.6 84.4h1.8M38.6 86.1h1.8"/>
<path d="M38.6 87.8h1.8M38.6 89.5h1.8M38.6 91.2h1.8M38.6 93h1.8M38.6 94.7h1.8M38.6 96.4h1.8M38.6 98.2h1.8M38.6 99.9h1.8M74.9 80.9h1.7M74.9 82.7h1.7M74.9 84.4h1.7M74.9 86.1h1.7"/>
<path d="M74.9 87.8h1.7M74.9 89.5h1.7M74.9 91.2h1.7M74.9 93h1.7M74.9 94.7h1.7M74.9 96.4h1.7M74.9 98.2h1.7M74.9 99.9h1.7M80 85.2h3.2v1.8h-3.2l-.8-.9zM80.3 85.7h.5M80.6 85.7v.9M81.6 85.8l-.5-.1v.2v.6h.5"/>
<path d="M81.9 85.7v.9M82.1 86.1l.3 .5M82.4 85.7l-.5 .4M93.4 81.8h4l.7 .9-.7 .8h-4zM94.2 82h2.8M94.3 82.3v.8M94.7 82.7h.4v-.4h-.4v.8M94.9 82.7l.3 .4M95.5 82.3h.6v.5l-.1 .3-.5-.1zM95.7 82.9l.4 .3M96.9 82.3h-.4l-.1 .4 .4-.1 .1 .4h-.5M205.8 85.2h.8v-.8l.9 .8-.9 .9v-.9"/>
<path d="M205.8 85.2h.1M38.6 101.6h1.8M38.6 103.3h1.8M38.6 105h1.8M38.6 106.8h1.8M38.6 108.5h1.8M51.6 112v1.7M53.3 112v1.7M55.1 112v1.7M56.8 112v1.7M58.5 112v1.7M60.2 112v1.7"/>
<path d="M61.9 112v1.7M63.7 112v1.7M74.9 101.6h1.7M74.9 103.3h1.7M74.9 105h1.7M168.8 114.5l.8 .5M168.8 114.5h1.7M169.6 114l-.8 .5M170.5 114.5h.1M182.5 119.7v.5M161.8 130.8h3.5M161.8 132.6h3.5"/>
<path d="M161.8 134.3h3.5M161.8 136h3.5M161.8 137.8h3.5M161.8 139.5h3.5M165.3 129.1h10.3v20.7h-10.3zM170.5 125.7h.1M170.5 124v5.2M170.5 124l-.5 .8M170.5 124l.5 .8M170.9 138.6h-.9v1.7M171.3 138.6h-.4v1.7h-1.3M175.6 130.8h3.5"/>
<path d="M175.6 132.6h3.5M175.6 134.3h3.5M175.6 136h3.5M175.6 137.8h3.5M175.6 139.5h3.5M179.9 133.5h3.1v1.7h-3.1l-.8-.9zM179.9 138.6h4.7v1.7h-4.7l-.8-.8zM179.9 135.2h3.1v1.7h-3.1l-.8-.9zM179.9 136.9h3.1v1.7h-3.1l-.8-.8zM180.2 133.9l.3 .8 .3-.8M180.2 135.7l.3 .8 .3-.8M180.2 137.4l.3 .8 .3-.8"/>
<path d="M180.2 138.8h3.7M180.3 139.6l.5-.1v-.4h-.5v.8M180.5 139.6l.3 .3M181 134.7l.2-.8 .3 .8M181 136.5l.2-.8 .3 .8M181 138.2l.2-.8 .3 .8M181.1 134.6h.3M181.1 136.3h.3M181.1 138h.3M181.2 139.5h.3M181.6 139.1h-.4v.8h.4M181.7 134.2l.3-.3v.8"/>
<path d="M181.7 135.8h.5v.2l-.5 .5h.5M181.7 137.4h.5l-.2 .3 .2 .1v.3h-.5M181.7 134.7h.5M181.9 120.1h1.1v2.5h-1.1zM182.4 139.1h-.3l-.2 .1 .1 .3 .4 .2v.2h-.5M182.5 123.1v.9h.9l-.9 .8-.9-.8h.9M182.5 123.1h.1M182.5 122.6v.5M182.7 139.5h.4M183.2 139.1h-.5v.8h.5M183.4 139.1h.5M183.7 139.1v.8"/>
<path d="M190.1 121.8h-.5v.5v-.5l1 1M190.1 122.6h-.5v.5v-.5l1 1.1M190.2 123.9h1.7M190.6 127.9h1v2.4h-1zM190.6 131.8l.5 .8M191.1 123.9l.8 1.7h-1.7zM191.1 130.8h.1M191.1 122.3v5.7M191.1 130.3v2.3M191.6 131.8l-.5 .8M161.8 141.2h3.5M161.8 143h3.5"/>
<path d="M161.8 146.4h3.5M161.8 148.1h2.7M170.5 153.3v.8h.8l-.8 .9-.9-.9h.9M170.5 153.3h.1M170.5 149.8v3.5M175.6 141.2h3.5M175.6 143h3.5"/>
<circle cx="164.9" cy="148.1" r=".47"/>
</g>
<g fill="none" stroke="#b90000" stroke-width=".21">
<path d="M39.1 33.7h-.2v-.3l.3-.1 .2 .3-.2 .1h-.3l.1 .5h.3l.1-.4-.2-.1M39.1 37.1l-.2-.2 .4-.1v.3l-.4 .1 .1 .4h.3l.1-.3-.2-.2M39.1 38.9l-.2-.1v-.2l.3-.1 .2 .2-.5 .3 .1 .3h.3l.1-.3-.2-.1M39.4 35.4l-.2 .2-.3-.1v-.4l.3-.1 .2 .2-.2 .7h-.2M39.7 36.8h.6l-.4 .8M39.9 35l.3 .2v.6l-.2 .1-.3-.1v-.6zM39.9 38.9l-.2-.1v-.2l.3-.1 .2 .1v.2l-.5 .2 .1 .3 .4-.1v-.2l-.2-.1M40.2 33.7l-.4 .1-.1-.4h.5v.6l-.4 .2M49.7 28.2v-.5l.3 .3 .1-.3h.3v.5M50 26.9l.2 .1v.3h-.5v-.4h.6l.2 .4M51.8 27.7l.1 .2v.2h-.5v-.4h.6l.3 .4M52.3 27.1h-1l.3 .3"/>
<path d="M52.3 26.9v.5M54.8 27.8v-.5l.4 .3v-.3h.4v.5M56.9 27l.1-.1h.4v.1l-.1 .4h-.2l-.2-.1v-.4h-.3l-.1 .3 .2 .2 .2-.2M57.4 28h-.9l.3 .1M57.4 27.7v.4M58.3 28.2v-.5l.3 .3 .1-.3h.4v.5M58.5 27h.6M58.9 26.8v.6l-.7-.3M60 27.7v.4h.4v-.4l.4 .1-.1 .3M60.8 27.1h-.8l.2 .3M60.8 26.9v.5M61.7 27.8l.2 .3h.6v-.4h-.4l-.1 .3 .2 .1"/>
<path d="M61.7 27l.1 .2 .6 .2 .2-.2-.1-.3h-.4l-.1 .3 .2 .2M63.8 27.9l.1-.2h.3l.1 .2-.1 .2h-.3l-.2-.4-.2 .1v.3l.3-.1M64.3 26.9v.5l-.5-.5-.3 .1v.4M74.6 37l.3-.2v.8M74.6 37.6h.5M75.6 36.8a.42 .42 0 0 1 .4 .4 .42 .42 0 0 1-.4 .4zM75.6 38.9h-.5l.1-.4 .4 .1v.6l-.5 .1M76.4 36.8a.42 .42 0 0 1 .4 .4 .42 .42 0 0 1-.4 .4zM76.4 38.9l-.5 .1v-.4l.3-.1 .2 .1-.2 .7h-.2M38.9 54.2l.3-.2v.8M38.9 56l.3-.3v.9M38.9 57.7l.3-.3v.9"/>
<path d="M38.9 59.4l.3-.3v.9M38.9 56.6h.5M38.9 54.8h.5M38.9 58.3h.5M38.9 60h.5M39.2 48.8h.6l-.3 .9M39.3 40.4l.3-.1v.8M39.3 42l.4-.1 .1 .3-.6 .6h.6M39.3 41.1h.5M39.5 43.6l-.2 .6h.5M39.5 50.9l-.2-.2 .4-.1 .1 .2-.1 .1-.4 .1v.3l.2 .1 .3-.1-.1-.4M39.7 57.4h.5l-.3 .4 .3 .1v.3h-.5"/>
<path d="M39.7 45.4h-.4v.4l.4-.1 .1 .4-.1 .2-.4-.1M39.7 47.1l-.4 .2v.6l.4 .1v-.5h-.3l-.1 .1M39.7 55.8l.4-.1 .1 .4-.5 .5h.5M39.7 44v.5M39.8 52.6l-.1 .2h-.3l-.1-.4 .4-.1 .1 .1-.1 .7h-.3M39.9 54l.3 .1-.1 .7-.4-.1v-.6zM39.9 59.1l-.2 .6h.6M40.1 59.5v.5M75.1 59.1h.5l-.4 .9M75.2 50.9l-.1-.1v-.2h.4l.1 .2-.5 .1v.2l.1 .3 .4-.1v-.3l-.2-.1M75.2 52.6l-.1-.2v-.1h.4l.1 .2-.5 .3v.3l.5-.1v-.3l-.2-.1M75.2 54.4l-.1-.3 .1-.1 .4 .1v.2l-.5 .1v.4l.5-.1v-.2l-.2-.1"/>
<path d="M75.2 56.1l-.1-.2v-.2h.4l.1 .3-.5 .1v.2l.1 .3 .4-.1v-.3l-.2-.1M75.2 57.8l-.1-.2v-.2h.4l.1 .3-.5 .3v.3l.5-.1v-.3l-.2-.1M75.6 40.6l-.4 .2-.1-.5h.5l-.1 .7-.4 .1M75.6 42.3l-.1 .2h-.4v-.6l.5 .1v.6l-.5 .2M75.6 44.1l-.2 .1-.3-.1 .1-.5 .4 .1v.6l-.5 .2M75.6 45.8l-.4 .1-.1-.4h.5l-.1 .7-.4 .1M75.6 47.5l-.1 .1h-.4v-.5l.5 .1v.6l-.5 .2M75.6 49.2l-.2 .2-.3-.2 .1-.4 .4 .1v.6l-.5 .2M75.8 41.9h.6l-.3 .9M75.8 47.1h.6l-.3 .4h.2l.1 .1-.1 .4-.5-.1M75.8 54h.6l-.3 .3 .3 .2v.2h-.6M75.9 48.9l.3-.1 .2 .3-.6 .6h.6"/>
<path d="M75.9 56l.3-.3v.9M75.9 56.6h.5M76 57.4a.42 .42 0 0 1 .4 .5 .42 .42 0 0 1-.4 .4zM76.1 40.6l-.2-.1v-.2h.4l.1 .1-.5 .3v.3l.2 .1 .3-.2-.2-.3M76.1 45.3l-.2 .6h.5M76.1 52.2l-.2 .7h.5M76.3 43.6l-.4 .3v.5l.4 .1 .1-.3-.2-.2-.3 .2M76.3 50.6h-.4v.3l.3-.1 .2 .5-.2 .1-.3-.1M76.3 45.7v.6M76.3 52.5v.6M76.4 59.6l-.2 .1-.3-.1v-.4l.3-.1 .2 .2-.2 .7h-.2M204.2 57.4h.6l-.4 .4h.3l.1 .2-.1 .3-.5-.1"/>
<path d="M204.3 56l.2-.3v.9M204.3 56.6h.5M204.7 59.1h-.4v.5l.3-.1 .2 .4-.5 .1M205.1 41.4l.3-.3v.8M205.1 42.9l.3-.1 .2 .2-.5 .6h.5M205.1 44.5h.5l-.3 .3 .3 .2v.3l-.2 .1-.3-.1M205.1 41.9h.5M205.3 46.2l-.2 .7h.5M205.5 48h-.3l-.1 .4 .4-.1v.5l-.4-.1M205.5 49.7h-.3l-.1 .7 .2 .2 .3-.2-.2-.4-.3 .2M205.5 46.5v.6M210.3 55.8l.4-.1 .1 .2-.5 .7h.5"/>
<path d="M210.4 57.4l-.1 .6h.5M210.7 59.1l-.3 .1-.1 .7h.5l-.2-.4-.3 .1M210.7 57.7v.6M38.9 61.2l.3-.3v.9M38.9 62.9l.3-.3v.9M38.9 64.6l.3-.3v.9M38.9 66.3l.3-.2v.8M38.9 67.9l.3-.1 .2 .2-.6 .6h.6M38.9 69.6l.3-.1 .2 .2-.6 .7h.6M38.9 71.3l.4-.1 .1 .3-.6 .6h.6M38.9 73l.3-.1 .2 .3-.6 .6h.6M38.9 74.7l.3-.1 .2 .3-.6 .7h.6"/>
<path d="M38.9 76.5l.4-.1 .1 .3-.6 .6h.6M38.9 78.2l.3-.1 .2 .3-.6 .5h.6M38.9 79.9l.3-.1 .2 .2-.6 .7h.6M38.9 63.5h.5M38.9 61.8h.5M38.9 65.2h.5M38.9 66.9h.5M39.7 64.3h.6l-.4 .9M39.7 72.9h.5l-.3 .4 .3 .1v.3h-.5M39.7 78.1h.6l-.4 .8M39.7 69.7l.3-.2v.9M39.7 71.3l.4-.1 .1 .4-.5 .5h.5"/>
<path d="M39.7 70.4h.5M39.9 67.8l.3 .1-.1 .7h-.3l-.1-.2v-.5zM39.9 74.6l-.2 .6h.6M40.1 62.6l-.4 .2v.6h.5l-.1-.5h-.3l-.1 .2M40.1 75v.6M40.2 60.9h-.5v.4h.5v.4h-.5M40.2 66.4l-.1 .2h-.3l-.1-.4h.5v.5l-.4 .2M40.2 76.4h-.5v.4h.5v.4h-.5M75.1 60.9h.5l-.4 .9M75.1 62.6h.5l-.4 .9M75.1 64.3h.5l-.4 .9M75.1 66.1h.5l-.4 .8"/>
<path d="M75.1 67.8h.5l-.4 .8M75.1 69.5h.5l-.4 .9M75.1 71.2h.5l-.4 .9M75.1 72.9h.5l-.4 .9M75.5 74.6l-.3 .1-.1 .7 .1 .2 .4-.1v-.4l-.4-.1-.1 .1M75.5 76.4h-.3l-.1 .7 .1 .2 .4-.1-.1-.5h-.4v.2M75.5 78.1l-.4 .3v.4v.1h.5l-.1-.5h-.4v.2M75.5 79.8l-.3 .1-.1 .7 .1 .1 .4-.1v-.4l-.4-.1-.1 .2M75.8 62.6h.6l-.3 .9M75.8 67.8h.6l-.3 .3h.2v.5l-.5-.1M75.8 78.1h.6l-.3 .8M75.9 69.6l.3-.1 .2 .2-.6 .7h.6"/>
<path d="M75.9 71.5l.3-.3v.9M75.9 72.1h.5M76.1 61.3l-.2-.3 .4-.1v.4h-.4v.4l.2 .1 .3-.2-.2-.3M76.1 72.9a.43 .43 0 0 1 .3 .5 .43 .43 0 0 1-.4 .4l-.1-.7zM76.1 76.7l-.2-.2 .4-.1v.3l-.4 .1v.4l.2 .1 .3-.2-.2-.4M76.3 64.3l-.4 .3v.5l.3 .1 .2-.1-.2-.5-.3 .2M76.3 66.1h-.4v.4l.4-.1 .1 .4-.2 .1-.3-.1M76.3 79.8h-.4v.4l.3-.1 .2 .5-.2 .1-.3-.1M76.4 75.1l-.2 .1-.3-.1v-.4l.3-.1 .2 .2-.2 .7-.2 .1M204.2 60.9h.6l-.4 .9M204.8 62.9l-.1 .2h-.4v-.4l.4-.1 .1 .2-.2 .7h-.3M209.8 62.9l.3-.3v.9"/>
<path d="M209.8 63.5h.6M210.4 61.3l-.1-.2 .1-.2h.3v.4l-.4 .1 .1 .4 .4-.2-.2-.3M210.8 62.6a.42 .42 0 0 1 .4 .4 .42 .42 0 0 1-.4 .5zM38.8 83.3h.6l-.3 .3 .3 .2-.1 .3-.5-.1M38.8 85h.6l-.3 .3 .3 .2v.2l-.2 .2-.4-.1M38.8 86.7h.6l-.3 .4h.2v.5l-.5-.1M38.8 88.4h.6l-.3 .4 .3 .1-.1 .4-.5-.1M38.8 90.2h.6l-.3 .3 .3 .1v.3l-.2 .2-.4-.1M38.8 91.9h.6l-.3 .3h.2v.5h-.5M38.8 93.6h.6l-.3 .3 .3 .2-.1 .3h-.5M38.9 81.7l.4-.1 .1 .2-.6 .6h.6M39.1 95.3l-.2 .6h.5"/>
<path d="M39.1 97l-.2 .7h.5M39.1 98.8l-.2 .6h.5M39.3 95.6v.6M39.3 97.3v.6M39.3 99.1v.5M39.7 88.4h.5l-.3 .4 .3 .1v.3h-.5M39.7 93.6h.6l-.4 .8M39.7 85.2l.3-.2v.9M39.7 86.8l.4-.1 .1 .4-.5 .5h.5M39.7 97.3l.3-.2v.8M39.7 98.8h.5v.4l-.5 .4h.5M39.7 85.9h.5"/>
<path d="M39.7 97.9h.5M39.8 95.4h.3l.1 .1v.6l-.2 .1-.3-.1zM39.9 80.2l-.2-.1v-.2l.3-.1 .2 .1v.2l-.5 .2v.3l.2 .1 .3-.1v-.3l-.2-.1M39.9 83.3l.3 .1-.1 .7h-.3l-.1-.2v-.5zM40.1 91.9l-.4 .2v.6h.5l-.1-.5h-.3l-.1 .2M40.2 81.9l-.1 .2h-.3l-.1-.4h.5v.6l-.4 .1M40.2 90.2h-.5v.3h.5v.5h-.5M75.5 81.6h-.3l-.1 .7v.1l.5-.1-.1-.4h-.4v.2M75.5 83.3l-.3 .1-.1 .5v.2l.5-.1v-.3l-.4-.1-.1 .2M75.5 85h-.3l-.1 .7 .1 .2 .4-.1v-.4l-.4-.1-.1 .2M75.5 86.7h-.3l-.1 .7v.2l.5-.1-.1-.4h-.4v.1M75.5 88.4l-.3 .1-.1 .6v.2l.5-.1v-.3l-.4-.1-.1 .1"/>
<path d="M75.6 90.2h-.5v.3h.5v.5h-.5M75.6 91.9h-.5v.4l.4-.1 .1 .5h-.5M75.6 93.6h-.5v.4h.5v.4h-.5M75.6 95.4h-.5v.3h.5v.4h-.5M75.6 97.1h-.5v.4l.4-.1 .1 .4h-.5M75.6 98.8h-.5v.4h.5v.3h-.5M75.8 83.3h.6l-.3 .3 .3 .2-.1 .3-.5-.1M75.8 91.9h.6l-.3 .8M75.8 98.8h.6l-.3 .3 .3 .2v.2h-.6M75.9 85h.4l.1 .2-.6 .7h.6M75.9 87l.3-.3v.9M75.9 87.6h.5"/>
<path d="M76.1 81.5l-.2 .7h.5M76.1 88.4a.43 .43 0 0 1 .3 .5 .43 .43 0 0 1-.4 .4l-.1-.7zM76.1 90.5l-.2-.2 .4-.1 .1 .2-.5 .2v.4l.2 .1 .3-.2-.2-.4M76.1 97l-.2 .7h.5M76.3 93.6l-.4 .2v.6h.4l.1-.3-.2-.2-.3 .2M76.3 95.4h-.4v.3l.3-.1 .2 .5-.2 .1-.3-.1M76.3 81.8v.6M76.3 97.3v.6M39.1 100.5l-.2 .5h.5M39.1 102.1l-.2 .7h.5M39.1 103.9l-.2 .6h.5M39.1 105.6l-.2 .6h.5"/>
<path d="M39.1 107.4l-.2 .6h.5M39.3 100.8v.6M39.3 102.5v.6M39.3 104.3v.5M39.3 106v.5M39.3 107.7v.5M39.7 105.7h.6l-.4 .8M39.9 100.5l-.2 .5h.6M39.9 107.7l-.2-.2 .4-.1 .1 .3-.5 .1 .1 .4h.4v-.4l-.2-.1M40.1 103.9l-.4 .3v.6h.5v-.5h-.3l-.2 .1M40.1 100.8v.6M40.2 102.2h-.5v.5h.5l-.1 .4-.4-.1"/>
<path d="M51.3 113.2h-.8l.3 .3M51.3 112.4h-.8l.3 .2M51.3 112.1v.5M51.3 113v.5M52.3 112.2v.3l.3 .1h.4l.1-.3-.4-.2-.2 .2 .2 .3M53.1 113v.5l-.5-.5h-.3v.5M54 113.5v-.5l.3 .2 .1-.2h.3v.5M54.3 112.3l.2-.2 .3 .1v.4h-.2l-.3-.1v-.3h-.3v.4h.1l.2-.1M55.7 112.6v-.5l.3 .3 .2-.3 .3 .1-.1 .4M56 113.1h.5M56.3 112.9v.6l-.6-.3M57.4 113v.4l.4 .1v-.5h.4v.5"/>
<path d="M57.8 112.1l.2 .2-.2 .3h-.4v-.4a.57 .57 0 0 1 .9 .4M59.4 112.2h.6M59.7 112.1v.5l-.6-.2M60 113.3l-.9-.4v.6M60.8 112.2v.2l.5 .2h.4v-.4l-.4-.1-.1 .2 .1 .3M61.3 113.2v-.2l.4 .1v.3l-.3 .1-.1-.1-.1-.4h-.3l-.1 .3 .2 .2 .3-.2M62.6 112.2v.4h.3v-.3l.4-.2 .2 .2-.1 .3M62.9 113l.2 .3-.2 .2-.3-.1 .1-.4 .7 .1 .1 .3M75.3 103.9l-.2 .6h.5M75.5 104.3v.5M75.6 100.5h-.5v.4h.5v.4h-.5M75.6 102.2h-.5v.5l.4-.1 .1 .4h-.5"/>
<path d="M75.9 100.6l.4-.1 .1 .3-.6 .6h.6M76 102.2a.42 .42 0 0 1 .4 .5 .42 .42 0 0 1-.4 .4zM76.4 104.3l-.2 .2-.3-.1v-.4l.3-.1 .2 .2-.2 .7h-.2M163.3 131.5h.5l-.3 .4h.3v.4h-.5M163.3 138.4h.6l-.4 .8M163.4 129.8l.3-.1 .1 .5-.5 .5h.5M163.5 133.2l-.1 .6h.5M163.7 136.7l-.3 .2v.6h.4l-.1-.5h-.3v.2M163.7 133.6v.5M163.8 135h-.4v.3h.4l-.1 .5h-.3M169.4 127l.1-.2 .6 .1a.36 .36 0 0 1-.2 .4 .36 .36 0 0 1-.4-.2zM170.2 127.6v.5l-.5-.5h-.2v.5"/>
<path d="M176.7 130l.2-.3v1M176.7 131.8l.2-.3v.9M176.7 133.5l.2-.3v.9M176.7 135.2l.2-.2v.8M176.7 136.9l.2-.2v.8M176.7 138.6l.2-.2v.8M176.7 130.7h.5M176.7 132.4h.5M176.7 134.1h.5M176.7 135.8h.5M176.7 137.5h.5M176.7 139.2h.5"/>
<path d="M177.5 131.5h.6l-.4 .9M177.5 138.4h.5l-.2 .3 .2 .1v.3h-.5M177.7 130.2l-.2-.2 .2-.3 .3 .1v.3l-.4 .1-.1 .1 .2 .4 .3-.1v-.3l-.2-.1M177.8 136.6l-.3 .7h.6M177.9 133.2l-.2 .1-.2 .6 .1 .2 .4-.1v-.4h-.2l-.3 .1M177.9 136.9v.6M178 135h-.4l-.1 .3h.5v.5h-.5M162.9 147.3l.3-.3v.9M162.9 147.9h.5M163.4 145.6l.2-.3v.9M163.4 146.2h.4M163.5 140.5l-.1-.3h.3l.1 .2-.4 .2v.3l.1 .1 .3-.1-.1-.4"/>
<path d="M163.8 142.2l-.1 .2h-.3v-.5h.4v.6l-.1 .2h-.3M164.2 147.4l-.1 .1h-.3v-.5l.4 .1v.6l-.4 .2M169.4 151.1l.1-.2 .6 .1a.36 .36 0 0 1-.2 .4 .36 .36 0 0 1-.4-.1zM170.2 151.9h-.8l.2 .3M170.2 151.7v.5M176.7 140.3l.2-.1v.8M176.7 142.1l.2-.2v.8M176.7 141h.5M176.7 142.7h.5M177.5 140.2h.5v.3l-.5 .5h.5M177.5 142.1l.3-.2v.8M177.5 142.7h.5"/>
</g>
<g fill="none" stroke="#0f0f0f" stroke-width=".21">
<path d="M85.4 38.1h3.6M85.5 38.4v.8M85.9 38.5h.5v.7h-.5zM86.6 39.3h.6M87.3 38.4l.3 .8 .2-.6 .1 .6 .2-.8M88.4 38.8h.5v-.4h-.5v.8M88.6 38.8l.3 .4M77.6 59.1l.2-.9 .4 .9M77.6 58h6.7M77.6 40.7h3.5M77.7 51.3v.7l.1 .2 .4-.1v-.8M77.7 58.8h.4"/>
<path d="M77.7 40.9v.9M78.3 40.9a.47 .47 0 0 1 .4 .4 .47 .47 0 0 1-.2 .5l-.4-.1v-.6zM78.4 58.2h.5M78.5 52.2l.3-.9 .2 .9M78.6 51.9h.4M78.6 58.2v.9M78.9 41.9h.6M79 59.1l.3-.9 .2 .9M79 58.8h.5M79.4 51.8h.3l.2-.4-.2-.1h-.3v.9M79.5 51.8l.4 .4M79.7 41.4h.3l.2-.3-.2-.2h-.3v.9"/>
<path d="M79.7 59.1l.3-.9 .3 .9M79.8 58.8h.4M79.9 41.4l.3 .4M80.1 51.3h.5M80.4 51.3v.9M80.6 40.9a.49 .49 0 0 1 .4 .3 .49 .49 0 0 1-.1 .6h-.3zM80.6 58.2v.7l.1 .2 .4-.1v-.8M80.9 51.7h.3l.1-.4h-.4v.9h.3l.2-.3-.3-.2M81.4 58.2l.6 .9M81.6 52.3h.6M82 58.2l-.6 .9M82.4 51.3v.9"/>
<path d="M82.8 58.2h-.5v.2l.1 .2 .4 .1v.3h-.5M83.1 58.6h.3M83.3 51.3v.9l-.5-.9v.9M83.5 58.2h-.4v.9h.4M83.6 51.3h.5M83.9 51.3v.9M83.9 58.2v.9h.4M85.4 59.9l.2-.8 .3 .8M85.4 58.8h4.2M85.5 59.6h.3M86.1 59.1h.5M86.3 59.1v.8"/>
<path d="M86.7 59.9l.3-.8 .3 .8M86.8 59.6h.4M88.1 59.1h-.5v.3l.5 .2-.1 .3h-.4M88.4 59.5h.3M88.9 59.1h-.5v.8h.5M89.2 59.1v.8h.4M183.5 58h7M183.5 59.6h7.1M183.7 59.9l.1 .8h.3l.1-.8M183.7 56.4v.9l.2 .1 .3-.2v-.8M183.7 58.2v.8l.2 .1 .3-.2v-.7M184.4 57.4l.3-1 .3 1"/>
<path d="M184.4 59.1l.3-.9 .3 .9M184.5 57.1h.5M184.5 58.8h.5M185.3 56.9h.3l.2-.1-.2-.4h-.3v1M185.3 58.6h.4v-.4h-.4v.9M185.5 56.9l.3 .5M185.5 58.6l.3 .5M186.1 59.9h.5M186.1 56.4h.5M186.1 58.2h.5M186.3 56.4v1M186.3 58.2v.9"/>
<path d="M186.3 59.9v.8M186.8 56.9h.4v-.4l-.4-.1v1h.4l.1-.4-.2-.1M186.8 58.6l.4-.1v-.2l-.4-.1v.9h.4l.1-.3-.2-.2M187.5 57.4h.7M187.5 59.1h.7M188.3 59.9a.49 .49 0 0 1 .5 .3 .49 .49 0 0 1-.1 .5h-.4zM188.3 56.9h.4l.1-.3-.1-.2h-.4v1M188.3 58.2h.4a.47 .47 0 0 1 .1 .6 .47 .47 0 0 1-.5 .3zM188.5 56.9l.3 .5M189.1 56.4l.6 1M189.1 58.2h.5M189.4 58.2v.9"/>
<path d="M189.6 60h-.4v.2l.4 .2v.3h-.4M189.7 56.4l-.6 1M189.9 58.6h.4v-.4h-.4v.9M190 56.4a.47 .47 0 0 1 .5 .5 .47 .47 0 0 1-.5 .5zM190 58.6l.4 .5M196.5 57.4v.7l.1 .1 .4-.2v-.6M197 55.3h6.1M197.1 55.6v.8h.4l.1-.1v-.7M197.2 58.2l.3-.8 .3 .8M197.3 58h.4M197.8 56.4l.4-.8 .2 .8M197.9 56.3h.4"/>
<path d="M198.1 57.8h.3l.2-.2-.1-.2h-.4v.8M198.3 57.8l.3 .4M198.7 56.1l.5-.1v-.3l-.5-.1v.8M198.8 57.4h.5M198.9 56.1l.3 .3M199.1 57.4v.8M199.4 55.6h.5M199.5 58.2l.3-.8 .2 .8M199.6 58h.3M199.7 55.6v.8M200.1 56.4l.3-.8 .3 .8M200.1 58.3h.7"/>
<path d="M200.2 56.3h.4M200.8 56.5h.6M200.9 57.4h.5M201.1 57.4v.8M201.5 57.4l.6 .8M202.1 55.7a.44 .44 0 0 0-.5 .1 .44 .44 0 0 0 .1 .6l.4-.1M202.1 57.4l-.6 .8M202.5 57.4h.3a.48 .48 0 0 1 .2 .5 .48 .48 0 0 1-.5 .3zM202.5 55.6a.49 .49 0 0 1 .4 .3 .49 .49 0 0 1-.1 .5h-.3zM212 57.1h6.7M212 58.8h6.9M212 59.1l.1 .8 .5-.1v-.7"/>
<path d="M212 55.6l.1 .8 .5-.1v-.7M212 57.4v.6l.2 .2 .4-.1v-.7M212.9 59.9l.2-.8 .3 .8M212.9 56.4l.2-.8 .3 .8M212.9 58.2l.2-.8 .3 .8M213 58h.3M213 59.6h.3M213 56.3h.3M213.7 59.5h.5v-.4h-.5v.8M213.7 56.1h.4l.1-.4-.1-.1h-.4v.8M213.7 57.8h.4l.1-.2v-.2h-.5v.8M213.9 59.5l.3 .4"/>
<path d="M213.9 56.1l.3 .3M213.9 57.8l.3 .4M214.5 57.4h.4M214.5 59.1h.4M214.5 55.6h.4M214.7 55.6v.8M214.7 57.4v.8M214.7 59.1v.8M215.1 59.9l.3-.8 .3 .8M215.1 56.4l.3-.8 .3 .8M215.1 58.2l.3-.8 .3 .8M215.2 58h.4"/>
<path d="M215.2 59.6h.4M215.2 56.3h.4M215.8 58.3h.6M215.8 60h.6M215.8 56.5h.6M216.6 59.1h.4l.1 .1v.5l-.1 .2h-.4zM216.6 56.1l.5-.1v-.3l-.5-.1v.8M216.6 57.4h.4l.1 .1v.5l-.2 .2h-.3zM216.9 56.1l.2 .3M217.4 57.4h.5M217.4 55.6l.6 .8M217.6 57.4v.8"/>
<path d="M218 59.1h-.5v.3l.5 .2-.1 .3h-.4M218 55.6l-.6 .8M218.1 57.8h.4l.1-.2v-.2h-.5v.8M218.3 59.5h.4v-.4h-.4v.8M218.3 55.6a.48 .48 0 0 1 .5 .3 .48 .48 0 0 1-.2 .5h-.3zM218.4 57.8l.2 .4M218.6 59.5l.2 .4M77.6 62.5l.2-.9 .4 .9M77.6 61.4h4.5M77.6 64h4.6M77.7 62.3h.4M77.7 64.2v.9"/>
<path d="M78.1 64.3l.4-.1 .1 .3-.6 .6h.6M78.4 61.6h.5M78.6 61.6v.9M79 62.5l.3-.9 .2 .9M79 62.3h.5M79.5 64.3l-.5-.1-.1 .2 .1 .7 .5-.1M79.6 65.1h.7M79.9 62h.3l.1-.3-.4-.1v.9h.3l.2-.3-.3-.2M80.5 64.2v.9M80.7 62h.3M81.1 61.6h-.4v.9h.4M81.4 64.2v.9l-.5-.9v.9"/>
<path d="M81.7 64.2h.5M81.9 64.2v.9M82 61.6v.9l-.5-.9v.9M83.6 62.3h4.2M83.8 62.5v.9M84.1 62.6l.4-.1 .1 .2-.5 .7h.5M85.5 62.6l-.4-.1-.1 .2v.4l.2 .3 .3-.1M86.3 62.5l-.5 .1v.3h.4l.1 .3-.2 .2-.3-.1M86.7 62.9h.2M87.1 62.5h-.4v.9h.4M87.4 62.5v.9h.4M184.4 60.7l.3-.8 .3 .8"/>
<path d="M184.5 60.5h.5M185.3 60.3h.4l.1-.2-.2-.2h-.3v.8M185.5 60.3l.3 .4M186.8 60.3l.4-.1v-.2l-.4-.1v.8h.4l.1-.2-.2-.2M187.5 60.8h.7M190 60.3h.5v-.2l-.1-.2h-.4v.8M190.2 60.3l.3 .4M196.3 60.5h6.8M196.5 60.7l.1 .9 .4-.1v-.8M197.2 61.6l.3-.9 .3 .9M197.3 61.4h.4M197.4 62.3h5.7"/>
<path d="M197.5 62.5v.7l.2 .2 .3-.1v-.8M198.1 61.3h.3l.2-.4-.2-.2h-.3v.9M198.3 63.4l.3-.9 .2 .9M198.3 61.3l.3 .3M198.4 63.1h.4M198.8 60.7h.5M199.1 60.7v.9M199.2 62.9h.3l.2-.1-.1-.3h-.4v.9M199.3 62.9l.4 .5M199.5 61.6l.3-.9 .2 .9M199.6 61.4h.3M199.9 62.5h.5"/>
<path d="M200.1 61.7h.7M200.1 62.5v.9M200.5 63.4l.4-.9 .2 .9M200.6 63.1h.4M201 61.3l.5-.1v-.4l-.5-.1v.9M201.2 61.3l.3 .3M201.2 63.5h.7M201.7 60.7h.5M202 60.7v.9M202.1 62.9h.3l.2-.1-.1-.3h-.4v.9M202.3 62.9l.3 .5M202.9 62.5v.9"/>
<path d="M203 60.8h-.5v.3l.5 .3-.1 .2h-.4M212 60.5h6.6M212 60.7l.1 .9 .5-.1v-.8M212.9 61.6l.2-.9 .3 .9M213 61.4h.3M213.7 61.3h.4l.1-.4-.1-.2h-.4v.9M213.9 61.3l.3 .3M214.5 60.7h.4M214.7 60.7v.9M215.1 61.6l.3-.9 .3 .9M215.2 61.4h.4M215.8 61.7h.6"/>
<path d="M217.1 60.8l-.2-.1-.3 .3v.4l.2 .2 .3-.1M217.4 60.7h.5M217.6 60.7v.9M218.6 60.8h-.5v.3l.5 .2v.3h-.5M199.9 90l.3-.8 .2 .8M199.9 88.3l.3-.8 .2 .8M200 89.8h.4M200 88.1h.4M200.6 89.2h.5M200.6 87.5h.5M200.9 87.5v.8M200.9 89.2v.8"/>
<path d="M201.3 90l.2-.8 .4 .8M201.3 88.3l.2-.8 .4 .8M201.4 89.8h.4M201.4 88.1h.4M202 90.1h.6M202 88.4h.6M202.8 89.2l.4 .1 .1 .4-.1 .3h-.4zM202.8 87.5h.4a.48 .48 0 0 1 .1 .5 .48 .48 0 0 1-.5 .3zM203.7 89.4l.2-.2v.8M203.7 90h.4M204.1 87.8l-.1 .2-.3-.1v-.3l.4-.1v.6l-.4 .2M204.5 89.3l.3-.1 .1 .2-.1 .6a.39 .39 0 0 1-.4-.3 .39 .39 0 0 1 .1-.4z"/>
<path d="M214.2 92.7l.3-.9 .3 .9M214.2 90.9l.3-.9 .3 .9M214.3 92.4h.5M214.3 90.6h.5M215 90h.5M215 91.8h.5M215.3 90v.9M215.3 91.8v.9M215.6 92.7l.3-.9 .3 .9M215.6 90.9l.3-.9 .3 .9M215.7 92.4h.4M215.7 90.6h.4"/>
<path d="M216.3 92.7h.7M216.3 91h.7M217.1 91.8h.4l.1 .2v.4l-.2 .3h-.3zM217.1 90h.3l.2 .3v.4l-.1 .2h-.4zM218 92l.2-.2v.9M218 90.1l.3-.1 .2 .2-.5 .7h.5M218 92.7h.5M184.3 115.9l.3-.9 .3 .9M184.3 114.8h6.7M184.4 115.6h.4M185 115h.5M185.3 115v.9"/>
<path d="M185.7 115.9l.3-.9 .3 .9M185.8 115.6h.4M186.4 115.9h.6M186.8 114.2l.3-.9 .3 .9M186.9 113.9h.4M187.6 113.3h.4M187.7 115.1a.44 .44 0 0 0-.5 .2 .44 .44 0 0 0 .1 .6l.4-.1M187.8 113.3v.9M188.2 114.2l.3-.9 .3 .9M188.3 113.9h.4M188.5 115.1l-.3-.1-.2 .2 .1 .2 .4 .1v.3l-.5 .1M188.8 115.3l.3-.3v.9"/>
<path d="M188.8 114.3h.7M188.8 115.9h.6M189.6 114.2l.3-.9 .3 .9M189.7 113.9h.4M189.7 115.4h.3M190.1 115h-.4v.9M190.4 115l.6 .9M190.5 113.4l.3-.1 .1 .2-.1 .7-.3-.1zM191 115l-.6 .9M179.2 132.3l.3-.9 .3 .9M179.2 130.5l.3-.8 .3 .8M179.2 131.2h6.8"/>
<path d="M179.2 129.4h4.3M179.3 132h.4M179.3 130.3h.4M180 131.4h.5M180 129.7h.5M180.2 129.7v.8M180.2 131.4v.9M180.6 132.3l.3-.9 .3 .9M180.6 130.5l.3-.8 .3 .8M180.7 132h.4M180.7 130.3h.4M181.4 132.3l.2-.9 .3 .9"/>
<path d="M181.5 132h.3M181.9 129.7h-.4v.3l.4 .2-.1 .3h-.3M182.2 131.4v.8l.2 .1 .3-.2v-.7M182.3 130.1h.3M182.7 129.7h-.4v.8h.4M183 131.4l.6 .9M183.1 129.7v.8h.4M183.6 131.4l-.6 .9M184.4 131.4h-.5v.3l.5 .2-.1 .4-.4-.1M184.8 131.8h.2M185.2 131.4h-.4v.9h.4M185.5 131.4v.9h.5"/>
<path d="M180.1 142.4h3.7M180.1 140.7h3.5M180.2 140.8v1M180.2 142.6v.9M180.6 142.7h.5v.6l-.1 .2a.47 .47 0 0 1-.4-.3 .47 .47 0 0 1 0-.5zM180.8 140.8l.3 .2v.6l-.1 .2a.49 .49 0 0 1-.5-.4 .49 .49 0 0 1 .3-.6zM181.3 143.5h.7M181.3 141.9h.7M182.1 142.6l.2 .9 .2-.6 .2 .6 .1-.9M182.2 141.3h.5v-.4l-.5-.1v1M182.4 141.3l.3 .5M183 140.8h.3l.2 .3v.4l-.2 .3h-.3z"/>
<path d="M183.2 143h.4v-.4h-.4v.9M183.3 143l.4 .5"/>
</g>
<g fill="none" stroke="#006665" stroke-width=".21">
<path d="M41.1 34v.8M41.1 35.7v.8M41.1 37.4v.8M41.1 39.2v.8M42.1 33.9l-.7 1.1M42.1 35.6l-.7 1.1M42.1 37.4l-.7 1.1M42.1 39.1l-.7 1.1M42.5 35.8h.5l-.1 .7-.4-.1zM42.5 39.2h.5v.6l-.2 .2a.47 .47 0 0 1-.4-.3 .47 .47 0 0 1 .1-.5zM42.9 34h-.4a.44 .44 0 0 0-.1 .5 .44 .44 0 0 0 .6 .3v-.4h-.2M42.9 37.5a.43 .43 0 0 0-.5 .2 .43 .43 0 0 0 .1 .5l.5-.1v-.2h-.2"/>
<path d="M43.4 36.1h.2M43.4 39.5h.2M43.7 35.7h-.3v.8h.3M43.7 39.2h-.3v.8h.3M43.8 34h-.4l-.1 .2 .1 .6h.4M43.8 37.5l-.2-.1-.3 .2 .1 .6 .4-.1M44.1 35.8h.5v.2l-.5 .5h.5M44.1 39.3l.2-.1v.8M44.2 34v.8h.4M44.2 37.4v.8h.4M44.8 34.4l.5-.1v-.3h-.5v.8M44.8 37.4v.8"/>
<path d="M45 37.8l.3 .4M45.1 34.4l.2 .4M45.3 37.4l-.5 .5M45.6 35.6l-.8 1.1M45.6 39.1l-.8 1.1M45.7 37.6l.2-.2v.8M45.7 38.2h.5M45.8 39.2l.2 .8 .3-.8M46.3 35.7l-.5 .2v.5l.2 .1 .4-.1v-.2h-.2M46.6 39.9l.3 .1 .1-.2-.1-.4h-.3v.9M47.2 35.8l-.3-.1-.2 .2v.5l.2 .1 .3-.1M47.4 39.9l.2 .1 .2-.2-.1-.4h-.3v.9"/>
<path d="M47.5 35.7v.8h.5M48.3 35.7v.8M48.4 36l.3 .5M48.7 35.7l-.4 .5M49.1 35.8h.5v.2l-.5 .5h.5M50.2 30.7l1 .3-1 .3M50.3 29.9l-.1 .3 .3 .2h.4l.3-.2-.1-.3M50.3 29.1l-.1 .2 .3 .3h.4l.3-.3-.1-.2M52 30.7l.9 .3-.9 .3M52.1 29.9l-.1 .4 .2 .1h.4l.3-.2-.1-.3M52.1 29.1l-.1 .3 .2 .2h.4l.3-.3-.1-.2M55.4 31.9l.9 .3-.9 .3"/>
<path d="M55.4 29.9h.1M55.5 31.1l-.1 .3 .3 .2h.4l.2-.2v-.3M55.5 30.3l-.1 .2 .3 .3h.4l.2-.3v-.2M55.7 29.2l.6-.1v.2v.2h-.5zM55.7 29.9h.6M57.2 31.9l.8 .3-.8 .3M57.2 29.9h.1M57.3 31.1l-.1 .4 .2 .1h.5l.1-.2v-.3M57.3 30.3l-.1 .3 .2 .2h.5l.1-.3v-.2M57.4 29.9h.6M57.5 29.1h.5v.4h-.5zM58.9 31.9l.8 .3-.8 .3"/>
<path d="M58.9 29.9h.1M59 31.1l-.1 .3 .2 .2h.5l.1-.1-.1-.4M59 30.3l-.1 .2 .2 .3h.5l.1-.2-.1-.3M59.2 29.1h.4l.1 .3-.5 .1zM59.2 29.9h.5M60.6 31.9l.9 .3-.9 .3M60.6 29.9h.1M60.7 31.1l-.1 .3 .2 .2h.5l.2-.2-.1-.3M60.7 30.3l-.1 .2 .2 .3h.5l.2-.3-.1-.2M60.9 29.2l.5-.1 .1 .2-.1 .2h-.4zM60.9 29.9h.6M62.4 31.9l.8 .3-.8 .3"/>
<path d="M62.4 29.9h.1M62.4 31.1v.4l.1 .1h.5l.2-.2-.1-.3M62.4 30.3v.3l.1 .2h.5l.2-.3-.1-.2M62.6 29.9h.6M62.7 29.1h.4v.4h-.4zM64 31.9l.9 .3-.9 .3M64 29.9h.1M64.1 31.1l-.1 .3 .3 .2h.4l.2-.1-.1-.4M64.1 30.3l-.1 .2 .3 .3h.4l.2-.2-.1-.3M64.4 29.2l.4-.1 .1 .3-.4 .1zM64.4 29.9h.5M72.3 37.4v.8"/>
<path d="M72.3 39.2v.8M73.4 37.4l-.8 1.1M73.4 39.1l-.8 1.1M73.6 39.2h.5a.47 .47 0 0 1-.3 .8l-.2-.2zM73.8 37.4a.47 .47 0 0 1 .4 .3 .47 .47 0 0 1-.2 .5l-.4-.1v-.6zM41.1 40.8v.9M41.1 42.5v.9M41.1 44.3v.9M41.1 46v.9M41.1 47.7v.9M41.1 49.5v.8M41.1 51.2v.8"/>
<path d="M41.1 52.9v.8M41.1 54.6v.9M41.1 56.3v.9M41.1 58v1M41.1 59.8v.9M42.1 40.8l-.7 1.1M42.1 42.5l-.7 1.1M42.1 44.2l-.7 1.1M42.1 45.9l-.7 1.2M42.1 47.7l-.7 1.1M42.1 49.4l-.7 1.1M42.1 51.1l-.7 1.2"/>
<path d="M42.1 52.9l-.7 1.1M42.1 54.6l-.7 1.1M42.1 56.3l-.7 1.1M42.1 58l-.7 1.1M42.1 59.7l-.7 1.1M42.5 44.4h.5v.6l-.2 .2a.47 .47 0 0 1-.4-.3 .47 .47 0 0 1 .1-.5zM42.5 46.1h.5l-.1 .8-.4-.1zM42.5 49.6h.5v.6l-.2 .1a.47 .47 0 0 1-.4-.2 .47 .47 0 0 1 .1-.5zM42.5 51.3h.5l-.1 .7-.4-.1zM42.5 54.7h.5v.6l-.2 .2a.47 .47 0 0 1-.4-.3 .47 .47 0 0 1 .1-.5zM42.5 56.4h.5l-.1 .8-.4-.1zM42.5 59.9h.5v.6l-.2 .2a.47 .47 0 0 1-.4-.3 .47 .47 0 0 1 .1-.5z"/>
<path d="M42.5 40.8l.5 .1-.1 .8h-.4l-.1-.3zM42.6 42.5l.4 .2v.6h-.5a.52 .52 0 0 1 .1-.8zM42.6 47.7l.4 .2v.6h-.5a.52 .52 0 0 1 .1-.8zM42.6 52.9l.4 .1v.6h-.5a.52 .52 0 0 1 .1-.7zM42.6 58l.4 .2v.6l-.2 .2a.49 .49 0 0 1-.4-.4 .49 .49 0 0 1 .2-.6zM44 40.8l-.8 1.1M44 44.2l-.8 1.1M44.1 40h.5M44.2 44.3h.5M44.2 41.3h.5v-.4l-.5-.1v.9M44.4 44.3v.9M44.9 44.3h.4a.48 .48 0 0 1 .1 .6 .48 .48 0 0 1-.5 .3z"/>
<path d="M45.1 40.8h.3l.2 .2v.5l-.2 .2h-.3zM45.8 44.3v.9M45.9 41.1l.3-.3v.9M45.9 41.7h.5M67.3 51.2v.8M68.4 51.1l-.8 1.2M68.6 51.3h.5l.1 .5-.2 .2-.4-.1zM70.1 51.1l-.6 1.2M70.9 51.2h-.3l-.2 .3 .2 .5h.3l-.1-.3M71.8 51.3l-.4-.1-.2 .3 .2 .5 .4-.1M72.2 51.2v.8h.4M72.3 40.8v.9"/>
<path d="M72.3 42.5v.9M72.3 44.3v.9M72.3 46v.9M72.3 47.7v.9M72.3 49.5v.8M72.3 52.9v.8M72.3 54.6v.9M72.3 56.3v.9M72.3 58v1M72.3 59.8v.9M72.9 51.2v.8M73 51.5l.4 .5"/>
<path d="M73.4 40.8l-.8 1.1M73.4 42.5l-.8 1.1M73.4 44.2l-.8 1.1M73.4 45.9l-.8 1.2M73.4 47.7l-.8 1.1M73.4 49.4l-.8 1.1M73.4 51.2l-.5 .5M73.4 52.9l-.8 1.1M73.4 54.6l-.8 1.1M73.4 56.3l-.8 1.1M73.4 58l-.8 1.1M73.4 59.7l-.8 1.1"/>
<path d="M73.6 44.4h.5a.47 .47 0 0 1-.3 .8l-.2-.2zM73.6 46.1h.5l.1 .5-.2 .3-.4-.1zM73.6 49.6h.5a.47 .47 0 0 1-.3 .7l-.2-.1zM73.6 51.2h.6l-.3 .3h.2l.1 .2-.1 .3-.5-.1M73.6 54.7h.5a.47 .47 0 0 1-.3 .8l-.2-.2zM73.6 56.4h.5l.1 .5-.2 .3-.4-.1zM73.6 59.9h.5a.47 .47 0 0 1-.3 .8l-.2-.2zM73.7 40.8h.3l.2 .3-.2 .6-.4-.1zM73.8 42.5a.47 .47 0 0 1 .4 .4 .47 .47 0 0 1-.2 .5l-.4-.1v-.6zM73.8 47.7a.47 .47 0 0 1 .4 .3 .47 .47 0 0 1-.2 .6l-.4-.1v-.6zM73.8 52.9a.47 .47 0 0 1 .4 .3 .47 .47 0 0 1-.2 .5l-.4-.1v-.6zM73.8 58a.47 .47 0 0 1 .4 .5 .47 .47 0 0 1-.4 .5l-.2-.2v-.6z"/>
<path d="M41.1 61.5v.9M41.1 63.2v.9M41.1 65v.8M41.1 66.7v.8M41.1 68.4v.9M41.1 70.1v.9M41.1 71.8v.9M41.1 73.5v1M41.1 75.3v.9M41.1 77v.8M41.1 78.7v.9M42.1 61.5l-.7 1.1"/>
<path d="M42.1 63.2l-.7 1.1M42.1 64.9l-.7 1.1M42.1 66.7l-.7 1.1M42.1 68.4l-.7 1.1M42.1 70.1l-.7 1.1M42.1 71.8l-.7 1.1M42.1 73.5l-.7 1.1M42.1 75.2l-.7 1.1M42.1 77l-.7 1.1M42.1 78.7l-.7 1.1M42.5 61.6h.5l-.1 .8-.4-.1zM42.5 65.1h.5v.6l-.2 .1-.4-.2z"/>
<path d="M42.5 70.2h.5v.6l-.2 .2-.4-.3zM42.5 75.4h.5v.7h-.5zM42.6 63.2l.4 .2v.6l-.2 .1a.49 .49 0 0 1-.4-.4 .49 .49 0 0 1 .2-.5zM42.6 66.7l.4 .1-.1 .7h-.4l-.1-.2v-.4zM42.6 68.4l.4 .1v.6l-.2 .2a.49 .49 0 0 1-.4-.4 .49 .49 0 0 1 .2-.5zM42.6 71.8l.4 .2v.6h-.5a.52 .52 0 0 1 .1-.8zM42.6 73.5l.4 .2v.6l-.2 .2a.49 .49 0 0 1-.4-.4 .49 .49 0 0 1 .2-.6zM42.6 77l.4 .2v.6h-.5a.52 .52 0 0 1 .1-.8zM42.6 78.7l.4 .2v.6l-.2 .1a.49 .49 0 0 1-.4-.4 .49 .49 0 0 1 .2-.5zM44 61.5l-.8 1.1M44.2 61.5h.5M44.4 61.5v.9"/>
<path d="M44.9 62.4v-.9l.3 .6 .3-.6v.9M46.4 61.6l-.4-.1-.2 .2 .6 .4-.1 .3h-.5M69 68.4v.9M70.1 68.4l-.8 1.1M70.5 68.4l.3 .1v.6l-.1 .2-.4-.2v-.6zM71.8 68.4l-.7 1.1M72 68.4h.5M72.3 68.4v.9M72.3 61.5v.9M72.3 63.2v.9M72.3 65v.8M72.3 66.7v.8"/>
<path d="M72.3 70.1v.9M72.3 71.8v.9M72.3 73.5v1M72.3 75.3v.9M72.3 77v.8M72.3 78.7v.9M72.8 68.4h.2l.3 .2v.4l-.3 .3h-.2zM73.4 61.5l-.8 1.1M73.4 63.2l-.8 1.1M73.4 64.9l-.8 1.1M73.4 66.7l-.8 1.1M73.4 70.1l-.8 1.1"/>
<path d="M73.4 71.8l-.8 1.1M73.4 73.5l-.8 1.1M73.4 75.2l-.8 1.1M73.4 77l-.8 1.1M73.4 78.7l-.8 1.1M73.6 61.6h.5l.1 .5-.2 .3-.4-.1zM73.6 65.1l.4-.1 .2 .2v.4l-.2 .2-.4-.1zM73.6 70.2l.4-.1 .2 .3v.3l-.2 .3-.4-.2zM73.6 75.4h.5v.7h-.5zM73.8 63.2a.47 .47 0 0 1 .4 .5 .47 .47 0 0 1-.4 .4l-.2-.1v-.6zM73.8 66.7l.4 .2-.2 .6-.4-.1v-.6zM73.8 68.4a.47 .47 0 0 1 .4 .4 .47 .47 0 0 1-.4 .5l-.2-.2v-.6z"/>
<path d="M73.8 71.8a.47 .47 0 0 1 .4 .4 .47 .47 0 0 1-.2 .5l-.4-.1v-.6zM73.8 73.5a.47 .47 0 0 1 .4 .5 .47 .47 0 0 1-.4 .5l-.2-.2v-.6zM73.8 77a.47 .47 0 0 1 .4 .3 .47 .47 0 0 1-.2 .5h-.4v-.6zM73.8 78.7a.47 .47 0 0 1 .4 .5 .47 .47 0 0 1-.4 .4l-.2-.1v-.6zM41.1 80.5v.8M41.1 82.2v.8M41.1 83.9v.9M41.1 85.6v.9M41.1 87.3v.9M41.1 89.1v.9M41.1 90.8v.8M41.1 92.5v.8"/>
<path d="M41.1 94.3v.8M41.1 96v.8M41.1 97.7v.8M41.1 99.4v.9M42.1 80.4l-.7 1.1M42.1 82.2l-.7 1.1M42.1 83.9l-.7 1.1M42.1 85.6l-.7 1.1M42.1 87.3l-.7 1.1M42.1 89l-.7 1.1M42.1 90.7l-.7 1.2M42.1 92.5l-.7 1.1"/>
<path d="M42.1 94.2l-.7 1.1M42.1 95.9l-.7 1.2M42.1 97.7l-.7 1.1M42.1 99.4l-.7 1.1M42.5 80.6h.5l-.1 .7-.4-.1zM42.5 84h.5v.6l-.2 .2a.47 .47 0 0 1-.4-.3 .47 .47 0 0 1 .1-.5zM42.5 85.7h.5l-.1 .8-.4-.1zM42.5 89.2h.5v.6l-.2 .2a.47 .47 0 0 1-.4-.3 .47 .47 0 0 1 .1-.5zM42.5 90.9h.5l-.1 .7h-.4zM42.5 94.4h.5v.6l-.2 .1a.47 .47 0 0 1-.4-.3 .47 .47 0 0 1 .1-.4zM42.5 99.5h.5v.6l-.2 .2a.47 .47 0 0 1-.4-.3 .47 .47 0 0 1 .1-.5zM42.5 96l.5 .1-.1 .7h-.4l-.1-.2z"/>
<path d="M42.6 82.2l.4 .1v.6h-.5a.52 .52 0 0 1 .1-.7zM42.6 87.3l.4 .2v.6h-.5a.52 .52 0 0 1 .1-.8zM42.6 92.5l.4 .2v.6h-.5a.52 .52 0 0 1 .1-.8zM42.6 97.7l.4 .1v.6h-.5a.52 .52 0 0 1 .1-.7zM44 97.7l-.8 1.1M44.2 98.2l.5-.1v-.4h-.5v.8M45.1 97.7h.2l.3 .2v.4l-.2 .2h-.3zM45.9 97.7h.4l.1 .1-.5 .7h.5M69 85.6v.9M70.1 85.6l-.7 1.1M70.4 85.7l.4-.1v.9l-.4-.1zM71.9 85.6l-.7 1.1"/>
<path d="M72.1 85.6h.4M72.3 85.6v.9M72.3 80.5v.8M72.3 82.2v.8M72.3 83.9v.9M72.3 87.3v.9M72.3 89.1v.9M72.3 90.8v.8M72.3 92.5v.8M72.3 94.3v.8M72.3 96v.8M72.3 97.7v.8"/>
<path d="M72.3 99.4v.9M73.4 85.7l-.5-.1-.1 .4 .1 .5 .5-.1M73.4 80.4l-.8 1.1M73.4 82.2l-.8 1.1M73.4 83.9l-.8 1.1M73.4 87.3l-.8 1.1M73.4 89l-.8 1.1M73.4 90.7l-.8 1.2M73.4 92.5l-.8 1.1M73.4 94.2l-.8 1.1M73.4 95.9l-.8 1.2M73.4 97.7l-.8 1.1"/>
<path d="M73.4 99.4l-.8 1.1M73.6 80.6h.5l.1 .5-.2 .2-.4-.1zM73.6 84h.5a.47 .47 0 0 1-.3 .8l-.2-.2zM73.6 89.2h.5a.47 .47 0 0 1-.3 .8l-.2-.2zM73.6 90.9h.5l.1 .5-.2 .2h-.4zM73.6 94.4h.5a.47 .47 0 0 1-.3 .7l-.2-.1zM73.6 99.5h.5a.47 .47 0 0 1-.3 .8l-.2-.2zM73.7 96h.3l.2 .2-.2 .6-.4-.1zM73.7 85.6v.9M73.8 82.2a.47 .47 0 0 1 .4 .3 .47 .47 0 0 1-.2 .5l-.4-.1v-.6zM73.8 87.3a.47 .47 0 0 1 .4 .4 .47 .47 0 0 1-.2 .5l-.4-.1v-.6zM73.8 92.5a.47 .47 0 0 1 .4 .3 .47 .47 0 0 1-.2 .5h-.4v-.6z"/>
<path d="M73.8 97.7a.47 .47 0 0 1 .4 .3 .47 .47 0 0 1-.2 .5l-.4-.1v-.6zM73.8 86l.4 .5M74.2 85.6l-.5 .5M41.1 101.1v.9M41.1 102.8v1M41.1 104.6v.8M41.1 106.3v.8M41.1 108v.9M42.1 101.1l-.7 1.1M42.1 102.8l-.7 1.1M42.1 104.5l-.7 1.1M42.1 106.3l-.7 1.1"/>
<path d="M42.1 108l-.7 1.1M42.5 101.2h.5l-.1 .8-.4-.1zM42.5 104.7h.5v.6l-.2 .1a.47 .47 0 0 1-.4-.2 .47 .47 0 0 1 .1-.5zM42.5 106.4h.5l-.1 .7h-.4zM42.6 102.8l.4 .2v.6l-.2 .2a.49 .49 0 0 1-.4-.4 .49 .49 0 0 1 .2-.6zM42.6 108l.4 .2v.6l-.2 .1a.49 .49 0 0 1-.4-.4 .49 .49 0 0 1 .2-.5zM51.2 110.8v.3a.44 .44 0 0 0 .5 .1 .44 .44 0 0 0 .2-.5h-.3v.2M51.2 109.9h.8l-.8 .5h.8M51.2 109.1a.48 .48 0 0 1 .5-.1 .48 .48 0 0 1 .3 .4h-.8zM52.9 110.8v.3l.3 .2 .5-.2-.1-.4h-.2v.2M52.9 109.9h.8l-.8 .5h.8M52.9 109.1l.3-.2 .4 .1 .1 .4h-.8z"/>
<path d="M54.6 109.9h.8l-.8 .5h.8M54.6 110.8a.43 .43 0 0 0 .3 .5 .43 .43 0 0 0 .5-.2l-.1-.4h-.2v.2M54.6 109.1l.4-.2 .3 .1 .1 .4h-.8zM56.3 110.8v.3a.44 .44 0 0 0 .6 .1 .44 .44 0 0 0 .2-.5h-.3v.2M56.3 109.9h.9l-.9 .5h.9M56.3 109.1a.48 .48 0 0 1 .6-.1 .48 .48 0 0 1 .3 .4h-.9zM58 110.8v.3l.4 .2 .5-.2-.1-.4h-.3v.2M58 109.9h.9l-.9 .5h.9M58 109.1l.4-.2 .4 .1 .1 .4h-.9zM59.7 109.9h.9l-.9 .5h.9M59.8 110.8a.43 .43 0 0 0 .3 .5 .43 .43 0 0 0 .5-.2l-.1-.4h-.3v.2M59.8 109.1l.4-.2 .3 .1 .1 .4h-.9z"/>
<path d="M61.5 110.8v.3a.44 .44 0 0 0 .6 .1 .44 .44 0 0 0 .2-.5h-.4v.2M61.5 109.9h.9l-.9 .5h.9M61.5 109.1a.48 .48 0 0 1 .6-.1 .48 .48 0 0 1 .3 .4h-.9zM63.2 110.8v.3l.3 .2 .5-.2v-.4h-.3v.2M63.2 109.9h.8l-.8 .5h.8M63.2 109.1l.3-.2 .5 .1v.4h-.8zM72.3 101.1v.9M72.3 102.8v1M72.3 104.6v.8M73.4 101.1l-.8 1.1M73.4 102.8l-.8 1.1M73.4 104.5l-.8 1.1"/>
<path d="M73.6 101.2h.5l.1 .5-.2 .3-.4-.1zM73.6 104.7h.5a.47 .47 0 0 1-.3 .7l-.2-.1zM73.8 102.8a.47 .47 0 0 1 .4 .5 .47 .47 0 0 1-.4 .5l-.2-.2v-.6zM166.2 131.3l.3-.9 .3 .9M166.2 133l.3-.9 .3 .9M166.2 134.7l.3-.8 .3 .8M166.2 136.4l.3-.8 .3 .8M166.2 138.1l.3-.8 .3 .8M166.2 139.9l.3-.8 .3 .8M166.3 131h.4M166.3 132.7h.4M166.3 134.5h.4"/>
<path d="M166.3 136.2h.4M166.3 138h.4M166.3 139.7h.4M167 135.6h.6l-.3 .3h.2l.1 .2-.1 .3h-.5M167.1 132.4l.2-.3v.9M167.1 134l.4-.1 .1 .2-.6 .6h.6M167.1 133h.5M167.2 130.4a.42 .42 0 0 1 .4 .4 .42 .42 0 0 1-.4 .5zM167.3 137.3l-.2 .6h.5M167.5 139.1h-.4v.3l.3-.1 .2 .4-.2 .2-.3-.1M167.5 137.6v.5M170 131.9l.9 .2-.9 .3"/>
<path d="M170 131a.42 .42 0 0 0 .4 .6 .42 .42 0 0 0 .4-.6M170 130.2v.2l.2 .3 .6-.1v-.4M173.3 130.8h.3l.2-.1-.1-.3h-.4v.9l.5-.1v-.3l-.2-.1M173.3 132.5h.4l.1-.2-.2-.2h-.3v.9h.4l.1-.4-.2-.1M173.3 134.2h.4l.1-.2-.5-.1v.8h.5v-.4l-.2-.1M173.3 136h.3l.2-.2-.1-.2h-.4v.8h.5v-.3l-.2-.1M173.3 137.7h.4l.1-.2-.2-.2h-.3v.8h.4l.1-.3-.2-.1M173.3 139.4h.4v-.3h-.4v.8l.5-.1v-.3l-.2-.1M174.1 132.4l.3-.3v.9M174.1 134h.5l-.5 .7h.5M174.1 135.6h.5l-.3 .3h.2v.5h-.4M174.1 133h.5"/>
<path d="M174.3 130.4a.43 .43 0 0 1 .3 .4 .43 .43 0 0 1-.3 .5l-.2-.4zM174.3 137.3l-.2 .6h.5M174.5 139.1h-.3l-.1 .3 .4-.1 .1 .4-.1 .2-.4-.1M174.5 137.6v.5M166.2 141.6l.3-.8 .3 .8M166.2 143.3l.3-.9 .3 .9M166.2 146.8l.3-.9 .3 .9M166.3 141.3h.4M166.3 143.1h.4M166.3 146.5h.4M166.8 147.7l-.2-.1-.3 .3v.4l.2 .2h.3M167 142.4h.6l-.3 .9"/>
<path d="M167.1 146.4h.7M167.3 148h.2M167.5 140.8l-.4 .1v.6l.4 .1v-.5h-.3l-.1 .2M167.6 147.6h-.3v.9h.3M168.2 146.2l.7 .2-.7 .3M169.2 146.3h.3l.2-.1-.1-.3h-.4v.9l.5-.1v-.3l-.2-.1M170 147.4h.9l-.9 .5h.9M170 146.8l.2-.3h.4l.3 .3v.2h-.9zM170 148.3v.2l.2 .3h.4l.3-.3-.1-.2h-.3v.2M173.3 141.2h.3l.2-.2-.1-.2h-.4v.8h.4l.1-.3-.2-.1M173.3 142.9h.4l.1-.3-.2-.2h-.3v.9h.4l.1-.3-.2-.1M174.1 142.4h.5l-.3 .9"/>
<path d="M174.5 140.8h-.2l-.2 .3 .1 .5h.3v-.5h-.3l-.1 .2"/>
</g>
<path d="M102.9 79l.3 .2-.1 .1-.3-.1z" fill="#910000"/>
<path d="M99 79.2h.9M102.6 79.2h.5v1.7h-.5M103 79l.3 .2-.1 .2-.3-.2zM99.8 80.3h2.7v1.1h-2.7z" fill="none" stroke="#910000" stroke-width=".21"/>
<path d="M102.9 80.7l.3 .2-.1 .1-.3-.1z" fill="#910000"/>
<path d="M99 80.9h.9M99.8 82.1h2.7v1h-2.7zM102.6 80.9h.5v1.8h-.5M103 80.7l.3 .2-.1 .2-.3-.2z" fill="none" stroke="#910000" stroke-width=".21"/>
<path d="M102.9 82.4l.3 .2-.1 .2-.3-.2z" fill="#910000"/>
<path d="M99 82.7h.9M99.8 83.8h2.7v1h-2.7zM102.6 82.7h.5v1.7h-.5M103 82.5l.3 .2-.1 .2-.3-.2z" fill="none" stroke="#910000" stroke-width=".21"/>
<path d="M102.9 84.1l.3 .2-.1 .2-.3-.2z" fill="#910000"/>
<path d="M99 84.4h.9M99.8 85.5h2.7v1.1h-2.7zM102.6 84.4h.5v1.7h-.5M103 84.2l.3 .2-.1 .2-.3-.2z" fill="none" stroke="#910000" stroke-width=".21"/>
<path d="M102.9 85.8l.3 .2-.1 .2-.3-.2z" fill="#910000"/>
<path d="M99 86.1h.9M99.8 87.3h2.7v1h-2.7zM102.6 86.1h.5v1.7h-.5M103 85.9l.3 .2-.1 .1-.3-.1z" fill="none" stroke="#910000" stroke-width=".21"/>
<path d="M102.9 87.6l.3 .2-.1 .2-.3-.2z" fill="#910000"/>
<path d="M99 87.8h.9M99.8 89h2.7v1h-2.7zM102.6 87.8h.5v1.7h-.5M103 87.7l.3 .1-.1 .2-.3-.2z" fill="none" stroke="#910000" stroke-width=".21"/>
<path d="M102.9 89.3l.3 .2-.1 .2-.3-.2z" fill="#910000"/>
<g fill="none" stroke="#910000" stroke-width=".21">
<path d="M31.4 37h6.6l.6 .9-.6 .8h-6.6zM32.6 37.5h-.3l-.2 .1v.5l.2 .2 .3-.1M33.1 37.9h.3l.1-.4h-.4v.8M33.1 33.6h4.9l.6 .8-.6 .9h-4.9zM33.8 33.7h3.7M33.9 37.5l.1 .8h.3v-.8M34 34.5l.4-.1-.1-.4h-.3v.8M34.2 34.5l.2 .3M34.6 38.4h.7M34.8 34.4h.3M35.3 34h-.5v.8h.5M35.9 37.5h-.3l-.2 .1v.5l.2 .2 .3-.1"/>
<path d="M36 34.1h-.4v.2l.4 .3-.1 .2h-.3M36.3 37.5v.8h.4M36.4 34.4h.3M36.9 34h-.5v.8h.5M37 34h.5M37 37.5v.8M37.1 37.8l.4 .5M37.3 34v.8M37.5 37.5l-.5 .5M50.8 26.6h.1M50.8 24.9l-.6 .9M50.8 24.9l.5 .9"/>
<path d="M50.8 24.9v1.7M77.4 37h3.3l.7 .9-.7 .8h-3.3zM77.9 37.5l.3 .8 .3-.8M77.9 37.2h2.1M78.8 37.9h.4v-.4h-.4v.8M79.5 38.3l.3-.8 .3 .8M79.6 38.1h.4M115.5 37h3.4l.8 .9-.8 .8h-3.4l-.7-.8zM115.5 35.3h3.4l.8 .8-.8 .9h-3.4l-.7-.9zM115.5 33.6h3.4l.8 .8-.8 .9h-3.4l-.7-.9zM115.5 38.7h3.4l.8 .9-.8 .8h-3.4l-.7-.8zM116.3 30.1h2.6l.8 .8-.8 1h-2.6l-.8-1z"/>
<path d="M116.3 37.5h.3l.2 .1v.5l-.2 .2h-.3zM116.3 31.9h2.6l.8 .8-.8 .9h-2.6l-.8-.9zM116.3 35.8h.3l.2 .1v.5l-.3 .2h-.2zM116.3 34h.2l.3 .2v.5l-.2 .1h-.3zM116.3 39.2h.2l.3 .2v.4l-.2 .2h-.3zM117.1 30.6h.4a.48 .48 0 0 1 .1 .6 .48 .48 0 0 1-.5 .3zM117.1 37.7l.3-.2v.8M117.1 32.3l.5 .1v.4l-.1 .3h-.4zM117.1 35.9l.3-.1v.8M117.1 34.2l.3-.2v.8M117.1 39.4l.3-.2v.8M117.1 38.3h.5"/>
<path d="M117.1 36.6h.5M117.1 34.8h.5M117.9 39.2h.6l-.4 .3 .4 .2v.2h-.6M118 37.5h.4l.1 .2-.6 .6h.6M118 35.9l.2-.1v.8M118 36.6h.5M118.1 30.9l-.1-.2 .4-.1 .1 .2-.2 .1-.3 .1v.4l.1 .1 .4-.2-.2-.4M118.1 34a.43 .43 0 0 1 .4 .5 .43 .43 0 0 1-.4 .3l-.1-.6zM118.5 32.6l-.1 .2h-.3l-.1-.4 .4-.1 .1 .2-.2 .6h-.2M22.3 43.9h7l.8 .8-.8 .9h-7zM23.2 44.3v.9M23.7 44.3h.1a.52 .52 0 0 1 .1 .9l-.3-.1a.52 .52 0 0 1 .1-.8z"/>
<path d="M24.9 44.4l-.2-.1-.3 .3v.4l.2 .2h.3M25.2 44.3h.5M25.4 44.3v.9M25.9 44.3v.9h.5M26.5 45.3h.6M27.2 44.3h.5M27.5 44.3v.9M28 44.3a.49 .49 0 0 1 .4 .3 .49 .49 0 0 1-.1 .6h-.3zM28.8 44.3v.9M29.6 40.4h9v1.8h-9l-.7-.9zM30.2 49.1h3.5l.7 .8-.7 .9h-3.5zM30.3 40.9v.9"/>
<path d="M30.8 41h.5v.6l-.2 .2a.47 .47 0 0 1-.4-.3 .47 .47 0 0 1 .1-.5zM30.9 49.3h2.3M30.9 49.5v.7l.2 .2 .4-.1v-.8M31.2 45.6h2.5l.7 .8-.7 1h-2.5zM31.9 46.9l.2-.8 .4 .8M31.9 49.5a.47 .47 0 0 1 .5 .5 .47 .47 0 0 1-.5 .4zM31.9 45.8h1.3M32 46.7h.4M32.1 41l-.3-.1-.2 .2v.4l.3 .3 .2-.1M32.4 40.9h.5M32.6 40.9v.9M33.1 46.1l-.4 .1v.2l.4 .2v.3h-.4"/>
<path d="M33.1 49.6h-.4v.2l.4 .3v.3l-.4-.1M33.1 40.9v.9h.5M33.7 41.9h.6M34.2 47.4h3.8l.6 .8-.6 .9h-3.8zM34.5 40.9h.3l.2 .2v.4l-.2 .3h-.3zM34.6 55.9h3.4l.6 1-.6 .8h-3.4zM34.6 57.7h3.4l.6 .8-.6 .9h-3.4zM34.6 54.2h3.4l.6 .9-.6 .8h-3.4zM34.7 50.8h3.3l.6 .9-.6 .8h-3.3zM35 59.4h3.6v1.7h-3.6l-.8-.9zM35.1 48.2h.4l.1-.3-.5-.1v.8M35.3 40.9h.5"/>
<path d="M35.3 48.2l.3 .4M35.3 51h2.2M35.4 56.9h.3M35.4 58.5h.3M35.4 55.1h.3M35.5 51.3v.8h.4M35.5 40.9v.9M35.7 59.8v.9M35.9 56.4h-.5v.9M35.9 58.1h-.5v.9M35.9 54.6h-.5v1M35.9 41.8l.3-.9 .3 .9"/>
<path d="M36 41.5h.4M36.2 51.3h.3a.47 .47 0 0 1 .2 .5 .47 .47 0 0 1-.5 .3zM36.6 47.8l-.7 1.1M36.7 56.5l-.4-.1a.44 .44 0 0 0-.1 .6 .44 .44 0 0 0 .5 .2M36.7 58.2a.44 .44 0 0 0-.6 .2 .44 .44 0 0 0 .2 .6l.4-.1M36.7 54.7a.42 .42 0 0 0-.6 .4 .42 .42 0 0 0 .6 .4M36.8 47.8l.2 .8 .1-.6 .2 .6 .2-.8M36.8 47.5h.7M37 59.8v.9h.4M37 56.7l.2-.3v.9M37 58.2h.5v.3l-.5 .5h.5M37 54.7l.3-.1 .2 .2v.6l-.2 .2-.3-.1z"/>
<path d="M37 57.3h.5M37.3 41l-.4-.1a.44 .44 0 0 0-.1 .6 .44 .44 0 0 0 .5 .2M37.5 51.3h-.5v.3l.5 .2v.2h-.5M37.6 40.9v.9M37.7 59.9l.2-.1a.59 .59 0 0 1 .1 .9 .53 .53 0 0 1-.3-.8zM37.8 41.3l.3 .5M38.1 40.9l-.5 .5M77.3 47.4h3.9v1.7h-3.9l-.7-.9zM77.3 43.9h3.9v1.7h-3.9l-.7-.9zM77.7 47.5h2.9M77.7 44.1h2.9M77.8 44.3v.9"/>
<path d="M77.8 47.8v.8M78.3 48.2l.4-.1-.1-.3h-.3v.8M78.3 44.8l.4-.1v-.3l-.4-.1v.9M78.4 48.2l.3 .4M78.4 44.8l.3 .4M79.1 47.9h.5l-.1 .7h-.4zM79.1 44.5l.2-.2 .3 .2-.1 .7-.4-.1zM79.2 48.5l.5 .2M79.2 45l.5 .3M80.1 47.8l-.1 .6h.5M80.4 44.3l-.4 .3v.6l.5-.1-.2-.4-.3 .1M80.4 48v.6"/>
<path d="M86 49.1h3.9v1.7h-3.9l-.8-.9zM86 45.6h3.9v1.8h-3.9l-.8-1zM86 42.2h3.9v1.7h-3.9l-.8-.9zM86.3 49.3h2.8M86.3 45.8h2.8M86.3 42.4h2.8M86.4 42.6v.9M86.4 46.1v.8M86.4 49.5v.9M86.8 50l.5-.1v-.3l-.5-.1v.9M86.8 46.5h.4l.1-.3-.5-.1v.8M86.8 43h.4l.1-.3-.5-.1v.9"/>
<path d="M87.1 50l.2 .4M87.1 46.5l.2 .4M87.1 43l.2 .5M87.8 49.6v-.1a.47 .47 0 0 1 .5 .5 .47 .47 0 0 1-.5 .4l-.1-.3zM87.8 46.1l.4 .1a.47 .47 0 0 1-.4 .7l-.1-.3zM87.8 42.6h.3l.2 .3-.2 .6h-.3zM87.8 50.2l.5 .2M87.8 46.7l.5 .3M87.8 43.3l.5 .3M88.5 49.5h.6l-.3 .3 .3 .2v.2l-.2 .2-.4-.1M88.5 42.6h.6l-.3 .9M89 46.1h-.4v.4l.4-.1 .1 .4-.2 .1h-.3"/>
<path d="M98 58.5h7v6.9h-7zM101.6 56.9h.1M101.6 55.1l-.6 .8M101.6 55.1l.5 .8M101.6 55.1v3.4M115.5 40.4h3.4l.8 .9-.8 .9h-3.4l-.7-.9zM115.5 42.2h3.4l.8 .8-.8 .9h-3.4l-.7-.9zM115.7 47.4h3.2l.8 .8-.8 .9h-3.2zM115.7 50.8h3.2l.8 .9-.8 .8h-3.2zM115.7 45.6h3.2l.8 .8-.8 1h-3.2zM115.7 49.1h3.2l.8 .8-.8 .9h-3.2zM116.3 40.9h.3l.2 .2v.4l-.3 .3h-.2z"/>
<path d="M116.3 42.6h.3l.2 .2v.5l-.2 .2h-.3zM116.4 47.8l.3 .8 .3-.8M116.4 51.3l.3 .8 .3-.8M116.4 46.1l.3 .8 .3-.8M116.4 49.5l.3 .9 .3-.9M117.1 41.2l.3-.3v.9M117.1 42.9l.3-.3v.9M117.1 48.6l.3-.8 .3 .8M117.1 52.1l.3-.8 .3 .8M117.1 46.9l.3-.8 .3 .8M117.1 50.4l.3-.9 .3 .9M117.1 40h.5"/>
<path d="M117.1 41.8h.5M117.1 43.5h.5M117.2 48.4h.4M117.2 51.9h.4M117.2 46.7h.4M117.2 50.2h.4M117.9 49.5h.6l-.4 .3 .4 .2v.2l-.2 .2-.4-.1M118 47.9l.4-.1 .1 .2-.6 .6h.6M118 46.4l.2-.3v.8M118 46.9h.5M118.1 40.8l-.1 .6h.5M118.1 51.6l-.1-.3h.4v.3l-.4 .1v.3l.1 .1 .4-.2-.2-.3"/>
<path d="M118.4 42.6h-.4v.4h.4l.1 .1-.1 .4-.4-.1M118.4 41.2v.6M25.9 61.1h3.4l.8 .9-.8 .9h-3.4zM26.6 61.6h.5M26.9 61.6v.8M27.5 62.4v-.8l.2 .6 .3-.6v.8M28.9 61.6l-.5 .1v.2l.5 .3-.2 .2h-.3M34.5 69.7h3.5l.6 .9-.6 .8h-3.5zM34.5 71.4h3.5l.6 .9-.6 .9h-3.5zM34.5 78.4h3.5l.6 .8-.6 .8h-3.5zM34.5 76.7h3.5l.6 .8-.6 .9h-3.5zM34.5 74.9h3.5l.6 .8-.6 1h-3.5z"/>
<path d="M34.5 73.2h3.5l.6 .8-.6 .9h-3.5zM35 62.9h3.6v1.7h-3.6l-.8-.9zM35 64.6h3.6v1.6h-3.6l-.8-.8zM35.3 66.2h2.7l.6 1-.6 .8h-2.7zM35.3 68h2.7l.6 .9-.6 .8h-2.7zM35.3 70.1a.47 .47 0 0 1 .6 .5 .47 .47 0 0 1-.6 .5zM35.3 71.9l.5 .1 .1 .4-.2 .4h-.4zM35.3 78.8a.48 .48 0 0 1 .5 .3 .48 .48 0 0 1-.1 .5h-.4zM35.3 77.1l.5 .1 .1 .4-.2 .3h-.4zM35.3 75.4h.4a.48 .48 0 0 1 .1 .5 .48 .48 0 0 1-.5 .3zM35.3 73.6a.48 .48 0 0 1 .5 .3 .48 .48 0 0 1-.1 .6h-.4zM35.7 63.3v.8"/>
<path d="M35.7 65v.9M36.1 60.3l.5-.1v-.3l-.5-.1v.9M36.1 63.7h.4l.1-.3-.5-.1v.8M36.1 65.5l.5-.1v-.3l-.5-.1v.9M36.2 66.8h.3a.47 .47 0 0 1 .2 .5 .47 .47 0 0 1-.5 .3zM36.2 68.4a.49 .49 0 0 1 .4 .4 .49 .49 0 0 1-.1 .5h-.3zM36.2 70.4l.2-.3v1M36.2 72.2l.2-.3v.9M36.2 79l.2-.2v.8M36.2 77.3l.2-.2v.8M36.2 75.6l.2-.2v.8M36.2 73.9l.2-.3v.9"/>
<path d="M36.2 71.1h.5M36.2 72.8h.5M36.2 79.6h.5M36.2 77.9h.5M36.2 76.2h.5M36.2 74.5h.5M37 63.3v.8h.4M37 65v.9h.4M37 75.4h.5l-.3 .2 .3 .1v.5h-.5M37 70.2l.3-.1 .2 .2v.6l-.2 .2-.3-.1zM37 72.2l.2-.3v.9M37 73.7h.5v.3l-.5 .5h.5"/>
<path d="M37 72.8h.5M37.1 67.1l-.1-.3h.5l-.1 .3-.4 .1 .1 .4 .4-.1v-.3l-.2-.1M37.2 77l-.2 .7h.5M37.4 77.3v.6M37.5 68.9l-.5 .1 .1-.6 .4 .1v.6l-.5 .2M37.5 78.8h-.5v.4h.5l-.1 .4-.4-.1M37.6 63.5l.3-.2v.8M37.6 65.1l.4-.1 .1 .1-.5 .8h.5M37.6 64.1h.5M77.4 66.2h5.7l.8 1-.8 .8h-5.7zM77.9 66.5h4.6M78 67.2h.4"/>
<path d="M78.4 66.8h-.4v.8h.4M78.8 66.8l.5 .8M79.3 66.8l-.5 .8M79.6 67.2h.4l.1-.4h-.5v.8M81 66.8h-.5v.3l.5 .2-.2 .3-.3-.1M81.3 67.2h.3M81.7 66.8h-.4v.8h.4M81.7 68h8.5l.8 .9-.8 .8h-8.5zM82.1 66.8v.8h.4M82.3 69.3v-.9l.4 .6 .2-.6v.9M83.4 68.9h.2M83.8 68.4h-.4v.9h.4"/>
<path d="M84.1 69.3v-.9l.3 .6 .3-.6v.9M85.6 68.5a.43 .43 0 0 0-.5 .3 .43 .43 0 0 0 .1 .5l.4-.1M85.8 68.4h.5M86.1 68.4v.9M86.7 68.4v.9h.3M87.1 69.4h.7M87.8 68.4h.5M88.1 68.4v.9M88.6 68.4h.3l.2 .3v.4l-.2 .2h-.3zM89.4 68.4v.9M96.4 62h1.7M98.1 79.2h.9"/>
<path d="M100.3 62.4h.4v-.9h.4v.9h.5v-.9h.4v.9M101.6 67.2v.8h.8l-.8 .9-.9-.9h.9M101.6 67.2h.1M101.6 65.4v1.8M103.2 79.2h1.8M105 79.2h.1M105 77.5l-.5 .9M105 77.5l.5 .9M105 77.5v1.7M105 62h1.7M30.3 99h3.4l.7 .9-.7 .8h-3.4zM31.9 99.5l.3-.1 .2 .3-.6 .7h.6"/>
<path d="M33.1 99.4l-.4 .3v.6h.4v-.5l-.4 .1M33.9 95.5h4.1l.6 .9-.6 .9h-4.1zM33.9 97.3h4.1l.6 .9-.6 .8h-4.1zM34.6 96.1l.3 .8 .3-.8M34.6 97.7l.3 .9 .3-.9M34.8 93.8h3.2l.6 .9-.6 .8h-3.2zM34.8 92.2h3.2l.6 .8-.6 .8h-3.2zM34.8 87h3.2l.6 .8-.6 .9h-3.2zM34.8 88.7h3.2l.6 .8-.6 .9h-3.2zM34.8 90.4h3.2l.6 .8-.6 1h-3.2zM34.8 80h3.2l.6 .9-.6 .9h-3.2zM34.8 85.2h3.2l.6 .9-.6 .9h-3.2z"/>
<path d="M34.8 83.5h3.2l.6 .9-.6 .8h-3.2zM34.8 81.8h3.2l.6 .9-.6 .8h-3.2zM35.3 96.9l.4-.8 .2 .8M35.3 98.6l.4-.9 .2 .9M35.4 94.3l.3 .9 .3-.9M35.4 92.6l.3 .8 .3-.8M35.4 87.4l.3 .9 .3-.9M35.4 89.1l.3 .9 .3-.9M35.4 90.9l.3 .8 .3-.8M35.4 80.6l.3 .8 .3-.8M35.4 85.7l.3 .9 .3-.9M35.4 83.9l.3 .9 .3-.9"/>
<path d="M35.4 82.3l.3 .8 .3-.8M35.4 96.6h.5M35.4 98.3h.5M36.2 96.3l.2-.2v.8M36.2 98l.2-.3v.9M36.2 95.2l.2-.9 .4 .9M36.2 93.4l.2-.8 .4 .8M36.2 88.3l.2-.9 .4 .9M36.2 90l.2-.9 .4 .9M36.2 91.7l.2-.8 .4 .8M36.2 81.4l.2-.8 .4 .8M36.2 86.6l.2-.9 .4 .9"/>
<path d="M36.2 84.8l.2-.9 .4 .9M36.2 83.1l.2-.8 .4 .8M36.2 96.9h.5M36.2 98.6h.5M36.3 95h.4M36.3 93.2h.4M36.3 88h.4M36.3 89.8h.4M36.3 91.5h.4M36.3 81.1h.4M36.3 86.3h.4M36.3 84.6h.4"/>
<path d="M36.3 82.8h.4M37 90.9h.5l-.4 .8M37 83.9h.5l-.3 .4 .3 .1v.3h-.5M37 96.1h.4l.1 .1v.5l-.2 .2-.3-.1zM37 98l.2-.3v.9M37 80.7l.2-.1v.8M37 82.3h.4l.1 .3-.5 .5h.5M37 98.6h.5M37 81.4h.5M37.1 92.9l-.1-.3h.4l.1 .2-.5 .2v.4l.5-.1v-.3l-.2-.1M37.2 85.6l-.2 .6h.5M37.4 89.1l-.4 .3v.6h.5v-.5l-.4-.1-.1 .2"/>
<path d="M37.4 86v.6M37.5 94.7l-.2 .2-.3-.1 .1-.5 .4 .1v.6l-.5 .2M37.5 87.4h-.5v.4h.5l-.1 .5-.4-.1M88.3 80h3.9l.7 .9-.7 .9h-3.9zM88.3 83.5h3.9l.7 .9-.7 .8h-3.9zM89 80.3h2.8M89 83.7h2.8M89.1 80.6v.8M89.1 83.9v.9M89.5 81h.4l.1-.2v-.2h-.5v.8M89.5 84.5h.4l.1-.4-.1-.2h-.4v.9M89.7 81l.3 .4"/>
<path d="M89.7 84.5l.3 .3M90.4 80.6h.5a.47 .47 0 0 1-.4 .8l-.1-.2zM90.4 84.1l.1-.2a.42 .42 0 0 1 .5 .5 .42 .42 0 0 1-.5 .4l-.1-.1zM90.5 81.1l.5 .4M90.5 84.6l.5 .3M91.5 80.5l-.3 .6h.6M91.6 83.9l-.2 .1-.2 .6 .1 .2 .4-.1v-.3l-.3-.1-.2 .2M91.6 80.8v.6M93.4 85.2h4l.7 .9-.7 .9h-4zM94.2 85.5h2.8M94.3 85.7v.9M94.7 86.1h.3l.2-.1-.1-.3h-.4v.9"/>
<path d="M94.9 86.1l.3 .5M95.5 85.8h.6a.47 .47 0 0 1-.4 .8l-.2-.2zM95.7 86.3l.4 .4M96.4 85.7h.6l-.4 .9M98.1 89.5h1.8M98.1 91.2h1.8M98.1 80.9h.9M98.1 82.7h.9M98.1 84.4h.9M98.1 86.1h.9M98.1 87.8h.9M99.8 90.7h2.7v1.1h-2.7z"/>
<path d="M102.6 89.5h.5v1.7h-.5M103 89.3l.3 .2-.1 .2-.3-.2zM24.4 102.5h4.1l.7 .8-.7 .9h-4.1zM24.4 105.9h4.1l.7 .9-.7 .9h-4.1zM24.4 104.2h4.1l.7 .8-.7 .9h-4.1zM24.4 107.7h4.1l.7 .8-.7 .8h-4.1zM25.2 102.9l.2 .9 .3-.9M25.2 106.4l.2 .8 .3-.8M25.2 104.6l.2 .9 .3-.9M25.2 108.1l.2 .8 .3-.8M25.9 103.8l.3-.9 .3 .9M25.9 107.2l.3-.8 .3 .8"/>
<path d="M25.9 105.5l.3-.9 .3 .9M25.9 108.9l.3-.8 .3 .8M25.9 103.5h.5M25.9 107h.5M25.9 105.3h.5M25.9 108.7h.5M26.7 103.2l.3-.3v.9M26.7 106.6l.3-.2v.8M26.7 104.9l.3-.3v.9M26.7 108.3l.3-.2v.8M26.7 103.8h.5M26.7 107.2h.5"/>
<path d="M26.7 105.5h.5M26.7 108.9h.5M27.5 104.6h.6l-.4 .9M27.7 106.7l-.1-.2 .3-.1 .1 .2-.4 .2v.3l.1 .1 .3-.1v-.3l-.2-.1M27.9 102.9l-.3 .2v.6h.4l-.1-.5h-.3v.2M28 108.4l-.1 .2h-.3v-.4h.4v.6l-.4 .1M30.3 100.7h3.4l.7 .9-.7 .9h-3.4zM31 100.4l.4-1 .2 1M31 102.1l.4-.9 .2 .9M31.1 100.1h.4M31.1 101.8h.4M31.9 101.3l.4-.1 .1 .3-.6 .6h.6"/>
<path d="M32.6 101.2h.6l-.3 .9M51.6 113.7v.8h.8l-.8 .9-.8-.9h.8M51.6 113.7h.1M80 104.2h5.1v1.7h-5.1l-.8-.9zM80.4 104.6v.9M81.3 104.6v.9l-.5-.9v.9M81.6 104.6h.5M81.8 104.6v.9M82.2 105.6h.6M83 105h.4M83.4 104.6h-.4v.9h.4M84.3 104.6v.9l-.5-.9v.9"/>
<path d="M95.5 107.7h3.5M95.5 109.3h3.5M95.5 111h3.5M95.5 112.8h3.5M95.5 114.5h3.5M95.5 116.2h3.5M95.5 118h3.5M95.5 119.7h3.5M99 105.8h10.3v20.8h-10.3zM104.2 102.5h.1M104.2 100.7l-.5 .9M104.2 100.7l.5 .9"/>
<path d="M104.2 100.7v5.2M104.6 115.4h-.8v1.7M105 115.4h-.4v1.7h-1.4M109.3 107.7h3.4M109.3 109.3h3.4M109.3 111h3.4M109.3 112.8h3.4M109.3 114.5h3.4M109.3 116.2h3.4M109.3 118h3.4M109.3 119.7h3.4M113.5 106.8h2.6l.8 .9-.8 .8h-2.6l-.8-.8z"/>
<path d="M113.5 112h2.6l.8 .8-.8 .9h-2.6l-.8-.9zM113.5 110.2h2.6l.8 .8-.8 1h-2.6l-.8-1zM113.5 108.5h2.6l.8 .8-.8 .9h-2.6l-.8-.9zM113.5 118.8h2.6l.8 .9-.8 .8h-2.6l-.8-.8zM113.5 113.7h2.6l.8 .8-.8 .9h-2.6l-.8-.9zM113.5 117.1h2.6l.8 .9-.8 .8h-2.6l-.8-.8zM113.5 115.4h2.6l.8 .8-.8 .9h-2.6l-.8-.9zM114 107.2l.4 .1 .1 .4-.2 .4h-.3zM114 112.4l.4 .1 .1 .4-.2 .3h-.3zM114 110.7h.3a.48 .48 0 0 1 .2 .5 .48 .48 0 0 1-.5 .3zM114 108.9a.49 .49 0 0 1 .5 .3 .49 .49 0 0 1-.2 .6h-.3zM114 119.2a.47 .47 0 0 1 .5 .5 .47 .47 0 0 1-.5 .5z"/>
<path d="M114 114.1a.49 .49 0 0 1 .5 .3 .49 .49 0 0 1-.2 .5h-.3zM114 117.6h.4l.1 .5-.2 .3h-.3zM114 115.9h.3a.48 .48 0 0 1 .2 .5 .48 .48 0 0 1-.5 .3zM114.8 112.4h.6l-.4 .3h.3v.5h-.5M114.8 119.2h.6l-.4 1M114.8 110.8l.5-.1 .1 .3-.6 .5h.6M114.8 109.2l.3-.3v.9M114.8 109.8h.6M114.9 107.2a.42 .42 0 0 1 .5 .5 .42 .42 0 0 1-.5 .4zM115 114.1l-.2 .6h.6M115.3 117.6l-.5 .1v.6l.5 .1v-.5h-.4l-.1 .2M115.3 115.9h-.5v.3h.5l.1 .3-.2 .2-.4-.1"/>
<path d="M115.3 114.4v.5M56.8 138.6h.1M56.8 136.9l-.5 .9M56.8 136.9l.5 .9M56.8 136.9v4.3M91.1 122.3h3.7l.7 .8-.7 .9h-3.7zM92 123.1h.3l.1-.3-.4-.1v.9M92.2 123.1l.2 .5M93.4 122.7l-.7 1.1M93.6 122.7l.2 .9 .2-.6 .2 .6 .2-.9M93.6 122.5h.8M95.5 123.1h3.5"/>
<path d="M95.5 124.8h2.6M104.2 130v.8h.8l-.8 1-1-1h1M104.2 130h.1M104.2 126.6v3.4M42.3 156.8h3.4l.7 .8-.7 .9h-3.4l-.8-.9zM42.3 155h3.4l.7 .8-.7 1h-3.4l-.8-1zM42.3 151.6h3.4l.7 .8-.7 .9h-3.4l-.8-.9zM42.3 153.3h3.4l.7 .8-.7 .9h-3.4l-.8-.9zM42.3 158.5h3.4l.7 .8-.7 .8h-3.4l-.8-.8zM42.3 149.8h3.4l.7 .9-.7 .9h-3.4l-.8-.9zM42.5 143h3.2l.7 .8-.7 .8h-3.2zM43.1 157.2l.5 .1-.1 .7h-.4z"/>
<path d="M43.1 155.5l.5 .1v.6l-.3 .1h-.2zM43.1 152l.5 .1-.1 .8h-.4zM43.1 153.7l.5 .2-.1 .7h-.4zM43.1 158.9l.5 .1-.1 .7h-.4zM43.1 150.3l.5 .1v.6l-.3 .2h-.2zM43.1 146.4h2.6l.7 .9-.7 .8h-2.6l-.7-.8zM43.1 148.1h2.6l.7 .9-.7 .8h-2.6l-.7-.8zM43.2 143.4l.3 .8 .2-.8M43.9 157.4l.3-.2v.8M43.9 155.7l.3-.2v.8M43.9 152.3l.3-.3v.9M43.9 154l.3-.3v.9"/>
<path d="M43.9 159.1l.3-.2v.8M43.9 150.5l.3-.2v.9M43.9 146.9h.3l.2 .1v.5l-.2 .2h-.3zM43.9 144.2l.3-.8 .3 .8M43.9 148.5h.3l.2 .3v.4l-.2 .2h-.3zM43.9 158h.5M43.9 156.3h.5M43.9 152.9h.5M43.9 154.6h.5M43.9 159.7h.5M43.9 151.2h.5M44 144h.4"/>
<path d="M44.7 155.5h.6l-.4 .2 .4 .2v.3l-.2 .1-.4-.1M44.7 152.3l.3-.3v.9M44.7 153.8l.4-.1 .2 .2-.6 .7h.6M44.7 143.6l.3-.2v.8M44.7 152.9h.6M44.7 144.2h.6M44.9 157.1l-.2 .7h.6M44.9 150.3h.2a.48 .48 0 0 1 .2 .5 .48 .48 0 0 1-.4 .4 .6 .6 0 0 1 0-.9zM44.9 147.2l-.2-.2 .1-.1h.4v.3l-.5 .2 .1 .3h.4l.1-.3-.2-.2M45.2 158.9h-.4l-.1 .4 .4-.1 .2 .4h-.6M45.2 157.4v.6M45.3 149l-.2 .1-.4-.1 .2-.5 .4 .2v.4l-.2 .3h-.3"/>
<path d="M46.4 143.8h2.7M46.4 147.3h2.7M46.4 149h2.7M46.4 150.7h2.7M46.4 152.4h2.7M46.4 154.1h2.7M46.4 155.8h2.7M46.4 157.6h2.7M46.4 159.3h2.7M49 141.1h15.5v29.3h-15.5zM64.6 147.3h2.5M64.6 150.7h2.5"/>
<path d="M68.2 142.6h1.1v2.3h-1.1zM68.9 142.1h.1M68.9 140.3l-.6 .9M68.9 140.3l.5 .9M68.9 140.3v2.3M68.9 145v.5M71.3 146.4h3.3l.8 .9-.8 .8h-3.3l-.7-.8zM72.3 146.9h-.5v.1l.5 .4-.1 .3h-.4M72.6 146.9h.3l.2 .1v.5l-.2 .2h-.3zM73.4 147.7l.2-.8 .4 .8M73.4 147.4h.5M77.7 142.6h1.1v2.3h-1.1z"/>
<path d="M77.7 159.8h1.1v2.4h-1.1zM78.3 142.1h.1M78.3 159.3h.1M78.3 140.3l-.5 .9M78.3 140.3l.6 .9M78.3 140.3v2.3M78.3 145v.5M78.3 157.6v2.2M78.3 157.6l-.5 .9M78.3 157.6l.6 .9M80 149.8h3.4l.6 .9-.6 .9h-3.4zM81.1 150.3h-.5v.2l.5 .3v.3h-.5"/>
<path d="M81.9 150.4l-.3-.1a.43 .43 0 0 0-.2 .5 .43 .43 0 0 0 .5 .3M82.3 150.3v.9h.5M101.6 146.4h1.6M101.6 148.1h1.6M101.6 153.3h1.6M103.2 144.6h13.8v10.3h-13.8zM108.4 143v1.6M110.2 156.8v.8h.8l-.8 .9-.9-.9h.9M110.2 156.8h.1M110.2 143v1.6M110.2 155v1.8M117 146.4h1.8"/>
<path d="M117 151.6h1.8M33.9 167.1h6.6l.8 .8-.8 .9h-6.6zM35.3 167.6a.44 .44 0 0 0-.7 .1 .44 .44 0 0 0 .2 .7l.5-.1M35.6 167.9h.4l.1-.2-.2-.2h-.3v.9M36.4 163.6h4.9v1.7h-4.9l-.8-.8zM36.4 167.5l.1 .9 .5-.1v-.8M37 163.9h3.8M37.1 164a.47 .47 0 0 1 .5 .5 .47 .47 0 0 1-.5 .5zM37.1 168.4h.7M37.9 164h.4M38.1 164v1M38.5 167.6a.42 .42 0 0 0-.5 .2 .42 .42 0 0 0 .1 .6l.4-.1"/>
<path d="M38.5 165l.3-1 .3 1M38.6 164.7h.4M38.9 167.5v.9h.4M39.6 167.5v.9M39.7 167.8l.4 .6M39.8 164.1l-.2-.1-.3 .3v.4l.3 .3 .2-.1M40.1 167.5l-.5 .5M40.3 164v1M40.3 164.5l.4 .5M40.7 164l-.4 .5M42 165.3h3.7l.7 .9-.7 .9h-3.7zM42.9 166.2h.4v-.4h-.4v.9"/>
<path d="M43 166.2l.4 .5M44.3 165.7l-.7 1.1M44.5 165.6h.8M44.6 165.8l.1 .9 .2-.6 .2 .6 .2-.9M46.4 162.8h2.7l-1-.9v.9M46.4 164.5h2.7l-1-.9v.9M46.4 166.2h2.7l-1-.9v.9M46.4 167.9h2.7M49.1 167.5l.4 .4-.4 .5M56.8 173.1v.8h.8l-.8 .9-.9-.9h.9M56.8 173.1h.1M56.8 170.5v2.6"/>
<path d="M64.6 164.5h2.5M64.6 167.9h2.5M64.6 163.6l.8 .9M65.4 162.8v-.9l-.8 .9h2.5M67.9 167.1h4.8v1.7h-4.8l-.8-.9zM68.2 167.3h3.7M68.4 167.9h.4l.1-.2-.2-.2h-.3v.9M68.5 167.9l.4 .5M69.2 167.9h.3M69.6 167.5h-.4v.9h.4M70.5 167.6h-.5v.2l.5 .3-.1 .3h-.4M70.8 167.9h.3"/>
<path d="M71.2 167.5h-.4v.9h.4M71.5 167.5h.4M71.8 167.5v.9M78.3 162.3v.5M109.3 177.4v.9h.9l-.9 .8-.9-.8h.9M109.3 177.4h.1M110.1 174.8h3.2v1.8h-3.2l-.8-1zM110.1 173.1h3.3l.8 .8-.8 .9h-3.3l-.8-.9zM111 175.3l-.5 .1v.2l.5 .1v.3l-.1 .1h-.4M111 173.6h-.5l.1 .3 .4 .2v.3h-.5M111.4 173.5a.49 .49 0 0 1 .4 .3 .49 .49 0 0 1-.1 .6h-.3zM111.9 175.4l-.4-.1-.1 .2 .1 .6h.4"/>
<path d="M112.1 174.4l.3-.9 .3 .9M112.2 175.3v.8h.4M112.2 174.1h.4M28.1 188.2h2.1M29.2 190.3v.8h.9l-.9 1-.9-1h.9M29.2 190.3h.1M29.2 186.9h.1M29.2 185.1v3.2M29.2 188.9v1.4M29.2 185.1l-.5 .9M29.2 185.1l.6 .9M36.7 188.9h2.2"/>
<path d="M37.8 186.9v1.4M37.8 188.9v1.4M45.4 188.2h2M46.4 186.9v1.4M46.4 188.9v1.4M54 188.2h2M55.1 186.9v1.4M55.1 188.9v1.4M62.6 188.2h2.1M63.7 186.9v1.4M63.7 188.9v1.4M71.2 188.2h2"/>
<path d="M72.3 186.9v1.4M72.3 188.9v1.4M79.8 188.2h2.1M80.9 186.9v1.4M80.9 188.9v1.4M88.4 188.2h2.1M89.5 186.9v1.4M89.5 188.9v1.4"/>
<circle cx="98.6" cy="124.8" r=".47"/>
</g>
<g fill="none" stroke="#b90000" stroke-width=".21">
<path d="M100.9 57.6l.1-.2 .3 .1v.4l-.3 .1-.1-.1-.1-.5h-.3v.4l.1 .2 .3-.2M97 61.2l.2-.3v.9M97 61.8h.5M98.3 79.8h.5l-.3 .3 .3 .1v.4h-.5M98.3 78.2h.5v.2l-.5 .5h.5M100.8 66.2h.5M101 66v.5l-.5-.2M103.9 78.4l.3-.3v.8M103.9 78.9h.5M106 60.9h-.3l-.1 .4h.4l.1 .3-.1 .2-.4-.1M98.3 86.7h.5l-.3 .9M98.5 81.5l-.2 .7h.5"/>
<path d="M98.5 88.9l-.2-.1v-.3l.3-.1 .2 .1v.3l-.5 .1 .1 .4 .4-.1v-.3h-.2M98.7 85h-.3l-.1 .2v.6h.5v-.4l-.3-.1-.2 .2M98.7 81.8v.6M98.8 83.3h-.5v.4h.5l-.1 .4-.4-.1M98.8 90.5l-.2 .2-.3-.1v-.3h.5v.5l-.4 .3M97 106.6h.5v.3l-.5 .5h.5M97 108.2h.5l-.3 .4 .3 .1v.3h-.5M97 115.2h.6l-.4 .8M97.2 117.2l-.2-.2 .1-.1 .4 .1-.1 .2-.4 .2 .1 .3 .4-.1v-.3l-.2-.1M97.2 109.9l-.2 .6h.6M97.4 113.4l-.2 .1-.2 .6 .1 .2 .4-.1v-.4l-.2-.1-.3 .2M97.4 110.3v.6"/>
<path d="M97.5 111.7h-.4l-.1 .4h.4l.1 .4h-.5M97.5 119l-.2 .2-.3-.2 .2-.4 .3 .1v.5l-.4 .2M103.1 103.7a.48 .48 0 0 1 .5-.2 .48 .48 0 0 1 .3 .3l-.1 .2h-.6l-.1-.1zM103.9 104.3v.6l-.5-.6-.3 .1 .1 .5M110.4 106.8l.2-.3v.9M110.4 108.5l.2-.3v.9M110.4 110.2l.2-.2v.9M110.4 112l.2-.3v.9M110.4 113.7l.2-.3v.9M110.4 115.4l.2-.2v.8M110.4 117.1l.2-.2v.8M110.4 118.8l.2-.2v.8"/>
<path d="M110.4 107.4h.5M110.4 109.1h.5M110.4 110.9h.5M110.4 112.6h.5M110.4 114.3h.5M110.4 116h.5M110.4 117.7h.5M110.4 119.4h.5M111.1 108.2h.6l-.3 .9M111.1 115.2h.6l-.3 .2 .3 .2v.3l-.2 .1-.4-.1M111.2 117l.4-.1 .1 .2-.6 .6h.6M111.2 118.8l.3-.2v.8"/>
<path d="M111.2 119.4h.5M111.4 106.9l-.2-.3 .4-.1v.4l-.4 .1 .1 .4h.3l.1-.3-.2-.2M111.4 113.4l-.2 .6h.5M111.6 110h-.3l-.1 .2v.6l.3 .1 .2-.5-.2-.1-.3 .1M111.6 111.7h-.4v.4h.4v.5l-.4-.1M111.6 113.7v.6M55.7 139.3l.6-.1 .2 .2v.3h-.7l-.1-.1zM96.6 124l.2-.3v.9M96.6 124.6h.5M97 122.3l.2-.3v.9M97 122.9h.5M97.9 124.2l-.2 .1-.3-.1 .2-.5 .3 .1v.6l-.4 .2"/>
<path d="M103.1 127.8a.4 .4 0 0 1 .4-.2 .4 .4 0 0 1 .3 .4 .42 .42 0 0 1-.4 .1 .42 .42 0 0 1-.3-.3zM103.9 128.7h-.8l.2 .3M103.9 128.5v.5M47.1 151.6l.2-.3v.9M47.1 153.3l.2-.3v.9M47.1 155l.2-.3v1M47.1 156.8l.2-.3v.8M47.1 158.5l.2-.3v.8M47.1 152.2h.4M47.1 153.9h.4M47.1 155.7h.4M47.1 157.3h.4"/>
<path d="M47.1 159h.4M47.5 146.2h.5l-.4 .8M47.6 148.2l-.1-.1 .1-.2 .4 .1v.2h-.4l-.1 .2v.3l.5-.1v-.3l-.2-.1M47.9 142.7l-.4 .3v.4v.1h.5l-.1-.5h-.4v.2M47.9 151.6l.2-.3v.9M47.9 153.1h.5v.4l-.5 .4h.5M47.9 154.7h.5l-.3 .4h.3v.5h-.5M47.9 152.2h.5M48 150l-.4 .2-.1-.5 .1-.1h.4v.6l-.5 .3M48.1 156.4l-.2 .7h.6M48.3 156.8v.5M48.4 158.2h-.4l-.1 .4h.5v.4h-.5"/>
<path d="M56.5 140.1v.5l-.6-.5-.2 .1v.4M65.6 146.3l.4-.1 .1 .1-.5 .7h.5M65.6 149.6h.5l-.4 .3 .4 .2v.2l-.2 .2-.3-.1M102.1 147h.6l-.4 .9M102.3 145.7l-.2-.2 .1-.2 .5 .1v.2l-.5 .1-.1 .1 .2 .4 .4-.1v-.3l-.2-.1M102.4 152.1l-.3 .7h.6M102.6 152.4v.6M107.4 143.6v.3l.3 .2h.4l.1-.4-.4-.2-.1 .2 .1 .4M109.1 155.7v.4h.4l-.1-.4 .2-.1 .3 .1v.4M109.9 143.5v.6l-.6-.6-.2 .1 .1 .5M117.6 145.6l.3-.3v.9M117.6 150.5h.5l-.2 .3h.2v.5h-.5"/>
<path d="M117.6 146.2h.5M47.1 161.9l.2-.2v.8M47.1 163.6l.2-.2v.8M47.1 165.3l.2-.2v.9M47.1 162.5h.4M47.1 164.2h.4M47.1 166h.4M47.5 167.1l.2-.3v.9M47.5 167.7h.5M47.9 161.7h.6l-.5 .8M48 165.5l-.1-.2 .1-.2h.3l.1 .3-.4 .1-.1 .1 .1 .4 .4-.1v-.3l-.2-.1M48.3 163.4h-.3l-.1 .6 .1 .2 .4-.1v-.3l-.2-.1-.3 .2"/>
<path d="M55.7 171.3l.1-.1h.5h.2v.3a.48 .48 0 0 1-.5 .2 .48 .48 0 0 1-.3-.4zM56.5 172.2h-.8l.2 .2M56.5 172v.4M65.1 167.1l.3-.3v.9M65.1 167.7h.6M65.7 161.6l-.1 .7h.5M66 163.4h-.3l-.1 .4 .3-.1 .2 .2-.1 .3-.4-.1M66 161.9v.6M66.5 167.2l-.1 .1h-.3l-.1-.4 .4-.1 .1 .2-.2 .7h-.2"/>
</g>
<g fill="none" stroke="#0f0f0f" stroke-width=".21">
<path d="M33.7 42.7v.9M34.1 42.8h.5v.6l-.2 .2a.47 .47 0 0 1-.4-.3 .47 .47 0 0 1 .1-.5zM34.8 43.6h.6M35.6 43.1h.4l.1-.3-.5-.1v.9M35.9 43.1l.2 .5M37 42.7h-.5l-.1 .2 .2 .2h.3l.1 .3-.2 .2-.4-.1M37.2 42.7h.5M37.5 42.7v.9M77.6 54.5h6.2M77.7 54.7h.2l.3 .3v.4l-.2 .2h-.3zM78.6 54.7l.1 .9h.3v-.9M79.4 55.6l.2-.9 .4 .9"/>
<path d="M79.5 55.3h.4M80.2 55.2h.4l.1-.3-.1-.2h-.4v.9M80.4 55.2l.3 .4M81 54.7h.5M81.2 54.7v.9M82.2 54.8l-.4-.1-.1 .2 .1 .3h.4l-.1 .4h-.4M82.6 55.2h.2M83 54.7h-.4v.9h.4M83.4 54.7v.9h.4M85.4 56.4l.2-.8 .3 .8M85.5 52.2v.7l.1 .1 .4-.1v-.7M85.5 56.3h.3"/>
<path d="M86.1 55.6h.5M86.2 53l.4-.8 .2 .8M86.3 52.8h.4M86.3 55.6v.8M86.7 56.4l.3-.8 .3 .8M86.8 56.3h.4M87.1 52.6l.5-.1v-.2l-.5-.1v.8M87.3 52.6l.3 .4M87.4 56.5h.7M87.8 52.2h.5M88.1 52.2v.8M88.3 55.6v.8"/>
<path d="M88.5 53l.3-.8 .3 .8M88.6 52.8h.4M89.2 55.6v.8l-.5-.8v.8M89.2 53.1h.6M89.4 55.6h.6M89.7 55.6v.8M90 52.2v.8M90.9 52.2v.8l-.4-.8v.8M91.2 52.2h.5M91.5 52.2v.8M112.5 52.8h6.2M112.6 53l.5 .2v.4l-.3 .3h-.2z"/>
<path d="M113.5 53v.8l.2 .1 .3-.2v-.7M114.3 53.9l.2-.9 .3 .9M114.3 53.6h.5M115.1 53.5h.4v-.5h-.4v.9M115.4 53.5l.2 .4M115.9 57.1h3.6M115.9 53h.5M115.9 57.4v.8M115.9 55.3h3.6M116.1 53v.9M116.1 55.6v.8M116.4 57.4h.5v.6l-.2 .2-.3-.2z"/>
<path d="M116.7 55.6h.1a.52 .52 0 0 1 .1 .8l-.4-.1a.52 .52 0 0 1 .2-.7zM117 53l-.4 .1v.3l.4 .1v.3h-.4M117 58.3h.7M117.2 56.5h.7M117.5 53.5h.2M117.9 57.4l.2 .8 .1-.6 .2 .6 .2-.8M117.9 53h-.4v.9h.4M118.1 56.1h.3l.2-.4-.2-.1h-.3v.8M118.2 53v.9h.5M118.2 56.1l.4 .3M118.9 57.8l.5-.1v-.3h-.5v.8M118.9 55.6h.3l.2 .2v.5l-.2 .1h-.3z"/>
<path d="M119.2 57.8l.2 .4M91.4 70.2l.2-.8 .4 .8M91.5 70h.4M92.2 69.4h.4M92.3 69.4v.8M92.7 70.2l.4-.8 .2 .8M92.8 70h.5M93.4 70.3h.7M94.3 69.8h.4l.1-.3-.5-.1v.8M94.5 69.8l.3 .4M95.1 69.4l.5 .2v.5l-.1 .1h-.4zM95.9 69.4l.2 .4 .4-.4"/>
<path d="M96.1 69.8v.4M115.4 78v.9M115.9 78.1l.4-.1 .2 .3v.3l-.3 .3-.3-.2zM116.6 78.9h.6M117.5 78.4h.4v-.4h-.4v.9M117.6 78.4l.4 .5M118.7 78h-.4l-.1 .2 .2 .2 .3 .1v.3h-.5M119 78h.5M119.2 78v.9M90.3 110.7l.2-.8 .3 .8M90.3 117.6l.2-.8 .3 .8M90.3 114.2l.2-.9 .3 .9"/>
<path d="M90.3 119.3l.2-.8 .3 .8M90.3 115.9l.2-.9 .3 .9M90.3 112.5l.2-1 .3 1M90.4 110.4h.3M90.4 117.4h.3M90.4 113.9h.3M90.4 119.1h.3M90.4 115.6h.3M90.4 112.2h.3M91 109.9h.5M91 116.8h.5M91 113.3h.5"/>
<path d="M91 118.5h.5M91 115h.5M91 111.5h.5M91.1 109l.3-.8 .2 .8M91.1 107.3l.3-.9 .2 .9M91.1 108.8h.5M91.1 107.1h.5M91.2 109.9v.8M91.2 111.5v1M91.2 113.3v.9M91.2 115v.9M91.2 116.8v.8"/>
<path d="M91.2 118.5v.8M91.6 110.7l.3-.8 .3 .8M91.6 117.6l.3-.8 .3 .8M91.6 114.2l.3-.9 .3 .9M91.6 119.3l.3-.8 .3 .8M91.6 115.9l.3-.9 .3 .9M91.6 112.5l.3-1 .3 1M91.7 110.4h.5M91.7 117.4h.5M91.7 113.9h.5M91.7 119.1h.5M91.7 115.6h.5"/>
<path d="M91.7 112.2h.5M91.8 108.2h.5M91.8 106.4h.5M92.1 106.4v.9M92.1 108.2v.8M92.3 110.8h.7M92.3 117.7h.7M92.3 114.3h.7M92.3 119.4h.7M92.3 115.9h.7M92.3 112.6h.7M92.5 109l.2-.8 .4 .8"/>
<path d="M92.5 107.3l.2-.9 .4 .9M92.6 108.8h.4M92.6 107.1h.4M93.1 109.1h.7M93.1 107.4h.7M93.2 109.9a.49 .49 0 0 1 .4 .3 .49 .49 0 0 1-.1 .5h-.3zM93.2 116.8h.3a.48 .48 0 0 1 .1 .5 .48 .48 0 0 1-.4 .3zM93.2 113.3l.4 .1 .1 .4-.2 .4h-.3zM93.2 118.5l.4 .1 .1 .4-.2 .3h-.3zM93.2 115a.49 .49 0 0 1 .4 .3 .49 .49 0 0 1-.1 .6h-.3zM93.2 111.5a.47 .47 0 0 1 .5 .5 .47 .47 0 0 1-.5 .5zM94 110.1l.3-.2v.8"/>
<path d="M94 108.2h.4v.7l-.4 .1zM94 106.4l.4 .1v.6l-.2 .2h-.2zM94 117l.3-.2v.8M94 113.6l.3-.3v.9M94 118.7l.3-.2v.8M94 115.3l.3-.3v.9M94 111.8l.3-.3v1M94 110.7h.4M94 117.6h.4M94 114.2h.4M94 119.3h.4M94 115.9h.4"/>
<path d="M94 112.5h.4M94.8 113.4h.5v.3l-.5 .5h.5M94.8 115h.5l-.3 .4h.3v.4h-.5M94.8 111.8l.2-.3v1M94.8 112.5h.5M94.9 109.9h.2l.2 .1-.1 .6a.39 .39 0 0 1-.4-.2 .39 .39 0 0 1 .1-.5zM95 106.8l-.2-.3 .2-.1 .3 .1v.2l-.4 .1-.1 .2 .2 .3 .3-.1v-.3l-.2-.1M95 116.7l-.2 .6h.6M95.2 117v.6M95.3 108.5l-.1 .2h-.3v-.5h.4v.6l-.4 .2M95.3 118.5h-.4l-.1 .4 .4-.1 .1 .4h-.5M90 125.3l.3-.8 .2 .8"/>
<path d="M90 124.2h4.5M90.1 125.1h.4M90.7 124.5h.5M91 124.5v.8M91.4 125.3l.3-.8 .3 .8M91.5 125.1h.4M92.2 124.9h.4l.1-.1-.1-.3h-.4v.8h.5v-.3l-.1-.1M93.1 124.9h.3M93.5 124.5h-.4v.8h.4M94.4 124.5v.8l-.5-.8v.8M42 161.3h4.3M42.2 161.6v.8"/>
<path d="M42.5 161.6h.5v.3l-.5 .5h.5M43.9 161.6h-.3l-.2 .2v.4l.2 .2 .3-.1M44.7 161.6l-.5 .1 .1 .2 .4 .3-.1 .2-.4-.1M45.1 161.9h.3M45.5 161.6h-.4v.8h.4M45.8 161.6v.8h.5M80.2 163h4.5M80.3 163.3v.8M80.6 163.4h.5v.2l-.5 .5h.5M82 163.4l-.3-.1-.2 .3 .2 .5 .3-.1M82.2 164.2h.6M83 163.3v.8"/>
<path d="M83.9 163.3v.8l-.5-.8v.8M84.3 163.3h.4M84.5 163.3v.8"/>
</g>
<g fill="none" stroke="#006665" stroke-width=".21">
<path d="M101.4 59.8l.1 .4h.4v-.4M101.4 59.1v.3l.2 .1 .4-.2-.1-.2M98.7 61.9h.2M99.1 61.5h-.4v.9h.4M99.9 61.5v.9l-.5-.9v.9M101.1 60.4l.9 .3-.9 .3M101.1 64.4v.3l.2 .2h.4l.3-.3-.1-.2h-.3v.2M101.1 63.5h.9l-.9 .5h.9M101.1 62.8a.48 .48 0 0 1 .6-.2 .48 .48 0 0 1 .3 .5h-.9zM102.4 61.6h.5l-.1 .8-.4-.1zM103.3 61.5l.1 .9h.4v-.9M104.1 61.5h.5"/>
<path d="M104.3 61.5v.9M99.9 108l.3-.9 .3 .9M99.9 109.8l.3-.9 .3 .9M99.9 111.5l.3-.9 .3 .9M99.9 113.2l.3-.9 .3 .9M99.9 114.9l.3-.8 .3 .8M99.9 116.6l.3-.8 .3 .8M99.9 118.3l.3-.8 .3 .8M100 107.7h.5M100 109.5h.5M100 111.2h.5M100 113h.5"/>
<path d="M100 114.7h.5M100 116.4h.5M100 118.1h.5M100 119.8h.5M100.7 109.1l.3-.2v.9M100.7 110.7h.5v.3l-.5 .5h.5M100.7 112.3h.5l-.2 .3 .2 .1v.4h-.5M100.7 119.2h.6l-.4 .9M100.7 109.8h.5M100.8 107.2l.2-.1 .2 .2-.1 .6a.39 .39 0 0 1-.4-.2 .39 .39 0 0 1 .1-.5zM101 114l-.3 .6h.6M101.1 117.5l-.2 .1-.2 .6h.5v-.3l-.3-.1-.2 .2"/>
<path d="M101.1 114.3v.6M101.2 115.8h-.4l-.1 .4 .4-.1 .1 .4h-.5M103.7 108.6l.8 .2-.8 .4M103.8 107.8l-.1 .2a.48 .48 0 0 0 .3 .3 .48 .48 0 0 0 .5-.1l-.1-.4M103.8 106.9a.44 .44 0 0 0 .1 .6 .44 .44 0 0 0 .6-.2l-.1-.4M107 107.6h.3l.1-.4-.4-.1v.9h.4l.1-.3-.3-.1M107 109.3h.3l.1-.3-.4-.1v.9h.3l.2-.4-.3-.1M107 111h.4l-.1-.4h-.3v.9h.4l.1-.3-.3-.2M107 112.7h.3l.1-.3-.4-.1v.9h.4l.1-.3-.3-.2M107 114.4h.3l.1-.2-.4-.1v.8h.3l.2-.3-.3-.2M107 116.2l.4-.1-.1-.3h-.3v.8h.4l.1-.2-.3-.2M107 117.9h.3l.1-.3-.4-.1v.8h.4l.1-.2-.3-.2"/>
<path d="M107 119.6h.3l.1-.3-.4-.1v.9h.3l.2-.3-.3-.2M107.7 112.3h.6l-.3 .3 .3 .2-.1 .4-.5-.1M107.7 119.2h.6l-.3 .9M107.8 109.1l.3-.2v.9M107.8 110.7l.4-.1 .1 .3-.6 .6h.6M107.8 109.8h.5M108 107.1a.43 .43 0 0 1 .3 .5 .43 .43 0 0 1-.4 .4l-.1-.7zM108 114l-.2 .6h.5M108.2 115.8h-.4v.4l.4-.1 .1 .2-.1 .3-.4-.1M108.2 117.5l-.3 .1-.1 .6h.5l-.1-.4-.4 .2M108.2 114.3v.6M99.9 120.1l.3-.9 .3 .9"/>
<path d="M99.9 123.5l.3-.9 .3 .9M100 123.3h.5M100.5 124.5l-.3-.1-.2 .2v.4l.3 .3 .2-.1M100.8 123.2h.7M100.9 124.8h.3M101.3 124.4h-.4v.9h.4M101.8 123l.7 .2-.7 .3M102.9 123.1h.3l.1-.4-.4-.1v.9h.4l.1-.3-.2-.1M103.7 124.2h.8l-.8 .5h.8M103.8 125.1l-.1 .2 .2 .2h.4l.2-.2-.1-.3h-.2v.2M103.8 123.4l.2-.2 .4 .1 .1 .4h-.8zM50 144.2l.2-.9 .3 .9"/>
<path d="M50.1 146.8a.48 .48 0 0 1 .5 .3 .48 .48 0 0 1-.2 .5h-.3zM50.1 148.5a.47 .47 0 0 1 .5 .4 .47 .47 0 0 1-.5 .5zM50.1 150.2l.4 .1 .1 .4-.2 .4h-.3zM50.1 151.9a.48 .48 0 0 1 .5 .3 .48 .48 0 0 1-.2 .6h-.3zM50.1 153.7h.3a.48 .48 0 0 1 .2 .6 .48 .48 0 0 1-.5 .3zM50.1 155.4l.4 .1 .1 .4-.2 .3h-.3zM50.1 157.1a.48 .48 0 0 1 .5 .3 .48 .48 0 0 1-.2 .5h-.3zM50.1 158.9h.3a.48 .48 0 0 1 .2 .5 .48 .48 0 0 1-.5 .3zM50.1 144h.4M50.8 143.4l.3-.1 .2 .2v.6l-.2 .1a.53 .53 0 0 1-.3-.8zM50.8 151.9h.6l-.3 .4 .3 .1-.1 .4-.5-.1M50.8 158.9h.6l-.3 .8"/>
<path d="M50.9 146.9l.2-.1a.43 .43 0 0 1 .3 .4 .43 .43 0 0 1-.4 .4zM50.9 148.7l.3-.2v.9M50.9 150.3l.4-.1 .1 .3-.6 .6h.6M50.9 149.4h.5M51.1 153.6l-.2 .6h.5M51.3 155.4h-.4v.4l.4-.1v.5h-.4M51.3 157.1l-.4 .2v.6h.4l.1-.3-.1-.2-.4 .2M51.3 154v.6M56.3 143.9l.9 .2-.9 .4M56.3 143.3l.2-.2h.4l.3 .3v.2h-.9zM56.3 142.4l.2-.1h.4l.3 .4h-.9zM61.9 146.9h-.5v.2l.5 .3-.1 .2h-.4"/>
<path d="M61.9 150.2h-.4l-.1 .2 .2 .3h.3v.3l-.5 .1M62.3 146.8a.49 .49 0 0 1 .4 .3 .49 .49 0 0 1-.1 .5h-.3zM62.8 150.3l-.4-.1-.1 .4 .1 .5 .4-.1M63 147.6l.3-.8 .3 .8M63.1 147.4h.4M63.2 150.2v.9h.4M103.9 152.6h2.1M104 153.3h.3l.2-.4-.2-.1h-.3v.9M104.2 153.3l.3 .4M104.4 145.9h-.4l-.1 .2 .2 .2 .3 .1v.3l-.5 .1M104.4 147.7l-.3-.1-.2 .2 .1 .2 .4 .2v.3h-.5M104.9 147.6l.4 .2-.1 .7h-.3z"/>
<path d="M105.3 146l-.4-.1-.1 .4 .1 .5 .4-.1M105.3 152.9h-.4v.2l.4 .2-.1 .4-.3-.1M105.5 148.5l.4-.9 .2 .9M105.5 152.8h.5M105.6 148.3h.4M105.7 145.9v.9h.4M105.8 152.8v.9M108 147.5l.8 .3-.8 .3M108 145.2v.6M108 145.5h.8M108.4 146.9l.1-.1 .3 .1v.3h-.8v-.3l.2-.1 .2 .4M108.6 146v.4"/>
<path d="M108.8 145.9l-.8 .3 .8 .3M109.7 147l.8 .3-.8 .2M109.7 152.9h.8l-.8 .6h.8M109.7 152.3l.5-.3 .3 .2v.3h-.8zM109.8 146.2a.44 .44 0 0 0 .1 .6 .44 .44 0 0 0 .6-.2v-.4M109.8 145.3l-.1 .3 .2 .2h.5l.1-.5M109.8 153.8l-.1 .2 .2 .3h.5l.1-.2v-.3h-.3v.2M111 150.8h1.8M111.2 151.1v.8M112.1 151.1v.8l-.5-.8v.8M112.4 151.1h.5M112.5 145.9h.5l-.3 .4 .3 .1-.1 .4-.4-.1"/>
<path d="M112.6 151.1v.8M113.3 146l.4-.1 .1 .3-.6 .6h.6M113.7 151.1l-.7 1.1M114.2 145.9v.9M114.3 146.3l.4 .5M114.5 151.1h-.4l-.1 .2 .5 .5-.1 .1h-.4M114.7 145.9l-.5 .5M114.8 151.2h.6v.5l-.1 .2-.5-.1zM115 151.8l.4 .2M115 145.9v.9M115 146.3h.5M115.5 145.9v.9"/>
<path d="M115.7 151.1l.2 .8 .1-.6 .2 .6 .3-.8M115.9 145.9h.6l-.6 .9h.6M50 165.7l.2 .9 .2-.6 .1 .6 .3-.9M50 162h1.5M50 163.8h1.5M50 165.5h1.7M50.1 164.5h.3l.2-.2-.1-.3h-.4v.9M50.3 164.5l.3 .4M50.6 162.3h-.3l-.2 .2v.4l.1 .2 .4-.1M50.6 167.5l-.3-.1-.2 .3v.4l.1 .2 .4-.1M50.9 164h.4l.1 .2v.4l-.2 .3h-.3zM50.9 167.4v.9h.4"/>
<path d="M51.1 166.2h.4v-.5h-.4v.9M51.3 166.2l.3 .4M51.4 162.3h-.5v.3l.5 .3-.1 .2h-.4M51.7 167.4v.9M51.8 167.8l.3 .5M52.1 167.4l-.4 .5M56.3 168.9l.9 .4-.9 .2M56.3 168.3v.4l.2 .1 .4-.5h.2v.5M56.3 167.4v.4l.2 .1 .3-.4 .2-.1 .2 .2-.1 .3M60.9 162h2.7M61 162.3v.8M61.3 163.1l.3-.8 .2 .8"/>
<path d="M61.3 162.9h.5M61.4 167.2h2.2M61.5 167.9l.5-.1v-.3l-.5-.1v.9M61.8 163.8h1.8M61.8 167.9l.2 .4M61.9 164v.9M62.6 162.3a.43 .43 0 0 0-.5 .3 .43 .43 0 0 0 .2 .5l.3-.1M62.8 164v.9l-.4-.9v.9M62.9 167.5l-.4-.1-.1 .2 .5 .6-.5 .1M63 162.3v.8M63.1 162.7l.4 .4M63.1 164h.5"/>
<path d="M63.1 167.4h.5M63.4 164v.9M63.4 167.4v.9M63.5 162.3l-.5 .5"/>
</g>
<path d="M28.1 188.9h2.2M36.8 188.3h2.1M45.4 188.9h2.1M54.1 188.9h2M62.6 188.9h2.1M71.2 188.9h2.1M79.9 188.9h2M88.4 188.9h2.1" fill="none" stroke="#910000" stroke-width=".25"/>
<path d="M105.9 172.2h.6v.1h-.6z" fill="#910000"/>
<path d="M105.9 172.2h.6v.1h-.6z" fill="none" stroke="#910000" stroke-width=".21"/>
<path d="M105.9 173.9h.6v.1h-.6z" fill="#910000"/>
<path d="M105.9 173.9h.6v.1h-.6z" fill="none" stroke="#910000" stroke-width=".21"/>
<path d="M105.9 175.6h.6v.1h-.6z" fill="#910000"/>
<path d="M105.9 175.6h.6v.1h-.6z" fill="none" stroke="#910000" stroke-width=".21"/>
<path d="M105.9 177.3h.6v.2h-.6z" fill="#910000"/>
<g fill="none" stroke="#910000" stroke-width=".21">
<path d="M31.4 37h6.6l.6 .9-.6 .8h-6.6zM32.6 37.5h-.3l-.2 .1v.5l.2 .2 .3-.1M33.1 37.9h.3l.1-.4h-.4v.8M33.1 33.6h4.9l.6 .8-.6 .9h-4.9zM33.8 33.7h3.7M33.9 37.5l.1 .8h.3v-.8M34 34.5l.4-.1-.1-.4h-.3v.8M34.2 34.5l.2 .3M34.6 38.4h.7M34.8 34.4h.3M35.3 34h-.5v.8h.5M35.9 37.5h-.3l-.2 .1v.5l.2 .2 .3-.1"/>
<path d="M36 34.1h-.4v.2l.4 .3-.1 .2h-.3M36.3 37.5v.8h.4M36.4 34.4h.3M36.9 34h-.5v.8h.5M37 34h.5M37 37.5v.8M37.1 37.8l.4 .5M37.3 34v.8M37.5 37.5l-.5 .5M77.4 37h3.3l.7 .9-.7 .8h-3.3zM77.9 37.5l.3 .8 .3-.8M77.9 37.2h2.1"/>
<path d="M78.8 37.9h.4v-.4h-.4v.8M79.5 38.3l.3-.8 .3 .8M79.6 38.1h.4M115.5 37h3.4l.8 .9-.8 .8h-3.4l-.7-.8zM115.5 35.3h3.4l.8 .8-.8 .9h-3.4l-.7-.9zM115.5 33.6h3.4l.8 .8-.8 .9h-3.4l-.7-.9zM115.5 38.7h3.4l.8 .9-.8 .8h-3.4l-.7-.8zM116.3 30.1h2.6l.8 .8-.8 1h-2.6l-.8-1zM116.3 37.5h.3l.2 .1v.5l-.2 .2h-.3zM116.3 31.9h2.6l.8 .8-.8 .9h-2.6l-.8-.9zM116.3 35.8h.3l.2 .1v.5l-.3 .2h-.2zM116.3 34h.2l.3 .2v.5l-.2 .1h-.3z"/>
<path d="M116.3 39.2h.2l.3 .2v.4l-.2 .2h-.3zM117.1 30.6h.4a.48 .48 0 0 1 .1 .6 .48 .48 0 0 1-.5 .3zM117.1 37.7l.3-.2v.8M117.1 32.3l.5 .1v.4l-.1 .3h-.4zM117.1 35.9l.3-.1v.8M117.1 34.2l.3-.2v.8M117.1 39.4l.3-.2v.8M117.1 38.3h.5M117.1 36.6h.5M117.1 34.8h.5M117.9 39.2h.6l-.4 .3 .4 .2v.2h-.6M118 37.5h.4l.1 .2-.6 .6h.6"/>
<path d="M118 35.9l.2-.1v.8M118 36.6h.5M118.1 30.9l-.1-.2 .4-.1 .1 .2-.2 .1-.3 .1v.4l.1 .1 .4-.2-.2-.4M118.1 34a.43 .43 0 0 1 .4 .5 .43 .43 0 0 1-.4 .3l-.1-.6zM118.5 32.6l-.1 .2h-.3l-.1-.4 .4-.1 .1 .2-.2 .6h-.2M22.3 43.9h7l.8 .8-.8 .9h-7zM23.2 44.3v.9M23.7 44.3h.1a.52 .52 0 0 1 .1 .9l-.3-.1a.52 .52 0 0 1 .1-.8zM24.9 44.4l-.2-.1-.3 .3v.4l.2 .2h.3M25.2 44.3h.5M25.4 44.3v.9M25.9 44.3v.9h.5"/>
<path d="M26.5 45.3h.6M27.2 44.3h.5M27.5 44.3v.9M28 44.3a.49 .49 0 0 1 .4 .3 .49 .49 0 0 1-.1 .6h-.3zM28.8 44.3v.9M29.6 40.4h9v1.8h-9l-.7-.9zM30.2 49.1h3.5l.7 .8-.7 .9h-3.5zM30.3 40.9v.9M30.8 41h.5v.6l-.2 .2a.47 .47 0 0 1-.4-.3 .47 .47 0 0 1 .1-.5zM30.9 49.3h2.3M30.9 49.5v.7l.2 .2 .4-.1v-.8M31.2 45.6h2.5l.7 .8-.7 1h-2.5z"/>
<path d="M31.9 46.9l.2-.8 .4 .8M31.9 49.5a.47 .47 0 0 1 .5 .5 .47 .47 0 0 1-.5 .4zM31.9 45.8h1.3M32 46.7h.4M32.1 41l-.3-.1-.2 .2v.4l.3 .3 .2-.1M32.4 40.9h.5M32.6 40.9v.9M33.1 46.1l-.4 .1v.2l.4 .2v.3h-.4M33.1 49.6h-.4v.2l.4 .3v.3l-.4-.1M33.1 40.9v.9h.5M33.7 41.9h.6M34.2 47.4h3.8l.6 .8-.6 .9h-3.8z"/>
<path d="M34.5 40.9h.3l.2 .2v.4l-.2 .3h-.3zM34.6 55.9h3.4l.6 1-.6 .8h-3.4zM34.6 57.7h3.4l.6 .8-.6 .9h-3.4zM34.6 54.2h3.4l.6 .9-.6 .8h-3.4zM34.7 50.8h3.3l.6 .9-.6 .8h-3.3zM35 59.4h3.6v1.7h-3.6l-.8-.9zM35.1 48.2h.4l.1-.3-.5-.1v.8M35.3 40.9h.5M35.3 48.2l.3 .4M35.3 51h2.2M35.4 56.9h.3M35.4 58.5h.3"/>
<path d="M35.4 55.1h.3M35.5 51.3v.8h.4M35.5 40.9v.9M35.7 59.8v.9M35.9 56.4h-.5v.9M35.9 58.1h-.5v.9M35.9 54.6h-.5v1M35.9 41.8l.3-.9 .3 .9M36 41.5h.4M36.2 51.3h.3a.47 .47 0 0 1 .2 .5 .47 .47 0 0 1-.5 .3zM36.6 47.8l-.7 1.1M36.7 56.5l-.4-.1a.44 .44 0 0 0-.1 .6 .44 .44 0 0 0 .5 .2"/>
<path d="M36.7 58.2a.44 .44 0 0 0-.6 .2 .44 .44 0 0 0 .2 .6l.4-.1M36.7 54.7a.42 .42 0 0 0-.6 .4 .42 .42 0 0 0 .6 .4M36.8 47.8l.2 .8 .1-.6 .2 .6 .2-.8M36.8 47.5h.7M37 59.8v.9h.4M37 56.7l.2-.3v.9M37 58.2h.5v.3l-.5 .5h.5M37 54.7l.3-.1 .2 .2v.6l-.2 .2-.3-.1zM37 57.3h.5M37.3 41l-.4-.1a.44 .44 0 0 0-.1 .6 .44 .44 0 0 0 .5 .2M37.5 51.3h-.5v.3l.5 .2v.2h-.5M37.6 40.9v.9"/>
<path d="M37.7 59.9l.2-.1a.59 .59 0 0 1 .1 .9 .53 .53 0 0 1-.3-.8zM37.8 41.3l.3 .5M38.1 40.9l-.5 .5M77.3 47.4h3.9v1.7h-3.9l-.7-.9zM77.3 43.9h3.9v1.7h-3.9l-.7-.9zM77.7 47.5h2.9M77.7 44.1h2.9M77.8 44.3v.9M77.8 47.8v.8M78.3 48.2l.4-.1-.1-.3h-.3v.8M78.3 44.8l.4-.1v-.3l-.4-.1v.9M78.4 48.2l.3 .4"/>
<path d="M78.4 44.8l.3 .4M79.1 47.9h.5l-.1 .7h-.4zM79.1 44.5l.2-.2 .3 .2-.1 .7-.4-.1zM79.2 48.5l.5 .2M79.2 45l.5 .3M80.1 47.8l-.1 .6h.5M80.4 44.3l-.4 .3v.6l.5-.1-.2-.4-.3 .1M80.4 48v.6M86 49.1h3.9v1.7h-3.9l-.8-.9zM86 45.6h3.9v1.8h-3.9l-.8-1zM86 42.2h3.9v1.7h-3.9l-.8-.9zM86.3 49.3h2.8"/>
<path d="M86.3 45.8h2.8M86.3 42.4h2.8M86.4 42.6v.9M86.4 46.1v.8M86.4 49.5v.9M86.8 50l.5-.1v-.3l-.5-.1v.9M86.8 46.5h.4l.1-.3-.5-.1v.8M86.8 43h.4l.1-.3-.5-.1v.9M87.1 50l.2 .4M87.1 46.5l.2 .4M87.1 43l.2 .5M87.8 49.6v-.1a.47 .47 0 0 1 .5 .5 .47 .47 0 0 1-.5 .4l-.1-.3z"/>
<path d="M87.8 46.1l.4 .1a.47 .47 0 0 1-.4 .7l-.1-.3zM87.8 42.6h.3l.2 .3-.2 .6h-.3zM87.8 50.2l.5 .2M87.8 46.7l.5 .3M87.8 43.3l.5 .3M88.5 49.5h.6l-.3 .3 .3 .2v.2l-.2 .2-.4-.1M88.5 42.6h.6l-.3 .9M89 46.1h-.4v.4l.4-.1 .1 .4-.2 .1h-.3M115.5 40.4h3.4l.8 .9-.8 .9h-3.4l-.7-.9zM115.5 42.2h3.4l.8 .8-.8 .9h-3.4l-.7-.9zM115.7 47.4h3.2l.8 .8-.8 .9h-3.2zM115.7 50.8h3.2l.8 .9-.8 .8h-3.2z"/>
<path d="M115.7 45.6h3.2l.8 .8-.8 1h-3.2zM115.7 49.1h3.2l.8 .8-.8 .9h-3.2zM116.3 40.9h.3l.2 .2v.4l-.3 .3h-.2zM116.3 42.6h.3l.2 .2v.5l-.2 .2h-.3zM116.4 47.8l.3 .8 .3-.8M116.4 51.3l.3 .8 .3-.8M116.4 46.1l.3 .8 .3-.8M116.4 49.5l.3 .9 .3-.9M117.1 41.2l.3-.3v.9M117.1 42.9l.3-.3v.9M117.1 48.6l.3-.8 .3 .8M117.1 52.1l.3-.8 .3 .8"/>
<path d="M117.1 46.9l.3-.8 .3 .8M117.1 50.4l.3-.9 .3 .9M117.1 40h.5M117.1 41.8h.5M117.1 43.5h.5M117.2 48.4h.4M117.2 51.9h.4M117.2 46.7h.4M117.2 50.2h.4M117.9 49.5h.6l-.4 .3 .4 .2v.2l-.2 .2-.4-.1M118 47.9l.4-.1 .1 .2-.6 .6h.6M118 46.4l.2-.3v.8"/>
<path d="M118 46.9h.5M118.1 40.8l-.1 .6h.5M118.1 51.6l-.1-.3h.4v.3l-.4 .1v.3l.1 .1 .4-.2-.2-.3M118.4 42.6h-.4v.4h.4l.1 .1-.1 .4-.4-.1M118.4 41.2v.6M25.9 61.1h3.4l.8 .9-.8 .9h-3.4zM26.6 61.6h.5M26.9 61.6v.8M27.5 62.4v-.8l.2 .6 .3-.6v.8M28.9 61.6l-.5 .1v.2l.5 .3-.2 .2h-.3M34.5 69.7h3.5l.6 .9-.6 .8h-3.5zM34.5 71.4h3.5l.6 .9-.6 .9h-3.5z"/>
<path d="M34.5 78.4h3.5l.6 .8-.6 .8h-3.5zM34.5 76.7h3.5l.6 .8-.6 .9h-3.5zM34.5 74.9h3.5l.6 .8-.6 1h-3.5zM34.5 73.2h3.5l.6 .8-.6 .9h-3.5zM35 62.9h3.6v1.7h-3.6l-.8-.9zM35 64.6h3.6v1.6h-3.6l-.8-.8zM35.3 66.2h2.7l.6 1-.6 .8h-2.7zM35.3 68h2.7l.6 .9-.6 .8h-2.7zM35.3 70.1a.47 .47 0 0 1 .6 .5 .47 .47 0 0 1-.6 .5zM35.3 71.9l.5 .1 .1 .4-.2 .4h-.4zM35.3 78.8a.48 .48 0 0 1 .5 .3 .48 .48 0 0 1-.1 .5h-.4zM35.3 77.1l.5 .1 .1 .4-.2 .3h-.4z"/>
<path d="M35.3 75.4h.4a.48 .48 0 0 1 .1 .5 .48 .48 0 0 1-.5 .3zM35.3 73.6a.48 .48 0 0 1 .5 .3 .48 .48 0 0 1-.1 .6h-.4zM35.7 63.3v.8M35.7 65v.9M36.1 60.3l.5-.1v-.3l-.5-.1v.9M36.1 63.7h.4l.1-.3-.5-.1v.8M36.1 65.5l.5-.1v-.3l-.5-.1v.9M36.2 66.8h.3a.47 .47 0 0 1 .2 .5 .47 .47 0 0 1-.5 .3zM36.2 68.4a.49 .49 0 0 1 .4 .4 .49 .49 0 0 1-.1 .5h-.3zM36.2 70.4l.2-.3v1M36.2 72.2l.2-.3v.9M36.2 79l.2-.2v.8"/>
<path d="M36.2 77.3l.2-.2v.8M36.2 75.6l.2-.2v.8M36.2 73.9l.2-.3v.9M36.2 71.1h.5M36.2 72.8h.5M36.2 79.6h.5M36.2 77.9h.5M36.2 76.2h.5M36.2 74.5h.5M37 63.3v.8h.4M37 65v.9h.4M37 75.4h.5l-.3 .2 .3 .1v.5h-.5"/>
<path d="M37 70.2l.3-.1 .2 .2v.6l-.2 .2-.3-.1zM37 72.2l.2-.3v.9M37 73.7h.5v.3l-.5 .5h.5M37 72.8h.5M37.1 67.1l-.1-.3h.5l-.1 .3-.4 .1 .1 .4 .4-.1v-.3l-.2-.1M37.2 77l-.2 .7h.5M37.4 77.3v.6M37.5 68.9l-.5 .1 .1-.6 .4 .1v.6l-.5 .2M37.5 78.8h-.5v.4h.5l-.1 .4-.4-.1M37.6 63.5l.3-.2v.8M37.6 65.1l.4-.1 .1 .1-.5 .8h.5M37.6 64.1h.5"/>
<path d="M77.4 66.2h5.7l.8 1-.8 .8h-5.7zM77.9 66.5h4.6M78 67.2h.4M78.4 66.8h-.4v.8h.4M78.8 66.8l.5 .8M79.3 66.8l-.5 .8M79.6 67.2h.4l.1-.4h-.5v.8M81 66.8h-.5v.3l.5 .2-.2 .3-.3-.1M81.3 67.2h.3M81.7 66.8h-.4v.8h.4M81.7 68h8.5l.8 .9-.8 .8h-8.5zM82.1 66.8v.8h.4"/>
<path d="M82.3 69.3v-.9l.4 .6 .2-.6v.9M83.4 68.9h.2M83.8 68.4h-.4v.9h.4M84.1 69.3v-.9l.3 .6 .3-.6v.9M85.6 68.5a.43 .43 0 0 0-.5 .3 .43 .43 0 0 0 .1 .5l.4-.1M85.8 68.4h.5M86.1 68.4v.9M86.7 68.4v.9h.3M87.1 69.4h.7M87.8 68.4h.5M88.1 68.4v.9M88.6 68.4h.3l.2 .3v.4l-.2 .2h-.3z"/>
<path d="M89.4 68.4v.9M93.4 78.4h4l.7 .8-.7 .8h-4zM94.2 78.5h2.8M94.3 78.8v.8M94.7 79.3h.3l.2-.4-.2-.1h-.3v.8M94.9 79.3l.3 .3M95.5 78.9l.2-.1a.42 .42 0 0 1 .4 .4 .42 .42 0 0 1-.4 .4l-.2-.1zM95.7 79.5l.4 .2M96.4 78.8h.5l-.3 .3 .3 .1v.3h-.5M30.3 99h3.4l.7 .9-.7 .8h-3.4zM31.9 99.5l.3-.1 .2 .3-.6 .7h.6M33.1 99.4l-.4 .3v.6h.4v-.5l-.4 .1"/>
<path d="M33.9 95.5h4.1l.6 .9-.6 .9h-4.1zM33.9 97.3h4.1l.6 .9-.6 .8h-4.1zM34.6 96.1l.3 .8 .3-.8M34.6 97.7l.3 .9 .3-.9M34.8 93.8h3.2l.6 .9-.6 .8h-3.2zM34.8 92.2h3.2l.6 .8-.6 .8h-3.2zM34.8 87h3.2l.6 .8-.6 .9h-3.2zM34.8 88.7h3.2l.6 .8-.6 .9h-3.2zM34.8 90.4h3.2l.6 .8-.6 1h-3.2zM34.8 80h3.2l.6 .9-.6 .9h-3.2zM34.8 85.2h3.2l.6 .9-.6 .9h-3.2zM34.8 83.5h3.2l.6 .9-.6 .8h-3.2z"/>
<path d="M34.8 81.8h3.2l.6 .9-.6 .8h-3.2zM35.3 96.9l.4-.8 .2 .8M35.3 98.6l.4-.9 .2 .9M35.4 94.3l.3 .9 .3-.9M35.4 92.6l.3 .8 .3-.8M35.4 87.4l.3 .9 .3-.9M35.4 89.1l.3 .9 .3-.9M35.4 90.9l.3 .8 .3-.8M35.4 80.6l.3 .8 .3-.8M35.4 85.7l.3 .9 .3-.9M35.4 83.9l.3 .9 .3-.9M35.4 82.3l.3 .8 .3-.8"/>
<path d="M35.4 96.6h.5M35.4 98.3h.5M36.2 96.3l.2-.2v.8M36.2 98l.2-.3v.9M36.2 95.2l.2-.9 .4 .9M36.2 93.4l.2-.8 .4 .8M36.2 88.3l.2-.9 .4 .9M36.2 90l.2-.9 .4 .9M36.2 91.7l.2-.8 .4 .8M36.2 81.4l.2-.8 .4 .8M36.2 86.6l.2-.9 .4 .9M36.2 84.8l.2-.9 .4 .9"/>
<path d="M36.2 83.1l.2-.8 .4 .8M36.2 96.9h.5M36.2 98.6h.5M36.3 95h.4M36.3 93.2h.4M36.3 88h.4M36.3 89.8h.4M36.3 91.5h.4M36.3 81.1h.4M36.3 86.3h.4M36.3 84.6h.4M36.3 82.8h.4"/>
<path d="M37 90.9h.5l-.4 .8M37 83.9h.5l-.3 .4 .3 .1v.3h-.5M37 96.1h.4l.1 .1v.5l-.2 .2-.3-.1zM37 98l.2-.3v.9M37 80.7l.2-.1v.8M37 82.3h.4l.1 .3-.5 .5h.5M37 98.6h.5M37 81.4h.5M37.1 92.9l-.1-.3h.4l.1 .2-.5 .2v.4l.5-.1v-.3l-.2-.1M37.2 85.6l-.2 .6h.5M37.4 89.1l-.4 .3v.6h.5v-.5l-.4-.1-.1 .2M37.4 86v.6"/>
<path d="M37.5 94.7l-.2 .2-.3-.1 .1-.5 .4 .1v.6l-.5 .2M37.5 87.4h-.5v.4h.5l-.1 .5-.4-.1M80 85.2h3.2v1.8h-3.2l-.8-.9zM80.3 85.7h.5M80.6 85.7v.9M81.6 85.8l-.5-.1v.2v.6h.5M81.9 85.7v.9M82.1 86.1l.3 .5M82.4 85.7l-.5 .4M88.3 80h3.9l.7 .9-.7 .9h-3.9zM88.3 83.5h3.9l.7 .9-.7 .8h-3.9zM89 80.3h2.8"/>
<path d="M89 83.7h2.8M89.1 80.6v.8M89.1 83.9v.9M89.5 81h.4l.1-.2v-.2h-.5v.8M89.5 84.5h.4l.1-.4-.1-.2h-.4v.9M89.7 81l.3 .4M89.7 84.5l.3 .3M90.4 80.6h.5a.47 .47 0 0 1-.4 .8l-.1-.2zM90.4 84.1l.1-.2a.42 .42 0 0 1 .5 .5 .42 .42 0 0 1-.5 .4l-.1-.1zM90.5 81.1l.5 .4M90.5 84.6l.5 .3M91.5 80.5l-.3 .6h.6"/>
<path d="M91.6 83.9l-.2 .1-.2 .6 .1 .2 .4-.1v-.3l-.3-.1-.2 .2M91.6 80.8v.6M93.4 81.8h4l.7 .9-.7 .8h-4zM93.4 85.2h4l.7 .9-.7 .9h-4zM94.2 82h2.8M94.2 85.5h2.8M94.3 82.3v.8M94.3 85.7v.9M94.7 82.7h.4v-.4h-.4v.8M94.7 86.1h.3l.2-.1-.1-.3h-.4v.9M94.9 82.7l.3 .4M94.9 86.1l.3 .5"/>
<path d="M95.5 82.3h.6v.5l-.1 .3-.5-.1zM95.5 85.8h.6a.47 .47 0 0 1-.4 .8l-.2-.2zM95.7 82.9l.4 .3M95.7 86.3l.4 .4M96.4 85.7h.6l-.4 .9M96.9 82.3h-.4l-.1 .4 .4-.1 .1 .4h-.5M24.4 102.5h4.1l.7 .8-.7 .9h-4.1zM24.4 105.9h4.1l.7 .9-.7 .9h-4.1zM24.4 104.2h4.1l.7 .8-.7 .9h-4.1zM24.4 107.7h4.1l.7 .8-.7 .8h-4.1zM25.2 102.9l.2 .9 .3-.9M25.2 106.4l.2 .8 .3-.8"/>
<path d="M25.2 104.6l.2 .9 .3-.9M25.2 108.1l.2 .8 .3-.8M25.9 103.8l.3-.9 .3 .9M25.9 107.2l.3-.8 .3 .8M25.9 105.5l.3-.9 .3 .9M25.9 108.9l.3-.8 .3 .8M25.9 103.5h.5M25.9 107h.5M25.9 105.3h.5M25.9 108.7h.5M26.7 103.2l.3-.3v.9M26.7 106.6l.3-.2v.8"/>
<path d="M26.7 104.9l.3-.3v.9M26.7 108.3l.3-.2v.8M26.7 103.8h.5M26.7 107.2h.5M26.7 105.5h.5M26.7 108.9h.5M27.5 104.6h.6l-.4 .9M27.7 106.7l-.1-.2 .3-.1 .1 .2-.4 .2v.3l.1 .1 .3-.1v-.3l-.2-.1M27.9 102.9l-.3 .2v.6h.4l-.1-.5h-.3v.2M28 108.4l-.1 .2h-.3v-.4h.4v.6l-.4 .1M30.3 100.7h3.4l.7 .9-.7 .9h-3.4zM31 100.4l.4-1 .2 1"/>
<path d="M31 102.1l.4-.9 .2 .9M31.1 100.1h.4M31.1 101.8h.4M31.9 101.3l.4-.1 .1 .3-.6 .6h.6M32.6 101.2h.6l-.3 .9M80 104.2h5.1v1.7h-5.1l-.8-.9zM80.4 104.6v.9M81.3 104.6v.9l-.5-.9v.9M81.6 104.6h.5M81.8 104.6v.9M82.2 105.6h.6M83 105h.4"/>
<path d="M83.4 104.6h-.4v.9h.4M84.3 104.6v.9l-.5-.9v.9M113.5 106.8h2.6l.8 .9-.8 .8h-2.6l-.8-.8zM113.5 112h2.6l.8 .8-.8 .9h-2.6l-.8-.9zM113.5 110.2h2.6l.8 .8-.8 1h-2.6l-.8-1zM113.5 108.5h2.6l.8 .8-.8 .9h-2.6l-.8-.9zM113.5 118.8h2.6l.8 .9-.8 .8h-2.6l-.8-.8zM113.5 113.7h2.6l.8 .8-.8 .9h-2.6l-.8-.9zM113.5 117.1h2.6l.8 .9-.8 .8h-2.6l-.8-.8zM113.5 115.4h2.6l.8 .8-.8 .9h-2.6l-.8-.9zM114 107.2l.4 .1 .1 .4-.2 .4h-.3zM114 112.4l.4 .1 .1 .4-.2 .3h-.3z"/>
<path d="M114 110.7h.3a.48 .48 0 0 1 .2 .5 .48 .48 0 0 1-.5 .3zM114 108.9a.49 .49 0 0 1 .5 .3 .49 .49 0 0 1-.2 .6h-.3zM114 119.2a.47 .47 0 0 1 .5 .5 .47 .47 0 0 1-.5 .5zM114 114.1a.49 .49 0 0 1 .5 .3 .49 .49 0 0 1-.2 .5h-.3zM114 117.6h.4l.1 .5-.2 .3h-.3zM114 115.9h.3a.48 .48 0 0 1 .2 .5 .48 .48 0 0 1-.5 .3zM114.8 112.4h.6l-.4 .3h.3v.5h-.5M114.8 119.2h.6l-.4 1M114.8 110.8l.5-.1 .1 .3-.6 .5h.6M114.8 109.2l.3-.3v.9M114.8 109.8h.6M114.9 107.2a.42 .42 0 0 1 .5 .5 .42 .42 0 0 1-.5 .4z"/>
<path d="M115 114.1l-.2 .6h.6M115.3 117.6l-.5 .1v.6l.5 .1v-.5h-.4l-.1 .2M115.3 115.9h-.5v.3h.5l.1 .3-.2 .2-.4-.1M115.3 114.4v.5M142.8 110.2h3.4l.7 .8-.7 1h-3.4l-.8-1zM142.8 118.8h3.4l.7 .9-.7 .8h-3.4l-.8-.8zM142.8 106.8h2.6l.8 .9-.8 .8h-2.6l-.8-.8zM142.8 108.5h2.6l.8 .8-.8 .9h-2.6l-.8-.9zM142.8 117.1h3.4l.7 .9-.7 .8h-3.4l-.8-.8zM142.8 115.4h3.4l.7 .8-.7 .9h-3.4l-.8-.9zM142.8 112h3.4l.7 .8-.7 .9h-3.4l-.8-.9zM142.8 113.7h3.4l.7 .8-.7 .9h-3.4l-.8-.9z"/>
<path d="M143.3 110.7h.3a.48 .48 0 0 1 .2 .5 .48 .48 0 0 1-.5 .3zM143.3 119.2a.47 .47 0 0 1 .5 .5 .47 .47 0 0 1-.5 .5zM143.3 107.2l.4 .1 .1 .4-.2 .4h-.3zM143.3 108.9a.49 .49 0 0 1 .4 .3 .49 .49 0 0 1-.1 .6h-.3zM143.3 117.6h.4l.1 .5-.2 .3h-.3zM143.3 115.9h.3a.48 .48 0 0 1 .2 .5 .48 .48 0 0 1-.5 .3zM143.3 112.4l.4 .1 .1 .4-.2 .3h-.3zM143.3 114.1a.49 .49 0 0 1 .4 .3 .49 .49 0 0 1-.1 .5h-.3zM144.1 111l.2-.3v.8M144.1 119.5l.2-.3v1M144.1 117.8l.2-.2v.8M144.1 116.1l.2-.2v.8"/>
<path d="M144.1 112.6l.2-.2v.8M144.1 114.3l.2-.2v.8M144.1 111.5h.5M144.1 118.4h.5M144.1 116.7h.5M144.1 113.2h.5M144.1 114.9h.5M144.3 107.6l-.2-.3 .4-.1 .1 .3-.5 .2 .1 .4 .4-.1v-.3l-.2-.1M144.6 109.3l-.2 .2-.3-.1v-.4h.5v.6l-.4 .2M144.9 115.9h.5l-.2 .3h.2v.4h-.5M144.9 112.6l.3-.2v.8M144.9 114.2h.5v.3l-.5 .4h.5"/>
<path d="M144.9 113.2h.5M145 110.8l.3-.1 .1 .2v.5l-.2 .1a.48 .48 0 0 1-.2-.7zM145.2 117.6l-.3 .5h.6M145.3 117.8v.6M145.4 119.2h-.4l-.1 .5h.5v.4h-.5M91.1 122.3h3.7l.7 .8-.7 .9h-3.7zM92 123.1h.3l.1-.3-.4-.1v.9M92.2 123.1l.2 .5M93.4 122.7l-.7 1.1M93.6 122.7l.2 .9 .2-.6 .2 .6 .2-.9M93.6 122.5h.8M94 138.4h3.1"/>
<path d="M94 138.3h3.1v.2h-3.1zM94.5 138.8h2.1v.3h-2.1zM95.5 136v2.3M95.5 139v2.2M96 137.4h.7M96.3 137.1v.6M120.4 122.3h3.7l.7 .8-.7 .9h-3.7zM121.2 123.1h.4l.1-.3-.5-.1v.9M121.5 123.1l.2 .5M122.7 122.7l-.7 1.1M122.9 122.7l.2 .9 .2-.6 .2 .6 .2-.9M122.9 122.5h.8"/>
<path d="M144.1 120.2h.5M179.9 133.5h3.1v1.7h-3.1l-.8-.9zM179.9 138.6h4.7v1.7h-4.7l-.8-.8zM179.9 135.2h3.1v1.7h-3.1l-.8-.9zM179.9 136.9h3.1v1.7h-3.1l-.8-.8zM180.2 133.9l.3 .8 .3-.8M180.2 135.7l.3 .8 .3-.8M180.2 137.4l.3 .8 .3-.8M180.2 138.8h3.7M180.3 139.6l.5-.1v-.4h-.5v.8M180.5 139.6l.3 .3M181 134.7l.2-.8 .3 .8"/>
<path d="M181 136.5l.2-.8 .3 .8M181 138.2l.2-.8 .3 .8M181.1 134.6h.3M181.1 136.3h.3M181.1 138h.3M181.2 139.5h.3M181.6 139.1h-.4v.8h.4M181.7 134.2l.3-.3v.8M181.7 135.8h.5v.2l-.5 .5h.5M181.7 137.4h.5l-.2 .3 .2 .1v.3h-.5M181.7 134.7h.5M182.4 139.1h-.3l-.2 .1 .1 .3 .4 .2v.2h-.5"/>
<path d="M182.7 139.5h.4M183.2 139.1h-.5v.8h.5M183.4 139.1h.5M183.7 139.1v.8M42.3 156.8h3.4l.7 .8-.7 .9h-3.4l-.8-.9zM42.3 155h3.4l.7 .8-.7 1h-3.4l-.8-1zM42.3 151.6h3.4l.7 .8-.7 .9h-3.4l-.8-.9zM42.3 153.3h3.4l.7 .8-.7 .9h-3.4l-.8-.9zM42.3 158.5h3.4l.7 .8-.7 .8h-3.4l-.8-.8zM42.3 149.8h3.4l.7 .9-.7 .9h-3.4l-.8-.9zM42.5 143h3.2l.7 .8-.7 .8h-3.2zM43.1 157.2l.5 .1-.1 .7h-.4z"/>
<path d="M43.1 155.5l.5 .1v.6l-.3 .1h-.2zM43.1 152l.5 .1-.1 .8h-.4zM43.1 153.7l.5 .2-.1 .7h-.4zM43.1 158.9l.5 .1-.1 .7h-.4zM43.1 150.3l.5 .1v.6l-.3 .2h-.2zM43.1 146.4h2.6l.7 .9-.7 .8h-2.6l-.7-.8zM43.1 148.1h2.6l.7 .9-.7 .8h-2.6l-.7-.8zM43.2 143.4l.3 .8 .2-.8M43.9 157.4l.3-.2v.8M43.9 155.7l.3-.2v.8M43.9 152.3l.3-.3v.9M43.9 154l.3-.3v.9"/>
<path d="M43.9 159.1l.3-.2v.8M43.9 150.5l.3-.2v.9M43.9 146.9h.3l.2 .1v.5l-.2 .2h-.3zM43.9 144.2l.3-.8 .3 .8M43.9 148.5h.3l.2 .3v.4l-.2 .2h-.3zM43.9 158h.5M43.9 156.3h.5M43.9 152.9h.5M43.9 154.6h.5M43.9 159.7h.5M43.9 151.2h.5M44 144h.4"/>
<path d="M44.7 155.5h.6l-.4 .2 .4 .2v.3l-.2 .1-.4-.1M44.7 152.3l.3-.3v.9M44.7 153.8l.4-.1 .2 .2-.6 .7h.6M44.7 143.6l.3-.2v.8M44.7 152.9h.6M44.7 144.2h.6M44.9 157.1l-.2 .7h.6M44.9 150.3h.2a.48 .48 0 0 1 .2 .5 .48 .48 0 0 1-.4 .4 .6 .6 0 0 1 0-.9zM44.9 147.2l-.2-.2 .1-.1h.4v.3l-.5 .2 .1 .3h.4l.1-.3-.2-.2M45.2 158.9h-.4l-.1 .4 .4-.1 .2 .4h-.6M45.2 157.4v.6M45.3 149l-.2 .1-.4-.1 .2-.5 .4 .2v.4l-.2 .3h-.3"/>
<path d="M71.3 146.4h3.3l.8 .9-.8 .8h-3.3l-.7-.8zM72.3 146.9h-.5v.1l.5 .4-.1 .3h-.4M72.6 146.9h.3l.2 .1v.5l-.2 .2h-.3zM73.4 147.7l.2-.8 .4 .8M73.4 147.4h.5M80 149.8h3.4l.6 .9-.6 .9h-3.4zM81.1 150.3h-.5v.2l.5 .3v.3h-.5M81.9 150.4l-.3-.1a.43 .43 0 0 0-.2 .5 .43 .43 0 0 0 .5 .3M82.3 150.3v.9h.5M95.5 141.2v.9h.9l-.9 .9-.8-.9h.8M95.5 141.2h.1M97.5 147.3h3.3l.8 .8-.8 .9h-3.3l-.8-.9z"/>
<path d="M97.5 145.5h3.3l.8 .9-.8 .9h-3.3zM98.8 147.8l-.4-.1-.1 .2 .1 .2 .4 .1-.1 .3h-.4M98.8 146l-.5 .1v.2l.5 .3-.1 .3-.4-.1M99.1 147.7l.5 .2v.5l-.2 .1h-.3zM99.7 146.1l-.4-.1a.44 .44 0 0 0-.1 .6 .44 .44 0 0 0 .5 .2M99.9 148.5l.3-.8 .3 .8M99.9 148.3h.5M100 146v.9h.5M110.2 143h.1M110.2 141.2l-.5 .9M110.2 141.2l.5 .9M110.2 141.2v1.8"/>
<path d="M33.9 167.1h6.6l.8 .8-.8 .9h-6.6zM35.3 167.6a.44 .44 0 0 0-.7 .1 .44 .44 0 0 0 .2 .7l.5-.1M35.6 167.9h.4l.1-.2-.2-.2h-.3v.9M36.4 163.6h4.9v1.7h-4.9l-.8-.8zM36.4 167.5l.1 .9 .5-.1v-.8M37 163.9h3.8M37.1 164a.47 .47 0 0 1 .5 .5 .47 .47 0 0 1-.5 .5zM37.1 168.4h.7M37.9 164h.4M38.1 164v1M38.5 167.6a.42 .42 0 0 0-.5 .2 .42 .42 0 0 0 .1 .6l.4-.1M38.5 165l.3-1 .3 1"/>
<path d="M38.6 164.7h.4M38.9 167.5v.9h.4M39.6 167.5v.9M39.7 167.8l.4 .6M39.8 164.1l-.2-.1-.3 .3v.4l.3 .3 .2-.1M40.1 167.5l-.5 .5M40.3 164v1M40.3 164.5l.4 .5M40.7 164l-.4 .5M42 165.3h3.7l.7 .9-.7 .9h-3.7zM42.9 166.2h.4v-.4h-.4v.9M43 166.2l.4 .5"/>
<path d="M44.3 165.7l-.7 1.1M44.5 165.6h.8M44.6 165.8l.1 .9 .2-.6 .2 .6 .2-.9M67.9 167.1h4.8v1.7h-4.8l-.8-.9zM68.2 167.3h3.7M68.4 167.9h.4l.1-.2-.2-.2h-.3v.9M68.5 167.9l.4 .5M69.2 167.9h.3M69.6 167.5h-.4v.9h.4M70.5 167.6h-.5v.2l.5 .3-.1 .3h-.4M70.8 167.9h.3M71.2 167.5h-.4v.9h.4"/>
<path d="M71.5 167.5h.4M71.8 167.5v.9M105.9 177.3h.6v.2h-.6zM106.5 172.3h4.5M106.5 173.9h2.8M106.5 175.6h2.8M106.5 177.4h2.8M109.3 172.3h.1M110.1 174.8h3.2v1.8h-3.2l-.8-1zM110.1 173.1h3.3l.8 .8-.8 .9h-3.3l-.8-.9zM110.2 171.7l.8 .6M111 175.3l-.5 .1v.2l.5 .1v.3l-.1 .1h-.4"/>
<path d="M111 173.6h-.5l.1 .3 .4 .2v.3h-.5M111 172.3l-.8 .5M111.4 173.5a.49 .49 0 0 1 .4 .3 .49 .49 0 0 1-.1 .6h-.3zM111.9 175.4l-.4-.1-.1 .2 .1 .6h.4M112.1 174.4l.3-.9 .3 .9M112.2 175.3v.8h.4M112.2 174.1h.4M96.2 188.1h2.1v.3h-2.1zM96.2 188.8h2.1v.2h-2.1zM96.4 187.6h.3M96.6 187.4v.3M97.2 186.9v1.2"/>
<path d="M97.2 189v1.3M104 188.1h2v.3h-2zM104 188.8h2v.2h-2zM104.2 187.6h.3M104.3 187.4v.3M105 186.9v1.2M105 189v1.3"/>
</g>
<path d="M107.7 174.5h.5l-.2 .4 .2 .1v.4h-.5M107.8 171.4l.2-.2v.8M107.8 172.9h.4v.3l-.5 .5h.5M107.8 172h.4M108 176.2l-.2 .7h.5M108.2 176.6v.6" fill="none" stroke="#b90000" stroke-width=".21"/>
<path d="M107.7 134.3l.7-.3 .8 .3-.8 .4v1.3v-1.3z" fill="none" stroke="#474747" stroke-width=".21"/>
<path d="M94.5 139h2.1" fill="none" stroke="#910000" stroke-width=".34"/>
<path d="M96.2 188.9h2.1M104 188.9h2" fill="none" stroke="#910000" stroke-width=".25"/>
<g fill="none" stroke="#090" stroke-width=".21">
<path d="M50.8 26.6h13.8M76.6 37.9h.8M76.6 39.6h8.6M135.2 25.8h3.4M185.1 31.9h2.6M195.4 27.6h8.7M30.1 44.7h8.5M34.4 49.9h4.2M34.4 46.4h4.2M38.6 43v.9h-.8M76.6 41.3v.9h.8M76.6 51.7v.8h.8"/>
<path d="M76.6 55.1v.8h.8M76.6 58.5v.9h.8M76.6 49.9h8.6M76.6 46.4h8.6M76.6 43h8.6M76.6 56.9h8.6M76.6 53.4h8.6M101.6 56.9h-5.2v5.1M119.7 53.4h-.9v.8M154.1 50.8h10.4M195.4 42.2h8.7M30.1 62h8.5"/>
<path d="M76.6 60.2h8.6M76.6 62v.9h.8M76.6 63.7h6.8M76.6 65.4h.8M76.6 68.9h5.1M76.6 67.2h.8M76.6 70.6h14.6M106.7 62h13M154.1 73.2h10.4M165.3 61.1h9.5M193.8 60.2h9.4M34.4 99.9h4.2"/>
<path d="M76.6 86.1h2.6M92.9 84.4h5.2M92.9 80.9h5.2M135.2 84.4h3.4M175.6 95.5v1.8M199.8 85.2h6M225.6 82.7h2.6M29.2 103.3h9.4M29.2 106.8h9.4M29.2 108.5h9.4M29.2 105h9.4M34.4 101.6h4.2"/>
<path d="M51.6 113.7h12.1M76.6 105h2.6M170.5 114.5h2.5M186 105.9h5.1M186 104.2h5.1M191.1 107.7h-18.1v3.3M191.1 111h-8.6v8.7M191.1 118v4.3M199.8 102.5h1.7v6.8h-1.7M199.8 105.9h1.7M199.8 104.2h1.7M225.6 103.3h2.6"/>
<path d="M95.5 124.8v.9h-.8M95.5 136h12.9v7M124.8 124.8v.9h-.8M149 130.8h3.4M152.4 132.6h-3.4v.9M155.8 132.6h6M155.8 130.8h6M191.1 120.5h10.4M201.5 124v6.8h-10.4M225.6 124h2.6M67.1 147.3h3.5M67.1 150.7h12.9"/>
<path d="M68.9 145.5v1.8M78.3 145.5v5.2M149 141.2h3.4M152.4 143h-3.4v.8M155.8 143h6M155.8 141.2h6M161.8 146.4v6.9h8.7M179.1 141.2v.9h.9M179.1 143v.8h.9M41.3 164.5h5.1M41.3 167.9h5.1M67.1 164.5h12.9"/>
<path d="M78.3 162.8v1.7M29.2 190.3h75.8M29.2 186.9h75.8"/>
</g>
<g fill="none" stroke="#0000ca" stroke-width=".21">
<path d="M157.9 19.1v.9M158.2 19.1h.3l.2 .2v.5l-.2 .2h-.3zM158.3 16.4v.8l-.4-.8v.8M158.7 16.5h.5a.47 .47 0 0 1-.3 .7l-.2-.1zM159.5 16.4h.5M159.6 19.2l-.2-.1a.43 .43 0 0 0-.4 .5 .43 .43 0 0 0 .6 .3M159.7 16.4v.8M160.3 16.8h.3M160.6 19.3l.2-.2v.9M160.7 16.4h-.4v.8h.4M161.1 17.1v.1M161.1 16.7v.1"/>
<path d="M161.6 19.1a.48 .48 0 0 1 .3 .5 .48 .48 0 0 1-.3 .4l-.2-.1v-.6zM162.1 16.4v.7l.2 .1 .3-.1v-.7M162.9 17.2l.3-.8 .2 .8M163 17h.4M163.3 19.4h-.4v.2l.1 .4 .3-.1M163.6 19.5l.4-.1v.5h-.4zM163.8 16.8h.4v-.4h-.4v.8M164 16.8l.3 .4M164.5 19.5h.3v.5M164.5 19.4v.6M164.5 16.4h.5M164.7 16.4v.8"/>
<path d="M165.2 19.5l.4-.1v.6M165.2 19.4v.6M165.3 16.5l.3-.1 .1 .1v.6l-.1 .1a.48 .48 0 0 1-.3-.7zM165.9 19.7l.4-.1v-.2l-.4 .1v.4l.2 .1 .2-.1M167 16.2a1.02 1.02 0 0 0 0 1.4M167.1 19.4h-.4v.2l.1 .4 .3-.1M167.3 19.4h.4M167.4 19.1v.8l.3 .1M167.7 16.7l-.3-.1-.1 .2 .1 .4 .3-.1M167.9 19.5h.5v.4h-.5zM168 16.8l.4-.2 .1 .5-.3 .1zM168.7 19.4v.6"/>
<path d="M168.9 16.7h.3v.5M168.9 16.6v.6M168.9 19.4l-.2 .2M169.5 19.4h-.2l-.1 .2 .4 .3-.1 .1-.3-.1M169.9 16.7l-.2-.1-.1 .3 .4 .2-.2 .1-.2-.1M170.3 16.7h.4v.4h-.4zM170.6 19.4h.4v.6M171 19.6l-.4 .2 .1 .2 .3-.1M171.2 16.4v.8M171.4 19.4v.6M171.5 16.9l.4-.1-.1-.2-.3 .2v.3l.2 .1 .2-.1M171.7 19.4l-.3 .2"/>
<path d="M171.9 19.7l.4-.1v-.2h-.4v.5h.4M172.3 16.2a1.02 1.02 0 0 1 0 1.4M173.4 19.9l.2 .1 .2-.1-.1-.5h-.3v.9M173.5 16.9h.7M174.1 19.1v.1M174.1 19.4v.6M174.5 19.5l.4-.1v.6M174.5 19.4v.6M174.6 16.6l.6 .3-.6 .2M175.3 19.5l.3-.1v.6M175.3 19.4v.6M176.1 19.7l.3-.1v-.2h-.3v.5h.3"/>
<path d="M176.7 16.7h-.4v.4h.4M177.1 16.7h.3v.5M177.1 16.4v.8M177.2 19.4h-.4l-.1 .2 .2 .4 .3-.1M177.2 19.1v.9M177.8 16.7h.4v.5M178.1 19.4h.3M178.2 16.8l-.4 .2 .1 .2 .3-.1M178.3 19.1v.8l.1 .1M178.6 16.7l.3-.1 .1 .2v.4M178.6 16.6v.6M178.8 19.5h.3v.5"/>
<path d="M178.8 19.1v.9M179.4 16.7l.2-.1 .2 .2v.4M179.4 16.6v.6M179.4 19.7l.5-.1v-.2l-.5 .1v.4l.2 .1 .3-.1M180.1 16.9l.4-.1-.1-.2-.3 .2v.3l.2 .1 .2-.1M180.9 16.4v.7l.2 .1M181.2 19.4h-.3v.3l.3 .1-.1 .2-.2-.1M181.6 19.4l.4 .1v.5M182 16.8h.3l.2-.2-.1-.2h-.4v.8l.5-.1v-.3h-.2M182 19.6l-.4 .2v.2l.4-.1M182.4 19.5l.3-.1v.6M182.4 19.4v.6"/>
<path d="M182.7 19.5l.4-.1v.6M183.5 19.7l.4-.1v-.2h-.4v.5h.4M183.8 16.2a1.02 1.02 0 0 0 0 1.4M184 17.2l.3-.8 .2 .8M184.1 17h.3M185 16.7l-.2-.2 .1-.1h.3l.1 .2-.5 .3 .2 .3 .3-.1v-.3l-.2-.1M185 19.4h.3v.6M185.3 19.6l-.4 .2 .1 .2 .3-.1M185.6 16.8h.7M185.6 17h.7M186 19.4h-.3l-.1 .2 .5 .3-.2 .1-.3-.1M186.8 16.4h.3l.1 .1v.6l-.2 .1-.3-.1z"/>
<path d="M187.1 19.6h.3l.2-.3-.2-.2h-.3v.9M187.2 19.6l.4 .4M187.5 16.2a1.02 1.02 0 0 1 0 1.4M188.3 19.2h-.4v.2l.4 .3v.3l-.4-.1M188.7 19.2h.5v.3l-.5 .5h.5M189.5 19.1h.5l-.3 .3 .3 .2v.3l-.1 .1-.4-.1M190.4 19.2l.3-.1 .2 .2-.6 .7h.6M191.9 19.1l.4 .2v.5l-.2 .2h-.2zM192.7 19.5h.4l.1-.3-.5-.1v.9h.4l.1-.3-.2-.2M194 19.5l-.3 .2-.2-.4 .2-.2 .3 .1-.1 .7-.3 .1M194.4 19.9l-.1 .2M157.8 20.8l.1 .6 .1-.4 .2 .4 .2-.6"/>
<path d="M157.9 22.2l.3 .1v.4h-.3l-.1-.1 .1-.2h.3M157.9 26.4l.3 .1v.4h-.3v-.3l.3-.1M158.3 24.7v.8l-.4-.8v.8M158.7 20.5v.1M158.7 25h.4l-.1 .5-.3-.1zM158.7 20.8v.6M159 20.8h.3M159.1 20.5v.8l.2 .1M159.3 26.9h.3v-.5h-.3v.8M159.3 22.2v.5M159.4 24.9h.3M159.5 22.2h-.2v.2"/>
<path d="M159.5 24.7v.7l.2 .1M159.6 20.9h.4v.5M159.6 20.5v.9M159.7 22.5l.4-.1v-.2l-.4 .1v.3l.4 .1M160 25.3l.4-.1-.2-.3-.2 .1v.5h.3M160.1 26.4h.3v.5l-.4-.1zM160.6 22.3h.3v.4M160.6 20h.5M160.6 22.2v.5M160.7 25.4v.1M160.7 25v.1M160.8 26.4v.5"/>
<path d="M160.9 22.3l.3-.1v.5M161.1 26.4l-.3 .1M161.1 21h.7M161.2 26.4h.4M161.3 26v.8l.3 .1M161.4 20.7v.7M161.7 22.3l.3-.1v.5l-.3-.1zM161.9 24.7h.3l.1 .2-.1 .6h-.3l-.1-.2zM162.3 22.2h.4M162.4 21.9v.7l.3 .1M162.5 20.5h-.4v.5l.4-.1 .1 .3-.2 .2-.3-.1M162.5 26.4h.4v.5h-.4l-.1-.2 .5-.2"/>
<path d="M162.7 25l.2-.1 .2 .2v.4M162.7 24.9v.6M162.9 20.5l.2 .9 .3-.9M162.9 22.5l.4-.1v-.2h-.4v.5h.4M163.2 26.4h.2M163.3 26v.9h.1M163.4 24.7v.7l.2 .1M163.9 24.9l.1 .6M164.3 24.9l-.4 .9M164.4 20.9h.3v.4h-.3M164.4 21.9v.8h.2l.1-.4-.3-.1M164.4 20.5v.9"/>
<path d="M164.5 26.4l.3 .1v.4h-.3v-.3l.3-.1M165.1 21.1l.4-.1-.1-.2-.3 .2v.3h.4M165.1 22.2h.4v.5h-.4zM165.2 26.5l.4-.1v.5M165.2 26.4v.5M165.6 25h-.4v.4l.4 .1M165.9 20.5v.1M165.9 22.2h.3v.5h-.3v-.2l.3-.1M165.9 25.1l.3-.2 .2 .2-.1 .4h-.3zM165.9 20.8v.6M165.9 26.4l.2 .5M166.2 20.9l.3-.1 .2 .2v.4"/>
<path d="M166.2 20.8v.6M166.3 26.4l-.4 .8M166.7 22.2v.5M166.7 25l.3-.1 .2 .2v.4M166.7 24.9v.6M166.9 22.2l-.2 .2M167.4 20.8v.7l-.1 .1h-.2M167.4 20.9l-.2-.1-.2 .2 .2 .4 .2-.1M167.5 25l.3-.1 .1 .2v.4M167.5 24.9v.6M167.6 21.9v.8h-.3l-.1-.4 .4-.1M167.7 26.9h-.4v-.5h.4v.6l-.2 .2-.2-.1"/>
<path d="M168.1 26v.1M168.1 26.4v.5M168.3 25.3l.4-.1-.2-.3-.2 .2v.3l.3 .1M168.4 26.4l.2 .5 .2-.5M168.5 20.9h.4v.4h-.4M168.5 22.2l.2 .5 .2-.3 .1 .3 .2-.5M168.5 20.8v.8M169.1 26.6l.4-.1v-.1h-.4v.5h.4M169.3 20.8v.6M169.5 25h-.5v.4l.5 .1M169.5 20.8l-.2 .2M169.5 21.9v.1"/>
<path d="M169.5 22.2v.5M169.7 24.9h.3M169.8 24.7v.8h.2M169.8 22.2h.3M169.9 20.8l.3 .2-.2 .4-.2-.1zM169.9 26.5l.3-.1v.5M169.9 26.4v.5M170 21.9v.8h.1M170.5 20.8l.2 .6 .2-.6M170.5 22.3l.3-.1v.5M170.5 21.9v.8M170.9 25.1l.2-.2 .2 .1-.1 .5h-.2z"/>
<path d="M171.2 26.4h.3M171.2 20.5v.1M171.2 20.8v.6M171.3 26v.9h.2M171.7 25h.4v.5M171.7 24.9v.6M171.8 26v.1M171.8 26.4v.5M171.9 22.4h.4l.1-.2-.1-.3h-.4v.8M172 20.9l-.3-.1-.1 .2 .1 .4 .3-.1M172 20.5v.9M172.1 22.4l.3 .3"/>
<path d="M172.3 26.5h.3v.4M172.3 26.4v.5M172.4 21.1l.4-.1-.1-.2-.3 .1v.4h.4M172.4 25.3l.4-.1v-.3l-.4 .2v.3l.4 .1M172.6 26.5l.3-.1v.5M173.2 22l-.4-.1-.1 .2 .1 .2 .4 .1v.2l-.5 .1M173.4 26.6l.4-.1-.1-.1h-.3v.5h.3M173.5 20.9l-.2-.1-.2 .2 .2 .4 .2-.1M173.5 22l.4-.1 .1 .2-.5 .6h.5M173.5 20.5v.9M173.9 24.7v.8M173.9 25.2l.3 .3"/>
<path d="M174.1 26.9h.1M174.2 24.9l-.3 .4M174.3 21.9h.6l-.4 .3 .4 .2-.1 .3-.5-.1M174.5 21l.4-.2 .1 .4-.3 .2zM174.6 24.7v.1M174.6 24.9v.6M175 25l.2-.1 .2 .2v.4M175 24.9v.6M175.1 22h.5v.3l-.5 .4h.5M175.4 20.9h.3v.5M175.4 20.8v.6M176.1 24.7v.8h-.3l-.1-.4 .2-.2 .2 .1"/>
<path d="M176.7 21.9v.7l.1 .1M176.8 20.9l.3-.1 .1 .2-.1 .4-.3-.1M176.8 20.8v.8M177.2 21.9v.1M177.2 25.1l.3-.2 .2 .2-.1 .4h-.4zM177.2 22.2v.5M177.6 20.5v.1M177.6 22.3h.3v.4M177.6 20.8v.6M177.6 22.2v.5M177.8 24.9h.4M178 20.9h.3v.5"/>
<path d="M178 20.8v.6M178.2 24.7h-.2v.8M178.3 22.5l.4-.1v-.2l-.4 .1v.3l.4 .1M179.1 25.3l.4-.1-.1-.3-.3 .1v.5h.3M179.4 20.8l.2-.3v.9M179.4 21.4h.5M179.8 24.9l.5 .6M180.1 21.9v.8h-.3l-.1-.4 .4-.1M180.3 24.9l-.5 .6M180.4 20.5a.39 .39 0 0 1 .4 .5 .39 .39 0 0 1-.5 .3l-.1-.4zM180.5 22.2v.5M180.5 24.9h.3"/>
<path d="M180.5 24.7v.7l.3 .1M180.7 22.2l-.2 .2M181.1 21.3v.1M181.1 21.9v.1M181.1 25.3l.4-.1-.2-.3-.2 .1v.5h.3M181.1 22.2v.5M181.4 22.2l.2 .5 .1-.5M181.8 24.9v.6M182.1 22.5l.4-.1-.1-.2h-.3v.5h.3M182.1 24.9l-.3 .2M182.3 25l.3-.1 .1 .2v.4M182.3 24.9v.6"/>
<path d="M182.7 20.5h.5M182.8 22.2v.5M182.9 20.5v.9M183.1 22.2l-.3 .2M183.1 25l.2-.1 .2 .2v.4h-.4l.1-.3h.3M183.4 20.9l.3-.1 .2 .2v.4M183.4 20.5v.9M183.7 22.2h-.4l.1 .3h.3v.2h-.4M183.9 24.7l.1 .8M184.3 20.5v.1M184.3 20.8v.6M184.6 22.2h.4"/>
<path d="M184.7 21.9v.7l.3 .1M185 20.9h-.4l.1 .2h.3l-.1 .3-.3-.1M185 24.7v.1M185 24.9v.6M185.3 22.2l.3 .1-.1 .4-.3-.1zM185.5 25l.1-.1 .2 .2v.4M185.5 24.9v.6M186 20.9l.2-.1 .2 .2v.4M186.1 24.9h.3M186.2 24.7v.8h.2M186.4 21l-.4 .1 .1 .3 .3-.1M186.6 21.9v.8h.4v-.5h-.4"/>
<path d="M186.6 25.3l.5-.1-.2-.3-.3 .2v.3l.4 .1M186.8 20.5l.1 .9M187.2 20.5l.1 .9M187.4 22.5l.4-.1-.1-.2h-.3v.5h.3M187.4 24.9v.6M187.7 20.9h.4v.4h-.4zM187.7 24.9l-.3 .2M187.8 24.9h.4M188.2 24.7h-.2v.8M188.3 20.8l.2 .6 .2-.4 .1 .4 .2-.6M188.4 25l.3-.1 .1 .2v.4h-.4l.1-.3h.3M188.8 22.2h.4v.5h-.4v-.1l.1-.2h.3"/>
<path d="M189.6 20.9l-.2-.1v.2l.3 .3h-.3M189.6 25l-.2-.1-.2 .2 .1 .4h.3M189.9 21.9v.8h-.3v-.5h.3M189.9 25.3l.5-.1-.2-.3-.3 .1v.5h.4M190.6 20.8h.3M190.8 21.9v.8h-.3l-.1-.4 .4-.1M190.9 20.5l-.2 .1v.8M191.1 21l.4-.2 .1 .4-.3 .2zM191.1 22.5l.5-.1-.1-.2h-.4v.5h.4M191.2 24.9h.4M191.4 24.7v.8h.2M191.8 25.1l.2-.2 .2 .1v.5h-.3z"/>
<path d="M192 20.8v.6M192.2 20.8l-.2 .2M192.2 21.9v.8h-.2l-.1-.4 .3-.1M192.7 22.6v.1M214.8 28.7h.5l-.3 .4 .3 .1v.4h-.5M214.8 26.3l.2-.3v.9M214.8 27.5h.5v.2l-.5 .5h.5M214.8 36.1h.4l.1-.3-.5-.1v.8h.5v-.2l-.2-.2M214.8 25h.3M214.8 26.9h.5M215 30.1l-.2 .7h.5M215.2 33h-.3l-.1 .1v.6h.5v-.4l-.4-.1-.1 .2"/>
<path d="M215.2 30.4v.6M215.3 24.6h-.5v.8M215.3 31.5h-.5v.5h.5v.3h-.5M215.4 24.6h.5M215.7 24.6v.8M215.7 26.5h.6M215.7 26.6h.6M215.7 27.8h.6M215.7 28.1h.6M215.7 29.2h.6M215.7 29.4h.6M215.7 30.6h.6"/>
<path d="M215.7 30.9h.6M215.7 32h.6M215.7 32.2h.6M215.7 33.3h.6M215.7 33.6h.6M215.8 36l.3 .1v.4h-.4zM216.2 24.6h.2l.3 .2v.5l-.2 .1h-.3zM216.4 36h.3M216.4 35.7v.7l.3 .1M216.6 28.7l.3 1 .3-1M216.6 30.2h.5M216.7 32h.5v-.4l-.5-.1v.9"/>
<path d="M216.9 30.2v.8M217 36.1l.3-.1 .1 .5M217 32l.2 .4M217 35.7v.8M217.1 24.6v.8M217.2 26h-.3l-.2 .2v.4l.3 .3 .2-.1v-.3h-.2M217.2 27.5l-.2-.1-.3 .2v.5l.2 .1 .3-.1M217.2 33.1l-.3-.1-.2 .1v.5l.3 .2 .2-.1M217.3 30.4l.4 .6M217.5 27.4h.5M217.5 31.9l.5 .5M217.5 33h.5"/>
<path d="M217.7 27.4v.8M217.7 33v.8M217.7 30.4l-.4 .6M217.8 29.1h-.3v.5h.3M218 31.9l-.5 .5M218.1 26v.9l-.6-.9v.9M218.1 30.2h.3l.2 .1v.6l-.3 .1h-.2zM218.3 31.5a.49 .49 0 0 1 .5 .3 .49 .49 0 0 1-.2 .6h-.3zM218.4 36.5h.4l-.1-.5h-.3v.9M218.5 26h.3a.48 .48 0 0 1 .2 .6 .48 .48 0 0 1-.5 .3zM218.6 24.9l-.5 .1v.4h.5M218.6 29.1h-.4l-.1 .1 .2 .5 .3-.1"/>
<path d="M218.7 27.5h-.5v.2l.5 .3-.1 .2h-.4M218.7 33l-.5 .1 .1 .2 .4 .3-.1 .2-.4-.1M218.9 24.9h.3v.5h-.4zM219.2 36l.4 .1v.4h-.4zM219.7 25l.3-.1 .1 .5M219.7 24.9v.5M220 36v.5M220.2 36l-.2 .2M220.3 36h.4M220.4 25l.4-.1v.5M220.4 24.9v.5M220.5 35.7v.8h.2"/>
<path d="M221.2 25.2l.4-.1-.1-.2-.3 .1v.4h.3M221.3 36h-.3l-.1 .2 .5 .2-.5 .1M222.4 24.9l-.4 .1v.4h.4M222.6 24.9h.3M222.7 24.6v.8h.2M222.7 36h-.3l-.1 .2 .1 .3h.3M223.1 36.1h.4v.4h-.4zM223.2 24.9h.4v.5h-.5zM223.9 36.1h.3v.4M223.9 36v.5M224 24.9v.5M224.2 24.9l-.2 .2"/>
<path d="M224.5 25.4h.1M224.5 24.9v.1M224.5 36h.3M224.8 35.7l-.1 .1v.7M225.2 35.7v.1M225.2 36v.5M225.9 36.5h-.4l.1-.5h.3v.7l-.1 .2-.3-.1M226.4 36v.5h.3v-.5M227.1 36v.5M227.4 36l-.3 .2M227.6 36.3l.4-.1v-.2h-.4v.5h.4M228.7 35.7v.8h-.3v-.5h.3"/>
<path d="M229.8 36h.4v.5h-.4l-.1-.1 .5-.2M230.8 36h-.2v.3l.3 .1-.3 .1M232.4 35.7v.8l-.5-.8v.8M232.9 35.7v.8h.4v-.8M233.7 35.7v.8h.4M234.5 35.7v.8h.3M235.8 36.1h.4v.4M235.8 36v.5M236.2 36.1l.3-.1v.5M236.9 36.1l.4-.1v.5h-.4zM238.1 35.7v.8h-.4v-.4l.4-.1M238.5 36.3l.4-.1-.1-.2-.3 .1v.3l.3 .1"/>
<path d="M239.2 36.1h.4v.4M239.2 36v.5M239.6 36.1h.4v.4M240.4 36.5h.1"/>
</g>
<g fill="none" stroke="#00008a" stroke-width=".21">
<path d="M38.3 35.8l.8 .7M38.3 39.2l.8 .8M39.1 35.8l-.8 .7M39.1 39.2l-.8 .8M203.7 30.5l.8 .9M204.5 30.5l-.8 .9M38.3 53l.8 .8M39.1 53l-.8 .8M153.7 48.6l.9 .9M153.7 46.9l.9 .9M154.6 48.6l-.9 .9M154.6 46.9l-.9 .9"/>
<path d="M203.7 45.2l.8 .8M204.5 45.2l-.8 .8M76.2 71.9l.8 .9M76.2 73.6l.8 .9M76.2 75.3l.8 .9M76.2 77.1l.8 .8M76.2 78.8l.8 .8M77 71.9l-.8 .9M77 73.6l-.8 .9M77 75.3l-.8 .9M77 77.1l-.8 .8M77 78.8l-.8 .8"/>
<path d="M119.2 63.3l.9 .8M120.1 63.3l-.9 .8M153.7 71.1l.9 .7M153.7 69.3l.9 .8M154.6 71.1l-.9 .7M154.6 69.3l-.9 .8M76.2 94.3l.8 .8M76.2 90.9l.8 .7M76.2 92.6l.8 .8M76.2 89.1l.8 .9M76.2 83.9l.8 .9M76.2 87.4l.8 .9"/>
<path d="M76.2 80.5l.8 .8M76.2 82.3l.8 .8M76.2 96.1l.8 .7M76.2 97.7l.8 .9M76.2 99.4l.8 .9M77 94.3l-.8 .8M77 90.9l-.8 .7M77 92.6l-.8 .8M77 89.1l-.8 .9M77 83.9l-.8 .9M77 87.4l-.8 .9M77 80.5l-.8 .8"/>
<path d="M77 82.3l-.8 .8M77 96.1l-.8 .7M77 97.7l-.8 .9M77 99.4l-.8 .9M97.7 87.4l.8 .9M97.7 89.1l.8 .9M97.7 90.9l.8 .7M98.5 87.4l-.8 .9M98.5 89.1l-.8 .9M98.5 90.9l-.8 .7M175.2 98.6l.9 .8M176.1 98.6l-.9 .8"/>
<path d="M76.2 102.9l.8 .9M76.2 101.2l.8 .8M77 102.9l-.8 .9M77 101.2l-.8 .8M190.7 102.1l.9 .8M190.7 108.9l.9 .9M191.6 108.9l-.9 .9M191.6 102.1l-.9 .8M199.3 112.4l.9 .8M199.3 110.7l.9 .8M199.3 107.2l.9 .9M199.3 100.3l.9 .8"/>
<path d="M200.2 112.4l-.9 .8M200.2 110.7l-.9 .8M200.2 107.2l-.9 .9M200.2 100.3l-.9 .8M101.1 152.9l.9 .8M102 152.9l-.9 .8M118.4 146l.8 .8M118.4 151.2l.8 .7M119.2 146l-.8 .8M119.2 151.2l-.8 .7M66.7 162.3l.8 .9M67.5 162.3l-.8 .9"/>
</g>
<g fill="#090">
<circle cx="175.6" cy="97.3" r=".38"/>
<circle cx="201.5" cy="105.9" r=".38"/>
<circle cx="201.5" cy="104.2" r=".38"/>
<circle cx="201.5" cy="102.5" r=".38"/>
<circle cx="135.2" cy="25.8" r=".38"/>
<circle cx="135.2" cy="84.4" r=".38"/>
<circle cx="191.1" cy="120.5" r=".38"/>
<circle cx="161.8" cy="148.1" r=".38"/>
<circle cx="170.5" cy="153.3" r=".38"/>
<circle cx="191.1" cy="130.8" r=".38"/>
<circle cx="62.8" cy="26.6" r=".38"/>
<circle cx="57.6" cy="26.6" r=".38"/>
<circle cx="59.4" cy="26.6" r=".38"/>
<circle cx="61.1" cy="26.6" r=".38"/>
<circle cx="55.9" cy="26.6" r=".38"/>
<circle cx="52.4" cy="26.6" r=".38"/>
<circle cx="101.6" cy="56.8" r=".38"/>
<circle cx="50.8" cy="26.6" r=".38"/>
<circle cx="53.3" cy="113.7" r=".38"/>
<circle cx="55.1" cy="190.3" r=".38"/>
<circle cx="55.1" cy="186.9" r=".38"/>
<circle cx="46.4" cy="190.3" r=".38"/>
<circle cx="63.7" cy="186.9" r=".38"/>
<circle cx="37.8" cy="186.9" r=".38"/>
<circle cx="37.8" cy="190.3" r=".38"/>
<circle cx="46.4" cy="186.9" r=".38"/>
<circle cx="29.2" cy="186.9" r=".38"/>
<circle cx="29.2" cy="190.3" r=".38"/>
<circle cx="68.9" cy="147.3" r=".38"/>
<circle cx="56.8" cy="113.7" r=".38"/>
<circle cx="55.1" cy="113.7" r=".38"/>
<circle cx="58.5" cy="113.7" r=".38"/>
<circle cx="60.2" cy="113.7" r=".38"/>
<circle cx="61.9" cy="113.7" r=".38"/>
<circle cx="51.6" cy="113.7" r=".38"/>
<circle cx="78.3" cy="150.7" r=".38"/>
<circle cx="80.9" cy="190.3" r=".38"/>
<circle cx="72.3" cy="190.3" r=".38"/>
<circle cx="80.9" cy="186.9" r=".38"/>
<circle cx="89.5" cy="186.9" r=".38"/>
<circle cx="89.5" cy="190.3" r=".38"/>
<circle cx="78.3" cy="164.5" r=".38"/>
<circle cx="72.3" cy="186.9" r=".38"/>
<circle cx="63.7" cy="190.3" r=".38"/>
<circle cx="97.2" cy="190.3" r=".38"/>
<circle cx="97.2" cy="186.9" r=".38"/>
</g>
<path d="M109.5 134.3l.5-.1v-.2l-.5-.1v.8M110.4 134.2h.4l-.1 .5-.3-.1zM111.1 134.2l.2 .5 .2-.4 .1 .4 .2-.5M112.1 134.4l.4-.1-.1-.1h-.3v.5h.3M112.8 134.2v.5M113.1 134.2l-.3 .1" fill="none" stroke="#910089" stroke-width=".21"/>
<g fill="none" stroke="#006665" stroke-width=".21">
<path d="M49.7 23.3h.6M50 23v.6M51.1 22.7h-.4v.5l.3-.1 .2 .4h-.5M51.4 22.7l.3 .9 .2-.9M66.2 27l.2-.8 .3 .8M66.2 24.5v.7l.2 .2 .4-.2v-.7M66.2 26.8h.5M66.8 26.2h.5M67.1 26.2v.8M67.5 24.5h-.2l-.2 .7 .2 .2 .3-.1v-.5h-.3l-.2 .1M67.7 26.6h.2M68 26.2h-.3v.8"/>
<path d="M68 24.5a.42 .42 0 0 1 .4 .3 .42 .42 0 0 1-.1 .5h-.3zM68.4 26.5l.2-.3v.8M68.4 27h.5M68.8 24.8l.2-.3v.9M68.8 25.4h.5M69.6 26.2h-.4v.4l.4-.1v.5h-.4M70.1 26.3l.3-.1 .1 .2-.1 .6a.39 .39 0 0 1-.4-.2 .39 .39 0 0 1 .1-.5zM71 26.5l-.2-.2 .4-.1v.3l-.4 .1 .1 .4h.3l.1-.3-.1-.2M71.6 27l.2-.8 .3 .8M71.7 26.8h.3M72.9 26.2h-.5l-.1 .2 .2 .2 .4 .1v.3h-.6M73.3 26.7h.6"/>
<path d="M74.2 26.2h.6l-.3 .8M75 27l.3-.8 .3 .8M75.1 26.8h.4M75.8 26.2l.5 .8M76.3 26.2l-.5 .8M76.7 26.5l.2-.3v.8M76.7 27h.5M77.5 26.3l.3-.1 .1 .2-.1 .6a.39 .39 0 0 1-.4-.2 .39 .39 0 0 1 .1-.5zM78.4 26.3v-.1a.43 .43 0 0 1 .4 .4 .43 .43 0 0 1-.4 .4l-.1-.3zM134.1 22.4h.6M134.4 22.1v.6M135.5 21.9h-.4v.4l.4-.1v.5l-.4-.1"/>
<path d="M135.8 21.9l.3 .8 .3-.8M140.2 26.2h.5M140.3 24.5v.7l.2 .2 .3-.2v-.7M140.4 26.2v.8M141 26.2v.8h.4M141.6 24.5h-.3l-.1 .7 .1 .2 .4-.1v-.5h-.4l-.1 .1M141.7 26.5l.2-.3v.8M141.7 27h.4M142.1 24.5a.42 .42 0 0 1 .4 .3 .42 .42 0 0 1-.1 .5l-.2 .1-.2-.2zM142.9 26.2h-.3l-.2 .7 .1 .1h.5l-.1-.5h-.4l-.1 .2M142.9 24.6l.3-.1 .1 .3-.5 .6h.5M143.8 26.3l-.3-.1-.2 .2v.5l.2 .1h.3"/>
<path d="M144.1 26.3l.5-.1v.2l-.5 .6h.5M145.4 26.2h-.4v.4l.4-.1 .1 .2-.1 .3h-.4M146.3 26.2h-.5v.4l.4-.1 .1 .5h-.5M146.6 26.3l.4-.1 .1 .2-.5 .6h.5M179.6 27.5h.4v-.4l-.4-.1v.9M179.8 27.5l.2 .4M180.4 29l.2-.3v1M180.4 29.7h.5M181 27v.9l-.5-.9v.9M181.4 28.7a.48 .48 0 0 1 .4 .5 .48 .48 0 0 1-.4 .5l-.2-.2v-.6zM181.7 27l-.4 .3v.5l.4 .1v-.5h-.3l-.1 .2M182.1 28.7v1"/>
<path d="M182.2 29.2l.4 .5M182.3 27l.3 .2-.1 .7h-.3v-.2v-.5zM182.6 28.7l-.5 .5M182.9 27.3l.3-.3v.9M182.9 27.9h.5M186.6 28.5h.6M186.9 28.1v.6M188.1 27.9h-.4l-.1 .4h.5v.4h-.5M188.3 27.9l.4 .8 .2-.8M194.8 30.5h-.4l-.1 .4 .1 .5 .5-.1v-.3h-.2M195.7 30.5v.9l-.5-.9v.9M196.1 30.5l.5 .1v.4l-.1 .4h-.4z"/>
<path d="M203.7 25.4v.7l.1 .1 .3-.1v-.7M204.4 26.2l.3-.8 .3 .8M204.5 25.9h.4M205.3 25.8h.4v-.4h-.4v.8M205.4 25.8l.4 .4M205.9 23.6v.7l-.3 .2M205.9 38.2v.8l-.3 .2M206 25.4h.5M206.3 25.4v.8M206.7 23.6l-.3 .2v.6h.4v-.4l-.3-.1-.1 .2M206.7 38.2l-.3 .3v.6h.4v-.5h-.3l-.1 .1M206.9 25.4h.2l.1 .1v.5l-.2 .2a.48 .48 0 0 1-.3-.4 .48 .48 0 0 1 .2-.4z"/>
<path d="M207.2 23.7l.3-.1 .1 .1v.6l-.1 .2a.53 .53 0 0 1-.3-.8zM207.2 38.3l.3-.1 .1 .2v.6l-.1 .2a.53 .53 0 0 1-.3-.9zM208 23.8l.2-.2v.9M208 38.3l.3-.1 .2 .3-.6 .7h.6M208 24.5h.5M208.2 25.8h.4M208.7 25.4h-.5v.8M208.9 25.4h.4M209.1 25.4v.8M209.7 25.4h.3a.47 .47 0 0 1 .2 .5 .47 .47 0 0 1-.5 .3zM210.5 25.4v.8M100.5 53.5h.6"/>
<path d="M100.8 53.1v.6M101.9 52.9h-.3l-.1 .4 .3-.1 .2 .4-.5 .1M102.2 52.9l.3 .8 .3-.8M105.1 59.1l.2-.2v.8M105.1 59.7h.4M106 59.6v.1M106.5 59.2l-.2-.1 .1-.2h.3v.3l-.4 .2 .1 .3h.3l.1-.1-.2-.4M107 57.2l.2 .4 .3-.4M107.2 57.6v.4M107.3 58.8l-.2 .7h.6M107.6 59.1v.6M107.9 58.9h.5l-.2 .3 .2 .1v.3h-.5"/>
<path d="M108.2 57.2h-.3l-.2 .7 .2 .1h.3v-.5l-.3-.1-.2 .2M108.7 57.2a.42 .42 0 0 1 .4 .3 .42 .42 0 0 1-.2 .5h-.1l-.2-.1zM108.8 59l.4-.1 .1 .2-.5 .6h.5M109.4 57.4l.3-.2v.8M109.4 58h.5M109.6 59.7v-.8l.3 .6 .3-.6v.8M110.6 58.9v.8M110.6 59.3h.5M111.1 58.9v.8M111.5 59.1h.4l-.4 .6h.4M163.8 57.3a.43 .43 0 0 0-.5 .2 .43 .43 0 0 0 .1 .5h.4l-.1-.3M164.7 57.2v.8l-.5-.8v.8"/>
<path d="M165.1 57.2h.2l.3 .2v.5l-.2 .1h-.3zM166.4 51.4l.3-.2v.8M166.4 53.4l.3-.1v-.3h-.3v.7M166.4 52h.5M166.6 53.4l.1 .3M167.3 51.2h.3l.1 .1-.1 .7h-.3v-.1zM167.3 53a.45 .45 0 0 0-.1 .7l.2-.1v-.3l-.4 .1M167.8 53a.41 .41 0 0 1 .3 .3 .41 .41 0 0 1-.3 .4l-.1-.3zM168.1 51.2v.8M168.2 51.5l.4 .5M168.4 53h.4l-.3 .7M168.6 51.2l-.5 .5"/>
<path d="M177.3 54.6v.8l.2 .1 .3-.1v-.8M178 52.9v.6l-.3 .2M178.1 55.5l.2-.9 .4 .9M178.2 55.2h.4M178.8 52.9l-.4 .1-.1 .7 .6-.1-.2-.4-.4 .2M178.9 55.1h.5v-.5h-.5v.9M179.1 55.1l.3 .4M179.4 52.9l.2 .1-.1 .7-.3-.1v-.6zM179.7 54.6h.4M180 52.9h.5l-.3 .3 .3 .1v.4h-.5M180 54.6v.9M180.5 54.7l.3-.1 .1 .2v.5l-.2 .2a.48 .48 0 0 1-.2-.8z"/>
<path d="M194.8 45.2h-.4a.44 .44 0 0 0-.1 .6 .44 .44 0 0 0 .6 .1v-.2h-.2M195.7 45.2v.8l-.5-.8v.8M196.1 45.2h.4a.47 .47 0 0 1 .1 .5 .47 .47 0 0 1-.5 .3zM203.7 40v.8h.1h.3v-.8M204.4 40.8l.3-.8 .3 .8M204.5 40.6h.4M205.3 40.4h.4v-.4h-.4v.8M205.4 40.4l.4 .4M205.7 53.7v.8l.2 .1h.3v-.9M206 40h.5M206.3 40v.8M206.4 52v.8l-.4 .1"/>
<path d="M206.5 54.6l.3-.9 .2 .9M206.5 54.4h.5M206.7 40.3l.3-.3v.8M206.7 40.8h.5M207.1 52l-.3 .3v.5h.4l-.1-.4-.3 .1M207.4 54.2l.4-.1-.1-.4h-.3v.9M207.6 54.2l.2 .4M207.6 52.1l.3-.1 .2 .2-.1 .6a.39 .39 0 0 1-.5-.2 .39 .39 0 0 1 .1-.5zM208.1 53.7h.5M208.2 40.4h.4M208.3 53.7v.9M208.6 52l-.2 .6h.5"/>
<path d="M208.7 40h-.5v.8M208.8 54l.3-.3v.9M208.8 54.6h.5M208.8 52.4v.5M208.9 40h.4M209.1 40v.8M209.7 40h.3a.47 .47 0 0 1 .2 .6 .47 .47 0 0 1-.5 .2zM210.5 40v.8M99.5 74.9l.4-.1v-.3h-.4v.8M99.7 74.9l.2 .4M100.3 76.2h.5l-.3 .3 .3 .1v.3h-.5M100.9 70.1h-.4v.2v.5l.2 .2 .3-.1v-.2h-.2"/>
<path d="M100.9 74.5v.8l-.5-.8v.8M101.1 76.2v.8M101.3 76.5l.3 .5M101.6 74.5l-.4 .1v.6l.4 .1 .1-.4h-.5M101.6 76.2l-.5 .5M101.8 70.1v.9l-.5-.9v.9M102 76.2h.5l-.3 .3 .3 .2-.1 .3-.4-.1M102.1 74.5h.3l.1 .1v.5l-.2 .2-.2-.2zM102.2 70.1h.4a.47 .47 0 0 1 .1 .6 .47 .47 0 0 1-.5 .3zM102.8 74.5h.5v.3l-.5 .5h.5M103.9 75.8h.6M104.3 75.5v.7"/>
<path d="M105.4 75.3h-.5v.4l.5-.1v.4l-.1 .2-.4-.1M105.7 75.3l.3 .9 .2-.9M163.8 79.6h-.4a.43 .43 0 0 0-.1 .5 .43 .43 0 0 0 .5 .3l-.1-.4M164.6 64.1h-.3a.44 .44 0 0 0-.1 .6 .44 .44 0 0 0 .5 .2v-.3h-.2M164.7 79.6v.9l-.5-.9v.9M165.1 79.6h.3l.2 .2v.4l-.3 .3h-.2zM165.6 64.1v.9l-.5-.9v.9M166 64.1h.3l.1 .2v.4l-.2 .3h-.2zM166.4 73.8l.3-.3v1M166.4 75.7h.3v-.3h-.3v.7M166.4 74.5h.5M166.6 75.7l.1 .4"/>
<path d="M167.3 75.4h-.1l-.2 .5 .1 .2 .3-.1-.1-.4h-.2l-.1 .2M167.4 73.5l.3 .2v.6l-.2 .2-.2-.2v-.6zM167.8 75.4h.2v.7h-.2zM168.1 73.5v1M168.2 74l.4 .5M168.6 73.5l-.5 .5M168.7 75.4l-.3 .2v.4l.3 .1v-.5h-.3v.2M186.2 64.6h.7M186.6 64.3v.7M187.7 64.1h-.4l-.1 .4h.5v.4h-.5M188 64.1l.3 .9 .3-.9M193.1 63.3l-.1-.1a.43 .43 0 0 0-.4 .5 .43 .43 0 0 0 .5 .3v-.3h-.2"/>
<path d="M194 63.2v.9l-.5-.9v.9M194.3 63.2h.3l.3 .3v.4l-.3 .2h-.3zM214.7 63.8h.6M215 63.5v.6M216.1 63.2h-.3l-.1 .4 .3-.1 .2 .5-.2 .1-.3-.1M216.4 63.2l.3 .9 .3-.9M220.1 78.4h.3l.2-.4-.2-.2h-.3v.9M220.3 78.4l.3 .3M220.8 79.9l.3-.3v.9M221.4 77.8v.9l-.5-.9v.9M221.8 79.7l.1-.1a.45 .45 0 0 1 .3 .4 .45 .45 0 0 1-.2 .5l-.3-.4zM222.2 77.8l-.2 .1-.2 .7h.5l-.2-.4-.3 .2"/>
<path d="M222.5 79.6v.9M222.7 80l.4 .5M222.8 77.8a.53 .53 0 0 1 .3 .9l-.5-.1v-.6zM223.1 79.6l-.6 .4M223.4 77.8h.5l-.3 .4 .3 .1v.4h-.5M227 79.3h.7M227.4 78.9v.7M228.6 78.7h-.5v.4h.5v.4h-.5M228.8 78.7l.3 .9 .3-.9M103.1 99.1h.6M103.3 98.8v.6M104.5 98.5h-.4v.4h.4v.5h-.4"/>
<path d="M104.8 98.5l.3 .9 .3-.9M132.3 99.1h.7M132.6 98.8v.6M133.8 98.5h-.4v.4h.4v.5h-.4M134.1 98.5l.3 .9 .3-.9M134.5 87.4a.43 .43 0 0 0-.5 .3 .43 .43 0 0 0 .2 .5l.4-.1v-.3h-.2M135.4 87.3v.9l-.5-.9v.9M135.8 87.3l.5 .3v.4l-.2 .2h-.3zM169.1 91.6h-.4l-.1 .5 .4-.1 .1 .4h-.5M169.4 91.6l.2 .9 .4-.9M171.4 91.7l-.2-.1-.3 .3 .1 .6 .4-.1M171.5 90v.6l-.3 .2"/>
<path d="M171.7 92.1h.4M172.2 91.6h-.5v.9M172.3 90l-.4 .1v.6h.4v-.4h-.3l-.1 .2M172.8 90h.3l.1 .1v.5l-.2 .2a.48 .48 0 0 1-.2-.8zM173.2 92.1h.4v-.4l-.4-.1v.9M173.9 92.1l.2-.2 .4 .2-.1 .4h-.4zM173.9 90h-.3l-.1 .6 .2 .2 .3-.2-.1-.3h-.3l-.1 .2M174.7 91.9l.2 .6 .1-.4 .2 .4 .2-.6M175.6 92.2h.5l-.1-.3-.4 .2v.3l.5 .1M176.4 91.9v.6M176.7 91.9l-.3 .2M178.5 93.9h.7"/>
<path d="M178.9 93.6v.7M178.9 96.9a.43 .43 0 0 0-.4 .2 .43 .43 0 0 0 .1 .6l.4-.1v-.3h-.1M179.9 96.8v.9l-.5-.9v.9M180 93.3h-.5v.5l.4-.1 .1 .4-.1 .2-.4-.1M180.3 96.8l.4 .3-.1 .6h-.3zM180.3 93.3l.2 1 .3-1M190.9 83l.3-.8 .3 .8M191 82.8h.4M191.6 82.2h.5M191.9 82.2v.8M192.3 83l.3-.8 .2 .8M192.4 82.8h.3"/>
<path d="M194.3 82.3l-.2-.1a.5 .5 0 0 0-.2 .8l.4-.1M194.3 80.5v.6l-.3 .2M194.7 82.5h.3v.5h-.3zM195.1 80.5h-.2l-.2 .6 .1 .2 .4-.1-.1-.4h-.3l-.1 .2M195.4 82.6l.4-.1v.5M195.4 82.5v.5M195.6 80.5a.42 .42 0 0 1 .5 .4 .42 .42 0 0 1-.5 .4zM196.2 82.6h.4v.4M196.2 82.5v.5M196.8 80.5h-.4v.4h.4l-.1 .4-.3-.1M197 82.8l.4-.1-.1-.2h-.3v.5h.3M198.1 82.5l-.4 .1v.3l.4 .1"/>
<path d="M198.3 82.5h.4M198.5 82.2v.8h.2M199 82.5l.3 .1v.4h-.3l-.1-.2zM199.8 82.5v.5M200 82.5l-.2 .2M209.1 84.8h-.4a.44 .44 0 0 0-.1 .5 .44 .44 0 0 0 .6 .3v-.3h-.2M210 84.8v.8l-.5-.8v.8M210.4 84.8l.5 .1v.6l-.3 .1h-.2zM220.1 99h.3l.2-.2-.2-.3h-.3v.9M220.3 99l.3 .4M220.8 80.5h.6M221.4 98.5v.9l-.5-.9v.9"/>
<path d="M222.2 98.5l-.2 .1-.2 .7 .2 .1 .3-.1-.2-.5-.3 .2M222.8 98.5a.48 .48 0 0 1 .4 .5 .48 .48 0 0 1-.4 .4l-.2-.1v-.6zM223.6 98.5l-.2 .6h.6M223.8 98.8v.6M227 99.9h.7M227.4 99.6v.7M228.6 99.4h-.5v.4h.5v.4h-.5M228.8 99.4l.3 .9 .3-.9M50.9 116.7l-.1-.1-.3 .2v.6l.4 .1 .1-.4h-.2M51.9 116.6v.9l-.6-.9v.9M52.3 116.6a.49 .49 0 0 1 .4 .3 .49 .49 0 0 1-.1 .6h-.3zM105.8 103.8h.6l-.4 .8"/>
<path d="M105.9 102l.1 .8h.3l.1-.8M106.9 103.7l-.3 .6h.6M107.1 104v.6M107.1 102l-.2 .1-.2 .6 .1 .1 .4-.1v-.3l-.3-.1-.2 .2M107.4 104.6l.3-.8 .3 .8M107.5 104.3h.4M107.7 102a.43 .43 0 0 1 .4 .4 .43 .43 0 0 1-.4 .4l-.1-.7zM108.8 103.8h-.4l-.2 .1v.4l.3 .3 .3-.1M108.8 102h-.4v.4h.4v.4l-.4-.1M109 103.8h.5M109.3 103.8v.8M109.8 103.8h.4v.3l-.5 .5h.5"/>
<path d="M110.8 103.7l-.3 .6h.6M111 104v.6M111.8 103.8h-.3l-.1 .3 .3-.1 .2 .4-.2 .2-.3-.1M135.1 103.8h.6l-.4 .8M135.2 102l.1 .8h.3l.1-.1v-.7M136.2 103.7l-.3 .6h.5M136.4 104v.6M136.4 102l-.2 .1-.2 .3 .1 .4h.3l.1-.3-.1-.2-.4 .2M136.7 104.6l.2-.8 .4 .8M136.8 104.3h.4M137 102a.43 .43 0 0 1 .4 .4 .43 .43 0 0 1-.5 .4v-.7zM138 103.8h-.3l-.2 .1v.4l.3 .3 .2-.1"/>
<path d="M138 102l-.3 .2v.5h.4v-.3l-.3-.1-.1 .2M138.3 103.8h.5M138.6 103.8v.8M139.1 103.8h.4v.3l-.5 .5h.5M140.1 103.7l-.3 .6h.6M140.2 104v.6M141.1 103.8h-.4v.3l.3-.1 .2 .4-.2 .2-.3-.1M165.4 114.6h.7M165.7 114.3v.6M166.8 114.1h-.3l-.1 .3 .3-.1 .2 .5-.2 .1-.3-.1M167.2 114.1l.2 .8 .4-.8M175 113.7h.3l.1-.4h-.4v.7"/>
<path d="M175 111.7l.3-.2v.8M175 112.3h.5M175.1 113.7l.3 .3M175.9 111.5v.8M176 113.3h-.3l-.1 .3v.2l.3 .2 .2-.3h-.5M176 111.8l.4 .5M176.3 113.5l.2-.2v.7M176.3 114h.4M176.4 111.5l-.5 .5M177 113.3h.3v.3l-.4 .4h.4M186.5 100.3l-.4 .2v.5l.1 .1 .4-.1v-.2h-.2M187.4 100.3v.8l-.5-.8v.8"/>
<path d="M187.8 100.3l.5 .1v.4l-.1 .3h-.4zM203.1 117.6a.43 .43 0 0 0-.5 .2 .43 .43 0 0 0 .1 .5h.4l-.1-.3M204 117.5v.8l-.5-.8v.8M204.3 117.5h.3l.2 .2v.4l-.1 .2h-.4zM204.8 102.1a.43 .43 0 0 0-.5 .2 .43 .43 0 0 0 .1 .5l.4-.1v-.2h-.1M205.7 102v.8l-.5-.8v.8M206.1 102a.49 .49 0 0 1 .5 .3 .49 .49 0 0 1-.1 .5h-.4zM220.1 119.7h.3l.2-.2-.1-.3h-.4v.9M220.3 119.7l.3 .4M220.8 100.5l.3-.2v.8M220.8 101.1h.6M221.4 119.2v.9l-.5-.9v.9"/>
<path d="M221.8 100.4l.1-.1a.43 .43 0 0 1 .3 .4 .43 .43 0 0 1-.3 .4l-.2-.3zM222.2 119.2h-.2l-.2 .4v.3l.3 .2 .2-.4-.2-.2-.3 .2M222.5 100.3v.8M222.7 119.2a.42 .42 0 0 1 .4 .3 .42 .42 0 0 1-.1 .5l-.2 .1-.2-.2zM222.7 100.6l.4 .5M223.1 100.3l-.6 .5M223.9 119.2h-.4l-.1 .4h.5v.4h-.5M55.7 135.3h.6M56 134.9v.7M57.1 134.7h-.3l-.1 .5 .4-.1 .1 .3-.2 .2-.3-.1M57.4 134.7l.3 .9 .3-.9M58.5 139.5l.5-.1-.1-.3h-.4v.8"/>
<path d="M58.5 137.3l.1 .8 .4-.1v-.7M59.8 137.3l-.4 .2v.5l.4 .1 .1-.3-.2-.2-.3 .2M59.9 139.1h-.4a.44 .44 0 0 0-.1 .5 .44 .44 0 0 0 .5 .2M60.2 137.4l.3-.1 .2 .2-.1 .6h-.3l-.1-.2zM60.2 139.4h.3M60.7 139.1h-.5v.8M61 137.3h.5l-.2 .3 .2 .2-.1 .3-.4-.1M61.1 139.4l-.2-.2 .1-.1h.3l.1 .2-.4 .1-.1 .2 .2 .3 .3-.1v-.3l-.1-.1M62.2 139.1h-.4v.3l.3-.1 .2 .4-.2 .2-.3-.1M62.8 139.4l-.2-.3h.3l.1 .2-.4 .2v.3l.2 .1 .2-.1v-.3l-.1-.1M63.6 139l-.2 .6h.6M63.8 139.3v.6"/>
<path d="M67.7 138.7h.7M68 138.4v.7M69.2 138.1h-.4v.5h.4v.4h-.4M69.5 138.1l.3 1 .3-1M77.2 138.7h.6M77.5 138.4v.7M78.7 138.1h-.4l-.1 .5h.5v.4h-.5M78.9 138.1l.4 1 .2-1M98.4 137.4l.4-.1v-.3l-.4-.1v.9h.4l.1-.3-.2-.1M98.9 138.7l-.4-.1-.2 .4 .2 .5 .4-.1M99.1 136.9h.5M99.3 139.1h.4v-.5h-.4v.9"/>
<path d="M99.4 136.9v.9M99.4 139.1l.4 .4M100.1 138.9l.3-.3v.9M100.1 139.5h.4M100.3 136.9h-.3l-.1 .7 .1 .2 .4-.1-.1-.4-.4 .1M100.8 136.9a.43 .43 0 0 1 .4 .4 .43 .43 0 0 1-.3 .5l-.2-.2zM100.9 138.7h.5v.3l-.5 .5h.5M101.6 137.2l.1-.3v.9M101.6 137.8h.4M101.7 138.7l.4-.1 .1 .3-.6 .6h.6M102.7 138.6l.3 .1-.1 .8h-.2l-.1-.2zM103.5 133.1l-.1-.1a.43 .43 0 0 0-.4 .4 .43 .43 0 0 0 .5 .4v-.3h-.2"/>
<path d="M104.4 133v.9l-.5-.9v.9M104.8 133h.2l.3 .2v.4l-.3 .3h-.2zM109.1 139.6h.7M109.4 139.2v.7M110.5 139.1h-.4v.3l.3-.1 .2 .4-.2 .2-.3-.1M110.9 139.1l.2 .8 .3-.8M132.8 133.1l-.3-.1-.2 .2v.4l.2 .3 .3-.1v-.3h-.2M133.6 133v.9l-.4-.9v.9M134.1 133h.2l.3 .2v.4l-.3 .3h-.2zM152.9 139.1h.6l-.3 .2 .3 .2v.2l-.1 .2-.5-.1M152.9 135.4h.6l-.3 .4h.3v.5l-.6-.1M152.9 128.7h.6l-.3 .3 .3 .2v.2l-.1 .2-.5-.1"/>
<path d="M152.9 137.8l.5-.2-.2-.2h-.3v.6M152.9 134.2h.3l.2-.3-.5-.1v.7M152.9 127.5l.5-.2-.2-.3h-.3v.7M153.1 137.8l.3 .2M153.1 134.2l.3 .3M153.1 127.5l.3 .2M153.8 139.1h.5l-.3 .2 .3 .1v.4h-.5M153.8 135.4h.5l-.3 .4h.3v.4h-.5M153.8 128.7h.5l-.3 .3 .3 .1v.4h-.5M154 137.4l-.4 .1v.5h.4l-.1-.4-.3 .2M154 133.8h-.3l-.1 .2v.4l.3 .1 .1-.4-.4 .1M154 127l-.4 .2v.5h.4l-.1-.4-.3 .2"/>
<path d="M154.2 137.6l.3-.2v.6M154.2 138h.4M154.3 133.8l.3 .1v.4l-.1 .2-.3-.3zM154.3 127.1l.2-.1 .1 .2v.5h-.3zM154.7 139.5h.4v-.4h-.4v.8M154.7 135.8h.4v-.4h-.4v.9M154.7 129.2h.4v-.5h-.4v.9M154.9 139.5l.2 .4M154.9 135.8l.2 .5M154.9 129.2l.2 .4M155.1 137.4l.2 .2-.1 .4h-.2l-.1-.2zM155.1 127.4l-.2-.2 .2-.2 .2 .2-.4 .3 .1 .2 .3-.1-.2-.2"/>
<path d="M155.3 134.1l-.2 .1-.2-.3h.4l-.1 .5-.2 .1M169.4 122.3h.6M169.7 122v.6M170.8 121.8h-.4v.4l.4-.1 .1 .2-.1 .3h-.4M171.2 121.8l.2 .8 .3-.8M172.1 127h.6l-.4 .8M172.2 125.3l.1 .8 .4-.1v-.7M173.2 127l-.2 .5h.5M173.4 127.3v.5M173.4 125.3l-.3 .1v.6h.4l-.1-.4h-.2l-.1 .2M173.7 127.8l.3-.8 .3 .8M173.8 127.5h.4"/>
<path d="M174 125.3h.3l.1 .1-.1 .6a.39 .39 0 0 1-.5-.2 .39 .39 0 0 1 .1-.5zM174.6 125.3h.6l-.3 .8M175 127h-.1a.5 .5 0 0 0-.2 .8l.3-.1M175.3 127h.5M175.6 127v.8M176.1 127h.3l.2 .2-.6 .6h.6M177.1 127l-.2 .5h.5M177.2 127.3v.5M178.2 127h-.4l-.1 .4h.5v.3h-.5M181.9 126.1h-.3l-.2 .2v.5l.2 .2h.3v-.4h-.2M182.7 126.1v.9l-.5-.9v.9M183.2 126.1l.4 .1 .1 .4-.2 .4h-.3z"/>
<path d="M184.4 122.2h.5v-.2l-.5-.1v.7M184.5 120.4l.2-.3v.8M184.5 120.9h.5M184.6 122.2l.3 .4M185.4 120.2l.3-.1 .1 .2v.5l-.2 .1a.48 .48 0 0 1-.2-.7zM185.5 121.9l-.4 .1v.6l.4-.1-.1-.4-.3 .2M186 121.9l.1 .1v.6l-.3-.1v-.5zM186.1 120.1v.8M186.3 120.4l.3 .5M186.4 121.9h.4l-.2 .2 .2 .1v.4h-.4M186.6 120.1l-.5 .5M190 134.4h.7"/>
<path d="M190.4 134.1v.6M191.5 133.9h-.4l-.1 .3h.4l.2 .4-.2 .1h-.4M191.8 133.9l.3 .8 .3-.8M193 125l.3-.8 .3 .8M193.1 128.3l.4-.2-.2-.2h-.2v.7M193.1 124.8h.4M193.2 122.5h.3a.47 .47 0 0 1 .2 .5 .47 .47 0 0 1-.5 .3zM193.2 128.3l.3 .3M193.3 129.5l-.2 .6h.6M193.5 129.8v.6M193.8 124.2h.5M193.8 129.6h.6l-.3 .8"/>
<path d="M194 124.2v.8M194.1 127.9l-.3 .2v.5h.2l.1-.4-.3 .1M194.3 122.5h-.2l-.2 .6 .2 .2 .3-.1-.1-.4h-.3l-.1 .2M194.4 125l.3-.8 .3 .8M194.4 128l.2-.1 .2 .2v.4l-.2 .1h-.2zM194.5 124.8h.4M194.9 129.6h.2l.1 .1v.6l-.2 .1-.2-.1zM194.9 122.6v-.1a.45 .45 0 0 1 .4 .4 .45 .45 0 0 1-.3 .4l-.2-.3zM195.2 127.9l-.2 .5h.4M195.4 128.1v.5M195.6 130h.4v-.4h-.4v.8M195.6 122.7l.3-.2v.8"/>
<path d="M195.6 123.3h.5M195.8 125l.3-.8 .3 .8M195.8 130l.3 .4M195.9 124.8h.4M197.1 124.5h-.5v.4l.5 .1M197.3 124.5h.4M197.4 124.2v.7l.3 .1M197.9 124.2h.1M197.9 124.5v.5M198.2 124.5l.2 .5 .3-.5M198.9 124.8l.4-.1v-.2l-.4 .1v.3l.4 .1M203.4 121.2l.3-.3v.9"/>
<path d="M203.4 123.1l.4-.1-.1-.3h-.3v.8M203.4 121.8h.5M203.6 123.1l.2 .4M204.3 120.9a.42 .42 0 0 1 .5 .5 .42 .42 0 0 1-.5 .4zM204.4 122.7l-.3 .2v.5l.2 .1 .2-.2-.1-.2h-.3M204.8 123l.1-.3v.8M204.8 123.5h.3M205.1 120.9v.9M205.3 121.3l.3 .5M205.4 122.7h.4l-.3 .4h.3v.3h-.4M205.6 120.9l-.5 .6M220.8 121.2l.3-.3v.9"/>
<path d="M220.8 121.8h.6M221.8 121l.1-.1a.43 .43 0 0 1 .3 .5 .43 .43 0 0 1-.3 .4l-.2-.3zM222.5 120.9v.9M222.7 121.3l.4 .5M223.1 120.9l-.6 .6M227 120.6h.7M227.4 120.3v.6M228.6 120.1h-.5v.4h.5v.4h-.5M228.8 120.1l.3 .8 .3-.8M70.8 144.5l.3-.3v.9M70.8 143l.4-.1-.1-.4h-.3v.8M70.8 145.1h.5"/>
<path d="M70.9 143l.3 .3M71.7 144.2v.9M71.8 142.5a.4 .4 0 0 0-.4 .4 .4 .4 0 0 0 .3 .4l.1-.1v-.3l-.2-.1-.2 .2M71.8 144.6l.4 .5M72.2 144.2l-.5 .4M72.3 142.5a.4 .4 0 0 1 .2 .4 .4 .4 0 0 1-.2 .4l-.2-.2v-.4zM72.8 142.8l.1-.3v.8M72.8 143.3h.3M77.2 155.9h.6M77.5 155.6v.6M78.7 155.4h-.4l-.1 .4 .4-.1 .1 .5h-.5M78.9 155.4l.4 .8 .2-.8"/>
<path d="M80.2 143l.4-.1v-.4h-.4v.8M80.3 144.5l.3-.3v.9M80.3 145.1h.4M80.4 143l.2 .3M81.1 144.2v.9M81.2 142.5a.4 .4 0 0 0-.3 .4 .4 .4 0 0 0 .2 .4l.2-.3-.2-.2-.2 .2M81.2 159.8l-.3 .3 .1 .4h.2v-.4h-.3M81.2 144.6l.5 .5M81.6 159.9l.1-.1a.34 .34 0 0 1 .3 .3 .34 .34 0 0 1-.3 .4zM81.7 144.2l-.6 .4M81.7 142.5h.1a.45 .45 0 0 1-.1 .8l-.1-.2v-.4zM82.3 142.6l.2-.1 .1 .4-.4 .4h.4"/>
<path d="M82.6 159.8h-.3v.3h.3v.4l-.3-.1M94.9 144.2h-.4a.44 .44 0 0 0-.1 .6 .44 .44 0 0 0 .6 .2v-.4h-.2M95.8 144.2v.9l-.5-.9v.9M96.2 144.2h.4v.2v.4l-.2 .3h-.2zM109.5 159.7h-.3a.44 .44 0 0 0-.1 .6 .44 .44 0 0 0 .5 .2v-.3h-.2M110.4 159.7v.9l-.5-.9v.9M110.9 159.7l.4 .2v.4l-.3 .3h-.1zM111.9 157.9h.2l.3 .3v.4l-.3 .3h-.2zM111.9 156.2l.1 .9 .4-.1v-.8M113.2 156.2l-.4 .2-.1 .5 .1 .2 .4-.1v-.4h-.4l-.1 .2M113.2 158h-.5v.3l.5 .3-.1 .3-.4-.1M113.5 157.9h.6l-.4 .4 .4 .2v.2l-.2 .2-.4-.1"/>
<path d="M113.7 156.3l.2-.1 .2 .2-.1 .6a.39 .39 0 0 1-.4-.2 .39 .39 0 0 1 .1-.5zM114.3 158h.5v.4l-.5 .5h.5M114.6 156.2l-.2 .6h.5M114.8 156.5v.6M115.2 157.9h.5l-.3 .4 .3 .2v.2l-.2 .2-.3-.1M116 158.2l.3-.3v1M116 158.9h.5M116.9 158.9v-1l.2 .7 .4-.7v1M117.8 157.9h.5l-.5 1h.5M118.7 158.5h.6M119 158.2v.7M152.9 145.8h.6l-.3 .3h.3v.5l-.6-.1"/>
<path d="M152.9 144.5h.4l.1-.3-.5-.1v.7M153.1 144.5l.3 .3M153.8 145.8h.5l-.3 .3 .3 .1v.3h-.5M154 144.1h-.3l-.1 .2v.4l.3 .1 .1-.4-.4 .1M154.2 144.3l.3-.2v.7M154.2 144.8h.4M154.7 146.2h.4v-.4h-.4v.8M154.9 144.3l.2-.2v.7M154.9 146.2l.2 .4M154.9 144.8h.4M169.8 156.3a.42 .42 0 0 0-.5 .3 .42 .42 0 0 0 .2 .5l.4-.1v-.2h-.2M170.7 156.2v.9l-.5-.9v.9"/>
<path d="M171.2 156.2l.4 .2-.1 .7h-.3zM56.1 176.1h-.2l-.2 .1v.5l.1 .2 .4-.1v-.2h-.2M57 176.1v.8l-.5-.8v.8M57.4 176.1a.47 .47 0 0 1 .5 .3 .47 .47 0 0 1-.1 .5h-.4zM80.2 160.1h.4v-.2l-.4-.1v.7M80.3 161.7l.3-.3v.9M80.3 162.3h.4M80.4 160.1l.2 .4M81.1 161.4v.9M81.2 161.8l.5 .5M81.7 161.4l-.6 .5M105.2 168.3v.6l-.3 .3"/>
<path d="M105.4 170v.9M105.8 170.1h.5v.3l-.5 .5h.5M106 168.3l-.3 .1-.2 .6 .2 .2 .3-.1v-.4l-.3-.1-.2 .2M106.5 168.3a.48 .48 0 0 1 .4 .4 .48 .48 0 0 1-.4 .5l-.1-.3zM107.1 170.1l-.3-.1a.42 .42 0 0 0-.2 .6 .42 .42 0 0 0 .5 .2M107.1 168.3h.6l-.3 .9M112.1 172.3h.7M112.5 172v.6M113.7 171.7h-.5v.5h.5l-.1 .4-.4-.1M113.9 171.7l.4 .9 .2-.9M28.1 183.5h.6M28.4 183.2v.7"/>
<path d="M28.6 193.3l-.1-.1a.43 .43 0 0 0-.4 .5 .43 .43 0 0 0 .5 .4v-.3h-.2M29.5 193.2v1l-.5-1v1M29.6 182.9h-.4v.4h.4v.5h-.4M29.8 193.2h.3l.2 .3v.4l-.2 .3h-.3zM29.8 182.9l.4 1 .2-1M31.2 189.3l.3-.3v.9M31.2 189.9h.5M31.7 187.3l-.2-.1-.3 .3v.4l.2 .2h.3M32 189.1l.4-.1 .1 .2v.5l-.2 .2a.48 .48 0 0 1-.3-.8zM32.5 187.2l-.4 .1-.1 .8 .6-.1-.2-.4-.4 .1M32.9 189.1l.2-.1a.39 .39 0 0 1 .3 .5 .39 .39 0 0 1-.5 .3zM33.1 187.2l.2 .2-.1 .7-.3-.1v-.6z"/>
<path d="M33.7 189.4l.2-.1 .2 .1v.5M33.7 187.5l.2-.3v.9M33.7 189.3v.6M33.7 188.1h.5M34.5 189.4h.3M34.8 189h-.3v.9M39.8 187.5l.2-.3v.9M39.8 188.1h.5M40.3 189.1h-.5v.6l.3 .2 .2-.1M40.7 187.3l.2-.1 .2 .2-.1 .7h-.2l-.2-.3zM41.1 189l-.4 .2v.6l.3 .1 .1-.5-.3-.1-.1 .1M41.5 189.1h.4v.6l-.1 .2-.3-.1-.1-.3z"/>
<path d="M41.6 187.2a.43 .43 0 0 1 .4 .5 .43 .43 0 0 1-.5 .4l-.1-.7zM42.3 187.7l.3-.1v.5M42.3 189.1h.5l-.5 .8h.5M42.3 187.6v.5M43 187.7h.4M43.5 187.2h-.5v.9M48.4 189.3l.2-.3v.9M48.4 189.9h.5M49 187.3a.44 .44 0 0 0-.6 .2 .44 .44 0 0 0 .2 .6h.4M49.3 189a.43 .43 0 0 1 .4 .4 .43 .43 0 0 1-.3 .5l-.2-.2zM49.7 187.2l-.3 .1-.2 .7 .5 .1v-.4l-.3-.1-.2 .1M50.2 189h.2l.1 .2v.5l-.2 .2-.2-.2z"/>
<path d="M50.2 187.3h.3v.8h-.3zM50.8 187.2h.6l-.3 .4 .3 .1v.3l-.6 .1M50.9 189.4h.4v.5M50.9 189.3v.6M51.7 189.4h.2M52.1 189h-.4v.9M57 189.3l.3-.3v.9M57 189.9h.5M57.5 187.3l-.2-.1-.3 .3v.4l.2 .2h.3M58 189h.2l.1 .2v.5l-.2 .2-.2-.2zM58.3 187.2l-.3 .1-.1 .7h.5l-.2-.4-.3 .1M58.7 189.1l.4-.1v.2v.5l-.1 .2a.48 .48 0 0 1-.3-.8z"/>
<path d="M58.7 187.4l.2-.2a.53 .53 0 0 1 .2 .9l-.4-.1zM59.6 189.4l.1-.1 .2 .1v.5M59.6 189.3v.6M59.7 187.2l-.1 .6h.5M59.9 187.6v.5M60.3 189.4h.3M60.7 189h-.4v.9M65.7 189.3l.2-.3v.9M65.7 189.9h.4M66.2 187.3l-.3-.1-.2 .3v.4l.1 .2h.4M66.5 189.1l.3-.1 .1 .2v.5l-.1 .2a.48 .48 0 0 1-.3-.8zM66.9 187.2l-.3 .1-.1 .8 .5-.1-.2-.4-.3 .1"/>
<path d="M67.4 189a.39 .39 0 0 1 .4 .4 .39 .39 0 0 1-.5 .4v-.4zM67.5 187.2l.3 .2-.1 .7-.4-.1v-.6zM68.1 189.4l.3-.1 .1 .1v.5M68.1 189.3v.6M68.6 187.2h-.4l-.1 .5h.5v.4h-.5M68.9 189.4h.3M69.3 189h-.4v.9M74.2 189.3l.3-.3v.9M74.2 189.9h.5M74.8 187.3a.44 .44 0 0 0-.6 .2 .44 .44 0 0 0 .2 .6h.4M75.1 189.1l.1-.1a.38 .38 0 0 1 .4 .4 .38 .38 0 0 1-.5 .4zM75.5 187.2l-.4 .3v.6h.5v-.4l-.3-.1-.2 .1"/>
<path d="M76 189a.43 .43 0 0 1 .4 .4 .43 .43 0 0 1-.3 .5l-.2-.2zM76 187.3l.2-.1 .2 .2-.1 .7h-.3zM76.7 189.4h.4v.5M76.7 189.3v.6M77.2 187.2l-.4 .1-.1 .8 .6-.1-.2-.4-.4 .1M77.5 189.4h.3M77.9 189h-.4v.9M82.8 189.3l.3-.3v.9M82.8 189.9h.6M83.4 187.3a.43 .43 0 0 0-.5 .3 .43 .43 0 0 0 .1 .5h.4M83.8 189a.43 .43 0 0 1 .4 .4 .43 .43 0 0 1-.3 .5l-.2-.2zM84.1 187.2l-.2 .1-.2 .7 .5 .1v-.4l-.3-.1-.2 .1"/>
<path d="M84.5 189.1l.4-.1 .1 .2v.5l-.2 .2-.3-.1zM84.5 187.4l.2-.2a.53 .53 0 0 1 .3 .9l-.5-.1zM85.3 187.2h.6l-.3 .9M85.4 189.4h.3v.5M85.4 189.3v.6M86.1 189.4h.3M86.6 189h-.5v.9M91.5 189.3l.2-.3v.9M91.5 189.9h.5M92 187.3l-.3-.1-.2 .3v.4l.1 .2h.4M92.4 189h.3v.2v.5l-.1 .2-.3-.2zM92.7 187.2l-.3 .1-.1 .7h.5l-.1-.4-.4 .1"/>
<path d="M93.2 189.1l.3-.1 .1 .2v.5l-.2 .2a.48 .48 0 0 1-.2-.8zM93.3 187.2a.53 .53 0 0 1 .3 .9l-.4-.1v-.6zM93.9 189.4l.3-.1 .2 .1v.5M93.9 189.3v.6M94.1 187.7l-.2-.3 .2-.2 .3 .1v.3l-.4 .1-.1 .1 .1 .3h.4v-.4h-.1M94.8 189.4h.2M95.1 189h-.3v.9M99.2 188.8l.2-.2v.8M99.2 189.4h.5M99.8 187l-.4-.1-.2 .3 .2 .5h.4M100.1 188.7l.2-.1a.45 .45 0 0 1 .2 .4 .45 .45 0 0 1-.3 .4l-.2-.2zM100.5 186.9l-.4 .2v.6h.4v-.5h-.3l-.1 .2"/>
<path d="M101 188.6a.43 .43 0 0 1 .4 .5 .43 .43 0 0 1-.4 .3l-.1-.6zM101 186.9h.3l.1 .2-.1 .6a.39 .39 0 0 1-.4-.2 .39 .39 0 0 1 .1-.5zM101.7 188.9v.9M102.1 189.4h.1M102.1 188.9v.5h-.4M102.2 187.2l-.1 .2h-.3l-.1-.4 .4-.1 .1 .2-.1 .6h-.3M102.7 189h.2M103 188.6h-.3v.8M107 188.8l.2-.2v.8M107 189.4h.5M107.5 187l-.4-.1-.1 .2v.5l.1 .1h.4M108 188.6l.2 .1v.7h-.3l-.1-.1v-.5z"/>
<path d="M108.2 186.9h-.2l-.2 .3 .1 .5h.3v-.5h-.3l-.1 .2M108.7 180.4l-.5 .1v.4l.1 .3h.4v-.3h-.2M108.7 188.7l.2-.1 .2 .2-.1 .6h-.2l-.2-.2zM108.7 187.2l.2-.3v.8M108.7 187.7h.5M109.5 187l.4-.1v.2v.6h-.4zM109.5 188.9v.9M109.6 180.4v.8l-.5-.8v.8M109.9 189.4h.1M109.9 188.9v.5h-.4M109.9 180.4h.4l.1 .1v.6l-.1 .1h-.4zM110.4 189h.3"/>
<path d="M110.8 188.6h-.4v.8"/>
</g>
</svg>
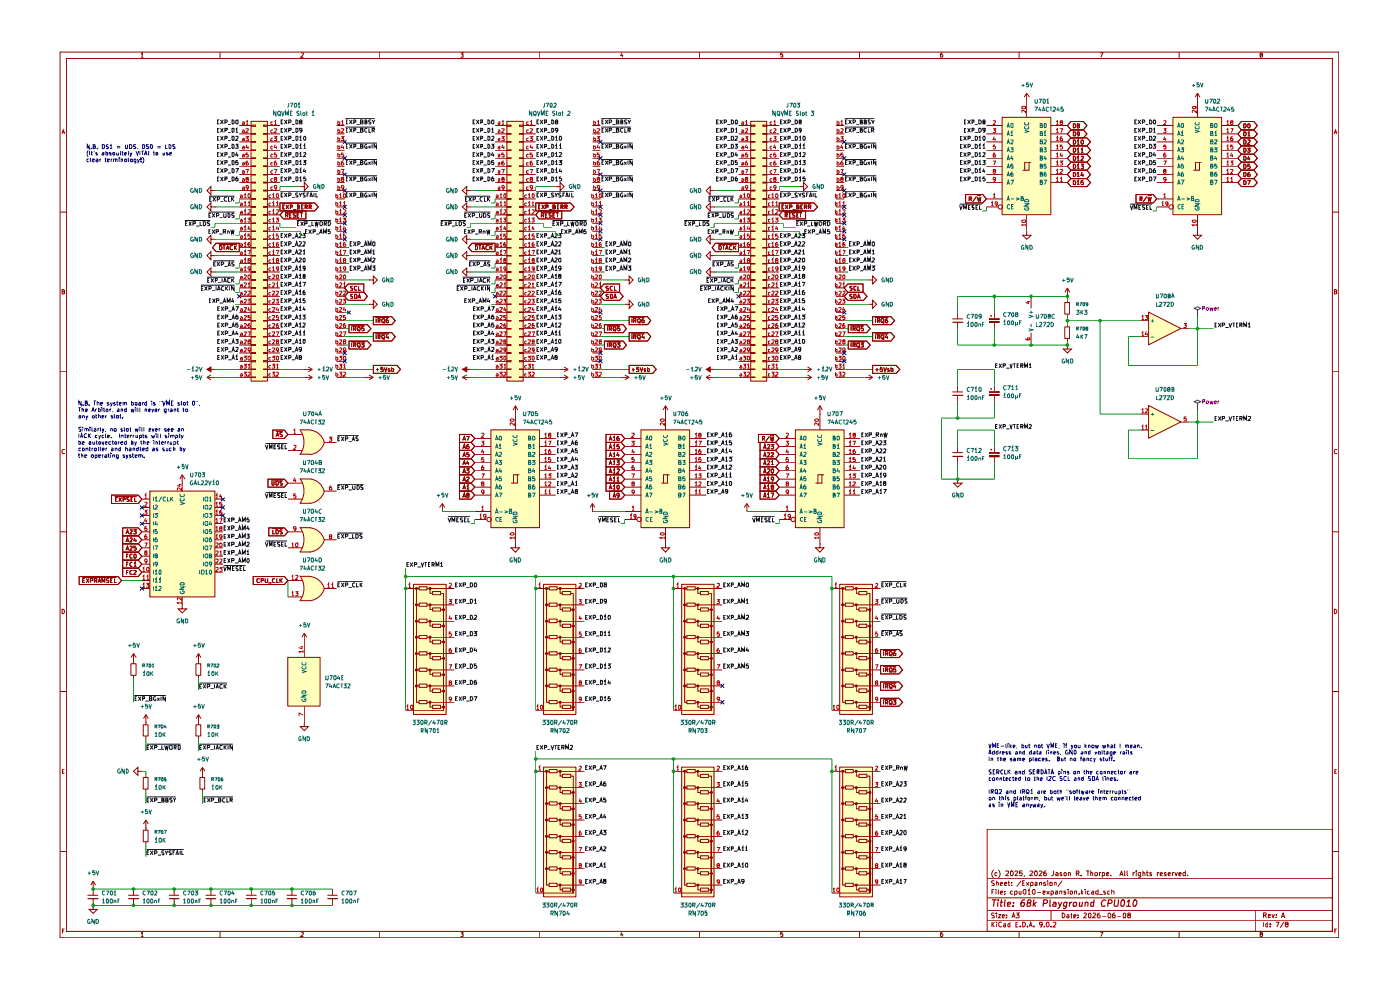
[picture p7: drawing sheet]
<svg xmlns="http://www.w3.org/2000/svg" width="297mm" height="210mm" viewBox="0 0 297 210" stroke-linecap="round" stroke-linejoin="round" font-family="sans-serif">
<g fill="none" stroke="#910000" stroke-width=".21">
<path d="M12.7 11h271.3v187.9h-271.3zM14.1 12.4h268.6v185.2h-268.6zM29.9 11.5l.3-.3v.9M29.9 12.1h.5M46.7 11v1.4M63.9 11.3l.3-.1 .2 .3-.6 .6h.6M80.6 11v1.4M97.7 11.2h.6l-.3 .4h.3v.5h-.6M114.5 11v1.4M131.9 11.2l-.2 .6h.5M132.1 11.6v.5M148.4 11v1.4"/>
<path d="M166.1 11.2h-.5v.4h.5v.5h-.5M182.3 11v1.4M199.9 11.2l-.3 .1-.1 .8h.4l.1-.1-.1-.4-.4 .1M216.2 11v1.4M233.4 11.2h.6l-.5 .9M250.1 11v1.4M267.5 11.6h-.2v-.3l.4-.1 .1 .3-.5 .2v.4h.2l.3-.1-.1-.4M13.2 28.4l.2-.8 .4 .8M13.2 28.1h.5M283 28.4l.3-.8 .3 .8M283.1 28.1h.4M12.7 45h1.4"/>
<path d="M282.7 45h1.3M12.7 78.9h1.4M13.2 61.8h.4l.1-.2-.2-.2h-.3v1l.5-.1v-.4l-.2-.1M282.7 78.9h1.3M283.1 61.8h.4l.1-.2-.2-.2h-.3v1l.5-.1v-.4l-.2-.1M13.7 95.5l-.4-.1-.1 .1v.6l.1 .1 .4-.1M283.6 95.5l-.4-.1-.1 .1v.6l.1 .1 .4-.1M12.7 112.8h1.4M282.7 112.8h1.3M13.2 129.2h.2l.3 .3v.4l-.3 .3h-.2zM283.1 129.2h.2l.3 .3v.4l-.3 .3h-.2zM12.7 146.7h1.4"/>
<path d="M282.7 146.7h1.3M13.2 163.6h.3M13.7 163.2h-.5v.8h.5M209.4 175.9h73.3v21.7h-73.3zM283.2 163.6h.2M283.6 163.2h-.4v.8h.4M12.7 180.6h1.4M13.2 197.5h.4M13.7 197.1h-.5v.9M29.9 198l.3-.3v1M29.9 198.7h.5M46.7 197.6v1.3"/>
<path d="M63.9 197.8l.3-.1 .2 .3-.6 .7h.6M80.6 197.6v1.3M97.7 197.7h.6l-.3 .4 .3 .1v.4h-.6M114.5 197.6v1.3M131.9 197.7l-.2 .6h.5M132.1 198.1v.6M148.4 197.6v1.3M166.1 197.7h-.5v.5h.5v.4h-.5M182.3 197.6v1.3M199.9 197.7l-.3 .1-.1 .8 .4 .1 .1-.2-.1-.4-.4 .1M209.4 195.2h73.3M209.4 193.2h73.3"/>
<path d="M209.4 190.5h73.3M209.4 186.4h73.3M210.4 195.6v1M210.4 189.2h.4M210.5 196l.4 .6M210.7 184.6l-.1 .1a1.11 1.11 0 0 0 .1 1.5M210.9 188.7h-.5v1M210.9 193.8l-.4-.1-.1 .1v.2l.4 .2 .1 .2v.3h-.5M210.9 186.9l-.4-.1-.1 .2v.2l.5 .4v.2h-.5M210.9 195.6l-.5 .5M211.3 188.7v.1M211.3 189v.7"/>
<path d="M211.4 193.7v.1M211.4 187.2h.4v.6M211.4 186.8v1M211.4 194v.7M211.5 195.6v.1M211.5 196v.6M211.5 185.2h-.4v.5l.4 .1M211.8 194h.5l-.5 .7h.5M211.8 188.7l.1 1M211.8 184.6l.1 .1a1.11 1.11 0 0 1-.1 1.5M212.2 189.4l.5-.1-.1-.3h-.3l-.1 .2v.3l.2 .2 .2-.1M212.2 187.5l.5-.1-.1-.2-.4 .1v.4l.4 .1"/>
<path d="M212.5 195.7l-.5-.1-.1 .2v.6l.3 .2 .3-.1M212.6 194.3h.5l-.1-.3-.4 .1v.6h.5M212.9 196h.4v.6M213.1 189.6v.1M213.1 189v.2M213.1 187.5l.5-.1-.1-.2h-.4v.6h.5M213.3 196.1l-.4 .2 .1 .3h.3M213.4 184.8h.5v.4l-.5 .6h.5M213.6 194.6v.1M213.6 194.1v.1M213.9 187.2h.3M214 186.8v.9l.2 .1"/>
<path d="M214.2 196h-.4v.5l.2 .1h.2M214.2 195.6v1M214.4 184.9l.2-.2a.52 .52 0 0 1 .4 .6 .52 .52 0 0 1-.5 .5zM214.6 187.7v.1M214.6 187.2v.1M214.7 194.7l.3-1 .3 1M214.8 194.4h.5M214.8 189h-.3l-.2 .2 .1 .4h.4M215.3 189.6l.3 .1 .2-.2-.1-.5h-.4v1M215.3 184.8l.4-.1 .2 .2-.6 .9h.6M215.5 196h.4M215.6 193.7h.6l-.3 .4 .3 .1v.4h-.6"/>
<path d="M216 195.6h-.5v1h.5M216.2 189v.5l.2 .2 .2-.1M216.2 197.6v1.3M216.4 196.5v.1M216.6 189v.7M216.6 186.8l-.9 1.3M216.8 184.7h-.5v.5h.5l-.1 .6-.4-.1M217 195.6h.3a.55 .55 0 0 1 .2 .8l-.3 .2h-.2zM217 187.3h.3M217.2 188.7h.3l.1 .1v.7l-.2 .2a.63 .63 0 0 1-.2-1zM217.3 185.8v.1M217.4 186.8h-.4v1h.4"/>
<path d="M217.7 187.2l.6 .6M218 196.5v.1M218.1 188.9l.2-.2v1M218.1 189.7h.5M218.3 196.6l.3-1 .4 1M218.3 187.2l-.6 .6M218.4 196.3h.5M218.5 184.8l.4-.1 .2 .4-.7 .7h.7M218.6 187.2h.6v.5l-.6 .1M218.6 187.2v1M219.2 188.7h.3l.1 .1v.7l-.3 .2a.63 .63 0 0 1-.1-1zM219.3 196.5v.1"/>
<path d="M219.5 184.8l.3-.1 .2 .2v.7l-.1 .2-.4-.1zM219.6 187.2h.4v.6h-.4v-.3l.4-.1M220 189.3h.8M220.5 184.8l.3-.1 .3 .4-.7 .7h.7M220.5 187.2h.4v.6M220.5 187.2v.6M221.1 196l-.2 .2-.4-.2 .1-.4h.4a.64 .64 0 0 1-.4 1M221.3 189.4l.4-.1v-.3h-.4v.6h.4M221.5 196.5v.1M221.8 187.2h-.3l-.1 .2 .3 .1 .2 .2-.5 .1M221.9 184.7l-.3 .1a.74 .74 0 0 0-.1 1h.4l.1-.5-.1-.1h-.4l-.1 .1M222 195.7l.4-.1 .1 .2v.6l-.2 .2-.3-.4z"/>
<path d="M222 189l.6 .7M222.3 186.8v.1M222.3 187.2v.6M222.6 189l-.6 .7M222.7 187.2h.5l-.1 .6-.4-.1zM223 196.5v.1M223 189.6l.3 .1 .2-.2-.1-.5h-.4v1M223 193.2v2M223.4 195.7h.6v.3l-.6 .6h.6M223.5 184.7v.8l-.2 .3h-.2M223.6 187.2h.5v.6M223.6 187.2v.6"/>
<path d="M223.9 189h.4v.7M224 185.2l.3-.1 .1 .1v.6h-.4v-.4l.4-.1M224.3 189.3l-.4 .1 .1 .3 .3-.1M224.8 189.1l.5-.1v.7M224.8 189v.7M225.2 185.2h-.3v.2l.4 .2-.1 .2h-.3M225.3 193.7h.3l.3 .4-.2 .6h-.4zM225.3 186.8l-.9 1.3M225.7 185.2l.4-.1 .1 .1-.1 .6-.4-.1zM226.1 189h-.3l-.1 .2 .4 .2v.2h-.4M226.4 194.1l.2-.1 .2 .2v.5h-.4v-.4h.4M226.6 188.7v.1"/>
<path d="M226.6 189v.7M226.6 185.2h.5v.6M226.6 185.1v.7M227 189.1l.5-.1v.5l-.1 .2-.4-.1zM227.1 194h.4M227.3 193.7v1h.2M227.8 194.3h.5l-.2-.3-.3 .1v.6h.4M228 189.1l.4-.1v.7M228 189v.7M228.3 185.2h.6v-.3l-.1-.2h-.5v1.1M228.6 185.2l.3 .6M228.7 194.6v.1"/>
<path d="M228.7 194.1v.1M228.9 189.6v.1M229.4 185.7v.1M229.4 188.7v1M229.5 189.3l.2 .4M229.7 189l-.3 .4M229.9 193.8l.4-.1 .2 .1-.6 .9h.6M230.2 188.7v.1M230.2 189v.7M230.5 184.7h.6M230.8 184.7v1.1M231.1 193.7l.3 .1-.1 .9h-.3l-.1-.2v-.7z"/>
<path d="M231.1 189l-.4 .1v.5h.4M231.4 185.2h.4v.6M231.4 184.7v1.1M231.6 189h.3l.1 .7M231.9 193.8l.4-.1 .1 .3-.6 .7h.6M232 189.3h-.3l-.2 .1 .2 .3 .3-.1M232.3 185.2l.3-.1 .2 .1-.1 .6h-.4zM233 189l-.6 .1v.5h.6M233 188.7v1M233.1 189.8h.9M233.3 185.1v.7M233.3 193.7l-.3 .1-.2 .7 .2 .2 .4-.1-.1-.5h-.3l-.2 .2"/>
<path d="M233.4 197.7h.6l-.5 1M233.5 185.1l-.2 .1M233.8 194.3h.9M233.8 185.2l.4-.1 .2 .1-.1 .6h-.5M233.8 185.1v1M234.5 189h-.4v.3l.5 .2-.2 .2-.3-.1M234.8 185.4l.4-.1-.1-.2-.3 .1v.6h.4M235.1 193.8l.2-.1a.52 .52 0 0 1 .4 .6 .52 .52 0 0 1-.5 .4zM235.4 189l-.4 .1v.5h.4M235.6 185.7v.1M235.8 189.1l.5-.1v.7M235.8 188.7v1"/>
<path d="M236.5 193.7l-.3 .1a.74 .74 0 0 0-.1 .9h.4l.1-.4-.1-.2h-.4l-.1 .2M237 194.3h.8M237.6 185.8l.3-1.1 .3 1.1M237.7 185.5h.5M238.5 193.7l.3 .1-.1 .9h-.3l-.1-.2v-.7zM238.6 184.7l.1 1.1M239.1 184.7v.9l.2 .2M239.4 194.1l-.2-.3 .4-.1 .2 .2-.1 .2-.4 .1v.5h.4l.1-.4-.2-.2M240.4 185.1v.7M240.7 185.1l-.3 .1M241 184.7v.1M241 185.1v.7"/>
<path d="M242 185.1v.8l-.1 .2h-.3M242 185.2l-.4-.1-.1 .1 .1 .6h.4M242.5 185.2l.2-.1 .2 .1v.6M242.5 184.7v1.1M243.2 185.1h.4M243.3 184.7v.9l.3 .2M244.3 185.2h-.4v.2l.4 .2v.2h-.4M245.5 185.1v.7M245.9 185.1l-.4 .1M246.1 185.4l.5-.1-.1-.2-.4 .1v.4l.1 .2h.3M247.4 185.2l-.3-.1-.1 .1 .4 .3v.3h-.4M247.8 185.4l.5-.1-.1-.2-.4 .1v.4l.1 .2h.3"/>
<path d="M248.7 185.1v.7M249 185.1l-.3 .1M249.3 185.1l.2 .7 .3-.7M250.1 185.4l.5-.1-.2-.2-.3 .1v.6h.4M250.1 197.6v1.3M251.5 184.7v1.1h-.5l-.1-.6 .2-.1 .4 .1M252 185.7v.1M266.4 193.2v4.4M267.5 198.2l-.2-.1v-.3l.4-.1 .1 .3-.5 .2v.4l.2 .1 .3-.2-.1-.3M268 195.6v1M268.1 194.1h.5v-.3l-.1-.2h-.4v1M268.3 194.1l.3 .5"/>
<path d="M268.9 196h-.4v.5l.2 .1h.2M268.9 195.6v1M269.1 194.3l.4-.1-.1-.2-.3 .1v.5h.4M269.4 196.5v.1M269.4 196h.1M269.8 194l.3 .6 .2-.6M270.6 195.6h.7l-.4 1M270.8 194.6h.1M270.8 194.1h.1M271.9 194.6l.3-1 .3 1M271.9 194.4h.6M272.4 195.5l-.8 1.3"/>
<path d="M272.9 196l-.2-.2 .1-.2h.4l.1 .4h-.5l-.1 .2 .2 .4 .4-.1v-.4l-.2-.1M282.7 180.6h1.3M283.2 197.5h.2M283.6 197.1h-.4v.9"/>
</g>
<g fill="none" stroke="#910000" stroke-width=".25">
<path d="M210.5 190.9h.9M210.9 190.9l-.1 1.3M211.7 191.4l-.1 .8M211.8 190.9v.1M212.2 191.4h.5M212.5 190.9l-.2 1.3h.3M213.2 190.9l-.1 1.2 .1 .1M213.7 191.8l.7-.1-.2-.3-.5 .2v.6h.5M214.9 192.1v.1M215 191.5v.1M217.4 190.9a.89 .89 0 0 0-.7 1.3h.5l.2-.5-.1-.2h-.5l-.2 .2M218.1 191.5l-.1-.1v-.3l.2-.2 .4 .1v.4l-.5 .1-.2 .2 .1 .5 .6-.1v-.4l-.2-.2"/>
<path d="M219.3 190.9l-.1 1.3M219.3 191.7l.4 .5M219.8 191.4l-.6 .5M221.4 191.6h.6l.2-.2v-.4l-.2-.1h-.6l-.1 1.3M222.8 190.9l-.1 1.3h.2M223.5 191.5l.4-.1 .2 .2-.1 .6h-.6v-.4l.6-.1M224.6 191.4l.2 .8M225.3 191.4l-.6 1.2-.3 .1M226.4 191.4l-.2 1.1-.3 .2h-.3M226.4 191.5h-.6l-.2 .5 .1 .2h.5M226.9 191.4v.8M227.4 191.4l-.5 .2"/>
<path d="M227.8 191.5h.6v.5l-.2 .2-.5-.1zM229.1 191.4l-.1 .8 .5-.1M229.7 191.4l-.2 .8M230.2 191.5l.5-.1 .1 .2v.6M230.2 191.4v.8M232.1 190.9l-.2 1.3h-.5v-.7h.6M234.6 191a.6 .6 0 0 0-.8 0 .6 .6 0 0 0-.2 .7l.2 .5 .6-.1M235.1 191.6h.7l.1-.2-.1-.4-.6-.1-.2 1.3M236.5 190.9l-.2 1.1 .2 .2 .6-.1 .2-1.2M237.9 191.1l.3-.2 .3 .1v.7l-.2 .5h-.4zM239 192.2h.8M239.1 191.3l.5-.4-.2 1.3"/>
<path d="M240.7 190.9l.5 .2v.6l-.3 .5h-.4l-.2-.5 .2-.6z"/>
</g>
<g fill="#ffb">
<path d="M144.6 124h6.9v27.6h-6.9z"/>
<path d="M178.2 162.8h6.9v27.5h-6.9z"/>
<path d="M144.6 162.8h6.9v27.5h-6.9z"/>
<path d="M178.2 124h6.9v27.6h-6.9z"/>
<path d="M136 91.2h10.3v20.8h-10.3z"/>
<path d="M104.2 91.2h10.3v20.8h-10.3z"/>
<path d="M168.8 91.2h10.3v20.8h-10.3z"/>
<path d="M65.4 103.2l3.5 1a3.6 3.6 0 0 1-3.1 2.6z"/>
<path d="M65.9 101.6a3.4 3.4 0 0 1 2.9 2.6l-3.3 .8z"/>
<path d="M63.7 101.6h2.1v5.2h-2.1a4.7 4.7 0 0 0 0-5.2z"/>
<path d="M65.4 92.9l3.5 1a3.6 3.6 0 0 1-3.1 2.6z"/>
<path d="M65.9 91.3a3.4 3.4 0 0 1 2.9 2.5l-3.3 .9z"/>
<path d="M63.7 91.2h2.1v5.2h-2.1a4.7 4.7 0 0 0 0-5.2z"/>
<path d="M53.3 25.8h3.5v55.1h-3.5z"/>
<path d="M31.8 104.2h13.8v22.4h-13.8z"/>
<path d="M87.8 124h6.9v27.6h-6.9z"/>
<path d="M115.4 124h6.8v27.6h-6.8z"/>
<path d="M115.4 162.8h6.8v27.5h-6.8z"/>
<path d="M65.4 123.9l3.5 .9a3.6 3.6 0 0 1-3.1 2.7z"/>
<path d="M65.9 122.3a3.5 3.5 0 0 1 2.9 2.6l-3.3 .9z"/>
<path d="M63.7 122.3h2.1v5.2h-2.1a4.7 4.7 0 0 0 0-5.2z"/>
<path d="M65.4 113.6l3.5 .9a3.6 3.6 0 0 1-3.1 2.6z"/>
<path d="M65.9 112a3.5 3.5 0 0 1 2.9 2.6l-3.3 .8z"/>
<path d="M63.7 112h2.1v5.1h-2.1a4.7 4.7 0 0 0 0-5.1z"/>
<path d="M61.1 139.5h6.8v10.3h-6.8z"/>
<path d="M243.7 86.1l6.9 3.4-6.9 3.5z"/>
<path d="M159.3 25.8h3.4v55.1h-3.4z"/>
<path d="M212.6 24.9h10.4v20.7h-10.4z"/>
<path d="M243.7 66.2l6.9 3.5-6.9 3.5z"/>
<path d="M248.9 24.9h10.3v20.7h-10.3z"/>
<path d="M107.6 25.8h3.4v55.1h-3.4z"/>
</g>
<g fill="none" stroke="#0f0f0f" stroke-width=".21">
<path d="M153.5 137.9h.3M153.5 134.4h.3M154 137.5h-.5v.8h.5M154 134h-.5v.8h.5M154.2 137.5l.6 .8M154.2 134l.6 .8M154.8 137.5l-.6 .8M154.8 134l-.6 .8M155.1 137.9l.5-.1-.1-.3h-.4v.8M155.1 134.4l.5-.1-.1-.3h-.4v.8M155.7 138.4h.7M155.7 134.9h.7"/>
<path d="M156.5 138.3l.3-.8 .3 .8M156.5 134.8l.3-.8 .3 .8M156.6 138h.4M156.6 134.6h.4M157.3 138.3v-.8l.4 .5 .2-.5v.8M157.3 134.8v-.8l.4 .6 .2-.6v.8M158.3 134h.5l-.3 .3 .3 .1v.3h-.5M158.5 137.4l-.2 .6h.6M158.7 137.7v.6M153.5 141.3h.3M154 140.8h-.5v1h.5M154.2 140.8l.6 1"/>
<path d="M154.8 140.8l-.6 1M155.1 141.3h.5v-.4l-.5-.1v1M155.7 141.9h.7M156.5 141.8l.3-1 .3 1M156.6 141.5h.4M157.3 141.8v-1l.4 .7 .2-.7v1M158.8 140.8h-.4l-.1 .5h.5v.4h-.5"/>
</g>
<path d="M144.6 123.9h6.9v27.7h-6.9zM144.6 124.8h1.2M145.7 124.5h1.8v.6h-1.8z" fill="none" stroke="#910000" stroke-width=".21"/>
<path d="M145.1 124.6l.4 .2-.2 .2-.3-.2z" fill="#910000"/>
<path d="M145.1 124.6l.4 .2-.2 .2-.3-.2zM145.2 124.8v3.5h.6" fill="none" stroke="#910000" stroke-width=".21"/>
<path d="M147.9 124.6l.3 .2-.1 .2-.3-.2z" fill="#910000"/>
<path d="M145.7 127.9h1.8v.7h-1.8zM147.5 124.8h4M147.9 124.6l.3 .2-.1 .2-.3-.2zM148 124.8v1.1h.6M148.6 125.5h1.7v.7h-1.7zM150.3 125.9h.6v24.8" fill="none" stroke="#910000" stroke-width=".21"/>
<path d="M145.1 128.1l.3 .2-.1 .2-.3-.2z" fill="#910000"/>
<path d="M145.1 128.1l.4 .2-.2 .2-.3-.2zM145.2 128.3v3.5h.6" fill="none" stroke="#910000" stroke-width=".21"/>
<path d="M147.9 128.1l.3 .2-.1 .2-.3-.2z" fill="#910000"/>
<path d="M147.5 128.3h4M147.9 128.1l.3 .2-.1 .2-.3-.2zM148 128.3v1h.6M148.6 128.9h1.7v.7h-1.7zM150.3 129.3h.6v21.4" fill="none" stroke="#910000" stroke-width=".21"/>
<path d="M150.8 129.1l.3 .2-.1 .2-.3-.2z" fill="#910000"/>
<path d="M145.7 131.3h1.8v.8h-1.8zM150.8 129.1l.3 .2-.1 .2-.3-.2z" fill="none" stroke="#910000" stroke-width=".21"/>
<path d="M145.1 131.5l.3 .2-.1 .2-.3-.2z" fill="#910000"/>
<path d="M145.1 131.6l.4 .2-.2 .2-.3-.2zM145.2 131.8v3.4h.6" fill="none" stroke="#910000" stroke-width=".21"/>
<path d="M147.9 131.6l.3 .2-.1 .2-.3-.2z" fill="#910000"/>
<path d="M147.5 131.8h4M147.9 131.6l.3 .2-.1 .2-.3-.2zM148 131.8v1h.6M148.6 132.4h1.7v.7h-1.7zM150.3 132.8h.6v17.9" fill="none" stroke="#910000" stroke-width=".21"/>
<path d="M150.8 132.6l.3 .2-.1 .2-.3-.2z" fill="#910000"/>
<path d="M145.7 134.8h1.8v.7h-1.8zM150.8 132.6l.3 .2-.1 .2-.3-.2z" fill="none" stroke="#910000" stroke-width=".21"/>
<path d="M145.1 134.9l.3 .2-.1 .2-.3-.2z" fill="#910000"/>
<path d="M145.1 135l.4 .2-.2 .2-.3-.2zM145.2 135.2v3.4h.6" fill="none" stroke="#910000" stroke-width=".21"/>
<path d="M147.9 135l.3 .2-.1 .2-.3-.2z" fill="#910000"/>
<path d="M147.5 135.2h4M147.9 135l.3 .2-.1 .2-.3-.2zM148 135.2v1h.6M148.6 135.8h1.7v.8h-1.7zM150.3 136.2h.6v14.5" fill="none" stroke="#910000" stroke-width=".21"/>
<path d="M150.8 136l.3 .2-.1 .2-.3-.2z" fill="#910000"/>
<path d="M145.7 138.3h1.8v.6h-1.8zM150.8 136l.3 .2-.1 .2-.3-.2z" fill="none" stroke="#910000" stroke-width=".21"/>
<path d="M145.1 138.4l.3 .2-.1 .2-.3-.2z" fill="#910000"/>
<path d="M145.1 138.5l.4 .1-.2 .2-.3-.2zM145.2 138.6v3.5h.6M148 138.6v1.1h.6" fill="none" stroke="#910000" stroke-width=".21"/>
<path d="M147.9 138.5l.3 .1-.1 .2-.3-.2z" fill="#910000"/>
<path d="M147.5 138.6h4M147.9 138.5l.3 .1-.1 .2-.3-.2zM148.6 139.3h1.7v.7h-1.7zM150.3 139.7h.6v11" fill="none" stroke="#910000" stroke-width=".21"/>
<path d="M150.8 139.5l.3 .2-.1 .1-.3-.1z" fill="#910000"/>
<path d="M150.8 139.5l.3 .2-.1 .1-.3-.1zM145.2 142.1v3.4h.6M145.7 141.7h1.8v.7h-1.8z" fill="none" stroke="#910000" stroke-width=".21"/>
<path d="M145.1 141.9l.4 .2-.2 .2-.3-.2z" fill="#910000"/>
<path d="M145.1 141.9l.4 .2-.2 .2-.3-.2zM148 142.1v1h.6" fill="none" stroke="#910000" stroke-width=".21"/>
<path d="M147.9 141.9l.3 .2-.1 .2-.3-.2z" fill="#910000"/>
<path d="M147.5 142.1h4M147.9 141.9l.3 .2-.1 .2-.3-.2zM148.6 142.7h1.7v.7h-1.7zM150.3 143.1h.6v7.6" fill="none" stroke="#910000" stroke-width=".21"/>
<path d="M150.8 142.9l.3 .2-.1 .2-.3-.2z" fill="#910000"/>
<path d="M145.2 145.5v3.5h.6M145.7 145.1h1.8v.7h-1.8zM150.8 142.9l.3 .2-.1 .2-.3-.2z" fill="none" stroke="#910000" stroke-width=".21"/>
<path d="M145.1 145.3l.4 .2-.2 .2-.3-.2z" fill="#910000"/>
<path d="M145.1 145.3l.4 .2-.2 .2-.3-.2zM148 145.5v1.1h.6" fill="none" stroke="#910000" stroke-width=".21"/>
<path d="M147.9 145.3l.3 .2-.1 .2-.3-.2z" fill="#910000"/>
<path d="M147.5 145.5h4M147.9 145.3l.3 .2-.1 .2-.3-.2zM148.6 146.1h1.7v.8h-1.7zM150.3 146.6h.6v4.1" fill="none" stroke="#910000" stroke-width=".21"/>
<path d="M150.8 146.4l.3 .2-.1 .2-.3-.2z" fill="#910000"/>
<path d="M145.7 148.6h1.8v.7h-1.8zM148 149v1h.6M150.8 146.4l.3 .2-.1 .2-.3-.2z" fill="none" stroke="#910000" stroke-width=".21"/>
<path d="M147.9 148.8l.3 .2-.1 .2-.3-.2z" fill="#910000"/>
<path d="M147.5 149h4M147.9 148.8l.3 .2-.1 .2-.3-.2zM148.6 149.6h1.7v.7h-1.7zM150.3 150h.6v.7" fill="none" stroke="#910000" stroke-width=".21"/>
<path d="M150.8 149.8l.3 .2-.1 .2-.3-.2z" fill="#910000"/>
<g fill="none" stroke="#910000" stroke-width=".21">
<path d="M142.9 124.8h1.7M151.5 124.8h1.7M151.5 128.3h1.7M151.5 131.8h1.7M151.5 135.2h1.7M151.5 138.6h1.7M142.9 150.7h8M150.8 149.8l.3 .2-.1 .2-.3-.2zM151.5 142.1h1.7M151.5 145.5h1.7M151.5 149h1.7M178.1 162.7h7v27.5h-7z"/>
<path d="M178.2 163.6h1.2M179.3 163.2h1.7v.7h-1.7z"/>
</g>
<g fill="none" stroke="#b90000" stroke-width=".21">
<path d="M143.5 124l.3-.3v.9M143.5 124.6h.5M152.1 123.8h.5v.4l-.5 .4h.5M152.1 127.2h.5l-.2 .3 .2 .1v.4h-.5M152.4 130.6l-.3 .6h.6M152.5 137.5l-.3 .2-.1 .5 .1 .2 .4-.1-.1-.4h-.3l-.1 .1M152.5 130.9v.6M152.6 134.1h-.4l-.1 .4h.5v.4h-.5M143.1 149.8l.3-.2v.9M143.1 150.5h.5M144 149.6h.2l.2 .1v.6l-.2 .2-.2-.1zM152.1 141h.6l-.4 .9"/>
<path d="M152.3 144.8l-.2-.2 .2-.2 .3 .1v.2l-.4 .1-.1 .2 .2 .3 .3-.1v-.3l-.2-.1M152.6 148.2l-.1 .2h-.3l-.1-.4 .2-.1 .3 .1v.5l-.4 .2"/>
</g>
<g fill="none" stroke="#0f0f0f" stroke-width=".21">
<path d="M187 123.4h5.3M187 126.9h5.5M187.1 124.1h.3M187.1 127.5h.3M187.5 123.7h-.4v.8h.4M187.5 127.1h-.4v.9h.4M187.8 123.7l.5 .8M187.8 127.1l.5 .9M188.3 123.7l-.5 .8M188.3 127.1l-.5 .9M188.7 124.1h.4l.1-.4h-.5v.8M188.7 127.5h.5v-.3l-.5-.1v.9"/>
<path d="M189.4 124.6h.6M189.4 128.1h.6M190.2 127.1v.7l.2 .2 .3-.1v-.8M190.7 123.7h-.3l-.2 .1v.5l.2 .2 .3-.1M191 123.7v.8h.5M191.1 127.1h.4a.48 .48 0 0 1 .1 .6 .48 .48 0 0 1-.5 .3zM191.8 123.7v.8M191.9 124l.3 .5M192.2 123.7l-.4 .5M192.4 127.1l-.4 .1v.2l.4 .2v.3h-.4M153.5 162.9h.3M154 162.4h-.5v.9h.5"/>
<path d="M154.2 162.4l.6 .9M154.8 162.4l-.6 .9M155.1 162.9l.5-.1-.1-.4h-.4v.9M155.7 163.4h.7M156.5 163.3l.3-.9 .3 .9M156.6 163h.4M157.3 162.7l.3-.3v.9M157.3 163.3h.6M158.5 162.4h-.2l-.2 .7 .2 .2 .3-.1-.1-.4-.4 .1M187.1 162.9h.3M187.1 166.2h.3M187.1 173.2h.3"/>
<path d="M187.1 176.6h.3M187.1 169.7h.3M187.5 162.4h-.4v.9h.4M187.5 165.8h-.4v.9h.4M187.5 172.8h-.4v.8h.4M187.5 176.1h-.4v1h.4M187.5 179.6h-.4v.9h.4M187.5 169.3h-.4v.8h.4M187.8 162.4l.5 .9M187.8 165.8l.5 .9M187.8 172.8l.5 .8M187.8 176.1l.5 1"/>
<path d="M187.8 179.6l.5 .9M187.8 169.3l.5 .8M188.3 162.4l-.5 .9M188.3 165.8l-.5 .9M188.3 172.8l-.5 .8M188.3 176.1l-.5 1M188.3 179.6l-.5 .9M188.3 169.3l-.5 .8M188.7 162.9h.4l.1-.4-.5-.1v.9M188.7 166.3l.5-.1v-.3l-.5-.1v.9M188.7 173.2h.4l.1-.4h-.5v.8M188.7 176.7l.5-.1v-.4l-.5-.1v1"/>
<path d="M188.7 169.7h.4l.1-.3-.5-.1v.8M189.4 163.4h.6M189.4 166.8h.6M189.4 173.7h.6M189.4 177.2h.6M189.4 170.2h.6M190.1 166.7l.3-.9 .3 .9M190.1 173.6l.3-.8 .3 .8M190.1 177.1l.3-1 .3 1M190.1 170.1l.3-.8 .3 .8M190.2 162.9h.4l.1-.4-.5-.1v.9M190.2 166.5h.4"/>
<path d="M190.2 173.4h.4M190.2 176.8h.4M190.2 169.9h.4M190.5 162.9l.2 .4M190.9 165.9h.5v.3l-.5 .5h.5M190.9 172.8h.5v.3l-.5 .5h.5M190.9 176.2h.5v.4l-.5 .5h.5M190.9 179.9l.2-.3v.9M190.9 169.4h.5v.2l-.5 .5h.5M191 162.8l.3-.1 .2 .2v.4M191 162.7v.6M191.7 165.8h.5l-.2 .4h.2v.5h-.5"/>
<path d="M191.7 173l.3-.2v.8M191.7 169.4h.5v.2l-.5 .5h.5M191.7 173.6h.5M191.8 162.4l.2 .9 .1-.6 .2 .6 .2-.9M191.8 176.2l.3-.1 .1 .2v.6l-.1 .2a.53 .53 0 0 1-.3-.9zM192.2 180l-.1 .1h-.3l-.1-.3 .2-.2 .3 .1v.6l-.4 .2M187.1 183.5h.3M187.1 180h.3M187.1 186.9h.3M187.5 183.1h-.4v.8h.4M187.5 186.6h-.4v.8h.4M187.8 183.1l.5 .8"/>
<path d="M187.8 186.6l.5 .8M188.3 183.1l-.5 .8M188.3 186.6l-.5 .8M188.7 183.5h.4l.1-.3-.5-.1v.8M188.7 180h.4l.1-.3-.5-.1v.9M188.7 187l.5-.1v-.3h-.5v.8M189.4 184h.6M189.4 180.5h.6M189.4 187.5h.6M190.1 183.9l.3-.8 .3 .8M190.1 180.5l.3-.9 .3 .9M190.1 187.4l.3-.8 .3 .8"/>
<path d="M190.2 183.7h.4M190.2 180.2h.4M190.2 187.2h.4M190.9 183.3l.2-.2v.8M190.9 186.7l.2-.1v.8M190.9 183.9h.5M190.9 180.5h.5M190.9 187.4h.5M191.7 186.6h.5l-.3 .8M191.9 183.4l-.2-.1 .1-.2h.3l.1 .2-.5 .3 .1 .3h.4v-.4l-.1-.1"/>
</g>
<path d="M178.7 163.4l.3 .2-.1 .2-.3-.2z" fill="#910000"/>
<path d="M178.7 163.4l.3 .2-.1 .2-.3-.2zM178.8 163.6v3.5h.6" fill="none" stroke="#910000" stroke-width=".21"/>
<path d="M181.5 163.4l.4 .2-.1 .2-.4-.2z" fill="#910000"/>
<path d="M179.3 166.7h1.7v.7h-1.7zM181.1 163.6h4M181.5 163.4l.4 .2-.1 .2-.4-.2zM181.6 163.6v1h.6M182.2 164.3h1.7v.6h-1.7zM183.9 164.6h.6v24.8" fill="none" stroke="#910000" stroke-width=".21"/>
<path d="M178.6 166.9l.3 .1-.1 .2-.3-.2z" fill="#910000"/>
<path d="M178.7 166.9l.3 .2-.1 .2-.3-.2zM178.8 167.1v3.4h.6" fill="none" stroke="#910000" stroke-width=".21"/>
<path d="M181.5 166.9l.4 .2-.1 .2-.4-.2z" fill="#910000"/>
<path d="M181.1 167.1h4M181.5 166.9l.4 .2-.1 .2-.4-.2zM181.6 167.1v1h.6M182.2 167.7h1.7v.7h-1.7zM183.9 168.1h.6v21.3" fill="none" stroke="#910000" stroke-width=".21"/>
<path d="M184.4 167.9l.3 .2-.1 .2-.3-.2z" fill="#910000"/>
<path d="M179.3 170.1h1.7v.7h-1.7zM184.4 167.9l.3 .2-.1 .2-.3-.2z" fill="none" stroke="#910000" stroke-width=".21"/>
<path d="M178.6 170.2l.3 .2-.1 .2-.3-.2z" fill="#910000"/>
<path d="M178.7 170.3l.3 .2-.1 .2-.3-.2zM178.8 170.5v3.4h.6" fill="none" stroke="#910000" stroke-width=".21"/>
<path d="M181.5 170.3l.4 .2-.1 .2-.4-.2z" fill="#910000"/>
<path d="M181.1 170.5h4M181.5 170.3l.4 .2-.1 .2-.4-.2zM181.6 170.5v1.1h.6M182.2 171.1h1.7v.8h-1.7zM183.9 171.6h.6v17.8" fill="none" stroke="#910000" stroke-width=".21"/>
<path d="M184.4 171.4l.3 .2-.1 .2-.3-.2z" fill="#910000"/>
<path d="M179.3 173.6h1.7v.6h-1.7zM184.4 171.4l.3 .2-.1 .2-.3-.2z" fill="none" stroke="#910000" stroke-width=".21"/>
<path d="M178.6 173.7l.3 .2-.1 .2-.3-.2z" fill="#910000"/>
<path d="M178.7 173.8l.3 .1-.1 .2-.3-.2zM178.8 173.9v3.5h.6" fill="none" stroke="#910000" stroke-width=".21"/>
<path d="M181.5 173.8l.4 .1-.1 .2-.4-.2z" fill="#910000"/>
<path d="M181.1 173.9h4M181.5 173.8l.4 .1-.1 .2-.4-.2zM181.6 173.9v1.1h.6M182.2 174.6h1.7v.7h-1.7zM183.9 175h.6v14.4" fill="none" stroke="#910000" stroke-width=".21"/>
<path d="M184.4 174.8l.3 .2-.1 .1-.3-.1z" fill="#910000"/>
<path d="M179.3 177h1.7v.7h-1.7zM184.4 174.8l.3 .2-.1 .1-.3-.1z" fill="none" stroke="#910000" stroke-width=".21"/>
<path d="M178.6 177.2l.3 .2-.1 .2-.3-.2z" fill="#910000"/>
<path d="M178.7 177.2l.3 .2-.1 .2-.3-.2zM178.8 177.4v3.4h.6M181.6 177.4v1h.6" fill="none" stroke="#910000" stroke-width=".21"/>
<path d="M181.5 177.2l.4 .2-.1 .2-.4-.2z" fill="#910000"/>
<path d="M181.1 177.4h4M181.5 177.2l.4 .2-.1 .2-.4-.2zM182.2 178.1h1.7v.6h-1.7zM183.9 178.4h.6v11" fill="none" stroke="#910000" stroke-width=".21"/>
<path d="M184.4 178.2l.3 .2-.1 .2-.3-.2z" fill="#910000"/>
<path d="M184.4 178.2l.3 .2-.1 .2-.3-.2zM178.8 180.8v3.5h.6M179.3 180.4h1.7v.7h-1.7z" fill="none" stroke="#910000" stroke-width=".21"/>
<path d="M178.7 180.6l.3 .2-.1 .2-.3-.2z" fill="#910000"/>
<path d="M178.7 180.6l.3 .2-.1 .2-.3-.2zM181.6 180.8v1.1h.6" fill="none" stroke="#910000" stroke-width=".21"/>
<path d="M181.5 180.6l.4 .2-.1 .2-.4-.2z" fill="#910000"/>
<path d="M181.1 180.8h4M181.5 180.6l.4 .2-.1 .2-.4-.2zM182.2 181.5h1.7v.7h-1.7zM183.9 181.9h.6v7.5" fill="none" stroke="#910000" stroke-width=".21"/>
<path d="M184.4 181.7l.3 .2-.1 .2-.3-.2z" fill="#910000"/>
<path d="M178.8 184.3v3.4h.6M179.3 183.9h1.7v.7h-1.7zM184.4 181.7l.3 .2-.1 .2-.3-.2z" fill="none" stroke="#910000" stroke-width=".21"/>
<path d="M178.7 184.1l.3 .2-.1 .2-.3-.2z" fill="#910000"/>
<path d="M178.7 184.1l.3 .2-.1 .2-.3-.2zM181.6 184.3v1h.6" fill="none" stroke="#910000" stroke-width=".21"/>
<path d="M181.5 184.1l.4 .2-.1 .2-.4-.2z" fill="#910000"/>
<path d="M181.1 184.3h4M181.5 184.1l.4 .2-.1 .2-.4-.2zM182.2 184.9h1.7v.7h-1.7zM183.9 185.3h.6v4.1" fill="none" stroke="#910000" stroke-width=".21"/>
<path d="M184.4 185.1l.3 .2-.1 .2-.3-.2z" fill="#910000"/>
<path d="M179.3 187.4h1.7v.6h-1.7zM181.6 187.7v1.1h.6M184.4 185.1l.3 .2-.1 .2-.3-.2z" fill="none" stroke="#910000" stroke-width=".21"/>
<path d="M181.5 187.6l.4 .1-.1 .2-.4-.2z" fill="#910000"/>
<path d="M181.1 187.7h4M181.5 187.6l.4 .1-.1 .2-.4-.2zM182.2 188.4h1.7v.7h-1.7zM183.9 188.8h.6v.6" fill="none" stroke="#910000" stroke-width=".21"/>
<path d="M184.4 188.6l.3 .2-.1 .1-.3-.1z" fill="#910000"/>
<g fill="none" stroke="#910000" stroke-width=".21">
<path d="M144.6 162.7h6.9v27.5h-6.9zM144.6 163.6h1.2M145.7 163.2h1.8v.7h-1.8zM176.5 163.6h1.7M185.1 163.6h1.7M185.1 167.1h1.7M185.1 170.5h1.7M185.1 173.9h1.7M185.1 177.4h1.7M176.5 189.4h8M184.4 188.6l.3 .2-.1 .1-.3-.1zM185.1 180.8h1.7"/>
<path d="M185.1 184.3h1.7M185.1 187.7h1.7"/>
</g>
<g fill="none" stroke="#b90000" stroke-width=".21">
<path d="M177.1 162.8l.2-.3v.9M177.1 163.4h.5M185.7 162.6l.4-.1 .1 .2-.5 .7h.5M185.7 166h.5l-.2 .3h.1l.1 .4-.1 .1-.4-.1M185.7 179.8h.5l-.3 .8M186 169.4l-.3 .6h.5M186.1 172.8h-.3l-.1 .5 .4-.1v.5l-.4-.1M186.1 176.3h-.2l-.2 .4 .1 .5h.3v-.5h-.3l-.1 .1M186.1 169.7v.6M176.7 188.6l.2-.3v.9M176.7 189.2h.5M177.6 188.4l.2-.1 .2 .2-.1 .7h-.2l-.2-.3z"/>
<path d="M185.9 183.6l-.2-.3 .4-.1 .1 .2-.5 .3 .1 .3h.3l.1-.3-.1-.1M186.2 187l-.1 .2h-.3v-.6h.3l.1 .2-.1 .7h-.3"/>
</g>
<g fill="none" stroke="#0f0f0f" stroke-width=".21">
<path d="M153.5 166.2h.3M153.5 173.2h.3M153.5 176.6h.3M153.5 169.7h.3M154 165.8h-.5v.9h.5M154 179.6h-.5v.9h.5M154 172.8h-.5v.8h.5M154 176.1h-.5v1h.5M154 169.3h-.5v.8h.5M154.2 165.8l.6 .9M154.2 179.6l.6 .9M154.2 172.8l.6 .8"/>
<path d="M154.2 176.1l.6 1M154.2 169.3l.6 .8M154.8 165.8l-.6 .9M154.8 179.6l-.6 .9M154.8 172.8l-.6 .8M154.8 176.1l-.6 1M154.8 169.3l-.6 .8M155.1 166.3l.5-.1v-.3l-.5-.1v.9M155.1 173.2l.5-.1-.1-.3h-.4v.8M155.1 176.7l.5-.1v-.4l-.5-.1v1M155.1 169.7h.4l.1-.3-.5-.1v.8M155.7 166.8h.7"/>
<path d="M155.7 173.7h.7M155.7 177.2h.7M155.7 170.2h.7M156.5 166.7l.3-.9 .3 .9M156.5 173.6l.3-.8 .3 .8M156.5 177.1l.3-1 .3 1M156.5 170.1l.3-.8 .3 .8M156.6 166.5h.4M156.6 173.4h.4M156.6 176.8h.4M156.6 169.9h.4M157.3 166.1l.3-.3v.9"/>
<path d="M157.3 179.9l.3-.3v.9M157.3 173l.3-.2v.8M157.3 176.4l.3-.3v1M157.3 169.5l.3-.2v.8M157.3 166.7h.6M157.3 173.6h.6M157.3 177.1h.6M157.3 170.1h.6M158.1 179.9l.3-.3v.9M158.1 172.8h.5l-.2 .3 .2 .1v.3h-.5M158.1 176.2h.5v.4l-.5 .5h.5M158.4 169.3l-.3 .6h.6"/>
<path d="M158.5 169.5v.6M158.6 165.8h-.4l-.1 .4h.5v.5h-.5M153.5 183.5h.3M153.5 180h.3M153.5 186.9h.3M154 183.1h-.5v.8h.5M154 186.6h-.5v.8h.5M154.2 183.1l.6 .8M154.2 186.6l.6 .8M154.8 183.1l-.6 .8M154.8 186.6l-.6 .8M155.1 183.5l.5-.1-.1-.3h-.4v.8"/>
<path d="M155.1 180h.4l.1-.3-.5-.1v.9M155.1 187l.5-.1v-.3h-.5v.8M155.7 184h.7M155.7 180.5h.7M155.7 187.5h.7M156.5 183.9l.3-.8 .3 .8M156.5 180.5l.3-.9 .3 .9M156.5 187.4l.3-.8 .3 .8M156.6 183.7h.4M156.6 180.2h.4M156.6 187.2h.4M157.3 183.3l.3-.2v.8"/>
<path d="M157.3 183.9h.6M157.3 180.5h.6M157.9 186.9l-.2 .2-.4-.1v-.4h.6l-.2 .7-.3 .1M158.1 180.5h.5M158.3 183.1h.2l.1 .2-.1 .6a.39 .39 0 0 1-.4-.3 .39 .39 0 0 1 .1-.4z"/>
</g>
<path d="M145.1 163.4l.4 .2-.2 .2-.3-.2z" fill="#910000"/>
<path d="M145.1 163.4l.4 .2-.2 .2-.3-.2zM145.2 163.6v3.5h.6" fill="none" stroke="#910000" stroke-width=".21"/>
<path d="M147.9 163.4l.3 .2-.1 .2-.3-.2z" fill="#910000"/>
<path d="M145.7 166.7h1.8v.7h-1.8zM147.5 163.6h4M147.9 163.4l.3 .2-.1 .2-.3-.2zM148 163.6v1h.6M148.6 164.3h1.7v.6h-1.7zM150.3 164.6h.6v24.8" fill="none" stroke="#910000" stroke-width=".21"/>
<path d="M145.1 166.9l.3 .1-.1 .2-.3-.2z" fill="#910000"/>
<path d="M145.1 166.9l.4 .2-.2 .2-.3-.2zM145.2 167.1v3.4h.6" fill="none" stroke="#910000" stroke-width=".21"/>
<path d="M147.9 166.9l.3 .2-.1 .2-.3-.2z" fill="#910000"/>
<path d="M147.5 167.1h4M147.9 166.9l.3 .2-.1 .2-.3-.2zM148 167.1v1h.6M148.6 167.7h1.7v.7h-1.7zM150.3 168.1h.6v21.3" fill="none" stroke="#910000" stroke-width=".21"/>
<path d="M150.8 167.9l.3 .2-.1 .2-.3-.2z" fill="#910000"/>
<path d="M145.7 170.1h1.8v.7h-1.8zM150.8 167.9l.3 .2-.1 .2-.3-.2z" fill="none" stroke="#910000" stroke-width=".21"/>
<path d="M145.1 170.2l.3 .2-.1 .2-.3-.2z" fill="#910000"/>
<path d="M145.1 170.3l.4 .2-.2 .2-.3-.2zM145.2 170.5v3.4h.6" fill="none" stroke="#910000" stroke-width=".21"/>
<path d="M147.9 170.3l.3 .2-.1 .2-.3-.2z" fill="#910000"/>
<path d="M147.5 170.5h4M147.9 170.3l.3 .2-.1 .2-.3-.2zM148 170.5v1.1h.6M148.6 171.1h1.7v.8h-1.7zM150.3 171.6h.6v17.8" fill="none" stroke="#910000" stroke-width=".21"/>
<path d="M150.8 171.4l.3 .2-.1 .2-.3-.2z" fill="#910000"/>
<path d="M145.7 173.6h1.8v.6h-1.8zM150.8 171.4l.3 .2-.1 .2-.3-.2z" fill="none" stroke="#910000" stroke-width=".21"/>
<path d="M145.1 173.7l.3 .2-.1 .2-.3-.2z" fill="#910000"/>
<path d="M145.1 173.8l.4 .1-.2 .2-.3-.2zM145.2 173.9v3.5h.6" fill="none" stroke="#910000" stroke-width=".21"/>
<path d="M147.9 173.8l.3 .1-.1 .2-.3-.2z" fill="#910000"/>
<path d="M147.5 173.9h4M147.9 173.8l.3 .1-.1 .2-.3-.2zM148 173.9v1.1h.6M148.6 174.6h1.7v.7h-1.7zM150.3 175h.6v14.4" fill="none" stroke="#910000" stroke-width=".21"/>
<path d="M150.8 174.8l.3 .2-.1 .1-.3-.1z" fill="#910000"/>
<path d="M145.7 177h1.8v.7h-1.8zM150.8 174.8l.3 .2-.1 .1-.3-.1z" fill="none" stroke="#910000" stroke-width=".21"/>
<path d="M145.1 177.2l.3 .2-.1 .2-.3-.2z" fill="#910000"/>
<path d="M145.1 177.2l.4 .2-.2 .2-.3-.2zM145.2 177.4v3.4h.6M148 177.4v1h.6" fill="none" stroke="#910000" stroke-width=".21"/>
<path d="M147.9 177.2l.3 .2-.1 .2-.3-.2z" fill="#910000"/>
<path d="M147.5 177.4h4M147.9 177.2l.3 .2-.1 .2-.3-.2zM148.6 178.1h1.7v.6h-1.7zM150.3 178.4h.6v11" fill="none" stroke="#910000" stroke-width=".21"/>
<path d="M150.8 178.2l.3 .2-.1 .2-.3-.2z" fill="#910000"/>
<path d="M150.8 178.2l.3 .2-.1 .2-.3-.2zM145.2 180.8v3.5h.6M145.7 180.4h1.8v.7h-1.8z" fill="none" stroke="#910000" stroke-width=".21"/>
<path d="M145.1 180.6l.4 .2-.2 .2-.3-.2z" fill="#910000"/>
<path d="M145.1 180.6l.4 .2-.2 .2-.3-.2zM148 180.8v1.1h.6" fill="none" stroke="#910000" stroke-width=".21"/>
<path d="M147.9 180.6l.3 .2-.1 .2-.3-.2z" fill="#910000"/>
<path d="M147.5 180.8h4M147.9 180.6l.3 .2-.1 .2-.3-.2zM148.6 181.5h1.7v.7h-1.7zM150.3 181.9h.6v7.5" fill="none" stroke="#910000" stroke-width=".21"/>
<path d="M150.8 181.7l.3 .2-.1 .2-.3-.2z" fill="#910000"/>
<path d="M145.2 184.3v3.4h.6M145.7 183.9h1.8v.7h-1.8zM150.8 181.7l.3 .2-.1 .2-.3-.2z" fill="none" stroke="#910000" stroke-width=".21"/>
<path d="M145.1 184.1l.4 .2-.2 .2-.3-.2z" fill="#910000"/>
<path d="M145.1 184.1l.4 .2-.2 .2-.3-.2zM148 184.3v1h.6" fill="none" stroke="#910000" stroke-width=".21"/>
<path d="M147.9 184.1l.3 .2-.1 .2-.3-.2z" fill="#910000"/>
<path d="M147.5 184.3h4M147.9 184.1l.3 .2-.1 .2-.3-.2zM148.6 184.9h1.7v.7h-1.7zM150.3 185.3h.6v4.1" fill="none" stroke="#910000" stroke-width=".21"/>
<path d="M150.8 185.1l.3 .2-.1 .2-.3-.2z" fill="#910000"/>
<path d="M145.7 187.4h1.8v.6h-1.8zM148 187.7v1.1h.6M150.8 185.1l.3 .2-.1 .2-.3-.2z" fill="none" stroke="#910000" stroke-width=".21"/>
<path d="M147.9 187.6l.3 .1-.1 .2-.3-.2z" fill="#910000"/>
<path d="M147.5 187.7h4M147.9 187.6l.3 .1-.1 .2-.3-.2zM148.6 188.4h1.7v.7h-1.7zM150.3 188.8h.6v.6" fill="none" stroke="#910000" stroke-width=".21"/>
<path d="M150.8 188.6l.3 .2-.1 .1-.3-.1z" fill="#910000"/>
<g fill="none" stroke="#910000" stroke-width=".21">
<path d="M178.1 123.9h7v27.7h-7zM178.2 124.8h1.2M179.3 124.5h1.7v.6h-1.7zM186.8 137.8h3.9l.8 .8-.8 .9h-3.9zM187.3 138h2.8M187.4 138.2v.9M187.8 138.6h.5v-.2l-.1-.2h-.4v.9M188.1 138.6l.2 .5M188.7 138.4l.1-.2a.42 .42 0 0 1 .5 .4 .42 .42 0 0 1-.5 .5l-.1-.1zM188.8 138.9l.5 .2M189.9 138.2l-.2 .1-.2 .6 .1 .2 .4-.1v-.4h-.3l-.2 .1M186.8 141.2h3.9l.8 .9-.8 .9h-3.9z"/>
<path d="M186.8 148.1h3.9l.8 .9-.8 .8h-3.9zM186.8 144.6h3.9l.8 .9-.8 .9h-3.9zM187.3 141.4h2.8M187.3 148.3h2.8M187.3 144.9h2.8M187.4 141.7v.8M187.4 145.2v.8M187.4 148.5v.9M187.8 142.1h.5v-.4h-.5v.8M187.8 149.1h.4l.1-.4-.1-.2h-.4v.9M187.8 145.6h.4l.1-.4h-.5v.8M188.1 142.1l.2 .4"/>
<path d="M188.1 149.1l.2 .3M188.1 145.6l.2 .4M188.7 141.8h.5l.1 .5-.2 .2-.4-.1zM188.7 148.7l.1-.2a.42 .42 0 0 1 .5 .5 .42 .42 0 0 1-.5 .4l-.1-.1zM188.7 145.2h.5a.47 .47 0 0 1-.4 .8l-.1-.2zM188.8 142.4l.5 .2M188.8 149.2l.5 .3M188.8 145.8l.5 .3M189.5 148.5h.5l-.2 .4 .2 .1v.3h-.5M189.8 145.1l-.3 .6h.6M189.9 145.4v.6M190 141.7h-.4l-.1 .4 .4-.1 .1 .4h-.5"/>
<path d="M142.9 163.6h1.7M151.5 163.6h1.7M151.5 167.1h1.7M151.5 170.5h1.7M151.5 173.9h1.7M151.5 177.4h1.7M142.9 189.4h8M150.8 188.6l.3 .2-.1 .1-.3-.1zM151.5 180.8h1.7M151.5 184.3h1.7M151.5 187.7h1.7"/>
</g>
<g fill="none" stroke="#b90000" stroke-width=".21">
<path d="M143.5 162.8l.3-.3v.9M143.5 163.4h.5M152.1 162.6h.5v.3l-.5 .5h.5M152.1 166h.5l-.2 .3 .2 .1v.3h-.5M152.1 179.8h.6l-.4 .8M152.4 169.4l-.3 .6h.6M152.5 176.3h-.2l-.2 .7 .1 .2 .4-.1-.1-.4h-.3l-.1 .1M152.5 169.7v.6M152.6 172.8h-.4l-.1 .5 .4-.1 .1 .4h-.5M143.1 188.6l.3-.3v.9M143.1 189.2h.5M144 188.4l.2-.1 .2 .2-.1 .7-.3-.1z"/>
<path d="M152.3 183.6l-.2-.3 .2-.1 .3 .1v.2l-.5 .2 .1 .3h.3l.1-.3-.2-.1M152.6 187l-.1 .2h-.3v-.6l.4 .1v.6l-.4 .2"/>
</g>
<g fill="none" stroke="#0f0f0f" stroke-width=".21">
<path d="M153.5 124.1h.3M153.5 127.5h.3M153.5 130.9h.3M154 123.7h-.5v.8h.5M154 127.1h-.5v.9h.5M154 130.5h-.5v.9h.5M154.2 123.7l.6 .8M154.2 127.1l.6 .9M154.2 130.5l.6 .9M154.8 123.7l-.6 .8M154.8 127.1l-.6 .9M154.8 130.5l-.6 .9"/>
<path d="M155.1 124.1l.5-.1-.1-.3h-.4v.8M155.1 127.5h.5l-.1-.4h-.4v.9M155.1 131l.5-.1v-.3l-.5-.1v.9M155.7 124.6h.7M155.7 128.1h.7M155.7 131.4h.7M156.5 124.5l.3-.8 .3 .8M156.5 128l.3-.9 .3 .9M156.5 131.4l.3-.9 .3 .9M156.6 124.2h.4M156.6 127.7h.4M156.6 131.2h.4"/>
<path d="M157.3 124.5v-.8l.4 .5 .2-.5v.8M157.3 128v-.9l.4 .6 .2-.6v.9M157.3 131.4v-.9l.4 .7 .2-.7v.9M158.3 127.4l.2-.3v.9M158.3 130.6h.5v.3l-.5 .5h.5M158.3 128h.5M158.5 123.7h.2l.1 .1-.1 .6a.39 .39 0 0 1-.4-.2 .39 .39 0 0 1 .1-.5zM187 133.7h4.5M187 130.3h5.3M187.1 130.9h.3M187.1 134.4h.3M187.5 134h-.4v.8h.4"/>
<path d="M187.5 130.5h-.4v.9h.4M187.8 134l.5 .8M187.8 130.5l.5 .9M188.3 134l-.5 .8M188.3 130.5l-.5 .9M188.7 134.4h.4l.1-.3-.5-.1v.8M188.7 131l.5-.1v-.3l-.5-.1v.9M189.4 131.4h.6M189.4 134.9h.6M190.1 134.8l.3-.8 .3 .8M190.2 130.5v.9h.4M190.2 134.6h.4"/>
<path d="M190.9 130.5h.2l.3 .3v.4l-.2 .2h-.3zM191.4 134h-.4l-.1 .2 .1 .2 .4 .1v.2l-.5 .1M192.2 130.6l-.3-.1-.2 .2 .1 .2 .4 .2v.2l-.5 .1"/>
</g>
<path d="M178.7 124.6l.3 .2-.1 .2-.3-.2z" fill="#910000"/>
<path d="M178.7 124.6l.3 .2-.1 .2-.3-.2zM178.8 124.8v3.5h.6" fill="none" stroke="#910000" stroke-width=".21"/>
<path d="M181.5 124.6l.4 .2-.1 .2-.4-.2z" fill="#910000"/>
<path d="M179.3 127.9h1.7v.7h-1.7zM181.1 124.8h4M181.5 124.6l.4 .2-.1 .2-.4-.2zM181.6 124.8v1.1h.6M182.2 125.5h1.7v.7h-1.7zM183.9 125.9h.6v24.8" fill="none" stroke="#910000" stroke-width=".21"/>
<path d="M178.6 128.1l.3 .2-.1 .2-.3-.2z" fill="#910000"/>
<path d="M178.7 128.1l.3 .2-.1 .2-.3-.2zM178.8 128.3v3.5h.6" fill="none" stroke="#910000" stroke-width=".21"/>
<path d="M181.5 128.1l.4 .2-.1 .2-.4-.2z" fill="#910000"/>
<path d="M181.1 128.3h4M181.5 128.1l.4 .2-.1 .2-.4-.2zM181.6 128.3v1h.6M182.2 128.9h1.7v.7h-1.7zM183.9 129.3h.6v21.4" fill="none" stroke="#910000" stroke-width=".21"/>
<path d="M184.4 129.1l.3 .2-.1 .2-.3-.2z" fill="#910000"/>
<path d="M179.3 131.3h1.7v.8h-1.7zM184.4 129.1l.3 .2-.1 .2-.3-.2z" fill="none" stroke="#910000" stroke-width=".21"/>
<path d="M178.6 131.5l.3 .2-.1 .2-.3-.2z" fill="#910000"/>
<path d="M178.7 131.6l.3 .2-.1 .2-.3-.2zM178.8 131.8v3.4h.6" fill="none" stroke="#910000" stroke-width=".21"/>
<path d="M181.5 131.6l.4 .2-.1 .2-.4-.2z" fill="#910000"/>
<path d="M181.1 131.8h4M181.5 131.6l.4 .2-.1 .2-.4-.2zM181.6 131.8v1h.6M182.2 132.4h1.7v.7h-1.7zM183.9 132.8h.6v17.9" fill="none" stroke="#910000" stroke-width=".21"/>
<path d="M184.4 132.6l.3 .2-.1 .2-.3-.2z" fill="#910000"/>
<path d="M179.3 134.8h1.7v.7h-1.7zM184.4 132.6l.3 .2-.1 .2-.3-.2z" fill="none" stroke="#910000" stroke-width=".21"/>
<path d="M178.6 134.9l.3 .2-.1 .2-.3-.2z" fill="#910000"/>
<path d="M178.7 135l.3 .2-.1 .2-.3-.2zM178.8 135.2v3.4h.6" fill="none" stroke="#910000" stroke-width=".21"/>
<path d="M181.5 135l.4 .2-.1 .2-.4-.2z" fill="#910000"/>
<path d="M181.1 135.2h4M181.5 135l.4 .2-.1 .2-.4-.2zM181.6 135.2v1h.6M182.2 135.8h1.7v.8h-1.7zM183.9 136.2h.6v14.5" fill="none" stroke="#910000" stroke-width=".21"/>
<path d="M184.4 136l.3 .2-.1 .2-.3-.2z" fill="#910000"/>
<path d="M179.3 138.3h1.7v.6h-1.7zM184.4 136l.3 .2-.1 .2-.3-.2z" fill="none" stroke="#910000" stroke-width=".21"/>
<path d="M178.6 138.4l.3 .2-.1 .2-.3-.2z" fill="#910000"/>
<path d="M178.7 138.5l.3 .1-.1 .2-.3-.2zM178.8 138.6v3.5h.6M181.6 138.6v1.1h.6" fill="none" stroke="#910000" stroke-width=".21"/>
<path d="M181.5 138.5l.4 .1-.1 .2-.4-.2z" fill="#910000"/>
<path d="M181.1 138.6h4M181.5 138.5l.4 .1-.1 .2-.4-.2zM182.2 139.3h1.7v.7h-1.7zM183.9 139.7h.6v11" fill="none" stroke="#910000" stroke-width=".21"/>
<path d="M184.4 139.5l.3 .2-.1 .1-.3-.1z" fill="#910000"/>
<path d="M184.4 139.5l.3 .2-.1 .1-.3-.1zM178.8 142.1v3.4h.6M179.3 141.7h1.7v.7h-1.7z" fill="none" stroke="#910000" stroke-width=".21"/>
<path d="M178.7 141.9l.3 .2-.1 .2-.3-.2z" fill="#910000"/>
<path d="M178.7 141.9l.3 .2-.1 .2-.3-.2zM181.6 142.1v1h.6" fill="none" stroke="#910000" stroke-width=".21"/>
<path d="M181.5 141.9l.4 .2-.1 .2-.4-.2z" fill="#910000"/>
<path d="M181.1 142.1h4M181.5 141.9l.4 .2-.1 .2-.4-.2zM182.2 142.7h1.7v.7h-1.7zM183.9 143.1h.6v7.6" fill="none" stroke="#910000" stroke-width=".21"/>
<path d="M184.4 142.9l.3 .2-.1 .2-.3-.2z" fill="#910000"/>
<path d="M178.8 145.5v3.5h.6M179.3 145.1h1.7v.7h-1.7zM184.4 142.9l.3 .2-.1 .2-.3-.2z" fill="none" stroke="#910000" stroke-width=".21"/>
<path d="M178.7 145.3l.3 .2-.1 .2-.3-.2z" fill="#910000"/>
<path d="M178.7 145.3l.3 .2-.1 .2-.3-.2zM181.6 145.5v1.1h.6" fill="none" stroke="#910000" stroke-width=".21"/>
<path d="M181.5 145.3l.4 .2-.1 .2-.4-.2z" fill="#910000"/>
<path d="M181.1 145.5h4M181.5 145.3l.4 .2-.1 .2-.4-.2zM182.2 146.1h1.7v.8h-1.7zM183.9 146.6h.6v4.1" fill="none" stroke="#910000" stroke-width=".21"/>
<path d="M184.4 146.4l.3 .2-.1 .2-.3-.2z" fill="#910000"/>
<path d="M179.3 148.6h1.7v.7h-1.7zM181.6 149v1h.6M184.4 146.4l.3 .2-.1 .2-.3-.2z" fill="none" stroke="#910000" stroke-width=".21"/>
<path d="M181.5 148.8l.4 .2-.1 .2-.4-.2z" fill="#910000"/>
<path d="M181.1 149h4M181.5 148.8l.4 .2-.1 .2-.4-.2zM182.2 149.6h1.7v.7h-1.7zM183.9 150h.6v.7" fill="none" stroke="#910000" stroke-width=".21"/>
<path d="M184.4 149.8l.3 .2-.1 .2-.3-.2z" fill="#910000"/>
<g fill="none" stroke="#910000" stroke-width=".21">
<path d="M44.7 40.4v-.8l-.8 .8 .8 .9v-.9h.9M44.7 43.9v-.9l-.8 .9 .8 .8v-.8h.9M44.7 50.8v-.9l-.8 .9 .8 .9v-.9h.9M44.7 57.7v-.8l-.8 .8 .8 .8v-.8h.9M44.7 54.2v-.8l-.8 .8 .8 .9v-.9h.9M45.6 40.4h.1M45.6 43.9h.1M45.6 50.8h.1M45.6 57.7h.1M45.6 54.2h.1M45.8 51.6h5v1.8h-5l-.7-.9zM46.4 51.9h3.8"/>
<path d="M46.6 52.1l.4 .1 .1 .4-.2 .4h-.3zM47.3 52.1h.5M47.5 52.1v.9M48 53l.3-.9 .3 .9M48 52.7h.5M49.3 52.2l-.3-.1-.2 .2v.5l.2 .2 .3-.1M49.7 52.1v.9M49.8 52.4l.4 .6M50.2 52.1l-.5 .5M132.5 59.4h1v-.9l.8 .9-.8 .8v-.8M132.5 59.4h.1M132.5 64.6h1v-.9l.8 .9-.8 .8v-.8"/>
<path d="M132.5 64.6h.1M132.5 79.5l1 .5M133.5 77.5h5l.7 .9-.7 .8h-5zM133.5 70.6h3.9l.6 .8-.6 .9h-3.9zM133.5 67.2h3.9l.6 .8-.6 .9h-3.9zM133.9 70.8h2.8M133.9 67.3h2.8M134.1 78.4h.6M134.1 67.6v.8M134.1 71.1v.8M134.3 78.1v.7M134.4 71.5h.4l.1-.3-.5-.1v.8"/>
<path d="M134.4 68h.4l.1-.3-.5-.1v.8M134.7 71.5l.2 .4M134.7 68l.2 .4M135.4 71.7l.4 .3M135.4 71.1l.4 .1a.47 .47 0 0 1-.4 .7l-.1-.3zM135.4 68.3l.4 .2M135.4 67.6h.3l.1 .3-.1 .5h-.3l-.1-.2zM135.5 77.9h-.4v.5h.4l-.1 .4-.3-.1M135.8 77.9l.3 .9 .3-.9M136.4 71l-.2 .6h.5M136.6 67.6l-.4 .2v.6h.4v-.5h-.3l-.1 .2M136.6 71.3v.6"/>
<path d="M136.9 78.3l-.1-.1-.2 .2 .3 .1v.3h-.3M137.4 77.9v.9h.3l.1-.4-.2-.2-.2 .1M57.9 91.2h2.4l.8 1-.8 .8h-2.4zM58.5 92.6l.4-.9 .2 .9M58.5 91.5h1.5M58.6 92.3h.5M59.9 91.7l-.5 .1v.3l.5 .2-.1 .3h-.4M61.1 92.2h2.9M61.1 95.5h2.9M63.7 91.2a4.5 4.5 0 0 1 0 5.2M63.7 96.3h2.1M63.7 91.2h2.1"/>
<path d="M65.8 91.2a3.4 3.4 0 0 1 3 2.6M68.8 93.8a3.6 3.6 0 0 1-3 2.6M68.9 93.8h2.5M100.7 93h3.5M100.7 94.7h3.5M100.7 96.4h3.5M100.7 98.2h3.5M100.7 99.9h3.5M104.1 91.2h10.4v20.7h-10.4zM109.3 87.8v3.4M114.5 93h3.4M114.5 94.7h3.4"/>
<path d="M114.5 96.4h3.4M114.5 98.2h3.4M114.5 99.9h3.4M131.7 80h.1M131.7 80h1.8M132.5 93h3.5M132.5 94.7h3.5M132.5 96.4h3.5M132.5 98.2h3.5M132.5 99.9h3.5M133.5 80l-1 .6M136 91.2h10.3v20.7h-10.3z"/>
<path d="M141.2 87.8h.1M141.2 86.1l-.5 .9M141.2 86.1l.5 .9M141.2 86.1v5.1M146.3 93h3.5M146.3 94.7h3.5M146.3 96.4h3.5M146.3 98.2h3.5M146.3 99.9h3.5M165.3 93h3.5M165.3 94.7h3.5M165.3 96.4h3.5"/>
<path d="M165.3 98.2h3.5M165.3 99.9h3.5M168.7 91.2h10.4v20.7h-10.4zM173.9 87.8v3.4M179.1 93h3.4M179.1 94.7h3.4M179.1 96.4h3.4M179.1 98.2h3.4M179.1 99.9h3.4M38.6 102.5h.1M38.6 100.7l-.5 .9M38.6 100.7l.6 .9"/>
<path d="M38.6 100.7v1.8M56.9 101.6h3.4l.8 .9-.8 .8h-3.4zM57.5 101.8h2.5M57.7 102.1l.1 .8 .3-.1v-.7M58.5 102.1h.4l.2 .1v.5l-.2 .2h-.4zM59.9 102.1h-.5v.3l.5 .3-.1 .2h-.4M61.1 102.5h2.9M61.1 105.9h2.9M63.7 101.5a4.5 4.5 0 0 1 0 5.2M63.7 101.6h2.1M65.8 101.6a3.4 3.4 0 0 1 2.9 2.5M68.8 104.1a3.6 3.6 0 0 1-3 2.7h-2.1"/>
<path d="M68.9 104.2h2.5M100.7 101.6h3.5M100.7 103.3h3.5M100.7 105h3.5M100.7 108.5h3.5M100.7 110.2h2.5M109.3 112v3.4M109.8 100.7h-.9v1.8M110.2 100.7h-.4v1.8h-1.4M114.5 101.6h3.4M114.5 103.3h3.4M114.5 105h3.4"/>
<path d="M132.5 101.6h3.5M132.5 103.3h3.5M132.5 105h3.5M132.5 108.5h3.5M132.5 110.2h2.7M141.2 112v3.4M141.6 100.7h-.8v1.8M142 100.7h-.4v1.8h-1.3M146.3 101.6h3.5M146.3 103.3h3.5M146.3 105h3.5M158.5 108.5h.1"/>
<path d="M158.5 106.8l-.6 .9M158.5 106.8l.5 .9M158.5 106.8v1.7M161.2 104.2h3.3l.8 .8-.8 .9h-3.3zM161.2 102.5h3.3l.8 .8-.8 .9h-3.3zM161.2 100.7h3.3l.8 .9-.8 .9h-3.3zM162 105.5l.3-.9 .2 .9M162 103.8l.3-.9 .2 .9M162 102.1l.3-.9 .2 .9M162 105.3h.4M162 103.5h.4M162 101.8h.4"/>
<path d="M162.8 104.9l.2-.3v.9M162.8 103.2l.2-.3v.9M162.8 101.5l.2-.3v.9M162.8 105.5h.5M162.8 103.8h.5M162.8 102.1h.5M163.5 104.6h.6l-.3 .9M163.8 103.2l-.2-.2 .4-.1 .1 .2-.1 .1-.4 .1 .1 .5h.3l.1-.2-.1-.4M164.1 101.6l-.1 .1h-.3l-.1-.4 .4-.1 .1 .2v.3l-.4 .4M165.3 101.6h3.5M165.3 103.3h3.5M165.3 105h3.5"/>
<path d="M165.3 108.5h3.5M165.3 110.2h2.5M173.9 115.4v.8h.9l-.9 .9-.9-.9h.9M173.9 115.4h.1M173.9 112v3.4M174.4 100.7h-.9v1.8M174.8 100.7h-.4v1.8h-1.4M179.1 101.6h3.4M179.1 103.3h3.4M179.1 105h3.4M203.2 101.6v.9h.9l-.9 .8-.9-.8h.9M203.2 101.6h.1"/>
<path d="M176.5 124.8h1.7M185.1 124.8h1.7M185.1 128.3h1.7M185.1 131.8h1.7M185.1 135.2h1.7M185.1 138.6h1.7M176.5 150.7h8M184.4 149.8l.3 .2-.1 .2-.3-.2zM185.1 142.1h1.7M185.1 145.5h1.7M185.1 149h1.7"/>
<circle cx="103.8" cy="110.2" r=".47"/>
<circle cx="135.6" cy="110.2" r=".47"/>
<circle cx="168.3" cy="110.2" r=".47"/>
</g>
<g fill="none" stroke="#b90000" stroke-width=".21">
<path d="M62.3 91.3l.2-.2v.8M62.3 94.5h.5v.4l-.5 .5h.5M62.3 91.9h.5M69.8 92.7h.6l-.3 .4h.2l.1 .2-.1 .3-.5-.1M102.1 92h.6v.2l-.6 .5h.6M102.1 93.6h.6l-.3 .3 .3 .1v.4h-.6M102.4 95.3l-.3 .6h.6M102.6 98.8h-.3l-.2 .7h.6v-.3l-.2-.1-.4 .2M102.6 95.6v.6M102.7 97.1h-.5l-.1 .4 .5-.1 .1 .4h-.6M108.2 89a.48 .48 0 0 1 .5-.2 .48 .48 0 0 1 .4 .4l-.2 .2h-.5l-.2-.1zM109.1 89.7v.5l-.6-.5-.3 .1 .1 .4"/>
<path d="M115.5 92.2l.3-.3v.8M115.5 93.8l.3-.2v.8M115.5 95.5l.3-.1v.8M115.5 97.3l.3-.2v.8M115.5 99l.3-.2v.8M115.5 92.7h.5M115.5 94.4h.5M115.5 96.2h.5M115.5 97.9h.5M115.5 99.6h.5M116.4 93.6h.5l-.4 .8M116.5 92.2l-.1-.2 .4-.1v.3l-.4 .1 .1 .4h.3l.1-.3-.2-.2"/>
<path d="M116.5 98.8l-.1 .6h.5M116.8 95.4l-.4 .1v.6l.3 .1 .2-.4-.2-.2-.3 .2M116.8 97.1h-.4v.4l.4-.1v.5l-.4-.1M116.8 99.1v.5M134 93.6h.6l-.4 .3 .4 .2-.1 .3h-.5M134.1 92l.4-.1 .1 .3-.6 .5h.6M134.2 95.3l-.1 .6h.5M134.5 97.1h-.4v.4l.4-.1 .1 .2-.1 .3-.4-.1M134.5 98.8h-.3l-.1 .7h.5l-.2-.4-.3 .2M134.5 95.6v.6M140.2 88.9a.39 .39 0 0 1 .4-.1 .39 .39 0 0 1 .2 .5l-.6 .1-.1-.2zM140.9 89.7v.5l-.6-.5-.2 .2 .1 .3"/>
<path d="M147.4 92.2l.3-.3v.8M147.4 93.8l.3-.2v.8M147.4 95.5l.3-.1v.8M147.4 97.3l.3-.2v.8M147.4 99l.3-.2v.8M147.4 92.7h.6M147.4 94.4h.6M147.4 96.2h.6M147.4 97.9h.6M147.4 99.6h.6M148.2 93.6h.6l-.4 .8M148.4 92.2l-.2-.1 .1-.2 .4 .1-.1 .2-.4 .2 .1 .3h.4v-.4l-.2-.1"/>
<path d="M148.5 98.8l-.3 .6h.6M148.6 95.4h-.2l-.2 .7 .2 .1 .3-.1v-.4l-.3-.1-.2 .2M148.6 99.1v.5M148.7 97.1h-.4l-.1 .4 .4-.1 .1 .4h-.5M166.7 92h.6v.2l-.6 .5h.6M166.7 93.6h.6l-.3 .3 .3 .1v.4h-.6M167 95.3l-.3 .6h.6M167.2 98.8h-.3l-.2 .7h.6v-.3l-.2-.1-.4 .2M167.2 95.6v.6M167.3 97.1h-.5l-.1 .4 .5-.1 .1 .4h-.6M172.8 89a.48 .48 0 0 1 .5-.2 .48 .48 0 0 1 .4 .4l-.2 .2h-.5l-.2-.1zM173.7 89.7v.5l-.6-.5-.3 .1 .1 .4"/>
<path d="M180.1 92.2l.3-.3v.8M180.1 93.8l.3-.2v.8M180.1 95.5l.3-.1v.8M180.1 97.3l.3-.2v.8M180.1 99l.3-.2v.8M180.1 92.7h.5M180.1 94.4h.5M180.1 96.2h.5M180.1 97.9h.5M180.1 99.6h.5M180.9 93.6h.6l-.4 .8M181.1 92.2l-.1-.2 .4-.1v.3l-.4 .1v.4h.4l.1-.3-.2-.2"/>
<path d="M181.1 98.8l-.1 .6h.5M181.4 95.4l-.4 .1v.6l.3 .1 .2-.4-.2-.2-.3 .2M181.4 97.1h-.4v.4l.4-.1v.5l-.4-.1M181.4 99.1v.5M62.5 101.3l-.2 .7h.6M62.7 101.6v.6M62.8 104.8h-.4l-.1 .4h.5v.4h-.5M70.3 103.1l-.4 .2v.5l.4 .1v-.5h-.3l-.1 .2M101.8 109.3l.2-.2v.9M101.8 110h.4M102.1 100.5h.6l-.4 .9M102.1 107.7l.3-.3v.8"/>
<path d="M102.1 108.2h.6M102.3 102.6l-.2-.2 .1-.2h.4l.1 .3-.6 .2 .1 .4 .5-.1v-.3l-.2-.1M102.7 104.3l-.2 .2-.4-.2 .2-.4 .4 .1v.6l-.1 .2h-.4M103.1 109.5l-.4 .2-.1-.4 .1-.2 .4 .1v.6l-.4 .2M108.2 113.2a.48 .48 0 0 1 .5-.2 .48 .48 0 0 1 .4 .3l-.2 .2h-.5l-.2-.1zM109.1 114.1h-.9l.3 .2M109.1 113.8v.5M115.5 100.8l.3-.3v.9M115.5 102.5l.3-.3v.9M115.5 104.2l.3-.3v.9M115.5 101.4h.5M115.5 103.1h.5"/>
<path d="M115.5 104.8h.5M116.4 100.5h.5l-.4 .3 .4 .2v.2l-.2 .2-.3-.1M116.4 102.3l.4-.1 .1 .2-.5 .7h.5M116.4 104.2l.2-.3v.9M116.4 104.8h.5M133.6 109.3l.3-.2v.9M133.6 110h.6M134 100.5h.6l-.4 .9M134.1 107.7l.2-.3v.8M134.1 108.2h.5M134.2 102.6l-.1-.3 .4-.1v.4l-.4 .1 .1 .4h.3l.1-.2-.2-.3M134.6 104.3l-.2 .2-.3-.1v-.4l.3-.1 .2 .2-.2 .7h-.2"/>
<path d="M134.9 109.5l-.2 .2-.2-.1v-.4h.4v.6l-.3 .2M140.2 113.1a.39 .39 0 0 1 .4-.1 .39 .39 0 0 1 .2 .4l-.6 .1-.1-.2zM140.9 114.1h-.8l.2 .2M140.9 113.8v.5M147.4 100.8l.3-.3v.9M147.4 102.5l.3-.3v.9M147.4 104.2l.3-.3v.9M147.4 101.4h.6M147.4 103.1h.6M147.4 104.8h.6M148.2 100.5h.5l-.2 .3 .2 .1v.4h-.5M148.2 102.3h.5v.3l-.5 .5h.5"/>
<path d="M148.2 104.2l.3-.3v.9M148.2 104.8h.5M166.3 109.3l.3-.2v.9M166.3 110h.5M166.7 100.5h.6l-.4 .9M166.7 107.7l.3-.3v.8M166.7 108.2h.6M166.9 102.6l-.2-.2 .1-.2 .5 .1-.1 .3-.5 .1 .1 .4 .5-.1v-.3l-.2-.1M167.3 104.3l-.2 .2-.4-.2 .2-.4 .4 .1v.6l-.1 .2h-.4M167.7 109.5l-.4 .2-.1-.4 .1-.2 .4 .1-.1 .7-.3 .1M172.8 113.2a.48 .48 0 0 1 .5-.2 .48 .48 0 0 1 .4 .3l-.2 .2h-.5l-.2-.1zM173.7 114.1h-.9l.3 .2"/>
<path d="M173.7 113.8v.5M180.1 100.8l.3-.3v.9M180.1 102.5l.3-.3v.9M180.1 104.2l.3-.3v.9M180.1 101.4h.5M180.1 103.1h.5M180.1 104.8h.5M180.9 100.5h.6l-.4 .3 .4 .2v.2l-.2 .2-.4-.1M181 102.3l.4-.1 .1 .3-.6 .6h.6M181 104.2l.2-.3v.9M181 104.8h.5M177.1 124l.2-.3v.9"/>
<path d="M177.1 124.6h.5M185.7 123.8l.4-.1 .1 .2-.5 .7h.5M185.7 127.2h.5l-.2 .3 .2 .2-.1 .4-.4-.1M186 130.6l-.3 .6h.5M186.1 134.1h-.3l-.1 .4 .4-.1 .1 .4-.1 .2-.4-.1M186.1 137.5l-.4 .4 .1 .5h.3v-.5h-.3l-.1 .1M186.1 130.9v.6M176.7 149.8l.2-.2v.9M176.7 150.5h.5M177.6 149.6h.2l.2 .1v.6l-.2 .2a.53 .53 0 0 1-.2-.9zM185.7 141h.5l-.3 .9M185.9 144.8l-.2-.2 .4-.2 .1 .2-.5 .4 .2 .3 .3-.1-.1-.4"/>
<path d="M186.2 148.2l-.1 .2h-.3l-.1-.4 .2-.1 .3 .1-.1 .7h-.3"/>
</g>
<g fill="none" stroke="#0f0f0f" stroke-width=".21">
<path d="M46.1 29.3h.3M46.1 27.6h.3M46.1 25.9h.3M46.1 34.5h.3M46.1 37.9h.3M46.1 36.2h.3M46.1 31h.3M46.1 32.7h.3M46.5 25.4h-.4v.9h.4M46.5 27.2h-.4v.9h.4M46.5 34.1h-.4v.8h.4M46.5 37.5h-.4v.9h.4"/>
<path d="M46.5 28.9h-.4v.9h.4M46.5 35.8h-.4v.8h.4M46.5 30.6h-.4v.9h.4M46.5 32.4h-.4v.8h.4M46.8 25.4l.6 .9M46.8 27.2l.6 .9M46.8 34.1l.6 .8M46.8 37.5l.6 .9M46.8 28.9l.6 .9M46.8 35.8l.6 .8M46.8 30.6l.6 .9M46.8 32.4l.6 .8"/>
<path d="M47.4 25.4l-.6 .9M47.4 27.2l-.6 .9M47.4 34.1l-.6 .8M47.4 37.5l-.6 .9M47.4 28.9l-.6 .9M47.4 35.8l-.6 .8M47.4 30.6l-.6 .9M47.4 32.4l-.6 .8M47.7 25.9h.3l.2-.3-.2-.2h-.3v.9M47.7 27.6h.3l.2-.3-.5-.1v.9M47.7 34.5h.4v-.4h-.4v.8M47.7 38h.3l.2-.2-.1-.3h-.4v.9"/>
<path d="M47.7 29.3h.4v-.4h-.4v.9M47.7 36.3h.3l.2-.4-.2-.1h-.3v.8M47.7 31.1h.3l.2-.3-.2-.2h-.3v.9M47.7 32.8h.3l.2-.2-.1-.2h-.4v.8M48.4 29.8h.6M48.4 28.1h.6M48.4 26.4h.6M48.4 35h.6M48.4 38.5h.6M48.4 36.7h.6M48.4 31.5h.6M48.4 33.3h.6"/>
<path d="M49.2 25.4l.5 .2-.1 .7h-.4zM49.2 27.2l.5 .1v.6l-.3 .2h-.2zM49.2 34.1l.5 .1-.1 .7h-.4zM49.2 37.5l.5 .1v.6l-.3 .2h-.2zM49.2 28.9l.5 .1-.1 .8h-.4zM49.2 35.8l.5 .1-.1 .7h-.4zM49.2 30.6l.5 .2-.1 .7h-.4zM49.2 32.4l.5 .1v.6l-.3 .1h-.2zM50 27.4l.2-.2v.9M50 29h.5v.2l-.5 .6h.5M50 35.8h.6l-.4 .8M50 30.6h.5l-.3 .3 .3 .1v.4h-.5"/>
<path d="M50 28.1h.5M50.1 25.5l.2-.1 .2 .2-.1 .7h-.2l-.2-.3zM50.2 32.3l-.2 .6h.6M50.4 37.5h-.2l-.2 .7 .2 .2 .3-.1v-.4l-.5 .1M50.4 32.6v.6M50.5 34.1h-.4l-.1 .4 .4-.1 .1 .4h-.5M100.4 29.3h.2M100.8 28.9h-.4v.9h.4M101 28.9l.6 .9M101.6 28.9l-.6 .9M102 29.3l.4-.1-.1-.3h-.3v.9M102.6 29.8h.6"/>
<path d="M103.5 28.9l.4 .2v.5l-.1 .2h-.3zM104.3 29h.5v.2l-.5 .6h.5M127.5 27h6.3M127.7 27.6h.3M128.1 27.2h-.4v.9h.4M128.4 27.2l.6 .9M129 27.2l-.6 .9M129.2 27.6h.5v-.3l-.5-.1v.9M129.9 28.1h.7M130.8 27.6h.4l.1-.3-.5-.1v.9l.5-.1v-.4h-.2M132.1 27.3l-.3-.1a.43 .43 0 0 0-.2 .5 .43 .43 0 0 0 .5 .3M132.5 27.2v.9h.5"/>
<path d="M133.2 27.6h.4l.1-.3-.5-.1v.9M133.4 27.6l.3 .5M39.2 46.8h5.4M39.3 47.4h.4M39.7 47h-.4v.9h.4M40.1 47l.5 .9M40.6 47l-.5 .9M40.9 47.5l.5-.1v-.4h-.5v.9M41.6 48h.7M42.5 47v.9h.4M43.1 47h.4l.1 .2v.4l-.2 .3h-.3zM43.9 58.8h5.8"/>
<path d="M44.1 59.5h.2M44.2 45h5.5M44.3 49.1h.3M44.3 45.7h.3M44.4 59.1h-.3v.8h.3M44.4 41.6h5.3M44.5 47l-.5 .1 .1 .3 .4 .2-.2 .3-.3-.1M44.5 42.2h.2M44.7 48.7h-.4v.9h.4M44.7 45.3h-.4v.8h.4M44.7 59.1l.6 .8M44.9 41.8h-.4v.9h.4"/>
<path d="M45 48.7l.6 .9M45 45.3l.6 .8M45.2 41.8l.6 .9M45.3 55.3h4.4M45.3 56h.4M45.3 59.1l-.6 .8M45.6 48.7l-.6 .9M45.6 45.3l-.6 .8M45.7 59.5h.3l.1-.4h-.4v.8M45.8 55.6h-.5v.8h.5M45.8 41.8l-.6 .9M45.8 49.1h.5l.1-.3-.6-.1v.9"/>
<path d="M45.9 45.8h.4l.1-.2-.1-.3h-.4v.8M46 55.6l.6 .8M46.1 42.3h.3l.2-.2-.2-.3h-.3v.9M46.3 60h.6M46.5 49.7h.7M46.6 55.6l-.6 .8M46.6 46.2h.6M46.8 42.8h.6M46.9 56.1h.4l.2-.4-.2-.1h-.4v.8M47.1 59.1v.8M47.4 49.1h.4l.1-.3-.5-.1v.9M47.5 59.9l.2-.8 .3 .8"/>
<path d="M47.5 45.3v.8h.4l.1-.2v-.6M47.5 59.6h.5M47.6 56.5h.7M47.6 49.1l.3 .5M48.1 41.9a.42 .42 0 0 0-.6 .3 .42 .42 0 0 0 .6 .4M48.3 49.1l.2-.1 .1 .1v.5M48.3 49v.6M48.4 56.4l.2-.8 .3 .8M48.4 45.3l.4 .2v.4l-.2 .2h-.2zM48.4 56.3h.4M48.5 41.8v.9h.4M48.8 59.1h-.4l-.1 .1 .1 .7 .4-.1"/>
<path d="M49 48.7l.1 .9 .2-.6 .2 .6 .2-.9M49.1 41.8v.9M49.1 59.1v.8M49.3 42.2l.4 .5M49.3 59.4l.4 .5M49.7 55.7l-.4-.1-.2 .1 .1 .3 .5 .2-.1 .2h-.5M49.7 45.3h-.4l-.2 .1 .1 .3 .5 .1v.2l-.6 .1M49.7 41.8l-.6 .5M49.7 59.1l-.6 .5M74.3 53.5h.2M74.7 53h-.4v.9h.4M75 53l.6 .9"/>
<path d="M75.6 53l-.6 .9M75.9 53.5h.4v-.5h-.4v.9M76.5 54h.7M77.3 53.9l.3-.9 .2 .9M77.3 53.6h.5M78.1 53.9v-.9l.3 .6 .3-.6v.9M79 53.3l.3-.3v.9M79 53.9h.5M42.6 60.5h7.1M42.7 61.2h.3M43.1 60.7h-.4v.9h.4M43.4 60.7l.6 .9"/>
<path d="M44 60.7l-.6 .9M44.3 61.3h.4l.1-.4-.1-.2h-.4v.9M44.4 63.8h.3M44.7 63.4h-.3v.8h.3M45 61.7h.7M45.1 63.4l.6 .8M45.7 63.4l-.6 .8M45.8 60.7v.9M45.9 63.8h.5v-.3l-.5-.1v.8M46.1 61.6l.3-.9 .3 .9M46.2 69h.3M46.2 65.5h.3"/>
<path d="M46.2 67.2h.3M46.2 75.8h.3M46.2 61.4h.4M46.6 65.1h-.4v.8h.4M46.6 68.5h-.4v.9h.4M46.6 66.8h-.4v.9h.4M46.6 75.4h-.4v.8h.4M46.6 64.3h.7M46.9 65.1l.6 .8M46.9 68.5l.6 .9M46.9 66.8l.6 .9M46.9 75.4l.6 .8"/>
<path d="M47.4 64.2l.2-.8 .4 .8M47.5 60.8l-.2-.1a.5 .5 0 0 0-.2 .9l.4-.1M47.5 64h.4M47.5 65.1l-.6 .8M47.5 68.5l-.6 .9M47.5 66.8l-.6 .9M47.5 75.4l-.6 .8M47.8 65.5h.5v-.4h-.5v.8M47.8 69h.4l.1-.4-.5-.1v.9M47.8 67.3l.5-.1v-.4h-.5v.9M47.8 75.9l.5-.1v-.3l-.5-.1v.8M47.9 60.7v.9"/>
<path d="M48 61.2l.4 .4M48.2 64.2v-.8l.3 .6 .3-.6v.8M48.4 60.7l-.5 .6M48.5 69.5h.6M48.5 66h.6M48.5 67.8h.6M48.5 76.3h.6M48.7 60.7v.9M49.2 65.9l.3-.8 .2 .8M49.2 69.4l.3-.9 .2 .9M49.2 67.7l.3-.9 .2 .9M49.2 76.2l.3-.8 .2 .8"/>
<path d="M49.3 69.1h.4M49.3 65.7h.4M49.3 67.4h.4M49.3 76h.4M49.4 63.3l-.3 .7h.6M49.6 63.6v.6M49.7 60.7v.9l-.6-.9v.9M50 65.1h.6l-.4 .8M50 75.6l.2-.2v.8M50 76.2h.5M50.4 66.8h-.2l-.2 .7 .2 .2 .3-.1v-.4l-.3-.1-.2 .2M50.5 68.5h-.4l-.1 .5 .4-.1 .1 .4h-.5"/>
<path d="M59.6 69h.3M59.6 65.5h.3M59.6 70.7h.3M59.6 67.2h.3M59.6 72.3h.3M59.6 74.1h.3M59.6 75.8h.3M60.1 72h-.5v.9h.5M60.1 73.7h-.5v.8h.5M60.1 75.4h-.5v.8h.5M60.1 68.5h-.5v.9h.5M60.1 66.8h-.5v.9h.5"/>
<path d="M60.1 65.1h-.5v.8h.5M60.1 70.2h-.5v.9h.5M60.3 72l.6 .9M60.3 73.7l.6 .8M60.3 75.4l.6 .8M60.3 68.5l.6 .9M60.3 66.8l.6 .9M60.3 65.1l.6 .8M60.3 70.2l.6 .9M60.9 72l-.6 .9M60.9 73.7l-.6 .8M60.9 75.4l-.6 .8"/>
<path d="M60.9 68.5l-.6 .9M60.9 66.8l-.6 .9M60.9 65.1l-.6 .8M60.9 70.2l-.6 .9M61.3 72.4h.3l.2-.3-.5-.1v.9M61.3 74.1h.4v-.4h-.4v.8M61.3 75.9h.3l.2-.2-.2-.3h-.3v.8M61.3 69h.4v-.5h-.4v.9M61.3 67.3h.3l.2-.4-.5-.1v.9M61.3 65.5h.4l.1-.3-.2-.1h-.3v.8M61.3 70.7h.3l.2-.1-.2-.4h-.3v.9M61.9 69.5h.6"/>
<path d="M61.9 66h.6M61.9 71.2h.6M61.9 67.8h.6M61.9 72.9h.6M61.9 74.6h.6M61.9 76.3h.6M62.6 72.9l.3-.9 .3 .9M62.6 74.5l.3-.8 .3 .8M62.6 76.2l.3-.8 .3 .8M62.6 69.4l.3-.9 .3 .9M62.6 67.7l.3-.9 .3 .9M62.6 65.9l.3-.8 .3 .8"/>
<path d="M62.6 71.1l.3-.9 .3 .9M62.7 69.1h.4M62.7 65.7h.4M62.7 70.8h.4M62.7 67.4h.4M62.7 72.6h.4M62.7 74.3h.4M62.7 76h.4M63.5 72.2l.2-.2v.9M63.5 68.8l.2-.3v.9M63.5 67l.2-.2v.9M63.5 65.3l.2-.2v.8"/>
<path d="M63.5 70.5l.2-.3v.9M63.5 71.1h.5M63.5 72.9h.5M63.5 69.4h.5M63.5 67.7h.5M63.5 65.9h.5M63.6 75.8l-.1-.1v-.2l.3-.1 .2 .2-.5 .2v.4h.4l.1-.2-.2-.2M64 74l-.1 .2h-.4v-.4l.4-.1 .1 .2-.2 .6h-.3M64.2 66.8h.5l-.2 .3 .2 .1v.4h-.5M64.3 72.1h.4v.6l-.1 .2-.3-.2zM64.3 68.6l.3-.1 .1 .4-.5 .5h.5M64.3 70.5l.3-.3v.9"/>
<path d="M64.3 71.1h.4M64.5 65.1l-.2 .6h.5M64.6 65.4v.5M152.2 69h.2M152.2 65.5h.2M152.2 70.7h.2M152.2 67.2h.2M152.2 72.3h.2M152.2 74.1h.2M152.2 75.8h.2M152.5 68.5h-.3v.9h.3M152.5 65.1h-.3v.8h.3"/>
<path d="M152.5 70.2h-.3v.9h.3M152.5 66.8h-.3v.9h.3M152.5 75.4h-.3v.8h.3M152.5 73.7h-.3v.8h.3M152.5 72h-.3v.9h.3M152.9 68.5l.6 .9M152.9 65.1l.6 .8M152.9 70.2l.6 .9M152.9 66.8l.6 .9M152.9 75.4l.6 .8M152.9 73.7l.6 .8M152.9 72l.6 .9"/>
<path d="M153.5 68.5l-.6 .9M153.5 65.1l-.6 .8M153.5 70.2l-.6 .9M153.5 66.8l-.6 .9M153.5 75.4l-.6 .8M153.5 73.7l-.6 .8M153.5 72l-.6 .9M153.7 69h.4l.1-.4-.5-.1v.9M153.7 65.5h.5v-.4h-.5v.8M153.7 70.7h.5v-.4l-.5-.1v.9M153.7 67.3l.5-.1v-.4h-.5v.9M153.7 75.9l.5-.1v-.3l-.5-.1v.8"/>
<path d="M153.7 74.1h.4l.1-.3-.5-.1v.8M153.7 72.4l.5-.1v-.2l-.5-.1v.9M154.4 69.5h.7M154.4 66h.7M154.4 71.2h.7M154.4 67.8h.7M154.4 72.9h.7M154.4 74.6h.7M154.4 76.3h.7M155.1 69.4l.3-.9 .3 .9M155.1 65.9l.3-.8 .3 .8M155.1 71.1l.3-.9 .3 .9"/>
<path d="M155.1 67.7l.3-.9 .3 .9M155.1 76.2l.3-.8 .3 .8M155.1 74.5l.3-.8 .3 .8M155.1 72.9l.3-.9 .3 .9M155.2 69.1h.5M155.2 65.7h.5M155.2 70.8h.5M155.2 67.4h.5M155.2 72.6h.5M155.2 74.3h.5M155.2 76h.5M155.9 65.1h.6l-.3 .8"/>
<path d="M155.9 72h.5l-.2 .3h.2v.5h-.5M156 75.6l.2-.2v.8M156 73.8l.3-.1 .1 .3-.5 .5h.5M156 76.2h.4M156.2 70.2l-.2 .6h.5M156.3 66.8h-.2l-.1 .2v.6h.4v-.4l-.2-.1-.2 .2M156.3 70.6v.5M156.4 68.5h-.4v.5h.4l-.1 .4-.3-.1M165.6 69h.3M165.6 65.5h.3M165.6 70.7h.3M165.6 67.2h.3"/>
<path d="M165.6 72.3h.3M165.6 74.1h.3M165.6 75.8h.3M165.6 63.8h.3M166 70.2h-.4v.9h.4M166 72h-.4v.9h.4M166 73.7h-.4v.8h.4M166 75.4h-.4v.8h.4M166 63.4h-.4v.8h.4M166 68.5h-.4v.9h.4M166 66.8h-.4v.9h.4M166 65.1h-.4v.8h.4"/>
<path d="M166.2 70.2l.6 .9M166.2 72l.6 .9M166.2 73.7l.6 .8M166.2 75.4l.6 .8M166.2 63.4l.6 .8M166.2 68.5l.6 .9M166.2 66.8l.6 .9M166.2 65.1l.6 .8M166.8 70.2l-.6 .9M166.8 72l-.6 .9M166.8 73.7l-.6 .8M166.8 75.4l-.6 .8"/>
<path d="M166.8 63.4l-.6 .8M166.8 68.5l-.6 .9M166.8 66.8l-.6 .9M166.8 65.1l-.6 .8M167.2 70.7h.3l.2-.1-.2-.4h-.3v.9M167.2 72.4h.3l.2-.3-.5-.1v.9M167.2 74.1h.4v-.4h-.4v.8M167.2 75.9h.3l.2-.2-.2-.3h-.3v.8M167.2 63.8h.4v-.4h-.4v.8M167.2 69h.4v-.5h-.4v.9M167.2 67.3h.3l.2-.4-.5-.1v.9M167.2 65.5h.4l.1-.3-.2-.1h-.3v.8"/>
<path d="M167.8 69.5h.7M167.8 66h.7M167.8 71.2h.7M167.8 67.8h.7M167.8 72.9h.7M167.8 74.6h.7M167.8 76.3h.7M167.8 64.3h.7M168.5 71.1l.4-.9 .2 .9M168.5 72.9l.4-.9 .2 .9M168.5 74.5l.4-.8 .2 .8M168.5 76.2l.4-.8 .2 .8"/>
<path d="M168.5 64.2l.4-.8 .2 .8M168.5 69.4l.4-.9 .2 .9M168.5 67.7l.4-.9 .2 .9M168.5 65.9l.4-.8 .2 .8M168.6 69.1h.4M168.6 65.7h.4M168.6 70.8h.4M168.6 67.4h.4M168.6 72.6h.4M168.6 74.3h.4M168.6 76h.4M168.6 64h.4"/>
<path d="M169.4 70.5l.2-.3v.9M169.4 72.2l.2-.2v.9M169.4 63.6l.2-.2v.8M169.4 68.8l.2-.3v.9M169.4 67l.2-.2v.9M169.4 65.3l.2-.2v.8M169.4 71.1h.5M169.4 72.9h.5M169.4 64.2h.5M169.4 69.4h.5M169.4 67.7h.5M169.4 65.9h.5"/>
<path d="M169.5 75.8l-.1-.2 .3-.2 .2 .2-.4 .2-.1 .3 .1 .1h.3l.1-.2-.2-.2M169.9 74l-.1 .2h-.3v-.5h.3l.1 .2-.1 .6h-.3M170.1 66.8h.6l-.3 .3 .3 .2v.2l-.1 .2-.5-.1M170.2 70.5l.3-.3v.9M170.2 72.1l.2-.1a.43 .43 0 0 1 .3 .4 .43 .43 0 0 1-.3 .5l-.2-.2zM170.2 68.6l.4-.1 .1 .3-.6 .6h.6M170.2 71.1h.5M170.4 65.1l-.2 .6h.5M170.6 63.4h-.4v.4l.4-.1 .1 .2-.1 .3-.4-.1M170.6 65.4v.5M56.3 94.4l.3 .8 .3-.8M56.3 94.1h4.6"/>
<path d="M57.2 95.2v-.8l.2 .6 .3-.6v.8M58.1 94.8h.4M58.5 94.4h-.4v.8h.4M59.4 94.4h-.5v.3l.5 .3-.1 .2h-.4M59.7 94.8h.4M60.2 94.4h-.5v.8h.5M60.5 94.4v.8h.4M71.6 92.4h4.5M71.7 93.1h.3M72.1 92.7h-.4v.8h.4M72.4 92.7l.5 .8M72.9 92.7l-.5 .8"/>
<path d="M73.3 93.1h.4l.1-.4h-.5v.8M74 93.6h.6M74.7 93.5l.3-.8 .2 .8M74.8 93.3h.3M76 92.7h-.4l-.1 .1 .1 .3 .4 .1v.2h-.5M150.1 95.6h.2M150.1 93.9h.2M150.1 97.3h.2M150.1 99.1h.2M150.1 92.2h.2M150.5 93.5h-.4v.9h.4M150.5 91.8h-.4v.9h.4"/>
<path d="M150.5 97h-.4v.8h.4M150.5 98.7h-.4v.8h.4M150.5 95.2h-.4v.9h.4M150.7 93.5l.6 .9M150.7 91.8l.6 .9M150.7 97l.6 .8M150.7 98.7l.6 .8M150.7 95.2l.6 .9M151.3 93.5l-.6 .9M151.3 91.8l-.6 .9M151.3 97l-.6 .8M151.3 98.7l-.6 .8"/>
<path d="M151.3 95.2l-.6 .9M151.7 93.9h.4v-.4h-.4v.9M151.7 92.2h.3l.2-.3-.5-.1v.9M151.7 97.4h.3l.2-.3-.5-.1v.8M151.7 99.1h.4v-.4h-.4v.8M151.7 95.7h.3l.2-.3-.2-.2h-.3v.9M152.4 96.1h.5M152.4 94.4h.5M152.4 97.9h.5M152.4 99.6h.5M152.4 92.7h.5M153 94.4l.4-.9 .2 .9"/>
<path d="M153 92.7l.4-.9 .2 .9M153 97.8l.4-.8 .2 .8M153 99.5l.4-.8 .2 .8M153 96.1l.4-.9 .2 .9M153.1 95.8h.4M153.1 94.1h.4M153.1 97.6h.4M153.1 99.3h.4M153.1 92.4h.4M153.9 93.8l.2-.3v.9M153.9 92l.2-.2v.9M153.9 97.2l.2-.2v.8"/>
<path d="M153.9 98.9l.2-.2v.8M153.9 95.5l.2-.3v.9M153.9 97.8h.5M153.9 94.4h.5M153.9 92.7h.5M153.9 99.5h.5M153.9 96.1h.5M154.6 97h.6l-.3 .2 .3 .2v.3l-.1 .1-.5-.1M154.7 98.8l.4-.1 .1 .2-.6 .6h.6M154.9 95.2l-.2 .6h.5M155.1 93.5h-.4v.4l.4-.1 .1 .2-.1 .4-.4-.1M155.1 91.8h-.3l-.1 .2v.6l.4 .1 .1-.5-.1-.1-.4 .1"/>
<path d="M155.1 95.5v.6M182.8 95.6h.3M182.8 93.9h.3M182.8 97.3h.3M182.8 99.1h.3M182.8 92.2h.3M183.2 95.2h-.4v.9h.4M183.2 93.5h-.4v.9h.4M183.2 97h-.4v.8h.4M183.2 98.7h-.4v.8h.4M183.2 91.8h-.4v.9h.4M183.5 95.2l.6 .9"/>
<path d="M183.5 93.5l.6 .9M183.5 97l.6 .8M183.5 98.7l.6 .8M183.5 91.8l.6 .9M184.1 95.2l-.6 .9M184.1 93.5l-.6 .9M184.1 97l-.6 .8M184.1 98.7l-.6 .8M184.1 91.8l-.6 .9M184.4 95.7l.5-.1v-.3l-.5-.1v.9M184.4 93.9h.4l.1-.3-.5-.1v.9M184.4 97.4l.5-.1v-.2l-.5-.1v.8"/>
<path d="M184.4 99.1h.4l.1-.3-.5-.1v.8M184.4 92.2h.5v-.4h-.5v.9M185 96.1h.7M185 94.4h.7M185 97.9h.7M185 99.6h.7M185 92.7h.7M185.8 96.1l.3-.9 .3 .9M185.8 94.4l.3-.9 .3 .9M185.8 97.8l.3-.8 .3 .8M185.8 99.5l.3-.8 .3 .8M185.9 92.2h.5v-.4h-.5v.9"/>
<path d="M185.9 95.8h.4M185.9 94.1h.4M185.9 97.6h.4M185.9 99.3h.4M186.1 92.2l.3 .5M186.6 95.3h.5v.3l-.5 .5h.5M186.6 93.6l.4-.1 .1 .3-.5 .6h.5M186.6 97.1l.4-.1 .1 .3-.5 .5h.5M186.6 98.8l.4-.1 .1 .3-.5 .5h.5M186.8 92.2h.4v.5M186.8 92.1v.6M187.4 95.3h.5v.3l-.5 .5h.5"/>
<path d="M187.4 93.5h.5l-.2 .3 .2 .1v.4h-.5M187.4 97.2l.3-.2v.8M187.4 97.8h.5M187.5 98.8l.3-.1 .1 .1-.1 .6a.39 .39 0 0 1-.4-.2 .39 .39 0 0 1 .1-.4zM187.5 91.8l.2 .9 .1-.7 .2 .7 .3-.9M150.1 102.5h.2M150.1 100.8h.2M150.1 104.3h.2M150.5 103.8h-.4v.9h.4M150.5 100.4h-.4v.8h.4M150.5 102.1h-.4v.9h.4M150.7 103.8l.6 .9"/>
<path d="M150.7 100.4l.6 .8M150.7 102.1l.6 .9M151.3 103.8l-.6 .9M151.3 100.4l-.6 .8M151.3 102.1l-.6 .9M151.7 104.3h.4v-.5h-.4v.9M151.7 100.9h.3l.2-.4-.2-.1h-.3v.8M151.7 102.6h.3l.2-.2-.1-.3h-.4v.9M152.4 103.1h.5M152.4 101.3h.5M152.4 104.8h.5M153 104.7l.4-.9 .2 .9"/>
<path d="M153 101.2l.4-.8 .2 .8M153 103l.4-.9 .2 .9M153.1 102.7h.4M153.1 101h.4M153.1 104.4h.4M153.9 100.6l.2-.2v.8M153.9 102.3l.2-.2v.9M153.9 103h.5M153.9 101.2h.5M154.4 104.2l-.1 .1h-.3v-.5h.3l.1 .2-.2 .7h-.2M154.7 100.6l.3-.2v.8M154.7 101.2h.5"/>
<path d="M154.8 102.1a.42 .42 0 0 1 .4 .3 .42 .42 0 0 1-.1 .5l-.2 .1-.2-.2zM159.6 109.9l.4 .8 .2-.8M159.6 109.6h4.7M160.5 110.7v-.8l.3 .5 .3-.5v.8M161.5 110.3h.3M161.9 109.9h-.4v.8h.4M162.8 109.9h-.5v.3l.5 .2-.1 .3h-.4M163.1 110.3h.3M163.5 109.9h-.4v.8h.4M163.9 109.9v.8h.4M182.8 102.5h.3M182.8 100.8h.3"/>
<path d="M182.8 104.3h.3M183.2 102.1h-.4v.9h.4M183.2 100.4h-.4v.8h.4M183.2 103.8h-.4v.9h.4M183.5 102.1l.6 .9M183.5 100.4l.6 .8M183.5 103.8l.6 .9M184.1 102.1l-.6 .9M184.1 100.4l-.6 .8M184.1 103.8l-.6 .9M184.4 102.6l.5-.1v-.3l-.5-.1v.9M184.4 100.9l.5-.1v-.3l-.5-.1v.8"/>
<path d="M184.4 104.3h.4l.1-.4-.5-.1v.9M185 103.1h.7M185 101.3h.7M185 104.8h.7M185.8 103l.3-.9 .3 .9M185.8 101.2l.3-.8 .3 .8M185.8 104.7l.3-.9 .3 .9M185.9 102.7h.4M185.9 101h.4M185.9 104.4h.4M186.6 102.3l.3-.2v.9M186.6 100.6l.3-.2v.8"/>
<path d="M186.6 104.1l.3-.3v.9M186.6 103h.5M186.6 101.2h.5M186.6 104.7h.5M187.4 103.8h.6l-.4 .9M187.6 102.5l-.2-.2 .1-.2 .4 .1v.2l-.4 .1-.1 .2 .2 .3 .3-.1v-.3l-.2-.1M187.9 100.8l-.2 .2-.3-.2 .2-.4 .3 .1v.5l-.4 .2"/>
</g>
<g fill="none" stroke="#006665" stroke-width=".21">
<path d="M105.1 93.3l.3-.8 .3 .8M105.1 95.1l.3-.8 .3 .8M105.1 96.8l.3-.8 .3 .8M105.1 98.5l.3-.8 .3 .8M105.2 93.2h.4M105.2 94.9h.4M105.2 96.6h.4M105.2 98.3h.4M105.9 94.5l.2-.2v.8M105.9 96.1h.5v.2l-.5 .5h.5M105.9 97.7h.5l-.3 .3 .3 .1v.4h-.5M105.9 95.1h.5"/>
<path d="M106 92.6l.2-.1 .2 .2-.1 .6h-.3l-.1-.2zM106.1 99.4l-.2 .5h.6M106.3 99.7v.6M108.8 93.9l.9 .3-.9 .3M108.9 93.2l-.1 .2 .3 .3h.4l.2-.2-.1-.3M108.9 92.3a.43 .43 0 0 0 .3 .5 .43 .43 0 0 0 .5-.1l-.1-.4M112.1 92.9h.4l.1-.3-.5-.1v.8h.5v-.2l-.2-.2M112.1 94.6h.4l.1-.2-.5-.1v.8h.4l.1-.3-.2-.2M112.1 96.4l.5-.1-.1-.3h-.4v.8h.5v-.2l-.2-.2M112.1 98.1h.4l.1-.4h-.5v.8h.5v-.2l-.2-.2M112.1 99.8h.5v-.3l-.5-.1v.9h.4l.1-.4-.2-.1M112.9 97.7h.6l-.3 .3 .3 .2v.2l-.6 .1"/>
<path d="M113 94.5l.2-.2v.8M113 96.1l.4-.1 .1 .2-.6 .6h.6M113 95.1h.5M113.2 92.5a.43 .43 0 0 1 .3 .5 .43 .43 0 0 1-.4 .3l-.1-.6zM113.2 99.4l-.2 .5h.5M113.4 99.7v.6M136.9 93.3l.4-.8 .2 .8M136.9 95.1l.4-.8 .2 .8M136.9 96.8l.4-.8 .2 .8M136.9 98.5l.4-.8 .2 .8M137 93.2h.5M137 94.9h.5"/>
<path d="M137 96.6h.5M137 98.3h.5M137.7 97.7h.6l-.3 .3 .3 .2v.2l-.6 .1M137.8 94.5l.2-.2v.8M137.8 96.1l.4-.1 .1 .2-.6 .6h.6M137.8 95.1h.5M138 92.5a.43 .43 0 0 1 .3 .5 .43 .43 0 0 1-.4 .3l-.1-.6zM138 99.4l-.2 .5h.5M138.2 99.7v.6M140.8 93.9l.8 .3-.8 .3M140.8 93.2v.3l.1 .2h.4l.3-.3-.1-.2M140.8 92.3v.4a.43 .43 0 0 0 .5 .1 .43 .43 0 0 0 .2-.5"/>
<path d="M144 92.9h.4l.1-.2-.2-.2h-.3v.8h.4l.1-.3-.2-.1M144 94.6h.4v-.3h-.4v.8l.5-.1v-.3l-.2-.1M144 96.4h.3l.2-.2-.1-.2h-.4v.8l.5-.1v-.2l-.2-.1M144 98.1h.4l.1-.3-.2-.1h-.3v.8h.5v-.3l-.2-.1M144 99.8h.4v-.4h-.4v.9l.5-.1v-.3l-.2-.1M144.8 94.5l.3-.2v.8M144.8 96.1h.5v.2l-.5 .5h.5M144.8 97.7h.5l-.2 .3 .2 .1v.4h-.5M144.8 95.1h.5M144.9 92.6l.3-.1 .1 .2-.1 .6h-.2l-.2-.2zM145.1 99.4l-.3 .5h.5M145.2 99.7v.6"/>
<path d="M169.7 93.3l.3-.8 .2 .8M169.7 95.1l.3-.8 .2 .8M169.7 96.8l.3-.8 .2 .8M169.7 98.5l.3-.8 .2 .8M169.8 93.2h.4M169.8 94.9h.4M169.8 96.6h.4M169.8 98.3h.4M170.5 94.5l.2-.2v.8M170.5 96.1h.5v.2l-.5 .5h.5M170.5 97.7h.5l-.3 .3 .3 .1v.4h-.5M170.5 95.1h.5"/>
<path d="M170.6 92.6l.2-.1 .2 .2-.1 .6h-.3l-.1-.2zM170.7 99.4l-.2 .5h.6M170.9 99.7v.6M173.4 93.9l.9 .3-.9 .3M173.5 93.2l-.1 .2 .3 .3h.4l.2-.2-.1-.3M173.5 92.3a.43 .43 0 0 0 .3 .5 .43 .43 0 0 0 .5-.1l-.1-.4M176.7 92.9h.4l.1-.3-.5-.1v.8h.5v-.2l-.2-.2M176.7 94.6h.4l.1-.2-.5-.1v.8h.4l.1-.3-.2-.2M176.7 96.4l.5-.1-.1-.3h-.4v.8h.5v-.2l-.2-.2M176.7 98.1h.4l.1-.4h-.5v.8h.5v-.2l-.2-.2M176.7 99.8h.5v-.3l-.5-.1v.9h.4l.1-.4-.2-.1M177.5 97.7h.6l-.3 .3 .3 .2v.2l-.6 .1"/>
<path d="M177.6 94.5l.2-.2v.8M177.6 96.1l.4-.1 .1 .2-.6 .6h.6M177.6 95.1h.5M177.8 92.5a.43 .43 0 0 1 .3 .5 .43 .43 0 0 1-.4 .3l-.1-.6zM177.8 99.4l-.2 .5h.5M178 99.7v.6M105.1 100.3l.3-.9 .3 .9M105.1 102l.3-.9 .3 .9M105.1 103.8l.3-1 .3 1M105.1 105.4l.3-.8 .3 .8M105.1 108.9l.3-.9 .3 .9M105.2 100h.4"/>
<path d="M105.2 101.7h.4M105.2 103.5h.4M105.2 105.2h.4M105.2 108.7h.4M105.7 109.9l-.3-.1-.2 .1v.5l.2 .2 .3-.1M105.9 104.6h.6l-.5 .8M106 108.6h.6M106 110.2h.4M106.3 102.8l-.3 .1-.1 .7 .1 .2 .4-.1v-.5h-.4l-.1 .1M106.4 101.1h-.4l-.1 .5 .4-.1 .1 .4h-.5M106.5 109.8h-.5v.8h.5M107.1 108.3l.6 .3-.6 .2"/>
<path d="M108.1 108.4h.3l.1-.3-.4-.1v.9h.3l.2-.1-.2-.4M108.8 109.5h.9l-.9 .5h.9M108.9 110.4l-.1 .2 .2 .3h.6l.1-.5h-.4v.1M108.9 108.8l.3-.2 .4 .1 .1 .4h-.9zM112.1 101.6l.5-.1-.1-.4h-.4v.9h.5v-.3l-.2-.1M112.1 103.2h.4l.1-.3-.5-.1v1h.4l.1-.4-.2-.2M112.1 105l.5-.1-.1-.3h-.4v.8h.4l.1-.1v-.2l-.2-.1M112.9 104.6h.6l-.3 .8M113.4 101.1h-.4v.5l.4-.1v.5l-.4-.1M113.4 102.8l-.3 .1-.1 .8 .3 .1 .2-.2-.2-.4-.3 .1M136.9 100.3l.4-.9 .2 .9M136.9 102l.4-.9 .2 .9"/>
<path d="M136.9 103.8l.4-1 .2 1M136.9 105.4l.4-.8 .2 .8M136.9 108.9l.4-.9 .2 .9M137 100h.5M137 101.7h.5M137 103.5h.5M137 105.2h.5M137 108.7h.5M137.5 109.9l-.3-.1a.42 .42 0 0 0-.2 .5 .42 .42 0 0 0 .5 .2M137.7 104.6h.6l-.3 .8M137.8 108.6h.7M138 110.2h.2"/>
<path d="M138.2 101.1h-.4v.5l.4-.1v.5l-.4-.1M138.2 102.8l-.4 .3v.6l.3 .1 .2-.2-.2-.4-.3 .1M138.4 109.8h-.4v.8h.4M138.9 108.3l.7 .3-.7 .2M140 108.4h.3l.1-.2-.4-.2v.9l.4-.1v-.3l-.2-.1M140.8 110.4v.5h.6l.2-.3-.1-.2h-.3v.1M140.8 109.5h.8l-.8 .5h.8M140.8 108.8a.48 .48 0 0 1 .5-.2 .48 .48 0 0 1 .3 .5h-.8zM144 101.6h.3l.2-.2-.1-.3h-.4v.9l.5-.1v-.3h-.2M144 103.2h.4l.1-.2-.2-.2h-.3v1l.5-.1v-.4l-.2-.1M144 105h.3l.2-.1-.1-.3h-.4v.8h.5v-.4h-.2M144.8 104.6h.5l-.3 .8"/>
<path d="M145.2 102.8l-.2 .1-.2 .7 .2 .2 .3-.1v-.5h-.3l-.2 .1M145.3 101.1h-.4l-.1 .5 .4-.1 .1 .4h-.5M169.7 100.3l.3-.9 .2 .9M169.7 102l.3-.9 .2 .9M169.7 103.8l.3-1 .2 1M169.7 105.4l.3-.8 .2 .8M169.7 108.9l.3-.9 .2 .9M169.8 100h.4M169.8 101.7h.4M169.8 103.5h.4M169.8 105.2h.4M169.8 108.7h.4"/>
<path d="M170.3 109.9l-.3-.1-.2 .1v.5l.2 .2 .3-.1M170.5 104.6h.6l-.5 .8M170.6 108.6h.6M170.6 110.2h.4M170.9 102.8l-.3 .1-.1 .7 .1 .2 .4-.1v-.5h-.4l-.1 .1M171 101.1h-.4l-.1 .5 .4-.1 .1 .4h-.5M171.1 109.8h-.5v.8h.5M171.6 108.3l.7 .3-.7 .2M172.7 108.4h.3l.1-.3-.4-.1v.9h.3l.2-.3-.3-.2M173.4 109.5h.9l-.9 .5h.9M173.5 110.4l-.1 .2 .2 .3 .7-.1-.1-.4h-.3v.1M173.5 108.8l.3-.2 .4 .1 .1 .4h-.9z"/>
<path d="M176.7 101.6l.5-.1-.1-.4h-.4v.9h.5v-.3l-.2-.1M176.7 103.2h.4l.1-.3-.5-.1v1h.4l.1-.4-.2-.2M176.7 105l.5-.1-.1-.3h-.4v.8h.4l.1-.1v-.2l-.2-.1M177.5 104.6h.6l-.3 .8M178 101.1h-.4v.5l.4-.1 .1 .1-.1 .4-.4-.1M178 102.8l-.3 .1-.1 .8 .3 .1 .2-.2-.2-.4-.3 .1"/>
</g>
<path d="M43.9 78.4l.8-.6v.6h.9h-.9v.5z" fill="#910000"/>
<g fill="none" stroke="#910000" stroke-width=".21">
<path d="M50.8 26.6h2.5M50.8 28.4h2.5M50.8 30.1h2.5M50.8 31.9h2.5M50.8 33.6h2.5M50.8 35.3h2.5M50.8 37h2.5M50.8 38.7h2.5M53.3 25.7h3.4v55.2h-3.4zM53.3 26.5h.9v.3h-.9zM53.3 28.3h.9v.2h-.9zM53.3 30h.9v.2h-.9z"/>
<path d="M53.3 31.8h.9v.2h-.9zM53.3 33.5h.9v.2h-.9zM53.3 35.2h.9v.1h-.9zM53.3 37h.9v.1h-.9zM53.3 38.6h.9v.2h-.9zM55.9 26.5h.9v.3h-.9zM55.9 28.3h.9v.2h-.9zM55.9 30h.9v.2h-.9zM55.9 31.8h.9v.2h-.9zM55.9 33.5h.9v.2h-.9zM55.9 35.2h.9v.1h-.9zM55.9 37h.9v.1h-.9z"/>
<path d="M55.9 38.6h.9v.2h-.9zM56.8 26.6h2.6M56.8 28.4h2.6M56.8 30.1h2.6M56.8 31.9h2.6M56.8 33.6h2.6M56.8 35.3h2.6M56.8 37h2.6M56.8 38.7h2.6M63.7 39.6h.9v-.9l.8 .9-.8 .8v-.8M63.7 39.6h.1M71.4 26.6h1.7"/>
<path d="M71.4 28.4h1.7M71.4 30.1h1.7M71.4 31.9h1.7M71.4 33.6h1.7M71.4 35.3h1.7M71.4 37h1.7M71.4 38.7h1.7M50.8 45.6h2.5M50.8 43.9h2.5M50.8 40.4h2.5M50.8 42.2h2.5M50.8 47.4h2.5"/>
<path d="M50.8 49.1h2.5M50.8 50.8h2.5M50.8 52.5h2.5M50.8 54.2h2.5M50.8 55.9h2.5M50.8 57.7h2.5M50.8 59.4h2.5M53.3 40.3h.9v.2h-.9zM53.3 42.1h.9v.2h-.9zM53.3 43.8h.9v.2h-.9zM53.3 45.5h.9v.2h-.9zM53.3 47.3h.9v.2h-.9z"/>
<path d="M53.3 49h.9v.1h-.9zM53.3 50.7h.9v.1h-.9zM53.3 52.4h.9v.2h-.9zM53.3 54.1h.9v.2h-.9zM53.3 55.8h.9v.2h-.9zM53.3 57.6h.9v.2h-.9zM53.3 59.3h.9v.2h-.9zM55.9 40.3h.9v.2h-.9zM55.9 42.1h.9v.2h-.9zM55.9 43.8h.9v.2h-.9zM55.9 45.5h.9v.2h-.9zM55.9 47.3h.9v.2h-.9z"/>
<path d="M55.9 49h.9v.1h-.9zM55.9 50.7h.9v.1h-.9zM55.9 52.4h.9v.2h-.9zM55.9 54.1h.9v.2h-.9zM55.9 55.8h.9v.2h-.9zM55.9 57.6h.9v.2h-.9zM55.9 59.3h.9v.2h-.9zM56.8 45.6h2.6M56.8 43.9h2.6M56.8 40.4h2.6M56.8 42.2h2.6M56.8 47.4h2.6"/>
<path d="M56.8 49.1h2.6M56.8 50.8h2.6M56.8 52.5h2.6M56.8 54.2h2.6M56.8 55.9h2.6M56.8 57.7h2.6M56.8 59.4h2.6M59.4 43h7.4l.7 .9-.7 .8h-7.4zM59.8 43.2h6.4M60 43.9h.2M60.2 44.7h4.7v1.7h-4.7l-.8-.8zM60.4 43.5h-.4v.8h.4"/>
<path d="M60.5 45h3.7M60.6 45.7l.5-.1v-.3l-.5-.1v.9M60.7 43.5l.6 .8M60.8 45.7l.3 .4M61.3 43.5l-.6 .8M61.4 45.6h.4M61.6 43.9h.4v-.3l-.4-.1v.8M61.8 45.2h-.4v.9h.4M62.2 44.4h.7M62.7 45.3l-.3-.1-.2 .1 .1 .3 .4 .2v.2h-.5M63 45.6h.4M63.1 43.9h.4v-.3l-.1-.1h-.3v.8h.4v-.3l-.1-.1"/>
<path d="M63.5 45.2h-.5v.9h.5M63.7 45.2h.5M64 45.2v.9M64 43.9h.2M64.4 43.5h-.4v.8h.4M64.7 43.9h.4l.1-.3-.1-.1h-.4v.8M64.9 43.9l.3 .4M65.6 43.9h.4l.1-.3-.2-.1h-.3v.8M65.7 43.9l.4 .4M71.4 45.6h1.7M71.4 43.9h1.7M71.4 40.4h1.7"/>
<path d="M71.4 42.2h1.7M71.4 47.4h1.7M71.4 49.1h1.7M71.4 50.8h1.7M71.4 52.5h1.7M71.4 54.2h1.7M71.4 55.9h1.7M71.4 57.7h1.7M71.4 59.4h1.7M78.3 59.4h.9v-.9l.8 .9-.8 .8v-.8M78.3 59.4h.1M44.7 78.4v.5l-.8-.5 .8-.6v.6h.9"/>
<path d="M44.7 79.5l-.8 .5M45.6 78.4h.1M50.8 78.4h2.5M50.8 61.1h2.5M50.8 62.9h2.5M50.8 64.6h2.5M50.8 66.2h2.5M50.8 68h2.5M50.8 69.7h2.5M50.8 71.4h2.5M50.8 73.2h2.5M50.8 74.9h2.5"/>
<path d="M50.8 76.7h2.5M53.3 61h.9v.2h-.9zM53.3 62.8h.9v.1h-.9zM53.3 64.5h.9v.1h-.9zM53.3 66.2h.9v.1h-.9zM53.3 67.9h.9v.2h-.9zM53.3 69.6h.9v.2h-.9zM53.3 71.3h.9v.2h-.9zM53.3 73.1h.9v.2h-.9zM53.3 74.8h.9v.2h-.9zM53.3 76.5h.9v.2h-.9zM53.3 78.3h.9v.1h-.9z"/>
<path d="M53.3 80h.9v.1h-.9zM55.9 61h.9v.2h-.9zM55.9 62.8h.9v.1h-.9zM55.9 64.5h.9v.1h-.9zM55.9 66.2h.9v.1h-.9zM55.9 67.9h.9v.2h-.9zM55.9 69.6h.9v.2h-.9zM55.9 71.3h.9v.2h-.9zM55.9 73.1h.9v.2h-.9zM55.9 74.8h.9v.2h-.9zM55.9 76.5h.9v.2h-.9zM55.9 78.3h.9v.1h-.9z"/>
<path d="M55.9 80h.9v.1h-.9zM56.8 78.4h2.6M56.8 61.1h2.6M56.8 62.9h2.6M56.8 64.6h2.6M56.8 66.2h2.6M56.8 68h2.6M56.8 69.7h2.6M56.8 71.4h2.6M56.8 73.2h2.6M56.8 74.9h2.6M56.8 76.7h2.6"/>
<path d="M64.6 78.4h.1M64.6 78.4h1.6M65.4 77.8l.8 .6M65.4 79.5l.8 .5M66.2 78.4l-.8 .5M71.4 78.4h1.7M71.4 61.1h1.7M71.4 62.9h1.7M71.4 64.6h1.7M71.4 66.2h1.7M71.4 68h1.7M71.4 69.7h1.7"/>
<path d="M71.4 71.4h1.7M71.4 73.2h1.7M71.4 74.9h1.7M71.4 76.7h1.7M73.9 60.2h3.3v1.8h-3.3l-.8-.9zM73.9 62h3.4l.6 .9-.6 .8h-3.4l-.8-.8zM74 72.3h3.9l.8 .9-.8 .8h-3.9zM74 68.9h3.9l.8 .8-.8 .9h-3.9zM74.5 72.5h2.8M74.5 69.1h2.8M74.6 69.3v.8M74.6 72.8v.8"/>
<path d="M74.8 60.7l-.4 .1v.2l.4 .3v.2h-.4M74.8 62.4l-.4 .1v.3l.4 .1v.3l-.4 .1M75 73.2h.4l.1-.3-.5-.1v.8M75 69.8l.5-.1v-.3l-.5-.1v.8M75.2 62.4l.4 .1 .1 .4-.1 .4h-.4zM75.2 73.2l.3 .4M75.2 69.8l.3 .3M75.7 60.8l-.4-.1a.44 .44 0 0 0-.1 .6 .44 .44 0 0 0 .5 .2M75.9 63.3l.3-.9 .3 .9M75.9 72.9l.3-.1 .2 .2-.2 .6h-.2l-.2-.2zM75.9 69.5l.2-.2a.43 .43 0 0 1 .3 .5 .43 .43 0 0 1-.4 .3l-.2-.2zM76 73.4l.4 .3"/>
<path d="M76 70l.4 .2M76 63h.4M76.1 60.7v.9h.4M76.7 72.8h.6l-.4 .3h.3v.5l-.5-.1M77.2 69.3h-.5v.4l.4-.1 .2 .5h-.6M78.3 64.6h.9v-.9l.8 .9-.8 .8v-.8M78.3 64.6h.1M78.3 79.5l.9 .5M79.2 70.6h3.9l.8 .8-.8 .9h-3.9zM79.2 67.2h3.9l.8 .8-.8 .9h-3.9zM79.2 77.5h5l.8 .9-.8 .8h-5zM79.6 70.8h2.9"/>
<path d="M79.6 67.3h2.9M79.8 67.6v.8M79.8 71.1v.8M79.8 78.4h.6M80.1 78.1v.7M80.2 71.5h.4v-.3l-.4-.1v.8M80.2 68l.4-.1v-.3h-.4v.8M80.4 71.5l.2 .4M80.4 68l.2 .4M81.1 71.2l.4-.1 .1 .5-.2 .3a.47 .47 0 0 1-.4-.3 .47 .47 0 0 1 .1-.4zM81.1 71.7l.5 .3M81.1 68.3l.5 .2"/>
<path d="M81.1 67.6h.4v.8h-.4l-.1-.2zM81.2 77.9h-.4v.5l.4-.1 .1 .1-.1 .4-.4-.1M81.5 77.9l.3 .9 .3-.9M82.1 71l-.2 .6h.5M82.3 67.6l-.4 .2v.6h.4v-.5h-.3l-.1 .2M82.3 71.3v.6M82.7 78.3l-.2-.1-.2 .2 .5 .3-.5 .1M83.1 77.9v.9h.3l.1-.4-.1-.2-.3 .1M43.9 80l.8 .6M43.9 80h1.7M45.6 80h.1M50.8 80h2.5"/>
<path d="M56.8 80h2.6M64.6 80h.1M64.6 80h1.6M66.2 80l-.8 .6M71.4 80h1.7M77.4 80h.1M77.4 80h1.8M79.2 80l-.9 .6M23.7 105h5.6l.8 .9-.8 .9h-5.6zM24.3 105.3h4.7M24.5 105.9h.3M24.9 105.5h-.4v.9h.4"/>
<path d="M25.2 105.5l.6 .9M25.8 105.5l-.6 .9M26 118.8h3.3l.8 .9-.8 .8h-3.3zM26 117.1h3.3l.8 .9-.8 .8h-3.3zM26 115.4h3.3l.8 .8-.8 .9h-3.3zM26 112h3.3l.8 .8-.8 .9h-3.3zM26 113.7h3.3l.8 .8-.8 .9h-3.3zM26.1 106h.4v-.4l-.4-.1v.9M26.7 116.7l.3-.8 .3 .8M26.7 113.2l.3-.8 .3 .8M26.7 114.9l.3-.8 .3 .8M26.8 118h.3"/>
<path d="M26.8 119.7h.3M26.8 116.5h.4M26.8 113h.4M26.8 114.8h.4M27.2 119.2h-.4v1M27.2 117.6h-.4v.8M27.4 105.5h-.4l-.1 .2 .5 .3v.3h-.5M27.6 115.9h.4l.1 .1-.5 .7h.5M27.6 112.5l.4-.1 .1 .2-.5 .6h.5M27.6 114.2l.3-.1 .2 .2-.5 .6h.5M27.8 105.9h.3M28.1 119.3l-.3-.1-.2 .3v.4l.2 .3 .3-.1"/>
<path d="M28.1 117.6h-.4l-.1 .1v.5l.1 .2 .4-.1M28.1 105.5h-.3v.9h.3M28.3 112.4h.6l-.3 .3h.2v.5h-.5M28.4 119.5l.3-.3v1M28.5 117.6a.42 .42 0 0 1 .4 .4 .42 .42 0 0 1-.4 .4zM28.6 105.5v.9h.4M28.6 114.1l-.2 .6h.5M28.8 115.9h-.4v.3h.4l.1 .3-.2 .2-.3-.1M28.8 114.4v.5M30.1 105.9h1.7M30.1 107.7h1.7M30.1 109.3h1.7"/>
<path d="M30.1 111h1.7M30.1 112.8h1.7M30.1 114.5h1.7M30.1 116.2h1.7M30.1 118h1.7M30.1 119.7h1.7M31.8 104.2h13.8v22.4h-13.8zM38.6 102.5v1.7M45.6 105.9h1.7M45.6 107.7h1.7M45.6 109.3h1.7M45.6 111h1.7"/>
<path d="M45.6 112.8h1.7M45.6 114.5h1.7M45.6 116.2h1.7M45.6 118h1.7M45.6 119.7h1.7M16.8 122.3h8.2l.8 .8-.8 .9h-8.2zM17.5 122.5h7.2M17.6 123.1h.3M18 122.7h-.4v.9h.4M18.3 122.7l.5 .9M18.8 122.7l-.5 .9M19.2 123.1h.4l.1-.3-.5-.1v.9"/>
<path d="M20 123.1h.4l.1-.3-.5-.1v.9M20.3 123.1l.2 .5M20.8 123.6l.3-.9 .3 .9M20.9 123.3h.4M21.6 123.6v-.9l.4 .6 .2-.6v.9M23.1 122.8l-.4-.1-.1 .2 .1 .2 .4 .1-.1 .4h-.4M23.5 123.1h.2M23.8 122.7h-.3v.9h.3M24.3 122.7v.9h.4M26 120.5h3.3l.8 .9-.8 .9h-3.3zM26.8 121.5h.3M27.2 121h-.4v.9"/>
<path d="M28.1 121.1l-.4-.1-.1 .2v.4l.2 .3 .3-.1M28.3 138.6l-.5 .9M28.3 138.6l.6 .9M28.3 138.6v2.2M28.4 121.1l.4-.1 .1 .3-.6 .6h.6M28.4 120.2h.5M30.1 121.4h1.7M30.1 123.1h1.7M30.1 124.8h1.7M38.6 128.3v.9h1l-1 .8-.8-.8h.8M38.6 128.3h.1M38.6 126.6v1.7"/>
<path d="M45.6 121.4h1.7M87.7 123.9h7v27.7h-7zM87.8 124.8h1.1M88.9 124.5h1.7v.6h-1.7zM27.8 140.8h1.1v2.5h-1.1zM28.3 140.3h.1M28.3 143.3v.5M30.4 153.8h1v2.3h-1zM30.9 153.3h.1M30.9 151.6l-.5 .8M30.9 151.6l.6 .8M30.9 151.6v2.2"/>
<path d="M30.9 156.2v.6M41.6 153.8h1v2.3h-1zM42.1 153.3v.5M42.1 156.2v.6M64.6 153.3v.8h.8l-.8 .9-.9-.9h.9M64.6 153.3h.1M69.5 189.9h2M70.6 188.6v1.3M70.6 190.6v1.5"/>
</g>
<g fill="none" stroke="#0f0f0f" stroke-width=".21">
<path d="M59.6 25.9h.3M59.6 27.6h.3M59.6 31h.3M59.6 37.9h.3M59.6 36.2h.3M59.6 34.5h.3M59.6 32.7h.3M59.6 29.3h.3M60.1 37.5h-.5v.9h.5M60.1 35.8h-.5v.8h.5M60.1 32.4h-.5v.8h.5M60.1 25.4h-.5v.9h.5"/>
<path d="M60.1 34.1h-.5v.8h.5M60.1 30.6h-.5v.9h.5M60.1 28.9h-.5v.9h.5M60.1 27.2h-.5v.9h.5M60.3 37.5l.6 .9M60.3 35.8l.6 .8M60.3 32.4l.6 .8M60.3 25.4l.6 .9M60.3 34.1l.6 .8M60.3 30.6l.6 .9M60.3 28.9l.6 .9M60.3 27.2l.6 .9"/>
<path d="M60.9 37.5l-.6 .9M60.9 35.8l-.6 .8M60.9 32.4l-.6 .8M60.9 25.4l-.6 .9M60.9 34.1l-.6 .8M60.9 30.6l-.6 .9M60.9 28.9l-.6 .9M60.9 27.2l-.6 .9M61.3 38h.3l.2-.2-.1-.3h-.4v.9M61.3 36.3h.3l.2-.4-.2-.1h-.3v.8M61.3 32.8h.3l.2-.2-.1-.2h-.4v.8M61.3 25.9h.3l.2-.3-.2-.2h-.3v.9"/>
<path d="M61.3 34.5h.4v-.4h-.4v.8M61.3 31.1h.3l.2-.3-.2-.2h-.3v.9M61.3 29.3h.4v-.4h-.4v.9M61.3 27.6h.3l.2-.3-.5-.1v.9M61.9 26.4h.6M61.9 28.1h.6M61.9 31.5h.6M61.9 38.5h.6M61.9 36.7h.6M61.9 35h.6M61.9 33.3h.6M61.9 29.8h.6"/>
<path d="M62.8 37.5l.4 .1v.6l-.3 .2h-.1zM62.8 35.8l.4 .1-.1 .7h-.3zM62.8 32.4l.4 .1v.6l-.3 .1h-.1zM62.8 25.4l.4 .2-.1 .7h-.3zM62.8 34.1l.4 .1-.1 .7h-.3zM62.8 30.6l.4 .2-.1 .7h-.3zM62.8 28.9l.4 .1-.1 .8h-.3zM62.8 27.2l.4 .1v.6l-.3 .2h-.1zM63.5 37.8l.3-.3v.9M63.5 36l.3-.2v.8M63.5 32.6l.3-.2v.8M63.5 34.3l.3-.2v.8"/>
<path d="M63.5 30.9l.3-.3v.9M63.5 29.2l.3-.3v.9M63.5 38.4h.5M63.5 36.6h.5M63.5 33.2h.5M63.5 34.9h.5M63.5 31.5h.5M63.5 29.8h.5M63.7 25.9l-.2-.2 .2-.3 .3 .1v.3l-.4 .1v.4l.4-.1v-.3h-.1M64 27.6l-.3 .1-.2-.4h.5v.7l-.4 .1M64.4 32.5l.4-.1 .1 .2-.5 .6h.5M64.4 34.1h.5l-.3 .3h.2l.1 .2-.1 .3-.4-.1"/>
<path d="M64.4 30.9l.2-.3v.9M64.4 31.5h.5M64.6 35.8l-.2 .6h.5M64.6 28.9a.43 .43 0 0 1 .3 .4 .43 .43 0 0 1-.3 .5l-.2-.4zM64.8 37.5h-.3l-.1 .4h.4l.1 .3-.2 .2-.3-.1M64.8 36.1v.5M73.3 25.2h6.2M73.3 27h6.2M73.3 30.3h6.7M73.3 33.8h6.7M73.3 37.3h6.7M73.4 25.9h.3"/>
<path d="M73.4 27.6h.3M73.4 31h.3M73.4 37.9h.3M73.4 34.5h.3M73.8 25.4h-.4v.9h.4M73.8 27.2h-.4v.9h.4M73.8 30.6h-.4v.9h.4M73.8 34.1h-.4v.8h.4M73.8 37.5h-.4v.9h.4M74.1 25.4l.6 .9M74.1 27.2l.6 .9M74.1 30.6l.6 .9"/>
<path d="M74.1 34.1l.6 .8M74.1 37.5l.6 .9M74.7 25.4l-.6 .9M74.7 27.2l-.6 .9M74.7 30.6l-.6 .9M74.7 34.1l-.6 .8M74.7 37.5l-.6 .9M75.1 25.9h.4v-.4l-.4-.1v.9M75.1 27.6h.4l-.1-.4h-.3v.9M75.1 31.1l.4-.1v-.3l-.4-.1v.9M75.1 34.5h.3l.1-.3-.4-.1v.8M75.1 38l.4-.1-.1-.4h-.3v.9"/>
<path d="M75.6 26.4h.7M75.6 28.1h.7M75.6 31.5h.7M75.6 38.5h.7M75.6 35h.7M76.5 25.9h.4l.1-.3-.2-.2h-.3v.9h.4l.1-.4h-.2M76.5 27.6h.4l.1-.3-.5-.1v.9l.5-.1v-.4h-.2M76.5 31h.4l.1-.2-.2-.2h-.3v.9h.4l.1-.4-.2-.1M76.5 34.5h.3l.2-.2-.1-.2h-.4v.8h.4l.1-.3-.2-.1M76.5 37.9h.4v-.4h-.4v.9l.5-.1v-.3l-.2-.1M77.4 25.9h.4v-.3l-.1-.2h-.3v.9h.4v-.4h-.1M77.8 27.3l-.3-.1a.43 .43 0 0 0-.1 .5 .43 .43 0 0 0 .4 .3"/>
<path d="M77.8 30.7a.43 .43 0 0 0-.4 .2 .43 .43 0 0 0 .1 .6h.3v-.4h-.1M77.8 34.1l-.4 .1-.1 .4 .2 .3h.3v-.3h-.1M77.8 37.5h-.3a.43 .43 0 0 0-.1 .6 .43 .43 0 0 0 .4 .2v-.3h-.1M78.2 30.9l.4 .6M78.2 34.3l.4 .6M78.2 37.8l.4 .6M78.3 27.2v.9h.4M78.6 30.9l-.4 .6M78.6 34.3l-.4 .6M78.6 37.8l-.4 .6M78.7 25.5l-.3-.1-.2 .2 .1 .3 .4 .1v.2l-.5 .1M78.9 25.4l.3 .5 .3-.5"/>
<path d="M78.9 27.6h.4l.2-.3-.6-.1v.9M78.9 30.6v.9M78.9 34.1v.8M78.9 37.5v.9M79.1 27.6l.4 .5M79.2 25.9v.4M79.9 30.6v.9l-.5-.9v.9M79.9 34.1v.8l-.5-.8v.8M79.9 37.5v.9l-.5-.9v.9M59.5 40.7h7.9M59.6 41.4h.3M59.6 50h.3"/>
<path d="M59.6 55.2h.3M59.6 56.9h.3M59.6 51.7h.3M59.6 58.6h.3M59.6 53.5h.3M60.1 40.9h-.5v.9h.5M60.1 49.6h-.5v.8h.5M60.1 58.2h-.5v.9h.5M60.1 53h-.5v.9h.5M60.1 59.9h-.5v.8h.5M60.1 54.7h-.5v.9h.5M60.1 56.4h-.5v1h.5"/>
<path d="M60.1 51.3h-.5v.9h.5M60.3 40.9l.6 .9M60.3 49.6l.6 .8M60.3 58.2l.6 .9M60.3 53l.6 .9M60.3 59.9l.6 .8M60.3 54.7l.6 .9M60.3 56.4l.6 1M60.3 51.3l.6 .9M60.9 40.9l-.6 .9M60.9 49.6l-.6 .8M60.9 58.2l-.6 .9"/>
<path d="M60.9 53l-.6 .9M60.9 59.9l-.6 .8M60.9 54.7l-.6 .9M60.9 56.4l-.6 1M60.9 51.3l-.6 .9M61.3 41.4h.3l.2-.3-.2-.2h-.3v.9M61.3 50h.4l.1-.3-.2-.1h-.3v.8M61.3 58.6h.4v-.4h-.4v.9M61.3 53.5h.4v-.5h-.4v.9M61.3 55.2h.4l.1-.3-.2-.2h-.3v.9M61.3 56.9h.3l.2-.3-.2-.2h-.3v1M61.3 51.8h.3l.2-.4-.2-.1h-.3v.9"/>
<path d="M61.9 41.9h.6M61.9 50.5h.6M61.9 55.7h.6M61.9 57.4h.6M61.9 52.3h.6M61.9 59.1h.6M61.9 54h.6M62.6 50.4l.3-.8 .3 .8M62.6 59.1l.3-.9 .3 .9M62.6 53.9l.3-.9 .3 .9M62.6 55.6l.3-.9 .3 .9M62.6 57.4l.3-1 .3 1"/>
<path d="M62.6 52.2l.3-.9 .3 .9M62.7 50.2h.4M62.7 55.3h.4M62.7 57.1h.4M62.7 51.9h.4M62.7 58.8h.4M62.7 53.6h.4M62.9 46.8h7.3M63.1 47.4h.3M63.2 41l-.3-.1-.2 .2 .1 .3 .4 .1v.3h-.5M63.5 40.9l.2 .5 .3-.5M63.5 49.7l.3-.1 .2 .2-.6 .6h.6"/>
<path d="M63.5 47h-.4v.9h.4M63.5 58.5l.2-.3v.9M63.5 53.1l.4-.1 .1 .3-.6 .6h.6M63.5 54.8l.3-.1 .2 .3-.6 .6h.6M63.5 56.7l.2-.3v1M63.5 51.3h.3l.2 .2-.6 .7h.6M63.5 59.1h.5M63.5 57.4h.5M63.7 41.4v.4M63.8 47l.6 .9M64.2 49.6h.5l-.2 .3 .2 .1v.3h-.5M64.2 59.9h.6l-.3 .8"/>
<path d="M64.3 53.3l.3-.3v.9M64.3 51.3h.4v.4l-.5 .5h.5M64.3 53.9h.4M64.4 47l-.6 .9M64.5 58.5l-.2-.2 .3-.1 .1 .3-.4 .1v.4l.2 .1 .2-.1v-.4l-.1-.1M64.5 54.7l.2 .2-.1 .7h-.2l-.1-.2v-.5zM64.6 47.5l.5-.1v-.4h-.5v.9M64.7 41h-.4v.3l.4 .2v.3h-.4M64.7 56.9l-.1 .1-.3-.1v-.4h.4v.6l-.3 .3M64.8 49.1h.3M65.1 41.4h.3M65.2 48.7h-.4v.9h.4"/>
<path d="M65.3 48h.7M65.5 48.7l.6 .9M65.6 40.9h-.5v.9M65.7 41.8l.3-.9 .3 .9M65.8 41.6h.4M66.1 48.7l-.6 .9M66.2 47v.9h.4M66.4 49.1h.4v-.4h-.4v.9M66.6 40.9v.9M66.8 47l.2 .9 .2-.7 .1 .7 .2-.9M67 40.9v.9h.4M67.1 49.7h.6"/>
<path d="M67.8 49.6l.3-.9 .3 .9M67.9 47.1h.5a.47 .47 0 0 1-.4 .8l-.1-.2zM67.9 49.3h.4M68.6 49.6v-.9l.4 .6 .2-.6v.9M68.8 47.5h.3l.2-.4-.5-.1v.9M69 47.5l.3 .4M69.6 47h.4a.48 .48 0 0 1 .1 .6 .48 .48 0 0 1-.5 .3zM70.1 48.7h-.5v.4h.5l-.1 .5-.4-.1M73.3 40.7h6.7M73.4 41.4h.3M73.8 40.9h-.4v.9h.4M74.1 40.9l.6 .9"/>
<path d="M74.3 55.2h.2M74.3 56.9h.2M74.3 51.7h.2M74.7 54.7h-.4v.9h.4M74.7 56.4h-.4v1h.4M74.7 51.3h-.4v.9h.4M74.7 40.9l-.6 .9M75 54.7l.6 .9M75 56.4l.6 1M75 51.3l.6 .9M75.1 41.4h.4v-.4l-.4-.1v.9M75.6 54.7l-.6 .9"/>
<path d="M75.6 56.4l-.6 1M75.6 51.3l-.6 .9M75.6 41.9h.7M75.9 55.2h.4l.1-.3-.2-.2h-.3v.9M75.9 56.9h.3l.2-.1-.2-.4h-.3v1M75.9 51.8h.3l.2-.2-.2-.3h-.3v.9M76.5 41.4h.4l.1-.3-.2-.2h-.3v.9h.5v-.4h-.2M76.5 55.7h.7M76.5 57.4h.7M76.5 52.3h.7M77.3 55.6l.3-.9 .2 .9M77.3 57.4l.3-1 .2 1"/>
<path d="M77.3 52.2l.3-.9 .2 .9M77.3 55.3h.5M77.3 57.1h.5M77.3 51.9h.5M77.8 41a.43 .43 0 0 0-.4 .3 .43 .43 0 0 0 .1 .5h.3v-.4h-.1M78.1 55.6v-.9l.3 .6 .3-.6v.9M78.1 57.4v-1l.3 .7 .3-.7v1M78.1 52.2v-.9l.3 .6 .3-.6v.9M78.2 41.3l.4 .5M78.6 41.3l-.4 .5M78.9 40.9v.9M79 54.8h.5v.3l-.5 .5h.5"/>
<path d="M79 56.4h.5l-.2 .4 .2 .1v.4h-.5M79.1 51.3h.3l.1 .1v.6l-.1 .2a.53 .53 0 0 1-.3-.9zM79.9 40.9v.9l-.5-.9v.9M46.2 72.3h.3M46.2 74.1h.3M46.2 70.7h.3M46.6 72h-.4v.9h.4M46.6 73.7h-.4v.8h.4M46.6 70.2h-.4v.9h.4M46.9 72l.6 .9M46.9 73.7l.6 .8M46.9 70.2l.6 .9"/>
<path d="M47.5 72l-.6 .9M47.5 73.7l-.6 .8M47.5 70.2l-.6 .9M47.8 72.4l.5-.1v-.2l-.5-.1v.9M47.8 74.1h.4l.1-.3-.5-.1v.8M47.8 70.7h.5v-.4l-.5-.1v.9M48.5 72.9h.6M48.5 74.6h.6M48.5 71.2h.6M49.2 72.9l.3-.9 .2 .9M49.2 74.5l.3-.8 .2 .8M49.2 71.1l.3-.9 .2 .9"/>
<path d="M49.3 72.6h.4M49.3 74.3h.4M49.3 70.8h.4M50 72h.5l-.3 .3h.3v.5h-.5M50 73.8h.5v.2l-.5 .5h.5M50.2 70.2l-.2 .6h.6M50.4 70.6v.5M59.6 63.8h.3M59.6 60.3h.3M59.6 62h.3M60.1 63.4h-.5v.8h.5M60.1 61.6h-.5v.9h.5"/>
<path d="M60.3 63.4l.6 .8M60.3 61.6l.6 .9M60.9 63.4l-.6 .8M60.9 61.6l-.6 .9M61.3 63.8h.4v-.4h-.4v.8M61.3 60.3h.4l.1-.2-.2-.2h-.3v.8M61.3 62.1h.3l.2-.3-.2-.2h-.3v.9M61.9 64.3h.6M61.9 60.8h.6M61.9 62.6h.6M62.6 64.2l.3-.8 .3 .8M62.6 60.7l.3-.8 .3 .8"/>
<path d="M62.6 62.5l.3-.9 .3 .9M62.7 64h.4M62.7 60.5h.4M62.7 62.3h.4M63.5 63.6l.2-.2v.8M63.5 60.2l.2-.3v.8M63.5 61.8l.2-.2v.9M63.5 64.2h.5M63.5 60.7h.5M63.5 62.5h.5M64.6 61.6l-.3 .2v.6h.4v-.4l-.2-.1-.2 .2M64.7 63.4h-.4v.4h.4l-.1 .4-.3-.1"/>
<path d="M71.6 123.4h5.3M71.7 124.1h.3M72.1 123.7h-.4v.8h.4M72.4 123.7l.5 .8M72.9 123.7l-.5 .8M73.3 124.1h.4l.1-.4h-.5v.8M74 124.6h.6M75.3 123.7h-.3l-.2 .1v.5l.2 .2 .3-.1M75.6 123.7v.8h.5M76.4 123.7v.8M76.5 124l.3 .5M76.8 123.7l-.4 .5"/>
<path d="M28.5 147.5h6.7M28.7 148.2h.2M29 147.8h-.3v.8h.3M29.3 147.8l.6 .8M29.9 147.8l-.6 .8M30.3 148.2l.4-.1-.1-.3h-.3v.8M30.9 148.7h.6M31.1 157.9h7.2M31.2 158.5h.3M31.6 158.1h-.4v.9h.4M31.7 148.2h.3l.2-.2-.1-.2h-.4v.8l.5-.1v-.2l-.2-.1M31.9 158.1l.6 .9"/>
<path d="M32.5 158.1l-.6 .9M32.8 158.5h.4v-.4h-.4v.9M33.1 147.8h-.4a.43 .43 0 0 0-.1 .5 .43 .43 0 0 0 .5 .2l-.1-.2M33.4 148l.4 .6M33.5 159h.7M33.8 148l-.4 .6M34.2 147.8v.8M34.3 158.1v.9h.5M34.9 158.1l.3 .9 .1-.6 .2 .6 .2-.9M35.1 147.8v.8l-.5-.8v.8M36.1 158.1l.4 .1-.1 .8h-.3l-.2-.3zM37 158.5h.4l-.1-.4h-.3v.9"/>
<path d="M37.1 158.5l.3 .5M37.8 158.1l.4 .1-.1 .8h-.3zM42.3 157.9h7.1M42.4 158.5h.3M42.8 158.1h-.4v.9h.4M43.1 158.1l.5 .9M43.6 158.1l-.5 .9M44 158.5h.4l.1-.3-.5-.1v.9M44.7 159h.6M45.5 158.1v.9M45.8 159l.3-.9 .3 .9M45.9 158.7h.4"/>
<path d="M47.2 158.2l-.4-.1-.2 .4 .2 .5 .4-.1M47.5 158.1v.9M47.6 158.5l.4 .5M48 158.1l-.5 .5M48.4 158.1v.9M49.3 158.1v.9l-.5-.9v.9"/>
</g>
<g fill="none" stroke="#b90000" stroke-width=".21">
<path d="M51.4 25.9h.5v.6M51.4 27.6h.3l.2 .1v.4h-.5l.1-.3h.4M51.4 29.3l.5 .1v.4h-.5v-.2l.5-.1M51.4 31l.5 .1v.5M51.4 32.8l.3-.1 .2 .2v.4h-.5l.1-.3h.4M51.4 34.5l.5 .1v.4h-.5v-.2l.5-.1M51.4 36.3l.3-.1 .2 .2v.4M51.4 38l.3-.1 .2 .2v.4h-.5l.1-.4h.4M51.4 39.7h.5v.6M51.9 26l-.5 .1 .1 .4 .4-.1M51.9 31.2l-.5 .1 .1 .3 .4-.1M51.9 36.4h-.5l.1 .4 .4-.1"/>
<path d="M51.9 39.8l-.5 .1 .1 .4 .4-.1M52.1 29h.6l-.3 .3 .3 .2v.3h-.6M52.1 35.9h.6l-.3 .9M52.2 25.8l.2-.2v.9M52.2 27.4l.4-.1 .1 .3-.6 .5h.6M52.2 26.5h.5M52.4 30.7l-.2 .6h.5M52.4 38l-.2-.3 .4-.1v.4l-.4 .1 .1 .4h.3l.1-.4-.2-.1M52.6 32.5h-.4v.4l.4-.1v.5l-.4-.1M52.6 34.2h-.3l-.1 .8 .5-.1-.2-.4-.3 .2M52.6 31v.6M52.7 39.7l-.2 .2-.3-.1v-.4l.3-.1 .2 .2-.2 .7-.2 .1"/>
<path d="M57.9 25.9h-.4l-.1 .1 .2 .5 .3-.1M57.9 27.6h-.3l-.2 .1 .1 .4h.4M57.9 29.3h-.4l-.1 .2 .1 .3h.4M57.9 31h-.4l-.1 .2 .2 .4 .3-.1M57.9 32.8l-.3-.1-.2 .2 .1 .4h.4M57.9 34.5h-.4l-.1 .2 .1 .3h.4M57.9 36.3l-.3-.1-.2 .2 .2 .4 .3-.1M57.9 38l-.3-.1-.2 .2 .1 .4h.4M57.9 39.7h-.4l-.1 .1 .2 .5 .3-.1M58.1 29h.6l-.3 .3 .3 .2v.3h-.6M58.1 35.9h.6l-.3 .9M58.2 25.8l.3-.2v.9"/>
<path d="M58.2 27.4l.4-.1 .1 .3-.6 .5h.6M58.2 26.5h.5M58.4 30.7l-.2 .6h.5M58.4 38l-.2-.3 .4-.1v.4l-.4 .1 .1 .4h.3l.1-.4-.2-.1M58.6 32.5h-.4v.4l.4-.1v.5l-.4-.1M58.6 34.2l-.4 .2v.6l.5-.1-.2-.4-.3 .2M58.6 31v.6M58.7 39.7l-.2 .2-.3-.1v-.4l.3-.1 .2 .2-.2 .7-.2 .1M71.7 25.9h.4v.5h-.4M71.7 27.3v.8h.3l.1-.5h-.4M71.7 29v.8h.3l.1-.4-.4-.1M71.7 31l.4 .1v.4h-.4"/>
<path d="M71.7 32.5v.8h.3l.1-.5h-.4M71.7 34.2v.8h.4v-.4l-.4-.1M71.7 36.3h.4v.4h-.4M71.7 37.6v.9h.3l.1-.5h-.4M71.7 39.7h.4v.5h-.4M71.7 25.6v.9M71.7 30.8v.8M71.7 35.9v.9M71.7 39.3v1M72.3 29h.6l-.3 .3 .3 .2v.3h-.6M72.3 35.9h.6l-.3 .9M72.4 25.8l.3-.2v.9"/>
<path d="M72.4 27.4l.5-.1v.3l-.6 .5h.6M72.4 26.5h.5M72.6 30.7l-.2 .6h.5M72.6 38l-.2-.3 .5-.1v.4l-.5 .1 .1 .4h.4v-.4l-.1-.1M72.9 32.5h-.5v.4l.5-.1v.5l-.5-.1M72.9 34.2l-.5 .2v.6l.5-.1-.1-.4-.4 .2M72.9 31v.6M72.9 39.7l-.1 .2-.4-.1v-.4l.4-.1 .1 .2-.1 .7-.3 .1M51 41.4h.3l.1 .1v.4M51 43.1l.3-.1 .1 .2v.4h-.4l.1-.3h.3M51 44.8l.4 .1v.5M51 46.6l.3-.1 .1 .2v.4"/>
<path d="M51 48.3l.3-.1 .1 .2v.4h-.4l.1-.3h.3M51 50l.4 .1v.5M51 51.8l.3-.1 .1 .2v.4M51 53.5h.4v.5h-.4l.1-.4h.3M51 55.2h.4v.5M51 56.9h.3l.1 .1v.4M51 58.6l.4 .1v.4h-.4l.1-.3h.3M51.4 41.6h-.4l.1 .3h.3M51.4 45l-.4 .1 .1 .3 .3-.1M51.4 46.8l-.4 .1 .1 .2 .3-.1M51.4 50.2h-.4l.1 .4 .3-.1M51.4 51.9l-.4 .1 .1 .3 .3-.1"/>
<path d="M51.4 55.3l-.4 .1 .1 .3h.3M51.4 57.1l-.4 .1 .1 .2h.3M51.8 41.4l.2-.3v.8M51.8 43l.2-.2v.8M51.8 44.7l.2-.2v.9M51.8 46.5l.2-.2v.8M51.8 48.2l.2-.2v.8M51.8 49.9l.2-.2v.9M51.8 51.7l.2-.3v.9M51.8 53.4l.2-.3v.9M51.8 55.1l.2-.3v.9M51.8 56.9l.2-.3v.8"/>
<path d="M51.8 58.4l.3-.1 .2 .2-.5 .6h.5M51.8 41.9h.5M51.8 43.6h.5M51.8 45.4h.5M51.8 47.1h.5M51.8 48.8h.5M51.8 50.6h.5M51.8 52.3h.5M51.8 54h.5M51.8 55.7h.5M51.8 57.4h.5M52.5 46.3h.6l-.3 .3h.2l.1 .3-.1 .2-.5-.1"/>
<path d="M52.5 53.1h.6l-.3 .9M52.6 43l.3-.2v.8M52.6 44.6l.4-.1 .1 .2-.6 .7h.6M52.6 43.6h.5M52.7 41.1a.43 .43 0 0 1 .4 .4 .43 .43 0 0 1-.3 .4l-.2-.1zM52.8 48l-.2 .6h.5M52.8 55.2h-.2v-.3l.4-.1 .1 .3-.5 .2v.4h.2l.3-.1-.1-.4M52.8 58.3a.43 .43 0 0 1 .3 .5 .43 .43 0 0 1-.4 .3l-.1-.6zM53 49.7h-.4v.4l.4-.1 .1 .4-.1 .2-.4-.1M53 51.4l-.4 .2v.6l.4 .1 .1-.2-.1-.3h-.3l-.1 .1M53 48.2v.6M53.1 56.9l-.1 .2h-.3l-.1-.4 .4-.1 .1 .2-.1 .5-.3 .1"/>
<path d="M57.4 41.4h-.2l-.2 .1 .2 .4h.2M57.4 43.1l-.2-.1-.2 .2 .1 .4h.3M57.4 44.8h-.3l-.1 .2 .2 .4 .2-.1M57.4 46.6l-.2-.1-.2 .2 .2 .4 .2-.1M57.4 48.3l-.2-.1-.2 .2 .1 .4h.3M57.4 50h-.3l-.1 .2 .2 .4 .2-.1M57.4 51.8l-.2-.1-.2 .2 .2 .4 .2-.1M57.4 53.5h-.4l.1 .5h.3M57.4 55.2h-.3l-.1 .1 .2 .4h.2M57.4 56.9h-.2l-.2 .1 .2 .4h.2M57.4 58.6l-.4 .1 .1 .4h.3M57.8 41.4l.2-.3v.8"/>
<path d="M57.8 43l.2-.2v.8M57.8 44.7l.2-.2v.9M57.8 46.5l.2-.2v.8M57.8 48.2l.2-.2v.8M57.8 49.9l.2-.2v.9M57.8 51.7l.2-.3v.9M57.8 53.4l.2-.3v.9M57.8 55.1l.2-.3v.9M57.8 56.9l.2-.3v.8M57.8 58.4l.3-.1 .2 .2-.5 .6h.5M57.8 41.9h.5M57.8 43.6h.5"/>
<path d="M57.8 45.4h.5M57.8 47.1h.5M57.8 48.8h.5M57.8 50.6h.5M57.8 52.3h.5M57.8 54h.5M57.8 55.7h.5M57.8 57.4h.5M58.5 46.3h.6l-.3 .3h.3v.4h-.6M58.5 53.1h.6l-.3 .9M58.6 43l.3-.2v.8M58.6 44.6l.4-.1 .1 .4-.6 .5h.6"/>
<path d="M58.6 58.5l.2-.2 .3 .1-.1 .7h-.3zM58.6 43.6h.5M58.7 41.1l.4 .1v.7h-.2l-.3-.1zM58.8 48l-.2 .6h.5M58.8 55.2h-.2v-.3l.4-.1 .1 .4-.5 .1v.4h.2h.3l-.1-.5M59.1 49.7h-.5v.4h.5v.4h-.5M59.1 51.4l-.5 .2v.6h.5v-.4h-.4l-.1 .1M59.1 56.9v.2h-.4l-.1-.4 .5-.1v.7l-.4 .1M59.1 48.2v.6M71.2 41.4h.5v.5h-.5M71.2 42.8v.8h.4l.1-.5h-.5M71.2 44.8l.5 .1v.4h-.5"/>
<path d="M71.2 46.6h.5v.4h-.5M71.2 48v.8h.4l.1-.5h-.5M71.2 50l.5 .1v.4h-.5M71.2 51.8h.5v.4h-.5M71.2 53.1v.9h.4l.1-.5h-.5M71.2 55.2h.5v.5h-.5M71.2 56.9h.5v.5h-.5M71.2 58.3v.8h.4l.1-.4-.5-.1M71.2 41.1v.8M71.2 44.5v.9M71.2 46.3v.8M71.2 49.7v.9"/>
<path d="M71.2 51.4v.9M71.2 54.8v.9M71.2 56.6v.8M71.2 60v.9M72 41.4l.3-.3v.8M72 43l.3-.2v.8M72 44.7l.3-.2v.9M72 46.5l.3-.2v.8M72 48.2l.3-.2v.8M72 49.9l.3-.2v.9M72 51.7l.3-.3v.9M72 53.4l.3-.3v.9"/>
<path d="M72 55.1l.3-.3v.9M72 56.9l.3-.3v.8M72 58.4l.3-.1 .2 .2-.5 .6h.5M72 41.9h.5M72 43.6h.5M72 45.4h.5M72 47.1h.5M72 48.8h.5M72 50.6h.5M72 52.3h.5M72 54h.5M72 55.7h.5"/>
<path d="M72 57.4h.5M72.8 46.3h.6l-.4 .3h.3l.1 .3-.2 .2-.4-.1M72.8 53.1h.6l-.4 .9M72.9 43l.2-.2v.8M72.9 44.6l.3-.1 .2 .2-.6 .7h.6M72.9 43.6h.5M72.9 41.1a.43 .43 0 0 1 .5 .4 .43 .43 0 0 1-.4 .4l-.1-.1zM73 48l-.1 .6h.5M73 55.2h-.1v-.3l.3-.1 .2 .3-.5 .2v.4h.1l.4-.1-.2-.4M73 58.3a.43 .43 0 0 1 .4 .5 .43 .43 0 0 1-.5 .3v-.6zM73.3 49.7h-.4v.4l.3-.1 .2 .4-.2 .2-.3-.1M73.3 51.4l-.4 .2v.6l.3 .1 .2-.2-.1-.3h-.4v.1"/>
<path d="M73.3 48.2v.6M73.4 56.9l-.1 .2h-.4v-.4l.4-.1 .1 .2-.1 .5-.4 .1M51 60.3l.4 .1v.5M51 62.1l.3-.1 .1 .2v.4h-.4l.1-.3h.3M51 63.8l.4 .1v.4h-.4l.1-.3h.3M51 65.5l.4 .1v.5M51 67.3l.3-.1 .1 .1v.5h-.4l.1-.4h.3M51 69h.4v.5h-.4v-.3l.4-.1M51 70.7h.4v.5M51 72.4l.3-.1 .1 .2v.4h-.4l.1-.3h.3M51 74.1l.4 .1v.4h-.4v-.2l.4-.1M51 75.8l.4 .1v.5"/>
<path d="M51 77.6l.3-.1 .1 .2v.4h-.4l.1-.3h.3M51 79.3l.4 .1v.4h-.4v-.3h.4M51.4 60.5l-.4 .1 .1 .3 .3-.1M51.4 65.7h-.4l.1 .4 .3-.1M51.4 70.8l-.4 .1 .1 .3h.3M51.4 76l-.4 .1 .1 .3 .3-.1M51.8 60.1l.3-.1 .2 .2-.5 .7h.5M51.8 61.8h.4l.1 .1-.5 .7h.5M51.8 63.5h.3l.2 .1-.5 .7h.5M51.8 65.3h.5l-.5 .8h.5M51.8 67l.4-.1 .1 .2-.5 .7h.5M51.8 68.7l.3-.1 .2 .2-.5 .7h.5"/>
<path d="M51.8 70.5l.4-.1 .1 .2-.5 .6h.5M51.8 72.2l.4-.1 .1 .2-.5 .6h.5M51.8 73.9l.3-.1 .2 .2-.5 .6h.5M51.8 75.6h.5l-.4 .2 .4 .2v.2l-.2 .2-.3-.1M51.8 77.3h.5l-.4 .3h.3v.5l-.4-.1M51.8 78.9h.5l-.4 .4 .4 .2v.2l-.5 .1M52.5 63.5h.6l-.3 .3 .3 .2-.1 .3-.5-.1M52.5 70.4h.6l-.3 .8M52.6 60.2l.3-.2v.9M52.6 61.8h.4l.1 .2-.6 .6h.6M52.6 77.5l.3-.2v.8M52.6 79l.4-.1 .1 .3-.6 .6h.6"/>
<path d="M52.6 60.9h.5M52.6 78.1h.5M52.7 75.6a.42 .42 0 0 1 .4 .3 .42 .42 0 0 1-.1 .4l-.2 .1-.2-.2zM52.8 65.1l-.2 .6h.5M52.8 72.4l-.2-.2 .4-.1v.3l-.4 .1 .1 .4h.3l.1-.3-.1-.2M53 66.9h-.4v.4h.4v.5l-.4-.1M53 68.6l-.4 .3v.5l.4 .1 .1-.4-.1-.1-.4 .1M53 65.5v.6M53.1 74.2l-.1 .2-.4-.1v-.4l.4-.1 .1 .2-.1 .6h-.3M57.4 60.3h-.3l-.1 .2 .2 .4 .2-.1M57.4 62.1l-.2-.1-.2 .2 .1 .4h.3M57.4 63.8h-.3l-.1 .2 .1 .3h.3"/>
<path d="M57.4 65.5h-.3l-.1 .2 .2 .4 .2-.1M57.4 67.3l-.2-.1-.2 .1 .1 .5h.3M57.4 69h-.3l-.1 .1 .1 .4h.3M57.4 70.7h-.3l-.1 .1 .2 .4h.2M57.4 72.4l-.2-.1-.2 .2 .1 .4h.3M57.4 74.1h-.3l-.1 .2 .1 .3h.3M57.4 75.8h-.3l-.1 .2 .2 .4 .2-.1M57.4 77.6l-.2-.1-.2 .2 .1 .4h.3M57.4 79.3h-.3l-.1 .2 .1 .3h.3M57.8 60.1l.3-.1 .2 .2-.5 .7h.5M57.8 61.8h.4l.1 .1-.5 .7h.5M57.8 63.5h.3l.2 .1-.5 .7h.5"/>
<path d="M57.8 65.3h.5l-.5 .8h.5M57.8 67l.4-.1 .1 .2-.5 .7h.5M57.8 68.7l.3-.1 .2 .2-.5 .7h.5M57.8 70.5l.4-.1 .1 .2-.5 .6h.5M57.8 72.2l.4-.1 .1 .2-.5 .6h.5M57.8 73.9l.3-.1 .2 .2-.5 .6h.5M57.8 75.6h.5l-.3 .2 .3 .2v.2l-.2 .2-.3-.1M57.8 77.3h.5l-.3 .3h.2v.5l-.4-.1M57.8 78.9h.5l-.3 .4 .3 .2v.2l-.5 .1M58.5 63.5h.6l-.3 .3 .3 .1v.4l-.6-.1M58.5 70.4h.6l-.3 .8M58.6 60.2l.3-.2v.9"/>
<path d="M58.6 61.8h.5v.3l-.6 .5h.6M58.6 77.5l.3-.2v.8M58.6 79l.4-.1 .1 .5-.6 .4h.6M58.6 60.9h.5M58.6 78.1h.5M58.7 75.6h.4v.7l-.2 .1-.3-.2zM58.8 65.1l-.2 .6h.5M58.8 72.4l-.2-.2 .5-.1v.3l-.5 .1 .1 .4h.4l-.1-.5M59.1 66.9h-.5v.4h.5v.5l-.5-.1M59.1 68.6l-.5 .3v.5l.5 .1-.1-.5-.4 .1M59.1 74.2l-.1 .2-.4-.1v-.4h.5v.6l-.1 .1h-.3M59.1 65.5v.6"/>
<path d="M71.2 60.3l.5 .1v.4h-.5M71.2 61.8v.8h.4l.1-.5h-.5M71.2 63.5v.8h.4l.1-.4-.5-.1M71.2 65.5l.5 .1v.4h-.5M71.2 66.9v.9h.4l.1-.5h-.5M71.2 68.6v.9h.4l.1-.5h-.5M71.2 70.7h.5v.5h-.5M71.2 72.1v.8h.4l.1-.5h-.5M71.2 73.8v.8h.4l.1-.4-.5-.1M71.2 75.8l.5 .1v.4h-.5M71.2 77.3v.8h.4l.1-.5h-.5M71.2 78.9v.9h.5v-.4l-.5-.1"/>
<path d="M71.2 65.2v.9M71.2 70.4v.8M71.2 75.6v.8M72 60.1l.3-.1 .2 .2-.5 .7h.5M72 61.8h.4l.1 .1-.5 .7h.5M72 63.5h.3l.2 .1-.5 .7h.5M72 65.3h.5l-.5 .8h.5M72 67l.4-.1 .1 .2-.5 .7h.5M72 68.7l.3-.1 .2 .2-.5 .7h.5M72 70.5l.4-.1 .1 .2-.5 .6h.5M72 72.2l.4-.1 .1 .2-.5 .6h.5M72 73.9l.3-.1 .2 .2-.5 .6h.5"/>
<path d="M72 75.6h.5l-.2 .2 .2 .2v.2l-.2 .2-.3-.1M72 77.3h.5l-.2 .3 .2 .2-.1 .3-.4-.1M72 78.9h.5l-.2 .4 .2 .2v.2l-.5 .1M72.8 63.5h.6l-.4 .3 .4 .2-.1 .3-.5-.1M72.8 70.4h.6l-.4 .8M72.9 60.2l.2-.2v.9M72.9 61.8h.4l.1 .2-.6 .6h.6M72.9 77.5l.2-.2v.8M72.9 79l.3-.1 .2 .3-.6 .6h.6M72.9 60.9h.5M72.9 78.1h.5M72.9 75.6a.42 .42 0 0 1 .4 .3 .42 .42 0 0 1-.1 .4l-.2 .1-.1-.2z"/>
<path d="M73 65.1l-.1 .6h.5M73 72.4l-.1-.2 .4-.1v.3l-.4 .1v.4h.4l.1-.3-.2-.2M73.3 66.9h-.4v.4h.4v.5l-.4-.1M73.3 68.6l-.4 .3v.5l.4 .1 .1-.4-.2-.1-.3 .1M73.3 65.5v.6M73.4 74.2l-.2 .2-.3-.1v-.4l.3-.1 .2 .2-.2 .6h-.3M30.7 105l.2-.2v.9M30.7 106.6l.4-.1 .1 .2-.5 .7h.5M30.7 108.2h.5l-.3 .4 .3 .2-.1 .3-.4-.1M30.7 115.2h.5l-.3 .8M30.7 105.7h.5M30.9 109.9l-.2 .6h.5"/>
<path d="M30.9 117.2l-.2-.2 .1-.1h.3v.3l-.4 .2 .1 .3h.3l.1-.3-.2-.2M31.1 111.7h-.3l-.1 .4h.4v.5l-.4-.1M31.1 113.4a.57 .57 0 0 0-.3 .9h.3l.1-.4-.2-.2-.3 .2M31.1 110.3v.6M31.2 119l-.2 .2-.3-.2 .2-.4 .3 .1v.4l-.2 .3h-.2M37.9 102.7h.6M38.1 102.7v.5l-.6-.2M38.5 103.5v.5l-.5-.5-.4 .1 .1 .4M45.8 105l.2-.2v.9M45.8 106.8l.2-.3v.9M45.8 108.5l.2-.3v.9M45.8 110.2l.2-.2v.9"/>
<path d="M45.8 112l.2-.3v.9M45.8 113.7l.2-.3v.9M45.8 115.3h.5v.2l-.5 .5h.5M45.8 117h.5v.2l-.5 .5h.5M45.8 118.7h.5v.3l-.5 .4h.5M45.8 105.7h.5M45.8 107.4h.5M45.8 109.1h.5M45.8 110.9h.5M45.8 112.6h.5M45.8 114.3h.5M46.6 110h.5l-.3 .9"/>
<path d="M46.6 115.3l.2-.1a.43 .43 0 0 1 .3 .4 .43 .43 0 0 1-.3 .4l-.2-.1zM46.6 117.1l.3-.2v.8M46.6 118.7l.3-.1 .2 .1-.5 .7h.5M46.6 117.7h.5M46.8 104.8l-.2 .6h.5M46.8 112.1l-.2-.3 .4-.1v.4h-.4l.1 .5h.3l.1-.4-.2-.1M47 106.5h-.4v.5l.4-.1v.5l-.4-.1M47 108.2l-.4 .3v.5l.4 .1 .1-.3-.2-.2-.3 .2M47 105.1v.6M47.1 113.8l-.2 .2-.3-.1v-.4l.3-.1 .2 .2-.2 .7h-.2M30.3 120.5l.2-.1v.8M30.3 122.3l.2-.3v.9"/>
<path d="M30.3 124l.2-.3v.9M30.3 121.2h.5M30.3 122.9h.5M30.3 124.6h.5M31 123.7h.6l-.3 .4 .3 .1v.3h-.6M31.1 122.3l.3-.3v.9M31.1 122.9h.5M31.2 120.4a.42 .42 0 0 1 .4 .2 .42 .42 0 0 1-.1 .5l-.2 .1-.2-.2zM38.5 127.9h-.9l.3 .2M38.5 126.8v.5l-.5-.5h-.3v.5M38.5 127.6v.5M45.8 120.4h.5v.3l-.5 .5h.5"/>
<path d="M46.6 120.4h.5l-.3 .2 .3 .2v.2l-.2 .2-.3-.1"/>
</g>
<g fill="none" stroke="#006665" stroke-width=".21">
<path d="M32.6 105.4v.9M32.6 107.1v.9M32.6 108.9v.9M32.6 110.6v.9M32.6 112.3v.9M32.6 114.1v.8M32.6 115.8v.8M32.6 117.5v.8M32.6 119.2v.9M32.8 108.9h.6l-.3 .3 .3 .1v.3l-.2 .2-.4-.1M32.8 115.8h.6l-.3 .8M32.9 105.7l.2-.3v.9"/>
<path d="M32.9 107.2l.3-.1 .2 .3-.6 .6h.6M32.9 106.3h.5M33.1 110.5l-.2 .7h.5M33.1 117.9l-.2-.1v-.2l.3-.1 .2 .2-.5 .3 .1 .3 .4-.1-.2-.3M33.3 112.3h-.4v.4l.3-.1 .2 .2-.1 .4-.4-.1M33.3 114.1l-.4 .2v.5l.3 .1 .2-.4-.2-.2-.3 .2M33.3 110.9v.6M33.4 119.6l-.3 .2-.2-.1v-.4l.4-.1 .1 .2-.2 .6-.2 .1M34.3 105.4l-.6 1.1M35.2 105.5l-.4-.1-.2 .4 .2 .5 .4-.1M35.5 105.4v.9h.4M36.2 105.4v.9"/>
<path d="M36.4 105.8l.3 .5M36.7 105.4l-.5 .6M38.2 106.5l.9 .3-.9 .3M38.3 105.7v.5h.7v-.5M38.3 104.9l-.1 .3 .2 .2h.5l.2-.2-.1-.3M43.1 105.4v.9M43.1 107.1v.9M43.1 108.9v.9M43.1 110.6v.9M43.1 112.3v.9M43.1 114.1v.8M43.1 115.8v.8"/>
<path d="M43.1 117.5v.8M43.1 119.2v.9M43.6 105.5h.5l-.1 .8-.4-.1zM43.6 109h.5v.6l-.2 .2a.47 .47 0 0 1-.4-.3 .47 .47 0 0 1 .1-.5zM43.6 110.7h.5l-.1 .8-.4-.1zM43.6 114.2h.5v.6l-.2 .1a.47 .47 0 0 1-.4-.2 .47 .47 0 0 1 .1-.5zM43.6 115.9h.5l-.1 .7-.4-.1zM43.6 119.3h.5v.6l-.2 .2a.47 .47 0 0 1-.4-.3 .47 .47 0 0 1 .1-.5zM43.7 107.1l.4 .2v.6h-.5a.52 .52 0 0 1 .1-.8zM43.7 112.3l.4 .2v.6h-.5a.52 .52 0 0 1 .1-.8zM43.7 117.5l.4 .1v.6h-.5a.52 .52 0 0 1 .1-.7zM44.4 105.7l.3-.3v.9"/>
<path d="M44.4 107.2l.3-.1 .2 .2-.5 .7h.5M44.4 108.9h.5l-.2 .3 .2 .1v.3l-.2 .2-.3-.1M44.4 115.8h.5l-.3 .8M44.4 106.3h.5M44.6 117.9l-.2-.3 .3-.1 .2 .2-.4 .2v.4l.4-.1-.2-.3M44.7 110.5l-.3 .7h.5M44.8 112.3h-.3l-.1 .4 .3-.1 .2 .2-.1 .4-.4-.1M44.8 114.1h-.2l-.2 .3v.4l.3 .1 .2-.4-.2-.2-.3 .2M44.8 110.9v.6M44.9 119.6l-.3 .2-.2-.2 .1-.4h.3l.1 .2-.2 .6-.2 .1M32.6 120.9v.9M32.6 122.6v.9"/>
<path d="M32.6 124.4v.9M32.9 121.2l.2-.3v.9M32.9 122.9l.2-.3v.9M32.9 124.7l.2-.3v.9M32.9 121.8h.5M32.9 123.5h.5M32.9 125.3h.5M33.7 122.9l.3-.3v.9M33.7 124.5l.4-.1 .1 .4-.5 .5h.5M33.7 123.5h.5M33.8 120.9h.3l.1 .2-.1 .7h-.3l-.1-.2zM38.2 125.4v.4l.4 .1 .5-.1-.1-.5h-.3v.2"/>
<path d="M38.2 124.5h.9l-.9 .5h.9M38.2 123.7l.4-.1 .4 .1 .1 .4h-.9zM42.3 120.9v.9M42.7 121h.5l.1 .5-.2 .3-.4-.1zM43.6 121.2l.2-.3v.9M43.6 121.8h.5M44.5 121l.1-.1a.43 .43 0 0 1 .3 .5 .43 .43 0 0 1-.3 .4l-.2-.3z"/>
</g>
<path d="M69.6 190.6h2" fill="none" stroke="#910000" stroke-width=".25"/>
<path d="M88.2 124.6l.4 .2-.2 .2-.3-.2z" fill="#910000"/>
<path d="M88.2 124.6l.4 .2-.2 .2-.3-.2zM88.3 124.8v3.5h.6" fill="none" stroke="#910000" stroke-width=".21"/>
<path d="M91.1 124.6l.3 .2-.1 .2-.3-.2z" fill="#910000"/>
<path d="M88.9 127.9h1.7v.7h-1.7zM90.6 124.8h4.1M91.1 124.6l.3 .2-.1 .2-.3-.2zM91.2 124.8v1.1h.6M91.8 125.5h1.7v.7h-1.7zM93.5 125.9h.6v24.8" fill="none" stroke="#910000" stroke-width=".21"/>
<path d="M88.2 128.1l.3 .2-.1 .2-.3-.2z" fill="#910000"/>
<path d="M88.2 128.1l.4 .2-.2 .2-.3-.2zM88.3 128.3v3.5h.6" fill="none" stroke="#910000" stroke-width=".21"/>
<path d="M91.1 128.1l.3 .2-.1 .2-.3-.2z" fill="#910000"/>
<path d="M90.6 128.3h4.1M91.1 128.1l.3 .2-.1 .2-.3-.2zM91.2 128.3v1h.6M91.8 128.9h1.7v.7h-1.7zM93.5 129.3h.6v21.4" fill="none" stroke="#910000" stroke-width=".21"/>
<path d="M94 129.1l.3 .2-.1 .2-.3-.2z" fill="#910000"/>
<path d="M88.9 131.3h1.7v.8h-1.7zM94 129.1l.3 .2-.1 .2-.3-.2z" fill="none" stroke="#910000" stroke-width=".21"/>
<path d="M88.2 131.5l.3 .2-.1 .2-.3-.2z" fill="#910000"/>
<path d="M88.2 131.6l.4 .2-.2 .2-.3-.2zM88.3 131.8v3.4h.6" fill="none" stroke="#910000" stroke-width=".21"/>
<path d="M91.1 131.6l.3 .2-.1 .2-.3-.2z" fill="#910000"/>
<path d="M90.6 131.8h4.1M91.1 131.6l.3 .2-.1 .2-.3-.2zM91.2 131.8v1h.6M91.8 132.4h1.7v.7h-1.7zM93.5 132.8h.6v17.9" fill="none" stroke="#910000" stroke-width=".21"/>
<path d="M94 132.6l.3 .2-.1 .2-.3-.2z" fill="#910000"/>
<path d="M88.9 134.8h1.7v.7h-1.7zM94 132.6l.3 .2-.1 .2-.3-.2z" fill="none" stroke="#910000" stroke-width=".21"/>
<path d="M88.2 134.9l.3 .2-.1 .2-.3-.2z" fill="#910000"/>
<path d="M88.2 135l.4 .2-.2 .2-.3-.2zM88.3 135.2v3.4h.6" fill="none" stroke="#910000" stroke-width=".21"/>
<path d="M91.1 135l.3 .2-.1 .2-.3-.2z" fill="#910000"/>
<path d="M90.6 135.2h4.1M91.1 135l.3 .2-.1 .2-.3-.2zM91.2 135.2v1h.6M91.8 135.8h1.7v.8h-1.7zM93.5 136.2h.6v14.5" fill="none" stroke="#910000" stroke-width=".21"/>
<path d="M94 136l.3 .2-.1 .2-.3-.2z" fill="#910000"/>
<path d="M88.9 138.3h1.7v.6h-1.7zM94 136l.3 .2-.1 .2-.3-.2z" fill="none" stroke="#910000" stroke-width=".21"/>
<path d="M88.2 138.4l.3 .2-.1 .2-.3-.2z" fill="#910000"/>
<path d="M88.2 138.5l.4 .1-.2 .2-.3-.2zM88.3 138.6v3.5h.6M91.2 138.6v1.1h.6" fill="none" stroke="#910000" stroke-width=".21"/>
<path d="M91.1 138.5l.3 .1-.1 .2-.3-.2z" fill="#910000"/>
<path d="M90.6 138.6h4.1M91.1 138.5l.3 .1-.1 .2-.3-.2zM91.8 139.3h1.7v.7h-1.7zM93.5 139.7h.6v11" fill="none" stroke="#910000" stroke-width=".21"/>
<path d="M94 139.5l.3 .2-.1 .1-.3-.1z" fill="#910000"/>
<path d="M94 139.5l.3 .2-.1 .1-.3-.1zM88.3 142.1v3.4h.6M88.9 141.7h1.7v.7h-1.7z" fill="none" stroke="#910000" stroke-width=".21"/>
<path d="M88.2 141.9l.4 .2-.2 .2-.3-.2z" fill="#910000"/>
<path d="M88.2 141.9l.4 .2-.2 .2-.3-.2zM91.2 142.1v1h.6" fill="none" stroke="#910000" stroke-width=".21"/>
<path d="M91.1 141.9l.3 .2-.1 .2-.3-.2z" fill="#910000"/>
<path d="M90.6 142.1h4.1M91.1 141.9l.3 .2-.1 .2-.3-.2zM91.8 142.7h1.7v.7h-1.7zM93.5 143.1h.6v7.6" fill="none" stroke="#910000" stroke-width=".21"/>
<path d="M94 142.9l.3 .2-.1 .2-.3-.2z" fill="#910000"/>
<path d="M88.3 145.5v3.5h.6M88.9 145.1h1.7v.7h-1.7zM94 142.9l.3 .2-.1 .2-.3-.2z" fill="none" stroke="#910000" stroke-width=".21"/>
<path d="M88.2 145.3l.4 .2-.2 .2-.3-.2z" fill="#910000"/>
<path d="M88.2 145.3l.4 .2-.2 .2-.3-.2zM91.2 145.5v1.1h.6" fill="none" stroke="#910000" stroke-width=".21"/>
<path d="M91.1 145.3l.3 .2-.1 .2-.3-.2z" fill="#910000"/>
<path d="M90.6 145.5h4.1M91.1 145.3l.3 .2-.1 .2-.3-.2zM91.8 146.1h1.7v.8h-1.7zM93.5 146.6h.6v4.1" fill="none" stroke="#910000" stroke-width=".21"/>
<path d="M94 146.4l.3 .2-.1 .2-.3-.2z" fill="#910000"/>
<path d="M88.9 148.6h1.7v.7h-1.7zM91.2 149v1h.6M94 146.4l.3 .2-.1 .2-.3-.2z" fill="none" stroke="#910000" stroke-width=".21"/>
<path d="M91.1 148.8l.3 .2-.1 .2-.3-.2z" fill="#910000"/>
<path d="M90.6 149h4.1M91.1 148.8l.3 .2-.1 .2-.3-.2zM91.8 149.6h1.7v.7h-1.7zM93.5 150h.6v.7" fill="none" stroke="#910000" stroke-width=".21"/>
<path d="M94 149.8l.3 .2-.1 .2-.3-.2z" fill="#910000"/>
<g fill="none" stroke="#910000" stroke-width=".21">
<path d="M86.1 124.8h1.7M94.7 124.8h1.7M94.7 128.3h1.7M94.7 131.8h1.7M94.7 135.2h1.7M94.7 138.6h1.7M115.3 123.9h6.9v27.7h-6.9zM115.4 124.8h1.1M116.5 124.5h1.7v.6h-1.7zM86.1 150.7h8M94 149.8l.3 .2-.1 .2-.3-.2zM94.7 142.1h1.7"/>
<path d="M94.7 145.5h1.7M94.7 149h1.7"/>
</g>
<g fill="none" stroke="#b90000" stroke-width=".21">
<path d="M86.7 124l.2-.3v.9M86.7 124.6h.5M95.3 123.8l.3-.1 .2 .2-.5 .7h.5M95.3 127.2h.5l-.3 .3h.2l.1 .2-.1 .4-.4-.1M95.5 130.6l-.2 .6h.5M95.7 134.1h-.4v.4l.3-.1 .2 .4-.2 .2-.3-.1M95.7 137.5l-.4 .2v.6l.4 .1v-.5h-.3l-.1 .1M95.7 130.9v.6M86.2 149.8l.3-.2v.9M86.2 150.5h.5M87.2 149.6h.1a.59 .59 0 0 1 .1 .9 .53 .53 0 0 1-.2-.9zM95.3 141h.5l-.3 .9"/>
<path d="M95.5 144.8l-.2-.1v-.2l.3-.1 .2 .2-.5 .3v.3l.2 .1 .3-.1-.2-.4M95.8 148.2l-.1 .2h-.3l-.1-.4 .3-.1 .2 .1-.2 .7h-.2"/>
</g>
<g fill="none" stroke="#0f0f0f" stroke-width=".21">
<path d="M124.2 137.9h.3M124.7 137.5h-.5v.8h.5M124.9 137.5l.6 .8M125.5 137.5l-.6 .8M125.9 137.9h.4v-.4h-.4v.8M126.4 138.4h.7M127.4 137.5h.3l.1 .1v.4l-.3 .3h-.1zM128.1 137.7l.3-.2v.8M128.1 138.3h.5M129 137.5h.4l.1 .1-.5 .7h.5M113.9 158.5h.3M114.3 158.1h-.4v.9h.4"/>
<path d="M114.6 158.1l.6 .9M115.2 158.1l-.6 .9M115.5 158.5h.4v-.4h-.4v.9M116.1 159h.7M116.9 158.1l.3 .9 .3-.9M117.6 158.1h.5M117.9 158.1v.9M118.4 158.5h.3M118.8 158.1h-.4v.9h.4M119.2 158.5h.4l.1-.3-.5-.1v.9M119.4 158.5l.3 .5M120 159v-.9l.4 .6 .2-.6v.9"/>
<path d="M121 158.2l.4-.1 .1 .4-.6 .5h.6M124.2 144.7h.3M124.7 144.3h-.5v.9h.5M124.9 144.3l.6 .9M125.5 144.3l-.6 .9M125.9 144.7h.4l.1-.2-.2-.2h-.3v.9M126.4 145.2h.7M127.4 144.3l.4 .2-.1 .7h-.3zM128.1 144.6l.3-.3v.9M128.1 145.2h.5M129.2 144.3l-.2 .6h.5M129.4 144.6v.6"/>
<path d="M124.2 176.6h.3M124.2 169.7h.3M124.2 162.9h.3M124.7 176.1h-.5v1h.5M124.7 169.3h-.5v.8h.5M124.7 162.4h-.5v.9h.5M124.9 176.1l.6 1M124.9 169.3l.6 .8M124.9 162.4l.6 .9M125.5 176.1l-.6 1M125.5 169.3l-.6 .8M125.5 162.4l-.6 .9"/>
<path d="M125.9 176.7h.3l.2-.4-.2-.2h-.3v1M125.9 169.7h.4l.1-.2-.2-.2h-.3v.8M125.9 162.9h.4v-.5h-.4v.9M126.4 177.2h.7M126.4 170.2h.7M126.4 163.4h.7M127.2 177.1l.3-1 .3 1M127.2 170.1l.3-.8 .3 .8M127.2 163.3l.3-.9 .3 .9M127.3 176.8h.4M127.3 169.9h.4M127.3 163h.4"/>
<path d="M128 176.1h.6l-.4 .4 .4 .2v.2l-.2 .2-.4-.1M128 162.4h.6l-.4 .9M128.5 169.3h-.4v.4l.4-.1 .1 .2-.1 .3-.4-.1M124.2 186.9h.3M124.7 186.6h-.5v.8h.5M124.9 186.6l.6 .8M125.5 186.6l-.6 .8M125.9 187h.3l.2-.4h-.5v.8M126.4 187.5h.7M127.2 187.4l.3-.8 .3 .8M127.3 187.2h.4M128.2 186.9l-.1-.1v-.2h.4l.1 .1-.5 .3v.3l.1 .1 .4-.2-.2-.3"/>
</g>
<path d="M115.8 124.6l.4 .2-.2 .2-.3-.2z" fill="#910000"/>
<path d="M115.8 124.6l.4 .2-.2 .2-.3-.2zM115.9 124.8v3.5h.6" fill="none" stroke="#910000" stroke-width=".21"/>
<path d="M118.7 124.6l.3 .2-.1 .2-.3-.2z" fill="#910000"/>
<path d="M116.5 127.9h1.7v.7h-1.7zM118.2 124.8h4M118.7 124.6l.3 .2-.1 .2-.3-.2zM118.8 124.8v1.1h.5M119.3 125.5h1.8v.7h-1.8zM121.1 125.9h.5v24.8" fill="none" stroke="#910000" stroke-width=".21"/>
<path d="M115.8 128.1l.3 .2-.1 .2-.3-.2z" fill="#910000"/>
<path d="M115.8 128.1l.4 .2-.2 .2-.3-.2zM115.9 128.3v3.5h.6" fill="none" stroke="#910000" stroke-width=".21"/>
<path d="M118.7 128.1l.3 .2-.1 .2-.3-.2z" fill="#910000"/>
<path d="M118.2 128.3h4M118.7 128.1l.3 .2-.1 .2-.3-.2zM118.8 128.3v1h.5M119.3 128.9h1.8v.7h-1.8zM121.1 129.3h.5v21.4" fill="none" stroke="#910000" stroke-width=".21"/>
<path d="M121.5 129.1l.3 .2-.1 .2-.3-.2z" fill="#910000"/>
<path d="M116.5 131.3h1.7v.8h-1.7zM121.5 129.1l.3 .2-.1 .2-.3-.2z" fill="none" stroke="#910000" stroke-width=".21"/>
<path d="M115.8 131.5l.3 .2-.1 .2-.3-.2z" fill="#910000"/>
<path d="M115.8 131.6l.4 .2-.2 .2-.3-.2zM115.9 131.8v3.4h.6" fill="none" stroke="#910000" stroke-width=".21"/>
<path d="M118.7 131.6l.3 .2-.1 .2-.3-.2z" fill="#910000"/>
<path d="M118.2 131.8h4M118.7 131.6l.3 .2-.1 .2-.3-.2zM118.8 131.8v1h.5M119.3 132.4h1.8v.7h-1.8zM121.1 132.8h.5v17.9" fill="none" stroke="#910000" stroke-width=".21"/>
<path d="M121.5 132.6l.3 .2-.1 .2-.3-.2z" fill="#910000"/>
<path d="M116.5 134.8h1.7v.7h-1.7zM121.5 132.6l.3 .2-.1 .2-.3-.2z" fill="none" stroke="#910000" stroke-width=".21"/>
<path d="M115.8 134.9l.3 .2-.1 .2-.3-.2z" fill="#910000"/>
<path d="M115.8 135l.4 .2-.2 .2-.3-.2zM115.9 135.2v3.4h.6" fill="none" stroke="#910000" stroke-width=".21"/>
<path d="M118.7 135l.3 .2-.1 .2-.3-.2z" fill="#910000"/>
<path d="M118.2 135.2h4M118.7 135l.3 .2-.1 .2-.3-.2zM118.8 135.2v1h.5M119.3 135.8h1.8v.8h-1.8zM121.1 136.2h.5v14.5" fill="none" stroke="#910000" stroke-width=".21"/>
<path d="M121.5 136l.3 .2-.1 .2-.3-.2z" fill="#910000"/>
<path d="M116.5 138.3h1.7v.6h-1.7zM121.5 136l.3 .2-.1 .2-.3-.2z" fill="none" stroke="#910000" stroke-width=".21"/>
<path d="M115.8 138.4l.3 .2-.1 .2-.3-.2z" fill="#910000"/>
<path d="M115.8 138.5l.4 .1-.2 .2-.3-.2zM115.9 138.6v3.5h.6M118.8 138.6v1.1h.5" fill="none" stroke="#910000" stroke-width=".21"/>
<path d="M118.7 138.5l.3 .1-.1 .2-.3-.2z" fill="#910000"/>
<path d="M118.2 138.6h4M118.7 138.5l.3 .1-.1 .2-.3-.2zM119.3 139.3h1.8v.7h-1.8zM121.1 139.7h.5v11" fill="none" stroke="#910000" stroke-width=".21"/>
<path d="M121.5 139.5l.3 .2-.1 .1-.3-.1z" fill="#910000"/>
<path d="M121.5 139.5l.3 .2-.1 .1-.3-.1zM115.9 142.1v3.4h.6M116.5 141.7h1.7v.7h-1.7z" fill="none" stroke="#910000" stroke-width=".21"/>
<path d="M115.8 141.9l.4 .2-.2 .2-.3-.2z" fill="#910000"/>
<path d="M115.8 141.9l.4 .2-.2 .2-.3-.2zM118.8 142.1v1h.5" fill="none" stroke="#910000" stroke-width=".21"/>
<path d="M118.7 141.9l.3 .2-.1 .2-.3-.2z" fill="#910000"/>
<path d="M118.2 142.1h4M118.7 141.9l.3 .2-.1 .2-.3-.2zM119.3 142.7h1.8v.7h-1.8zM121.1 143.1h.5v7.6" fill="none" stroke="#910000" stroke-width=".21"/>
<path d="M121.5 142.9l.3 .2-.1 .2-.3-.2z" fill="#910000"/>
<path d="M115.9 145.5v3.5h.6M116.5 145.1h1.7v.7h-1.7zM121.5 142.9l.3 .2-.1 .2-.3-.2z" fill="none" stroke="#910000" stroke-width=".21"/>
<path d="M115.8 145.3l.4 .2-.2 .2-.3-.2z" fill="#910000"/>
<path d="M115.8 145.3l.4 .2-.2 .2-.3-.2zM118.8 145.5v1.1h.5" fill="none" stroke="#910000" stroke-width=".21"/>
<path d="M118.7 145.3l.3 .2-.1 .2-.3-.2z" fill="#910000"/>
<path d="M118.2 145.5h4M118.7 145.3l.3 .2-.1 .2-.3-.2zM119.3 146.1h1.8v.8h-1.8zM121.1 146.6h.5v4.1" fill="none" stroke="#910000" stroke-width=".21"/>
<path d="M121.5 146.4l.3 .2-.1 .2-.3-.2z" fill="#910000"/>
<path d="M116.5 148.6h1.7v.7h-1.7zM118.8 149v1h.5M121.5 146.4l.3 .2-.1 .2-.3-.2z" fill="none" stroke="#910000" stroke-width=".21"/>
<path d="M118.7 148.8l.3 .2-.1 .2-.3-.2z" fill="#910000"/>
<path d="M118.2 149h4M118.7 148.8l.3 .2-.1 .2-.3-.2zM119.3 149.6h1.8v.7h-1.8zM121.1 150h.5v.7" fill="none" stroke="#910000" stroke-width=".21"/>
<path d="M121.5 149.8l.3 .2-.1 .2-.3-.2z" fill="#910000"/>
<g fill="none" stroke="#910000" stroke-width=".21">
<path d="M113.7 124.8h1.7M122.2 124.8h1.8M122.2 128.3h1.8M122.2 131.8h1.8M122.2 135.2h1.8M122.2 138.6h1.8M113.7 150.7h7.9M121.5 149.8l.3 .2-.1 .2-.3-.2zM122.2 142.1h1.8M122.2 145.5h1.8M122.2 149h1.8M115.3 162.7h6.9v27.5h-6.9z"/>
<path d="M115.4 163.6h1.1M116.5 163.2h1.7v.7h-1.7z"/>
</g>
<g fill="none" stroke="#b90000" stroke-width=".21">
<path d="M114.3 124l.2-.3v.9M114.3 124.6h.5M122.8 127.2h.5l-.2 .3 .2 .1v.4h-.5M122.9 123.8h.4v.4l-.5 .4h.5M123.1 130.6l-.2 .6h.5M123.2 137.5l-.3 .2v.7l.4-.1-.1-.4h-.3v.1M123.2 130.9v.6M123.3 134.1h-.4v.4h.4v.4h-.4M113.8 149.8l.3-.2v.9M113.8 150.5h.5M114.8 149.6l.3 .1v.6l-.2 .2-.2-.2v-.6zM122.8 141h.6l-.4 .9"/>
<path d="M123 144.8l-.1-.3h.4v.2l-.4 .1 .1 .5 .3-.1v-.3l-.2-.1M123.3 148.2l-.1 .2h-.3v-.4h.4v.5l-.4 .2"/>
</g>
<g fill="none" stroke="#0f0f0f" stroke-width=".21">
<path d="M124.2 166.2h.3M124.2 173.2h.3M124.7 165.8h-.5v.9h.5M124.7 179.6h-.5v.9h.5M124.7 172.8h-.5v.8h.5M124.9 165.8l.6 .9M124.9 179.6l.6 .9M124.9 172.8l.6 .8M125.5 165.8l-.6 .9M125.5 179.6l-.6 .9M125.5 172.8l-.6 .8M125.9 166.3h.3l.2-.3-.2-.2h-.3v.9"/>
<path d="M125.9 173.2h.4v-.4h-.4v.8M126.4 166.8h.7M126.4 173.7h.7M127.2 166.7l.3-.9 .3 .9M127.2 173.6l.3-.8 .3 .8M127.3 166.5h.4M127.3 173.4h.4M128.1 179.7l.3-.1 .2 .3-.6 .6h.6M128.2 172.7l-.1 .7h.5M128.5 165.8l-.4 .1v.8h.3l.2-.1-.2-.4-.3 .1M128.5 173v.6M124.2 183.5h.3"/>
<path d="M124.2 180h.3M124.7 183.1h-.5v.8h.5M124.9 183.1l.6 .8M125.5 183.1l-.6 .8M125.9 183.5h.4v-.4h-.4v.8M125.9 180h.4l.1-.2-.2-.2h-.3v.9M126.4 184h.7M126.4 180.5h.7M127.2 183.9l.3-.8 .3 .8M127.2 180.5l.3-.9 .3 .9M127.3 183.7h.4M127.3 180.2h.4"/>
<path d="M128.1 183.3l.2-.2v.8M128.1 183.9h.5"/>
</g>
<path d="M115.8 163.4l.4 .2-.2 .2-.3-.2z" fill="#910000"/>
<path d="M115.8 163.4l.4 .2-.2 .2-.3-.2zM115.9 163.6v3.5h.6" fill="none" stroke="#910000" stroke-width=".21"/>
<path d="M118.7 163.4l.3 .2-.1 .2-.3-.2z" fill="#910000"/>
<path d="M116.5 166.7h1.7v.7h-1.7zM118.2 163.6h4M118.7 163.4l.3 .2-.1 .2-.3-.2zM118.8 163.6v1h.5M119.3 164.3h1.8v.6h-1.8zM121.1 164.6h.5v24.8" fill="none" stroke="#910000" stroke-width=".21"/>
<path d="M115.8 166.9l.3 .1-.1 .2-.3-.2z" fill="#910000"/>
<path d="M115.8 166.9l.4 .2-.2 .2-.3-.2zM115.9 167.1v3.4h.6" fill="none" stroke="#910000" stroke-width=".21"/>
<path d="M118.7 166.9l.3 .2-.1 .2-.3-.2z" fill="#910000"/>
<path d="M118.2 167.1h4M118.7 166.9l.3 .2-.1 .2-.3-.2zM118.8 167.1v1h.5M119.3 167.7h1.8v.7h-1.8zM121.1 168.1h.5v21.3" fill="none" stroke="#910000" stroke-width=".21"/>
<path d="M121.5 167.9l.3 .2-.1 .2-.3-.2z" fill="#910000"/>
<path d="M116.5 170.1h1.7v.7h-1.7zM121.5 167.9l.3 .2-.1 .2-.3-.2z" fill="none" stroke="#910000" stroke-width=".21"/>
<path d="M115.8 170.2l.3 .2-.1 .2-.3-.2z" fill="#910000"/>
<path d="M115.8 170.3l.4 .2-.2 .2-.3-.2zM115.9 170.5v3.4h.6" fill="none" stroke="#910000" stroke-width=".21"/>
<path d="M118.7 170.3l.3 .2-.1 .2-.3-.2z" fill="#910000"/>
<path d="M118.2 170.5h4M118.7 170.3l.3 .2-.1 .2-.3-.2zM118.8 170.5v1.1h.5M119.3 171.1h1.8v.8h-1.8zM121.1 171.6h.5v17.8" fill="none" stroke="#910000" stroke-width=".21"/>
<path d="M121.5 171.4l.3 .2-.1 .2-.3-.2z" fill="#910000"/>
<path d="M116.5 173.6h1.7v.6h-1.7zM121.5 171.4l.3 .2-.1 .2-.3-.2z" fill="none" stroke="#910000" stroke-width=".21"/>
<path d="M115.8 173.7l.3 .2-.1 .2-.3-.2z" fill="#910000"/>
<path d="M115.8 173.8l.4 .1-.2 .2-.3-.2zM115.9 173.9v3.5h.6" fill="none" stroke="#910000" stroke-width=".21"/>
<path d="M118.7 173.8l.3 .1-.1 .2-.3-.2z" fill="#910000"/>
<path d="M118.2 173.9h4M118.7 173.8l.3 .1-.1 .2-.3-.2zM118.8 173.9v1.1h.5M119.3 174.6h1.8v.7h-1.8zM121.1 175h.5v14.4" fill="none" stroke="#910000" stroke-width=".21"/>
<path d="M121.5 174.8l.3 .2-.1 .1-.3-.1z" fill="#910000"/>
<path d="M116.5 177h1.7v.7h-1.7zM121.5 174.8l.3 .2-.1 .1-.3-.1z" fill="none" stroke="#910000" stroke-width=".21"/>
<path d="M115.8 177.2l.3 .2-.1 .2-.3-.2z" fill="#910000"/>
<path d="M115.8 177.2l.4 .2-.2 .2-.3-.2zM115.9 177.4v3.4h.6M118.8 177.4v1h.5" fill="none" stroke="#910000" stroke-width=".21"/>
<path d="M118.7 177.2l.3 .2-.1 .2-.3-.2z" fill="#910000"/>
<path d="M118.2 177.4h4M118.7 177.2l.3 .2-.1 .2-.3-.2zM119.3 178.1h1.8v.6h-1.8zM121.1 178.4h.5v11" fill="none" stroke="#910000" stroke-width=".21"/>
<path d="M121.5 178.2l.3 .2-.1 .2-.3-.2z" fill="#910000"/>
<path d="M121.5 178.2l.3 .2-.1 .2-.3-.2zM115.9 180.8v3.5h.6M116.5 180.4h1.7v.7h-1.7z" fill="none" stroke="#910000" stroke-width=".21"/>
<path d="M115.8 180.6l.4 .2-.2 .2-.3-.2z" fill="#910000"/>
<path d="M115.8 180.6l.4 .2-.2 .2-.3-.2zM118.8 180.8v1.1h.5" fill="none" stroke="#910000" stroke-width=".21"/>
<path d="M118.7 180.6l.3 .2-.1 .2-.3-.2z" fill="#910000"/>
<path d="M118.2 180.8h4M118.7 180.6l.3 .2-.1 .2-.3-.2zM119.3 181.5h1.8v.7h-1.8zM121.1 181.9h.5v7.5" fill="none" stroke="#910000" stroke-width=".21"/>
<path d="M121.5 181.7l.3 .2-.1 .2-.3-.2z" fill="#910000"/>
<path d="M115.9 184.3v3.4h.6M116.5 183.9h1.7v.7h-1.7zM121.5 181.7l.3 .2-.1 .2-.3-.2z" fill="none" stroke="#910000" stroke-width=".21"/>
<path d="M115.8 184.1l.4 .2-.2 .2-.3-.2z" fill="#910000"/>
<path d="M115.8 184.1l.4 .2-.2 .2-.3-.2zM118.8 184.3v1h.5" fill="none" stroke="#910000" stroke-width=".21"/>
<path d="M118.7 184.1l.3 .2-.1 .2-.3-.2z" fill="#910000"/>
<path d="M118.2 184.3h4M118.7 184.1l.3 .2-.1 .2-.3-.2zM119.3 184.9h1.8v.7h-1.8zM121.1 185.3h.5v4.1" fill="none" stroke="#910000" stroke-width=".21"/>
<path d="M121.5 185.1l.3 .2-.1 .2-.3-.2z" fill="#910000"/>
<path d="M116.5 187.4h1.7v.6h-1.7zM118.8 187.7v1.1h.5M121.5 185.1l.3 .2-.1 .2-.3-.2z" fill="none" stroke="#910000" stroke-width=".21"/>
<path d="M118.7 187.6l.3 .1-.1 .2-.3-.2z" fill="#910000"/>
<path d="M118.2 187.7h4M118.7 187.6l.3 .1-.1 .2-.3-.2zM119.3 188.4h1.8v.7h-1.8zM121.1 188.8h.5v.6" fill="none" stroke="#910000" stroke-width=".21"/>
<path d="M121.5 188.6l.3 .2-.1 .1-.3-.1z" fill="#910000"/>
<g fill="none" stroke="#910000" stroke-width=".21">
<path d="M156.7 26.6h2.6M156.7 28.4h2.6M156.7 30.1h2.6M156.7 31.9h2.6M156.7 33.6h2.6M156.7 35.3h2.6M156.7 37h2.6M156.7 38.7h2.6M159.3 25.7h3.3v55.2h-3.3zM159.3 26.5h.8v.3h-.8zM159.3 28.3h.8v.2h-.8zM159.3 30h.8v.2h-.8z"/>
<path d="M159.3 31.8h.8v.2h-.8zM159.3 33.5h.8v.2h-.8zM159.3 35.2h.8v.1h-.8zM159.3 37h.8v.1h-.8zM159.3 38.6h.8v.2h-.8zM161.8 26.5h.9v.3h-.9zM161.8 28.3h.9v.2h-.9zM161.8 30h.9v.2h-.9zM161.8 31.8h.9v.2h-.9zM161.8 33.5h.9v.2h-.9zM161.8 35.2h.9v.1h-.9zM161.8 37h.9v.1h-.9z"/>
<path d="M161.8 38.6h.9v.2h-.9zM162.7 26.6h2.6M162.7 28.4h2.6M162.7 30.1h2.6M162.7 31.9h2.6M162.7 33.6h2.6M162.7 35.3h2.6M162.7 37h2.6M162.7 38.7h2.6M169.6 39.6h.9v-.9l.8 .9-.8 .8v-.8M169.6 39.6h.1M177.3 26.6h1.8"/>
<path d="M177.3 28.4h1.8M177.3 30.1h1.8M177.3 31.9h1.8M177.3 33.6h1.8M177.3 35.3h1.8M177.3 37h1.8M177.3 38.7h1.8M227.2 27.6h2.6l.8 .8-.8 .8h-2.6l-.8-.8zM227.2 25.8h2.6l.8 .8-.8 1h-2.6l-.8-1zM227.7 28a.47 .47 0 0 1 .5 .3 .47 .47 0 0 1-.2 .5h-.3zM227.7 26.3h.3a.47 .47 0 0 1 .2 .5 .47 .47 0 0 1-.5 .3zM228.6 26.6v-.3h.3l.1 .2-.4 .2v.4l.4-.1v-.3l-.2-.1"/>
<path d="M229 28.3l-.1 .2h-.3v-.4h.4v.6l-.4 .1M150.7 57.7v-.8l-.9 .8 .9 .8v-.8h.8M151.5 57.7h.1M156.7 43.9h2.6M156.7 45.6h2.6M156.7 40.4h2.6M156.7 42.2h2.6M156.7 47.4h2.6M156.7 49.1h2.6M156.7 50.8h2.6M156.7 52.5h2.6M156.7 54.2h2.6"/>
<path d="M156.7 55.9h2.6M156.7 57.7h2.6M156.7 59.4h2.6M159.3 40.3h.8v.2h-.8zM159.3 42.1h.8v.2h-.8zM159.3 43.8h.8v.2h-.8zM159.3 45.5h.8v.2h-.8zM159.3 47.3h.8v.2h-.8zM159.3 49h.8v.1h-.8zM159.3 50.7h.8v.1h-.8zM159.3 52.4h.8v.2h-.8zM159.3 54.1h.8v.2h-.8z"/>
<path d="M159.3 55.8h.8v.2h-.8zM159.3 57.6h.8v.2h-.8zM159.3 59.3h.8v.2h-.8zM161.8 40.3h.9v.2h-.9zM161.8 42.1h.9v.2h-.9zM161.8 43.8h.9v.2h-.9zM161.8 45.5h.9v.2h-.9zM161.8 47.3h.9v.2h-.9zM161.8 49h.9v.1h-.9zM161.8 50.7h.9v.1h-.9zM161.8 52.4h.9v.2h-.9zM161.8 54.1h.9v.2h-.9z"/>
<path d="M161.8 55.8h.9v.2h-.9zM161.8 57.6h.9v.2h-.9zM161.8 59.3h.9v.2h-.9zM162.7 43.9h2.6M162.7 45.6h2.6M162.7 40.4h2.6M162.7 42.2h2.6M162.7 47.4h2.6M162.7 49.1h2.6M162.7 50.8h2.6M162.7 52.5h2.6M162.7 54.2h2.6"/>
<path d="M162.7 55.9h2.6M162.7 57.7h2.6M162.7 59.4h2.6M165.3 43h7.4l.7 .9-.7 .8h-7.4zM165.8 43.2h6.3M165.9 43.9h.3M166.1 44.7h4.8v1.7h-4.8l-.8-.8zM166.3 43.5h-.4v.8h.4M166.4 45h3.7M166.6 45.7l.4-.1v-.3l-.4-.1v.9M166.6 43.5l.6 .8M166.7 45.7l.3 .4"/>
<path d="M167.2 43.5l-.6 .8M167.4 45.6h.3M167.5 43.9h.4l.1-.3-.2-.1h-.3v.8M167.8 45.2h-.4v.9h.4M168.2 44.4h.6M168.6 45.3l-.3-.1-.2 .1 .1 .3 .4 .2v.2h-.5M169 43.9h.4l.1-.3-.5-.1v.8h.5v-.2l-.2-.2M169 45.6h.3M169.4 45.2h-.4v.9h.4M169.6 45.2h.5M169.9 43.9h.2M169.9 45.2v.9"/>
<path d="M170.3 43.5h-.4v.8h.4M170.6 43.9h.5l.1-.3-.2-.1h-.4v.8M170.9 43.9l.3 .4M171.5 43.9h.5v-.3l-.5-.1v.8M171.7 43.9l.3 .4M177.3 43.9h1.8M177.3 45.6h1.8M177.3 40.4h1.8M177.3 42.2h1.8M177.3 47.4h1.8M177.3 49.1h1.8M177.3 50.8h1.8"/>
<path d="M177.3 52.5h1.8M177.3 54.2h1.8M177.3 55.9h1.8M177.3 57.7h1.8M177.3 59.4h1.8M184.3 59.4h.8v-.9l.9 .9-.9 .8v-.8M184.3 59.4h.1M204.8 41.3h3.7l.8 .9-.8 .8h-3.7zM205.6 42.2h.4l.1-.3-.5-.1v.8M205.9 42.2l.2 .4M207.1 41.7l-.7 1.1M207.3 41.8l.3 .8 .1-.6 .2 .6 .2-.8"/>
<path d="M207.3 41.5h.8M217.8 49.1v.8h.9l-.9 .9-.8-.9h.8M217.8 49.1h.1M156.7 61.1h2.6M156.7 62.9h2.6M156.7 64.6h2.6M156.7 66.2h2.6M156.7 68h2.6M156.7 69.7h2.6M156.7 71.4h2.6M156.7 73.2h2.6M156.7 74.9h2.6"/>
<path d="M156.7 76.7h2.6M156.7 78.4h2.6M159.3 61h.8v.2h-.8zM159.3 62.8h.8v.1h-.8zM159.3 64.5h.8v.1h-.8zM159.3 66.2h.8v.1h-.8zM159.3 67.9h.8v.2h-.8zM159.3 69.6h.8v.2h-.8zM159.3 71.3h.8v.2h-.8zM159.3 73.1h.8v.2h-.8zM159.3 74.8h.8v.2h-.8zM159.3 76.5h.8v.2h-.8z"/>
<path d="M159.3 78.3h.8v.1h-.8zM159.3 80h.8v.1h-.8zM161.8 61h.9v.2h-.9zM161.8 62.8h.9v.1h-.9zM161.8 64.5h.9v.1h-.9zM161.8 66.2h.9v.1h-.9zM161.8 67.9h.9v.2h-.9zM161.8 69.6h.9v.2h-.9zM161.8 71.3h.9v.2h-.9zM161.8 73.1h.9v.2h-.9zM161.8 74.8h.9v.2h-.9zM161.8 76.5h.9v.2h-.9z"/>
<path d="M161.8 78.3h.9v.1h-.9zM161.8 80h.9v.1h-.9zM162.7 61.1h2.6M162.7 62.9h2.6M162.7 64.6h2.6M162.7 66.2h2.6M162.7 68h2.6M162.7 69.7h2.6M162.7 71.4h2.6M162.7 73.2h2.6M162.7 74.9h2.6M162.7 76.7h2.6"/>
<path d="M162.7 78.4h2.6M170.5 78.4h.1M170.5 78.4h1.7M171.3 77.8l.9 .6M171.3 79.5l.9 .5M172.2 78.4l-.9 .5M177.3 61.1h1.8M177.3 62.9h1.8M177.3 64.6h1.8M177.3 66.2h1.8M177.3 68h1.8M177.3 69.7h1.8"/>
<path d="M177.3 71.4h1.8M177.3 73.2h1.8M177.3 74.9h1.8M177.3 76.7h1.8M177.3 78.4h1.8M179.9 62h3.3l.7 .9-.7 .8h-3.3l-.8-.8zM179.9 60.2h3.2v1.8h-3.2l-.8-.9zM180 72.3h3.9l.7 .9-.7 .8h-3.9zM180 68.9h3.9l.7 .8-.7 .9h-3.9zM180.4 72.5h2.9M180.4 69.1h2.9M180.5 69.3v.8"/>
<path d="M180.5 72.8v.8M180.8 62.4l-.5 .1v.3l.5 .2-.1 .3h-.4M180.8 60.7l-.5 .1v.2l.4 .2 .1 .2-.2 .2-.3-.1M181 73.2h.4l.1-.3-.2-.1h-.3v.8M181 69.8h.3l.2-.3-.2-.2h-.3v.8M181.1 62.4l.5 .1v.4l-.1 .4h-.4zM181.1 73.2l.4 .4M181.1 69.8l.4 .3M181.6 60.8l-.4-.1-.1 .2 .1 .6h.4M181.8 72.9h.5l-.1 .7-.4-.1zM181.8 69.5l.2-.2 .3 .2-.1 .6h-.4zM181.9 73.4l.5 .3"/>
<path d="M181.9 63.3l.3-.9 .3 .9M181.9 70l.5 .2M182 60.7v.9h.4M182 63h.4M182.7 72.8h.5l-.4 .3h.3l.1 .2-.1 .3-.4-.1M183.1 69.3h-.4v.4l.3-.1 .2 .5h-.5M184.3 64.6h.8v-.9l.9 .9-.9 .8v-.8M184.3 64.6h.1M184.3 79.5l.8 .5M185.1 77.5h5l.8 .9-.8 .8h-5zM185.1 67.2h3.9l.8 .8-.8 .9h-3.9zM185.1 70.6h3.9l.8 .8-.8 .9h-3.9z"/>
<path d="M185.6 67.3h2.8M185.6 70.8h2.8M185.7 78.4h.7M185.7 67.6v.8M185.7 71.1v.8M186.1 78.1v.7M186.1 68h.5v-.4h-.5v.8M186.1 71.5h.5v-.4h-.5v.8M186.3 68l.3 .4M186.3 71.5l.3 .4M187 71.2h.5v.6l-.2 .1a.47 .47 0 0 1-.4-.3 .47 .47 0 0 1 .1-.4zM187.1 68.3l.5 .2"/>
<path d="M187.1 67.6l.4 .1-.1 .7h-.3l-.2-.2zM187.1 71.7l.5 .3M187.2 77.9h-.4l-.1 .5 .5-.1v.5l-.5-.1M187.5 77.9l.2 .9 .4-.9M188.1 71l-.3 .6h.5M188.3 67.6h-.3l-.2 .3 .1 .5h.4v-.5h-.4l-.1 .2M188.3 71.3v.6M188.6 78.3l-.2-.1-.1 .2 .4 .3-.4 .1M189 77.9v.9h.4v-.5h-.4M225.9 69.3h1v2.5h-1zM225.9 64.2h1v2.4h-1zM226.4 62.9h.1"/>
<path d="M226.4 61.1v1.8M226.4 63.7v.5M226.4 66.7v.5M226.4 68.9v.5M226.4 71.8v.5M226.4 61.1l-.5 .9M226.4 61.1l.5 .9M156.7 80h2.6M162.7 80h2.6M170.5 80h.1M170.5 80h1.7M172.2 80l-.9 .6"/>
<path d="M177.3 80h1.8M183.4 80h.1M183.4 80h1.7M185.1 80l-.8 .6M241.9 87.8h1.8M241.9 91.2h1.8M243.7 86l6.8 3.5-6.8 3.5zM250.6 89.5h1.7M57 112h3.3l.8 .8-.8 .9h-3.3zM57.8 112.1h2.2M57.9 112.4v.8h.4M58.5 112.4h.4l.2 .2v.5l-.2 .1h-.4z"/>
<path d="M59.9 112.4l-.5 .1v.2l.5 .3-.1 .2h-.4M61.1 112.8h2.9M61.1 116.2h2.9M63.7 111.9a4.5 4.5 0 0 1 0 5.2M63.7 111.9h2.1M65.8 112a3.5 3.5 0 0 1 3 2.5M68.8 114.5a3.6 3.6 0 0 1-3 2.6h-2.1M68.9 114.5h2.5M93.8 108.5h.1M93.8 106.8l-.5 .9M93.8 106.8l.6 .9M93.8 106.8v1.7"/>
<path d="M97.5 104.2h2.4l.8 .8-.8 .9h-2.4zM98.2 105.5l.3-.9 .3 .9M98.3 105.3h.4M99.2 105l-.2-.1v-.2l.4-.1 .1 .3-.5 .2v.3l.2 .1 .3-.1-.1-.4M109.3 115.4v.8h.9l-.9 .9-.9-.9h.9M109.3 115.4h.1M125.7 108.5h.1M125.7 106.8l-.5 .9M125.7 106.8l.5 .9M125.7 106.8v1.7M129.3 104.2h2.5l.7 .8-.7 .9h-2.5zM130.1 105.5l.2-.9 .3 .9"/>
<path d="M130.2 105.3h.3M131.4 105l-.4 .2-.2-.4 .2-.2 .4 .1-.1 .7-.4 .1M141.2 115.4v.8h.8l-.8 .9-.9-.9h.9M141.2 115.4h.1M42.1 138.6l-.5 .9M42.1 138.6l.5 .9M42.1 138.6v2.2M53.7 122.3h6.6l.8 .8-.8 .9h-6.6zM55.1 122.8a.44 .44 0 0 0-.7 .2 .44 .44 0 0 0 .2 .6l.5-.1M55.4 123.1h.4l.1-.2-.2-.2h-.3v.9M56.3 122.7v.9l.5-.1v-.8M56.9 123.7h.7"/>
<path d="M58.3 122.8l-.2-.1a.48 .48 0 0 0-.3 .4 .48 .48 0 0 0 .2 .5l.3-.1M58.7 122.7v.9h.4M59.4 122.7v.9M59.5 123.1l.4 .5M59.9 122.7l-.5 .5M61 139.4h6.9v10.4h-6.9zM61.1 123.1h2.9M61.1 126.6h2.9M63.7 122.2a4.5 4.5 0 0 1 0 5.2M63.7 122.3h2.1M64.6 136h.1M64.6 134.3v5.2"/>
<path d="M64.6 134.3l-.6 .9M64.6 134.3l.5 .9M65.8 122.3a3.5 3.5 0 0 1 3 2.6M68.8 124.8a3.6 3.6 0 0 1-3 2.6h-2.1M68.9 124.8h2.5M41.6 140.8h1v2.5h-1zM42.1 140.3h.1M42.1 153.3h.1M42.1 143.3v.5M42.1 151.6v1.7M42.1 151.6l-.5 .8M42.1 151.6l.5 .8"/>
<path d="M64.6 149.8v3.5M29.2 163.6v-.8l-.9 .8 .9 .9v-.9h.9M30.1 163.6h.1M30.4 176.1h1v2.5h-1zM30.4 164.9h1v2.5h-1zM30.9 175.6h.1M30.9 173.9l-.5 .9M30.9 173.9l.6 .9M30.9 164.5v.5M30.9 167.4v.5M30.9 173.9v2.2M30.9 178.6v.5"/>
<path d="M42.4 164.9h1v2.5h-1zM43 164.5h.1M43 162.8l-.5 .8M43 162.8l.5 .8M43 162.8v2.2M43 167.4v.5M113.7 163.6h1.7M122.2 163.6h1.8M122.2 167.1h1.8M122.2 170.5h1.8M122.2 173.9h1.8M122.2 177.4h1.8"/>
<path d="M18.6 189.9h2.1M19.8 192.1v.8h.8l-.8 .9-.9-.9h.9M19.8 192.1h.1M19.8 188.6h.1M19.8 186.9v3M19.8 190.6v1.5M19.8 186.9l-.5 .8M19.8 186.9l.5 .8M27.3 189.9h2.1M28.3 188.6v1.3M28.3 190.6v1.5M35.9 189.9h2"/>
<path d="M37 188.6v1.3M37 190.6v1.5M43.7 189.9h2M44.7 188.6v1.3M44.7 190.6v1.5M52.2 189.9h2.2M53.3 188.6v1.3M53.3 190.6v1.5M60.9 189.9h2M61.9 188.6v1.3M61.9 190.6v1.5M113.7 189.4h7.9"/>
<path d="M121.5 188.6l.3 .2-.1 .1-.3-.1zM122.2 180.8h1.8M122.2 184.3h1.8M122.2 187.7h1.8"/>
</g>
<g fill="none" stroke="#b90000" stroke-width=".21">
<path d="M157.3 25.9h.5v.6M157.3 27.6h.3l.2 .1v.4h-.5l.1-.3h.4M157.3 29.3l.5 .1v.4h-.5v-.2l.5-.1M157.3 31l.5 .1v.5M157.3 32.8l.3-.1 .2 .2v.4h-.5l.1-.3h.4M157.3 34.5l.5 .1v.4h-.5v-.2l.5-.1M157.3 36.3l.3-.1 .2 .2v.4M157.3 38l.3-.1 .2 .2v.4h-.5l.1-.4h.4M157.3 39.7h.5v.6M157.8 26l-.5 .1 .1 .4 .4-.1M157.8 31.2l-.5 .1 .1 .3 .4-.1M157.8 36.4h-.5l.1 .4 .4-.1"/>
<path d="M157.8 39.8l-.5 .1 .1 .4 .4-.1M158.1 25.8l.3-.2v.9M158.1 27.4l.4-.1 .1 .2-.5 .6h.5M158.1 29h.5l-.2 .3 .2 .2v.3h-.5M158.1 35.9h.5l-.3 .9M158.1 26.5h.5M158.3 38l-.2-.2 .1-.2h.3v.4l-.4 .1 .1 .4h.3l.1-.4-.1-.1M158.4 30.7l-.3 .6h.5M158.5 32.5h-.3l-.1 .4 .4-.1v.5l-.4-.1M158.5 34.2h-.2l-.2 .7h.5l-.1-.4-.4 .2M158.5 31v.6M158.6 39.7l-.3 .2-.2-.4 .2-.2 .3 .2-.1 .7-.3 .1"/>
<path d="M163.8 25.9h-.4v.1l.1 .5 .3-.1M163.8 27.6h-.3l-.1 .1v.4h.4M163.8 29.3h-.4v.2v.3h.4M163.8 31h-.4v.2l.1 .4 .3-.1M163.8 32.8l-.3-.1-.1 .2v.4h.4M163.8 34.5h-.4v.2v.3h.4M163.8 36.3l-.3-.1-.1 .2 .1 .4 .3-.1M163.8 38l-.3-.1-.1 .2v.4h.4M163.8 39.7h-.4v.1l.1 .5 .3-.1M164.1 25.8l.3-.2v.9M164.1 27.4l.4-.1 .1 .2-.5 .6h.5M164.1 29h.5l-.2 .3 .2 .2v.3h-.5"/>
<path d="M164.1 35.9h.5l-.3 .9M164.1 26.5h.5M164.3 38l-.2-.2 .1-.2h.3v.4l-.4 .1 .1 .4h.3l.1-.4-.1-.1M164.4 30.7l-.3 .6h.5M164.5 32.5h-.3l-.1 .4 .4-.1v.5l-.4-.1M164.5 34.2h-.2l-.2 .7h.5l-.1-.4-.4 .2M164.5 31v.6M164.6 39.7l-.3 .2-.2-.4 .2-.2 .3 .2-.1 .7-.3 .1M177.6 25.9h.4v.5h-.4M177.6 27.3v.8h.3l.1-.5h-.4M177.6 29v.8h.3l.1-.4-.4-.1M177.6 31l.4 .1v.4h-.4"/>
<path d="M177.6 32.5v.8h.3l.1-.5h-.4M177.6 34.2v.8h.4v-.4l-.4-.1M177.6 36.3h.4v.4h-.4M177.6 37.6v.9h.3l.1-.5h-.4M177.6 39.7h.4v.5h-.4M177.6 25.6v.9M177.6 30.8v.8M177.6 35.9v.9M177.6 39.3v1M178.3 25.8l.3-.2v.9M178.3 27.4h.6v.2l-.6 .5h.6M178.3 29h.6l-.3 .3 .3 .1v.4h-.6"/>
<path d="M178.3 35.9h.6l-.4 .9M178.3 26.5h.6M178.5 38l-.2-.2 .1-.2 .5 .1-.1 .3-.5 .1 .1 .4 .5-.1v-.3l-.2-.1M178.6 30.7l-.3 .6h.6M178.8 34.2h-.3l-.2 .7 .6 .1v-.4l-.4-.1-.2 .2M178.8 31v.6M178.9 32.5h-.5l-.1 .4 .5-.1 .1 .4h-.6M178.9 39.7l-.4 .2-.2-.4 .2-.2 .4 .1v.6l-.5 .3M157 41.4h.2l.1 .1v.4M157 43.1l.2-.1 .1 .2v.4h-.3l-.1-.1 .2-.2h.2M157 44.8l.3 .1v.5M157 46.6l.2-.1 .1 .2v.4"/>
<path d="M157 48.3l.2-.1 .1 .2v.4h-.3l-.1-.2 .2-.1h.2M157 50l.3 .1v.5M157 51.8l.2-.1 .1 .2v.4M157 53.5h.3v.5h-.3l-.1-.2 .2-.2h.2M157 55.2h.3v.5M157 56.9h.2l.1 .1v.4M157 58.6l.3 .1v.4h-.3l-.1-.1 .4-.2M157.3 41.6l-.4 .1 .2 .2h.2M157.3 45l-.4 .2 .2 .2 .2-.1M157.3 46.8l-.4 .1 .2 .2 .2-.1M157.3 50.2l-.4 .1 .2 .3 .2-.1M157.3 51.9l-.4 .2 .2 .2 .2-.1"/>
<path d="M157.3 55.3l-.4 .2 .2 .2h.2M157.3 57.1l-.4 .2 .2 .1h.2M157.7 41.4l.2-.3v.8M157.7 43l.2-.2v.8M157.7 44.7l.2-.2v.9M157.7 46.5l.2-.2v.8M157.7 48.2l.2-.2v.8M157.7 49.9l.2-.2v.9M157.7 51.7l.2-.3v.9M157.7 53.4l.2-.3v.9M157.7 55.1l.2-.3v.9M157.7 56.9l.2-.3v.8"/>
<path d="M157.7 58.4h.5v.3l-.5 .4h.5M157.7 41.9h.5M157.7 43.6h.5M157.7 45.4h.5M157.7 47.1h.5M157.7 48.8h.5M157.7 50.6h.5M157.7 52.3h.5M157.7 54h.5M157.7 55.7h.5M157.7 57.4h.5M158.5 46.3h.5l-.3 .3h.3v.3l-.1 .2-.4-.1"/>
<path d="M158.5 53.1h.5l-.3 .9M158.5 43l.3-.2v.8M158.5 44.6l.4-.1 .1 .2-.5 .7h.5M158.5 43.6h.5M158.6 41.1a.43 .43 0 0 1 .5 .4 .43 .43 0 0 1-.4 .4l-.2-.1zM158.7 48l-.2 .6h.5M158.7 55.2h-.2v-.3l.4-.1 .1 .3-.5 .2v.4h.2l.3-.1-.1-.4M158.7 58.3a.43 .43 0 0 1 .3 .5 .43 .43 0 0 1-.4 .3l-.1-.6zM159 49.7h-.5v.4l.4-.1 .1 .4-.1 .2-.4-.1M159 51.4l-.5 .2v.6l.4 .1 .1-.2v-.3h-.4l-.1 .1M159 48.2v.6M159 56.9v.2h-.4l-.1-.4 .5-.1v.2v.5l-.4 .1"/>
<path d="M163.4 41.4h-.4v.5h.4M163.4 43.1h-.4v.5h.4M163.4 44.8h-.4v.5h.4M163.4 46.6h-.4v.4h.4M163.4 48.3h-.4v.5h.4M163.4 50h-.4v.5h.4M163.4 51.8h-.4v.4h.4M163.4 53.5h-.4v.5h.4M163.4 55.2h-.4v.5h.4M163.4 56.9h-.4v.5h.4M163.4 58.6h-.4v.5h.4M163.7 41.4l.3-.3v.8"/>
<path d="M163.7 43l.3-.2v.8M163.7 44.7l.3-.2v.9M163.7 46.5l.3-.2v.8M163.7 48.2l.3-.2v.8M163.7 49.9l.3-.2v.9M163.7 51.7l.3-.3v.9M163.7 53.4l.3-.3v.9M163.7 55.1l.3-.3v.9M163.7 56.9l.3-.3v.8M163.7 58.4h.5v.3l-.5 .4h.5M163.7 41.9h.5M163.7 43.6h.5"/>
<path d="M163.7 45.4h.5M163.7 47.1h.5M163.7 48.8h.5M163.7 50.6h.5M163.7 52.3h.5M163.7 54h.5M163.7 55.7h.5M163.7 57.4h.5M164.5 46.3h.6l-.4 .3h.3l.1 .3-.2 .2-.4-.1M164.5 53.1h.6l-.4 .9M164.5 43l.3-.2v.8M164.5 44.6l.4-.1 .2 .2-.6 .7h.6"/>
<path d="M164.5 43.6h.6M164.6 41.1a.43 .43 0 0 1 .5 .4 .43 .43 0 0 1-.4 .4l-.2-.1zM164.7 48l-.2 .6h.6M164.7 55.2h-.2v-.3l.4-.1 .2 .3-.6 .2v.4h.2l.4-.1-.2-.4M164.7 58.3a.43 .43 0 0 1 .4 .5 .43 .43 0 0 1-.5 .3l-.1-.6zM165 49.7h-.5v.4l.4-.1 .2 .4-.2 .2-.4-.1M165 51.4l-.5 .2v.6l.4 .1 .2-.2-.1-.3h-.4l-.1 .1M165 48.2v.6M165.1 56.9l-.1 .2h-.4l-.1-.4 .5-.1 .1 .2-.1 .5-.4 .1M177.2 41.4h.4v.5h-.4M177.2 42.8v.8h.3l.1-.5h-.4M177.2 44.8l.4 .1v.4h-.4"/>
<path d="M177.2 46.6h.4v.4h-.4M177.2 48v.8h.3l.1-.5h-.4M177.2 50l.4 .1v.4h-.4M177.2 51.8h.4v.4h-.4M177.2 53.1v.9h.3l.1-.5h-.4M177.2 55.2h.4v.5h-.4M177.2 56.9h.4v.5h-.4M177.2 58.3v.8h.3l.1-.4-.4-.1M177.2 41.1v.8M177.2 44.5v.9M177.2 46.3v.8M177.2 49.7v.9"/>
<path d="M177.2 51.4v.9M177.2 54.8v.9M177.2 56.6v.8M177.2 60v.9M177.9 41.4l.3-.3v.8M177.9 43l.3-.2v.8M177.9 44.7l.3-.2v.9M177.9 46.5l.3-.2v.8M177.9 48.2l.3-.2v.8M177.9 49.9l.3-.2v.9M177.9 51.7l.3-.3v.9M177.9 53.4l.3-.3v.9"/>
<path d="M177.9 55.1l.3-.3v.9M177.9 56.9l.3-.3v.8M177.9 58.4h.5v.3l-.5 .4h.5M177.9 41.9h.5M177.9 43.6h.5M177.9 45.4h.5M177.9 47.1h.5M177.9 48.8h.5M177.9 50.6h.5M177.9 52.3h.5M177.9 54h.5M177.9 55.7h.5"/>
<path d="M177.9 57.4h.5M178.8 43l.2-.2v.8M178.8 44.6l.3-.1 .2 .2-.5 .7h.5M178.8 46.3h.5l-.4 .3h.3l.1 .3-.2 .2-.3-.1M178.8 53.1h.5l-.4 .9M178.8 43.6h.5M178.9 41.1a.39 .39 0 0 1 .4 .4 .39 .39 0 0 1-.4 .4zM178.9 48l-.1 .6h.5M178.9 55.2l-.1-.2 .3-.2 .2 .3-.5 .3 .1 .3 .4-.1-.2-.4M178.9 58.3a.43 .43 0 0 1 .4 .5 .43 .43 0 0 1-.4 .3l-.1-.5zM179.2 49.7h-.3l-.1 .4 .3-.1 .2 .4-.2 .2-.3-.1M179.2 51.4l-.3 .1-.1 .6 .1 .2 .4-.2-.1-.3h-.3l-.1 .1"/>
<path d="M179.2 48.2v.6M179.3 56.9l-.1 .2h-.3v-.5h.3l.1 .2-.1 .5-.3 .1M157 60.3l.3 .1v.5M157 62.1l.2-.1 .1 .2v.4h-.3l-.1-.2 .4-.1M157 63.8l.3 .1v.4h-.3l-.1-.2 .4-.1M157 65.5l.3 .1v.5M157 67.3l.2-.1 .1 .1v.5h-.3l-.1-.2 .4-.2M157 69h.3v.5h-.3v-.3l.3-.1M157 70.7h.3v.5M157 72.4l.2-.1 .1 .2v.4h-.3l-.1-.1 .4-.2M157 74.1l.3 .1v.4h-.3v-.2l.3-.1M157 75.8l.3 .1v.5"/>
<path d="M157 77.6l.2-.1 .1 .2v.4h-.3l-.1-.2 .4-.1M157 79.3l.3 .1v.4h-.3v-.3h.3M157.3 60.5l-.4 .2 .2 .2 .2-.1M157.3 65.7l-.4 .1 .2 .3 .2-.1M157.3 70.8l-.4 .2 .2 .2h.2M157.3 76l-.4 .2 .2 .2 .2-.1M157.7 60.1h.5v.3l-.5 .5h.5M157.7 61.8h.5v.3l-.5 .5h.5M157.7 63.5h.5v.4l-.5 .4h.5M157.7 65.3h.5v.3l-.5 .5h.5M157.7 67h.5v.3l-.5 .5h.5M157.7 68.7h.5v.3l-.5 .5h.5"/>
<path d="M157.7 70.5h.5v.2l-.5 .5h.5M157.7 72.2h.5v.2l-.5 .5h.5M157.7 73.9h.5v.3l-.5 .4h.5M157.7 75.6h.5l-.3 .2 .3 .1v.4h-.5M157.7 77.3h.5l-.3 .3 .3 .1v.3h-.5M157.7 78.9h.5l-.3 .4 .3 .1v.4h-.5M158.5 63.5h.5l-.3 .3 .3 .2v.3l-.5-.1M158.5 70.4h.5l-.3 .8M158.5 60.2l.3-.2v.9M158.5 61.8h.5v.2l-.5 .6h.5M158.5 77.5l.3-.2v.8M158.5 79l.4-.1 .1 .3-.5 .6h.5"/>
<path d="M158.5 60.9h.5M158.5 78.1h.5M158.6 75.6a.42 .42 0 0 1 .4 .3 .42 .42 0 0 1-.1 .4l-.2 .1-.2-.2zM158.7 65.1l-.2 .6h.5M158.7 72.4l-.2-.2 .5-.1v.3l-.5 .1 .1 .4h.4v-.1l-.1-.4M159 66.9h-.5v.4h.5v.1v.4l-.5-.1M159 68.6l-.5 .3v.5l.5 .1v-.4l-.1-.1-.4 .1M159 65.5v.6M159 74.2l-.1 .2-.4-.1v-.4l.4-.1 .1 .2-.1 .6h-.3M163.4 60.3h-.4v.5h.4M163.4 62.1h-.4v.5h.4M163.4 63.8h-.4v.5h.4"/>
<path d="M163.4 65.5h-.4v.5h.4M163.4 67.3h-.4v.5h.4M163.4 69h-.4v.5h.4M163.4 70.7h-.4v.5h.4M163.4 72.4h-.4v.5h.4M163.4 74.1h-.4v.5h.4M163.4 75.8h-.4v.5h.4M163.4 77.6h-.4v.5h.4M163.4 79.3h-.4v.5h.4M163.7 60.1h.5v.3l-.5 .5h.5M163.7 61.8h.5v.3l-.5 .5h.5M163.7 63.5h.5v.4l-.5 .4h.5"/>
<path d="M163.7 65.3h.5v.3l-.5 .5h.5M163.7 67h.5v.3l-.5 .5h.5M163.7 68.7h.5v.3l-.5 .5h.5M163.7 70.5h.5v.2l-.5 .5h.5M163.7 72.2h.5v.2l-.5 .5h.5M163.7 73.9h.5v.3l-.5 .4h.5M163.7 75.6h.5l-.2 .2 .2 .1v.4h-.5M163.7 77.3h.5l-.2 .3 .2 .1v.3h-.5M163.7 78.9h.5l-.2 .4 .2 .1v.4h-.5M164.5 63.5h.6l-.4 .3 .4 .2-.1 .3-.5-.1M164.5 70.4h.6l-.4 .8M164.5 60.2l.3-.2v.9"/>
<path d="M164.5 61.8h.5l.1 .2-.6 .6h.6M164.5 77.5l.3-.2v.8M164.5 79l.4-.1 .2 .3-.6 .6h.6M164.5 60.9h.6M164.5 78.1h.6M164.6 75.6a.42 .42 0 0 1 .4 .3 .42 .42 0 0 1-.1 .4l-.2 .1-.2-.2zM164.7 65.1l-.2 .6h.6M164.7 72.4l-.2-.2 .5-.1v.3l-.5 .1 .1 .4h.4l.1-.1-.2-.4M165 66.9h-.5v.4h.5l.1 .1-.1 .4-.5-.1M165 68.6l-.5 .3v.5l.5 .1 .1-.4-.2-.1-.4 .1M165 65.5v.6M165.1 74.2l-.2 .2-.4-.1v-.4l.4-.1 .2 .2-.2 .6h-.3"/>
<path d="M177.2 60.3l.4 .1v.4h-.4M177.2 61.8v.8h.3l.1-.5h-.4M177.2 63.5v.8h.3l.1-.4-.4-.1M177.2 65.5l.4 .1v.4h-.4M177.2 66.9v.9h.3l.1-.5h-.4M177.2 68.6v.9h.3l.1-.5h-.4M177.2 70.7h.4v.5h-.4M177.2 72.1v.8h.3l.1-.5h-.4M177.2 73.8v.8h.3l.1-.4-.4-.1M177.2 75.8l.4 .1v.4h-.4M177.2 77.3v.8h.3l.1-.5h-.4M177.2 78.9v.9h.4v-.4l-.4-.1"/>
<path d="M177.2 65.2v.9M177.2 70.4v.8M177.2 75.6v.8M177.9 60.1h.5v.3l-.5 .5h.5M177.9 61.8h.5v.3l-.5 .5h.5M177.9 63.5h.5v.4l-.5 .4h.5M177.9 65.3h.5v.3l-.5 .5h.5M177.9 67h.5v.3l-.5 .5h.5M177.9 68.7h.5v.3l-.5 .5h.5M177.9 70.5h.5v.2l-.5 .5h.5M177.9 72.2h.5v.2l-.5 .5h.5M177.9 73.9h.5v.3l-.5 .4h.5"/>
<path d="M177.9 75.6h.5l-.2 .2 .2 .1v.4h-.5M177.9 77.3h.5l-.2 .3 .2 .1v.3h-.5M177.9 78.9h.5l-.2 .4 .2 .1v.4h-.5M178.8 60.2l.2-.2v.9M178.8 61.8h.4l.1 .1-.5 .7h.5M178.8 63.5h.5l-.4 .3 .4 .2-.1 .3-.4-.1M178.8 70.4h.5l-.4 .8M178.8 77.5l.2-.2v.8M178.8 79l.3-.1 .2 .2-.5 .7h.5M178.8 60.9h.5M178.8 78.1h.5M178.9 75.6a.42 .42 0 0 1 .4 .3 .42 .42 0 0 1-.2 .4l-.2 .1-.1-.3z"/>
<path d="M178.9 65.1l-.1 .6h.5M178.9 72.4l-.1-.1 .1-.2h.3v.3l-.4 .2 .1 .3h.3l.1-.3-.2-.2M179.2 66.9h-.3l-.1 .4h.4v.5l-.4-.1M179.2 68.6a.57 .57 0 0 0-.3 .9h.3l.1-.4-.2-.1-.3 .1M179.2 65.5v.6M179.3 74.2l-.2 .2-.3-.2 .1-.4 .4 .2v.3l-.2 .3h-.2M242.2 87l.2-.3v.9M242.2 90.4l.2-.2v.9M242.2 87.6h.5M242.2 91.1h.5M242.9 86.8h.6v.3l-.6 .5h.6M242.9 90.4l.3-.2v.9"/>
<path d="M242.9 91.1h.6M251.7 88.4h-.5v.5h.5v.3h-.5M61.9 115.4l.2-.2v.8M61.9 116h.5M62.8 112.1l-.1 .1h-.3v-.5l.4 .1v.6l-.4 .2M62.8 115.3h.4v.6l-.2 .1-.2-.1zM70.1 113.8l-.2-.1v-.2l.3-.1 .2 .3-.5 .2 .1 .4h.3l.1-.3-.2-.2M61.9 122.3l.2-.3v.9M61.9 125.8l.2-.3v.9M61.9 122.9h.5M61.9 126.4h.5M62.7 122.1h.5v.3l-.5 .5h.5"/>
<path d="M62.7 125.5h.5l-.3 .4h.3v.4h-.5M63.7 137.2h.6M64 137.1v.5l-.6-.2M64.3 138.2h-.8l.2 .3M64.3 138v.5M69.5 124l.2-.3v.9M69.5 124.6h.5M70.3 124l.3-.3v.9M70.3 124.6h.5M64.3 151.7l-.8-.4v.5M114.3 162.8l.2-.3v.9M114.3 163.4h.5"/>
<path d="M122.8 166h.5l-.2 .3 .2 .1v.3h-.5M122.8 179.8h.6l-.4 .8M122.9 162.6h.4v.3l-.5 .5h.5M123.1 169.4l-.2 .6h.5M123.2 176.3h-.2l-.1 .2v.7l.4-.1-.1-.4h-.3v.1M123.2 169.7v.6M123.3 172.8h-.4v.5h.4l-.1 .4-.3-.1M113.8 188.6l.3-.3v.9M113.8 189.2h.5M114.8 188.3l.3 .2-.1 .7h-.2l-.1-.2v-.5zM123 183.6l-.1-.3h.4v.2l-.4 .1v.4l.4-.1v-.2l-.2-.1M123.3 187l-.1 .2h-.3v-.6l.4 .1v.6l-.4 .2"/>
</g>
<g fill="none" stroke="#0f0f0f" stroke-width=".21">
<path d="M165.6 32.7h.3M165.6 37.9h.3M165.6 36.2h.3M165.6 34.5h.3M165.6 29.3h.3M165.6 25.9h.3M165.6 31h.3M165.6 27.6h.3M166 32.4h-.4v.8h.4M166 37.5h-.4v.9h.4M166 35.8h-.4v.8h.4M166 34.1h-.4v.8h.4"/>
<path d="M166 28.9h-.4v.9h.4M166 25.4h-.4v.9h.4M166 30.6h-.4v.9h.4M166 27.2h-.4v.9h.4M166.2 32.4l.6 .8M166.2 37.5l.6 .9M166.2 35.8l.6 .8M166.2 34.1l.6 .8M166.2 28.9l.6 .9M166.2 25.4l.6 .9M166.2 30.6l.6 .9M166.2 27.2l.6 .9"/>
<path d="M166.8 32.4l-.6 .8M166.8 37.5l-.6 .9M166.8 35.8l-.6 .8M166.8 34.1l-.6 .8M166.8 28.9l-.6 .9M166.8 25.4l-.6 .9M166.8 30.6l-.6 .9M166.8 27.2l-.6 .9M167.2 32.8h.3l.2-.2-.1-.2h-.4v.8M167.2 38h.3l.2-.2-.1-.3h-.4v.9M167.2 36.3h.3l.2-.2-.2-.3h-.3v.8M167.2 34.5h.4v-.4h-.4v.8"/>
<path d="M167.2 29.3h.4v-.4h-.4v.9M167.2 25.9h.3l.2-.1-.2-.4h-.3v.9M167.2 31.1h.3l.2-.2-.2-.3h-.3v.9M167.2 27.6h.3l.2-.3-.5-.1v.9M167.8 33.3h.7M167.8 38.5h.7M167.8 36.7h.7M167.8 35h.7M167.8 29.8h.7M167.8 26.4h.7M167.8 31.5h.7M167.8 28.1h.7"/>
<path d="M168.7 32.4h.3a.48 .48 0 0 1 .2 .5 .48 .48 0 0 1-.5 .3zM168.7 37.5h.3a.48 .48 0 0 1 .2 .6 .48 .48 0 0 1-.5 .3zM168.7 35.8a.49 .49 0 0 1 .4 .3 .49 .49 0 0 1-.1 .5h-.3zM168.7 34.1l.4 .1 .1 .4-.2 .3h-.3zM168.7 28.9l.4 .1 .1 .4-.2 .4h-.3zM168.7 25.4a.49 .49 0 0 1 .4 .3 .49 .49 0 0 1-.1 .6h-.3zM168.7 30.6a.49 .49 0 0 1 .4 .3 .49 .49 0 0 1-.1 .6h-.3zM168.7 27.2h.3a.48 .48 0 0 1 .2 .6 .48 .48 0 0 1-.5 .3zM169.5 32.6l.3-.2v.8M169.5 37.8l.3-.3v.9M169.5 36l.3-.2v.8M169.5 34.3l.3-.2v.8"/>
<path d="M169.5 29.2l.3-.3v.9M169.5 30.9l.3-.3v.9M169.5 33.2h.5M169.5 38.4h.5M169.5 36.6h.5M169.5 34.9h.5M169.5 29.8h.5M169.5 31.5h.5M169.7 25.9l-.2-.1v-.3l.3-.1 .2 .1v.3l-.5 .1 .1 .4 .4-.1v-.3h-.2M170 27.6l-.2 .1-.3-.1v-.3h.5v.5l-.4 .3M170.3 32.5h.5v.2l-.5 .5h.5M170.3 34.1h.5l-.2 .3 .2 .1v.3h-.5"/>
<path d="M170.3 30.9l.3-.3v.9M170.3 31.5h.5M170.4 29l.3-.1v.8a.39 .39 0 0 1-.4-.2 .39 .39 0 0 1 .1-.5zM170.6 35.8l-.3 .6h.6M170.7 36.1v.5M170.8 37.5h-.4l-.1 .4h.5v.4h-.5M179.2 25.2h6.3M179.2 30.3h6.7M179.2 27h6.3M179.2 33.8h6.7M179.2 37.3h6.7M179.4 37.9h.2"/>
<path d="M179.4 34.5h.2M179.4 25.9h.2M179.4 31h.2M179.4 27.6h.2M179.8 25.4h-.4v.9h.4M179.8 30.6h-.4v.9h.4M179.8 27.2h-.4v.9h.4M179.8 34.1h-.4v.8h.4M179.8 37.5h-.4v.9h.4M180 25.4l.6 .9M180 30.6l.6 .9M180 27.2l.6 .9"/>
<path d="M180 34.1l.6 .8M180 37.5l.6 .9M180.6 25.4l-.6 .9M180.6 30.6l-.6 .9M180.6 27.2l-.6 .9M180.6 34.1l-.6 .8M180.6 37.5l-.6 .9M181 25.9h.3l.2-.1-.2-.4h-.3v.9M181 31.1h.3l.2-.2-.2-.3h-.3v.9M181 27.6h.3l.2-.3-.5-.1v.9M181 34.5h.4v-.4h-.4v.8M181 38h.3l.2-.2-.1-.3h-.4v.9"/>
<path d="M181.6 38.5h.6M181.6 35h.6M181.6 26.4h.6M181.6 31.5h.6M181.6 28.1h.6M182.5 25.9h.3l.1-.4-.4-.1v.9h.4l.1-.3-.3-.1M182.5 31h.3l.1-.3-.4-.1v.9h.4l.1-.3-.3-.2M182.5 27.6h.3l.1-.3-.4-.1v.9h.3l.2-.4-.3-.1M182.5 34.5l.4-.1-.1-.3h-.3v.8h.4l.1-.2-.3-.2M182.5 37.9h.4v-.3l-.4-.1v.9h.3l.2-.3-.3-.2M183.3 25.9h.4l.1-.4-.5-.1v.9h.5l.1-.3-.3-.1M183.8 30.7a.43 .43 0 0 0-.5 .2 .43 .43 0 0 0 .1 .6l.5-.1v-.3h-.2"/>
<path d="M183.8 34.1h-.4l-.1 .3 .1 .5 .5-.1v-.2h-.2M183.8 37.5h-.4a.44 .44 0 0 0-.1 .6 .44 .44 0 0 0 .6 .2v-.3h-.2M183.9 27.3l-.5-.1a.44 .44 0 0 0-.1 .6 .44 .44 0 0 0 .6 .2M184.1 30.9l.4 .6M184.1 34.3l.4 .6M184.1 37.8l.4 .6M184.2 27.2v.9h.4M184.5 30.9l-.4 .6M184.5 34.3l-.4 .6M184.5 37.8l-.4 .6M184.6 25.5h-.4v.3l.4 .2-.1 .3h-.3M184.9 25.4l.3 .5 .3-.5"/>
<path d="M184.9 27.6h.5v-.3l-.5-.1v.9M184.9 30.6v.9M184.9 34.1v.8M184.9 37.5v.9M185.1 27.6l.3 .5M185.2 25.9v.4M185.8 30.6v.9l-.5-.9v.9M185.8 34.1v.8l-.5-.8v.8M185.8 37.5v.9l-.5-.9v.9M203.7 32.7h.3M203.7 37.9h.3M203.7 36.2h.3"/>
<path d="M203.7 34.5h.3M203.7 29.3h.3M203.7 31h.3M204.2 32.4h-.5v.8h.5M204.2 28.9h-.5v.9h.5M204.2 30.6h-.5v.9h.5M204.2 35.8h-.5v.8h.5M204.2 37.5h-.5v.9h.5M204.2 34.1h-.5v.8h.5M204.4 32.4l.6 .8M204.4 28.9l.6 .9M204.4 30.6l.6 .9"/>
<path d="M204.4 35.8l.6 .8M204.4 37.5l.6 .9M204.4 34.1l.6 .8M204.6 25.9h.2M204.6 27.6h.2M204.9 25.4h-.3v.9h.3M204.9 27.2h-.3v.9h.3M205 32.4l-.6 .8M205 28.9l-.6 .9M205 30.6l-.6 .9M205 35.8l-.6 .8M205 37.5l-.6 .9"/>
<path d="M205 34.1l-.6 .8M205.3 25.4l.6 .9M205.3 27.2l.6 .9M205.4 32.8h.3l.2-.2-.1-.2h-.4v.8M205.4 29.3h.4v-.4h-.4v.9M205.4 31.1h.3l.2-.2-.2-.3h-.3v.9M205.4 36.3h.3l.2-.2-.2-.3h-.3v.8M205.4 38h.3l.2-.2-.1-.3h-.4v.9M205.4 34.5h.4v-.4h-.4v.8M205.9 25.4l-.6 .9M205.9 27.2l-.6 .9M206 33.3h.6"/>
<path d="M206 38.5h.6M206 36.7h.6M206 35h.6M206 29.8h.6M206 31.5h.6M206.2 25.9h.4v-.4l-.4-.1v.9M206.2 27.6h.4v-.3l-.4-.1v.9M206.8 26.4h.7M206.8 28.1h.7M206.9 32.4h.3a.48 .48 0 0 1 .2 .5 .48 .48 0 0 1-.5 .3zM206.9 28.9l.4 .1 .1 .4-.2 .4h-.3zM206.9 30.6a.49 .49 0 0 1 .4 .3 .49 .49 0 0 1-.1 .6h-.3z"/>
<path d="M206.9 35.8a.49 .49 0 0 1 .4 .3 .49 .49 0 0 1-.1 .5h-.3zM206.9 37.5h.3a.48 .48 0 0 1 .2 .6 .48 .48 0 0 1-.5 .3zM206.9 34.1l.4 .1 .1 .4-.2 .3h-.3zM207.6 25.4h.3l.2 .3v.4l-.1 .2h-.4zM207.6 27.2h.4l.1 .2v.4l-.2 .3h-.3zM207.6 32.6l.3-.2v.8M207.6 29.2l.3-.3v.9M207.6 30.9l.3-.3v.9M207.6 36l.3-.2v.8M207.6 37.8l.3-.3v.9M207.6 34.3l.3-.2v.8M207.6 33.2h.5"/>
<path d="M207.6 38.4h.5M207.6 36.6h.5M207.6 34.9h.5M207.6 29.8h.5M207.6 31.5h.5M208.5 32.5l.4-.1 .1 .2-.5 .6h.5M208.5 30.9l.2-.3v.9M208.5 34.1h.5l-.3 .3 .3 .2-.1 .3-.4-.1M208.5 31.5h.5M208.7 25.9l-.2-.3 .3-.2 .2 .3-.4 .2-.1 .2 .1 .2h.3l.1-.3-.2-.1M208.7 28.9h.2v.9a.47 .47 0 0 1-.4-.4 .47 .47 0 0 1 .2-.5zM208.7 35.8l-.2 .6h.5"/>
<path d="M208.9 37.5h-.3l-.1 .4h.4l.1 .3-.2 .2-.3-.1M208.9 36.1v.5M209 27.6l-.2 .1-.3-.1 .1-.4h.3a.57 .57 0 0 1-.3 .9M149.8 58.8h5.9M150 59.5h.2M150.4 59.1h-.4v.8h.4M150.7 59.1l.6 .8M151.2 55.3h4.5M151.3 59.1l-.6 .8M151.3 56h.3M151.6 59.5h.4v-.4h-.4v.8M151.7 55.6h-.4v.8h.4"/>
<path d="M152 55.6l.5 .8M152.3 60h.6M152.5 55.6l-.5 .8M152.9 56.1l.5-.1v-.3l-.5-.1v.8M153.1 59.1v.8M153.4 59.9l.2-.8 .4 .8M153.5 59.6h.4M153.5 56.5h.7M154.3 56.4l.3-.8 .3 .8M154.4 56.3h.4M154.7 59.1h-.3l-.2 .1v.5l.2 .2 .3-.1M155.1 59.1v.8"/>
<path d="M155.2 59.4l.4 .5M155.6 55.7l-.4-.1-.1 .1v.3l.5 .2v.1l-.5 .1M155.6 59.1l-.5 .5M165.5 40.7h7.9M165.6 41.4h.3M166 40.9h-.4v.9h.4M166.2 40.9l.6 .9M166.8 40.9l-.6 .9M167.2 41.4h.3l.2-.3-.2-.2h-.3v.9M167.8 41.9h.7M168.9 46.8h7.2M169 47.4h.3"/>
<path d="M169.1 41l-.3-.1-.2 .2 .1 .3 .4 .1v.3h-.5M169.4 40.9l.3 .5 .3-.5M169.5 47h-.5v.9h.5M169.7 41.4v.4M169.7 47l.6 .9M170.3 47l-.6 .9M170.6 47.5h.4l.2-.4-.6-.1v.9M170.7 41h-.5v.3l.5 .3-.1 .2h-.4M170.7 49.1h.4M171.1 41.4h.2M171.2 48.7h-.5v.9h.5M171.2 48h.7"/>
<path d="M171.4 48.7l.6 .9M171.5 40.9h-.4v.9M171.7 41.8l.3-.9 .3 .9M171.7 41.6h.5M172 48.7l-.6 .9M172.2 47v.9h.3M172.3 49.1h.5v-.4h-.5v.9M172.5 40.9v.9M172.8 47l.1 .9 .2-.7 .2 .7 .2-.9M172.9 40.9v.9h.5M173 49.7h.7M173.8 47.1h.5a.47 .47 0 0 1-.4 .8l-.1-.2z"/>
<path d="M173.8 49.6l.2-.9 .3 .9M173.8 49.3h.4M174.6 49.6v-.9l.3 .6 .2-.6v.9M174.7 47.5h.3l.2-.4-.5-.1v.9M175 47.5l.2 .4M175.6 47h.3l.2 .2v.4l-.3 .3h-.2zM176 48.7h-.4v.4h.4v.5l-.4-.1M179.2 40.7h6.7M179.4 41.4h.2M179.8 40.9h-.4v.9h.4M180 40.9l.6 .9M180.2 56.9h.3"/>
<path d="M180.2 51.7h.3M180.2 53.5h.3M180.2 55.2h.3M180.6 56.4h-.4v1h.4M180.6 51.3h-.4v.9h.4M180.6 53h-.4v.9h.4M180.6 54.7h-.4v.9h.4M180.6 40.9l-.6 .9M180.9 56.4l.6 1M180.9 51.3l.6 .9M180.9 53l.6 .9M180.9 54.7l.6 .9"/>
<path d="M181 41.4h.3l.2-.3-.2-.2h-.3v.9M181.5 56.4l-.6 1M181.5 51.3l-.6 .9M181.5 53l-.6 .9M181.5 54.7l-.6 .9M181.6 41.9h.6M181.8 56.9h.4l.1-.3-.1-.2h-.4v1M181.8 51.8h.4l.1-.4-.1-.1h-.4v.9M181.8 53.5h.4v-.5h-.4v.9M181.8 55.2h.4l.1-.3-.1-.2h-.4v.9M182.5 41.4h.3l.1-.4-.4-.1v.9h.4l.1-.3-.3-.1M182.5 57.4h.6"/>
<path d="M182.5 52.3h.6M182.5 54h.6M182.5 55.7h.6M183.2 57.4l.3-1 .3 1M183.2 52.2l.3-.9 .3 .9M183.2 53.9l.3-.9 .3 .9M183.2 55.6l.3-.9 .3 .9M183.3 57.1h.4M183.3 51.9h.4M183.3 53.6h.4M183.3 55.3h.4M183.8 41a.43 .43 0 0 0-.5 .3 .43 .43 0 0 0 .1 .5h.5v-.4h-.2"/>
<path d="M184.1 57.4v-1l.3 .7 .2-.7v1M184.1 52.2v-.9l.3 .6 .2-.6v.9M184.1 53.9v-.9l.3 .6 .2-.6v.9M184.1 55.6v-.9l.3 .6 .2-.6v.9M184.1 41.3l.4 .5M184.5 41.3l-.4 .5M184.9 40.9v.9M185 56.4h.5l-.3 .4 .3 .1v.3l-.1 .2-.4-.1M185 53.3l.3-.3v.9M185 54.8l.4-.1 .1 .3-.5 .6h.5M185 53.9h.5M185.2 51.3a.48 .48 0 0 1 .4 .4 .48 .48 0 0 1-.4 .5l-.2-.2v-.6z"/>
<path d="M185.8 40.9v.9l-.5-.9v.9M203.6 43.6l.2 .8 .4-.8M203.6 43.3h4.6M204.4 44.4v-.8l.4 .6 .2-.6v.8M205.4 44h.3M205.9 43.6h-.5v.8h.5M206.6 43.6h-.4l.1 .4 .3 .1-.1 .3h-.3M207 44h.3M207.5 43.6h-.5v.8h.5M207.8 43.6v.8h.4M148.5 60.5h7.2M148.6 61.2h.4"/>
<path d="M149.1 60.7h-.5v.9h.5M149.4 60.7l.5 .9M149.9 60.7l-.5 .9M150.2 61.3l.5-.1v-.4l-.5-.1v.9M150.3 63.8h.3M150.7 63.4h-.4v.8h.4M150.9 61.7h.7M151 63.4l.6 .8M151.6 63.4l-.6 .8M151.8 60.7v.9M151.9 63.8h.5v-.4h-.5v.8M152.1 61.6l.3-.9 .2 .9"/>
<path d="M152.2 61.4h.3M152.5 64.3h.7M153.3 64.2l.3-.8 .3 .8M153.4 64h.4M153.5 60.8a.44 .44 0 0 0-.6 .2 .44 .44 0 0 0 .1 .6l.5-.1M153.8 60.7v.9M153.9 61.2l.4 .4M154.1 64.2v-.8l.4 .6 .2-.6v.8M154.3 60.7l-.5 .6M154.6 60.7v.9M155.3 63.3l-.2 .7h.6M155.5 63.6v.6"/>
<path d="M155.6 60.7v.9l-.5-.9v.9M257.8 69h.2M258.1 68.5h-.3v.9h.3M258.4 68.5l.6 .9M259 68.5l-.6 .9M259.3 69h.4l.1-.4-.5-.1v.9M260 69.5h.6M260.7 68.5l.3 .9 .3-.9M261.5 68.5h.4M261.7 68.5v.9M262.3 69h.2M262.7 68.5h-.4v.9h.4"/>
<path d="M263 69h.4v-.5h-.4v.9M263.3 69l.2 .4M263.9 69.4v-.9l.3 .6 .3-.6v.9M264.8 68.8l.2-.3v.9M264.8 69.4h.5M257.8 88.8h.2M258.1 88.3h-.3v.9h.3M258.4 88.3l.6 .9M259 88.3l-.6 .9M259.3 88.8h.4l.1-.4-.5-.1v.9M260 89.3h.6M260.7 88.3l.3 .9 .3-.9"/>
<path d="M261.5 88.3h.4M261.7 88.3v.9M262.3 88.8h.2M262.7 88.3h-.4v.9h.4M263 88.8h.4v-.5h-.4v.9M263.3 88.8l.2 .4M263.9 89.2v-.9l.3 .6 .3-.6v.9M264.8 88.4h.5v.3l-.5 .5h.5M47.5 119.9h4.6M47.5 110.3h.4M47.5 113.7h.4M47.5 112h.4"/>
<path d="M47.5 115.4h.4M47.5 117.1h.4M47.5 118.9h.4M48 113.3h-.5v.9h.5M48 111.5h-.5v1h.5M48 109.9h-.5v.8h.5M48 115h-.5v.9h.5M48 116.8h-.5v.8h.5M48 118.5h-.5v.8h.5M48.3 113.3l.5 .9M48.3 111.5l.5 1M48.3 109.9l.5 .8"/>
<path d="M48.3 115l.5 .9M48.3 116.8l.5 .8M48.3 118.5l.5 .8M48.8 113.3l-.5 .9M48.8 111.5l-.5 1M48.8 109.9l-.5 .8M48.8 115l-.5 .9M48.8 116.8l-.5 .8M48.8 118.5l-.5 .8M49.1 113.7h.5l.1-.3-.6-.1v.9M49.1 112.1l.6-.1v-.4l-.6-.1v1M49.1 110.3h.6v-.4h-.6v.8"/>
<path d="M49.1 115.5l.6-.1v-.3l-.6-.1v.9M49.1 117.2l.6-.1v-.3h-.6v.8M49.1 118.9h.5l.1-.3-.6-.1v.8M49.8 114.3h.7M49.8 112.6h.7M49.8 110.8h.7M49.8 115.9h.7M49.8 117.7h.7M49.8 119.4h.7M50.6 114.2l.2-.9 .4 .9M50.6 112.5l.2-1 .4 1M50.6 110.7l.2-.8 .4 .8"/>
<path d="M50.6 115.9l.2-.9 .4 .9M50.6 117.6l.2-.8 .4 .8M50.6 119.3l.2-.8 .4 .8M50.7 113.9h.4M50.7 112.2h.4M50.7 110.4h.4M50.7 115.6h.4M50.7 117.4h.4M50.7 119.1h.4M51.4 114.2v-.9l.3 .6 .3-.6v.9M51.4 112.5v-1l.3 .7 .3-.7v1M51.4 110.7v-.8l.3 .5 .3-.5v.8"/>
<path d="M51.4 115.9v-.9l.3 .6 .3-.6v.9M51.4 117.6v-.8l.3 .6 .3-.6v.8M51.4 119.3v-.8l.3 .6 .3-.6v.8M52.4 113.3h.5l-.3 .4 .3 .1-.1 .4-.4-.1M52.4 115.1l.3-.1 .2 .2-.5 .7h.5M52.4 117l.2-.2v.8M52.4 117.6h.5M52.4 118.6l.1-.1a.43 .43 0 0 1 .4 .4 .43 .43 0 0 1-.4 .4l-.1-.3zM52.6 111.5l-.2 .6h.5M52.8 109.9h-.4v.4l.3-.1 .2 .2-.1 .3-.4-.1M52.8 111.9v.6M56.3 115l.3 .9 .3-.9"/>
<path d="M56.3 104.7l.3 .8 .3-.8M56.3 104.4h4.6M56.3 114.8h4.6M57.2 115.9v-.9l.2 .6 .3-.6v.9M57.2 105.5v-.8l.2 .6 .3-.6v.8M58.1 115.4h.4M58.1 105.1h.4M58.5 115h-.4v.9h.4M58.5 104.7h-.4v.8h.4M59.4 115.1h-.5v.3l.5 .2-.1 .3h-.4M59.4 104.8h-.5v.2l.5 .3-.1 .2h-.4M59.7 115.4h.4"/>
<path d="M59.7 105.1h.4M60.2 115h-.5v.9h.5M60.2 104.7h-.5v.8h.5M60.5 115v.9h.4M60.5 104.7v.8h.4M71.6 113.1h5.3M71.6 102.7h5.5M71.7 113.7h.3M71.7 103.4h.3M72.1 113.3h-.4v.9h.4M72.1 103h-.4v.8h.4M72.4 113.3l.5 .9"/>
<path d="M72.4 103l.5 .8M72.9 113.3l-.5 .9M72.9 103l-.5 .8M73.3 113.7h.4l.1-.3-.5-.1v.9M73.3 103.4h.4l.1-.3-.5-.1v.8M74 114.3h.6M74 103.9h.6M74.8 113.3v.9h.4M74.8 103v.7l.2 .1 .3-.1v-.7M75.5 113.3h.3l.2 .2v.5l-.2 .2h-.3zM75.7 103h.4a.47 .47 0 0 1 .1 .5 .47 .47 0 0 1-.5 .3zM76.8 113.3h-.4l-.1 .2 .5 .4-.1 .3h-.4"/>
<path d="M77 103h-.4l-.1 .2 .2 .2 .3 .1v.3h-.5M86.3 119.8h.4M86.7 119.3h-.4v.9h.4M87 119.3l.6 .9M87.6 119.3l-.6 .9M87.9 119.8h.4l.1-.3-.1-.2h-.4v.9M89.4 119.3l.2 .9 .3-.9M90 119.3h.5M90.3 119.3v.9M90.9 119.8h.2M91.2 119.3h-.3v.9h.3M91.6 119.8h.5l.1-.3-.2-.2h-.4v.9"/>
<path d="M91.8 119.8l.4 .4M93.4 119.6l.3-.3v.9M95 109.9l.4 .8 .2-.8M95 109.6h4.7M95.9 110.7v-.8l.3 .5 .3-.5v.8M96.9 110.3h.3M97.3 109.9h-.4v.8h.4M98.2 109.9h-.5v.3l.5 .2-.1 .3h-.4M98.5 110.3h.3M98.9 109.9h-.4v.8h.4M99.3 109.9v.8h.4M118.2 104.3h.3"/>
<path d="M118.6 103.8h-.4v.9h.4M118.9 103.8l.6 .9M119.5 103.8l-.6 .9M119.8 104.3h.4l.1-.4-.5-.1v.9M120.4 104.8h.7M121.2 104.7l.3-.9 .3 .9M121.3 104.4h.4M122.2 104.2l-.2-.3 .5-.1v.4l-.5 .1 .1 .4h.4l-.1-.5M127 109.9l.2 .8 .3-.8M127 109.6h4.5M127.8 110.7v-.8l.3 .5 .3-.5v.8M128.7 110.3h.4"/>
<path d="M129.2 109.9h-.5v.8h.5M130 109.9h-.3l-.2 .1 .1 .3 .4 .1-.1 .3h-.4M130.3 110.3h.4M130.8 109.9h-.5v.8h.5M131.2 109.9v.8h.3M47.5 120.2l.2 .8 .3-.8M48.3 121v-.8l.3 .6 .3-.6v.8M49.3 120.6h.3M49.7 120.2h-.4v.8h.4M50.5 120.3h-.4v.3l.4 .2-.1 .2h-.3M50.9 120.6h.3M51.3 120.2h-.4v.8h.4"/>
<path d="M51.7 120.2v.8h.4M88.6 120.3h.7M92.5 120.2v-.9l.2 .6 .4-.6v.9M93.4 120.2h.5M96.6 127.5h.4M96.6 124.1h.4M96.6 134.4h.4M96.6 137.9h.4M96.6 130.9h.4M97.1 123.7h-.5v.8h.5M97.1 134h-.5v.8h.5M97.1 127.1h-.5v.9h.5"/>
<path d="M97.1 137.5h-.5v.8h.5M97.1 130.5h-.5v.9h.5M97.4 123.7l.5 .8M97.4 134l.5 .8M97.4 127.1l.5 .9M97.4 137.5l.5 .8M97.4 130.5l.5 .9M97.9 123.7l-.5 .8M97.9 134l-.5 .8M97.9 127.1l-.5 .9M97.9 137.5l-.5 .8M97.9 130.5l-.5 .9"/>
<path d="M98.3 124.1h.4l.1-.4h-.5v.8M98.3 134.4h.4l.1-.3-.5-.1v.8M98.3 127.5h.5v-.3l-.5-.1v.9M98.3 137.9h.4l.1-.4h-.5v.8M98.3 131l.5-.1v-.3l-.5-.1v.9M98.9 128.1h.7M98.9 124.6h.7M98.9 134.9h.7M98.9 138.4h.7M98.9 131.4h.7M99.8 123.7h.4l.1 .5-.2 .3h-.3zM99.8 134l.4 .1 .1 .4-.2 .3h-.3z"/>
<path d="M99.8 127.1h.3a.48 .48 0 0 1 .2 .6 .48 .48 0 0 1-.5 .3zM99.8 137.5h.3a.48 .48 0 0 1 .2 .5 .48 .48 0 0 1-.5 .3zM99.8 130.5a.48 .48 0 0 1 .5 .3 .48 .48 0 0 1-.2 .6h-.3zM100.5 134h.6l-.3 .3h.2l.1 .2-.1 .3-.5-.1M100.6 127.4l.3-.3v.9M100.6 130.6l.4-.1 .1 .3-.6 .6h.6M100.6 128h.5M100.7 123.7a.42 .42 0 0 1 .4 .4 .42 .42 0 0 1-.4 .4zM100.8 137.4l-.2 .6h.5M101 137.7v.6M124.2 127.5h.3M124.2 124.1h.3"/>
<path d="M124.2 134.4h.3M124.2 130.9h.3M124.7 127.1h-.5v.9h.5M124.7 123.7h-.5v.8h.5M124.7 134h-.5v.8h.5M124.7 130.5h-.5v.9h.5M124.9 127.1l.6 .9M124.9 123.7l.6 .8M124.9 134l.6 .8M124.9 130.5l.6 .9M125.5 127.1l-.6 .9M125.5 123.7l-.6 .8"/>
<path d="M125.5 134l-.6 .8M125.5 130.5l-.6 .9M125.9 127.5h.3l.2-.1-.1-.3h-.4v.9M125.9 124.1h.4v-.4h-.4v.8M125.9 134.4h.4v-.4h-.4v.8M125.9 131h.3l.2-.3-.2-.2h-.3v.9M126.4 128.1h.7M126.4 124.6h.7M126.4 134.9h.7M126.4 131.4h.7M127.4 127.1h.3l.1 .2v.4l-.3 .3h-.1zM127.4 123.7h.3l.1 .1-.1 .7h-.3z"/>
<path d="M127.4 134h.3l.1 .2-.1 .6h-.3zM127.4 130.5l.4 .3-.1 .6h-.3zM128.1 134.2l.3-.2v.8M128.1 130.8l.3-.3v.9M128.1 134.8h.5M128.1 131.4h.5M128.3 124l-.2-.2 .1-.1h.4v.2l-.5 .3 .1 .3h.4v-.4l-.1-.1M128.6 127.5l-.3 .1-.2-.1 .1-.4 .4 .1v.7l-.4 .1M129 134.2l.2-.2v.8M129 134.8h.5M129.2 130.5a.43 .43 0 0 1 .3 .5 .43 .43 0 0 1-.4 .4l-.1-.6zM42.3 144.9h5.8"/>
<path d="M42.4 145.6h.3M42.8 145.2h-.4v.8h.4M43.1 145.2l.5 .8M43.6 145.2l-.5 .8M44 145.7l.5-.1v-.4h-.5v.8M44.7 146.1h.6M45.5 145.2v.8M45.8 146l.3-.8 .3 .8M45.9 145.8h.4M47.2 145.2a.44 .44 0 0 0-.6 .2 .44 .44 0 0 0 .2 .6l.4-.1M47.5 145.2v.8M47.6 145.6l.4 .4"/>
<path d="M48 145.2l-.5 .5M96.6 144.7h.4M96.6 148.2h.4M96.6 141.3h.4M97.1 144.3h-.5v.9h.5M97.1 147.8h-.5v.8h.5M97.1 140.8h-.5v1h.5M97.4 144.3l.5 .9M97.4 147.8l.5 .8M97.4 140.8l.5 1M97.9 144.3l-.5 .9M97.9 147.8l-.5 .8"/>
<path d="M97.9 140.8l-.5 1M98.3 144.7h.4l.1-.3-.5-.1v.9M98.3 148.2h.4l.1-.3-.5-.1v.8M98.3 141.3h.5v-.4l-.5-.1v1M98.9 145.2h.7M98.9 148.7h.7M98.9 141.9h.7M99.8 144.3a.47 .47 0 0 1 .5 .3 .47 .47 0 0 1-.2 .6h-.3zM99.8 147.8h.3a.47 .47 0 0 1 .2 .5 .47 .47 0 0 1-.5 .3zM99.8 140.8a.47 .47 0 0 1 .5 .5 .47 .47 0 0 1-.5 .5zM100.5 147.8h.6l-.3 .8M101 144.3l-.4 .2v.6l.4 .1v-.6h-.3l-.1 .2"/>
<path d="M101 140.8h-.4v.5l.4-.1 .1 .4-.1 .2-.4-.1M124.2 148.2h.3M124.2 141.3h.3M124.7 147.8h-.5v.8h.5M124.7 140.8h-.5v1h.5M124.9 147.8l.6 .8M124.9 140.8l.6 1M125.5 147.8l-.6 .8M125.5 140.8l-.6 1M125.9 148.2h.4v-.4h-.4v.8M125.9 141.3h.3l.2-.1-.2-.4h-.3v1M126.4 148.7h.7"/>
<path d="M126.4 141.9h.7M127.4 147.8h.3l.1 .2v.4l-.3 .2h-.1zM127.4 140.8l.4 .3v.4l-.3 .3h-.1zM128.1 148l.3-.2v.8M128.1 141.1l.3-.3v1M128.1 148.6h.5M128.1 141.8h.5M129 140.8h.5l-.3 .4 .3 .1v.3l-.2 .2-.3-.1M129.4 147.8h-.3l-.1 .4 .4-.1 .1 .4-.2 .1-.3-.1M31.1 169h6.2M31.2 169.7h.3M31.6 169.3h-.4v.8h.4"/>
<path d="M31.9 169.3l.6 .8M32.5 169.3l-.6 .8M32.8 169.7h.4l.1-.2-.2-.2h-.3v.8M33.5 170.2h.7M34.3 169.7l.5-.1v-.2l-.5-.1v.8h.5v-.2l-.2-.2M35.2 169.7l.4-.1-.1-.3h-.3v.8h.4l.1-.2-.2-.2M36.5 169.4h-.5v.2l.5 .3-.1 .2h-.4M36.8 169.3l.2 .4 .3-.4M37 169.7v.4M43.1 169h6.3M43.3 169.7h.3M43.6 169.3h-.3v.8h.3"/>
<path d="M44 169.3l.6 .8M44.6 169.3l-.6 .8M44.8 169.7h.5v-.3l-.5-.1v.8M45.5 170.2h.7M46.4 169.7h.3l.2-.2-.2-.2h-.3v.8h.4l.1-.3-.2-.1M47.7 169.4a.42 .42 0 0 0-.5 .2 .42 .42 0 0 0 .2 .5l.3-.1M48.1 169.3v.8h.5M48.8 169.7h.4l.1-.2-.2-.2h-.3v.8M49 169.7l.3 .4M31.1 180.2h7.9M31.2 180.9h.3M31.6 180.5h-.4v.8h.4"/>
<path d="M31.9 180.5l.6 .8M32.5 180.5l-.6 .8M32.8 181h.3l.2-.4-.2-.1h-.3v.8M33.5 181.4h.7M34.8 180.5h-.5v.4l.5 .2v.2h-.5M35 180.5l.3 .5 .3-.5M35.3 181v.3M36.4 180.5h-.5v.3l.5 .3-.1 .2h-.4M36.7 180.9h.3M37.1 180.5h-.4v.8M37.3 181.3l.3-.8 .3 .8M37.4 181.1h.4"/>
<path d="M38.2 180.5v.8M38.6 180.5v.8h.4"/>
</g>
<path d="M18.7 190.6h2.1M27.3 190.6h2.1M35.9 190.6h2.1M43.7 190.6h2.1M52.3 190.6h2.1M60.9 190.6h2" fill="none" stroke="#910000" stroke-width=".25"/>
<path d="M244.1 87.9h.7M244.1 91.3h.7M244.5 87.6v.6M64 142.2l.9 .2-.9 .3M64 147.4h.9l-.9 .5h.9M64 146.8l.3-.3h.4l.2 .2v.3h-.9zM64.1 141.3a.44 .44 0 0 0 .2 .6 .44 .44 0 0 0 .6-.1l-.1-.5M64.1 140.5a.44 .44 0 0 0 .2 .6 .44 .44 0 0 0 .6-.2l-.1-.4M64.1 148.3l-.1 .2 .3 .3h.4l.2-.2v-.3h-.3v.2" fill="none" stroke="#006665" stroke-width=".21"/>
<path d="M253.4 85.2l.6-.3 .7 .3-.7 .4v1.4v-1.4z" fill="none" stroke="#474747" stroke-width=".21"/>
<path d="M149.8 78.4l.9-.6v.6h.8h-.8v.5z" fill="#910000"/>
<g fill="none" stroke="#910000" stroke-width=".21">
<path d="M217.8 19.8l-.5 .8M217.8 19.8l.6 .8M217.8 19.8v5.1M254 19.8l-.5 .8M254 19.8l.5 .8M254 19.8v5.1M105 26.6h2.6M105 28.4h2.6M105 30.1h2.6M105 31.9h2.6M105 33.6h2.6M105 35.3h2.6"/>
<path d="M105 37h2.6M105 38.7h2.6M107.5 25.7h3.5v55.2h-3.5zM107.6 26.5h.8v.3h-.8zM107.6 28.3h.8v.2h-.8zM107.6 30h.8v.2h-.8zM107.6 31.8h.8v.2h-.8zM107.6 33.5h.8v.2h-.8zM107.6 35.2h.8v.1h-.8zM107.6 37h.8v.1h-.8zM107.6 38.6h.8v.2h-.8zM110.2 26.5h.8v.3h-.8z"/>
<path d="M110.2 28.3h.8v.2h-.8zM110.2 30h.8v.2h-.8zM110.2 31.8h.8v.2h-.8zM110.2 33.5h.8v.2h-.8zM110.2 35.2h.8v.1h-.8zM110.2 37h.8v.1h-.8zM110.2 38.6h.8v.2h-.8zM111 26.6h2.7M111 28.4h2.7M111 30.1h2.7M111 31.9h2.7M111 33.6h2.7"/>
<path d="M111 35.3h2.7M111 37h2.7M111 38.7h2.7M117.9 39.6h.9v-.9l.9 .9-.9 .8v-.8M117.9 39.6h.1M125.7 26.6h1.7M125.7 28.4h1.7M125.7 30.1h1.7M125.7 31.9h1.7M125.7 33.6h1.7M125.7 35.3h1.7M125.7 37h1.7"/>
<path d="M125.7 38.7h1.7M209.3 26.6h3.3M209.3 28.4h3.3M209.3 30.1h3.3M209.3 31.9h3.3M209.3 33.6h3.3M209.3 35.3h3.3M209.3 37h3.3M209.3 38.7h3.3M212.6 24.9h10.3v20.6h-10.3zM217.8 21.5h.1M218.3 34.4h-.9v1.7"/>
<path d="M218.7 34.4h-.4v1.7h-1.3M223 26.6h3.4M223 28.4h3.4M223 30.1h3.4M223 31.9h3.4M223 33.6h3.4M223 35.3h3.4M223 37h3.4M223 38.7h3.4M227.2 32.7h3.4l.7 .9-.7 .8h-3.4l-.8-.8zM227.2 37.9h3.4l.7 .8-.7 .9h-3.4l-.8-.9zM227.2 36.1h3.4l.7 .9-.7 .9h-3.4l-.8-.9z"/>
<path d="M227.2 29.2h3.4l.7 .9-.7 .8h-3.4l-.8-.8zM227.2 34.4h3.4l.7 .9-.7 .8h-3.4l-.8-.8zM227.2 30.9h3.4l.7 1-.7 .8h-3.4l-.8-.8zM227.7 33.1a.47 .47 0 0 1 .5 .3 .47 .47 0 0 1-.2 .6h-.3zM227.7 38.3a.49 .49 0 0 1 .5 .3 .49 .49 0 0 1-.2 .6h-.3zM227.7 36.6h.3a.47 .47 0 0 1 .2 .6 .47 .47 0 0 1-.5 .3zM227.7 29.7a.47 .47 0 0 1 .5 .4 .47 .47 0 0 1-.5 .5zM227.7 34.8a.47 .47 0 0 1 .5 .5 .47 .47 0 0 1-.5 .5zM227.7 31.5h.3a.47 .47 0 0 1 .2 .5 .47 .47 0 0 1-.5 .3zM228.6 33.4l.1-.3v.9M228.6 38.6l.1-.3v.9M228.6 36.9l.1-.3v.9"/>
<path d="M228.6 29.9l.1-.2v.9M228.6 35.1l.1-.3v1M228.6 31.7l.1-.2v.8M228.6 34h.4M228.6 39.2h.4M228.6 37.5h.4M228.6 30.6h.4M228.6 35.8h.4M228.6 32.3h.4M229.3 33.2h.5v.3l-.5 .5h.5M229.3 34.8h.5l-.2 .4 .2 .1v.4h-.5M229.3 31.7l.3-.2v.8"/>
<path d="M229.3 32.3h.5M229.4 29.8l.3-.1 .1 .1v.6l-.1 .2a.53 .53 0 0 1-.3-.8zM229.6 36.5l-.3 .7h.6M229.7 36.9v.6M229.8 38.3h-.4l-.1 .4 .4-.1 .1 .5h-.5M245.4 26.6h3.5M245.4 28.4h3.5M245.4 30.1h3.5M245.4 31.9h3.5M245.4 33.6h3.5M245.4 35.3h3.5M245.4 37h3.5"/>
<path d="M245.4 38.7h3.5M248.8 24.9h10.4v20.6h-10.4zM254 21.5h.1M254.5 34.4h-.9v1.7M254.9 34.4h-.4v1.7h-1.3M259.2 26.6h3.4M259.2 28.4h3.4M259.2 30.1h3.4M259.2 31.9h3.4M259.2 33.6h3.4M259.2 35.3h3.4M259.2 37h3.4"/>
<path d="M259.2 38.7h3.4M263.4 30.9h2.6l.7 1-.7 .8h-2.6l-.8-.8zM263.4 32.7h2.6l.7 .9-.7 .8h-2.6l-.8-.8zM263.4 29.2h2.6l.7 .9-.7 .8h-2.6l-.8-.8zM263.4 27.6h2.6l.7 .8-.7 .8h-2.6l-.8-.8zM263.4 25.8h2.6l.7 .8-.7 1h-2.6l-.8-1zM263.4 36.1h2.6l.7 .9-.7 .9h-2.6l-.8-.9zM263.4 34.4h2.6l.7 .9-.7 .8h-2.6l-.8-.8zM263.4 37.9h2.6l.7 .8-.7 .9h-2.6l-.8-.9zM263.9 31.5h.3a.47 .47 0 0 1 .2 .5 .47 .47 0 0 1-.5 .3zM263.9 33.1a.47 .47 0 0 1 .5 .3 .47 .47 0 0 1-.2 .6h-.3zM263.9 29.7a.47 .47 0 0 1 .5 .4 .47 .47 0 0 1-.5 .5z"/>
<path d="M263.9 28a.47 .47 0 0 1 .5 .3 .47 .47 0 0 1-.2 .5h-.3zM263.9 26.3h.3a.47 .47 0 0 1 .2 .5 .47 .47 0 0 1-.5 .3zM263.9 36.6h.3l.1 .2a.42 .42 0 0 1 0 .5 .42 .42 0 0 1-.4 .2zM263.9 34.8a.47 .47 0 0 1 .5 .5 .47 .47 0 0 1-.5 .5zM263.9 38.3a.47 .47 0 0 1 .5 .3 .47 .47 0 0 1-.2 .6h-.3zM264.6 31.5h.6l-.3 .3h.2l.1 .3-.2 .2-.4-.1M264.6 38.3h.6l-.3 .9M264.7 29.8l.3-.1 .2 .2-.6 .7h.6M264.7 28.2l.3-.2v.8M264.7 28.8h.5M264.8 26.3a.43 .43 0 0 1 .4 .4 .43 .43 0 0 1-.3 .4l-.2-.1zM264.9 33.1l-.2 .6h.5"/>
<path d="M265.1 36.6l-.4 .2v.6l.3 .1 .2-.2-.1-.3h-.3l-.1 .1M265.1 34.8h-.4v.5l.3-.1 .2 .4-.2 .2-.3-.1M265.1 33.4v.6M99 43.9v-.9l-.9 .9 .9 .8v-.8h.9M99 40.4v-.8l-.9 .8 .9 .9v-.9h.9M99 50.8v-.9l-.9 .9 .9 .9v-.9h.9M99 57.7v-.8l-.9 .8 .9 .8v-.8h.9M99 54.2v-.8l-.9 .8 .9 .9v-.9h.9M99.9 43.9h.1M99.9 40.4h.1M99.9 50.8h.1M99.9 57.7h.1"/>
<path d="M99.9 54.2h.1M100.1 51.6h4.9v1.8h-4.9l-.7-.9zM100.7 51.9h3.8M100.9 52.1l.4 .2v.5l-.2 .2h-.2zM101.6 52.1h.5M101.8 52.1v.9M102.2 53l.3-.9 .3 .9M102.3 52.7h.4M103.6 52.2l-.4-.1-.1 .2v.5l.1 .2 .4-.1M103.9 52.1v.9M104.1 52.4l.3 .6M104.4 52.1l-.5 .5"/>
<path d="M105 42.2h2.6M105 43.9h2.6M105 40.4h2.6M105 45.6h2.6M105 47.4h2.6M105 49.1h2.6M105 50.8h2.6M105 52.5h2.6M105 54.2h2.6M105 55.9h2.6M105 57.7h2.6M105 59.4h2.6"/>
<path d="M107.6 40.3h.8v.2h-.8zM107.6 42.1h.8v.2h-.8zM107.6 43.8h.8v.2h-.8zM107.6 45.5h.8v.2h-.8zM107.6 47.3h.8v.2h-.8zM107.6 49h.8v.1h-.8zM107.6 50.7h.8v.1h-.8zM107.6 52.4h.8v.2h-.8zM107.6 54.1h.8v.2h-.8zM107.6 55.8h.8v.2h-.8zM107.6 57.6h.8v.2h-.8zM107.6 59.3h.8v.2h-.8z"/>
<path d="M110.2 40.3h.8v.2h-.8zM110.2 42.1h.8v.2h-.8zM110.2 43.8h.8v.2h-.8zM110.2 45.5h.8v.2h-.8zM110.2 47.3h.8v.2h-.8zM110.2 49h.8v.1h-.8zM110.2 50.7h.8v.1h-.8zM110.2 52.4h.8v.2h-.8zM110.2 54.1h.8v.2h-.8zM110.2 55.8h.8v.2h-.8zM110.2 57.6h.8v.2h-.8zM110.2 59.3h.8v.2h-.8z"/>
<path d="M111 42.2h2.7M111 43.9h2.7M111 40.4h2.7M111 45.6h2.7M111 47.4h2.7M111 49.1h2.7M111 50.8h2.7M111 52.5h2.7M111 54.2h2.7M111 55.9h2.7M111 57.7h2.7M111 59.4h2.7"/>
<path d="M113.7 43h7.3l.8 .9-.8 .8h-7.3zM114.1 43.2h6.3M114.3 43.9h.2M114.3 44.7h4.9v1.7h-4.9l-.6-.8zM114.6 43.5h-.3v.8h.3M114.8 45h3.7M114.8 45.7l.6-.1v-.3l-.6-.1v.9M114.9 43.5l.6 .8M115.1 45.7l.3 .4M115.5 43.5l-.6 .8M115.7 45.6h.3M115.8 43.9h.5v-.3l-.5-.1v.8"/>
<path d="M116.1 45.2h-.4v.9h.4M116.5 44.4h.6M117 45.3l-.4-.1-.1 .1v.3l.5 .2-.2 .3-.3-.1M117.3 43.9h.4l.1-.3-.2-.1h-.3v.8h.4l.1-.3-.2-.1M117.3 45.6h.3M117.7 45.2h-.4v.9h.4M118 45.2h.5M118.2 43.9h.3M118.2 45.2v.9M118.6 43.5h-.4v.8h.4M119 43.9h.4l.1-.3-.2-.1h-.3v.8M119.2 43.9l.3 .4"/>
<path d="M119.8 43.9h.5l.1-.3-.2-.1h-.4v.8M120 43.9l.4 .4M125.7 42.2h1.7M125.7 43.9h1.7M125.7 40.4h1.7M125.7 45.6h1.7M125.7 47.4h1.7M125.7 49.1h1.7M125.7 50.8h1.7M125.7 52.5h1.7M125.7 54.2h1.7M125.7 55.9h1.7"/>
<path d="M125.7 57.7h1.7M125.7 59.4h1.7M150.7 50.8v-.9l-.9 .9 .9 .9v-.9h.8M150.7 54.2v-.8l-.9 .8 .9 .9v-.9h.8M150.7 43.9v-.9l-.9 .9 .9 .8v-.8h.8M150.7 40.4v-.8l-.9 .8 .9 .9v-.9h.8M151.5 50.8h.1M151.5 54.2h.1M151.5 43.9h.1M151.5 40.4h.1M151.8 51.6h4.9v1.8h-4.9l-.7-.9zM152.4 51.9h3.8"/>
<path d="M152.5 52.1l.4 .1 .1 .4-.1 .4h-.4zM153.3 52.1h.5M153.5 52.1v.9M153.9 53l.3-.9 .3 .9M154 52.7h.4M155.2 52.2l-.3-.1-.2 .3 .2 .6 .3-.1M155.7 52.1v.9M155.7 52.4l.5 .6M156.2 52.1l-.5 .5M209.3 42.2h3.3M209.3 43.9h2.5M217.8 45.6v3.5"/>
<path d="M241 41.3h3.6l.8 .9-.8 .8h-3.6zM241.8 42.2h.5v-.4h-.5v.8M242 42.2l.3 .4M243.3 41.7l-.8 1.1M243.5 41.5h.8M243.5 41.8l.2 .8 .2-.6 .1 .6 .2-.8M245.4 42.2h3.5M245.4 43.9h2.5M254 49.1v.8h.9l-.9 .9-.8-.9h.8M254 49.1h.1M254 45.6v3.5M99 79.5l-.9 .5"/>
<path d="M105 68h2.6M105 71.4h2.6M105 69.7h2.6M105 61.1h2.6M105 62.9h2.6M105 64.6h2.6M105 66.2h2.6M105 73.2h2.6M105 74.9h2.6M105 76.7h2.6M105 78.4h2.6M107.6 61h.8v.2h-.8z"/>
<path d="M107.6 62.8h.8v.1h-.8zM107.6 64.5h.8v.1h-.8zM107.6 66.2h.8v.1h-.8zM107.6 67.9h.8v.2h-.8zM107.6 69.6h.8v.2h-.8zM107.6 71.3h.8v.2h-.8zM107.6 73.1h.8v.2h-.8zM107.6 74.8h.8v.2h-.8zM107.6 76.5h.8v.2h-.8zM107.6 78.3h.8v.1h-.8zM107.6 80h.8v.1h-.8zM110.2 61h.8v.2h-.8z"/>
<path d="M110.2 62.8h.8v.1h-.8zM110.2 64.5h.8v.1h-.8zM110.2 66.2h.8v.1h-.8zM110.2 67.9h.8v.2h-.8zM110.2 69.6h.8v.2h-.8zM110.2 71.3h.8v.2h-.8zM110.2 73.1h.8v.2h-.8zM110.2 74.8h.8v.2h-.8zM110.2 76.5h.8v.2h-.8zM110.2 78.3h.8v.1h-.8zM110.2 80h.8v.1h-.8zM111 68h2.7"/>
<path d="M111 71.4h2.7M111 69.7h2.7M111 61.1h2.7M111 62.9h2.7M111 64.6h2.7M111 66.2h2.7M111 73.2h2.7M111 74.9h2.7M111 76.7h2.7M111 78.4h2.7M118.8 78.4h.1M118.8 78.4h1.7"/>
<path d="M119.7 79.5l.8 .5M119.7 77.8l.8 .6M120.5 78.4l-.8 .5M125.7 68h1.7M125.7 71.4h1.7M125.7 69.7h1.7M125.7 61.1h1.7M125.7 62.9h1.7M125.7 64.6h1.7M125.7 66.2h1.7M125.7 73.2h1.7M125.7 74.9h1.7"/>
<path d="M125.7 76.7h1.7M125.7 78.4h1.7M128.1 62h3.3l.8 .9-.8 .8h-3.3l-.7-.8zM128.1 60.2h3.3v1.8h-3.3l-.7-.9zM128.2 72.3h4l.7 .9-.7 .8h-4zM128.2 68.9h4l.7 .8-.7 .9h-4zM128.7 72.5h2.8M128.7 69.1h2.8M128.9 69.3v.8M128.9 72.8v.8M129.1 62.4h-.5v.2l.1 .3h.4v.3l-.5 .1M129.1 60.7h-.5v.2l.5 .4v.2h-.5"/>
<path d="M129.2 73.2h.5v-.3l-.5-.1v.8M129.2 69.8l.5-.1v-.3l-.5-.1v.8M129.5 62.4h.3l.1 .2-.1 .7h-.3zM129.5 73.2l.2 .4M129.5 69.8l.2 .3M129.9 60.8l-.3-.1a.43 .43 0 0 0-.2 .6 .43 .43 0 0 0 .5 .2M130.2 63.3l.3-.9 .3 .9M130.3 73.4l.4 .3M130.3 72.8l.4 .2-.2 .6h-.3l-.1-.2zM130.3 70l.4 .2M130.3 69.3a.42 .42 0 0 1 .4 .4 .42 .42 0 0 1-.4 .4l-.2-.2zM130.3 63h.4"/>
<path d="M130.3 60.7v.9h.5M130.9 72.8h.6l-.3 .3h.2v.5l-.5-.1M131.4 69.3h-.4v.4l.4-.1 .1 .5h-.5M150.7 78.4v.5l-.9-.5 .9-.6v.6h.8M150.7 79.5l-.9 .5M151.5 78.4h.1M202.1 67.6h2.1M203.2 66.2v1.5M203.2 68.4v1.3M209.9 67.5h2.1v.3h-2.1zM209.9 68.2h2.1v.2h-2.1zM210.1 67h.3"/>
<path d="M210.3 66.8v.4M210.9 66.2v1.3M210.9 68.4v1.3M218.7 62.9v2.5M218.7 70.6v2.6M226.4 73.2v.8h.9l-.9 .9-.8-.9h.8M226.4 73.2h.1M241.9 68h1.8M241.9 71.4h1.8M243.7 66.2l6.8 3.5-6.8 3.4zM250.6 69.7h1.7M98.1 80h1.8"/>
<path d="M98.1 80l.9 .6M99.9 80h.1M105 80h2.6M109.3 87.8h.1M109.3 86.1l-.5 .9M109.3 86.1l.6 .9M109.3 86.1v1.7M111 80h2.7M118.8 80h.1M118.8 80h1.7M120.5 80l-.8 .6M125.7 80h1.7"/>
<path d="M149.8 80l.9 .6M149.8 80h1.7M151.5 80h.1M160.9 92.2h3.6l.8 .8-.8 .8h-3.6zM161.2 97.3h3.3l.8 .9-.8 .8h-3.3zM161.2 95.5h3.3l.8 .9-.8 .9h-3.3zM161.2 93.8h3.3l.8 .9-.8 .8h-3.3zM161.2 99h3.3l.8 .9-.8 .8h-3.3zM161.8 93h.3l.1-.3-.4-.1v.8M161.9 93l.3 .4M162 98.6l.3-.9 .2 .9M162 96.9l.3-.8 .2 .8"/>
<path d="M162 95.2l.3-.9 .2 .9M162 98.3h.4M162 96.6h.4M162 95h.4M162.8 97.8h.5v.3l-.5 .5h.5M162.8 96.1h.5v.3l-.5 .5h.5M162.8 94.4h.5v.3l-.5 .5h.5M162.8 99.5h.5v.4l-.5 .5h.5M163.2 92.6l-.8 1.1M163.4 92.6l.2 .8 .2-.6 .2 .6 .1-.8M163.4 92.3h.8M163.5 94.3h.6l-.3 .3 .3 .2v.2l-.1 .2-.5-.1"/>
<path d="M163.6 98l.3-.3v.9M163.6 96.1h.4l.1 .2-.6 .6h.6M163.6 98.6h.5M163.8 99.4a.48 .48 0 0 1 .3 .5 .48 .48 0 0 1-.3 .5l-.2-.2v-.6zM173.9 87.8h.1M173.9 86.1l-.5 .9M173.9 86.1l.6 .9M173.9 86.1v1.7M202.1 96h2.1M202.1 83.1h2.1M203.2 81.8v1.4M203.2 83.9v1.3"/>
<path d="M203.2 94.7v1.4M203.2 96.8v1.4M209.9 96h2.1v.2h-2.1zM209.9 96.6h2.1v.3h-2.1zM209.9 83h2.1v.3h-2.1zM209.9 83.7h2.1v.2h-2.1zM210.1 95.4h.3M210.1 82.5h.3M210.3 82.3v.4M210.3 95.2v.3M210.9 81.8v1.2M210.9 83.9v1.3"/>
<path d="M210.9 94.7v1.3M210.9 96.9v1.3M162 100.4l.3-1 .2 1M162 100.1h.4"/>
<circle cx="212.2" cy="43.9" r=".47"/>
<circle cx="248.5" cy="43.9" r=".47"/>
</g>
<g fill="none" stroke="#0f0f0f" stroke-width=".21">
<path d="M100.4 34.5h.2M100.4 36.2h.2M100.4 37.9h.2M100.4 25.9h.2M100.4 27.6h.2M100.4 31h.2M100.4 32.7h.2M100.8 34.1h-.4v.8h.4M100.8 37.5h-.4v.9h.4M100.8 35.8h-.4v.8h.4M100.8 30.6h-.4v.9h.4M100.8 25.4h-.4v.9h.4"/>
<path d="M100.8 27.2h-.4v.9h.4M100.8 32.4h-.4v.8h.4M101 34.1l.6 .8M101 37.5l.6 .9M101 35.8l.6 .8M101 30.6l.6 .9M101 25.4l.6 .9M101 27.2l.6 .9M101 32.4l.6 .8M101.6 34.1l-.6 .8M101.6 37.5l-.6 .9M101.6 35.8l-.6 .8"/>
<path d="M101.6 30.6l-.6 .9M101.6 25.4l-.6 .9M101.6 27.2l-.6 .9M101.6 32.4l-.6 .8M102 34.5h.3l.1-.3-.4-.1v.8M102 38l.4-.1-.1-.4h-.3v.9M102 36.3l.4-.1-.1-.4h-.3v.8M102 31.1l.4-.1-.1-.4h-.3v.9M102 25.9h.4l-.1-.5h-.3v.9M102 27.6h.4l-.1-.4h-.3v.9M102 32.8l.4-.1-.1-.3h-.3v.8M102.6 35h.6"/>
<path d="M102.6 36.7h.6M102.6 38.5h.6M102.6 26.4h.6M102.6 28.1h.6M102.6 31.5h.6M102.6 33.3h.6M103.5 34.1l.4 .1v.6l-.1 .1h-.3zM103.5 37.5l.4 .2v.4l-.2 .3h-.2zM103.5 35.8l.4 .2v.4l-.1 .2h-.3zM103.5 30.6l.4 .3v.4l-.1 .2h-.3zM103.5 25.4l.4 .3v.4l-.1 .2h-.3zM103.5 27.2l.4 .2v.4l-.2 .3h-.2z"/>
<path d="M103.5 32.4l.4 .2v.4l-.2 .2h-.2zM104.3 35.8h.6l-.5 .8M104.3 30.6h.5l-.3 .3 .3 .1v.4h-.5M104.3 27.4l.2-.2v.9M104.3 28.1h.5M104.3 25.5l.3-.1 .2 .2-.1 .7h-.3l-.1-.3zM104.5 32.3l-.2 .6h.6M104.7 37.5h-.3l-.1 .7 .1 .2 .4-.1v-.4l-.5 .1M104.7 32.6v.6M104.8 34.1h-.5v.4l.4-.1 .1 .4h-.5M113.9 34.5h.3M113.9 36.2h.3"/>
<path d="M113.9 37.9h.3M113.9 25.9h.3M113.9 27.6h.3M113.9 29.3h.3M113.9 31h.3M113.9 32.7h.3M114.3 37.5h-.4v.9h.4M114.3 35.8h-.4v.8h.4M114.3 34.1h-.4v.8h.4M114.3 32.4h-.4v.8h.4M114.3 30.6h-.4v.9h.4M114.3 28.9h-.4v.9h.4"/>
<path d="M114.3 25.4h-.4v.9h.4M114.3 27.2h-.4v.9h.4M114.6 37.5l.6 .9M114.6 35.8l.6 .8M114.6 34.1l.6 .8M114.6 32.4l.6 .8M114.6 30.6l.6 .9M114.6 28.9l.6 .9M114.6 25.4l.6 .9M114.6 27.2l.6 .9M115.2 37.5l-.6 .9M115.2 35.8l-.6 .8"/>
<path d="M115.2 34.1l-.6 .8M115.2 32.4l-.6 .8M115.2 30.6l-.6 .9M115.2 28.9l-.6 .9M115.2 25.4l-.6 .9M115.2 27.2l-.6 .9M115.5 38l.4-.1v-.4h-.4v.9M115.5 36.3l.4-.1v-.4h-.4v.8M115.5 34.5h.4v-.3l-.4-.1v.8M115.5 32.8l.4-.1v-.3h-.4v.8M115.5 31.1l.4-.1v-.4h-.4v.9M115.5 29.3l.4-.1v-.3h-.4v.9"/>
<path d="M115.5 25.9h.4v-.5h-.4v.9M115.5 27.6h.4v-.4h-.4v.9M116.1 35h.7M116.1 36.7h.7M116.1 38.5h.7M116.1 26.4h.7M116.1 28.1h.7M116.1 29.8h.7M116.1 31.5h.7M116.1 33.3h.7M117 37.5l.5 .2v.4l-.3 .3h-.2zM117 35.8l.5 .2v.4l-.2 .2h-.3z"/>
<path d="M117 34.1l.5 .1v.6l-.2 .1h-.3zM117 32.4l.5 .2v.4l-.3 .2h-.2zM117 30.6l.5 .3v.4l-.2 .2h-.3zM117 28.9l.5 .2v.5l-.2 .2h-.3zM117 25.4l.5 .3v.4l-.2 .2h-.3zM117 27.2l.5 .2v.4l-.3 .3h-.2zM117.8 37.8l.3-.3v.9M117.8 36l.3-.2v.8M117.8 34.3l.3-.2v.8M117.8 32.6l.3-.2v.8M117.8 30.9l.3-.3v.9M117.8 29.2l.3-.3v.9"/>
<path d="M117.8 38.4h.5M117.8 36.6h.5M117.8 34.9h.5M117.8 33.2h.5M117.8 31.5h.5M117.8 29.8h.5M118 25.9l-.2-.3 .2-.2 .3 .1v.3l-.4 .1v.4l.4-.1v-.3h-.2M118.3 27.6l-.3 .1-.2-.4h.5l-.1 .7-.3 .1M118.6 34.1h.6l-.4 .3h.3v.5l-.5-.1M118.7 32.5l.4-.1 .1 .2-.6 .6h.6M118.7 30.9l.2-.3v.9M118.7 31.5h.5"/>
<path d="M118.7 28.9a.42 .42 0 0 1 .5 .4 .42 .42 0 0 1-.5 .5zM118.8 35.8l-.1 .6h.5M119.1 37.5h-.4v.4h.4l.1 .3-.2 .2-.3-.1M119.1 36.1v.5M127.5 33.8h6.7M127.5 37.3h6.7M127.5 30.3h6.7M127.5 25.2h6.3M127.7 34.5h.3M127.7 37.9h.3M127.7 25.9h.3M127.7 31h.3"/>
<path d="M128.1 34.1h-.4v.8h.4M128.1 37.5h-.4v.9h.4M128.1 30.6h-.4v.9h.4M128.1 25.4h-.4v.9h.4M128.4 34.1l.6 .8M128.4 37.5l.6 .9M128.4 30.6l.6 .9M128.4 25.4l.6 .9M129 34.1l-.6 .8M129 37.5l-.6 .9M129 30.6l-.6 .9M129 25.4l-.6 .9"/>
<path d="M129.2 34.5h.5v-.3l-.5-.1v.8M129.2 38l.5-.1v-.3l-.5-.1v.9M129.2 31.1l.5-.1v-.3l-.5-.1v.9M129.2 25.9h.5v-.4l-.5-.1v.9M129.9 35h.7M129.9 38.5h.7M129.9 26.4h.7M129.9 31.5h.7M130.8 34.5h.3l.2-.2-.1-.2h-.4v.8h.4l.1-.3-.2-.1M130.8 37.9h.4v-.4h-.4v.9l.5-.1v-.3l-.2-.1M130.8 31h.4l.1-.2-.2-.2h-.3v.9h.4l.1-.4-.2-.1M130.8 25.9h.4l.1-.3-.2-.2h-.3v.9h.4l.1-.4h-.2"/>
<path d="M131.7 25.9h.3l.1-.3-.2-.2h-.2v.9h.3l.1-.4h-.2M132.1 34.1l-.4 .1-.1 .4 .2 .3h.3v-.3h-.2M132.1 37.5h-.3a.43 .43 0 0 0-.2 .6 .43 .43 0 0 0 .5 .2v-.3h-.2M132.1 30.7l-.1-.1a.48 .48 0 0 0-.4 .3 .48 .48 0 0 0 .2 .6h.3v-.4h-.2M132.5 34.3l.4 .6M132.5 37.8l.4 .6M132.5 30.9l.4 .6M132.9 34.3l-.4 .6M132.9 37.8l-.4 .6M132.9 30.9l-.4 .6M133 25.5l-.4-.1-.1 .2v.3l.5 .1v.2l-.5 .1M133.2 25.4l.3 .5 .3-.5"/>
<path d="M133.2 30.6v.9M133.2 34.1v.8M133.2 37.5v.9M133.5 25.9v.4M134.2 34.1v.8l-.6-.8v.8M134.2 37.5v.9l-.6-.9v.9M134.2 30.6v.9l-.6-.9v.9M152 34.5h.4M152 36.2h.4M152 37.9h.4M152 25.9h.4M152 27.6h.4"/>
<path d="M152 29.3h.4M152 31h.4M152 32.7h.4M152.4 37.5h-.4v.9h.4M152.4 35.8h-.4v.8h.4M152.4 32.4h-.4v.8h.4M152.4 30.6h-.4v.9h.4M152.4 28.9h-.4v.9h.4M152.4 25.4h-.4v.9h.4M152.4 27.2h-.4v.9h.4M152.4 34.1h-.4v.8h.4M152.7 37.5l.6 .9"/>
<path d="M152.7 35.8l.6 .8M152.7 32.4l.6 .8M152.7 30.6l.6 .9M152.7 28.9l.6 .9M152.7 25.4l.6 .9M152.7 27.2l.6 .9M152.7 34.1l.6 .8M153.3 37.5l-.6 .9M153.3 35.8l-.6 .8M153.3 32.4l-.6 .8M153.3 30.6l-.6 .9M153.3 28.9l-.6 .9"/>
<path d="M153.3 25.4l-.6 .9M153.3 27.2l-.6 .9M153.3 34.1l-.6 .8M153.6 38h.4l.1-.2-.1-.3h-.4v.9M153.6 36.3h.4l.1-.2-.1-.3h-.4v.8M153.6 32.8h.4l.1-.2-.1-.2h-.4v.8M153.6 31.1h.4l.1-.2-.1-.3h-.4v.9M153.6 29.3h.4v-.4h-.4v.9M153.6 25.9h.4l.1-.1-.1-.4h-.4v.9M153.6 27.6h.4l.1-.3-.5-.1v.9M153.6 34.5h.4v-.4h-.4v.8M154.3 35h.7"/>
<path d="M154.3 36.7h.7M154.3 38.5h.7M154.3 26.4h.7M154.3 28.1h.7M154.3 29.8h.7M154.3 31.5h.7M154.3 33.3h.7M155.1 37.5h.4a.48 .48 0 0 1 .1 .6 .48 .48 0 0 1-.5 .3zM155.1 35.8a.49 .49 0 0 1 .5 .3 .49 .49 0 0 1-.1 .5h-.4zM155.1 32.4h.4a.48 .48 0 0 1 .1 .5 .48 .48 0 0 1-.5 .3zM155.1 30.6a.49 .49 0 0 1 .5 .3 .49 .49 0 0 1-.1 .6h-.4zM155.1 28.9l.5 .1 .1 .4-.2 .4h-.4z"/>
<path d="M155.1 25.4a.49 .49 0 0 1 .5 .3 .49 .49 0 0 1-.1 .6h-.4zM155.1 27.2h.4a.48 .48 0 0 1 .1 .6 .48 .48 0 0 1-.5 .3zM155.1 34.1l.5 .1 .1 .4-.2 .3h-.4zM155.9 35.8h.6l-.3 .8M155.9 30.6h.5l-.2 .3 .2 .1v.4h-.5M156 29l.3-.1 .1 .3-.5 .6h.5M156 27.4l.2-.2v.9M156 28.1h.4M156.2 32.3l-.2 .6h.5M156.2 25.4l.2 .2-.1 .7h-.2l-.1-.2v-.5zM156.3 37.5l-.3 .2v.6h.4v-.4l-.4 .1M156.3 32.6v.6"/>
<path d="M156.4 34.1h-.4v.4l.3-.1 .1 .4h-.4M240.7 34.5h.3M240.7 36.2h.3M240.7 37.9h.3M240.7 25.9h.3M240.7 27.6h.3M240.7 29.3h.3M240.7 31h.3M240.7 32.7h.3M241.2 34.1h-.5v.8h.5M241.2 35.8h-.5v.8h.5M241.2 37.5h-.5v.9h.5"/>
<path d="M241.2 25.4h-.5v.9h.5M241.2 27.2h-.5v.9h.5M241.2 28.9h-.5v.9h.5M241.2 30.6h-.5v.9h.5M241.2 32.4h-.5v.8h.5M241.4 34.1l.6 .8M241.4 35.8l.6 .8M241.4 37.5l.6 .9M241.4 25.4l.6 .9M241.4 27.2l.6 .9M241.4 28.9l.6 .9M241.4 30.6l.6 .9"/>
<path d="M241.4 32.4l.6 .8M242 34.1l-.6 .8M242 35.8l-.6 .8M242 37.5l-.6 .9M242 25.4l-.6 .9M242 27.2l-.6 .9M242 28.9l-.6 .9M242 30.6l-.6 .9M242 32.4l-.6 .8M242.4 34.5h.4v-.4h-.4v.8M242.4 36.3h.3l.2-.2-.2-.3h-.3v.8M242.4 38h.3l.2-.2-.1-.3h-.4v.9"/>
<path d="M242.4 25.9h.3l.2-.1-.2-.4h-.3v.9M242.4 27.6h.3l.2-.3-.5-.1v.9M242.4 29.3h.4v-.4h-.4v.9M242.4 31.1h.3l.2-.2-.2-.3h-.3v.9M242.4 32.8h.3l.2-.2-.1-.2h-.4v.8M243 35h.6M243 36.7h.6M243 38.5h.6M243 26.4h.6M243 28.1h.6M243 29.8h.6M243 31.5h.6"/>
<path d="M243 33.3h.6M243.9 34.1l.4 .1 .1 .4-.2 .3h-.3zM243.9 35.8a.49 .49 0 0 1 .4 .3 .49 .49 0 0 1-.1 .5h-.3zM243.9 37.5h.3a.48 .48 0 0 1 .2 .6 .48 .48 0 0 1-.5 .3zM243.9 25.4a.49 .49 0 0 1 .4 .3 .49 .49 0 0 1-.1 .6h-.3zM243.9 27.2h.3a.48 .48 0 0 1 .2 .6 .48 .48 0 0 1-.5 .3zM243.9 28.9l.4 .1 .1 .4-.2 .4h-.3zM243.9 30.6a.49 .49 0 0 1 .4 .3 .49 .49 0 0 1-.1 .6h-.3zM243.9 32.4h.3a.48 .48 0 0 1 .2 .5 .48 .48 0 0 1-.5 .3zM244.6 37.5h.6l-.4 .9M244.6 27.4l.3-.2v.9M244.6 29h.5v.2l-.5 .6h.5"/>
<path d="M244.6 30.6h.5l-.2 .3 .2 .1v.4h-.5M244.6 28.1h.5M244.7 25.5l.3-.1 .1 .2v.7h-.3l-.2-.3zM244.9 32.3l-.3 .6h.6M245.1 35.8l-.3 .1-.2 .6h.5v-.3l-.3-.1-.2 .2M245.1 32.6v.6M245.1 34.1h-.4l-.1 .4 .5-.1v.4h-.5M93.5 46.8h5.3M93.6 47.4h.3M94 47h-.4v.9h.4M94.4 47l.5 .9M94.9 47l-.5 .9"/>
<path d="M95.2 47.5l.5-.1v-.4h-.5v.9M95.9 48h.7M96.7 47v.9h.5M97.4 47h.3l.2 .2v.4l-.2 .3h-.3zM98.2 58.8h5.8M98.3 59.5h.3M98.5 49.1h.3M98.5 45h5.5M98.6 45.7h.2M98.6 41.6h5.4M98.7 59.1h-.4v.8h.4M98.8 47l-.5 .1v.3l.5 .2-.2 .3-.3-.1"/>
<path d="M98.8 42.2h.2M98.9 48.7h-.4v.9h.4M99 45.3h-.4v.8h.4M99 59.1l.6 .8M99.2 41.8h-.4v.9h.4M99.3 45.3l.6 .8M99.3 48.7l.5 .9M99.4 41.8l.6 .9M99.5 55.3h4.5M99.6 59.1l-.6 .8M99.6 56h.3M99.8 48.7l-.5 .9"/>
<path d="M99.9 59.5h.4l.1-.4h-.5v.8M99.9 45.3l-.6 .8M100 55.6h-.4v.8h.4M100 41.8l-.6 .9M100.1 49.1h.4l.1-.3-.5-.1v.9M100.2 45.8h.3l.2-.2-.2-.3h-.3v.8M100.3 55.6l.6 .8M100.4 42.3h.3l.2-.2-.2-.3h-.3v.9M100.5 60h.7M100.8 49.7h.7M100.9 46.2h.6M100.9 55.6l-.6 .8"/>
<path d="M101 42.8h.6M101.2 56.1h.4l.1-.4-.1-.1h-.4v.8M101.4 59.1v.8M101.6 49.1h.5v-.3l-.5-.1v.9M101.7 59.9l.3-.8 .3 .8M101.7 45.3l.1 .8h.3l.1-.8M101.8 59.6h.4M101.9 56.5h.6M101.9 49.1l.2 .5M102.3 41.9a.4 .4 0 0 0-.5 .3 .4 .4 0 0 0 .5 .4M102.5 49.1l.2-.1 .2 .1v.5M102.5 49v.6"/>
<path d="M102.6 56.4l.3-.8 .3 .8M102.6 45.3h.2l.3 .2v.4l-.2 .2h-.3zM102.7 56.3h.4M102.7 41.8v.9h.5M103.1 59.1h-.4l-.2 .3 .2 .5 .4-.1M103.2 48.7l.2 .9 .2-.6 .2 .6 .1-.9M103.4 41.8v.9M103.4 59.1v.8M103.6 59.4l.3 .5M103.6 42.2l.3 .5M103.9 55.7l-.3-.1-.2 .1 .1 .3 .4 .3-.1 .1h-.4M103.9 45.3h-.3l-.2 .1 .1 .3 .4 .1-.1 .3h-.4"/>
<path d="M103.9 59.1l-.5 .5M103.9 41.8l-.5 .5M113.7 40.7h8M113.9 51.7h.3M113.9 50h.3M113.9 55.2h.3M113.9 53.5h.3M113.9 58.6h.3M113.9 56.9h.3M113.9 41.4h.3M114.3 58.2h-.4v.9h.4M114.3 59.9h-.4v.8h.4"/>
<path d="M114.3 53h-.4v.9h.4M114.3 56.4h-.4v1h.4M114.3 51.3h-.4v.9h.4M114.3 49.6h-.4v.8h.4M114.3 54.7h-.4v.9h.4M114.3 40.9h-.4v.9h.4M114.6 58.2l.6 .9M114.6 59.9l.6 .8M114.6 53l.6 .9M114.6 56.4l.6 1M114.6 51.3l.6 .9M114.6 49.6l.6 .8"/>
<path d="M114.6 54.7l.6 .9M114.6 40.9l.6 .9M115.2 58.2l-.6 .9M115.2 59.9l-.6 .8M115.2 53l-.6 .9M115.2 56.4l-.6 1M115.2 51.3l-.6 .9M115.2 49.6l-.6 .8M115.2 54.7l-.6 .9M115.2 40.9l-.6 .9M115.5 58.6h.4v-.3l-.4-.1v.9M115.5 53.5h.4v-.4l-.4-.1v.9"/>
<path d="M115.5 56.9h.4v-.5h-.4v1M115.5 51.8l.4-.1v-.4h-.4v.9M115.5 50l.4-.1v-.3h-.4v.8M115.5 55.2l.4-.1v-.4h-.4v.9M115.5 41.4h.4v-.5h-.4v.9M116.1 52.3h.7M116.1 50.5h.7M116.1 55.7h.7M116.1 54h.7M116.1 59.1h.7M116.1 57.4h.7M116.1 41.9h.7"/>
<path d="M116.9 59.1l.3-.9 .3 .9M116.9 53.9l.3-.9 .3 .9M116.9 57.4l.3-1 .3 1M116.9 52.2l.3-.9 .3 .9M116.9 50.4l.3-.8 .3 .8M116.9 55.6l.3-.9 .3 .9M117 51.9h.4M117 50.2h.4M117 55.3h.4M117 53.6h.4M117 58.8h.4M117 57.1h.4"/>
<path d="M117.2 46.8h7.3M117.3 47.4h.3M117.5 41l-.4-.1-.1 .2 .5 .6-.5 .1M117.7 58.5l.3-.3v.9M117.7 47h-.4v.9h.4M117.7 53.1l.4-.1 .1 .3-.6 .6h.6M117.7 56.7l.3-.3v1M117.7 51.3h.4l.1 .2-.6 .7h.6M117.7 49.7l.4-.1 .1 .2-.6 .6h.6M117.7 54.8l.4-.1 .1 .3-.6 .6h.6M117.7 40.9l.3 .5 .3-.5M117.7 59.1h.5"/>
<path d="M117.7 57.4h.5M118 41.4v.4M118.1 47l.5 .9M118.5 59.9h.6l-.4 .8M118.5 53.3l.2-.3v.9M118.5 51.3h.5v.4l-.5 .5h.5M118.5 49.6h.5l-.3 .3 .3 .1v.3h-.5M118.5 53.9h.5M118.6 54.8l.2-.1 .2 .2-.1 .6a.39 .39 0 0 1-.4-.2 .39 .39 0 0 1 .1-.5zM118.6 47l-.5 .9M118.7 58.5l-.2-.1 .1-.2 .4 .1-.1 .2-.4 .2 .2 .4 .3-.1v-.4l-.2-.1M118.9 47.5l.5-.1v-.4h-.5v.9"/>
<path d="M119 56.9l-.3 .1-.2-.4 .2-.2 .3 .1v.6l-.4 .3M119 41l-.3-.1-.2 .2 .1 .3 .4 .1v.3h-.5M119.1 49.1h.2M119.4 41.4h.3M119.5 48.7h-.4v.9h.4M119.6 48h.7M119.8 48.7l.6 .9M119.8 40.9h-.4v.9M120 41.8l.3-.9 .3 .9M120.1 41.6h.4M120.4 48.7l-.6 .9M120.4 47v.9h.5"/>
<path d="M120.7 49.1h.4v-.4h-.4v.9M120.9 40.9v.9M121.1 47l.2 .9 .2-.7 .1 .7 .2-.9M121.3 40.9v.9h.4M121.3 49.7h.7M122 49.6l.4-.9 .2 .9M122.1 47.1h.5v.6l-.1 .2-.4-.2zM122.1 49.3h.5M122.9 49.6v-.9l.3 .6 .3-.6v.9M123.1 47.5h.3l.2-.4-.5-.1v.9M123.2 47.5l.4 .4M123.9 47h.3a.48 .48 0 0 1 .2 .6 .48 .48 0 0 1-.5 .3z"/>
<path d="M124.3 48.7h-.4l-.1 .4h.4l.1 .4h-.5M127.5 40.7h6.7M127.7 41.4h.3M128.1 40.9h-.4v.9h.4M128.4 40.9l.6 .9M128.6 51.7h.2M128.6 55.2h.2M128.6 53.5h.2M128.6 56.9h.2M129 54.7h-.4v.9h.4M129 51.3h-.4v.9h.4M129 56.4h-.4v1h.4"/>
<path d="M129 53h-.4v.9h.4M129 40.9l-.6 .9M129.2 41.4h.5v-.4l-.5-.1v.9M129.2 54.7l.6 .9M129.2 51.3l.6 .9M129.2 56.4l.6 1M129.2 53l.6 .9M129.8 54.7l-.6 .9M129.8 51.3l-.6 .9M129.8 56.4l-.6 1M129.8 53l-.6 .9M129.9 41.9h.7"/>
<path d="M130.2 55.2h.3l.1-.4-.4-.1v.9M130.2 51.8l.4-.1v-.4h-.4v.9M130.2 56.9h.4v-.4l-.4-.1v1M130.2 53.5h.3l.1-.4-.4-.1v.9M130.8 41.4h.4l.1-.3-.2-.2h-.3v.9h.5v-.4h-.2M130.8 52.3h.6M130.8 55.7h.6M130.8 54h.6M130.8 57.4h.6M131.5 55.6l.3-.9 .3 .9M131.5 52.2l.3-.9 .3 .9M131.5 57.4l.3-1 .3 1"/>
<path d="M131.5 53.9l.3-.9 .3 .9M131.6 51.9h.4M131.6 55.3h.4M131.6 53.6h.4M131.6 57.1h.4M132.1 41l-.1-.1a.48 .48 0 0 0-.4 .4 .48 .48 0 0 0 .2 .5h.3v-.4h-.2M132.4 55.6v-.9l.3 .6 .3-.6v.9M132.4 52.2v-.9l.3 .6 .3-.6v.9M132.4 57.4v-1l.3 .7 .3-.7v1M132.4 53.9v-.9l.3 .6 .3-.6v.9M132.5 41.3l.4 .5M132.9 41.3l-.4 .5"/>
<path d="M133.2 40.9v.9M133.3 54.8h.5v.3l-.5 .5h.5M133.3 56.4h.5l-.2 .4 .2 .1v.4h-.5M133.3 53.3l.3-.3v.9M133.3 53.9h.5M133.4 51.3h.2l.2 .1v.6l-.2 .2a.53 .53 0 0 1-.2-.9zM134.2 40.9v.9l-.6-.9v.9M145.2 46.8h5.3M145.3 47.4h.3M145.8 47h-.5v.9h.5M146 47l.6 .9M146.6 47l-.6 .9"/>
<path d="M146.9 47.5l.5-.1v-.4h-.5v.9M147.5 48h.7M148.4 47v.9h.4M149.1 47h.4a.48 .48 0 0 1 .1 .6 .48 .48 0 0 1-.5 .3zM150.2 45h5.5M150.2 49.1h.3M150.2 45.7h.4M150.3 41.6h5.4M150.4 47l-.5 .1 .1 .3 .4 .1v.3h-.5M150.4 42.2h.3M150.7 48.7h-.5v.9h.5M150.7 45.3h-.5v.8h.5"/>
<path d="M150.8 41.8h-.4v.9h.4M150.9 48.7l.6 .9M151 45.3l.5 .8M151.1 41.8l.6 .9M151.5 48.7l-.6 .9M151.5 45.3l-.5 .8M151.7 41.8l-.6 .9M151.8 49.1h.5v-.4h-.5v.9M151.8 45.8l.6-.1v-.4h-.6v.8M152 42.3h.4l.1-.2-.1-.3h-.4v.9M152.4 49.7h.7M152.5 46.2h.7"/>
<path d="M152.7 42.8h.7M153.4 49.1h.3l.1-.3-.4-.1v.9M153.4 45.3l.1 .8h.3l.1-.8M153.5 49.1l.3 .5M154 41.9l-.2-.1-.3 .2 .1 .6h.4M154.2 49.1h.4v.5M154.2 49v.6M154.3 45.3a.49 .49 0 0 1 .5 .3 .49 .49 0 0 1-.2 .5h-.3zM154.4 41.8v.9h.4M154.9 48.7l.2 .9 .1-.6 .2 .6 .3-.9M155.1 41.8v.9M155.2 42.2l.4 .5"/>
<path d="M155.6 45.3h-.4l-.1 .1v.3l.5 .1v.2l-.5 .1M155.6 41.8l-.5 .5M165.6 51.7h.3M165.6 50h.3M165.6 55.2h.3M165.6 53.5h.3M165.6 58.6h.3M165.6 56.9h.3M166 51.3h-.4v.9h.4M166 49.6h-.4v.8h.4M166 54.7h-.4v.9h.4M166 59.9h-.4v.8h.4"/>
<path d="M166 53h-.4v.9h.4M166 58.2h-.4v.9h.4M166 56.4h-.4v1h.4M166.2 51.3l.6 .9M166.2 49.6l.6 .8M166.2 54.7l.6 .9M166.2 59.9l.6 .8M166.2 53l.6 .9M166.2 58.2l.6 .9M166.2 56.4l.6 1M166.8 51.3l-.6 .9M166.8 49.6l-.6 .8"/>
<path d="M166.8 54.7l-.6 .9M166.8 59.9l-.6 .8M166.8 53l-.6 .9M166.8 58.2l-.6 .9M166.8 56.4l-.6 1M167.2 51.8h.3l.2-.2-.2-.3h-.3v.9M167.2 50h.4l.1-.3-.2-.1h-.3v.8M167.2 55.2h.4l.1-.3-.2-.2h-.3v.9M167.2 53.5h.4v-.5h-.4v.9M167.2 58.6h.4v-.4h-.4v.9M167.2 56.9h.3l.2-.1-.2-.4h-.3v1M167.8 52.3h.7"/>
<path d="M167.8 50.5h.7M167.8 55.7h.7M167.8 54h.7M167.8 59.1h.7M167.8 57.4h.7M168.5 52.2l.4-.9 .2 .9M168.5 50.4l.4-.8 .2 .8M168.5 55.6l.4-.9 .2 .9M168.5 53.9l.4-.9 .2 .9M168.5 59.1l.4-.9 .2 .9M168.5 57.4l.4-1 .2 1M168.6 51.9h.4"/>
<path d="M168.6 50.2h.4M168.6 55.3h.4M168.6 53.6h.4M168.6 58.8h.4M168.6 57.1h.4M169.4 51.3h.3l.2 .1-.5 .8h.5M169.4 49.7l.3-.1 .2 .1-.5 .7h.5M169.4 54.8l.3-.1 .2 .2-.5 .7h.5M169.4 53.1l.4-.1 .1 .2-.5 .7h.5M169.4 58.5l.2-.3v.9M169.4 56.7l.2-.3v1M169.4 59.1h.5"/>
<path d="M169.4 57.4h.5M170.1 49.6h.6l-.3 .3h.2l.1 .2-.1 .3-.5-.1M170.1 59.9h.6l-.3 .8M170.2 51.3h.4l.1 .2-.6 .7h.6M170.2 53.3l.3-.3v.9M170.2 53.9h.5M170.4 54.7a.43 .43 0 0 1 .3 .5 .43 .43 0 0 1-.4 .4l-.1-.7zM170.4 58.5l-.2-.2 .4-.1v.3l-.4 .1v.4l.2 .1 .3-.2-.1-.4M170.7 56.9l-.1 .1-.4-.1v-.4l.4-.1 .1 .2-.1 .7-.3 .1M239.7 43.6l.4 .8 .2-.8M239.7 43.3h4.7M240.6 44.4v-.8l.3 .6 .3-.6v.8"/>
<path d="M241.6 44h.2M242 43.6h-.4v.8h.4M242.9 43.6h-.5v.3l.5 .3-.1 .2h-.4M243.2 44h.3M243.6 43.6h-.4v.8h.4M244 43.6v.8h.4M96.9 60.5h7.1M97 61.2h.2M97.4 60.7h-.4v.9h.4M97.7 60.7l.6 .9M98.3 60.7l-.6 .9M98.6 61.3h.3l.2-.4-.2-.2h-.3v.9"/>
<path d="M98.6 63.8h.3M99 63.4h-.4v.8h.4M99.3 61.7h.6M99.4 63.4l.5 .8M99.9 63.4l-.5 .8M100.1 60.7v.9M100.2 63.8h.4l.1-.3-.5-.1v.8M100.4 61.6l.3-.9 .3 .9M100.5 67.2h.3M100.5 65.5h.3M100.5 69h.3M100.5 61.4h.4"/>
<path d="M100.5 70.7h.3M100.5 74.1h.3M100.5 75.8h.3M100.5 72.3h.3M100.9 66.8h-.4v.9h.4M100.9 65.1h-.4v.8h.4M100.9 70.2h-.4v.9h.4M100.9 73.7h-.4v.8h.4M100.9 75.4h-.4v.8h.4M100.9 72h-.4v.9h.4M100.9 68.5h-.4v.9h.4M100.9 64.3h.7"/>
<path d="M101.1 66.8l.6 .9M101.1 65.1l.6 .8M101.1 70.2l.6 .9M101.1 73.7l.6 .8M101.1 75.4l.6 .8M101.1 72l.6 .9M101.1 68.5l.6 .9M101.6 64.2l.3-.8 .3 .8M101.7 60.8l-.2-.1-.3 .3v.4l.2 .2 .3-.1M101.7 64h.4M101.7 66.8l-.6 .9M101.7 65.1l-.6 .8"/>
<path d="M101.7 70.2l-.6 .9M101.7 73.7l-.6 .8M101.7 75.4l-.6 .8M101.7 72l-.6 .9M101.7 68.5l-.6 .9M102.1 67.3h.3l.2-.4-.5-.1v.9M102.1 65.5h.4l.1-.3-.2-.1h-.3v.8M102.1 70.7h.3l.2-.3-.2-.2h-.3v.9M102.1 74.1h.4v-.4h-.4v.8M102.1 75.9h.3l.2-.3-.2-.2h-.3v.8M102.1 72.4h.3l.2-.3-.5-.1v.9M102.1 69h.4v-.5h-.4v.9"/>
<path d="M102.1 60.7v.9M102.2 61.2l.4 .4M102.5 64.2v-.8l.2 .6 .4-.6v.8M102.6 60.7l-.5 .6M102.7 67.8h.7M102.7 66h.7M102.7 69.5h.7M102.7 71.2h.7M102.7 74.6h.7M102.7 76.3h.7M102.7 72.9h.7M103 60.7v.9"/>
<path d="M103.5 67.7l.3-.9 .2 .9M103.5 65.9l.3-.8 .2 .8M103.5 71.1l.3-.9 .2 .9M103.5 74.5l.3-.8 .2 .8M103.5 76.2l.3-.8 .2 .8M103.5 72.9l.3-.9 .2 .9M103.5 69.4l.3-.9 .2 .9M103.6 63.3l-.2 .7h.5M103.6 67.4h.3M103.6 65.7h.3M103.6 69.1h.3M103.6 70.8h.3"/>
<path d="M103.6 74.3h.3M103.6 76h.3M103.6 72.6h.3M103.8 60.7v.9l-.4-.9v.9M103.8 63.6v.6M104.3 65.1h.6l-.5 .8M104.3 73.8h.5v.2l-.5 .5h.5M104.3 75.6l.2-.2v.8M104.3 72h.5l-.3 .3h.3v.5h-.5M104.3 76.2h.5M104.5 70.2l-.2 .6h.6M104.7 66.8h-.3l-.1 .7 .1 .2 .4-.1v-.4l-.4-.1-.1 .2"/>
<path d="M104.7 70.6v.5M104.8 68.5h-.5v.5l.4-.1 .1 .4h-.5M113.9 60.3h.3M113.9 62h.3M113.9 63.8h.3M113.9 67.2h.3M113.9 65.5h.3M113.9 69h.3M113.9 70.7h.3M113.9 74.1h.3M113.9 75.8h.3M113.9 72.3h.3"/>
<path d="M114.3 63.4h-.4v.8h.4M114.3 66.8h-.4v.9h.4M114.3 61.6h-.4v.9h.4M114.3 65.1h-.4v.8h.4M114.3 68.5h-.4v.9h.4M114.3 70.2h-.4v.9h.4M114.3 73.7h-.4v.8h.4M114.3 75.4h-.4v.8h.4M114.3 72h-.4v.9h.4M114.6 63.4l.6 .8M114.6 66.8l.6 .9M114.6 61.6l.6 .9"/>
<path d="M114.6 65.1l.6 .8M114.6 68.5l.6 .9M114.6 70.2l.6 .9M114.6 73.7l.6 .8M114.6 75.4l.6 .8M114.6 72l.6 .9M115.2 63.4l-.6 .8M115.2 66.8l-.6 .9M115.2 61.6l-.6 .9M115.2 65.1l-.6 .8M115.2 68.5l-.6 .9M115.2 70.2l-.6 .9"/>
<path d="M115.2 73.7l-.6 .8M115.2 75.4l-.6 .8M115.2 72l-.6 .9M115.5 60.3l.4-.1v-.3h-.4v.8M115.5 63.8h.4v-.3l-.4-.1v.8M115.5 67.3l.4-.1v-.4h-.4v.9M115.5 62.1l.4-.1v-.4h-.4v.9M115.5 65.5h.4v-.4h-.4v.8M115.5 69h.4v-.4l-.4-.1v.9M115.5 70.7h.4v-.5h-.4v.9M115.5 74.1h.4v-.3l-.4-.1v.8M115.5 75.9l.4-.1v-.4h-.4v.8"/>
<path d="M115.5 72.4h.4v-.3l-.4-.1v.9M116.1 60.8h.7M116.1 62.6h.7M116.1 64.3h.7M116.1 67.8h.7M116.1 66h.7M116.1 69.5h.7M116.1 71.2h.7M116.1 74.6h.7M116.1 76.3h.7M116.1 72.9h.7M116.9 60.7l.3-.8 .3 .8"/>
<path d="M116.9 64.2l.3-.8 .3 .8M116.9 67.7l.3-.9 .3 .9M116.9 62.5l.3-.9 .3 .9M116.9 65.9l.3-.8 .3 .8M116.9 69.4l.3-.9 .3 .9M116.9 71.1l.3-.9 .3 .9M116.9 74.5l.3-.8 .3 .8M116.9 76.2l.3-.8 .3 .8M116.9 72.9l.3-.9 .3 .9M117 60.5h.4M117 62.3h.4M117 64h.4"/>
<path d="M117 67.4h.4M117 65.7h.4M117 69.1h.4M117 70.8h.4M117 74.3h.4M117 76h.4M117 72.6h.4M117.7 60.2l.3-.3v.8M117.7 63.6l.3-.2v.8M117.7 67l.3-.2v.9M117.7 61.8l.3-.2v.9M117.7 65.3l.3-.2v.8"/>
<path d="M117.7 68.8l.3-.3v.9M117.7 70.5l.3-.3v.9M117.7 72.2l.3-.2v.9M117.7 60.7h.5M117.7 62.5h.5M117.7 64.2h.5M117.7 67.7h.5M117.7 65.9h.5M117.7 69.4h.5M117.7 71.1h.5M117.7 72.9h.5M117.9 75.8l-.2-.1v-.2l.4-.1 .1 .2-.5 .3 .1 .3h.3l.1-.2-.1-.2"/>
<path d="M118.2 74l-.1 .2h-.3l-.1-.4 .4-.1 .1 .2-.1 .6h-.3M118.5 66.8h.5l-.3 .3 .3 .1v.4h-.5M118.5 68.6h.5v.3l-.5 .5h.5M118.5 70.5l.2-.3v.9M118.5 71.1h.5M118.6 72.1h.4v.6l-.2 .2-.2-.1zM118.7 65.1l-.2 .6h.6M118.9 61.6l-.2 .1-.2 .7 .2 .1 .3-.1v-.4l-.3-.1-.2 .2M118.9 65.4v.5M119 63.4h-.4l-.1 .4 .4-.1 .1 .4h-.5M165.6 60.3h.3M165.6 62h.3"/>
<path d="M166 61.6h-.4v.9h.4M166.2 61.6l.6 .9M166.8 61.6l-.6 .9M167.2 60.3h.4l.1-.2-.2-.2h-.3v.8M167.2 62.1h.3l.2-.2-.2-.3h-.3v.9M167.8 60.8h.7M167.8 62.6h.7M168.5 60.7l.4-.8 .2 .8M168.5 62.5l.4-.9 .2 .9M168.6 60.5h.4M168.6 62.3h.4M169.4 60.2l.2-.3v.8"/>
<path d="M169.4 61.8l.2-.2v.9M169.4 60.7h.5M169.4 62.5h.5M170.6 61.6l-.4 .2v.6l.4 .1 .1-.1-.1-.5-.4 .2M211.2 77.5h.3M211.6 77.2h-.4v.8h.4M212 77.2l.5 .8M212.5 77.2l-.5 .8M212.8 77.6h.3l.2-.2-.1-.2h-.4v.8M213.5 78.1h.7M214.2 77.2l.3 .8 .3-.8M214.9 77.2h.5"/>
<path d="M215.2 77.2v.8M215.8 77.5h.2M216.1 77.2h-.3v.8h.3M216.5 77.6h.4l.1-.2v-.2h-.5v.8M216.7 77.6l.3 .4M217.4 78v-.8l.2 .6 .4-.6v.8M218.3 77.3l.3-.1v.8M218.3 78h.5M118.2 92.2h.3M118.6 91.8h-.4v.9h.4M118.9 91.8l.6 .9M119.5 91.8l-.6 .9"/>
<path d="M119.8 92.2h.5v-.4h-.5v.9M120.4 92.7h.7M121.2 92.7l.3-.9 .3 .9M121.3 92.4h.4M122 91.8h.6l-.4 .9M211.2 90.5h.3M211.6 90h-.4v.9h.4M212 90l.5 .9M212.5 90l-.5 .9M212.8 90.5h.4l.1-.3-.2-.2h-.3v.9M213.5 91h.7M214.2 90l.3 .9 .3-.9"/>
<path d="M214.9 90h.5M215.2 90v.9M215.8 90.5h.2M216.1 90h-.3v.9h.3M216.5 90.5h.5v-.3l-.1-.2h-.4v.9M216.7 90.5l.3 .4M217.4 90.9v-.9l.2 .6 .4-.6v.9M218.3 90.1l.3-.1 .2 .2-.5 .7h.5"/>
</g>
<g fill="none" stroke="#b90000" stroke-width=".21">
<path d="M105.7 25.9h.3v.6M105.7 27.6h.3v.5h-.3v-.2l.3-.1M105.7 29.3h.3v.5h-.3v-.2l.3-.1M105.7 31h.3v.6M105.7 32.8h.3v.5h-.3v-.2l.3-.1M105.7 34.5h.3v.5h-.3v-.2l.3-.1M105.7 36.3h.3v.5M105.7 38h.3v.5h-.3v-.3l.3-.1M105.7 39.7h.3v.6M106 26l-.3 .1 .1 .4 .2-.1M106 31.2l-.3 .1 .1 .3 .2-.1M106 36.4h-.3l.1 .4 .2-.1"/>
<path d="M106 39.8l-.3 .1 .1 .4 .2-.1M106.4 29h.6l-.4 .3 .4 .2v.3h-.6M106.4 35.9h.6l-.4 .9M106.5 25.8l.2-.2v.9M106.5 27.4l.4-.1 .1 .3-.6 .5h.6M106.5 26.5h.5M106.6 30.7l-.1 .6h.5M106.6 38l-.1-.3 .4-.1v.4l-.4 .1v.4h.4l.1-.4-.2-.1M106.9 32.5h-.4v.4l.4-.1v.5l-.4-.1M106.9 34.2l-.4 .2v.6l.5-.1-.2-.4-.3 .2M106.9 31v.6M107 39.7l-.2 .2-.3-.1v-.4l.3-.1 .2 .2-.2 .7-.3 .1"/>
<path d="M112.1 25.9h-.4v.5h.4M112.1 27.6h-.4v.5h.4M112.1 29.3l-.4 .1v.4h.4M112.1 31l-.4 .1v.4h.4M112.1 32.8h-.4v.4l.4 .1M112.1 34.5l-.4 .1v.4h.4M112.1 36.3h-.4v.4h.4M112.1 38h-.4v.4l.4 .1M112.1 39.7h-.4v.5h.4M112.4 29h.6l-.4 .3 .4 .2v.3h-.6M112.4 35.9h.6l-.4 .9M112.5 25.8l.2-.2v.9"/>
<path d="M112.5 27.4l.4-.1 .1 .3-.6 .5h.6M112.5 26.5h.5M112.6 30.7l-.1 .6h.5M112.6 38l-.1-.3 .4-.1v.4l-.4 .1 .1 .4h.3l.1-.4-.2-.1M112.9 32.5h-.4v.4l.4-.1v.5l-.4-.1M112.9 34.2h-.3l-.1 .8 .5-.1-.2-.4-.3 .2M112.9 31v.6M113 39.7l-.2 .2-.3-.1v-.4l.3-.1 .2 .2-.2 .7-.2 .1M125.9 25.9h.4l.1 .1-.2 .5-.3-.1M125.9 27.3v.8h.4l.1-.4-.2-.1h-.3M125.9 29v.8h.4v-.5h-.4M125.9 31h.4l.1 .2-.2 .4-.3-.1"/>
<path d="M125.9 32.5v.8h.4l.1-.4-.2-.2-.3 .1M125.9 34.2v.8h.4v-.5h-.4M125.9 36.3l.3-.1 .2 .2-.2 .4-.3-.1M125.9 37.6v.9h.4l.1-.4-.2-.2-.3 .1M125.9 39.7h.4l.1 .1-.2 .5-.3-.1M125.9 25.6v.9M125.9 30.8v.8M125.9 35.9v.9M125.9 39.3v1M126.6 29h.6l-.3 .3 .3 .2v.3h-.6M126.6 35.9h.6l-.3 .9M126.7 25.8l.3-.2v.9"/>
<path d="M126.7 27.4l.4-.1 .1 .3-.6 .5h.6M126.7 26.5h.5M126.9 30.7l-.2 .6h.5M126.9 38l-.2-.3 .4-.1v.4l-.4 .1 .1 .4h.3l.1-.4-.2-.1M127.1 32.5h-.4v.4l.4-.1v.5l-.4-.1M127.1 34.2l-.4 .2v.6l.5-.1-.2-.4-.3 .2M127.1 31v.6M127.2 39.7l-.2 .2-.3-.1v-.4l.3-.1 .2 .2-.2 .7-.2 .1M210.7 25.7l.4-.1 .1 .2-.5 .7h.5M210.7 27.3h.5l-.3 .3 .3 .2-.1 .3h-.4M210.7 34.2h.5l-.3 .8M210.9 36.3l-.2-.2 .1-.2h.3v.4l-.4 .1 .2 .4 .3-.2-.2-.3"/>
<path d="M210.9 29l-.2 .6h.5M211.1 30.8h-.3l-.1 .3 .3-.1 .2 .5-.2 .1-.3-.1M211.1 32.5h-.2l-.2 .3 .1 .5h.3v-.5h-.3l-.1 .2M211.1 29.3v.5M211.2 38l-.1 .1h-.3v-.5h.3l.1 .2-.1 .6-.3 .1M216.8 22.6a.61 .61 0 0 1 .8 .2 .47 .47 0 0 1-.4 .3 .47 .47 0 0 1-.4-.3zM217.6 23.4v.5l-.5-.5h-.3v.5M224.1 25.8l.2-.2v.9M224.1 27.6l.2-.3v.8M224.1 29.2l.2-.2v.8M224.1 31l.2-.2v.8M224.1 32.7l.2-.2v.8"/>
<path d="M224.1 34.4l.2-.2v.8M224.1 36.2l.2-.3v.9M224.1 37.9l.2-.3v.9M224.1 26.5h.5M224.1 28.1h.5M224.1 29.8h.5M224.1 31.6h.5M224.1 33.3h.5M224.1 35h.5M224.1 36.8h.5M224.1 38.5h.5M224.8 27.3h.6l-.3 .8"/>
<path d="M224.8 34.2h.6l-.3 .3 .3 .2v.2l-.6 .1M224.9 36l.4-.1 .1 .3-.6 .6h.6M224.9 37.9l.3-.3v.9M224.9 38.5h.5M225.1 25.9l-.2-.2 .4-.1 .1 .2-.5 .2v.4l.2 .1 .3-.2-.1-.4M225.1 32.4l-.2 .7h.5M225.3 29l-.3 .1-.1 .7h.5l-.1-.5-.4 .2M225.3 30.8h-.4v.3l.4-.1 .1 .5-.1 .1-.4-.1M225.3 32.7v.6M246.8 25.7h.6v.2l-.6 .6h.6M246.8 27.3h.6l-.3 .3 .3 .1v.4h-.6M246.8 34.2h.6l-.4 .8"/>
<path d="M247 36.3l-.2-.2 .1-.2h.4l.1 .3-.6 .2 .2 .4 .4-.1v-.3l-.2-.1M247.1 29l-.3 .6h.6M247.3 32.5h-.3l-.2 .6 .1 .2 .5-.1-.1-.4h-.4l-.1 .2M247.3 29.3v.5M247.4 30.8h-.5l-.1 .3h.6v.4h-.6M247.4 38l-.1 .1h-.4v-.5l.5 .1v.6l-.5 .2M252.9 22.7a.52 .52 0 0 1 .9 .1 .45 .45 0 0 1-.5 .3 .45 .45 0 0 1-.4-.4zM253.8 23.4v.5l-.5-.5-.4 .1 .1 .4M260.2 25.8l.3-.2v.9M260.2 27.6l.3-.3v.8M260.2 29.2l.3-.2v.8M260.2 31l.3-.2v.8"/>
<path d="M260.2 32.7l.3-.2v.8M260.2 34.4l.3-.2v.8M260.2 36.2l.3-.3v.9M260.2 37.9l.3-.3v.9M260.2 26.5h.5M260.2 28.1h.5M260.2 29.8h.5M260.2 31.6h.5M260.2 33.3h.5M260.2 35h.5M260.2 36.8h.5M260.2 38.5h.5"/>
<path d="M261.1 27.3h.5l-.4 .8M261.1 34.2h.5l-.4 .3 .4 .2v.2l-.5 .1M261.1 36l.4-.1 .1 .2-.5 .7h.5M261.1 37.9l.2-.3v.9M261.1 38.5h.5M261.2 25.9l-.1-.2 .4-.1 .1 .2-.2 .1-.3 .1v.4l.1 .1 .4-.2-.2-.4M261.2 32.4l-.1 .7h.5M261.5 29l-.3 .1-.1 .7h.5l-.2-.5-.3 .2M261.5 30.8h-.4v.3l.3-.1 .2 .5-.2 .1-.3-.1M261.5 32.7v.6M105.3 41.4h.2l.2 .1v.4M105.3 43.1l.2-.1 .2 .2v.4h-.4l.1-.3h.3"/>
<path d="M105.3 44.8l.4 .1v.5M105.3 46.6l.2-.1 .2 .2v.4M105.3 48.3l.2-.1 .2 .2v.4h-.4l.1-.3h.3M105.3 50l.4 .1v.5M105.3 51.8l.2-.1 .2 .2v.4M105.3 53.5h.4v.5h-.4l.1-.4h.3M105.3 55.2h.4v.5M105.3 56.9h.2l.2 .1v.4M105.3 58.6l.4 .1v.4h-.4l.1-.3h.3M105.7 41.6h-.4l.1 .3h.3M105.7 45l-.4 .1 .1 .3 .3-.1M105.7 46.8l-.4 .1 .1 .2 .3-.1"/>
<path d="M105.7 50.2h-.4l.1 .4 .3-.1M105.7 51.9l-.4 .1 .1 .3 .3-.1M105.7 55.3l-.4 .1 .1 .3h.3M105.7 57.1l-.4 .1 .1 .2h.3M106 41.4l.3-.3v.8M106 43l.3-.2v.8M106 44.7l.3-.2v.9M106 46.5l.3-.2v.8M106 48.2l.3-.2v.8M106 49.9l.3-.2v.9M106 51.7l.3-.3v.9M106 53.4l.3-.3v.9"/>
<path d="M106 55.1l.3-.3v.9M106 56.9l.3-.3v.8M106 58.4l.4-.1 .1 .2-.5 .6h.5M106 41.9h.5M106 43.6h.5M106 45.4h.5M106 47.1h.5M106 48.8h.5M106 50.6h.5M106 52.3h.5M106 54h.5M106 55.7h.5"/>
<path d="M106 57.4h.5M106.8 46.3h.5l-.2 .3 .2 .1v.3h-.5M106.8 53.1h.6l-.3 .9M106.9 43l.2-.2v.8M106.9 44.6h.4v.3l-.5 .5h.5M106.9 43.6h.4M107 41.1h.2l.1 .2v.5l-.2 .1-.2-.1zM107.1 48l-.2 .6h.5M107.1 55.2h-.2v-.3l.2-.1 .2 .1v.3l-.4 .1v.4h.2h.2v-.4l-.2-.1M107.1 58.3l.2 .2-.1 .6h-.2l-.1-.1v-.5zM107.2 51.4l-.3 .2v.6h.4l-.1-.4h-.2l-.1 .1M107.2 48.2v.6"/>
<path d="M107.3 49.7h-.4v.4h.4v.4h-.4M107.3 56.9l-.1 .2h-.2l-.1-.4h.4v.6l-.3 .1M111.7 41.4h-.2l-.2 .1 .2 .4h.2M111.7 43.1l-.2-.1-.2 .2 .1 .4h.3M111.7 44.8h-.3l-.1 .2 .2 .4 .2-.1M111.7 46.6l-.2-.1-.2 .2 .2 .4 .2-.1M111.7 48.3l-.2-.1-.2 .2 .1 .4h.3M111.7 50h-.3l-.1 .2 .2 .4 .2-.1M111.7 51.8l-.2-.1-.2 .2 .2 .4 .2-.1M111.7 53.5h-.4l.1 .5h.3M111.7 55.2h-.3l-.1 .1 .2 .4h.2M111.7 56.9h-.2l-.2 .1 .2 .4h.2"/>
<path d="M111.7 58.6l-.4 .1 .1 .4h.3M112.1 41.4l.2-.3v.8M112.1 43l.2-.2v.8M112.1 44.7l.2-.2v.9M112.1 46.5l.2-.2v.8M112.1 48.2l.2-.2v.8M112.1 49.9l.2-.2v.9M112.1 51.7l.2-.3v.9M112.1 53.4l.2-.3v.9M112.1 55.1l.2-.3v.9M112.1 56.9l.2-.3v.8M112.1 58.4l.3-.1 .2 .2-.6 .6h.6"/>
<path d="M112.1 41.9h.5M112.1 43.6h.5M112.1 45.4h.5M112.1 47.1h.5M112.1 48.8h.5M112.1 50.6h.5M112.1 52.3h.5M112.1 54h.5M112.1 55.7h.5M112.1 57.4h.5M112.8 46.3h.5l-.2 .3 .2 .1v.3h-.5M112.8 53.1h.6l-.3 .9"/>
<path d="M112.9 43l.2-.2v.8M112.9 44.6h.4v.3l-.5 .5h.5M112.9 43.6h.4M113 41.1h.2l.1 .2v.5l-.1 .1-.3-.1zM113.1 48l-.2 .6h.5M113.1 55.2h-.2v-.3l.3-.1 .1 .1v.3l-.4 .1v.4h.2h.2v-.4l-.1-.1M113.1 58.3l.2 .2-.1 .6h-.2l-.1-.1v-.5zM113.2 51.4l-.3 .2v.6h.4l-.1-.4h-.2l-.1 .1M113.2 48.2v.6M113.3 49.7h-.4v.4h.4v.4h-.4M113.3 56.9l-.1 .2h-.2l-.1-.4h.4v.6l-.3 .1M125.5 41.4h.4v.5h-.4"/>
<path d="M125.5 42.8v.8h.4v-.5h-.4M125.5 44.8l.4 .1v.4h-.4M125.5 46.6h.4v.4h-.4M125.5 48v.8h.4v-.5h-.4M125.5 50l.4 .1v.4h-.4M125.5 51.8h.4v.4h-.4M125.5 53.1v.9h.4v-.5h-.4M125.5 55.2h.4v.5h-.4M125.5 56.9h.4v.5h-.4M125.5 58.3v.8h.4v-.4l-.4-.1M125.5 41.1v.8M125.5 44.5v.9"/>
<path d="M125.5 46.3v.8M125.5 49.7v.9M125.5 51.4v.9M125.5 54.8v.9M125.5 56.6v.8M125.5 60v.9M126.3 41.4l.2-.3v.8M126.3 43l.2-.2v.8M126.3 44.7l.2-.2v.9M126.3 46.5l.2-.2v.8M126.3 48.2l.2-.2v.8M126.3 49.9l.2-.2v.9"/>
<path d="M126.3 51.7l.2-.3v.9M126.3 53.4l.2-.3v.9M126.3 55.1l.2-.3v.9M126.3 56.9l.2-.3v.8M126.3 58.4l.3-.1 .2 .2-.6 .6h.6M126.3 41.9h.5M126.3 43.6h.5M126.3 45.4h.5M126.3 47.1h.5M126.3 48.8h.5M126.3 50.6h.5M126.3 52.3h.5"/>
<path d="M126.3 54h.5M126.3 55.7h.5M126.3 57.4h.5M127 46.3h.5l-.2 .3h.2v.4h-.5M127 53.1h.6l-.3 .9M127.1 43l.3-.2v.8M127.1 44.6l.4-.1v.4l-.5 .5h.5M127.1 43.6h.4M127.2 41.1l.3 .1v.7h-.1l-.3-.1zM127.3 48l-.2 .6h.5M127.3 55.2h-.2v-.3l.4-.1v.4l-.4 .1v.4h.2h.2v-.5M127.3 58.3l.2 .1v.7h-.3l-.1-.1v-.5z"/>
<path d="M127.5 49.7h-.4v.4h.4v.4h-.4M127.5 51.4l-.4 .2v.6h.4v-.4h-.3l-.1 .1M127.5 56.9v.2h-.3l-.1-.4 .4-.1v.7l-.3 .1M127.5 48.2v.6M210.3 43l.2-.2v.8M210.3 43.6h.5M210.7 41.4l.2-.3v.8M210.7 41.9h.5M211.6 43.1l-.1 .2h-.3l-.1-.4 .4-.1 .1 .2-.1 .6h-.3M216.8 46.8l.7-.1 .1 .2a.45 .45 0 0 1-.4 .3 .45 .45 0 0 1-.4-.3zM217.6 47.7h-.8l.2 .3M217.6 47.5v.5"/>
<path d="M246.5 43l.2-.2v.8M246.5 43.6h.4M246.8 41.4l.3-.3v.8M246.8 41.9h.6M247.8 43.1l-.1 .2h-.3l-.1-.3 .1-.2 .4 .1v.6l-.4 .1M252.9 46.8l.7-.1 .2 .2a.43 .43 0 0 1-.5 .3 .43 .43 0 0 1-.4-.4zM253.8 47.7h-.9l.3 .3M253.8 47.5v.5M105.3 60.3l.4 .1v.5M105.3 62.1l.2-.1 .2 .2v.4h-.4l.1-.3h.3M105.3 63.8l.4 .1v.4h-.4l.1-.3h.3M105.3 65.5l.4 .1v.5"/>
<path d="M105.3 67.3l.2-.1 .2 .1v.5h-.4l.1-.4h.3M105.3 69h.4v.5h-.4v-.3l.4-.1M105.3 70.7h.4v.5M105.3 72.4l.2-.1 .2 .2v.4h-.4l.1-.3h.3M105.3 74.1l.4 .1v.4h-.4v-.2l.4-.1M105.3 75.8l.4 .1v.5M105.3 77.6l.2-.1 .2 .2v.4h-.4l.1-.3h.3M105.3 79.3l.4 .1v.4h-.4v-.3h.4M105.7 60.5l-.4 .1 .1 .3 .3-.1M105.7 65.7h-.4l.1 .4 .3-.1M105.7 70.8l-.4 .1 .1 .3h.3M105.7 76l-.4 .1 .1 .3 .3-.1"/>
<path d="M106 75.6h.5l-.3 .2 .3 .2v.2l-.1 .2-.4-.1M106 77.3h.5l-.3 .3h.3v.5l-.5-.1M106 78.9h.5l-.3 .4 .3 .2v.2l-.5 .1M106 60.1l.4-.1 .1 .2-.5 .7h.5M106 61.8h.5v.2l-.5 .6h.5M106 63.5h.4l.1 .2-.5 .6h.5M106 65.3l.5-.1v.2l-.5 .7h.5M106 67l.5-.1v.3l-.5 .6h.5M106 68.7l.4-.1 .1 .3-.5 .6h.5M106 70.5l.5-.1v.2l-.5 .6h.5M106 72.2l.5-.1v.2l-.5 .6h.5M106 73.9l.4-.1 .1 .2-.5 .6h.5"/>
<path d="M106.8 63.5h.5l-.2 .3 .2 .1v.3h-.5M106.8 70.4h.6l-.3 .8M106.9 60.2l.2-.2v.9M106.9 61.8h.3l.1 .3-.5 .5h.5M106.9 77.5l.2-.2v.8M106.9 79h.4v.4l-.5 .4h.5M106.9 60.9h.4M106.9 78.1h.4M107 75.6h.2l.1 .1v.5l-.2 .2-.2-.2zM107.1 65.1l-.2 .6h.5M107.1 72.4l-.2-.2 .3-.1 .1 .2-.4 .2 .1 .4h.3v-.4l-.2-.1M107.2 68.6l-.3 .3v.5h.4v-.4h-.2l-.2 .1"/>
<path d="M107.2 65.5v.6M107.3 66.9h-.4v.4h.4l-.1 .5-.3-.1M107.3 74.2l-.2 .2-.2-.1v-.4h.4v.6l-.3 .1M111.7 60.3h-.3l-.1 .2 .2 .4 .2-.1M111.7 62.1l-.2-.1-.2 .2 .1 .4h.3M111.7 63.8h-.3l-.1 .2 .1 .3h.3M111.7 65.5h-.3l-.1 .2 .2 .4 .2-.1M111.7 67.3l-.2-.1-.2 .1 .1 .5h.3M111.7 69h-.3l-.1 .1 .1 .4h.3M111.7 70.7h-.3l-.1 .1 .2 .4h.2M111.7 72.4l-.2-.1-.2 .2 .1 .4h.3M111.7 74.1h-.3l-.1 .2 .1 .3h.3"/>
<path d="M111.7 75.8h-.3l-.1 .2 .2 .4 .2-.1M111.7 77.6l-.2-.1-.2 .2 .1 .4h.3M111.7 79.3h-.3l-.1 .2 .1 .3h.3M112 75.6h.6l-.4 .2 .4 .2v.2l-.2 .2-.4-.1M112 77.3h.6l-.4 .3h.3v.5l-.5-.1M112 78.9h.6l-.4 .4 .4 .2v.2l-.6 .1M112.1 60.1l.3-.1 .2 .2-.6 .7h.6M112.1 61.8h.4l.1 .2-.6 .6h.6M112.1 63.5h.3l.2 .2-.6 .6h.6M112.1 65.3l.4-.1 .1 .2-.6 .7h.6M112.1 67l.4-.1 .1 .3-.6 .6h.6M112.1 68.7l.3-.1 .2 .3-.6 .6h.6"/>
<path d="M112.1 70.5l.4-.1 .1 .2-.6 .6h.6M112.1 72.2l.4-.1 .1 .2-.6 .6h.6M112.1 73.9l.3-.1 .2 .2-.6 .6h.6M112.8 63.5h.5l-.2 .3 .2 .1v.3h-.5M112.8 70.4h.6l-.3 .8M112.9 60.2l.2-.2v.9M112.9 61.8h.3l.1 .3-.5 .5h.5M112.9 77.5l.2-.2v.8M112.9 79h.4v.4l-.5 .4h.5M112.9 60.9h.4M112.9 78.1h.4M113 75.6h.2l.1 .1v.5l-.1 .2-.3-.2z"/>
<path d="M113.1 65.1l-.2 .6h.5M113.1 72.4l-.2-.2 .3-.1 .1 .2-.4 .2 .1 .4h.3v-.4l-.1-.1M113.2 68.6l-.3 .3v.5h.4v-.4h-.2l-.2 .1M113.2 65.5v.6M113.3 66.9h-.4v.4h.4l-.1 .5-.3-.1M113.3 74.2l-.1 .2-.3-.1v-.4h.4v.6l-.3 .1M125.5 60.3l.4 .1v.4h-.4M125.5 61.8v.8h.4v-.5h-.4M125.5 63.5v.8h.4v-.4l-.4-.1M125.5 65.5l.4 .1v.4h-.4M125.5 66.9v.9h.4v-.5h-.4M125.5 68.6v.9h.4v-.5h-.4"/>
<path d="M125.5 70.7h.4v.5h-.4M125.5 72.1v.8h.4v-.5h-.4M125.5 73.8v.8h.4v-.4l-.4-.1M125.5 75.8l.4 .1v.4h-.4M125.5 77.3v.8h.4v-.5h-.4M125.5 78.9v.9h.4v-.4l-.4-.1M125.5 65.2v.9M125.5 70.4v.8M125.5 75.6v.8M126.2 75.6h.6l-.4 .2 .4 .2v.2l-.2 .2-.4-.1M126.2 77.3h.6l-.4 .3h.3v.5l-.5-.1M126.2 78.9h.6l-.4 .4 .4 .2v.2l-.6 .1"/>
<path d="M126.3 60.1l.3-.1 .2 .2-.6 .7h.6M126.3 61.8h.4l.1 .2-.6 .6h.6M126.3 63.5h.3l.2 .2-.6 .6h.6M126.3 65.3l.4-.1 .1 .2-.6 .7h.6M126.3 67l.4-.1 .1 .3-.6 .6h.6M126.3 68.7l.3-.1 .2 .3-.6 .6h.6M126.3 70.5l.4-.1 .1 .2-.6 .6h.6M126.3 72.2l.4-.1 .1 .2-.6 .6h.6M126.3 73.9l.3-.1 .2 .2-.6 .6h.6M127 63.5h.5l-.2 .3 .2 .1v.4l-.5-.1M127 70.4h.6l-.3 .8M127.1 60.2l.3-.2v.9"/>
<path d="M127.1 61.8h.4v.3l-.5 .5h.5M127.1 77.5l.3-.2v.8M127.1 79l.4-.1v.5l-.5 .4h.5M127.1 60.9h.4M127.1 78.1h.4M127.2 75.6h.3v.7l-.1 .1-.3-.2zM127.3 65.1l-.2 .6h.5M127.3 72.4l-.2-.2 .4-.1v.3l-.4 .1 .1 .4h.3v-.5M127.5 66.9h-.4v.4h.4v.5l-.4-.1M127.5 68.6l-.4 .3v.5l.4 .1v-.5l-.4 .1M127.5 74.2v.2l-.4-.1v-.4h.4v.6v.1h-.3M127.5 65.5v.6"/>
<path d="M217.6 71.8v.2l.2 .1h.6v-.4l-.4 .1v.2l.1 .1M217.9 64h.6M218.1 63.9v.5l-.6-.3M242.2 67.2l.2-.3v.9M242.2 70.6l.2-.2v.8M242.2 67.8h.5M242.2 71.2h.5M242.9 66.9h.6l-.3 .4h.3v.4h-.6M243.2 70.3l-.3 .6h.6M243.4 70.7v.5M251.2 68.6h.5l-.3 .4h.3v.4h-.5"/>
</g>
<g fill="none" stroke="#006665" stroke-width=".21">
<path d="M213.7 27l.2-.8 .3 .8M213.7 28.7l.2-.8 .3 .8M213.7 30.5l.2-.8 .3 .8M213.7 32.2l.2-.8 .3 .8M213.7 34l.2-.9 .3 .9M213.7 35.7l.2-.9 .3 .9M213.7 37.4l.2-.9 .3 .9M213.7 39.2l.2-1 .3 1M213.7 26.8h.4M213.7 28.6h.4M213.7 30.3h.4M213.7 32h.4"/>
<path d="M213.7 33.7h.4M213.7 35.4h.4M213.7 37.1h.4M213.7 38.9h.4M214.4 28.1l.3-.2v.8M214.4 29.8h.5v.2l-.5 .5h.5M214.4 31.4h.5l-.2 .3 .2 .1v.3h-.5M214.4 38.2h.6l-.4 1M214.4 28.7h.5M214.5 26.3l.3-.1 .1 .2-.1 .6a.39 .39 0 0 1-.4-.2 .39 .39 0 0 1 .1-.5zM214.7 33.1l-.3 .6h.6M214.8 36.5l-.3 .2-.1 .5 .1 .2 .4-.1-.1-.4h-.3l-.1 .1"/>
<path d="M214.8 33.4v.6M214.9 34.8h-.4l-.1 .5 .4-.1 .1 .4h-.5M217.4 27.6l.8 .3-.8 .2M217.5 26.8l-.1 .4 .3 .2 .5-.2-.1-.4M217.5 25.9l-.1 .5 .3 .1 .5-.1-.1-.5M220.7 26.6l.4-.1-.1-.3h-.3v.8h.4l.1-.2-.3-.2M220.7 28.3h.3l.1-.3-.4-.1v.8h.4l.1-.2-.3-.2M220.7 30h.4v-.2l-.4-.1v.8h.3l.2-.3-.3-.2M220.7 31.8l.4-.1-.1-.3h-.3v.8h.4l.1-.2-.3-.2M220.7 33.5h.3l.1-.4h-.4v.9h.3l.2-.3-.3-.2M220.7 35.3l.4-.1-.1-.4h-.3v.9h.3l.2-.2-.1-.2h-.2M220.7 37l.4-.1v-.3l-.4-.1v.9h.4l.1-.3-.3-.1"/>
<path d="M220.7 38.6h.3l.1-.3-.4-.1v1h.3l.2-.4-.3-.2M221.4 31.4h.6l-.3 .3 .3 .1v.3h-.6M221.4 38.2h.6l-.4 1M221.5 28.1l.2-.2v.8M221.5 29.8l.4-.1 .1 .3-.6 .5h.6M221.5 28.7h.5M221.6 26.2h.3l.1 .2-.1 .6h-.3l-.1-.1zM221.7 33.1l-.2 .6h.5M221.9 36.5l-.4 .2v.6h.5l-.1-.4h-.3l-.1 .1M221.9 33.4v.6M222 34.8h-.5v.5l.4-.1 .1 .4h-.5M249.8 27l.3-.8 .3 .8"/>
<path d="M249.8 28.7l.3-.8 .3 .8M249.8 30.5l.3-.8 .3 .8M249.8 32.2l.3-.8 .3 .8M249.8 34l.3-.9 .3 .9M249.8 35.7l.3-.9 .3 .9M249.8 37.4l.3-.9 .3 .9M249.8 39.2l.3-1 .3 1M249.9 26.8h.4M249.9 28.6h.4M249.9 30.3h.4M249.9 32h.4M249.9 33.7h.4"/>
<path d="M249.9 35.4h.4M249.9 37.1h.4M249.9 38.9h.4M250.6 28.1l.2-.2v.8M250.6 29.8h.5v.2l-.5 .5h.5M250.6 31.4h.5l-.3 .3 .3 .1v.3h-.5M250.6 38.2h.6l-.5 1M250.6 28.7h.5M250.7 26.3l.3-.1 .1 .2-.1 .6a.39 .39 0 0 1-.4-.2 .39 .39 0 0 1 .1-.5zM250.8 33.1l-.2 .6h.6M251 36.5l-.3 .2-.1 .5 .1 .2 .4-.1-.1-.4h-.3l-.1 .1M251 33.4v.6"/>
<path d="M251.1 34.8h-.4l-.1 .5 .4-.1 .1 .4h-.5M253.5 27.6l.9 .3-.9 .2M253.6 26.8a.44 .44 0 0 0 .2 .6 .44 .44 0 0 0 .6-.2l-.1-.4M253.6 25.9a.44 .44 0 0 0 .2 .6 .44 .44 0 0 0 .6-.1l-.1-.5M256.8 26.6l.5-.1-.1-.3h-.4v.8h.5v-.2l-.1-.2M256.8 28.3l.5-.1-.1-.3h-.4v.8h.5v-.2l-.1-.2M256.8 30h.5v-.2l-.5-.1v.8h.4l.1-.2-.1-.3M256.8 31.8l.5-.1-.1-.3h-.4v.8h.5v-.2l-.1-.2M256.8 33.5l.5-.1-.1-.3h-.4v.9h.4l.1-.2-.1-.3M256.8 35.3l.5-.1-.1-.4h-.4v.9h.4l.1-.2-.1-.2M256.8 37l.5-.1-.1-.4h-.4v.9h.5v-.3l-.1-.1M256.8 38.6h.5l-.1-.4h-.4v1h.4l.1-.2-.1-.4"/>
<path d="M257.6 31.4h.6l-.4 .3h.3v.5l-.5-.1M257.6 38.2h.6l-.4 1M257.7 28.1l.2-.2v.8M257.7 29.8l.4-.1 .1 .2-.6 .6h.6M257.7 28.7h.5M257.8 26.2a.42 .42 0 0 1 .4 .4 .42 .42 0 0 1-.4 .4zM257.8 33.1l-.1 .6h.5M258.1 34.8h-.4v.5l.4-.1 .1 .3-.2 .2-.3-.1M258.1 36.5l-.4 .2v.6l.4 .1v-.5h-.3l-.1 .1M258.1 33.4v.6M213.7 42.5l.2-.8 .3 .8M213.7 42.3h.4"/>
<path d="M214.2 43.5a.42 .42 0 0 0-.5 .4 .42 .42 0 0 0 .5 .3M214.5 42.2h.6M214.6 43.8h.3M215 43.4h-.4v.9h.4M215.5 41.9l.7 .3-.7 .3M216.6 42.1l.4-.1v-.2l-.4-.1v.8h.4l.1-.2-.2-.2M217.4 44.1v.3l.1 .2h.6l.1-.2v-.3h-.3v.1M217.4 43.2h.8l-.8 .5h.8M217.4 42.5l.3-.2 .4 .1 .1 .4h-.8zM249.8 42.5l.3-.8 .3 .8M249.9 42.3h.4M250.4 43.5l-.3-.1-.2 .2v.5l.2 .2 .3-.1"/>
<path d="M250.7 42.2h.6M250.7 43.8h.4M251.2 43.4h-.5v.9h.5M251.8 41.9l.5 .3-.5 .3M252.8 42.1l.4-.1-.1-.3h-.3v.8h.4l.1-.2-.2-.2M253.5 43.2h.9l-.9 .5h.9M253.5 42.5l.5-.2 .4 .2v.3h-.9zM253.6 44.1l-.1 .2 .3 .3h.4l.2-.2v-.3h-.4v.1M218.2 66.8l.9 .3-.9 .3M218.2 69.7l.9 .3-.9 .2M218.4 66.2h.7M218.7 65.9v.6"/>
<path d="M218.7 68.7v.7M244.1 68.1h.7M244.1 71.5h.7M244.5 67.8v.6"/>
</g>
<path d="M253.4 65.4l.6-.3 .7 .3-.7 .3v1.5v-1.5z" fill="none" stroke="#474747" stroke-width=".21"/>
<path d="M202.1 68.4h2.2M209.9 68.3h2.1M202.1 96.8h2.2M202.1 83.9h2.2M209.9 96.8h2.1M209.9 83.8h2.1" fill="none" stroke="#910000" stroke-width=".25"/>
<path d="M98.1 78.4l.9-.6v.6h.9h-.9v.5z" fill="#910000"/>
<g fill="none" stroke="#910000" stroke-width=".21">
<path d="M227.2 27.6h2.6l.8 .8-.8 .8h-2.6l-.8-.8zM227.2 25.8h2.6l.8 .8-.8 1h-2.6l-.8-1zM227.2 32.7h3.4l.7 .9-.7 .8h-3.4l-.8-.8zM227.2 37.9h3.4l.7 .8-.7 .9h-3.4l-.8-.9zM227.2 36.1h3.4l.7 .9-.7 .9h-3.4l-.8-.9zM227.2 29.2h3.4l.7 .9-.7 .8h-3.4l-.8-.8zM227.2 34.4h3.4l.7 .9-.7 .8h-3.4l-.8-.8zM227.2 30.9h3.4l.7 1-.7 .8h-3.4l-.8-.8zM227.7 28a.47 .47 0 0 1 .5 .3 .47 .47 0 0 1-.2 .5h-.3zM227.7 26.3h.3a.47 .47 0 0 1 .2 .5 .47 .47 0 0 1-.5 .3zM227.7 33.1a.47 .47 0 0 1 .5 .3 .47 .47 0 0 1-.2 .6h-.3zM227.7 38.3a.49 .49 0 0 1 .5 .3 .49 .49 0 0 1-.2 .6h-.3z"/>
<path d="M227.7 36.6h.3a.47 .47 0 0 1 .2 .6 .47 .47 0 0 1-.5 .3zM227.7 29.7a.47 .47 0 0 1 .5 .4 .47 .47 0 0 1-.5 .5zM227.7 34.8a.47 .47 0 0 1 .5 .5 .47 .47 0 0 1-.5 .5zM227.7 31.5h.3a.47 .47 0 0 1 .2 .5 .47 .47 0 0 1-.5 .3zM228.6 33.4l.1-.3v.9M228.6 38.6l.1-.3v.9M228.6 36.9l.1-.3v.9M228.6 29.9l.1-.2v.9M228.6 35.1l.1-.3v1M228.6 31.7l.1-.2v.8M228.6 34h.4M228.6 39.2h.4"/>
<path d="M228.6 37.5h.4M228.6 30.6h.4M228.6 35.8h.4M228.6 32.3h.4M228.6 26.6v-.3h.3l.1 .2-.4 .2v.4l.4-.1v-.3l-.2-.1M229 28.3l-.1 .2h-.3v-.4h.4v.6l-.4 .1M229.3 33.2h.5v.3l-.5 .5h.5M229.3 34.8h.5l-.2 .4 .2 .1v.4h-.5M229.3 31.7l.3-.2v.8M229.3 32.3h.5M229.4 29.8l.3-.1 .1 .1v.6l-.1 .2a.53 .53 0 0 1-.3-.8zM229.6 36.5l-.3 .7h.6"/>
<path d="M229.7 36.9v.6M229.8 38.3h-.4l-.1 .4 .4-.1 .1 .5h-.5M263.4 30.9h2.6l.7 1-.7 .8h-2.6l-.8-.8zM263.4 32.7h2.6l.7 .9-.7 .8h-2.6l-.8-.8zM263.4 29.2h2.6l.7 .9-.7 .8h-2.6l-.8-.8zM263.4 27.6h2.6l.7 .8-.7 .8h-2.6l-.8-.8zM263.4 25.8h2.6l.7 .8-.7 1h-2.6l-.8-1zM263.4 36.1h2.6l.7 .9-.7 .9h-2.6l-.8-.9zM263.4 34.4h2.6l.7 .9-.7 .8h-2.6l-.8-.8zM263.4 37.9h2.6l.7 .8-.7 .9h-2.6l-.8-.9zM263.9 31.5h.3a.47 .47 0 0 1 .2 .5 .47 .47 0 0 1-.5 .3zM263.9 33.1a.47 .47 0 0 1 .5 .3 .47 .47 0 0 1-.2 .6h-.3z"/>
<path d="M263.9 29.7a.47 .47 0 0 1 .5 .4 .47 .47 0 0 1-.5 .5zM263.9 28a.47 .47 0 0 1 .5 .3 .47 .47 0 0 1-.2 .5h-.3zM263.9 26.3h.3a.47 .47 0 0 1 .2 .5 .47 .47 0 0 1-.5 .3zM263.9 36.6h.3l.1 .2a.42 .42 0 0 1 0 .5 .42 .42 0 0 1-.4 .2zM263.9 34.8a.47 .47 0 0 1 .5 .5 .47 .47 0 0 1-.5 .5zM263.9 38.3a.47 .47 0 0 1 .5 .3 .47 .47 0 0 1-.2 .6h-.3zM264.6 31.5h.6l-.3 .3h.2l.1 .3-.2 .2-.4-.1M264.6 38.3h.6l-.3 .9M264.7 29.8l.3-.1 .2 .2-.6 .7h.6M264.7 28.2l.3-.2v.8M264.7 28.8h.5M264.8 26.3a.43 .43 0 0 1 .4 .4 .43 .43 0 0 1-.3 .4l-.2-.1z"/>
<path d="M264.9 33.1l-.2 .6h.5M265.1 36.6l-.4 .2v.6l.3 .1 .2-.2-.1-.3h-.3l-.1 .1M265.1 34.8h-.4v.5l.3-.1 .2 .4-.2 .2-.3-.1M265.1 33.4v.6M45.8 51.6h5v1.8h-5l-.7-.9zM46.4 51.9h3.8M46.6 52.1l.4 .1 .1 .4-.2 .4h-.3zM47.3 52.1h.5M47.5 52.1v.9M48 53l.3-.9 .3 .9M48 52.7h.5M49.3 52.2l-.3-.1-.2 .2v.5l.2 .2 .3-.1"/>
<path d="M49.7 52.1v.9M49.8 52.4l.4 .6M50.2 52.1l-.5 .5M59.4 43h7.4l.7 .9-.7 .8h-7.4zM59.8 43.2h6.4M60 43.9h.2M60.2 44.7h4.7v1.7h-4.7l-.8-.8zM60.4 43.5h-.4v.8h.4M60.5 45h3.7M60.6 45.7l.5-.1v-.3l-.5-.1v.9M60.7 43.5l.6 .8M60.8 45.7l.3 .4"/>
<path d="M61.3 43.5l-.6 .8M61.4 45.6h.4M61.6 43.9h.4v-.3l-.4-.1v.8M61.8 45.2h-.4v.9h.4M62.2 44.4h.7M62.7 45.3l-.3-.1-.2 .1 .1 .3 .4 .2v.2h-.5M63 45.6h.4M63.1 43.9h.4v-.3l-.1-.1h-.3v.8h.4v-.3l-.1-.1M63.5 45.2h-.5v.9h.5M63.7 45.2h.5M64 45.2v.9M64 43.9h.2"/>
<path d="M64.4 43.5h-.4v.8h.4M64.7 43.9h.4l.1-.3-.1-.1h-.4v.8M64.9 43.9l.3 .4M65.6 43.9h.4l.1-.3-.2-.1h-.3v.8M65.7 43.9l.4 .4M100.1 51.6h4.9v1.8h-4.9l-.7-.9zM100.7 51.9h3.8M100.9 52.1l.4 .2v.5l-.2 .2h-.2zM101.6 52.1h.5M101.8 52.1v.9M102.2 53l.3-.9 .3 .9M102.3 52.7h.4"/>
<path d="M103.6 52.2l-.4-.1-.1 .2v.5l.1 .2 .4-.1M103.9 52.1v.9M104.1 52.4l.3 .6M104.4 52.1l-.5 .5M113.7 43h7.3l.8 .9-.8 .8h-7.3zM114.1 43.2h6.3M114.3 43.9h.2M114.3 44.7h4.9v1.7h-4.9l-.6-.8zM114.6 43.5h-.3v.8h.3M114.8 45h3.7M114.8 45.7l.6-.1v-.3l-.6-.1v.9M114.9 43.5l.6 .8"/>
<path d="M115.1 45.7l.3 .4M115.5 43.5l-.6 .8M115.7 45.6h.3M115.8 43.9h.5v-.3l-.5-.1v.8M116.1 45.2h-.4v.9h.4M116.5 44.4h.6M117 45.3l-.4-.1-.1 .1v.3l.5 .2-.2 .3-.3-.1M117.3 43.9h.4l.1-.3-.2-.1h-.3v.8h.4l.1-.3-.2-.1M117.3 45.6h.3M117.7 45.2h-.4v.9h.4M118 45.2h.5M118.2 43.9h.3"/>
<path d="M118.2 45.2v.9M118.6 43.5h-.4v.8h.4M119 43.9h.4l.1-.3-.2-.1h-.3v.8M119.2 43.9l.3 .4M119.8 43.9h.5l.1-.3-.2-.1h-.4v.8M120 43.9l.4 .4M151.8 51.6h4.9v1.8h-4.9l-.7-.9zM152.4 51.9h3.8M152.5 52.1l.4 .1 .1 .4-.1 .4h-.4zM153.3 52.1h.5M153.5 52.1v.9M153.9 53l.3-.9 .3 .9"/>
<path d="M154 52.7h.4M155.2 52.2l-.3-.1-.2 .3 .2 .6 .3-.1M155.7 52.1v.9M155.7 52.4l.5 .6M156.2 52.1l-.5 .5M165.3 43h7.4l.7 .9-.7 .8h-7.4zM165.8 43.2h6.3M165.9 43.9h.3M166.1 44.7h4.8v1.7h-4.8l-.8-.8zM166.3 43.5h-.4v.8h.4M166.4 45h3.7M166.6 45.7l.4-.1v-.3l-.4-.1v.9"/>
<path d="M166.6 43.5l.6 .8M166.7 45.7l.3 .4M167.2 43.5l-.6 .8M167.4 45.6h.3M167.5 43.9h.4l.1-.3-.2-.1h-.3v.8M167.8 45.2h-.4v.9h.4M168.2 44.4h.6M168.6 45.3l-.3-.1-.2 .1 .1 .3 .4 .2v.2h-.5M169 43.9h.4l.1-.3-.5-.1v.8h.5v-.2l-.2-.2M169 45.6h.3M169.4 45.2h-.4v.9h.4M169.6 45.2h.5"/>
<path d="M169.9 43.9h.2M169.9 45.2v.9M170.3 43.5h-.4v.8h.4M170.6 43.9h.5l.1-.3-.2-.1h-.4v.8M170.9 43.9l.3 .4M171.5 43.9h.5v-.3l-.5-.1v.8M171.7 43.9l.3 .4M204.8 41.3h3.7l.8 .9-.8 .8h-3.7zM205.6 42.2h.4l.1-.3-.5-.1v.8M205.9 42.2l.2 .4M207.1 41.7l-.7 1.1M207.3 41.8l.3 .8 .1-.6 .2 .6 .2-.8"/>
<path d="M207.3 41.5h.8M241 41.3h3.6l.8 .9-.8 .8h-3.6zM241.8 42.2h.5v-.4h-.5v.8M242 42.2l.3 .4M243.3 41.7l-.8 1.1M243.5 41.5h.8M243.5 41.8l.2 .8 .2-.6 .1 .6 .2-.8M73.9 60.2h3.3v1.8h-3.3l-.8-.9zM73.9 62h3.4l.6 .9-.6 .8h-3.4l-.8-.8zM74 72.3h3.9l.8 .9-.8 .8h-3.9zM74 68.9h3.9l.8 .8-.8 .9h-3.9zM74.5 72.5h2.8"/>
<path d="M74.5 69.1h2.8M74.6 69.3v.8M74.6 72.8v.8M74.8 60.7l-.4 .1v.2l.4 .3v.2h-.4M74.8 62.4l-.4 .1v.3l.4 .1v.3l-.4 .1M75 73.2h.4l.1-.3-.5-.1v.8M75 69.8l.5-.1v-.3l-.5-.1v.8M75.2 62.4l.4 .1 .1 .4-.1 .4h-.4zM75.2 73.2l.3 .4M75.2 69.8l.3 .3M75.7 60.8l-.4-.1a.44 .44 0 0 0-.1 .6 .44 .44 0 0 0 .5 .2M75.9 63.3l.3-.9 .3 .9"/>
<path d="M75.9 72.9l.3-.1 .2 .2-.2 .6h-.2l-.2-.2zM75.9 69.5l.2-.2a.43 .43 0 0 1 .3 .5 .43 .43 0 0 1-.4 .3l-.2-.2zM76 73.4l.4 .3M76 70l.4 .2M76 63h.4M76.1 60.7v.9h.4M76.7 72.8h.6l-.4 .3h.3v.5l-.5-.1M77.2 69.3h-.5v.4l.4-.1 .2 .5h-.6M79.2 70.6h3.9l.8 .8-.8 .9h-3.9zM79.2 67.2h3.9l.8 .8-.8 .9h-3.9zM79.2 77.5h5l.8 .9-.8 .8h-5zM79.6 70.8h2.9"/>
<path d="M79.6 67.3h2.9M79.8 78.4h.6M79.8 67.6v.8M79.8 71.1v.8M80.1 78.1v.7M80.2 71.5h.4v-.3l-.4-.1v.8M80.2 68l.4-.1v-.3h-.4v.8M80.4 71.5l.2 .4M80.4 68l.2 .4M81.1 71.2l.4-.1 .1 .5-.2 .3a.47 .47 0 0 1-.4-.3 .47 .47 0 0 1 .1-.4zM81.1 71.7l.5 .3M81.1 68.3l.5 .2"/>
<path d="M81.1 67.6h.4v.8h-.4l-.1-.2zM81.2 77.9h-.4v.5l.4-.1 .1 .1-.1 .4-.4-.1M81.5 77.9l.3 .9 .3-.9M82.1 71l-.2 .6h.5M82.3 67.6l-.4 .2v.6h.4v-.5h-.3l-.1 .2M82.3 71.3v.6M82.7 78.3l-.2-.1-.2 .2 .5 .3-.5 .1M83.1 77.9v.9h.3l.1-.4-.1-.2-.3 .1M99 78.4v.5l-.9-.5 .9-.6v.6h.9M99.9 78.4h.1M128.1 62h3.3l.8 .9-.8 .8h-3.3l-.7-.8zM128.1 60.2h3.3v1.8h-3.3l-.7-.9z"/>
<path d="M128.2 72.3h4l.7 .9-.7 .8h-4zM128.2 68.9h4l.7 .8-.7 .9h-4zM128.7 72.5h2.8M128.7 69.1h2.8M128.9 69.3v.8M128.9 72.8v.8M129.1 62.4h-.5v.2l.1 .3h.4v.3l-.5 .1M129.1 60.7h-.5v.2l.5 .4v.2h-.5M129.2 73.2h.5v-.3l-.5-.1v.8M129.2 69.8l.5-.1v-.3l-.5-.1v.8M129.5 62.4h.3l.1 .2-.1 .7h-.3zM129.5 73.2l.2 .4"/>
<path d="M129.5 69.8l.2 .3M129.9 60.8l-.3-.1a.43 .43 0 0 0-.2 .6 .43 .43 0 0 0 .5 .2M130.2 63.3l.3-.9 .3 .9M130.3 73.4l.4 .3M130.3 72.8l.4 .2-.2 .6h-.3l-.1-.2zM130.3 70l.4 .2M130.3 69.3a.42 .42 0 0 1 .4 .4 .42 .42 0 0 1-.4 .4l-.2-.2zM130.3 63h.4M130.3 60.7v.9h.5M130.9 72.8h.6l-.3 .3h.2v.5l-.5-.1M131.4 69.3h-.4v.4l.4-.1 .1 .5h-.5M133.5 77.5h5l.7 .9-.7 .8h-5z"/>
<path d="M133.5 70.6h3.9l.6 .8-.6 .9h-3.9zM133.5 67.2h3.9l.6 .8-.6 .9h-3.9zM133.9 70.8h2.8M133.9 67.3h2.8M134.1 78.4h.6M134.1 67.6v.8M134.1 71.1v.8M134.3 78.1v.7M134.4 71.5h.4l.1-.3-.5-.1v.8M134.4 68h.4l.1-.3-.5-.1v.8M134.7 71.5l.2 .4M134.7 68l.2 .4"/>
<path d="M135.4 71.7l.4 .3M135.4 71.1l.4 .1a.47 .47 0 0 1-.4 .7l-.1-.3zM135.4 68.3l.4 .2M135.4 67.6h.3l.1 .3-.1 .5h-.3l-.1-.2zM135.5 77.9h-.4v.5h.4l-.1 .4-.3-.1M135.8 77.9l.3 .9 .3-.9M136.4 71l-.2 .6h.5M136.6 67.6l-.4 .2v.6h.4v-.5h-.3l-.1 .2M136.6 71.3v.6M136.9 78.3l-.1-.1-.2 .2 .3 .1v.3h-.3M137.4 77.9v.9h.3l.1-.4-.2-.2-.2 .1M179.9 62h3.3l.7 .9-.7 .8h-3.3l-.8-.8z"/>
<path d="M179.9 60.2h3.2v1.8h-3.2l-.8-.9zM180 72.3h3.9l.7 .9-.7 .8h-3.9zM180 68.9h3.9l.7 .8-.7 .9h-3.9zM180.4 72.5h2.9M180.4 69.1h2.9M180.5 69.3v.8M180.5 72.8v.8M180.8 62.4l-.5 .1v.3l.5 .2-.1 .3h-.4M180.8 60.7l-.5 .1v.2l.4 .2 .1 .2-.2 .2-.3-.1M181 73.2h.4l.1-.3-.2-.1h-.3v.8M181 69.8h.3l.2-.3-.2-.2h-.3v.8M181.1 62.4l.5 .1v.4l-.1 .4h-.4z"/>
<path d="M181.1 73.2l.4 .4M181.1 69.8l.4 .3M181.6 60.8l-.4-.1-.1 .2 .1 .6h.4M181.8 72.9h.5l-.1 .7-.4-.1zM181.8 69.5l.2-.2 .3 .2-.1 .6h-.4zM181.9 73.4l.5 .3M181.9 63.3l.3-.9 .3 .9M181.9 70l.5 .2M182 60.7v.9h.4M182 63h.4M182.7 72.8h.5l-.4 .3h.3l.1 .2-.1 .3-.4-.1M183.1 69.3h-.4v.4l.3-.1 .2 .5h-.5"/>
<path d="M185.1 77.5h5l.8 .9-.8 .8h-5zM185.1 67.2h3.9l.8 .8-.8 .9h-3.9zM185.1 70.6h3.9l.8 .8-.8 .9h-3.9zM185.6 70.8h2.8M185.6 67.3h2.8M185.7 78.4h.7M185.7 67.6v.8M185.7 71.1v.8M186.1 78.1v.7M186.1 68h.5v-.4h-.5v.8M186.1 71.5h.5v-.4h-.5v.8M186.3 68l.3 .4"/>
<path d="M186.3 71.5l.3 .4M187 71.2h.5v.6l-.2 .1a.47 .47 0 0 1-.4-.3 .47 .47 0 0 1 .1-.4zM187.1 68.3l.5 .2M187.1 67.6l.4 .1-.1 .7h-.3l-.2-.2zM187.1 71.7l.5 .3M187.2 77.9h-.4l-.1 .5 .5-.1v.5l-.5-.1M187.5 77.9l.2 .9 .4-.9M188.1 71l-.3 .6h.5M188.3 67.6h-.3l-.2 .3 .1 .5h.4v-.5h-.4l-.1 .2M188.3 71.3v.6M188.6 78.3l-.2-.1-.1 .2 .4 .3-.4 .1M189 77.9v.9h.4v-.5h-.4"/>
<path d="M57.9 91.2h2.4l.8 1-.8 .8h-2.4zM58.5 92.6l.4-.9 .2 .9M58.5 91.5h1.5M58.6 92.3h.5M59.9 91.7l-.5 .1v.3l.5 .2-.1 .3h-.4M97.5 97.3h2.4l.8 .9-.8 .8h-2.4zM97.5 93.8h2.4l.8 .9-.8 .8h-2.4zM97.5 99h2.4l.8 .9-.8 .8h-2.4zM97.5 92.2h2.4l.8 .8-.8 .8h-2.4zM97.5 95.5h2.4l.8 .9-.8 .9h-2.4zM98.2 98.6l.3-.9 .3 .9M98.2 95.2l.3-.9 .3 .9"/>
<path d="M98.2 93.4l.3-.8 .3 .8M98.2 96.9l.3-.8 .3 .8M98.3 98.3h.4M98.3 95h.4M98.3 93.2h.4M98.3 96.6h.4M98.9 99.4h.6l-.3 .4 .3 .1v.3l-.1 .2-.5-.1M98.9 92.6h.6l-.3 .8M99.2 97.7l-.2 .6h.5M99.4 94.3l-.4 .2v.6l.4 .1 .1-.2-.1-.4-.4 .2M99.4 96.1h-.4v.4l.4-.1 .1 .3-.1 .2-.4-.1M99.4 98v.6"/>
<path d="M128.6 92.2h3.2l.7 .8-.7 .8h-3.2zM128.6 97.3h3.2l.7 .9-.7 .8h-3.2zM128.6 93.8h3.2l.7 .9-.7 .8h-3.2zM128.6 95.5h3.2l.7 .9-.7 .9h-3.2zM128.6 99h3.2l.7 .9-.7 .8h-3.2zM129.2 93.4l.3-.8 .3 .8M129.2 98.6l.3-.9 .3 .9M129.2 95.2l.3-.9 .3 .9M129.2 96.9l.3-.8 .3 .8M129.3 98.3h.4M129.3 95h.4M129.3 93.2h.4"/>
<path d="M129.3 96.6h.4M130.1 92.8l.2-.2v.8M130.1 98l.2-.3v.9M130.1 94.5l.2-.2v.9M130.1 96.3l.2-.2v.8M130.1 99.7l.2-.3v1M130.1 93.4h.4M130.1 98.6h.4M130.1 95.2h.4M130.1 96.9h.4M130.8 97.7h.6l-.3 .4 .3 .1v.3h-.6M130.8 99.5h.6v.4l-.6 .5h.6"/>
<path d="M131.1 96l-.3 .6h.6M131.3 92.6h-.3l-.2 .7 .1 .1 .5-.1-.1-.4h-.4l-.1 .2M131.3 96.3v.6M131.4 94.3h-.5l-.1 .4h.6v.4h-.6M160.9 92.2h3.6l.8 .8-.8 .8h-3.6zM161.2 97.3h3.3l.8 .9-.8 .8h-3.3zM161.2 95.5h3.3l.8 .9-.8 .9h-3.3zM161.2 93.8h3.3l.8 .9-.8 .8h-3.3zM161.2 99h3.3l.8 .9-.8 .8h-3.3zM161.8 93h.3l.1-.3-.4-.1v.8M161.9 93l.3 .4M162 98.6l.3-.9 .2 .9"/>
<path d="M162 96.9l.3-.8 .2 .8M162 95.2l.3-.9 .2 .9M162 98.3h.4M162 95h.4M162 96.6h.4M162.8 97.8h.5v.3l-.5 .5h.5M162.8 96.1h.5v.3l-.5 .5h.5M162.8 94.4h.5v.3l-.5 .5h.5M162.8 99.5h.5v.4l-.5 .5h.5M163.2 92.6l-.8 1.1M163.4 92.6l.2 .8 .2-.6 .2 .6 .1-.8M163.4 92.3h.8"/>
<path d="M163.5 94.3h.6l-.3 .3 .3 .2v.2l-.1 .2-.5-.1M163.6 98l.3-.3v.9M163.6 96.1h.4l.1 .2-.6 .6h.6M163.6 98.6h.5M163.8 99.4a.48 .48 0 0 1 .3 .5 .48 .48 0 0 1-.3 .5l-.2-.2v-.6zM23.7 105h5.6l.8 .9-.8 .9h-5.6zM24.3 105.3h4.7M24.5 105.9h.3M24.9 105.5h-.4v.9h.4M25.2 105.5l.6 .9M25.8 105.5l-.6 .9M26 118.8h3.3l.8 .9-.8 .8h-3.3z"/>
<path d="M26 117.1h3.3l.8 .9-.8 .8h-3.3zM26 115.4h3.3l.8 .8-.8 .9h-3.3zM26 112h3.3l.8 .8-.8 .9h-3.3zM26 113.7h3.3l.8 .8-.8 .9h-3.3zM26.1 106h.4v-.4l-.4-.1v.9M26.7 116.7l.3-.8 .3 .8M26.7 113.2l.3-.8 .3 .8M26.7 114.9l.3-.8 .3 .8M26.8 119.7h.3M26.8 118h.3M26.8 116.5h.4M26.8 113h.4"/>
<path d="M26.8 114.8h.4M27.2 119.2h-.4v1M27.2 117.6h-.4v.8M27.4 105.5h-.4l-.1 .2 .5 .3v.3h-.5M27.6 115.9h.4l.1 .1-.5 .7h.5M27.6 112.5l.4-.1 .1 .2-.5 .6h.5M27.6 114.2l.3-.1 .2 .2-.5 .6h.5M27.8 105.9h.3M28.1 119.3l-.3-.1-.2 .3v.4l.2 .3 .3-.1M28.1 117.6h-.4l-.1 .1v.5l.1 .2 .4-.1M28.1 105.5h-.3v.9h.3M28.3 112.4h.6l-.3 .3h.2v.5h-.5"/>
<path d="M28.4 119.5l.3-.3v1M28.5 117.6a.42 .42 0 0 1 .4 .4 .42 .42 0 0 1-.4 .4zM28.6 105.5v.9h.4M28.6 114.1l-.2 .6h.5M28.8 115.9h-.4v.3h.4l.1 .3-.2 .2-.3-.1M28.8 114.4v.5M56.9 101.6h3.4l.8 .9-.8 .8h-3.4zM57 112h3.3l.8 .8-.8 .9h-3.3zM57.5 101.8h2.5M57.7 102.1l.1 .8 .3-.1v-.7M57.8 112.1h2.2M57.9 112.4v.8h.4"/>
<path d="M58.5 102.1h.4l.2 .1v.5l-.2 .2h-.4zM58.5 112.4h.4l.2 .2v.5l-.2 .1h-.4zM59.9 102.1h-.5v.3l.5 .3-.1 .2h-.4M59.9 112.4l-.5 .1v.2l.5 .3-.1 .2h-.4M97.5 102.5h2.4l.8 .8-.8 .9h-2.4zM97.5 100.7h2.4l.8 .9-.8 .9h-2.4zM97.5 104.2h2.4l.8 .8-.8 .9h-2.4zM98.2 103.8l.3-.9 .3 .9M98.2 100.4l.3-1 .3 1M98.2 102.1l.3-.9 .3 .9M98.2 105.5l.3-.9 .3 .9M98.3 103.5h.4"/>
<path d="M98.3 100.1h.4M98.3 101.8h.4M98.3 105.3h.4M99 103.2l.3-.3v.9M99 101.3l.4-.1 .1 .3-.6 .6h.6M99 103.8h.5M99.2 105l-.2-.1v-.2l.4-.1 .1 .3-.5 .2v.3l.2 .1 .3-.1-.1-.4M128.6 102.5h3.2l.7 .8-.7 .9h-3.2zM128.6 100.7h3.2l.7 .9-.7 .9h-3.2zM129.2 103.8l.3-.9 .3 .9M129.2 102.1l.3-.9 .3 .9M129.2 100.4l.3-1 .3 1"/>
<path d="M129.3 104.2h2.5l.7 .8-.7 .9h-2.5zM129.3 103.5h.4M129.3 100.1h.4M129.3 101.8h.4M130.1 103.2l.2-.3v.9M130.1 101.5l.2-.3v.9M130.1 105.5l.2-.9 .3 .9M130.1 103.8h.4M130.1 102.1h.4M130.1 100.4h.4M130.2 105.3h.3M130.8 101.5l.3-.3v.9"/>
<path d="M130.8 102.1h.6M130.9 103l.3-.1 .2 .2-.1 .6a.39 .39 0 0 1-.5-.2 .39 .39 0 0 1 .1-.5zM131.4 105l-.4 .2-.2-.4 .2-.2 .4 .1-.1 .7-.4 .1M161.2 104.2h3.3l.8 .8-.8 .9h-3.3zM161.2 102.5h3.3l.8 .8-.8 .9h-3.3zM161.2 100.7h3.3l.8 .9-.8 .9h-3.3zM162 105.5l.3-.9 .2 .9M162 103.8l.3-.9 .2 .9M162 102.1l.3-.9 .2 .9M162 100.4l.3-1 .2 1M162 103.5h.4M162 100.1h.4"/>
<path d="M162 101.8h.4M162 105.3h.4M162.8 104.9l.2-.3v.9M162.8 103.2l.2-.3v.9M162.8 101.5l.2-.3v.9M162.8 103.8h.5M162.8 102.1h.5M162.8 105.5h.5M163.5 104.6h.6l-.3 .9M163.8 103.2l-.2-.2 .4-.1 .1 .2-.1 .1-.4 .1 .1 .5h.3l.1-.2-.1-.4M164.1 101.6l-.1 .1h-.3l-.1-.4 .4-.1 .1 .2v.3l-.4 .4M16.8 122.3h8.2l.8 .8-.8 .9h-8.2z"/>
<path d="M17.5 122.5h7.2M17.6 123.1h.3M18 122.7h-.4v.9h.4M18.3 122.7l.5 .9M18.8 122.7l-.5 .9M19.2 123.1h.4l.1-.3-.5-.1v.9M20 123.1h.4l.1-.3-.5-.1v.9M20.3 123.1l.2 .5M20.8 123.6l.3-.9 .3 .9M20.9 123.3h.4M21.6 123.6v-.9l.4 .6 .2-.6v.9M23.1 122.8l-.4-.1-.1 .2 .1 .2 .4 .1-.1 .4h-.4"/>
<path d="M23.5 123.1h.2M23.8 122.7h-.3v.9h.3M24.3 122.7v.9h.4M26 120.5h3.3l.8 .9-.8 .9h-3.3zM26.8 121.5h.3M27.2 121h-.4v.9M28.1 121.1l-.4-.1-.1 .2v.4l.2 .3 .3-.1M28.4 121.1l.4-.1 .1 .3-.6 .6h.6M28.4 120.2h.5M53.7 122.3h6.6l.8 .8-.8 .9h-6.6zM55.1 122.8a.44 .44 0 0 0-.7 .2 .44 .44 0 0 0 .2 .6l.5-.1M55.4 123.1h.4l.1-.2-.2-.2h-.3v.9"/>
<path d="M56.3 122.7v.9l.5-.1v-.8M56.9 123.7h.7M58.3 122.8l-.2-.1a.48 .48 0 0 0-.3 .4 .48 .48 0 0 0 .2 .5l.3-.1M58.7 122.7v.9h.4M59.4 122.7v.9M59.5 123.1l.4 .5M59.9 122.7l-.5 .5M186.8 137.8h3.9l.8 .8-.8 .9h-3.9zM187.3 138h2.8M187.4 138.2v.9M187.8 138.6h.5v-.2l-.1-.2h-.4v.9M188.1 138.6l.2 .5"/>
<path d="M188.7 138.4l.1-.2a.42 .42 0 0 1 .5 .4 .42 .42 0 0 1-.5 .5l-.1-.1zM188.8 138.9l.5 .2M189.9 138.2l-.2 .1-.2 .6 .1 .2 .4-.1v-.4h-.3l-.2 .1M186.8 141.2h3.9l.8 .9-.8 .9h-3.9zM186.8 148.1h3.9l.8 .9-.8 .8h-3.9zM186.8 144.6h3.9l.8 .9-.8 .9h-3.9zM187.3 141.4h2.8M187.3 148.3h2.8M187.3 144.9h2.8M187.4 141.7v.8M187.4 145.2v.8M187.4 148.5v.9"/>
<path d="M187.8 142.1h.5v-.4h-.5v.8M187.8 149.1h.4l.1-.4-.1-.2h-.4v.9M187.8 145.6h.4l.1-.4h-.5v.8M188.1 142.1l.2 .4M188.1 149.1l.2 .3M188.1 145.6l.2 .4M188.7 141.8h.5l.1 .5-.2 .2-.4-.1zM188.7 148.7l.1-.2a.42 .42 0 0 1 .5 .5 .42 .42 0 0 1-.5 .4l-.1-.1zM188.7 145.2h.5a.47 .47 0 0 1-.4 .8l-.1-.2zM188.8 142.4l.5 .2M188.8 149.2l.5 .3M188.8 145.8l.5 .3"/>
<path d="M189.5 148.5h.5l-.2 .4 .2 .1v.3h-.5M189.8 145.1l-.3 .6h.6M189.9 145.4v.6M190 141.7h-.4l-.1 .4 .4-.1 .1 .4h-.5"/>
</g>
<g fill="none" stroke="#0f0f0f" stroke-width=".21">
<path d="M118.2 95.6h.3M118.2 99.1h.3M118.2 97.3h.3M118.2 93.9h.3M118.6 95.2h-.4v.9h.4M118.6 98.7h-.4v.8h.4M118.6 97h-.4v.8h.4M118.6 93.5h-.4v.9h.4M118.9 95.2l.6 .9M118.9 98.7l.6 .8M118.9 97l.6 .8M118.9 93.5l.6 .9"/>
<path d="M119.5 95.2l-.6 .9M119.5 98.7l-.6 .8M119.5 97l-.6 .8M119.5 93.5l-.6 .9M119.8 95.7l.5-.1v-.3l-.5-.1v.9M119.8 99.1h.4l.1-.3-.5-.1v.8M119.8 97.4l.5-.1v-.2l-.5-.1v.8M119.8 93.9h.4l.1-.3-.5-.1v.9M120.4 96.1h.7M120.4 99.6h.7M120.4 97.9h.7M120.4 94.4h.7"/>
<path d="M121.2 96.1l.3-.9 .3 .9M121.2 99.5l.3-.8 .3 .8M121.2 97.8l.3-.8 .3 .8M121.2 94.4l.3-.9 .3 .9M121.3 95.8h.4M121.3 99.3h.4M121.3 97.6h.4M121.3 94.1h.4M122 98.7h.5l-.3 .3h.3v.5l-.5-.1M122.2 96.9l-.2 .6h.6M122.5 95.2h-.5v.4h.5v.5l-.5-.1M122.5 93.5l-.5 .2v.6l.5 .1v-.6h-.4l-.1 .2"/>
<path d="M122.5 97.2v.6M118.2 100.8h.3M118.2 102.5h.3M118.6 100.4h-.4v.8h.4M118.6 102.1h-.4v.9h.4M118.9 100.4l.6 .8M118.9 102.1l.6 .9M119.5 100.4l-.6 .8M119.5 102.1l-.6 .9M119.8 100.9l.5-.1v-.3l-.5-.1v.8M119.8 102.6l.5-.1v-.3l-.5-.1v.9M120.4 101.3h.7"/>
<path d="M120.4 103.1h.7M121.2 101.2l.3-.8 .3 .8M121.2 103l.3-.9 .3 .9M121.3 101h.4M121.3 102.7h.4M122 100.5l.4-.1 .1 .4-.5 .4h.5M122 102.3l.3-.2v.9M122 103h.5"/>
</g>
<g fill="none" stroke="#090" stroke-width=".21">
<path d="M63.7 39.6h-4.3v.8M117.9 39.6h-4.2v.8M169.6 39.6h-4.3v.8M45.6 50.8h5.2M45.6 54.2h5.2M45.6 57.7h5.2M45.6 43.9h5.2M45.6 40.4h5.2M50.8 59.4v.8h-.9M50.8 49.1v.8h-.9M50.8 42.2v.8h-.9M50.8 45.6v.8h-.9"/>
<path d="M50.8 55.9v1h-.9M50.8 47.4h-5.2v.8h-.9M59.4 49.1h4.3v.8h.9M59.4 47.4v.8h3.4M73.1 54.2h.9M73.1 57.7h.9M73.1 55.9h.9M73.1 52.5h.9M73.1 59.4h5.2M99.9 50.8h5.1M99.9 54.2h5.1M99.9 57.7h5.1"/>
<path d="M99.9 43.9h5.1M99.9 40.4h5.1M105 42.2v.8h-.8M105 45.6v.8h-.8M105 49.1v.8h-.8M105 55.9v1h-.8M105 59.4v.8h-.8M105 47.4h-5.1v.8h-.9M113.7 49.1h4.2v.8h.9M113.7 47.4h1.7v.8h1.6M127.4 54.2h.8M127.4 57.7h.8"/>
<path d="M127.4 55.9h.8M127.4 52.5h.8M127.4 59.4h5.1M151.5 50.8h5.2M151.5 54.2h5.2M151.5 57.7h5.2M151.5 43.9h5.2M151.5 40.4h5.2M156.7 59.4v.8h-.9M156.7 49.1v.8h-.9M156.7 42.2v.8h-.9M156.7 45.6v.8h-.9"/>
<path d="M156.7 47.4h-5.2v.8h-.8M156.7 55.9v1h-.9M165.3 49.1h4.3v.8h.9M165.3 47.4h.9v.8h2.6M179.1 54.2h.9M179.1 57.7h.9M179.1 55.9h.9M179.1 52.5h.9M179.1 59.4h5.2M209.3 43.9v.8h-.9M245.4 43.9v.8h-.8M45.6 78.4h5.2"/>
<path d="M49.9 64.6h.9M50.8 61.1v.9h-.9M59.4 78.4h5.2M73.1 64.6h5.2M73.1 78.4h6.1M73.1 71.4h6.1M73.1 73.2h.9M73.1 68h6.1M73.1 69.7h.9M73.1 66.2h.9M99.9 78.4h5.1M104.2 64.6h.8"/>
<path d="M105 61.1v.9h-.8M113.7 78.4h5.1M127.4 64.6h5.1M127.4 78.4h6.1M127.4 71.4h6.1M127.4 73.2h.8M127.4 68h6.1M127.4 69.7h.8M151.5 78.4h5.2M155.8 64.6h.9M156.7 61.1v.9h-.9M165.3 78.4h5.2"/>
<path d="M179.1 64.6h5.2M179.1 78.4h6M179.1 71.4h6M179.1 73.2h.9M179.1 68h6M179.1 69.7h.9M203.2 69.7v3.5h23.2v-.9M210.9 62.9v3.3M210.9 69.7v3.5M226.4 68h15.5M226.4 63.7v-.8h-23.2v3.3M226.4 67.2v1.7"/>
<path d="M233.4 68v19.8h8.5M252.3 69.7h5.1M254 67.2v10.3h-14.6v-6.1h2.5M45.6 80h5.2M59.4 80h5.2M73.1 80h4.3M99.9 80h5.1M113.7 80h5.1M127.4 80h4.3M151.5 80h5.2M165.3 80h5.2M179.1 80h4.3"/>
<path d="M203.2 81.8v-3.4h7.7v3.4M203.2 94.7v-3.5h7.7v3.5M203.2 85.2v3.5M203.2 98.2v3.4M210.9 85.2v3.5h-11.1v12.9h11.1v-3.4M252.3 89.5h5.1M254 87v10.3h-14.6v-6.1h2.5M93.8 108.5h6.9M100.7 110.2v.8h-.8M125.7 108.5h6.8M132.5 110.2v.8h-.8M158.5 108.5h6.8"/>
<path d="M165.3 110.2v.8h-.8M25.8 123.1h4.3M61.1 123.1v3.5M86.1 122.3h90.4v28.4M86.1 120.5v30.2M113.7 122.3v28.4M142.9 122.3v28.4M28.3 143.8v5.2M30.9 156.8v2.5M42.1 143.8v2.6M42.1 156.8v2.5M113.7 159.3v30.1"/>
<path d="M30.1 163.6h.8v.9M30.9 167.9v2.6M30.9 179.1v2.6M43 167.9v2.6M113.7 161h62.8v28.4M142.9 161v28.4M19.8 188.6h50.8M19.8 192.1h50.8"/>
</g>
<g fill="none" stroke="#0000ca" stroke-width=".21">
<path d="M18.8 32l-.3 .3v.6l.3 .3M18.8 33.7h-.3l-.1 .2 .2 .4 .2-.1M18.9 30.7v.8l-.4-.8v.8M19 32v.9M19.2 33.5v.7l.1 .1M19.3 31.5h.1M19.3 32.4h.4M19.4 32v.8l.3 .1M19.6 34l.4-.1v-.2l-.4 .1v.4l.2 .1 .2-.1M19.8 31.1h.3l.1-.3-.4-.1v.8h.3l.2-.1-.2-.3M20 32l-.1 .2M20.4 33.7l.4 .1v.5"/>
<path d="M20.6 31.5h.1M20.6 32.4l-.3 .1 .4 .3-.4 .1M20.8 33.9l-.4 .1v.3l.4-.1M21.2 33.7v.6M21.4 33.7l-.2 .2M21.7 30.7h.4a.47 .47 0 0 1 .1 .5 .47 .47 0 0 1-.5 .3zM21.7 32.4h.4v.5h-.4l-.1-.2 .2-.1h.3M22.2 33.7h.4M22.4 33.5v.7l.2 .1M22.5 32v.9h.3l.1-.4-.4-.1M22.8 34l.4-.1v-.2h-.4v.5h.4M23 30.7l-.4 .1v.2l.4 .2v.3h-.4"/>
<path d="M23.3 30.9l.3-.2v.8M23.3 31.5h.5M23.6 32.4h-.4l.1 .2h.3v.3h-.4M23.6 33.7v.6M23.8 33.7l-.2 .2M24 32.4l.3 .1v.4h-.3zM24.1 33.8h.4v.5M24.1 33.7v.6M24.5 33.8l.3-.1v.6M24.8 32.4v.5l.3-.1M24.8 31.1h.7M24.8 31.4h.7"/>
<path d="M25.1 32.4v.5M25.3 33.5v.1M25.3 33.7v.6M25.5 32l.1 .9M25.7 33.8l.3-.1v.6M25.7 33.7v.6M25.9 32.4h.3M25.9 32v.8l.3 .1M26.5 32.6h.3v-.2h-.3v.5h.3M26.5 33.8l.3-.1 .1 .5-.2 .1-.2-.1zM26.6 30.7l.1 .8h.3v-.8M27.2 32l.1 .9"/>
<path d="M27.2 33.5v.7l.2 .1M27.5 30.7h.3l.2 .2v.5l-.3 .1h-.2zM27.6 32.4l.2 .5M27.7 33.7l.4 .1-.1 .5-.4-.1zM28 32.4l-.3 .7-.1 .1M28.8 30.7l-.5 .1v.2l.5 .3-.1 .2h-.4M28.8 32l.4 .9 .2-.9M28.8 34.2l-.2 .1-.2-.1 .1-.5h.3v.8l-.3 .1M29.2 33.7l.1 .6M29.2 31.5v.1M29.6 33.7l-.4 .9M29.7 32v.9"/>
<path d="M29.9 34.2v.1M29.9 33.5v.5M30 32h.5M30.3 30.7h.3l.1 .2v.5l-.3 .1h-.1zM30.3 33.3a1.02 1.02 0 0 1 0 1.4M30.3 32v.9M30.6 32.9l.3-.9 .3 .9M30.7 32.6h.4M31.5 30.7h-.4l-.1 .2 .2 .2 .3 .1v.3h-.5M31.5 32l.1 .9M32 30.7a.39 .39 0 0 1 .4 .4 .39 .39 0 0 1-.4 .4zM32.5 32.4h.3"/>
<path d="M32.6 32v.9h.2M33.1 32.5l.3-.1 .1 .4-.4 .1zM33.4 31.1h.7M33.4 31.4h.7M34.6 32.4v.5l.3-.1M34.9 32.4v.5M35.1 30.7v.8h.4M35.6 32.4l-.3 .1 .4 .3-.4 .1M35.9 30.7l.4 .2v.5l-.3 .1h-.1zM35.9 32.6h.5v-.2l-.5 .1v.3l.5 .1M37.1 30.7h-.4l-.1 .2 .2 .2 .3 .1v.3h-.5M16.6 86.5h.5"/>
<path d="M16.6 96.5h.4M16.7 88.2l.4 .1v.4h-.4l.1-.4h.3M16.7 93.8h.4v.4h-.4M16.7 96.1v.8l.3 .2M16.7 92v.8M16.7 93.4v.9M16.9 86.5v.8M17.1 92.8l.2-.8 .3 .8M17.1 95.1h-.4v.4l.4 .1M17.1 92.7h.4M17.2 85v1l-.5-1v1M17.2 90.6l-.5 .1v.3l.5 .2-.1 .3h-.4"/>
<path d="M17.2 96.6l.4-.1v.6M17.2 96.1v1M17.4 86.8h.3v.5M17.4 86.5v.8M17.5 88.3h.4v.4M17.5 93.9l.4-.1-.2-.1-.2 .1v.4h.3M17.5 95.1l.2-.1 .2 .2-.1 .4h-.3zM17.5 88.2v.5M17.6 90.6v.1M17.6 90.9v.6M17.6 85.9v.1M18 91h.3v.5"/>
<path d="M18 96.7l.4-.1-.1-.1h-.3v.5h.3M18 90.9v.6M18.1 85.5h.3l.1-.4-.4-.1v1h.3l.2-.4-.3-.1M18.2 87.1l.4-.1-.2-.3-.2 .1v.4h.3M18.2 95.1l.3-.1 .2 .2v.4M18.2 88.2l.2 .5M18.2 95v.6M18.3 91.1l.3-.2 .2 .2v.4M18.4 92.1a.44 .44 0 0 0-.6 .1 .44 .44 0 0 0 .2 .6l.4-.1M18.7 88.2l-.5 .8M18.8 92v.8M18.8 92.4l.5 .4"/>
<path d="M18.9 85.9v.1M18.9 93.8h.4v.5M18.9 95h.4M19 94.8v.7l.3 .1M19.1 90.6v.1M19.1 90.9v.6M19.3 93.8l-.5 .2 .2 .3 .3-.1M19.3 92l-.5 .5M19.4 87.3l.4-.8 .2 .8M19.4 96.5h.4l.1 .1-.2 .5-.4-.2zM19.5 90.6v.8l.2 .1M19.5 87.1h.4"/>
<path d="M19.5 95v.6M19.6 88.3h.4l-.1 .4-.3-.1zM19.7 93.7v.4l.2 .2 .2-.1M19.8 95l-.3 .2M19.9 85h.5M20 91l.2-.1 .2 .2v.4h-.4l-.1-.2 .2-.2h.3M20 95.2l.2-.2 .2 .1v.4l-.3 .1zM20.1 85v1M20.1 93.7v.6M20.2 97l.2 .1 .2-.2-.1-.4h-.3v.8M20.3 86.7v.6M20.3 88.2h.3"/>
<path d="M20.4 87.8v.8l.2 .1M20.4 93.7h.3M20.4 93.4v.7l.3 .2M20.5 86.7l-.2 .2M20.6 85.5h.4v.5M20.6 92.3h-.3l-.1 .2 .1 .3h.3M20.6 85v1M20.8 90.9v.6M20.9 86.8l.2-.1 .2 .2-.2 .4-.2-.1M20.9 88.3h.4v.4M20.9 94.8l.1 .8M20.9 86.5v.8"/>
<path d="M20.9 87.8v.9M21 93.8h.4v.4h-.4zM21 96.7l.4-.1-.1-.1h-.3v.5h.3M21 92.3l.1 .5M21 90.9l-.2 .2M21.3 90.6l.1 .9M21.3 94.8l.1 .8M21.4 85.6h.4l-.1-.2h-.3v.5h.3M21.4 92.3l-.4 .9M21.6 86.5v.1M21.6 88.4l.5-.1-.1-.1h-.4v.5h.4M21.6 93.7l.3 .6 .2-.6"/>
<path d="M21.6 86.7v.6M21.6 90.9l.3 .6M21.7 95.4l.4-.1-.1-.3-.3 .1v.5h.4M21.7 96.5v.6M21.9 86.7h.3M22 96.5l-.3 .1M22.1 86.5v.7l.1 .1M22.1 90.9l-.3 .8h-.2M22.1 92.3l-.5 .1 .1 .4h.4M22.2 96.5l.4 .1v.5M22.4 92v.7l.2 .1M22.4 93.9l.3-.1-.1-.1-.2 .1v.4h.3"/>
<path d="M22.4 88.2v.5M22.5 86.9l.1-.2 .3 .1v.4l-.3 .1zM22.5 91.5l-.1 .1M22.5 95v.6M22.6 88.2l-.2 .1M22.6 96.6l-.4 .1 .1 .4 .3-.1M22.7 95l-.2 .2M22.8 92.6l.4-.1v-.2h-.4v.5h.4M22.9 96.5h.3M23 96.1v.8l.2 .2M23.1 85.4h-.3l-.1 .2 .5 .2-.2 .2-.3-.1M23.3 86.7v.6"/>
<path d="M23.4 85.4l.3 .6M23.5 91h.3v.5M23.5 93.8l-.3-.1-.1 .1 .1 .5 .3-.1M23.5 96.1v.1M23.5 90.9v.6M23.5 96.5v.6M23.6 86.7l-.3 .2M23.6 92.7v.1M23.7 95.1h.3v.5h-.3v-.3h.3M23.7 93.7h.4M23.8 85.4l-.1 .6-.3 .2M23.9 87.2l-.1 .2"/>
<path d="M23.9 88.2h-.3l.1 .2h.2v.3h-.3M23.9 93.4v.8l.2 .1M23.9 96.6l.4-.1v.6M23.9 96.5v.6M24.3 87.8v.8l.1 .1M24.3 90.9l.4 .2-.1 .4h-.3l-.1-.2zM24.3 93.8h.5v.4h-.5zM24.4 85.4h-.2l-.1 .2 .4 .2-.2 .2-.2-.1M24.4 95.1l.3-.1 .1 .2v.4M24.4 95v.6M24.7 88.3h.5l-.1 .4h-.3zM24.8 85.4h.3"/>
<path d="M24.8 85v.8l.3 .2M24.9 86.8h.4v.5M25.1 97h-.4l.1-.5h.3v.7l-.1 .1h-.3M25.2 93.7v.6M25.3 87l-.5 .2 .2 .1 .3-.1M25.4 85.6h.3v-.2h-.3v.5h.3M25.4 93.7l-.2 .1M25.4 88.2h.3M25.4 92v.8M25.5 87.8v.9h.2M25.6 93.9l.4-.1-.1-.1-.3 .1v.3l.2 .2 .2-.1M25.6 94.8v.8h-.3l-.1-.4 .2-.2 .2 .1"/>
<path d="M25.7 86.8h.3v.5M25.7 92.4h.4v.4M25.7 86.7v.6M25.7 92.3v.5M25.9 91l-.1-.1-.2 .2 .4 .3-.4 .1M26 88.6v.1M26.1 85.5l.4-.1v.6M26.1 85.4v.6M26.4 90.6v.8l.1 .1M26.4 92.3h.3M26.5 85.5l.3-.1v.6M26.5 96.5h-.4v.2l.4 .1-.1 .3-.3-.1"/>
<path d="M26.5 92v.8h.2M26.6 95.1l.3-.1 .1 .2v.4M26.6 94.8v.8M26.7 96.5l.3 .6M26.8 86.8h-.3v.4h.3M26.8 91h.4l-.1 .5-.3-.1zM26.8 93.8l-.3-.1-.1 .1 .1 .5 .3-.1M26.8 86.5v.8M26.8 93.4v.9M27 92.6l.4-.1-.1-.2h-.3v.5h.3M27.1 96.5l-.1 .6-.3 .2M27.5 95.1h.3v.5h-.3l-.1-.1 .2-.2h.2"/>
<path d="M27.5 90.9h.3M27.6 90.6v.9h.2M27.7 92.3v.5M27.8 86.7l.2 .6 .1-.4 .2 .4 .2-.6M27.8 96.5h-.3v.2l.3 .1-.1 .3-.2-.1M27.9 85.4h.3l.1 .2-.2 .4-.2-.1M27.9 93.8h.3v.4h-.3M27.9 85v1M27.9 93.4v.9M28 92.3l-.3 .2M28.1 96.5h.3M28.1 96.1v.8l.3 .2"/>
<path d="M28.2 95.1h.4v.5M28.2 92.3v.5M28.2 95v.6M28.5 92.3l-.3 .2M28.6 93.7l.1 .6M28.7 85.5h.4v.4h-.4zM28.7 90.9l.1 .6 .2-.4 .2 .4 .1-.6M28.7 96.7l.4-.1-.1-.1h-.3v.5h.3M28.8 86.5v.1M28.8 92.3v.5l.4-.1M28.8 86.7v.6M29 93.7l-.4 .8"/>
<path d="M29.2 92.3v.5M29.2 86.5l.1 .8M29.3 94.8v.8h-.2l-.1-.5h.3M29.4 85.4l.4 .1v.5M29.4 96.6l.4-.1v.6M29.4 96.5v.6M29.6 92.8l.4-.1-.1-.4h-.3v.9M29.7 86.5l.1 .8M29.7 90.6v.1M29.7 90.9v.6M29.8 94.8v.7l.1 .1M29.8 96.6h.4v.5"/>
<path d="M29.8 85.6h-.4l.1 .4 .3-.1M29.8 93.7h.4M29.9 93.4v.7l.3 .2M30.1 90.6l.1 .9M30.2 95.4l.4-.1-.1-.3-.3 .2v.3l.4 .1M30.3 85.4v.6M30.3 92.3h.3M30.3 92v.7l.3 .1M30.4 93.8h.4v.5M30.4 93.4v.9M30.5 85.4l-.2 .2M30.5 90.6l.1 .9"/>
<path d="M30.6 97v.1M30.8 86.8h.3v.5M30.8 86.7v.6M31.1 85.4h-.3l-.1 .2 .2 .4 .2-.1M31.1 92.3h-.2l-.1 .2 .4 .2-.4 .1M31.1 85v1M31.2 93.9l.4-.1-.1-.1-.3 .1v.4h.3M31.4 94.8v.8h-.4l-.1-.5h.5M31.5 87.1l.4-.1-.1-.3-.3 .1v.4h.4M31.6 91.2l.4-.1-.1-.2-.3 .1v.5h.4M32.1 92.3l.2 .5 .2-.3 .1 .3 .2-.5M32.2 85v.1"/>
<path d="M32.2 86.7l.2 .6 .2-.6M32.2 85.4v.6M32.3 90.9l.2 .6 .2-.6M32.4 95.1l.2-.1 .2 .2v.4h-.4l.1-.3h.3M32.6 93.4v.1M32.6 93.7v.6M32.9 85.4h-.3v.2l.4 .2-.2 .2-.2-.1M32.9 87.1l.4-.1-.1-.3-.3 .2v.3h.3M33 91.2l.4-.1-.2-.2-.2 .2v.3l.3 .1M33.1 93.8l.1-.1 .2 .1v.5M33.1 93.7v.6M33.1 92v.1"/>
<path d="M33.1 92.3v.5M33.5 92v.7l.2 .1M33.5 95.1l-.3-.1-.1 .2 .1 .2h.3v.2h-.4M33.7 86.7v.6M33.7 93.7h.3M33.7 90.9v.6M33.8 93.4v.8l.2 .1M33.9 86.7l-.2 .2M33.9 85v.2M34 90.9l-.3 .2M34 92l.1 .8M34.2 93.9l.5-.1-.1-.1-.4 .1v.3l.2 .2 .2-.1"/>
<path d="M34.2 85v.2M34.5 85l.3 1 .3-1M34.8 95.1h-.3l.1 .3h.2v.2h-.3M35 93.7v.6M35.3 86.7v.7l-.1 .2h-.4M35.3 86.8h-.5v.4h.5M35.3 91h-.4l.1 .2h.3v.3h-.4M35.3 93.7l-.3 .1M35.3 95v.6l.3-.1M35.3 86v-1l.4 .7 .2-.7v1M35.3 92.3h-.2l-.1 .2 .4 .2-.4 .1M35.6 91.2l.4-.1-.1-.2-.3 .2v.3l.3 .1"/>
<path d="M35.6 93.7v.6M35.6 95v.6M35.7 86.7v.6M35.8 92v.1M35.8 92.3v.5M35.9 86.7l-.2 .2M35.9 93.7l-.3 .1M36.1 93.7v.5h.3M36.2 86.8h.3v.5M36.2 92.4l.3-.1v.5M36.2 92.3v.5M36.4 91.2l.4-.1-.2-.2-.2 .1v.5h.3"/>
<path d="M36.4 95.1l-.3-.1-.2 .2 .1 .4h.4M36.4 85.5h.2M36.4 93.7v.6M36.5 87l-.4 .2 .2 .1 .2-.1M36.5 92.4l.4-.1 .1 .5M36.8 85h-.4v1h.4M36.8 95.1h.3v.5M36.8 94.8v.8M36.9 93.8l.2-.1 .2 .1-.2 .5-.2-.1M36.9 93.7v.8M37 86.8h.3v.5M37 86.7v.6"/>
<path d="M37.3 92.8l.4-.1-.1-.4h-.3v.9M37.5 93.7h.4M37.6 93.4v.7l.3 .2M37.6 86.7h.4M37.7 86.5v.7l.3 .1M37.8 91h.3v.5h-.3l-.1-.2 .4-.2M38.1 85.4h-.3l-.1 .2 .4 .2-.1 .2-.3-.1M38.1 92l.1 .8M38.2 94.8v.8h.3l.1-.5h-.4M38.5 85l.1 1M38.5 92.3l.1 .5M38.6 91h.3v.5"/>
<path d="M38.6 90.9v.6M38.7 86.7h.4M38.9 85.5h.4v.4h-.4zM38.9 86.5v.7l.2 .1M38.9 92.3l-.4 .9M38.9 95l.2 .6M39.3 86.9l.4-.2 .1 .5-.3 .1zM39.3 95l-.4 1M39.6 85.4h.3M39.7 85v.9l.2 .1M41 85l.3 .2v.6l-.2 .2-.3-.2v-.6zM41.6 85v.2"/>
<path d="M41.9 85v.2M42.4 85.9l-.1 .2M209.8 157.8l.2 .8 .3-.8M209.8 160l.2-.9 .3 .9M209.8 159.8h.4M210.6 158.6v-.8l.3 .6 .3-.6v.8M210.9 159.1v.9h-.3v-.5h.3M211.5 158.2h.4M211.7 159.1v.9h-.3v-.5h.3M212 157.8h-.5v.8h.5M212.1 159.5v.5M212.4 159.5l-.3 .1"/>
<path d="M212.4 158.3h.6M212.6 159.7l.5-.1-.1-.1h-.4v.5h.4M213.4 157.8v.7l.2 .1M213.7 159.5h-.3v.2l.3 .1v.2h-.3M213.8 157.8v.1M213.8 158v.6M214.2 157.8v.8M214.3 158.3l.3 .3M214.4 159.5h-.3v.2l.3 .1v.2h-.3M214.6 158l-.4 .4M214.9 158.4l.4-.1-.1-.3-.3 .2v.3l.4 .1M215.4 159.5l.5 .1v.4h-.5v-.3l.5-.1"/>
<path d="M215.8 158.6l-.1 .2M216.3 159.6h.3v.4M216.3 159.5v.5M216.8 157.8v.8h.3l.1-.4-.2-.2-.2 .1M217.4 159.1v.9h-.4v-.5h.4M217.5 158v.5h.4M217.9 158v.6M218.2 158h.4M218.3 157.8v.7l.3 .1M218.8 159.1v.9h-.3v-.5h.3M219.2 159.5h.4v.5h-.4v-.3l.4-.1M219.5 158.1h.3v.5"/>
<path d="M219.5 158v.6M219.9 159.5h.4M220 159.1v.8l.3 .1M220.3 158.1l.2-.1 .2 .2-.1 .4-.3-.1zM220.5 159.5h.3v.5h-.3v-.3l.3-.1M220.9 158h.4M221 157.8v.7l.3 .1M222 159.1v.9M222 157.8l.4 .8 .2-.8M222.4 159.1v.1M222.4 159.5v.5M222.8 159.6l.3-.1v.5"/>
<path d="M222.8 159.5v.5M223 158.6v-.8l.2 .6 .3-.6v.8M223.6 159.7l.4-.1-.1-.1h-.3v.5h.3M223.9 158.2h.3M224.3 157.8h-.4v.8h.4M224.6 159.5h-.3v.2l.4 .2-.4 .1M224.7 158.6v.2M225.1 160l-.1 .1M225.8 157.8v.1M225.8 158v.6M226 158h.4M226.4 157.8h-.2v.8"/>
<path d="M226.5 159.2a.43 .43 0 0 0-.4 .3 .43 .43 0 0 0 .1 .5h.4v-.4h-.2M227.2 158l.3 .6M227.5 159.1v.9l-.6-.9v.9M227.6 158l-.2 .9h-.2M227.9 159.1l.4 .3-.1 .6h-.3zM228 158.1l.2-.1 .2 .2-.1 .4-.3-.1zM228.7 158v.5h.4M229.1 158v.6M229.4 159.5l.3 .1v.4h-.3v-.3l.3-.1M230.2 159.6l.3-.1v.5M230.2 157.8v.8M230.2 159.5v.5"/>
<path d="M230.2 158.3l.3 .3M230.5 158l-.3 .4M230.9 158.1l.2-.1 .2 .2v.4M230.9 158v.6M231.3 159.1v.9h-.4v-.5h.4M231.6 158.2l.3-.2 .2 .2-.1 .4h-.3zM232.3 159.5l.1 .5 .3-.5M232.4 158l.1 .6 .2-.4 .2 .4 .1-.6M233 159.5h.4v.5l-.4-.1zM233.8 159.1l.1 .9M233.9 158l.2 .6 .1-.4 .2 .4 .2-.6M234.1 159.5h.4"/>
<path d="M234.2 159.1v.8l.3 .1M234.7 159.5h.4v.5h-.4v-.3l.4-.1M234.9 158.1h.3v.5M234.9 157.8v.8M235.7 158.1l.2-.1 .2 .2v.4h-.4l.1-.3h.3M235.9 160h-.4l.1-.5h.3v.6l-.1 .2-.3-.1M236.3 159.7l.4-.1-.1-.1h-.3v.5h.3M236.3 158h.4M236.4 157.8v.7l.3 .1M237.6 157.8v.8M237.7 159.5v.5M238 159.5l-.3 .1"/>
<path d="M238.2 159.5l.4 .1v.4h-.4v-.3l.4-.1M238.7 158.1l.2-.1 .2 .2v.4M238.7 158v.6M239 159.1v.1M239 159.5v.5M239.1 158.2v-.2l.3 .1v.5M239.4 159.1v.8l.2 .1M239.8 158.4l.4-.1-.1-.3-.3 .1v.5h.4M240.2 159.5l-.4 .1 .4 .4h-.4M240.6 158.1h.3v.5h-.3l-.1-.1 .2-.2h.2M241.3 158.1h.4v.5M241.3 158v.6"/>
<path d="M242.1 158.5v.1M209.8 160.6v.1M209.8 169.2l.3-.1 .2 .2-.1 .4h-.4zM209.8 170.6h.4v.6M209.8 160.8v.6M209.8 167.5v.9M210.2 165.1h-.4v.5h.4M210.2 170.7l-.4 .1 .1 .4 .3-.1M210.3 160.9h.3v.5M210.3 163.4h-.5v.3l.5 .2v.2h-.5M210.3 167.9h.3l.2-.1-.1-.3h-.4v.9M210.3 160.8v.6"/>
<path d="M210.4 167.9l.4 .5M210.5 165.1l.4-.1 .1 .1-.1 .5h-.3zM210.6 169.2l.3-.1 .1 .2v.4M210.6 169.1v.6M210.7 163.7h.2M210.9 170.6h-.3v.2h.3v.3h-.3M211.1 163.3h-.4v.9h.4M211.2 168.1l.5 .3M211.2 167.5l.4 .1v.6l-.1 .2-.4-.2zM211.4 165.1h.3v.5M211.4 165v.6M211.5 163.8h.3l.2-.4-.2-.1h-.3v.9"/>
<path d="M211.5 160.8h.4M211.6 163.8l.4 .4M211.7 160.6v.7l.2 .1M212 167.6h.5v.2l-.5 .6h.5M212 170.2v.1M212 169.1h.3M212 170.6v.6M212 168.9v.7l.3 .1M212.1 165.1h.4v.5M212.1 165v.6M212.2 160.9l.3-.1 .1 .6M212.2 160.6v.8"/>
<path d="M212.4 170.6h.3v.6M212.4 170.6v.6M212.6 169.2h.3v.5M212.6 168.9v.8M212.8 163.4l-.2-.1-.3 .2v.5l.3 .2 .2-.1M212.8 165h.3M212.9 161.1h.4l-.1-.3-.3 .2v.2l.2 .2 .2-.1M212.9 164.7v.8l.2 .1M213.1 163.3v.9h.5M213.3 168.9h.1M213.3 169.1v.6M213.4 165.3l.4-.1-.1-.2-.3 .1v.5h.3"/>
<path d="M213.5 167.8h.3v.6M213.7 170.2l.3 1 .2-1M213.8 167.9l-.3 .1 .1 .4 .2-.1M213.8 163.3v.9M214 169.2l-.2-.1-.1 .3 .4 .2-.4 .1M214 163.7l.3 .5M214.2 167.8h.5v.6M214.2 167.8v.6M214.3 163.3l-.5 .5M214.5 165.1l-.3-.1-.1 .1 .1 .5h.3M214.6 171.2v-1l.2 .7 .3-.7v1M214.7 160.9h-.4l.4 .4h-.4"/>
<path d="M214.8 165h.3M214.9 164.7v.9h.2M215.1 160.9l.2-.1 .1 .2v.4M215.1 169.2l.2-.1 .2 .2-.1 .4h-.3M215.1 169.1v.9M215.3 163.6l.5 .1v.5M215.3 165.3l.5-.1-.2-.2-.3 .1v.5h.4M215.4 161.1l-.4 .1 .1 .2 .3-.1M215.4 167.8h-.3l-.1 .1 .2 .5 .2-.1M215.4 167.5v.9M215.5 170.6h.4M215.8 163.8l-.5 .1 .1 .3 .4-.1"/>
<path d="M215.9 160.9h.3v.5M215.9 168.9v.7l.1 .1M215.9 160.8v.6M215.9 170.2h-.4v1h.4M216.2 161l.2-.2 .1 .1v.5M216.2 163.7h.3v.5M216.2 163.6v.6M216.4 169.2l.1-.1 .2 .2v.4h-.3l-.1-.2 .4-.1M216.4 164.7v.9h-.2l-.1-.5h.3M216.4 167.5v.9M216.9 167.9l.5-.1v-.2l-.5-.1v.9M217 161.1h.4l-.2-.3-.2 .1v.4h.3"/>
<path d="M217 170.6h.4v.6M217 169.1h.3M217.1 168.9v.8h.2M217.1 167.9l.3 .5M217.3 163.6h-.3l-.1 .2 .1 .4 .3-.1M217.3 163.3v.9M217.4 170.7l-.4 .1v.4l.4-.1M217.5 165h.2M217.5 169.1h.3M217.5 164.7v.8l.2 .1M217.7 167.6h.5a.47 .47 0 0 1-.3 .8l-.2-.2zM217.7 170.6h.4v.6"/>
<path d="M217.7 170.6v.6M217.8 168.9h-.2v.8M217.9 168.1l.4 .3M218 165.1l.3-.1 .2 .1-.1 .5h-.3zM218.1 169.2h.4l-.1 .5-.3-.1zM218.4 160.9l.2-.1 .2 .2-.2 .4-.2-.1M218.4 160.8v.9M218.5 170.6l.1 .6M218.6 167.7l.3-.2v.9M218.6 168.4h.5M218.8 163.4l-.3-.1-.2 .1 .1 .3 .4 .2v.2h-.5M218.9 170.6l-.4 .8"/>
<path d="M218.9 169.1v.6M219.1 169.1l-.2 .2M219.1 170.6l.1 .6 .2-.5 .2 .5 .1-.6M219.2 160.6v.8M219.2 163.7h.3M219.3 165h.4M219.4 169.2h.3v.5M219.4 169.1v.6M219.5 164.7v.9h.2M219.6 160.9l.2-.1 .2 .2v.4M219.6 163.3h-.4v.9h.4M219.7 169.3l.3-.2 .2 .2v.4"/>
<path d="M220 161.1h-.4l.1 .3 .3-.1M220 163.8l.4-.1-.1-.4h-.3v.9M220 165.1h.3v.5M220 164.7v.9M220.1 170.6h.3v.6M220.2 167.8h.3v.6M220.2 163.8l.2 .4M220.4 170.7l-.3 .1 .1 .4 .2-.1M220.5 167.9l-.4 .2 .2 .3 .2-.1M220.6 169.7l-.1 .2M220.7 165.3l.4-.1-.1-.2-.3 .1v.4l.4 .1M220.8 160.9h-.5v.4h.5"/>
<path d="M220.8 170.6l.2 .6M220.8 163.3a.47 .47 0 0 1 .6 .4 .47 .47 0 0 1-.6 .5zM220.9 167.8v.6M221.1 161.1h.4l-.1-.3-.3 .1v.4h.3M221.2 167.8l-.3 .1M221.2 170.6l-.3 .7-.1 .1M221.4 168l.4-.1v-.1h-.4v.5h.4M221.5 171.1v.1M221.6 164.2l.3-.9 .2 .9M221.6 168.9v.8h.4v-.4l-.1-.2-.3 .1M221.7 164h.3M222.1 160.9l-.1-.1-.2 .2 .4 .2-.2 .2-.2-.1"/>
<path d="M222.1 164.7v.9M222.3 163.3h.5M222.4 169.1v.5h.4M222.5 161.3v.1M222.5 164.8l.5-.1v.4l-.5 .5h.5M222.5 163.3v.9M222.8 169.1v.6M222.9 167.8h.3v.5h-.3M222.9 167.5v.9M223 164.2l.2-.9 .4 .9M223.1 164h.4M223.1 169.1h.3"/>
<path d="M223.1 168.9v.7l.3 .1M223.6 167.8h.4l.1 .1-.2 .5-.3-.2zM223.9 164.8l-.4-.1-.2 .4 .2 .5 .4-.1M224.2 169.1l.2 .6 .2-.4 .1 .4 .2-.6M224.3 161l.4-.2v-.2h-.4v.8l.4-.1v-.2l-.1-.1M224.3 167.8h.3M224.4 167.5v.8l.2 .1M224.5 164.1l.2 .1 .2-.2-.1-.4h-.3v.9M224.9 167.8h.4v.6M224.9 167.5v.9M225.2 160.8v.5h.3M225.2 169.5l.4-.1-.1-.3-.3 .2v.3l.4 .1"/>
<path d="M225.3 163.3v.1M225.3 163.6v.6M225.3 164.7h-.4l-.1 .2 .2 .2 .3 .1v.3l-.5 .1M225.5 160.8v.6M225.7 163.7l.3-.1v.6M225.7 163.6v.6M225.8 160.8h.3M225.9 160.6v.7l.2 .1M226 168.9l-.1 .1M226.2 164.8l-.4-.1-.1 .2v.5l.1 .2 .4-.1M226.3 167.5v.2M226.4 168.9v.7l.1 .1"/>
<path d="M226.6 164.7v.9h.3M226.6 167.5v.2M226.8 163.6h-.4v.3l.4 .1-.1 .2-.3-.1M226.9 168.9v.8M227 160.9l.3-.1 .2 .2v.4M227 160.8v.6M227.3 167.8h-.4v.2l.4 .1-.1 .3-.3-.1M227.7 167.8h.3l.1 .1-.1 .5-.4-.2zM227.8 161l.3-.2 .1 .5-.2 .1zM227.8 163.7h.4v.4h-.4zM228 165.1l.2-.1 .1 .1v.5h-.3l-.1-.2 .4-.2M228 168.9v.8"/>
<path d="M228.3 169.5l.4-.1-.1-.3-.3 .2v.3l.4 .1M228.3 167.8h.3M228.6 163.7h.4v.5M228.6 163.6v.6M228.6 167.5h-.1v.9M228.7 165.1h.4v.5M228.7 165v.6M228.8 167.8h.3M229 167.5v.8l.1 .1M229.1 169.2h.4v.5h-.4v-.2l.1-.1h.3M229.1 160.8h.4M229.4 167.8l.2 .6 .1-.5 .1 .5 .2-.6"/>
<path d="M229.5 160.6h-.2v.8M229.7 160.9l.3-.1 .2 .2v.4M229.8 164.7v.9h-.2l-.1-.5h.3M229.8 169.1l.2 .6 .2-.6M229.9 163.6h.3M230 163.3v.7l.2 .2M230.2 161.1h-.5l.1 .3 .4-.1M230.3 167.8h.5v.6M230.5 163.7h.4v.5M230.5 169.5l.4-.1-.1-.3-.3 .2v.3l.3 .1M230.5 163.3v.9M230.6 160.9h.3v.5"/>
<path d="M230.6 160.8v.6M230.8 167.9l-.5 .1 .1 .4 .4-.1M231.1 167.8v.6M231.3 163.9l.4-.1-.1-.2h-.3v.5h.3M231.3 164.7h-.4v.4l.4 .1v.4h-.4M231.3 167.8l-.2 .1M231.6 168l.4-.1v-.1h-.4v.4l.2 .2 .2-.1M231.7 160.9l-.3-.1-.1 .2 .1 .4 .3-.1M231.8 164.7l.4 .1-.1 .8h-.3zM231.9 169.1h.3M231.9 168.9v.7l.3 .1M232 160.8l.2 .6"/>
<path d="M232.4 160.8l-.4 .9M232.4 165.6l.4-.9 .2 .9M232.4 169.2h.4v.5M232.4 168.9v.8M232.5 165.3h.5M233 163.6h-.3l-.1 .2 .2 .4 .2-.1M233 167.5v.1M233 167.8v.6M233.2 169.5l.3-.1v-.3l-.3 .1v.5h.3M233.5 163.6l.3 .1v.4l-.2 .1-.2-.2zM233.5 167.8h.3v.6M233.5 167.8v.6"/>
<path d="M233.6 160.9l-.1-.1-.1 .3 .3 .1-.2 .2-.1-.1M234 164.7v.8l.1 .1M234 169.2h.3v.5M234 160.8h.3M234 169.1v.6M234.1 160.6v.6l.2 .2M234.1 167.8h.4M234.2 163.7l.4-.1v.6M234.2 167.5v.7l.3 .2M234.2 163.6v.6M234.3 169.3l.3-.2 .1 .2v.4M234.5 164.7v.1"/>
<path d="M234.5 165v.6M234.6 160.8v.4l.1 .2 .2-.1M234.7 168l.4-.1v-.1h-.4v.5h.4M234.8 165.1l.3-.1 .1 .1v.5M234.8 165v.6M234.9 160.8v.6M235 163.7l.3-.1v.6M235 163.6v.6M235.2 160.8h.4M235.5 167.8v.6M235.6 160.6l-.3 .1v.7M235.6 165.3l.4-.1-.1-.2-.3 .1v.4l.4 .1"/>
<path d="M235.8 163.9l.4-.1-.1-.2h-.3v.5h.3M235.8 167.8l-.3 .1M235.8 160.8h.3M236 167.8v.6M236.1 160.6l-.3 .1v.7M236.2 169.2h-.4v.4l.4 .1M236.3 167.8l-.3 .1M236.3 161.3v.1M236.4 169.3l.2-.2 .3 .2v.4h-.4zM236.5 167.8v.4l.2 .2 .2-.1M236.7 165.1h-.4l.1 .2h.3v.3h-.4M236.9 163.6h-.4l-.1 .2 .2 .4 .3-.1"/>
<path d="M236.9 167.8v.6M237.1 165.5v.1M237.1 163.6h.3M237.3 163.3v.8l.1 .1M237.3 169.2h.3v.5M237.3 169.1v.6M237.4 168.3h.3l-.1-.5h-.2v.8M237.7 163.7h.4v.4h-.4zM238 167.8h.3M238 169.2l.3-.1 .2 .2v.4M238 169.1v.6M238.1 167.5v.8l.2 .1"/>
<path d="M238.5 163.6v.6M238.8 163.6l-.3 .2M238.8 169.5l.4-.1-.1-.3-.3 .1v.5h.3M238.9 167.8h-.4l.4 .5h-.4M239.2 167.5v.2M239.6 167.5v.2M239.7 163.6h.4v.6M240 169.2h-.4v.4l.4 .1M240.1 163.8l-.5 .2 .2 .2 .3-.1M240.2 169.1h.3M240.3 168.9v.8h.2M240.5 163.6v.6"/>
<path d="M240.7 163.6l-.2 .2M240.7 169.5l.5-.1-.1-.3-.4 .2v.3l.5 .1M241 163.9l.4-.1-.1-.2h-.3v.5h.3M241.9 168.9v.8h-.3l-.1-.5h.4"/>
</g>
<g fill="none" stroke="#00008a" stroke-width=".21">
<path d="M72.8 29.7l.7 .8M72.8 36.6l.7 .8M72.8 33.1l.7 .9M73.5 29.7l-.7 .8M73.5 36.6l-.7 .8M73.5 33.1l-.7 .9M127 36.6l.8 .8M127 33.1l.8 .9M127 29.7l.8 .8M127.8 36.6l-.8 .8M127.8 33.1l-.8 .9M127.8 29.7l-.8 .8"/>
<path d="M178.7 33.1l.8 .9M178.7 36.6l.8 .8M178.7 29.7l.8 .8M179.5 33.1l-.8 .9M179.5 36.6l-.8 .8M179.5 29.7l-.8 .8M72.8 40l.7 .8M72.8 43.5l.7 .8M72.8 45.2l.7 .8M72.8 50.3l.7 .9M72.8 48.6l.7 .9M72.8 46.9l.7 .9"/>
<path d="M73.5 40l-.7 .8M73.5 43.5l-.7 .8M73.5 45.2l-.7 .8M73.5 50.3l-.7 .9M73.5 48.6l-.7 .9M73.5 46.9l-.7 .9M127 50.3l.8 .9M127 46.9l.8 .9M127 48.6l.8 .9M127 40l.8 .8M127 43.5l.8 .8M127 45.2l.8 .8"/>
<path d="M127.8 50.3l-.8 .9M127.8 46.9l-.8 .9M127.8 48.6l-.8 .9M127.8 40l-.8 .8M127.8 43.5l-.8 .8M127.8 45.2l-.8 .8M178.7 45.2l.8 .8M178.7 43.5l.8 .8M178.7 50.3l.8 .9M178.7 46.9l.8 .9M178.7 48.6l.8 .9M178.7 40l.8 .8"/>
<path d="M179.5 45.2l-.8 .8M179.5 43.5l-.8 .8M179.5 50.3l-.8 .9M179.5 46.9l-.8 .9M179.5 48.6l-.8 .9M179.5 40l-.8 .8M50.3 62.4l.9 .9M51.2 62.4l-.9 .9M72.8 76.2l.7 .8M72.8 74.5l.7 .8M73.5 76.2l-.7 .8M73.5 74.5l-.7 .8"/>
<path d="M73.6 65.9l.8 .8M74.4 65.9l-.8 .8M104.6 62.4l.8 .9M105.4 62.4l-.8 .9M127 74.5l.8 .8M127 65.9l.8 .8M127 76.2l.8 .8M127.8 74.5l-.8 .8M127.8 65.9l-.8 .8M127.8 76.2l-.8 .8M156.2 62.4l.9 .9M157.1 62.4l-.9 .9"/>
<path d="M178.7 74.5l.8 .8M178.7 76.2l.8 .8M178.7 65.9l.8 .8M179.5 74.5l-.8 .8M179.5 76.2l-.8 .8M179.5 65.9l-.8 .8M29.7 108.9l.8 .9M29.7 107.2l.8 .9M29.7 110.7l.8 .8M30.5 108.9l-.8 .9M30.5 107.2l-.8 .9M30.5 110.7l-.8 .8"/>
<path d="M46.9 105.5l.8 .8M46.9 107.2l.8 .9M46.9 108.9l.8 .9M47.7 105.5l-.8 .8M47.7 107.2l-.8 .9M47.7 108.9l-.8 .9M29.7 124.4l.8 .9M30.5 124.4l-.8 .9M152.9 145.1l.7 .8M152.9 148.5l.7 .9M153.6 145.1l-.7 .8M153.6 148.5l-.7 .9"/>
</g>
<g fill="#090">
<circle cx="142.9" cy="161" r=".38"/>
<circle cx="142.9" cy="163.6" r=".38"/>
<circle cx="176.5" cy="163.6" r=".38"/>
<circle cx="176.5" cy="124.8" r=".38"/>
<circle cx="203.2" cy="101.6" r=".38"/>
<circle cx="113.7" cy="161" r=".38"/>
<circle cx="86.1" cy="124.8" r=".38"/>
<circle cx="113.7" cy="163.6" r=".38"/>
<circle cx="142.9" cy="124.8" r=".38"/>
<circle cx="113.7" cy="124.8" r=".38"/>
<circle cx="142.9" cy="122.3" r=".38"/>
<circle cx="113.7" cy="122.3" r=".38"/>
<circle cx="86.1" cy="122.3" r=".38"/>
<circle cx="37" cy="188.6" r=".38"/>
<circle cx="19.8" cy="188.6" r=".38"/>
<circle cx="44.7" cy="188.6" r=".38"/>
<circle cx="53.3" cy="192.1" r=".38"/>
<circle cx="53.3" cy="188.6" r=".38"/>
<circle cx="28.3" cy="192.1" r=".38"/>
<circle cx="28.3" cy="188.6" r=".38"/>
<circle cx="44.7" cy="192.1" r=".38"/>
<circle cx="37" cy="192.1" r=".38"/>
<circle cx="61.9" cy="188.6" r=".38"/>
<circle cx="61.9" cy="192.1" r=".38"/>
<circle cx="19.8" cy="192.1" r=".38"/>
<circle cx="210.9" cy="62.9" r=".38"/>
<circle cx="226.4" cy="68" r=".38"/>
<circle cx="226.4" cy="73.2" r=".38"/>
<circle cx="233.4" cy="68" r=".38"/>
<circle cx="254" cy="69.7" r=".38"/>
<circle cx="254" cy="89.5" r=".38"/>
<circle cx="218.7" cy="62.9" r=".38"/>
<circle cx="226.4" cy="62.9" r=".38"/>
<circle cx="203.2" cy="88.7" r=".38"/>
<circle cx="218.7" cy="73.2" r=".38"/>
<circle cx="210.9" cy="73.2" r=".38"/>
</g>
<path d="M255.1 65.4h.5v-.4h-.5v.8M255.9 65.4l.3-.2 .2 .5-.3 .1zM256.7 65.2l.1 .6 .2-.4 .2 .4 .1-.6M257.6 65.6l.4-.1-.1-.3-.3 .2v.3l.2 .1 .2-.1M258.4 65.2v.6M258.6 65.2l-.2 .2M255.1 85.2h.5v-.4h-.5v.8M255.9 85.2l.3-.2 .2 .5-.3 .1zM256.7 85l.1 .6 .2-.4 .2 .4 .1-.6M257.6 85.3h.4l-.1-.3-.3 .2v.3l.2 .1h.2M258.4 85v.6M258.6 85l-.2 .2" fill="none" stroke="#910089" stroke-width=".21"/>
<g fill="none" stroke="#006665" stroke-width=".21">
<path d="M216.7 18.2h.7M217 17.8v.6M218.2 17.6h-.4l-.1 .4h.5v.3h-.5M218.5 17.6l.3 .8 .3-.8M252.9 18.2h.6M253.2 17.8v.6M254.4 17.6h-.4v.4l.3-.1 .2 .2-.1 .3-.4-.1M254.6 17.6l.4 .8 .2-.8M58.5 23.6v.9l-.5-.9v.9M59 23.7l.1-.1 .4 .1v.6l-.2 .2a.47 .47 0 0 1-.4-.3 .47 .47 0 0 1 .1-.5zM59.1 24.3l.5 .3M59.7 23.6l.3 .9 .3-.9"/>
<path d="M60.6 24.5v-.9l.3 .7 .3-.7v.9M61.3 21.9v.6l-.4 .2M61.6 21.9h.5l-.3 .8M61.6 24h.2M62 23.6h-.4v.9h.4M62.4 22.1l.2-.2a.43 .43 0 0 1 .4 .4 .43 .43 0 0 1-.5 .4zM63.2 22.1l.3-.2v.8M63.2 22.7h.5M63.5 23.7l-.4-.1-.2 .1 .1 .3 .5 .2v.2h-.6M63.8 23.6v.7l.2 .2M64.3 23.9h.3l.1 .2-.1 .4-.4-.2zM65 23.9h.2"/>
<path d="M65.1 23.6v.8l.1 .1M66.2 23.8l.2-.2v.9M66.2 24.5h.5M67 39.2h-.3l-.2 .1v.4l.3 .3 .2-.1v-.3h-.2M67.9 39.2v.8l-.5-.8v.8M68.3 39.2h.3a.48 .48 0 0 1 .2 .5 .48 .48 0 0 1-.5 .3zM112.8 23.6v.9l-.5-.9v.9M113.2 23.7l.2-.1a.48 .48 0 0 1 .4 .4 .48 .48 0 0 1-.4 .5 .52 .52 0 0 1-.2-.8zM113.3 24.3l.4 .3M114 23.6l.3 .9 .3-.9M114.8 24.5v-.9l.3 .7 .3-.7v.9M115.5 21.9v.6l-.3 .2"/>
<path d="M115.8 21.9h.6l-.4 .8M115.9 24h.2M116.3 23.6h-.4v.9h.4M116.9 21.9l.2 .2-.1 .6h-.2l-.1-.1v-.5zM117.5 22h.5v.2l-.5 .5h.5M117.7 23.7l-.3-.1-.2 .1 .1 .3 .4 .3-.1 .2-.4-.1M118.1 23.6v.7l.1 .2M118.6 23.9h.3l-.1 .6-.3-.2zM119.2 23.9h.3M119.3 23.6v.8l.2 .1M120.4 23.7l.4-.1 .1 .2-.5 .7h.5M121.3 39.2h-.4l-.1 .1v.4l.2 .3 .3-.1v-.3h-.2"/>
<path d="M122.1 39.2v.8l-.5-.8v.8M122.6 39.2h.3a.48 .48 0 0 1 .1 .5 .48 .48 0 0 1-.4 .3zM164.5 23.6v.9l-.5-.9v.9M164.9 23.7l.2-.1 .3 .1v.6l-.2 .2-.3-.2zM165 24.3l.5 .3M165.6 23.6l.4 .9 .2-.9M166.5 24.5v-.9l.3 .7 .3-.7v.9M167.2 21.9v.6l-.4 .2M167.5 21.9h.6l-.4 .8M167.5 24h.3M167.9 23.6h-.4v.9h.4M168.5 21.9a.43 .43 0 0 1 .4 .4 .43 .43 0 0 1-.5 .4v-.6z"/>
<path d="M169.1 21.9h.5l-.2 .3 .2 .1v.3h-.5M169.4 23.7h-.5v.3l.5 .2v.2h-.5M169.8 23.6l.1 .9M170.2 23.9h.4v.2l-.1 .4-.3-.1zM170.9 23.9h.3M171 23.6v.7l.2 .2M172.1 23.6h.5l-.3 .3 .3 .1v.4h-.5M172.9 39.2h-.3a.43 .43 0 0 0-.2 .5 .43 .43 0 0 0 .5 .2v-.3h-.1M173.9 39.2v.8l-.5-.8v.8M174.2 39.2h.3l.2 .1v.4l-.2 .3h-.3zM219.5 22.7h.6l-.4 .9M219.6 21l.1 .9h.3l.1-.9"/>
<path d="M220.4 21h.5l-.3 .9M220.6 22.7l-.3 .6h.5M220.8 23.1v.5M221.1 23.6l.3-.9 .3 .9M221.2 23.4h.4M221.4 21a.42 .42 0 0 1 .4 .5 .42 .42 0 0 1-.4 .4zM222 21.3l.3-.3v.9M222 21.9h.5M222.5 22.8l-.3-.1-.2 .2v.6h.5M222.7 22.7h.5M223 22.7v.9M223.4 22.8h.5v.4l-.5 .4h.5"/>
<path d="M224.5 22.7l-.3 .6h.5M224.7 23.1v.5M225.5 22.7h-.4v.5l.3-.1 .2 .4h-.5M255.6 22.7h.6l-.3 .9M255.7 21l.1 .9h.4v-.9M256.6 21h.6l-.5 .9M256.7 22.7l-.2 .6h.6M256.9 23.1v.5M257.3 23.6l.2-.9 .3 .9M257.3 23.4h.5M257.5 21a.42 .42 0 0 1 .4 .5 .42 .42 0 0 1-.4 .4zM258.3 21.1l.4-.1 .1 .3-.6 .6h.6"/>
<path d="M258.6 22.8l-.2-.1-.3 .3v.4l.2 .2 .3-.1M258.9 22.7h.5M259.1 22.7v.9M259.6 22.8l.4-.1 .1 .3-.6 .6h.6M260.6 22.7l-.2 .6h.6M260.8 23.1v.5M261.7 22.7h-.4l-.1 .5 .4-.1 .1 .4h-.5M40.9 40h-.3a.44 .44 0 0 0-.1 .6 .44 .44 0 0 0 .5 .2v-.3h-.2M40.9 43.5a.41 .41 0 0 0-.5 .4 .41 .41 0 0 0 .6 .3v-.3h-.2M40.9 50.3h-.3a.44 .44 0 0 0-.2 .6 .44 .44 0 0 0 .6 .2v-.3h-.2M40.9 57.3a.43 .43 0 0 0-.4 .2 .43 .43 0 0 0 .1 .5h.4v-.3h-.2M40.9 53.8a.41 .41 0 0 0-.5 .4 .41 .41 0 0 0 .6 .4v-.4h-.2"/>
<path d="M41.9 40v.8l-.5-.8v.8M41.9 43.4v.9l-.5-.9v.9M41.9 50.3v.9l-.5-.9v.9M41.9 57.2v.8l-.5-.8v.8M41.9 53.7v.9l-.5-.9v.9M42.3 40h.3a.47 .47 0 0 1 .2 .6 .47 .47 0 0 1-.5 .2zM42.3 43.4a.47 .47 0 0 1 .5 .5 .47 .47 0 0 1-.5 .4zM42.3 50.3h.3a.47 .47 0 0 1 .2 .6 .47 .47 0 0 1-.5 .3zM42.3 57.2a.49 .49 0 0 1 .4 .3 .49 .49 0 0 1-.1 .5h-.3zM42.3 53.7a.47 .47 0 0 1 .5 .5 .47 .47 0 0 1-.5 .4zM81.7 59h-.4l-.2 .1v.5l.3 .2 .3-.1v-.3h-.2M82.5 59v.8l-.5-.8v.8"/>
<path d="M82.9 59h.4a.48 .48 0 0 1 .1 .5 .48 .48 0 0 1-.5 .3zM95.2 43.5a.41 .41 0 0 0-.5 .4 .41 .41 0 0 0 .6 .3v-.3h-.2M95.2 40h-.3a.44 .44 0 0 0-.1 .6 .44 .44 0 0 0 .5 .2v-.3h-.2M95.2 50.3h-.3a.44 .44 0 0 0-.2 .6 .44 .44 0 0 0 .6 .2v-.3h-.2M95.2 57.3a.43 .43 0 0 0-.5 .2 .43 .43 0 0 0 .2 .5h.4v-.3h-.2M95.2 53.8a.41 .41 0 0 0-.5 .4 .41 .41 0 0 0 .6 .4v-.4h-.2M96.1 43.4v.9l-.5-.9v.9M96.1 40v.8l-.5-.8v.8M96.1 50.3v.9l-.5-.9v.9M96.1 57.2v.8l-.5-.8v.8M96.1 53.7v.9l-.5-.9v.9M96.6 43.4l.4 .2v.5l-.3 .2h-.1z"/>
<path d="M96.6 40l.4 .2v.4l-.3 .2h-.1zM96.6 50.3l.4 .2v.5l-.3 .2h-.1zM96.6 57.2l.4 .2v.5l-.2 .1h-.2zM96.6 53.7l.4 .3v.4l-.3 .2h-.1zM135.8 59l-.4 .1v.5l.3 .2 .2-.1v-.3h-.1M136.8 59v.8l-.5-.8v.8M137.2 59h.3a.48 .48 0 0 1 .2 .5 .48 .48 0 0 1-.5 .3zM146.9 57.3l-.2-.1-.3 .2v.5l.2 .1h.3v-.3h-.1M146.9 50.3l-.5 .2 .1 .6h.4v-.3h-.1M146.9 53.8l-.2-.1-.3 .3v.4l.3 .2h.2v-.4h-.1M146.9 43.5l-.2-.1-.3 .2v.5l.3 .2 .2-.1v-.3h-.1M146.9 40l-.5 .2v.4l.3 .2h.2v-.3h-.1"/>
<path d="M147.8 57.2v.8l-.5-.8v.8M147.8 50.3v.9l-.5-.9v.9M147.8 53.7v.9l-.5-.9v.9M147.8 43.4v.9l-.5-.9v.9M147.8 40v.8l-.5-.8v.8M148.2 57.2a.49 .49 0 0 1 .5 .3 .49 .49 0 0 1-.2 .5h-.3zM148.2 50.3h.3a.47 .47 0 0 1 .2 .6 .47 .47 0 0 1-.5 .3zM148.2 53.7a.47 .47 0 0 1 .5 .5 .47 .47 0 0 1-.5 .4zM148.2 43.4a.47 .47 0 0 1 .5 .5 .47 .47 0 0 1-.5 .4zM148.2 40h.3a.47 .47 0 0 1 .2 .6 .47 .47 0 0 1-.5 .2zM187.6 59h-.4a.43 .43 0 0 0-.1 .5 .43 .43 0 0 0 .5 .2v-.3h-.2M188.5 59v.8l-.5-.8v.8"/>
<path d="M188.8 59h.4l.2 .1v.5l-.3 .2h-.3zM217.2 52.1l-.2-.1-.3 .3v.4l.2 .2h.3v-.4h-.2M218.1 52v.9l-.5-.9v.9M218.5 52h.2l.3 .3v.4l-.2 .2h-.3zM225.3 59.5h.7M225.7 59.1v.7M226.9 59h-.5v.3h.5v.4h-.5M227.1 59l.3 .8 .3-.8M253.4 52.1a.43 .43 0 0 0-.5 .3 .43 .43 0 0 0 .1 .5h.4v-.4h-.2M254.3 52v.9l-.5-.9v.9M254.6 52h.3l.2 .3v.4l-.1 .2h-.4zM39.7 78.4h.6"/>
<path d="M40.7 78.1l.2-.3v.9M40.7 78.7h.5M40.8 79.8v.7M41.5 77.9l.4-.1 .1 .2-.5 .7h.5M41.9 79.6h-.4v.4h.4l.1 .3-.1 .2-.4-.1M42.3 77.8l.2 .9 .4-.9M42.3 79.6l.2 .9 .4-.9M67.4 78.4h.6M67.7 78.1v.6M67.7 79.8v.7M68.4 78.1l.3-.3v.9M68.4 78.7h.5"/>
<path d="M68.9 79.6h-.5v.4h.5v.4h-.5M69.1 79.6l.4 .9 .2-.9M69.2 77.9h.5v.4l-.5 .4h.5M70 77.8l.2 .9 .4-.9M80.6 79.8v.7M81.7 64.1h-.4l-.2 .2v.4l.3 .3 .3-.1v-.3h-.2M81.8 79.6h-.4l-.1 .4h.4l.1 .4h-.5M82.1 79.6l.2 .9 .4-.9M82.5 64.1v.9l-.5-.9v.9M82.9 64.1h.4a.48 .48 0 0 1 .1 .6 .48 .48 0 0 1-.5 .3zM93.9 78.4h.7M95 78.1l.2-.3v.9"/>
<path d="M95 78.7h.5M95.1 79.8v.7M95.8 77.9l.3-.1 .2 .3-.6 .6h.6M96.2 79.6h-.4v.4h.4l.1 .3-.2 .2-.3-.1M96.6 79.6l.2 .9 .3-.9M96.6 77.8l.2 .9 .3-.9M121.6 78.4h.7M122 78.1v.6M122 79.8v.7M122.7 78.1l.2-.3v.9M122.7 78.7h.4M123.1 79.6h-.4v.4h.4v.4h-.4"/>
<path d="M123.4 79.6l.3 .9 .3-.9M123.5 77.9h.5v.4l-.5 .4h.5M124.2 77.8l.3 .9 .3-.9M134.9 79.8v.7M135.8 64.1l-.4 .2v.4l.3 .3 .2-.1v-.3h-.1M136 79.6h-.3l-.1 .4h.4l.1 .3-.2 .2-.3-.1M136.4 79.6l.2 .9 .3-.9M136.8 64.1v.9l-.5-.9v.9M137.2 64.1h.3a.48 .48 0 0 1 .2 .6 .48 .48 0 0 1-.5 .3zM145.6 78.4h.7M146.7 78.1l.2-.3v.9M146.7 78.7h.4"/>
<path d="M146.8 79.8v.7M147.4 77.9h.6v.4l-.6 .4h.6M148 79.6h-.5l-.1 .4h.5l.1 .4h-.6M148.2 77.8l.3 .9 .3-.9M148.2 79.6l.3 .9 .3-.9M173.4 78.4h.6M173.7 78.1v.6M173.7 79.8v.7M174.4 78.1l.2-.3v.9M174.4 78.7h.5M174.8 79.6h-.4v.4h.4l.1 .3-.2 .2-.3-.1M175.1 79.6l.3 .9 .2-.9"/>
<path d="M175.2 77.9h.4v.4l-.5 .4h.5M175.9 77.8l.3 .9 .3-.9M186.6 79.8v.7M187.6 64.1h-.4a.43 .43 0 0 0-.1 .6 .43 .43 0 0 0 .5 .2v-.3h-.2M187.7 79.6h-.4l-.1 .4h.5v.4h-.5M188 79.6l.3 .9 .3-.9M188.5 64.1v.9l-.5-.9v.9M188.8 64.1h.4l.2 .2v.4l-.3 .3h-.3zM205.2 68.6l.2-.2v.9M205.2 69.3h.4M205.7 66.8l-.3-.1-.2 .2v.4l.2 .2 .3-.1M205.9 66.7h.6l-.3 .8"/>
<path d="M206 68.4h.3l.2 .1v.6l-.2 .2a.53 .53 0 0 1-.3-.9zM206.9 68.4h.1a.48 .48 0 0 1 .3 .4 .48 .48 0 0 1-.3 .5l-.2-.3zM206.9 66.8l.2-.1 .2 .1-.1 .7-.3-.1zM207.6 68.8h.5v.5M207.6 68.7v.6M208.1 67v.2h-.4l-.1-.4 .2-.1 .3 .1v.5l-.4 .2M208.4 68.8h.3M208.8 68.4h-.4v.9M212.9 68.3l.2-.3v.9M212.9 68.9h.5M213.5 66.4l-.4-.1a.44 .44 0 0 0-.1 .6 .44 .44 0 0 0 .5 .2M213.7 66.3h.6l-.4 .9"/>
<path d="M213.9 68a.43 .43 0 0 1 .4 .5 .43 .43 0 0 1-.5 .4l-.1-.7zM214.7 66.4l.1-.1a.38 .38 0 0 1 .3 .5 .38 .38 0 0 1-.4 .3zM214.8 68l.2 .2-.1 .7h-.2l-.1-.2v-.5zM215.4 68.3v.9M215.6 66.7l-.2-.3 .5-.1v.4l-.5 .1v.3l.2 .1 .3-.2-.1-.3M215.9 68.8v.1M215.9 68.3v.5h-.5M216.3 68.4h.3M216.7 68h-.4v.9M219.8 68.4v.9h.5M219.8 66.7l.1 .8h.4v-.2v-.6M220.5 68.4h.3l.2 .2-.6 .7h.6"/>
<path d="M220.7 66.7h.6l-.5 .8M221.3 68.4h.6l-.5 .9M221.7 66.7a.43 .43 0 0 1 .3 .4 .43 .43 0 0 1-.4 .4l-.1-.7zM222.1 68.4h.5v.4l-.5 .5h.5M222.5 67l-.1-.2 .3-.1 .1 .2-.4 .2 .1 .4 .3-.1-.1-.4M223 68.4h.2l.3 .2v.4l-.3 .3h-.2zM223.7 66.8a.44 .44 0 0 0-.5 .1 .44 .44 0 0 0 .1 .6l.4-.1M225.8 76.2l-.5 .1v.5l.2 .2 .3-.1v-.2h-.1M226.7 76.2v.8l-.5-.8v.8M227.1 76.2h.4l.1 .5-.1 .3h-.4zM228.4 65.8h.5l-.3 .4h.3v.4h-.5M228.4 69.7h.3l.1-.2-.4-.1v.7"/>
<path d="M228.4 64.6h.3l.1-.3-.4-.1v.7M228.6 69.7l.2 .4M228.6 64.6l.2 .3M228.6 70.9l-.2 .7h.6M228.8 71.2v.6M229.1 69.4h.4l-.4 .7M229.1 64.2h.4l-.4 .7M229.3 65.8v.9M229.3 71v.8M229.4 71.3l.3 .5M229.4 66.2l.3 .5M229.7 69.4h.4v.6l-.2 .1-.2-.1z"/>
<path d="M229.7 64.2h.4v.6l-.2 .1-.2-.1zM229.7 71l-.4 .5M229.7 65.8l-.4 .5M230.1 71h.5l-.4 .8M230.1 65.8h.5l-.3 .4h.3v.4h-.5M230.5 69.6h-.2l.1-.2h.4v.2l-.5 .2 .2 .3 .3-.1-.1-.4M230.8 64.5l-.3 .1-.2-.3 .5-.1v.5l-.4 .2M245.3 64.1v.9h.4M245.3 62.4v.8l.4-.1v-.7M246 64.2l.4-.1 .1 .2-.6 .7h.6M246.1 62.4h.6l-.4 .8M246.8 64.1h.6l-.5 .9"/>
<path d="M247 62.4h.3l.1 .1v.7h-.3l-.2-.3zM247.6 64.2l.4-.1 .1 .2-.5 .7h.5M247.9 62.8l-.1-.3 .3-.1 .2 .2-.4 .2v.4h.3l.1-.3-.2-.1M248.5 64.1h.3l.2 .2v.4l-.3 .3h-.2zM248.5 63.2l.3-.8 .3 .8M248.6 62.9h.4M37.5 99.1h.7M37.9 98.8v.6M39.1 98.5h-.5v.4h.5v.5h-.5M39.3 98.5l.4 .9 .2-.9M40.5 80.1h.7M63.6 99.4h.6l-.4 .9"/>
<path d="M63.6 89.1h.6l-.4 .9M64.4 97.7v.8h.4v-.8M64.4 87.3l.1 .9 .4-.1v-.8M64.6 99.4l-.1 .5h.5M64.6 89l-.1 .6h.5M64.9 89.4v.6M64.9 99.7v.6M65.1 97.7h.6l-.3 .8M65.2 90l.3-.9 .2 .9M65.2 87.3h.6l-.4 .9M65.3 89.7h.4M66.1 97.7h.2l.2 .1-.1 .7h-.3z"/>
<path d="M66.2 87.4l.1-.1a.45 .45 0 0 1 .3 .5 .45 .45 0 0 1-.4 .4l-.1-.3zM66.6 99.5l-.4-.1a.44 .44 0 0 0-.1 .6 .44 .44 0 0 0 .5 .2M66.6 89.2l-.4-.1a.44 .44 0 0 0-.1 .6 .44 .44 0 0 0 .5 .2M66.8 89.1h.5M66.8 99.4h.5M67 97.7l-.2 .6h.5M67 89.1v.9M67 99.4v.9M67.1 87.3l-.2 .6h.5M67.3 98v.5M67.3 87.7v.5M67.4 80.1h.6"/>
<path d="M67.5 99.4h.5l-.2 .4h.2v.4h-.5M67.5 89.1h.5l-.2 .3h.2v.5h-.5M67.6 88.2l.3-.9 .3 .9M67.7 98.1h.4l.1-.3-.2-.1h-.3v.8h.5v-.3l-.2-.1M67.7 87.9h.4M68.4 99.5l.4-.1 .1 .3-.6 .6h.6M68.4 89.2l.4-.1 .1 .2-.6 .7h.6M80.3 80.1h.7M94.8 80.1h.7M108.2 84.5h.6M108.5 84.1v.7M109.7 83.9h-.4v.4l.3-.1 .2 .4-.2 .2-.3-.1"/>
<path d="M109.9 83.9l.4 .9 .2-.9M111 89.1h.5l-.3 .9M111 87.3l.1 .9h.4v-.9M111.9 87.3h.6l-.4 .9M112.1 89l-.3 .6h.6M112.2 89.4v.6M112.6 90l.2-.9 .4 .9M112.6 89.7h.5M112.9 87.3a.43 .43 0 0 1 .3 .5 .43 .43 0 0 1-.4 .4l-.1-.7zM113.9 89.2l-.3-.1-.2 .2v.4l.3 .3 .2-.1M114 87.3h-.4v.5l.3-.1 .2 .1-.1 .4-.4-.1M114.2 89.1h.5"/>
<path d="M114.4 89.1v.9M114.9 89.2l.5-.1v.3l-.6 .6h.6M115.9 89l-.2 .6h.6M116.1 89.4v.6M117 89.1h-.4l-.1 .3h.4l.1 .4-.1 .2-.4-.1M121.6 80.1h.7M134.6 80.1h.7M140.1 84.5h.7M140.4 84.1v.7M141.5 83.9h-.3l-.1 .4 .3-.1 .2 .4-.2 .2-.3-.1M141.9 83.9l.2 .9 .3-.9M142.9 89.1h.5l-.4 .9"/>
<path d="M143 87.3v.9l.4-.1v-.8M143.7 87.3h.6l-.3 .9M143.9 89l-.2 .6h.5M144.1 89.4v.6M144.4 90l.3-.9 .3 .9M144.5 89.7h.4M144.6 87.4l.3-.1 .2 .2-.1 .7h-.3l-.1-.3zM145.8 89.2l-.4-.1a.43 .43 0 0 0-.1 .5 .43 .43 0 0 0 .5 .3M145.8 87.3l-.2 .1-.2 .4 .1 .4h.3l.1-.4-.1-.1-.4 .1M146 89.1h.5M146.3 89.1v.9M146.4 80.1h.7"/>
<path d="M146.8 89.2l.4-.1 .1 .2-.5 .7h.5M147.8 89l-.2 .6h.5M148 89.4v.6M148.9 89.1h-.4l-.1 .3h.5v.5h-.5M172.8 84.5h.6M173.1 84.1v.7M173.4 80.1h.6M174.3 83.9h-.4v.4h.4v.4h-.4M174.5 83.9l.4 .9 .2-.9M175.6 89.1h.5l-.3 .9M175.6 87.3l.1 .9h.4v-.2v-.7M176.5 87.3h.6l-.4 .9"/>
<path d="M176.7 89l-.3 .6h.6M176.8 89.4v.6M177.2 90l.2-.9 .4 .9M177.2 89.7h.5M177.5 87.3a.43 .43 0 0 1 .3 .5 .43 .43 0 0 1-.4 .4l-.1-.7zM178.1 87.3h.6l-.4 .9M178.5 89.2l-.3-.1-.2 .2v.4l.3 .3 .2-.1M178.8 89.1h.5M179 89.1v.9M179.5 89.2l.4-.1 .1 .3-.6 .6h.6M180.5 89l-.2 .6h.6M180.7 89.4v.6"/>
<path d="M181.6 89.1h-.5v.3h.4l.1 .4-.1 .2-.4-.1M186.2 80.1h.7M205.2 97.1l.2-.3v.9M205.2 84.1l.2-.2v.9M205.2 97.7h.4M205.2 84.8h.4M205.7 95.2l-.3-.1-.2 .2v.5l.2 .2 .3-.1M205.7 82.3l-.3-.1-.2 .2v.4l.2 .2 .3-.1M205.9 95.1h.6l-.3 .9M205.9 82.2h.6l-.3 .8M206 96.9l.3-.1 .2 .2-.1 .6a.39 .39 0 0 1-.5-.2 .39 .39 0 0 1 .1-.5zM206 84l.4-.1 .1 .2v.5l-.2 .2a.48 .48 0 0 1-.3-.8z"/>
<path d="M206.9 83.9a.42 .42 0 0 1 .4 .3 .42 .42 0 0 1-.2 .5h-.2zM206.9 95.4l.1-.3v.9M206.9 82.4l.1-.2v.8M206.9 96h.4M206.9 83h.4M207 96.8a.43 .43 0 0 1 .3 .5 .43 .43 0 0 1-.4 .4l-.1-.5zM207.6 97.2h.5v.5M207.6 84.3h.5v.5M207.6 95.2h.5v.3l-.5 .5h.5M207.6 84.2v.6M207.6 97.2v.5M207.7 82.3l.3-.1 .1 .1v.7h-.3l-.2-.2z"/>
<path d="M208.4 97.2h.3M208.4 84.3h.3M208.8 96.8h-.4v.9M208.8 83.9h-.4v.9M212.9 96.7l.2-.2v.8M212.9 83.8l.2-.3v.9M212.9 97.3h.5M212.9 84.4h.5M213.5 94.8a.42 .42 0 0 0-.6 .4 .42 .42 0 0 0 .6 .3M213.5 81.9l-.4-.1-.2 .4 .2 .5 .4-.1M213.7 94.7h.6l-.4 .9M213.7 81.8h.6l-.4 .9"/>
<path d="M213.8 96.5a.43 .43 0 0 1 .5 .4 .43 .43 0 0 1-.4 .4l-.2-.1zM213.9 83.5a.43 .43 0 0 1 .4 .5 .43 .43 0 0 1-.5 .4l-.1-.7zM214.6 95l.2-.3v.9M214.6 82.1l.2-.3v.9M214.6 95.6h.5M214.6 82.7h.5M214.7 96.5h.2l.1 .1v.6l-.2 .1-.2-.1zM214.8 83.5l.2 .2-.1 .7h-.2l-.1-.2v-.5zM215.3 94.7h.6l-.3 .3 .3 .2v.3l-.1 .1-.5-.1M215.4 82.1l.3-.3v.9M215.4 83.9v.8M215.4 96.7v.9"/>
<path d="M215.4 82.7h.5M215.9 97.2v.1M215.9 96.7v.5l-.2 .1-.3-.1M215.9 84.3v.1M215.9 83.9v.4h-.5M216.3 96.9h.3M216.3 83.9h.3M216.7 96.5h-.4v.8M216.7 83.5h-.4v.9M245.2 82.2l.1 .8h.4v-.2v-.6M245.3 83.9v.9h.4M246 84l.4-.1 .1 .2-.6 .7h.6"/>
<path d="M246 82.2h.6l-.4 .8M246.8 83.9h.6l-.5 .9M247.1 82.2l.3 .1-.1 .7h-.3l-.1-.2v-.5zM247.6 84h.5l-.5 .8h.5M247.9 82.6l-.2-.3 .2-.1 .3 .1v.2l-.5 .2 .1 .3h.3l.1-.3-.2-.1M248.5 83.9h.3l.2 .2v.4l-.3 .3h-.2zM248.6 82.6h.4v-.3l-.1-.1h-.3v.8h.4v-.3l-.1-.1M40.4 100.3l.1 .8h.3l.1-.8M40.8 102.1a.43 .43 0 0 0-.4 .2 .43 .43 0 0 0 .1 .5l.4-.1v-.2h-.1M41.2 102.8l.2-.8 .3 .8M41.3 100.3h.5l-.4 .8M41.3 102.6h.4"/>
<path d="M42 102v.8h.5M42.2 100.3a.42 .42 0 0 1 .4 .4 .42 .42 0 0 1-.4 .4zM42.7 102.1h.4v.3l-.5 .4h.5M42.9 100.3h.5l-.3 .3 .3 .1v.3h-.5M43.5 102.1h.5v.3l-.5 .4h.5M44.2 102l.3 .8 .3-.8M45.1 102.2l.2-.2v.8M45.1 102.8h.5M45.9 102.1l.3-.1 .2 .1-.1 .6a.39 .39 0 0 1-.5-.2 .39 .39 0 0 1 .1-.4zM63.6 109.8h.6l-.4 .8M64.4 118.3l.1 .9h.3v-.9M64.4 108l.1 .9 .3-.1v-.8"/>
<path d="M64.6 109.7l-.1 .7h.5M64.9 110v.6M65.1 118.3h.6l-.3 .9M65.1 108h.6l-.3 .9M65.2 100.3l.3-.9 .2 .9M65.2 110.6l.3-.8 .2 .8M65.3 100h.4M65.3 110.4h.4M66.1 118.4l.2-.1 .2 .2v.6l-.2 .1a.53 .53 0 0 1-.2-.8zM66.1 108.1l.2-.1 .2 .2v.6l-.2 .1a.53 .53 0 0 1-.2-.8zM66.6 109.9l-.4-.1a.44 .44 0 0 0-.1 .5 .44 .44 0 0 0 .5 .2M66.8 109.8h.5"/>
<path d="M67 118.3l-.2 .6h.5M67 108l-.2 .6h.5M67 109.8v.8M67.3 108.3v.6M67.3 118.7v.5M67.5 109.8h.5l-.2 .3 .2 .1v.3h-.5M67.7 118.3h.2l.3 .3v.4l-.3 .2h-.2zM68.2 108.1l-.3-.1-.2 .2v.5l.2 .2 .3-.1M68.4 109.9l.4-.1 .1 .2-.6 .6h.6M92.7 105.1h.6M93 104.8v.6M94.2 104.6h-.4v.4h.4v.4h-.4"/>
<path d="M94.4 104.6l.4 .8 .2-.8M108.7 118.4l-.1-.1a.43 .43 0 0 0-.4 .5 .43 .43 0 0 0 .5 .4v-.4h-.2M109.6 118.3v.9l-.5-.9v.9M109.9 118.3h.3l.2 .3v.4l-.2 .2h-.3zM124.6 105.1h.7M124.9 104.8v.6M126 104.6h-.4v.4l.4-.1 .1 .4-.2 .1h-.3M126.4 104.6l.2 .8 .3-.8M140.5 118.4a.41 .41 0 0 0-.5 .4 .41 .41 0 0 0 .6 .4v-.4h-.2M141.4 118.3v.9l-.5-.9v.9M141.9 118.3a.47 .47 0 0 1 .5 .5 .47 .47 0 0 1-.5 .4zM157.3 105.1h.6"/>
<path d="M157.6 104.8v.6M158.8 104.6h-.4v.4h.4v.4h-.4M159 104.6l.4 .8 .2-.8M173.3 118.4l-.1-.1a.43 .43 0 0 0-.4 .5 .43 .43 0 0 0 .5 .4v-.4h-.2M174.2 118.3v.9l-.5-.9v.9M174.5 118.3h.3l.2 .3v.4l-.2 .2h-.3zM202.6 104.6h-.4l-.1 .2v.4l.2 .2h.3v-.4h-.2M203.4 104.6v.8l-.4-.8v.8M203.8 104.6h.4l.1 .2v.4l-.2 .2h-.3zM27.2 136.9h.7M27.6 136.6v.7M28.7 136.4h-.4l-.1 .5 .5-.1v.4h-.5"/>
<path d="M29 136.4l.3 .9 .3-.9M38.1 131.4l-.3-.1-.3 .1v.5l.2 .2h.4v-.3h-.2M38.9 131.3v.8l-.4-.8v.8M39.3 131.3l.5 .1v.5l-.1 .2h-.4zM41 136.9h.7M41.4 136.6v.7M42.5 136.4h-.4l-.1 .5 .5-.1v.4h-.5M42.8 136.4l.2 .9 .4-.9M63.5 132.7h.5M63.6 120.1h.6l-.4 .8M63.7 132.4v.6M64.6 120l-.1 .7h.5"/>
<path d="M64.9 132.1h-.4v.4h.3l.2 .1-.1 .4-.4-.1M64.9 120.4v.5M65.1 132.1l.4 .9 .2-.9M65.2 120.9l.3-.8 .2 .8M65.3 120.7h.4M66.6 120.2l-.4-.1a.44 .44 0 0 0-.2 .6 .44 .44 0 0 0 .6 .2M66.8 120.1h.5M67 120.1v.8M67.5 120.1h.5l-.2 .3 .2 .1v.4h-.5M68.4 120.2l.4-.1 .1 .3-.6 .5h.6M29.8 149.9h.7M30.2 149.6v.6"/>
<path d="M30.3 141.2h.4v-.3l-.4-.1v.7M30.3 142.7l.3-.3v.9M30.3 143.3h.5M30.4 141.2l.3 .3M30.9 140.8h.5l-.3 .7M31.2 142.5l.3-.1 .1 .2-.1 .7h-.2l-.2-.3zM31.3 149.4h-.4v.4l.4-.1 .1 .4-.2 .1h-.3M31.6 149.4l.3 .8 .2-.8M31.7 140.8a.31 .31 0 0 1 .3 .4 .31 .31 0 0 1-.4 .2zM32 142.4v.9M32.1 142.9l.4 .4M32.3 141l.2-.2v.7"/>
<path d="M32.3 141.5h.3M32.5 142.4l-.5 .6M32.9 155.7l.2-.3v.8M32.9 154.1h.2l.2-.2-.4-.1v.7M32.9 156.2h.5M33.1 154.1l.2 .4M33.5 153.8h.5l-.3 .7M33.8 155.4a.42 .42 0 0 1 .5 .4 .42 .42 0 0 1-.5 .4zM34.2 153.8l.4 .1v.4l-.2 .2-.2-.3zM34.6 155.4v.8M34.7 155.7l.4 .5M35 153.7l-.2 .5h.5"/>
<path d="M35.1 155.4l-.5 .5M35.2 154v.5M41 149.9h.7M41.4 149.6v.6M42.5 149.4h-.4l-.1 .4 .5-.1v.5h-.5M42.8 149.4l.2 .8 .4-.8M44.1 155.7l.2-.3v.8M44.1 142.7l.2-.3v.9M44.1 154.1h.2l.2-.2-.4-.1v.7M44.1 141.2l.4-.1-.1-.3h-.3v.7M44.1 143.3h.5M44.1 156.2h.5"/>
<path d="M44.2 154.1l.3 .4M44.2 141.2l.3 .3M44.7 153.8h.5l-.4 .7M44.7 140.8h.5l-.4 .7M45.1 155.4a.43 .43 0 0 1 .3 .4 .43 .43 0 0 1-.3 .4l-.2-.3zM45.1 142.4a.43 .43 0 0 1 .3 .5 .43 .43 0 0 1-.3 .4l-.2-.3zM45.4 153.8h.4v.6l-.2 .1-.2-.1zM45.4 140.9h.4l-.1 .6-.3-.1zM45.8 142.4v.9M45.8 155.4v.8M45.9 155.7l.4 .5M45.9 142.9l.4 .4"/>
<path d="M46 153.8h.4l-.2 .2h.2v.4h-.4M46 140.9h.4v.3l-.4 .3h.4M46.3 155.4l-.5 .5M46.3 142.4l-.5 .6M63.9 156.3a.42 .42 0 0 0-.5 .3 .42 .42 0 0 0 .1 .5h.4v-.3h-.2M64.8 156.2v.9l-.5-.9v.9M65.1 156.2l.6 .2v.5l-.2 .2h-.4zM69 145.1h.6l-.4 .8M69.1 143.3v.8l.2 .1 .3-.1v-.8M70 143.3h.5l-.4 .9M70.1 145l-.2 .7h.5M70.3 145.3v.6"/>
<path d="M70.7 145.9l.2-.8 .3 .8M70.7 145.7h.5M71 143.3a.48 .48 0 0 1 .3 .5 .48 .48 0 0 1-.3 .4l-.2-.1v-.6zM71.8 143.3l-.2 .6h.6M72 145.2l-.4-.1a.44 .44 0 0 0-.2 .6 .44 .44 0 0 0 .6 .1M72 143.6v.6M72.3 145.1h.4M72.5 145.1v.8M72.5 143.7h.3M72.9 143.3h-.4v.9h.4M72.9 145.1h.5l-.2 .3 .2 .1v.3h-.5M73.8 145.2l.4-.1 .1 .1-.5 .7h.5"/>
<path d="M87.6 152.8h.5l-.3 .3 .3 .1v.4h-.5M88.4 152.8h.5l-.2 .3 .2 .2v.2l-.1 .2-.4-.1M89.4 155h.3l.1-.4h-.4v.8M89.4 152.8a.48 .48 0 0 1 .4 .4 .48 .48 0 0 1-.4 .5l-.1-.2v-.6zM89.5 155l.3 .4M90.1 153.3h.4l.1-.4-.1-.1h-.4v.9M90.3 153.3l.3 .4M90.6 154.6v.8l-.4-.8v.8M91 154.6h.6l-.4 .8M91.6 152.8l-.7 1.1M92 154.6h.2l.1 .1v.5l-.1 .2-.3-.2zM92.1 152.8l-.3 .6h.6"/>
<path d="M92.2 153.1v.6M92.7 152.8h.5l-.4 .9M92.7 154.8l.2-.2v.8M92.7 155.4h.5M93.7 152.8l.2 .1v.7l-.1 .1-.3-.2v-.6zM94.4 153.3h.3l.2-.4-.2-.1h-.3v.9M94.5 153.3l.4 .4M115.1 152.8h.6l-.3 .3 .3 .2v.2l-.2 .2-.4-.1M115.9 152.8h.6l-.3 .3 .3 .1v.4h-.6M116.9 152.9l.2-.1 .2 .1v.6l-.2 .2a.53 .53 0 0 1-.2-.8zM116.9 155h.4v-.4h-.4v.8M117 155l.4 .4"/>
<path d="M117.6 153.3l.5-.1v-.3l-.5-.1v.9M117.9 153.3l.2 .4M118.2 154.6v.8l-.5-.8v.8M118.6 154.6h.6l-.5 .8M119.2 152.8l-.8 1.1M119.5 154.6a.36 .36 0 0 1 .4 .3 .36 .36 0 0 1-.1 .4l-.1 .1a.55 .55 0 0 1-.2-.8zM119.6 152.8l-.2 .6h.5M119.8 153.1v.6M120.2 152.8h.6l-.4 .9M120.3 154.6h.4l.1 .2-.6 .6h.6M121.1 152.9l.3-.1 .1 .1v.6l-.1 .2a.53 .53 0 0 1-.3-.8zM121.9 153.3l.5-.1v-.3l-.5-.1v.9"/>
<path d="M122.1 153.3l.3 .4M144.4 152.8h.6l-.4 .3 .4 .2v.2l-.2 .2-.4-.1M145.2 152.8h.6l-.3 .3 .3 .1v.4h-.6M146.2 152.9l.2-.1 .2 .1v.6l-.2 .2a.53 .53 0 0 1-.2-.8zM146.2 155h.4v-.4h-.4v.8M146.3 155l.4 .4M146.9 153.3l.5-.1v-.3l-.5-.1v.9M147.2 153.3l.2 .4M147.5 154.6v.8l-.5-.8v.8M147.9 154.6h.6l-.5 .8M148.5 152.8l-.8 1.1M148.8 154.6a.43 .43 0 0 1 .4 .3 .43 .43 0 0 1-.3 .5l-.2-.2z"/>
<path d="M148.9 152.8l-.2 .6h.5M149.1 153.1v.6M149.5 152.8h.6l-.5 .9M149.5 154.6h.5l-.3 .3 .3 .1v.3h-.5M150.4 152.9l.2-.1a.54 .54 0 0 1 0 .9l-.3-.3zM151.2 153.3l.5-.1v-.3l-.5-.1v.9M151.4 153.3l.3 .4M178 152.8h.5l-.2 .3 .2 .1v.4h-.5M178.9 152.8h.5l-.3 .3 .3 .1v.4h-.5M179.8 155h.3l.1-.4h-.4v.8M179.9 152.8a.48 .48 0 0 1 .3 .4 .48 .48 0 0 1-.3 .5l-.2-.2v-.6zM180 155l.2 .4"/>
<path d="M180.5 153.3h.4l.2-.4-.2-.1h-.4v.9M180.8 153.3l.3 .4M181.1 154.6v.8l-.5-.8v.8M181.5 154.6h.5l-.4 .8M182.1 152.8l-.8 1.1M182.4 154.6h.3v.7l-.1 .1-.3-.2zM182.5 152.8l-.3 .6h.6M182.7 153.1v.6M183.1 152.8h.5l-.3 .9M183.1 154.6h.6l-.4 .8M184.1 152.8a.48 .48 0 0 1 .4 .4 .48 .48 0 0 1-.4 .5l-.2-.2v-.6zM184.8 153.3h.3l.2-.4-.2-.1h-.3v.9"/>
<path d="M185 153.3l.3 .4M25.4 163.2a.41 .41 0 0 0-.5 .4 .41 .41 0 0 0 .6 .4v-.4h-.1M26.4 163.1v.9l-.5-.9v.9M26.8 163.1l.4 .3v.4l-.2 .2h-.2zM29.8 172.3h.7M30.2 172v.6M31.3 171.7h-.4v.5l.3-.1 .2 .2-.1 .3-.4-.1M31.6 171.7l.3 .9 .2-.9M32.9 178l.2-.2v.9M32.9 166.8l.2-.2v.8M32.9 176.5h.3l.1-.2-.4-.2v.7M32.9 165.3h.3l.1-.2-.4-.1v.6"/>
<path d="M32.9 178.7h.5M32.9 167.4h.5M33.1 176.5l.2 .3M33.1 165.3l.2 .3M33.5 176.1h.5l-.3 .7M33.5 165h.5l-.3 .6M33.9 177.8a.48 .48 0 0 1 .4 .4 .48 .48 0 0 1-.4 .5l-.2-.2v-.6zM33.9 166.6a.43 .43 0 0 1 .3 .4 .43 .43 0 0 1-.4 .4l-.1-.7zM34.3 176.1l.3 .2-.1 .5a.37 .37 0 0 1-.3-.3 .37 .37 0 0 1 .1-.4zM34.3 165l.3 .1-.1 .5-.3-.2zM34.6 166.6v.8M34.6 177.8v.9"/>
<path d="M34.7 178.2l.4 .5M34.7 166.9l.4 .5M34.8 176.1h.5l-.3 .7M35.1 177.8l-.5 .5M35.1 166.6l-.5 .5M35.2 165h-.3l-.1 .3 .4-.1v.4h-.4M41.9 161.1h.6M42.2 160.7v.7M43.4 160.6h-.4l-.1 .4 .4-.1 .1 .4h-.5M43.6 160.6l.4 .8 .2-.8M44.9 165.3h.4v-.2l-.4-.1v.6M45 166.8l.2-.2v.8"/>
<path d="M45 167.4h.4M45.1 165.3l.2 .3M45.6 165h.4l-.2 .6M45.8 166.7l.3-.1 .2 .1-.1 .6a.39 .39 0 0 1-.5-.2 .39 .39 0 0 1 .1-.4zM46.3 165.1l.1-.1a.34 .34 0 0 1 .3 .3 .34 .34 0 0 1-.3 .3zM46.6 166.6v.8M46.8 166.9l.3 .5M47.1 166.6l-.5 .5M47.2 165l-.3 .1v.5h.4l-.1-.4h-.3v.2M18.7 185.2h.6M18.9 184.9v.6M19.1 195h-.3l-.2 .4 .2 .5h.3v-.4h-.2"/>
<path d="M20 195v.9l-.5-.9v.9M20.1 184.7h-.4v.4l.4-.1 .1 .4-.2 .1h-.3M20.4 195h.3l.2 .2v.5l-.2 .2h-.3zM20.4 184.7l.3 .8 .3-.8M21.7 191l.3-.3v.9M21.7 191.6h.5M22.2 189.1l-.3-.1-.2 .2v.4l.3 .3 .2-.1M22.6 189h.5l-.4 .9M22.6 190.7h.3l.1 .2-.1 .7h-.3v-.2zM23.4 190.8l.3-.1v.8a.39 .39 0 0 1-.4-.2 .39 .39 0 0 1 .1-.5zM23.5 189a.43 .43 0 0 1 .4 .4 .43 .43 0 0 1-.3 .5l-.2-.2zM24.2 191h.2l.2 .1v.5"/>
<path d="M24.2 189.3l.2-.3v.9M24.2 191v.6M24.2 189.9h.5M25 191.1h.3M25.4 190.7h-.4v.9M30.3 191l.3-.3v.9M30.3 191.6h.5M30.9 189.1l-.4-.1-.2 .2v.4l.3 .3 .3-.1M31.1 189h.6l-.3 .9M31.2 190.8l.3-.1v.8a.39 .39 0 0 1-.4-.2 .39 .39 0 0 1 .1-.5zM32 190.7a.42 .42 0 0 1 .5 .4 .42 .42 0 0 1-.5 .5zM32 189.1l.4-.1 .1 .2v.5l-.2 .2a.48 .48 0 0 1-.3-.8z"/>
<path d="M32.8 191h.3l.1 .1v.5M32.8 189.1l.4-.1 .1 .2-.5 .7h.5M32.8 191v.6M33.6 191.1h.3M34 190.7h-.4v.9M38.9 191l.3-.3v.9M38.9 191.6h.5M39.5 189.1l-.4-.1a.44 .44 0 0 0-.1 .6 .44 .44 0 0 0 .5 .2M39.7 189h.6l-.4 .9M39.8 190.7a.42 .42 0 0 1 .5 .4 .42 .42 0 0 1-.5 .5zM40.7 190.7a.42 .42 0 0 1 .4 .4 .42 .42 0 0 1-.4 .5zM40.7 189.1l.3-.1 .1 .2v.5l-.2 .2a.48 .48 0 0 1-.2-.8z"/>
<path d="M41.4 189h.5l-.3 .4h.3v.3l-.1 .2-.4-.1M41.4 191h.4v.6M41.4 191v.6M42.2 191.1h.3M42.6 190.7h-.4v.9M46.7 191l.2-.3v.9M46.7 191.6h.5M47.2 189.1l-.3-.1-.2 .2v.4l.2 .3 .3-.1M47.5 189h.5l-.3 .9M47.6 190.7h.3l.1 .2-.1 .7h-.3l-.1-.2zM48.4 190.8l.3-.1v.8a.39 .39 0 0 1-.4-.2 .39 .39 0 0 1 .1-.5zM48.5 189a.43 .43 0 0 1 .4 .4 .43 .43 0 0 1-.3 .5l-.2-.2z"/>
<path d="M49.1 191h.3l.2 .1v.5M49.1 191v.6M49.4 188.9l-.3 .6h.6M49.6 189.3v.6M50 191.1h.2M50.3 190.7h-.3v.9M55.3 191l.3-.3v.9M55.3 191.6h.4M55.8 189.1l-.3-.1-.2 .2v.4l.3 .3 .2-.1M56.1 189h.6l-.4 .9M56.3 190.7h.2l.1 .2-.1 .6a.39 .39 0 0 1-.4-.2 .39 .39 0 0 1 .1-.5zM57 190.7a.42 .42 0 0 1 .5 .4 .42 .42 0 0 1-.5 .5z"/>
<path d="M57 189.1l.4-.1v.2v.5l-.1 .2a.48 .48 0 0 1-.3-.8zM57.8 191h.2l.2 .1v.5M57.8 191v.6M58.2 189h-.3l-.1 .4h.4l.1 .3-.2 .2-.3-.1M58.5 191.1h.4M59 190.7h-.5v.9M63.9 191l.2-.3v.9M63.9 191.6h.5M64.5 189.1l-.5-.1a.44 .44 0 0 0-.1 .6 .44 .44 0 0 0 .6 .2M64.7 189h.6l-.4 .9M64.8 190.7a.42 .42 0 0 1 .4 .4 .42 .42 0 0 1-.4 .5zM65.7 190.7a.42 .42 0 0 1 .4 .4 .42 .42 0 0 1-.4 .5z"/>
<path d="M65.7 189.1l.3-.1 .1 .2v.5l-.2 .2a.48 .48 0 0 1-.2-.8zM66.4 191h.4v.6M66.4 191v.6M66.8 189l-.4 .2v.6l.4 .1 .1-.5h-.5M67.2 191.1h.2M67.6 190.7h-.4v.9M72.5 191l.3-.3v.9M72.5 191.6h.5M73 189.1l-.3-.1a.43 .43 0 0 0-.2 .5 .43 .43 0 0 0 .5 .3M73.4 189h.6l-.5 .9M73.4 190.7a.42 .42 0 0 1 .5 .4 .42 .42 0 0 1-.5 .5zM74.2 190.8l.3-.1v.8a.39 .39 0 0 1-.4-.2 .39 .39 0 0 1 .1-.5z"/>
<path d="M74.3 189a.43 .43 0 0 1 .4 .4 .43 .43 0 0 1-.3 .5l-.2-.2zM75 189h.6l-.4 .9M75.1 191h.2l.1 .6M75.1 191v.6M75.8 191.1h.3M76.2 190.7h-.4v.9M115.1 191.6h.6l-.3 .3h.2v.5l-.5-.1M115.9 191.6h.6l-.3 .3 .3 .1v.3h-.6M116.9 191.6h.2l.2 .1-.1 .6a.39 .39 0 0 1-.4-.2 .39 .39 0 0 1 .1-.5zM116.9 193.8h.3l.2-.2-.2-.4h-.3v1M117 193.8l.4 .4M117.6 192h.5v-.4h-.5v.8"/>
<path d="M117.9 192l.2 .4M118.2 193.2v1l-.5-1v1M118.6 193.2h.6l-.5 1M119.2 191.6l-.8 1.1M119.6 191.6l-.2 .5h.5M119.6 193.2a.48 .48 0 0 1 .3 .5 .48 .48 0 0 1-.3 .5 .69 .69 0 0 1 0-1zM119.8 191.9v.5M120.2 191.6h.6l-.4 .8M120.4 193.2l-.1 .6h.5M120.7 193.6v.6M121.1 191.6h.3l.1 .1v.6a.39 .39 0 0 1-.5-.2 .39 .39 0 0 1 .1-.5zM121.9 192h.4l.1-.4h-.5v.8"/>
<path d="M122.1 192l.3 .4M144.4 191.6h.6l-.4 .3h.3v.5l-.5-.1M145.2 191.6h.6l-.3 .3 .3 .1v.3h-.6M146.2 191.6h.2l.2 .1-.1 .6a.39 .39 0 0 1-.4-.2 .39 .39 0 0 1 .1-.5zM146.2 193.8h.3l.2-.2-.2-.4h-.3v1M146.3 193.8l.4 .4M146.9 192h.5v-.4h-.5v.8M147.2 192l.2 .4M147.5 193.2v1l-.5-1v1M147.9 193.2h.6l-.5 1M148.5 191.6l-.8 1.1M148.9 191.6l-.2 .5h.5"/>
<path d="M148.9 193.2a.48 .48 0 0 1 .3 .5 .48 .48 0 0 1-.3 .5l-.2-.2v-.6zM149.1 191.9v.5M149.5 191.6h.6l-.5 .8M150 193.2h-.4v.5h.4v.4h-.4M150.4 191.6h.1a.34 .34 0 0 1 .3 .4 .34 .34 0 0 1-.4 .3zM151.2 192h.4l.1-.4h-.5v.8M151.4 192l.3 .4M178 191.6h.5l-.2 .3 .2 .1v.3h-.5M178.9 191.6h.5l-.3 .3 .3 .1v.3h-.5M179.8 193.8l.4-.1-.1-.5h-.3v1M179.9 191.6a.43 .43 0 0 1 .3 .4 .43 .43 0 0 1-.4 .4l-.1-.7zM180 193.8l.2 .4"/>
<path d="M180.5 192h.5l.1-.3-.2-.1h-.4v.8M180.8 192l.3 .4M181.1 193.2v1l-.5-1v1M181.5 193.2h.5l-.4 1M182.1 191.6l-.8 1.1M182.5 191.6l-.3 .5h.6M182.5 193.2l.2 .1v.8l-.1 .1-.3-.2v-.6zM182.7 191.9v.5M183.1 191.6h.5l-.3 .8M183.5 193.2l-.2 .1-.2 .7 .2 .2 .3-.1v-.4l-.3-.1-.2 .2M184.1 191.6a.43 .43 0 0 1 .3 .4 .43 .43 0 0 1-.4 .4l-.1-.7zM184.8 192h.4l.1-.3-.2-.1h-.3v.8"/>
<path d="M185 192l.3 .4"/>
</g>
</svg>
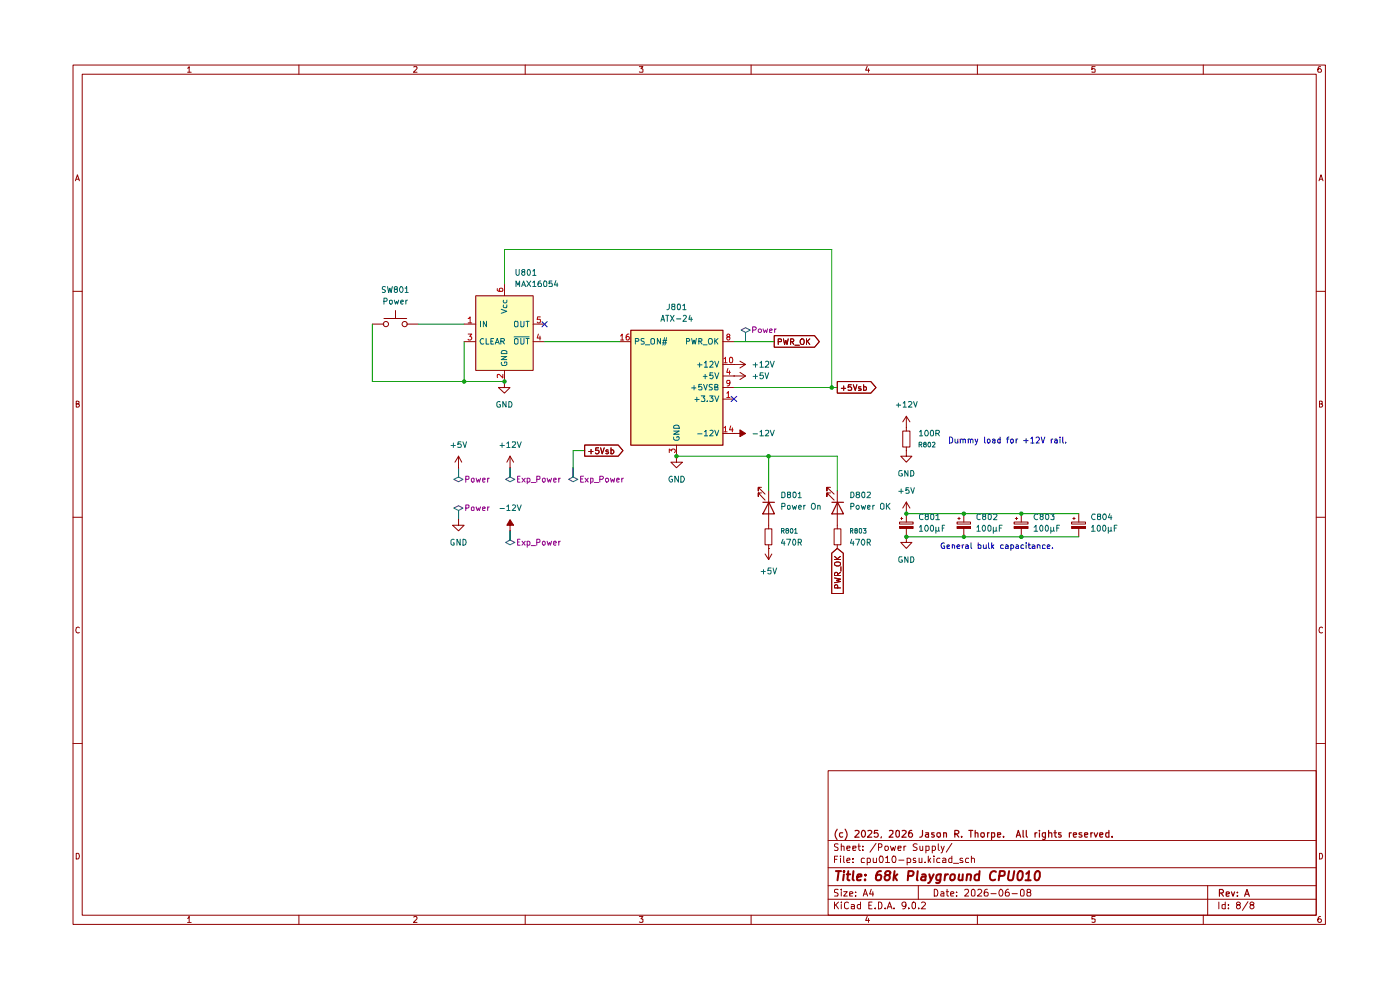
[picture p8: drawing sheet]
<svg xmlns="http://www.w3.org/2000/svg" width="297mm" height="210mm" viewBox="0 0 297 210" stroke-linecap="round" stroke-linejoin="round" font-family="sans-serif">
<g fill="none" stroke="#910000" stroke-width=".21">
<path d="M15.5 13.8h265.7v182.3h-265.7zM17.4 15.7h261.8v178.4h-261.8zM39.8 14.5l.3-.4v1.2M39.8 15.3h.8M63.4 13.8v1.9M87.8 14.2l.6-.1 .1 .4-.8 .8h.8M111.4 13.8v1.9M135.6 14.1h.8l-.4 .5 .4 .1v.5h-.8M159.3 13.8v1.9M184 14.1l-.4 .8h.9M184.2 14.6v.7M207.3 13.8v1.9"/>
<path d="M232.3 14.1h-.7v.6l.2-.1 .5 .1-.1 .6-.6-.1M255.3 13.8v1.9M280.2 14.1l-.5 .1a.94 .94 0 0 0 0 1.1h.5l.1-.1v-.4l-.2-.2h-.3l-.2 .2M16 38.4l.4-1.3 .4 1.3M16.2 38h.6M279.8 38.4l.4-1.3 .5 1.3M279.9 38h.6M15.5 61.8h1.9M279.2 61.8h2M16.2 85.7l.6-.1v-.4l-.6-.1v1.3h.4l.2-.5-.3-.2M279.9 85.7l.6-.1v-.4l-.6-.1v1.3l.6-.1 .1-.4-.3-.2M15.5 109.7h1.9"/>
<path d="M279.2 109.7h2M16.8 133.2l-.2-.2a.65 .65 0 0 0-.5 .6 .65 .65 0 0 0 .5 .7l.2-.1M280.6 133.2l-.3-.2a.65 .65 0 0 0-.5 .6 .65 .65 0 0 0 .5 .7l.3-.1M15.5 157.7h1.9M279.2 157.7h2M175.7 163.5h103.5v30.6h-103.5zM175.7 178.3h103.5M177.8 179.1l-.5-.1-.3 .2v.3l.8 .5-.3 .4-.5-.1M178.5 179.6l.5-.1 .1 .9M178.5 179v1.4M179.7 179.9l.6-.1v-.3h-.6v.2v.6h.6M180.9 179.9l.7-.1-.1-.3h-.6v.8h.6"/>
<path d="M182 179.5h.5M182.2 179v1.2l.3 .2M183 179.5v.2M185.8 178.9l-1.2 1.9M186.3 179.7h.7v-.6l-.7-.1v1.4M187.8 179.5l.6 .1 .1 .6a.45 .45 0 0 1-.7 .1zM188.9 179.5l.3 .9 .3-.7 .2 .7 .3-.9M190.5 179.9l.7-.1-.1-.3h-.5l-.1 .2 .1 .6h.5M191.8 179.5v.9M192.2 179.5h-.3l-.1 .2M194.6 179.1l-.6-.1-.3 .2 .3 .5 .5 .1 .1 .4a.6 .6 0 0 1-.9 .1M195.2 179.5v.8l.4 .1 .1-.1"/>
<path d="M195.7 179.5v.9M199 179v1.2l.3 .2M199.6 179.5l.4 .9M200.3 179.5l-.4 1.3-.3 .1M201.9 178.9l-1.2 1.9M16.2 181a.66 .66 0 0 1 .6 .4 .66 .66 0 0 1-.2 .8h-.4zM39.8 194.8l.3-.4v1.3M39.8 195.7h.8M63.4 194.1v2M87.8 194.6l.4-.2 .3 .4-.8 .9h.8M111.4 194.1v2M135.6 194.4h.8l-.4 .5 .4 .1v.6h-.8"/>
<path d="M159.3 194.1v2M175.7 190.8h103.5M175.7 187.9h103.5M175.7 184.1h103.5M177 191.3v1.5M177 182.3h.5M177.3 191.9l.6 .9M177.7 181.6h-.7v1.4M177.8 188.7h-.7v.6a.53 .53 0 0 1 .6 .2 .53 .53 0 0 1 0 .6h-.7M177.9 191.3l-.9 .9M178.3 181.6v.1M178.3 182v1"/>
<path d="M178.5 191.3v.2M178.5 188.6v.2M178.5 189.1v1M178.5 191.9v.9M179 189.1h.7l-.7 1h.7M179 181.6v1.2l.2 .2M179.7 182.5l.6-.1-.1-.4-.5 .1v.7v.2h.6M180 191.5l-.4-.2-.4 .4v.9l.4 .2 .4-.2M180.3 189.7l.6-.2-.1-.3h-.5v.9h.5M180.6 191.9h.4l.3 .1v.8M180.9 182.9v.1M180.9 182.1v.2"/>
<path d="M181.3 192.2l-.7 .1v.4h.7M181.5 190v.1M181.5 189.2v.1M182.5 191.9h-.4l-.2 .2v.4l.2 .3 .4-.1M182.5 191.3v1.5M183 180.3v.1M183.1 190.1l.5-1.5 .5 1.5M183.2 189.7h.7M183.4 182.1l-.4-.1-.3 .3 .1 .7h.6M184 194.4l-.4 .8h.9M184 182.1l.4-.1 .3 .3-.1 .7h-.6M184 182v1.5"/>
<path d="M184.2 194.8v.9M184.3 192h.5M184.8 188.6l-.3 1.1h.8M185 191.3h-.7v1.5h.7M185.2 189.1v1M185.2 182l.1 1 .6-.1M185.7 192.6v.2M185.9 182v1M186.3 191.3l.7 .2v1.1l-.3 .2h-.4zM186.7 181.6a.73 .73 0 0 1 .7 .5 .73 .73 0 0 1-.3 .9h-.4l-.2-.5zM187.8 192.6v.2M187.9 181.9l.4-.3v1.4"/>
<path d="M187.9 183h.8M188.2 192.8l.5-1.5 .5 1.5M188.4 192.4h.7M189.4 181.7l.5-.1 .2 .5-.2 .9h-.4l-.2-.3-.1-.6zM189.7 192.6v.2M190.7 182.5h1.1M192.2 191.9l-.1 .3-.4 .1-.4-.4v-.3a.46 .46 0 0 1 .5-.3 .46 .46 0 0 1 .4 .3l-.2 1-.5 .2M192.4 182.1a.52 .52 0 0 1 .8 .2l-.2 .7h-.6M192.4 182v1.5M192.8 192.6v.2M193.5 191.5l.4-.2 .3 .3v.9l-.3 .3a.82 .82 0 0 1-.4-1.3zM194.2 182.1l-.3-.1-.2 .3 .2 .2 .4 .2-.1 .3h-.5"/>
<path d="M194.8 187.9v2.9M194.9 192.6v.2M195 182v1l.6-.1M195.5 191.5l.2-.2h.3l.3 .5-.9 1h.9M195.6 182v1M196.3 182.9v.1M196.4 180.3l.4 .1 .3-.1-.1-.8h-.6v1.4M196.9 181.6v1.4M197.1 182.5l.3 .5M197.4 182l-.5 .6M197.8 180.3l.4 .1 .3-.2-.2-.7h-.5v1.4M198.1 181.6v.1"/>
<path d="M198.1 182v1M198.2 188.6a.8 .8 0 0 1 .8 .6 .8 .8 0 0 1-.3 .9h-.5zM199.4 182.1l-.4-.1-.3 .3 .1 .6 .6 .1M199.6 189.2l.4-.1 .2 .2v.8h-.6v-.4l.6-.2M200 182.1l.4-.1 .3 .3v.7h-.7v-.5l.7-.1M200.7 189.1h.5M200.9 188.6v1.3l.1 .2h.2M201.7 189.7l.7-.2-.2-.4h-.4l-.1 .2v.6l.1 .2h.5M201.9 181.6v1.4h-.5l-.2-.7 .3-.3 .4 .1M202.3 183.1h1.1M202.9 190v.1M202.9 189.2v.1"/>
<path d="M204.2 182.1a.36 .36 0 0 0-.6 .2l.7 .4-.1 .3h-.6M204.6 188.8l.6-.2 .3 .4-.1 .3-.8 .8h.9M205.5 182.1l-.4-.1-.3 .3 .2 .7h.5M206.1 182.2l.1-.1a.36 .36 0 0 1 .6 .2v.7M206.1 181.6v1.4M206.2 188.8l.3-.2 .3 .4v.8l-.1 .3h-.5l-.1-.3zM207.3 194.1v2M207.4 188.8l.2-.2h.3l.4 .5-.1 .2-.9 .8h1M209.5 188.6l-.5 .2-.2 1 .2 .3 .5-.1v-.7l-.5-.1-.2 .3M210.2 189.6h1.1M212.3 188.6a.87 .87 0 0 1 .2 1.5h-.3l-.3-.5 .1-.6zM213.9 188.6h-.2a1.04 1.04 0 0 0-.3 1.5h.5l.2-.6-.2-.3-.5 .1-.1 .2"/>
<path d="M214.7 189.6h1.1M216.6 188.8l.3-.2 .4 .4v.8l-.2 .3h-.4l-.2-.3zM218.1 189.3l-.3-.3 .1-.3h.6l.2 .3-.1 .1-.7 .2-.1 .3 .1 .5h.6l.2-.5-.3-.3M232.3 194.4h-.7v.6h.7v.6h-.7M255.3 194.1v2M256.2 187.9v6.2M258.6 191.3v1.5M259.9 191.9h-.7v.7l.3 .2 .4-.1M259.9 191.3v1.5M260.6 192.6v.2M260.6 191.9v.1M262.5 191.9l-.2-.2 .2-.4 .6 .3-.1 .3h-.5l-.1 .2-.1 .4 .2 .3a.45 .45 0 0 0 .5-.2 .45 .45 0 0 0 .1-.5l-.3-.2"/>
<path d="M264.7 191.3l-1.1 1.8M265.4 191.9l-.2-.2 .2-.4 .6 .3-.1 .3h-.5l-.1 .2-.1 .4 .2 .3a.45 .45 0 0 0 .5-.2 .45 .45 0 0 0 0-.5l-.2-.2M279.9 181a.66 .66 0 0 1 .7 .4 .66 .66 0 0 1-.3 .8h-.4zM280.2 194.4a.72 .72 0 0 0-.6 .5 .72 .72 0 0 0 .2 .8l.4-.1a.42 .42 0 0 0 0-.6 .42 .42 0 0 0-.5 0l-.1 .2"/>
</g>
<g fill="none" stroke="#910000" stroke-width=".25">
<path d="M177.6 175.9a1.75 1.75 0 0 0 0 2.2M178.8 176.7h-.5l-.2 .2v.4l.2 .3 .5-.1M179.3 175.9a1.64 1.64 0 0 1 0 2.2M181.4 176.2h.8v.4l-.9 1h.9M182.9 176.2l.2-.1a.73 .73 0 0 1 .6 .8 .73 .73 0 0 1-.6 .7l-.4-.6zM184.1 176.2l.6-.1 .3 .5-1 1h1M186.2 176.1h-.7v.7l.6-.1 .2 .3v.3l-.2 .3-.6-.2M187 177.5l-.1 .3M188.7 176.2h.7v.5l-.8 .9h.8M190.1 176.2l.4-.1 .3 .3v.9l-.3 .3a.87 .87 0 0 1-.4-1.4zM191.4 176.2h.7l.1 .4-.9 1h.9M193.4 176.1a.57 .57 0 0 0-.7 .6v.6l.3 .3h.3l.3-.3v-.3l-.3-.3h-.3l-.3 .3"/>
<path d="M195.7 176.1v1.1l-.2 .3-.4 .1M196.4 176.7h.6v.9M197 177h-.4l-.3 .2 .3 .4 .4-.1M198.2 176.7h-.5v.3l.5 .3-.2 .3-.3-.1M198.8 176.7h.6v.8a.45 .45 0 0 1-.6-.2zM200.2 176.7h.5l.1 .9M200.2 176.7v.9M202.6 176.9l.6-.1 .2-.1-.1-.5-.7-.1v1.5M202.9 176.9l.5 .7M204 177.4v.2M205.5 176.1h.9M205.9 176.1v1.5"/>
<path d="M206.9 176.7h.5l.1 .9M206.9 176.1v1.5M208.1 176.7h.6v.8a.45 .45 0 0 1-.6-.2zM209.5 176.7v.9M209.8 176.7h-.2l-.1 .2M210.4 177.5h.5v-.8h-.5v1.4M211.6 177.1l.7-.1-.1-.3h-.6v.8h.6M212.9 177.4v.2M215.6 177.6l.4-1.5 .5 1.5M215.7 177.2h.7M217 176.1v1.4l.2 .1M217.7 176.1v1.2l.3 .3"/>
<path d="M219.6 176.7v.9M220 176.7h-.3l-.1 .2M220.5 176.1v.1M220.5 176.7v.9M221.8 177.5l-.4 .1-.3-.3 .2-.6h.5v1.1l-.3 .3-.3-.1M222.5 176.7h.6v.9M222.5 176.1v1.5M223.6 176.7h.6M223.8 176.1v1.2l.4 .3M225.1 176.7h-.5v.3l.6 .3-.3 .3-.3-.1M226.9 176.7v.9M227.3 176.7h-.3l-.1 .2"/>
<path d="M227.7 177.1l.7-.1-.1-.3h-.5l-.1 .1 .1 .7h.5M229.5 176.7h-.5l-.1 .1 .6 .4v.3h-.6M230.1 177.1l.7-.1-.1-.3h-.5l-.1 .1 .1 .7h.5M231.4 176.7v.9M231.8 176.7h-.3l-.1 .2M232.1 176.7l.3 .9 .5-.9M233.3 177.1l.7-.1-.1-.3h-.5l-.1 .1 .1 .7h.5M235.2 176.7h-.5l-.1 .2 .1 .6h.5M235.2 176.1v1.5M235.9 177.4v.2M258.7 189.4h.8v-.5l-.2-.2h-.6v1.4M259 189.4l.5 .7"/>
<path d="M260.1 189.7l.7-.2-.1-.2h-.6v.7h.6M261.2 189.2l.4 .9 .3-.9M262.5 190v.1M262.5 189.3v.1M264 190.1l.5-1.4 .5 1.4M264.2 189.7h.7"/>
</g>
<g fill="none" stroke="#910000" stroke-width=".42">
<path d="M177.3 184.8h1.1M177.9 184.8l-.2 1.9M179 185.5l-.1 1.2M179.1 184.8l-.2 .1 .1 .1 .1-.2-.1 .2M179.6 185.5h.8M180 184.8l-.2 1.7 .4 .2M181.1 184.8l-.2 1.7 .2 .2M181.8 186.1l.9-.2v-.4h-.5l-.3 .2-.1 .9h.8M183.5 186.6v.1M183.6 185.5v.2M186.9 184.8a1.2 1.2 0 0 0-.9 1.8l.5 .1 .3-.1 .1-.9a.63 .63 0 0 0-1 .2M188.1 185.6l-.4-.4 .3-.3 .6-.1 .2 .2 .1 .1-.2 .4-.8 .2a.61 .61 0 0 0-.1 .9 .61 .61 0 0 0 .9-.1 .61 .61 0 0 0-.2-.9"/>
<path d="M189.8 184.8l-.3 1.9M189.8 186l.5 .7M190.4 185.5l-.8 .6M192.7 185.8l.9-.1 .2-.6v-.1l-.3-.2h-.8l-.1 1.9M194.7 184.8l-.2 1.7 .2 .2M195.6 185.5h.7v1.2M196.4 185.9l-.9 .2-.1 .4 .2 .2 .7-.1M197.1 185.5l.4 1.2M198.1 185.5l-.9 1.7-.3 .1M199.6 185.5l-.2 1.5a.53 .53 0 0 1-.8 .2M199.6 185.5a.65 .65 0 0 0-.9 .3v.8a.64 .64 0 0 0 .8 0M200.5 185.5l-.1 1.2"/>
<path d="M201.1 185.5h-.4l-.2 .3M201.7 185.6l.3-.1 .6 .1v.7l-.5 .4a.46 .46 0 0 1-.6-.4zM203.5 185.5l-.2 1a.49 .49 0 0 0 .9 .1M204.3 185.5l-.1 1.2M205.2 185.6l.2-.1h.5v1.2M205.2 185.5l-.2 1.2M207.7 185.5a.65 .65 0 0 0-.9 .3v.8a.64 .64 0 0 0 .8 0M207.8 184.8l-.2 1.9M211.3 185l-.1-.1a.85 .85 0 0 0-1.2 .7v.6a.66 .66 0 0 0 1.1 .4M212 185.8l1-.1 .1-.2v-.5l-.2-.2h-.8l-.2 1.9M214.1 184.8l-.3 1.5 .4 .4 .6-.1 .4-1.8M216.1 185l.3-.2 .5 .2a1.72 1.72 0 0 1-.2 1.6l-.3 .1-.4-.1a1.4 1.4 0 0 1 .1-1.6z"/>
<path d="M217.5 186.7h1.1M217.7 185.4l.6-.6-.2 1.9M219.7 185l.4-.2 .4 .2a1.65 1.65 0 0 1-.2 1.6h-.6a1.4 1.4 0 0 1 0-1.6z"/>
</g>
<g fill="#ffb">
<path d="M100.9 62.7h12.2v15.9h-12.2z"/>
<path d="M133.8 70h19.5v24.4h-19.5z"/>
</g>
<g fill="none" stroke="#910000" stroke-width=".21">
<path d="M79 68.7h2.4M81.4 67.6h4.9M83.9 65.9v1.7M86.3 68.7h2.4M98.5 68.7h2.4M98.5 72.5h2.4M100.9 62.7h12.2v15.9h-12.2zM107 60.3v2.4M107 78.6v2.3M113.1 68.7h2.5M113.1 72.5h2.5M107 80.9v1.3h1.2l-1.2 1.2-1.3-1.2h1.3"/>
<path d="M107 80.9h.1M108.2 99.2h.1M108.2 96.8l-.7 1.2M108.2 96.8l.8 1.2M108.2 96.8v2.4"/>
<circle cx="81.9" cy="68.7" r=".55"/>
<circle cx="85.8" cy="68.7" r=".55"/>
</g>
<path d="M99.3 67.6l.4-.4v1.3M99.3 70.9h.8l-.5 .5 .4 .1 .1 .4-.3 .2h-.3l-.2-.1M99.3 68.5h.8M105.5 61.2v.4l.2 .2h.9v-.6h-.6l-.1 .4 .3 .2M106.7 79.4v.8l-.9-.8-.3 .1 .1 .6M114.2 70.9l-.2 .8h.7M114.6 71.3v.8M114.6 67.2h-.6v.6l.6-.1v.6l-.1 .2h-.4l-.1-.2" fill="none" stroke="#b90000" stroke-width=".21"/>
<g fill="none" stroke="#006665" stroke-width=".21">
<path d="M101.9 68.2v1.1M102.6 71.9a.61 .61 0 0 0-.8 .3 .61 .61 0 0 0 .3 .8l.5-.1M103.1 71.8v1.2h.6M103.2 68.2v1.1l-.7-1.1v1.1M104.1 72.4h.5M104.7 71.8h-.6v1.2h.6M105.1 73l.4-1.2 .4 1.2M105.2 72.6h.5M106.3 72.4h.5l.2-.2-.1-.3-.6-.1v1.2M106.3 65.6l1.2 .4-1.2 .5M106.3 75.6h1.2l-1.2 .7h1.2M106.4 76.9l-.1 .2 .3 .5h.7l.2-.3-.1-.5h-.4v.2"/>
<path d="M106.5 74.4h.9l.1 .2v.4h-1.2zM106.6 72.4l.4 .6M106.8 64.7a.36 .36 0 0 0 .2 .6l.5-.1v-.5M106.8 63.7v.3l.2 .3h.4l.1-.2v-.4M109 71.5h3.3M109.1 68.3l.2-.1h.4l.2 .1v.9l-.3 .1-.5-.1zM109.1 72l.3-.2 .5 .2v.8l-.2 .2h-.4l-.2-.2zM110.5 68.2v1.1h.2h.2l.3-.2v-.9M110.5 71.8l.1 1.2 .5-.1 .1-1.1M111.6 68.2h.7M111.6 71.8h.7M111.9 68.2v1.1"/>
<path d="M111.9 71.8v1.2"/>
</g>
<path d="M97.3 99.2v2l.9 .5-.9 .5-1-.5 1-.5zM96.3 107.8l1-.5 .9 .5-.9 .5v1.9v-1.9z" fill="none" stroke="#474747" stroke-width=".21"/>
<path d="M108.2 110.2l.8 1.2h-.8v1.2v-1.2h-.7z" fill="#910000"/>
<g fill="none" stroke="#910000" stroke-width=".21">
<path d="M131.4 72.5h2.4M153.3 72.5h2.4M153.3 77.3h2.4M153.3 79.8h2.4M97.3 99.2h.1M97.3 96.8l-.8 1.2M97.3 96.8l.7 1.2M97.3 96.8v2.4M124 94.4h7.1l1.1 1.2-1.1 1.2h-7.1zM124.9 95.8h.9M125.4 95.3v1M127 95h-.6l-.1 .6 .6-.1 .2 .2v.3l-.3 .3h-.3l-.2-.2"/>
<path d="M127.4 95l.4 1.3 .4-1.3M129 95.5l-.3-.1-.2 .3 .2 .1h.3l.1 .3-.2 .2-.4-.1M129.6 95.5l.4-.1 .2 .3v.3l-.2 .3-.4-.1M129.6 95v1.3M143.5 96.8v1.2h1.3l-1.3 1.2-1.2-1.2h1.2M143.5 96.8h.1M143.5 94.4v2.4M153.3 82.2h2.4M153.3 84.7h2.4M153.3 91.9h2.4M97.3 110.2v1.2h1.2l-1.2 1.2-1.3-1.2h1.3M97.3 110.2h.1"/>
<path d="M108.2 111.4h-.7l.7-1.2 .8 1.2h-.8v1.2M108.2 112.6h.1M190.8 110.7h2.9v.5h-2.9zM190.8 111.7h2.9v.4h-2.9zM191.1 110h.4M191.3 109.7v.5M192.3 113.9v1.2h1.2l-1.2 1.2-1.2-1.2h1.2M192.3 113.9h.1M192.3 109v1.7M192.3 112.1v1.8"/>
</g>
<path d="M108.2 99.2v2l1 .5-1 .5-.9-.5 .9-.5zM121.6 99.2v2l1 .5-1 .5-1-.5 1-.5zM108.2 112.6v2l1 .5-1 .5-.9-.5 .9-.5z" fill="none" stroke="#474747" stroke-width=".21"/>
<path d="M133.8 70.1h19.6v24.3h-19.6z" fill="none" stroke="#910000" stroke-width=".25"/>
<g fill="none" stroke="#b90000" stroke-width=".21">
<path d="M131.7 71.3l.3-.4v1.2M131.7 72.1h.6M133.4 70.9h-.4l-.2 .3v.8l.2 .1 .4-.1v-.5l-.4-.1-.2 .2M153.6 76.1l.3-.3v1.2M153.6 77h.7M154.4 71.5l-.1-.1a.31 .31 0 0 1 0-.5 .31 .31 0 0 1 .5 .1v.4l-.5 .1-.1 .1v.3l.2 .2 .5-.2-.1-.4h-.2M154.4 78.1l-.2 .9h.7M154.8 78.7v.7M154.9 75.9l.2-.1a.77 .77 0 0 1 .2 1.2h-.4l-.1-.2zM142 96v-.8l.5 .5v-.4h.7l.1 .5-.2 .2M153.6 90.8l.3-.4v1.2M153.6 91.6h.7"/>
<path d="M154.2 83.4l.3-.3v1.2M154.2 84.3h.7M154.9 81.2l-.1 .2h-.5v-.7h.5l.1 .2-.2 .9-.4 .1M155 90.3l-.2 .9h.7M155.4 90.8v.8"/>
</g>
<g fill="none" stroke="#006665" stroke-width=".21">
<path d="M134.8 72.4h.6l.1-.2v-.3l-.7-.1v1.2M136.6 71.9l-.4-.1-.2 .2 .1 .3 .5 .3v.3l-.6 .1M136.9 73.1h.9M138.1 72l.2-.2 .6 .2v.8l-.2 .2h-.4l-.2-.2zM140.1 71.8v1.2l-.7-1.2v1.2M140.5 72.7h.9M140.6 72.2h.9M141 71.6l-.4 1.6M141.4 71.6l-.3 1.6M145.6 72.4h.6v-.5l-.6-.1v1.2M146.7 71.8l.3 1.2 .2-.9 .3 .9 .2-1.2M148 77.4h.9"/>
<path d="M148.2 72.4h.6l.1-.2-.1-.3-.6-.1v1.2M148.4 77v.9M148.5 72.4l.4 .6M149.2 73.1h.8M149.2 79.8h.8M149.4 77l.4-.4v1.3M149.4 77.9h.7M149.6 79.4v.9M150.4 72l.2-.2 .4 .2 .1 .6-.1 .4h-.6l-.1-.4zM150.6 76.8l.4-.2 .3 .4-.8 .9h.8M151.2 79.1h-.6v.6l.5-.1 .2 .2v.3l-.3 .2-.4-.1M151.6 76.6l.5 1.3 .4-1.3"/>
<path d="M151.6 79.1l.5 1.2 .4-1.2M151.6 71.8v1.2M151.8 72.3l.5 .7M152.3 71.8l-.7 .7M142.9 92.7v.5l.3 .2h.6a.55 .55 0 0 0 .2-.8h-.4v.3M142.9 91.4h1.2l-1.2 .7h1.2M142.9 90.4a.66 .66 0 0 1 .8-.2 .66 .66 0 0 1 .4 .6h-1.2zM146.7 82.3h1M147.2 81.8v.9M147.4 84.7h.9M147.8 84.2v1M148 92h.9"/>
<path d="M148.8 84h.7l-.3 .4 .3 .2v.5h-.7M148.8 81.5h-.6v.6l.5-.1 .2 .2v.3l-.1 .2-.6-.1M149.3 81.5l.4 1.2 .3-1.2M149.4 91.6l.4-.3v1.2M149.4 92.5h.7M150 85.1v.1M150.5 84h.8l-.4 .4 .4 .3-.1 .4h-.7M150.6 91.4l.4-.1 .3 .3-.8 .9h.8M151.1 81.6h-.7v.4l.7 .4-.1 .3h-.6M151.6 82.1h.5l.2-.2-.1-.3-.6-.1v1.2h.6l.1-.5-.2-.1M151.6 84l.5 1.2 .4-1.2M151.6 91.3l.5 1.2 .4-1.2"/>
</g>
<path d="M190.8 111.9h2.9" fill="none" stroke="#910000" stroke-width=".42"/>
<path d="M155.7 91.9h1.3v-.7l1.2 .7-1.2 .7v-.7z" fill="#910000"/>
<g fill="none" stroke="#910000" stroke-width=".21">
<path d="M155.7 77.3h.1M155.7 79.8h.1M155.7 77.3h2.5M155.7 79.8h2.5M157 76.6l1.2 .7M157 79l1.2 .8M158.2 77.3l-1.2 .8M158.2 79.8l-1.2 .7M164.3 71.2h8.5l1 1.3-1 1.2h-8.5zM165.1 72.5h.6l.1-.5-.7-.1v1.2M166.2 71.9l.3 1.2 .2-.9 .3 .9 .2-1.2M167.7 72.5h.6v-.5l-.6-.1v1.2"/>
<path d="M168 72.5l.4 .6M168.7 73.2h.9M169.8 72l.5-.1a.86 .86 0 0 1 .1 1.2h-.4a.82 .82 0 0 1-.2-1.1zM171.1 71.9v1.2M171.3 72.4l.5 .7M171.8 71.9l-.7 .7M124 94.4h7.1l1.1 1.2-1.1 1.2h-7.1zM124.9 95.8h.9M125.4 95.3v1M127 95h-.6l-.1 .6 .6-.1 .2 .2v.3l-.3 .3h-.3l-.2-.2M127.4 95l.4 1.3 .4-1.3M129 95.5l-.3-.1-.2 .3 .2 .1h.3l.1 .3-.2 .2-.4-.1"/>
<path d="M129.6 95.5l.4-.1 .2 .3v.3l-.2 .3-.4-.1M129.6 95v1.3M155.7 91.9h1.3v.7l1.2-.7-1.2-.7v.7M155.7 91.9h.1M177.6 80.9h7.1l1.1 1.3-1.1 1.2h-7.1zM178.5 82.4h.9M179 81.9v.9M180.6 81.6h-.6l-.1 .6 .2-.2h.3l.3 .3v.3l-.2 .2-.6-.1M181 81.6l.4 1.2 .4-1.2M182.6 82h-.4l-.1 .2 .2 .3h.3v.3h-.5M183.2 81.6v1.2h.4l.2-.2v-.4l-.2-.2h-.4M191.5 91.4h1.5v3.4h-1.5z"/>
<path d="M192.3 90.7h.1M192.3 95.6v1.2h1.2l-1.2 1.2-1.2-1.2h1.2M192.3 95.6h.1M192.3 88.3l-.8 1.2M192.3 88.3l.7 1.2M192.3 88.3v3.1M192.3 94.8v.8M161.5 103.4h-.6v.7v-.7l1.4 1.4M161.5 104.6h-.6v.7v-.7l1.4 1.5M162.3 112.2h1.4v3.4h-1.4zM162.3 117.5l.8 1.2M163.1 116.3h.1"/>
<path d="M163.1 104.1v8.1M163.1 115.6v3.1M163.7 117.5l-.6 1.2M176.2 103.4h-.8v.7v-.7l1.6 1.4M176.2 104.6h-.8v.7v-.7l1.6 1.5M176.4 117.3l1.2-1 1.3 1v8.6h-2.5zM177 112.2h1.4v3.4h-1.4zM177 119.5a.86 .86 0 0 1 1.3 0 .46 .46 0 0 1-.4 .6l-.8-.2zM177 118.7h1.3M177 118l.8 .7M177.6 104.1v8.1M177.6 115.6v.7"/>
<path d="M178.3 118l-.7 .5M192.3 109h.1M192.3 106.5v2.5M192.3 106.5l-.8 1.3M192.3 106.5l.7 1.3M203 110.7h2.9v.5h-2.9zM203 111.7h2.9v.4h-2.9zM203.2 110h.5M203.5 109.7v.5M204.5 109v1.7M204.5 112.1v1.8M215.1 110.7h3v.5h-3z"/>
<path d="M215.1 111.7h3v.4h-3zM215.4 110h.5M215.6 109.7v.5M216.7 109v1.7M216.7 112.1v1.8M227.3 110.7h3v.5h-3zM227.3 111.7h3v.4h-3zM227.6 110h.5M227.8 109.7v.5M228.9 109v1.7M228.9 112.1v1.8M177 122.6l1.3 .2-.8 .3 .8 .3-1.3 .2"/>
<path d="M177.7 124.7l-.1-.6h-.5l-.1 .6h1.3M177.7 122.1l-.1-.6h-.5l-.1 .6h1.3M178.3 121.4l-.6 .4M178.4 120.2v1"/>
</g>
<path d="M161.8 106.5h2.5M163.1 106.5l1.2 2.5h-2.5zM176.5 106.5h2.4M177.7 106.5l1.2 2.5h-2.4z" fill="none" stroke="#910000" stroke-width=".25"/>
<path d="M157.2 70l1-.5 1 .5-1 .5v2v-2z" fill="none" stroke="#474747" stroke-width=".21"/>
<path d="M203 111.9h2.9M215.1 111.9h3M227.3 111.9h3" fill="none" stroke="#910000" stroke-width=".42"/>
<path d="M79 68.7v12.2h28M88.7 68.7h9.8M98.5 72.5v8.4M107 60.3v-7.4h69.4v29.3M115.6 72.5h15.8M155.7 72.5h8.6M124 95.6h-2.4v3.6M143.5 96.8h34.1v7.3M155.7 82.2h21.9M163.1 96.8v7.3M192.3 109h36.6M192.3 113.9h36.6" fill="none" stroke="#090" stroke-width=".21"/>
<g fill="none" stroke="#0000ca" stroke-width=".21">
<path d="M201.4 92.7l.5 .1 .2 .2v.6l-.3 .4h-.4zM202.6 93.1v.7l.3 .2 .3-.2M203.2 93.1v.9M203.7 93.3l.3-.2 .3 .2v.7M203.7 93.1v.9M204.3 93.3l.2-.2 .3 .2v.7M205.4 93.3l.2-.2 .3 .2v.7M205.4 93.1v.9M205.9 93.3l.2-.2 .3 .2v.7M206.8 93.1l.4 .9M207.4 93.1l-.3 1.1-.3 .2M208.9 92.7v1.2l.1 .1"/>
<path d="M209.5 93.3l.1-.2 .4 .1v.7l-.4 .1-.1-.2zM210.6 93.2h.5v.8M211.1 93.5l-.5 .1v.3h.5M212.2 93.2l-.4-.1-.1 .2v.5l.1 .2 .4-.1M212.2 92.7v1.3M213.5 93.1h.5M214 92.7l-.3 .2v1.1M214.5 93.2l.3-.1 .2 .2v.5l-.2 .2-.4-.3zM215.6 93.1v.9M215.9 93.1l-.3 .3M217.2 93.5h.9M217.7 93v1"/>
<path d="M218.7 93l.3-.3v1.3M218.7 94h.7M219.8 92.9l.2-.2h.3l.2 .2v.4l-.7 .7h.7M220.9 92.7l.3 1.3 .5-1.3M223 93.1v.9M223.3 93.1l-.3 .3M223.8 93.2l.3-.1 .2 .2v.7M224.3 93.5h-.4l-.2 .1 .2 .4 .4-.1M224.9 92.7v.2M224.9 93.1v.9M225.5 92.7v1.2l.1 .1M226.1 93.8v.2"/>
<path d="M200.3 115.2a.59 .59 0 0 0-.7 .4 .59 .59 0 0 0 .3 .7l.5-.1v-.4h-.3M200.9 116l.5-.2v-.1h-.5v.6h.5M202 115.7l.4-.1 .1 .1v.6M202 115.6v.7M203 116l.6-.2-.1-.2-.5 .1v.5l.1 .1h.4M204.1 115.6v.7M204.5 115.6l-.4 .2M204.9 115.7l.3-.1 .2 .1v.6h-.5l-.1-.2 .6-.3M206 115.1v1.1l.2 .1M207.5 115.1v1.2h.5l.1-.6h-.6M208.6 115.6l.1 .7 .5-.1M209.2 115.6v.7"/>
<path d="M209.7 115.1v1.1l.3 .1M210.4 115.1v1.2M210.5 115.9l.3 .4M210.8 115.6l-.4 .4M212.8 115.7a.36 .36 0 0 0-.5 .1v.5h.5M213.4 115.7l.3-.1 .2 .1v.6h-.5l-.1-.2 .6-.3M214.5 115.7l.3-.1 .3 .2v.4l-.2 .1h-.4M214.5 115.6v1.2M215.6 115.7l.3-.1 .2 .1v.6h-.5l-.1-.2 .6-.3M217.2 115.7l-.4-.1-.2 .2v.4l.1 .1h.5M217.7 115.1v.1M217.7 115.6v.7"/>
<path d="M218.1 115.6h.5M218.3 115.1v1.1l.1 .1h.2M218.9 115.7l.4-.1 .2 .1v.6h-.6v-.3l.6-.2M220 115.7l.5-.1 .1 .1v.6M220 115.6v.7M221.7 115.7h-.6v.5l.6 .1M222.2 116l.6-.2-.2-.2-.4 .1v.5v.1h.5M223.3 116.2v.1"/>
</g>
<path d="M115 68.2l1.1 1.1M116.1 68.2l-1.1 1.1M155.1 84.1l1.2 1.1M156.3 84.1l-1.2 1.1" fill="none" stroke="#00008a" stroke-width=".21"/>
<g fill="#090">
<circle cx="107" cy="80.9" r=".47"/>
<circle cx="98.5" cy="80.9" r=".47"/>
<circle cx="143.5" cy="96.8" r=".47"/>
<circle cx="192.3" cy="113.9" r=".47"/>
<circle cx="216.7" cy="109" r=".47"/>
<circle cx="204.5" cy="109" r=".47"/>
<circle cx="216.7" cy="113.9" r=".47"/>
<circle cx="204.5" cy="113.9" r=".47"/>
<circle cx="163.1" cy="96.8" r=".47"/>
<circle cx="176.4" cy="82.2" r=".47"/>
<circle cx="192.3" cy="109" r=".47"/>
</g>
<g fill="none" stroke="#910089" stroke-width=".21">
<path d="M159.7 70h.5l.2-.2v-.4l-.7-.1v1.2M160.9 69.8h.6v.6l-.1 .1h-.4l-.1-.1zM161.9 69.8l.2 .7 .3-.5 .2 .5 .2-.7M163.2 70.2l.6-.2-.1-.2-.5 .1v.5l.1 .1h.4M164.3 69.8v.7M164.7 69.8l-.4 .2M98.8 107.8h.5l.2-.2v-.4l-.7-.1v1.2M98.8 101.7h.5l.2-.2v-.4l-.7-.1v1.3M100.1 107.6h.5l-.1 .7h-.4zM100.1 101.5h.5v.6l-.2 .2-.4-.3zM101 107.5l.3 .8 .2-.5 .2 .5 .2-.8M101 101.4l.3 .9 .2-.6 .2 .6 .2-.9"/>
<path d="M102.4 107.9l.6-.1-.2-.3-.4 .2v.4v.2h.5M102.4 101.9l.6-.2-.2-.3-.4 .2v.4l.1 .3 .4-.1M103.5 101.4v.9M103.5 107.5v.8M103.8 107.5l-.3 .3M103.8 101.4l-.3 .3M109.8 115h.3M109.8 101.6h.3M110.3 114.4h-.5v1.3h.5M110.3 101h-.5v1.3h.5M110.7 114.8l.7 .9M110.7 101.4l.7 .9"/>
<path d="M111.4 114.8l-.7 .9M111.4 101.4l-.7 .9M111.8 114.9l.4-.1 .2 .3-.1 .5h-.5M111.8 101.5a.36 .36 0 0 1 .6 .2l-.1 .5h-.5M111.8 101.4v1.2M111.8 114.8v1.3M112.7 115.7h.9M112.7 102.4h.9M113.9 115.1l.7-.1v-.4l-.2-.2h-.5v1.3M113.9 101.7h.5l.2-.2v-.4l-.7-.1v1.3M115.1 114.9l.4-.1 .2 .2v.5l-.2 .2-.4-.3zM115.1 101.5h.6v.6l-.2 .2-.4-.3z"/>
<path d="M116.1 114.8l.2 .9 .3-.6 .2 .6 .2-.9M116.1 101.4l.2 .9 .3-.6 .2 .6 .2-.9M117.4 115.2l.6-.1-.1-.3-.5 .2v.5l.2 .2 .3-.1M117.4 101.9l.6-.2-.1-.3-.5 .2v.4l.2 .3 .3-.1M118.5 101.4v.9M118.5 114.8v.9M118.9 114.8l-.4 .3M118.9 101.4l-.4 .3M123.2 101.6h.4M123.8 101h-.6v1.3h.6M124.1 101.4l.7 .9M124.8 101.4l-.7 .9"/>
<path d="M125.3 101.5h.5v.6l-.2 .2-.3-.1M125.3 101.4v1.2M126.1 102.4h.9M127.3 101.7h.5l.2-.3-.1-.3-.6-.1v1.3M128.5 101.5l.4-.1 .2 .3v.3l-.2 .3-.5-.3zM129.5 101.4l.2 .9 .3-.6 .2 .6 .2-.9M130.8 101.9l.6-.2-.2-.3-.4 .2v.4l.2 .3 .3-.1M131.9 101.4v.9M132.2 101.4l-.3 .3"/>
</g>
<g fill="none" stroke="#006665" stroke-width=".21">
<path d="M109.5 57.1v1.1l.2 .2 .4-.2v-1.1M110.9 57.7l-.2-.3 .2-.3h.3l.1 .5-.4 .1-.2 .2v.3l.2 .2 .4-.2v-.4l-.1-.1M111.8 59.6l.8 1.2M112.1 57.1a.68 .68 0 0 1 .4 .7 .68 .68 0 0 1-.4 .6l-.3-.5 .1-.6zM112.6 59.6l-.8 1.2M113 59.9l.4-.3v1.2M113 57.5l.4-.4v1.3M113 58.4h.7M114.7 59.6l-.4 .1a.94 .94 0 0 0 0 1.1h.4l.2-.2v-.3l-.3-.3h-.2l-.3 .3M115.4 59.7l.3-.1 .3 .3v.7l-.2 .2-.4-.1zM117.1 59.6h-.6v.6l.2-.2 .4 .1v.7l-.6-.1M117.9 59.5l-.3 .9h.8"/>
<path d="M81.4 63.9h.6l.1-.1v-.4l-.1-.2h-.6v1.3M81.8 60.9l-.5-.1-.2 .2v.3l.7 .4-.3 .4-.4-.1M82.2 60.8l.3 1.3 .2-1 .3 1 .2-1.3M82.6 63.8h.6v.5l-.1 .2-.5-.2zM83.6 63.7l.3 .8 .3-.6 .1 .6 .3-.8M83.9 61.4l-.3-.2 .1-.3a.34 .34 0 0 1 .5 0 .34 .34 0 0 1 0 .4l-.6 .2v.4l.3 .2 .4-.3-.1-.4h-.1M85 64.1l.6-.2-.2-.2-.4 .1v.5l.2 .2 .3-.1M85.1 60.8a.68 .68 0 0 1 .4 .6 .68 .68 0 0 1-.4 .7 .75 .75 0 0 1 0-1.3zM85.9 61.1h.2l.2-.3v1.3M85.9 62.1h.7M86.1 63.7v.8M86.4 63.7l-.3 .2"/>
<path d="M109.5 60.8v-1.2l.4 .8 .3-.8v1.2M110.7 60.8l.4-1.2 .4 1.2M110.8 60.4h.5M113 60.8h.7M118.2 60v.8M140.2 68.2l.4-1.3 .4 1.3M140.3 67.8h.6M141.2 66.9h.7M141.6 66.9v1.3M142 64.5v.9l-.2 .2-.3 .1M142.2 66.9l.8 1.3M142.7 65l-.2-.2 .1-.3h.5l.1 .4-.2 .1h-.4l-.1 .2 .1 .4 .1 .1 .5-.1v-.5l-.2-.1"/>
<path d="M143 66.9l-.8 1.3M143.5 67.6h.9M143.8 64.6l.4-.1a.91 .91 0 0 1-.1 1.2l-.3-.1zM144.9 64.9l.3-.4v1.2M144.9 65.7h.6M144.9 67.1l.5-.2 .2 .3-.7 1h.7M146.4 66.9l-.3 .8h.8M146.6 67.3v.9M159.8 77.4h.9M159.8 79.8h.9M160.3 77v.9M160.3 79.4v.9"/>
<path d="M161.2 77h.2l.1-.4v1.3M161.2 77.9h.8M161.9 79.1h-.6l-.1 .6 .6-.1 .2 .2v.3l-.3 .2h-.3l-.2-.1M162.3 79.1l.3 1.2 .5-1.2M162.4 76.8l.2-.2 .4 .1 .1 .5-.8 .7h.8M163.4 76.6l.4 1.3 .5-1.3M95.7 94.5h.9M96.2 94v.9M97.8 93.7h-.6l-.1 .6 .2-.2h.3l.3 .3-.1 .4h-.7M98.2 93.7l.4 1.2 .4-1.2M106.1 85.3l-.4-.1-.3 .3v.6l.2 .3 .6-.1v-.5h-.3M106.1 94.5h.9"/>
<path d="M106.5 94v.9M107.4 85.2v1.2l-.7-1.2v1.2M107.5 94.1l.4-.4v1.2M107.5 94.9h.7M107.9 85.2a.66 .66 0 0 1 .7 .4 .66 .66 0 0 1-.2 .8h-.5zM108.7 93.8l.6-.1 .1 .4-.8 .8h.8M109.7 93.7l.4 1.2 .5-1.2M159.8 92h.9M161.2 91.6l.3-.3v1.2M161.2 92.5h.8M162.4 91.4h.7v.4l-.8 .7h.8M163.4 91.3l.4 1.2 .5-1.2"/>
<path d="M190.2 85.9h.9M190.6 85.5v.9M191.3 99.8h-.5l-.1 .3v.7a.55 .55 0 0 0 .7 .1v-.4h-.2M191.6 85.5l.3-.3v1.2M191.6 86.4h.7M192.6 99.8v1.2l-.7-1.2v1.2M192.7 85.3l.5-.1 .3 .2-.8 1h.8M193.2 99.8h.4a.66 .66 0 0 1 .3 .8 .66 .66 0 0 1-.7 .4zM193.8 85.2l.4 1.2 .4-1.2M195 94.3h.5v-.4l-.5-.1v1M195.1 91.6l.3-.3v1.2M195.1 92.5h.6"/>
<path d="M195.2 94.3l.4 .5M196.2 94.2l-.3-.1 .4-.3 .2 .3-.1 .1-.5 .2v.3l.3 .1 .3-.1-.2-.5M196.3 91.4a.61 .61 0 0 1 .7 .3 .61 .61 0 0 1-.2 .8h-.5v-.2l-.1-.5zM196.9 93.9a.38 .38 0 0 1 .5 .1 .38 .38 0 0 1 0 .4l-.2 .4a.58 .58 0 0 1-.3-.9zM197.4 91.4l.4-.1 .2 .2v.8l-.1 .2-.5-.1zM197.8 93.9l.4-.1 .2 .3-.6 .7h.6M198.5 91.9h.5l.3-.2-.1-.3-.7-.1v1.2M198.9 91.9l.4 .6M96.3 114.5l-.3-.1-.3 .3v.6l.1 .3h.5v-.5h-.1M97.6 114.4v1.3l-.7-1.3v1.3M98.2 114.4a.64 .64 0 0 1 .7 .6 .64 .64 0 0 1-.7 .7zM106.1 107.9h.9"/>
<path d="M107.5 107.4l.4-.3v1.2M107.5 108.3h.7M108.7 107.2l.4-.1 .3 .3-.8 .9h.8M109.7 107.1l.4 1.2 .5-1.2M142.6 101.1l-.1-.1a.64 .64 0 0 0-.6 .6 .64 .64 0 0 0 .5 .7l.3-.2v-.4h-.3M143.9 101v1.3l-.7-1.3v1.3M144.4 101a.65 .65 0 0 1 .8 .6 .65 .65 0 0 1-.8 .7zM165.8 112.6h.5l.1-.3-.2-.2h-.4v1M165.9 107.4h.6v-.5l-.1-.1h-.5v1.2M165.9 104.4h.5l.1 .2v.7l-.3 .3h-.3zM166 112.6l.4 .5M166.1 114.4l-.3 .8h.7"/>
<path d="M166.4 114.8v.9M166.9 114.4h.8l-.5 1.3M166.9 112.5l-.2-.2 .2-.2 .4 .2-.1 .2h-.3l-.2 .2 .2 .4h.2l.2-.2-.2-.4M167 107.4l.3-.2 .3 .2v.5l-.1 .1-.5-.1zM167.3 104.9l-.3-.2v-.2l.6-.1a.44 .44 0 0 1 0 .4 .44 .44 0 0 1-.5 .2v.5a.35 .35 0 0 0 .6-.1 .35 .35 0 0 0-.2-.5M167.7 112.2l.2-.1a.55 .55 0 0 1 .3 .5 .55 .55 0 0 1-.3 .5l-.3-.4zM168.1 107.2l.2 .8 .3-.6 .1 .6 .3-.8M168.2 104.6l.2-.2 .3 .1a.66 .66 0 0 1-.2 1.1l-.3-.3zM168.4 114.4a.68 .68 0 0 1 .4 .6 .68 .68 0 0 1-.4 .7l-.3-.6 .1-.5zM168.6 112.3l.2-.2v1M168.6 113.1h.6M169.3 115.1l.7-.1v-.4l-.2-.2h-.5v1.3"/>
<path d="M169.3 104.7l.4-.3v1.2M169.3 105.6h.7M169.4 107.6l.6-.1-.2-.3-.4 .2v.5l.2 .1 .3-.1M169.7 115.1l.3 .6M170.5 107.2v.8M170.9 107.2l-.4 .2M172.3 106.8h.3a.73 .73 0 0 1 0 1.2l-.3-.1a.87 .87 0 0 1 0-1.1zM173.5 107.4l.1-.2 .4 .2v.6M173.5 107.2v.8M180.4 112.6h.4l.1-.4-.5-.1v1M180.5 107.4h.6v-.6h-.6v1.2M180.5 104.4h.4a.66 .66 0 0 1 .3 .7 .66 .66 0 0 1-.7 .5z"/>
<path d="M180.7 114.4l-.3 .8h.8M180.7 112.6l.2 .5M181 114.8v.9M181.5 114.4h.9l-.5 1.3M181.5 112.5l-.1-.1v-.2h.5l-.1 .3-.4 .1v.4l.1 .1 .4-.1v-.4l-.2-.1M181.6 107.4l.3-.2 .3 .1v.6l-.3 .1-.3-.2zM181.9 104.9l-.3-.3 .2-.2h.4l.2 .2-.8 .6 .3 .4 .4-.1 .1-.2-.3-.4M182.5 112.1l.3 .2v.6l-.2 .2-.3-.2v-.6zM182.7 107.2l.3 .8 .1-.6 .3 .6 .2-.8M183 104.4h.3l.2 .2v.7l-.4 .3a.84 .84 0 0 1-.1-1.2zM183 114.4a.68 .68 0 0 1 .5 .6 .68 .68 0 0 1-.5 .7 .75 .75 0 0 1 0-1.3zM183.1 112.1h.6l-.3 .4 .3 .1v.4h-.6"/>
<path d="M184 115.1l.6-.1v-.5l-.6-.1v1.3M184 104.5l.6-.1 .1 .3-.8 .9h.8M184.1 107.6l.5-.1v-.2h-.5v.6h.5M184.2 115.1l.5 .6M185.2 107.2v.8M185.5 107.2l-.3 .2M187 106.8h.3l.2 .2v.9l-.2 .1-.5-.1v-.9zM188 106.8v1.2M188.3 107.4l.5 .6M188.8 106.8l-.8 .7M190.7 104.2h.9M191.2 103.7v.9"/>
<path d="M191.3 118.1h-.5l-.1 .3v.6l.1 .2h.6v-.4h-.2M192.6 118.1v1.2l-.7-1.2v1.2M192.8 103.5h-.6v.6l.4-.2 .3 .2v.4l-.2 .1h-.5M193.2 118.1h.4a.66 .66 0 0 1 .3 .8 .66 .66 0 0 1-.7 .4zM193.2 103.5l.4 1.1 .4-1.1M195.1 111.8l.3-.4v1.3M195.1 112.7h.6M195.8 109.1l-.6-.1-.1 .3v.7a.55 .55 0 0 0 .7 .1M196.3 111.5a.61 .61 0 0 1 .7 .5 .61 .61 0 0 1-.4 .7 .71 .71 0 0 1-.3-1.2zM196.5 109.6l-.2-.3v-.3h.5l.1 .4-.6 .2a.36 .36 0 0 0 .2 .6l.4-.1v-.5h-.1M197.4 109.2l.2-.2h.3a.86 .86 0 0 1 0 1.2l-.5-.2zM197.5 111.5l.3-.1 .2 .3v.7l-.2 .3a.71 .71 0 0 1-.3-1.2z"/>
<path d="M198.5 109.4l.5-.4v1.2M198.5 111.8v1.3M198.5 110.2h.8M199.1 111.8v.8l-.3 .1-.3-.2M199.1 112.5l.2 .2M199.9 112h.3M200.4 111.4h-.5v1.3M207.3 111.8l.3-.4v1.3M207.3 112.7h.6M207.9 109.1l-.5-.1-.1 .3v.7a.45 .45 0 0 0 .6 .1M208.5 111.5l.3-.1 .2 .3v.7l-.2 .3a.71 .71 0 0 1-.3-1.2zM208.7 109.6l-.3-.3 .1-.3h.5v.5l-.5 .1a.35 .35 0 0 0 0 .5 .35 .35 0 0 0 .5 0 .35 .35 0 0 0 0-.5h-.1"/>
<path d="M209.6 109.2l.2-.2h.3a.77 .77 0 0 1-.1 1.2l-.4-.2zM209.8 111.4l.4 .3v.7l-.2 .3a.75 .75 0 0 1-.2-1.3zM210.7 109.1l.6-.1 .2 .2-.1 .4-.7 .6h.8M210.7 111.8v1.3M211.3 111.8v.8l-.4 .1-.2-.2M211.3 112.5l.2 .2M212 112h.4M212.6 111.4h-.6v1.3M219.4 111.8l.4-.4v1.3M219.4 112.7h.7M220.1 109.1l-.5-.1a.61 .61 0 0 0-.2 .8 .61 .61 0 0 0 .7 .3M220.7 111.5l.3-.1 .2 .3v.7l-.2 .3a.71 .71 0 0 1-.3-1.2z"/>
<path d="M220.9 109.6l-.3-.3 .1-.3h.5v.5l-.5 .1a.35 .35 0 0 0 0 .5 .35 .35 0 0 0 .5 0 .35 .35 0 0 0 0-.5h-.1M221.8 109.2l.2-.2 .3 .1a.66 .66 0 0 1-.2 1.1l-.3-.2zM222 111.4a.68 .68 0 0 1 .4 .7 .68 .68 0 0 1-.4 .6l-.3-.5 .1-.6zM222.9 109h.7l-.3 .5 .3 .1v.5h-.7M222.9 111.8v1.3M223.5 111.8v.7l-.2 .2-.4-.2M223.5 112.5l.2 .2M224.2 112h.4M224.8 111.4h-.6v1.3M231.6 111.8l.3-.4v1.3M231.6 112.7h.7M232.3 109.1l-.5-.1a.61 .61 0 0 0-.2 .8 .61 .61 0 0 0 .7 .3"/>
<path d="M233 111.4l.4 .3v.7l-.2 .3a.75 .75 0 0 1-.2-1.3zM233 109.6l-.2-.5 .6-.1v.5l-.6 .1v.5l.5 .1a.35 .35 0 0 0 .2-.3 .35 .35 0 0 0-.2-.3M234.1 109l.4 .1a.66 .66 0 0 1-.2 1.1 .84 .84 0 0 1-.2-1.2zM234.2 111.4a.68 .68 0 0 1 .4 .7 .68 .68 0 0 1-.4 .6l-.3-.3v-.7zM235.1 111.8v1.3M235.5 109l-.4 .8h.8M235.7 111.8v.7l-.2 .2-.4-.2M235.7 112.5l.2 .2M235.7 109.4v.8M236.4 112h.4M237 111.4h-.6v1.3M161.5 121.2h.9"/>
<path d="M162 120.8v.9M163.6 120.5h-.6l-.1 .6 .6-.1 .1 .6-.2 .1h-.3l-.2-.1M164 120.5l.3 1.2 .5-1.2"/>
</g>
</svg>
